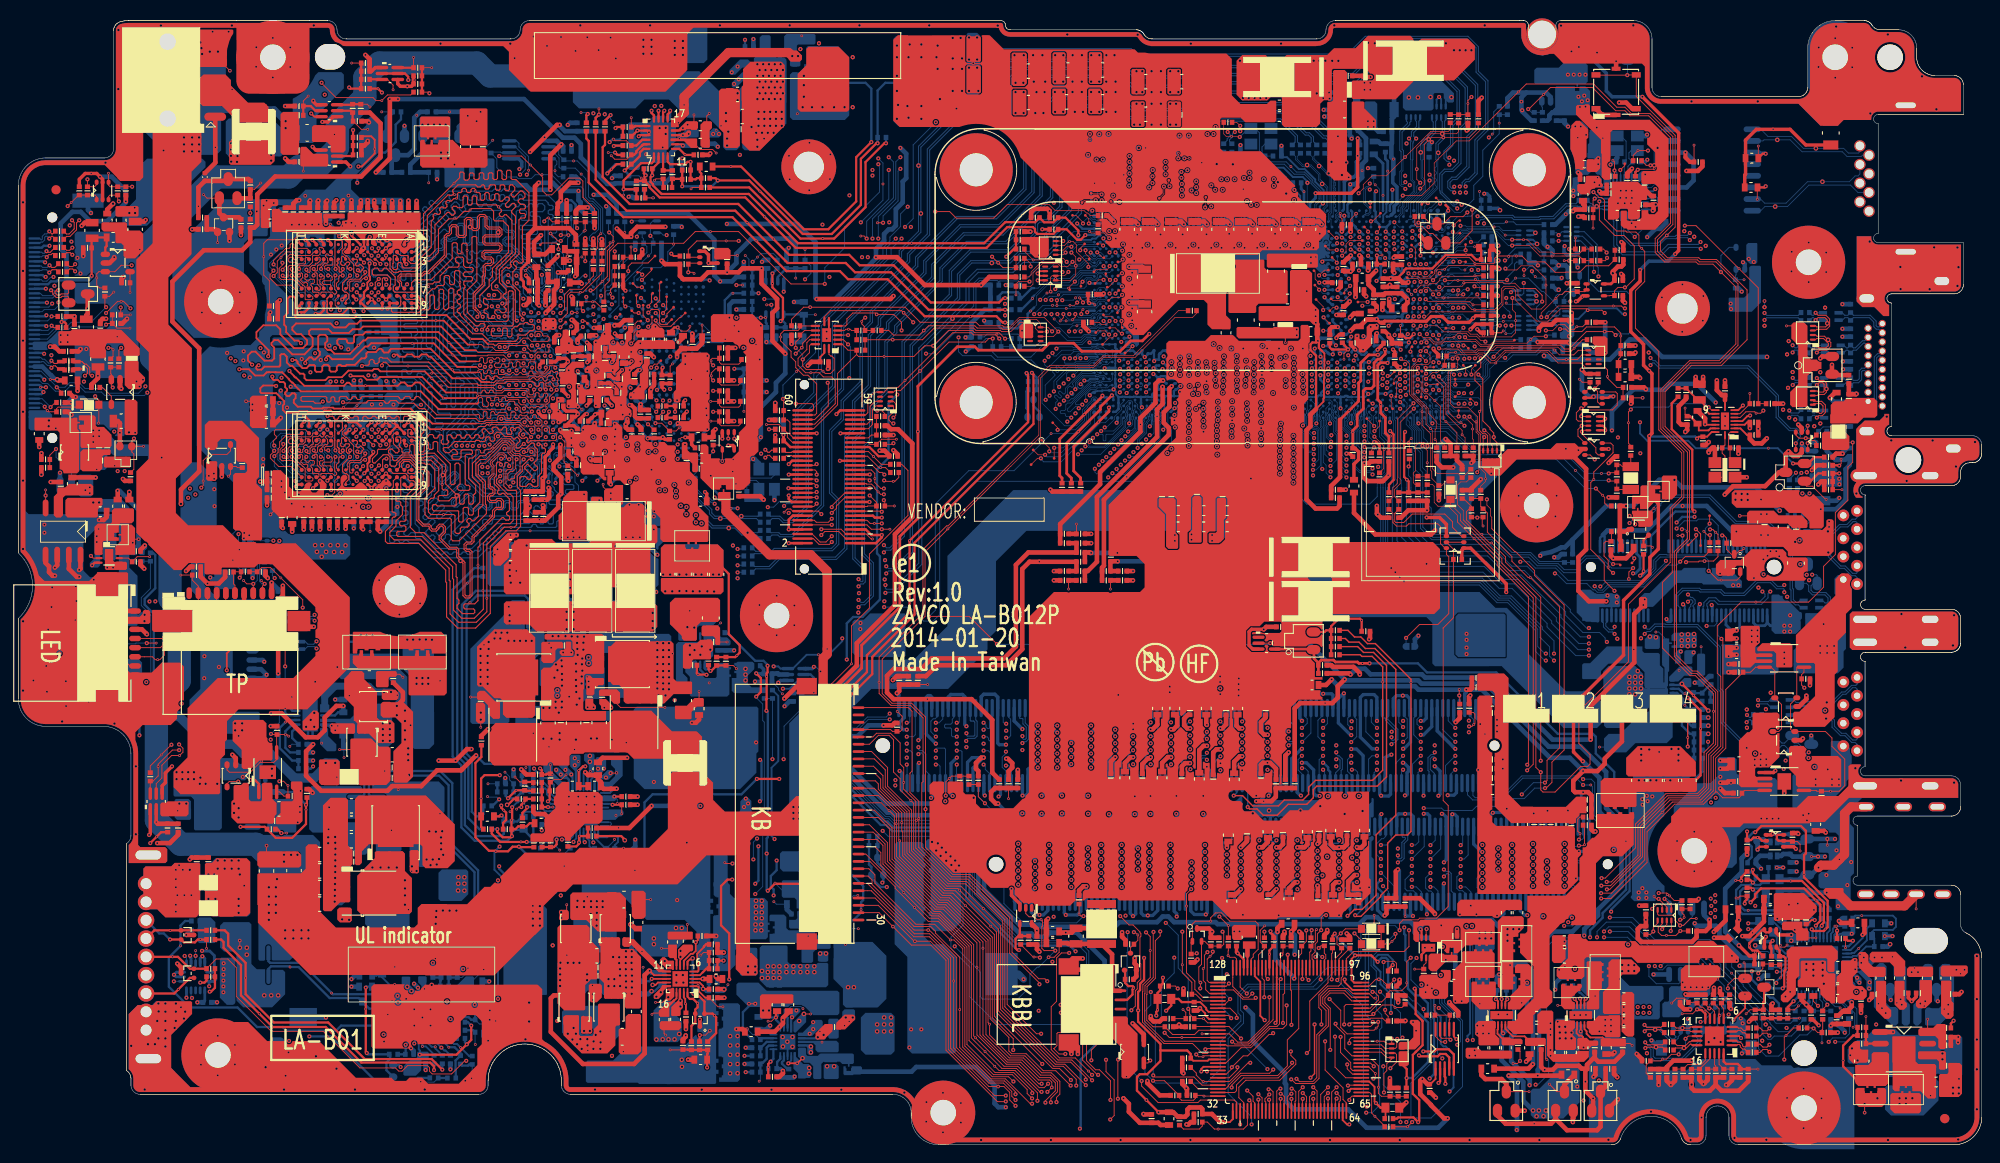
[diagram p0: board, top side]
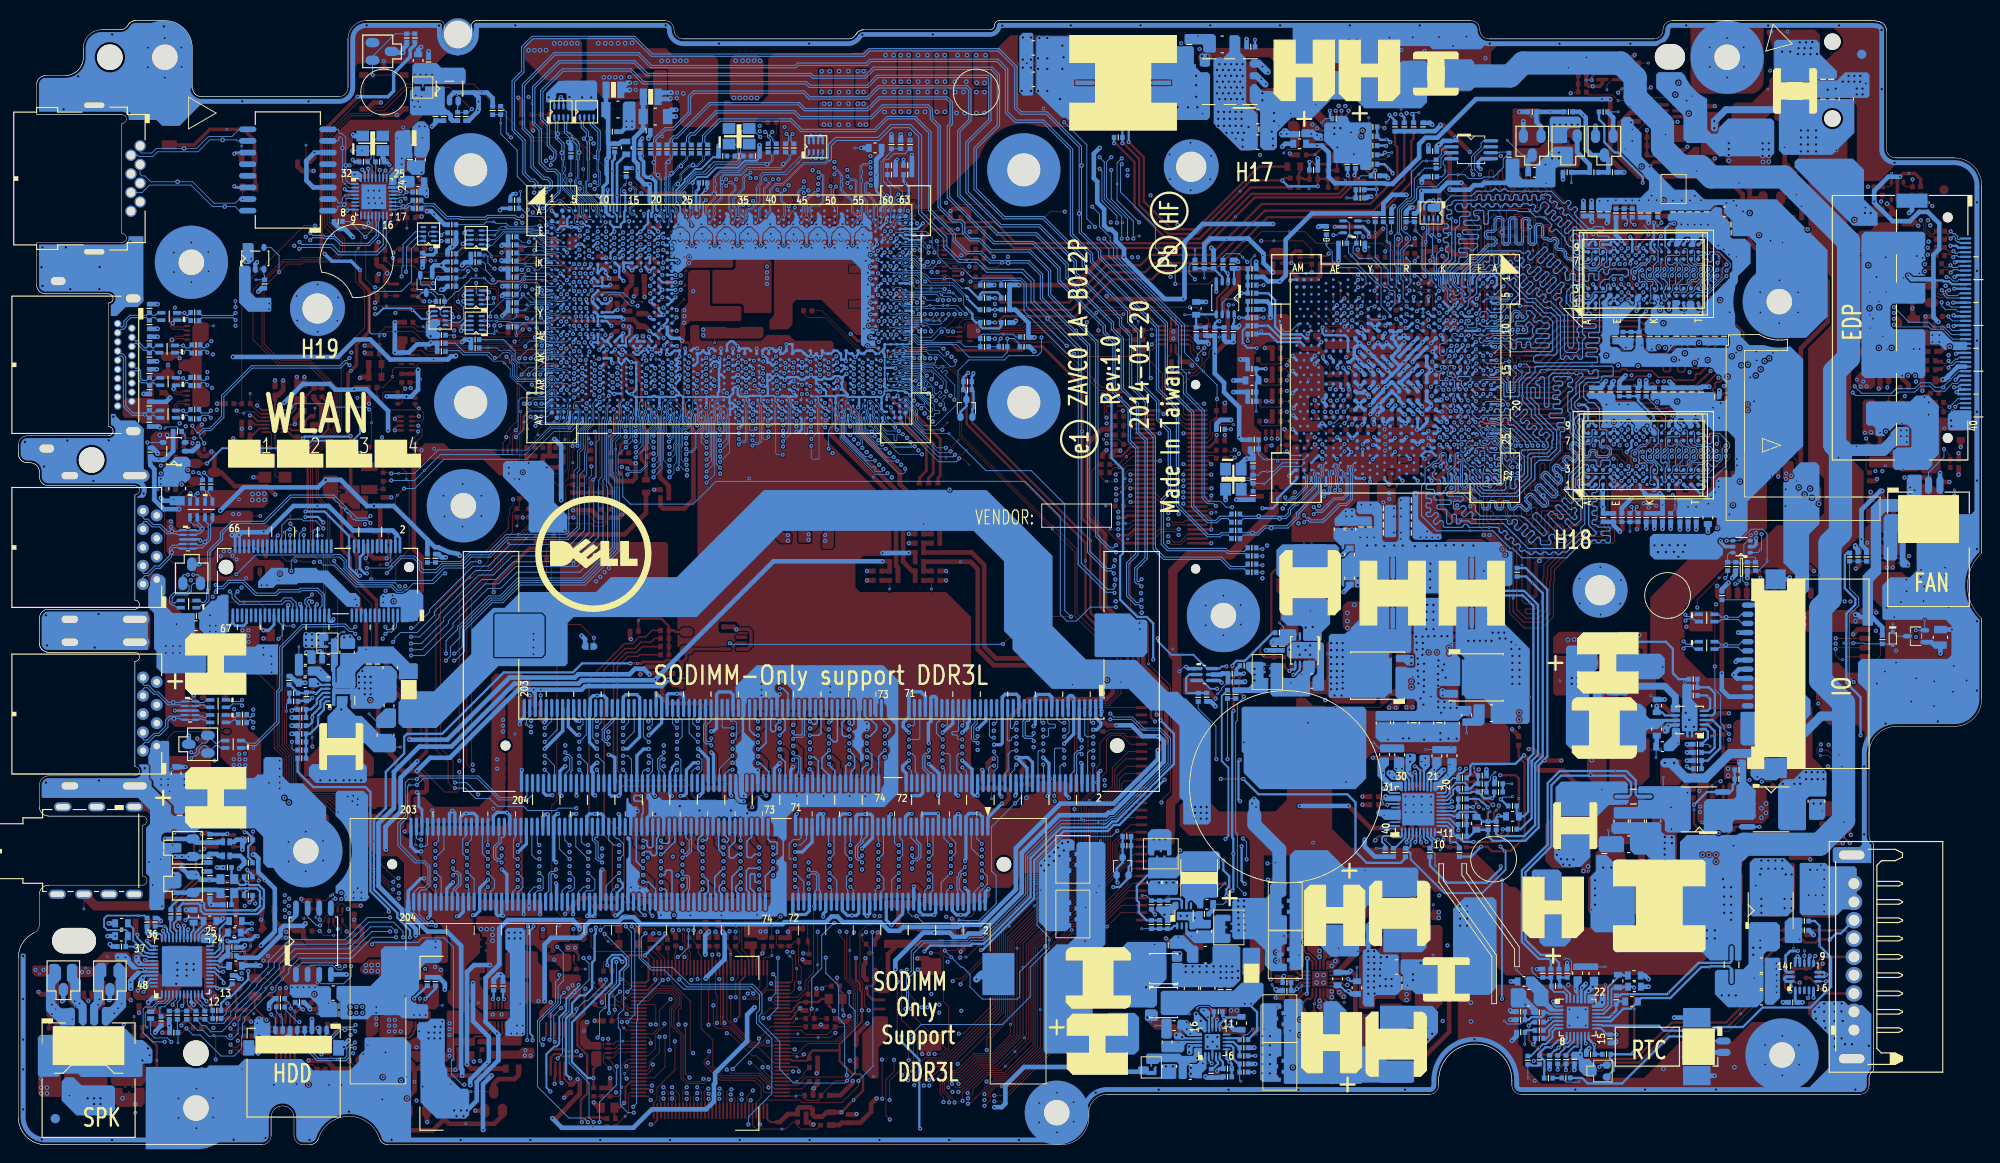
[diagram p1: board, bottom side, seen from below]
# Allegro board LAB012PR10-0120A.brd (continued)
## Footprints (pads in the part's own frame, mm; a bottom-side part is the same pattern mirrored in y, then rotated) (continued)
HB_A823020-SBHR21_30P
  oval 0.305x1.295 smd: 1(0,0) 2(0.8,0) 3(1.6,0) 4(2.4,0) 5(3.2,0) 6(4,0) 7(4.8,0) 8(5.6,0) 9(6.4,0) 10(7.2,0) 11(8,0) 12(8.8,0) 13(9.6,0) 14(10.4,0) 15(11.2,0) 16(12,0) 17(12.8,0) 18(13.6,0) 19(14.4,0) 20(15.2,0) 21(16,0) 22(16.8,0) 23(17.6,0) 24(18.4,0) 25(19.2,0) 26(20,0) 27(20.8,0) 28(21.6,0) 29(22.4,0) 30(23.2,0)
  rect 1.803x2.21 smd: 31(25.55,-5.65) 32(-2.35,-5.65)
IP4292CZ10-TBR_XSON10_2P5X1
  oval 0.254x0.889 smd: 1(0,0)
  oval 0.254x0.838 smd: 2(0.5,-0.025) 3(1,-0.025) 4(1.5,-0.025) 5(2,-0.025) 6(2,1.125) 7(1.5,1.125) 8(1,1.125) 9(0.5,1.125) 10(0,1.125)
ISL9520HRTZ-T_TQFN28_4X4
  oval 0.203x0.94 smd: 1(0,0) 2(0.4,0) 3(0.8,0) 4(1.2,0) 5(1.6,0) 6(2,0) 7(2.4,0) 15(2.4,4.05) 16(2,4.05) 17(1.6,4.05) 18(1.2,4.05) 19(0.8,4.05) 20(0.4,4.05) 21(0,4.05)
  oval 0.94x0.203 smd: 8(3.225,0.825) 9(3.225,1.225) 10(3.225,1.625) 11(3.225,2.025) 12(3.225,2.425) 13(3.225,2.825) 14(3.225,3.225) 22(-0.825,3.225) 23(-0.825,2.825) 24(-0.825,2.425) 25(-0.825,2.025) 26(-0.825,1.625) 27(-0.825,1.225) 28(-0.825,0.825)
  rect 2.388x2.388 smd: 29(1.2,2.025)
ISL62771HRTZ-T_TQFN40_5X5
  oval 0.203x1.016 smd: 1(0,0) 2(0.4,0) 3(0.8,0) 4(1.2,0) 5(1.6,0) 6(2,0) 7(2.4,0) 8(2.8,0) 9(3.2,0) 10(3.6,0) 21(3.6,4.975) 22(3.2,4.975) 23(2.8,4.975) 24(2.4,4.975) 25(2,4.975) 26(1.6,4.975) 27(1.2,4.975) 28(0.8,4.975) 29(0.4,4.975) 30(0,4.975)
  oval 1.016x0.203 smd: 11(4.288,0.688) 12(4.288,1.088) 13(4.288,1.488) 14(4.288,1.888) 15(4.288,2.288) 16(4.288,2.688) 17(4.288,3.088) 18(4.288,3.488) 19(4.288,3.888) 20(4.288,4.288) 31(-0.688,4.288) 32(-0.688,3.888) 33(-0.688,3.488) 34(-0.688,3.088) 35(-0.688,2.688) 36(-0.688,2.288) 37(-0.688,1.888) 38(-0.688,1.488) 39(-0.688,1.088) 40(-0.688,0.688)
  rect 3.505x3.505 smd: 41(1.8,2.488)
ISL95813HRZ-T_QFN20_3X4
  oval 0.254x0.889 smd: 1(0,0) 2(0.5,0) 3(1,0) 4(1.5,0) 5(2,0) 6(2.5,0) 11(2.5,3.1) 12(2,3.1) 13(1.5,3.1) 14(1,3.1) 15(0.5,3.1) 16(0,3.1)
  oval 0.889x0.254 smd: 7(3.3,0.8) 8(3.3,1.3) 9(3.3,1.8) 10(3.3,2.3) 17(-0.8,2.3) 18(-0.8,1.8) 19(-0.8,1.3) 20(-0.8,0.8)
  rect 2.642x1.651 smd: 21(1.25,1.55)
JUMP_43X39
  custom 0.191x0.191 smd: 1(0,0) 2(0.914,0)
JUMP_43X79
  custom 0.188x0.188 smd: 1(0,0) 2(1.1,0)
JUMP_43X118
  custom 0.187x0.187 smd: 1(0,0) 2(1.1,0)
K4W1G1646E-HC12_FBGA_96P-A39
  round 0.445 smd: A1(0,0) A2(0.8,0) A3(1.6,0) A7(4.801,0) A8(5.601,0) A9(6.401,0) B1(0,-0.8) B2(0.8,-0.8) B3(1.6,-0.8) B7(4.801,-0.8) B8(5.601,-0.8) B9(6.401,-0.8) C1(0,-1.6) C2(0.8,-1.6) C3(1.6,-1.6) C7(4.801,-1.6) C8(5.601,-1.6) C9(6.401,-1.6) D1(0,-2.4) D2(0.8,-2.4) D3(1.6,-2.4) D7(4.801,-2.4) D8(5.601,-2.4) D9(6.401,-2.4) E1(0,-3.2) E2(0.8,-3.2) E3(1.6,-3.2) E7(4.801,-3.2) E8(5.601,-3.2) E9(6.401,-3.2) M1(0,-8.801) M2(0.8,-8.801) M3(1.6,-8.801) M7(4.801,-8.801) M8(5.601,-8.801) M9(6.401,-8.801) N1(0,-9.601) N2(0.8,-9.601) N3(1.6,-9.601) N7(4.801,-9.601) N8(5.601,-9.601) N9(6.401,-9.601) P1(0,-10.401) P2(0.8,-10.401) P3(1.6,-10.401) P7(4.801,-10.401) P8(5.601,-10.401) P9(6.401,-10.401) R1(0,-11.201) R2(0.8,-11.201) R3(1.6,-11.201) R7(4.801,-11.201) R8(5.601,-11.201) R9(6.401,-11.201) T1(0,-12.002) T2(0.8,-12.002) T3(1.6,-12.002) T7(4.801,-12.002) T8(5.601,-12.002) T9(6.401,-12.002)
  round 0.343 smd: F1(0,-4) F2(0.8,-4) F3(1.6,-4) F7(4.801,-4) F8(5.601,-4) F9(6.401,-4) G1(0,-4.801) G2(0.8,-4.801) G3(1.6,-4.801) G7(4.801,-4.801) G8(5.601,-4.801) G9(6.401,-4.801) H1(0,-5.601) H2(0.8,-5.601) H3(1.6,-5.601) H7(4.801,-5.601) H8(5.601,-5.601) H9(6.401,-5.601) J1(0,-6.401) J2(0.8,-6.401) J3(1.6,-6.401) J7(4.801,-6.401) J8(5.601,-6.401) J9(6.401,-6.401) K1(0,-7.201) K2(0.8,-7.201) K3(1.6,-7.201) K7(4.801,-7.201) K8(5.601,-7.201) K9(6.401,-7.201) L1(0,-8.001) L2(0.8,-8.001) L3(1.6,-8.001) L7(4.801,-8.001) L8(5.601,-8.001) L9(6.401,-8.001)
KB9012QF-A2_LQFP128_14X14
  oval 0.203x1.753 smd: 1(0,0) 2(0.4,0) 3(0.8,0) 4(1.2,0) 5(1.6,0) 6(2,0) 7(2.4,0) 8(2.8,0) 9(3.2,0) 10(3.6,0) 11(4,0) 12(4.4,0) 13(4.8,0) 14(5.2,0) 15(5.6,0) 16(6,0) 17(6.4,0) 18(6.8,0) 19(7.2,0) 20(7.6,0) 21(8,0) 22(8.4,0) 23(8.8,0) 24(9.2,0) 25(9.6,0) 26(10,0) 27(10.4,0) 28(10.8,0) 29(11.2,0) 30(11.6,0) 31(12,0) 32(12.4,0) 65(12.4,15.654) 66(12,15.654) 67(11.6,15.654) 68(11.2,15.654) 69(10.8,15.654) 70(10.4,15.654) 71(10,15.654) 72(9.6,15.654) 73(9.2,15.654) 74(8.8,15.654) 75(8.4,15.654) 76(8,15.654) 77(7.6,15.654) 78(7.2,15.654) 79(6.8,15.654) 80(6.4,15.654) 81(6,15.654) 82(5.6,15.654) 83(5.2,15.654) 84(4.8,15.654) 85(4.4,15.654) 86(4,15.654) 87(3.6,15.654) 88(3.2,15.654) 89(2.8,15.654) 90(2.4,15.654) 91(2,15.654) 92(1.6,15.654) 93(1.2,15.654) 94(0.8,15.654) 95(0.4,15.654) 96(0,15.654)
  oval 1.753x0.203 smd: 33(14.027,1.627) 34(14.027,2.027) 35(14.027,2.427) 36(14.027,2.827) 37(14.027,3.227) 38(14.027,3.627) 39(14.027,4.027) 40(14.027,4.427) 41(14.027,4.827) 42(14.027,5.227) 43(14.027,5.627) 44(14.027,6.027) 45(14.027,6.427) 46(14.027,6.827) 47(14.027,7.227) 48(14.027,7.627) 49(14.027,8.027) 50(14.027,8.427) 51(14.027,8.827) 52(14.027,9.227) 53(14.027,9.627) 54(14.027,10.027) 55(14.027,10.427) 56(14.027,10.827) 57(14.027,11.227) 58(14.027,11.627) 59(14.027,12.027) 60(14.027,12.427) 61(14.027,12.827) 62(14.027,13.227) 63(14.027,13.627) 64(14.027,14.027) 97(-1.627,14.027) 98(-1.627,13.627) 99(-1.627,13.227) 100(-1.627,12.827) 101(-1.627,12.427) 102(-1.627,12.027) 103(-1.627,11.627) 104(-1.627,11.227) 105(-1.627,10.827) 106(-1.627,10.427) 107(-1.627,10.027) 108(-1.627,9.627) 109(-1.627,9.227) 110(-1.627,8.827) 111(-1.627,8.427) 112(-1.627,8.027) 113(-1.627,7.627) 114(-1.627,7.227) 115(-1.627,6.827) 116(-1.627,6.427) 117(-1.627,6.027) 118(-1.627,5.627) 119(-1.627,5.227) 120(-1.627,4.827) 121(-1.627,4.427) 122(-1.627,4.027) 123(-1.627,3.627) 124(-1.627,3.227) 125(-1.627,2.827) 126(-1.627,2.427) 127(-1.627,2.027) 128(-1.627,1.627)
KC_FBMA-L10-160808-800LMT_2P
  rect 0.889x1.092 smd: 1(0,0) 2(1.5,0)
KC_FBMA-L11-160808-800LMT_2P
  rect 0.889x1.092 smd: 1(0,0) 2(1.5,0)
KC_FBMA-L11-201209-221LMA30_2P
  rect 0.838x1.397 smd: 1(0,0) 2(1.65,0)
KC_WCM-2012HS-900T_4P
  rect 0.889x0.406 smd: 1(0,0) 2(1.7,0) 3(1.7,-0.8) 4(0,-0.8)
L03ESDL5V0CC3-2_SOT23-3
  oval 1.016x1.524 smd: 1(0,0) 2(0.965,2.083) 3(-0.965,2.083)
L03ESDL5V0CG3-2_SOT-523-3
  oval 0.406x0.787 smd: 1(0,0) 2(-0.5,-1.4) 3(0.5,-1.4)
L30ESDL5V0C3-2_SOT23-3
  oval 1.016x1.524 smd: 1(0,0) 2(0.965,2.083) 3(-0.965,2.083)
L_5X5X3_M_2P
  rect 2.159x2.794 smd: 1(0,0) 2(4.35,0)
LANKO_LF-H1201P-2_16P
  oval 0.635x1.905 smd: 1(0,0) 2(1.27,0) 3(2.54,0) 4(3.81,0) 5(5.08,0) 6(6.35,0) 7(7.62,0) 8(8.89,0) 9(8.89,8.763) 10(7.62,8.763) 11(6.35,8.763) 12(5.08,8.763) 13(3.81,8.763) 14(2.54,8.763) 15(1.27,8.763) 16(0,8.763)
LNG3DMTR_LGA16_3X3
  oval 0.305x0.864 smd: 1(0,0) 2(0.5,0) 3(1,0) 4(1.5,0) 5(2,0) 9(2,2.96) 10(1.5,2.96) 11(1,2.96) 12(0.5,2.96) 13(0,2.96)
  oval 0.864x0.305 smd: 6(2.48,0.98) 7(2.48,1.48) 8(2.48,1.98) 14(-0.48,1.98) 15(-0.48,1.48) 16(-0.48,0.98)
LOTES_APCI0019-P009A_67P
  round 1.092 hole 1.092 unplated: (-0.75,-5.275)
  round 1.6 hole 1.6 unplated: (19.25,-5.275)
  oval 0.305x1.549 smd: 1(0,0) 2(0.25,-7.55) 3(0.5,0) 4(0.75,-7.55) 5(1,0) 6(1.25,-7.55) 7(1.5,0) 8(1.75,-7.55) 9(2,0) 10(2.25,-7.55) 11(2.5,0) 12(2.75,-7.55) 13(3,0) 14(3.25,-7.55) 15(3.5,0) 16(3.75,-7.55) 17(4,0) 18(4.25,-7.55) 19(4.5,0) 20(4.75,-7.55) 21(5,0) 22(5.25,-7.55) 23(5.5,0) 24(7.75,-7.55) 25(8,0) 26(8.25,-7.55) 27(8.5,0) 28(8.75,-7.55) 29(9,0) 30(9.25,-7.55) 31(9.5,0) 32(9.75,-7.55) 33(10,0) 34(10.25,-7.55) 35(10.5,0) 36(10.75,-7.55) 37(11,0) 38(11.25,-7.55) 39(11.5,0) 40(11.75,-7.55) 41(12,0) 42(12.25,-7.55) 43(12.5,0) 44(12.75,-7.55) 45(13,0) 46(13.25,-7.55) 47(13.5,0) 48(13.75,-7.55) 49(14,0) 50(14.25,-7.55) 51(14.5,0) 52(14.75,-7.55) 53(15,0) 54(15.25,-7.55) 55(15.5,0) 56(15.75,-7.55) 57(16,0) 58(16.25,-7.55) 59(16.5,0) 60(16.75,-7.55) 61(17,0) 62(17.25,-7.55) 63(17.5,0) 64(17.75,-7.55) 65(18,0) 66(18.25,-7.55) 67(18.5,0)
  rect 1.194x2.743 smd: 68(-1.1,-0.775) 69(19.6,-0.775)
MC74VHC1G08DFT2G_SC70-5
  oval 0.381x0.711 smd: 1(0,0) 2(0.65,0) 3(1.3,0) 4(1.3,1.9) 5(0,1.9)
MDU1516URH_POWERDFN56-8-5
  oval 0.61x1.27 smd: 1(0,0) 2(1.27,0) 3(2.54,0) 4(3.81,0)
  custom 1.105x1.105 smd: 5(1.905,3.715)
MMBT3904_NL_SOT23-3
  oval 1.016x1.524 smd: 1(0,0) 2(0.965,2.083) 3(-0.965,2.083)
MMST3904-7-F_SOT323-3
  oval 0.711x0.889 smd: 1(0,0) 2(0.65,1.9) 3(-0.65,1.9)
MURAT_BLM15AG102SN1D_2P
  rect 0.457x0.508 smd: 1(0,0) 2(0.85,0)
MURAT_BLM15BB221SN1D_2P
  rect 0.508x0.762 smd: 1(0,0) 2(0.75,0)
MURAT_BLM15BD601SN1D_2P
  rect 0.508x0.762 smd: 1(0,0) 2(0.75,0)
MURAT_BLM18AG601SN1D_L0603_2P
  rect 0.66x1.041 smd: 1(0,0) 2(1.2,0)
MURAT_DLW21SN670HQ2L_4P
  rect 0.889x0.406 smd: 1(0,0) 2(1.7,0) 3(1.7,0.8) 4(0,0.8)
MURAT_LQM2MPN2R2NG0L_2P
  rect 0.787x1.803 smd: 1(0,0) 2(1.6,0)
PANAS_ETQP3W2R2WFN_2P
  rect 2.362x3.505 smd: 1(0,0) 2(-6.05,0)
PANAS_ETQP4LR15AFM_4P
  custom 0.686x0.686 smd: 1(0,0) 4(8.357,0)
  rect 2.21x0.508 smd: 2(1.448,0) 3(6.909,0)
PESD5V0U2BT_SOT23-3
  oval 1.016x1.524 smd: 1(0,0) 2(0.965,2.083) 3(-0.965,2.083)
PS8520BTQFN20GTR2_TQFN20_4X4
  oval 0.254x1.194 smd: 1(0,0) 2(0.5,0) 3(1,0) 4(1.5,0) 5(2,0) 11(2,3.8) 12(1.5,3.8) 13(1,3.8) 14(0.5,3.8) 15(0,3.8)
  oval 1.194x0.254 smd: 6(2.9,0.9) 7(2.9,1.4) 8(2.9,1.9) 9(2.9,2.4) 10(2.9,2.9) 16(-0.9,2.9) 17(-0.9,2.4) 18(-0.9,1.9) 19(-0.9,1.4) 20(-0.9,0.9)
  rect 2.108x2.108 smd: 21(1,1.9)
R0402_0OHM
  rect 0.508x0.559 smd: 1(0,0) 2(0.914,0)
R0603_0OHM
  rect 0.635x0.889 smd: 1(0,0) 2(1.397,0)
R0805_0OHM
  rect 0.813x1.397 smd: 1(0,0) 2(1.702,0)
R_0402
  rect 0.508x0.559 smd: 1(0,0) 2(0.914,0)
R_0603
  rect 0.635x0.889 smd: 1(0,0) 2(1.397,0)
R_0805
  rect 0.813x1.397 smd: 1(0,0) 2(1.702,0)
R_1206
  rect 1.016x1.651 smd: 1(0,0) 2(2.667,0)
R_1206_4P-D
  custom 0.445x0.445 smd: 1(0,0) 4(5.004,0)
  custom 0.114x0.114 smd: 2(1.194,0) 3(3.81,0)
RB751V-40_SOD323-2
  rect 0.787x0.889 smd: 1(0,0) 2(2.14,0)
RHU002N06_SOT323-3
  oval 0.813x0.914 smd: 1(0,0) 2(0.65,1.6) 3(-0.65,1.6)
RP_0804_8P4R
  oval 0.66x0.254 smd: 1(0,0) 2(0,-0.5) 3(0,-1) 4(0,-1.5) 5(1.15,-1.5) 6(1.15,-1) 7(1.15,-0.5) 8(1.15,0)
RT8207MZQW_WQFN20_3X3
  oval 0.203x0.889 smd: 1(0,0) 2(0.4,0) 3(0.8,0) 4(1.2,0) 5(1.6,0) 11(1.6,3.1) 12(1.2,3.1) 13(0.8,3.1) 14(0.4,3.1) 15(0,3.1)
  oval 0.889x0.203 smd: 6(2.35,0.75) 7(2.35,1.15) 8(2.35,1.55) 9(2.35,1.95) 10(2.35,2.35) 16(-0.75,2.35) 17(-0.75,1.95) 18(-0.75,1.55) 19(-0.75,1.15) 20(-0.75,0.75)
  rect 1.702x1.702 smd: 21(0.8,1.55)
RTL8106EUS-CG_QFN32_4X4
  oval 0.203x0.889 smd: 1(0,0) 2(0.4,0) 3(0.8,0) 4(1.2,0) 5(1.6,0) 6(2,0) 7(2.4,0) 8(2.8,0) 17(2.8,4.1) 18(2.4,4.1) 19(2,4.1) 20(1.6,4.1) 21(1.2,4.1) 22(0.8,4.1) 23(0.4,4.1) 24(0,4.1)
  oval 0.889x0.203 smd: 9(3.45,0.65) 10(3.45,1.05) 11(3.45,1.45) 12(3.45,1.85) 13(3.45,2.25) 14(3.45,2.65) 15(3.45,3.05) 16(3.45,3.45) 25(-0.65,3.45) 26(-0.65,3.05) 27(-0.65,2.65) 28(-0.65,2.25) 29(-0.65,1.85) 30(-0.65,1.45) 31(-0.65,1.05) 32(-0.65,0.65)
  rect 2.692x2.692 smd: 33(1.4,2.05)
SAMTE_BSH-030-01-L-D-A_60P
  round 1.016 hole 1.016 unplated: (-2.81,5.53) (17.316,5.53)
  oval 0.279x2.261 smd: 1(0,0) 2(0,5.728) 3(0.5,0) 4(0.5,5.728) 5(1,0) 6(1,5.728) 7(1.5,0) 8(1.5,5.728) 9(2,0) 10(2,5.728) 11(2.5,0) 12(2.5,5.728) 13(3,0) 14(3,5.728) 15(3.5,0) 16(3.5,5.728) 17(4,0) 18(4,5.728) 19(4.5,0) 20(4.5,5.728) 21(5,0) 22(5,5.728) 23(5.5,0) 24(5.5,5.728) 25(6,0) 26(6,5.728) 27(6.5,0) 28(6.5,5.728) 29(7,0) 30(7,5.728) 31(7.5,0) 32(7.5,5.728) 33(8,0) 34(8,5.728) 35(8.5,0) 36(8.5,5.728) 37(9,0) 38(9,5.728) 39(9.5,0) 40(9.5,5.728) 41(10,0) 42(10,5.728) 43(10.5,0) 44(10.5,5.728) 45(11,0) 46(11,5.728) 47(11.5,0) 48(11.5,5.728) 49(12,0) 50(12,5.728) 51(12.5,0) 52(12.5,5.728) 53(13,0) 54(13,5.728) 55(13.5,0) 56(13.5,5.728) 57(14,0) 58(14,5.728) 59(14.5,0) 60(14.5,5.728)
SDAN_601028-008041_8P-T
  round 1.245 hole 0.94: 1(0,0) 2(1.02,-1) 3(2.04,0) 4(3.06,-1) 5(4.08,0) 6(5.1,-1) 7(6.12,0) 8(7.14,-1)
  oval 1.092x2.692 hole 0.61x2.21: 9(-4.43,-5) 10(11.57,-5)
SDM10U45-7_SOD523-2
  rect 0.406x0.406 smd: 1(0,0) 2(1.4,0)
SHORTPADS
  custom 0.19x0.19 smd: 1(-0.483,0) 2(0.483,0)
SI3456BDV-T1-E3_TSOP6
  oval 0.508x1.448 smd: 1(0,0) 2(1,0) 3(2,0) 4(2,2.425) 5(1,2.425) 6(0,2.425)
SI3457CDV-T1-GE3_TSOP6
  oval 0.508x1.422 smd: 1(0,0) 2(0.95,0) 3(1.9,0) 4(1.9,2.44) 5(0.95,2.44) 6(0,2.44)
SINGA_2SJ3080-001111F_6P
  oval 0.991x1.905 hole 0.61x1.499: 1(0,0) 2(-9.55,5.5) 3(0,7.8) 4(-9.55,8.4) 5(-9.55,0) 6(-9.55,2.75) 7(0,4.1)
SIR472DP-T1-GE3_POWERPAK8-5
  oval 0.61x1.27 smd: 1(0,0) 2(1.27,0) 3(2.54,0) 4(3.81,0)
  custom 1.105x1.105 smd: 5(1.905,3.36)
SIRA06DP-T1-GE_POWERPAKSO-8-5
  oval 0.61x1.27 smd: 1(0,0) 2(1.27,0) 3(2.54,0) 4(3.81,0)
  custom 1.105x1.105 smd: 5(1.905,3.715)
SIS412DN-T1-GE3_POWERPAK8-5
  oval 0.406x0.991 smd: 1(0,0) 2(0.66,0) 3(1.32,0) 4(1.98,0)
  custom 0.559x0.559 smd: 5(0.99,2.247)
SLG3NB274VTR_TQFN16_2X3
  oval 0.203x0.914 smd: 1(0,-0.013) 2(0.4,-0.013) 3(0.8,-0.013) 4(1.2,-0.013) 5(1.6,-0.013) 6(2,-0.013) 7(2.4,-0.013) 9(2.4,2.063) 10(2,2.063) 11(1.6,2.063) 12(1.2,2.063) 13(0.8,2.063) 14(0.4,2.063) 15(0,2.063)
  oval 0.914x0.203 smd: 8(2.738,1.025) 16(-0.338,1.025)
  rect 1.905x0.889 smd: 17(1.2,1.025)
SN74LVC1G06DCKR_SC70-5
  oval 0.381x0.864 smd: 1(0,0) 2(0.65,0) 3(1.3,0) 4(1.3,1.74) 5(0,1.74)
SN74LVC2T45DCTR_SM8
  oval 0.381x0.914 smd: 1(0,0) 2(0.65,0) 3(1.3,0) 4(1.95,0) 5(1.95,3.6) 6(1.3,3.6) 7(0.65,3.6) 8(0,3.6)
SSM3K7002FU_SC70-3
  oval 0.508x0.991 smd: 1(0,0) 2(0.65,1.9) 3(-0.65,1.9)
STARC_107K40-000001-G2_40P
  round 1.092 hole 1.092 unplated: (-2.3,-1.95) (21.8,-1.95)
  oval 0.254x1.295 smd: 1(0,0) 2(0.5,0) 3(1,0) 4(1.5,0) 5(2,0) 6(2.5,0) 7(3,0) 8(3.5,0) 9(4,0) 10(4.5,0) 11(5,0) 12(5.5,0) 13(6,0) 14(6.5,0) 15(7,0) 16(7.5,0) 17(8,0) 18(8.5,0) 19(9,0) 20(9.5,0) 21(10,0) 22(10.5,0) 23(11,0) 24(11.5,0) 25(12,0) 26(12.5,0) 27(13,0) 28(13.5,0) 29(14,0) 30(14.5,0) 31(15,0) 32(15.5,0) 33(16,0) 34(16.5,0) 35(17,0) 36(17.5,0) 37(18,0) 38(18.5,0) 39(19,0) 40(19.5,0)
  rect 1.549x3.404 smd: 41(-4.125,-5.85) 42(23.625,-5.85)
  rect 2.007x6.198 smd: 43(0.5,-7.65) 44(6,-7.65) 45(13.5,-7.65) 46(19,-7.65)
SW_SMT1-05-A_4P
  rect 0.61x0.991 smd: 1(0,0) 2(0,-4.4) 3(3.7,0) 4(3.7,-4.4)
  rect 0.457x0.991 smd: 5(-0.675,-2.2) 6(4.375,-2.2)
SY6288C20AAC_SOT23-5
  oval 0.559x0.787 smd: 1(0,0) 2(0.95,0) 3(1.9,0) 4(1.9,2.4) 5(0,2.4)
SY6288D20AAC_SOT23-5
  oval 0.559x0.787 smd: 1(0,0) 2(0.95,0) 3(1.9,0) 4(1.9,2.4) 5(0,2.4)
SY8003DFC_DFN8_2X2
  oval 0.254x0.787 smd: 1(0,0) 2(0.5,0) 3(1,0) 4(1.5,0) 5(1.5,2.2) 6(1,2.2) 7(0.5,2.2) 8(0,2.2)
  rect 1.549x0.838 smd: 9(0.75,1.1)
SY8036DBC_DFN10_3X3
  oval 0.254x0.889 smd: 1(0,0) 2(0.5,0) 3(1,0) 4(1.5,0) 5(2,0) 6(2,3.1) 7(1.5,3.1) 8(1,3.1) 9(0.5,3.1) 10(0,3.1)
  rect 2.388x1.575 smd: 11(1,1.55)
SY8206DQNC_QFN10_3X3
  oval 0.254x0.61 smd: 1(0,0) 2(0.45,0) 3(0.9,0) 4(1.35,0) 5(1.8,0) 6(2.25,0)
  rect 1.168x0.254 smd: 7(2.19,-0.675)
  rect 0.914x2.007 smd: 8(2.065,-2)
  custom 0.482x0.482 smd: 9(1.077,-1.775)
  rect 0.813x1.168 smd: 10(0.137,-1.587)
TAITW_PUBAU6-09FLBS1NN4H0_9P
  round 1.295 hole 0.711: 1(0,0) 2(-2.5,0) 3(-4.5,0) 4(-7,0) 5(-7.5,-1.5) 6(-5.5,-1.5) 7(-3.5,-1.5) 8(-1.5,-1.5) 9(0.5,-1.5)
  oval 1.397x3.2 hole 0.787x2.591: 10(4.35,-2.38) 12(-11.35,-2.38)
  oval 1.397x2.388 hole 0.787x1.803: 11(4.35,-9.48) 13(-11.35,-9.48)
TAIYO_FBMJ4516HS720NT_2P
  rect 1.549x1.854 smd: 1(0,0) 2(3.95,0)
TAIYO_NRS4018T1R0NDGJ_2P
  rect 1.194x3.708 smd: 1(0,0) 2(2.8,0)
TOKO_FDUE1040J-H-R36M-P3_4P
  custom 0.876x0.876 smd: 1(0,0) 4(13.411,0)
  rect 2.032x0.508 smd: 2(2.489,0) 3(10.922,0)
TPC12
  round 0.305 smd: 1(0,0)
TPS22966DPUR_SON14_2X3
  oval 0.203x0.762 smd: 1(0,0) 2(0.4,0) 3(0.8,0) 4(1.2,0) 5(1.6,0) 6(2,0) 7(2.4,0) 8(2.4,2.05) 9(2,2.05) 10(1.6,2.05) 11(1.2,2.05) 12(0.8,2.05) 13(0.4,2.05) 14(0,2.05)
  rect 2.489x0.889 smd: 15(1.2,1.025)
TPS51212DSCR_SON10_3X3
  oval 0.279x0.838 smd: 1(0,0) 2(0.5,0) 3(1,0) 4(1.5,0) 5(2,0) 6(2,2.95) 7(1.5,2.95) 8(1,2.95) 9(0.5,2.95) 10(0,2.95)
  custom 0.412x0.412 smd: 11(1,1.475)
TPS51285BRUKR_QFN20_3X3
  oval 0.203x1.016 smd: 1(0,0) 2(0.4,0) 3(0.8,0) 4(1.2,0) 5(1.6,0) 11(1.6,2.975) 12(1.2,2.975) 13(0.8,2.975) 14(0.4,2.975) 15(0,2.975)
  oval 1.016x0.203 smd: 6(2.288,0.688) 7(2.288,1.088) 8(2.288,1.488) 9(2.288,1.888) 10(2.288,2.288) 16(-0.688,2.288) 17(-0.688,1.888) 18(-0.688,1.488) 19(-0.688,1.088) 20(-0.688,0.688)
  rect 1.702x1.702 smd: 21(0.8,1.488)
TVNST52302AB0_SOT523-3
  oval 0.508x0.559 smd: 1(0,0) 2(-0.5,-1.4) 3(0.5,-1.4)
W25Q64FVSSIG_SO8
  oval 0.635x1.676 smd: 1(0,0) 2(1.27,0) 3(2.54,0) 4(3.81,0) 5(3.81,7.25) 6(2.54,7.25) 7(1.27,7.25) 8(0,7.25)
Y_7V27000011_4P
  rect 1.397x1.194 smd: 1(0,0) 2(2.2,0) 3(2.2,1.7) 4(0,1.7)
Y_FSX3M-25PM20FDO_4P
  rect 1.397x1.194 smd: 1(0,0) 2(2.2,0) 3(2.2,1.6) 4(0,1.6)
Y_Q13FC1350000_2P
  rect 0.991x1.803 smd: 1(0,0) 2(2.5,0)
Y_X3G024000DC1H_4P
  rect 1.397x1.194 smd: 1(0,0) 2(2.2,0) 3(2.2,1.7) 4(0,1.7)

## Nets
0.675V_DDR_VTT_ON: PR202.1 QD2.2 R2347.2 R2351.2 U2303.4
1.35V_B+: PC201.1 PC206.1 PC208.1 PC212.1 PL201.2 PQ200.5 PR208.1
3/5V_B+: PC105.1 PC112.1 PC113.1 PC114.1 PC115.1 PC116.1 PC117.1 PL102.2 PQ101.5 PQ103.5 PU100.12
3V_EN: PD101.2 PR100.1 PU100.6
3VALW_PCH: J513.2 U2304.13 U2304.14
3VS: J511.2 U2301.8 U2301.9
3VS_GATE: C2322.1 R2318.2 U2301.5
5V_EN: PD101.3 PR101.1 PU100.20
5VS: J510.2 U2301.13 U2301.14
5VS_GATE: C2309.1 R2313.2 U2301.3
+0.675VS: CD24.1 CD25.1 CD26.1 CD27.1 CD28.1 CD29.1 CD54.1 CD55.1 CD56.1 CD57.1 CD58.1 CD59.1 JDIMM1.203 JDIMM1.204 JDIMM2.203 JDIMM2.204 PJP203.1 R2314.1
+0.675VSP: PC205.1 PC211.1 PJP203.2 PU200.2 PU200.20
+1.05V: J512.2 U2304.8 U2304.9
+1.05V_LDO_3V: PC312.1 PR304.1 PU300.5
+1.05V_PGOOD: PR308.2 PU300.2 UE1.122
+1.05VS: C2315.1 C2317.1 J515.1 PJP300.2 U2304.6 U2304.7
+1.5VS: PJP401.2 PR1025.1 RA8.1 RC129.1 UC1.J15
+1.05VS_APLLOPI: C69.1 C70.1 L3.2 R267.2 UC1.AA21 UC1.W21
+1.05VS_ASATA3PLL: C63.1 C65.1 L2.2 RC126.2 RC131.2 UC1.B11
+1.05VS_AUSB3PLL: C58.1 C59.1 L1.2 RC91.1 UC1.B18 UC1.B27
+1.05VS_AXCK_DCB: C83.1 C84.1 L4.2 UC1.J18 UC1.K19
+1.05VS_AXCK_LCPLL: C85.1 C86.1 L5.2 RC13.2 UC1.A20
+1.05VS_GATE: C2325.1 R2451.2 U2304.5
+1.05VS_PCH: C43.1 C44.1 C46.1 C47.1 C50.1 C53.1 C57.1 C60.1 C61.1 C62.1 C66.1 C67.1 C76.1 C87.1 C88.1 C2328.1 C2329.1 CC14.1 CC15.1 CC28.1 CD63.1 CD65.1 CG2.1 J512.1 J515.2 JXDP1.43 JXDP1.44 L1.1 L2.1 L3.1 L4.1 L5.1 PC548.2 PR500.2 PR503.2 PR504.2 R252.1 R253.2 R256.1 R267.1 R286.1 R2315.1 R2346.1 RC58.1 RC60.1 RC130.2 RC136.2 RC137.2 RC142.2 RC143.2 RP44.5 RP44.6 RP44.7 RP44.8 RP45.8 RP48.1 RP48.2 RP48.3 UC1.AC22 UC1.AE8 UC1.AE9 UC1.AE22 UC1.AE23 UC1.AF9 UC1.AF22 UC1.AG8 UC1.AG13 UC1.AG14 UC1.AG16 UC1.AG17 UC1.H11 UC1.H15 UC1.J11 UC1.J17 UC1.K9 UC1.L10 UC1.M9 UC1.N8 UC1.P9 UC1.R21 UC1.T21 UG1.3
+1.5VSP: PC403.1 PC404.1 PJP401.1 PR400.1 PU400.3 PU400.4
+1.05VSP: PC307.1 PC308.1 PC309.1 PC310.1 PC311.1 PJP300.1 PL301.2 PR305.1
+1.8VGS: CV38.1 CV39.1 CV46.1 CV170.2 J9.1 LV2.1 LV3.1 LV6.1 LV7.1 PR1022.1 RV8.1 RV11.1 RV15.1 RV27.1 RV28.1 RV81.2 RV82.2 RV84.2 RV87.2 RV152.2 U1.8 UV1.AM30
+1.8VS: J9.2 PJP601.2
+1.8VSP: PC600.1 PC602.1 PC604.1 PJP601.1 PL600.2 PR603.1
+1.8VSP_ON: PC603.1 PR601.1 PR604.1 PU600.7
+1.35V: C35.1 C36.1 C37.1 C38.1 C39.1 C40.2 C41.1 C42.1 C43.2 C45.1 C72.1 C74.1 CD4.1 CD5.1 CD6.1 CD7.1 CD8.1 CD9.1 CD10.1 CD11.1 CD12.1 CD13.1 CD14.1 CD15.1 CD16.1 CD17.1 CD18.1 CD19.1 CD20.1 CD23.1 CD35.1 CD36.1 CD37.1 CD38.1 CD39.1 CD40.1 CD41.1 CD42.1 CD43.1 CD44.1 CD45.1 CD46.1 CD47.1 CD48.1 CD49.1 CD50.1 CD51.1 CD62.2 JDIMM1.75 JDIMM1.76 JDIMM1.81 JDIMM1.82 JDIMM1.87 JDIMM1.88 JDIMM1.93 JDIMM1.94 JDIMM1.99 JDIMM1.100 JDIMM1.105 JDIMM1.106 JDIMM1.111 JDIMM1.112 JDIMM1.117 JDIMM1.118 JDIMM1.123 JDIMM1.124 JDIMM2.75 JDIMM2.76 JDIMM2.81 JDIMM2.82 JDIMM2.87 JDIMM2.88 JDIMM2.93 JDIMM2.94 JDIMM2.99 JDIMM2.100 JDIMM2.105 JDIMM2.106 JDIMM2.111 JDIMM2.112 JDIMM2.117 JDIMM2.118 JDIMM2.123 JDIMM2.124 PJP200.2 PJP201.2 QD2.1 RC14.1 RC15.1 RC16.1 RD3.1 U2303.5 UC1.AH26 UC1.AJ31 UC1.AJ33 UC1.AJ37 UC1.AN33 UC1.AP43 UC1.AR48 UC1.AY35 UC1.AY40 UC1.AY44 UC1.AY50
+1.35VGPUP: PC1108.1 PJP1100.1 PJP1101.1 PL1101.2 PR1107.2
+1.35VGPUP_B+: PC1100.1 PC1101.1 PC1102.1 PL1100.1 PQ1100.5
+1.35VP: PC213.1 PC214.2 PJP200.1 PJP201.1 PL200.1 PR207.2 PU200.5 PU200.19
+1.35VS_VGA: CV40.1 CV41.1 CV42.1 CV43.1 CV44.1 CV45.1 CV47.1 CV48.1 CV49.1 CV50.1 CV51.1 CV52.1 CV53.1 CV103.1 CV104.1 CV105.1 CV106.1 CV107.1 CV108.1 CV109.1 CV110.1 CV111.1 CV112.1 CV113.1 CV114.1 CV115.1 CV116.1 CV117.1 CV118.1 CV119.1 CV120.1 CV121.1 CV122.1 CV123.1 CV124.1 CV125.1 CV126.1 CV127.1 CV128.1 CV129.1 CV130.1 CV131.1 CV132.1 CV136.1 CV137.1 CV138.1 CV139.1 CV140.1 CV141.1 CV142.1 CV143.1 CV144.1 CV145.1 CV146.1 CV147.1 CV148.1 CV149.1 CV150.1 CV151.1 CV152.1 CV153.1 CV154.1 CV155.1 CV156.1 CV157.1 CV158.1 CV159.1 CV160.1 CV161.1 CV162.1 CV163.1 CV164.1 CV165.1 CV171.1 CV172.1 CV173.1 CV174.1 CV175.1 CV176.1 CV177.1 CV178.1 CV179.1 CV180.1 CV181.1 CV182.1 CV183.1 PJP1100.2 PJP1101.2 RV32.1 RV33.1 RV42.1 RV43.1 RV50.1 RV51.1 UV1.H13 UV1.H16 UV1.H19 UV1.J9 UV1.J10 UV1.J23 UV1.J24 UV1.K9 UV1.K10 UV1.K23 UV1.K24 UV1.L11 UV1.L12 UV1.L13 UV1.L20 UV1.L21 UV1.L22 UV5.A1 UV5.A8 UV5.B2 UV5.C1 UV5.C9 UV5.D2 UV5.D9 UV5.E9 UV5.F1 UV5.G7 UV5.H2 UV5.H9 UV5.K2 UV5.K8 UV5.N1 UV5.N9 UV5.R1 UV5.R9 UV6.A1 UV6.A8 UV6.B2 UV6.C1 UV6.C9 UV6.D2 UV6.D9 UV6.E9 UV6.F1 UV6.G7 UV6.H2 UV6.H9 UV6.K2 UV6.K8 UV6.N1 UV6.N9 UV6.R1 UV6.R9 UV7.A1 UV7.A8 UV7.B2 UV7.C1 UV7.C9 UV7.D2 UV7.D9 UV7.E9 UV7.F1 UV7.G7 UV7.H2 UV7.H9 UV7.K2 UV7.K8 UV7.N1 UV7.N9 UV7.R1 UV7.R9 UV8.A1 UV8.A8 UV8.B2 UV8.C1 UV8.C9 UV8.D2 UV8.D9 UV8.E9 UV8.F1 UV8.G7 UV8.H2 UV8.H9 UV8.K2 UV8.K8 UV8.N1 UV8.N9 UV8.R1 UV8.R9
+3V_DSW: C81.1 C5213.1 C5215.2 J518.2 RC31.1 RC32.1 RC34.1 RC39.1 RC105.2 U2408.7 U2408.8 UC1.AH10
+3VALW: C89.2 C2311.1 C2313.1 C2316.1 C2318.1 CE61.2 CG10.1 CL38.1 CL39.1 CM8.2 J516.1 J518.1 JP3.2 PJP100.2 PJP102.2 PJP301.1 PJP400.1 PJP600.1 PJP1301.2 PR3.2 PR25.2 PR28.1 PR37.1 PR115.2 RA10.1 RE327.2 RE330.1 RE332.2 RL40.1 RM10.1 RP36.7 RP36.8 U2301.6 U2301.7 U2304.1 U2304.2 U2408.1 U2408.2 UG1.2 UL2.4 UL2.5 UL3.5 UM1.5
+3VALW_EC: CE1.1 CE2.1 CE5.2 CE6.2 JLED.3 LE1.1 PR16.2 RE3.2 RE8.2 RE71.1 RE73.1 RE327.1 RE328.1 RP36.5 RP36.6 UE1.9 UE1.22 UE1.33 UE1.96 UE1.125
+3VALW_PCH: C68.1 C75.2 C78.1 C2310.1 C2312.1 C2327.1 J513.1 J516.2 QH1.2 QH1.5 R264.1 R2329.1 R2330.1 R2334.1 R2335.1 RC27.1 RC28.1 RC29.1 RC64.2 RC103.2 RC104.2 RC110.2 RC120.1 RC124.1 RC125.1 RC127.1 RP40.5 RP40.6 RP40.7 RP40.8 RP49.7 RP49.8 RP55.5 RP55.6 RP55.7 RP55.8 U2302.8 UC1.AA9 UC1.AC9 UC1.AE20 UC1.AE21 UC1.Y8
+3VALW_PCH_GATE: C2314.1 R416.2 U2304.3
+3VALWP: PC101.1 PC102.1 PJP100.1 PJP102.1 PL100.2 PR109.1
+3VGS: CV10.1 CV22.1 CV23.1 CV166.2 J514.2 LV4.1 QV1.2 QV1.5 QV2.1 RP34.1 RP34.2 RP34.3 RV5.1 RV6.1 RV24.1 RV58.2 RV71.2 RV72.2 RV79.2 RV91.2 RV146.1 RV147.1 RV148.1 RV154.1 RV162.1 U1.1 UV2.5 UV3.1
+3VLP: CG4.1 JP12.1 JP14.1 PC109.1 PD700.3 PU100.3 RE49.2 RE328.2 RE333.2 UE1.111 UG1.15
+3VS: C44.2 C71.1 C73.1 C82.1 C2323.1 C2324.1 C2498.1 CA57.1 CA58.1 CA59.1 CA60.1 CC11.1 CC13.1 CD30.1 CD31.1 CD60.1 CD61.1 CD62.1 CE15.1 CS27.1 CS42.1 CS43.1 CS44.1 CX1.1 CX7.1 J511.1 J514.1 JDIMM1.199 JDIMM2.199 JEDP.34 JEDP.35 JIO.6 PR308.1 PR1020.1 PR1030.1 PR1110.1 Q2409.2 QC1.2 QC1.5 QC3.2 QE6.2 QE6.5 QM1.2 QS1.2 QV2.3 QX3.2 QX4.2 QX4.5 QX5.1 R2331.1 R2332.1 R2448.1 R2453.1 RA1.1 RA2.1 RA7.1 RA9.1 RA13.2 RC3.1 RC9.2 RC11.2 RC36.1 RC73.1 RC74.1 RC75.1 RC76.1 RC77.1 RC79.1 RC98.2 RC100.1 RC102.1 RC106.1 RC107.2 RC108.1 RC109.1 RC111.1 RC112.1 RC114.1 RC115.1 RC118.1 RC119.1 RC121.1 RC128.1 RC362.1 RD12.2 RE9.1 RE10.1 RE50.1 RE68.2 RE331.1 RL33.1 RL37.2 RM7.1 RP37.6 RP37.7 RP37.8 RP42.1 RP42.3 RP42.4 RP51.5 RP51.8 RP52.5 RP52.6 RP52.7 RP52.8 RP53.5 RP53.6 RP53.7 RP53.8 RP54.5 RP54.6 RP54.7 RP54.8 RS19.1 RS20.1 RS25.1 RS26.1 RS27.1 RS28.1 RS29.1 RS30.1 RS33.2 RS34.2 RS38.2 RX10.1 RX12.1 RX13.1 RX27.1 RX30.1 U2407.1 UA1.1 UA1.9 UA1.36 UC1.K14 UC1.K16 UC1.T9 UC1.U8 UC1.V8 UC1.W9 UC3.5 UC4.14 UE2.5 US3.1 US3.7 US3.8 US3.14 UX1.5 UX4.5
+3VS_CAM: JEDP.29 RX27.2
+3VS_TOUCH: CE58.1 CE59.1 J519.2 JTP.8 JTP1.10 RC78.2 RE329.1 RE334.1 RE335.1 RE339.1 RE340.2 UE4.7 UE4.8
+3VS_WLAN_NGFF: CM3.2 CM4.1 CM5.1 CM6.1 CM7.1 JNGFF.2 JNGFF.4 JNGFF.64 JNGFF.66 RE72.1 RM7.2 RM8.1 RP42.2 UM1.1
+5V_HDD: CS5.1 CS6.1 CS7.1 JHDD.9 JHDD.10 JP13.1
+5V_PVDD: CA53.1 CA54.1 CA55.1 CA56.1 RA1110.2 UA1.41 UA1.46
+5V_USB_PWR1: CI1.1 CI2.1 CI40.1 JUSB1.1 UI3.6 UI3.7 UI3.8 UI5.1
+5V_USB_PWR2: CI8.1 CI9.1 CI43.1 JUSB2.1 UI2.6 UI2.7 UI2.8 UI6.1
+5V_USB_PWR3: JIO.1 JIO.2 JIO.3 JIO.4 UI4.6 UI4.7 UI4.8 UI7.1
+5VA: CA51.1 CA71.1 RA1111.2 UA1.26
+5VALW: C2305.1 C2306.1 CI6.1 CI7.1 CI12.1 CI14.1 CI18.1 CI44.1 CI45.1 JLED.1 PC400.1 PC528.1 PC1021.1 PC1105.1 PJP101.2 PJP103.2 PR8.1 PR206.1 PR210.2 PR1024.2 PU400.6 PU501.12 PU1000.26 PU1000.31 PU1100.7 R10.1 R2347.1 RV22.1 U2301.1 U2301.2 U2301.4 U2304.4 U2408.4 UI2.2 UI2.3 UI3.2 UI3.3 UI4.2 UI4.3 UI5.5 UI6.5 UI7.5
+5VALWP: PC107.1 PC108.2 PJP101.1 PJP103.1 PL101.2 PR104.2 PU100.14
+5VS: C2307.1 C2308.1 CE25.1 CE56.1 FE1.2 FX1.2 J510.1 JLED.2 JP13.2 RA1110.1 RA1111.1 RE59.1 RE60.1 RS32.1 RX16.2 RX17.2 RX29.1 UE3.1 UE3.2
+5VS_KBL: CE57.1 FE1.1 JKBBL.1 RE59.2
+V18R: CE16.1 UE1.124
+VCC_PWR_SRC: PC515.1 PC516.1 PC517.1 PC518.1 PC519.1 PC521.1 PC524.1 PC532.1 PL501.1 PL503.1 PQ501.1
+VCCHDA: C77.1 RC127.2 RC128.2 RC129.2 UC1.AH14
+VCCIO_OUT: R245.2
+VCCIO_OUT_R: R245.1 UC1.A59
+VCCIOA_OUT: RC71.1 UC1.E20
+VCCRTCEXT: C52.1 UC1.AE7
+VDD_CT: CV61.1 CV62.1 CV63.1 LV3.2 UV1.AA20 UV1.AA21 UV1.AB20 UV1.AB21
+VDD_TOUCH: CX49.1 CX50.1 JEDP.11 JEDP.26 QX6.2 QX6.5 RX28.1 RX35.1 RX39.1 RX40.1 UX3.1
+VDDCI: CV87.1 CV88.1 CV89.1 CV90.1 LV25.1 LV26.1 UV1.M13 UV1.M15 UV1.M16 UV1.M17 UV1.M18 UV1.M20 UV1.M21 UV1.N20
+VDDR3: CV64.1 CV65.1 CV66.1 LV4.2 UV1.AA17 UV1.AA18 UV1.AB17 UV1.AB18
GND: C35.2 C36.2 C37.2 C38.2 C39.2 C41.2 C42.2 C45.2 C50.2 C51.2 C52.2 C53.2 C54.2 C55.2 C56.2 C57.2 C58.2 C59.2 C60.2 C61.2 C62.2 C63.2 C64.2 C65.2 C66.2 C67.2 C68.2 C69.2 C70.2 C71.2 C72.2 C73.2 C74.2 C75.1 C76.2 C77.2 C78.2 C79.2 C80.2 C81.2 C82.2 C83.2 C84.2 C85.2 C86.2 C87.2 C88.2 C89.1 C90.2 C91.1 C92.1 C93.2 C2305.2 C2306.2 C2307.2 C2308.2 C2309.2 C2310.2 C2311.2 C2312.2 C2313.2 C2314.2 C2315.2 C2316.2 C2317.2 C2318.2 C2322.2 C2323.2 C2324.2 C2325.2 C2326.2 C2327.2 C2328.2 C2329.2 C2498.2 C5212.2 C5213.2 C5214.2 C5216.2 C5217.2 C5218.2 C5219.2 CA21.2 CA22.2 CA25.1 CA29.2 CA30.2 CA31.2 CA32.2 CA53.2 CA54.2 CA55.2 CA56.2 CA57.2 CA58.2 CA59.2 CA60.2 CA64.1 CA69.2 CA74.2 CC1.1 CC2.1 CC3.1 CC4.1 CC5.2 CC6.1 CC7.1 CC11.2 CC13.2 CC14.2 CC15.2 CC16.2 CC17.2 CC26.2 CC27.2 CC28.2 CC29.2 CC30.2 CC31.2 CC33.2 CC34.2 CC35.2 CC37.2 CC38.2 CC42.2 CD1.2 CD2.2 CD3.2 CD4.2 CD5.2 CD6.2 CD7.2 CD8.2 CD9.2 CD10.2 CD11.2 CD12.2 CD13.2 CD14.2 CD15.2 CD16.2 CD17.2 CD18.2 CD19.2 CD20.2 CD21.2 CD22.2 CD23.2 CD24.2 CD25.2 CD26.2 CD27.2 CD28.2 CD29.2 CD30.2 CD31.2 CD32.2 CD33.2 CD34.2 CD35.2 CD36.2 CD37.2 CD38.2 CD39.2 CD40.2 CD41.2 CD42.2 CD43.2 CD44.2 CD45.2 CD46.2 CD47.2 CD48.2 CD49.2 CD50.2 CD51.2 CD52.2 CD53.2 CD54.2 CD55.2 CD56.2 CD57.2 CD58.2 CD59.2 CD60.2 CD61.2 CD63.2 CD64.2 CD65.2 CE1.2 CE2.2 CE5.1 CE6.1 CE8.2 CE11.2 CE12.2 CE15.2 CE16.2 CE18.1 CE19.2 CE20.2 CE22.2 CE23.2 CE24.2 CE25.2 CE26.2 CE27.2 CE28.2 CE29.2 CE30.2 CE31.2 CE32.2 CE34.2 CE35.2 CE36.2 CE56.2 CE57.2 CE58.2 CE59.2 CE60.2 CE61.1 CG2.2 CG3.2 CG4.2 CG5.2 CG6.2 CG7.2 CG8.2 CG9.2 CG10.2 CI1.2 CI2.2 CI6.2 CI7.2 CI8.2 CI9.2 CI12.2 CI13.2 CI14.2 CI15.2 CI17.2 CI18.2 CI26.2 CI40.2 CI43.2 CI44.2 CI45.2 CI46.2 CI47.2 CL3.2 CL4.2 CL5.2 CL6.2 CL7.2 CL8.2 CL9.2 CL12.2 CL13.2 CL14.2 CL15.2 CL16.1 CL17.2 CL19.2 CL33.2 CL36.1 CL37.1 CL38.2 CL39.2 CL41.1 CM3.1 CM4.2 CM5.2 CM6.2 CM7.2 CM8.1 CMOS1.1 CS5.2 CS6.2 CS7.2 CS27.2 CS42.2 CS43.2 CS44.2 CV10.2 CV11.2 CV15.2 CV17.2 CV18.2 CV19.2 CV20.2 CV21.2 CV22.2 CV23.2 CV24.2 CV25.2 CV26.2 CV27.2 CV28.2 CV29.2 CV33.2 CV34.2 CV38.2 CV39.2 CV40.2 CV41.2 CV42.2 CV43.2 CV44.2 CV45.2 CV46.2 CV47.2 CV48.2 CV49.2 CV50.2 CV51.2 CV52.2 CV53.2 CV54.2 CV55.2 CV56.2 CV57.2 CV58.2 CV59.2 CV60.2 CV61.2 CV62.2 CV63.2 CV64.2 CV65.2 CV66.2 CV67.2 CV68.2 CV69.2 CV70.2 CV71.2 CV72.2 CV73.2 CV74.2 CV75.2 CV76.2 CV77.2 CV78.2 CV79.2 CV80.2 CV81.2 CV82.2 CV83.2 CV84.2 CV85.2 CV86.2 CV87.2 CV88.2 CV89.2 CV90.2 CV91.2 CV92.2 CV93.2 CV94.2 CV95.2 CV96.2 CV97.2 CV100.2 CV101.2 CV102.2 CV103.2 CV104.2 CV105.2 CV106.2 CV107.2 CV108.2 CV109.2 CV110.2 CV111.2 CV112.2 CV113.2 CV114.2 CV115.2 CV116.2 CV117.2 CV118.2 CV119.2 CV120.2 CV121.2 CV122.2 CV123.2 CV124.2 CV125.2 CV126.2 CV127.2 CV128.2 CV129.2 CV130.2 CV131.2 CV132.2 CV133.2 CV134.2 CV135.2 CV136.2 CV137.2 CV138.2 CV139.2 CV140.2 CV141.2 CV142.2 CV143.2 CV144.2 CV145.2 CV146.2 CV147.2 CV148.2 CV149.2 CV150.2 CV151.2 CV152.2 CV153.2 CV154.2 CV155.2 CV156.2 CV157.2 CV158.2 CV159.2 CV160.2 CV161.2 CV162.2 CV163.2 CV164.2 CV165.2 CV166.1 CV167.1 CV168.2 CV169.1 CV170.1 CV171.2 CV172.2 CV173.2 CV174.2 CV175.2 CV176.2 CV177.2 CV178.2 CV179.2 CV180.2 CV181.2 CV182.2 CV183.2 CVT90.1 CX1.2 CX2.2 CX3.2 CX5.2 CX7.2 CX8.2 CX9.2 CX11.2 CX20.2 CX21.2 CX22.2 CX23.2 CX24.2 CX25.2 CX26.2 CX27.2 CX28.2 CX29.2 CX30.2 CX49.2 CX50.2 CX51.2 CX52.2 DA10.1 DA12.1 DA13.1 DA14.1 DE1.1 DE2.1 DI1.3 DI1.8 DI2.1 DI4.3 DI4.8 DI5.1 DX2.1 H2.1(TP-1) H3.1(TP-1) H4.1(TP-1) H5.1(TP-1) H6.1(TP-1) H7.1(TP-1) H8.1(TP-1) H9.1(TP-1) H10.1(TP-1) H11.1(TP-1) H12.1(TP-1) H13.1(TP-1) H14.1(TP-1) H15.1(TP-1) H16.1(TP-1) H17.1(TP-1) H18.1(TP-1) H19.1(TP-1) HE1.2 JDIMM1.2 JDIMM1.3 JDIMM1.8 JDIMM1.9 JDIMM1.11 JDIMM1.13 JDIMM1.14 JDIMM1.19 JDIMM1.20 JDIMM1.25 JDIMM1.26 JDIMM1.28 JDIMM1.31 JDIMM1.32 JDIMM1.37 JDIMM1.38 JDIMM1.43 JDIMM1.44 JDIMM1.46 JDIMM1.48 JDIMM1.49 JDIMM1.54 JDIMM1.55 JDIMM1.60 JDIMM1.61 JDIMM1.63 JDIMM1.65 JDIMM1.66 JDIMM1.71 JDIMM1.72 JDIMM1.127 JDIMM1.128 JDIMM1.133 JDIMM1.134 JDIMM1.136 JDIMM1.138 JDIMM1.139 JDIMM1.144 JDIMM1.145 JDIMM1.150 JDIMM1.151 JDIMM1.153 JDIMM1.155 JDIMM1.156 JDIMM1.161 JDIMM1.162 JDIMM1.167 JDIMM1.168 JDIMM1.170 JDIMM1.172 JDIMM1.173 JDIMM1.178 JDIMM1.179 JDIMM1.184 JDIMM1.185 JDIMM1.187 JDIMM1.189 JDIMM1.190 JDIMM1.195 JDIMM1.196 JDIMM1.205 JDIMM1.206 JDIMM2.2 JDIMM2.3 JDIMM2.8 JDIMM2.9 JDIMM2.11 JDIMM2.13 JDIMM2.14 JDIMM2.19 JDIMM2.20 JDIMM2.25 JDIMM2.26 JDIMM2.28 JDIMM2.31 JDIMM2.32 JDIMM2.37 JDIMM2.38 JDIMM2.43 JDIMM2.44 JDIMM2.46 JDIMM2.48 JDIMM2.49 JDIMM2.54 JDIMM2.55 JDIMM2.60 JDIMM2.61 JDIMM2.63 JDIMM2.65 JDIMM2.66 JDIMM2.71 JDIMM2.72 JDIMM2.127 JDIMM2.128 JDIMM2.133 JDIMM2.134 JDIMM2.136 JDIMM2.138 JDIMM2.139 JDIMM2.144 JDIMM2.145 JDIMM2.150 JDIMM2.151 JDIMM2.153 JDIMM2.155 JDIMM2.156 JDIMM2.161 JDIMM2.162 JDIMM2.167 JDIMM2.168 JDIMM2.170 JDIMM2.172 JDIMM2.173 JDIMM2.178 JDIMM2.179 JDIMM2.184 JDIMM2.185 JDIMM2.187 JDIMM2.189 JDIMM2.190 JDIMM2.195 JDIMM2.196 JDIMM2.205 JDIMM2.206 JEDP.3 JEDP.6 JEDP.9 JEDP.12 JEDP.15 JEDP.18 JEDP.20 JEDP.31 JEDP.41 JEDP.42 JEDP.43 JEDP.44 JEDP.45 JEDP.46 JFAN.3 JFAN.4 JFAN.5 JHDD.3 JHDD.6 JHDD.11 JHDD.12 JHDMI.2 JHDMI.5 JHDMI.8 JHDMI.11 JHDMI.17 JHDMI.20 JHDMI.21 JHDMI.22 JHDMI.23 JIO.8 JIO.9 JIO.10 JIO.13 JIO.16 JIO.17 JIO.18 JKB.31 JKB.32 JKBBL.5 JKBBL.6 JLAN.9 JLAN.10 JLED.8 JLED.9 JLED.10 JNGFF.1 JNGFF.7 JNGFF.18 JNGFF.25 JNGFF.31 JNGFF.37 JNGFF.43 JNGFF.49 JNGFF.55 JNGFF.61 JNGFF.67 JNGFF.68 JNGFF.69 JRTC.2 JRTC.3 JRTC.4 JSPK.5 JSPK.6 JTP.5 JTP.9 JTP.10 JTP1.7 JTP1.11 JTP1.12 JUSB1.4 JUSB1.7 JUSB1.10 JUSB1.11 JUSB1.12 JUSB1.13 JUSB2.4 JUSB2.7 JUSB2.10 JUSB2.11 JUSB2.12 JUSB2.13 JXDP1.1 JXDP1.2 JXDP1.7 JXDP1.8 JXDP1.13 JXDP1.14 JXDP1.19 JXDP1.20 JXDP1.25 JXDP1.26 JXDP1.31 JXDP1.32 JXDP1.37 JXDP1.38 JXDP1.49 JXDP1.50 JXDP1.59 LE2.1 PBATT.1 PBATT.2 PBATT.4 PBATT.10 PBATT.11 PC1.2 PC2.2 PC3.2 PC4.2 PC5.2 PC7.2 PC8.2 PC13.1 PC15.2 PC17.1 PC100.2 PC101.2 PC103.2 PC105.2 PC106.2 PC107.2 PC109.2 PC111.2 PC112.2 PC113.2 PC114.2 PC115.2 PC116.2 PC117.2 PC201.2 PC202.2 PC203.2 PC204.1 PC205.2 PC206.2 PC208.2 PC209.2 PC210.2 PC211.2 PC212.2 PC213.2 PC300.2 PC301.2 PC303.2 PC304.2 PC305.2 PC306.2 PC308.2 PC309.2 PC310.2 PC311.2 PC312.2 PC313.2 PC400.2 PC401.2 PC402.2 PC404.2 PC500.1 PC510.2 PC515.2 PC516.2 PC517.2 PC518.2 PC519.2 PC521.2 PC524.2 PC526.1 PC527.1 PC528.2 PC531.1 PC532.2 PC541.1 PC546.1 PC548.1 PC600.2 PC601.2 PC602.2 PC603.2 PC605.2 PC703.2 PC704.2 PC705.2 PC706.2 PC707.2 PC708.2 PC709.1 PC710.2 PC711.1 PC712.2 PC713.2 PC714.2 PC716.2 PC718.2 PC719.1 PC720.1 PC724.1 PC725.1 PC726.1 PC728.1 PC729.2 PC730.2 PC731.2 PC732.2 PC734.2 PC735.2 PC736.2 PC737.2 PC738.2 PC739.2 PC836.2 PC837.2 PC838.2 PC839.2 PC840.2 PC841.2 PC842.2 PC843.2 PC844.2 PC845.2 PC846.2 PC847.2 PC848.2 PC849.2 PC850.2 PC851.2 PC852.2 PC853.2 PC854.2 PC855.2 PC856.2 PC857.2 PC858.2 PC859.2 PC860.2 PC869.2 PC871.2 PC872.2 PC901.2 PC902.2 PC903.2 PC904.2 PC905.2 PC906.2 PC907.2 PC908.2 PC909.2 PC910.2 PC911.2 PC912.2 PC913.2 PC914.2 PC915.2 PC916.2 PC917.2 PC918.2 PC919.2 PC920.2 PC921.2 PC922.2 PC923.2 PC924.2 PC1019.2 PC1020.2 PC1021.2 PC1022.1 PC1023.2 PC1024.2 PC1025.2 PC1029.2 PC1030.2 PC1034.2 PC1035.2 PC1040.2 PC1041.2 PC1042.2 PC1044.2 PC1045.2 PC1046.2 PC1047.2 PC1048.2 PC1049.2 PC1052.2 PC1100.2 PC1101.2 PC1102.2 PC1104.2 PC1105.2 PC1106.2 PC1108.2 PC1300.2 PC1301.2 PC1302.2 PC1303.2 PC1304.2 PC1305.2 PC1307.2 PC1308.2 PD1.1 PD2.1 PD101.1 PH500.2 PH1002.1 PL4.2 PL7.2 PQ1.1 PQ1.4 PQ2.1 PQ2.4 PQ3.1 PQ3.4 PQ4.1 PQ4.4 PQ5.3 PQ102.1 PQ102.2 PQ102.3 PQ104.1 PQ104.2 PQ104.3 PQ201.1 PQ201.2 PQ201.3 PQ501.8 PQ705.1 PQ705.2 PQ705.3 PQ706.1 PQ706.4 PQ1004.1 PQ1004.2 PQ1004.3 PQ1006.1 PQ1006.2 PQ1006.3 PQ1007.1 PQ1007.2 PQ1007.3 PQ1008.1 PQ1008.2 PQ1008.3 PQ1101.1 PQ1101.2 PQ1101.3 PR2.2 PR9.1 PR10.1 PR26.1 PR29.2 PR32.2 PR33.1 PR34.1 PR105.2 PR106.2 PR107.1 PR108.2 PR110.2 PR114.2 PR203.2 PR204.2 PR301.2 PR306.2 PR307.2 PR401.2 PR403.2 PR507.2 PR512.2 PR521.2 PR528.2 PR534.2 PR558.2 PR602.2 PR604.2 PR711.1 PR712.2 PR722.2 PR724.1 PR1029.1 PR1031.1 PR1032.1 PR1033.1 PR1035.1 PR1038.2 PR1051.2 PR1056.1 PR1102.1 PR1105.2 PR1108.2 PR1301.2 PR1304.2 PU100.21 PU200.1 PU200.3 PU200.14 PU200.21 PU300.9 PU400.1 PU501.21 PU600.4 PU600.8 PU600.9 PU701.22 PU701.29 PU1000.41 PU1100.11 PU1300.11 Q8.3 Q2307.3 Q2308.3 QC2.1 QC2.4 QE4.3 QE5.4 QV3.3 QV4.3 QV8.1 QV8.4 QX1.3 QX3.3 R2.2 R16.2 R159.2 R255.1 R2338.2 R2351.1 R2453.2 RA19.2 RA29.2 RA30.2 RA31.2 RA32.2 RA81.1 RA1113.1 RC2.2 RC20.2 RC21.2 RC22.2 RC23.2 RC24.2 RC25.2 RC66.2 RC68.2 RC69.2 RC70.2 RC84.1 RC87.1 RC88.2 RC89.2 RC90.2 RC99.2 RC101.2 RC113.2 RC116.2 RC122.2 RC123.2 RC132.2 RC133.1 RC134.2 RC135.2 RC138.2 RC163.2 RC368.2 RD6.1 RD7.1 RD13.2 RE1.1 RE2.1 RE5.1 RE18.2 RE47.1 RE58.2 RE326.2 RL27.1 RL31.1 RL35.1 RM9.2 RP34.4 RP41.5 RP41.6 RP41.7 RP41.8 RP45.6 RP45.7 RP51.6 RP51.7 RS18.2 RS21.2 RS22.1 RS23.2 RS24.2 RS31.2 RS35.2 RS36.2 RS37.2 RV2.1 RV4.2 RV9.2 RV12.2 RV13.2 RV16.2 RV17.1 RV21.1 RV29.1 RV34.2 RV35.2 RV38.2 RV39.1 RV40.1 RV41.1 RV44.2 RV45.2 RV46.2 RV47.2 RV52.2 RV53.2 RV56.2 RV57.2 RV59.1 RV73.1 RV74.1 RV83.2 RV88.1 RV89.1 RV150.1 RV151.1 RV160.2 RV163.2 RX9.2 RX13.2 RX14.2 RX24.1 RX26.2 RX34.2 RX36.2 RX41.2 SW1.1 SW1.2 SW1.5 SW1.6 U1.4 U2301.11 U2301.15 U2302.4 U2303.3 U2304.11 U2304.15 U2407.6 U2408.5 U2408.9 UA1.49 UC1.A11 UC1.A14 UC1.A18 UC1.A24 UC1.A28 UC1.A32 UC1.A36 UC1.A40 UC1.A44 UC1.A48 UC1.A52 UC1.A56 UC1.AA1 UC1.AA58 UC1.AB7 UC1.AB10 UC1.AB20 UC1.AB22 UC1.AC61 UC1.AD3 UC1.AD21 UC1.AD63 UC1.AE5 UC1.AE10 UC1.AE58 UC1.AF11 UC1.AF12 UC1.AF14 UC1.AF15 UC1.AF17 UC1.AF18 UC1.AG1 UC1.AG11 UC1.AG21 UC1.AG23 UC1.AG60 UC1.AG61 UC1.AG62 UC1.AG63 UC1.AH16 UC1.AH17 UC1.AH19 UC1.AH20 UC1.AH22 UC1.AH24 UC1.AH28 UC1.AH30 UC1.AH32 UC1.AH34 UC1.AH36 UC1.AH38 UC1.AH40 UC1.AH42 UC1.AH44 UC1.AH46 UC1.AH49 UC1.AH51 UC1.AH53 UC1.AH55 UC1.AH57 UC1.AJ13 UC1.AJ14 UC1.AJ23 UC1.AJ25 UC1.AJ27 UC1.AJ29 UC1.AJ35 UC1.AJ39 UC1.AJ41 UC1.AJ43 UC1.AJ45 UC1.AJ47 UC1.AJ50 UC1.AJ52 UC1.AJ54 UC1.AJ56 UC1.AJ58 UC1.AJ60 UC1.AJ63 UC1.AK3 UC1.AK23 UC1.AK52 UC1.AL10 UC1.AL13 UC1.AL17 UC1.AL20 UC1.AL22 UC1.AL23 UC1.AL26 UC1.AL29 UC1.AL31 UC1.AL33 UC1.AL36 UC1.AL39 UC1.AL40 UC1.AL45 UC1.AL46 UC1.AL51 UC1.AL52 UC1.AL54 UC1.AL57 UC1.AL60 UC1.AL61 UC1.AM1 UC1.AM17 UC1.AM23 UC1.AM31 UC1.AM52 UC1.AN7 UC1.AN17 UC1.AN23 UC1.AN31 UC1.AN32 UC1.AN35 UC1.AN36 UC1.AN39 UC1.AN40 UC1.AN42 UC1.AN43 UC1.AN45 UC1.AN46 UC1.AN48 UC1.AN49 UC1.AN51 UC1.AN52 UC1.AN60 UC1.AN63 UC1.AP3 UC1.AP10 UC1.AP17 UC1.AP20 UC1.AP22 UC1.AP23 UC1.AP26 UC1.AP29 UC1.AP31 UC1.AP38 UC1.AP39 UC1.AP48 UC1.AP52 UC1.AP54 UC1.AP57 UC1.AR5 UC1.AR11 UC1.AR15 UC1.AR17 UC1.AR23 UC1.AR31 UC1.AR33 UC1.AR39 UC1.AR43 UC1.AR49 UC1.AR52 UC1.AT13 UC1.AT35 UC1.AT37 UC1.AT40 UC1.AT42 UC1.AT43 UC1.AT46 UC1.AT49 UC1.AT61 UC1.AT62 UC1.AT63 UC1.AU1 UC1.AU16 UC1.AU18 UC1.AU20 UC1.AU22 UC1.AU24 UC1.AU26 UC1.AU28 UC1.AU30 UC1.AU33 UC1.AU51 UC1.AU53 UC1.AU55 UC1.AU57 UC1.AU59 UC1.AV8 UC1.AV14 UC1.AV16 UC1.AV20 UC1.AV24 UC1.AV28 UC1.AV33 UC1.AV34 UC1.AV36 UC1.AV39 UC1.AV41 UC1.AV43 UC1.AV46 UC1.AV49 UC1.AV51 UC1.AV55 UC1.AV59 UC1.AW4 UC1.AW16 UC1.AW24 UC1.AW33 UC1.AW35 UC1.AW37 UC1.AW40 UC1.AW42 UC1.AW44 UC1.AW47 UC1.AW50 UC1.AW51 UC1.AW59 UC1.AW60 UC1.AY4 UC1.AY6 UC1.AY11 UC1.AY16 UC1.AY18 UC1.AY22 UC1.AY24 UC1.AY26 UC1.AY30 UC1.AY33 UC1.AY51 UC1.AY53 UC1.AY57 UC1.AY59 UC1.B4 UC1.B20 UC1.B24 UC1.B26 UC1.B28 UC1.B32 UC1.B36 UC1.B40 UC1.B44 UC1.B48 UC1.B52 UC1.B56 UC1.B60 UC1.C11 UC1.C14 UC1.C18 UC1.C20 UC1.C25 UC1.C27 UC1.C38 UC1.C39 UC1.C57 UC1.D2 UC1.D5 UC1.D8 UC1.D12 UC1.D14 UC1.D18 UC1.D21 UC1.D23 UC1.D25 UC1.D26 UC1.D27 UC1.D29 UC1.D30 UC1.D31 UC1.D33 UC1.D34 UC1.D35 UC1.D37 UC1.D38 UC1.D39 UC1.D41 UC1.D42 UC1.D43 UC1.D45 UC1.D46 UC1.D47 UC1.D49 UC1.D50 UC1.D51 UC1.D53 UC1.D54 UC1.D55 UC1.D57 UC1.D59 UC1.D62 UC1.D63 UC1.E11 UC1.E17 UC1.F20 UC1.F26 UC1.F30 UC1.F34 UC1.F38 UC1.F42 UC1.F46 UC1.F50 UC1.F54 UC1.F58 UC1.F61 UC1.G3 UC1.G5 UC1.G6 UC1.G8 UC1.G18 UC1.G22 UC1.H13 UC1.H17 UC1.H57 UC1.J10 UC1.J22 UC1.J59 UC1.J63 UC1.K1 UC1.K12 UC1.L7 UC1.L13 UC1.L15 UC1.L17 UC1.L18 UC1.L20 UC1.L58 UC1.L61 UC1.M22 UC1.N3 UC1.N10 UC1.N21 UC1.P22 UC1.P59 UC1.P62 UC1.P63 UC1.R8 UC1.R10 UC1.R22 UC1.T1 UC1.T58 UC1.U9 UC1.U20 UC1.U22 UC1.U61 UC1.V3 UC1.V7 UC1.V10 UC1.V23 UC1.V58 UC1.W20 UC1.W22 UC1.Y10 UC1.Y59 UC1.Y63 UC3.3 UC4.7 UC4.15 UE1.11 UE1.24 UE1.35 UE1.94 UE1.113 UE2.3 UE3.5 UE3.6 UE3.7 UE3.8 UE4.5 UE4.9 UG1.4 UG1.7 UG1.13 UG1.17 UI2.1 UI2.9 UI3.1 UI3.9 UI4.1 UI4.9 UI5.2 UI6.2 UI7.2 UL1.33 UL2.2 UL3.2 UM1.2 US2.3 US2.21 US3.5 US3.10 US3.12 US3.13 US3.15 US3.16 UV1.A3 UV1.A30 UV1.AA11 UV1.AA13 UV1.AA16 UV1.AA27 UV1.AB6 UV1.AB10 UV1.AB15 UV1.AB24 UV1.AB32 UV1.AC9 UV1.AC17 UV1.AC24 UV1.AC26 UV1.AC27 UV1.AD6 UV1.AD8 UV1.AD25 UV1.AD32 UV1.AE7 UV1.AE14 UV1.AE27 UV1.AF32 UV1.AG12 UV1.AG27 UV1.AH10 UV1.AH28 UV1.AH32 UV1.B6 UV1.B8 UV1.B10 UV1.B12 UV1.B14 UV1.B16 UV1.B18 UV1.B20 UV1.B22 UV1.B24 UV1.B26 UV1.C1 UV1.C32 UV1.E28 UV1.F2 UV1.F6 UV1.F8 UV1.F10 UV1.F12 UV1.F14 UV1.F16 UV1.F18 UV1.F20 UV1.F22 UV1.F24 UV1.F26 UV1.G8 UV1.G10 UV1.G27 UV1.G31 UV1.H2 UV1.H6 UV1.H14 UV1.H17 UV1.H20 UV1.J7 UV1.J27 UV1.J31 UV1.K2 UV1.K6 UV1.K11 UV1.K22 UV1.K28 UV1.K32 UV1.L27 UV1.M6 UV1.M12 UV1.M32 UV1.N11 UV1.N13 UV1.N16 UV1.N18 UV1.N21 UV1.N25 UV1.N27 UV1.P6 UV1.P9 UV1.P25 UV1.P32 UV1.R11 UV1.R12 UV1.R15 UV1.R17 UV1.R20 UV1.R27 UV1.T6 UV1.T11 UV1.T13 UV1.T16 UV1.T18 UV1.T21 UV1.T25 UV1.T32 UV1.U9 UV1.U15 UV1.U17 UV1.U20 UV1.U25 UV1.U27 UV1.V11 UV1.V13 UV1.V16 UV1.V18 UV1.V32 UV1.W25 UV1.W26 UV1.W27 UV1.Y10 UV1.Y15 UV1.Y17 UV1.Y20 UV1.Y25 UV1.Y32 UV2.3 UV3.5 UV5.A9 UV5.B1 UV5.B3 UV5.B9 UV5.D1 UV5.D8 UV5.E1 UV5.E2 UV5.E8 UV5.F9 UV5.G1 UV5.G8 UV5.G9 UV5.J2 UV5.J8 UV5.M1 UV5.M9 UV5.P1 UV5.P9 UV5.T1 UV5.T9 UV6.A9 UV6.B1 UV6.B3 UV6.B9 UV6.D1 UV6.D8 UV6.E1 UV6.E2 UV6.E8 UV6.F9 UV6.G1 UV6.G8 UV6.G9 UV6.J2 UV6.J8 UV6.M1 UV6.M9 UV6.P1 UV6.P9 UV6.T1 UV6.T9 UV7.A9 UV7.B1 UV7.B3 UV7.B9 UV7.D1 UV7.D8 UV7.E1 UV7.E2 UV7.E8 UV7.F9 UV7.G1 UV7.G8 UV7.G9 UV7.J2 UV7.J8 UV7.M1 UV7.M9 UV7.P1 UV7.P9 UV7.T1 UV7.T9 UV8.A9 UV8.B1 UV8.B3 UV8.B9 UV8.D1 UV8.D8 UV8.E1 UV8.E2 UV8.E8 UV8.F9 UV8.G1 UV8.G8 UV8.G9 UV8.J2 UV8.J8 UV8.M1 UV8.M9 UV8.P1 UV8.P9 UV8.T1 UV8.T9 UX1.2 UX3.2 UX4.2 YG1.2 YG1.4 YL2.2 YL2.4 YV1.2 YV1.4
GNDA: CA1.2 CA2.2 CA23.1 CA33.2 CA38.2 CA39.2 CA40.2 CA51.2 CA61.2 CA62.1 CA63.1 CA71.2 JHP.6 JHP.7 QA5.1 QA5.4 QA6.1 QA6.4 RA12.1 RA29.1 RA30.1 RA31.1 RA32.1 RA83.2 RA84.2 UA1.25 UA1.38
VCCSENSE: PC522.1 PC541.2 PC545.1 PR537.1 R1.2 UC1.E63
VCCSENSE_VGA: PR1047.1 PR1049.2 RV159.2 RV161.1
VCCST_PG_EC: C79.1 CE35.1 DE1.2 R286.2 UC1.B59 UE1.123
VDD_1.35V: PC209.1 PR205.1 PR206.2 PU200.11
VDDIO: PC1019.1 PR1022.2 PR1025.2 PU1000.6
VDDR4: UV1.U12 UV1.V12 UV1.Y12
VIN: PC3.1 PC4.1 PC735.1 PL1.2 PL6.2 PQ700.5 PQ700.6 PQ700.7 PQ700.8 PR5.1 PR7.2 PR31.2 PR705.1 PR720.1 PR723.2
VSS_MECH: UV1.A32 UV1.AM1 UV1.AM32
VSSSENSE: PC545.2 PC546.2 PU501.8 R2.1 RC163.1 UC1.E62
VSSSENSE_VGA: PR1050.2 PR1051.1 RV158.2 RV160.1
65W#/90W: PQ4.2 PQ4.5 UE1.117
+A_VCC: RA10.2 RA11.2 UA1.20
+BIF_VDDC: CV168.1 RV31.1 UV1.R21 UV1.U21
+CHGRTC: DC1.3 JP12.2
+CODEC_AVDD2: CA61.1 RA8.2 RA9.2 UA1.40
+CPU_CORE: C40.1 C46.2 C47.2 PC901.1 PC902.1 PC903.1 PC904.1 PC905.1 PC906.1 PC907.1 PC908.1 PC909.1 PC910.1 PC911.1 PC912.1 PC913.1 PC914.1 PC915.1 PC916.1 PC917.1 PC918.1 PC919.1 PC920.1 PC921.1 PC922.1 PC923.1 PC924.1 PL502.4 R1.1 UC1.AB57 UC1.AD57 UC1.AG57 UC1.C24 UC1.C28 UC1.C32 UC1.C36 UC1.C40 UC1.C44 UC1.C48 UC1.C52 UC1.C56 UC1.E23 UC1.E25 UC1.E27 UC1.E29 UC1.E31 UC1.E33 UC1.E35 UC1.E37 UC1.E39 UC1.E41 UC1.E43 UC1.E45 UC1.E47 UC1.E49 UC1.E51 UC1.E53 UC1.E55 UC1.E57 UC1.F24 UC1.F28 UC1.F32 UC1.F36 UC1.F40 UC1.F44 UC1.F48 UC1.F52 UC1.F56 UC1.F59 UC1.G23 UC1.G25 UC1.G27 UC1.G29 UC1.G31 UC1.G33 UC1.G35 UC1.G37 UC1.G39 UC1.G41 UC1.G43 UC1.G45 UC1.G47 UC1.G49 UC1.G51 UC1.G53 UC1.G55 UC1.G57 UC1.H23 UC1.J23 UC1.K23 UC1.K57 UC1.L22 UC1.M23 UC1.M57 UC1.P57 UC1.U57 UC1.W57
+DIMM1_VREF_DQ: CD1.1 CD2.1 JDIMM1.1 RD1.2
+DIMM2_VREF_DQ: CD32.1 CD33.1 JDIMM2.1 RD8.2
+DP_VDDC: CV33.1 CV34.1 RV30.2 UV1.AD14
+DP_VDDR: CV26.1 CV27.1 RV27.2 UV1.AF14
+EC_VCCA: CE7.1 LE1.2 PR24.2 UE1.67
+FAN_POWER: CE22.1 CE23.1 JFAN.1 UE3.3
+FBA_VREF0: CV100.1 RV42.2 RV44.1 UV5.H1 UV5.M8
+FBA_VREF1: CV101.1 RV43.2 RV45.1 UV6.H1 UV6.M8
+FBA_VREF2: CV133.1 RV50.2 RV52.1 UV7.H1 UV7.M8
+FBA_VREF3: CV134.1 RV51.2 RV53.1 UV8.H1 UV8.M8
+INV_PWR_SRC: CX5.1 J520.2 JEDP.39 JEDP.40 QX2.1 QX2.2 QX2.5 QX2.6
+LAN_REGOUT: CL3.1 LL1.1 RL1.2 UL1.24
+LAN_VDD10: CL4.1 CL5.1 CL6.1 CL7.1 CL8.1 CL9.1 LL1.2 RL1.1 UL1.3 UL1.8 UL1.22 UL1.30
+LAN_VDD33: CG3.1 CL12.1 CL13.1 CL14.1 CL15.1 CL19.1 JP3.1 RL6.1 RL34.1 RL38.2 RL39.1 UG1.8 UL1.11 UL1.32 UL2.1 UL3.1
+LAN_VDDREG: CL16.2 CL17.1 RL6.2 UL1.23
+LCDVDD: LX1.1 UX1.1 UX4.1
+LCDVDD_CONN: CX2.1 CX3.1 CX8.1 CX11.1 JEDP.24 JEDP.25 LX1.2
+MIC2-VREFO: RA53.2 RA1109.2 UA1.29
+MPLL_PVDD: CV81.1 CV82.1 CV83.1 LV6.2 UV1.L8
+MVREFDA: CV94.1 RV33.2 RV34.1 UV1.K26
+MVREFSA: CV95.1 RV32.2 RV35.1 UV1.J26
+PCH_VCCDSW: C64.1 C5215.1 UC1.AG19 UC1.AG20
+RTCBATT: JRTC.1 RC10.2 RG1.1
+RTCVCC: C54.1 C55.1 C56.1 CC26.1 DC1.1 JP14.2 R2337.2 RA5.1 RA11.1 RC1.1 RC5.1 RC6.1 RC7.1 RG2.1 RG4.1 UC1.AG10
+SM_VREF_CA: CC8.1 RC17.2 UC1.AP49
+SM_VREF_CA_DIMM: RC14.2 RC17.1 RC20.1 RD4.2 RD10.2
+SM_VREF_DQ0: CC10.1 RC19.2 UC1.AR51
+SM_VREF_DQ0_DIMM1: RC16.2 RC19.1 RC22.1 RD1.1
+SM_VREF_DQ1: CC9.1 RC18.2 UC1.AP51
+SM_VREF_DQ1_DIMM2: RC15.2 RC18.1 RC21.1 RD8.1
+SPLL_PVDD: CV84.1 CV85.1 CV86.1 LV7.2 UV1.H7
+SPLL_VDDC: CV91.1 CV92.1 CV93.1 LV8.2 UV1.H8
+TSVDD: CV19.1 CV20.1 CV21.1 LV2.2 UV1.AD17
+V_TP: J519.1 RE330.2 RE331.2 UE4.1 UE4.2 UE4.4
+V_TS: CX51.1 RX28.2 RX29.2 RX30.2 UX3.5
+VCHGR: PC712.1 PC713.1 PC716.1 PQ702.1 PQ702.2 PQ702.3 PR701.1 PR716.4
+VDISPLAY_VCC: CX21.1 CX22.1 FX1.1 JHDMI.18
+VGA_CORE: CV67.1 CV68.1 CV69.1 CV70.1 CV71.1 CV72.1 CV73.1 CV74.1 CV75.1 CV76.1 CV77.1 CV78.1 CV79.1 CV80.1 LV25.2 LV26.2 PC836.1 PC837.1 PC838.1 PC839.1 PC840.1 PC841.1 PC842.1 PC843.1 PC844.1 PC845.1 PC846.1 PC847.1 PC848.1 PC849.1 PC850.1 PC851.1 PC852.1 PC853.1 PC854.1 PC855.1 PC856.1 PC857.1 PC858.1 PC859.1 PC860.1 PC869.1 PC871.1 PC872.1 PL1002.4 PL1003.4 PR1047.2 RV60.2 RV161.2 UV1.AA12 UV1.AA15 UV1.AB11 UV1.AB12 UV1.AB13 UV1.AC14 UV1.M11 UV1.N12 UV1.N15 UV1.N17 UV1.R13 UV1.R16 UV1.R18 UV1.T10 UV1.T12 UV1.T15 UV1.T17 UV1.T20 UV1.U10 UV1.U11 UV1.U13 UV1.U16 UV1.U18 UV1.V15 UV1.V17 UV1.V20 UV1.V21 UV1.W9 UV1.W10 UV1.Y9 UV1.Y13 UV1.Y16 UV1.Y18 UV1.Y21
+VGA_PCIE: CV54.1 CV55.1 CV56.1 CV57.1 CV58.1 CV59.1 CV60.1 LV8.1 PJP1300.1 RV1.2 RV3.2 RV30.1 RV31.2 UV1.L23 UV1.L24 UV1.L25 UV1.L26 UV1.M22 UV1.N22 UV1.N23 UV1.N24 UV1.R22 UV1.T22 UV1.U22 UV1.V22
+VGA_PCIEP: PC1300.1 PC1303.1 PC1305.1 PC1306.1 PC1308.1 PJP1300.2 PL1300.2 PR1302.1
AC_PRESENT: DH1.2 RC32.2 UC1.AJ8
ACDET: PC711.2 PR711.2 PR723.1 PU701.3
ACIN: CE18.2 DH1.1 PR1.1 PR707.2 PR712.1 PU701.14 RV149.1 UE1.110
ACIN_65W: QV8.2 RV149.2 UE1.108
ACOFF: PQ706.5 UE1.27
AD_BID0: CE8.1 RE3.1 RE5.2 UE1.75
ADP_I: PC720.2 PR23.2 PU701.9 UE1.65
ADPIN: PC1.1 PC2.1 PJPDC.4 PJPDC.5 PL1.1 PL6.1
AGATE: PR725.1 PU701.1
ALERT#: PR503.1 PR506.2 PU501.19
AOAC_WLAN: UE1.85 UM1.4
AUD_HP_OUT_L_CN: CA39.1 DA10.3 JHP.1 LA8.1
AUD_HP_OUT_R_CN: CA33.1 DA10.2 JHP.2 LA9.1
B+: CX4.1 J520.1 PC714.1 PC718.1 PC732.1 PC736.1 PC737.1 PC738.1 PC739.1 PL102.1 PL201.1 PL302.1 PL501.2 PL503.2 PL701.2 PL1000.2 PL1004.2 PL1100.2 PR716.1 QX2.4 RX2.1
B+_1.05V: PC303.1 PC304.1 PC305.1 PC306.1 PL302.2 PU300.8
BAT_ALERT: PBATT.3 PD1.2
BATT+: PC7.1 PL3.1 PL5.1 PQ702.5 PQ702.6 PQ702.7 PQ702.8
BATT++: PBATT.8 PBATT.9 PC8.1 PL3.2 PL5.2
BATT_CHG_LED#: JLED.6 UE1.92
BATT_I: PC725.2 PR35.2 PU701.15
BATT_LOW_LED#: JLED.5 UE1.93
BATT_PRS: PBATT.5 PC14.1 PD1.3 PR15.1 PR37.2
BATT_TEMP: CE9.2 PC723.2 PR15.2 PR16.1 UE1.63
BBS_BIT: RC119.2 RC123.1 UC1.L8
BEEP#: DA8.2 UE1.23
BGATE: PR706.2 PU701.16
BKOFF#: DX1.2 UE1.105
BOOT1: PR1034.1 PU1000.21
BOOT2: PR1055.1 PU1000.30
BOOT_1.35V: PR200.2 PU200.18
BP_0: RV82.1 UV1.U1
BP_1: RV81.1 UV1.U3
BST: PR709.1 PU701.25
BST_1.05V: PR303.1 PU300.6
BST_1.35V: PC200.1 PR200.1
BST_3V: PR103.2 PU100.9
BST_5V: PR111.1 PU100.17
BST_+1.35VGPUP: PR1101.1 PU1100.10
BST_CHGA: PC721.1 PR709.2
BT_ON#: JNGFF.46 RP54.2 UC1.AD5
CAPS_LED: JKB.1 UE1.91
CELL: PR719.2 PU701.6
CFD_PWRBTN#_XDP: JXDP1.41 RC49.2
CFG0: JXDP1.9 UC1.AC60
CFG1: JXDP1.11 UC1.AC62
CFG2: JXDP1.15 UC1.AC63
CFG3: JXDP1.17 RC56.2 UC1.AA63
CFG3_R: JXDP1.60 RC56.1
CFG4: JXDP1.27 RC138.1 UC1.AA60
CFG5: JXDP1.29 UC1.Y62
CFG6: JXDP1.33 UC1.Y61
CFG7: JXDP1.35 UC1.Y60
CFG8: JXDP1.10 UC1.V62
CFG9: JXDP1.12 UC1.V61
CFG10: JXDP1.16 UC1.V60
CFG11: JXDP1.18 UC1.U60
CFG12: JXDP1.28 UC1.T63
CFG13: JXDP1.30 UC1.T62
CFG14: JXDP1.34 UC1.T61
CFG15: JXDP1.36 UC1.T60
CFG16: JXDP1.6 UC1.AA62
CFG17: JXDP1.4 UC1.AA61
CFG18: JXDP1.24 UC1.U63
CFG19: JXDP1.22 UC1.U62
CFG_RCOMP: RC132.1 UC1.V63
CHG_B+: PC703.1 PC704.1 PC705.1 PC706.1 PC734.1 PL702.2 PQ703.5
CLK_BIASREF: RC13.1 UC1.C26
CLK_CPU_ITP: RC139.2 UC1.A35
CLK_CPU_ITP#: RC140.2 UC1.B35
CLK_PCI_LPC: R2336.1 R2354.2 UE1.12
CLK_PCIE_LAN: UC1.B42 UL1.15
CLK_PCIE_LAN#: UC1.C41 UL1.16
CLK_PCIE_WLAN: JNGFF.39 UC1.C37
CLK_PCIE_WLAN#: JNGFF.41 UC1.B38
CLK_PEG_VGA: UC1.B39 UV1.AK30
CLK_PEG_VGA#: UC1.A39 UV1.AK32
CLK_SMB: PBATT.7 PD2.3 PR18.1
CLK_X1: CG8.1 UG1.1 YG1.1
CLK_X2: CG9.1 UG1.16 YG1.3
CLK_XDP: JXDP1.40 RC139.1
CLK_XDP#: JXDP1.42 RC140.1
CLKOUT_LPC0: R2336.2 UC1.AN15
CLKRUN#: RC36.2 UC1.V5
CODEC_IRQ: RC88.1 UC1.L4
COMP: PC531.2 PR539.2 PU501.6
CPPE#: RC108.2 UC1.J1
CPU_DPB_AUX: RP51.2 UC1.B5
CPU_DPB_AUX#: RP51.1 UC1.C5
CPU_DPB_CTRLCLK: QX4.1 RP52.2 UC1.B9
CPU_DPB_CTRLCLK_R: JHDMI.15 QX4.6 RX16.1
CPU_DPB_CTRLDAT: QX4.4 RP52.1 UC1.C9
CPU_DPB_CTRLDAT_R: JHDMI.16 QX4.3 RX17.1
CPU_DPC_AUX: RP51.3 UC1.A6
CPU_DPC_AUX#: RP51.4 UC1.B6
CPU_DPC_CTRLCLK: RP52.3 UC1.D9
CPU_DPC_CTRLDAT: RP52.4 UC1.D11
CPU_EDP_HPD#: RC82.2 RC89.1 UC1.D6
CPU_PWR_DEBUG#: R253.1 R255.2 RC50.1 UC1.H59
CPU_PWR_DEBUG#_R: JXDP1.45 RC50.2
CPUSB#: RC111.2 UC1.K3
CS1: PR105.1 PU100.1
CS2: PR108.1 PU100.5
CS_1.35V: PR205.2 PU200.13
CSIN: PC708.1 PC717.2 PR704.1 PU701.27
CSIP: PC707.1 PC717.1 PR717.1 PU701.28
CSON: PC722.2 PR716.3 PU701.17
CSOP: PC722.1 PR708.1 PU701.18
DAT_SMB: PBATT.6 PD2.2 PR20.1
DBC_EN: RX23.1 UE1.25
DBC_EN_R: JEDP.23 RX23.2 RX36.1
DC_TEST_A3_B3: UC1.A3 UC1.B3
DC_TEST_A4: T168.1(TP-1) UC1.A4
DC_TEST_A60: T169.1(TP-1) UC1.A60
DC_TEST_A61_B61: UC1.A61 UC1.B61
DC_TEST_A62: T170.1(TP-1) UC1.A62
DC_TEST_AV1: T171.1(TP-1) UC1.AV1
DC_TEST_AW1: T172.1(TP-1) UC1.AW1
DC_TEST_AW63: T173.1(TP-1) UC1.AW63
DC_TEST_AY2_AW2: UC1.AW2 UC1.AY2
DC_TEST_AY3_AW3: UC1.AW3 UC1.AY3
DC_TEST_AY60: T166.1(TP-1) UC1.AY60
DC_TEST_AY61_AW61: UC1.AW61 UC1.AY61
DC_TEST_AY62_AW62: UC1.AW62 UC1.AY62
DC_TEST_B62_B63: UC1.B62 UC1.B63
DC_TEST_C1_C2: UC1.C1 UC1.C2
DCIN: PC710.1 PR705.2 PU701.2
DDI1_LANE_N0: CX18.2 UC1.C54
DDI1_LANE_N1: CX16.2 UC1.B58
DDI1_LANE_N2: CX14.2 UC1.B55
DDI1_LANE_N3: CX12.2 UC1.A57
DDI1_LANE_P0: CX19.2 UC1.C55
DDI1_LANE_P1: CX17.2 UC1.C58
DDI1_LANE_P2: CX15.2 UC1.A55
DDI1_LANE_P3: CX13.2 UC1.B57
DDR3_DRAMRST#: CD3.1 CD34.1 JDIMM1.30 JDIMM2.30 RD5.1
DDR3_DRAMRST#_CPU: CC35.1 RD3.2 RD5.2 UC1.AV15
DDR_A_BS0: JDIMM1.109 UC1.AU35
DDR_A_BS1: JDIMM1.108 UC1.AV35
DDR_A_BS2: JDIMM1.79 UC1.AY41
DDR_A_CAS#: JDIMM1.115 UC1.AU34
DDR_A_D0: JDIMM1.5 UC1.AH63
DDR_A_D1: JDIMM1.7 UC1.AH62
DDR_A_D2: JDIMM1.15 UC1.AK63
DDR_A_D3: JDIMM1.17 UC1.AK62
DDR_A_D4: JDIMM1.4 UC1.AH61
DDR_A_D5: JDIMM1.6 UC1.AH60
DDR_A_D6: JDIMM1.16 UC1.AK61
DDR_A_D7: JDIMM1.18 UC1.AK60
DDR_A_D8: JDIMM1.21 UC1.AM63
DDR_A_D9: JDIMM1.23 UC1.AM62
DDR_A_D10: JDIMM1.33 UC1.AP63
DDR_A_D11: JDIMM1.35 UC1.AP62
DDR_A_D12: JDIMM1.22 UC1.AM61
DDR_A_D13: JDIMM1.24 UC1.AM60
DDR_A_D14: JDIMM1.34 UC1.AP61
DDR_A_D15: JDIMM1.36 UC1.AP60
DDR_A_D16: JDIMM1.39 UC1.AY58
DDR_A_D17: JDIMM1.41 UC1.AW58
DDR_A_D18: JDIMM1.51 UC1.AY56
DDR_A_D19: JDIMM1.53 UC1.AW56
DDR_A_D20: JDIMM1.40 UC1.AV58
DDR_A_D21: JDIMM1.42 UC1.AU58
DDR_A_D22: JDIMM1.50 UC1.AV56
DDR_A_D23: JDIMM1.52 UC1.AU56
DDR_A_D24: JDIMM1.57 UC1.AY54
DDR_A_D25: JDIMM1.59 UC1.AW54
DDR_A_D26: JDIMM1.67 UC1.AY52
DDR_A_D27: JDIMM1.69 UC1.AW52
DDR_A_D28: JDIMM1.56 UC1.AV54
DDR_A_D29: JDIMM1.58 UC1.AU54
DDR_A_D30: JDIMM1.68 UC1.AV52
DDR_A_D31: JDIMM1.70 UC1.AU52
DDR_A_D32: JDIMM1.129 UC1.AY31
DDR_A_D33: JDIMM1.131 UC1.AW31
DDR_A_D34: JDIMM1.141 UC1.AY29
DDR_A_D35: JDIMM1.143 UC1.AW29
DDR_A_D36: JDIMM1.130 UC1.AV31
DDR_A_D37: JDIMM1.132 UC1.AU31
DDR_A_D38: JDIMM1.140 UC1.AV29
DDR_A_D39: JDIMM1.142 UC1.AU29
DDR_A_D40: JDIMM1.147 UC1.AY27
DDR_A_D41: JDIMM1.149 UC1.AW27
DDR_A_D42: JDIMM1.157 UC1.AY25
DDR_A_D43: JDIMM1.159 UC1.AW25
DDR_A_D44: JDIMM1.146 UC1.AV27
DDR_A_D45: JDIMM1.148 UC1.AU27
DDR_A_D46: JDIMM1.158 UC1.AV25
DDR_A_D47: JDIMM1.160 UC1.AU25
DDR_A_D48: JDIMM1.163 UC1.AY23
DDR_A_D49: JDIMM1.165 UC1.AW23
DDR_A_D50: JDIMM1.175 UC1.AY21
DDR_A_D51: JDIMM1.177 UC1.AW21
DDR_A_D52: JDIMM1.164 UC1.AV23
DDR_A_D53: JDIMM1.166 UC1.AU23
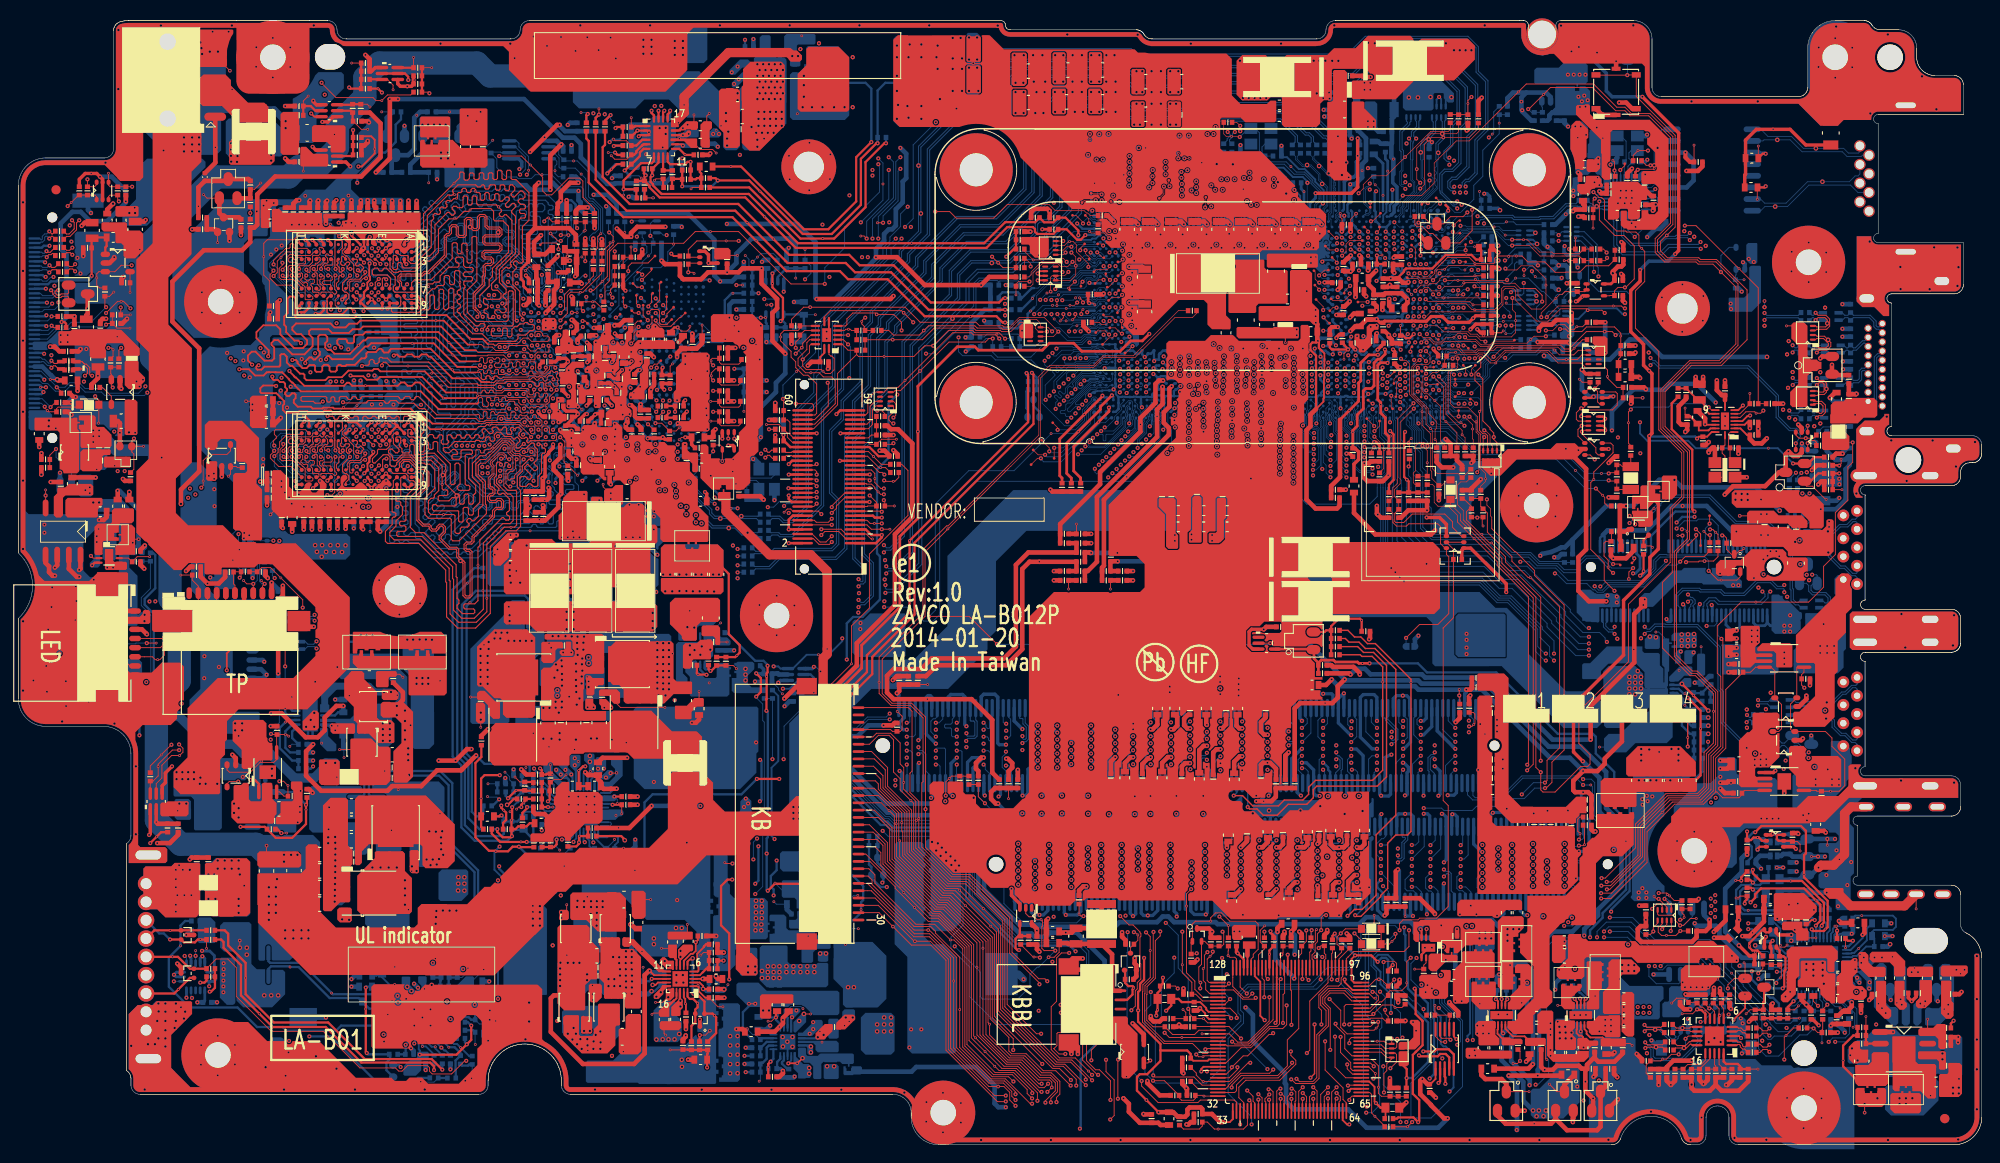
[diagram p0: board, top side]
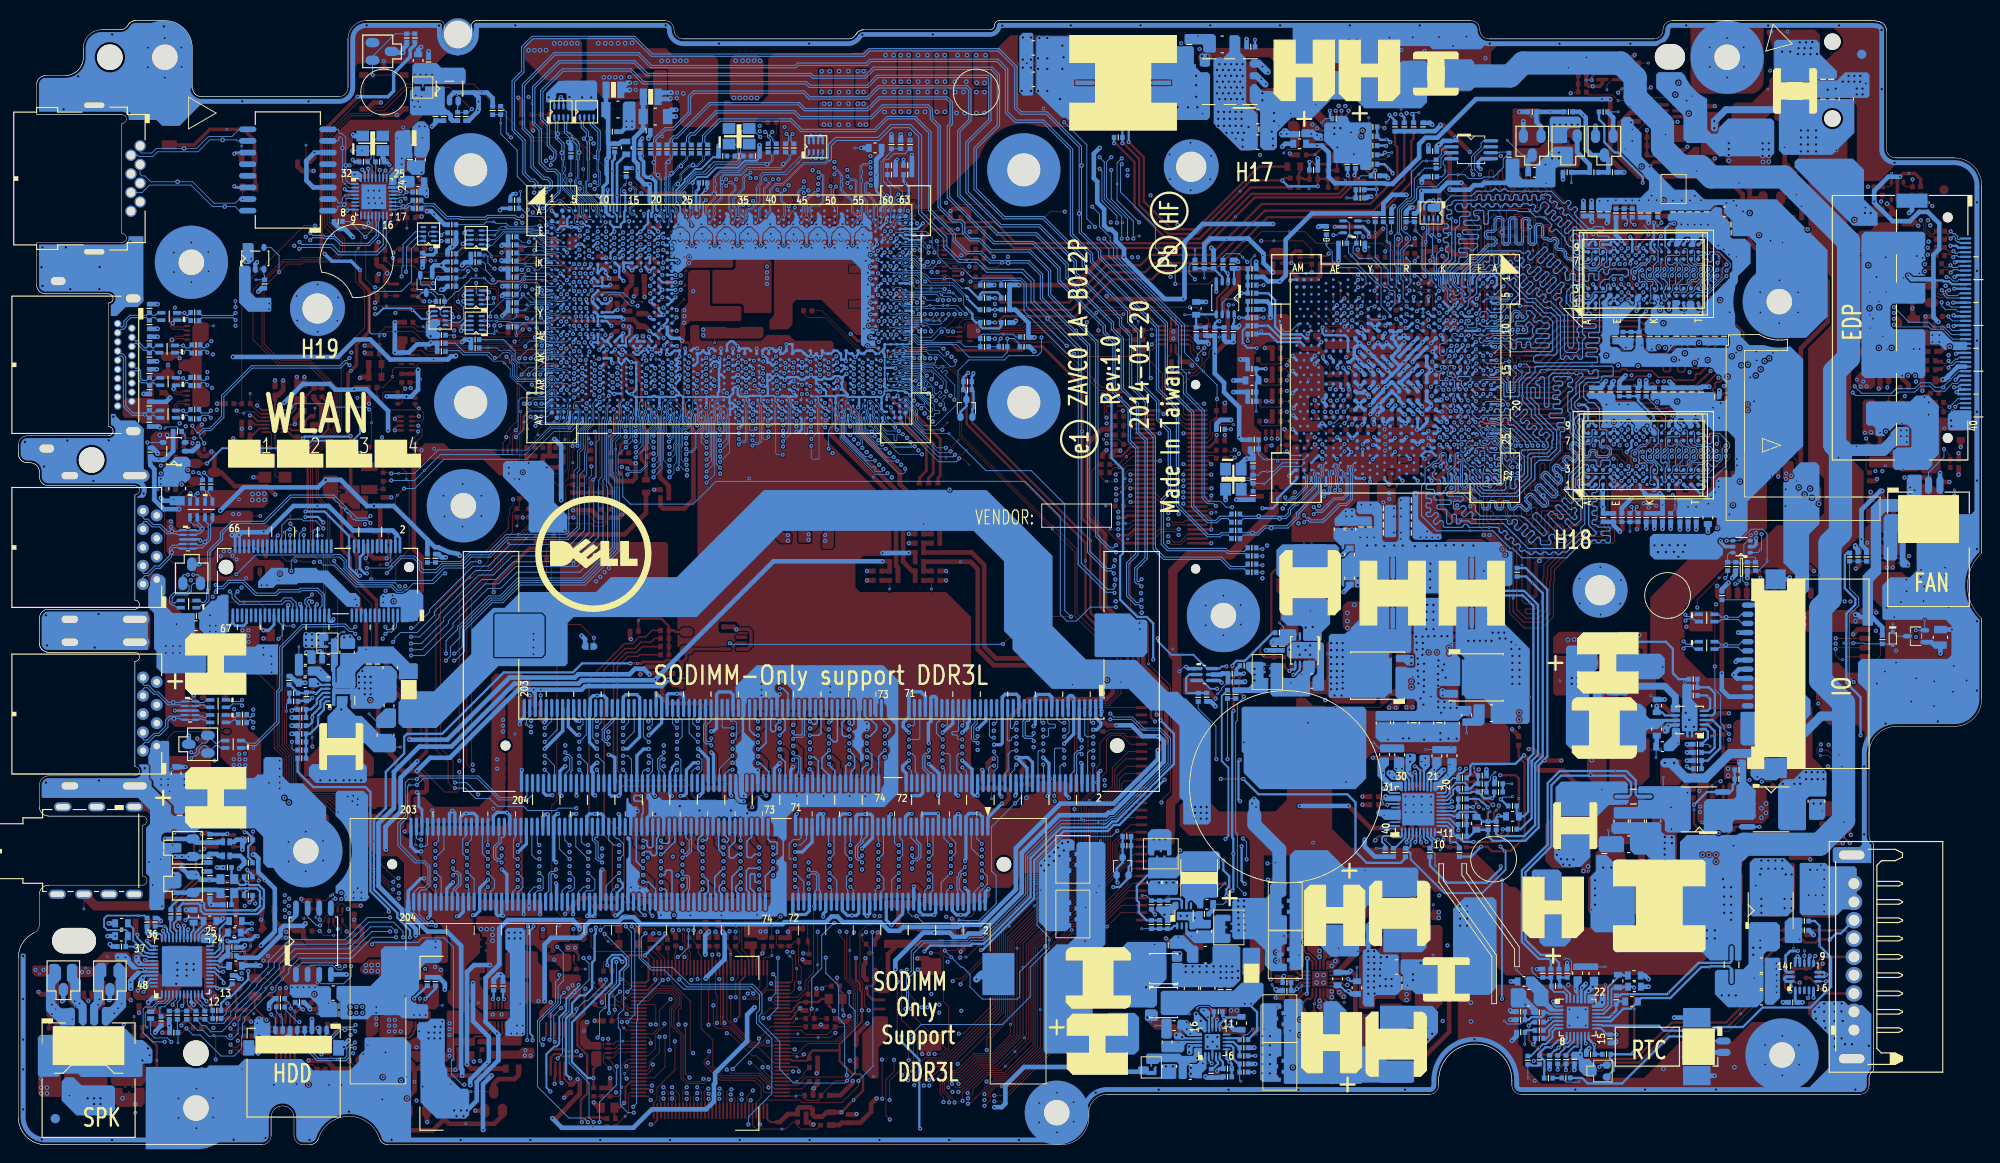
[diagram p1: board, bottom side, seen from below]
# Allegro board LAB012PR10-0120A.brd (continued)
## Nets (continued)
DDR_A_D54: JDIMM1.174 UC1.AV21
DDR_A_D55: JDIMM1.176 UC1.AU21
DDR_A_D56: JDIMM1.181 UC1.AY19
DDR_A_D57: JDIMM1.183 UC1.AW19
DDR_A_D58: JDIMM1.191 UC1.AY17
DDR_A_D59: JDIMM1.193 UC1.AW17
DDR_A_D60: JDIMM1.180 UC1.AV19
DDR_A_D61: JDIMM1.182 UC1.AU19
DDR_A_D62: JDIMM1.192 UC1.AV17
DDR_A_D63: JDIMM1.194 UC1.AU17
DDR_A_DQS0: JDIMM1.12 UC1.AJ62
DDR_A_DQS1: JDIMM1.29 UC1.AN61
DDR_A_DQS2: JDIMM1.47 UC1.AW57
DDR_A_DQS3: JDIMM1.64 UC1.AW53
DDR_A_DQS4: JDIMM1.137 UC1.AV30
DDR_A_DQS5: JDIMM1.154 UC1.AW26
DDR_A_DQS6: JDIMM1.171 UC1.AV22
DDR_A_DQS7: JDIMM1.188 UC1.AW18
DDR_A_DQS#0: JDIMM1.10 UC1.AJ61
DDR_A_DQS#1: JDIMM1.27 UC1.AN62
DDR_A_DQS#2: JDIMM1.45 UC1.AV57
DDR_A_DQS#3: JDIMM1.62 UC1.AV53
DDR_A_DQS#4: JDIMM1.135 UC1.AW30
DDR_A_DQS#5: JDIMM1.152 UC1.AV26
DDR_A_DQS#6: JDIMM1.169 UC1.AW22
DDR_A_DQS#7: JDIMM1.186 UC1.AV18
DDR_A_MA0: JDIMM1.98 UC1.AU36
DDR_A_MA1: JDIMM1.97 UC1.AY37
DDR_A_MA2: JDIMM1.96 UC1.AR38
DDR_A_MA3: JDIMM1.95 UC1.AP36
DDR_A_MA4: JDIMM1.92 UC1.AU39
DDR_A_MA5: JDIMM1.91 UC1.AR36
DDR_A_MA6: JDIMM1.90 UC1.AV40
DDR_A_MA7: JDIMM1.86 UC1.AW39
DDR_A_MA8: JDIMM1.89 UC1.AY39
DDR_A_MA9: JDIMM1.85 UC1.AU40
DDR_A_MA10: JDIMM1.107 UC1.AP35
DDR_A_MA11: JDIMM1.84 UC1.AW41
DDR_A_MA12: JDIMM1.83 UC1.AU41
DDR_A_MA13: JDIMM1.119 UC1.AR35
DDR_A_MA14: JDIMM1.80 UC1.AV42
DDR_A_MA15: JDIMM1.78 UC1.AU42
DDR_A_RAS#: JDIMM1.110 UC1.AY34
DDR_A_WE#: JDIMM1.113 UC1.AW34
DDR_B_BS0: JDIMM2.109 UC1.AL35
DDR_B_BS1: JDIMM2.108 UC1.AM36
DDR_B_BS2: JDIMM2.79 UC1.AU49
DDR_B_CAS#: JDIMM2.115 UC1.AM33
DDR_B_D0: JDIMM2.33 UC1.AP58
DDR_B_D1: JDIMM2.35 UC1.AR58
DDR_B_D2: JDIMM2.23 UC1.AM57
DDR_B_D3: JDIMM2.21 UC1.AK57
DDR_B_D4: JDIMM2.22 UC1.AL58
DDR_B_D5: JDIMM2.24 UC1.AK58
DDR_B_D6: JDIMM2.34 UC1.AR57
DDR_B_D7: JDIMM2.36 UC1.AN57
DDR_B_D8: JDIMM2.41 UC1.AP55
DDR_B_D9: JDIMM2.42 UC1.AR55
DDR_B_D10: JDIMM2.52 UC1.AM54
DDR_B_D11: JDIMM2.50 UC1.AK54
DDR_B_D12: JDIMM2.39 UC1.AL55
DDR_B_D13: JDIMM2.40 UC1.AK55
DDR_B_D14: JDIMM2.51 UC1.AR54
DDR_B_D15: JDIMM2.53 UC1.AN54
DDR_B_D16: JDIMM2.6 UC1.AK40
DDR_B_D17: JDIMM2.7 UC1.AK42
DDR_B_D18: JDIMM2.17 UC1.AM43
DDR_B_D19: JDIMM2.16 UC1.AM45
DDR_B_D20: JDIMM2.18 UC1.AK45
DDR_B_D21: JDIMM2.15 UC1.AK43
DDR_B_D22: JDIMM2.4 UC1.AM40
DDR_B_D23: JDIMM2.5 UC1.AM42
DDR_B_D24: JDIMM2.69 UC1.AM46
DDR_B_D25: JDIMM2.59 UC1.AK46
DDR_B_D26: JDIMM2.58 UC1.AM49
DDR_B_D27: JDIMM2.67 UC1.AK49
DDR_B_D28: JDIMM2.70 UC1.AM48
DDR_B_D29: JDIMM2.68 UC1.AK48
DDR_B_D30: JDIMM2.56 UC1.AM51
DDR_B_D31: JDIMM2.57 UC1.AK51
DDR_B_D32: JDIMM2.129 UC1.AM29
DDR_B_D33: JDIMM2.130 UC1.AK29
DDR_B_D34: JDIMM2.132 UC1.AL28
DDR_B_D35: JDIMM2.131 UC1.AK28
DDR_B_D36: JDIMM2.141 UC1.AR29
DDR_B_D37: JDIMM2.142 UC1.AN29
DDR_B_D38: JDIMM2.143 UC1.AR28
DDR_B_D39: JDIMM2.140 UC1.AP28
DDR_B_D40: JDIMM2.147 UC1.AN26
DDR_B_D41: JDIMM2.148 UC1.AR26
DDR_B_D42: JDIMM2.159 UC1.AR25
DDR_B_D43: JDIMM2.157 UC1.AP25
DDR_B_D44: JDIMM2.146 UC1.AK26
DDR_B_D45: JDIMM2.149 UC1.AM26
DDR_B_D46: JDIMM2.160 UC1.AK25
DDR_B_D47: JDIMM2.158 UC1.AL25
DDR_B_D48: JDIMM2.174 UC1.AR21
DDR_B_D49: JDIMM2.165 UC1.AR22
DDR_B_D50: JDIMM2.175 UC1.AL21
DDR_B_D51: JDIMM2.164 UC1.AM22
DDR_B_D52: JDIMM2.163 UC1.AN22
DDR_B_D53: JDIMM2.177 UC1.AP21
DDR_B_D54: JDIMM2.176 UC1.AK21
DDR_B_D55: JDIMM2.166 UC1.AK22
DDR_B_D56: JDIMM2.180 UC1.AN20
DDR_B_D57: JDIMM2.182 UC1.AR20
DDR_B_D58: JDIMM2.191 UC1.AK18
DDR_B_D59: JDIMM2.193 UC1.AL18
DDR_B_D60: JDIMM2.192 UC1.AK20
DDR_B_D61: JDIMM2.194 UC1.AM20
DDR_B_D62: JDIMM2.183 UC1.AR18
DDR_B_D63: JDIMM2.181 UC1.AP18
DDR_B_DQS0: JDIMM2.29 UC1.AN58
DDR_B_DQS1: JDIMM2.47 UC1.AN55
DDR_B_DQS2: JDIMM2.12 UC1.AL42
DDR_B_DQS3: JDIMM2.64 UC1.AL49
DDR_B_DQS4: JDIMM2.137 UC1.AM28
DDR_B_DQS5: JDIMM2.154 UC1.AM25
DDR_B_DQS6: JDIMM2.171 UC1.AM21
DDR_B_DQS7: JDIMM2.188 UC1.AM18
DDR_B_DQS#0: JDIMM2.27 UC1.AM58
DDR_B_DQS#1: JDIMM2.45 UC1.AM55
DDR_B_DQS#2: JDIMM2.10 UC1.AL43
DDR_B_DQS#3: JDIMM2.62 UC1.AL48
DDR_B_DQS#4: JDIMM2.135 UC1.AN28
DDR_B_DQS#5: JDIMM2.152 UC1.AN25
DDR_B_DQS#6: JDIMM2.169 UC1.AN21
DDR_B_DQS#7: JDIMM2.186 UC1.AN18
DDR_B_MA0: JDIMM2.98 UC1.AP40
DDR_B_MA1: JDIMM2.97 UC1.AR40
DDR_B_MA2: JDIMM2.96 UC1.AP42
DDR_B_MA3: JDIMM2.95 UC1.AR42
DDR_B_MA4: JDIMM2.92 UC1.AR45
DDR_B_MA5: JDIMM2.91 UC1.AP45
DDR_B_MA6: JDIMM2.90 UC1.AW46
DDR_B_MA7: JDIMM2.86 UC1.AY46
DDR_B_MA8: JDIMM2.89 UC1.AY47
DDR_B_MA9: JDIMM2.85 UC1.AU46
DDR_B_MA10: JDIMM2.107 UC1.AK36
DDR_B_MA11: JDIMM2.84 UC1.AV47
DDR_B_MA12: JDIMM2.83 UC1.AU47
DDR_B_MA13: JDIMM2.119 UC1.AK33
DDR_B_MA14: JDIMM2.80 UC1.AR46
DDR_B_MA15: JDIMM2.78 UC1.AP46
DDR_B_RAS#: JDIMM2.110 UC1.AM35
DDR_B_WE#: JDIMM2.113 UC1.AK35
DDR_CKE0_DIMMA: JDIMM1.73 UC1.AU43
DDR_CKE1_DIMMA: JDIMM1.74 UC1.AW43
DDR_CKE2_DIMMB: JDIMM2.73 UC1.AY49
DDR_CKE3_DIMMB: JDIMM2.74 UC1.AU50
DDR_CS0_DIMMA#: JDIMM1.114 UC1.AP33
DDR_CS1_DIMMA#: JDIMM1.121 UC1.AR32
DDR_CS2_DIMMB#: JDIMM2.114 UC1.AM32
DDR_CS3_DIMMB#: JDIMM2.121 UC1.AK32
DDR_PG_CTRL: U2303.2 UC1.AV61
DDR_XDP_SMBCLK_R1: JXDP1.53 RP46.7
DDR_XDP_SMBDAT_R1: JXDP1.51 RP46.8
DDR_XDP_WLAN_TP_SMBCLK: JDIMM1.202 JDIMM2.202 QC1.1 R2332.2 RP46.2 US3.4
DDR_XDP_WLAN_TP_SMBDAT: JDIMM1.200 JDIMM2.200 QC1.4 R2331.2 RP46.1 US3.6
DEVSLP0: RC11.1 RS8.1 UC1.P2
DEW1: RS34.1 RS36.1 US2.16
DEW2: RS33.1 RS35.1 US2.6
DGPU_HOLD_RST#: RC77.2 UC1.N4 UV2.1
DGPU_PRSNT#: RC99.1 RC100.2 UC1.R7
DGPU_PWR_EN#: QV3.1 RV22.2 RV23.1 RV26.2
DGPU_PWROK: PR1030.2 PU1000.9 PU1000.20 RC73.2 UC1.U6 UE1.18
DH_1.35V: PR209.2 PU200.17
DH_CHG: PQ703.4 PU701.24
DIR: CV167.2 CV169.2 RV79.1 U1.5
DISPOFF#: DX1.1 JEDP.37 RX9.1
DL_1.35V: PQ201.4 PU200.15
DL_CHG: PQ705.4 PU701.21
DP_VSSR: UV1.AF19 UV1.AF20 UV1.AF23 UV1.AG14 UV1.AG23 UV1.AH14 UV1.AM14 UV1.AM16 UV1.AM18 UV1.AM20 UV1.AM22 UV1.AM24
DPB_HPD: QX5.3 RX14.1 UC1.C8
DPC_HPD: RC84.2 UC1.A8
DRAM_RST: CV97.1 RV37.1 RV38.1 UV1.L10
DRAM_RST#: RV36.1 UV5.T2 UV6.T2 UV7.T2 UV8.T2
DSWODVREN: R2337.1 R2338.1 UC1.AW7
EC_ENVDD: RX8.2 UE1.71
EC_LID_OUT#: RE73.2 UC1.AD6 UE1.101
EC_MUTE#: UA1.47 UE1.83
EC_ON: PR102.1 UE1.112
EC_RSMRST#: DE3.2 RC41.1 RE2.2 UE1.100
EC_RST#: CE11.1 RE8.1 UE1.37
EC_RX: JNGFF.32 UE1.31
EC_SCI#: UC1.AM2 UE1.20
EC_SMB_CK1: PR18.2 PR714.1 RP36.4 UE1.77
EC_SMB_CK2: QH1.6 QV1.6 RP36.2 U2407.10 UE1.79
EC_SMB_DA1: PR20.2 PR715.1 RP36.3 UE1.78
EC_SMB_DA2: QH1.3 QV1.3 RP36.1 U2407.9 UE1.80
EC_SMI#: RC107.1 UC1.V1 UE1.15
EC_SPOK: DE3.1 DE4.1 PR115.1 PU100.7
EC_TP_INT#: RE338.1 RE340.1 UE1.119
EC_TX: JNGFF.30 RM9.1 UE1.30
ECAGND: CE7.2 CE9.1 LE2.2 PH1.2 UE1.69
EDP_AUX: C4321.2 UC1.B45
EDP_AUX#: C4322.2 UC1.A45
EDP_AUX#_C: C4322.1 JEDP.8
EDP_AUX_C: C4321.1 JEDP.7
EDP_BIA_PWM: JEDP.36 RC72.2 RC75.2 RC81.2 RX26.1
EDP_BKLCTL: RC81.1 UC1.B8
EDP_COMP: RC71.2 UC1.D20
EDP_CPU_HPD: JEDP.10 RC82.1
EDP_DISP_UTIL: RC72.1 UC1.A43
EDP_TX0: C4312.2 UC1.B46
EDP_TX0#: C4311.2 UC1.C45
EDP_TX0#_C: C4311.1 JEDP.2
EDP_TX0_C: C4312.1 JEDP.1
EDP_TX1: C4314.2 UC1.B47
EDP_TX1#: C4313.2 UC1.A47
EDP_TX1#_C: C4313.1 JEDP.5
EDP_TX1_C: C4314.1 JEDP.4
EN_0.675VSP: PC203.1 PR202.2 PU200.7
EN_1.35V: PC202.1 PR201.2 PU200.8
EN_+1.35VGPUP: PC1104.1 PR1103.2 PU1100.3
EN_DFAN1: UE1.70 UE3.4
EN_INVPWR: QX1.2 RX41.1 UE1.68
EN_PCIE: PC1307.1 PR1300.2 PR1304.1 PU1300.5
ENABLE: PR1027.2 PU1000.8
ENVDD_PCH: RC87.2 RX7.2 UC1.C6
ENVDD_R: RX7.1 RX8.1 UX1.3 UX4.4
ERP_LOT6: PC5.1 PQ1.2 PR1.2 PR2.1 UE1.73
FAN_SPEED1: CE24.1 CE29.1 JFAN.2 RE50.2 UE1.28
FB_1.8VSP: PC604.2 PR602.1 PR603.2 PU600.1
FB_1.35V: PC214.1 PR204.1 PR207.1 PU200.6
FB_3V: PC102.2 PR107.2 PR109.2 PU100.4
FB_5V: PC108.1 PR104.1 PR106.1 PU100.2
FB_+1.35VGPUP: PR1107.1 PR1108.1 PU1100.4
FB_GND: RV158.1 UV1.AD20
FB_PCIE: PC1306.2 PR1301.1 PR1302.2 PU1300.6
FB_VDDC: RV159.1 UV1.AC20
FB_VDDCI: T222.1(TP-1) UV1.W1
FFS_INT1: RC79.2 UC1.N2 US3.11
FFS_INT2: QS1.3 RC115.2 UC1.G2 US3.9
FFS_INT2_CONN: DS1.2 JHDD.8 RS32.2
GCLK_VRTC: CG5.1 RG1.2 RG4.2 UG1.10
GPIO19_CTF: RV151.2 RV152.1 UV1.M2
GPIO27: RC38.2 RC105.1 UC1.AN5
GPIO28: RV21.2 UV1.R5
GPU_B+: PC1023.1 PC1024.1 PC1025.1 PC1041.1 PC1042.1 PC1045.1 PC1046.1 PC1047.1 PC1048.1 PC1049.1 PC1052.1 PL1000.1 PL1004.1 PQ1003.5 PQ1005.5
GPU_VID1: RV76.1 UV1.P8
GPU_VID1_GPIO_20: RV72.1 RV74.2 RV76.2 U1.3
GPU_VID3: RV75.1 UV1.N1
GPU_VID3_GPIO_15: RV71.1 RV73.2 RV75.2 U1.2
H_CATERR#: RC58.2 UC1.K61
H_CPU_SVIDALRT#: R254.1 UC1.L62
H_CPU_SVIDCLK: C5212.1 R248.2 UC1.N63
H_CPU_SVIDDATA: R256.2 R257.1 UC1.L63
H_CPUPWRGD: CC27.1 RC48.1 RC66.1 UC1.C61
H_PROCHOT#: CC42.1 CE19.1 PQ2.6 PQ3.3 PQ3.6 RC60.2 RC67.1 RE44.2 UE2.4
H_PROCHOT#_R: RC67.2 UC1.K63
H_THERMTRIP#: R2346.2 UC1.D60
H_VCCST_PWRGD_XDP: JXDP1.39 RC48.2
H_VR_READY: PR519.2 PU501.2 R251.1
HDA_SPKR: DA8.3 RC121.2 UC1.V2
HDD_A0_PRE0: RS24.1 RS27.2 US2.9
HDD_A0_PRE1: RS23.1 RS30.2 US2.19
HDD_B0_EQ: RS37.1 RS38.1 US2.13
HDD_B0_PRE0: RS21.1 RS28.2 US2.8
HDD_B0_PRE1: RS18.1 RS29.2 US2.17
HDD_REXT_SATA0: RS26.2 RS31.1 US2.20
HDMI_HPLUG: CX20.1 JHDMI.19 RX15.2 RX34.1
HOST_ALERT1_R_N: RC120.2 UC1.AD7
HPOUT-L: RA55.1 UA1.32
HPOUT-R: RA56.1 UA1.33
I2C0_SCL: RP53.4 UC1.F3
I2C0_SDA: RP53.3 UC1.F2
I2C1_SCL: RC364.2 RC366.2 RP53.2 UC1.F1
I2C1_SCL_PNL: QX6.3 RC364.1 RX38.1
I2C1_SCL_PNL_R: JEDP.17 QX6.4 RX38.2 RX39.2
I2C1_SCL_TP: QE6.4 RC366.1 RE337.1
I2C1_SCL_TP_R: JTP.6 JTP1.8 QE6.3 RE334.2 RE337.2
I2C1_SDA: RC363.2 RC365.2 RP53.1 UC1.G4
I2C1_SDA_PNL: QX6.6 RC363.1 RX37.1
I2C1_SDA_PNL_R: JEDP.16 QX6.1 RX37.2 RX40.2
I2C1_SDA_TP: QE6.1 RC365.1 RE336.1
I2C1_SDA_TP_R: JTP.7 JTP1.9 QE6.6 RE335.2 RE336.2
ICOMP: PR728.2 PU701.5
ILMT_1.05V: PR304.2 PR306.1 PU300.3
IMON: PC500.2 PR521.1 PU501.3
IMON_GPU: PC1022.2 PR1029.2 PU1000.10
INT-SPK-L+: LA6.1 UA1.42
INT-SPK-L-: LA5.1 UA1.43
INT-SPK-R+: LA4.1 UA1.45
INT-SPK-R-: LA3.1 UA1.44
INTRUDER#: RC7.2 UC1.AU6
ISEN1: PC1051.2 PR1058.1 PU1000.13
ISEN2: PC1050.2 PR1059.1 PU1000.12
ISOLATEB: RL33.2 RL35.2 UL1.20
ISUMN: PC529.1 PC530.1 PH501.1 PL502.3 PR535.2 PR545.1 PR549.1
ISUMP: PC529.2 PC530.2 PR536.1 PR549.2 PR551.2 PR558.1 PU501.10
JACK_PLUG#: JHP.5 RA1.2 RA3.1 RA4.1
JACK_SENSE#: QA5.3 RA4.2 RA13.1 UA1.13
JHDD_P10: JHDD.7 RS8.2
JTAG_TCK: RP34.5 UV1.L3
JTAG_TDI: RP34.7 UV1.L5
JTAG_TDO: T86.1(TP-1) UV1.K4
JTAG_TMS: RP34.6 UV1.L1
JTAG_TRSTB: RP34.8 UV1.L6
KB_BL_PWM: JKBBL.4 QE5.1 QE5.2 QE5.5 QE5.6
KB_CAPS_PWR: JKB.4 RE60.2
KB_DET#: QE4.1 RC103.1 RE68.1 UC1.AN3
KB_LED_PWM: QE5.3 UE1.21
KB_RST#: RC109.2 UC1.V4 UE1.2
KSI0: JKB.22 UE1.55
KSI1: JKB.24 UE1.56
KSI2: JKB.26 UE1.57
KSI3: JKB.23 UE1.58
KSI4: JKB.27 UE1.59
KSI5: JKB.25 UE1.60
KSI6: JKB.28 UE1.61
KSI7: JKB.29 UE1.62
KSO0: JKB.13 UE1.39
KSO1: JKB.15 UE1.40
KSO2: JKB.14 UE1.41
KSO3: JKB.16 UE1.42
KSO4: JKB.20 UE1.43
KSO5: JKB.21 UE1.44
KSO6: JKB.18 UE1.45
KSO7: JKB.19 UE1.46
KSO8: JKB.17 UE1.47
KSO9: JKB.7 UE1.48
KSO10: JKB.5 UE1.49
KSO11: JKB.6 UE1.50
KSO12: JKB.12 UE1.51
KSO13: JKB.9 UE1.52
KSO14: JKB.8 UE1.53
KSO15: JKB.10 UE1.54
KSO16: JKB.11 UE1.81
LAN_CLKREQ#: RL37.1 RP42.8 UC1.AD1 UL1.12
LAN_X1_R: RG5.1 UG1.6
LCD_CBL_DET#: RC106.2 UC1.J3
LCD_TEST: JEDP.33 UE1.72
LG_3V: PQ102.4 PU100.11
LG_5V: PQ104.4 PU100.15
LG_+1.35VGPUP: PQ1101.4 PU1100.6
LGATE: PQ501.4 PU501.16
LGATE1: PR1061.1 PU1000.24
LGATE2: PR1063.1 PU1000.27
LID_SW#: CE30.1 JLED.4 RE71.2 UE1.115
LINE1-L: CA67.1 UA1.22
LINE1-R: CA68.1 UA1.21
LINE1-VREFO-L: RA165.1 UA1.31
LINE1-VREFO-R: RA166.1 UA1.30
LINE-IN-L: LA8.2 RA55.2 RA80.2 RA83.1 RA165.2
LINE-IN-R: LA9.2 RA56.2 RA82.2 RA84.1 RA166.2
LPC_LAD0: UC1.AU14 UE1.10
LPC_LAD1: UC1.AW12 UE1.8
LPC_LAD2: UC1.AY12 UE1.7
LPC_LAD3: UC1.AW11 UE1.5
LPC_LFRAME#: UC1.AV12 UE1.4
LX_1.05V: PC302.2 PL301.1 PR302.1 PU300.10
LX_1.8VSP: PL600.1 PR605.1 PU600.6
LX_3V: PC104.1 PL100.1 PQ101.1 PQ101.2 PQ101.3 PQ102.5 PR113.1 PU100.8
LX_5V: PC110.2 PL101.1 PQ103.1 PQ103.2 PQ103.3 PQ104.5 PR112.1 PU100.18
LX_CHG: PC715.1 PC721.2 PL701.1 PQ703.1 PQ703.2 PQ703.3 PQ705.5 PU701.23
LX_PCIE: PL1300.1 PR1303.1 PU1300.1 PU1300.2 PU1300.3
M_BA0: UV1.J16 UV5.M2 UV6.M2 UV7.M2 UV8.M2
M_BA1: UV1.L15 UV5.N8 UV6.N8 UV7.N8 UV8.N8
M_BA2: UV1.G11 UV5.M3 UV6.M3 UV7.M3 UV8.M3
M_CAS#0: UV1.G19 UV5.K3 UV6.K3
M_CAS#1: UV1.G16 UV7.K3 UV8.K3
M_CKE0: UV1.K20 UV5.K9 UV6.K9
M_CKE1: UV1.J17 UV7.K9 UV8.K9
M_CLK0: RV48.1 UV1.H26 UV5.J7 UV6.J7
M_CLK1: RV54.1 UV1.G9 UV7.J7 UV8.J7
M_CLK#0: RV49.1 UV1.H25 UV5.K7 UV6.K7
M_CLK#1: RV55.1 UV1.H9 UV7.K7 UV8.K7
M_CLK_DDR0: JDIMM1.101 UC1.AV37
M_CLK_DDR1: JDIMM1.102 UC1.AY36
M_CLK_DDR2: JDIMM2.101 UC1.AN38
M_CLK_DDR3: JDIMM2.102 UC1.AL38
M_CLK_DDR#0: JDIMM1.103 UC1.AU37
M_CLK_DDR#1: JDIMM1.104 UC1.AW36
M_CLK_DDR#2: JDIMM2.103 UC1.AM38
M_CLK_DDR#3: JDIMM2.104 UC1.AK38
M_CS#0: UV1.H22 UV5.L2 UV6.L2
M_CS#1: UV1.G13 UV7.L2 UV8.L2
M_DA0: UV1.K27 UV5.A2
M_DA1: UV1.J29 UV5.C2
M_DA2: UV1.H30 UV5.A3
M_DA3: UV1.H32 UV5.C3
M_DA4: UV1.G29 UV5.C8
M_DA5: UV1.F28 UV5.D7
M_DA6: UV1.F32 UV5.A7
M_DA7: UV1.F30 UV5.B8
M_DA8: UV1.C30 UV6.D7
M_DA9: UV1.F27 UV6.C8
M_DA10: UV1.A28 UV6.A7
M_DA11: UV1.C28 UV6.B8
M_DA12: UV1.E27 UV6.C2
M_DA13: UV1.G26 UV6.A3
M_DA14: UV1.D26 UV6.C3
M_DA15: UV1.F25 UV6.A2
M_DA16: UV1.A25 UV5.G2
M_DA17: UV1.C25 UV5.E3
M_DA18: UV1.E25 UV5.H3
M_DA19: UV1.D24 UV5.H8
M_DA20: UV1.E23 UV5.H7
M_DA21: UV1.F23 UV5.F2
M_DA22: UV1.D22 UV5.F8
M_DA23: UV1.F21 UV5.F7
M_DA24: UV1.E21 UV6.F8
M_DA25: UV1.D20 UV6.H7
M_DA26: UV1.F19 UV6.H8
M_DA27: UV1.A19 UV6.F7
M_DA28: UV1.D18 UV6.G2
M_DA29: UV1.F17 UV6.H3
M_DA30: UV1.A17 UV6.E3
M_DA31: UV1.C17 UV6.F2
M_DA32: UV1.E17 UV7.H8
M_DA33: UV1.D16 UV7.H7
M_DA34: UV1.F15 UV7.G2
M_DA35: UV1.A15 UV7.F8
M_DA36: UV1.D14 UV7.F7
M_DA37: UV1.F13 UV7.F2
M_DA38: UV1.A13 UV7.E3
M_DA39: UV1.C13 UV7.H3
M_DA40: UV1.E11 UV7.B8
M_DA41: UV1.A11 UV7.D7
M_DA42: UV1.C11 UV7.A7
M_DA43: UV1.F11 UV7.C8
M_DA44: UV1.A9 UV7.C3
M_DA45: UV1.C9 UV7.C2
M_DA46: UV1.F9 UV7.A2
M_DA47: UV1.D8 UV7.A3
M_DA48: UV1.E7 UV8.G2
M_DA49: UV1.A7 UV8.E3
M_DA50: UV1.C7 UV8.H3
M_DA51: UV1.F7 UV8.F2
M_DA52: UV1.A5 UV8.H7
M_DA53: UV1.E5 UV8.F7
M_DA54: UV1.C3 UV8.F8
M_DA55: UV1.E1 UV8.H8
M_DA56: UV1.G7 UV8.C2
M_DA57: UV1.G6 UV8.A2
M_DA58: UV1.G1 UV8.A3
M_DA59: UV1.G3 UV8.C3
M_DA60: UV1.J6 UV8.D7
M_DA61: UV1.J1 UV8.B8
M_DA62: UV1.J3 UV8.A7
M_DA63: UV1.J5 UV8.C8
M_DQM0: UV1.E32 UV5.D3
M_DQM1: UV1.E30 UV6.D3
M_DQM2: UV1.A21 UV5.E7
M_DQM3: UV1.C21 UV6.E7
M_DQM4: UV1.E13 UV7.E7
M_DQM5: UV1.D12 UV7.D3
M_DQM6: UV1.E3 UV8.E7
M_DQM7: UV1.F4 UV8.D3
M_DQS0: UV1.H28 UV5.C7
M_DQS1: UV1.C27 UV6.C7
M_DQS2: UV1.A23 UV5.F3
M_DQS3: UV1.E19 UV6.F3
M_DQS4: UV1.E15 UV7.F3
M_DQS5: UV1.D10 UV7.C7
M_DQS6: UV1.D6 UV8.F3
M_DQS7: UV1.G5 UV8.C7
M_DQS#0: UV1.H27 UV5.B7
M_DQS#1: UV1.A27 UV6.B7
M_DQS#2: UV1.C23 UV5.G3
M_DQS#3: UV1.C19 UV6.G3
M_DQS#4: UV1.C15 UV7.G3
M_DQS#5: UV1.E9 UV7.B7
M_DQS#6: UV1.C5 UV8.G3
M_DQS#7: UV1.H4 UV8.B7
M_MA0: UV1.K17 UV5.N3 UV6.N3 UV7.N3 UV8.N3
M_MA1: UV1.J20 UV5.P7 UV6.P7 UV7.P7 UV8.P7
M_MA2: UV1.H23 UV5.P3 UV6.P3 UV7.P3 UV8.P3
M_MA3: UV1.G23 UV5.N2 UV6.N2 UV7.N2 UV8.N2
M_MA4: UV1.G24 UV5.P8 UV6.P8 UV7.P8 UV8.P8
M_MA5: UV1.H24 UV5.P2 UV6.P2 UV7.P2 UV8.P2
M_MA6: UV1.J19 UV5.R8 UV6.R8 UV7.R8 UV8.R8
M_MA7: UV1.K19 UV5.R2 UV6.R2 UV7.R2 UV8.R2
M_MA8: UV1.J14 UV5.T8 UV6.T8 UV7.T8 UV8.T8
M_MA9: UV1.K14 UV5.R3 UV6.R3 UV7.R3 UV8.R3
M_MA10: UV1.J11 UV5.L7 UV6.L7 UV7.L7 UV8.L7
M_MA11: UV1.J13 UV5.R7 UV6.R7 UV7.R7 UV8.R7
M_MA12: UV1.H11 UV5.N7 UV6.N7 UV7.N7 UV8.N7
M_MA13: UV1.G20 UV5.T3 UV6.T3 UV7.T3 UV8.T3
M_MA14: UV1.G14 UV5.T7 UV6.T7 UV7.T7 UV8.T7
M_MA15: UV1.L17 UV5.M7 UV6.M7 UV7.M7 UV8.M7
M_ODT: CD64.1 QD2.3 R2348.1 R2349.1 R2350.1 R2352.1
M_ODT0: JDIMM1.116 R2348.2
M_ODT1: JDIMM1.120 R2349.2
M_ODT2: JDIMM2.116 R2350.2
M_ODT3: JDIMM2.120 R2352.2
M_RAS#0: UV1.G22 UV5.J3 UV6.J3
M_RAS#1: UV1.G17 UV7.J3 UV8.J3
M_WE#0: UV1.G25 UV5.L3 UV6.L3
M_WE#1: UV1.H10 UV7.L3 UV8.L3
MAINPWON: R2450.2
MCT0: RL19.1 TL2.14
MCT1: RL20.1 TL2.11
MDI0+: TL2.8 UL1.1
MDI0-: TL2.7 UL1.2
MDI1+: TL2.2 UL1.4
MDI1-: TL2.1 UL1.5
MDO0+: JLAN.1 TL2.9
MDO0-: JLAN.2 TL2.10
MDO1+: JLAN.3 TL2.15
MDO1-: JLAN.6 TL2.16
ME_EN: RC8.1 RE326.1 UE1.99
ME_SUS_PWR_ACK: RC27.2 RC42.1 UE1.34
ME_SUS_PWR_ACK_R: RC35.1 RC42.2 UC1.AV4
MEM_SMBCLK: QC1.6 RP40.1 UC1.AP2
MEM_SMBDATA: QC1.3 RP40.2 UC1.AH1
MIC1-L: CA74.1 UA1.19
MIC_CLK: CA22.1 JEDP.30 LA1.2
MIC_CLK_C: LA1.1 UA1.3
MIC_DATA: JEDP.32 UA1.2
MIC_IN: LA7.2 QA6.3 RA53.1 UA1.18
MIC_IN_R: CA38.1 DA12.3 JHP.4 LA7.1
NTC: PR525.2 PU501.5
OCP_L: PR1020.2 PU1000.4 RV90.2 RV91.1
ODD_DA#: RP54.1 UC1.T3
ODD_DETECT#: RP37.1 UC1.V6
ON/OFFBTN#: CE20.1 DE2.3 RE49.1 SW1.3 SW1.4 UE1.114
PACIN#: QV8.5 QV8.6 RV147.2
PANEL_BKLEN: UC1.A9 UE1.76
PBTN_OUT#: RC49.1 UC1.AL7 UE1.106
PC_BEEP: DA8.1 RA19.1 RA79.2
PCC_GPIO_6: CVT90.2 RV90.1 UV1.T8
PCH_AUDIO_EN: RC116.1 UC1.P1
PCH_AZ_BITCLK: R2359.2 UC1.AW8
PCH_AZ_CODEC_BITCLK: CC5.1 R2359.1 RA1112.1 UA1.6
PCH_AZ_CODEC_RST#: R2358.1 RA6.1 UA1.11
PCH_AZ_CODEC_SDIN0: RA130.1 UC1.AY10
PCH_AZ_CODEC_SDOUT: R2356.1 UA1.5
PCH_AZ_CODEC_SYNC: R2357.1 UA1.10
PCH_AZ_RST#: R2358.2 UC1.AU8
PCH_AZ_SDOUT: R2356.2 RC3.2 RC8.2 UC1.AU11
PCH_AZ_SYNC: R2357.2 UC1.AV11
PCH_BATLOW#: RC31.2 UC1.AN4
PCH_DPWROK: RC33.1 RE37.1 UC1.AV5
PCH_DSW_EN: U2408.3 UE1.1
PCH_GPIO9: RC125.2 UC1.AM3
PCH_GPIO12: T182.1(TP-1) UC1.AM7
PCH_GPIO14: T126.1(TP-1) UC1.AH4
PCH_GPIO25: T127.1(TP-1) UC1.AM4
PCH_GPIO35: RP37.2 UC1.U1
PCH_GPIO37: RP37.3 UC1.AC1
PCH_GPIO44: RC104.1 UC1.AK4
PCH_GPIO46: RC124.2 UC1.AG3
PCH_GPIO47: T174.1(TP-1) UC1.AB6
PCH_GPIO48: T124.1(TP-1) UC1.U4
PCH_GPIO49: T125.1(TP-1) UC1.Y3
PCH_GPIO56: RC9.1 UC1.AG6
PCH_GPIO66: RC118.2 RC122.1 UC1.D3
PCH_GPIO83: T177.1(TP-1) UC1.R6
PCH_GPIO84: T176.1(TP-1) UC1.L6
PCH_GPIO85: T175.1(TP-1) UC1.N6
PCH_GPIO89: T178.1(TP-1) UC1.N7
PCH_GPIO90: T179.1(TP-1) UC1.K2
PCH_GPIO93: T180.1(TP-1) UC1.J2
PCH_GPIO94: T181.1(TP-1) UC1.G1
PCH_HOT#: R2330.2 UC1.AU4
PCH_INTVRMEN: RC1.2 RC2.1 UC1.AV7
PCH_JTAG_JTAGX: RC59.1 RC62.2 RC130.1 UC1.AE63
PCH_JTAG_RST#: R2341.2 RC57.2 UC1.AU62
PCH_JTAG_TCK: RC65.2 RC135.1 RP46.4 UC1.AE62
PCH_JTAG_TDI: RC44.1 RP48.8 UC1.AD61
PCH_JTAG_TDO: RC43.1 RC63.2 RP48.7 UC1.AE61
PCH_JTAG_TMS: RC46.1 RP48.6 UC1.AD62
PCH_OPI_COMP: RC101.1 UC1.AW15
PCH_PCIE_RCOMP: RC91.2 UC1.A27
PCH_PLTRST#: CC33.1 UC1.AG7 UC3.1 UC3.2
PCH_PWR_EN: R416.1 RE36.1
PCH_PWROK: CC34.1 CE31.1 DE4.2 RE18.1 RP50.2 RP50.3 UE1.32
PCH_PWROK_R: RP50.7 UC1.AY7
PCH_RSMRST#_R: RC33.2 RC41.2 UC1.AW6
PCH_RTCRST#: CC4.2 CMOS1.2 QC2.6 RC6.2 UC1.AU7
PCH_RTCX1: CC1.2 RC4.1 RG3.2 UC1.AW5 YC1.1
PCH_RTCX1_R: RG3.1 UG1.9
PCH_RTCX2: CC2.2 RC4.2 UC1.AY5 YC1.2
PCH_SLP_WLAN#: RC39.2 UC1.AM5
PCH_SMB_ALERT#: R2329.2 UC1.AN2
PCH_SPI_CLK: R2333.2 UC1.AA3
PCH_SPI_CLK_R: C2326.1 R2333.1 U2302.6
PCH_SPI_CS0#: U2302.1 UC1.Y7
PCH_SPI_HOLD1#: RP39.4 U2302.7
PCH_SPI_HOLD#: R2335.2 RP39.5 UC1.AF1
PCH_SPI_MISO: RP39.7 UC1.AA4
PCH_SPI_MISO_1: RP39.2 U2302.2
PCH_SPI_MOSI: RP39.8 UC1.AA2
PCH_SPI_MOSI_1: RP39.1 U2302.5
PCH_SPI_WP1#: RP39.3 U2302.3
PCH_SPI_WP#: R2334.2 RP39.6 UC1.Y6
PCH_TP_INT#: QC3.3 RC74.2 RC367.2 UC1.U7
PCH_X1_R: RG6.1 UG1.5
PCIE_B+: PC1301.1 PJP1301.1 PU1300.8 PU1300.9 PU1300.10
PCIE_CRX_C_GTX_N0: CV2.2 UV1.AG31
PCIE_CRX_C_GTX_N1: CV4.2 UV1.AF28
PCIE_CRX_C_GTX_N2: CV6.2 UV1.AF26
PCIE_CRX_C_GTX_N3: CV8.2 UV1.AD26
PCIE_CRX_C_GTX_P0: CV1.2 UV1.AH30
PCIE_CRX_C_GTX_P1: CV3.2 UV1.AG29
PCIE_CRX_C_GTX_P2: CV5.2 UV1.AF27
PCIE_CRX_C_GTX_P3: CV7.2 UV1.AD27
PCIE_PRX_LANTX_N3: CL31.1 UC1.G11
PCIE_PRX_LANTX_N3_C: CL31.2 UL1.18
PCIE_PRX_LANTX_P3: CL30.1 UC1.F11
PCIE_PRX_LANTX_P3_C: CL30.2 UL1.17
PCIE_PRX_WLANTX_N4: JNGFF.35 UC1.F13
PCIE_PRX_WLANTX_P4: JNGFF.33 UC1.G13
PCIE_PTX_LANRX_N3: CC32.1 UL1.14
PCIE_PTX_LANRX_N3_C: CC32.2 UC1.C29
PCIE_PTX_LANRX_P3: CC40.1 UL1.13
PCIE_PTX_LANRX_P3_C: CC40.2 UC1.B30
PCIE_PTX_WLANRX_N4: CC36.1 JNGFF.29
PCIE_PTX_WLANRX_N4_C: CC36.2 UC1.B29
PCIE_PTX_WLANRX_P4: CC41.1 JNGFF.27
PCIE_PTX_WLANRX_P4_C: CC41.2 UC1.A29
PCIE_WAKE#: RC97.2 RL34.2 UE1.29 UL1.21
PCIE_WAKE#_R: RC34.2 RC97.1 UC1.AJ5
PECI_EC: RE43.2 UC1.N62
PECI_KB9012: RE43.1 UE1.118
PEG_CLKREQ#: RP42.6 RV153.1 UC1.U5
PEG_CLKREQ#_R: RV150.2 RV153.2 UV1.N7
PEG_CRX_GTX_N0: CV2.1 UC1.F10
PEG_CRX_GTX_N1: CV4.1 UC1.F8
PEG_CRX_GTX_N2: CV6.1 UC1.H10
PEG_CRX_GTX_N3: CV8.1 UC1.E6
PEG_CRX_GTX_P0: CV1.1 UC1.E10
PEG_CRX_GTX_P1: CV3.1 UC1.E8
PEG_CRX_GTX_P2: CV5.1 UC1.G10
PEG_CRX_GTX_P3: CV7.1 UC1.F6
PEG_CTX_GRX_C_N0: CC18.2 UC1.C23
PEG_CTX_GRX_C_N1: CC20.2 UC1.B23
PEG_CTX_GRX_C_N2: CC22.2 UC1.B21
PEG_CTX_GRX_C_N3: CC24.2 UC1.B22
PEG_CTX_GRX_C_P0: CC19.2 UC1.C22
PEG_CTX_GRX_C_P1: CC21.2 UC1.A23
PEG_CTX_GRX_C_P2: CC23.2 UC1.C21
PEG_CTX_GRX_C_P3: CC25.2 UC1.A21
PEG_CTX_GRX_N0: CC18.1 UV1.AE31
PEG_CTX_GRX_N1: CC20.1 UV1.AD28
PEG_CTX_GRX_N2: CC22.1 UV1.AC31
PEG_CTX_GRX_N3: CC24.1 UV1.AB28
PEG_CTX_GRX_P0: CC19.1 UV1.AF30
PEG_CTX_GRX_P1: CC21.1 UV1.AE29
PEG_CTX_GRX_P2: CC23.1 UV1.AD30
PEG_CTX_GRX_P3: CC25.1 UV1.AC29
PHASE: PC525.2 PQ501.3 PU501.15
PHASE1: PC1026.2 PL1002.1 PQ1003.1 PQ1003.2 PQ1003.3 PQ1004.5 PQ1007.5 PR1036.1 PU1000.23
PHASE2: PC1043.2 PL1003.1 PQ1005.1 PQ1005.2 PQ1005.3 PQ1006.5 PQ1008.5 PR1054.1 PU1000.28
PLL_ANALOG_IN: T221.1(TP-1) UV1.AA1
PLL_ANALOG_OUT: RV83.1 UV1.AA3
PLT_RST#: CC30.1 CE36.1 R159.1 RC51.1 RM6.2 UC3.4 UE1.13 UL1.19 UV2.2
PLT_RST#_R: JNGFF.44 RM6.1
PLT_RST_VGA#: RV4.1 UV1.AL27 UV2.4
PM_APWROK_R: RP50.6 UC1.AB5
PROC_OPI_RCOMP: RC134.1 UC1.AY15
PROJECT_ID: RC112.2 RC113.1 UC1.L5
PS_0: CV29.1 RV8.2 RV9.1 UV1.AC19
PS_1: CV28.1 RV11.2 RV12.1 UV1.AD19
PS_2: CV11.1 RV13.1 RV28.2 UV1.AE17
PS_3: CV15.1 RV15.2 RV16.1 UV1.AE20
PS_ID: PR3.1 PR4.2 UE1.16
PSID: PJPDC.1 PL2.2
PSID-1: PQ5.2 PR6.1 PR9.2
PSID-2: PQ5.1 PQ6.2 PR8.2
PSID-3: PQ6.3 PR4.1 PR11.2
PTP_DIS#: JTP.3 JTP1.5 RC78.1 UE1.38
PTP_KBBL#: JTP1.2 RE339.2 UE1.120
PWR_SRC_ON: CX4.2 QX2.3 RX2.2 RX3.1
PX_EN: T218.1(TP-1) UV1.AB16
PXS_PWREN: PR601.2 PR1027.1 PR1103.1 PR1300.1 RP54.4 RV25.1 UC1.P4
REGN: PC709.2 PD700.2 PR707.1 PR710.1 PU701.19
REMOTE1+: C2500.1 C2502.1 Q2407.1 Q2407.2 U2407.2
REMOTE1-: C2500.2 C2502.2 Q2407.3 U2407.3
REMOTE2+: C2504.1 C2505.1 Q2408.1 Q2408.2 U2407.4
REMOTE2-: C2504.2 C2505.2 Q2408.3 U2407.5
RF_+1.35VGPUP: PR1105.1 PU1100.5
RING2: LA10.2 RA1109.1 UA1.17
RING2_R: CA40.1 DA12.2 JHP.3 LA10.1
RST#: PQ706.6 PR713.2 PU701.13
RSVD_AL1: T136.1(TP-1) UC1.AL1
RSVD_AM11: T137.1(TP-1) UC1.AM11
RSVD_AP7: T139.1(TP-1) UC1.AP7
RSVD_AT2: T128.1(TP-1) UC1.AT2
RSVD_AU10: T141.1(TP-1) UC1.AU10
RSVD_AU15: T142.1(TP-1) UC1.AU15
RSVD_AU44: T132.1(TP-1) UC1.AU44
RSVD_AV44: T134.1(TP-1) UC1.AV44
RSVD_AW14: T144.1(TP-1) UC1.AW14
RSVD_AY14: T145.1(TP-1) UC1.AY14
RSVD_D15: T135.1(TP-1) UC1.D15
RSVD_F22: T138.1(TP-1) UC1.F22
RSVD_H22: T140.1(TP-1) UC1.H22
RSVD_J21: T143.1(TP-1) UC1.J21
RSVD_N23: T129.1(TP-1) UC1.N23
RSVD_R23: T130.1(TP-1) UC1.R23
RSVD_T23: T131.1(TP-1) UC1.T23
RSVD_U10: T133.1(TP-1) UC1.U10
RTC_DIS: QC2.2 QC2.5 RC368.1 UE1.126
RTC_VOUT: CG6.1 RG2.2 UG1.14
RUNPWROK: CC29.1 UC4.1 UC4.4 UC4.10 UC4.13 UE1.36
SATA_ACT#: JLED.7 UC1.U3
SATA_IREF: RC126.1 UC1.A12
SATA_PRX_DTX_N0: CS31.2 JHDD.2
SATA_PRX_DTX_N0_C: CS33.1 UC1.J5
SATA_PRX_DTX_N0_R: CS31.1 US2.12
SATA_PRX_DTX_N0_RC: CS33.2 US2.4
SATA_PRX_DTX_P0: CS34.2 JHDD.1
SATA_PRX_DTX_P0_C: CS35.1 UC1.H5
SATA_PRX_DTX_P0_R: CS34.1 US2.11
SATA_PRX_DTX_P0_RC: CS35.2 US2.5
SATA_PTX_DRX_N0: CS32.2 JHDD.4
SATA_PTX_DRX_N0_C: CS36.1 UC1.B15
SATA_PTX_DRX_N0_R: CS36.2 US2.2
SATA_PTX_DRX_N0_RC: CS32.1 US2.14
SATA_PTX_DRX_P0: CS30.2 JHDD.5
SATA_PTX_DRX_P0_C: CS37.1 UC1.A15
SATA_PTX_DRX_P0_R: CS37.2 US2.1
SATA_PTX_DRX_P0_RC: CS30.1 US2.15
SATA_RCOMP: RC131.1 UC1.C12
SCL: PR714.2 PU701.11
SCLK_CPU: PR504.1 PR508.2 PU501.20
SDA: PR715.2 PU701.10
SDA_CPU: PR500.1 PR505.2 PU501.18
SERIRQ: RC102.2 UC1.T4 UE1.3
SIO_EXT_SCI#: RC98.1 UC1.N5
SIO_SLP_S0#: UC1.AF3 UE1.89
SIO_SLP_S3#: CE27.1 UC1.AT4 UE1.6
SIO_SLP_S4#: T104.1(TP-1) UC1.AJ6 UE1.84
SIO_SLP_S5#: CE28.1 T103.1(TP-1) UC1.AP5 UE1.14
SLATE_MODE_R: RC110.1 UC1.AL4
SLP_SUS#: T106.1(TP-1) UC1.AP4 UE1.17
SM_RCOMP0: RC68.1 UC1.AU60
SM_RCOMP1: RC69.1 UC1.AV60
SM_RCOMP2: RC70.1 UC1.AU61
SML0CLK: RP49.1 UC1.AN1
SML0DATA: RP49.2 UC1.AK1
SML1_SMBCLK: QH1.1 RP40.3 UC1.AU3
SML1_SMBDATA: QH1.4 RP40.4 UC1.AH3
SNB_1.05V: PC301.1 PR302.2
SNUB_PCIE: PC1304.1 PR1303.2
SPK_L1-_CONN: CA30.1 DA13.3 JSPK.3 LA5.2
SPK_L2+_CONN: CA29.1 DA13.2 JSPK.4 LA6.2
SPK_R1-_CONN: CA32.1 DA14.3 JSPK.1 LA3.2
SPK_R2+_CONN: CA31.1 DA14.2 JSPK.2 LA4.2
SRTCRST#: CC3.2 QC2.3 RC5.2 UC1.AV6
SUS_STAT#/LPCPD#: RC29.2 UC1.AG4
SUSACK#: RC28.2 RC35.2 RC37.1 UE1.97
SUSACK#_R: RC37.2 UC1.AK2
SUSCLK: RM5.2 UC1.AE6
SUSCLK_R: JNGFF.42 RM5.1
SUSP: Q8.1 Q2307.2 Q2308.2 R10.2
SUSP#: PR300.2 PR402.1 Q8.2 R16.1 R2313.1 R2318.1 R2451.1 UE1.116
SVI2_SVC: PU1000.3 RV78.2 RV84.1 RV89.2 RV157.2
SVI2_SVD: PU1000.5 RV77.2 RV87.1 RV88.2 RV155.2
SVI2_SVT: PU1000.7 RV156.2
SW_1.35V: PC200.2 PC207.1 PL200.2 PQ200.1 PQ200.2 PQ200.3 PQ201.5 PU200.16
SW_+1.35VGPUP: PC1103.2 PL1101.1 PQ1100.1 PQ1100.2 PQ1100.3 PQ1101.5 PR1104.1 PU1100.8
SW_CPU2: PC520.1 PL502.1 PQ501.5 PQ501.6 PQ501.7
SWAP_1: RP41.2 UC1.C35
SWAP_2: RP41.1 UC1.C34
SYS_PWROK: CC31.1 CE32.1 RC52.1 RP50.1 UE1.86
SYS_PWROK_R: RP50.8 UC1.AG2
SYS_PWROK_XDP: CC16.1 JXDP1.47 RC52.2 RC64.1
SYS_RESET#: RC26.2 UC1.AC3
SYSON: CE26.1 PR201.1 PR310.2 UE1.95
TDI_IREF: RC133.2 UC1.B12
TDI_XDP: JXDP1.56 RC44.2 RC45.1
TDI_XDP_R: RC45.2 RC63.1 UC4.5
TDO_XDP: JXDP1.52 RC43.2 RC62.1 RP44.4 UC4.2
TESTEN: RV17.2 RV154.2 UV1.K7
THM_ALERT#: RV146.2 UV1.R6 UV3.6
TMDS_L_TX0N: CX25.1 JHDMI.9 LX3.2
TMDS_L_TX0P: CX26.1 JHDMI.7 LX3.3
TMDS_L_TX1N: CX27.1 JHDMI.6 LX4.2
TMDS_L_TX1P: CX28.1 JHDMI.4 LX4.3
TMDS_L_TX2N: CX29.1 JHDMI.3 LX5.2
TMDS_L_TX2P: CX30.1 JHDMI.1 LX5.3
TMDS_L_TXCN: CX23.1 JHDMI.12 LX2.2
TMDS_L_TXCP: CX24.1 JHDMI.10 LX2.3
TMDS_TX0N: CX14.1 LX3.1 RP59.2
TMDS_TX0P: CX15.1 LX3.4 RP59.1
TMDS_TX1N: CX16.1 LX4.1 RP58.2
TMDS_TX1P: CX17.1 LX4.4 RP58.1
TMDS_TX2N: CX18.1 LX5.1 RP58.4
TMDS_TX2P: CX19.1 LX5.4 RP58.3
TMDS_TXCN: CX12.1 LX2.1 RP59.4
TMDS_TXCP: CX13.1 LX2.4 RP59.3
TMS_XDP: JXDP1.58 RC46.2 UC4.9
TON_1.35V: PR208.2 PU200.9
TP_CLK: JTP.1 JTP1.3 RE9.2 UE1.87
TP_DATA: JTP.2 JTP1.4 RE10.2 UE1.88
TP_DC_TEST_B2: T167.1(TP-1) UC1.B2
TP_EN: UE1.82 UE4.3
TP_INT#: JTP.4 JTP1.6 QC3.1 RC367.1 RE329.2 RE338.2
TRIP_+1.35VGPUP: PR1102.2 PU1100.2
TRST#_XDP: JXDP1.54 UC4.12
TS_EN: RX25.1 UE1.19 UX3.3
TS_EN_R: JEDP.22 RX25.2
TS_INT#: JEDP.21 RC114.2 RX35.2 UC1.P3
TS_RST#: JEDP.19 RC76.2 RX24.2 UC1.L1
UG_3V: PQ101.4 PU100.10
UG_5V: PQ103.4 PU100.16
UG_+1.35VGPUP: PQ1100.4 PU1100.9
UGATE: PR552.1 PU501.14
UGATE1: PR1060.1 PU1000.22
UGATE2: PR1062.1 PU1000.29
USB3RN1_JUSB1: LI1.1 UC1.G20
USB3RN1_JUSB1_R: DI1.1 DI1.10 JUSB1.5 LI1.2
USB3RN2_JUSB2: LI4.1 UC1.E18
USB3RN2_JUSB2_R: DI4.1 DI4.10 JUSB2.5 LI4.2
USB3RP1_JUSB1: LI1.4 UC1.H20
USB3RP1_JUSB1_R: DI1.2 DI1.9 JUSB1.6 LI1.3
USB3RP2_JUSB2: LI4.4 UC1.F18
USB3RP2_JUSB2_R: DI4.2 DI4.9 JUSB2.6 LI4.3
USB3TN1_JUSB1: CI3.2 UC1.C33
USB3TN1_JUSB1_C: CI3.1 LI3.1
USB3TN1_JUSB1_R: DI1.4 DI1.7 JUSB1.8 LI3.2
USB3TN2_JUSB2: CI10.2 UC1.B33
USB3TN2_JUSB2_C: CI10.1 LI6.1
USB3TN2_JUSB2_R: DI4.4 DI4.7 JUSB2.8 LI6.2
USB3TP1_JUSB1: CI4.2 UC1.B34
USB3TP1_JUSB1_C: CI4.1 LI3.4
USB3TP1_JUSB1_R: DI1.5 DI1.6 JUSB1.9 LI3.3
USB3TP2_JUSB2: CI11.2 UC1.A33
USB3TP2_JUSB2_C: CI11.1 LI6.4
USB3TP2_JUSB2_R: DI4.5 DI4.6 JUSB2.9 LI6.3
USB20_CAM_N7: LX6.1 RX21.1 UC1.AR13
USB20_CAM_N7_R: JEDP.28 LX6.2 RX21.2
USB20_CAM_P7: LX6.4 RX22.1 UC1.AP13
USB20_CAM_P7_R: JEDP.27 LX6.3 RX22.2
USB20_CR_N6: LI8.1 UC1.AP11
USB20_CR_N6_R: JIO.12 LI8.2
USB20_CR_P6: LI8.4 UC1.AN11
USB20_CR_P6_R: JIO.11 LI8.3
USB20_JUSB1_N0: LI2.1 UC1.AN8
USB20_JUSB1_N0_R: DI2.2 JUSB1.2 LI2.2
USB20_JUSB1_P0: LI2.4 UC1.AM8
USB20_JUSB1_P0_R: DI2.3 JUSB1.3 LI2.3
USB20_JUSB2_N1: LI5.1 UC1.AR7
USB20_JUSB2_N1_R: DI5.2 JUSB2.2 LI5.2
USB20_JUSB2_P1: LI5.4 UC1.AT7
USB20_JUSB2_P1_R: DI5.3 JUSB2.3 LI5.3
USB20_JUSB3_N2: LI7.1 UC1.AR8
USB20_JUSB3_N2_R: JIO.15 LI7.2
USB20_JUSB3_P2: LI7.4 UC1.AP8
USB20_JUSB3_P2_R: JIO.14 LI7.3
USB20_MINI1_N4: JNGFF.5 UC1.AM15
USB20_MINI1_P4: JNGFF.3 UC1.AL15
USB20_TOUCH_N5: DX2.3 JEDP.13 UC1.AM13
USB20_TOUCH_P5: DX2.2 JEDP.14 UC1.AN13
USB_EN#: CI13.1 CI26.1 CI46.1 UE1.26 UI2.4 UI3.4 UI4.4 UI5.4 UI6.4 UI7.4
USB_OC0#: CI15.1 CI17.1 RP55.1 UC1.AL3 UI2.5 UI3.5 UI5.3 UI6.3
USB_OC1#: CI47.1 RP55.2 UC1.AT1 UI4.5 UI7.3
USB_OC2#: RP55.3 UC1.AH2
USB_OC3#: RP55.4 UC1.AV3
USBRBIAS: RC90.1 UC1.AJ10 UC1.AJ11
VCIN0_PH: PH1.1 PR24.1 PR25.1 UE1.109
VCIN0_PH2: HE1.1 RE7.1 RE332.1 RE333.1
VCIN1_PH: PC13.2 PR23.1 PR26.2 PR27.2 UE1.102
VCIN2_PH: PC17.2 PR34.2 PR35.1 PR36.2 UE1.64
VCOMP: PC727.2 PU701.7
VCOUT0_PH#: PC100.1 PR100.2 PR101.2 PR102.2 PR110.1 UE1.104
VCOUT1_PH: PR30.1 RE47.2 UE1.103 UE2.2
VFB: PC701.2 PR726.1 PU701.8
VGA_AC__BATT: QV8.3 RV148.2 UV1.T9
VGA_DMINUS: CV9.2 UV1.T2 UV3.3
VGA_DPLUS: CV9.1 UV1.T4 UV3.2
VGA_SMB_CK3: QV1.1 RV6.2 UV1.U7 UV3.8
VGA_SMB_DA3: QV1.4 RV5.2 UV1.U8 UV3.7
VL: PC106.1 PU100.13
VR12.5_VR_ON_R: R250.2 UC1.F60
VR_HOT#: PC510.1 PR510.1 RE44.1
VR_HOT#_1: PR510.2 PU501.4
VR_ON: C80.1 CE34.1 DE1.3 PR511.1 PR519.1 R250.1 RE1.2 RE12.2
VR_ON_1: PR511.2 PU501.1
VR_ON_EC: RE12.1 UE1.121
VR_READY_R: R251.2 UC1.C59
VR_SVID_ALRT#: PR506.1 R252.2 R254.2
VR_SVID_CLK: PR508.1 R248.1
VR_SVID_DAT: PR505.1 R257.2
VRAM_ODT0: UV1.L18 UV5.K1 UV6.K1
VRAM_ODT1: UV1.K16 UV7.K1 UV8.K1
VSMB: PC726.2 PD700.1 PR713.1 PR719.1 PR727.1 PU701.12
VSUM+: PC1031.1 PC1032.1 PR1039.1 PR1042.1 PR1044.1 PR1057.1 PU1000.14
VSUM-: PC1031.2 PC1032.2 PC1035.1 PC1050.1 PC1051.1 PH1003.2 PR1043.1 PR1044.2 PR1046.1 PR1048.1 PR1053.1
VTTREF_1.35V: PC210.1 PU200.4
WAKE_PCH#: RC38.1 UE1.74
WAKEB: RV162.2 RV163.1 UV1.AJ27
WL_OFF#: QM1.3 RP54.3 UC1.AT5
WL_OFF#_R: JNGFF.48 QM1.1 RM8.2
WLAN_CLKREQ#: JNGFF.45 Q2409.1 R2452.1
WLAN_CLKREQ#_R: Q2409.3 R2452.2 RP42.7 UC1.N1
WLAN_WAKE#: JNGFF.47 RE72.2 UE1.90
WOL_EN: RL27.2 RL38.1 UE1.98 UL2.3 UL3.4
XDP_DBRESET#: CC17.1 JXDP1.48 RC26.1 RC362.2
XDP_OBS0_R: JXDP1.21 RC141.1 UC1.J60
XDP_OBS1_R: JXDP1.23 RC141.2 UC1.H60
XDP_PRDY#: JXDP1.5 UC1.J62
XDP_PREQ#: JXDP1.3 RP44.3 UC1.K62
XDP_RST#_R: JXDP1.46 RC51.2
XDP_TCK: RP45.2 UC1.E60
XDP_TCLK: JXDP1.57 RC59.2 RC65.1 RP46.5
XDP_TDI: RP44.2 UC1.F63 UC4.6
XDP_TDO: RP45.1 UC1.F62 UC4.3
XDP_TMS: RP44.1 UC1.E61 UC4.8
XDP_TRST#: R2341.1 RC57.1 RP45.3 UC1.E59 UC4.11
XTAL24_IN: CC6.2 RC12.2 RG6.2 UC1.A25 YC2.3
XTAL24_OUT: CC7.2 RC12.1 UC1.B25 YC2.1
XTALIN: CV17.1 RV20.1 UV1.AM28 YV1.1
XTALOUT: CV18.1 RV20.2 UV1.AK28 YV1.3
XTLI: CL36.2 RG8.2 UL1.29 YL2.1
XTLI_R: CG7.1 RG5.2 RG8.1
XTLO: CL37.2 UL1.28 YL2.3
N71037: RA130.2 UA1.8
N71249: CA62.2 RA12.2 UA1.27
N71261: CA63.2 UA1.39
N71273: CA64.2 UA1.7
N71383: CA24.1 UA1.37
N71395: CA24.2 UA1.35
N71399: CA25.2 UA1.34
N71447: CA23.2 UA1.28
N71539: CA65.2 CA69.1 RA79.1 RA81.2
N71593: CA65.1 UA1.12
N76526: RA1113.2 UA1.4
N14128350: PR1110.2 PU1100.1
N16741477: T212.1(TP-1) UV1.AB8
N16741481: T209.1(TP-1) UV1.AC8
N16741485: T205.1(TP-1) UV1.AE8
N16741489: T208.1(TP-1) UV1.AD7
N16741493: T203.1(TP-1) UV1.AE9
N16741497: T201.1(TP-1) UV1.N9
N16741501: T215.1(TP-1) UV1.AB2
N16741505: T214.1(TP-1) UV1.AB4
N16741509: T211.1(TP-1) UV1.AB9
N16741513: T207.1(TP-1) UV1.AC10
N16741517: T206.1(TP-1) UV1.AD9
N16741521: T202.1(TP-1) UV1.L9
N16741525: T216.1(TP-1) UV1.Y8
N16741529: T213.1(TP-1) UV1.AB7
N16741533: T210.1(TP-1) UV1.AC7
N16741553: T204.1(TP-1) UV1.Y11
N16741557: T217.1(TP-1) UV1.Y7
N16741803: RV29.2 UV1.AC22
N16741825: RV59.2 UV1.AB22
N16745905: QV3.2 RV25.2
N16745935: CV24.1 QV2.2 RV23.2
N16745959: CV25.1 QV4.2 RV26.1
N16784339: RV77.1 U1.7
N16784342: RV78.1 U1.6
N16787636: JKBBL.2 QE4.2 RE58.1
N16803422: RV157.1 UV1.AJ11
N16803439: RV155.1 UV1.AK12
N16803454: RV156.1 UV1.AL11
N16814221: RV60.1 UV1.AC11 UV1.AC13
N16855208: R2448.2 R2450.1 U2407.7
N16924370: CL41.2 TL2.3 TL2.6
N16924426: RL31.2 UL1.31
N16924463: T94.1(TP-1) UL1.25
N16924465: T95.1(TP-1) UL1.27
N16924703: CL33.1 RL19.2 RL20.2
N16948644: PC1036.2 PR1046.2 PU1000.15
N16948660: PC1036.1 PR1048.2
N16948668: PC1020.1 PR1024.1 PU1000.25
N16955053: PL1002.2 PR1039.2 PR1058.2
N16955054: PL1002.3 PR1043.2
N16955057: PR1052.2 PU1000.11
N16955058: PC1027.1 PC1030.1 PR1040.1 PR1049.1 PU1000.16
N16955061: PC1040.1 PR1050.1 PU1000.17
N16955074: PQ1004.4 PQ1007.4 PR1061.2
N16955100: PC1029.1 PR1036.2
N16955117: PC1026.1 PR1034.2
N16955158: PH1002.2 PR1031.2 PR1052.1
N16955166: PC1028.1 PR1037.2 PR1040.2 PR1041.1 PR1045.1 PU1000.18
N16955169: PC1027.2 PR1037.1
N16955171: PC1034.1 PR1045.2
N16955173: PC1028.2 PC1033.2 PR1038.1 PU1000.19
N16955176: PC1033.1 PR1041.2
N16955207: PQ1003.4 PR1060.2
N16960820: C5214.1 U2408.6
N16988653: PC605.1 PJP600.2 PU600.3
N16988706: PC601.1 PR605.2
N17016554: RV56.1 UV7.L8
N17017096: RV57.1 UV8.L8
N17072999: C5216.1 U2301.12
N17073002: C5217.1 U2301.10
N17073375: C5218.1 U2304.12
N17073377: C5219.1 U2304.10
N17087794: PU1000.39 PU1000.40
N17087943: PU1000.36 PU1000.37 PU1000.38
N17088414: PR1032.2 PU1000.1
N17088417: PR1033.2 PU1000.2
N17089228: PR1035.2 PU1000.34
N17089248: PR1056.2 PU1000.32 PU1000.33
N17112777: PL1003.2 PR1057.2 PR1059.2
N17143063: CE60.1 UE4.6
N17145436: PC307.2 PR309.1
N17200666: RS19.2 US2.7
N17200672: RS20.2 RS22.2 US2.18
N17200720: RS25.2 US2.10
N17242539: RV58.1 UV3.4
N17258399: PJPDC.2 PJPDC.3 PL4.1 PL7.1
N17283470: PQ200.4 PR209.1
N17283477: PC204.2 PR210.1 PU200.12
N17290798: PC300.1 PR300.1 PR301.1 PR310.1 PU300.1
N17411014: CE12.1 R2354.1
N17434554: RE36.2 UE1.107
N17434577: RE7.2 UE1.66
N17438484: CA21.1 RA1112.2
N17446326: PC729.1 PC730.1 PC731.1 PC733.2 PQ701.5 PQ701.6 PQ701.7 PQ701.8 PR702.1
N17446342: PC702.2 PQ700.1 PQ700.2 PQ700.3 PQ701.1 PQ701.2 PQ701.3 PR718.1
N17446348: PC702.1 PC733.1 PQ700.4 PQ701.4 PR718.2 PR725.2
N17455546: C93.1 RC137.1 UC1.AD8 UC1.AD10
N17456106: C92.2 RC142.1 UC1.J13
N17456207: C91.2 RC143.1 UC1.AH13
N17468285: CD21.1 CD22.1 JDIMM1.126 RD4.1
N17471827: JDIMM1.197 RD6.2
N17471828: JDIMM1.201 RD7.2
N17476323: CD52.1 CD53.1 JDIMM2.126 RD10.1
N17476376: JDIMM2.197 RD13.1
N17476385: JDIMM2.201 RD12.1
N17493058: JNGFF.36 T4927.1(TP-1)
N17493084: JNGFF.40 T4929.1(TP-1)
N17493086: JNGFF.38 T4928.1(TP-1)
N17493091: JNGFF.6 T3861.1(TP-1)
N17493111: JNGFF.16 T3862.1(TP-1)
N17494823: CA1.1 CA2.1 QA5.2 RA3.2
N17531604: C90.1 CC37.1 CC38.1 RC136.1 UC1.AB8
N17580597: CX52.1 UX3.4
N17586185: RE37.2 UE1.127
N17613161: PC313.1 PJP301.2 PU300.7
N17613162: PR305.2 PR307.1 PR309.2 PU300.4
N17613228: PC302.1 PR303.2
N17745376: RL39.2 UL1.26
N17847259: T4930.1(TP-1) UV1.AL9
N17877344: T223.1(TP-1) UV1.R1
N17877347: T224.1(TP-1) UV1.R3
N17882994: PH1003.1 PR1042.2
N17932877: RX10.2 UX4.3
N17933206: PL1003.3 PR1053.2
N17933209: PQ1006.4 PQ1008.4 PR1063.2
N17933219: PC1044.1 PR1054.2
N17933234: PC1043.1 PR1055.2
N17933249: PQ1005.4 PR1062.2
N17933268: PC1302.1 PU1300.7
N17933717: RL40.2 UL3.3
N17936926: RM10.2 UM1.3
N17938093: PR533.2 PR537.2 PR543.2 PU501.7
N17945375: CX9.1 UX1.4
N17984356: DS1.1 QS1.1
N18923200: DC1.2 RC10.1
N19505504: T117.1(TP-1) UC1.AD4
N19607621: QX5.2 RX15.1
N19636367: QA6.2 RA6.2 RA7.2
N19792312: QA5.5 QA5.6 RA2.2
N19794620: QA6.5 QA6.6 RA5.2
N21178712: PQ1.3 PR5.2
N22753332: PQ501.2 PR552.2
N22753389: PC525.1 PR538.1
N22753454: PH500.1 PR525.1 PR528.1
N22753537: PL502.2 PR536.2
N22753594: PR507.1 PU501.17
N22753687: PC522.2 PR533.1
N22753703: PC527.2 PR543.1
N22753707: PC526.2 PR539.1
N22753760: PC523.1 PR535.1 PU501.9
N22753762: PC523.2 PR545.2
N22753790: PH501.2 PR551.1
N22763740: PR708.2 PR716.2
N22763755: PQ706.3 PR720.2
N22763812: PC724.2 PQ702.4 PR706.1
N22763830: PC719.2 PR710.2 PU701.20
N22763871: PR702.2 PR717.2
N22763875: PR702.3 PR704.2
N22763935: PC715.2 PR722.1
N22764104: PC701.1 PR701.2
N22764115: PC727.1 PR726.2
N22764126: PR727.2 PU701.4
N22764133: PC728.2 PR728.1
N22764201: PC723.1 PQ706.2 PR724.2
N22764304: PL702.1 PR702.4
N22892968: PR538.2 PU501.13
N22894348: PR512.1 PU501.11
N23700314: PL2.1 PQ6.1 PR6.2 PR11.1
N23711299: PC401.1 PJP400.2 PU400.5 PU400.9
N23711301: PC403.2 PR400.2 PR401.1 PU400.2
N23711331: PC402.1 PR402.2 PR403.1 PU400.8
N37640332: RV2.2 UV1.N10
N37640410: RV3.1 UV1.AA22
N37817724: RV1.1 UV1.Y22
N38023415: CV96.1 RV36.2 RV37.2
N38028869: CV98.2 UV1.K8
N38028873: CV99.2 UV1.L7
N38028878: CV98.1 RV40.2
N38028880: CV99.1 RV41.2
N38039273: RV46.1 UV5.L8
N38046520: CV102.1 RV48.2 RV49.2
N38049955: RV47.1 UV6.L8
N38097860: CV135.1 RV54.2 RV55.2
N38342282: RV39.2 UV1.K25
N46660696: PC520.2 PR534.1
N47007806: PC16.1 PQ2.3 PR28.2
N47007810: PC16.2 PQ2.2 PR29.1
N47007850: PQ2.5 PR31.1 PR33.2
N47007898: PC14.2 PQ3.5 PR32.1
N47008006: PQ1.5 PQ1.6 PR7.1 PR10.2
N47008110: PC15.1 PQ3.2 PR30.2
N47415217: PC104.2 PR103.1
N47415258: PC103.1 PR113.2
N47415272: PC111.1 PR112.2
N47415370: PC110.1 PR111.2
N47420895: PC207.2 PR203.1
N47445410: PR114.1 PU100.19
N47894294: CC8.2 RC23.1
N47894380: CC9.2 RC24.1
N47894401: CC10.2 RC25.1
N47938591: T118.1(TP-1) UC1.AN10
N47938593: T119.1(TP-1) UC1.AM10
N47938689: T120.1(TP-1) UC1.E15
N47938710: T121.1(TP-1) UC1.E13
N47964855: T153.1(TP-1) UC1.L60
N47964866: T154.1(TP-1) UC1.N60
N47964871: T155.1(TP-1) UC1.W23
N47964873: T156.1(TP-1) UC1.Y22
N47964879: T157.1(TP-1) UC1.AV62
N47964884: T158.1(TP-1) UC1.D58
N47965485: T146.1(TP-1) UC1.AV63
N47965487: T147.1(TP-1) UC1.AU63
N47965489: T160.1(TP-1) UC1.P20
N47965491: T162.1(TP-1) UC1.R20
N47965493: T159.1(TP-1) UC1.A5
N47965495: T148.1(TP-1) UC1.C63
N47965502: T161.1(TP-1) UC1.E1
N47965509: T149.1(TP-1) UC1.C62
N47965511: T163.1(TP-1) UC1.D1
N47965522: T150.1(TP-1) UC1.B43
N47965524: T164.1(TP-1) UC1.J20
N47965529: T151.1(TP-1) UC1.A51
N47965534: T152.1(TP-1) UC1.B51
N47965536: T165.1(TP-1) UC1.H18
N55155843: QX1.1 RX3.2
N55200533: QX3.1 RP58.5 RP58.6 RP58.7 RP58.8 RP59.5 RP59.6 RP59.7 RP59.8
N55201771: JHDMI.13 RX12.2
N60531230: RP41.3 UC1.AK8
N60531232: RP41.4 UC1.AL8
N60754677: T111.1(TP-1) UC1.H61
N60754679: T112.1(TP-1) UC1.H62
N60754681: T113.1(TP-1) UC1.K59
N60754683: T114.1(TP-1) UC1.H63
N60754685: T115.1(TP-1) UC1.K60
N60754687: T116.1(TP-1) UC1.J61
N60931942: T97.1(TP-1) UC1.AF2
N60931944: T99.1(TP-1) UC1.AF4
N60931946: T98.1(TP-1) UC1.AD2
N61580896: Q2307.1 R2314.2
N61580898: Q2308.1 R2315.2
N63469524: CA68.2 RA82.1
N63469526: CA67.2 RA80.1
N63642793: C51.1 R264.2 UC1.AH11
N63656577: T38.1(TP-1) UC1.AB23
N63657072: T39.1(TP-1) UC1.P60
N63657081: T40.1(TP-1) UC1.P61
N63657090: T41.1(TP-1) UC1.N59
N63657099: T42.1(TP-1) UC1.N61
N63657120: T43.1(TP-1) UC1.T59
N63657126: T44.1(TP-1) UC1.AD60
N63657135: T45.1(TP-1) UC1.AD59
N63657146: T46.1(TP-1) UC1.AA59
N63657155: T47.1(TP-1) UC1.AE60
N63657164: T48.1(TP-1) UC1.AC59
N63657173: T49.1(TP-1) UC1.AG58
N63657182: T50.1(TP-1) UC1.U59
N63657191: T51.1(TP-1) UC1.V59
N64564173: PC1103.1 PR1101.2
N64564191: PC1106.1 PR1104.2
N64734520: T107.1(TP-1) UC1.AJ7
N64734538: T105.1(TP-1) UC1.AL5
N177530291: QV4.1 RV24.2
N188017740: PQ4.3 PR36.1
N188020320: PQ4.6 PR27.1

Pads without a net: DE2 2; FD1 1; FD2 1; FD3 1; FD4 1; JDIMM1 77 122 125 198; JDIMM2 77 122 125 198; JEDP 38; JHDMI 14; JIO 5 7; JKB 2 3 30; JKBBL 3; JLAN 4 5 7 8; JNGFF 8 9 10 11 12 13 14 15 17 19 20 21 22 23 24 26 28 34 50 51 52 53 54 56 57 58 59 60 62 63 65; JTP1 1; JXDP1 55; PU200 10; PU400 7; PU600 2 5; PU701 26; PU1000 35; PU1300 4; RP37 4 5; RP42 5; RP45 4 5; RP46 3 6; RP48 4 5; RP49 3 4 5 6; RP50 4 5; TL2 4 5 12 13; U2303 1; U2407 8; UA1 14 15 16 23 24 48; UC1 A17 A31 A37 A41 A49 A53 AA23 AB21 AC2 AC4 AC20 AC58 AD23 AE59 AF20 AG5 AL2 AL11 AL32 AP1 AP15 AP32 AR10 AT3 AT10 AU2 AU12 AV2 AV10 AV50 AW10 AW49 AY8 AY42 AY43 B14 B17 B31 B37 B41 B49 B50 B53 B54 C3 C4 C15 C17 C30 C31 C42 C43 C46 C47 C49 C50 C51 C53 D17 D61 E2 E3 E4 E5 F4 F5 F15 F17 G15 G17 H6 H8 J4 J6 J8 J58 K4 K10 K18 K21 L2 L3 L11 L59 M20 M21 N58 R5 T2 U2 V21 Y1 Y2 Y4 Y5 Y20; UE1 128; UE2 1; UG1 11 12; UL1 6 7 9 10; US3 2 3; UV1 AA5 AA6 AA29 AA31 AB23 AB25 AB26 AB27 AB30 AC1 AC3 AC5 AC6 AC16 AC23 AC25 AD2 AD4 AD10 AD11 AD13 AD16 AD22 AD23 AD24 AE1 AE3 AE5 AE6 AE10 AE11 AE13 AE16 AE19 AE22 AE23 AE24 AE25 AE26 AF2 AF4 AF6 AF7 AF8 AF9 AF10 AF11 AF13 AF16 AF17 AF22 AF24 AF25 AG1 AG3 AG5 AG6 AG7 AG8 AG9 AG10 AG11 AG13 AG15 AG16 AG17 AG18 AG19 AG20 AG21 AG22 AG24 AG25 AG26 AH1 AH3 AH5 AH6 AH8 AH12 AH16 AH18 AH20 AH22 AH24 AH26 AJ7 AJ9 AJ13 AJ15 AJ17 AJ19 AJ21 AJ23 AJ25 AK1 AK3 AK5 AK6 AK8 AK10 AK14 AK16 AK18 AK20 AK22 AK24 AK26 AL7 AL13 AL15 AL17 AL19 AL21 AL23 AL25 AM3 AM5 AM6 AM8 AM10 AM12 AM26 J8 J22 J25 K13 K30 L16 L29 L31 M4 M27 M28 M30 N3 N5 N6 N8 N26 N29 N31 P2 P4 P7 P10 P23 P24 P26 P27 P28 P30 R29 R31 T7 T23 T24 T26 T27 T28 T30 U5 U6 U23 U24 U26 U29 U31 V2 V4 V6 V27 V28 V30 W3 W5 W6 W7 W8 W23 W24 W29 W31 Y2 Y4 Y6 Y23 Y24 Y26 Y27 Y28 Y30; UV5 J1 J9 L1 L9; UV6 J1 J9 L1 L9; UV7 J1 J9 L1 L9; UV8 J1 J9 L1 L9; YC2 2 4

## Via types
v1: diameter 0.305, hole 0.152, TOP to BOTTOM, 752 vias
v2: diameter 0.457, hole 0.203, TOP to BOTTOM, 4198 vias
v3: diameter 0.508, hole 0.254, TOP to BOTTOM, 1212 vias
v4: diameter 0.406, hole 0.203, TOP to BOTTOM, 126 vias

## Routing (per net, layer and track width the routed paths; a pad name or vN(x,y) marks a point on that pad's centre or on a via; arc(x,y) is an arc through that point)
0.675V_DDR_VTT_ON: length 187.2
  TOP w0.305: 141.97,52.63 R2351.2 R2347.2 ; 141.97,52.63 141.48,53.12 141.48,54.03 QD2.2 141.37,54.14 U2303.4 ; 141.97,52.63 142.27,52.94 143.62,52.94 143.82,52.73 146.23,52.73 146.39,52.58 v1(146.79,52.58) v2(147.55,52.58)
  IN1 w0.254: v2(171.63,22.66) 171.63,22.03 170.62,21.01 170.62,18.09 167.95,15.42 166.93,15.42 166.3,14.79 166.3,11.43 164.7,9.83 163.34,9.83 161.74,8.23 157.5,8.23 156.82,8.91 155.28,8.91 154.95,9.24 152.2,9.24 152.06,9.1 150.7,9.1 150.35,9.45 150.34,9.45 150.28,9.52 150.11,9.68 147.53,9.68 147.17,9.33 141.97,9.33 141.28,10.01 141.28,10.18 140.82,10.63 139.17,10.63 139.15,10.65 138.77,10.65 138.76,10.63 137.05,10.63 135.97,9.55 133.54,9.55 132.29,10.8 130.63,10.8 129.97,11.46 118.37,11.46 v2(117.95,11.88)
  IN2 w0.254: v2(79.43,7.93) 80.07,7.29 83.9,7.29 84.53,7.92 85.3,7.92 85.98,7.24 95.43,7.24 97.13,8.95 103.31,8.95 105.32,6.93 105.32,3.32 106.89,1.75 v2(115.92,1.75)
  BOTTOM w0.254: v2(171.63,22.66) 171.63,23.42 173.01,24.79 173.01,25.3 175.57,27.87 175.57,35.49 174.28,36.78 174.28,40.72 172.26,42.74 172.26,44.57 171.94,44.89 168.1,44.89 161.4,51.59 153.83,51.59 152.84,52.58 v2(147.55,52.58) ; v2(115.92,1.75) 115.95,1.75 116.01,1.81 116.01,9.3 117.95,11.24 v2(117.95,11.88) ; PR202.1 v2(79.43,7.93)
1.35V_B+: length 5.2
  TOP w0.102: v2(80.47,15.4) v4(79.79,15.4)
  BOTTOM w0.254: 79.94,15.3 79.13,14.48 79.13,12.48 PR208.1
3/5V_B+: length 29.9
  TOP w0.203: PU100.12 69.41,18.51 v2(68.94,18.99)
  TOP w0.508: v2(68.94,18.99) 68.87,18.99 68.4,18.52 68.4,9.97 67.24,8.82 61.65,8.82 58.15,12.32 58.15,15.98 58.48,16.31 59.09,16.31 59.19,16.21
  BOTTOM w0.508: PC105.1 69.1,18.83 v2(68.94,18.99)
  vias: v1(59.9,20.71) v3(59.2,19.88) v3(59.16,19.24) v3(59.16,18.61) v3(59.16,17.97) v3(59.16,17.34) v3(60,19.87) v3(60.64,19.87) v3(61.27,19.87) v3(62.11,18.61) v3(62.11,17.97)
3V_EN: length 12.4
  TOP w0.203: PU100.6 73.07,19.99 73.32,20.24 73.51,20.24 v3(73.64,20.36)
  TOP w0.254: PR100.1 76.21,12.2 76.21,13.92 v1(76.03,14.1) 75.81,14.32 PD101.2 74.93,15.63 74.07,16.49 v2(73.72,16.49)
  BOTTOM w0.254: v3(73.64,20.36) 73.64,16.57 v2(73.72,16.49)
3VALW_PCH:
  vias: v1(159.59,15.4)
3VS:
  vias: v1(172.19,16.23)
3VS_GATE: length 4.7
  TOP w0.102: R2318.2 176.03,11.05 v1(176.23,10.85)
  TOP w0.203: C2322.1 172.99,11.71 171.66,11.71 171.25,12.12 171.25,12.4 171.02,12.63 U2301.5
5V_EN: length 6.3
  TOP w0.203: PU100.20 73.07,16.17 73.31,15.93
  TOP w0.254: PR101.1 73.5,12.97 73.93,13.4 PD101.3 73.93,14.77 74.17,15.02 v1(74.17,15.45) 73.69,15.93 73.31,15.93
5VS: length 0.8
  TOP w0.102: 168.87,15.22 v1(168.1,15.22)
5VS_GATE: length 2.3
  TOP w0.203: C2309.1 170.87,11.74 170.69,11.92 170.43,11.92 170.16,12.18 170.16,12.56 170.22,12.62 U2301.3
  vias: v2(170.92,10.62)
+0.675VS: length 122.8
  TOP w0.508: R2314.1 168.42,7.55 v2(165.92,7.55) v2(162.74,7.55)
  IN1 w0.508: v2(163.63,1.6) 161.74,3.5 149.67,3.5 149.02,2.85 124.64,2.85 124.54,2.75 122.23,2.75 121.6,3.38 118.99,3.38 118.57,2.96 114.06,2.96 113.82,2.72 108.77,2.72 107.83,3.66 v2(107.83,4.09)
  BOTTOM w0.356: JDIMM2.203 171.52,32.58 170.97,32.03 170.44,32.03 v2(170.41,32.06) ; v2(159.64,45.95) 159.64,46.23 159.15,46.72 JDIMM1.203 ; v2(170.08,29.09) 170.44,29.09 171.81,27.72 171.81,26.55 JDIMM2.204 ; v2(159.42,40.94) 159.45,40.91 JDIMM1.204
  BOTTOM w0.508: v2(162.74,7.55) 162.74,7.52 163.66,6.61 163.66,1.63 v2(163.63,1.6) ; JDIMM2.204 171.82,25.79 171.86,25.75 171.86,25.43 169.72,23.28 167.6,23.28 166.05,21.73 166.05,8.31 165.92,8.18 v2(165.92,7.55) ; v2(107.83,4.09) 107.02,4.09 106.61,4.5 106.61,6.46 104.58,8.49 98.05,8.49 97.54,7.98 91.75,7.98
  vias: v1(160.15,44.86)
+0.675VSP: length 2.7
  TOP w0.203: v3(85.63,9.46) 85.07,8.89 v4(85.05,8.89) 84.09,8.89 v2(84.09,8.89)
  BOTTOM w0.203: v2(84.09,8.89) 84.4,9.21 PU200.2
+1.05V:
  vias: v1(164.17,15.5)
+1.05V_LDO_3V: length 4.8
  TOP w0.254: v3(181.67,50.35) v1(182.92,49.09) 182.92,49.04 v3(184.55,47.42)
  BOTTOM w0.254: PR304.1 183.91,47.55 184.42,47.55 v3(184.55,47.42)
+1.05V_PGOOD: length 100.6
  TOP w0.152: v2(141.1,7.32) 141.55,7.76 v2(141.55,13.14) ; v2(182.3,46.66) v1(182.3,44.48) v2(182.3,43.49)
  TOP w0.203: UE1.122 135.02,18.41 135.62,17.8 135.62,14.08 136.1,13.6 v2(136.1,13.6)
  IN1 w0.152: v2(141.1,7.32) 141.15,7.32 141.26,7.22 147.25,7.22 147.72,7.69 154.29,7.69 154.67,7.31 155.81,7.31 156.01,7.1 156.02,7.1 156.93,6.2 159.98,6.2 161.06,5.12 168.32,5.12 172.14,8.95 172.14,13.09 172.9,13.85 172.9,18.27 176.51,21.87 176.51,35.6 176.86,35.95 176.86,38.53 177.68,39.35 181.72,39.35 182.3,39.93 v2(182.3,43.49)
  IN2 w0.152: v2(136.1,13.6) 136.23,13.73 140.95,13.73 v2(141.55,13.14)
  BOTTOM w0.254: PR308.2 182.68,45.78 182.3,46.16 v2(182.3,46.66) 182.3,46.92 181.41,47.81 181.41,48.44 180.94,48.91 PU300.2
+1.5VS: length 326
  TOP w0.102: v3(201.62,4.44) v4(201.62,3.5)
  TOP w0.254: PR1025.1 65.84,33.71 66.1,33.46 66.1,33.38 v3(66.22,33.26)
  TOP w0.381: v2(159.31,89.08) 159.7,88.7 RC129.1
  IN1 w0.254: v2(172.6,7.01) 172.88,7.01 174.3,8.44 184.21,8.44 184.71,8.95 191.32,8.95 192.59,10.22 192.59,11.1 194.11,12.63 195.26,12.63 197.41,10.47 198.66,10.47 200.69,12.5 202.24,12.5 v2(202.88,13.14) ; v2(159.31,89.08) 158.87,89.53 158.24,89.53 158.06,89.7 156.55,89.7 155.85,89.01 153.63,89.01 153.63,89 151.78,89 151.19,89.59 151.19,90.1 148.77,92.51 148.77,95.72 v2(147.39,97.11)
  IN1 w0.508: v3(204.4,21.9) 204.4,17.84 202.75,16.18 202.75,13.26 v2(202.88,13.14) ; v2(159.31,89.08) 159.57,88.83 159.57,87.51 160.03,87.05 162.24,87.05 163.12,86.16 166.58,86.16 v3(166.6,86.19) ; v3(190.95,86.06) 191.95,85.06 191.95,80.19 192.46,79.68 192.46,70.68 193.56,69.58 193.56,65.51 193.95,65.12 193.95,62.31 195.09,61.17 195.09,55.55 194.41,54.86 194.41,51.84 192.99,50.42 v2(192.99,41.97)
  IN2 w0.254: v2(80.98,37.52) 80.98,36.83 79.64,35.49 77.27,35.49 75.88,34.09 75.87,34.09 74.63,32.85 66.63,32.85 v3(66.22,33.26) ; v2(81.01,42.04) 81.67,41.38 84.6,41.38 88.1,37.88 96.72,37.88 108.63,25.96 118.04,25.96 120.22,23.78 124.95,23.78 125.06,23.67 126.49,23.67 127.26,24.44 128.81,24.44 128.86,24.39 136.53,24.39 136.77,24.16 146.32,24.16 147.1,23.37 148.95,23.37 149.59,24.01 151.07,24.01 v2(151.34,23.74) ; v2(172.6,7.01) 172.47,6.89 169.37,6.89 169.22,7.04 164.47,7.04 163.71,6.28 157.63,6.28 156.46,7.45 154.34,7.45 v2(154.12,7.23)
  IN2 w0.508: v2(192.99,41.97) 193.2,41.97 193.68,41.49 193.68,38.03 193.87,37.84 193.87,35.74 195.31,34.31 195.31,33.48 194.87,33.05 194.87,28.73 198.46,25.15 199,25.15 199.48,24.67 201.63,24.67 v3(204.4,21.9) ; v2(202.88,13.14) 203.89,12.12 203.89,5.95 v3(203.02,5.07)
  BOTTOM w0.254: v2(80.98,37.52) 81.16,37.7 81.16,41.89 v2(81.01,42.04) ; v2(147.39,97.11) 147.68,96.82 UC1.J15 ; v2(151.34,23.74) 151.34,23.02 151.47,22.9 151.47,20.17 151.75,19.89 151.75,17.05 152.48,16.31 153.07,16.31 153.93,15.45 153.93,14.43 154.59,13.77 154.59,7.7 v2(154.12,7.23)
  BOTTOM w0.508: v3(166.6,86.19) 166.66,86.14 167.14,86.14 167.49,85.78 173.79,85.78 175.98,87.96 177.6,87.96 179.51,86.06 v3(190.95,86.06) ; v3(204.4,21.9) 204.15,21.65 RA8.1
+1.05VS:
  vias: v1(175.55,33.15)
+1.05VS_APLLOPI: length 3.4
  TOP w0.102: L3.2 v1(138.36,87.61)
  TOP w0.508: v2(143.94,90.65) 144.7,90.65 C69.1
  BOTTOM w0.254: UC1.W21 144.45,91.16 v2(143.94,90.65) 144.04,90.55 UC1.AA21
  vias: v2(139.6,89.06) v2(139.6,88.42)
+1.05VS_ASATA3PLL: length 17
  BOTTOM w0.203: 149.91,101.58 149.73,101.39 UC1.B11
  BOTTOM w0.381: 149.91,101.58 149.96,101.58 150.24,101.86 150.24,102.52 150.55,102.84 150.55,104.62 150.09,105.08 150.09,105.96 150.16,106.03
  BOTTOM w0.508: 150.16,106.03 v1(150.16,107.66) 149.94,107.88 149.94,109.35 ; RC126.2 148.52,109.59 148.76,109.35 RC131.2 149.94,109.35 ; 149.94,109.35 149.99,109.4 C63.1 149.99,112.08 150.23,112.32 C65.1 150.23,115.22 L2.2
+1.05VS_AUSB3PLL: length 26.1
  IN1 w0.381: v2(145.45,104.92) 144.15,103.62 142.48,103.62 142.17,103.31 140.34,103.31 v2(139.35,104.3)
  BOTTOM w0.076: 139.99,102.34 139.99,101.7 UC1.B27
  BOTTOM w0.203: 139.99,102.34 139.99,103.66 v2(139.35,104.3)
  BOTTOM w0.254: 145.45,103 145.14,102.69 145.14,101.89 145.27,101.76 UC1.B18
  BOTTOM w0.305: RC91.1 139.17,104.47 v2(139.35,104.3)
  BOTTOM w0.508: L1.2 146.17,114.46 C59.1 146.17,110.94 C58.1 147.16,109.95 147.16,107.54 146.74,107.12 v1(146.74,106.4) 146.74,105.67 145.99,104.92 v2(145.45,104.92) 145.45,103
+1.05VS_AXCK_DCB: length 2.5
  TOP w0.508: v2(145.5,97.14) 145.18,96.83 145.14,96.83 C83.1
  BOTTOM w0.254: UC1.K19 145.44,97.09 v2(145.5,97.14) 145.82,96.82 UC1.J18
  vias: v1(141.69,96.98) v2(141.15,96.96) v2(141.15,96.32)
+1.05VS_AXCK_LCPLL: length 7.4
  BOTTOM w0.254: UC1.A20 144.75,102.17 144.75,103.08
  BOTTOM w0.381: RC13.2 146.49,107.75 146.11,107.37 146.11,105.97 145.81,105.68 v2(145.28,105.68) 144.8,105.19 144.8,103.12 144.75,103.08
  vias: v4(144.1,110.16)
+1.05VS_GATE: length 5.9
  TOP w0.102: R2451.2 166.3,11.21 166.76,10.75 166.76,9.45 v1(166.91,9.3)
  TOP w0.203: C2325.1 164.48,11.84 163.2,11.84 162.38,12.66 U2304.5
+1.05VS_PCH: length 338.6
  TOP w0.203: RP45.8 v2(111.32,94.43) ; CG2.1 188.79,78.92 188.52,78.65 UG1.3 ; 141.71,80.37 142.53,81.18 142.53,81.54 142.57,81.59 142.57,83.64 142.62,83.69 142.62,85.62 142.63,85.62 142.63,86.44 142.32,86.75
  TOP w0.254: C53.1 151.32,95.38 151.32,95.51 151.53,95.73 154.4,95.73 155.89,97.21 158.68,97.21 159.19,96.7 C67.1 159.75,97.73 C66.1 ; CC14.1 93.94,75.21 92.93,76.21 JXDP1.43 ; 141.71,80.37 141.71,86.21 141.1,86.82 141.1,87.43 141.31,87.63 141.74,87.63 v2(141.92,87.81) 142.02,87.71 142.02,87.05 142.32,86.75
  TOP w0.279: JXDP1.44 84.3,76.21 83.62,76.89 CC15.1 83.57,77.19 83.55,77.22 v2(83.55,77.53)
  TOP w0.508: 141.71,80.37 141.1,79.76 141.1,78.49 140.67,78.06 140.67,70.49 141.66,69.5 144,69.5 144.28,69.78 RC143.2 ; C87.1 146.61,96.98 v2(146.45,97.14) ; v2(59.11,111.41) 58.83,111.41 v4(57.47,110.05) v2(55.89,108.46) ; v2(165.39,8.79) 164.9,8.31 R2315.1 ; v2(151.8,94.24) 151.72,94.16 151.19,94.16 150.73,94.62 C53.1 149.9,94.62 v2(149.88,94.64) 149.86,94.62 C50.1 ; v2(141.69,89.79) 141.85,89.63 C43.1 141.85,87.88 v2(141.92,87.81) ; v2(189.08,78.29) CG2.1 ; RC58.1 106.03,94.8 v2(105.14,93.91) 98.99,93.91 95.94,96.96 v2(93.66,96.96) ; C88.1 144.41,93.72 v2(144.08,93.39) ; C44.1 146.03,94.66 C76.1 146.03,92.62 v2(146.01,92.6) ; v2(150.26,95.26) 150.12,95.4 RC142.2 150.2,96.12 C57.1 ; v2(177.73,82.53) 177.53,82.73 RC137.2 ; v2(176.59,86.54) 176.46,86.42 RC136.2 ; CC14.1 95.1,75.32 94.6,75.82 v2(94.06,75.82) ; v2(95.56,92.71) 95.23,92.38 v2(87.18,92.38)
  IN1 w0.508: v2(109.61,88.93) 109.38,88.7 105.47,88.7 104.96,88.19 v2(103.43,88.19) ; v2(189.08,78.29) 188.65,78.29 185.86,81.08 v2(185.35,81.08) ; v2(176.59,86.54) 176.59,85.15 177.73,84 v2(177.73,82.53) ; v2(94.06,75.82) 94.04,75.85 94.04,78.8 95.05,79.81 95.05,82.1 95.43,82.48 95.43,92.59 v2(95.56,92.71) ; v2(96.32,108.89) 101.66,108.89 103.05,110.29 109.68,110.29 111.84,108.13 v2(116.82,108.13) 118.01,109.33 118.01,110.37 v2(118.04,110.39) 118.7,111.05 120.35,111.05 120.96,110.44 125.63,110.44 126.55,109.53 128.43,109.53 129.01,110.11 129.01,111.23 130.21,112.42 139.36,112.42 v3(141.79,114.85)
  IN2 w0.508: v2(77.37,100.59) 77.07,100.89 69.02,100.89 67.49,102.42 66.86,102.42 62.54,106.74 58.48,106.74 56.75,108.46 v2(55.89,108.46) ; v2(83.55,77.53) 83.55,77.96 84.13,78.54 84.13,83.24 83.14,84.23 83.14,88.35 v2(87.18,92.38)
  BOTTOM w0.203: UC1.AG14 148.05,88.16 147.65,88.56 147.65,89.3 v2(147.68,89.34)
  BOTTOM w0.254: UC1.AG17 146.82,86.85 v2(146.84,86.85) 146.84,86.85 UC1.AG16 ; 151.55,94.71 151.55,94.7 151.8,94.46 v2(151.8,94.24) ; 151.55,94.71 UC1.P9 ; 151.55,94.71 UC1.N8 ; UC1.AE9 UC1.AF9 151.16,87.65 v2(151.84,87.65) 151.84,87.46 151.55,87.17 UC1.AG8 ; UC1.AE8 151.55,88.38 v2(151.73,88.55) ; UC1.J11 UC1.H11 149.63,97.47 v2(149.33,97.77) ; UC1.K9 UC1.M9 150.66,95.67 UC1.L10 150.44,95.7 150.26,95.52 v2(150.26,95.26) 150.26,95.15 149.88,94.77 v2(149.88,94.64) ; UC1.J17 146.78,96.82 v2(146.45,97.14) ; v2(147.39,97.8) 147.73,97.47 UC1.H15 ; v2(143.88,87.33) 143.88,87.36 UC1.AF22 ; UC1.T21 144.45,93.02 v2(144.08,93.39) 144.45,93.76 UC1.R21 ; UC1.AG13 148.78,87.32 148.13,87.32 UC1.AG14
  BOTTOM w0.381: UC1.AC22 UC1.AE22 143.13,88.11 UC1.AE23 142.21,88.11 v2(141.92,87.81)
  BOTTOM w0.508: v2(59.11,111.41) 59.11,111.31 59.7,110.72 PC548.2 PR504.2 PR503.2 PR500.2 ; R2346.1 CC28.1 v2(116.82,108.13) ; v2(147.63,115.24) 147.67,115.21 148.57,115.21 L2.1 148.61,115.28 147.88,116.01 v2(147.63,116.01) ; R286.1 v2(118.04,110.39) ; v2(162.9,19.62) 164.64,19.62 165.41,18.85 165.41,8.82 v2(165.39,8.79) ; v2(143.19,114.28) 143.24,114.23 144.29,114.23 L1.1 144.09,114.94 143.08,114.94 143.08,114.94 v2(143.13,114.94) ; v2(185.35,81.08) 183.32,83.11 180.4,83.11 179.76,82.48 177.78,82.48 v2(177.73,82.53) 176.38,82.53 174.02,80.16 v2(174.02,78.03) ; v2(105.14,93.91) R253.2 R256.1 R252.1 105.52,91.22 104.1,89.79 RC130.2 104.04,88.19 v2(103.43,88.19) ; v2(96.32,108.89) 96.96,108.26 96.96,105.59 96.58,105.21 96.58,102.94 95.83,102.19 95.83,100.41 95.42,100 95.05,100 94.54,99.5 94.54,98.73 93.66,97.85 v2(93.66,96.96) 93.66,96.83 89.21,92.38 v2(87.18,92.38) 87.05,92.51 87.05,98.61 85.07,100.59 v2(77.37,100.59)
  vias: v2(111.44,97.16) v2(140.7,93.25) v2(141.66,91.19) v2(141.66,90.5) v2(142.47,114.91) v2(142.5,114.33) v2(146.19,88.33) v2(147,116.01) v2(147,115.24) v2(148.33,89.47) v3(141.46,118.42) v3(142.09,118.42) v3(142.73,118.42) v3(143.48,118.41) v3(144.15,118.41) v3(147.38,120.37) v3(148.14,120.32) v3(148.57,116.6) v3(148.9,120.32) v3(149.21,116.6) v3(149.66,120.32) v3(149.84,116.6) v3(150.3,120.32) v3(150.48,116.6) v3(151.06,120.32) v3(162.62,23.55) v3(162.62,22.92) v3(162.62,22.28) v3(163.25,23.55) v3(163.89,23.55)
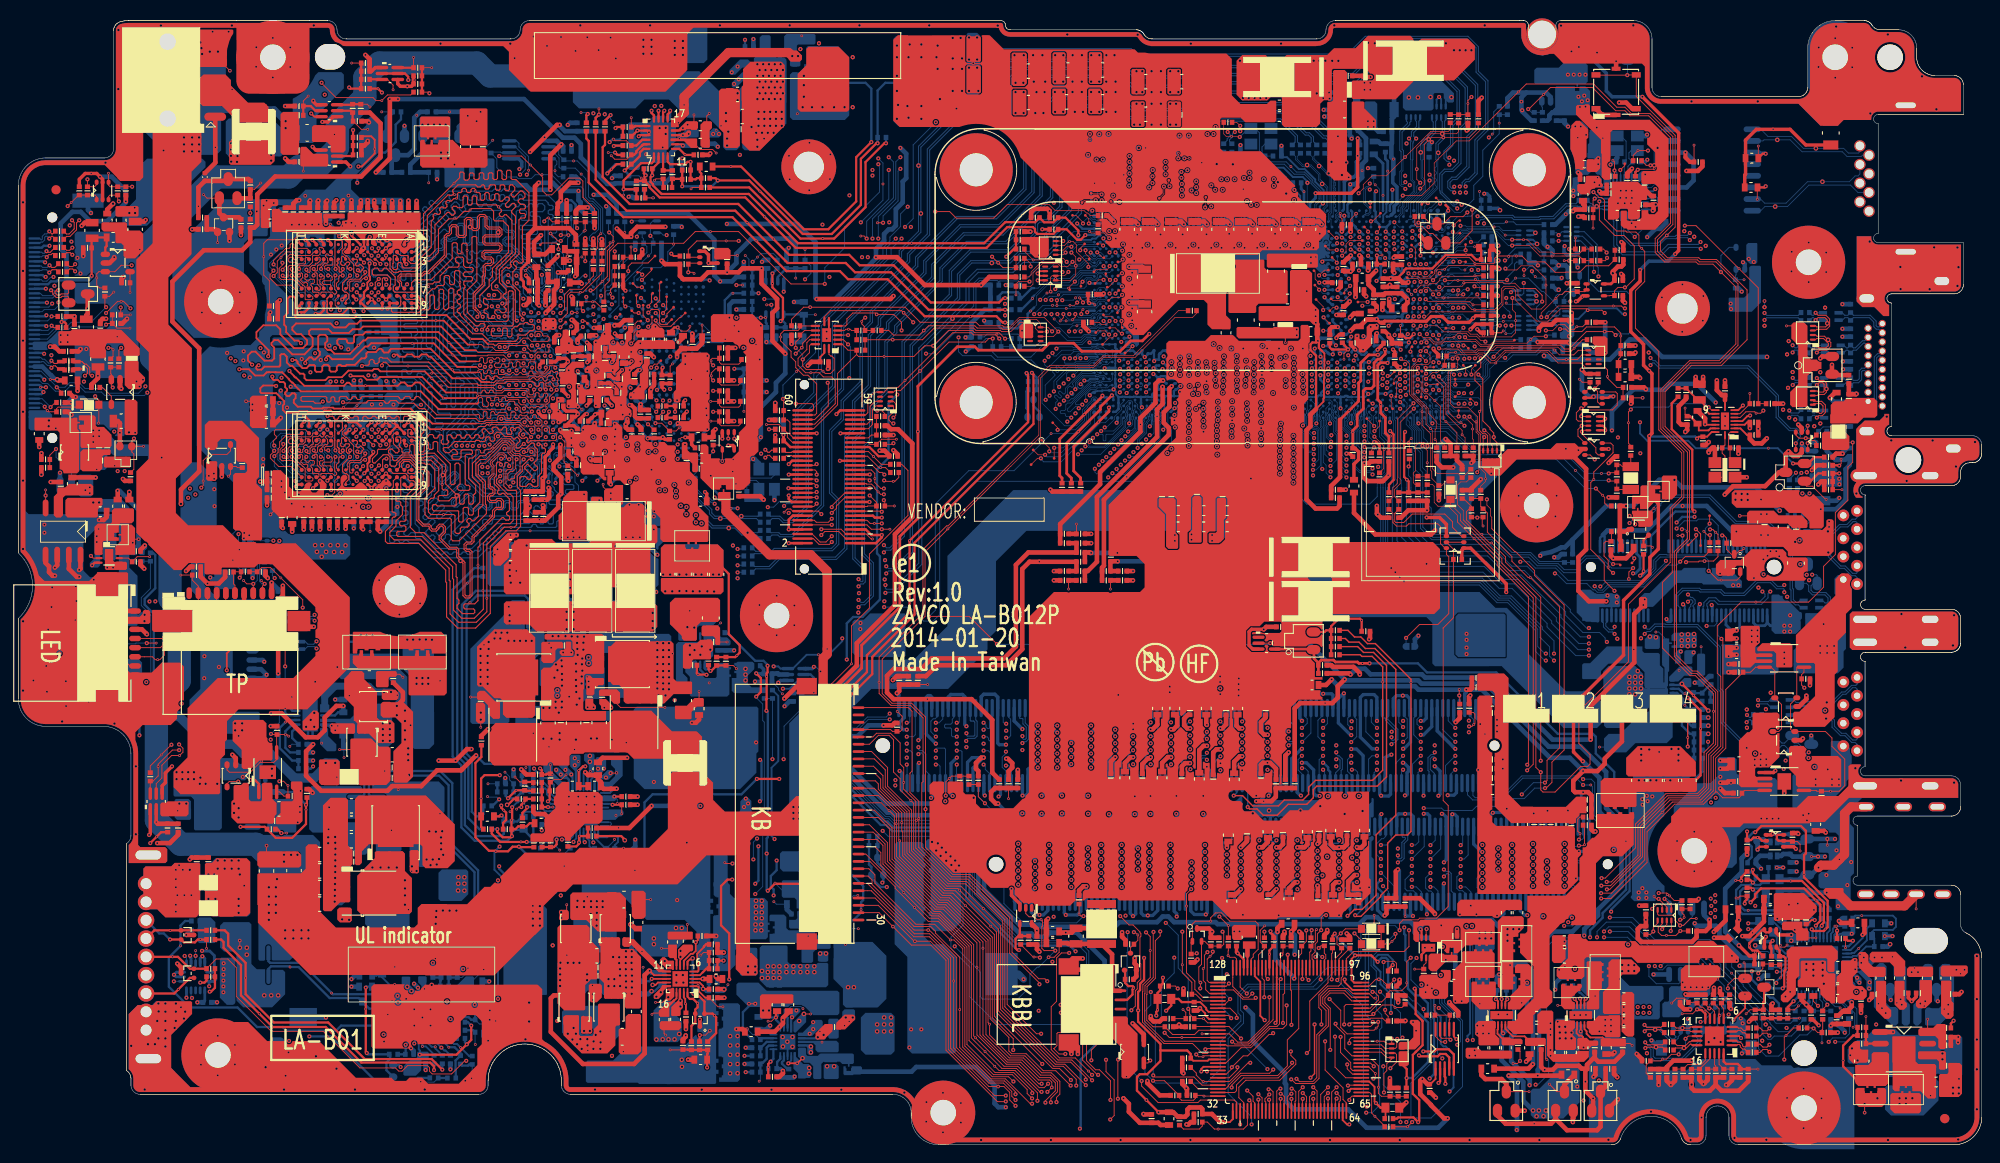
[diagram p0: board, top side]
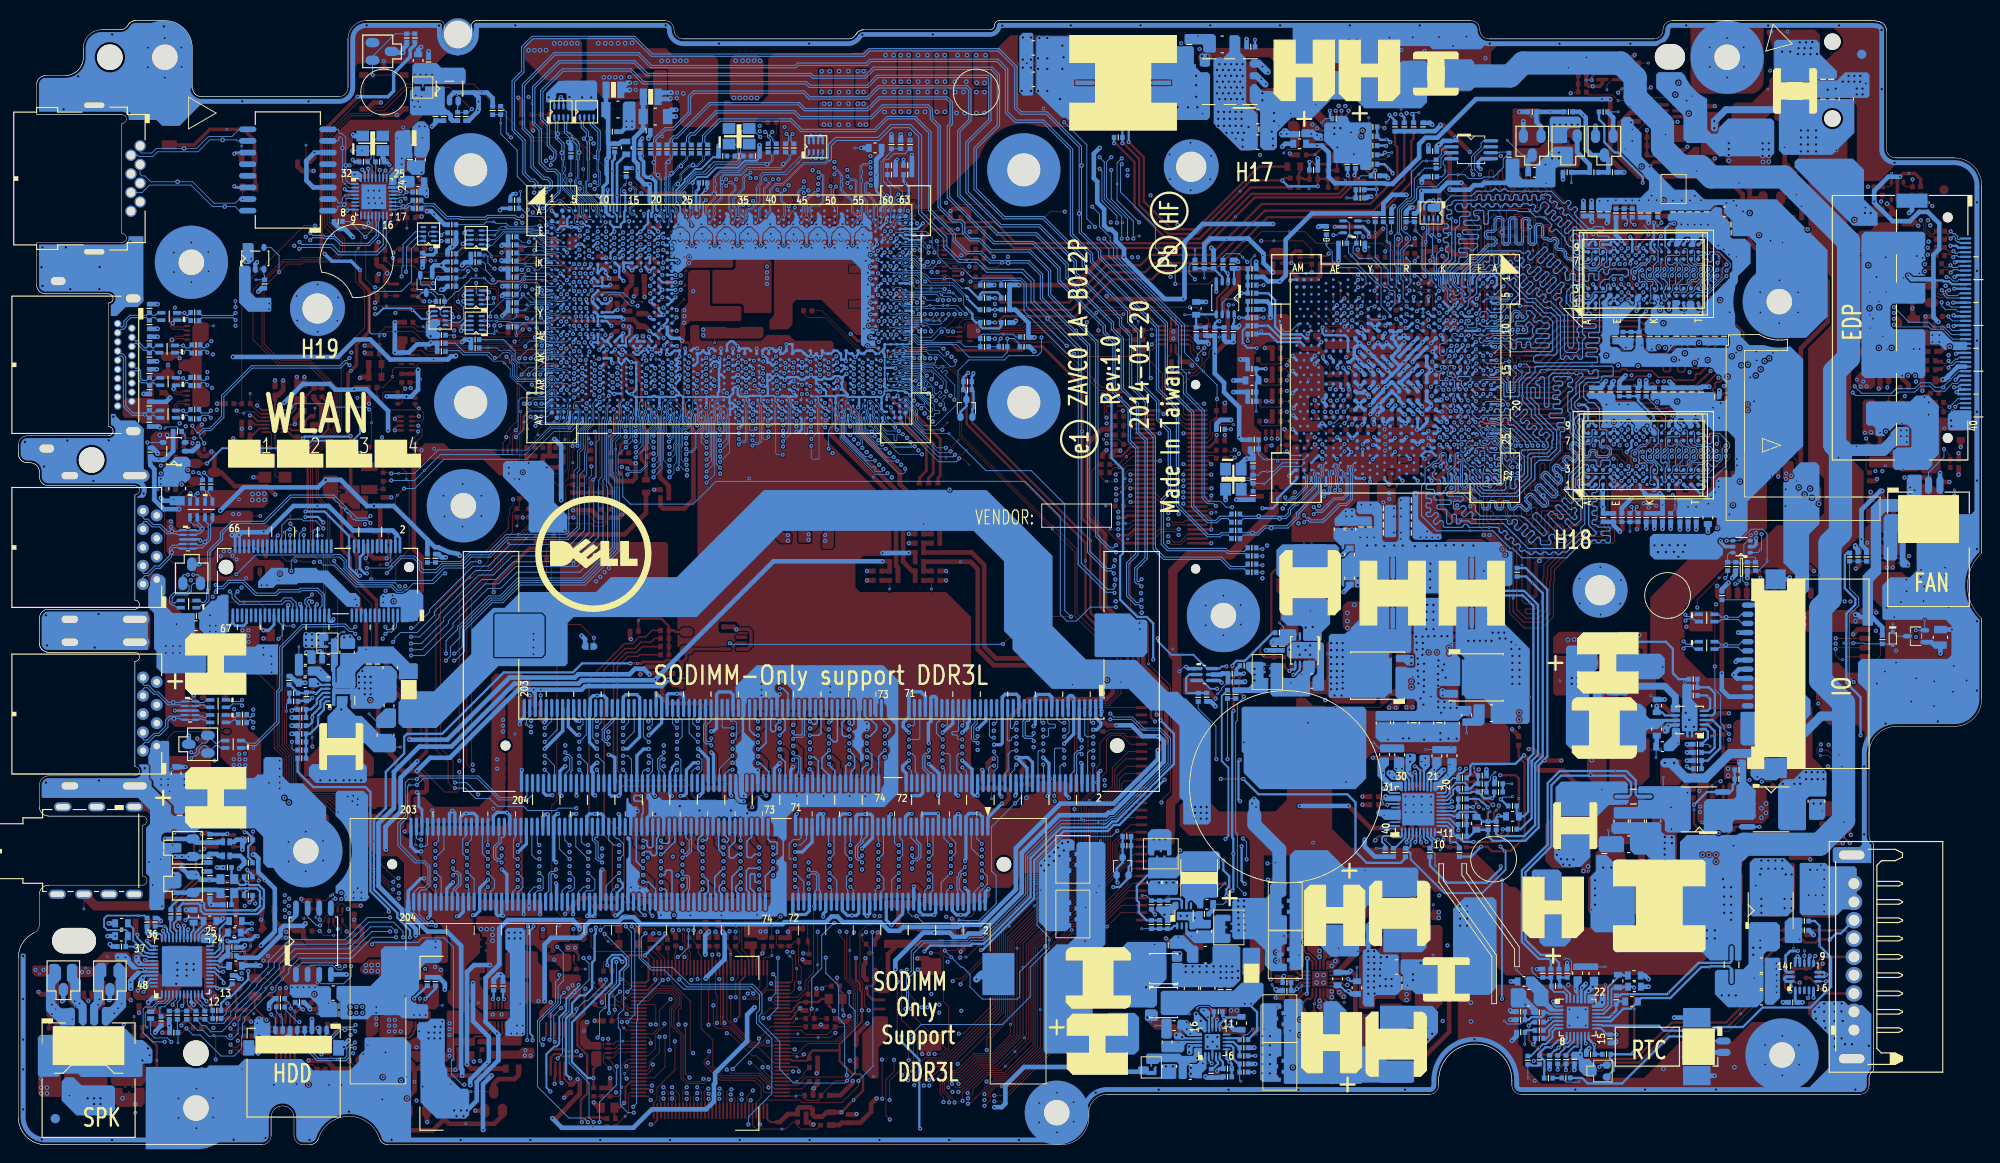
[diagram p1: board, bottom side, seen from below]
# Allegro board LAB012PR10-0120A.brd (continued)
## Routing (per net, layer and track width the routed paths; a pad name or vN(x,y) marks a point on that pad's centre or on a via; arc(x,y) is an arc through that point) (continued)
+1.5VSP: length 8.2
  TOP w0.254: PR400.1 PC403.1 200.37,11.93 199.27,10.82 v1(199.27,9.2) 199.27,8.56 200.79,7.04
  TOP w0.508: 200.79,7.04 201.61,7.04
+1.05VSP: length 11.6
  TOP w0.254: 183.13,39.77 183.7,40.34 v1(183.7,45.44) 183.7,47.43 v2(182.3,48.82)
  BOTTOM w0.254: PC307.1 183.83,48.49 PR305.1 182.63,48.49 v2(182.3,48.82)
  vias: v3(176.97,39.81) v3(177.6,39.81) v3(178.24,39.81) v3(178.87,39.81) v3(179.76,39.81) v3(180.4,39.81) v3(181.41,39.81)
+1.8VGS: length 115.6
  TOP w0.305: 55.68,96.45 54.91,95.67 54.91,94.56 55.17,94.29 55.17,93.78 55.68,93.27 LV7.1
  TOP w0.508: v2(69.14,37.01) 66.73,34.6 PR1022.1 ; v2(56.83,105.08) 56.42,104.68 56.42,100.13 ; 56.42,100.13 55.68,99.39 55.68,96.45 ; 56.42,100.13 60.14,100.13 60.89,99.38 LV6.1
  IN1 w0.381: v2(74.48,37.01) 74.61,37.01 75.55,37.95 75.55,50.17 74.61,51.11 74.61,52.25 76.26,53.9 76.26,54.79 77.15,55.68 77.15,65.33 75.35,67.13 75.35,70.78 75.62,71.05 v2(75.62,73.08)
  IN1 w0.508: v2(77.65,90.35) 77.65,93.3 v2(76.64,94.31)
  IN2 w0.508: v2(62.82,103.78) 62.81,103.76 61.6,103.76 v2(61.17,104.2)
  BOTTOM w0.254: U1.8 81.63,89.8 81.72,89.72 CV170.2
  BOTTOM w0.305: UV1.AM30 75,73.7 v2(75.62,73.08)
  BOTTOM w0.508: CV170.2 81.26,89.29 v2(81.08,89.46) ; v2(80.96,85.78) 80.14,85.78 LV2.1 ; v2(62.82,103.78) 64.36,103.78 65.33,102.8 RV82.2 RV81.2 73.13,101.73 76,98.86 76,94.95 v2(76.64,94.31) 77.93,94.31 78.42,94.8 RV84.2 ; v2(77.65,90.35) 77.65,91.75 78.03,92.13 RV87.2 ; v2(69.14,37.01) v2(74.48,37.01) ; v2(56.83,105.08) 58.35,105.08 59.24,104.2 v2(61.17,104.2) 61.17,103.18 61.4,102.95 61.4,102.14 61.8,101.73 RV152.2
  vias: v4(78.67,88.85)
+1.8VS: length 44
  TOP w1.016: 88.6,34.24 88.58,34.27 88.58,37.32 87.89,38 87.89,53.15 88.32,53.59 v1(88.32,54.16) 88.32,62.66 86.54,64.44 82.03,64.44 77.27,69.2 77.27,70.54
  vias: v3(89.15,33.36) v3(89.79,33.36) v3(90.43,33.35)
+1.8VSP: length 7.5
  BOTTOM w0.254: 90.89,29.41 91.1,29.41 92.26,28.25 92.26,26.73 92.03,26.5 v1(92.03,25.68) 92.03,25.36 91.18,24.51 PC604.1 PR603.1
+1.8VSP_ON: length 5.3
  BOTTOM w0.102: PR601.1 91.22,27.23 v1(91.67,27.23)
  BOTTOM w0.254: PR601.1 PR604.1 PC603.1 88.7,26.85 87.56,26.85 87.35,26.64 PU600.7
+1.35V: length 88.8
  TOP w0.508: RD3.1 102.8,38.35 103.25,37.9 v3(104.32,37.9) ; RC16.1 RC15.1 117,64.7 117.05,64.65 v2(117.15,64.65)
  BOTTOM w0.076: UC1.AY50 126.11,79.14 v2(126.25,79.14)
  BOTTOM w0.254: UC1.AY35 135.26,79.38 135.26,78.7 135.52,78.45 135.55,78.45 v2(135.72,78.28) ; UC1.AH26 140.69,86.98 v2(140.27,86.98) ; UC1.AR48 127.01,82.25 v2(126.85,82.25) ; v2(133.77,86.98) UC1.AJ37 ; v2(136.37,86.98) UC1.AJ33 ; UC1.AY44 128.86,79.28 128.86,78.11 129.09,77.89 v2(129.42,77.89) ; v2(132.54,79.12) 132.43,79.24 132.4,79.24 132.38,79.26 132.29,79.26 UC1.AY40 ; v2(129.75,83.41) 129.97,83.41 130.21,83.17 UC1.AP43 ; v2(135.8,84.09) 135.93,84.09 136.2,83.82 UC1.AN33 ; v2(137.67,86.98) UC1.AJ31
  BOTTOM w0.356: JDIMM1.99 127.95,49.52 127.43,50.04 125.74,50.04 v2(125.74,50.04) ; v2(131.25,49.22) 131.55,48.92 JDIMM1.111 ; JDIMM1.87 124.35,48.86 124.92,49.43 v2(125.74,49.43) 125.76,49.43 126.15,49.04 JDIMM1.93 ; JDIMM2.123 147.52,35.95 147.02,36.45 v3(146.79,36.45) ; JDIMM2.88 137.02,25.44 137.4,25.06 v2(137.63,25.06) 138.49,25.06 138.82,25.39 JDIMM2.94 ; JDIMM2.93 138.52,36.16 138.87,36.5 v3(140.01,36.5) 140.32,36.19 JDIMM2.99 ; v3(136.58,36.5) 136.72,36.36 JDIMM2.87 ; v2(133.26,49.07) 133.35,48.98 JDIMM1.117 ; v2(144.22,25.07) JDIMM2.112 ; JDIMM2.105 142.12,36.93 v3(142.17,36.98) ; v2(121.74,46) 122.07,46 122.55,46.47 JDIMM1.81 122.55,48.85 122.56,48.86 ; v2(131.26,41.67) 131.85,41.08 JDIMM1.112 ; JDIMM1.105 129.75,50.69 130.32,51.26 131.13,51.26 v2(131.23,51.16) ; v2(123.63,38.09) 123.09,38.09 122.85,38.33 JDIMM1.82 ; 135.22,25.31 JDIMM2.82 ; JDIMM1.94 126.45,38.11 v2(126.46,38.1) 124.9,38.1 124.65,38.35 JDIMM1.88 ; JDIMM1.100 128.25,38.37 128.52,38.1 v2(129.39,38.1) ; v2(129.79,41.29) 129.79,41.23 130.05,40.93 JDIMM1.106 ; JDIMM1.118 133.65,40.57 v2(133.64,40.91) ; v2(146.52,28.03) 146.52,27.97 146.02,27.48 JDIMM2.118 ; JDIMM2.106 142.42,25.49 141.99,25.06 v2(141.01,25.06) 140.96,25.06 140.62,25.39 JDIMM2.100 ; JDIMM2.117 145.72,35.73 145.32,36.13 v3(144.84,36.13) 144.37,36.13 143.92,35.68 JDIMM2.111 ; JDIMM2.76 133.42,25.41 v2(133.72,25.11) ; JDIMM2.75 133.12,35.68 133.64,36.2 v3(134.8,36.2) 134.92,36.08 JDIMM2.81 ; JDIMM1.76 121.05,38.27 121.26,38.06 121.89,38.06 121.9,38.05 v2(121.93,38.05)
  BOTTOM w0.381: 147.78,27.84 v2(147.5,28.12) ; 147.82,27.84 JDIMM2.124
  BOTTOM w0.508: v2(120.02,64.65) v2(117.15,64.65)
  vias: v2(120.11,49.14) v2(121.73,45.38) v2(131.23,50.55) v2(133.28,50.93) v2(133.26,50.32) v2(133.26,49.69) v2(135.18,38.13) v3(99.78,33.08) v3(100.23,32.14) v3(100.41,32.92) v3(100.72,31.55) v3(100.84,32.45) v3(101.3,31.94) v3(101.33,31.02) v3(101.8,31.5) v3(101.89,30.56) v3(102.3,31.04) v3(102.37,29.95) v3(102.72,30.5) v4(134.6,72.78)
+1.35VGPUP: length 14.3
  BOTTOM w0.254: PR1107.2 33.08,50.86 33.72,51.5 33.72,54.17 34.5,54.94 41.69,54.94 42.6,54.03
  vias: v1(46.06,50.68) v3(43.49,50.98) v3(43.49,50.35) v3(44.13,50.98) v3(44.13,50.35) v3(44.76,50.98) v3(44.76,50.35)
+1.35VGPUP_B+: length 2.4
  TOP w0.102: PQ1100.5 v1(35.08,43.16)
+1.35VP: length 32.5
  TOP w0.508: PC214.2 83.11,7.42 83.5,7.8 v2(83.5,8.06)
  IN2 w0.254: v2(97.31,10.62) 96.02,9.33 86.23,9.33 85.71,8.8 85.13,8.8 84.57,9.37 83.87,9.37 83.5,9 v2(83.5,8.06)
  IN2 w1.016: v3(86.54,10.72) 86.92,10.34 95.1,10.34 97.36,12.6 v2(97.49,12.6) v2(98.61,12.6)
  BOTTOM w0.254: PR207.2 82.86,8.36 82.86,9.04 83.2,9.38 PU200.5
  BOTTOM w0.381: PR207.2 83.24,8.31 v2(83.5,8.06)
  vias: v1(96.37,28.25) v3(86.54,10.09)
+1.35VS_VGA: length 97.4
  TOP w0.102: v4(27.54,68.85) 28.03,69.35
  TOP w0.203: UV7.G7 38.11,93.58 38.11,94.17 38.41,94.47 38.41,94.83 38.32,94.92 38.32,96.23 v2(38.36,96.27) ; UV6.G7 38.13,73.74 38.13,74.4
  TOP w0.254: UV7.R1 31.75,98.46 v2(31.36,98.85) ; v2(32.97,98.85) 33.35,98.47 UV7.N1 ; UV7.A8 43.57,92.73 v2(44.02,92.28) ; UV7.C9 UV7.D9 40.55,91.57 v2(40.32,91.34) ; UV6.C9 41.35,71.45 v2(41.35,71.45) ; UV7.R9 31.75,91.44 31.25,90.94 30.84,90.94 v2(30.71,90.81) ; UV6.R9 31.72,72.12 v2(30.64,71.04) ; v2(32.94,78.13) 33.33,78.52 UV6.N1 ; v2(43.74,72.24) 43.74,72.6 43.42,72.92 UV6.A8 ; v2(39.36,78.94) 38.95,78.53 UV6.F1 ; UV6.C1 41.38,78.52 42.15,77.75 UV6.B2 ; UV6.C1 41.35,78.54 v2(40.95,78.94) ; UV6.C1 UV6.D2 ; v2(38.76,75.68) 38.76,75.5 38.33,75.07 38.33,75 38.33,74.6 38.13,74.4 ; v2(32.94,72.51) 33.33,72.12 UV6.N9 ; UV6.H2 37.35,77.79 v2(37.69,78.12) ; UV6.G7 v2(37.78,73.35) ; UV7.E9 39.75,91.38 v2(39.71,91.34) 38.07,91.34 37.48,91.93 UV7.H9 37.35,92.12 37.75,92.52 37.75,93.14 38.14,93.53 UV7.G7 ; v2(43.49,77.92) 42.95,78.46 UV6.A1 ; UV7.K8 35.75,92.72 v2(35.37,92.34) ; UV6.K2 35.79,77.72 v2(36.17,78.1) ; UV6.R1 31.75,79.14 v2(31.24,79.64) ; UV7.N9 33.35,91.16 32.95,90.76 v2(32.47,90.76)
  TOP w0.381: CV42.1 56.93,85.2 v2(56.93,84.91) ; CV160.1 27.41,90.83 v2(27.52,90.94)
  TOP w0.508: v2(34.73,103.18) 34.48,102.93 34.48,102.37 RV51.1 ; CV45.1 CV44.1 CV43.1 28.05,78.8 v2(28.66,79.41)
  IN1 w0.508: v2(35.77,100.72) 35.77,101.46 34.73,102.5 v2(34.73,103.18) ; v2(36.63,67.33) 36.63,69.35 v2(36.38,69.6)
  IN2 w0.254: v2(43.74,72.24) 43.08,72.24 42.98,72.34 42.25,72.34 v2(41.35,71.45) ; v2(40.32,91.34) 40.78,91.8 42.7,91.8 42.98,91.52 v2(42.98,91.38)
  BOTTOM w0.254: UV7.R1 31.75,98.46 v2(31.36,98.85) ; v2(38.36,96.27) 38.36,96.52 UV8.G7 ; v2(38.76,75.68) 38.76,75.68 38.25,76.2 38.25,76.82 38.15,76.92 UV5.G7 ; v2(32.94,72.51) 33.33,72.12 UV6.N9 ; UV6.R9 31.72,72.12 v2(30.64,71.04) ; v2(41.35,71.45) 41.35,71.45 UV6.C9 ; UV8.A8 42.95,97.53 43.28,97.53 43.74,97.99 43.74,98.71 v2(43.59,98.86) ; v2(57.6,90.05) 57.65,90.05 58,89.7 UV1.J9 ; UV1.J10 58,88.9 57.65,89.25 v2(57.6,89.25) ; UV1.K24 v2(58.4,77.3) ; v2(44.02,92.28) 43.77,92.28 43.41,91.93 42.96,91.93 UV8.A1 ; v2(39.37,71.64) 39.37,71.7 UV5.F1 ; UV7.K2 36.15,97.93 36.15,98.5 35.81,98.84 35.81,100.58 35.77,100.61 v2(35.77,100.72) ; UV1.J23 v2(57.6,78.1) UV1.J24 ; UV8.E9 39.79,98.33 v2(40.28,98.82) 40.55,98.55 UV8.D9 UV7.C1 ; UV5.H2 v2(37.78,73.35) ; v2(58.39,78.1) 58.79,78.5 UV1.K23 ; UV7.K8 35.75,92.7 35.73,92.7 v2(35.37,92.34) ; UV7.N1 33.35,98.47 v2(32.97,98.85) ; UV6.K8 35.35,72.52 35.35,71.84 35.68,71.51 v2(35.8,71.51) ; UV1.K10 58.8,88.9 58.45,89.25 v2(58.4,89.25) ; v2(56.67,87.35) 56.67,87.23 UV1.H13 ; UV5.B2 UV5.A1 43.62,72.12 v2(43.74,72.24) ; v2(42.98,91.38) 42.95,91.41 UV8.A1 ; UV8.B2 42.15,92.58 42.79,91.93 UV8.A1 ; UV5.A8 43.28,77.72 v2(43.49,77.92) 43.49,78.35 43.49,78.35 43.49,78.67 42.98,79.18 42.98,80.45 43.36,80.83 v2(43.97,80.83) ; v2(40.16,72.51) 40.55,72.91 UV5.D2 ; UV8.H9 37.35,98.26 v2(37.67,97.94) ; UV1.K9 58.8,89.7 58.45,90.05 v2(58.4,90.05)
  BOTTOM w0.305: UV1.L21 59.6,80.3 59.39,80.09 v2(58.97,80.09) ; v2(56.8,81.3) 57.2,81.7 UV1.H19 ; UV1.L22 59.6,79.3 59.25,78.95 v2(59,78.95) ; UV1.H16 56.93,84.57 v2(56.93,84.91) ; UV1.L11 59.6,88.09 v2(60.13,87.56) ; UV1.L13 59.6,86.24 v2(59.98,86.62) 59.6,86.99 UV1.L12
  BOTTOM w0.381: v2(58.98,81.39) 59.07,81.3 UV1.L20
  BOTTOM w0.508: CV139.1 CV140.1 v2(36.38,100.72) ; CV180.1 CV158.1 42.6,100.89 v2(42.54,100.83) ; v2(41.35,71.45) 41.39,71.42 v2(41.39,69.68) 41.33,69.62 CV107.1 CV122.1 ; RV42.1 v2(36.63,67.33) ; v2(37.37,83.47) 37.37,82.83 RV43.1 ; CV161.1 CV162.1 40.82,100.81 v2(40.95,100.69)
  vias: v2(22.79,86.5) v2(24.61,86.67) v2(24.57,85.68) v2(25.28,83.83) v2(26.74,74.9) v2(26.72,74.22) v2(26.82,86.55) v2(27.59,97.24) v2(28.17,97.79) v2(28.49,81.02) v2(28.74,72.5) v2(28.73,71.86) v2(28.76,98.23) v2(29.11,71.25) v2(29.34,80.52) v2(29.57,70.72) v2(29.87,100.5) v2(29.85,70.03) v2(30.66,100.52) v2(30.95,85.84) v2(31.19,69.69) v2(31.35,100.51) v2(32.09,100.51) v2(32.06,69.67) v2(32.8,100.53) v2(33.02,85.72) v2(35.55,69.8) v2(36.9,70.05) v2(38.61,80.86) v2(39.59,80.88) v2(40.97,80.85) v2(42.41,99.48) v2(55.83,69.76) v3(32.41,65.49) v3(32.6,64.77) v3(33.13,64.23) v3(33.18,65.49) v3(33.61,64.77) v3(34.08,65.49) v3(34.48,64.74) v3(34.89,65.49) v3(35.35,64.74) v3(35.73,65.47) v3(37.39,55.68) v3(38.03,55.68) v3(38.66,55.68) v3(42.47,55.17) v3(43.11,55.17) v3(43.82,55.19) v3(44.51,55.19) v3(45.17,55.16)
+3V_DSW: length 221
  TOP w0.305: v2(89.68,46.37) 89.68,46.42 89.59,46.51 89.59,49.56 92.09,52.06 92.09,54.56 96.26,58.72 96.26,66.46 98.23,68.43 v4(98.23,77.91) 98.23,82.86 102.55,87.18 104.45,87.18 104.83,86.8 111.82,86.8 112.58,87.56 115.25,87.56 116.13,86.67 120.3,86.67 121.44,87.81 122.74,87.81 v2(123.5,88.57)
  TOP w0.381: C5215.2 144.27,88.52 143.93,88.19 v2(143.93,88.12) ; v2(150.12,86.87) 150.09,86.85 150.3,86.64 C81.1 ; v2(154.54,86.97) 154.54,86.85 155.05,86.34 RC105.2
  TOP w0.508: RC39.1 156.41,75.24 ; 156.41,75.24 156.41,76.55 v2(155.86,77.09) ; 156.41,75.24 RC31.1 157.1,74.76 157.66,74.19 RC34.1 ; RC32.1 v2(155.12,70.41)
  IN1 w0.305: v2(123.5,88.57) 123.96,88.12 137.16,88.12 137.6,87.69 140.93,87.69 141.58,88.34 143.04,88.34 143.26,88.12 v2(143.93,88.12) 144.53,88.12 145.09,87.56 147.22,87.56 147.73,87.05 147.73,86.26 148.24,85.75 149,85.75 v2(150.12,86.87) 150.64,87.4 151.32,87.4 151.54,87.17 154.34,87.17 v2(154.54,86.97) ; v2(155.89,20.2) 155.66,20.43 153.6,20.43 152.79,21.24 151.62,21.24 150.93,20.55 148.09,20.55 147.39,19.86 143.74,19.86 142.6,21 141.42,21 140.19,19.76 135.64,19.76 135.39,19.51 121.18,19.51 120.66,20.03 117.72,20.03 116.63,21.12 v2(115.45,21.12)
  IN1 w0.508: v2(155.86,77.09) 155.75,77.21 149.46,77.21 149.03,77.64 149.03,78.71 148.65,79.09 148.65,81.34 148.24,81.74 148.24,85.75
  BOTTOM w0.254: v2(89.68,46.37) 88.21,44.9 88.21,41.58 94.48,35.31 94.93,35.31 95.59,34.65 100.51,34.65 103.86,31.3 103.86,27.06 108.97,21.95 110.24,21.95 110.45,21.75 114.83,21.75 v2(115.45,21.12) ; UC1.AH10 150.43,86.56 v2(150.12,86.87)
  BOTTOM w0.508: v2(155.86,77.09) 155.12,76.35 v2(155.12,70.41)
+3VALW: length 314.9
  TOP w0.203: UG1.2 188.05,78.25 188.78,77.53 CG10.1
  TOP w0.508: CG10.1 189.08,77.09 189.57,76.61 190.38,76.61 v2(190.94,77.17) ; RE330.1 v2(10.85,71.43) ; v2(120.68,5.06) 120.68,5.06 121.27,4.47 121.27,3.59 122.47,2.39 CE61.2 124.49,2.39 124.74,2.15 RE327.2 ; PR115.2 v2(76.2,22.8) ; v3(17.76,70.01) 17.76,71.57 19.75,73.56 19.75,86.99 16.83,89.92 16.83,94.28 20.26,97.72 24.44,97.72 25.33,98.61 PR3.2 25.76,100.18 26.09,100.51 26.09,103.81 28.05,105.77 37.45,105.77 39.55,107.88 39.55,111.57 38.37,112.75 PR28.1
  IN1 w0.254: 79.3,36.25 79.3,34.98 77.02,32.69 63.56,32.69 63.3,32.44 55.48,32.44 54.97,31.93 51.11,31.93 50.09,32.95 50.09,38.28 46.79,41.58 46.79,48.19 45.52,49.46 41.84,49.46 40.19,51.11 32.57,51.11 30.28,53.4 30.28,58.6 29.01,59.87 24.14,59.87 17.96,66.04 17.96,68.79 17.76,68.99 v3(17.76,70.01)
  IN1 w0.762: v2(170.92,4.83) 171.76,3.99 174.94,3.99 176.08,5.14 181.55,5.14 182.2,5.78 187.39,5.78 188.14,6.53 192.97,6.53 193.6,7.17 203.43,7.17 205.7,4.91
  IN1 w1.524: 79.43,49.59 79.43,38.41
  IN2 w0.762: v3(17.76,70.01) 11.94,70.01 10.85,71.1 v2(10.85,71.43)
  IN2 w1.524: 184.23,55 184.23,51.72 185.69,50.26 185.69,43.77 187.13,42.33 187.13,38.03 184.71,35.62 181.41,35.62 179.56,33.76 179.56,30.69 182.28,27.97 182.28,27.91 182.35,27.83 182.35,25.62 183.06,24.91 v2(183.06,24.19) 183.06,21.06 180.09,18.09 180.09,16.57 179.14,15.61
  BOTTOM w0.508: v2(196.83,69.43) 198.52,69.43 199.54,70.45 199.54,73.8 199.98,74.24 CM8.2 199.86,75.2 199.48,74.82 UM1.5 198.45,74.82 197.49,75.78 RM10.1 ; v2(10.85,71.43) 11.06,71.43 13.13,69.36 13.13,65.52 12.58,64.98 RE332.2 ; RL40.1 187.81,93.58 v2(188.19,93.2) ; RA10.1 190.35,20.43 188.22,20.43 185.76,22.89 185.76,23.55 185.4,23.91 183.29,23.91 183.06,24.13 v2(183.06,24.19)
  BOTTOM w1.524: 79.43,36.07 79.43,34.98 76.7,32.25 76.7,28.47 76.66,28.43
  vias: v2(79.24,36.89) v2(79.44,37.81) v2(79.69,37.28) v2(152.3,13.39) v2(159.31,13.01) v2(159.31,12.15) v2(159.95,13.01) v2(159.95,12.15) v2(160.58,12.15) v2(169.22,116.9) v2(169.86,116.9) v2(170.49,116.9) v2(171.13,116.9) v2(172.65,12.37) v2(173.28,13.64) v2(173.28,13.01) v2(173.28,12.37) v2(173.92,13.64) v2(173.92,13.01) v2(173.92,12.37) v2(176.84,15.04) v2(176.84,14.41) v2(177.48,15.04) v2(177.48,14.41) v2(178.11,15.04) v2(178.11,14.41) v2(181.64,54.49) v2(188.97,96.77) v2(189.52,96.44) v3(79.41,51.99) v3(79.41,51.35) v3(79.41,50.72) v3(80.55,26.65) v3(80.55,26.01) v3(80.55,25.38) v3(80.55,24.74) v3(80.5,24.05) v3(80.5,23.42) v3(81.13,24.05) v3(81.13,23.42) v3(81.18,26.65) v3(81.18,26.01) v3(81.18,25.38) v3(81.18,24.74) v3(159.57,23.17) v3(159.57,22.53) v3(160.2,23.17) v3(160.2,22.53) v3(160.84,23.17) v3(160.84,22.53) v3(181.64,55.73) v3(181.64,55.1) v3(182.33,55.76) v3(182.33,55.12) v3(182.3,54.46) v3(182.99,55.78) v3(182.99,55.15) v3(182.99,54.51) v3(187.53,71.12) v3(187.51,70.46) v3(188.19,71.1) v3(188.17,70.44) v3(188.83,71.07) v3(188.86,70.44) v3(205.43,5.07) v3(205.43,4.44) v3(206.13,5.07) v3(206.13,4.44) v3(206.83,5.07) v4(152.63,12.45) v4(155.38,23.96) v4(190.3,70.49)
+3VALW_EC: length 300.5
  TOP w0.203: 131.55,2.47 132.29,2.47 132.62,2.8 UE1.33 ; UE1.96 145.86,17.71 145.59,17.98 145.59,20.29 v2(145.97,20.68) ; CE6.2 129.06,15.57 129.72,14.91 129.72,14.76 129.98,14.51 UE1.9 ; CE2.1 128.3,9.17 129.88,9.17 130.01,9.31 UE1.22
  TOP w0.254: v2(122.93,20.41) 122.93,18.02 122.5,17.59 122.5,16.9 122.28,16.68 v2(122.28,14.67) 122.28,13.44 124.72,11 124.72,10.32 ; v2(145.97,20.68) 147.74,20.68 v2(148.44,19.98) ; 124.72,10.32 124.75,10.29 127.64,10.29 128.02,9.91 CE2.1 ; 124.72,10.32 124.72,9.15 123.27,7.7 122.46,7.7 122.15,7.4 122.15,5.91 v4(123.19,4.87) v2(124.52,3.55) ; RE3.2 151.58,6.21 151.58,7.26 v2(151.61,7.28) 151.61,8.27 151.06,8.82 150.88,8.82 ; v2(19.87,17.71) 20.33,17.71 20.55,17.94 PR16.2 ; UE1.125 133.82,20.24 v2(133.15,20.91) ; v2(125.34,14.63) 125.9,15.19 LE1.1 126.69,15.93 127.05,15.57 CE6.2 ; RE73.1 143.51,22.81 v2(143.76,23.06)
  TOP w0.381: v2(133.15,20.91) 133.03,21.04 CE5.2
  TOP w0.508: JLED.3 13.09,56.3 13.5,56.3 13.96,55.84 13.96,55.84 v2(14.04,55.76) ; 131.55,2.47 131.22,2.47 130.33,3.36 CE1.1 129.29,3.89 129.11,4.07 127.9,4.07 127.67,3.84 127.67,3.31 127.41,3.05 RE8.2 126.61,3.05 126.12,3.55 RE327.1 v2(124.52,3.55) ; RE328.1 139.36,23.64 v2(138.99,23.27) RE71.1
  IN2 w0.254: v2(125.34,14.63) 125.34,14.63 125.3,14.67 125.14,14.83 122.44,14.83 v2(122.28,14.67) ; v2(145.97,20.68) 142.87,20.68 142.58,20.97 141.45,20.97 140.93,20.45 139.68,20.45 v2(139.38,20.76) 138.77,21.37 137.41,21.37 136.95,20.91 v2(133.15,20.91) 131.3,20.91 130,19.61 126.2,19.61 125.77,20.03 125.3,20.03 125.02,20.31 123.02,20.31 v2(122.93,20.41)
  IN2 w0.508: 15.94,45.83 12.33,49.44 12.33,54.06 v2(14.04,55.76) ; 15.94,45.83 17.02,45.83 20.88,41.97 24.39,41.97 27.27,39.08 29.67,39.08 30.24,39.65 46.69,39.65 47.3,39.04 47.3,32.31 52.51,27.11 55.45,27.11 58.55,30.21 76.59,30.21 77.74,31.35 78.67,31.35 79.71,30.31 90.43,30.31 96.69,24.05 100.81,24.05 106.48,18.38 106.48,15.47 106.48,15.47 106.48,15.04 107.12,14.41 107.12,3.89 107.52,3.48 121.52,3.48 122.25,2.75 123.72,2.75 v2(124.52,3.55) ; 15.94,45.83 15.94,37.51 20.12,33.33 20.12,23.3 20.72,22.7 20.72,18.56 v2(19.87,17.71)
  BOTTOM w0.254: v2(143.76,23.06) 143.76,22.9 v2(145.97,20.68) ; v2(151.61,7.28) 152.2,7.28 153.94,9.02 153.94,13.35 149.58,17.71 149.58,20.18 149.35,20.41 148.88,20.41 v2(148.44,19.98)
  BOTTOM w0.508: v2(138.99,23.27) 139.4,22.86 139.4,20.96 139.38,20.93 v2(139.38,20.76)
+3VALW_PCH: length 328
  TOP w0.254: RP40.7 173.03,79.05 v2(173.28,79.3) 173.04,79.54 RP40.8 ; RP40.6 173.03,78.55 173.28,78.29 v2(173.28,78.05) RP40.5
  TOP w0.356: RC127.1 159.14,90.56 v2(158.87,90.29) 158.43,89.84 156.14,89.84 155.5,90.48 154.28,90.48 153.77,89.96 152.58,89.96 152.56,89.99 152.15,89.99 152.13,89.96 151.5,89.96 151.49,89.97 149.21,89.97 C68.1 148.71,89.79 v2(148.32,90.19)
  TOP w0.381: QH1.5 v2(173.67,76)
  TOP w0.508: RC120.1 v2(173.28,89.84) ; v2(145.47,88.89) 145.98,89.4 C78.1 147.24,90.15 C75.2 148.28,90.15 v2(148.32,90.19) ; v2(184.66,24.57) 184.69,24.54 184.69,23.78 184.26,23.35 R2334.1 183.27,22.66 182.76,22.15 177.22,22.15 176.84,22.53 176.84,23.55 177.17,23.88 R2335.1 v2(177.73,24.57) C2327.1 ; v2(169.35,87.61) 169.27,87.69 v2(165.92,87.69) ; v2(156.69,73.99) 155.45,73.99 154.88,74.56 RC29.1 ; v2(89.96,43.08) 89.05,44 89.05,49.83 91.56,52.34 91.56,54.78 95.73,58.95 95.73,66.68 97.63,68.58 97.63,76.6 96.07,78.16 95.31,78.16 94.93,78.54 RC64.2 ; RC125.1 R2330.1 158.88,74.67 v2(158.68,74.48) ; v2(159.7,72.7) 158.68,71.68 RC28.1 RC27.1 ; v2(173.41,59.36) 171.51,59.36 170.36,60.51 170.36,64.19 171.2,65.03 171.2,73.83 169.6,75.43 ; v2(154.71,67.11) 154.27,66.67 148.2,66.67 145.85,69.02 R264.1
  IN1 w0.508: v2(173.67,76) 173.28,76.38 v2(173.28,78.05) v2(173.28,79.3) v2(173.28,86.54) ; v2(148.32,90.19) 147.09,90.19 145.79,88.89 v2(145.47,88.89) ; v2(157.61,15.68) 158.1,15.68 158.1,16.34 164.62,22.86 164.62,24.2 164.17,24.65 164.17,26.12 166.05,28 166.05,31.42 169.22,34.6 169.46,34.6 173.02,38.16 173.02,49.89 172.59,50.32 172.59,58.54 v2(173.41,59.36) ; v2(158.87,90.29) 159.43,90.29 161.38,88.33 164.38,88.33 165.03,87.69 v2(165.92,87.69)
  IN2 w0.381: v2(170.36,75.87) 170.49,76 v2(173.67,76)
  IN2 w0.508: 159.16,15.7 160.05,15.7 160.46,15.3 165.89,15.3 166.3,15.7 168.28,15.7 169.21,16.64 176.51,16.64 177.7,17.84 177.7,18.5 177.18,19.02 177.18,24.01 v2(177.73,24.57)
  BOTTOM w0.254: 150.37,90.47 151.1,90.47 UC1.AA9 UC1.AC9 ; v2(145.47,88.89) 145.43,88.89 145.06,88.51 UC1.AE20 144.86,88.51 UC1.AE21
  BOTTOM w0.305: UC1.Y8 151.39,90.94 151.11,90.65 UC1.AA9
  BOTTOM w0.381: 150.37,90.47 150.32,90.43 148.56,90.43 v2(148.32,90.19)
  BOTTOM w0.508: v2(173.28,89.84) v2(173.28,86.54) 171.76,86.54 170.87,87.43 169.53,87.43 v2(169.35,87.61) 169.3,87.56 RC103.2 RC110.2 ; v2(156.93,15.68) 156.93,21.87 156.19,22.6 153.07,22.6 152.49,23.18 152.49,23.88 151.99,24.38 148.86,24.38 148.38,24.86 147.18,24.86 146.42,24.1 130.96,24.1 130.74,24.31 126.21,24.31 125.59,24.93 124.97,24.93 124.35,24.31 120.25,24.31 119.31,23.37 118.19,23.37 117.76,23.8 111.74,23.8 111.51,24.03 109.3,24.03 105.46,27.87 105.46,32.39 100.59,37.27 94.79,37.27 89.96,42.1 v2(89.96,43.08) ; U2302.8 184.08,25.07 184.59,24.57 v2(184.66,24.57) ; R2329.1 RC104.2 165.66,87.94 v2(165.92,87.69)
  vias: v2(160.84,73.97) v2(160.84,73.33) v4(168.99,76.03)
+3VALW_PCH_GATE: length 2.3
  TOP w0.203: U2304.3 161.58,12.62 161.52,12.56 161.52,12.12 162.35,11.29 C2314.1
+3VALWP: length 10.3
  TOP w0.254: PR109.1 PC102.1 v2(77.02,20.11)
  IN1 w0.254: v2(71.94,26.73) 75.46,23.2 75.46,21.66 v2(77.02,20.11)
  vias: v1(67.33,29.96)
+3VGS: length 120.1
  TOP w0.381: v2(77.53,76.38) 78.04,76.38 78.18,76.25 UV2.5
  TOP w0.508: v2(59.29,109.28) 58.1,108.08 v2(58.1,104.32) ; v2(77.4,95.31) 75.32,95.31 74.56,94.54 72.62,94.54 72.24,94.92 RV148.1 70.62,96.19 v2(70.24,96.58) ; v2(77.4,95.31) 78.64,95.31 79.08,95.74 v2(81.16,95.74) 81.16,94.09 82.86,92.38 82.86,91.37 82.35,90.86 82.35,87.81 v2(83.75,86.42) ; v2(77.4,95.31) RV147.1 ; v2(61.14,105.08) 60.25,105.08 59.24,104.07 v2(59.24,103.15) 58.91,102.82 58.91,102.42 58.86,102.37 RV154.1 ; v2(65.36,100.08) 66.25,99.19 v2(66.91,99.19) 66.91,99.6 67.59,100.27 v2(70.65,100.27) ; LV4.1 69.02,86.42 v2(69.4,86.03) ; RV91.2 v2(62.92,100.13)
  IN1 w0.508: v2(69.4,86.03) 69.4,87.81 71.18,89.59 71.18,95.64 v2(70.24,96.58)
  IN2 w0.508: v2(70.24,96.58) 70.24,96.63 69.78,97.08 67.75,97.08 67.37,97.46 v2(67.37,97.74) 67.27,97.85 66.73,97.85 65.39,99.19 65.39,100.03 65.33,100.08 ; v2(81.08,77.3) 80.17,76.38 v2(77.53,76.38) ; 65.33,100.08 65.33,100.13 65.19,100.27 63.06,100.27 v2(62.92,100.13) 61.93,100.13 59.24,102.82 v2(59.24,103.15) 59.23,103.17 59.23,103.19 v2(58.1,104.32) ; 65.33,100.08 v2(65.36,100.08)
  BOTTOM w0.254: CV166.2 81.63,95.52 U1.1
  BOTTOM w0.305: v2(66.91,99.19) 66.91,99.66 67.52,100.27 QV1.2 ; QV1.5 v2(70.65,100.27)
  BOTTOM w0.508: RV162.1 80.8,77.02 v2(81.08,77.3) 81.08,80.57 82.73,82.22 82.73,83.24 83.75,84.26 v2(83.75,86.42) RV71.2 RV79.2 ; v2(67.37,97.74) RV6.1 ; RV5.1 v2(70.24,96.58) ; v2(77.4,95.31) 78.42,96.32 78.42,97.34 80.07,98.99 84.26,98.99 84.89,98.35 RV72.2 ; v2(81.16,95.74) CV166.2 ; UV3.1 58.8,109.67 59.19,109.28 v2(59.29,109.28) 59.49,109.07 CV10.1 ; v2(58.1,104.32) 55.94,104.32 55.43,104.82 54.53,104.82 54.27,105.08 51.75,105.08 ; v2(61.14,105.08) 61.14,105.47 60.86,105.74 RV58.2
  vias: v3(46.16,108.39) v3(46.16,107.75) v3(46.92,108.39) v3(46.92,107.75) v4(47.63,107.07)
+3VLP: length 440.2
  TOP w0.203: v2(74.73,18.11) PU100.3 ; UG1.15 184.91,77.85 184.41,77.35 CG4.1 183.52,77.35 v2(183.32,77.14) ; UE1.111 139.42,18.31 139.32,18.21 v2(139.32,18.14)
  TOP w0.254: v2(77.95,28.96) 77.44,28.96 76.74,28.26 76.74,23.96 77.63,23.07 v2(77.63,18.06)
  TOP w0.381: v2(170.85,41.89) 169.83,42.9 169.83,48.04 175.29,53.5 175.29,59.47 178.16,62.34 178.16,64.15 179.09,65.08 179.09,70.02 178.71,70.41 ; v2(177.35,114.48) 181.31,110.52 181.31,97.68 v2(180.93,97.3) ; 178.1,71.67 178.1,71.67 v2(178.1,77.42) 178.39,77.72 178.39,84.24 v4(178.08,84.55) 177.48,85.15 177.48,87.43 176.08,88.83 176.08,93.32 177.09,94.33 v2(177.09,95.56)
  TOP w0.508: RE328.2 137.5,23.66 v2(137.5,23.25) ; v2(74.73,18.11) 74.86,18.11 74.87,18.1 PC109.1
  IN1 w0.254: v2(13.23,44.72) 13.77,44.72 16.67,41.83 20.15,41.83 22.23,39.74 22.23,38.97 21.96,38.7 21.96,34.51 25.29,31.19 25.29,25.27 24.1,24.08 23.79,24.08 21.58,21.87 21.58,16.37 23.87,14.09 31.31,14.09 36.05,9.35 40.89,9.35 v2(41.75,8.49)
  IN1 w0.508: v2(169.98,19.21) 170.01,19.23 170.01,23.09 174.63,27.71 174.63,31.86 174.28,32.21 v2(174.22,32.21)
  IN2 w0.254: v2(41.75,8.49) 41.75,11.15 42.5,11.9 46.42,11.9 49.18,14.66 49.97,14.66 54.01,18.7 54.01,24.95 58.63,29.57 77.34,29.57 v2(77.95,28.96) 79.58,28.96 80.14,29.52 90.13,29.52 96.5,23.16 99.52,23.16 105.47,17.21 105.47,14.58 106.28,13.77 106.28,3.59 107.12,2.74 118.23,2.74 118.96,2.01 124.25,2.01 125.37,3.13 133.18,3.13 133.38,3.33 142.98,3.33 145.04,5.39 148.62,5.39 150.43,3.58 155.29,3.58 ; v2(77.63,18.06) 77.4,17.84 75.75,17.84 75.47,18.11 v2(74.73,18.11)
  IN2 w0.508: v2(165.03,6.51) 165,6.51 164.27,5.77 157.48,5.77 155.29,3.58 ; v2(169.98,19.21) 169.17,18.4 167.01,18.4 166.98,18.37 166.66,18.37 165.97,17.68 v2(164.75,17.68) 155.23,17.68 154.54,18.37 152.74,18.37 152.25,18.85 140.11,18.85 139.48,18.22 139.4,18.22 v2(139.32,18.14)
  BOTTOM w0.254: PD700.3 41.55,8.69 v2(41.75,8.49) ; v2(178.1,77.42) 178.16,77.36 183.1,77.36 v2(183.32,77.14) ; RE333.2 14.71,64.66 14.95,64.42 14.95,60.79 13.8,59.63 13.8,58.99 14.79,58 14.79,50.46 13.23,48.9 v2(13.23,44.72)
  BOTTOM w0.381: v2(177.09,95.56) 178.06,96.52 180.15,96.52 v2(180.93,97.3) ; v2(177.35,114.48) 174.05,114.48 173.41,115.12 173.41,117.05 171.61,118.85 171.61,119.64 171.1,120.15 171.1,120.45
  BOTTOM w0.508: v2(165.03,6.51) 165.06,6.53 165.06,7.09 163.02,9.12 163.02,11.78 164.75,13.5 v2(164.75,17.68) ; v2(174.22,32.21) 174.3,32.29 174.3,34.73 172.65,36.38 172.65,40.09 v2(170.85,41.89) ; v2(137.5,23.25) 137.27,23.02 137.27,20.27 139.32,18.22 v2(139.32,18.14)
+3VS: length 551.8
  TOP w0.203: UC4.14 88.02,86.49 87.56,86.03 CC13.1 ; C2498.1 154.18,6.61 154.76,7.18 U2407.1
  TOP w0.254: QC1.5 173.64,81.59 173.8,81.75 v2(174.17,81.75) ; v2(80.65,39.96) v2(83.09,39.96) ; v3(172.02,81.71) 171.87,81.71 171.75,81.59 QC1.2
  TOP w0.305: UC3.5 173.92,94.04 CC11.1
  TOP w0.381: v3(187.89,21.77) 189.03,20.63 RA2.1 RA1.1 ; R2331.1 R2332.1 171.18,84.21 170.74,84.64 v3(170.74,84.67) ; RC128.1 v2(161.55,90.56)
  TOP w0.457: RC102.1 161.54,92.77 v2(161.58,92.73) ; RC102.1 RC74.1 ; RC102.1 RC36.1 ; RC73.1 RC77.1 161.6,95.81 v2(161.73,95.69)
  TOP w0.508: R2448.1 157.23,14.51 156.27,15.47 v2(156.27,15.57) ; v2(32.19,43.74) 31.43,42.98 31.43,40.31 33.08,38.66 40.32,38.66 40.82,39.17 44,39.17 45.73,40.9 48.35,40.9 48.48,41.02 v2(49.98,42.53) ; QX4.5 194.75,75.62 194.37,75.24 193.82,75.24 193.33,75.73 v2(193.3,75.73) 192.99,75.42 192.99,73.46 QX5.1 192.26,73.45 190.75,71.94 187.25,71.94 v2(186.34,71.02) ; QX4.2 194.75,78.29 v2(194.37,78.67) ; QC3.2 153.85,98.51 153.07,99.29 v2(153.07,99.28) ; RS26.1 188.91,6.91 187.89,5.9 185.98,5.9 185.35,6.53 ; C2498.1 153.88,6.61 v2(153.32,7.17) 153.27,7.17 153.09,6.99 153.09,5.52 154.26,4.35 154.26,4.3 155.69,2.88 v2(156.08,2.88) ; 185.35,6.53 RS20.1 RS30.1 ; 185.35,6.53 184.71,5.9 183.01,5.9 182.72,6.19 v3(182.72,6.57) 182.71,6.58 RS29.1 182.7,7.34 RS34.2 ; RC75.1 158.3,110.93 v2(158.17,110.8) ; RX30.1 9.71,102.16 v3(10.34,102.8) ; RE50.1 v3(2.52,73.21) ; v2(195.86,73.7) 196.38,74.22 RX12.1 ; v3(166.05,88.93) 166.05,89.21 166.43,89.59 167.44,89.59 167.95,90.1 169.22,90.1 v3(169.6,89.72) 169.63,89.74 v3(169.63,90.86) ; v2(182.56,14.79) 181.92,14.79 181.46,15.24 RS27.1 ; v2(86.21,85.12) 86.62,85.53 CC13.1 ; RD12.2 CD61.1 CD60.1 171.79,38.16 171.43,38.51 v2(170.87,38.51) 170.01,38.51 169.81,38.71 169.81,39.76 v2(170.87,40.82) 172.45,40.82 173.23,41.61 173.23,42.17 175.11,44.05 175.11,47.73 v2(175.95,48.57) ; v3(170.36,101.4) 170.92,101.4 RL33.1 ; CX1.1 4.49,86.67 3.98,87.18 v3(3.49,87.18) ; CD31.1 CD30.1 158.73,49.88 158.57,49.71 v2(158.12,49.71) ; RE331.1 v3(12.12,71.3) ; v2(143.41,50.83) 142.8,50.22 CD62.1 ; RA7.1 v2(188.78,31.68) ; v2(198.05,85.2) 198.05,84.21 QX3.2 198.18,84.08 RX13.1 ; RC3.1 v2(198.68,12.25) ; CE15.1 v2(111.23,23.4) 111.23,23.56 UE2.5 ; v2(120.53,23.21) 120.53,22.71 120.91,22.33 RE68.2 ; v2(187.02,14.84) 186.87,14.99 RS33.2 ; RC362.1 v3(82.66,81.03) ; CA60.1 195.76,14.79 v3(195.26,15.3) 194.75,15.8 CA59.1 ; v2(148.27,95.48) 147.45,94.67 C44.2 147.44,93.97 148.01,93.4 C73.1 C71.1 149.1,92.84 149.28,93.02 151.03,93.02 v2(151.69,92.36) 151.69,91.96 151.38,91.64 C82.1 ; v2(28.89,61.06) 28.89,60 28.38,59.49 v2(28.38,51.49) ; RS38.2 CS42.1 CS27.1 180.02,8.47 180.73,9.19 182.7,9.19 v2(182.71,9.2) ; RE9.1 151.39,16.31 RE10.1 150.5,16.03 150.68,15.85 v2(150.68,15.55) ; v2(185.16,17.14) 185.16,16.45 RS19.1 ; v3(200.21,15.55) 200.21,15.1 CA57.1 199.26,14.6 198.76,14.1 CA58.1 ; RC119.1 175.27,96.14 175.06,95.94 174.68,95.94 174.12,95.38 v3(174.12,95.2) 174.3,95.03 CC11.1 ; RX27.1 v2(6.47,82.35)
  IN1 w0.508: v2(195.86,73.7) 195.86,74.13 194.8,75.19 193.55,75.19 193.33,75.42 193.33,75.71 v2(193.3,75.73) 193.33,75.76 193.33,77.28 193.35,77.31 193.35,77.65 v2(194.37,78.67) 195.26,79.56 195.26,83.88 196.58,85.2 v2(198.05,85.2) ; v3(169.37,88.32) 169.98,88.32 171.25,87.05 171.25,85.17 v3(170.74,84.67) ; v2(32.19,43.74) 30.31,43.74 28.38,45.67 v2(28.38,51.49) ; v2(185.16,17.14) 185.16,16.14 ; 185.16,16.14 183.66,16.14 182.56,15.04 v2(182.56,14.79) 182.05,14.79 181.41,14.15 181.41,11.08 182.71,9.79 v2(182.71,9.2) ; 185.16,16.14 185.72,16.14 v2(187.02,14.84) 188.01,14.84 188.44,14.41 191.45,14.41 v2(193.1,12.76) ; v2(28.89,61.06) 28.89,65.59 v2(28.5,65.97) 28.5,66.35 27.74,67.11 25.46,67.11
  IN1 w1.524: 19.51,70.13 19.51,69.31 20.59,68.23 23.55,68.23
  IN2 w0.508: 4.97,72.01 4.91,71.95 4.91,54.07 v2(4.5,53.66) 5.3,52.86 6.64,52.86 14.43,45.07 14.43,37.16 17.33,34.26 17.33,31.07 15.97,29.7 15.97,19.59 v2(17,18.56) ; v3(187.89,21.77) 188.65,21.01 188.65,18.73 189.27,18.12 v2(190.02,18.12) 190.02,17.87 193.1,14.8 v2(193.1,12.76) 193.73,12.76 194.49,13.52 194.49,14.53 v3(195.26,15.3) 196.02,16.06 198.94,16.06 199.45,15.55 v3(200.21,15.55) ; v2(198.68,12.25) 198.68,12.88 200.21,14.41 v3(200.21,15.55) ; v3(200.21,15.55) 200.21,16.31 199.45,17.07 199.45,22.64 199.85,23.04 v2(200.21,23.04) ; v2(156.08,2.88) 158.08,4.88 168.59,4.88 169.6,3.87 175.32,3.87 177.22,5.77 181.92,5.77 v3(182.72,6.57) 182.71,6.58 v2(182.71,9.2)
  IN2 w1.524: 12.76,72.32 12.78,72.29 15.22,72.29 15.82,71.7 18.74,71.7 v2(18.74,71.68)
  BOTTOM w0.203: 155.96,114.43 v3(156.5,114.43) ; 155.96,114.43 155.94,114.43 ; 155.96,114.43 155.87,114.34 RP51.8 ; 165.99,89.52 RP37.7 ; 165.99,89.52 166,89.52 166,88.98 ; 165.99,89.52 165.49,90.02 RP37.6 ; v3(169.63,90.86) 169.47,90.86 169.28,91.05 RP42.1 ; 166,88.98 165.96,89.02 RP37.8 ; 166,88.98 v3(166.05,88.93) ; v3(154.21,114.46) 154.37,114.29 RP51.5 ; RP54.8 165.47,91.81 v3(165.79,92.13) 165.72,92.13 165.54,92.31 RP54.7 ; RP54.6 165.69,92.81 v2(165.77,92.74) 165.77,92.97 165.42,93.31 RP54.5 ; UA1.9 195.53,15.68 ; RP53.5 165.42,99.86 v3(165.66,99.62) 165.41,99.37 RP53.6 ; RP52.7 152.58,114.15 v3(152.84,114.41) 153.08,114.16 RP52.8 ; UA1.1 198.73,16.14 198.84,16.03 199.32,16.03 ; 199.32,23.04 198.94,23.04 198.73,22.83 UA1.36 ; RP53.7 165.41,98.87 165.74,98.53 165.74,98.51 v3(165.84,98.4) 165.46,98.4 165.42,98.37 RP53.8 ; RP52.6 152.08,114.17 v3(151.85,114.41) 151.58,114.14 RP52.5
  BOTTOM w0.254: JEDP.34 2.47,82.5 v2(2.75,82.22) 2.53,82 JEDP.35 ; v2(151.69,92.36) 151.72,92.38 151.72,92.67 UC1.U8 151.41,92.99 151.11,93.29 UC1.T9 ; PR1020.1 62.92,31.3 63.43,30.79 67.16,30.79 68.38,32.01 68.38,37.39 69.27,38.28 78.97,38.28 v2(80.65,39.96) ; PR1030.1 55.84,40.47 55.84,41.37 55.6,41.61 50.9,41.61 v2(49.98,42.53)
  BOTTOM w0.305: UC1.W9 151.11,91.44 UC1.V8 151.69,92.03 v2(151.69,92.36) ; US3.14 21.23,18.84 21.41,19.02 21.41,20.65 20.91,21.15 20.08,21.15 v2(20.06,21.18) ; UC1.K16 UC1.K14 148.3,95.52 v2(148.27,95.48) ; US3.1 20.36,15.74 CS43.1 ; US3.7 17.21,18.34 v2(17,18.56) 17.28,18.84 US3.8 ; v2(170.87,38.51) 170.9,38.51 170.67,38.28 170.67,36.94 170.32,36.59 JDIMM2.199
  BOTTOM w0.381: v3(195.26,15.3) 195.53,15.57 195.53,15.68 ; v3(161.8,102.09) 161.6,102.29 RC118.1 ; v2(28.5,65.97) 28.5,65.84 28,65.33 QE6.5 ; QE6.2 24.89,65.33 24.63,65.59 v2(24.63,66.25) ; v2(158.12,49.71) 158.12,49.43 157.95,49.26 JDIMM1.199
  BOTTOM w0.457: RC107.2 RC121.1 160.99,91.11 v2(161.55,90.56) ; RC100.1 167.82,96.45 v3(168.2,96.07) 167.7,95.56 RC98.2 ; RC112.1 167.57,93.78 167.95,93.4 v3(168.2,93.4)
  BOTTOM w0.508: RC79.1 RC76.1 161.69,95.65 v2(161.73,95.69) ; v3(168.2,96.07) 168.95,96.07 169.21,95.81 Q2409.2 ; RA9.1 200.34,23.17 v2(200.21,23.04) 199.32,23.04 ; RL37.2 179.93,100.7 179.28,100.05 178.77,100.05 v2(177.87,99.15) ; RC115.1 RC106.1 161.52,98.3 v2(161.61,98.21) ; v2(28.38,51.49) 28.38,49.71 27.61,48.95 JIO.6 ; RC108.1 RC111.1 161.56,96.54 v2(161.63,96.6) ; RS25.1 183.19,15.55 182.56,14.91 v2(182.56,14.79) ; RS28.1 186.46,15.96 187.02,15.4 v2(187.02,14.84) ; 199.32,16.03 199.73,16.03 v3(200.21,15.55) ; v2(165.94,96.07) 165.61,96.4 165,96.4 RC114.1 RC109.1 ; v2(188.78,31.68) 188.58,31.68 188.22,31.32 188.2,31.23 188.19,31.2 188.19,29.77 186.39,27.97 186.39,23.27 v3(187.89,21.77) ; v2(174.17,81.75) 172.06,81.75 v3(172.02,81.71) 171.52,81.71 170.74,82.49 v3(170.74,84.67) ; QS1.2 5.52,54.9 5.19,54.58 CS44.1 v2(4.5,53.66) ; v2(161.58,92.73) 161.39,92.92 RC11.2 ; PR1110.1 v2(32.19,43.74) ; PR308.1 v3(184.54,45.78) ; R2453.1 170.24,95.89 v2(170.29,95.84) ; v2(156.08,2.88) 155.05,1.85 147.23,1.85 145.22,3.87 139.29,3.87 138.44,4.72 138.44,5.32 138.44,6.58 138.31,6.71 138.31,7.81 134.81,11.31 134.81,14.19 134.02,14.99 v2(134.01,14.99) ; v2(190.02,18.12) 190.26,18.12 190.63,18.48 RA13.2 ; v2(170.87,40.82) 169.42,42.27 167.27,42.27 159.82,49.71 v2(158.12,49.71) 152.89,49.71 152.51,50.09 144.15,50.09 v2(143.41,50.83) ; v2(19.55,15.55) CS43.1
  vias: v2(10.47,77.91) v2(10.85,73.59) v2(11.61,73.59) v2(12.76,77.78) v2(18.55,70.67) v2(19.34,71.04) v2(24.67,66.83) v2(25.22,66.58) v2(176.94,27.56) v2(176.94,26.93) v2(177.34,37.75) v2(177.35,28.02) v2(177.37,37.14) v2(177.83,38.12) v2(177.78,27.56) v2(177.78,26.95) v2(177.92,37.53) v2(178.43,38.04) v2(185.83,62.39) v2(190.56,63.94) v2(191.01,64.33) v2(191.33,64.84) v2(191.97,64.84) v2(192.29,64.28) v3(12.08,77.82) v3(44.13,111.43) v3(44.76,111.43) v3(45.4,111.43) v3(46.03,111.43) v3(46.67,111.43) v3(175.14,19.64) v3(175.14,18.95) v3(175.82,19.61) v3(175.82,18.98) v3(176.46,19.61) v3(176.46,18.98) v4(189.53,61.9)
+3VS_CAM: length 4.7
  TOP w0.102: v3(4.25,83.6) v1(3.49,83.6)
  TOP w0.508: RX27.2 4.35,83.49 v3(4.25,83.6)
  BOTTOM w0.508: JEDP.29 2.61,85 3.56,84.05 3.57,84.05 4.03,83.6 v3(4.25,83.6)
+3VS_TOUCH: length 33
  TOP w0.102: 12.43,66.15 v4(13.14,66.15)
  TOP w0.508: JTP1.10 v2(27.66,61.4) ; RE340.2 26.99,62.15 v2(27.23,61.9) ; CE58.1 19.91,62.23 RE339.1 19.91,62.05 v2(20.66,61.31) 21.89,61.31 22.59,62.01 RE329.1
  IN2 w0.508: v2(25.58,61.9) v2(27.23,61.9) 27.23,61.8 27.64,61.4 v2(27.66,61.4) 27.66,60.99 27.3,60.63 21.49,60.63 20.82,61.31 v2(20.66,61.31) 20.27,60.92 14.09,60.92 12.5,62.51 v2(12.5,65.76)
  BOTTOM w0.508: RE334.1 v2(25.58,61.9) ; v2(27.66,61.4) 28.37,60.69 RC78.2 ; RE335.1 26.85,62.29 v2(27.23,61.9)
+3VS_WLAN_NGFF: length 144.2
  TOP w0.254: RE72.1 149.59,19.12 v2(150.09,19.62)
  IN1 w0.203: v2(149.89,14.39) 150.23,14.06 152.51,14.06 153.24,13.32 158.43,13.32 160.22,15.11 163,15.11 165.38,17.48 165.38,18.83 167.36,20.82 167.36,24.29 171.62,28.55 171.62,32.94 172.99,34.3 172.99,35.28 174.9,37.19 174.9,51.88 176.3,53.28 176.3,60.33 178.11,62.15 178.11,66.15 v2(181.74,69.78) 181.74,69.94 179.62,72.06 179.62,86.55 v2(175.44,90.73)
  BOTTOM w0.203: v2(175.44,90.73) 175.19,90.73 174.55,91.37 171.51,91.37 170.36,90.23 169.58,90.23 169.25,90.55 RP42.2 ; v2(150.09,19.62) 150.09,20.2 149.54,20.75 148.49,20.75 148.01,20.26 148.01,19.64 148.75,18.89 148.75,17.54 149.89,16.4 v2(149.89,14.39)
  BOTTOM w0.254: JNGFF.66 190.73,66.26 v2(191.06,66.6) ; JNGFF.2 172.73,66.3 173.03,66.6 173.23,66.41 JNGFF.4 ; v2(190.3,66.6) 190.3,66.48 190.23,66.4 JNGFF.64
  BOTTOM w0.508: v2(191.06,66.6) 191.06,66.6 v2(190.3,66.6) 190,66.91 187.23,66.91 184.36,69.78 v2(181.74,69.78) 180.52,69.78 177.86,67.11 173.54,67.11 173.03,66.6
  vias: v2(197.74,68.08) v2(197.73,67.49) v2(198.84,72.74) v2(198.86,72.15) v4(187.61,66.98)
+5V_HDD:
  vias: v2(182,17.2) v2(182.63,17.2) v2(183.27,17.2) v2(183.9,17.2) v2(184.54,17.2) v2(188.1,13.81) v2(188.3,13.25) v4(181.74,17.73)
+5V_PVDD: length 3.4
  BOTTOM w0.203: UA1.41 200.48,20.09 v2(200.56,20.17) ; v2(201.35,16.82) 200.97,17.2 200.72,17.2 200.49,17.43 200.49,17.57 200.25,17.81 200.25,17.82 199.99,18.09 UA1.46
  vias: v4(200.59,19.16)
+5V_USB_PWR1:
  vias: v2(196.76,54.48) v2(196.76,53.72) v2(197.52,54.48) v2(197.52,53.72) v2(198.28,54.48) v2(198.28,53.72) v4(197.14,56.87)
+5V_USB_PWR2:
  vias: v2(196.27,39.93) v2(196.27,39.3) v2(198.05,39.93) v2(198.05,39.3) v2(198.81,39.93) v2(198.81,39.3) v4(197.59,41)
+5V_USB_PWR3:
  vias: v3(23.68,46.03) v3(23.68,45.27) v3(24.44,46.03) v3(24.44,45.27) v4(24.06,44.66)
+5VA: length 2.8
  TOP w0.102: 194.86,22.6 v1(196.29,22.6)
  BOTTOM w0.203: UA1.26 194.73,22.95 194.46,23.21 194.45,23.21 194.19,23.47 v2(193.99,23.47)
+5VALW: length 215.5
  TOP w0.203: v2(162.13,12.17) 161.98,12.32 U2304.4 ; U2301.4 v2(170.62,12.37) ; v2(72.57,109.15) 72.43,109.29 PU501.12
  TOP w0.254: v2(153.13,23.54) 153.23,23.43 153.23,22.62 U2408.4
  TOP w0.508: v2(41.46,114.23) v2(40.57,114.23) 40.57,107.75 v2(39.05,106.23) ; v2(35.49,47.93) 34.73,47.93 33.46,46.66 33.46,45.27 32.7,44.51 31.38,44.51 28.75,47.13 v2(27.6,47.13) ; v2(49.48,43.21) 49,43.21 v4(47.75,41.97) v2(45.9,41.97) ; v2(65.33,38.89) 64.7,38.89 64.67,38.87 63.93,38.87 PR1024.2 63.62,39.62 63.3,39.93 PC1021.1 62.22,40.38 v2(61.91,40.7) ; PR8.1 v2(24.31,99.37) ; R10.1 174.25,7.73 v2(174.61,7.37) ; v2(145.47,51.36) 145.34,51.49 R2347.1 ; v2(171.7,44.25) 171.7,47.92 176.46,52.68 176.46,57.97 v2(177.45,58.96) ; v2(11.51,58.13) 11.69,58.3 12.75,58.3 JLED.1 ; PR210.2 79.06,12.63 v2(78.42,12.63)
  IN1 w0.381: v2(174.61,7.37) 174.58,7.34 173.87,7.34 172.88,6.35 v2(170.24,6.35)
  IN1 w0.508: v2(61.91,40.7) 61.91,40.11 61.47,39.68 58.6,39.68 57.63,40.66 57.63,41.6 57.23,41.99 56,41.99 55.51,42.49 52.1,42.49 51.37,43.21 v2(49.48,43.21) ; v2(35.49,47.93) 35.49,43.36 38.03,40.82 44.63,40.82 45.78,41.97 v2(45.9,41.97)
  IN2 w0.508: v2(27.6,47.13) 26.55,48.19 v2(17.84,48.19)
  BOTTOM w0.203: PU1000.31 64.62,38.43 65.08,38.89 v2(65.33,38.89) ; PU1000.26 61.73,40.51 v2(61.91,40.7)
  BOTTOM w0.254: PC1105.1 34.92,47.24 34.58,46.89 PU1100.7
  BOTTOM w0.508: PR206.1 81.65,12.56 v2(82.1,13.01) ; v3(165.41,3.74) 164.34,4.8 164.34,6.86 161.98,9.22 161.98,12.02 v2(162.13,12.17) 163.37,13.41 163.37,18.2 161.88,19.69 161.88,23.61 160.94,24.55 153.88,24.55 153.12,23.8 v2(153.12,23.54) ; v2(171.7,44.25) 167.54,44.25 160.76,51.03 153.63,51.03 153.27,51.39 147.66,51.39 147.05,52 146.11,52 v2(145.47,51.36) ; PC528.1 73.58,109.15 v2(72.57,109.15) 72.07,109.15 71.3,108.39 71.3,105.72 70.62,105.03 65.17,105.03 65.09,104.96 64.32,104.96 61.42,107.85 61.42,109.33 60.74,110.01 59.44,110.01 55.23,114.23 v2(41.46,114.23) v2(40.57,114.23) ; v2(39.05,106.23) RV22.1 ; v2(35.49,47.93) PC1105.1
  vias: v2(177.6,59.57) v2(184.84,37.39) v2(184.82,26.88) v2(184.82,25.3) v2(184.87,26.09) v2(185.35,37.9) v2(185.3,27.26) v2(185.3,26.55) v2(185.3,25.63) v2(185.27,24.87) v2(187.25,61.12) v2(187.84,61.12) v2(189.29,56.19) v2(189.29,55.55) v2(189.29,54.92) v2(189.62,42.09) v2(189.62,41.46) v2(189.92,56.19) v2(189.92,55.55) v2(189.92,54.92) v2(190.28,42.68) v2(190.25,42.09) v2(190.25,41.46) v2(190.87,42.12) v2(190.87,41.48) v3(23.55,37.27) v3(23.55,36.25) v3(24.06,36.76) v3(24.06,35.74) v3(77.73,11.85) v3(77.73,10.84) v3(77.73,9.82) v3(77.73,8.81) v3(77.73,7.79) v3(78.54,11.87) v3(78.54,10.85) v3(78.54,9.83) v3(78.54,8.82) v3(78.54,7.8) v3(165.79,3.1) v3(166.05,3.74) v3(166.55,3.1) v3(166.81,3.74) v3(168.28,12.88) v3(168.33,12.25) v3(168.33,11.61) v3(168.92,12.88) v3(168.97,12.25) v3(168.97,11.61) v3(169.6,12.25) v3(169.6,11.61) v3(210.11,9.96) v3(210.11,9.33) v4(168.1,13.44) v4(188.74,43.35)
+5VALWP: length 26.5
  TOP w0.203: PU100.14 69.85,17.71 69.59,17.45 v3(69.27,17.45)
  TOP w0.508: v3(77.08,16.96) 77.04,17 PR104.2
  IN2 w0.254: v3(77.08,16.96) 75.29,15.17 75.29,10.57 73.23,8.51 v3(72.47,8.51)
  IN2 w0.508: v3(69.27,17.45) 69.35,17.38 71.23,17.38 72.15,16.46 72.56,16.46 73.62,15.41 73.62,11.39 72.45,10.22 v3(72.45,9.28)
  BOTTOM w0.102: v1(77.49,17.48) 77.49,17.37 v3(77.08,16.96)
  BOTTOM w0.508: v3(77.08,16.96) 76.94,16.82 PC108.2
+5VS: length 283.9
  TOP w0.508: v2(94.48,45.81) 95.43,45.81 95.69,46.07 RE60.1 ; FE1.2 118.29,23.98 117.95,23.64 RE59.1 115.03,23.17 v2(114.38,23.17) 113.79,23.17 CE56.1
  IN1 w1.016: 186.37,19.36 186.24,19.49 186.24,29.04 187.23,30.03 187.23,34.95 188.96,36.68 192.67,36.68 194.59,38.61 194.59,42.94 193.95,43.58 193.95,50.09 195.58,51.72 195.58,54.54 196.8,55.76 196.8,67.43 195.94,68.29 195.94,70.09 197.56,71.72 197.56,73.51 197.03,74.05 197.03,77.02 197.29,77.27
  IN2 w0.508: 168.26,19.11 164.9,19.11 164.62,18.83 162.54,18.83 162.12,19.24 155.87,19.24 155.33,19.79 151.69,19.79 150.88,20.6 148.15,20.6 147.23,19.69 136.05,19.69 135.61,19.25 131.25,19.25 130.66,18.67 125.76,18.67 125.4,19.04 124.93,19.04 124.77,19.2 118.67,19.2 v2(118.62,19.16) ; 168.26,19.11 v2(168.26,19.11) 168.26,19.11 ; 168.26,19.11 168.59,19.11 v2(168.89,19.41) ; 13.26,59.11 13.26,59.73 13.82,60.29 20.84,60.29 21.13,60 27.64,60 28.02,60.38 33.97,60.38 37.65,56.7 45.14,56.7 46.77,58.32 46.77,61.24 53.45,67.92 69.58,67.92 71.89,65.61 75.44,65.61 77.53,63.53 77.53,57.69 81.21,54 81.21,49.15 84.08,46.28 88.31,46.28 v2(89.97,44.62)
  BOTTOM w0.508: v2(94.48,45.81) 92.83,45.81 91.64,44.62 v2(89.97,44.62) 89.85,44.62 89.31,44.09 89.31,41.84 94.88,36.28 95.33,36.28 95.61,36 100.72,36 104.83,31.88 104.83,27.57 109.33,23.07 110.64,23.07 110.99,22.71 112.25,22.71 112.71,23.17 v2(114.38,23.17) 115.56,23.17 118.62,20.11 v2(118.62,19.16) ; RS32.1 10.85,56.52 11.99,57.66 12,57.65 13.26,57.65 13.51,57.89 v3(13.79,57.89)
  vias: v2(187.13,20.63) v2(187.64,20.12) v2(192.97,16.18) v2(193.48,16.69) v3(8.18,70.16) v3(8.82,70.16) v3(12.12,101.78) v3(12.76,101.78) v3(13.78,57.19) v3(198.18,77.53) v3(198.94,77.53) v4(12.71,102.37)
+5VS_KBL: length 13.5
  TOP w0.102: CE57.1 113.66,21.02 113.12,20.48 v4(112.5,20.48)
  TOP w0.508: CE57.1 114.57,22.03 114.66,21.94 RE59.2 FE1.1 119.44,20.79 119.44,16.92 119.54,16.82 JKBBL.1
+V18R: length 2.6
  TOP w0.203: 134.22,20.66 UE1.124
  TOP w0.508: 134.22,20.66 134.22,21.61 CE16.1
+VCC_PWR_SRC:
  vias: v1(76.74,111.31) v3(77.27,112.7) v3(77.27,111.82) v3(77.4,109.91) v3(77.4,109.15) v3(77.53,110.67) v3(78.54,114.86) v3(78.54,114.1)
+VCCHDA: length 17.6
  TOP w0.127: RC129.2 161.96,88.7 v1(162.16,88.9)
  TOP w0.381: RC129.2 160.84,88.78 RC128.2 RC127.2 159.15,89.64 v2(158.58,89.07) ; v2(148.43,86.85) 148.83,87.25 149.08,87.5 C77.1
  IN1 w0.254: v2(148.43,86.85) 149.54,87.96 150.83,87.96 150.98,88.11 154.12,88.11 154.41,87.81 156.14,87.81
  IN1 w0.381: 156.14,87.81 157.06,88.73 158.24,88.73 v2(158.58,89.07)
  BOTTOM w0.254: UC1.AH14 148.34,86.85 v2(148.43,86.85)
+VCCIO_OUT: length 1.6
  BOTTOM w0.102: v3(122.36,108.89) v1(123.09,108.89)
  BOTTOM w0.508: R245.2 v3(122.36,108.89)
+VCCIO_OUT_R: length 7.7
  BOTTOM w0.254: UC1.A59 120.24,102.3 119.69,102.85 119.69,103.18 120.71,104.2 120.71,104.7
  BOTTOM w0.508: 120.71,104.7 v1(120.71,105.95) 120.71,107.62 120.14,108.2 R245.1
+VCCIOA_OUT: length 2.9
  TOP w0.076: RC71.1 145.47,101.1 v4(146.08,101.71)
  TOP w0.508: v2(145.5,99.74) 145.47,99.76 RC71.1
  BOTTOM w0.254: v2(145.5,99.74) 145.28,99.74 144.97,99.42 UC1.E20
+VCCRTCEXT: length 3.4
  TOP w0.127: v1(150.93,89.49) C52.1
  TOP w0.254: v2(152.38,88.55) 151.94,88.11 151.5,88.11 151.21,88.4 C52.1
  BOTTOM w0.254: v2(152.38,88.55) 152.2,88.38 UC1.AE7
+VDD_CT: length 13.7
  TOP w0.102: v2(72.83,77.27) 72.42,77.27 v1(72.17,77.02)
  TOP w0.381: LV3.2 73.53,76.5 CV61.1 v2(72.83,77.27)
  TOP w0.508: CV63.1 CV62.1 67.93,80.84 v2(67.96,80.88)
  IN1 w0.381: v2(72.83,77.27) 71.94,77.27 70.54,78.67 70.54,79.05 70.08,79.51 69.32,79.51 68.26,80.57 68.26,80.59 v2(67.96,80.88)
  BOTTOM w0.381: UV1.AB20 68.38,81.3 v2(67.96,80.88) ; UV1.AA21 67.46,80.3 67.96,80.8 ; 67.96,80.8 68.4,80.36 UV1.AB21 ; 67.96,80.8 v2(67.96,80.88) ; v2(67.96,80.88) 67.54,81.3 UV1.AA20
+VDD_TOUCH: length 52.3
  TOP w0.254: v2(8.01,94.92) CX50.1 8.01,98.98 CX49.1 8.15,99.12 RX28.1 9.65,98.16 9.5,98.02 UX3.1 ; RX35.1 5.21,89.69 5.03,89.87 v2(4.73,89.87)
  TOP w0.381: RX40.1 6.66,105.47 7.3,106.1 v1(7.96,106.1) 8.57,106.1 v2(8.92,105.74) 9.2,105.47 9.2,103.25
  TOP w0.508: RX39.1 v2(11.74,103.05)
  IN2 w0.508: v2(2.82,86.4) 2.82,87.73 4.73,89.64 v2(4.73,89.87)
  BOTTOM w0.254: JEDP.11 3.25,94 3.56,94.31 4.17,94.31 4.27,94.42 5.24,94.42 5.26,94.44 ; JEDP.26 2.72,86.5 v2(2.82,86.4)
  BOTTOM w0.508: v2(4.73,89.87) 5.26,90.41 5.26,94.44 ; 5.26,94.44 5.37,94.54 7.63,94.54 v2(8.01,94.92) ; 5.26,94.44 5.26,97.21 4.63,97.85 4.63,100.64 5.89,101.9 6.82,101.9 7.83,100.89 9.71,100.89 11.74,102.93 v2(11.74,103.05) 11.74,104.2 10.19,105.74 v2(8.92,105.74)
+VDDCI: length 7.2
  TOP w0.102: v2(61.09,80.62) 61.22,80.62 v1(61.55,80.29)
  BOTTOM w0.381: UV1.M13 UV1.M15 60.6,85.09 v2(60.1,84.59) 60.15,84.54 60.16,84.54 UV1.M16 UV1.M17 ; UV1.N20 61.6,81.13 v2(61.09,80.62) ; UV1.M18 UV1.M20 60.52,81.3 60.1,80.88 v2(60.1,80.7) 60.5,80.3 UV1.M21
+VDDR3: length 3.4
  BOTTOM w0.381: UV1.AB18 68.24,82.14 67.56,82.14 UV1.AA18 66.9,81.8 v2(66.9,81.67) ; UV1.AA17 67.41,83.29 v2(67.9,82.8) UV1.AB17
  vias: v1(67.21,82.15)
GND: length 2245.4
  TOP w0.102: CM6.2 v4(187.98,68.7) ; C93.2 v4(177.37,81.59) ; 25.44,81.22 25.44,81.22 v4(24.87,81.22) ; PC714.2 v4(27.11,32.67)
  TOP w0.203: v2(170.54,15.96) 170.54,15.93 170.62,15.85 U2301.11 ; UE1.113 v2(138.62,20.76) ; UG1.4 188.27,79.05 188.8,79.58 189.03,79.58 v2(189.11,79.66) ; UC4.15 88.52,88.7 UC4.7 ; UE1.24 129.41,8.51 129.18,8.28 v2(129.18,8) ; U2304.11 v2(161.98,15.91) ; UE1.11 130.04,13.71 129.61,14.14 129.61,14.34 v2(129.04,14.91) ; UG1.13 184.26,78.65 v2(184.19,78.72) ; v2(188.12,11.65) 187.9,11.87 US2.3 ; U2407.6 156.76,11.82 v2(157.04,11.54) ; UE1.35 v2(133.42,2.21) ; v2(144.84,18.04) 144.84,17.76 145.69,16.91 UE1.94 ; RP45.6 111.56,95.43 v2(111.31,95.18) 111.56,94.93 RP45.7 ; UG1.7 187.82,80.25 v2(188.32,80.75)
  TOP w0.254: U2408.9 153.23,20.77 U2408.5 ; UV6.G1 v2(38.57,78.94) ; UV6.T9 30.53,72.12 v2(30.32,71.91) ; v2(42.54,71.7) 42.54,71.7 ; 42.54,71.7 42.54,71.73 UV6.B9 ; 42.54,71.7 42.95,72.11 UV6.A9 ; v2(38.59,92.36) 38.95,92 UV7.F9 ; v2(38.59,92.36) 38.21,92.73 UV7.G8 ; v2(38.59,92.36) 38.16,91.93 UV7.G9 ; v2(32.47,91.34) 32.47,91.59 32.55,91.67 UV7.P9 ; UV7.E2 v2(40.14,97.93) UV7.D1 ; UV6.J8 36.55,72.92 v2(36.96,72.52) ; v2(31.23,79.01) 30.95,78.72 UV6.T1 ; UV6.D1 40.55,78.57 v2(40.17,78.94) 39.75,78.52 UV6.E1 ; UV7.T1 30.86,98.33 v2(30.51,98.68) ; UV7.D8 40.55,92.72 v2(40.16,92.33) 39.76,92.73 UV7.E8 ; UV6.B1 42.17,78.52 v2(42.59,78.94) ; UV6.E2 39.75,77.72 v2(40.15,78.12) ; v2(36.96,97.95) 36.55,97.53 UV7.J2 ; v2(30.71,91.42) 30.71,91.7 UV7.T9 ; UV6.G9 38.2,72.12 v2(38.57,71.75) UV6.F9 ; UV7.J8 36.55,92.7 v2(36.91,92.33) ; v2(32.94,78.96) 32.55,78.57 UV6.P1 ; UV7.E1 39.75,98.39 v2(39.35,98.78) ; v2(25.36,39.84) 25.84,39.84 26.26,39.42 UI4.1 ; UV7.M1 34.15,98.5 v2(33.81,98.84) ; v2(42.42,98.84) 42.15,98.56 UV7.B1 ; UV7.M9 v2(34.15,91.24) ; UV6.P9 32.55,72.09 v2(32.17,71.72) ; UV6.D8 40.55,72.93 v2(40.15,73.33) 39.75,72.93 UV6.E8 ; JXDP1.37 v2(89.72,74.71) ; UV7.P1 32.55,98.4 v2(32.11,98.84) ; UV6.G8 38.15,72.84 38.5,72.49 v2(38.51,72.49) ; JXDP1.49 v2(89.78,77.71) ; UV7.A9 43.3,91.93 43.64,91.59 43.64,91.43 v2(43.63,91.43) ; UV7.B3 42.15,96.42 v2(42.37,96.19) ; v2(42.35,76.4) 42.15,76.6 UV6.B3 ; v2(42.22,91.33) 42.22,91.86 UV7.B9 ; v2(34.17,71.52) 34.17,72.1 UV6.M9 ; UV7.G1 38.15,98.93 v2(38.39,99.17) ; UV6.J2 36.58,77.72 36.87,78.02 v2(36.87,78.13)
  TOP w0.279: v2(92.95,70.21) JXDP1.19 ; JXDP1.8 v2(84.13,67.21) 84.13,68.28 84.57,68.71 JXDP1.14 ; JXDP1.7 92.54,67.21 93.15,66.6 v2(94.29,66.6) 94.29,66.35 93.66,65.71 JXDP1.1 ; v2(89.34,79.81) 89.74,80.21 JXDP1.59 ; JXDP1.38 84.49,74.71 v2(84.13,74.35) ; JXDP1.50 v2(87.18,77.71) ; JXDP1.31 v2(92.97,73.21) ; JXDP1.20 84.46,70.21 84.13,70.54 v2(84.13,70.92) ; JXDP1.25 v2(92.97,71.71) ; v2(84.1,71.71) JXDP1.26 ; JXDP1.13 93.32,68.71 93.53,68.51 v2(94.29,68.51) ; JXDP1.2 v2(84.13,65.71) ; JXDP1.32 84.27,73.21 84.26,73.21 v2(84.13,73.21)
  TOP w0.381: CV41.2 59.52,80.45 59.82,80.14 60.86,80.14 61.1,79.91 v2(61.1,79.8) 60.81,79.51 CV47.2 60.46,79.23 CV60.2 60.69,78.54 CV57.2 ; CV90.2 59.59,85.09 v2(60.01,85.52) 60.01,85.67 59.77,85.91 CV40.2 58.63,85.53 CV42.2 ; PQ2.4 32.55,113.61 32.21,113.95 v2(32.21,114.05) ; v2(170.08,92.13) 170.24,92.13 170.84,92.74 UC3.3 ; UE2.3 109.36,26.32 108.45,27.23 v2(108.45,27.96) ; CV88.2 62.1,83.39 v2(62.1,82.89) ; CV89.2 59.44,82.38 v2(60.05,81.77) ; CV168.2 62.56,79.38 62.6,79.38 v2(62.98,79.76) 63.08,79.86 CV70.2 63.63,79.82 CV80.2 ; v2(55.43,94.96) 55.43,94.92 55.78,94.57 CV85.2 ; v2(161.64,97.47) 161.62,97.49 161.5,97.49 161.02,97.97 C66.2 160.66,97.73 C67.2 ; PC851.2 67.29,84.26 67.66,84.63 v2(67.86,84.63) ; CV53.2 57.23,79.53 56.8,79.96 v2(56.8,80.1) ; CV33.2 CV34.2 70.29,82.73 v2(70.54,82.48) ; RV38.2 CV97.2 66.05,93.55 v2(66.3,93.3) ; CV51.2 60.69,86.14 CV87.2 CV74.2 ; UV2.3 v2(76.88,77.13) ; v2(196.6,13.03) 195.94,13.69 CA60.2 ; PC871.2 65.47,88.29 v2(65.14,88.63) ; PC852.2 CV75.2 64.65,83.19 v2(65.07,82.78) 65.33,82.51 65.33,82.51 CV76.2 ; PQ1.4 32.48,108.66 32.14,109 v2(32.14,109.02) ; v2(36.25,106.86) 35.76,107.36 PQ1.1 ; PQ4.4 41.43,115.91 41.71,115.63 v2(42.47,115.63) 42.93,115.63 43.16,115.85 PR26.1 PC13.1 ; v2(65.93,84.63) 65.51,84.21 CV78.2 65,83.7 64.67,84.03 CV72.2 ; CV71.2 64.09,86.97 CV77.2 PC840.2 64.98,85.66 v2(64.82,85.5) ; v2(162.48,60.36) 162.48,61.28 158.59,65.17 QC2.1 157.63,64.95 RC368.2 ; v2(146,86.87) 145.52,87.35 C62.2 ; v2(66.96,85.58) 66.77,85.39 CV67.2 ; v2(68.73,77.16) 68.76,77.19 RV59.1 70.28,77.19 v2(70.38,77.3) 70.62,77.06 RV29.1 ; v2(62.05,80.74) 62.41,81.1 CV73.2 ; QV8.4 75.38,96.31 v2(75.37,96.32) 75.37,97.21 74.97,97.61 QV8.1 ; UV6.M1 34.15,78.84 v2(33.94,79.05) ; v2(33.2,111.74) 33.8,111.74 34.36,112.31 PQ2.1 ; C51.2 145.39,75.5 v2(145.03,75.5) ; RV160.2 72.65,79.73 v2(73.01,80.09) ; QC2.4 155.95,67.77 155.2,68.52 v2(153.78,68.52) ; UI2.1 191.66,40.65 191.86,40.86 v2(191.87,40.86) ; CA30.2 206.38,16.06 v2(206.76,15.68) 207.24,16.16 CA31.2 ; CV79.2 64.24,81.31 v2(64.8,80.75) ; v2(136,56.29) 135.97,56.32 134.68,56.32 134.4,56.04 134.4,54.54 134.79,54.14 U2303.3 ; PQ4.1 38.98,117.67 38.59,117.28 PC17.1 ; v2(14.28,33.84) 14.41,33.96 PQ706.1 ; v2(16.78,41.33) 16.06,40.61 16.06,39.55 15.71,39.2 PQ706.4
  TOP w0.406: PD101.1 v2(74.43,13.67)
  TOP w0.457: v2(62.13,85.48) 62.31,85.66 CV74.2 ; v2(62.1,87.63) 62.39,87.34 CV52.2 ; v2(69.09,82.5) 69.09,82.6 69.42,82.94 CV64.2 CV66.2 ; v2(144.08,89.33) 143.43,89.33 143.21,89.11 C64.2 ; CV63.2 CV62.2 67.54,79.35 67.32,79.58 67.32,80.42 66.94,80.8 v2(66.77,80.8) ; v2(142.64,94.2) 143.45,94.2 C88.2 ; C68.2 149.23,88.88 v2(149.66,88.45) ; C61.2 148.27,88.56 v2(148.35,88.65) ; v2(82.66,77.53) CC15.2 ; v2(149.77,93.93) 149.99,93.7 C53.2
  TOP w0.508: v2(186.49,6.53) 186.62,6.53 187.13,7.04 RS23.2 RS31.2 ; RE1.1 CE34.2 130.23,23.14 v2(130.36,23.27) 130.01,23.62 DE1.1 ; v2(185.86,39.55) 186.57,39.55 186.7,39.68 CI7.2 ; v2(57.55,91.71) 57.59,91.75 CV92.2 57.59,93.07 CV93.2 ; CI14.2 v2(186.75,52.51) ; CV134.2 33.58,103 v2(33.71,103.13) ; v2(151.57,4.62) 150.99,4.04 LE2.1 ; v2(195.26,49.05) 195.26,48.67 194.46,47.87 UI5.2 ; v2(77.04,21) PR107.1 PR108.2 ; C76.2 146.95,92.92 v2(147.19,92.68) ; CC13.2 88.47,84.83 v2(88.41,84.76) ; v2(135.53,32.49) 135.87,32.49 136.45,33.08 CD43.2 ; RC163.2 112.63,101.99 v2(112.6,102.01) 112.37,102.24 110.96,102.24 110.6,101.88 R2.2 ; PC902.2 142.02,100.86 v2(142.32,100.55) ; v2(5.8,79.73) 5.47,80.07 RX9.2 ; CV160.2 RV57.2 28.33,92.03 v2(28.56,92.26) ; v2(150.65,30.07) 150.42,29.85 CD52.2 CD53.2 ; v2(169.78,101.99) 169.96,102.16 RL35.1 171.05,102.6 170.87,102.78 CL17.2 ; CG8.2 v2(187.84,75.49) ; v2(73.59,88.6) 73.62,88.57 CV26.2 ; v2(196.55,72.13) 196.87,72.45 RX34.2 CX20.2 ; CA22.2 6,81.69 v2(6.26,81.69) ; UX3.2 9.96,96.32 10.47,96.83 v2(10.47,96.96) ; v2(73.56,46.09) 73.98,46.09 74.34,46.45 PC1044.2 ; CV124.2 CV132.2 37.52,67.37 v2(37.65,67.24) ; R159.2 175.22,92.21 v2(175.44,91.98) ; v2(187.64,54.28) 187.17,54.28 CI12.2 186.78,53.87 187.13,53.52 v2(187.64,53.52) ; RC90.2 149.66,73.14 149.02,72.5 RC101.2 147.33,72.5 146.99,72.84 v2(146.99,74.45) 147.5,74.45 147.71,74.65 CC35.2 RC134.2 ; CD14.2 129.72,45.93 v2(129.79,45.86) ; CD41.2 142.04,33.04 v2(141.87,32.87) ; v2(197.92,13.01) 198.1,13.19 CA58.2 198.57,13.2 CA57.2 ; v2(123.65,42.33) 123.54,42.22 123.37,42.22 122.74,41.58 CD5.2 ; PC923.2 122.82,92.01 v2(121.31,92.01) ; CX3.2 7.42,90.61 7.58,90.76 v2(7.58,91.37) DX2.1 ; v2(81.39,70.46) 81.01,70.84 CV46.2 ; CV125.2 CV121.2 v2(35.74,67.29) ; RC132.2 118.42,92.89 v2(118.51,92.98) ; CX7.2 10.86,79.05 11.09,78.82 v2(11.09,77.78) QX1.3 ; v2(62.44,74.94) 62.58,74.79 CV55.2 ; v2(174.81,113.85) 175.57,113.85 176.25,113.17 SW1.2 ; v2(6.91,100.39) 7.26,100.73 CX49.2 ; v2(95.56,75.87) 96.02,75.42 CC14.2 ; PC7.2 PC8.2 18.93,31.37 v2(18.73,31.17) ; v2(133.64,42.43) 133.36,42.43 132.77,41.84 CD19.2 ; v2(78.16,81.21) RV12.2 CV28.2 ; CV159.2 CV165.2 31.81,103.03 31.86,103.08 v2(31.86,103.15) ; v2(156.95,46.16) 157.41,46.61 RD6.1 ; CD46.2 132.88,27.3 v2(133.5,27.91) ; PC841.2 62.44,88.42 v2(63.1,88.42) ; v2(184.59,76.76) 184.26,76.43 CG4.2 ; RE5.1 CE8.2 149.78,6.21 v2(149.78,7.27) ; v2(116.24,20.35) 115.14,20.35 114.6,19.81 114.6,19.57 JKBBL.5 115.04,19.13 v2(116.19,19.13) ; v2(39.5,66.98) 39.25,67.24 39.25,68 CV128.2 CV122.2 ; UE3.5 2.98,63.56 3.36,63.17 3.36,62.54 3.74,62.16 v2(3.99,62.16) ; v2(127.95,41.69) 127.41,41.69 127.06,41.33 CD6.2 ; RS22.1 184.47,7.07 184.13,6.72 184.11,6.72 v2(184.02,6.63) 183.58,7.07 RS18.2 ; CX2.2 v2(6.13,90.48) RX24.1 ; v2(145.39,92.12) 144.84,91.57 C69.2 ; CV130.2 28.76,67.49 v2(28.89,67.37) ; CD48.2 143.31,32.82 143.69,32.44 144.19,32.44 v2(144.23,32.49) 144.76,32.49 145.09,32.82 CD42.2 ; C93.2 176.16,81.01 v2(176.1,80.95) ; CD45.2 140.77,32.82 140.44,32.49 v2(139.67,32.49) ; v2(38.87,103.15) 38.87,102.54 CV154.2 ; v2(184.59,75.62) 184.59,75.75 184.97,76.13 CG9.2 185.27,76.01 YG1.2 ; RC123.2 175.27,98.4 v2(175.06,98.61) ; CD36.2 141.92,28.25 v2(141.87,28.29) ; v2(127.28,100.55) 126.97,100.86 PC920.2 ; CL16.1 170.54,106 v2(170.34,106.2) ; v2(194.87,44.37) 194.87,44.37 194.69,44.19 UI6.2 ; v2(123.3,6.96) 123.3,6.74 124.64,5.39 RE18.2 ; C2325.2 165.03,9.45 v2(164.65,9.07) ; v2(23.37,42.6) 23.74,42.23 UI7.2 ; v2(78.29,87.05) RV13.2 CV11.2 ; v2(13.75,62.93) 13.34,63.34 CE60.2 ; CE27.2 v2(127.23,17.07) ; v2(142.93,23.45) 142.93,23.23 142.61,22.91 RE47.1 ; CX52.2 11.28,94.59 v2(11.49,94.8) ; C2322.2 174.11,9.9 v2(174.3,10.09) ; C73.2 148.32,91.62 v2(148.32,91.2) 148.18,91.06 C75.1 ; CV152.2 32.7,103.03 32.75,103.08 v2(32.75,103.15) ; CI26.2 186.37,38.41 v2(185.86,38.92) ; v2(65.11,89.49) 65.16,89.54 65.64,89.54 66.17,90.07 PC872.2 ; RX41.2 11.63,72.52 v2(11.42,72.73) ; v2(147.38,95.51) 147.43,95.56 C92.1 ; v2(136.42,44.78) 136.05,44.78 135.69,45.14 135.69,46.16 136.2,46.66 CD9.2 ; RV2.1 v2(61.91,99.01) ; CG7.2 v2(192.72,80.95) ; CV155.2 37.39,102.49 v2(37.39,103.15) ; CD8.2 135.69,41.49 135.92,41.72 v2(136.41,41.72) 136.7,41.72 137.34,41.08 CD21.2 ; v2(119.61,100.84) 118.95,101.5 C80.2 ; v2(6.65,62.79) 6.79,62.94 UE3.8 ; v2(29.14,107.75) 29.52,107.37 PR10.1 ; CE6.1 128.78,14.66 v2(129.04,14.91) ; CX51.2 13.73,100.86 v2(13.9,101.02) ; UE3.7 5.52,62.91 6.39,62.03 v2(6.65,62.03) ; CE19.2 111.21,21.87 CE15.2 111.23,21.35 v2(111.5,21.09) ; Q8.3 173.74,4.02 174.66,4.93 v2(174.66,4.96) ; v2(17.37,19.78) 17.77,19.37 PD1.1 ; CE18.1 140.14,23.02 v2(139.88,23.27) ; v2(182.07,16.44) 182.12,16.39 RS24.2 RS21.2 ; CV119.2 CV123.2 ; CV123.2 v2(26.41,72.45) ; CV123.2 CV179.2 ; CD39.2 134.17,33.16 v2(133.5,32.49) ; R2351.1 143.39,52.38 143.57,52.2 145.8,52.2 146.49,51.52 v2(146.49,51.36) ; JTP.9 31.28,56.58 v2(32.26,56.58) ; v2(72.9,12.63) PR114.2 ; CE25.2 9.65,68.57 9.33,68.25 v2(8.82,68.25) ; CD13.2 126.55,46.73 126.55,45.78 126.15,45.38 v2(125.87,45.38) ; v2(137.3,100.55) 137,100.86 PC916.2 ; v2(149.66,88.45) 149.66,88.27 149.99,87.94 C77.2 150.86,87.56 C52.2 ; v2(57.28,69.85) 57.33,69.8 RV34.2 CV94.2 ; C71.2 148.95,91.85 148.95,91.22 v2(148.98,91.19) ; UI2.9 v2(192.84,38.41) ; v2(129.78,100.55) 129.48,100.86 PC919.2 ; PR110.2 72.57,11.5 72.88,11.8 v2(72.88,11.94) ; v2(183.98,83.88) 183.98,83.34 183.71,83.08 CG5.2 183.17,83.48 v2(183.17,83.88) ; CV59.2 60.94,74.83 v2(60.84,74.94) 60.43,74.94 60.1,75.26 CV58.2 ; v2(125.87,42.33) 125.86,42.35 125.53,42.35 124.9,41.71 CD17.2 ; CL5.2 178.34,103.64 CL12.2 ; CV173.2 v2(33.97,67.29) ; v2(146.17,29.46) 145.92,29.46 145.22,28.76 CD37.2 CD38.2 ; v2(60.43,90.1) 60.52,90.1 60.99,89.63 60.99,89.06 CV50.2 ; CV127.2 v2(32.95,67.21) ; v2(6.79,86.92) 6.79,86.9 6.56,86.67 CX1.2 ; PC922.2 122.73,95.91 v2(121.31,95.91) ; PC917.2 134.5,100.86 v2(134.8,100.55) ; v2(150.88,84.93) 150.69,84.93 C81.2 ; PC842.2 63.45,89.23 v2(62.86,89.23) ; PC5.2 PR2.2 37.78,109.15 38.16,109.53 v2(38.16,109.66) ; PC921.2 124.1,100.86 v2(124.39,100.57) ; CE28.2 126.52,12.88 v2(126.75,13.11) 126.98,12.88 CE36.2 ; PC1035.2 57.78,35.81 57.46,36.12 56.47,36.12 56.24,36.35 PC1030.2 ; v2(145.06,23.07) 145.41,22.72 RE326.2 RE2.1 ; v2(68.13,97.79) 68.13,97.26 CV96.2 ; v2(185.17,22.61) 186.7,22.61 RA32.2 ; v2(172.22,34.22) 172.01,34.22 171.79,34.45 RD13.2 ; SW1.1 172.95,112.5 173.05,112.5 v2(173.06,112.5) 173.06,112.48 173.08,112.5 SW1.5 ; v2(3.99,63.05) 4.25,63.3 UE3.6 ; CA29.2 202.42,16.11 v2(202.11,15.8) ; v2(76.13,78.16) 75.88,77.91 RV4.2 75.8,77.27 CV61.2 ; CC42.2 v2(110.52,99.75) ; RV9.2 CV29.2 v2(78.16,83.49) ; Q2307.3 169.81,2.93 169.75,2.87 v2(169.75,2.47) ; v2(145.42,90.38) 145.85,90.8 C78.2 ; v2(112.71,71.56) 112.91,71.35 RC70.2 RC68.2 RC69.2 ; v2(132.29,100.55) 131.99,100.86 PC918.2 ; CV15.2 RV16.2 v2(78.16,79.05) ; v2(175.04,95.13) 175.22,94.95 CC11.2 ; CV65.2 69.02,81.74 69.02,82.43 v2(69.09,82.5) ; CX8.2 v2(8.69,84) 8.69,83.75 7.98,83.04 CX9.2 ; v2(83.65,48.73) 85.01,50.1 JKB.32 ; CS42.2 v2(179.13,6.53) ; v2(58.93,95.3) 59.84,95.3 CV82.2 ; C90.2 v2(176.59,87.3) ; v2(147.67,116.64) 146.88,116.64 146.75,116.77 C85.2 ; CE23.2 v2(3.54,72.39) ; RX14.2 198.51,75.49 v2(199.21,75.49) ; CE30.2 138.11,22.89 138.26,23.04 v2(138.26,23.27) ; CV162.2 v2(40.82,103.13) ; v2(121.73,42.33) 121.45,42.33 120.83,41.71 CD16.2 ; CV86.2 55.78,92.1 55.41,91.73 v2(55.17,91.73) ; UX4.2 v2(22.22,72.99) ; PR9.1 v2(18.98,100) ; C91.1 v2(144.96,71.56) ; R16.2 172.22,7.62 v2(172.01,7.42) ; v2(149.7,92.39) 149.7,91.65 C82.2 ; CG6.2 184.19,79.34 v2(184.19,78.72) ; v2(183.5,26.85) 183.32,26.67 C2326.2 ; CV153.2 v2(38.16,103.18) ; v2(127.96,45.48) 127.65,45.48 127.31,45.82 127.31,46.54 127.74,46.97 CD10.2 ; CV120.2 v2(31.17,67.21) ; v2(185.86,41.97) 186.75,41.97 187.04,41.67 CI6.2 187.04,41.5 186.62,41.08 v2(185.86,41.08) ; RM9.2 127.11,6.63 127.54,6.2 v2(127.54,6.18) 127.62,6.1 CE31.2 ; CD49.2 138.74,28 139.42,28.68 v2(139.67,28.68) ; v2(72.11,87.68) 72.57,88.15 CV27.2 ; CC17.2 v2(81.97,79.18) ; QX3.3 196.98,86.11 v2(196.78,85.91) ; v2(121.68,13.25) 122.9,12.03 QE5.4 ; CG2.2 v2(190,78.21) CG10.2 ; CX22.2 198.38,82.16 v2(197.82,81.6) ; C87.2 145.7,95.62 v2(145.5,95.42) 145.49,95.41 144.79,95.41 C83.2 ; PU400.1 v2(204.72,12.31) ; CD33.2 108.13,40.8 108.54,41.2 108.54,41.69 108.06,42.17 v2(107.88,42.17) ; PC100.2 v2(73.13,9.29) ; CC29.2 v2(84.44,87.48) ; v2(30.66,103.18) 30.41,103.18 30.03,102.8 CV163.2 CV164.2 ; RV150.1 60.56,92.52 v2(60.42,92.67) ; CE22.2 v2(8.44,72.89) ; v2(60.06,72.53) 60,72.59 RV39.1 ; PR724.1 17.46,33.86 16.54,32.95 v2(15.17,32.95) ; CC33.2 v2(169.09,94.11) ; v2(148.35,69.79) 148.35,68.94 v4(148.46,68.84) 148.8,68.5 CC4.1 ; PC109.2 76.42,18.1 76.19,18.33 v3(76.19,18.42) ; CV157.2 v2(39.93,103.18) ; RV40.1 63.73,98.91 v2(63.71,98.94) ; RA19.2 189.36,13.82 v2(188.98,13.44) ; v2(158.55,49.08) 158.43,48.95 RD7.1 ; v2(191.57,15.42) 191.45,15.3 CA69.2 RA81.1 ; v2(112.45,24.69) 112.26,24.5 CE56.2 CE57.2 ; v2(144.23,28.68) 143.87,28.68 143.57,28.38 CD50.2 ; CD12.2 124.39,45.9 123.86,45.38 v2(123.65,45.38) ; CE24.2 v2(2.52,75.54) ; JKB.31 88.75,22.2 v2(89.08,22.53) ; PC1021.2 63.8,42.27 v2(66.48,42.27) ; PR33.1 v2(29.14,113.47) ; v2(105.41,42.29) 105.15,42.29 104.58,41.71 104.58,41.08 104.83,40.82 CD3.2 ; RA30.2 186.43,24.5 185.43,23.5 185.4,23.5 v2(185.15,23.25) ; CE35.2 128.44,19.92 v2(128.76,20.23) ; v2(115.7,9.91) 115.7,10.67 115.21,11.17 JKBBL.6 114.7,10.51 114.99,10.22 v2(114.99,9.91) ; PH1002.1 50.56,44.67 v2(51.29,45.39) ; v2(133.64,45.48) 133.32,45.48 133.03,45.78 133.03,46.85 CD20.2 ; v2(151.47,13.54) 151.44,13.52 CE32.2 ; v2(131.26,45.48) 131.46,45.48 131.88,45.9 CD11.2 ; v2(109.15,40.95) CD32.2 ; v2(57.9,71.77) 57.97,71.7 57.97,70.69 57.74,70.46 CV95.2 RV35.2 ; v2(11.87,90.23) 11.36,89.72 RX36.2 ; v2(24.31,58.86) 24.66,59.2 JTP1.7 ; CVT90.1 60.89,102.04 61.25,102.39 v2(62.16,102.39) ; CV49.2 58.53,88.19 58.78,88.45 v2(59.06,88.45) ; v2(200.73,82.02) 200.69,82.02 200.65,81.98 CX21.2 RX13.2 ; v3(66.86,24.06) 66.93,24.06 67.39,23.6 PC103.2 ; v2(121.9,20.38) 121.9,19.79 122.09,19.6 QE4.3 122.09,18.38 RE58.2 ; v2(60.23,96.58) 59.59,96.58 CV83.2 ; CD4.2 119.31,41.86 v2(119.78,42.33) ; RC2.2 173.92,64.32 v2(174.17,64.06) 175.57,64.06 176.4,64.89 CC26.2 ; v2(61.52,94.06) 61.39,94.19 CV91.2 ; CX11.2 8.95,89.97 9.2,90.23 v2(9.58,90.23) ; CD44.2 131.97,32.98 v2(131.97,32.47) ; PR1051.2 55.48,40.44 v2(54.92,41) ; v2(122.26,100.55) 121.96,100.86 PC907.2 ; v2(123.66,14.05) 123.66,13.77 123.96,13.47 124.63,13.47 124.94,13.77 CE12.2 ; CL41.1 183.9,106.87 183.41,106.38 v2(182.16,106.38) ; v3(41.33,47.93) 41.99,48.59 41.99,49.43 PC1106.2 ; CD40.2 138.11,32.84 137.75,32.49 v2(137.39,32.49) ; CE26.2 150.83,17.66 v2(150.83,18.01) ; v2(187.64,56.19) 187.29,56.19 CI18.2 187.17,55.3 v2(187.64,55.3) ; v2(75.56,108.29) 75.4,108.13 PR512.2 ; RS36.2 180.9,6.98 v2(180.46,6.53) 180.02,6.98 CS27.2 ; PC17.1 PR34.1 38.36,118.6 v2(37.9,119.05) ; RC23.2 v2(121.72,61.65) ; CC1.1 174.38,75.19 v2(173.67,74.48) ; RS35.2 185.82,16.55 v2(185.82,17.07) ; v2(150.2,96.91) 150.32,97.03 C57.2 ; CV118.2 v2(29.9,66.97) ; CD34.2 115.83,27.77 116.28,28.22 v2(116.62,28.22) ; C50.2 149.54,93.7 v2(149.77,93.93) ; SW1.6 v2(174.48,118.37) ; YG1.4 v2(188.74,72.92) ; CE58.2 18.78,63.13 v2(18.31,62.67) ; CX5.2 v2(2.28,76.22) ; CD64.2 147.61,55.33 v2(147.5,55.22) ; RX26.2 v2(5.77,81.08) ; v2(95.5,50.75) 95.93,51.19 CD2.2 CD1.2 ; PR1035.1 v2(67.62,37.14) ; v2(57.07,99.35) 57.06,99.35 56.32,98.61 56.32,97.53 CV84.2 57.52,97.27 58.1,97.85 CV81.2 ; RV17.1 v2(59.87,103.18) ; RC20.2 v2(121.72,62.67) ; CI17.2 196.91,36.31 RA29.2 195.99,35.68 v2(195.51,36.16) ; 211.82,11.74 PC402.2 PR403.2 ; 211.82,11.74 v2(211.82,11.18) ; 211.82,11.74 v2(211.84,11.76) ; CD7.2 130.49,42.85 130.82,43.19 v2(131.26,43.19) ; RS37.2 177.31,9.34 v2(176.73,9.92) ; Q2308.3 v2(164.5,3.71) ; CA54.2 v2(201.22,14.41) ; CD35.2 136.78,27.31 v2(137.39,27.91) ; CI13.2 v2(186.75,51.62) ; CG3.2 v2(186.37,83.49) ; C2498.2 154.12,5.71 154.22,5.71 v2(154.79,5.14) ; RC138.2 116.31,89.44 v2(116.89,88.87) ; RC21.2 v2(117.15,65.71) ; CC2.1 v2(173.67,70.72) ; CV161.2 v2(41.71,103.1) ; CD22.2 138.36,42.51 v2(138.72,42.87) ; v2(212.2,16.69) 211.94,16.44 CA32.2 ; v2(139.81,100.55) 139.51,100.86 PC915.2 ; C2327.2 v2(176.99,26.12) ; C56.2 C54.2 C55.2 153.83,70.31 v2(153.83,69.31) 151.8,69.31 150.98,68.5 CC3.1 ; v2(77.1,16.06) PR105.2 ; v2(136,56.29) 136.28,56.57 CD23.2 ; PQ5.3 v2(23.06,98.75) ; CE2.2 CE29.2 127.11,7.93 v2(127.23,7.8) ; v2(177.09,83.75) 176.97,83.88 CC37.2 CC38.2 ; RA31.2 199.02,24.24 v2(198.81,24.44) ; RC24.2 v2(117.15,66.73) ; CE59.2 13.34,64.99 v2(13.81,65.46) ; CD47.2 147,32.82 146.61,32.44 146.24,32.44 v2(146.17,32.51) ; CC16.2 v2(95.56,77.53) ; v2(38.28,111.69) 38.16,111.82 PR29.2 ; CX50.2 v2(7.09,97.08) ; PD2.1 v2(18.34,22.92) ; CV158.2 v2(42.6,103.13) ; CI15.2 v2(195.65,50.19) ; CE1.2 CE11.2 128.04,2.47 127.78,2.21 v2(127.56,2.21) ; CV54.2 64.57,72.27 v2(64.7,72.15) ; PR1056.1 v2(67.62,38.03) ; v2(129.79,43.57) 129.43,43.57 128.96,43.11 CD18.2 ; CV126.2 v2(27.16,69.85) ; CV180.2 v2(43.49,103.1) ; CI47.2 v2(27.57,45.72) ; RV41.1 v2(62.79,98.99) ; v2(159.8,114.38) 159.44,114.02 RC84.1 ; v2(35.49,103.18) 35.36,103.05 RV53.2 ; RC25.2 v2(113.09,61.65) ; CV129.2 v2(32.06,67.21) ; RC22.2 v2(113.09,62.67) ; CE61.1 122.92,3.31 v2(122.87,3.36) ; C89.1 v2(157.11,23.55) ; CV156.2 v2(36.38,103.18) ; CV131.2 v2(34.85,67.29)
  TOP w0.559: UX1.2 11.11,82.73 v2(11.23,82.61)
  VCC w0.203: PBATT.2 15.03,14.52 ; PBATT.2 14.76,13.71 ; PBATT.2 14.76,15.33 ; PBATT.10 16.08,31.65 ; PBATT.10 16.08,30.67 ; PBATT.10 16.08,32.62 ; PBATT.10 14.2,30.67 ; PBATT.4 14.76,19.33 ; PBATT.4 15.03,18.52 ; PBATT.4 14.76,17.71 ; 20.46,8.46 H7.1 ; H7.1 23.14,11.14 ; H7.1 23.14,8.46 ; H7.1 21.8,11.63 ; H7.1 20.46,11.14 ; H7.1 21.8,7.97 ; H7.1 19.97,9.8 ; H7.1 23.63,9.8 ; PBATT.1 14.76,11.71 ; PBATT.1 15.03,12.52 ; PBATT.1 13.95,11.44 ; PBATT.1 14.76,13.33 ; 40.15,62.09 H18.1 ; H18.1 43.75,60.57 ; H18.1 43.19,62.09 ; H18.1 43.19,59.05 ; H18.1 39.59,60.57 ; H18.1 40.15,59.05 ; H18.1 41.67,58.49 ; H18.1 41.67,62.65 ; 14.2,8.42 PBATT.11 ; PBATT.11 16.08,9.4 ; PBATT.11 16.08,8.42 ; PBATT.11 16.08,10.37 ; PBATT.11 14.2,10.37
  GND w0.102: 38.16,97.46 38.16,96.7 ; 36.63,94.54 36.63,94.8 36.63,94.8 36.63,95.82 36.63,95.83 ; 30.28,94.67 30.28,94.78 30.25,94.81 30.25,95.91 30.28,95.94 ; 33.44,95.92 33.44,94.82 33.46,94.8 33.45,94.8 33.46,94.79 33.46,94.54 ; 31.81,94.42 31.81,94.78 31.84,94.81 31.84,95.9 31.81,95.94 ; 37.39,96.83 37.35,96.87 37.35,97.3 37.39,97.34 ; 35.11,94.54 35.03,94.62 35.03,95.83 ; 32.7,94.42 32.7,94.76 32.65,94.8 32.65,96.15 32.7,96.19 ; 35.84,95.8 35.84,94.8 35.84,94.8 35.84,94.57 ; 31.04,95.94 31.04,94.54 ; 38.47,97.55 38.96,97.55 ; 32.65,75.99 32.65,74.69 ; 30.27,76 30.27,74.99 ; 36.61,75.99 36.61,74.79 ; 31.84,75.94 31.84,75 ; 35.02,75.97 35.02,74.77 ; 31.04,76.13 31.04,74.73 ; 34.23,76.01 34.23,74.99 ; 35.82,75.99 35.82,74.79 ; 34.23,95.83 34.23,94.55
  GND w0.203: JUSB1.12 203.45,73.1 ; JUSB1.12 199.89,73.1 ; JUSB1.12 199.89,73.97 ; JUSB1.12 201.67,73.97 ; JUSB1.12 199.89,72.22 ; JUSB1.12 203.45,73.97 ; 202.97,84.7 JHDMI.11 ; JHDMI.11 204.01,84.24 ; JHDMI.11 204.01,85.16 ; JHDMI.11 204.13,84.7 ; JHDMI.11 203.09,84.24 ; JHDMI.11 203.09,85.16 ; 164.46,71.14 H12.1 ; H12.1 164.46,68.46 ; H12.1 167.14,68.46 ; H12.1 165.8,71.63 ; H12.1 167.14,71.14 ; H12.1 163.97,69.8 ; H12.1 165.8,67.97 ; H12.1 167.63,69.8 ; 202.97,87.7 JHDMI.5 ; JHDMI.5 203.09,87.24 ; JHDMI.5 204.01,87.24 ; JHDMI.5 204.13,87.7 ; JHDMI.5 204.01,88.16 ; JHDMI.5 203.09,88.16 ; H7.1 23.14,8.46 ; H7.1 23.14,11.14 ; H7.1 23.63,9.8 ; H7.1 21.8,7.97 ; H7.1 21.8,11.63 ; H7.1 19.97,9.8 ; H7.1 20.46,11.14 ; H7.1 20.46,8.46 ; 201.85,91.52 JHDMI.20 ; JHDMI.20 200.57,91.52 ; JHDMI.20 203.13,91.52 ; JHDMI.20 200.57,93.38 ; JHDMI.20 203.13,93.38 ; JHDMI.20 201.85,93.38 ; JHDMI.20 200.57,92.45 ; JHDMI.20 203.13,92.45 ; H5.1 196.83,4 ; H5.1 193.66,5.34 ; H5.1 193.17,4 ; H5.1 195,5.83 ; H5.1 196.34,5.34 ; H5.1 195,2.17 ; H5.1 193.66,2.66 ; H5.1 196.34,2.66 ; H16.1 106.23,82.73 ; H16.1 102.97,82.73 ; H16.1 106.84,81.1 ; H16.1 104.6,78.86 ; H16.1 104.6,83.34 ; H16.1 106.23,79.47 ; H16.1 102.97,79.47 ; H16.1 102.36,81.1 ; 199.96,65.25 JUSB1.7 ; JUSB1.7 200.16,64.61 ; JUSB1.7 200.16,65.88 ; JUSB1.7 200.79,66.07 ; JUSB1.7 200.79,64.42 ; JUSB2.13 210.14,55.77 ; JUSB2.13 207.4,54.9 ; JUSB2.13 208.77,55.77 ; JUSB2.13 207.4,55.77 ; JUSB2.13 210.14,54.9 ; 27.8,116.97 H9.1 ; H9.1 27.8,120.63 ; H9.1 26.46,117.46 ; H9.1 26.46,120.14 ; H9.1 25.97,118.8 ; H9.1 29.63,118.8 ; H9.1 29.14,117.46 ; H9.1 29.14,120.14 ; JLAN.9 207.62,113.55 ; JLAN.9 206.1,114.27 ; JLAN.9 207.62,114.27 ; JLAN.9 204.58,113.55 ; JLAN.9 204.58,114.27 ; JUSB2.12 203.45,55.77 ; JUSB2.12 199.89,54.9 ; JUSB2.12 201.67,55.77 ; JUSB2.12 199.89,55.77 ; JUSB2.12 199.89,54.02 ; JUSB2.12 203.45,54.9 ; H17.1 86.32,108.91 ; H17.1 87.84,108.35 ; H17.1 88.4,106.83 ; H17.1 87.84,105.31 ; H17.1 84.79,108.35 ; H17.1 84.23,106.83 ; H17.1 86.32,104.75 ; H17.1 84.79,105.31 ; 199.89,57.4 JUSB1.10 ; JUSB1.10 203.45,57.4 ; JUSB1.10 201.67,56.52 ; JUSB1.10 199.89,58.27 ; JUSB1.10 199.89,56.52 ; JUSB1.10 203.45,56.52 ; H13.1 166.63,104.87 ; H13.1 163.37,108.13 ; H13.1 167.24,106.5 ; H13.1 165,104.26 ; H13.1 163.37,104.87 ; H13.1 166.63,108.13 ; H13.1 165,108.74 ; H13.1 162.76,106.5 ; JHDMI.22 203.13,77.95 ; JHDMI.22 201.85,77.02 ; JHDMI.22 203.13,77.02 ; JHDMI.22 200.57,78.88 ; JHDMI.22 203.13,78.88 ; JHDMI.22 201.85,78.88 ; JHDMI.22 200.57,77.95 ; JHDMI.17 204.01,82.16 ; JHDMI.17 202.97,81.7 ; JHDMI.17 204.13,81.7 ; JHDMI.17 203.09,82.16 ; JHDMI.17 203.09,81.24 ; JHDMI.17 204.01,81.24 ; H19.1 183.81,91.35 ; H19.1 181.73,89.27 ; H19.1 183.25,92.87 ; H19.1 180.21,89.83 ; H19.1 180.21,92.87 ; H19.1 179.65,91.35 ; H19.1 181.73,93.43 ; H19.1 183.25,89.83 ; JUSB1.4 199.29,69.57 ; JUSB1.4 198.65,68.11 ; JUSB1.4 198.46,68.75 ; JUSB1.4 199.29,67.92 ; JUSB1.4 199.92,68.11 ; JUSB1.4 198.65,69.38 ; PBATT.1 15.03,12.52 ; PBATT.1 12.87,12.52 ; PBATT.1 14.76,11.71 ; PBATT.1 14.76,13.33 ; PBATT.1 13.95,11.44 ; PBATT.1 13.14,13.33 ; PBATT.1 13.14,11.71 ; 199.89,40.07 JUSB2.10 ; JUSB2.10 199.89,39.2 ; JUSB2.10 203.45,39.2 ; H8.1 84.14,56.46 ; H8.1 82.8,55.97 ; H8.1 84.14,59.14 ; H8.1 84.63,57.8 ; H8.1 81.46,56.46 ; H8.1 82.8,59.63 ; H8.1 80.97,57.8 ; H8.1 81.46,59.14 ; JUSB1.13 210.14,73.97 ; JUSB1.13 208.77,73.97 ; JUSB1.13 210.14,73.1 ; JUSB1.13 207.4,73.1 ; 198.65,49.91 JUSB2.4 ; JUSB2.4 199.92,49.91 ; JUSB2.4 198.65,51.18 ; JUSB2.4 198.46,50.55 ; JUSB2.4 199.29,49.72 ; JUSB2.4 199.29,51.37 ; 104.6,104.3 H15.1 ; H15.1 102.4,106.5 ; H15.1 106.8,106.5 ; H15.1 103,108.1 ; H15.1 103,104.9 ; H15.1 106.2,108.1 ; H15.1 104.6,108.7 ; H15.1 106.2,104.9 ; H11.1 23.93,92.1 ; H11.1 22.1,90.27 ; H11.1 20.76,90.76 ; H11.1 22.1,93.93 ; H11.1 23.44,93.44 ; H11.1 20.76,93.44 ; H11.1 23.44,90.76 ; H11.1 20.27,92.1 ; 200.16,47.68 JUSB2.7 ; JUSB2.7 200.16,46.41 ; JUSB2.7 199.96,47.05 ; JUSB2.7 200.79,46.22 ; JUSB2.7 200.79,47.87 ; H4.1 184.83,32.1 ; H4.1 184.34,30.76 ; H4.1 183,33.93 ; H4.1 181.66,30.76 ; H4.1 183,30.27 ; H4.1 184.34,33.44 ; H4.1 181.66,33.44 ; H4.1 181.17,32.1 ; JHDMI.8 202.46,86.66 ; JHDMI.8 201.54,86.66 ; JHDMI.8 202.46,85.74 ; JHDMI.8 201.42,86.2 ; JHDMI.8 202.58,86.2 ; JHDMI.8 201.54,85.74 ; 193.67,96.4 H3.1 ; H3.1 195.5,98.23 ; H3.1 194.16,97.74 ; H3.1 196.84,95.06 ; H3.1 194.16,95.06 ; H3.1 195.5,94.57 ; H3.1 196.84,97.74 ; H3.1 197.33,96.4 ; 99.17,3.5 H6.1 ; H6.1 102.34,2.16 ; H6.1 99.66,4.84 ; H6.1 99.66,2.16 ; H6.1 102.83,3.5 ; H6.1 101,5.33 ; H6.1 101,1.67 ; H6.1 102.34,4.84 ; 12.32,31.65 PBATT.10 ; PBATT.10 12.32,30.67 ; PBATT.10 12.32,32.62 ; PBATT.10 14.2,30.67 ; PBATT.10 16.08,30.67 ; PBATT.10 16.08,31.65 ; PBATT.10 16.08,32.62 ; 12.32,8.42 PBATT.11 ; PBATT.11 16.08,8.42 ; PBATT.11 16.08,10.37 ; PBATT.11 14.2,10.37 ; PBATT.11 16.08,9.4 ; PBATT.11 12.32,9.4 ; PBATT.11 14.2,8.42 ; PBATT.11 12.32,10.37 ; 165,78.86 H14.1 ; H14.1 166.63,82.73 ; H14.1 167.24,81.1 ; H14.1 165,83.34 ; H14.1 163.37,82.73 ; H14.1 166.63,79.47 ; H14.1 163.37,79.47 ; H14.1 162.76,81.1 ; 204.58,97.55 JLAN.10 ; JLAN.10 207.62,96.83 ; JLAN.10 207.62,97.55 ; JLAN.10 206.1,96.83 ; JLAN.10 204.58,96.83 ; 208.77,95.28 JHDMI.21 ; JHDMI.21 208.77,94.35 ; JHDMI.21 208.77,93.42 ; JHDMI.21 210.05,93.42 ; JHDMI.21 210.05,95.28 ; JHDMI.21 211.33,93.42 ; JHDMI.21 211.33,94.35 ; JHDMI.21 211.33,95.28 ; 13.14,15.33 PBATT.2 ; PBATT.2 13.14,13.71 ; PBATT.2 12.87,14.52 ; PBATT.2 14.76,15.33 ; PBATT.2 14.76,13.71 ; PBATT.2 15.03,14.52 ; 207.4,56.52 JUSB1.11 ; JUSB1.11 210.14,57.4 ; JUSB1.11 208.77,56.52 ; JUSB1.11 207.4,57.4 ; JUSB1.11 210.14,56.52 ; H18.1 41.67,62.65 ; H18.1 43.75,60.57 ; H18.1 39.59,60.57 ; H18.1 40.15,62.09 ; H18.1 41.67,58.49 ; H18.1 40.15,59.05 ; H18.1 43.19,62.09 ; H18.1 43.19,59.05 ; PBATT.4 15.03,18.52 ; PBATT.4 13.14,19.33 ; PBATT.4 13.14,17.71 ; PBATT.4 14.76,19.33 ; PBATT.4 14.76,17.71 ; PBATT.4 12.87,18.52 ; JHDMI.23 212.58,75.12 ; JHDMI.23 210.02,76.98 ; JHDMI.23 210.02,76.05 ; JHDMI.23 212.58,76.05 ; JHDMI.23 210.02,75.12 ; JHDMI.23 211.3,76.98 ; JHDMI.23 212.58,76.98 ; JHDMI.23 211.3,75.12 ; H2.1 199.74,117.46 ; H2.1 200.23,118.8 ; H2.1 198.4,120.63 ; H2.1 199.74,120.14 ; H2.1 197.06,120.14 ; H2.1 197.06,117.46 ; H2.1 196.57,118.8 ; H2.1 198.4,116.97 ; 201.42,89.2 JHDMI.2 ; JHDMI.2 202.58,89.2 ; JHDMI.2 202.46,89.66 ; JHDMI.2 201.54,88.74 ; JHDMI.2 202.46,88.74 ; JHDMI.2 202,89.78 ; JHDMI.2 201.54,89.66
  BOTTOM w0.076: 140.75,101.42 140.75,105.06 v2(140.77,105.08)
  BOTTOM w0.102: v2(78.16,81.21) v4(77.5,81.21) ; PU200.21 83.98,11.28 v3(83.98,11.26) ; v2(86.87,52.2) 87.1,52.2 v4(87.6,51.71) ; v2(190.68,91.5) v4(190.68,92.17)
  BOTTOM w0.127: 127.19,81.75 127.03,81.59 127.03,81.08 UC1.AV49 ; 130.43,81.75 130.18,81.5 130.18,81.23 129.82,80.86 UC1.AV43 ; UC1.AV41 131.39,80.86 131.76,81.23 131.76,81.71 131.78,81.73 ; 134.99,81.71 134.91,81.63 134.91,81.23 134.54,80.86 UC1.AV36 ; UC1.AV39 132.97,80.86 133.33,81.23 133.33,81.78
  BOTTOM w0.152: UC1.AY16 146.96,78.57 v2(147,78.53)
  BOTTOM w0.178: UC1.AT61 118.38,82.4 UC1.AT62 118.32,82.34 117.82,82.34 117.79,82.3 117.63,82.3 UC1.AT63 117.32,82.19 v2(117,81.87) ; v2(145.54,78.81) 145.6,78.88 UC1.AY18 ; UC1.AN60 119.79,84.06 119.81,84.08 119.81,84.36 119.79,84.38 UC1.AL60 119.79,85.35 119.81,85.37 119.81,85.66 119.79,85.67 UC1.AJ60 ; UC1.AT46 127.76,81.75 126.71,81.75 126.67,81.79 UC1.AT49 ; UC1.A28 139.61,102.91 v2(139.32,103.2) ; UC1.AU18 146.12,81.68 146.14,81.7 146.42,81.7 146.44,81.68 UC1.AU16 ; v2(140.28,78.57) 140.28,78.59 140.47,78.79 UC1.AY26 ; 130.9,81.82 UC1.AT42 131.07,81.73 131.78,81.73 131.87,81.82 UC1.AT40 132.86,81.82 132.93,81.75 133.3,81.75 ; UC1.AW33 136.69,80.98 UC1.AV33 ; UC1.AU28 139.74,81.68 139.76,81.7 140.04,81.7 140.06,81.68 UC1.AU26 140.99,81.68 141,81.7 141.29,81.7 141.31,81.68 UC1.AU24 UC1.AV24 UC1.AW24 UC1.AY24 141.82,78.88 v2(141.75,78.8) ; v2(121.31,78.8) 121.38,78.87 UC1.AY57 ; UC1.AY53 123.81,79.11 123.77,79.06 123.77,78.68 123.56,78.47 v2(123.56,78.47) ; v2(116.41,83.48) 116.44,83.44 116.81,83.44 117.02,83.65 UC1.AN63 ; v2(137.88,78.77) 138.04,78.93 UC1.AY30 ; UC1.AJ63 116.73,86.08 v2(116.58,85.94) ; UC1.AY22 143.18,79.73 143.18,79.13 143.23,79.07 v2(143.23,78.79) ; v2(125.02,78.11) 125.16,78.24 UC1.AY51 UC1.AW51 UC1.AV51 ; UC1.AG60 UC1.AG61 UC1.AG62 UC1.AG63 117.84,87.43 117.17,87.43 v2(116.97,87.63)
  BOTTOM w0.203: UC1.AH49 126.29,86.42 125.97,86.42 ; UC1.D21 144.05,99.61 144.53,99.13 v2(144.53,99.1) ; UC1.AC61 118.81,89.69 v2(118.51,89.99) ; v2(147.41,82.01) 147.08,81.68 UC1.AU16 ; 119.96,86.87 120.41,86.42 UC1.AJ58 ; v2(181.79,59.03) 181.98,58.85 JNGFF.31 ; UC1.A24 142.12,102.48 v2(142.46,102.82) 142.54,102.9 142.54,104.28 141.62,105.2 141.62,105.44 140.48,106.58 139.83,106.58 138.54,107.88 138.06,107.88 CC7.1 ; UC1.AU1 156.3,81.38 156.73,80.95 v2(157.28,80.95) ; RP51.7 155.37,114.23 v2(155.15,114.46) 154.87,114.18 RP51.6 ; UC1.B52 124.49,101.13 ; v2(140.77,105.08) 140.77,105.21 140.26,105.72 139.18,105.72 138.16,106.74 135.82,106.74 135.06,107.5 133.79,107.5 133.46,107.83 CC6.1 ; UC1.AN42 131.5,84.12 v2(131.63,84.12) 131.7,84.12 UC1.AN40 ; UC1.B56 UC1.A56 ; JNGFF.7 173.98,58.91 174.3,59.24 v2(174.55,59.24) ; UC1.D8 152.13,100.4 152.43,100.4 152.76,100.73 v2(152.9,100.73) ; UC1.AU59 119.84,81.98 119.84,82.28 v2(119.61,82.52) 119.49,82.4 UC1.AT61 ; 142.26,81.86 142,81.86 UC1.AU24 ; 124.48,101.13 124.48,101.64 ; UC1.A32 137.1,101.71 137,101.61 137,101.16 UC1.B32 ; 155.13,100.36 154.45,100.36 ; UC1.AU33 136.83,81.65 137.17,81.65 137.22,81.7 137.5,81.7 137.51,81.71 138.02,81.71 ; v2(149.31,82.02) 149.49,82.02 149.76,82.3 149.88,82.3 UC1.AR11 ; v2(155.13,85.43) 155.13,85.44 155.13,85.57 UC1.AK3 ; 124.49,101.64 UC1.A52 ; PU200.3 PU200.21 ; UC1.B48 UC1.A48 ; UC1.R8 UC1.R10
  BOTTOM w0.229: UC1.AU59 120.51,81.68 120.54,81.71 120.85,81.71 120.88,81.68 121.21,81.68 121.22,81.68 UC1.AU57 121.76,81.68 121.8,81.72 122.1,81.72 122.14,81.68 UC1.AU55 123.05,81.68 123.09,81.72 123.39,81.72 123.43,81.68 UC1.AU53 ; UC1.AU20 144.33,81.68 144.3,81.65 143.95,81.65 143.89,81.71 143.58,81.71 143.55,81.68 UC1.AU22
  BOTTOM w0.254: RP41.6 127.06,109.98 v2(126.8,110.24) 126.56,110 RP41.5 ; UC1.AP26 140.66,83.17 140.33,82.83 140.31,82.83 v2(140.31,82.82) ; v2(52.74,79.3) 52.74,79.3 UV1.B22 ; v2(30.32,71.91) 30.53,72.12 UV6.T9 ; UC1.AL36 134.47,85.12 v2(134.16,84.81) ; v2(152.82,84.26) 152.52,83.96 UC1.AN7 ; UV1.B12 53.45,87.15 v2(53.12,87.15) ; UC1.AH19 145.61,86.66 145.82,86.87 v2(146,86.87) 146.04,86.87 146.35,86.56 UC1.AH17 146.69,86.3 146.97,86.3 UC1.AH16 ; PC105.2 70.14,17.43 69.48,16.77 v3(69.14,16.77) ; UC1.AU16 UC1.AV16 UC1.AW16 146.96,80.35 UC1.AY16 ; v2(149.31,82.02) 149.27,82.06 148.62,82.06 UC1.AT13 ; UC1.T58 120.76,93.53 v2(120.52,93.77) 120.22,94.07 UC1.P59 ; v2(63.63,92.74) 63.6,92.71 UV1.T6 ; UC1.N10 150.63,94.71 150.63,93.83 UC1.R10 149.9,93.79 v2(149.77,93.93) ; UV1.L27 59.66,75.3 60.08,75.72 60.78,75.72 UV1.N27 v2(60.84,74.94) ; UV7.J8 36.55,92.7 v2(36.91,92.33) ; UV6.J2 36.55,77.74 36.87,78.07 v2(36.87,78.13) ; UC1.AR39 132.99,82.84 v2(133.07,82.93) 133.26,82.93 UC1.AP38 ; UC1.AR39 UC1.AP39 ; UC1.AR39 132.55,82.8 UC1.AT40 ; UV1.A30 52.68,73.7 v2(52.61,73.63) ; v2(149.79,78.92) 149.77,78.94 UC1.AY11 ; UV6.G9 38.2,72.12 v2(38.57,71.75) ; v2(121.31,95.91) UC1.L58 ; v2(155.2,95.19) 154.84,94.83 UC1.N3 ; v2(56.99,82.51) 57.2,82.72 UV1.H17 ; v2(55.27,78.92) 55.6,79.25 UV1.F22 ; UC1.AP39 132.33,83.49 UC1.AN40 132.33,84.14 UC1.AN39 UC1.AP39 ; UC1.AH30 138.55,86.98 v2(138.97,86.98) UC1.AJ29 139.29,86.42 UC1.AH28 139.94,86.42 UC1.AJ27 140.22,86.38 140.22,85.47 140.58,85.12 UC1.AL26 ; UV1.B18 53.2,82.5 52.91,82.79 v2(52.57,82.79) ; UC1.AM52 124.21,84.82 v2(123.96,84.82) 124.26,85.12 UC1.AL52 ; v2(2.99,94.8) 2.86,94.8 2.66,95 JEDP.9 ; v2(115.63,100.64) 116.21,100.06 UC1.D63 118.1,100.06 UC1.D62 ; v2(70.41,74.89) 70.8,75.28 UV1.AE27 ; v2(144.53,99.1) 144.64,99.1 UC1.F20 ; UC1.AV36 134.52,80.71 v2(134.16,80.34) 133.87,80.06 UC1.AW37 ; v2(155.14,82.43) 155.14,82.54 154.84,82.84 UC1.AP3 ; UC1.AG11 149.67,87.35 UC1.AF11 ; UC1.A18 145.65,101.92 145.65,100.86 UC1.C18 145.63,100.66 UC1.D18 146.04,100.15 v2(146.45,99.74) 146.55,99.74 UC1.E17 ; v2(55.19,74.87) 54.81,74.5 UV1.E28 ; v2(123.31,98.33) 123.31,98.33 UC1.F54 UC1.D54 ; UV5.B3 42.15,73.76 42.53,74.14 v2(42.53,74.14) ; v2(145.42,90.38) 145.19,90.14 UC1.AB20 ; v2(156.77,84.13) 156.58,84.33 UC1.AM1 ; UC1.AA1 156.57,90.32 156.61,90.36 v2(156.62,90.36) ; RP41.7 127.56,109.98 v2(127.82,110.24) 127.83,110.24 128.06,110.01 RP41.8 ; v2(133.34,98.33) 133.34,98.33 UC1.F38 UC1.D38 ; UC1.K1 156.14,96.32 156.18,96.36 156.6,96.36 v2(156.71,96.48) ; v2(144.85,84.82) 145.15,85.12 UC1.AL20 ; v2(150.89,81.13) 151.3,80.71 UC1.AV8 ; v2(151.88,96.2) 151.88,96.01 152.19,95.7 UC1.L7 ; v2(150.04,104.32) 150.04,102.91 149.77,102.64 UC1.A11 ; v2(39.35,98.78) 38.95,98.38 UV8.F9 ; v2(148.35,97.79) 148.43,97.79 148.75,97.47 UC1.H13 ; UV1.J7 57.96,91.3 v2(57.55,91.71) 57.2,92.06 UV1.H6 ; UV1.J7 UV1.K6 ; UV1.J7 58.06,91.24 v2(58.41,90.89) ; UV1.K2 58.8,95.17 v2(58.93,95.3) ; v2(149.64,89.46) 150.16,89.98 UC1.AB10 ; UC1.AR43 130.13,82.52 129.8,82.19 v2(129.75,82.19) 129.75,82.16 UC1.AT43 129.48,81.74 130,81.74 130.03,81.71 130.39,81.71 130.43,81.75 130.84,81.75 130.9,81.82 ; UC1.AP54 123.21,82.84 v2(123.14,82.84) ; UV7.E8 39.76,92.73 v2(40.16,92.33) ; UV1.B10 52.63,88.9 v2(52.48,89.05) ; UV1.AD6 69.95,92.1 v2(69.6,92.45) ; v2(119.61,82.52) 119.61,82.6 119.83,82.82 119.83,82.83 119.84,82.84 119.84,83.11 119.83,83.12 119.83,83.13 119.79,83.17 UC1.AN60 ; v2(156.67,93.32) UC1.T1 ; UV8.D8 40.54,97.53 v2(40.14,97.93) UV7.E2 ; v2(60.06,72.53) 60.06,72.56 UV1.M32 ; UC1.AW44 129.05,80.06 129.4,80.41 v2(129.41,80.41) 129.58,80.41 129.82,80.64 UC1.AV43 ; v2(148.32,94.37) 148.78,94.82 UC1.L13 149.22,96.34 UC1.K12 ; UC1.AN35 135.25,83.82 v2(134.92,83.49) 134.59,83.82 UC1.AN36 ; UV7.M9 v2(34.15,91.24) ; UC1.AN48 127.03,83.56 126.64,83.56 UC1.AN49 126.2,83.64 125.63,83.64 125.45,83.82 UC1.AN51 125.24,83.96 124.75,83.96 124.61,83.82 UC1.AN52 ; UC1.AN48 127.57,83.82 v2(127.85,84.09) 128.12,83.82 UC1.AN46 128.57,83.59 129,83.59 129.23,83.82 UC1.AN45 129.3,83.86 130.21,83.86 UC1.AN43 130.43,83.82 v2(130.7,83.54) 130.98,83.82 UC1.AN42 ; UC1.AN48 UC1.AP48 127.19,83.17 v2(126.9,82.88) 126.85,82.88 126.49,82.52 UC1.AR49 126.18,82.32 126.18,81.83 UC1.AT49 125.26,81.79 UC1.AU51 ; UC1.AG21 144.18,86.56 v2(144.33,86.42) 144.47,86.56 UC1.AH20 ; v2(40.16,92.33) 40.55,91.95 UV8.D1 ; v2(40.16,92.33) 39.76,91.93 UV8.E1 ; UC1.W20 145.03,91.77 v2(145.39,92.12) 144.96,92.54 UC1.U20 ; v2(62.02,92.61) 62.04,92.59 62.04,92.14 UV1.P6 ; v2(153.75,82.4) 153.52,82.4 153.26,82.66 UC1.AR5 ; UC1.F58 120.66,98.81 120.66,98.38 v2(120.63,98.36) 121.05,97.94 UC1.H57 ; UC1.G8 151.24,98.51 v2(151.14,98.51) ; UC1.AJ60 119.79,86.32 119.96,86.49 119.96,86.87 119.95,86.87 119.8,87.02 119.8,87.43 UC1.AG60 ; v2(118.63,84.83) 118.66,84.87 UC1.AL61 UC1.AL60 ; UV6.P1 32.55,78.57 v2(32.94,78.96) ; UC1.N21 144.45,94.61 144.05,94.2 143.53,94.2 UC1.P22 v2(142.64,94.2) ; v2(52.87,84.52) 52.87,84.53 53.3,84.1 UV1.B16 ; UV1.J27 58.04,75.26 58.04,74.76 v2(58.04,74.76) ; v2(144.39,80.44) UC1.AV20 UC1.AU20 144.4,81.7 144.79,81.7 144.89,81.8 145.08,81.8 145.16,81.72 145.19,81.72 145.22,81.68 UC1.AU18 ; v2(33.81,98.84) 34.15,98.5 UV7.M1 ; UC1.AL29 138.78,85.26 138.48,85.56 138.1,85.56 137.98,85.44 UC1.AL31 ; UV6.T1 30.95,78.72 v2(31.23,79.01) ; UV1.F24 55.25,77.7 v2(55.12,77.57) ; v2(125.81,98.33) 125.82,98.33 UC1.F50 UC1.D50 ; UC1.AV34 136.44,80.38 UC1.AW33 UC1.AY33 ; UC1.AV34 136.44,81.03 UC1.AV33 136.74,81.68 UC1.AU33 136.7,81.71 136.33,82.08 136.33,82.43 UC1.AR33 136.16,82.78 135.83,82.78 v2(135.8,82.8) 135.8,82.78 135.85,82.73 135.85,81.96 UC1.AT35 135.63,81.74 135.02,81.74 134.99,81.71 134.75,81.71 134.74,81.72 134.67,81.72 134.58,81.82 UC1.AT37 133.37,81.82 133.3,81.75 ; UC1.AV34 136.01,80.71 v2(135.71,80.41) 135.36,80.06 UC1.AW35 ; v2(36.96,72.52) 36.55,72.92 UV6.J8 ; UV1.K32 58.66,72.76 v2(58.66,72.29) ; v2(153.78,87.64) 153.78,87.8 UC1.AE5 ; v2(147.89,80.36) 147.95,80.36 147.98,80.38 147.99,80.38 148.31,80.7 UC1.AV14 ; UC1.B20 144.38,101.49 v2(144.8,101.49) 144.8,101.01 UC1.C20 ; v2(52.85,80.82) 52.85,80.82 52.82,80.82 52.91,80.9 UV1.B20 ; 130.53,86.76 130.53,86.76 130.87,86.42 UC1.AJ41 131.17,86.41 v2(131.17,87.03) 131.26,87.03 131.68,86.61 UC1.AH40 132.05,86.98 v2(132.47,86.98) ; 130.53,86.76 UC1.AH42 ; 130.53,86.76 v2(130.53,87.45) 129.89,87.45 129.87,87.43 UC1.AJ43 129.54,86.75 UC1.AH44 128.89,86.75 UC1.AJ45 128.51,86.42 128.24,86.15 128.21,86.15 128.19,86.14 v2(127.85,86.14) ; UV1.Y32 66.79,72.89 v2(66.79,72.42) ; v2(61.59,72.53) 61.96,72.9 UV1.P32 ; UC1.AL57 121.56,85.12 v2(121.23,84.79) ; v2(56.02,75.69) 56.02,75.69 ; 56.02,75.69 56.4,75.32 UV1.G27 ; 56.02,75.69 55.62,76.1 UV1.F26 ; UV1.AG12 72.4,87.38 72.14,87.63 72.14,87.65 v2(72.11,87.68) ; v2(36.96,97.95) 36.96,97.95 UV7.J2 ; UC1.AY6 152.76,78.94 v2(152.9,78.8) ; UC1.B40 UC1.A40 ; v2(150.88,82.98) 150.55,83.31 UC1.AP10 ; v2(54.06,72.35) 54.05,72.35 53.87,72.54 53.87,72.77 UV1.C32 ; UV8.B3 42.15,93.7 v2(42.45,94) ; RP34.4 60.88,102.68 60.38,103.18 v2(59.87,103.18) ; UV1.AH32 73.2,72.45 73.21,72.44 v2(73.21,72.34) ; UC1.AE58 120.78,88.12 121.18,88.12 v2(121.33,88.27) ; UC1.L17 147,95.89 v2(147.38,95.51) 147.44,95.51 147.82,95.89 UC1.L15 ; UC1.AP22 143.42,83.17 143.09,82.84 v2(143.04,82.84) 142.96,82.84 142.64,82.52 UC1.AR23 142.61,82.49 142.26,82.14 142.26,81.86 142.54,81.86 142.72,81.68 UC1.AU22 ; v2(143.04,84.79) 143.04,84.8 143.36,85.12 UC1.AL22 ; UC1.V7 152.38,92.07 v2(152.38,92.36) ; v2(119.81,91.48) 119.81,91.38 120.11,91.08 UC1.Y59 ; UV1.A3 52.95,93.95 52.95,94.7 53.25,95 v2(53.5,95) UV1.C1 ; v2(144.01,98.48) 143.8,98.27 143.53,98.27 UC1.G22 ; UV1.V32 65.2,72.65 v2(64.7,72.15) ; v2(155.14,91.41) 155.14,91.54 154.84,91.84 UC1.V3 ; v2(148.98,91.19) 149.21,91.19 149.47,90.94 UC1.Y10 ; UC1.AV41 131.39,80.68 131.14,80.43 v2(130.98,80.43) 130.61,80.06 UC1.AW42 ; UC1.AV49 126.67,80.7 126.42,80.45 v2(126.26,80.45) 125.86,80.06 UC1.AW50 ; v2(42.54,71.7) 42.15,72.09 UV6.B9 ; UV1.F6 55.58,92.1 55.21,91.73 v2(55.17,91.73) ; UV1.B14 v2(52.99,85.7) ; v2(122.7,80.56) 122.59,80.67 UC1.AV55 UC1.AU55 ; v2(152.37,90.5) 152.37,90.51 152.37,90.51 152.2,90.35 UC1.AB7 ; v2(124.99,85.46) 125.34,85.12 UC1.AL51 ; JEDP.12 1.77,93.51 v2(3.01,93.51) ; UV8.A9 42.45,98.84 v2(42.42,98.84) 42.15,98.56 UV7.B1 ; v2(55.17,82.02) 55.6,82.45 UV1.F18 ; v2(3.07,90.61) 2.96,90.5 JEDP.18 ; UC1.AD21 144.45,88.95 v2(144.08,89.33) 143.95,89.45 143.95,89.5 143.53,89.92 UC1.AB22 ; UC1.L18 145.92,95.84 v2(145.5,95.42) 145.09,95.83 UC1.L20 ; UC1.AF11 150.34,87.75 150.6,88.02 UC1.AE10 ; UC1.AF11 150.08,87.9 149.66,88.32 v2(149.66,88.45) ; v2(57.89,72.4) 57.89,73.19 UV1.J31 ; UC1.L61 118.81,95.58 118.51,95.88 v2(118.51,95.98) ; UC1.AH36 134.65,86.98 135.07,86.98 ; v2(3.12,91.99) 1.77,91.99 JEDP.15 ; DI1.3 DI1.8 194.63,66.13 v2(194.51,66.01) ; v2(52.85,91.9) 52.85,91.89 52.9,91.89 52.92,91.91 53.41,91.91 UV1.B6 ; UV5.A9 42.95,78.58 v2(42.59,78.94) 42.17,78.52 UV6.B1 ; UC1.AD3 155.14,88.56 v2(155.14,88.45) ; UV1.AC27 69.2,75.3 v2(68.83,75.68) 69.2,76.05 UV1.AC26 ; UC1.AR15 148,82.29 147.72,82.01 v2(147.41,82.01) 146.92,82.5 UC1.AR17 UC1.AP17 UC1.AN17 UC1.AM17 UC1.AL17 147.43,85.45 v2(147.48,85.5) 147.61,85.5 148.01,85.91 UC1.AJ14 148.26,85.7 148.26,85.57 UC1.AL13 148.86,85.56 UC1.AJ13 ; UV1.F16 55.6,84.2 v2(55.22,84.59) ; JEDP.20 2.98,89.5 v2(3.06,89.43) ; v2(66.49,74.87) 66.06,75.3 UV1.W27 ; v2(56.81,90.85) 56.46,90.5 UV1.G8 56.37,90.47 55.63,90.47 UV1.F8 ; UC1.AL31 137.79,85.36 137.79,84.88 UC1.AM31 UC1.AN31 ; UC1.AL31 137.78,85.55 137.78,85.89 v2(137.81,85.92) ; v2(118.51,92.98) 118.51,92.87 UC1.U61 ; UC1.AH46 127.85,86.68 v2(127.85,86.14) ; v2(121.31,90.71) UC1.AA58 ; v2(69.91,72.4) 69.91,72.84 69.97,72.9 UV1.AD32 ; UV1.AH10 73.29,88.9 v2(73.59,88.6) ; UV1.K28 59.09,74.21 v2(59.09,74.1) ; v2(121.31,92.01) UC1.V58 ; v2(149.7,92.39) 149.7,92.22 150.04,91.89 UC1.V10 151.11,92.33 UC1.U9 ; UV6.E2 39.75,77.72 v2(40.15,78.12) 40.54,77.72 UV5.D8 ; UC1.AH22 143.61,86.81 143.61,86.41 v2(143.54,86.34) 143.16,86.34 143.03,86.48 UC1.AJ23 142.76,86.75 UC1.AH24 142.2,86.73 v2(142.2,86.1) 142.52,85.77 UC1.AK23 142.48,85.63 142.39,85.63 v2(142.2,85.44) 142.35,85.44 142.61,85.18 UC1.AL23 142.52,85.12 v2(142.2,84.79) 142.25,84.79 142.58,84.47 UC1.AM23 ; UV1.G10 UV1.F10 55.16,88.9 55.06,89.01 v2(54.87,89.01) ; UV1.M6 60.4,92.65 v2(60.42,92.67) ; UC1.AN52 124.39,83.82 124.02,84.2 v2(123.95,84.2) ; UC1.AN52 124.39,83.66 124.39,83.33 UC1.AP52 124.46,83.07 124.46,82.62 UC1.AR52 124.38,82.52 123.81,81.95 UC1.AU53 123.98,81.85 124.99,81.85 UC1.AU51 ; 155.13,100.36 155.16,100.33 155.16,100.33 155.49,100 UC1.D2 ; JDIMM2.128 149.02,27.49 148.39,28.12 148.39,28.53 v2(148.79,28.93) ; v2(69.6,90.85) 69.95,90.5 UV1.AD8 ; UC1.AU59 UC1.AV59 UC1.AW59 120.14,80.36 119.83,80.06 UC1.AW60 ; v2(42.22,91.33) 42.15,91.4 UV7.B9 ; UC1.B60 119.64,101.21 119.64,100.87 v2(119.61,100.84) 119.61,100.79 120.24,100.16 UC1.D59 ; v2(139.29,80.53) 139.26,80.56 UC1.AV28 UC1.AU28 138.8,81.68 138.76,81.73 138.46,81.73 138.41,81.68 UC1.AU30 138.02,81.71 138.02,82.14 137.88,82.28 UC1.AR31 UC1.AP31 UC1.AN31 ; UC1.AU51 UC1.AV51 ; UC1.AH32 137.02,87.41 136.67,87.76 136.34,87.76 v2(135.86,87.27) 135.72,87.13 UC1.AH34 135.48,86.98 135.07,86.98 ; UC1.V23 143.03,92.19 v2(142.64,92.58) ; UC1.V23 143.43,92.58 UC1.U22 ; UC1.V23 143.43,91.77 UC1.W22 ; UC1.AF18 UC1.AF17 146.83,88.29 v2(146.88,88.34) 147.06,88.34 UC1.AF15 ; v2(30.51,98.68) 30.86,98.33 UV7.T1 ; UV1.B8 v2(53.1,90.5) ; v2(142.4,96.47) 142.57,96.64 UC1.J22 ; v2(56.27,72.52) 56.27,73.17 UV1.G31 ; v2(38.59,92.36) 38.16,91.93 UV7.G9 ; v2(153.09,99.89) 153.39,100.19 UC1.D5 153.51,100.19 153.57,100.25 v2(153.98,100.25) 154.34,100.25 154.45,100.36 154.45,101.16 UC1.B4 ; v2(127.85,86.14) 127.55,86.14 UC1.AJ47 127.26,86.35 126.9,85.99 v2(126.87,85.99) 126.63,86.23 126.63,86.73 UC1.AH49 ; UC1.J10 150.29,96.82 v2(150.2,96.91) ; UC1.G5 153.28,98.38 v2(153.09,98.38) 152.85,98.38 UC1.G6 ; UC1.AG1 v2(156.62,87.32) ; v2(121.23,82.84) 121.56,83.17 UC1.AP57 ; v2(2.84,83.57) 2.84,83.58 2.42,84 JEDP.31 ; UV1.F20 55.6,80.83 55.21,80.44 v2(55.21,80.41) ; UC1.C11 149.79,100.63 UC1.D12 ; UC1.D34 UC1.F34 135.85,98.33 v2(135.84,98.33) ; v2(138.39,82.87) 138.51,82.87 138.78,83.14 UC1.AP29 ; UC1.AW4 154.16,79.46 UC1.AY4 154.21,79.01 v2(154.41,78.81) ; UV7.P1 32.55,98.4 v2(32.11,98.84) ; v2(123,86.04) 123.02,86.04 ; 123.02,86.04 122.71,86.35 UC1.AH55 122.39,86.42 UC1.AJ56 121.74,86.75 UC1.AH57 121.09,86.75 UC1.AJ58 ; 123.02,86.04 123.02,86.04 123.36,86.38 UC1.AJ54 123.69,86.42 UC1.AH53 124.01,85.63 v2(124.03,85.61) 124.2,85.77 UC1.AK52 124.56,86.32 UC1.AJ52 124.99,86.75 UC1.AH51 125.64,86.42 UC1.AJ50 125.97,86.42 ; UV8.G8 38.18,97.57 38.18,97.73 38.17,97.74 38.17,97.76 38.17,97.77 38.17,98.13 38.18,98.14 38.18,98.3 UV7.G1 38.15,98.93 v2(38.39,99.17) ; UV1.AB32 68.28,72.78 v2(67.43,72.78) ; UC1.A28 UC1.B28 ; v2(64.06,75.7) 64.4,75.37 UV1.U27 ; UV1.AF32 71.6,72.11 71.64,72.07 v2(71.65,72.07) ; v2(132.47,86.98) 132.88,86.98 UC1.AH38 133.12,86.24 v2(133.05,86.17) 132.92,86.17 132.6,85.85 UC1.AL39 132.33,85.44 UC1.AL40 131.94,85.12 v2(131.62,85.44) ; v2(132.47,86.98) UC1.AJ39 ; v2(55.43,94.96) 55.6,94.79 UV1.F2 ; UC1.AN31 137.64,84.14 UC1.AN32 ; v2(140.86,98.33) 140.86,98.33 UC1.F26 UC1.D26 ; v2(72,74.92) 72.01,74.92 72.39,75.3 UV1.AG27 UV1.AH28 ; UC1.D12 UC1.D14 148.62,100.53 148.31,100.84 UC1.C14 148.23,100.86 148.23,101.92 UC1.A14 148.11,104.01 v2(148.27,104.17) ; UC1.D12 149.39,100.24 149.39,99.82 v2(149.31,99.74) 149.39,99.74 149.72,99.42 UC1.E11 ; v2(53.09,76.03) 53.17,76.1 UV1.B26 ; UV5.D1 40.55,72.08 v2(40.17,71.71) 39.76,72.12 UV5.E1 ; UC1.AL33 136.15,85.12 v2(135.81,85.46) ; UV5.F9 38.95,78.57 v2(38.57,78.94) UV6.G1 38.15,78.52 38.15,77.73 UV5.G8 ; UV1.AA27 67.6,75.96 v2(67.6,75.94) ; UV1.F14 55.6,85.76 55.24,86.13 55.23,86.13 v2(55.23,86.12) ; UC1.AP23 142.58,83.17 142.18,83.57 v2(142.18,84.06) 142.44,84.06 142.61,83.89 UC1.AN23 ; UV1.F12 55.6,87.34 v2(55.24,87.7) ; UC1.H17 146.55,97.79 v2(146.45,97.79) 146.24,97.79 UC1.G18 ; UC1.D42 UC1.F42 130.83,98.33 v2(130.83,98.33) ; UC1.AL10 150.69,85.05 150.72,85.05 150.74,85.07 v2(150.88,84.93) ; v2(142.48,41.72) 142.53,41.72 143.04,41.21 143.04,40.94 143.25,40.73 JDIMM1.150 ; v2(118.5,99.01) 118.5,98.88 UC1.F61 ; UV7.P9 32.55,91.67 32.47,91.59 v2(32.47,91.34) ; UV6.P9 32.55,72.09 v2(32.17,71.72) ; UV7.T9 30.95,91.65 v2(30.71,91.42) ; UC1.J59 120.11,97.18 v2(119.81,97.48) ; JEDP.6 2.67,96.5 2.78,96.4 v2(2.93,96.4) ; v2(116.89,88.87) 117.02,88.87 117.03,88.86 UC1.AD63 ; UC1.AL54 123.46,85.12 v2(123.14,84.79) ; UC1.AL45 129.07,85.12 v2(128.8,84.85) 128.53,85.12 UC1.AL46 ; UV1.AB6 v2(68,92.5) ; v2(116.72,90.94) 116.89,91.11 UC1.Y63 ; UC1.P62 UC1.P63 117.49,94.08 117.05,94.08 v2(116.97,94.16) ; UC1.AP20 145.34,83.28 145.13,83.49 v2(144.91,83.49) ; v2(117.1,97.46) 117.15,97.46 UC1.J63 ; UV1.B24 52.69,77.7 52.36,77.38 52.37,77.38 v2(52.38,77.39) ; UC1.D46 UC1.F46 128.33,98.33 v2(128.32,98.33) ; UC1.A36 134.59,101.6 134.54,101.55 134.54,101.26 134.59,101.21 UC1.B36 ; v2(40.15,73.33) 39.75,72.93 UV6.E8 ; UV1.AC9 69.54,89.36 v2(69.58,89.36) ; v2(70.41,91.72) 70.41,91.72 70.8,91.33 UV1.AE7 ; UC1.AW40 132.16,80.06 132.51,80.41 v2(132.56,80.41) 132.59,80.41 132.89,80.71 UC1.AV39 ; v2(34.17,71.52) 34.17,72.1 UV6.M9 ; UC1.AV46 127.94,80.41 v2(127.83,80.41) 127.77,80.41 UC1.AW47 ; UV1.H2 57.17,94.13 v2(57.17,95.03) ; 135.07,86.98 UC1.AJ35 ; UC1.B24 UC1.A24 ; v2(154.48,97.45) 154.84,97.81 UC1.G3 ; UC1.M22 v2(142.64,95.02) ; v2(119.94,78.87) 120.02,78.96 120.02,79.38 UC1.AY59 ; UC1.AG23 142.99,87.26 v2(142.49,87.26) ; v2(141.57,86.98) UC1.AJ25 ; UV1.R27 v2(62.44,74.94) ; v2(138.35,98.33) 138.36,98.33 UC1.F30 UC1.D30 ; 148.46,88.54 UC1.AF14 ; JEDP.3 2.57,98 2.77,98.2 v2(3.41,98.2) ; v2(197.31,47.43) DI4.3 DI4.8 ; UV1.T32 v2(63.24,72.54) ; UC1.R22 v2(142.64,93.39)
  BOTTOM w0.305: v2(179.98,57.42) 179.98,57.26 180.11,57.14 180.38,57.14 180.48,57.23 JNGFF.25 ; UV1.AB24 68.2,77.68 v2(68.73,77.16) 69.2,77.63 UV1.AC24 ; UC1.AF12 149.25,87.75 v2(148.35,88.65) ; US3.5 v2(18.36,16.06) ; v2(176.33,62.41) 176.59,62.41 177.09,62.92 177.09,64.19 176.73,64.56 JNGFF.18 ; US3.13 20.36,20.33 v2(20.1,20.59) 19.86,20.35 US3.12 ; JNGFF.37 183.48,58.78 183.62,58.93 v2(183.62,59.06) ; v2(184.92,58.96) 184.92,58.83 184.98,58.77 JNGFF.43 ; v2(56.8,80.1) 56.8,80.3 UV1.H20 ; UV1.Y10 67.29,88.9 v2(67.72,89.34) ; UV1.K11 58.8,88.19 v2(59.06,88.45) ; UV1.W25 65.95,76.9 v2(66.35,77.3) ; UV1.U9 64.89,89.7 v2(65.11,89.49) ; v2(66.46,76.44) 66.14,76.44 UV1.W26 ; v2(62.86,89.23) 62.67,89.23 UV1.P9 ; UV1.H14 57.2,85.51 56.8,85.91 56.8,86.1 v2(56.8,86.1) ; 190.98,57.04 191.32,56.7 v2(192.84,56.7) ; 190.98,57.04 JNGFF.67 ; 190.98,57.04 190.98,56.97 190.71,56.7 189.79,56.7 189.48,57.02 JNGFF.61 ; v2(169.22,36.5) 169.12,36.41 JDIMM2.195 ; UV1.AE14 70.8,85.7 v2(71.2,86.1) ; v2(70.38,77.3) 70,76.92 UV1.AD25 ; v2(20.84,17.31) US3.16 21.34,17.84 21.52,18.03 21.52,18.18 21.35,18.34 US3.15 ; JNGFF.55 187.98,56.53 v2(187.64,56.19) 187.08,56.19 186.48,56.79 JNGFF.49 ; UV1.AC17 69.09,82.99 v2(69.09,82.5) ; UV1.U25 64.39,76.9 v2(64.06,77.23) ; US3.10 18.86,20.38 18.76,20.48 v2(18.76,20.64) ; v2(67.6,76.5) 67.2,76.9 UV1.Y25
  BOTTOM w0.356: JDIMM2.139 152.32,35.85 152.03,36.15 151.45,36.15 v2(151.44,36.14) 150.72,36.14 150.52,35.94 JDIMM2.133 ; v2(148.36,43.25) 147.83,43.25 146.55,44.53 JDIMM1.161 146.55,48.86 146.86,49.17 148.05,49.17 148.35,48.88 JDIMM1.167 ; JDIMM1.49 110.55,46.23 110.74,46.04 110.74,45.53 v2(111.32,45.02) ; JDIMM2.161 158.92,32.85 159.79,31.98 v2(159.87,31.98) ; JDIMM1.156 145.05,38.32 v2(144.86,38.13) ; 109.65,38.15 109.65,38.15 JDIMM1.46 ; 109.65,38.15 110.01,38.15 110.25,38.39 JDIMM1.48 110.25,41.02 v2(111.32,41.97) ; 109.65,38.15 v2(109.66,38.14) ; v2(126.5,24.92) 126.5,25.23 126.22,25.5 JDIMM2.60 ; v2(116.82,36.16) 117.19,36.16 117.52,35.83 JDIMM2.31 ; v2(155.68,30.85) 155.92,31.1 JDIMM2.151 155.92,35.81 155.58,36.15 v2(155.45,36.15) ; JDIMM2.14 112.42,25.58 111.94,25.1 v2(111.51,25.1) 110.93,25.1 110.62,25.41 JDIMM2.8 110.62,27.63 v2(111.02,28.03) ; v2(136.53,38.13) 136.65,38.25 JDIMM1.128 ; JDIMM2.167 160.72,35.96 v2(161.02,36.26) 161.06,36.3 162.13,36.3 162.52,35.9 JDIMM2.173 ; JDIMM2.61 126.52,36.07 v2(126.45,36.14) 126.91,36.14 127.12,35.93 JDIMM2.63 ; JDIMM2.179 164.32,35.87 164.65,36.19 v2(165.48,36.19) 165.7,36.19 166.12,35.77 JDIMM2.185 ; v2(123.63,36.13) 124.44,36.13 124.72,35.85 JDIMM2.55 ; JDIMM2.189 167.32,36.14 v2(166.99,36.48) 166.72,36.22 JDIMM2.187 ; v2(156.09,38.18) 156.77,38.18 157.05,38.46 JDIMM1.196 ; JDIMM1.2 96.45,40.62 v2(96.23,40.83) ; JDIMM1.145 141.75,49.01 142,49.26 v2(142.49,49.26) 143.41,49.26 143.55,49.12 JDIMM1.151 ; JDIMM1.28 104.25,41.15 105.38,42.29 ; v2(117.14,45.02) 117.78,45.65 117.78,46.12 117.15,46.75 JDIMM1.71 ; JDIMM2.38 119.62,24.55 v2(119.06,23.98) 117.84,25.2 117.84,25.55 117.82,25.57 JDIMM2.32 ; JDIMM1.150 143.25,38.24 143.08,38.08 v2(143.01,38.08) ; JDIMM1.55 112.35,46.01 v2(113.45,45.02) ; v2(166.93,28.66) 167.62,27.97 JDIMM2.190 ; JDIMM2.155 157.12,35.83 156.85,36.1 v2(156.6,36.1) 156.52,36.02 JDIMM2.153 ; v2(107.04,38.04) 107.25,38.24 JDIMM1.38 ; JDIMM1.172 149.85,38.29 149.65,38.09 148.85,38.09 v2(148.81,38.13) 148.65,38.29 JDIMM1.168 ; JDIMM2.134 150.82,29.9 v2(150.65,30.07) ; JDIMM2.46 122.02,25.22 121.77,24.97 v2(121.72,24.97) 121.42,25.27 JDIMM2.44 ; JDIMM2.196 169.42,25.03 v2(169.65,24.79) ; v2(116.62,28.22) JDIMM2.28 ; JDIMM1.138 139.65,38.49 140.01,38.13 v2(140.06,38.13) ; v2(98.35,41.71) 98.25,41.61 JDIMM1.8 ; JDIMM2.48 122.62,25.29 122.88,25.04 v2(123.34,25.04) 123.87,25.04 124.42,25.59 JDIMM2.54 ; v2(111.74,38.13) 111.84,38.13 112.05,38.34 JDIMM1.54 ; v2(105.54,38.14) 105.54,38.19 105.42,38.3 105.42,39.47 JDIMM1.32 ; v2(149.95,42.61) 149.84,42.61 149.25,42.3 JDIMM1.170 ; v2(164.78,25.07) 164.5,25.07 164.02,25.55 JDIMM2.178 164.02,28.03 v2(163.12,28.93) ; JDIMM2.136 151.42,25.16 151.6,24.98 v2(152.3,24.98) 152.02,25.25 JDIMM2.138 ; JDIMM1.185 153.75,46.59 153.45,46.3 v2(153.15,46.3) ; 105.38,42.29 v2(105.41,42.29) ; 105.38,42.29 105.38,42.29 104.16,42.29 103.65,41.78 JDIMM1.26 ; JDIMM2.66 128.02,25.55 128.42,25.15 v2(129.67,25.15) 129.67,25.18 129.82,25.33 JDIMM2.72 ; v2(111.02,30.98) 111.02,31.1 110.92,31.2 JDIMM2.9 110.92,35.85 110.58,36.2 v2(109.63,36.2) 109.5,36.2 109.12,35.81 JDIMM2.3 ; JDIMM1.3 96.75,46.66 96.2,46.11 96.2,45.76 96.63,45.33 v2(97.02,45.33) ; v2(109.15,40.95) 109.05,40.85 JDIMM1.44 ; v2(142.09,38.1) 142.07,38.13 141.71,38.13 141.45,38.39 JDIMM1.144 141.45,40.94 140.67,41.72 v2(140.17,41.72) ; JDIMM2.172 162.22,25.23 162.02,25.02 v2(161.47,25.02) 161.62,25.17 JDIMM2.170 ; v2(155.07,38.12) 155.25,38.29 JDIMM1.190 155.25,40.81 154.72,41.34 v2(154.67,41.34) ; v2(153.47,36.15) 153.88,36.15 154.12,35.91 JDIMM2.145 ; v2(103.53,45.71) 103.35,45.91 JDIMM1.25 ; JDIMM2.26 116.02,25.49 115.63,25.1 v2(114.38,25.1) 114.38,25.16 114.22,25.32 JDIMM2.20 ; v2(116.82,38.13) 115.91,38.13 115.65,38.39 JDIMM1.66 ; JDIMM2.71 129.52,36 v2(129.39,36.13) ; v2(140.17,43.25) 140.12,43.25 139.05,42.17 JDIMM1.136 ; JDIMM1.195 156.75,46.36 v2(156.95,46.16) ; JDIMM1.11 99.15,44.85 v2(100.19,43.81) ; v2(114.97,41.59) 113.85,40.55 JDIMM1.60 113.85,38.26 v2(113.96,38.14) ; JDIMM2.65 127.72,33.04 128.79,31.98 v2(129.59,31.98) ; v2(157.42,25.17) JDIMM2.156 ; JDIMM1.173 150.15,48.73 150.48,49.06 v2(151.19,49.06) 151.62,49.06 151.95,48.73 JDIMM1.179 152.03,47.62 152.03,43.97 151.3,43.25 v2(151.22,43.25) ; v2(153.82,25.18) JDIMM2.144 ; JDIMM1.14 100.05,38.28 v2(99.67,37.9) ; JDIMM2.184 165.82,25.42 166.3,24.95 v2(166.53,24.95) ; v2(119.1,36.11) 119.32,35.89 JDIMM2.37 ; v2(159.22,25.18) JDIMM2.162 ; JDIMM1.127 136.35,49.18 136.63,49.46 137.89,49.46 138.15,49.19 JDIMM1.133 138.15,45.52 138.52,45.15 v2(138.72,45.15) ; 145.6,44.75 v2(145.55,44.75) 145.48,44.75 144.15,46.08 JDIMM1.153 144.15,48.75 144.71,49.31 v2(144.75,49.31) JDIMM1.155 ; JDIMM2.49 122.92,35.9 122.74,36.08 122.32,36.08 122.3,36.11 v2(121.93,36.11) 121.34,36.11 121.12,35.89 JDIMM2.43 121.12,33.5 v2(122.26,32.36) ; v2(138.72,42.87) 138.5,42.65 138.5,39.55 JDIMM1.134 ; JDIMM2.25 115.72,36 115.54,36.18 v2(113.96,36.18) 113.92,36.14 JDIMM2.19 ; v2(153.45,38.13) JDIMM1.184 ; v2(107.85,43.7) 107.12,43.7 106.95,43.87 JDIMM1.37 ; v2(98.29,44.19) 98.55,44.48 JDIMM1.9 ; v2(145.55,43.22) 146.13,43.22 146.85,42.5 JDIMM1.162 ; JDIMM2.168 161.05,26.56 161.05,29.55 161.57,30.07 v2(161.62,30.07) ; v2(151.42,38.16) 151.54,38.16 151.67,38.28 151.67,38.57 151.65,38.59 JDIMM1.178 151.65,40.64 151.8,40.79 151.8,41.23 151.3,41.72 v2(151.22,41.72) 151.17,41.72 ; JDIMM1.187 154.35,45.67 153.45,44.77 v2(153.15,44.77) ; JDIMM2.11 111.52,35.94 v2(111.74,36.16) 111.78,36.16 112.12,35.82 JDIMM2.13 ; v2(140.17,46.3) 140.24,46.3 139.95,46.59 JDIMM1.139 ; v2(102.03,38.1) 102.03,38.07 101.85,38.25 JDIMM1.20 101.85,41.66 v2(102.48,42.29) ; JDIMM2.127 148.72,35.99 v2(148.85,36.12) ; JDIMM1.72 117.45,40.57 117.83,40.94 117.83,41.37 v2(117.14,41.97)
  BOTTOM w0.381: JDIMM1.37 106.95,48.89 106.63,49.21 105.42,49.21 105.15,48.94 JDIMM1.31 ; v2(58.4,78.9) 58.4,79.1 UV1.K22 ; JDIMM1.13 99.75,48.88 99.57,49.05 99.35,49.05 99.15,48.86 JDIMM1.11 ; v2(198.81,24.44) 199.14,24.77 CA25.1 ; CC27.2 118.6,107.45 v2(118.42,107.62) ; UV1.AA13 67.42,86.1 v2(67.93,86.61) ; UV1.N16 61.49,84.1 v2(61.09,84.5) ; UV1.T16 v2(63.13,84.57) UV1.R15 ; UV1.Y17 66.4,83.14 v2(66.86,82.68) ; UV1.P25 62,76.9 v2(61.6,76.5) 61.2,76.9 UV1.N25 ; UV1.N11 61.63,88.1 v2(62.1,87.63) 62.6,87.13 UV1.R12 UV1.T13 ; v2(65.93,84.63) 65.4,84.1 UV1.V16 ; v2(108.45,27.96) 108.78,27.62 108.78,26.58 JDIMM2.2 ; JDIMM1.189 154.95,45.21 156.69,43.46 156.7,43.46 v2(156.92,43.25) ; v2(33.94,79.05) 34.15,78.84 UV6.M1 ; v2(62.05,80.74) 62.6,81.29 UV1.R20 ; JDIMM2.150 155.62,28.48 v2(155.68,28.54) ; UV1.Y15 66.48,85.1 v2(66.96,85.58) ; PQ3.4 83.23,50.71 v2(82.99,50.47) ; v2(54.72,106.58) 54.97,106.84 54.97,107.37 54.63,107.72 UV3.5 ; UV1.T18 63.6,82.5 UV1.U17 64.45,83.3 64.97,82.78 v2(65.07,82.78) 65.4,82.44 UV1.V18 65.93,81.77 UV1.Y20 66.4,81.17 v2(66.77,80.8) ; JDIMM1.71 117.15,49.12 116.8,49.48 115.86,49.48 115.35,48.97 JDIMM1.65 ; v2(114.98,43.88) 115.02,43.92 115.02,46 114.75,46.27 JDIMM1.63 114.75,48.84 114.64,48.95 114.31,48.95 114.15,48.79 JDIMM1.61 ; JDIMM1.167 148.35,46.31 v2(148.36,46.3) ; v2(62.8,77.3) 63.2,76.9 UV1.T25 ; UV1.T11 63.42,88.1 v2(63.1,88.42) 62.78,88.11 62.61,88.11 UV1.R11 ; U1.4 v2(83.58,93.19) ; JDIMM1.43 108.75,46.3 v2(109.64,45.4) ; CL37.1 174.17,107.37 173.87,107.07 v2(173.87,107.07) ; UV1.N21 v2(61.1,79.8) ; v2(86.87,52.2) 86.68,52.01 85.97,52.01 85.97,52.01 PQ3.1 ; UV1.N18 61.6,82.39 v2(62.1,82.89) 62.32,83.11 62.32,83.11 62.52,83.3 UV1.R17 ; v2(160.08,103.89) 160.38,103.89 160.66,103.61 RC122.2 ; UV1.M12 UV1.N13 62.13,85.57 v2(62.13,85.48) ; JDIMM1.25 103.35,48.93 103.1,49.18 101.83,49.18 101.55,48.89 JDIMM1.19 ; CL36.1 177.65,107.37 v2(177.88,107.6) ; UV1.V11 65.4,88.37 v2(65.14,88.63) ; v2(147.38,106.68) RC133.1 ; UV1.U20 64.4,81.16 64.81,80.75 v2(64.8,80.75) ; UV1.AA16 67.4,84.16 v2(67.86,84.63) 68.34,85.1 UV1.AB15 ; v2(168.87,98.18) 168.79,98.1 168.79,97.51 169.09,97.21 170.03,97.21 R2453.2 ; UV1.V13 65.4,86.08 v2(64.82,85.5) 64.42,85.1 UV1.U15 ; v2(62.98,79.76) 63.06,79.76 UV1.T21 ; UV1.AB10 68.2,88.9 67.95,88.65 v2(67.73,88.65) 67.4,88.33 UV1.AA11 ; v2(117.74,107.62) CC28.2 ; v3(76.19,18.42) 76.33,18.28 PR106.2
  BOTTOM w0.457: RV151.1 62.85,101.93 62.79,101.99 62.79,102.01 62.41,102.39 v2(62.16,102.39) ; UL3.2 188.52,96.22 v2(188.33,96.41)
  BOTTOM w0.508: RC89.2 162.6,114.33 163.21,114.94 164.67,114.94 ; CC6.1 v2(133.46,109.2) ; PR558.2 v2(72.5,107.75) ; CV24.2 v2(45.73,105.47) ; PC1307.2 PR1304.2 v2(78.16,54) ; CV114.2 CV111.2 CV110.2 CV109.2 30.54,82.81 v2(29.75,82.81) ; CV114.2 CV116.2 ; CV114.2 33.71,82.99 v2(34.09,83.37) ; CV101.2 RV45.2 39.55,83.37 v2(38.89,84.03) ; UM1.2 195.35,75.77 194.77,76.35 v2(194.77,76.61) ; v2(67.37,33.33) 67.37,32.57 66.27,31.47 PR1032.1 PR1033.1 ; PC1034.2 53.23,39.44 53.17,39.5 v2(53.17,40.06) ; PC709.1 v2(36.38,17.26) ; v2(188.22,9.97) 188.82,10.57 JHDD.12 ; CX25.2 199.05,78.46 v2(198.94,78.35) ; v2(167.82,16.95) 167.82,17.63 168.48,18.29 C5216.2 C5217.2 ; YV1.2 v2(82.57,70.41) ; R2338.2 168.51,64.52 168.15,64.16 v2(167.72,64.16) ; v2(103.46,86.66) 103.98,87.18 RC135.2 ; CS43.2 21.68,15.55 v2(21.7,15.56) ; v2(84.77,7.44) 84.74,7.44 84.65,7.34 PC210.2 82.89,7.34 PR204.2 ; CL37.1 174.48,107.7 174.6,107.82 YL2.2 ; v2(154.36,109.53) 154.06,109.22 RC87.1 ; CV180.2 v2(43.49,103.1) ; PR32.2 80.5,50.55 v2(80.45,50.6) ; JHDD.3 v2(182.33,13.73) ; PR1038.2 v2(54.08,41) ; JHDD.11 179.16,10.57 v2(178.34,11.4) ; v2(84.44,87.48) 84.64,87.69 85.53,87.69 85.78,87.94 CV167.1 ; 164.67,114.94 164.14,114.41 v4(164.14,113.95) 164.14,113.09 v2(164.22,113.01) 164.22,112.88 165.23,111.87 RL27.1 ; 164.67,114.94 166.83,114.94 167.32,114.46 UL2.2 ; CA21.2 197.87,12.96 v2(197.92,13.01) CC5.2 ; CV129.2 v2(32.06,67.21) ; PR712.2 43.17,10.24 v2(42.88,10.53) ; CV173.2 v2(33.97,67.29) ; PC711.1 51.36,14.53 v2(51.49,14.66) ; C5212.2 105.67,89.82 v2(105.47,90.02) ; 143.49,112.32 143.49,112.65 143.08,113.06 v2(142.55,113.06) ; 143.49,112.32 v2(142.6,112.32) ; 143.49,112.32 C59.2 ; CM8.1 199.72,76.11 199.21,75.59 v2(199.21,75.49) ; JHDD.6 184.73,12.11 v3(185.21,11.64) ; CV169.1 v2(84.7,92.07) ; C63.2 148.52,110.67 v2(148.01,111.18) ; PR1102.1 v2(32.19,42.85) ; JRTC.3 v2(29.19,7.53) ; RV74.1 83.88,97.72 v2(84.13,97.97) ; CV166.1 81.41,96.65 v2(81.21,96.45) ; v2(36.66,83.49) 36.63,83.47 RV46.2 CV117.2 ; v3(69.14,16.77) 69.12,16.77 68.81,16.46 PC106.2 ; v2(66.66,103.56) 67.04,103.56 67.16,103.43 PC527.1 ; CV20.2 CV21.2 v2(81.72,82.22) ; CL39.2 v2(169.6,119.44) ; YV1.4 80.87,74.44 80.4,74.91 v2(80.24,74.91) 80.22,74.93 CV17.2 79.56,75.37 79.89,75.7 RV163.2 ; JIO.10 26.67,52.95 v2(26.85,52.76) ; RV83.2 72.37,100.33 v2(72.45,100.26) ; v2(64.19,102.52) 64.45,102.26 RV21.1 ; CV131.2 v2(34.85,67.29) ; JIO.8 26.72,50.95 v2(27.11,51.34) 26.5,51.95 JIO.9 ; YL2.4 176.81,110.19 177.7,110.19 v2(177.86,110.34) ; RC99.2 167.52,97.72 167.21,98.02 167.06,98.02 v2(166.99,98.09) 166.94,98.09 166.6,98.43 CC31.2 CC34.2 ; QV4.3 v2(50.04,111.82) ; JIO.13 v2(26.59,55.95) ; v2(168.54,94.7) 168.48,94.64 168.1,94.64 168.08,94.67 RC113.2 ; v2(13.81,65.46) 13.81,65.27 13.51,64.96 HE1.2 ; v2(36.38,18.09) 36.77,18.48 PC719.1 ; PC724.1 18.85,23.42 v2(18.34,22.92) ; CX29.2 v2(199.19,89.13) ; 166.43,119.23 166.4,119.26 H10.1 ; PC728.1 50.79,11.87 v2(51.3,11.36) ; v2(187.97,19.54) 188.01,19.58 189.52,19.58 189.57,19.54 CA74.2 ; v2(169.23,111.23) 168.84,111.62 CL15.2 CL19.2 ; v2(81.97,79.18) 83.11,79.18 83.57,78.72 CC30.2 ; CV18.2 v2(81.39,70.46) ; DA14.1 209.48,15.8 v2(209.61,15.68) ; PC726.1 v2(44.48,8.16) ; CV161.2 v2(41.71,103.1) ; CI40.2 v2(193.48,56.7) ; v2(145.6,109.91) 145.6,110.06 145.4,110.27 C58.2 ; PC531.1 65.08,105.85 v2(64.83,105.59) ; v3(66.86,24.06) 66.97,23.95 66.97,20.5 ; v2(181.54,53.88) 181.44,53.88 181.22,53.66 PC313.2 ; v2(204.48,15.8) 204.4,15.88 DA13.1 ; v2(183.06,50.47) PC312.2 183.95,50.47 184.66,51.19 PR307.2 ; CX27.2 v2(199.24,85.58) ; RC116.2 161.52,93.81 v2(161.55,93.77) ; CV135.2 39.93,99.37 v2(39.35,98.78) ; CV170.1 81.72,87.71 v2(81.69,87.69) 82.48,87.69 82.73,87.94 RV73.1 ; v2(29.51,10.08) JRTC.2 ; JEDP.41 7.61,102.1 v2(7.93,101.78) ; CM3.1 198.54,70.35 v2(198.84,70.65) ; v2(76.38,109.02) 76.05,109.35 PC528.2 ; CX30.2 v2(199.19,91.83) ; JIO.16 24.4,58.95 v2(24.31,58.86) ; PC15.2 84.21,48.43 v2(83.67,47.9) ; RC88.2 167.85,100.51 v4(168.99,101.66) 169.32,101.99 v2(169.78,101.99) ; v2(178.58,18.6) 178.58,18.6 U2302.4 ; DE2.1 173.08,119.44 172.95,119.31 v2(172.4,119.31) 172.4,119.71 171.99,120.12 171.99,120.45 ; CX26.2 198.27,81.16 v2(197.82,81.6) ; CV115.2 40.34,82.91 40.34,83.27 v2(40.19,83.42) ; v2(38.22,70.62) 39.3,69.54 CV102.2 ; CV118.2 v2(29.9,66.97) ; PR306.2 v3(184.54,46.66) ; v2(39.93,11.27) 40.09,11.12 PC725.1 ; v2(50.48,112.83) CV25.2 ; CX24.2 v2(199.27,84.71) ; RV89.1 v2(79.23,96.45) ; v2(170.41,119.92) 170.74,119.59 CL38.2 ; PH500.2 v2(80.27,120.78) ; CV108.2 28.68,81.92 28.63,81.97 28.63,82.35 v2(28.66,82.38) ; CI43.2 v2(196.14,41.27) ; PC858.2 69.02,61.02 v2(69.65,60.38) ; RA1113.1 198.81,13.01 199.45,12.37 v2(199.45,12.25) ; CV127.2 v2(32.95,67.21) ; PC707.2 v2(48.57,19.18) ; PC855.2 69.08,65.14 v2(69.78,64.44) ; CMOS1.1 152.51,55.22 v2(152.89,55.6) ; v2(39.5,66.98) 40.19,67.67 CV122.2 CV107.2 ; v2(60,111.41) 60.23,111.64 PC548.1 ; CV121.2 v2(35.74,67.29) ; PC203.2 v2(79.3,8.82) ; C5219.2 162.49,18.09 161.98,18.6 v2(161.7,18.6) 161.47,18.37 C5218.2 ; RV88.1 v2(78.42,91.24) ; v2(20.96,61.97) 21.16,61.76 22.49,61.76 JIO.18 ; R255.1 v2(107.83,93.91) ; JRTC.4 v2(33.59,13.88) ; PR301.2 PC300.2 v3(184.54,44.89) ; v2(41.03,83.42) 41.41,83.04 41.41,82.86 CV112.2 CV113.2 ; CI2.2 v2(193.48,57.84) ; CV158.2 v2(42.6,103.13) ; v2(195.79,44.7) DI5.1 ; v2(137.93,109.12) CC7.1 ; PC202.2 v2(79.43,10.6) ; CV120.2 v2(31.17,67.21) ; PC1104.2 v2(32.19,41.97) ; RC66.2 CC27.2 ; CX28.2 v2(199.19,88.27) ; CV19.2 v2(81.72,83.49) ; CS44.2 v2(3.26,56.28) ; CV162.2 v2(40.82,103.13) ; DI2.1 v2(194.6,63.41) ; C79.2 v2(119.06,110.42) ; PC708.2 v2(45.27,19.87) ; PC710.2 v2(51.42,17.84) ; JFAN.3 v2(4.55,73.41) ; PR711.1 v2(51.47,13.64) ; v2(42.17,111.31) QV3.3 ; v2(200.73,82.02) CX23.2 ; PC1105.2 v2(34.6,48.63) ; PC720.1 v2(47.19,8.23) ; CV10.2 v2(60.41,109.2)
  BOTTOM w0.762: v2(109.77,18.08) 109.38,18.47 109.37,18.47 109.2,18.64 JDIMM2.205
  vias: v2(1.65,50.71) v2(2.85,67.75) v2(2.85,66.86) v2(3.05,52.3) v2(3.13,49.48) v2(3.61,86.25) v2(3.62,58.74) v2(3.69,60.88) v2(3.94,93.83) v2(5.19,50.63) v2(5.22,47.92) v2(5.62,100.44) v2(5.8,98.66) v2(6.28,61) v2(6.35,59.39) v2(6.46,96.88) v2(6.79,95.18) v2(7.17,83.37) v2(7.15,50.95) v2(7.42,86.92) v2(7.69,48.41) v2(8.24,61.72) v2(8.2,60.46) v2(8.82,59.27) v2(9.35,53.97) v2(9.35,52.68) v2(9.55,57.62) v2(9.71,63.05) v2(10.34,63.05) v2(10.4,58.65) v2(10.57,51.69) v2(11.45,50.38) v2(19.36,57.59) v2(19.36,56.82) v2(19.95,8.74) v2(20.05,93.12) v2(20.05,90.91) v2(19.97,10.88) v2(20.32,53.37) v2(20.3,50.96) v2(21.4,71.61) v2(21.42,69.76) v2(21.7,56.22) v2(21.77,11.89) v2(21.77,7.57) v2(21.91,52.19) v2(22.08,94.42) v2(22.1,89.74) v2(22.42,19.82) v2(22.42,19.18) v2(22.4,18.56) v2(22.4,17.92) v2(22.4,17.29) v2(22.4,16.65) v2(22.55,57.54) v2(22.54,54.88) v2(23.65,10.9) v2(23.65,8.77) v2(24.19,93.12) v2(24.16,90.91) v2(24.52,40.17) v2(25.56,80.88) v2(25.56,80.24) v2(25.99,119.89) v2(25.96,117.76) v2(26.78,102.59) v2(27.79,120.91) v2(27.79,116.59) v2(27.9,102.87) v2(29.7,119.87) v2(29.7,117.73) v2(30.83,38.65) v2(30.75,36.94) v2(30.75,36.34) v2(33.97,87.3) v2(36.02,86.9) v2(38.84,87.08) v2(39.4,61.68) v2(39.48,59.11) v2(41.64,63.1) v2(41.61,57.92) v2(42.35,15.93) v2(43.24,14.79) v2(43.24,13.01) v2(43.92,61.83) v2(43.87,59.14) v2(44.13,13.9) v2(45.01,14.79) v2(45.01,13.01) v2(48.81,6.99) v2(52.03,64.46) v2(52.33,65.04) v2(53.75,66.6) v2(54.19,118.7) v2(54.36,66.62) v2(56.27,121.06) v2(57.73,120.04) v2(58.35,21.77) v2(58.86,13.52) v2(59.24,27.23) v2(59.26,121.01) v2(59.37,66.35) v2(60,66.35) v2(60.13,38.03) v2(60.13,37.14) v2(60.13,36.33) v2(60.64,66.35) v2(60.85,119.49) v2(61.14,38.03) v2(61.14,37.14) v2(61.14,36.33) v2(61.27,66.35) v2(61.78,71.05) v2(62.03,38.03) v2(62.03,37.14) v2(62.03,36.33) v2(62.13,120.98) v2(62.79,112.68) v2(62.92,38.03) v2(62.92,37.14) v2(62.92,36.33) v2(63.37,119.58) v2(64.04,112.58) v2(64.19,69.52) v2(64.19,68.64) v2(64.19,66.86) v2(64.68,120.94) v2(64.83,9.71) v2(65.25,118.67) v2(68.56,108.21) v2(68.76,69.27) v2(68.76,68.64) v2(69.4,68.64) v2(69.41,39.63) v2(69.5,113.47) v2(70.21,113.49) v2(71.68,48.57) v2(72.35,69.8) v2(72.8,76.5) v2(74.61,67.87) v2(76.33,69.5) v2(78.03,65.46) v2(78.54,61.88) v2(80.56,43.95) v2(80.93,58.96) v2(80.91,56.82) v2(81.11,75.49) v2(82.81,59.97) v2(82.81,55.66) v2(84.16,108.03) v2(84.23,105.47) v2(84.49,13.92) v2(84.74,58.91) v2(84.74,56.75) v2(84.97,14.66) v2(85.4,119.69) v2(86.39,109.45) v2(86.37,104.27) v2(87.43,120.32) v2(88.27,88.83) v2(88.27,88.07) v2(88.63,105.49) v2(88.68,108.18) v2(91.12,118.8) v2(91.12,113.34) v2(91.73,58.13) v2(91.8,60.25) v2(91.94,56.33) v2(91.97,56.99) v2(94.65,63.86) v2(94.61,61.75) v2(94.57,59.36) v2(97.02,43.81) v2(97.02,42.29) v2(99.14,2.52) v2(99.17,4.65) v2(100.19,45.33) v2(100.19,42.29) v2(100.97,5.67) v2(100.97,1.35) v2(102.48,45.33) v2(102.48,43.81) v2(102.93,4.55) v2(102.93,2.42) v2(103.53,43.43) v2(105.41,45.33) v2(105.41,43.81) v2(107.75,91.85) v2(107.75,90.61) v2(107.87,45.22) v2(109.19,32.23) v2(109.19,30.71) v2(109.19,29.18) v2(109.64,43.12) v2(111.04,28.8) v2(111.32,43.5) v2(112.17,90.73) v2(112.49,86.08) v2(112.61,81.83) v2(112.56,31.98) v2(112.56,30.45) v2(112.81,92.28) v2(113.45,43.5) v2(113.45,41.97) v2(113.7,80.86) v2(114.15,83.16) v2(114.55,78.99) v2(114.77,90.74) v2(114.83,85.91) v2(114.99,82.12) v2(114.98,31.98) v2(114.98,30.45) v2(114.98,28.93) v2(115.44,79.89) v2(116.11,75.86) v2(116.8,32.36) v2(116.8,30.15) v2(117.14,43.5) v2(117.35,77.22) v2(118,74.28) v2(118.25,31.98) v2(118.25,30.45) v2(118.25,28.93) v2(119.01,72.9) v2(119.25,75.57) v2(119.78,45.34) v2(119.78,43.85) v2(120.39,74.28) v2(120.47,76.95) v2(120.48,31.98) v2(120.48,30.45) v2(120.48,28.93) v2(121.34,108.01) v2(121.34,106.1) v2(121.73,43.85) v2(121.77,75.66) v2(122.26,30.07) v2(123.15,77.04) v2(123.5,104.58) v2(123.51,31.98) v2(123.51,30.45) v2(123.51,28.92) v2(123.65,43.85) v2(123.88,106.48) v2(125.28,107.37) v2(125.48,75.55) v2(125.82,31.98) v2(125.82,30.45) v2(125.82,28.93) v2(125.87,43.85) v2(126.29,66.6) v2(126.29,65.97) v2(127.06,104.96) v2(127.67,106.46) v2(127.83,77.85) v2(127.96,43.95) v2(127.96,43.19) v2(128.12,104.25) v2(128.11,66.68) v2(128.11,66.09) v2(128.11,30.83) v2(128.11,28.55) v2(128.63,105.24) v2(129.44,78.46) v2(129.59,30.45) v2(129.59,28.93) v2(130.28,104.81) v2(130.36,66.6) v2(130.36,65.97) v2(130.74,111.18) v2(130.89,77.99) v2(130.89,76.28) v2(131.26,43.93) v2(131.37,105.47) v2(131.97,30.94) v2(131.97,29.42) v2(132.48,77.92) v2(132.64,95.31) v2(132.64,94.67) v2(132.64,94.04) v2(132.77,23.3) v2(133.43,110.72) v2(133.36,23.3) v2(133.5,30.96) v2(133.5,29.44) v2(133.64,43.95) v2(133.84,105.62) v2(134.17,103.09) v2(134.2,77.55) v2(135.53,30.96) v2(135.53,29.44) v2(135.53,27.91) v2(135.72,77.71) v2(136.01,105.47) v2(136.41,43.25) v2(137.39,30.96) v2(137.39,29.44) v2(137.82,76.97) v2(137.76,75.17) v2(137.76,73.31) v2(139.26,75.5) v2(139.26,72.96) v2(139.67,30.96) v2(139.67,30.2) v2(140.17,44.77) v2(141.38,73.12) v2(141.47,76.59) v2(141.47,74.83) v2(141.87,30.58) v2(142.4,29.41) v2(142.48,46.3) v2(142.48,44.77) v2(142.48,43.25) v2(142.93,31.46) v2(143.31,76.21) v2(143.31,73.55) v2(143.92,43.63) v2(143.92,41.34) v2(144.23,30.96) v2(144.23,30.2) v2(145.6,46.26) v2(145.55,41.72) v2(145.66,31.36) v2(146.17,30.98) v2(147,76.84) v2(147.38,111.82) v2(147.38,111.18) v2(148.01,111.82) v2(148.36,44.77) v2(148.36,41.72) v2(148.49,74.05) v2(148.79,31.98) v2(148.79,30.45) v2(149.92,63) v2(149.97,45.11) v2(150.37,62.54) v2(150.65,32.36) v2(150.86,62.03) v2(151.22,46.3) v2(151.22,44.77) v2(151.31,61.53) v2(151.44,105.85) v2(151.59,109.38) v2(151.95,104.83) v2(152.17,31.98) v2(152.17,30.45) v2(152.17,28.93) v2(153.15,43.25) v2(153.15,41.72) v2(153.6,21.52) v2(153.88,17.43) v2(154.2,31.97) v2(154.2,30.44) v2(154.2,28.92) v2(154.36,21.52) v2(154.36,17.07) v2(154.67,43.63) v2(156.77,107.5) v2(156.92,44.77) v2(156.92,41.72) v2(157.44,104.02) v2(157.51,31.97) v2(157.51,30.44) v2(157.51,28.92) v2(157.61,102.68) v2(157.82,91.44) v2(158.07,104.02) v2(158.15,55.81) v2(158.15,55.15) v2(158.15,54.31) v2(158.15,53.6) v2(158.4,46.32) v2(158.4,45.07) v2(158.46,9.72) v2(159.02,10.32) v2(159.1,9.73) v2(159.87,30.45) v2(159.87,28.93) v2(160.05,100.64) v2(161.47,46.41) v2(161.47,45.78) v2(161.47,45.14) v2(161.62,32.36) v2(161.63,14.23) v2(162.11,42.09) v2(162.11,41.08) v2(162.59,14.23) v2(163.12,31.98) v2(163.12,30.45) v2(163.84,70.9) v2(163.84,68.69) v2(165.41,32.09) v2(165.41,30.57) v2(165.41,29.04) v2(165.87,72.19) v2(165.89,67.52) v2(166.93,30.95) v2(167.32,13.26) v2(167.32,12.63) v2(167.32,11.99) v2(167.32,10.34) v2(167.32,9.71) v2(167.85,68.64) v2(167.98,70.9) v2(168.84,22.19) v2(168.84,21.56) v2(168.86,32.09) v2(168.86,30.57) v2(168.86,29.04) v2(169.92,14.15) v2(170.55,14.16) v2(171.19,14.18) v2(173.54,60) v2(174.55,59.87) v2(174.61,55.27) v2(174.68,102.85) v2(174.94,103.43) v2(174.99,104.22) v2(175.32,15.04) v2(175.32,14.41) v2(175.32,13.77) v2(175.32,13.14) v2(175.42,102.85) v2(175.57,104.22) v2(175.57,103.43) v2(176.1,102.85) v2(176.18,104.22) v2(176.21,103.43) v2(176.55,67.78) v2(177.2,55.33) v2(177.84,9.99) v2(178.03,86.54) v2(178.11,11.99) v2(179.48,92.56) v2(179.56,90) v2(180.4,47.68) v2(181.13,33.18) v2(181.11,31.04) v2(181.72,93.98) v2(181.69,88.8) v2(181.92,99.8) v2(183.01,99.19) v2(183.01,34.19) v2(183.01,29.87) v2(183.81,2.97) v2(184,92.71) v2(183.95,90.02) v2(184.26,98.2) v2(184.89,33.08) v2(184.89,30.94) v2(185.86,40.19) v2(186.38,79.58) v2(186.37,78.53) v2(188.75,47.54) v2(188.76,45.55) v2(189.67,42.73) v2(190.02,60.86) v2(190.3,68.89) v2(190.33,35.63) v2(190.43,11.36) v2(190.68,89.46) v2(190.84,47.58) v2(190.81,13.14) v2(190.94,68.89) v2(190.95,35.62) v2(191.36,49.38) v2(191.57,35.62) v2(192.22,35.63) v2(192.72,80.29) v2(192.84,56.06) v2(192.84,53.78) v2(192.84,53.14) v2(192.84,52.51) v2(193.15,86.34) v2(193.15,5.11) v2(193.12,2.98) v2(193.25,82.68) v2(193.16,59.85) v2(193.33,87.79) v2(193.48,56.06) v2(193.63,95.41) v2(193.66,97.54) v2(193.76,84.41) v2(194.04,79.23) v2(194.9,36) v2(194.95,6.13) v2(194.95,1.81) v2(195.3,73.46) v2(195.32,35.43) v2(195.51,98.56) v2(195.51,94.24) v2(195.56,61.67) v2(196.12,78.49) v2(196.6,119.87) v2(196.58,117.73) v2(196.78,84.38) v2(196.78,78.8) v2(196.91,5.06) v2(196.91,2.93) v2(197.3,91.44) v2(197.41,97.46) v2(197.41,95.33) v2(197.44,29.46) v2(198.41,120.88) v2(198.41,116.56) v2(198.55,32.16) v2(198.71,26.05) v2(199.73,28.36) v2(200.15,30.88) v2(200.26,119.84) v2(200.26,117.71) v3(0.51,102.95) v3(0.51,95.46) v3(0.51,87.84) v3(0.51,80.07) v3(0.51,72.55) v3(0.51,65.08) v3(0.51,57.18) v3(0.51,49.61) v3(4.78,46.23) v3(9.52,107.28) v3(10.5,46) v3(10.93,121.77) v3(10.92,115.32) v3(12.33,10.8) v3(12.83,41.33) v3(12.83,33.91) v3(13.01,115.37) v3(13.01,114.74) v3(13.26,116.77) v3(13.26,116.13) v3(13.65,115.37) v3(13.65,114.74) v3(13.8,6.02) v3(13.9,116.77) v3(13.9,116.13) v3(14.15,10.98) v3(14.53,116.77) v3(14.53,116.13) v3(14.92,10.98) v3(15.17,116.13) v3(15.17,13.52) v3(15.3,15.42) v3(15.32,14.56) v3(15.3,11.61) v3(15.57,122.27) v3(15.93,115.37) v3(16.06,15.42) v3(16.06,14.53) v3(16.06,13.52) v3(16.06,12.5) v3(16.06,11.61) v3(16.06,10.72) v3(16.82,115.24) v3(17.07,12.76) v3(17.2,15.42) v3(17.2,14.53) v3(17.2,13.52) v3(18.09,116.01) v3(18.09,115.37) v3(18.09,114.74) v3(18.09,13.77) v3(18.22,14.53) v3(23.25,109.4) v3(23.25,108.72) v3(23.22,108.03) v3(23.25,107.4) v3(23.32,122.27) v3(23.93,109.4) v3(23.91,108.74) v3(23.93,108.01) v3(23.88,107.37) v3(27,8.47) v3(27.62,109.4) v3(27.62,108.77) v3(27.62,108.13) v3(27.62,107.5) v3(27.69,41.08) v3(27.69,40.3) v3(29.01,31.68) v3(29.01,30.92) v3(29.01,6.02) v3(29.79,31.67) v3(30.48,31.67) v3(31.43,45.65) v3(31.93,46.41) v3(32.26,122.28) v3(32.31,47.17) v3(32.31,45.65) v3(32.5,9.66) v3(33.84,33.58) v3(33.83,32.94) v3(34.6,33.62) v3(34.61,32.98) v3(34.63,32.33) v3(34.62,31.7) v3(34.61,31.06) v3(34.61,30.42) v3(34.61,29.79) v3(34.6,29.14) v3(34.58,28.48) v3(34.57,27.84) v3(34.56,27.19) v3(34.55,26.55) v3(34.74,8.31) v3(36.76,6.02) v3(38.36,120.29) v3(41.33,46.92) v3(42.22,47.43) v3(42.22,46.28) v3(42.22,45.27) v3(42.22,44.25) v3(42.58,43.3) v3(42.56,42.64) v3(42.58,42) v3(44.38,6.02) v3(45.14,17.45) v3(46.1,120.29) v3(48.04,28.52) v3(48.02,27.77) v3(48.05,29.23) v3(48.71,29.21) v3(48.71,28.52) v3(48.71,27.75) v3(53.72,120.28) v3(53.65,57.84) v3(53.65,57.21) v3(55.38,11.51) v3(55.78,15.52) v3(55.78,13.46) v3(57.33,47.72) v3(57.97,58.98) v3(57.98,48.37) v3(58.01,47.72) v3(58.35,55.55) v3(58.54,51.02) v3(58.71,52.47) v3(58.67,48.39) v3(58.68,47.74) v3(58.87,51.83) v3(58.98,58.98) v3(58.98,55.55) v3(59.02,47.2) v3(59.32,52.9) v3(59.34,47.77) v3(59.35,52.26) v3(59.37,51.43) v3(59.37,50.79) v3(59.37,50.14) v3(59.35,48.4) v3(59.75,55.55) v3(59.87,58.96) v3(59.87,58.22) v3(59.87,57.33) v3(59.87,56.32) v3(60.43,55.53) v3(60.56,58.98) v3(60.64,58.22) v3(60.64,57.33) v3(60.64,56.32) v3(60.89,52.54) v3(60.92,51.69) v3(60.89,50.78) v3(60.92,50.11) v3(60.93,49.46) v3(61.02,54.82) v3(61.04,54.16) v3(60.98,48.07) v3(61.07,55.5) v3(61.08,53.51) v3(61.28,48.75) v3(61.37,122.28) v3(61.52,51.15) v3(61.51,50.39) v3(61.59,53.12) v3(61.55,52.48) v3(61.59,51.78) v3(61.7,54.84) v3(61.7,54.08) v3(61.78,58.98) v3(61.78,55.5) v3(62.97,6.02) v3(64.45,18.09) v3(64.45,17.33) v3(64.95,20.5) v3(65.08,18.09) v3(65.08,17.33) v3(65.61,20.48) v3(65.61,19.84) v3(65.7,19.17) v3(65.7,18.47) v3(65.72,17.33) v3(66.33,19.84) v3(66.34,19.17) v3(66.34,18.47) v3(66.3,16.51) v3(66.35,21.14) v3(66.35,20.5) v3(66.36,17.84) v3(66.36,17.17) v3(66.99,21.14) v3(66.99,20.5) v3(66.96,19.87) v3(66.99,19.16) v3(67.01,18.47) v3(67.01,17.84) v3(67,17.17) v3(66.99,16.49) v3(67.62,58.98) v3(68.26,120.71) v3(68.26,119.94) v3(68.26,119.18) v3(68.51,58.98) v3(68.99,122.28) v3(69.14,120.71) v3(69.14,119.94) v3(69.14,119.18) v3(69.27,58.09) v3(69.27,57.21) v3(69.27,56.44) v3(69.4,22.53) v3(69.4,21.9) v3(69.68,11.49) v3(70.03,111.05) v3(70.36,11.51) v3(70.64,60.46) v3(70.69,111.08) v3(70.69,110.42) v3(71,11.51) v3(71.41,60.46) v3(71.68,120.58) v3(71.68,119.82) v3(71.68,119.05) v3(71.66,11.51) v3(71.81,23.68) v3(71.86,18.53) v3(71.86,17.71) v3(72.19,60.48) v3(72.17,12.09) v3(72.45,23.68) v3(72.57,120.58) v3(72.57,119.82) v3(72.57,119.05) v3(72.57,18.53) v3(72.62,17.71) v3(72.95,60.48) v3(73.34,54.54) v3(73.34,53.52) v3(73.67,60.46) v3(73.84,54.03) v3(74.4,60.46) v3(74.48,53.52) v3(74.63,54.44) v3(74.63,6.01) v3(75.24,60.46) v3(75.57,54.08) v3(75.98,60.43) v3(76.61,122.28) v3(80.07,111.18) v3(80.57,110.55) v3(80.7,118.04) v3(80.7,116.77) v3(80.7,115.5) v3(80.7,114.23) v3(80.7,109.78) v3(80.7,109.02) v3(80.83,112.83) v3(80.83,112.07) v3(80.83,111.31) v3(80.96,117.4) v3(80.96,116.13) v3(80.96,114.86) v3(81.21,110.55) v3(81.21,18.98) v3(81.21,18.22) v3(81.34,118.04) v3(81.34,116.77) v3(81.34,115.5) v3(81.34,114.23) v3(81.34,14.66) v3(81.46,112.83) v3(81.46,112.07) v3(81.46,111.31) v3(81.59,117.4) v3(81.59,116.13) v3(81.59,114.86) v3(81.84,110.55) v3(81.84,19.49) v3(81.84,18.85) v3(81.84,18.22) v3(81.97,118.04) v3(81.97,116.77) v3(81.97,115.5) v3(81.97,114.23) v3(81.97,14.66) v3(82.1,112.83) v3(82.1,112.07) v3(82.1,111.31) v3(82.23,117.4) v3(82.23,116.13) v3(82.23,114.86) v3(82.25,6.01) v3(82.48,110.55) v3(82.48,19.49) v3(82.48,18.85) v3(82.48,18.22) v3(82.61,118.04) v3(82.61,116.77) v3(82.61,115.5) v3(82.61,114.23) v3(82.73,112.83) v3(82.73,112.07) v3(82.73,111.31) v3(82.86,117.4) v3(82.86,116.13) v3(82.86,114.86) v3(83.11,19.49) v3(83.11,18.85) v3(83.11,18.22) v3(83.24,118.04) v3(83.24,116.77) v3(83.24,115.5) v3(83.24,114.23) v3(83.37,112.83) v3(83.37,112.07) v3(83.37,111.31) v3(83.5,117.4) v3(83.5,116.13) v3(83.5,114.86) v3(83.47,11.76) v3(83.5,10.72) v3(83.88,19.49) v3(83.88,18.85) v3(84.23,122.28) v3(84.54,11.76) v3(84.54,10.7) v3(84.64,19.49) v3(84.64,18.85) v3(85.4,19.49) v3(85.4,18.85) v3(85.95,24.78) v3(86.16,19.49) v3(86.16,18.85) v3(86.37,8.39) v3(86.37,7.75) v3(86.78,25.01) v3(86.92,19.49) v3(86.92,18.85) v3(87.48,25.01) v3(88.27,28.63) v3(88.32,8.56) v3(88.5,25.13) v3(89.03,28.63) v3(89.08,8.56) v3(89.26,25.13) v3(89.85,28.63) v3(89.87,6.01) v3(91.85,122.28) v3(93.78,13.14) v3(93.78,12.37) v3(94.54,13.9) v3(94.54,13.14) v3(94.54,12.37) v3(95.31,13.9) v3(95.31,13.14) v3(95.31,12.37) v3(96.75,5.69) v3(99.47,122.28) v3(103.82,120.96) v3(103.82,118.55) v3(103.82,117.66) v3(103.82,115.12) v3(104.7,120.96) v3(104.7,118.55) v3(104.7,117.66) v3(104.83,115.12) v3(105.14,0.51) v3(106.95,122.25) v3(108.78,119.02) v3(108.9,116.01) v3(108.9,114.99) v3(108.9,112.7) v3(109.75,116.01) v3(109.8,119.02) v3(109.78,114.99) v3(109.78,112.7) v3(112.76,0.51) v3(113.23,119.02) v3(113.21,116.13) v3(113.19,115) v3(113.21,112.83) v3(114.12,119.02) v3(114.1,116.13) v3(114.12,115) v3(114.1,112.83) v3(114.55,121.29) v3(117.16,119.02) v3(117.15,116.13) v3(117.15,115) v3(117.15,112.83) v3(118.04,116.13) v3(118.04,115) v3(118.04,112.83) v3(118.05,119.02) v3(120.38,0.51) v3(121.85,111.43) v3(122.1,117.28) v3(122.1,114.99) v3(122.1,113.72) v3(122.23,121.26) v3(122.48,111.43) v3(122.74,117.28) v3(122.74,114.99) v3(122.74,113.72) v3(125.79,117.28) v3(125.79,114.99) v3(125.79,113.72) v3(125.79,111.43) v3(126.42,113.72) v3(126.42,111.43) v3(126.68,117.28) v3(126.68,114.99) v3(128.03,120.29) v3(128,0.51) v3(133.41,118.42) v3(133.73,114.36) v3(134.04,118.42) v3(134.36,114.36) v3(134.68,118.42) v3(135,114.36) v3(135.31,118.42) v3(135.63,114.36) v3(135.62,0.51) v3(136.07,118.42) v3(136.27,114.36) v3(137.89,120.29) v3(143.24,0.51) v3(143.71,122.28) v3(150.86,0.51) v3(153.35,120.32) v3(153.98,120.32) v3(154.62,120.32) v3(155.25,120.32) v3(155.89,120.32) v3(156.77,119.56) v3(157.41,119.56) v3(158.04,119.56) v3(158.48,0.51) v3(158.68,119.56) v3(160.13,122.28) v3(166.1,0.51) v3(168.46,122.25) v3(173.64,0.54) v3(175.93,51.11) v3(175.93,50.47) v3(175.93,49.84) v3(175.93,49.2) v3(176.36,122.28) v3(176.56,51.11) v3(176.56,50.47) v3(176.56,49.84) v3(176.56,49.2) v3(176.84,51.74) v3(177.2,51.11) v3(177.2,50.47) v3(177.2,49.84) v3(177.22,43.24) v3(177.22,42.6) v3(177.22,41.97) v3(178.1,43.17) v3(178.16,55.5) v3(178.29,3.61) v3(178.82,55.43) v3(180.52,43.24) v3(181.29,43.24) v3(181.29,42.6) v3(181.29,41.97) v3(182.61,0.51) v3(182.71,113.97) v3(184.59,11.21) v3(185.9,11.22) v3(187.41,0.74) v3(189.95,113.97) v3(190.89,0.54) v3(195.26,19.74) v3(195.26,19.11) v3(196.02,19.74) v3(196.02,19.11) v3(196.02,18.47) v3(197.03,19.87) v3(197.03,19.11) v3(197.03,18.47) v3(197.16,17.58) v3(198.51,122.15) v3(200.23,10.52) v3(200.6,41.13) v3(200.72,71.14) v3(200.84,9.2) v3(202.24,112.65) v3(202.17,98.66) v3(204.03,79.53) v3(204.15,121.29) v3(204.17,0.51) v3(204.53,76.94) v3(205.52,95.89) v3(205.55,93.47) v3(205.64,57.97) v3(205.59,39.78) v3(206.06,54.31) v3(206.21,72.51) v3(207.88,116.72) v3(208.72,93.46) v3(209.04,76.93) v3(209.21,98.03) v3(209.45,113.11) v3(211.26,54.54) v3(211.27,6.23) v3(211.27,5.6) v3(211.38,57.84) v3(211.38,39.55) v3(211.59,74.09) v3(211.75,98.01) v3(211.75,93.82) v3(211.83,0.57) v3(211.87,95.86) v3(211.9,6.23) v3(211.9,5.6) v3(213.67,76.76) v3(213.87,20.6) v3(213.87,15.9) v3(213.87,11.49) v3(213.87,8.23) v3(213.87,3.87) v4(12.66,115.93) v4(17.76,15.02) v4(26.04,101.96) v4(27.11,103.13) v4(30.51,35.21) v4(31.32,103.66) v4(33.94,36.86) v4(33.88,34.45) v4(34.83,52.18) v4(36.05,103.69) v4(42.68,40.44) v4(42.83,45.83) v4(49.08,112.4) v4(53.56,58.77) v4(60.15,48.95) v4(60.56,67.01) v4(68.87,110.6) v4(69.45,69.19) v4(70.36,108.94) v4(81.44,109.91) v4(104.27,118.14) v4(153.68,16.67) v4(153.78,63.45) v4(158.6,26.12) v4(162.54,36.71) v4(179.18,42.9) v4(186.77,53.37) v4(187.03,39.53) v4(200.06,9.77) v4(211.92,7.19)
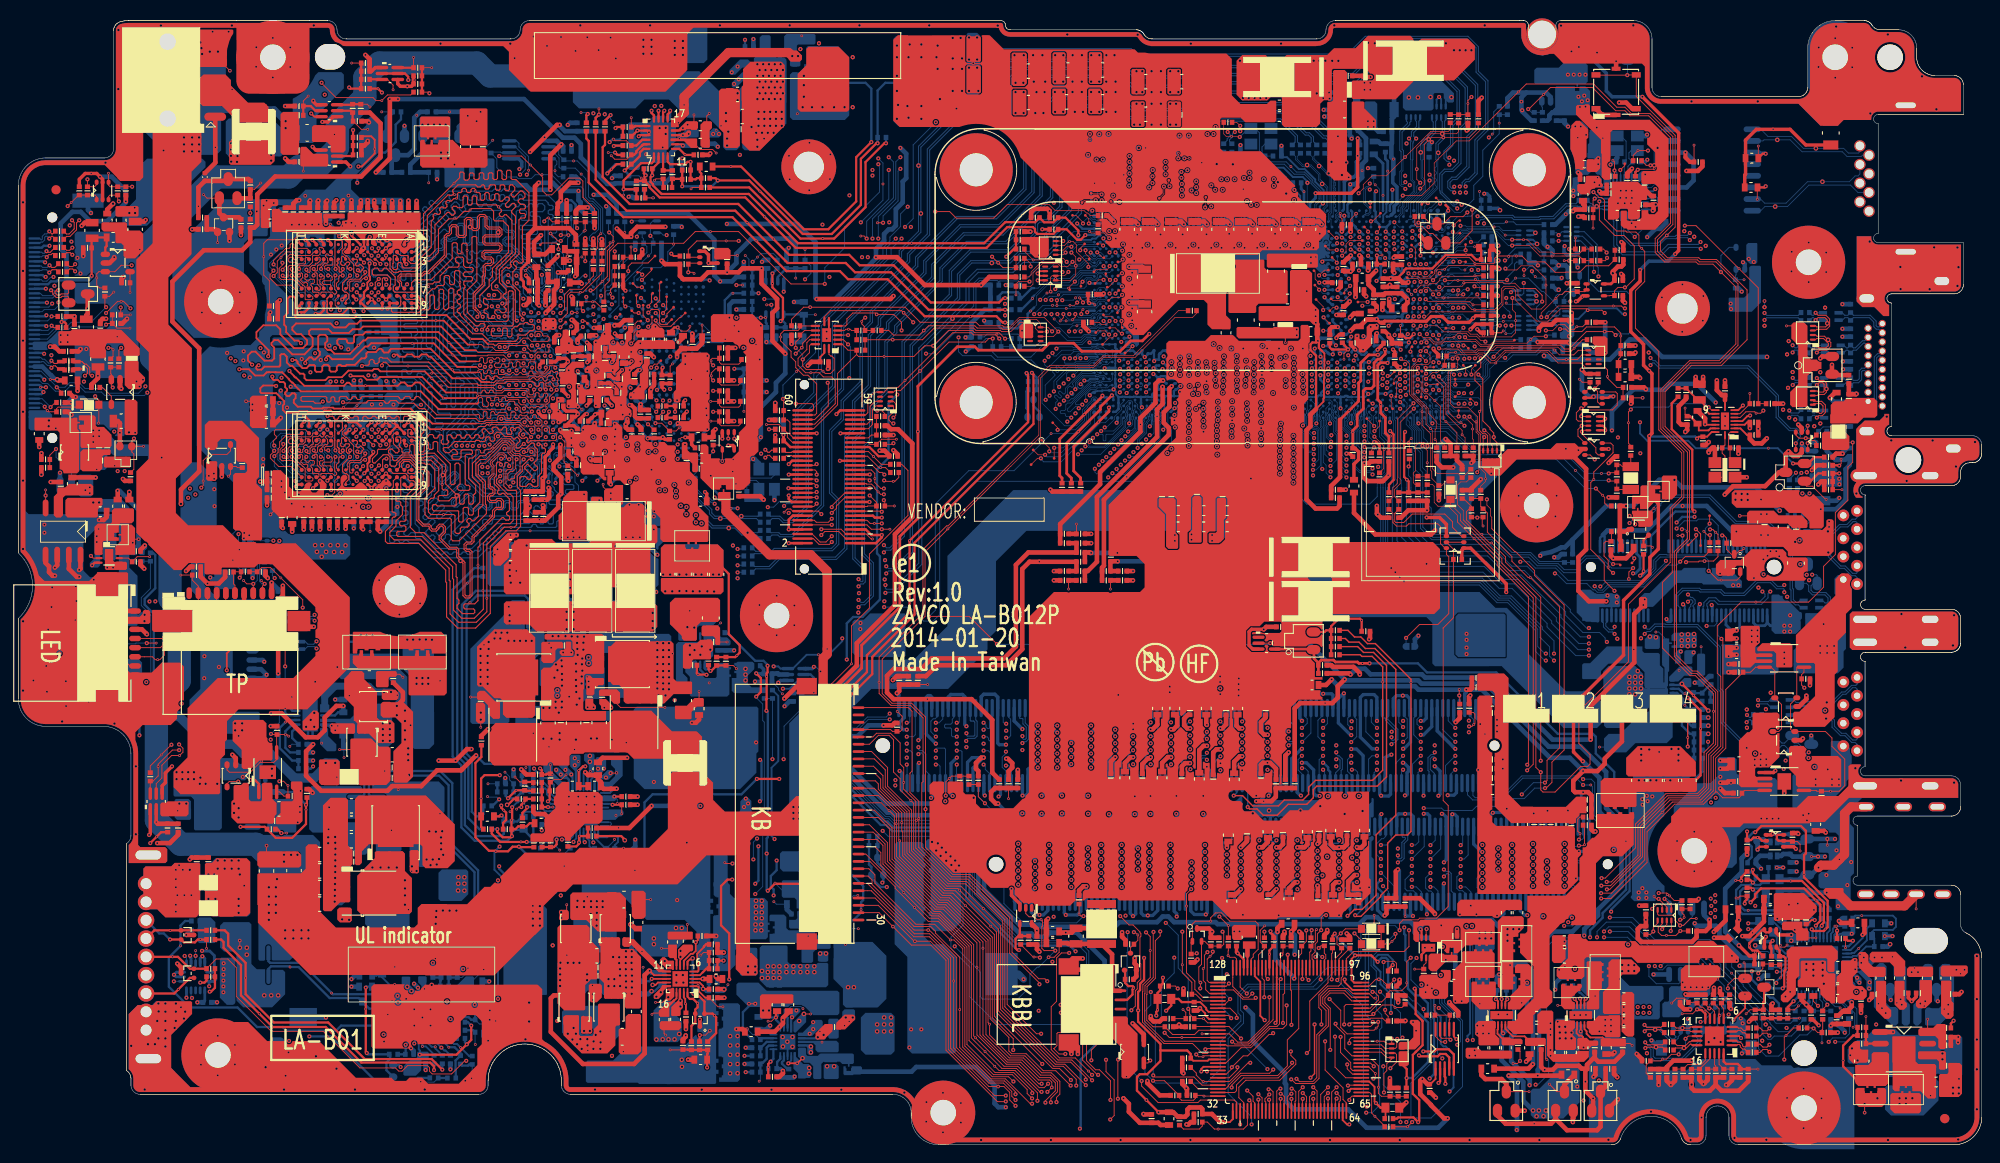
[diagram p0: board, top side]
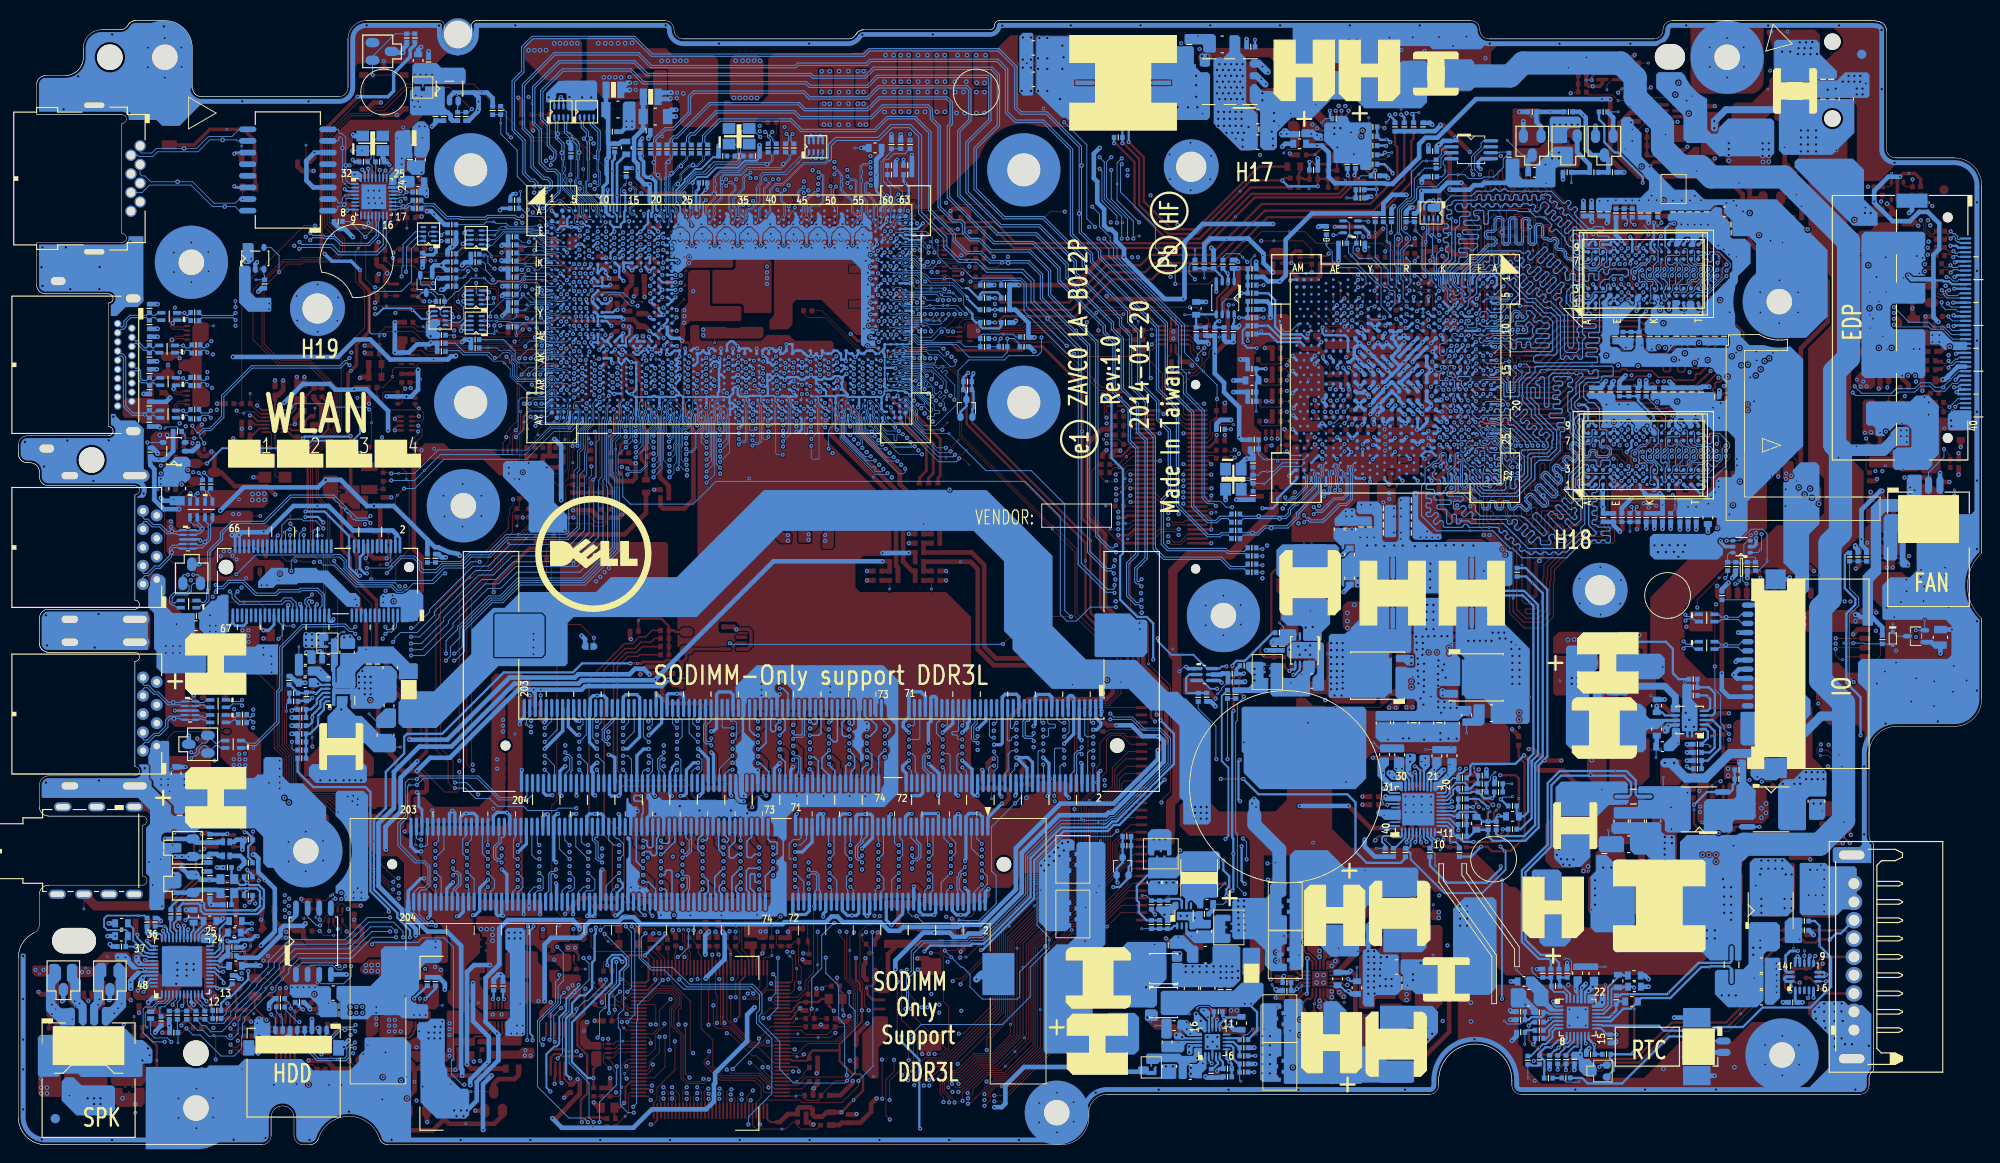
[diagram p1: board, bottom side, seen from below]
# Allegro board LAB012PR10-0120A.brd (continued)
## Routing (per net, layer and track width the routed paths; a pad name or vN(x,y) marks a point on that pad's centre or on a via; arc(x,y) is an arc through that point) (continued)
GNDA: length 23.7
  TOP w0.102: v2(204.65,22.79) v4(203.82,22.79) ; v2(192.72,30.28) v4(192.03,30.28)
  TOP w0.381: v3(193.6,22.92) 192.2,22.92 191.97,23.14 QA5.4 ; v2(190.83,22.71) 190.83,22.69 190.79,22.64 190.79,22.63 190.67,22.51 QA5.1 ; QA6.4 193.87,32.55 v2(194.11,32.31) ; v2(191.57,33.96) 191.45,33.84 190.89,33.84 QA6.1
  TOP w0.508: RA29.1 197.19,34.28 v2(197.36,34.1) ; RA30.1 187.83,24.63 v2(187.89,24.57) 187.75,24.43 RA32.1 ; v2(201.4,22.93) 201.59,23.12 RA31.1
  BOTTOM w0.203: UA1.38 200.01,21.29 200.01,21.28 200.02,21.29 200.1,21.29 201.4,22.58 v2(201.4,22.93)
  BOTTOM w0.381: CA38.2 191.62,33.91 v2(191.57,33.96)
  BOTTOM w0.508: RA84.2 v2(193.35,26.22) 193.48,26.34 CA33.2 ; CA23.1 v2(196.08,25.65) ; v4(192.03,30.28) v2(192.72,30.28) ; v2(192.08,24.69) 192.33,24.44 CA62.1 ; CA40.2 v2(194.19,30.84) ; CA39.2 v2(194.19,29.85) ; CA63.1 v2(204.53,24.19) ; CA61.2 v2(204.65,22.79)
  vias: v2(189.67,26.09) v3(193.6,22.28) v4(194.32,26.34)
VCCSENSE: length 57.7
  TOP w0.254: PR537.1 PC522.1 ; PC522.1 68.38,105.77 v2(68.51,105.9) 68.31,106.1 PC545.1 ; PC522.1 68.92,104.75 68.92,104.6 70.03,103.48 79.38,103.48 v1(81.5,101.36) 84.89,97.97 105.72,97.97 107.99,100.25 110.8,100.25 111.02,100.03 111.02,99.74 111.26,99.5 113.04,99.5 R1.2 114.48,100 115.63,98.86 116.01,98.86 v2(116.52,99.37)
  BOTTOM w0.254: PC541.2 68.38,106.18 68.51,106.05 v2(68.51,105.9) ; UC1.E63 116.54,99.39 v2(116.52,99.37)
VCCSENSE_VGA: length 75.9
  TOP w0.102: v1(54.41,36.66) 54.64,36.89 v2(54.92,36.89)
  TOP w0.254: v2(71.71,80.07) 71.74,80.09 RV161.1 RV159.2 ; v2(54.92,36.89) 54.92,37.14 55.38,37.6 PR1047.1 PR1049.2
  IN1 w0.203: v2(71.71,80.07) 72.14,79.63 73.64,79.63 74.53,78.74 74.53,75.92 77.02,73.44 77.02,70.16 79.43,67.75 79.43,61.52 78.03,60.13 78.03,55.17 77.21,54.35 77.21,53.59 76.43,52.81 76.43,35.96 76.01,35.54 58.72,35.54 58.52,35.74 58.48,35.74 58.1,36.12 55.56,36.12 54.92,36.76 v2(54.92,36.89)
VCCST_PG_EC: length 167.2
  TOP w0.102: UE1.123 134.62,20.27 134.85,20.5 134.85,20.81 135.39,21.34 135.39,24.11 135.08,24.41 132.3,24.41 131.39,25.33 130.74,25.33 130.21,24.79 v1(130.21,24.41) 128.53,24.41 128.21,24.09 DE1.2 128.07,22.08 CE35.1 128.61,20.83 v2(128.68,20.91)
  IN1 w0.107: v2(128.68,20.91) 127.59,20.91 126.71,20.03 124.87,20.03 123.81,21.09 120.63,21.09 119.89,21.82 114.67,21.82 114.67,21.85 112.02,24.51 112.02,25.96 110.6,27.39 110.6,33.52 108.24,35.88 99.26,35.88 96.3,38.84 95.94,38.84 95.93,38.84 95.59,38.84 95.59,38.84 95.55,38.84 95.05,39.34 95.05,41.15 93.29,42.9 93.29,44.06 94.04,44.8 94.04,65.71 94.8,66.48 94.8,69.4 93.91,70.29 93.91,73.72 93.27,74.35 93.27,79.05 94.29,80.07 94.29,91.11 91.88,93.53 91.88,96.19 91.12,96.96 91.12,98.1 92.84,99.83 107.32,99.83 111.74,104.25 119.01,104.25 v2(119.56,103.69)
  BOTTOM w0.076: 119.94,107.62 120.2,107.37 120.2,104.32 v2(119.56,103.69) 119.44,103.56 119.44,102.74 119.91,102.27 119.91,101.9 120.24,101.57 UC1.B59
  BOTTOM w0.102: R286.2 C79.1 119.06,108.51 119.94,107.62
VDD_1.35V: length 5.7
  TOP w0.102: v2(82.73,13.9) 82.66,13.9 82.25,13.49 v1(81.87,13.49)
  TOP w0.254: v2(82.73,13.9) 82.73,14.47 PC209.1
  BOTTOM w0.254: PU200.11 83.2,13.17 82.73,13.64 v2(82.73,13.9) ; v2(82.73,13.9) 80.89,13.9 PR206.2 ; v2(82.73,13.9) 82.91,14.08 PR205.1
VDDIO: length 5.1
  TOP w0.254: PR1022.2 PR1025.2 v1(61.28,33.71) 61.23,33.66 v2(61.23,33.04) 61.23,32.88 60.93,32.58 PC1019.1
  BOTTOM w0.203: PU1000.6 61.32,33.14 v2(61.23,33.04)
VDDR4: length 3
  BOTTOM w0.381: UV1.U12 64.43,87.1 v2(64.97,87.64) 64.97,87.52 65.39,87.1 UV1.V12 65.4,87.1 v2(65.94,87.64) 66.4,87.18 UV1.Y12
VIN: length 63.7
  IN2 w0.254: v3(21.72,39.43) 22.59,38.56 30.05,38.56 30.64,39.15 46.44,39.15 46.79,38.79 46.79,32.06 53.45,25.4 53.45,18.9 v2(49.84,15.3)
  BOTTOM w0.762: v3(29.19,111.05) v3(29.19,111.82) 27.94,113.07 PL6.2
  vias: v3(17.28,40.7) v3(17.28,39.93) v3(17.91,40.7) v3(17.91,39.93) v3(18.09,110.8) v3(18.09,110.04) v3(18.09,109.28) v3(18.09,108.51) v3(18.55,40.7) v3(18.55,39.93) v3(18.98,110.8) v3(18.98,110.04) v3(18.98,109.28) v3(18.98,108.51) v3(19.18,40.7) v3(19.18,39.93) v3(19.74,110.8) v3(19.74,110.04) v3(19.74,109.28) v3(19.74,108.51) v3(19.82,39.43) v3(19.88,40.1) v3(20.45,39.43) v4(15.65,75.06) v4(15.86,108.61) v4(32.42,50.58)
VSS_MECH: length 137.9
  IN1 w0.254: v2(52.63,72.45) 52.63,72.32 53.27,71.68 53.27,66.73 48.13,61.59 48.13,41.86 51.24,38.75 51.24,35.87 52.15,34.95 53.93,34.95 54.41,34.47 56.19,34.47 57.84,32.82 59.62,32.82 60.06,33.26 60.06,33.29 61.96,35.18 76.16,35.18 76.82,35.84 76.82,52.56 77.65,53.4 77.65,54.28 78.42,55.05 78.42,59.87 79.81,61.27 79.81,68.25 v2(78.54,69.52) 77.65,70.41 77.65,75.75 78.67,76.76 78.67,85.65 77.02,87.3 77.02,92.89 v2(75.49,94.42)
  BOTTOM w0.254: UV1.AM1 75.41,94.5 v2(75.49,94.42) ; v2(52.63,72.45) 52.76,72.45 53.2,72.89 UV1.A32 ; UV1.AM32 74.8,72.71 76.93,70.58 76.93,69.99 77.4,69.52 v1(77.83,69.52) v2(78.54,69.52)
VSSSENSE: length 59.2
  TOP w0.254: PU501.8 69.91,107.3 PC545.2 v2(69.22,105.9) 69.04,105.72 69.04,105.19 69.3,104.93 69.3,104.8 70.24,103.86 79.76,103.86 85.15,98.48 v1(97.54,98.48) 105.47,98.48 107.77,100.78 111.02,100.78 R2.1 112.02,100.77 113.04,100.77 RC163.1 114.36,101.27 115.75,99.88 v2(115.75,99.37)
  BOTTOM w0.203: v2(115.75,99.37) 115.75,99.02 115.93,98.84 117.13,98.84 117.28,98.99 117.67,98.99 118.03,99.35 UC1.E62
  BOTTOM w0.254: v2(69.22,105.9) PC545.2 PC546.2
VSSSENSE_VGA: length 77.3
  TOP w0.102: v1(58.1,41.51) PR1050.2
  TOP w0.254: PR1050.2 57.71,40.52 57.64,40.44 PR1051.1 57.16,40.92 v2(56.98,41.1) ; v2(71.05,80.07) 71.05,79.94 70.75,79.63 RV158.2 RV160.1
  IN1 w0.203: v2(71.05,80.07) 71.84,79.28 73.49,79.28 73.92,78.85 73.92,75.57 76.51,72.98 76.51,70.03 79.05,67.49 79.05,61.65 77.65,60.25 77.65,55.3 76.76,54.41 76.76,53.78 76.05,53.06 76.05,36.05 75.88,35.87 58.86,35.87 58.6,36.12 58.6,37.9 56.98,39.53 v2(56.98,41.1)
65W#/90W: length 190.1
  TOP w0.102: UE1.117 137.02,13.66 134.37,11 132.85,11 132.59,11.26 v2(132.54,11.26)
  TOP w0.254: v2(42.58,116.31) 42.58,116.67 42.22,117.02 PQ4.5 PQ4.2
  IN1 w0.107: v2(42.58,116.31) 51.45,116.31 60.75,107.01 62.46,107.01 64.69,104.78 66.66,104.78 67.9,103.54 80.59,103.54 84.51,99.62 84.77,99.62 89.34,95.05 89.34,91.37 91.75,88.96 91.75,84 90.47,82.72 90.47,66.82 90.2,66.55 90.2,56.01 91.23,54.98 91.23,50.97 88.96,48.7 88.96,41.08 89.95,40.09 89.95,39.13 94.07,35.01 94.57,35.01 95.04,34.55 95.04,34.25 101.73,27.56 102.99,27.56 103.75,26.79 103.88,26.79 103.88,26.79 104.07,26.79 104.07,26.79 104.26,26.79 107.21,23.85 107.21,15.82 110.49,12.53 111.86,12.53 112.59,11.8 113.07,11.8 113.4,11.47 115.36,11.47 116.26,12.37 118.04,12.37 118.65,11.77 130.12,11.77 130.63,11.26 v2(132.54,11.26)
  BOTTOM w0.102: v2(42.58,116.31) v1(43.24,116.31)
+A_VCC: length 5.2
  BOTTOM w0.102: v1(189.68,21.02) 189.76,21.1 191.05,21.1 RA10.2
  BOTTOM w0.203: UA1.20 192.37,20.09
  BOTTOM w0.508: 192.37,20.09 191.78,20.68 RA10.2 RA11.2
+BIF_VDDC: length 3.5
  TOP w0.102: 64.32,71.42 63.86,71.87 v1(63.86,72.14)
  TOP w0.381: CV168.1 61.32,79.23 61.91,79.81 v2(62.08,79.81)
  BOTTOM w0.381: UV1.R21 62.47,80.3 62.08,79.91 v2(62.08,79.81) ; v2(64.01,80.75) 64.04,80.73 64.05,80.73 64.4,80.38 UV1.U21
  vias: v2(64.7,71.18) v2(64.7,70.54) v2(65.33,70.16)
+CHGRTC: length 1.9
  TOP w0.102: v1(178.62,69.52) 178.02,68.92 DC1.3
+CODEC_AVDD2: length 13.9
  BOTTOM w0.203: RA9.2 200.59,25.02 v1(201.3,25.02) 204.7,25.02 205.03,24.69 205.03,23.8 204.69,23.46 202.66,23.46 202.43,23.23 CA61.1 202.67,22.55 RA8.2 201.78,21.65 200.76,20.62 200.37,20.62 200.23,20.49 UA1.40
+CPU_CORE: length 41.1
  TOP w0.305: R1.1 v2(111.82,100)
  IN1 w0.305: v2(122.18,99.42) 122.18,99.52 121.42,100.28 117.43,100.28 117.15,100 v2(111.82,100)
  BOTTOM w0.076: 143.01,97.39 143.03,97.37 UC1.J23 ; UC1.K23 143.13,96.24 UC1.L22 143.13,95.42 UC1.M23 ; UC1.AB57 v2(121.63,90.06)
  BOTTOM w0.081: UC1.H23 143.16,98 143.16,98.19 142.81,98.54 UC1.G23
  BOTTOM w0.254: v2(121.63,95.26) UC1.M57 ; 142.53,99.32 UC1.F24 141.7,99.32 ; UC1.U57 121.49,92.66 ; 137.52,99.32 UC1.F32 136.69,99.32 ; UC1.F59 120.11,98.72 v2(119.85,98.99) ; UC1.M23 143.01,95.42 142.61,95.82 UC1.K23 ; 122.33,98.17 UC1.G55 ; UC1.G53 124.29,98.17 ; 129.99,99.32 UC1.F44 129.16,99.32 ; 137.47,98.28 137.78,98.59 UC1.G31 ; 122.47,99.32 UC1.F56 121.64,99.32 ; 134.87,98.17 UC1.G35 ; UC1.G33 136.83,98.17 ; 139.19,99.32 UC1.F28 140.02,99.32 ; 131.67,99.32 UC1.F40 132.5,99.32 ; UC1.G25 141.84,98.17 ; 135.01,99.32 UC1.F36 134.18,99.32 ; UC1.P57 121.49,93.96 ; 126.66,99.32 UC1.F48 127.49,99.32 ; v2(121.85,96.56) UC1.K57 ; 129.86,98.17 UC1.G43 ; 142.39,98.17 UC1.G23 ; UC1.J23 142.61,97.46 ; UC1.G37 134.32,98.17 ; UC1.G49 126.8,98.17 ; 127.35,98.17 UC1.G47 ; 124.15,99.32 UC1.F52 124.98,99.32 ; UC1.G41 131.81,98.17 ; 139.89,98.17 UC1.G27 ; UC1.G45 129.3,98.17 ; UC1.W57 121.49,91.36 ; UC1.G29 139.33,98.17 ; UC1.AD57 121.49,88.76 ; UC1.G57 121.78,98.17 ; 124.84,98.17 UC1.G51 ; 132.36,98.17 UC1.G39
  vias: v2(121.63,93.96) v2(121.63,92.66) v2(121.63,91.36) v2(121.67,97.98) v2(122.07,89.15) v2(122.75,97.98) v2(123.87,97.98) v2(124.73,99.44) v2(125.25,97.98) v2(126.38,97.98) v2(127.14,99.44) v2(127.76,97.98) v2(128.89,97.98) v2(129.75,99.46) v2(130.27,97.98) v2(131.4,97.98) v2(132.22,99.51) v2(132.64,95.94) v2(132.78,97.98) v2(133.9,97.98) v2(134.73,99.51) v2(135.28,97.98) v2(136.41,97.98) v2(137.24,99.51) v2(137.79,97.98) v2(138.92,97.98) v2(139.74,99.51) v2(140.42,97.98) v2(141.43,97.98) v2(142.12,99.52) v3(95.94,120.07) v3(95.94,118.8) v3(95.94,116.77) v3(95.94,115.12) v3(95.94,112.07) v3(96.07,113.59) v3(97.08,113.47) v3(97.21,118.8) v3(97.21,112.2) v3(97.34,120.2) v3(98.61,120.2) v3(98.61,118.8) v3(98.61,113.47) v3(98.61,112.07) v3(100.26,118.8) v3(100.39,120.07) v3(100.39,117.53) v3(100.64,114.23) v3(102.04,120.91) v3(102.04,118.67) v3(102.04,117.53) v3(102.04,115.12) v3(102.9,120.91) v3(103.05,118.67) v3(103.05,117.53) v3(103.05,115.12) v3(110.81,119.02) v3(110.89,116.13) v3(111.05,112.7) v3(111.18,114.99) v3(111.83,119.02) v3(111.94,112.7) v3(112.13,116.13) v3(112.07,114.99) v3(115.13,119.02) v3(115.12,116.13) v3(115.12,115) v3(115.37,112.83) v3(116.15,119.02) v3(116.13,116.13) v3(116.13,115) v3(116.26,112.83) v3(118.81,119.02) v3(118.8,116.13) v3(118.8,115) v3(118.8,112.83) v3(119.7,119.02) v3(119.82,116.13) v3(119.82,115) v3(119.82,112.83) v3(123.75,117.28) v3(123.75,114.99) v3(123.75,113.72) v3(123.75,111.43) v3(124.77,117.28) v3(124.77,114.99) v3(124.77,113.72) v3(124.77,111.43) v4(102.44,113.19)
+DIMM1_VREF_DQ: length 5.9
  TOP w0.102: v1(99.29,50.27) RD1.2
  TOP w0.508: RD1.2 CD1.1 CD2.1 96.2,49.56 95.97,49.33 v2(95.94,49.33)
  BOTTOM w0.381: v2(95.94,49.33) 96.15,49.12 JDIMM1.1
+DIMM2_VREF_DQ: length 9.2
  TOP w0.102: v1(108.13,37.8) CD33.1
  TOP w0.508: CD32.1 CD33.1 RD8.2 106.66,38.97 106.23,38.54 106.23,37.77 106.74,37.27 v2(106.99,37.27)
  BOTTOM w0.356: v2(106.99,37.27) 108.52,35.73 JDIMM2.1
+DP_VDDC: length 25
  TOP w0.102: v1(71.43,85.3) 71.18,85.04 CV33.1
  TOP w0.305: CV33.1 CV34.1 70.29,84.82 v2(70.36,84.89)
  TOP w0.381: RV30.2 75.18,71.11 v2(74.99,71.3)
  IN1 w0.381: v2(70.36,84.89) 70.36,84.71 68.57,82.92 68.57,82.59 67.33,81.35 67.33,80.48 68.22,79.6 68.22,78.49 68.61,78.1 70.35,78.1 71.43,77.02 71.43,73.08 72.7,71.81 74.48,71.81 v2(74.99,71.3)
  BOTTOM w0.254: v2(70.36,84.89) 70.36,85.14 70,85.5 UV1.AD14
+DP_VDDR: length 6.3
  TOP w0.102: v1(74.67,89.54) RV27.2
  TOP w0.508: RV27.2 74.67,87.56 74.09,86.97 CV26.1 CV27.1 72.45,86.97 71.94,86.46 v2(71.94,86.05)
  BOTTOM w0.254: v2(71.94,86.05) 71.94,85.84 UV1.AF14
+EC_VCCA: length 101.8
  TOP w0.203: UE1.67 145.51,6.11 145.28,5.87 v2(145.27,5.87)
  TOP w0.254: v2(125,18.24) 125,18.21 124.97,18.19 124.97,17.6 CE7.1 124.69,16.87 124.4,16.58 LE1.2 v1(124.4,14.74) 124.4,14.65 124.27,14.52 124.27,14.11 v2(124.27,14.11)
  IN2 w0.203: v2(82.58,33.39) 83.63,33.39 83.96,33.06 86.15,33.06 87.14,34.05 92.82,34.05 99.73,27.14 101.86,27.14 110.66,18.34 117.15,18.34 117.27,18.22 118.15,18.22 118.19,18.26 119.89,18.26 119.97,18.34 122.77,18.34 122.89,18.46 124.41,18.46 124.63,18.24 v2(125,18.24)
  IN2 w0.254: v2(145.27,5.87) 145.29,5.9 145.6,5.9 145.98,6.28 145.98,11.14 145.56,11.56 145.04,11.56 144.65,11.17 143.48,11.17 142.86,11.79 140.98,11.79 140.8,11.97 137.46,11.97 137.22,11.73 136.59,11.73 135.38,12.94 134.66,12.94 134.47,13.13 127.67,13.13 126.95,13.86 124.52,13.86 124.27,14.1 124.27,14.11 v2(124.27,14.11)
  BOTTOM w0.203: v2(82.58,33.39) 82.25,33.72 82.25,41.18 82.99,41.91 82.99,49.03 PR24.2
+FAN_POWER:
  vias: v2(7.8,71.81) v2(7.8,71.18) v4(7.32,71.51)
+FBA_VREF0: length 27.4
  IN1 w0.508: v2(35.14,71.13) 35.14,71.17 34.92,71.4 34.92,72.66 33.77,73.8 29.01,73.8 28.66,74.15 27.95,74.15 27.36,74.74 27.36,76.71 28.25,77.61 30.07,77.61 30.61,77.07 33.05,77.07 33.74,77.76 v2(33.74,78.13)
  BOTTOM w0.254: 36.8,71.19 37.27,71.66 37.27,72.04 UV5.H1 ; v2(33.74,78.13) 34.15,77.72 UV5.M8
  BOTTOM w0.508: 36.8,71.19 36.8,71.12 36.54,70.87 35.41,70.87 v2(35.14,71.13) 34.85,70.84 v1(34.85,69.89) 34.85,68.97 CV100.1 RV44.1 RV42.2
+FBA_VREF1: length 32.7
  TOP w0.254: UV6.M8 34.13,72.92 v2(33.75,72.54) ; UV6.H1 37.32,78.52 36.9,78.94 36.06,78.94 v2(35.82,79.18)
  IN1 w0.254: v2(35.82,79.18) 35.42,79.58 34.71,79.58 34.19,80.09 33.41,80.09 33.34,80.03 33.27,80.03
  IN1 w0.381: 31.89,78.58 31.89,78.65 33.27,80.03
  IN1 w0.508: 31.89,78.58 31.52,78.22 27.93,78.22 26.72,77.01 26.72,76.38 26.09,75.75 26.09,73.72 26.62,73.19 30.79,73.19 31.3,72.68 31.3,71.17 31.6,70.86 32.54,70.86 33.75,72.07 v2(33.75,72.54)
  BOTTOM w0.254: RV45.1 CV101.1 RV43.2 37.52,81.28 v1(36.98,80.74) 35.82,79.58 v2(35.82,79.18)
+FBA_VREF2: length 37.6
  TOP w0.152: 33.79,92.51 33.71,92.43 33.71,92.14 33.75,92.1 33.75,91.77 33.71,91.73 33.71,90.94 33.92,90.73
  TOP w0.165: UV7.M8 34.01,92.73 33.79,92.51
  TOP w0.203: v2(36.66,91.04) 36.27,91.42 36.08,91.42 35.39,90.73 33.92,90.73
  TOP w0.254: UV7.H1 36.4,99.28 v2(36.4,99.45)
  IN1 w0.508: v2(36.4,99.45) 34.96,98 30.21,98 29.37,98.84 28.33,98.84 26.88,97.39 26.88,94.67 27.64,93.91 32.75,93.91 34.91,91.75 35.74,91.75 36.46,91.04 v2(36.66,91.04)
  BOTTOM w0.102: v1(36.81,100.36) 36.4,99.95 v2(36.4,99.45)
  BOTTOM w0.254: CV133.1 RV52.1 RV50.2 37.39,90.3 v2(36.66,91.04)
+FBA_VREF3: length 34.6
  TOP w0.508: v2(33.58,100.61) CV134.1 RV51.2 RV53.1
  IN1 w0.508: v2(37.7,91.06) 37.6,91.06 36.96,90.43 36.2,90.43 36.12,90.5 33.86,90.5 33.38,90.99 33.38,91.83 32.19,93.02 27.18,93.02 25.33,94.87 25.33,97.07 28.12,99.85 33.05,99.85 33.58,100.39 v2(33.58,100.61)
  BOTTOM w0.152: 34.58,98.86 34.58,98.18 34.15,97.75 UV8.M8
  BOTTOM w0.254: v2(33.58,100.61) 34.03,100.61 v1(34.09,100.55) 34.58,100.07 34.58,98.86 ; UV8.H1 37.35,91.34 37.62,91.06 v2(37.7,91.06)
+INV_PWR_SRC:
  vias: v3(3.34,79.12) v3(3.32,78.49) v4(4.1,78.26)
+LAN_REGOUT:
  vias: v1(173.03,109.96) v2(172.52,107.75) v2(172.52,107.12)
+LAN_VDD10: length 8.5
  TOP w0.508: v2(176.21,106.63) 175.7,106.13 CL7.1 ; CL8.1 CL9.1 172.87,103.94 v2(172.65,104.16) ; CL6.1 178.52,102.67 CL5.1 178.57,102.11 v2(178.49,102.04)
  BOTTOM w0.203: UL1.8 178.37,102.16 v2(178.49,102.04) ; UL1.3 178.52,104.16 v2(178.76,104.4) ; v2(172.65,104.16) UL1.22 ; UL1.30 176.17,106.6 v2(176.21,106.63)
  vias: v1(170.29,110.01) v2(170.02,111.24) v2(170.62,111.23) v2(171.2,110.32)
+LAN_VDD33: length 29.2
  TOP w0.203: UG1.8 186.37,81.34
  TOP w0.508: 186.37,81.34 CG3.1 186.01,81.89 185.48,82.43 v2(185.48,83.49) ; CL12.1 177.6,105.95 v2(177.65,106)
  IN1 w0.508: v2(187.03,91.29) 187.1,91.22 187.1,85.12 v2(185.48,83.49)
  IN1 w1.016: 187.14,92.47 187.14,92.8 179.46,100.49 177.13,100.49
  BOTTOM w0.203: UL1.11 v2(176.17,100.68)
  BOTTOM w0.508: CL19.1 167.52,112.78 167.19,112.45 167.19,112.07 166.99,111.87 RL38.2
  vias: v2(169.81,104.22) v2(169.81,103.64) v2(170.36,114.48) v2(170.53,113.36) v2(170.74,113.97) v2(171,114.61) v2(171.14,113.4) v2(171.38,114.1) v2(176.6,100.26) v2(186.99,91.89) v4(172.37,111.12)
+LAN_VDDREG:
  vias: v1(172.45,105.64) v2(172.12,105.13) v2(172.65,104.83)
+LCDVDD: length 11
  IN2 w1.524: 12.91,81.47 20.71,73.68 20.71,73.66
  vias: v2(12.57,82.85) v2(12.91,83.38) v2(13.23,82.82) v2(20.81,73.07) v2(21.35,73.32) v2(21.38,72.74) v4(13.62,83.57)
+LCDVDD_CONN:
  vias: v1(10.8,88.27) v2(4.63,88.45) v2(4.63,87.69) v2(5.39,88.45) v2(5.39,87.69)
+MIC2-VREFO: length 24.9
  TOP w0.254: v2(195.84,23.53) 196.02,23.35 197.17,23.35 197.58,23.76 197.58,26.64 195,29.21 v1(195,29.52) 195,31.63 195.2,31.83 195.2,34.29 194.67,34.82 190.34,34.82 v2(189.67,34.14)
  BOTTOM w0.254: v2(195.84,23.53) 195.92,23.44 195.92,22.54 UA1.29 ; v2(189.67,34.14) 189.46,34.14 188.83,33.51 RA53.2 188.83,33.02 189.29,32.57 189.29,31.42 188.83,30.97 RA1109.2
+MPLL_PVDD: length 10.1
  TOP w0.102: v2(60.45,90.9) v1(61.03,90.9)
  TOP w0.508: CV81.1 59.93,97.6 LV6.2 60.97,97.53 CV83.1 CV82.1 60.97,95.03 v2(60.81,94.87)
  IN2 w0.508: v2(60.45,90.9) 60.45,91.62 61,92.17 61,93.05 60.51,93.55 60.51,94.64 60.74,94.87 v2(60.81,94.87)
  BOTTOM w0.254: UV1.L8 60.05,90.5 v2(60.45,90.9)
+MVREFDA: length 12.3
  TOP w0.508: v2(59.2,76.46) 59.19,76.45 59.19,75.08 58.45,74.34 58.45,73.74 59.29,72.9 59.29,71.15 v1(59.24,71.1) 58.96,70.82 58.96,69.63 57.51,68.18 RV34.1 CV94.1 RV33.2
  BOTTOM w0.254: UV1.K26 59.16,76.46 v2(59.2,76.46)
+MVREFSA: length 8
  TOP w0.381: v2(58.4,76.5) 58.4,76.14 57.92,75.65 57.92,75.52 57.52,75.13 57.52,73.02
  TOP w0.508: 57.52,73.02 57.29,72.79 v1(57.27,72.79) 57.27,71.44 CV95.1 RV35.1 RV32.2
  BOTTOM w0.254: UV1.J26 v2(58.4,76.5)
+PCH_VCCDSW: length 5.9
  TOP w0.102: v2(145.2,86.87) 144.76,86.43 v1(144.76,85.81)
  TOP w0.254: C5215.1 144.78,87.42 144.78,87.37 145.2,86.94 v2(145.2,86.87) 143.44,86.87 143.21,87.1 C64.1
  BOTTOM w0.254: UC1.AG20 144.83,87.25 v2(145.2,86.87) 145.58,87.25 UC1.AG19
+RTCBATT: length 251.6
  TOP w0.254: RC10.2 v4(177.48,62.66) 177.48,62.54 v2(177.09,62.16) ; RG1.1 181.25,81.69 180.55,80.99 180.55,78.17 182.8,75.92 182.8,69.41 v2(183.04,69.17)
  IN1 w0.254: v2(177.09,62.16) 175.7,60.76 175.7,53.59 174.23,52.13 174.23,37.45 170.98,34.2 170.98,29.02 169.12,27.16 167.65,27.16 166.03,25.54 166.03,20.57 164.37,18.92 164.37,18.8 162.14,16.57 160.84,16.57 158.22,13.94 153.6,13.94 152.7,14.83 150.46,14.83 149.88,15.4 144.61,15.4 143.35,14.13 134.74,14.13 133.97,13.36 132.15,13.36 130.7,14.82 130.65,14.82 130.03,15.43 122.82,15.43 122.69,15.56 116.31,15.56 v2(115.75,15.01) ; v2(82.48,27.23) 81.46,27.23 80.7,28 77.78,28 75.24,30.54 57.46,30.54 54.29,27.36 54.29,14.66 52.25,12.63 51.48,12.63 48.16,9.31 48.16,8.3 47.33,7.46 33.43,7.46 v2(29.56,11.33)
  IN2 w0.254: v2(115.75,15.01) 115.75,14.66 114.74,13.64 109.02,13.64 106.99,15.68 106.99,18.59 100.9,24.68 96.78,24.68 90.64,30.81 83.04,30.81 v2(82.81,31.04)
  BOTTOM w0.254: v2(183.04,69.17) 180.96,69.17 178.29,66.5 178.29,63.12 177.32,62.16 v2(177.09,62.16) ; JRTC.1 v2(29.56,11.33) ; v2(82.48,27.23) 82.48,27.89 82.18,28.2 82.18,29.35 82.81,29.99 v2(82.81,31.04)
+RTCVCC: length 166.6
  TOP w0.254: 151.63,72.66 151.82,72.47 C56.1 ; 151.63,72.66 v4(151.63,72.65) ; 151.63,72.66 151.34,72.95 151.34,77.78 v2(151.43,77.87) ; v2(149.8,77.97) 150.18,77.6 150.18,72.61 149.68,72.11 RC6.1 ; C56.1 C54.1 C55.1 ; C56.1 RC5.1
  TOP w0.508: RC1.1 174.89,66.11 175,65.99 CC26.1 ; RC1.1 175.6,66.98 175.86,67.24 DC1.1 ; RC1.1 RC7.1 v3(175.57,69.78) ; v3(182.04,77.88) 182.04,77.87 182.24,78.06 RG2.1 181.59,78.67 181.31,78.95 181.31,80.67 182.12,81.49 RG4.1 ; v2(194.37,33.96) 194.29,34.04 RA5.1
  IN1 w0.254: 154.89,85.92 154.75,86.06 153.32,86.06 153.19,86.19 151.61,86.19 v2(150.96,86.85) 150.3,86.19 150.3,82.55 150.44,82.42 150.44,81.47 150.2,81.23 150.2,79.72 151.43,78.49 v2(151.43,77.87) 149.9,77.87 v2(149.8,77.97)
  IN1 w0.305: 155.49,85.92 154.89,85.92
  IN1 w0.508: v3(189.67,21.77) 189.67,22.44 190.43,23.2 190.43,24.71 191.57,25.85 191.57,31.17 v2(194.37,33.96) ; v3(192.33,69.27) 192.61,69 192.61,64.84 193.05,64.4 193.05,61.92 194.09,60.88 194.09,55.81 193.48,55.2 193.48,52.24 192,50.76 192,41.67 192.62,41.05 v2(192.78,41.05) ; v3(180.85,72.63) 180.85,72.63 180.85,76.69 v3(182.04,77.88) ; 155.49,85.92 156.14,85.27 159.44,85.27 160.74,83.97 160.74,80.55 163.42,77.86 163.42,71.74 163.08,71.39 163.08,68.33 166.2,65.22 v2(166.2,64.34)
  IN2 w0.508: v2(194.37,33.96) 192.84,35.49 192.84,37.39 192.14,38.08 192.14,39.91 192.78,40.54 v2(192.78,41.05)
  BOTTOM w0.254: v2(150.96,86.85) 150.55,87.25 UC1.AG10
  BOTTOM w0.508: v2(166.2,64.34) 166.2,64.35 166.39,64.54 167.4,64.75 168.36,65.16 168.5,65.26 168.89,65.26 169.73,66.1 ; RA11.1 189.87,21.57 v3(189.67,21.77) ; v3(192.33,69.27) 189.79,71.81 181.67,71.81 v3(180.85,72.63) 179.18,72.63 176.33,69.78 v3(175.57,69.78) 173.41,69.78 169.73,66.1 ; 169.73,66.1 R2337.2
+SM_VREF_CA: length 25.4
  TOP w0.508: v2(125.94,82.86) 125.7,82.62 125.7,80.62 125.09,80.01 125.09,78.86 125.64,78.31 125.64,77.56 v1(121.04,72.96) 118.55,70.47 118.55,63.25 118.34,63.05 RC17.2 CC8.1
  BOTTOM w0.254: v2(125.94,82.86) 125.94,82.86 126.25,83.17 UC1.AP49
+SM_VREF_CA_DIMM: length 123.9
  TOP w0.508: v2(154.69,25.2) 154.69,25.25 153.02,26.93 RD10.2 ; v2(144.84,50.83) 144.07,50.07 144.07,48.82 143.49,48.24 v1(142.7,48.24) 139.96,48.24 139.38,47.65 RD4.2 ; v2(120.05,63.73) RC14.2 119.26,63.68 RC17.1 RC20.1
  IN2 w0.508: v2(171,22.85) 170.39,23.46 170.39,24.97 169.35,26.01 155.5,26.01 v2(154.69,25.2)
  BOTTOM w0.508: v2(171,22.85) 171,23.55 172.5,25.05 172.5,25.68 175.06,28.25 175.06,35.11 173.39,36.78 173.39,40.72 170.62,43.49 167.11,43.49 160.23,50.37 153.22,50.37 152.86,50.73 144.94,50.73 v2(144.84,50.83) 131.93,63.73 v2(120.05,63.73)
+SM_VREF_DQ0: length 25.4
  TOP w0.508: CC10.1 RC19.2 116.77,62.67 117.79,63.68 117.79,70.76 124.36,77.33 v1(124.36,79.56) 124.36,80.33 124.95,80.92 124.95,82.78 v2(124.95,82.79)
  BOTTOM w0.254: v2(124.95,82.79) 124.95,82.78 124.96,82.78 124.96,82.77 124.98,82.77 124.98,82.76 124.99,82.76 124.99,82.75 125,82.75 125.01,82.74 125.01,82.72 125.2,82.52 125.38,82.52 UC1.AR51
+SM_VREF_DQ0_DIMM1: length 29.5
  TOP w0.508: RD1.1 99.12,51.19 100.31,52.38 107.88,52.38 109.63,54.13 109.63,62.89 110.42,63.68 v1(111.5,63.68) RC16.2 RC19.1 RC22.1
+SM_VREF_DQ1: length 23.2
  TOP w0.508: RC18.2 CC9.1 113.77,67.8 118.13,72.16 118.13,73.49 122.53,77.89 v1(122.53,78.69) 122.53,79.39 124.18,81.04 124.18,83.11 124.56,83.49 v2(125,83.49)
  BOTTOM w0.254: UC1.AP51 125.32,83.17 v2(125,83.49)
+SM_VREF_DQ1_DIMM2: length 54.8
  TOP w0.508: RD8.1 106.36,40.64 106.36,46.41 104.1,48.67 v1(99.27,48.67) 95.59,48.67 94.86,49.39 94.86,51.22 95.6,51.96 98.59,51.96 99.75,53.12 107.63,53.12 108.93,54.42 108.93,63.34 110.29,64.7 RC15.2 RC21.1 RC18.1
+SPLL_PVDD: length 6.2
  TOP w0.102: v1(55.38,95.48) 55.77,95.88 CV84.1
  TOP w0.508: v2(56.86,91.69) 56.7,91.85 CV86.1 56.7,93.25 LV7.2 56.72,94.14 CV85.1 56.7,94.54 56.57,94.67 CV84.1
  BOTTOM w0.254: v2(56.86,91.69) 57.2,91.35 UV1.H7
+SPLL_VDDC: length 6.3
  TOP w0.508: LV8.2 57.87,95.08 57.87,94.26 ; 57.87,94.26 CV93.1 ; 57.87,94.26 58.74,94.26 CV91.1 58.82,93.68 58.5,93.36 CV92.1 58.5,91.81 v1(58.12,91.43) 57.6,90.9 v2(57.6,90.85)
  BOTTOM w0.254: UV1.H8 57.25,90.5 v2(57.6,90.85)
+TSVDD: length 16.8
  IN1 w0.254: v2(78.19,84.76) 77.3,85.65 75.32,85.65 73.87,84.21 71.5,84.21 v2(69.74,82.45)
  BOTTOM w0.102: CV20.1 v1(79.23,80.12)
  BOTTOM w0.305: v2(69.74,82.45) 70,82.71 UV1.AD17 ; v2(78.19,84.76) LV2.2 79.23,84.13 78.99,83.89 CV19.1 79.23,83.25 CV21.1 CV20.1
+V_TP: length 0.9
  TOP w0.254: UE4.4 8.34,63.58 v2(8.06,63.3)
  vias: v1(8.77,67.26) v2(8.57,66.48) v2(8.57,65.84)
+V_TS:
  vias: v1(13.26,97.79)
+VCHGR: length 30.2
  TOP w0.102: v3(24.19,21.52) v4(24.19,22.31)
  IN2 w0.254: v2(31.78,11.83) 31.78,12.91 29.67,15.02 29.67,19.07 27.22,21.52 v3(24.95,21.52)
  BOTTOM w0.254: v2(31.78,11.83) 34.13,11.83 39.27,6.68 43.02,6.68 43.63,7.29 PR701.1
  vias: v3(24.95,20.76) v3(26.85,16.31) v3(27.62,16.31) v3(28.38,16.31)
+VDISPLAY_VCC:
  vias: v4(200.58,79.73)
+VGA_CORE: length 77.2
  TOP w0.254: v3(53.37,37.13) 53.46,37.13 54.11,37.77 PR1047.2
  TOP w0.381: v2(72.83,81.34) 72.65,81.16 RV161.2
  TOP w0.508: PC841.1 61.07,87.97 v2(61.07,87.63)
  IN1 w0.203: v3(55.51,65.46) 55.44,65.4 53.97,65.4 48.48,59.91 48.48,42.45 52.98,37.95 52.98,37.52 v3(53.37,37.13)
  BOTTOM w0.381: UV1.AB13 67.93,85.63 v2(67.93,85.55) 67.47,85.1 UV1.AA15 67.23,85.1 v2(66.76,84.63) 66.4,84.27 UV1.Y16 ; UV1.AB13 69,85.5 UV1.AC14 ; UV1.AB13 68.51,86.21 68.51,86.99 UV1.AB12 68.36,87.1 v2(67.93,87.54) ; v2(66.25,89.26) 66.22,89.29 66.21,89.29 UV1.W9 ; v2(66.25,89.26) 66.69,89.7 UV1.Y9 ; v2(66.25,89.26) 65.89,88.9 UV1.W10 ; 63.57,83.3 63.45,83.3 62.65,84.1 UV1.R16 v2(62.13,84.57) UV1.N15 ; 63.57,83.3 UV1.T17 ; 63.57,83.3 63.02,82.75 v2(63.02,82.73) 63.01,82.73 62.6,82.33 UV1.R18 ; UV1.U16 64.4,84.12 v2(64.91,84.63) 65.38,85.1 UV1.V15 UV1.Y13 66.42,86.1 v2(66.93,86.61) 66.93,86.63 UV1.AA12 67.49,87.1 v2(67.93,87.54) ; UV1.U16 65.2,83.3 UV1.V17 ; UV1.U16 63.6,84.9 UV1.T15 ; v2(65.82,80.8) 65.9,80.8 UV1.Y21 66.4,80.17 66.74,79.83 v2(66.74,79.82) ; v2(65.82,80.8) 65.82,80.85 65.4,81.27 UV1.V20 UV1.U18 63.6,81.5 UV1.T20 63.07,80.77 v2(63.07,80.75) ; v2(65.82,80.8) 65.4,80.38 UV1.V21 65.46,80.3 v2(66,79.76) ; UV1.T15 64.4,85.9 UV1.U13 63.6,86.9 UV1.T12 ; UV1.T15 63.48,85.1 v2(63.1,85.49) 62.6,85.98 UV1.R13 UV1.N12 v2(61.07,87.63) UV1.M11 ; UV1.T10 63.69,88.9 v2(64.01,88.57) ; v2(67.93,87.54) 68.4,88.01 UV1.AB11 ; UV1.T12 63.6,87.11 v2(63.06,87.65) ; UV1.T12 64.01,87.51 64.01,87.71 UV1.U11 64.4,88.19 v2(64.01,88.57) ; UV1.U10 64.34,88.9 v2(64.01,88.57) ; v2(61.23,82.84) 61.6,83.21 UV1.N17 ; UV1.Y18 v2(65.9,82.8)
  vias: v2(63.43,70.41) v2(63.43,69.52) v2(63.43,68.64) v2(63.43,66.86) v2(63.43,66.17) v2(66.35,66.35) v2(66.73,69.91) v2(67.11,66.35) v2(67.75,69.91) v2(67.87,66.35) v2(68.76,67.21) v2(69.4,67.21) v3(53.68,63.53) v3(53.65,62.79) v3(53.68,62.13) v3(53.78,61.4) v3(54.79,61.4) v3(56.57,61.4) v3(56.57,60.63) v3(56.67,65.49) v3(57.64,65.51) v3(57.71,61.4) v3(57.71,60.63) v3(58.55,65.49) v3(58.86,61.4) v3(58.86,60.63) v3(59.54,65.43) v3(60.2,63.48) v3(60.23,62.64) v3(60.23,61.75) v3(60.23,60.84) v3(60.59,65.41) v3(61.27,62.03) v3(61.27,61.27) v3(61.91,65.38) v3(62.29,62.03) v3(62.29,61.27) v3(63.05,61.27) v3(63.23,65.46) v3(63.81,61.27) v3(64.14,65.46) v3(65.23,65.38) v3(65.46,61.14) v3(66.17,65.49) v3(66.35,61.9) v3(66.35,61.14) v3(67.11,65.46) v3(67.24,61.9) v3(67.24,61.14) v3(68.13,61.9) v3(68.13,61.14) v4(54.37,62.68)
+VGA_PCIE: length 49.6
  TOP w0.508: v2(58.86,97.08) 58.86,97.03 LV8.1
  IN2 w0.203: 59.72,86.11 60.18,86.11 60.64,85.65 60.64,82.73 61.14,82.22 ; 59.21,86.97 59.34,87.1 60.64,87.1 61.19,86.54 61.19,85.12 61.58,84.74 61.58,83.54 61.75,83.37
  IN2 w0.254: 64.7,78.92 64.7,79.94 65.27,80.51 65.27,81.02 64.45,81.84 61.98,81.84 61.6,82.22 61.14,82.22 ; 59.26,86.44 59.39,86.44 59.72,86.11 ; 61.75,83.37 63.68,83.37 65.33,81.72 65.72,81.72 66.31,81.12 66.31,80.59 66.05,80.32 65.84,80.32 65.33,79.81 65.33,78.94 v2(65.14,78.75)
  IN2 w0.508: 59.26,86.44 59.21,86.49 59.21,87.69 59.8,88.27 59.8,92.79 59.87,92.86 59.87,93.51 58.35,95.03 58.35,96.57 v2(58.86,97.08)
  BOTTOM w0.254: UV1.L26 60.08,76.1 v2(60.4,76.42)
  BOTTOM w0.305: UV1.L24 59.6,77.7 v2(59.2,78.1) 59.6,78.5 UV1.L23 ; UV1.L25 60.09,76.9 v2(60.39,77.2) ; UV1.N23 61.4,78.1 v2(61.68,78.1) 61.6,78.18 UV1.N22 ; UV1.N24 60.7,77.7 v2(60.41,77.99)
  BOTTOM w0.381: UV1.M22 60.6,78.9 UV1.N23 ; UV1.T22 63.37,79.07 63.22,79.07 v2(62.93,78.77) 62.89,78.77 62.6,79.07 UV1.R22 ; UV1.U22 64.59,79.3 v2(65.14,78.75) 65.4,79 UV1.V22
  vias: v2(65.14,77.35) v2(65.14,76.53) v2(65.14,75.83) v2(65.21,78.16) v4(69.14,73.74)
+VGA_PCIEP: length 13.5
  TOP w0.254: PC1303.1 76.8,63.14 77.58,62.36 77.58,55.78 78.77,54.59 78.77,53.75 v1(78.47,53.45) 78.29,53.27 PC1306.1 PR1302.1
  vias: v3(70.41,62.29) v3(71.18,62.29) v3(72.19,62.29) v3(72.95,62.29) v3(73.97,62.29) v3(74.61,62.29) v3(75.88,62.29) v3(76.51,62.29)
AC_PRESENT: length 18.2
  TOP w0.076: v2(150.99,85.86) 151.19,85.65 151.57,85.65 151.92,85.3 151.92,81.97 153.3,80.6 v1(153.3,80.07) 153.3,78.59 154.23,77.65 154.23,73.67 154.35,73.56 154.35,72.79 RC32.2 155.45,72.01 156.06,72.63 DH1.2
  BOTTOM w0.076: v2(150.99,85.86) 151.06,85.79 151.36,85.79 151.55,85.98 UC1.AJ8
ACDET: length 7.8
  BOTTOM w0.102: v1(52.13,13.52) 51.8,13.19 50.35,13.19 PR711.2
  BOTTOM w0.203: PU701.3 47.27,14.3 47.43,14.46 PR723.1
  BOTTOM w0.254: PC711.2 PR711.2 49.46,13.64 49.18,13.92 48.06,13.92 47.86,14.13 PR723.1
ACIN: length 429.7
  TOP w0.076: 157.48,68.25 157.48,68.9 156.39,69.98 DH1.1
  TOP w0.102: v2(164.76,40.9) 165.43,41.56 165.43,59.73 161.75,63.4 161.75,63.9 157.48,68.17 157.48,68.25 ; v2(140.65,23.41) 140.65,22.21 CE18.2 140.14,20.91 139.82,20.59 UE1.110 139.82,12.69 138.58,11.45 138.58,8.6 137.52,7.55 133.53,7.55 132.52,6.53 132.52,6.28 v2(132.49,6.25)
  TOP w0.203: v2(37.14,106.86) 37.5,106.86 38.92,108.28 v1(38.92,108.77) 38.92,109.78 38.54,110.16 37.6,110.16 PR1.1 ; v2(71.3,97.34) 71.56,97.08 RV149.1 ; v2(22.76,51.82) 22.76,53.67 23.3,54.21 v2(23.3,58.68)
  IN1 w0.102: 63.05,97.72 63.91,96.85 65.82,96.85 66.3,97.34 v2(71.3,97.34) 75.24,97.34 75.88,96.7 75.88,95.71 77.91,93.68
  IN1 w0.107: v2(140.65,23.41) 141.02,23.03 143.15,23.03 143.62,23.5 146.57,23.5 147.03,23.04 148.7,23.04 151.75,26.09 152.76,26.09 154.74,28.07 154.74,32.87 159.39,37.52 160.84,37.52 162.24,38.92 162.69,38.92 164.67,40.9 v2(164.76,40.9) ; 77.91,93.68 78.14,93.45 81.11,93.45 82.73,91.83 82.73,91.24 82.23,90.73 82.23,86.29 80.7,84.76 80.7,78.29 83.37,75.62 83.37,70.54 82.86,70.03 82.86,62.05 85.53,59.39 85.53,54.79 84.13,53.4 84.13,38.61 83.22,37.7 83.22,34.5 86.49,31.22 91.23,31.22 93.36,29.09 95.23,29.09 100.27,24.05 101.53,24.05 102.29,23.29 102.81,23.29 103.68,22.42 103.68,13.32 108.4,8.6 109.86,8.6 110.89,7.58 112.85,7.58 114.79,5.63 117.34,5.63 118.43,6.72 121.21,6.72 122.14,5.79 130.42,5.79 130.88,6.25 v2(132.49,6.25) ; 63.05,97.72 62.36,98.4 62.36,99.42 61.22,100.56 59.86,100.56 55.21,105.21 54.54,105.21 53.9,105.85 53.9,107.24 52.71,108.44 50.07,108.44 47.99,106.35 40.7,106.35 40.06,106.99 37.27,106.99 v2(37.14,106.86) 36.38,106.1 35.74,106.1 33.23,103.59 33.23,102.45 32.14,101.36 28.68,101.36 24.96,97.64 19.67,97.64 17.07,95.05 17.07,69.11 17.58,68.6 17.58,65.98 23.3,60.26 v2(23.3,58.68)
  IN2 w0.203: v2(52.38,15.93) 52,15.93 50.35,14.28 49.31,14.28 46.58,11.55 42.93,11.55 v2(42.3,10.91) ; v2(22.76,51.82) 24.6,49.99 27.09,49.99 28.39,48.68 28.39,42.36 30.15,40.6 47.16,40.6 48.25,39.51 48.25,32.89 52.25,28.88 v2(52.38,28.88)
  BOTTOM w0.203: v2(52.38,28.88) v2(52.38,15.93)
  BOTTOM w0.254: PR707.2 PR712.1 42.3,9.91 v2(42.3,10.91) 42.93,11.54 PU701.14
ACIN_65W: length 164.2
  TOP w0.102: v2(78.67,98.73) v1(77.3,98.73) 74.1,98.73 73.16,97.79 RV149.2 73.29,96.96 QV8.2 ; v2(117.91,7.62) 117.84,7.62 116.22,9.24 116.22,11.93 117.96,13.67 v2(117.96,18.95) ; v2(140.9,17.99) 140.62,18.27 UE1.108
  IN1 w0.107: v2(117.96,18.95) 118.33,18.58 121.84,18.58 122.11,18.86 130.1,18.86 130.96,18 135.6,18 136.32,18.71 140.18,18.71 v2(140.9,17.99) ; v2(78.67,98.73) 78.67,96.32 80.07,94.92 81.62,94.92 82.94,93.6 83.75,93.6 84.26,93.09 84.26,88.32 84,88.07 84,86.92 84.26,86.67 84.26,82.99 85.91,81.34 85.91,79.18 85.65,78.92 85.65,69.02 84.89,68.25 84.89,65.21 84.51,64.83 84.51,62.29 86.82,59.97 86.82,54.06 85.4,52.63 85.4,39.17 87.18,37.39 87.18,36.07 88.73,34.53 90.34,34.53 94.84,30.02 95.62,30.02 100.66,24.99 101.92,24.99 102.68,24.22 103.2,24.22 104.61,22.8 104.61,13.79 108.86,9.54 110.25,9.54 110.56,9.23 112,9.23 112.72,8.51 113.24,8.51 113.5,8.25 117.21,8.25 117.84,7.62 v2(117.91,7.62)
ACOFF: length 289.3
  TOP w0.102: PQ706.5 15.06,39.44 15.68,40.06 15.68,41.46 16.73,42.51 v1(17.61,42.51) 17.98,42.88 17.98,43.31 v2(17.56,43.73) ; UE1.27 132.23,7.31 133.13,8.21 v2(133.13,8.46)
  IN1 w0.107: v2(17.56,43.73) 17.56,44.04 16.44,45.15 14.9,45.15 8.23,51.83 8.23,57.15 7.29,58.09 7.29,64.67 7.7,65.08 9.07,65.08 10.47,66.48 10.47,70.29 9.58,71.18 9.58,73.59 6.53,76.64 6.53,79.05 7.42,79.94 7.42,82.22 8.06,82.86 8.79,82.86 9.71,83.78 9.71,85.4 8.57,86.54 8.57,91.62 9.45,92.51 9.45,97.08 11.3,98.92 13.2,98.92 18.26,103.98 29.24,103.98 33.84,108.59 33.84,110.42 35.87,112.45 39.43,112.45 41.33,110.55 48.19,110.55 49,111.36 54.89,111.36 60.29,105.96 61.99,105.96 65.45,102.5 74.28,102.5 74.29,102.48 78.51,102.48 85.28,95.72 86.03,95.72 86.92,94.82 86.92,93.4 87.69,92.64 87.69,91.75 87.18,91.24 87.18,87.3 88.83,85.65 88.83,82.99 88.37,82.53 88.37,68.56 86.92,67.11 86.92,64.95 87.94,63.94 87.94,62.55 88.83,61.66 88.83,50.86 87.43,49.46 87.43,40.16 95.7,31.89 96.39,31.89 101.43,26.85 102.69,26.85 103.46,26.09 103.97,26.09 106.48,23.58 106.48,15.5 110.57,11.41 111.03,11.41 111.34,11.1 112.78,11.1 113.31,10.56 116.68,10.56 116.81,10.43 128.77,10.43 129.38,9.83 131.76,9.83 v2(133.13,8.46)
AD_BID0: length 8.3
  TOP w0.102: UE1.75 147.83,9.31 148.52,8.61 v1(148.52,6.28) 148.52,5.62 148.85,5.29 CE8.1 RE5.2 RE3.1
ADP_I: length 317.6
  TOP w0.102: PR23.2 42.86,114.69 40.32,114.69 v1(39.69,114.06) 39.06,114.06 38.73,114.39 34.69,114.39 33.11,115.97 v2(33.11,116.02) ; UE1.65 145.64,5.31 145.34,5.01 v2(145.34,4.88)
  IN1 w0.107: v2(33.11,116.02) 30.8,116.02 29.92,115.14 29.92,107.57 28.51,106.15 11.03,106.15 9.84,104.96 4.63,104.96 1.61,101.94 1.61,70.51 5.62,66.5 5.62,59.1 7.76,56.95 7.76,51.39 16.96,42.19 20.24,42.19 22.6,39.83 22.6,38.68 22.28,38.36 22.28,34.73 25.6,31.42 25.6,24.96 24.36,23.72 24.05,23.72 21.99,21.66 21.99,16.45 24.03,14.41 31.73,14.41 35.61,10.53 41.63,10.53 42.92,9.24 45.08,9.24 46.2,10.35 v2(46.2,10.61)
  IN2 w0.107: v2(46.2,10.61) 47.64,12.06 49.14,12.06 51.24,14.15 51.87,14.15 54.41,16.69 54.41,24.92 58.74,29.24 76.97,29.24 77.69,28.52 79.57,28.52 80.19,29.14 90.02,29.14 96.38,22.78 99.4,22.78 105.13,17.05 105.13,14.43 105.9,13.66 105.9,3.52 106.98,2.44 118.1,2.44 118.84,1.7 124.37,1.7 125.39,2.71 133.27,2.71 133.51,2.95 143.41,2.95 v2(145.34,4.88)
  BOTTOM w0.203: PU701.9 44.93,11.38 45.23,11.08 45.73,11.08 v2(46.2,10.61) 46.51,10.29 46.65,10.29 PC720.2
ADPIN: length 0.7
  TOP w0.102: v4(23.11,117.33) 22.68,117.76 22.66,117.76 22.66,117.87
  vias: v3(17.99,119.16) v3(18.5,120.45) v3(18.65,119.79) v3(18.7,119.13) v3(19.18,120.43) v3(19.34,119.79) v3(19.41,119.13) v3(19.87,120.43) v3(20,119.79) v3(20.07,119.16) v3(20.91,119.41) v3(21.8,119.41) v4(21.22,121.59) v4(22.97,121.59)
AGATE: length 49.8
  TOP w0.102: v2(28.72,34.04) v1(29.3,34.04)
  TOP w0.254: PR725.1 28.29,34.47 v2(28.72,34.04)
  IN1 w0.254: v2(28.72,34.04) 26.67,31.99 26.67,24.25 25.09,22.67 24.43,22.67 23.65,21.89 23.65,17.45 25.55,15.55 33.18,15.55 35.77,12.96 42.17,12.96 43.02,12.11 45.75,12.11 46.69,13.05 46.69,15.53 v2(46.82,15.65)
  BOTTOM w0.203: v2(46.82,15.65) 46.82,15.4 46.52,15.1 PU701.1
ALERT#: length 11
  TOP w0.102: v2(63.4,112.53) v1(63.4,113.16)
  TOP w0.254: PR506.2 63.05,112.17 v2(63.4,112.53) ; PU501.19 69.91,112.83 69.91,112.83 v2(69.91,112.96)
  IN1 w0.254: v2(63.4,112.53) 63.48,112.6 63.48,112.88 63.68,113.09 68,113.09 68.64,112.45 69.4,112.45 v2(69.91,112.96)
  BOTTOM w0.254: PR506.2 63.05,112.23 63.35,112.53 v2(63.4,112.53)
AOAC_WLAN: length 110.4
  TOP w0.102: UE1.85 145.52,13.31 v2(145.34,13.14) ; v2(200.31,76.72) 200.31,74.55 199.79,74.03 199.79,70.41 198.42,69.04 198.42,64.47 197.14,63.19 197.14,60.91 195.5,59.28 v1(189.74,59.28) 188.12,59.28 185.53,56.68 185.53,51.52 185.91,51.13 185.91,43.54 184.84,42.47 184.84,38.79 183.71,37.66 180.37,37.66 177.35,34.64 177.35,31.45 173.79,27.89 v2(173.47,27.89)
  IN1 w0.107: v2(145.34,13.14) 145.95,12.53 150.7,12.53 151.05,12.18 157.35,12.18 157.82,11.72 157.82,11.09 158.02,10.88 162.73,10.88 164.83,12.98 164.83,15.34 167.44,17.95 167.44,19.36 168.43,20.35 168.43,22.89 170.36,24.82 170.36,25.59 172.67,27.89 v2(173.47,27.89)
  BOTTOM w0.102: UM1.4 v2(200.31,76.72)
AUD_HP_OUT_L_CN: length 15.4
  TOP w1.016: JHP.1 200.14,36.91 199.42,36.19 199.42,31.73 v1(198.86,31.17) 198.23,30.54 196.84,30.54 v2(196.58,30.27)
  BOTTOM w0.508: v2(196.58,30.27) 195.78,29.47 DA10.3 194.98,29.47 194.44,28.93 CA39.1 192.4,28.93 LA8.1
AUD_HP_OUT_R_CN: length 16.3
  TOP w0.102: v1(207.24,25.76) JHP.2
  TOP w1.016: JHP.2 205.97,26.09 200.08,26.09 198.94,27.23
  BOTTOM w0.508: v2(197.48,27.54) DA10.2 195.08,27.82 CA33.1 192.65,27.82 LA9.1
B+: length 176.4
  TOP w1.524: 78.82,33.28 79.18,32.92 79.14,32.89 79.14,20.28 79.43,19.99
  BOTTOM w1.016: 15.08,46.83 17.52,46.83 20.61,43.74 23.55,43.74 24.57,42.73 27.48,42.73 30.14,40.06 32.31,40.06 33.58,41.33 v3(33.58,41.71) v3(34.6,41.71)
  BOTTOM w1.27: 9.58,76.89 9.71,76.89 10.72,75.87 15.42,75.87
  BOTTOM w2.54: 57.36,116.76 51.5,116.76 50.09,118.17 39.43,118.17 37.84,116.58 37.84,114.46 34.85,111.47 34.85,108.89 32.82,106.86 30.66,106.86 29.52,105.72 21.6,105.72 14.53,98.66 14.53,85.98 16.06,84.46 16.06,76.51 15.42,75.87 15.42,66.86 16.57,65.71 16.57,59.62 17.58,58.6 17.58,50.73 15.08,48.23 15.08,35.45 17.71,32.82 25.96,32.82 26.73,32.06
  vias: v2(8.18,78.03) v2(8.18,77.4) v2(8.18,76.76) v2(8.82,78.03) v2(8.82,77.4) v2(56.19,26.09) v2(56.19,25.43) v3(27.36,28.12) v3(27.36,27.11) v3(27.36,26.22) v3(27.36,25.33) v3(27.36,24.57) v3(28.12,28.12) v3(28.12,27.11) v3(28.12,26.22) v3(28.12,25.33) v3(28.25,29.01) v3(29.14,23.42) v3(29.14,22.53) v3(30.03,23.42) v3(30.03,22.53) v3(30.92,23.42) v3(30.92,22.53) v3(31.68,23.42) v3(31.68,22.53) v3(45.65,25.53) v3(45.61,24.86) v3(45.57,24.13) v3(46.36,25.58) v3(47.1,25.57) v3(47.83,25.57) v3(56.19,24.69) v3(56.19,23.93) v3(56.95,26.06) v3(56.95,25.4) v3(56.95,24.69) v3(56.95,23.93) v3(79.69,19.49) v3(79.69,18.83) v3(80.47,19.46) v3(80.47,18.83) v3(84.64,36.89) v3(84.64,36.25) v3(84.64,35.62) v3(85.27,36.89) v3(85.27,36.25) v3(85.27,35.62) v3(85.91,36.89) v3(85.91,36.25) v3(85.91,35.62) v4(73.01,33)
B+_1.05V:
  vias: v1(176.41,54.11)
BAT_ALERT: length 5.9
  TOP w0.254: PD1.2 18.73,18.22 v1(17.48,16.97) 17.03,16.52 PBATT.3
BATT+:
  vias: v3(20.76,29.52) v3(20.76,26.85) v3(20.76,25.84) v3(21.39,29.52) v3(21.52,26.85) v3(21.52,25.84) v3(21.77,31.04) v3(21.77,30.15) v3(22.54,31.04) v3(22.54,30.15) v3(23.3,31.04) v3(23.3,30.15) v3(24.06,31.04) v3(24.06,30.15) v3(24.06,26.85) v3(24.06,26.09) v3(24.06,25.33) v3(24.19,29.52) v4(24.67,28.3)
BATT++:
  vias: v2(17.2,30.03) v2(17.2,29.01) v2(17.2,28.12) v2(17.2,26.22) v2(17.2,25.46) v2(17.37,27.26) v2(17.96,30.03) v2(18.13,27.26) v2(18.89,27.26) v3(18.73,30.03) v4(17.56,30.54)
BATT_CHG_LED#: length 281.8
  TOP w0.102: v2(138.99,7.14) 139.02,7.14 139.48,6.68 141.48,6.68 142.04,7.24 142.04,11.94 143.06,12.96 143.06,14.79 142.45,15.4 142.45,16.11 143.16,16.82 144.89,16.82 145.6,16.11 UE1.92 ; v2(15.96,54.16) 15.96,53.48 15.46,52.99 v1(15.21,52.99) 14.95,52.99 14.64,53.3 13.77,53.3 JLED.6
  IN1 w0.102: 66.35,97.72 65.74,97.11 64.29,97.11 63.68,97.72 ; 75.15,97.72 75.5,97.37 75.88,97.37 77.91,95.34
  IN1 w0.107: v2(15.96,54.16) 16.59,54.79 16.59,95.97 18.65,98.02 25.01,98.02 28.58,101.59 31.24,101.59 32.31,102.67 32.31,103.69 36.2,107.57 40.14,107.57 41.1,106.61 47.91,106.61 49.99,108.69 52.84,108.69 54.16,107.37 54.16,105.97 54.67,105.47 55.29,105.47 59.86,100.89 61.22,100.89 62.69,99.42 62.97,99.42 63.2,99.19 63.2,98.2 63.68,97.72 ; 75.15,97.72 74.64,98.23 66.85,98.23 66.35,97.72 ; 77.91,95.34 79.54,93.7 81.29,93.7 82.99,92 82.99,91.11 82.48,90.61 82.48,86.16 80.96,84.64 80.96,78.41 83.62,75.75 83.62,70.41 83.11,69.91 83.11,62.16 85.78,59.49 85.78,54.67 84.38,53.27 84.38,38.45 83.55,37.61 83.55,34.68 86.75,31.47 91.31,31.47 93.46,29.32 95.32,29.32 100.36,24.28 101.63,24.28 102.39,23.52 102.91,23.52 103.91,22.51 103.91,13.45 108.52,8.84 109.96,8.84 110.99,7.81 112.94,7.81 114.89,5.86 117.24,5.86 118.36,6.98 121.34,6.98 122.13,6.18 127,6.18 127.57,6.75 131.08,6.75 131.26,6.92 138.49,6.92 138.71,7.14 v2(138.99,7.14)
BATT_I: length 161.4
  TOP w0.254: v2(39.71,114.94) v1(39.3,115.35) 39.27,115.37 PR35.2
  IN1 w0.107: v2(39.71,114.94) 39.63,114.86 37.9,114.86 33.58,110.55 33.58,108.71 29.09,104.22 18.11,104.22 13.2,99.31 11.3,99.31 9.2,97.21 9.2,92.64 8.31,91.75 8.31,86.42 9.45,85.27 9.45,83.85 8.71,83.11 7.93,83.11 7.17,82.35 7.17,80.07 6.28,79.18 6.28,76.51 9.33,73.46 9.33,71.05 10.22,70.16 10.22,66.6 8.95,65.33 7.63,65.33 7.05,64.76 7.05,57.99 8,57.05 8,51.55 14.79,44.76 16.44,44.76 17.14,44.06 17.14,42.93 17.38,42.69 20.5,42.69 23.15,40.05 23.15,38.38 22.79,38.03 22.79,34.99 26.1,31.67 26.1,24.58 24.76,23.24 24.22,23.24 23.11,22.12 23.11,16.05 24.24,14.91 31.95,14.91 34.83,12.03 v2(39.88,12.03)
  BOTTOM w0.203: PC725.2 40.91,12.03 41.58,12.7 PU701.15
  BOTTOM w0.254: v2(39.88,12.03) PC725.2
BATT_LOW_LED#: length 280.8
  TOP w0.102: v2(139.58,7.19) 139.6,7.19 139.91,6.89 141.36,6.89 141.79,7.32 141.79,12.01 142.8,13.02 142.8,14.66 142.22,15.24 142.22,16.23 143.06,17.07 145.16,17.07 145.73,16.51 UE1.93 147.51,16.51 148.01,16.01 v1(148.19,16.01) ; JLED.5 15.51,54.3 v2(15.96,54.74)
  IN1 w0.102: 75.85,97.72 77.58,95.99 77.58,95.99 77.91,95.67
  IN1 w0.107: 75.85,97.72 74.84,98.73 70.42,98.73 70.42,99.12 69.46,100.08 68.23,100.08 67.77,99.62 65.23,99.62 64.59,100.27 63.72,100.27 62.79,101.2 61.91,101.2 61.03,102.08 59.67,102.08 57.49,104.26 57.49,105.33 56.19,106.63 55.86,106.63 53.42,109.07 50.04,109.07 47.91,106.94 41.36,106.94 40.44,107.85 35.98,107.85 31.43,103.3 31.43,102.54 30.71,101.83 28.48,101.83 24.98,98.33 18.57,98.33 16.36,96.11 16.36,55.14 v2(15.96,54.74) ; v2(139.58,7.19) 139.58,7.22 139.25,7.55 138.82,7.55 138.4,7.13 130.89,7.13 130.72,6.96 127.48,6.96 126.94,6.42 122.27,6.42 121.46,7.23 118.28,7.23 117.15,6.1 116.4,6.1 115.93,6.56 115.93,6.72 114.93,7.73 113.36,7.73 113.04,8.04 111.09,8.04 110.06,9.07 108.63,9.07 104.15,13.55 104.15,22.61 103,23.75 102.49,23.75 101.72,24.52 100.46,24.52 95.42,29.56 93.63,29.56 91.46,31.73 86.87,31.73 83.81,34.79 83.81,37.48 84.64,38.31 84.64,53.01 86.04,54.41 86.04,59.62 83.37,62.29 83.37,68.89 84.64,70.16 84.64,75.62 84,76.26 84,82.1 82.73,83.37 82.73,90.48 83.23,90.97 83.23,92.12 81.39,93.96 79.62,93.96 77.91,95.67
BATT_PRS: length 120.4
  TOP w0.102: v2(48.91,9.16) 48.75,9.16 47.32,7.73 45.2,7.73 44.9,8.03 44.9,8.42 44.68,8.64 42.51,8.64 41.91,8.04 41.54,8.04 41.19,8.38 37.3,8.38 33.29,12.39 27.62,12.39 23.81,16.2 23.81,19.36 22.88,20.29 21.61,20.29 PR15.1
  TOP w0.254: PR15.1 20.55,19.22 PD1.3 18.73,19.22 17.44,20.52 v1(16.85,20.52) PBATT.5 ; v2(80.57,51.49) 81.08,50.98 81.08,49.46 v2(80.57,48.95)
  IN1 w0.107: v2(80.47,27.39) 77.63,27.39 74.99,30.03 57.71,30.03 54.79,27.11 54.79,14.46 52.46,12.12 51.47,12.12 48.91,9.57 v2(48.91,9.16)
  BOTTOM w0.102: v2(80.47,27.39) 81.29,28.2 81.29,33.99 81.46,34.17 81.46,46.16 81.29,46.33 81.29,48.14 80.57,48.85 v2(80.57,48.95)
  BOTTOM w0.381: PR37.2 81.39,51.95 PC14.1 80.63,51.44 v2(80.57,51.49)
BATT_TEMP: length 225.8
  TOP w0.203: UE1.63 144.62,2.68 145.09,2.21 v2(145.34,2.21)
  TOP w0.254: v2(152.86,2.47) 152.85,2.47 ; 152.85,2.47 152.35,2.98 150.68,2.98 150.55,2.85 CE9.2 ; 152.85,2.47 152.98,2.6 152.98,4.87 152.28,5.57 152.28,9.81 152.61,10.14 152.61,10.14 153.35,10.87 153.35,13.5 153.31,13.53 153.31,13.56 152.58,14.28 152.58,16.95 v2(152.48,17.05) ; PR15.2 PR16.1 21.47,17.14 21.05,16.72 v2(20.9,16.72) ; v2(14.41,32.95) v1(15.09,33.63) 15.6,34.14 PC723.2
  IN1 w0.203: v2(152.86,2.47) 152.3,3.03 150.73,3.03 149.92,2.21 v2(145.34,2.21)
  IN1 w0.254: v2(14.41,32.95) 15.42,33.96 21.9,33.96 24.82,31.04 24.82,25.35 24.04,24.57 23.66,24.57 20.72,21.62 20.72,18.34 20.35,17.97 20.35,17.12 20.75,16.72 v2(20.9,16.72)
  IN2 w0.254: v2(152.48,17.05) 152.36,17.05 152.33,17.02 149.65,17.02 148.89,17.78 146.38,17.78 145.62,17.02 141.16,17.02 141.08,16.94 137.63,16.94 137.45,17.12 133.83,17.12 133.32,16.6 126.42,16.6 126.2,16.83 126.01,17.01 124.35,17.01 123.97,17.4 123.36,17.4 123.13,17.16 120.51,17.16 119.83,16.48 117.4,16.48 116.65,17.23 113.25,17.23 112.94,16.91 110.21,16.91 108.98,18.14 108.98,19.07 101.6,26.46 101.45,26.46 101.38,26.52 98.51,26.52 92.48,32.55 88.39,32.55 88.03,32.9 86.93,32.9 86.39,32.36 83.76,32.36 83.46,32.66 80.88,32.66 v2(80.82,32.6) ; v2(80.47,28.5) 80.18,28.21 77.56,28.21 76.84,28.94 59,28.94 57.56,27.5 57.56,18.83 51.75,13.01 50.6,13.01 49.21,11.61 47.96,11.61 45.29,8.95 44.32,8.95 43.16,7.79 36.77,7.79 33.84,10.72 31.91,10.72 27.34,15.3 22.65,15.3 21.23,16.72 v2(20.9,16.72)
  BOTTOM w0.254: v2(80.47,28.5) 80.82,28.85 v2(80.82,32.6)
BBS_BIT: length 27.8
  TOP w0.076: 155.1,95.97 154.64,95.51 154.64,95.15 154.16,94.67 153.04,94.67 152.89,94.82 152.17,94.82 v2(151.81,95.19)
  TOP w0.102: 155.1,95.97 156.08,96.94 158.43,96.94 159.12,96.24 161.09,96.24 161.22,96.37 161.22,96.83 161.47,97.08 v1(163.58,97.08) 164.19,97.08 164.83,96.45 166.68,96.45 167.82,95.31 168.97,95.31 168.99,95.33 170.52,95.33 171.2,96.02 173.67,96.02 RC119.2 RC123.1
  BOTTOM w0.076: UC1.L8 151.55,95.44 v2(151.81,95.19)
BEEP#: length 70.7
  TOP w0.102: v2(186.68,17.07) 186.68,17.47 187.38,18.17 DA8.2 188.56,19.75 v1(188.45,19.87) ; v2(138.5,15.22) 138.5,13.11 138.07,12.68 136.67,12.68 134.58,10.6 133.53,10.6 131.85,8.91 UE1.23
  IN2 w0.107: v2(186.68,17.07) 185.98,17.77 181.91,17.77 181.42,17.28 181.42,15.3 179.63,13.52 177.35,13.52 175.19,11.36 172.27,11.36 170.69,12.93 169.63,12.93 168.79,13.77 167.06,13.77 166.17,12.88 160.66,12.88 159.66,13.88 153.27,13.88 152.97,14.17 150.71,14.17 149.56,15.33 147.2,15.33 146.76,14.89 141.64,14.89 141.49,15.03 138.69,15.03 v2(138.5,15.22)
BGATE: length 36.5
  BOTTOM w0.203: 41.4,13.01 41.49,13.1 PU701.16
  BOTTOM w0.254: PR706.2 18.22,24.44 17.71,23.93 v1(17.71,21.72) 16.44,20.45 16.44,17.25 18.7,14.99 23.93,14.99 26.07,12.86 28.89,12.86 29.28,12.46 34.7,12.46 35.25,13.01 41.4,13.01
BKOFF#: length 252.5
  TOP w0.102: v2(117.39,19.12) 117.39,16.72 116.54,15.87 116.54,14.55 116.55,14.55 116.55,14.21 116.54,14.21 116.54,13.95 114.84,12.25 113.52,12.25 113.42,12.14 113.42,10.82 113.1,10.51 113.05,10.51 113.65,9.91 v2(114.33,9.91) ; UE1.105 141.82,20.35 v2(141.66,20.51) ; v1(8.75,78.82) 8.75,78.82 8.79,78.86 DX1.2 8.79,81.36 v2(8.39,81.77)
  IN1 w0.107: v2(117.39,19.12) 117.94,19.67 120.27,19.67 120.85,19.09 127.34,19.09 127.45,19.2 135.66,19.2 135.84,19.38 140.52,19.38 v2(141.66,20.51) ; v2(8.39,81.77) 8.69,81.77 10.47,83.55 10.47,85.83 9.33,86.97 9.33,87.56 10.04,88.27 10.04,95.64 12.76,98.35 13.39,98.35 18.56,103.52 29.43,103.52 34.58,108.66 34.58,110.37 36.01,111.8 37.15,111.8 37.9,111.05 40.06,111.05 41.08,110.04 48.44,110.04 49.23,110.82 54.76,110.82 60.1,105.49 61.8,105.49 65.27,102.02 78.32,102.02 85.28,95.05 85.98,95.05 86.42,94.61 86.42,91.37 86.67,91.11 86.67,87.05 87.69,86.03 87.69,78.8 87.86,78.62 87.86,69.7 87.18,69.02 87.18,68.25 86.42,67.49 86.42,64.7 87.43,63.68 87.43,62.21 88.32,61.32 88.32,51.11 86.92,49.71 86.92,39.93 88.7,38.16 88.7,37.01 89.22,36.49 90.38,36.49 95.44,31.43 96.2,31.43 101.24,26.39 102.5,26.39 103.26,25.62 103.78,25.62 106.02,23.39 106.02,15.3 110.38,10.94 110.83,10.94 111.15,10.63 112.59,10.63 113.3,9.91 114.33,9.91 v2(114.33,9.91)
BOOT1:
  vias: v1(58.3,40.42)
BOOT2:
  vias: v1(65.32,40.64)
BOOT_1.35V:
  vias: v1(87.76,11.21)
BP_0: length 6.7
  BOTTOM w0.102: RV82.1 64.95,100.44 v1(64.95,98.68) 64.57,98.3 64.57,94.67 UV1.U1
BP_1: length 7.9
  BOTTOM w0.102: UV1.U3 64.49,93.7 64.83,94.04 64.83,95.56 66.22,96.96 v1(66.22,99.66) RV81.1
BST:
  vias: v1(44.35,17.02)
BST_1.05V:
  vias: v1(181.36,51.82)
BST_1.35V: length 1.3
  BOTTOM w0.102: PC200.1 v1(90.23,13.01)
BST_3V: length 3.2
  TOP w0.102: PR103.2 v1(70.22,21.45)
  TOP w0.203: 71.88,20.18 71.88,19.6 PU100.9
  TOP w0.254: 71.88,20.18 71.73,20.33 71.73,21.15 PR103.2
BST_5V: length 2.5
  TOP w0.102: PR111.1 69.34,14.38 v1(69.2,14.24)
  TOP w0.203: PU100.17 71.87,15.99 71.56,15.68
BST_+1.35VGPUP:
  vias: v1(33.13,43.87)
BST_CHGA: length 1.2
  BOTTOM w0.102: PC721.1 v1(41.1,19.42)
BT_ON#: length 61.8
  TOP w0.076: v2(153.71,89.47) 154.97,89.47 155.64,88.8 158.32,88.8 158.58,88.55 159.29,88.55 159.59,88.24 163.05,88.24 163.51,88.7 v1(163.51,90.02) 163.51,90.86 163.15,91.22 v2(163.15,92.5)
  IN2 w0.107: v2(163.15,92.5) 163.92,93.27 164.78,93.27 165.18,93.68 166.53,93.68 167.34,92.87 167.34,92.79 168.81,91.32 169.86,91.32 170.11,91.06 170.11,88.75 169.83,88.47 169.83,86.57 171.25,85.15 171.25,84.76 173.24,82.78 173.24,81.51 174.19,80.55 174.3,80.55 175.32,79.53 177.61,79.53 179.48,77.66 179.48,68.92 v2(181.08,67.31)
  BOTTOM w0.076: v2(153.71,89.47) 153.73,89.45 153.73,89.45 153.72,89.44 153.72,89.44 153.5,89.22 UC1.AD5
  BOTTOM w0.102: v2(181.08,67.31) 181.92,68.16 183.27,68.16 183.45,68.34 184.94,68.34 185.63,67.64 185.63,66.35 185.73,66.25 JNGFF.46 ; v2(163.15,92.5) 163.35,92.31 163.82,92.31 RP54.2
CAPS_LED: length 93
  TOP w0.102: UE1.91 145.6,15.71 144.74,16.57 143.24,16.57 142.68,16.01 142.68,15.5 143.26,14.91 v2(143.26,10.35) ; JKB.1 97.19,47.75 97.59,47.35 97.59,40.81 97.36,40.58 97.36,38.49 98.33,37.52 v1(98.33,35.64) 98.33,32.47 101.78,29.01 103.69,29.01 107.98,24.72 107.98,15.32 111.18,12.12 v2(111.69,12.12)
  IN2 w0.107: v2(111.69,12.12) 111.82,12.12 112.76,13.06 118.82,13.06 119.31,12.57 122.73,12.57 123.2,13.04 123.86,13.04 124.11,13.29 125.54,13.29 126.19,12.64 134.26,12.64 134.46,12.45 134.96,12.45 136.18,11.23 138.28,11.23 138.46,11.41 140.67,11.41 141.72,10.35 v2(143.26,10.35)
CELL: length 2.7
  BOTTOM w0.203: PU701.6 46.61,13.1 47.22,12.49 47.22,11.92 47.53,11.61 PR719.2
CFD_PWRBTN#_XDP: length 4.4
  TOP w0.102: JXDP1.41 92.85,75.71 v1(93.39,75.18) 94.24,74.32 RC49.2
CFG0: length 43.4
  TOP w0.102: JXDP1.9 92.67,67.71 93.15,67.24 v2(94.29,67.24) v1(95.18,67.24)
  IN2 w0.076: 111.94,87.18 112.25,87.48 114.79,87.48 116.01,88.7 v2(116.01,88.85)
  IN2 w0.107: v2(94.29,67.24) 94.42,67.24 101.4,74.22 101.4,82.35 103.31,84.26 109.02,84.26 111.94,87.18
  BOTTOM w0.076: UC1.AC60 119.17,89.28 118.69,89.28 118.65,89.32 117.87,89.32 117.7,89.15 117.1,89.15 117,89.25 116.37,89.25 116.01,88.89 v2(116.01,88.85)
CFG1: length 40.9
  TOP w0.102: JXDP1.11 92.68,68.21 93.02,67.87 v1(93.48,67.87) v2(94.29,67.87)
  IN2 w0.076: 111.94,87.56 112.07,87.69 114.36,87.69 115.37,88.7 v2(115.37,88.85)
  IN2 w0.107: 111.94,87.56 108.9,84.51 103.18,84.51 101.15,82.48 101.15,74.35 94.67,67.87 v2(94.29,67.87)
  BOTTOM w0.076: v2(115.37,88.85) 115.5,88.85 116.07,89.42 117.07,89.42 117.17,89.32 117.63,89.32 117.92,89.61 UC1.AC62
CFG2: length 39.8
  TOP w0.102: JXDP1.15 94.22,69.21 v2(94.29,69.14)
  IN2 w0.076: 111.94,87.94 114.23,87.94 114.74,88.45 v2(114.74,88.85)
  IN2 w0.107: v2(94.29,69.14) 95.56,69.14 100.89,74.48 100.89,82.61 103.05,84.76 108.77,84.76 111.94,87.94
  BOTTOM w0.076: UC1.AC63 117.49,89.59 115.72,89.59 v1(115.6,89.46) 115.12,89.46 114.74,89.08 v2(114.74,88.85)
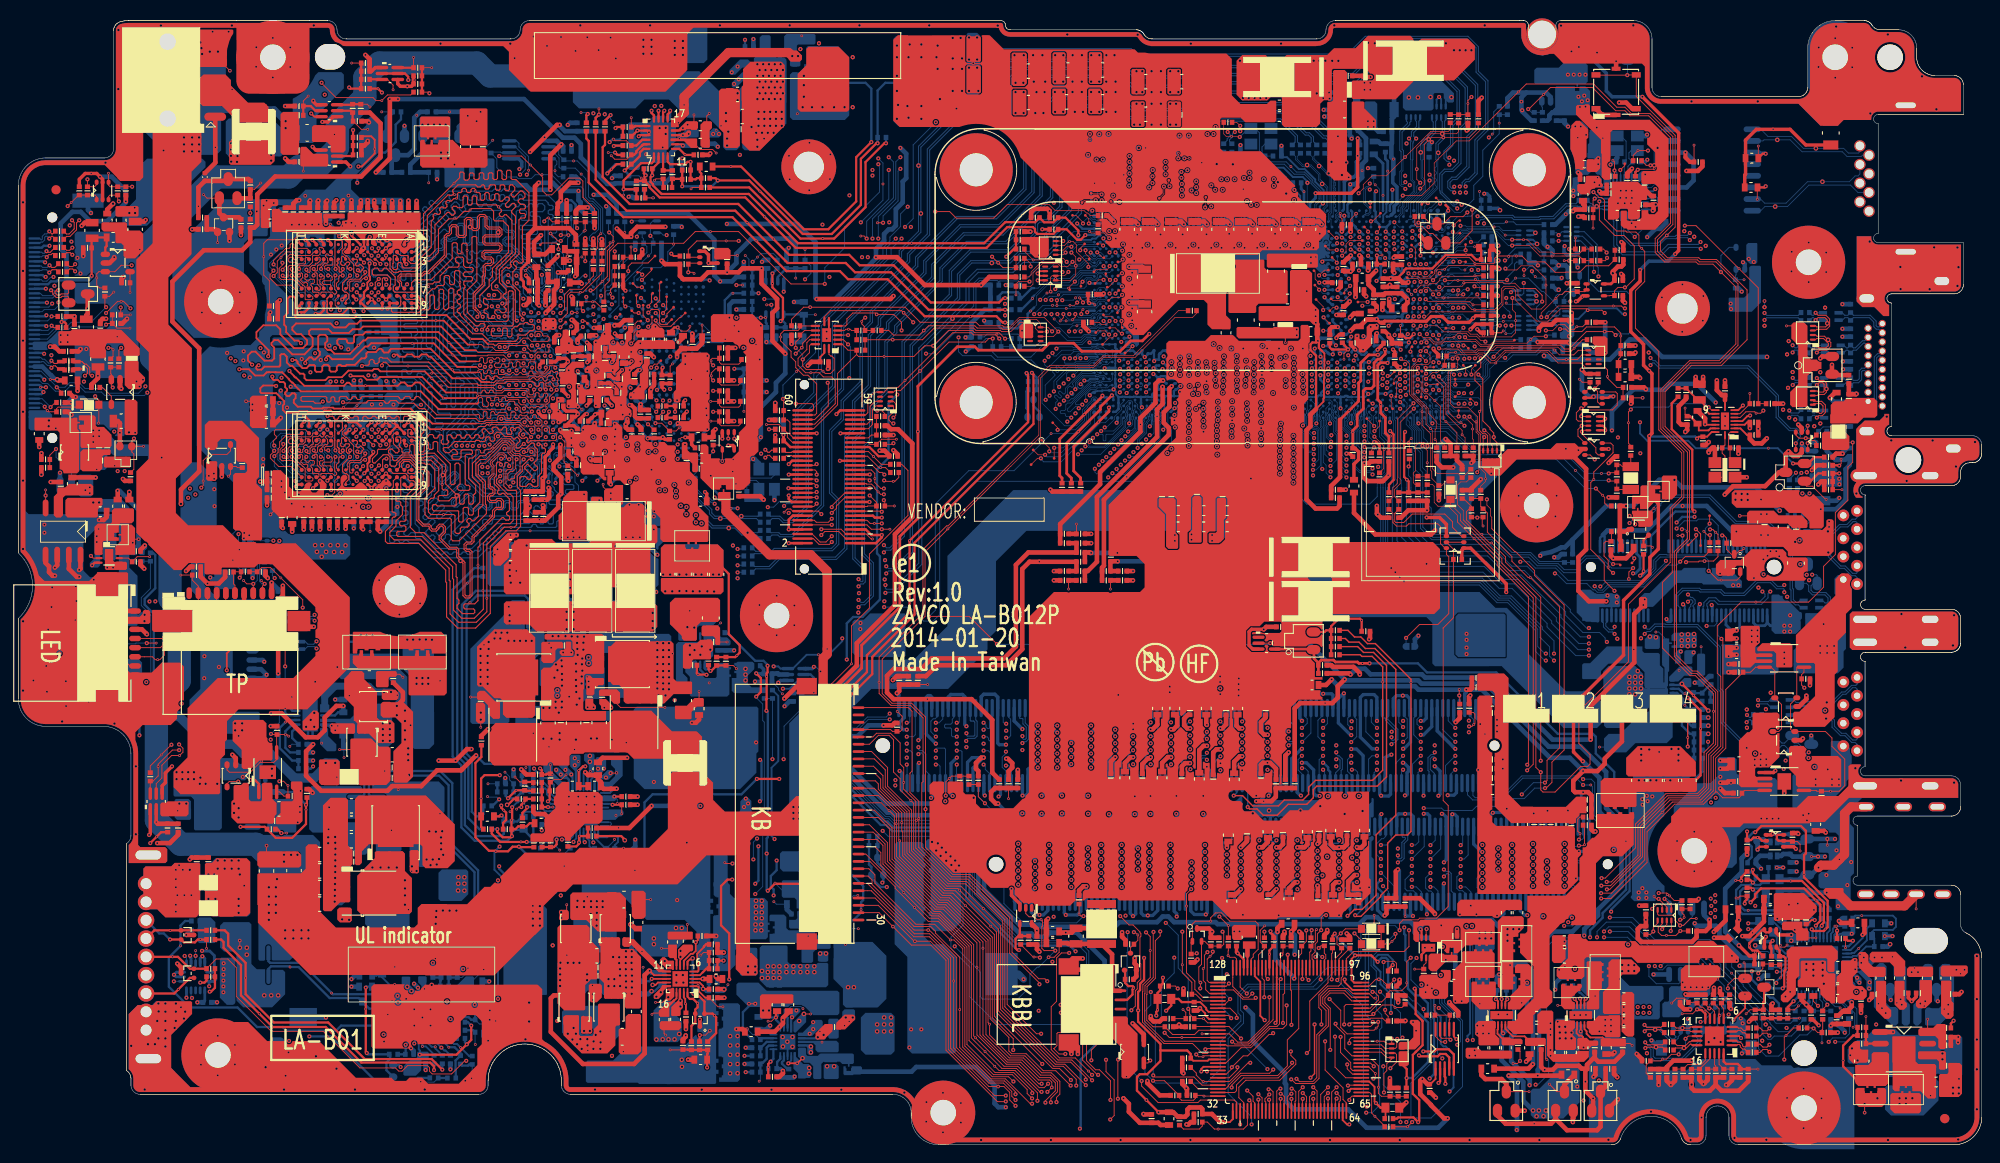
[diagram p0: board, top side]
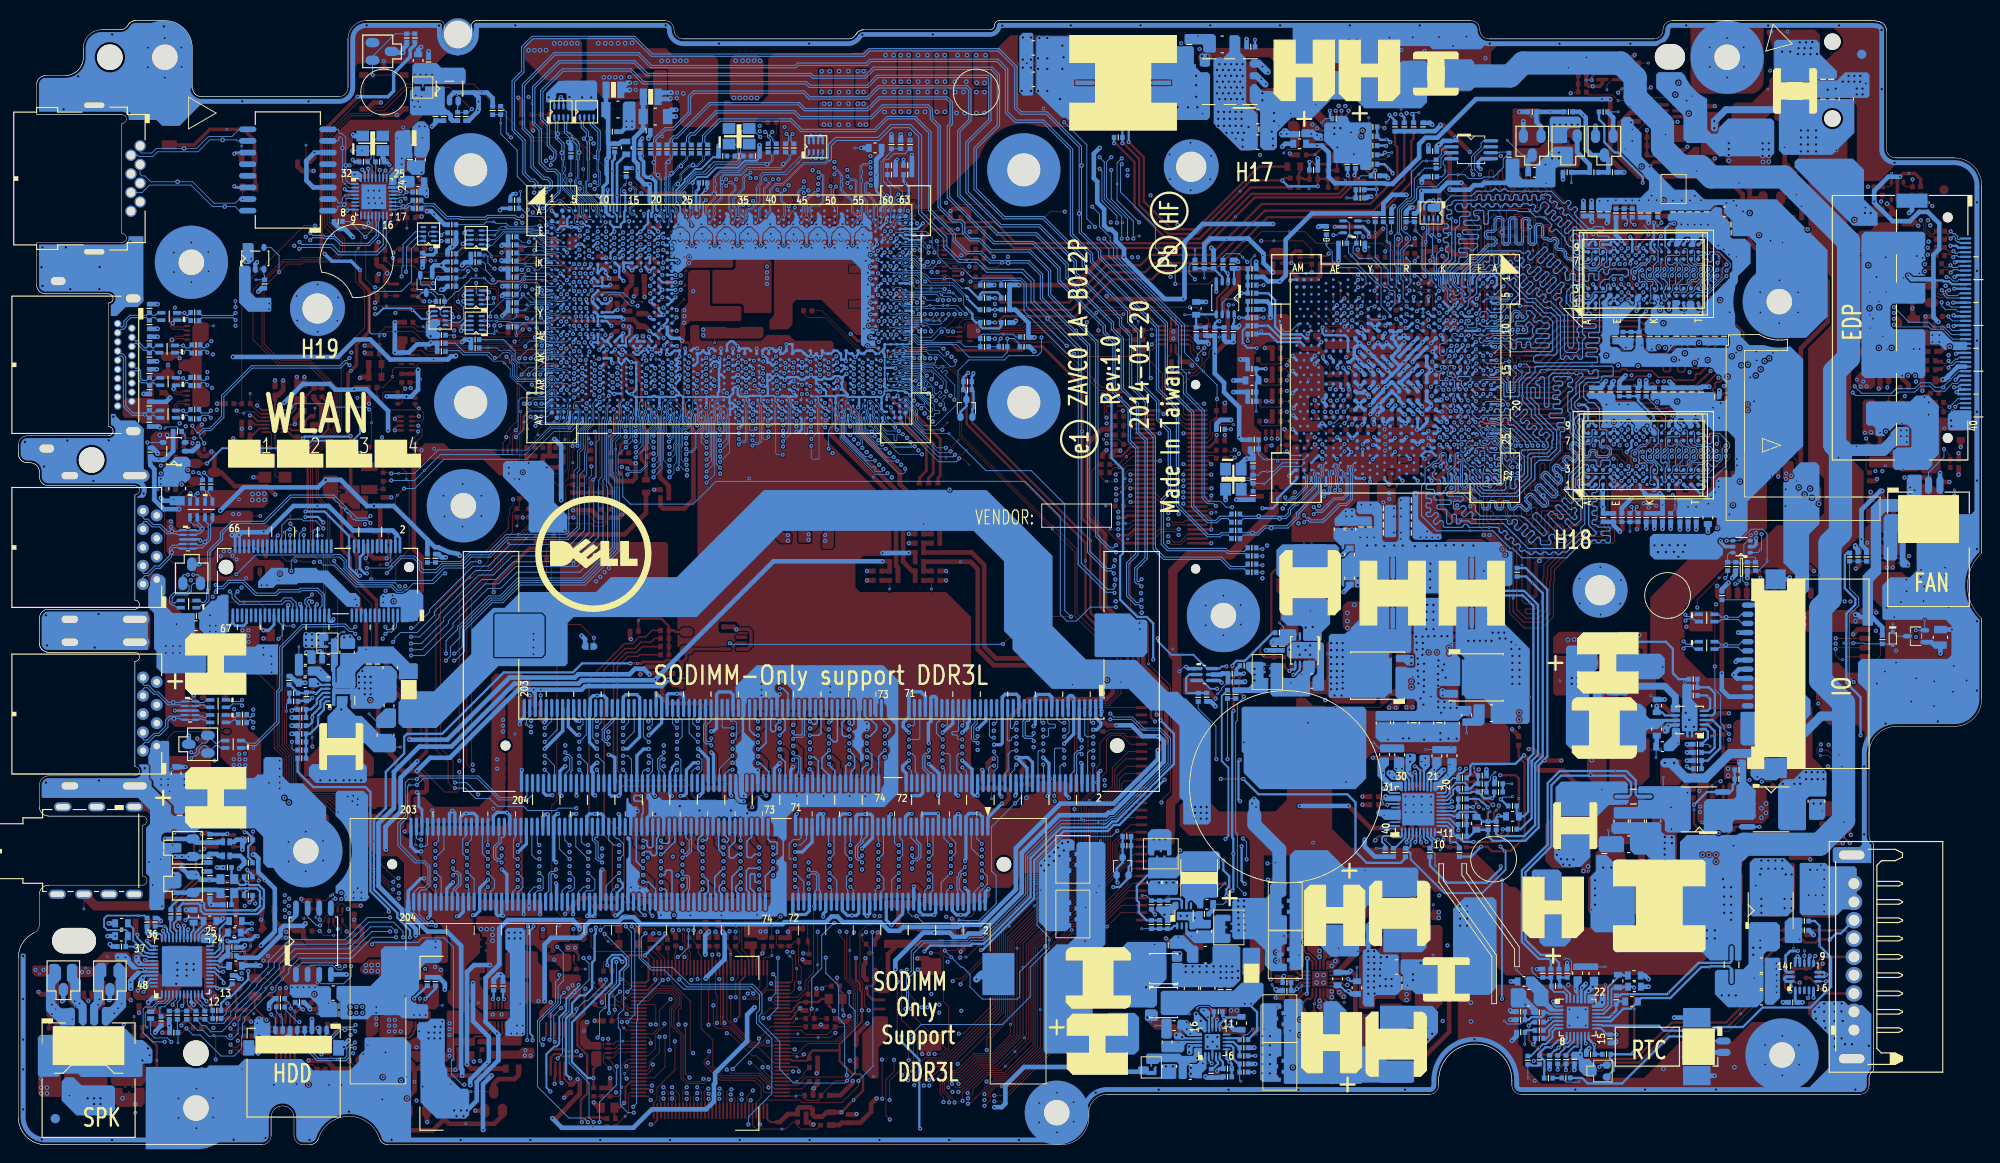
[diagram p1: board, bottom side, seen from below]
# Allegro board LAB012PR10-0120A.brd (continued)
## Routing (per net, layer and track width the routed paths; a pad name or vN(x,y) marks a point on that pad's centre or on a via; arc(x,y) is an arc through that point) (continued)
CFG3: length 43.9
  TOP w0.102: v2(92.97,70.92) 93.71,70.18 RC56.2 92.77,69.78 92.7,69.71 JXDP1.17 ; v1(113.77,90) 114.12,90.34 v2(114.12,90.74)
  IN2 w0.076: v2(114.12,90.74) 113.14,89.77 111.84,89.77 111.56,89.49
  IN2 w0.107: 111.56,89.49 109.15,87.08 103.08,87.08 98.99,82.99 98.99,76.26 96.58,73.84 93,73.84 92.39,73.23 92.39,71.51 v2(92.97,70.92)
  BOTTOM w0.076: UC1.AA63 117.38,90.23 117.2,90.23 117.16,90.19 114.68,90.19 v2(114.12,90.74)
CFG3_R: length 32.4
  TOP w0.102: v2(94.52,70.41) 94.54,70.41 94.62,70.34 RC56.1 v1(95.66,69.78) ; JXDP1.60 86.73,80.21 86.84,80.32 86.84,80.79 86.67,80.95 v2(84.9,80.95)
  IN1 w0.107: v2(84.9,80.95) 84.9,69.79 v2(84.13,69.02)
  IN2 w0.107: v2(84.13,69.02) 84.13,68.85 84.36,68.62 85.04,68.62 88.32,65.33 89.46,65.33 92.51,68.38 92.51,69.37 92.92,69.78 93.53,69.78 94.16,70.41 v2(94.52,70.41)
CFG4: length 43.5
  TOP w0.076: v2(119.16,89.99) 118.77,89.59 118.29,89.59 118.04,89.84 RC138.1
  TOP w0.102: v2(94.52,71.05) 94.16,71.05 v1(93.9,71.31) 93.53,71.68 93.53,71.81 93.17,72.17 92.64,72.17 92.59,72.21 JXDP1.27
  IN2 w0.076: v2(119.16,89.99) 118.79,89.61 114.89,89.61 114.36,89.08 114.36,88.57 113.98,88.19 111.94,88.19
  IN2 w0.107: 111.94,88.19 111.79,88.19 108.62,85.02 102.93,85.02 100.64,82.73 100.64,75.49 96.2,71.05 v2(94.52,71.05)
  BOTTOM w0.076: UC1.AA60 119.46,90.28 v2(119.16,89.99)
CFG5: length 39.7
  TOP w0.076: v1(116.26,91.24) 116.07,91.05 v2(116.07,90.74)
  TOP w0.102: JXDP1.29 92.83,72.71 v2(92.97,72.57)
  IN2 w0.076: v2(116.07,90.74) 115.48,90.16 114.2,90.16 113.38,89.34 112.15,89.34 111.56,88.75
  IN2 w0.107: v2(92.97,72.57) 93.45,72.09 96.1,72.09 100.13,76.13 100.13,82.99 102.8,85.65 108.46,85.65 111.56,88.75
  BOTTOM w0.076: UC1.Y62 117.92,91.11 117.63,90.82 117.32,90.82 117.09,90.58 116.23,90.58 v2(116.07,90.74)
CFG6: length 42.1
  TOP w0.102: JXDP1.33 93.15,73.71 93.53,73.33 v1(93.53,72.78) 93.53,72.34 94.19,71.68 v2(94.52,71.68)
  IN2 w0.076: 111.94,88.45 113.85,88.45 114.07,88.67 114.07,89.75 114.29,89.96 116.99,89.96 v2(118.51,91.48)
  IN2 w0.107: v2(94.52,71.68) 96.32,71.68 100.39,75.75 100.39,82.86 102.8,85.27 108.46,85.27 111.64,88.45 111.94,88.45
  BOTTOM w0.076: UC1.Y61 118.81,91.09 118.51,91.39 v2(118.51,91.48)
CFG7: length 41.1
  TOP w0.102: v1(115.12,90.12) 115.42,90.42 v2(115.42,90.74) ; JXDP1.35 93.26,74.21 94.02,73.45 94.33,73.45 v2(94.57,73.21)
  IN2 w0.076: 111.56,89.11 112.05,89.59 113.36,89.59 114.12,90.35 115.03,90.35 v2(115.42,90.74)
  IN2 w0.107: 111.56,89.11 108.49,86.03 102.67,86.03 99.75,83.11 99.75,76.13 97.08,73.46 94.83,73.46 v2(94.57,73.21)
  BOTTOM w0.076: v2(115.42,90.74) 115.81,90.35 117.09,90.35 117.13,90.39 117.13,90.39 117.39,90.65 117.7,90.65 117.87,90.82 118.46,90.82 118.55,90.73 119.12,90.73 UC1.Y60
CFG8: length 49.2
  TOP w0.102: v2(88.83,67.71) JXDP1.10
  IN2 w0.107: v2(111.52,90.74) 110.93,90.15 109.84,90.15 108.26,88.57 104.43,88.57 104.32,88.68 102.57,88.68 102.16,88.27 102.16,87.56 97.97,83.37 97.97,76.38 96.2,74.6 92.64,74.6 91.62,73.59 91.62,70.03 89.31,67.71 v2(88.83,67.71)
  BOTTOM w0.076: UC1.V62 117.97,91.67 117.7,91.4 115.4,91.4 115.37,91.37 v1(114.43,91.37) 112.15,91.37 v2(111.52,90.74)
CFG9: length 50.2
  TOP w0.102: JXDP1.12 86.92,68.21 87.14,68 88.45,68 v2(88.83,68.38)
  IN2 w0.107: v2(88.83,68.38) 89.34,68.38 91.37,70.41 91.37,73.72 92.51,74.86 96.07,74.86 97.72,76.51 97.72,83.62 101.81,87.71 101.81,88.32 102.47,88.98 104.5,88.98 104.65,88.83 108.13,88.83 110.04,90.73 v2(110.93,90.73)
  BOTTOM w0.076: v2(110.93,90.73) 111.89,91.7 v1(112.93,91.7) 115.01,91.7 115.14,91.57 117.63,91.57 117.8,91.74 117.8,91.91 118.04,92.15 118.56,92.15 UC1.V61
CFG10: length 56
  TOP w0.102: v2(87.69,68.89) 87.36,69.21 JXDP1.16 84.57,69.21 84.33,69.45 83.98,69.45 v1(83.62,69.09)
  IN2 w0.076: v2(119.16,91.48) 118.33,92.31 116.75,92.31 115.9,93.16 114.28,93.16 113.47,93.98 113.06,93.98 112.48,93.4 111.56,93.4
  IN2 w0.107: 111.56,93.4 110.17,93.4 108.92,94.64 105.26,94.64 102.11,91.5 101.91,91.5 92.13,81.72 92.13,77.4 90.48,75.75 89.21,75.75 87.4,73.94 86.8,73.94 86.42,73.56 86.42,70.16 v2(87.69,68.89)
  BOTTOM w0.076: v2(119.16,91.48) 119.46,91.78 UC1.V60
CFG11: length 49.2
  TOP w0.102: v2(116.26,92) 116.26,92.13 v1(115.88,92.51) ; v2(87.18,70.03) 86.86,69.71 JXDP1.18
  IN2 w0.076: 115.45,91.19 v2(116.26,92)
  IN2 w0.107: v2(87.18,70.03) 88.07,70.03 90.99,72.95 90.99,73.84 92.26,75.11 95.81,75.11 97.34,76.64 97.34,83.62 101.28,87.56 101.28,88.17 102.37,89.26 104.65,89.26 104.83,89.08 108.01,89.08 110.12,91.19 115.45,91.19
  BOTTOM w0.076: UC1.U60 119.17,92.28 118.69,92.28 118.65,92.32 117.87,92.32 117.7,92.15 117.32,92.15 117.14,92.33 116.59,92.33 v2(116.26,92)
CFG12: length 44.2
  TOP w0.102: JXDP1.28 86.9,72.21 v2(87.18,71.94)
  IN2 w0.107: v2(87.18,71.94) 87.81,71.94 94.8,78.92 94.8,83.24 102.16,90.61 104.55,90.61 107.17,93.22 108.87,93.22 109.85,92.25 111.53,92.25 v2(111.59,92.3)
  BOTTOM w0.076: UC1.T63 117.4,93.25 113.54,93.25 113.34,93.04 v1(112.33,93.04) v2(111.59,92.3)
CFG13: length 47.3
  TOP w0.102: JXDP1.30 87.04,72.71 v2(87.18,72.57) ; v2(113.41,92.26) v1(113.41,91.68)
  IN2 w0.076: 111.56,93.07 112.65,93.07 113.41,92.3 v2(113.41,92.26)
  IN2 w0.107: v2(87.18,72.57) 86.67,73.08 86.67,73.46 86.85,73.64 87.48,73.64 89.34,75.49 90.61,75.49 92.39,77.27 92.39,81.59 102.04,91.24 103.08,91.24 106.2,94.37 108.64,94.37 109.94,93.07 111.56,93.07
  BOTTOM w0.076: UC1.T62 117.69,92.89 117.4,92.89 114.12,92.89 113.49,92.26 v2(113.41,92.26)
CFG14: length 45.8
  TOP w0.102: v2(87.18,73.21) 87.18,73.53 87,73.71 JXDP1.34
  IN2 w0.076: 111.8,92.76 112.19,92.38 v2(112.19,92.29)
  IN2 w0.107: v2(87.18,73.21) 87.31,73.33 87.56,73.33 89.46,75.24 90.73,75.24 92.64,77.14 92.64,81.46 102.04,90.86 104.45,90.86 107.07,93.48 109,93.48 109.71,92.76 111.8,92.76
  BOTTOM w0.076: UC1.T61 118.56,93.65 118.04,93.65 117.8,93.41 117.8,93.25 117.62,93.06 113.81,93.06 v1(113.58,92.84) 113.43,92.68 112.98,92.68 112.98,92.69 112.95,92.69 112.61,92.69 112.59,92.69 v2(112.19,92.29)
CFG15: length 46.8
  TOP w0.102: JXDP1.36 86.92,74.21 87.05,74.35 v2(87.18,74.35)
  IN2 w0.076: v2(119.16,92.98) 118.79,92.61 117.03,92.61 116.93,92.71 116.92,92.71 116.12,93.51 114.63,93.51 113.85,94.3 113.06,94.3 112.42,93.65 111.56,93.65
  IN2 w0.107: 111.56,93.65 110.39,93.65 109.1,94.95 104.98,94.95 91.75,81.72 91.75,77.4 90.35,76 89.08,76 87.43,74.35 v2(87.18,74.35)
  BOTTOM w0.076: v2(119.16,92.98) 119.46,93.28 UC1.T60
CFG16: length 50.4
  TOP w0.102: JXDP1.6 86.69,66.71 87.56,65.84 88.19,65.84 v2(88.83,66.48)
  IN2 w0.076: v2(112.82,90.73) 112.24,90.15 111.56,90.15
  IN2 w0.107: 111.56,90.15 111.44,90.15 108.85,87.57 102.68,87.57 98.29,83.18 98.29,76.32 96.32,74.35 92.77,74.35 91.88,73.46 91.88,69.65 88.83,66.6 v2(88.83,66.48)
  BOTTOM w0.076: UC1.AA62 118.1,90.3 118.1,90.3 118.08,90.28 118.08,90.22 117.75,89.89 117.34,89.89 117.23,89.78 115.2,89.78 115.05,89.63 113.69,89.63 v1(113.12,90.2) 112.82,90.5 v2(112.82,90.73)
CFG17: length 51.2
  TOP w0.102: v2(88.83,65.84) 88.58,65.59 87.43,65.59 86.81,66.21 JXDP1.4
  IN2 w0.076: 111.56,89.89 111.63,89.96 112.69,89.96 v2(113.47,90.74)
  IN2 w0.107: 111.56,89.89 108.98,87.31 102.93,87.31 98.74,83.11 98.74,76.38 96.45,74.1 92.89,74.1 92.13,73.33 92.13,69.14 v2(88.83,65.84)
  BOTTOM w0.076: v2(113.47,90.74) 113.47,90.61 114.08,90 v1(114.42,90) 117.21,90 117.27,90.06 117.68,90.06 117.87,90.24 117.87,90.48 118.04,90.65 118.36,90.65 118.61,90.4 UC1.AA61
CFG18: length 44.8
  TOP w0.102: JXDP1.24 87.09,71.21 v2(87.18,71.3)
  IN2 w0.107: v2(114,92.26) 113.48,91.74 109.92,91.74 108.74,92.92 107.45,92.92 104.55,90.02 101.96,90.02 95.05,83.11 95.05,78.67 90.23,73.84 90.23,73.21 88.32,71.3 v2(87.18,71.3)
  BOTTOM w0.076: UC1.U63 117.44,92.61 117.33,92.71 115.65,92.71 v1(115.45,92.51) 115.2,92.26 v2(114,92.26)
CFG19: length 47.7
  TOP w0.076: v2(115.63,92) 115.32,91.7 v1(114.84,91.7)
  TOP w0.102: v2(87.18,70.71) JXDP1.22
  IN2 w0.076: 111.56,91.48 115.1,91.48 v2(115.63,92)
  IN2 w0.107: 111.56,91.48 110.02,91.48 107.88,89.34 105.04,89.34 104.86,89.51 102.19,89.51 100.95,88.27 100.95,87.61 96.96,83.62 96.96,76.64 95.69,75.37 92.13,75.37 90.61,73.84 90.61,73.21 88.11,70.71 v2(87.18,70.71)
  BOTTOM w0.076: UC1.U62 117.92,92.61 117.8,92.48 117.8,92.48 117.63,92.32 117.39,92.32 117.18,92.53 116.15,92.53 v2(115.63,92)
CFG_RCOMP: length 2.3
  TOP w0.102: v1(117.56,91.75) 117.37,91.94 v2(116.93,91.94)
  TOP w0.305: v2(116.93,91.94) 116.82,92.06 RC132.1
  BOTTOM w0.305: v2(116.93,91.94) 117.02,91.86 UC1.V63
CHG_B+:
  vias: v1(46.04,36.16) v3(44.58,31.16) v3(44.88,34.23) v3(45.01,30.54) v3(45.26,31.16) v3(45.6,34.19) v3(45.69,30.61) v3(45.94,31.21) v3(46.16,33.57) v3(46.17,32.92) v3(46.17,32.28) v3(46.28,34.24) v3(46.4,31.67)
CLK_BIASREF: length 15
  TOP w0.381: v2(141.66,103.94) 145.6,103.94 146.26,104.6 v4(146.26,108.03) v2(146.26,109.94)
  BOTTOM w0.089: 141.04,102.38 141.03,102.36 141.03,101.71 141.13,101.61 141.13,101.22 141.19,101.15 141.19,100.98 141.16,100.95 141.16,100.94 140.99,100.76 140.98,100.76 140.86,100.65 UC1.C26
  BOTTOM w0.305: v2(141.66,103.94) 141.66,103.43 141.04,102.81 141.04,102.38
  BOTTOM w0.381: v2(146.26,109.94) 146.49,109.71 RC13.1
CLK_CPU_ITP: length 76.5
  TOP w0.112: RC139.2 82.35,74.99 82.02,75.32 81.82,75.32 v2(81.57,75.06)
  IN2 w0.076: 111.56,98.87 111.71,98.87 111.79,98.95 112.9,98.95 113.07,99.12 114.99,99.12 115.53,98.57 117.34,98.57 118.24,97.67 118.75,97.67 119.47,98.39 120.11,98.39 120.58,98.86 124.01,98.86 124.35,98.52 124.35,97.9 125.08,97.17 131.57,97.17 132.3,97.9 132.3,98.54 133.83,100.06 133.83,101.26 v2(135.24,102.67)
  IN2 w0.114: 111.56,98.87 104.97,98.87 90.1,84 90.1,79.47 86.93,76.31 86.34,76.31 85.32,75.29 81.8,75.29 v2(81.57,75.06)
  BOTTOM w0.076: UC1.A35 135.22,101.97 135.22,101.78 135.34,101.66 135.46,101.66 135.59,101.79 135.59,102.54 135.69,102.65 135.69,103.07 135.58,103.19 135.07,103.19 135.01,103.13 135.01,102.89 v2(135.24,102.67)
CLK_CPU_ITP#: length 76.5
  TOP w0.112: RC140.2 82.25,75.87 82.02,75.65 81.85,75.65 v2(81.57,75.92)
  IN2 w0.076: 111.56,99.2 111.71,99.2 111.79,99.12 112.83,99.12 113,99.28 115.06,99.28 115.6,98.73 117.41,98.73 118.31,97.83 118.68,97.83 119.41,98.56 120.04,98.56 120.51,99.03 124.08,99.03 124.52,98.59 124.52,97.97 125.15,97.34 131.5,97.34 132.14,97.97 132.14,98.61 133.66,100.13 133.66,101.71 v2(134.63,102.67)
  IN2 w0.114: 111.56,99.2 104.83,99.2 89.77,84.14 89.77,79.61 86.8,76.64 86.2,76.64 85.19,75.62 81.87,75.62 v2(81.57,75.92)
  BOTTOM w0.076: v2(134.63,102.67) 134.85,102.89 134.85,103.2 135,103.35 135.65,103.35 135.86,103.14 135.86,102.58 135.75,102.48 135.75,101.7 135.54,101.49 135.38,101.49 UC1.B35
CLK_PCI_LPC: length 134
  TOP w0.076: v2(151.82,74.1) 151.9,74.17 R2336.1
  TOP w0.102: UE1.12 129.88,13.31 v1(129.42,13.77) R2354.2 127.91,14.27 127.91,14.69 v2(127.76,14.84)
  IN2 w0.107: v2(173.47,54.92) 173.95,54.44 173.95,45.96 174.23,45.68 174.23,34.27 173.82,33.86 173.82,31.6 174.43,30.99 174.43,23.23 173.35,22.15 170.29,22.15 169.34,23.11 165.96,23.11 165.02,24.04 159.78,24.04 159.09,23.35 157.98,23.35 157.29,24.04 153.31,24.04 152.78,24.57 152.13,24.57 151.14,25.56 126.55,25.56 125.3,24.31 v2(125.3,24.23)
  BOTTOM w0.076: v2(151.82,74.1) 151.82,73.08 152.08,72.83 152.08,71.81
  BOTTOM w0.102: v2(127.76,14.84) 127.76,18.21 126.67,19.3 126.67,22.88 125.3,24.24 v2(125.3,24.23) ; v2(173.47,54.92) 173.28,55.11 173.28,55.35 172.68,55.96 170.85,55.96 168.97,57.84 168.97,58.22 164.47,62.72 162.82,62.72 160.71,64.83 154.11,64.83 152.08,66.86 152.08,71.81
CLK_PCIE_LAN: length 91.4
  IN2 w0.076: 130.57,107.37 130.65,107.29 130.65,105.17 131.03,104.8 131.03,104.65 v2(130.7,104.32)
  IN2 w0.114: v2(183.7,98.62) 183.49,98.4 180.98,98.4 177.93,101.45 177.93,105.03 177.02,105.95 173.89,105.95 173.18,106.66 172.32,106.66 172.09,106.89 172.09,110.85 170.87,112.07 170,112.07 168.09,113.97 163.76,113.97 161.14,116.59 151.2,116.59 149.42,114.81 144.53,114.81 143.57,113.85 133.13,113.85 131.25,111.97 131.25,109.62 130.57,108.94 130.57,107.37
  BOTTOM w0.076: UC1.B42 130.83,101.17 130.74,101.26 130.74,101.32 130.64,101.41 130.64,102.81 130.99,103.16 130.99,104.03 v2(130.7,104.32)
  BOTTOM w0.112: v2(183.7,98.62) 183.44,98.35 180.15,98.35 179.33,97.54 175.33,97.54 174.55,98.31 174.55,100.88 174.57,100.89 UL1.15
CLK_PCIE_LAN#: length 91.9
  IN2 w0.076: 130.9,107.37 130.9,107.35 130.82,107.26 130.82,105.24 131.19,104.86 131.19,104.65 v2(131.52,104.32)
  IN2 w0.114: v2(183.72,97.87) 183.52,98.07 180.84,98.07 177.6,101.32 177.6,104.9 176.88,105.62 173.76,105.62 173.05,106.33 172.18,106.33 171.76,106.75 171.76,110.71 170.73,111.74 169.86,111.74 167.95,113.64 163.62,113.64 161.01,116.26 151.34,116.26 149.56,114.48 144.67,114.48 143.7,113.52 133.26,113.52 131.58,111.83 131.58,109.48 130.9,108.81 130.9,107.37
  BOTTOM w0.076: UC1.C41 131.15,100.98 131.15,101.2 130.81,101.54 130.81,102.74 131.16,103.09 131.16,103.96 v2(131.52,104.32)
  BOTTOM w0.112: v2(183.72,97.87) 183.59,97.87 183.44,98.02 180.28,98.02 179.47,97.21 175.19,97.21 174.22,98.18 174.22,100.84 174.17,100.9 UL1.16
CLK_PCIE_WLAN: length 128.8
  IN2 w0.076: v2(132.82,105.47) 132.77,105.47 132.49,105.74 132.49,107.27 132.58,107.35 132.58,107.37
  IN2 w0.114: 132.58,107.37 132.58,107.67 132.71,107.8 141.79,107.8 146.31,112.32 150.35,112.32 151.65,113.62 159.97,113.62 163.04,110.55 167.05,110.55 168.9,108.7 168.9,105.75 170.31,104.34 170.31,103.42 172.21,101.53 173.27,101.53 175.75,99.05 175.75,98.85 179.35,95.25 184.22,95.25 187.44,92.04 187.44,84.72 188.51,83.65 188.51,82.2 189.02,81.69 189.02,80.51 190,79.53 192.39,77.14 192.39,75.47 193.01,74.84 195.72,74.84 197.35,73.21 197.35,69.21 195.05,66.91 194.16,66.91 193.53,66.29 191.35,66.29 189.79,64.73 189.79,61.88 190.79,60.89 190.79,60.53 190.68,60.43 v2(190.46,60.43)
  BOTTOM w0.076: v2(132.82,105.47) 132.49,105.14 132.49,105.03 133.03,104.49 133.03,102.8 133.57,102.26 133.57,101.27 133.71,101.14 133.71,100.93 UC1.C37
  BOTTOM w0.112: v2(190.46,60.43) 190.73,60.15 190.73,59.88 190.22,59.36 185.74,59.36 185.36,59.75 184.59,59.75 184.06,59.22 184.06,58.86 183.98,58.78 JNGFF.39
CLK_PCIE_WLAN#: length 129.2
  IN2 w0.076: v2(132,105.47) 132.33,105.79 132.33,107.27 132.24,107.35 132.24,107.37
  IN2 w0.114: v2(191.31,60.43) 191.12,60.63 191.12,61.03 190.13,62.02 190.13,64.6 191.48,65.96 193.67,65.96 194.29,66.58 195.19,66.58 197.68,69.07 197.68,73.35 195.86,75.17 193.15,75.17 192.72,75.6 192.72,77.28 190.23,79.76 189.35,80.65 189.35,81.83 188.84,82.34 188.84,83.79 187.77,84.86 187.77,92.17 184.36,95.58 179.48,95.58 176.08,98.99 176.08,99.19 173.41,101.86 172.35,101.86 170.64,103.56 170.64,104.47 169.23,105.89 169.23,108.83 167.19,110.88 163.18,110.88 160.1,113.95 151.51,113.95 150.21,112.65 146.17,112.65 141.65,108.13 132.57,108.13 132.24,107.81 132.24,107.37
  BOTTOM w0.076: v2(132,105.47) 132.33,105.14 132.33,104.96 132.86,104.42 132.86,102.73 133.4,102.19 133.4,101.13 UC1.B38
  BOTTOM w0.112: v2(191.31,60.43) 191.06,60.18 191.06,59.75 190.35,59.03 185.6,59.03 185.22,59.41 184.72,59.41 184.39,59.08 184.39,58.86 184.48,58.78 JNGFF.41
CLK_PEG_VGA: length 116.7
  IN2 w0.102: v2(76.04,70.02) 76.22,70.19 76.88,70.19 77.04,70.03 77.04,70.02 77.12,69.94 77.12,69.88 77.23,69.78
  IN2 w0.114: v2(94.68,60.28) 94.59,60.38 94.04,60.38 91.83,62.59 91.04,62.59 89.77,61.32 85.64,61.32 84.63,62.34 82.85,62.34 81.39,63.8 81.39,66.47 79.52,68.33 78.65,68.33 77.23,69.75 77.23,69.78
  BOTTOM w0.076: UC1.B39 132.78,101.55 132.7,101.63 132.54,101.63 132.37,101.8 132.37,101.83 132.23,101.97 132.23,104.23 131.63,104.83 130.89,104.83 128.58,107.14 126.24,107.14 125.91,107.47 125.88,107.47 125.87,107.48 125.86,107.48
  BOTTOM w0.102: v2(76.04,70.02) 75.88,70.18 75.65,70.18 75.24,70.59 74.85,70.59 73.64,71.8 73.64,73.05 74,73.41 UV1.AK30
  BOTTOM w0.112: v2(94.68,60.28) 94.75,60.35 95.62,60.35 98.66,63.39 98.66,86.89 v3(102.02,90.25) 103.82,92.04 103.82,94.29 104.83,95.31 108.65,95.31 109.73,96.39 111.72,96.39 113.34,98.01 113.34,98.99 116.08,101.73 116.08,110.11 117.07,111.1 119.01,111.1 120.4,109.71 125.04,109.71 125.61,109.14 125.61,107.65 125.78,107.48 125.86,107.48
CLK_PEG_VGA#: length 116.6
  IN2 w0.102: v2(76.04,70.71) 76.04,70.48 76.13,70.4 76.96,70.4 77.25,70.11
  IN2 w0.114: v2(94.68,61.14) 94.68,60.81 94.58,60.71 94.17,60.71 91.96,62.92 90.9,62.92 89.63,61.65 85.78,61.65 84.77,62.67 82.99,62.67 81.72,63.94 81.72,66.6 79.66,68.66 78.79,68.66 77.56,69.89 77.56,69.92 77.37,70.11 77.25,70.11
  BOTTOM w0.076: 126.1,107.62 126.1,107.52 126.31,107.31 128.64,107.31 130.96,105 131.7,105 132.39,104.3 132.39,102.04 132.53,101.9 132.53,101.87 132.61,101.79 132.7,101.79 132.78,101.87 UC1.A39
  BOTTOM w0.102: UV1.AK32 73.84,72.74 73.84,71.89 74.94,70.79 75.33,70.79 75.73,70.39 75.95,70.39 76.04,70.48 v2(76.04,70.71)
  BOTTOM w0.112: v2(94.68,61.14) 94.68,60.79 94.79,60.68 95.48,60.68 98.33,63.53 98.33,87.02 103.49,92.18 103.49,94.43 104.69,95.64 108.51,95.64 109.6,96.72 111.58,96.72 113.01,98.15 113.01,99.13 115.75,101.87 115.75,110.25 116.94,111.43 119.14,111.43 120.54,110.04 125.18,110.04 125.94,109.28 125.94,107.78 126.1,107.62
CLK_SMB: length 8.7
  TOP w0.102: v1(20.55,21.44) PR18.1
  TOP w0.254: PR18.1 19.59,22.41 19.28,22.1 18.08,22.1 PD2.3 v2(16.57,22.41)
  BOTTOM w0.254: v2(16.57,22.41) 16.55,22.41 15.89,23.08 15.39,23.08 PBATT.7
CLK_X1: length 4.2
  TOP w0.102: UG1.1 186.94,77.85 186.75,77.65 186.75,76.31 CG8.1 186.92,75.06 YG1.1
CLK_X2: length 5.9
  TOP w0.102: YG1.3 186.2,72.92 186.37,73.08 186.37,75.24 186.06,75.54 CG9.1 186.37,76.43 UG1.16
CLK_XDP: length 2.2
  TOP w0.112: RC139.1 83.89,75.3 84.43,75.3 84.51,75.21 JXDP1.40
CLK_XDP#: length 2.2
  TOP w0.112: RC140.1 83.82,75.63 84.43,75.63 84.51,75.71 JXDP1.42
CLKOUT_LPC0: length 11
  TOP w0.076: R2336.2 151.9,76.56 v2(151.82,76.64) 151.82,76.86 v1(152.1,77.14)
  IN2 w0.076: v2(151.82,76.64) 151.44,76.64 150.3,77.78 150.3,78.92 149.66,79.56 149.54,79.56 148.9,80.19 148.9,81.21 147.41,82.7 v2(147.41,83.36)
  BOTTOM w0.076: UC1.AN15 147.69,83.63 v2(147.41,83.36)
CLKRUN#: length 7.1
  TOP w0.076: RC36.2 v1(158.86,91.75) 158.48,92.13 153.92,92.13 v2(153.68,92.36)
  BOTTOM w0.076: UC1.V5 153.5,92.19 v2(153.68,92.36)
CODEC_IRQ: length 16.3
  IN1 w0.076: v2(153.73,96.21) 154.1,96.21 155.65,97.76
  IN1 w0.127: 155.65,97.76 156.88,98.99 156.9,98.99 157.49,99.57 v2(157.49,100.39)
  BOTTOM w0.076: v2(157.49,100.39) 158.04,100.39 158.15,100.28 160.76,100.28 160.86,100.39 ; v2(153.73,96.21) 154.19,95.75 UC1.L4
  BOTTOM w0.102: RC88.1 163.58,100.51 163.28,100.82 v1(162.5,100.82) 162.4,100.82 162.24,100.66 161.14,100.66 160.86,100.39
COMP: length 5.8
  TOP w0.254: PU501.6 68.28,108.79 67.87,108.39 67.87,108.01 66.99,107.12 PR539.2 66.92,107.12 66.24,106.43 v2(66.21,106.43)
  BOTTOM w0.102: PC531.2 67.77,105.85 v1(68.03,105.59)
  BOTTOM w0.254: PC531.2 66.68,105.96 v2(66.21,106.43)
CPPE#: length 4
  BOTTOM w0.076: RC108.2 159.79,97.22 v1(158.1,97.22) 157.04,97.22 157.02,97.2 156.28,97.2 UC1.J1
CPU_DPB_AUX: length 12.4
  BOTTOM w0.076: UC1.B5 153.03,101.39 153.09,101.45 153.09,102.78 154.84,104.53 154.84,104.7 154.69,104.86 154.69,105.15 154.84,105.3 154.84,105.47 154.69,105.62 154.69,105.92 154.84,106.07 154.84,106.25 154.69,106.4 154.69,106.71 154.84,106.86 154.84,107.56 154.8,107.61 154.8,107.62
  BOTTOM w0.112: RP51.2 155.37,111.9 155.5,111.77 v3(155.5,110.44) 155.5,110.08 154.8,109.38 154.8,107.62
CPU_DPB_AUX#: length 12.5
  BOTTOM w0.076: 155.06,107.62 155.06,107.61 155.01,107.57 155.01,104.46 153.26,102.72 153.26,101.54 153.29,101.51 153.29,100.91 UC1.C5
  BOTTOM w0.112: RP51.1 155.87,111.94 155.75,111.82 155.75,109.97 155.06,109.28 v3(155.06,108.36) 155.06,107.62
CPU_DPB_CTRLCLK: length 77.6
  TOP w0.112: QX4.1 v2(195.4,78.54)
  IN2 w0.114: v2(178.24,85.94) 178.04,85.75 177.73,85.75 177.47,86.01 177.47,87.69 176.2,88.96 176.2,92.26 171.35,97.11 171.35,97.31 168.18,100.48 167.5,100.48 166.28,101.71 163.2,101.71 160.28,104.63 160.28,106.63 159.41,107.5 159.41,108.77 157.44,110.74 152.63,110.74 152.21,110.32 152.21,110.12 152.01,109.92 v2(151.86,109.92)
  BOTTOM w0.076: 152.02,107.62 152.02,107.61 152.03,107.61 152.07,107.61 152.07,107.6 152.07,105.37 152.33,105.1 152.33,104.14 151.15,102.96 151.15,102.55 150.97,102.37 150.97,101.77 150.6,101.39 UC1.B9
  BOTTOM w0.112: v2(178.24,85.94) 178.53,85.66 178.74,85.66 179.3,85.09 188.96,85.09 192.21,81.84 192.21,79.56 193.5,78.26 194.19,78.26 194.66,77.8 194.73,77.75 194.88,77.78 v2(195.4,78.54) ; 152.02,107.62 152.02,109.52 152.07,109.57 152.07,109.71 v2(151.86,109.92) 152.12,110.18 152.12,110.68 152.69,111.24 152.69,111.77 152.58,111.88 RP52.2
CPU_DPB_CTRLCLK_R: length 14.1
  TOP w0.112: RX16.1 196.35,76.74 196.16,76.93 195.55,76.93 195.4,76.78 v2(195.4,76.64) QX4.6
  IN2 w0.114: JHDMI.15 202.88,82.03 202.88,80.26 202.44,79.82 199.45,79.82 196.45,76.82 195.46,76.82 195.4,76.75 v2(195.4,76.64)
CPU_DPB_CTRLDAT: length 77.5
  TOP w0.112: QX4.4 v2(194.1,76.62)
  IN2 w0.114: v2(178.24,85.16) 178.24,85.42 178.16,85.5 177.63,85.5 177.22,85.91 177.22,87.59 175.95,88.86 175.95,92.16 171.11,97.01 171.11,97.21 168.08,100.23 167.4,100.23 166.17,101.46 163.1,101.46 160.03,104.52 160.03,106.53 159.16,107.4 159.16,108.67 157.33,110.49 152.73,110.49 152.46,110.22 152.46,110.1 v2(152.64,109.92)
  BOTTOM w0.076: 152.28,107.62 152.28,107.58 152.23,107.53 152.23,105.43 152.49,105.17 152.49,104.08 151.31,102.89 151.31,102.48 151.14,102.3 151.14,101.7 150.79,101.35 UC1.C9
  BOTTOM w0.112: RP52.1 153.08,111.96 152.94,111.82 152.94,111.13 152.38,110.57 152.38,110.18 v2(152.64,109.92) 152.33,109.6 152.33,109.46 152.28,109.42 152.28,107.62 ; v2(178.24,85.16) 178.48,85.4 178.64,85.4 179.2,84.84 188.85,84.84 191.95,81.74 191.95,79.45 193.39,78.01 194.08,78.01 194.49,77.6 194.52,77.58 194.58,77.54 194.61,77.38 v2(194.1,76.62)
CPU_DPB_CTRLDAT_R: length 13.8
  TOP w0.112: RX17.1 196.01,77.18 v2(195.19,77.18) 194.45,77.18 194.1,77.54 QX4.3
  IN2 w0.114: JHDMI.16 202.63,81.57 202.63,80.36 202.33,80.07 199.35,80.07 196.35,77.07 195.31,77.07 v2(195.19,77.18)
CPU_DPC_AUX: length 11.5
  BOTTOM w0.076: UC1.A6 152.39,102.93 153.66,104.2 153.66,105.36 153.35,105.67 153.35,107.56 153.4,107.61 153.4,107.62
  BOTTOM w0.112: RP51.3 154.87,111.91 154.77,111.81 154.77,110.59 v3(154.01,109.83) 153.4,109.22 153.4,107.62
CPU_DPC_AUX#: length 12.4
  BOTTOM w0.076: UC1.B6 152.02,102.79 153.5,104.27 153.5,105.29 153.19,105.6 153.19,107.56 153.14,107.61 153.14,107.62
  BOTTOM w0.112: 153.14,107.62 v3(153.14,108.41) 153.14,109.33 153.24,109.43 153.24,109.58 153.52,109.86 153.68,109.86 153.93,110.11 153.93,110.27 154.18,110.51 154.33,110.51 154.51,110.69 154.51,111.72 154.37,111.86 RP51.4
CPU_DPC_CTRLCLK: length 15.2
  IN2 w0.076: 150.15,101.78 150.15,101.76 150.19,101.72 150.19,101.47 150.5,101.16 150.5,100.92 150.35,100.78 v2(150.26,100.78)
  IN2 w0.114: 150.15,101.78 150.15,102.91 150.48,103.24 150.48,104.55 150.81,104.87 151.35,104.87 151.46,104.99 v2(151.46,105.16)
  BOTTOM w0.076: v2(151.46,105.16) 151.46,105.08 151.25,104.87 151.1,104.87 151.02,104.95 151.02,106.23 151.21,106.41 151.21,107.57 151.25,107.61 151.25,107.62 ; v2(150.26,100.78) 150.78,100.25 UC1.D9
  BOTTOM w0.112: RP52.3 152.08,111.81 151.95,111.68 151.95,111.46 151.11,110.62 151.11,108.74 151.25,108.6 151.25,107.62
CPU_DPC_CTRLDAT: length 15.3
  IN2 w0.076: v2(150.2,99.76) 150.2,100.19 150.67,100.65 150.67,101.23 150.36,101.53 150.36,101.72 150.4,101.76 150.4,101.78
  IN2 w0.114: v2(151.46,104.42) 151.26,104.62 150.91,104.62 150.73,104.45 150.73,103.13 150.4,102.8 150.4,101.78
  BOTTOM w0.076: v2(150.2,99.76) 150.23,99.76 150.23,99.77 150.23,100.2 150.28,100.25 UC1.D11 ; 151,107.62 151,107.61 151.04,107.57 151.04,106.48 150.86,106.3 150.86,104.88 151.03,104.71 151.17,104.71 v2(151.46,104.42)
  BOTTOM w0.112: RP52.4 151.58,111.81 151.69,111.7 151.69,111.57 150.85,110.73 150.85,108.64 151,108.49 151,107.62
CPU_EDP_HPD#: length 20.5
  BOTTOM w0.076: 157.68,102.02 157.5,101.85 156.86,101.85 155.49,103.21 155.11,103.21 154.27,102.38 154.12,102.38 153.92,102.17 153.92,101.85 153.66,101.59 153.66,100.72 153.49,100.55 153.31,100.55 153.01,100.25 UC1.D6
  BOTTOM w0.102: RC89.1 RC82.2 161.72,112.51 v1(161.72,111.6) 161.72,110.43 159.92,108.64 159.92,105.8 158.93,104.8 158.93,103.28 157.68,102.02
CPU_PWR_DEBUG#: length 56.9
  TOP w0.102: RC50.1 95.43,76.51 v2(95.56,76.64)
  IN1 w0.076: v2(120.54,97.67) 120.54,97.3 119.94,96.7 116.64,96.7 113.98,94.04 112.45,94.04 110.04,91.62 110.04,88.64 109.01,87.61 108.13,87.61
  IN1 w0.107: 108.13,87.61 100.89,87.61 99.7,86.42 v2(99.12,86.42)
  IN2 w0.107: v2(99.12,86.42) 96.58,83.88 96.58,77.65 v2(95.56,76.64)
  BOTTOM w0.076: v2(120.54,97.67) 120.32,97.89 UC1.H59
  BOTTOM w0.102: 107.07,94.24 107.19,94.37 109.2,94.37 109.35,94.21 R255.2 ; 107.07,94.24 R253.1 ; 107.07,94.24 106.89,94.42 105.01,94.42 104.58,93.98 104.58,91.06 v1(103.97,90.45) 99.93,86.42 v2(99.12,86.42)
CPU_PWR_DEBUG#_R: length 4.8
  TOP w0.102: v1(95.89,77.07) 94.27,77.07 RC50.2 93.02,76.51 92.82,76.71 JXDP1.45
CPUSB#: length 5.5
  BOTTOM w0.076: RC111.2 159.71,96.24 v1(159.06,96.24) 157.97,96.24 157.75,96.03 155.16,96.03 UC1.K3
CS1: length 4.4
  TOP w0.102: v1(76.94,15.07) 76.41,15.07 PR105.1
  TOP w0.203: PU100.1 74.2,17.31 74.3,17.21 74.3,16.77 75.01,16.06 PR105.1
CS2: length 4.2
  TOP w0.203: 74.87,21.65 74.87,21.59 74.13,20.86 74.13,20.03 74.27,19.89 74.27,18.99 74.2,18.91 PU100.5
  TOP w0.254: 74.87,21.65 74.87,21.65 75.11,21.9 75.29,21.9 75.3,21.89 PR108.1
CS_1.35V: length 4
  BOTTOM w0.102: v1(85.68,14.86) 85.45,15.09 84.38,15.09 PR205.2
  BOTTOM w0.254: PU200.13 84,13.85 83.83,14.03 PR205.2
CSIN: length 6.7
  BOTTOM w0.102: v1(45.54,20.32) 45.11,20.32 44.79,20 44.79,18.75 PC708.1
  BOTTOM w0.203: PU701.27 44.93,16.48 45.73,17.28 46.03,17.28 PC717.2
  BOTTOM w0.254: PC708.1 PR704.1 46.16,17.96 46.08,17.89 PC717.2
CSIP: length 6.3
  BOTTOM w0.102: v1(49.1,19.28) 49.1,18.93 48.44,18.27 PC707.1
  BOTTOM w0.203: PU701.28 45.33,16.37 45.65,16.69 46.67,16.69 47,17.02 PC717.1
  BOTTOM w0.254: PC707.1 PR717.1 47,18.22 PC717.1
CSON: length 18.2
  BOTTOM w0.203: 41.36,13.5 PU701.17
  BOTTOM w0.254: 41.36,13.5 40.49,13.5 39.12,14.86 38.32,14.86 PC722.2 37.17,16.02 34,16.02 30.61,19.41 v1(29.67,19.41) 29.67,19.42 29.61,19.49 27.6,19.49 27.31,19.19 PR716.3
CSOP: length 4.3
  BOTTOM w0.203: PU701.18 41.15,13.9
  BOTTOM w0.254: 41.15,13.9 40.67,13.9 v1(40.35,14.22) 39.91,14.66 PR708.1 39.63,15.65 PC722.1
DAT_SMB: length 7
  TOP w0.254: PBATT.6 14.85,23.42 v1(16.59,23.42) PD2.2 17.78,23.42 PR20.1
DBC_EN: length 216.4
  TOP w0.102: v2(129.8,8) 129.9,8.11 UE1.25 ; v1(12.22,90.66) RX23.1 v2(11.18,91.47)
  IN1 w0.107: v2(11.18,91.47) 10.98,91.67 10.98,95.43 12.63,97.08 14.41,97.08 16.57,99.24 20.88,99.24 21.77,100.13 25.76,100.13 28.28,102.65 29.23,102.65 35.38,108.8 35.38,110.28 36.4,111.31 36.85,111.31 37.61,110.55 39.81,110.55 40.82,109.53 48.7,109.53 49.46,110.29 54.64,110.29 60.3,104.63 60.3,104.37 61.41,103.27 62.19,103.27 63.91,101.55 78.12,101.55 84.82,94.85 84.82,94.16 85.91,93.07 85.91,91.11 86.16,90.86 86.16,86.8 87.18,85.78 87.18,78.8 86.67,78.29 86.67,68.51 85.91,67.75 85.91,64.44 86.92,63.43 86.92,61.98 87.81,61.09 87.81,51.36 86.42,49.97 86.42,39.68 88.19,37.9 88.19,36.73 89.07,35.86 90.33,35.86 95.23,30.96 96,30.96 101.04,25.92 102.31,25.92 103.07,25.16 103.59,25.16 105.55,23.19 105.55,15.11 110.18,10.47 110.64,10.47 110.95,10.16 112.39,10.16 113.11,9.45 113.62,9.45 113.82,9.24 116.05,9.24 116.52,9.71 127.65,9.71 128.3,9.06 128.74,9.06 v2(129.8,8)
DBC_EN_R: length 12.3
  TOP w0.102: RX36.1 9.71,89.72 v2(9.58,89.59) ; RX36.1 10.78,89.21 v1(12.2,89.21) ; RX36.1 RX23.2
  BOTTOM w0.102: JEDP.23 3.17,88 4.25,89.08 5.52,89.08 5.77,89.34 9.33,89.34 v2(9.58,89.59)
DC_TEST_A3_B3: length 0.7
  BOTTOM w0.081: UC1.B3 155,101.51 UC1.A3
DC_TEST_A4: length 2.1
  TOP w0.076: v2(155.25,102.8) 155.25,103.01 T168.1
  BOTTOM w0.076: UC1.A4 154.36,102.04 155.12,102.8 v2(155.25,102.8)
DC_TEST_A60: length 3.4
  TOP w0.076: T169.1 118.17,103.94 v2(118.29,103.81)
  BOTTOM w0.076: UC1.A60 119.41,102.18 118.67,102.92 118.67,103.43 v2(118.29,103.81)
DC_TEST_A61_B61: length 0.7
  BOTTOM w0.076: UC1.B61 118.75,101.45 UC1.A61
DC_TEST_A62: length 2.9
  TOP w0.076: T170.1 116.41,103.18 v2(117.66,103.18)
  BOTTOM w0.076: v2(117.66,103.18) 118.1,102.73 UC1.A62
DC_TEST_AV1: length 4.4
  TOP w0.076: T171.1 158.68,81.46 v2(159.19,80.95)
  BOTTOM w0.076: UC1.AV1 156.39,80.72 156.88,80.23 158.47,80.23 v2(159.19,80.95)
DC_TEST_AW1: length 2
  TOP w0.076: v2(157.28,79.56) T172.1
  BOTTOM w0.076: UC1.AW1 156.58,79.56 v2(157.28,79.56)
DC_TEST_AW63: length 9.7
  TOP w0.076: v2(112.12,75.37) 111.36,75.37 T173.1
  BOTTOM w0.076: 113.17,75.15 113.94,75.15 117.51,78.73 UC1.AW63
  BOTTOM w0.102: v2(112.12,75.37) 112.34,75.15 113.17,75.15
DC_TEST_AY2_AW2: length 0.7
  BOTTOM w0.076: UC1.AY2 155.48,79.52 UC1.AW2
DC_TEST_AY3_AW3: length 0.7
  BOTTOM w0.076: UC1.AY3 154.87,80.01 UC1.AW3
DC_TEST_AY60: length 11.3
  TOP w0.076: T166.1 111.28,74.99 v2(111.66,74.99)
  BOTTOM w0.076: UC1.AY60 119.23,79.41 118.7,78.87 118.16,78.87 113.9,74.6 113.72,74.6
  BOTTOM w0.102: v2(111.66,74.99) 111.66,74.91 111.97,74.6 113.72,74.6
DC_TEST_AY61_AW61: length 0.7
  BOTTOM w0.076: UC1.AW61 118.73,79.98 UC1.AY61
DC_TEST_AY62_AW62: length 0.7
  BOTTOM w0.076: UC1.AW62 118.08,79.97 UC1.AY62
DC_TEST_B62_B63: length 0.7
  BOTTOM w0.076: UC1.B62 117.64,101.31 UC1.B63
DC_TEST_C1_C2: length 0.7
  BOTTOM w0.081: UC1.C1 156.02,100.78 UC1.C2
DCIN: length 2.1
  BOTTOM w0.102: PC710.1 49.52,17.84 v1(50.82,19.13)
DDI1_LANE_N0: length 103.6
  IN2 w0.076: 126.08,107.37 126.08,107.35 126.04,107.31 126.04,105.65 125.73,105.34 124.13,105.34 v2(123.85,105.05)
  IN2 w0.114: 126.08,107.37 126.08,108 126.77,108.68 128.5,108.68 129.42,109.61 129.42,112.38 133.17,116.13 145.49,116.13 147.37,118.01 161.78,118.01 164.55,115.25 171.02,115.25 175.37,110.91 179.71,110.91 181.16,109.45 181.16,101.96 189.57,93.55 189.57,90.58 189.84,90.31 190.48,90.31 v2(190.68,90.1)
  BOTTOM w0.076: v2(123.85,105.05) 123.57,105.34 123.12,105.34 122.99,105.21 122.99,103.31 122.36,102.67 122.36,102.16 122.46,101.95 122.51,101.85 122.51,101.62 122.49,101.54 122.48,101.53 122.48,101.52 122.45,101.47 122.45,101.34 122.48,101.24 122.69,101.03 122.87,101.03 123.04,100.86 UC1.C54
  BOTTOM w0.112: v2(190.68,90.1) 190.92,90.34 194.36,90.34 CX18.2
DDI1_LANE_N1: length 112.5
  IN2 w0.076: v2(121.31,104.78) 121.31,104.95 121.41,105.05 122.95,105.05 123.33,105.42 123.33,106.82 123.84,107.33 123.84,107.56 123.88,107.61 123.88,107.62
  IN2 w0.114: v2(193.75,86.55) 193.5,86.8 193.09,86.8 192.62,87.27 192.62,87.51 192.49,87.65 192.49,87.99 192.62,88.12 192.62,88.52 192.49,88.65 192.49,89.01 192.62,89.14 192.62,89.56 192.49,89.69 192.49,90.05 192.62,90.18 192.62,90.35 192.49,90.48 192.49,90.83 192.62,90.97 192.62,91.26 192.49,91.39 192.49,91.75 192.62,91.88 192.62,92.38 191.06,93.94 191.06,96.77 189.86,97.98 187.35,97.98 183.83,101.5 183.83,109.65 181.06,112.42 176.9,112.42 171.91,117.41 168.82,117.41 168.31,116.9 165.16,116.9 161.99,120.07 156.62,120.07 156.11,119.56 146.81,119.56 144.91,117.66 132.44,117.66 127.82,113.04 127.82,111.56 126.93,110.67 125.15,110.67 124.95,110.47 124.95,110.32 124.69,110.06 124.54,110.06 124.36,109.88 124.36,109.74 124.12,109.5 123.98,109.5 123.88,109.4 123.88,107.62
  BOTTOM w0.076: v2(121.31,104.78) 121.31,104.93 121.37,104.99 121.74,104.99 121.81,104.91 121.81,104.14 121.65,103.98 121.43,103.98 121.19,103.73 121.19,103.51 120.89,103.21 120.89,102.98 120.82,102.92 120.82,102.92 120.76,102.86 120.76,102.52 120.82,102.45 120.82,102.45 120.89,102.39 120.89,101.14 UC1.B58
  BOTTOM w0.112: v2(193.75,86.55) 193.75,86.6 193.95,86.8 194.34,86.8 194.54,86.59 CX16.2
DDI1_LANE_N2: length 116.9
  IN2 w0.076: v2(125.28,106) 125.28,106.15 125.15,106.28 124.79,106.28 124.53,106.54 124.53,107.27 124.45,107.36 124.45,107.37
  IN2 w0.114: v2(193.39,79.42) 193.65,79.68 194.09,79.68 194.36,79.96 194.36,80.63 192.3,82.69 192.3,86.19 191.78,86.72 191.78,89.81 191.64,89.94 191.64,90.09 191.78,90.22 191.78,90.75 191.64,90.89 191.64,91.04 191.78,91.17 191.78,92.13 190.56,93.34 190.56,96.57 189.67,97.46 187.1,97.46 183.06,101.5 183.06,109.53 180.67,111.93 175.84,111.93 171.38,116.39 164.88,116.39 162.24,119.02 146.97,119.02 145.09,117.14 132.67,117.14 128.33,112.81 128.33,110.14 128,109.8 125.58,109.8 124.45,108.67 124.45,107.37
  BOTTOM w0.076: UC1.B55 122.75,101.39 122.9,101.54 123.11,101.54 123.41,101.84 123.41,103.05 124.64,104.28 124.64,106 124.97,106.33 125.18,106.33 125.28,106.23 v2(125.28,106)
  BOTTOM w0.112: CX14.2 194.29,79.68 193.65,79.68 v2(193.39,79.42)
DDI1_LANE_N3: length 119.4
  IN2 w0.076: v2(121.34,106.73) 121.34,106.91 121.43,107 122.62,107 123.08,107.46 123.08,107.56 123.12,107.61 123.12,107.62
  IN2 w0.114: v2(193.77,82.99) 193.77,83.15 193.68,83.25 193.09,83.25 192.82,83.51 192.82,84.54 194.87,86.59 194.87,91.4 191.8,94.47 191.8,97.08 190.15,98.74 187.66,98.74 184.72,101.68 184.72,109.93 181.49,113.17 177.42,113.17 172.04,118.55 168.84,118.55 168.08,117.78 165.41,117.78 162.36,120.84 147.01,120.84 145.05,118.88 132.59,118.88 125.79,112.07 123.53,112.07 123.25,111.79 123.25,110.67 123.12,110.55 123.12,107.62
  BOTTOM w0.076: UC1.A57 121.37,101.91 121.42,101.86 121.57,101.86 121.68,101.98 121.68,103.12 122.32,103.76 122.32,105 122.21,105.12 122.21,105.46 122.32,105.57 122.32,105.92 122.21,106.03 122.21,106.37 122.32,106.49 122.32,106.82 122.12,107.03 121.44,107.03 121.34,106.93 v2(121.34,106.73)
  BOTTOM w0.112: CX12.2 194.36,83.25 194.03,83.25 v2(193.77,82.99)
DDI1_LANE_P0: length 103.6
  IN2 w0.076: 125.83,107.37 125.83,107.35 125.88,107.31 125.88,105.72 125.66,105.5 124.13,105.5 v2(123.85,105.79)
  IN2 w0.114: v2(190.68,90.86) 190.68,90.71 190.53,90.56 189.95,90.56 189.82,90.68 189.82,93.65 181.41,102.06 181.41,109.55 179.81,111.15 175.47,111.15 171.13,115.5 164.65,115.5 161.89,118.26 147.26,118.26 145.38,116.38 133.07,116.38 129.17,112.48 129.17,109.71 128.39,108.93 126.66,108.93 125.83,108.1 125.83,107.37
  BOTTOM w0.076: UC1.C55 122.36,101.13 122.33,101.16 122.29,101.32 122.29,101.5 122.3,101.53 122.32,101.58 122.32,101.59 122.35,101.65 122.35,101.81 122.35,101.81 122.28,101.95 122.24,102.02 122.19,102.13 122.19,102.74 122.83,103.37 122.83,105.28 123.05,105.5 123.57,105.5 v2(123.85,105.79)
  BOTTOM w0.112: CX19.2 194.36,90.59 190.95,90.59 v2(190.68,90.86)
DDI1_LANE_P1: length 112.8
  IN2 w0.076: v2(121.31,105.43) 121.53,105.21 122.89,105.21 123.16,105.49 123.16,106.88 123.67,107.4 123.67,107.56 123.63,107.61 123.63,107.62
  IN2 w0.114: v2(193.75,87.33) 193.47,87.05 193.19,87.05 192.87,87.38 192.87,89.66 192.74,89.79 192.74,89.94 192.87,90.08 192.87,90.45 192.74,90.58 192.74,90.73 192.87,90.86 192.87,91.36 192.74,91.5 192.74,91.65 192.87,91.78 192.87,92.49 191.31,94.05 191.31,96.88 189.96,98.23 187.46,98.23 184.08,101.6 184.08,109.75 181.16,112.67 177,112.67 172.01,117.66 168.71,117.66 168.2,117.15 165.26,117.15 162.09,120.32 156.52,120.32 156.01,119.81 146.71,119.81 144.81,117.91 132.34,117.91 127.57,113.14 127.57,111.66 126.83,110.92 125.05,110.92 123.63,109.51 123.63,107.62
  BOTTOM w0.076: v2(121.31,105.43) 121.59,105.15 121.81,105.15 121.98,104.98 121.98,104.07 121.05,103.14 121.05,101.25 121.1,101.2 121.1,100.94 120.8,100.64 UC1.C58
  BOTTOM w0.112: v2(193.75,87.33) 194.03,87.06 194.22,87.06 CX17.2
DDI1_LANE_P2: length 116.7
  IN2 w0.076: 124.69,107.37 124.69,106.61 124.86,106.44 125.19,106.44 125.28,106.53 v2(125.28,106.74)
  IN2 w0.114: 124.69,107.37 124.69,108.56 124.87,108.74 125.04,108.74 125.31,109 125.31,109.18 125.69,109.55 125.99,109.55 126.12,109.43 126.47,109.43 126.6,109.55 126.88,109.55 127.01,109.43 127.34,109.43 127.46,109.55 128.1,109.55 128.58,110.04 128.58,112.71 132.77,116.9 145.2,116.9 147.08,118.77 162.14,118.77 164.77,116.14 171.28,116.14 175.74,111.68 180.56,111.68 182.81,109.43 182.81,101.4 187,97.22 189.57,97.22 190.32,96.47 190.32,93.24 191.53,92.02 191.53,91.27 191.4,91.14 191.4,90.78 191.53,90.65 191.53,90.33 191.4,90.19 191.4,89.84 191.53,89.71 191.53,89.37 191.4,89.23 191.4,88.87 191.53,88.74 191.53,88.45 191.4,88.32 191.4,87.96 191.53,87.83 191.53,87.46 191.4,87.33 191.4,86.97 191.53,86.84 191.53,86.62 192.06,86.09 192.06,82.58 192.82,81.82 192.82,81.67 193.07,81.41 193.23,81.41 193.53,81.11 193.53,80.98 193.78,80.73 193.91,80.73 194.11,80.53 194.11,80.06 193.98,79.93 193.51,79.93 193.39,80.05 v2(193.39,80.2)
  BOTTOM w0.076: v2(125.28,106.74) 125.28,106.63 125.14,106.49 124.91,106.49 124.48,106.07 124.48,105.9 124.36,105.79 124.36,105.44 124.48,105.33 124.48,105.15 124.36,105.03 124.36,104.68 124.48,104.56 124.48,104.35 123.25,103.12 123.25,101.91 123.04,101.71 122.79,101.71 122.74,101.76 122.74,102.03 UC1.A55
  BOTTOM w0.112: CX15.2 194.67,80.2 194.41,79.94 193.59,79.94 193.39,80.14 v2(193.39,80.2)
DDI1_LANE_P3: length 119.4
  IN2 w0.076: v2(121.34,107.37) 121.55,107.17 122.56,107.17 122.87,107.48 122.87,107.62
  IN2 w0.114: 122.87,107.62 122.87,110.65 123,110.78 123,111.89 123.43,112.32 125.69,112.32 132.49,119.13 144.95,119.13 146.91,121.09 162.46,121.09 165.52,118.03 167.97,118.03 168.74,118.8 172.14,118.8 177.53,113.42 181.59,113.42 184.97,110.04 184.97,101.78 187.76,98.99 190.25,98.99 192.05,97.19 192.05,94.57 195.12,91.5 195.12,86.49 193.07,84.44 193.07,83.62 193.19,83.49 193.49,83.49 v2(193.77,83.77)
  BOTTOM w0.076: UC1.B57 121.37,101.43 121.85,101.91 121.85,103.05 122.48,103.69 122.48,106.89 122.19,107.19 121.52,107.19 v2(121.34,107.37)
  BOTTOM w0.112: CX13.2 194.36,83.51 194.03,83.51 v2(193.77,83.77)
DDR3_DRAMRST#: length 31.9
  TOP w0.102: RD5.1 CD3.1 104.83,38.02 v2(105.56,37.3) ; CD34.1 v1(115.83,25.18) 116.03,24.97 v2(116.31,24.97)
  BOTTOM w0.102: JDIMM2.30 117.22,25.37 116.82,24.97 v2(116.31,24.97) 115.58,24.24 111.92,24.24 111.68,24.48 109.49,24.48 107.63,26.34 107.63,29.39 108.12,29.89 108.12,34.73 v2(105.56,37.3) 104.85,38 JDIMM1.30
DDR3_DRAMRST#_CPU: length 111.3
  TOP w0.076: v2(148.06,76.18) 147.76,75.87 CC35.1
  TOP w0.102: v2(101.28,38.13) 101.28,39.63 v1(101.66,40.01) 101.91,40.26 RD3.2 RD5.2
  IN2 w0.107: v2(101.28,38.13) 98.71,40.7 97.15,40.7 95.56,42.28 95.56,44.06 91.5,48.12 91.5,53.78 94.54,56.82 v2(94.54,58.73)
  BOTTOM w0.076: UC1.AV15 147.23,80.45 147.23,79.94 147.3,79.86 147.3,79.59 147.24,79.52 147.24,79.29 147.35,79.17 147.35,76.89 v2(148.06,76.18) 148.9,75.34 148.9,73.52 148.39,73.02 148.39,71.81
  BOTTOM w0.102: v2(94.54,58.73) 97.34,58.73 98.86,57.21 99.9,57.21 100.62,57.92 100.62,68.61 104.48,72.47 138.21,72.47 140.7,69.98 147.57,69.98 148.39,70.81 148.39,71.81
DDR_A_BS0: length 48.8
  IN1 w0.076: 134.6,70.74 134.6,74.1 135.54,75.03 135.54,76.31 v2(135.72,76.5)
  IN1 w0.163: v2(131.26,44.72) 131.47,44.51 131.74,44.51 131.86,44.63 131.86,46.86 132.25,47.25 132.25,51.31 132.29,51.34 132.29,51.43 131.57,52.15 131.57,53.13 131.74,53.29 132.22,53.29 132.39,53.13 132.39,52.48 132.55,52.31 133.04,52.31 133.2,52.48 133.2,60.3 133.38,60.48 133.69,60.48 133.89,60.28 133.89,59.57 134,59.45 134.49,59.45 134.6,59.57 134.6,70.74
  BOTTOM w0.076: v2(135.72,76.5) 135.51,76.71 135.05,76.71 134.83,76.93 134.83,80.66 135.1,80.93 135.1,81.22 UC1.AU35
  BOTTOM w0.157: v2(131.26,44.72) 130.67,45.31 130.67,46.36 130.95,46.64 JDIMM1.109
DDR_A_BS1: length 49.2
  IN1 w0.076: 135.11,70.24 135.11,74.27 135.72,74.88 135.72,75.92 136.08,76.28 136.08,76.96 135.95,77.09 v2(135.72,77.09)
  IN1 w0.163: 135.11,70.24 135.11,59.36 134.72,58.98 134.17,58.98 133.62,58.42 133.62,52.08 132.67,51.13 132.67,47.08 132.29,46.7 132.29,43.14 132.55,42.88 132.55,40.91 132.39,40.75 131.9,40.75 131.74,40.91 131.74,42.23 131.54,42.43 v2(131.26,42.43)
  BOTTOM w0.076: UC1.AV35 135,80.42 135,77 135.13,76.87 135.59,76.87 135.72,77 v2(135.72,77.09)
  BOTTOM w0.157: JDIMM1.108 130.65,41.82 v2(131.26,42.43)
DDR_A_BS2: length 46.8
  IN1 w0.076: v2(130.97,79.16) 131.25,78.88 131.25,76.02 131.14,75.91 129.49,75.91 129.07,75.49 126.68,75.49 124.24,73.05 124.24,71.81
  IN1 w0.163: 124.24,71.81 124.24,71.66 123.22,70.64 123.22,66.48 121.09,64.34 121.09,63.45 120.58,62.95 120.58,60.79 121.09,60.28 121.09,46.55 121.27,46.37 121.27,45.22 121.73,44.76 v2(121.73,44.61)
  BOTTOM w0.076: UC1.AY41 131.23,79.41 v2(130.97,79.16)
  BOTTOM w0.157: v2(121.73,44.61) 121.39,44.61 120.68,45.32 120.68,45.81 121.33,46.46 121.6,46.46 121.95,46.81 JDIMM1.79
DDR_A_CAS#: length 48.3
  IN1 w0.076: v2(135.72,81.06) 135.72,81.01 136.47,80.27 136.47,76.07 136.14,75.74 136.14,74.67 135.92,74.45 135.92,70.26 136.14,70.03 136.14,69.2
  IN1 w0.163: v2(133.64,43.19) 133.15,43.68 133.15,46.38 133.56,46.79 133.56,48.06 134.5,49 134.5,57.84 134.66,58 135.15,58 135.31,57.84 135.31,57.03 135.47,56.86 135.96,56.86 136.14,57.05 136.14,69.2
  BOTTOM w0.076: UC1.AU34 135.87,81.06 v2(135.72,81.06)
  BOTTOM w0.157: JDIMM1.115 132.75,43.89 133.45,43.19 v2(133.64,43.19)
DDR_A_D0: length 68.6
  IN1 w0.107: v2(112.08,85.64) 101.68,85.64 97.21,81.17 97.21,80.87 97.32,80.76 98.25,80.76 98.35,80.65 98.35,80.44 98.25,80.33 97.32,80.33 97.21,80.23 97.21,80.01 97.32,79.91 98.25,79.91 98.35,79.8 98.35,79.59 98.25,79.48 97.32,79.48 97.21,79.37 97.21,79.16 97.32,79.05 98.25,79.05 98.35,78.95 98.35,78.73 98.25,78.63 97.32,78.63 97.21,78.52 97.21,78.31 97.32,78.2 98.25,78.2 98.35,78.09 98.35,77.88 98.25,77.77 97.32,77.77 97.21,77.67 97.21,75.01 97.02,74.82 v2(97.02,46.1)
  BOTTOM w0.076: UC1.AH63 117.42,86.67 115.29,86.67 115.24,86.63 115.24,86.63 114.9,86.3 113.89,86.3 112.61,85.02 112.26,85.02 112.08,85.2 v2(112.08,85.64)
  BOTTOM w0.102: v2(97.02,46.1) 97.28,46.1 97.35,46.17 JDIMM1.5
DDR_A_D1: length 68.7
  IN1 w0.107: v2(112.93,86.49) 112.98,86.45 112.98,85.88 112.25,85.16 102.08,85.16 101.61,84.69 101.61,84.54 101.83,84.31 101.83,84.16 101.68,84.01 101.53,84.01 101.3,84.23 101.15,84.23 101,84.08 101,83.93 101.23,83.71 101.23,83.56 101.07,83.41 100.92,83.41 100.52,83.81 100.37,83.81 100.22,83.66 100.22,83.51 100.62,83.11 100.62,82.95 100.47,82.8 100.32,82.8 99.91,83.21 99.76,83.21 99.61,83.06 99.61,82.91 100.02,82.5 100.02,82.35 99.87,82.2 99.72,82.2 99.49,82.42 99.34,82.42 98.74,81.82 98.74,77.65 97.76,76.67 97.76,67.33 97.61,67.18 97.61,45.17 v2(97.02,44.57)
  BOTTOM w0.076: UC1.AH62 117.96,86.96 117.76,86.96 117.58,87.05 117.31,87.05 117.16,86.9 115.28,86.9 115.18,86.79 113.96,86.79 113.32,86.16 113.09,86.16 112.93,86.32 v2(112.93,86.49)
  BOTTOM w0.102: v2(97.02,44.57) 97.74,44.57 97.95,44.78 JDIMM1.7
DDR_A_D2: length 67.6
  IN1 w0.107: v2(113.08,82.3) 112.42,82.3 110.83,80.7 110.83,80.22 105.97,75.37 105.82,75.37 105.19,76 105.04,76 104.89,75.85 104.89,75.7 105.55,75.04 105.55,74.89 105.4,74.74 105.24,74.74 104.45,75.53 104.3,75.53 104.15,75.38 104.15,75.23 104.94,74.44 104.94,74.29 104.78,74.12 104.63,74.12 103.77,74.98 103.62,74.98 103.47,74.83 103.47,74.68 104.32,73.82 104.32,73.67 104.16,73.5 104.01,73.5 103.31,74.2 103.16,74.2 103,74.05 103,73.9 103.71,73.2 103.71,73.05 103.55,72.9 103.4,72.9 102.7,73.6 102.55,73.6 102.4,73.45 102.4,73.3 103.1,72.6 103.1,72.45 102.94,72.28 102.79,72.28 102.28,72.79 102.13,72.79 101.98,72.64 101.98,72.49 102.46,72 102.46,71.85 102.19,71.58 102.04,71.58 101.72,71.9 101.54,71.9 101.42,71.77 101.42,71.59 101.73,71.28 101.73,71.13 100.62,70.01 100.62,44.99 v2(100.19,44.57)
  BOTTOM w0.076: v2(113.08,82.3) 113.08,83.42 114.63,84.97 115.4,84.97 115.61,85.17 116.9,85.17 117.13,85.41 UC1.AK63
  BOTTOM w0.102: v2(100.19,44.57) 99.65,45.11 99.65,46.28 99.91,46.53 100.12,46.53 100.35,46.76 JDIMM1.15
DDR_A_D3: length 67.7
  IN1 w0.107: v2(100.19,46.1) 100.13,46.16 100.13,57.28 100.22,57.37 100.22,58.01 100.13,58.09 100.13,70.34 100.8,71.01 100.8,71.6 100.64,71.75 100.24,71.75 100.13,71.86 100.13,72.07 100.24,72.18 100.64,72.18 100.8,72.33 100.8,72.63 100.3,73.13 100.3,73.29 100.45,73.44 100.6,73.44 101.2,72.83 101.35,72.83 101.51,72.98 101.51,73.13 100.92,73.71 100.92,73.89 101.05,74.02 101.22,74.02 101.78,73.46 101.93,73.46 102.08,73.61 102.08,73.76 101.46,74.38 101.46,74.54 101.61,74.69 101.76,74.69 102.38,74.07 102.53,74.07 102.68,74.22 102.68,74.37 102.06,74.99 102.06,75.14 102.21,75.29 102.37,75.29 102.83,74.82 102.98,74.82 103.13,74.97 103.13,75.12 102.67,75.59 102.67,75.74 102.82,75.89 102.97,75.89 103.51,75.35 103.66,75.35 103.81,75.5 103.81,75.65 103.31,76.15 103.31,76.3 103.46,76.45 103.61,76.45 104.17,75.9 104.43,75.9 104.97,76.45 106.45,76.45 109.86,79.86 109.86,81 110.15,81.28 110.33,81.28 110.66,80.96 110.81,80.96 110.96,81.11 110.96,81.26 110.71,81.5 110.71,81.65 110.86,81.8 111.02,81.8 111.26,81.56 111.41,81.56 111.56,81.71 111.56,81.86 111.32,82.11 111.32,82.26 111.47,82.41 111.62,82.41 111.86,82.16 112.01,82.16 112.16,82.32 112.16,82.47 111.92,82.71 111.92,82.86 112.34,83.28 113.51,83.28 113.66,83.13 v2(113.66,82.78)
  BOTTOM w0.076: v2(113.66,82.78) 113.4,83.03 113.4,83.38 114.66,84.64 115.31,84.64 115.67,84.99 116.97,84.99 117.11,85.13 117.88,85.13 UC1.AK62
  BOTTOM w0.102: v2(100.19,46.1) 100.54,46.1 100.95,46.5 JDIMM1.17
DDR_A_D4: length 69.5
  IN1 w0.107: v2(97.02,41.52) 96.5,42.04 96.5,74.91 96.83,75.24 96.83,81.44 101.48,86.08 111.59,86.08 111.69,86.19 111.69,86.43 111.59,86.53 110.65,86.53 110.55,86.64 110.55,86.86 110.65,86.97 v2(113.37,86.97)
  BOTTOM w0.076: v2(113.37,86.97) 113.45,86.97 113.64,87.16 115.12,87.16 115.21,87.08 117.1,87.08 117.24,87.22 117.62,87.22 117.66,87.19 117.77,87.14 118.43,87.14 UC1.AH61
  BOTTOM w0.102: JDIMM1.4 97.05,41.49 v2(97.02,41.52)
DDR_A_D5: length 69.8
  IN1 w0.107: v2(97.02,43.05) 97.5,43.05 97.62,43.16 97.62,44.53 98.12,45.02 98.12,76.27 98.38,76.53 98.53,76.53 98.95,76.11 99.1,76.11 99.25,76.26 99.25,76.41 98.83,76.83 98.83,76.98 99.12,77.27 99.12,80.94 102.91,84.73 112.3,84.73 113.51,85.94 113.51,86.56 113.62,86.67 114.12,86.67 114.23,86.56 v2(114.23,85.91)
  BOTTOM w0.076: v2(114.23,85.91) 114.23,85.43 114.28,85.38 115.33,85.38 115.47,85.53 116.72,85.53 117.06,85.86 117.61,85.86 117.77,85.79 117.9,85.79 118.06,85.86 118.26,85.86 118.32,85.84 118.4,85.8 118.42,85.79 118.61,85.79 118.62,85.81 119,85.81 119.02,85.79 119.26,85.79 119.46,85.99 UC1.AH60
  BOTTOM w0.102: JDIMM1.6 97.65,42.81 97.41,43.05 v2(97.02,43.05)
DDR_A_D6: length 68.1
  IN1 w0.107: v2(100.19,41.52) 100.19,39.69 100.38,39.5 101.91,39.5 102.03,39.63 102.03,39.81 101.91,39.93 100.82,39.93 100.69,40.06 100.69,40.25 100.82,40.38 102.44,40.38 102.55,40.49 102.55,40.7 102.44,40.81 101.16,40.81 101.05,40.91 101.05,69.88 111.44,80.27 111.44,80.62 v2(112.18,81.37)
  BOTTOM w0.076: UC1.AK61 118.47,85.51 118.33,85.65 118.23,85.7 118.1,85.7 118.08,85.69 117.99,85.65 117.94,85.63 117.73,85.63 117.58,85.7 117.17,85.7 116.83,85.35 115.54,85.35 115.39,85.2 114.36,85.2 114.09,84.93 114.09,84.93 113.95,84.79 113.85,84.79 113.54,85.1 113.42,85.1 113.33,85.01 113.33,84.88 113.63,84.58 113.63,84.47 113.52,84.36 113.42,84.36 113.18,84.6 113.05,84.6 112.96,84.51 112.96,84.39 113.2,84.15 113.2,84.04 112.13,82.97 112.13,81.42 v2(112.18,81.37)
  BOTTOM w0.102: v2(100.19,41.52) 100.48,41.52 100.65,41.35 JDIMM1.16
DDR_A_D7: length 69.4
  IN1 w0.107: v2(100.19,43.05) 99.92,43.05 99.8,43.17 99.8,43.62 99.78,43.64 99.78,43.98 99.8,44 99.8,44.38 99.78,44.4 99.78,44.74 99.8,44.76 99.8,45.15 99.78,45.16 99.78,45.5 99.8,45.52 99.8,45.91 99.78,45.93 99.78,45.99 99.7,46.08 99.7,57.36 99.86,57.52 99.86,57.86 99.7,58.01 99.7,70.42 99.8,70.52 99.8,71.68 99.77,71.71 99.77,72.22 99.8,72.25 99.8,73.3 100.5,74 100.5,74.15 100.31,74.34 100.31,74.5 100.46,74.65 100.61,74.65 100.8,74.45 100.95,74.45 101.1,74.61 101.1,74.76 100.91,74.95 100.91,75.1 101.06,75.25 101.21,75.25 101.41,75.06 101.56,75.06 101.71,75.21 101.71,75.36 101.52,75.55 101.52,75.7 101.67,75.85 101.82,75.85 102.01,75.66 102.16,75.66 102.31,75.81 102.31,75.96 102.16,76.12 102.16,76.3 102.28,76.42 102.46,76.42 102.61,76.27 102.76,76.27 103.37,76.87 106.36,76.87 109.01,79.52 109.01,79.52 109.53,80.04 109.53,80.34 109.42,80.45 109.12,80.45 109.01,80.56 109.01,80.77 109.12,80.88 109.42,80.88 109.53,80.98 109.53,81.23 110.04,81.74 110.04,81.78 109.9,81.92 109.9,82.07 110.05,82.23 110.2,82.23 110.51,81.92 110.66,81.92 110.8,82.06 110.8,82.21 110.49,82.51 110.49,82.67 110.64,82.82 110.79,82.82 111.12,82.49 111.27,82.49 111.42,82.64 111.42,82.79 111.09,83.12 111.09,83.27 111.24,83.42 111.39,83.42 111.54,83.27 111.69,83.27 112.02,83.6 113.46,83.6 113.62,83.75 113.62,84.19 113.77,84.34 114.52,84.34 114.67,84.19 v2(114.67,83.63)
  BOTTOM w0.076: UC1.AK60 119.23,85.51 118.93,85.22 118.69,85.22 118.67,85.24 118.41,85.24 118.13,84.96 117.18,84.96 117.04,84.83 117.04,84.83 117,84.79 115.74,84.79 115.39,84.44 114.69,84.44 114.47,84.22 114.47,83.74 114.58,83.63 v2(114.67,83.63)
  BOTTOM w0.102: JDIMM1.18 101.25,43.2 101.12,43.33 100.32,43.33 100.19,43.2 v2(100.19,43.05)
DDR_A_D8: length 58.3
  IN1 w0.107: v2(102.48,44.57) 102.18,44.57 102.03,44.72 102.03,57.17 102.13,57.27 102.23,57.27 102.33,57.38 102.33,57.59 102.23,57.7 102.13,57.7 102.03,57.81 102.03,58.05 102.13,58.15 102.23,58.15 102.33,58.26 102.33,58.47 102.23,58.58 102.13,58.58 102.03,58.69 102.03,58.99 102.13,59.09 102.23,59.09 102.33,59.2 102.33,59.41 102.23,59.52 102.13,59.52 102.03,59.63 102.03,59.84 102.13,59.95 102.23,59.95 102.33,60.05 102.33,60.27 102.23,60.37 102.13,60.37 102.03,60.48 102.03,60.69 102.13,60.8 102.23,60.8 102.33,60.91 102.33,61.12 102.23,61.23 102.13,61.23 102.03,61.33 102.03,61.55 102.13,61.65 102.23,61.65 102.33,61.76 102.33,61.97 102.23,62.08 102.13,62.08 102.03,62.19 102.03,62.53 102.13,62.64 102.23,62.64 102.33,62.74 102.33,62.96 102.23,63.06 102.13,63.06 102.03,63.17 102.03,63.38 102.13,63.49 102.23,63.49 102.33,63.6 102.33,63.81 102.23,63.92 102.13,63.92 102.03,64.02 102.03,64.34 102.13,64.44 102.18,64.44 102.31,64.57 102.31,64.75 102.18,64.87 102.13,64.87 102.03,64.98 102.03,65.19 102.13,65.3 102.23,65.3 102.33,65.4 102.33,65.62 102.23,65.72 102.13,65.72 102.03,65.83 102.03,66.07 102.13,66.17 102.23,66.17 102.33,66.28 102.33,66.49 102.23,66.6 102.13,66.6 102.03,66.71 102.03,66.92 102.13,67.03 102.23,67.03 102.33,67.13 102.33,67.35 102.23,67.45 102.13,67.45 102.03,67.56 102.03,67.77 102.13,67.88 102.21,67.88 102.33,68 102.33,68.18 102.21,68.31 102.18,68.31 102.03,68.46 102.03,68.76 102.2,68.93 102.2,69.11 102.03,69.28 102.03,69.46 102.15,69.58 102.33,69.58 102.5,69.41 102.65,69.41 106.42,73.17 106.42,73.83 112.38,79.79 112.38,80.19 113.93,81.74 v2(114.57,81.74)
  BOTTOM w0.076: UC1.AM63 117.33,84.33 117.27,84.26 116.19,84.26 115.11,83.18 115.11,83.07 115.21,82.97 115.21,82.85 115.12,82.76 115,82.76 114.9,82.86 114.79,82.86 114.57,82.64 v2(114.57,81.74)
  BOTTOM w0.102: v2(102.48,44.57) 102.02,44.57 101.91,44.68 101.91,45.41 101.8,45.52 101.26,45.52 101.15,45.63 101.15,45.83 101.26,45.94 101.83,45.94 101.99,46.09 101.99,46.49 102.15,46.65 JDIMM1.21
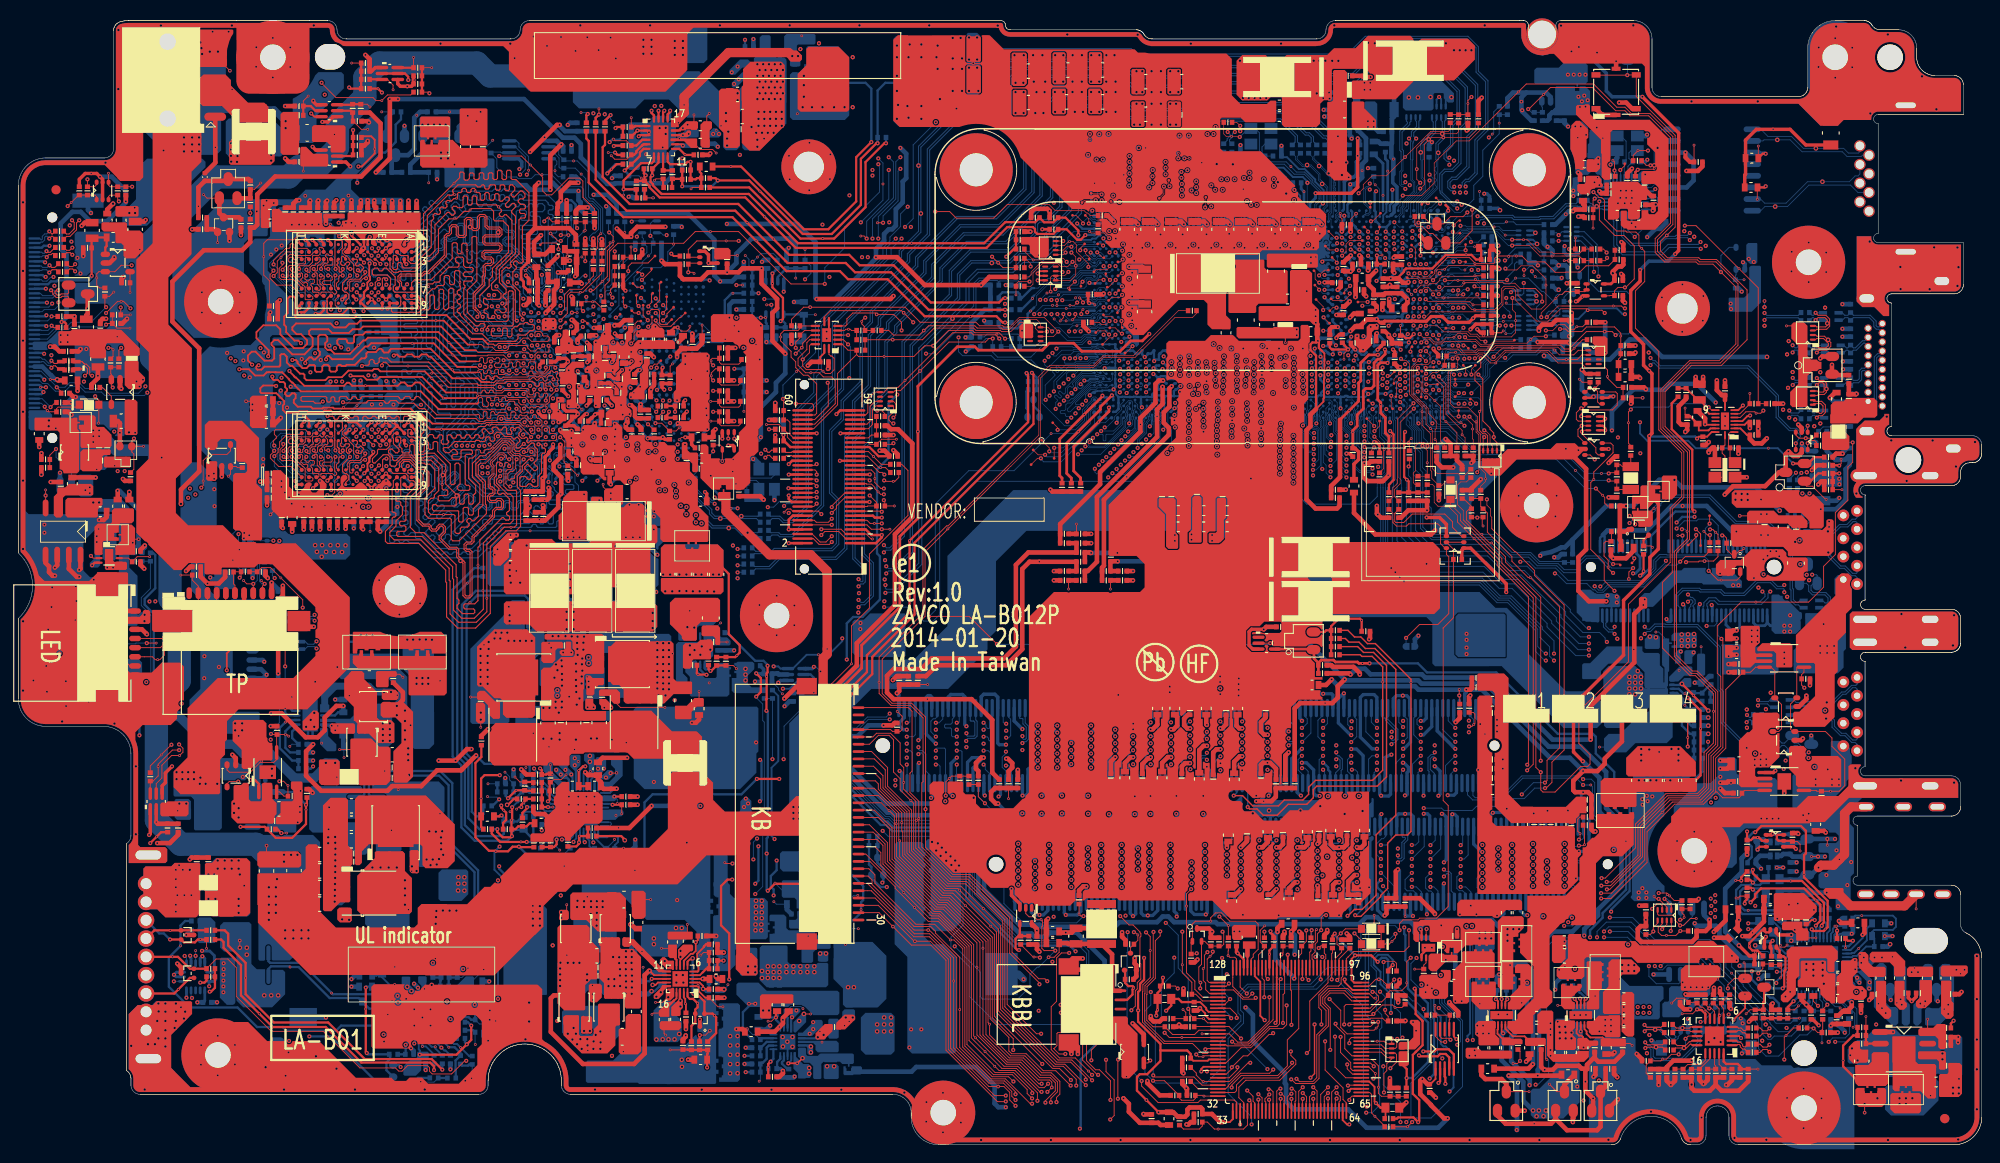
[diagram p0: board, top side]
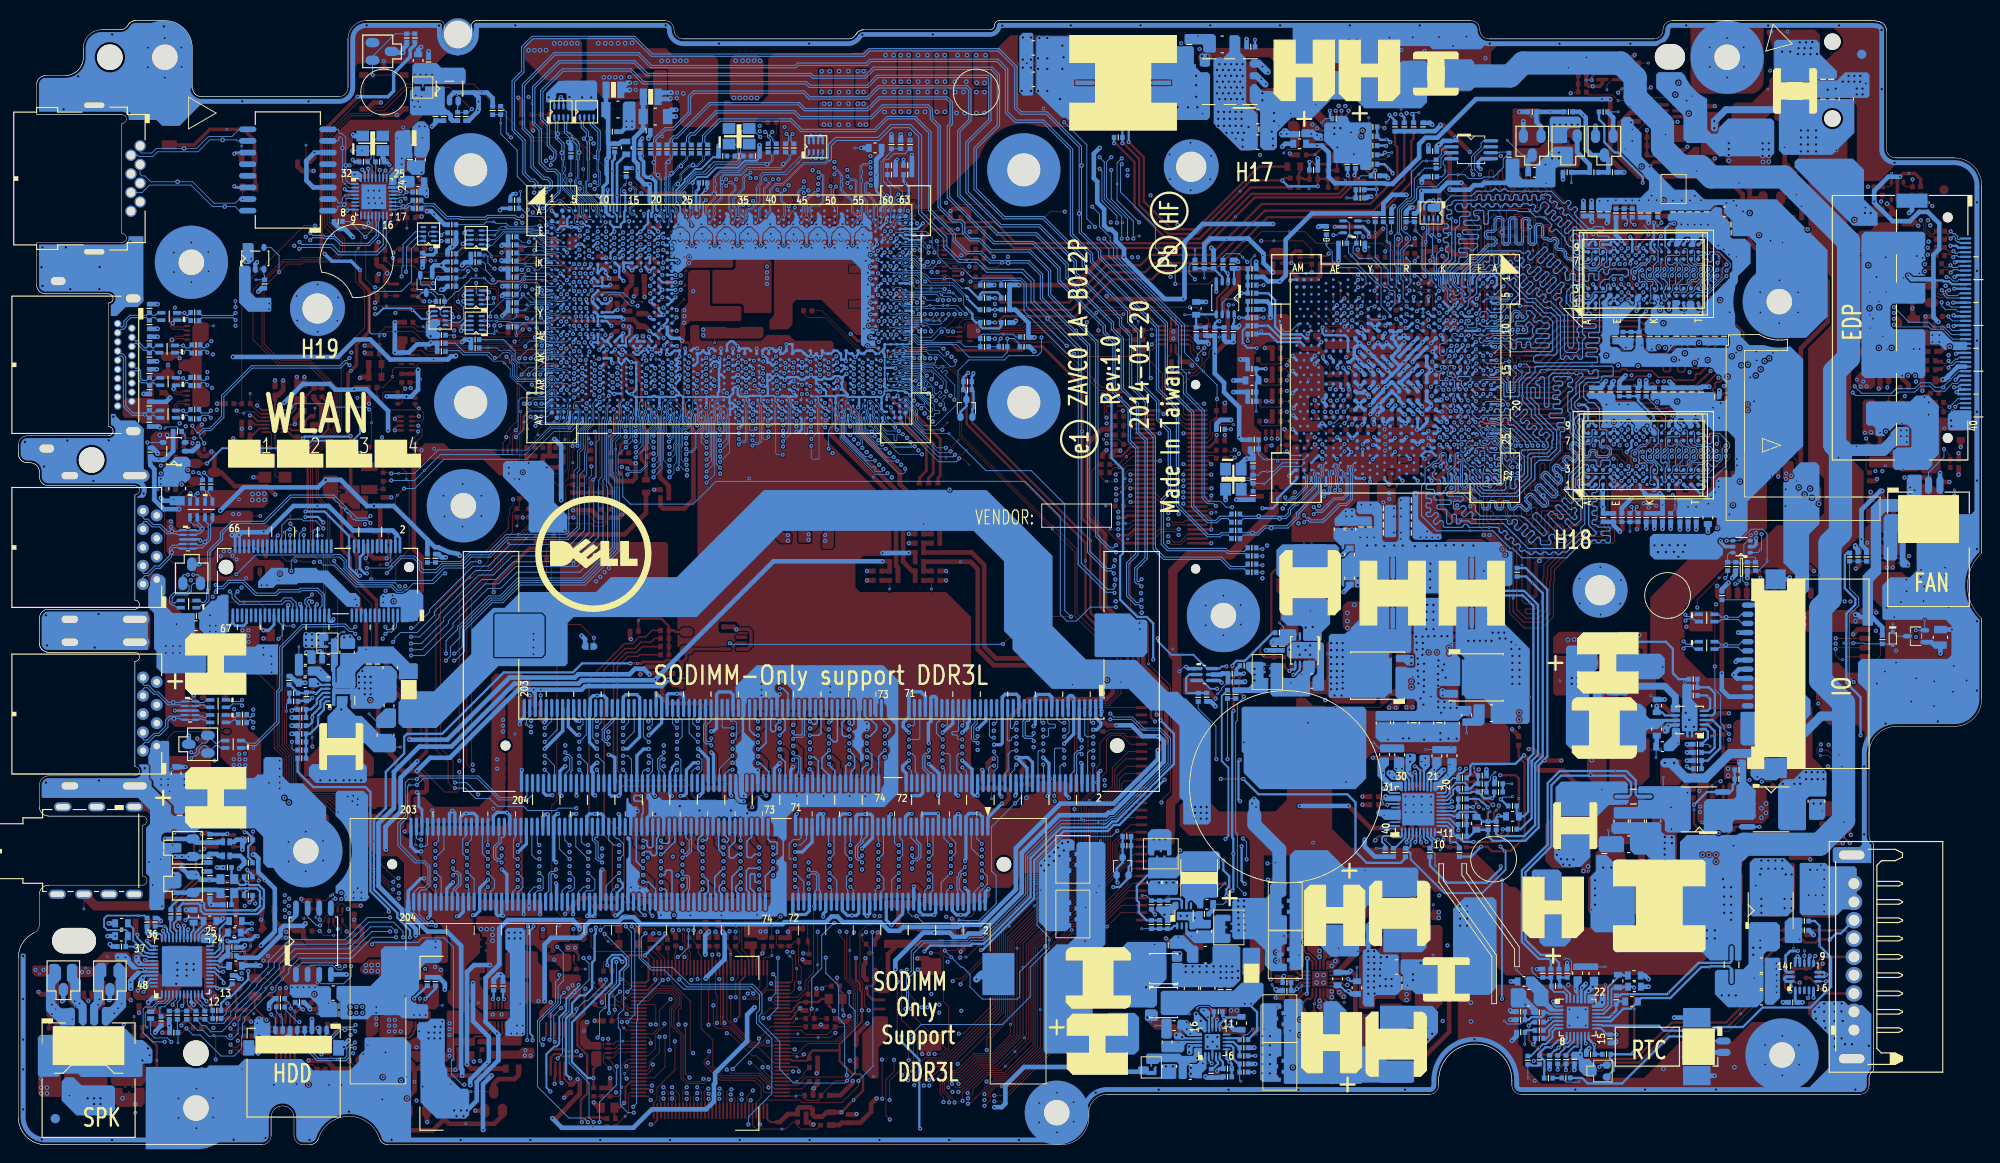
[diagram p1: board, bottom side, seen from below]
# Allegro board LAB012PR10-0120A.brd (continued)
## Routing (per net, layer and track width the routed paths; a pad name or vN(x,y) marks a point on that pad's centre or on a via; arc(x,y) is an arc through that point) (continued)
DDR_A_D9: length 59.5
  IN1 w0.107: v2(113.28,80.38) 113.29,80.4 113.68,80.4 113.79,80.29 113.79,80.08 113.68,79.97 112.86,79.97 112.76,79.86 112.76,78.85 112.62,78.72 112.52,78.72 112.27,78.97 112.08,78.97 111.95,78.84 111.95,78.65 112.14,78.46 112.14,78.28 112.01,78.15 111.83,78.15 111.63,78.35 111.45,78.35 111.33,78.23 111.33,78.05 111.58,77.8 111.58,77.65 111.43,77.5 111.28,77.5 111,77.78 110.82,77.78 110.7,77.65 110.7,77.47 110.98,77.2 110.98,77.05 110.83,76.9 110.67,76.9 110.38,77.19 110.21,77.19 110.08,77.06 110.08,76.88 110.37,76.59 110.37,76.44 110.22,76.29 110.07,76.29 109.72,76.64 109.54,76.64 109.42,76.52 109.42,76.34 109.77,75.99 109.77,75.84 109.62,75.69 109.47,75.69 109.22,75.93 109.05,75.93 108.92,75.81 108.92,75.63 109.17,75.39 109.17,75.24 109.03,75.1 108.88,75.1 108.61,75.36 108.46,75.36 108.31,75.21 108.31,75.06 108.57,74.8 108.57,74.65 108.42,74.49 108.27,74.49 108.01,74.76 107.87,74.76 107.62,74.51 107.62,74.36 107.88,74.1 107.88,73.95 107.73,73.8 107.58,73.8 107.32,74.06 107.17,74.06 106.89,73.78 106.89,72.97 102.69,68.76 102.69,46.16 102.63,46.1 v2(102.48,46.1)
  BOTTOM w0.076: UC1.AM62 117.92,84.33 117.63,84.62 117.39,84.62 117.21,84.44 116.14,84.44 114.33,82.64 114.33,82.13 114.22,82.01 114.11,82.01 113.8,82.32 113.69,82.32 113.58,82.21 113.58,82.1 113.89,81.79 113.89,81.69 113.79,81.58 113.68,81.58 113.37,81.89 113.26,81.89 113.15,81.78 113.15,81.67 113.46,81.36 113.46,81.25 113.29,81.08 113.29,80.39 v2(113.28,80.38)
  BOTTOM w0.102: JDIMM1.23 102.75,46.18 102.66,46.1 v2(102.48,46.1)
DDR_A_D10: length 57.4
  IN1 w0.107: v2(105.41,46.1) 105.41,47.01 105.16,47.26 105.16,47.26 105.05,47.37 105.01,47.37 104.91,47.48 104.91,47.69 105.01,47.8 105.05,47.8 105.16,47.9 105.16,48.12 105.05,48.22 105.01,48.22 104.91,48.33 104.91,48.54 105.01,48.65 105.05,48.65 105.16,48.76 105.16,48.97 105.05,49.08 105.01,49.08 104.91,49.18 104.91,49.4 105.01,49.5 105.05,49.5 105.16,49.61 105.16,49.82 105.05,49.93 105.01,49.93 104.91,50.04 104.91,50.25 105.01,50.36 105.05,50.36 105.16,50.46 105.16,50.68 105.05,50.79 105.01,50.79 104.91,50.89 104.91,51.11 105.01,51.21 105.05,51.21 105.16,51.32 105.16,51.53 105.05,51.64 105.01,51.64 104.91,51.75 104.91,51.96 105.01,52.07 105.05,52.07 105.16,52.17 105.16,52.39 105.05,52.49 105.01,52.49 104.91,52.6 104.91,52.81 105.01,52.92 105.05,52.92 105.16,53.03 105.16,53.24 105.05,53.35 105.01,53.35 104.91,53.45 104.91,53.67 105.01,53.77 105.05,53.77 105.16,53.88 105.16,54.09 105.05,54.2 105.01,54.2 104.91,54.31 104.91,54.52 105.01,54.63 105.05,54.63 105.16,54.73 105.16,54.95 105.05,55.05 105.01,55.05 104.91,55.16 104.91,55.37 105.01,55.48 105.05,55.48 105.16,55.59 105.16,55.8 105.05,55.91 105.01,55.91 104.91,56.01 104.91,56.23 105.01,56.33 105.05,56.33 105.16,56.44 105.16,56.65 105.05,56.76 105.01,56.76 104.91,56.87 104.91,57.08 105.01,57.19 105.05,57.19 105.16,57.29 105.16,57.51 105.05,57.61 105.01,57.61 104.91,57.72 104.91,57.93 105.01,58.04 105.05,58.04 105.16,58.15 105.16,58.36 105.05,58.47 105.01,58.47 104.91,58.57 104.91,58.79 105.01,58.89 105.05,58.89 105.16,59 105.16,59.21 105.05,59.32 105.01,59.32 104.91,59.43 104.91,59.64 105.01,59.75 105.05,59.75 105.16,59.85 105.16,60.07 105.05,60.17 105.01,60.17 104.91,60.28 104.91,60.49 105.01,60.6 105.05,60.6 105.16,60.71 105.16,60.92 105.05,61.03 105.01,61.03 104.91,61.13 104.91,61.35 105.01,61.45 105.05,61.45 105.16,61.56 105.16,61.77 105.05,61.88 105.01,61.88 104.91,61.99 104.91,62.2 105.01,62.31 105.05,62.31 105.16,62.41 105.16,62.63 105.05,62.73 105.01,62.73 104.91,62.84 104.91,63.05 105.01,63.16 105.05,63.16 105.16,63.27 105.16,63.48 105.05,63.59 105.01,63.59 104.91,63.69 104.91,63.91 105.01,64.01 105.05,64.01 105.16,64.12 105.16,64.33 105.05,64.44 105.01,64.44 104.91,64.55 104.91,64.76 105.01,64.87 105.05,64.87 105.16,64.97 105.16,65.19 105.05,65.29 105.01,65.29 104.91,65.4 104.91,65.61 105.01,65.72 105.05,65.72 105.16,65.83 105.16,66.04 105.05,66.15 105.01,66.15 104.91,66.25 104.91,66.47 105.01,66.57 105.05,66.57 105.16,66.68 105.16,66.91 105.16,66.92 105.16,67.13 105.05,67.24 105.01,67.24 104.91,67.34 104.91,67.56 105.01,67.66 105.05,67.66 105.16,67.77 105.16,68.07 109.77,72.68 110.07,72.68 110.42,73.03 110.42,73.18 110.1,73.5 110.1,73.65 110.25,73.8 110.4,73.8 110.77,73.44 110.95,73.44 111.07,73.56 111.07,73.74 110.7,74.1 110.7,74.26 110.86,74.41 111.01,74.41 111.37,74.05 111.55,74.05 115.9,78.39 115.9,78.97 115.85,79.02 115.5,79.02 115.4,79.13 115.4,79.43 115.49,79.52 115.8,79.52 115.9,79.63 115.9,79.97 115.8,80.08 v2(115.8,80.45)
  BOTTOM w0.076: UC1.AP63 117.12,82.98 115.14,81 115.14,80.95 114.59,80.4 114.59,80.17 114.69,80.07 114.86,80.07 115.47,80.67 115.57,80.67 v2(115.8,80.45)
  BOTTOM w0.102: v2(105.41,46.1) 105.67,45.83 105.67,45.65 105.81,45.5 105.81,45.47 106,45.47 106.05,45.52 106.05,46.44 105.75,46.74 JDIMM1.33
DDR_A_D11: length 58.6
  IN1 w0.107: v2(116.19,80.85) 116.19,78.4 110.1,72.32 109.95,72.32 105.52,67.89 105.52,58.92 105.63,58.82 105.84,58.82 105.94,58.71 105.94,58.5 105.84,58.39 105.63,58.39 105.52,58.28 105.52,58.04 105.63,57.93 105.83,57.93 105.94,57.82 105.94,57.61 105.84,57.51 105.63,57.51 105.52,57.4 105.52,57.19 105.63,57.08 105.84,57.08 105.94,56.97 105.94,56.76 105.84,56.65 105.63,56.65 105.52,56.55 105.52,56.33 105.63,56.23 105.84,56.23 105.94,56.12 105.94,55.91 105.84,55.8 105.63,55.8 105.52,55.69 105.52,55.48 105.63,55.37 105.84,55.37 105.94,55.27 105.94,55.05 105.84,54.95 105.63,54.95 105.52,54.84 105.52,54.63 105.63,54.52 105.8,54.52 105.92,54.39 105.92,54.22 105.8,54.09 105.63,54.09 105.52,53.99 105.52,53.77 105.63,53.67 105.84,53.67 105.94,53.56 105.94,53.35 105.84,53.24 105.63,53.24 105.52,53.13 105.52,52.92 105.63,52.81 105.84,52.81 105.94,52.7 105.94,52.49 105.84,52.38 105.63,52.38 105.52,52.28 105.52,52.06 105.63,51.96 105.8,51.96 105.92,51.83 105.92,51.66 105.8,51.53 105.63,51.53 105.52,51.42 105.52,51.21 105.63,51.1 105.84,51.1 105.94,51 105.94,50.78 105.84,50.68 105.63,50.68 105.52,50.57 105.52,50.36 105.63,50.25 105.8,50.25 105.92,50.13 105.92,49.95 105.8,49.82 105.63,49.82 105.52,49.72 105.52,49.5 105.63,49.4 105.84,49.4 105.94,49.29 105.94,49.08 105.84,48.97 105.63,48.97 105.52,48.86 105.52,48.57 105.63,48.46 105.84,48.46 105.94,48.35 105.94,48.14 105.84,48.03 105.67,48.03 105.52,47.89 105.52,47.68 105.67,47.53 105.82,47.53 105.92,47.43 105.92,44.45 105.85,44.38 105.6,44.38 v2(105.41,44.57)
  BOTTOM w0.076: v2(116.19,80.85) 115.53,80.85 115.45,80.92 115.45,81.07 117.06,82.68 117.63,82.68 117.92,82.98 UC1.AP62
  BOTTOM w0.102: v2(105.41,44.57) 105.42,44.56 105.8,44.56 105.95,44.4 105.95,44.23 106.06,44.12 106.3,44.12 106.41,44.23 106.41,47.64 JDIMM1.35
DDR_A_D12: length 59.3
  IN1 w0.107: v2(102.48,41.52) 102.38,41.42 101.82,41.42 101.67,41.57 101.67,68.63 101.67,68.63 101.67,68.93 101.67,68.93 101.67,69.61 102.25,70.19 102.4,70.19 102.57,70.02 102.75,70.02 102.87,70.14 102.87,70.32 102.7,70.49 102.7,70.67 102.83,70.79 103,70.79 103.18,70.62 103.35,70.62 103.48,70.74 103.48,70.92 103.31,71.09 103.31,71.27 103.43,71.39 103.61,71.39 103.79,71.21 103.94,71.21 104.09,71.36 104.09,71.51 103.91,71.7 103.91,71.87 104.03,72 104.21,72 104.38,71.83 104.56,71.83 104.69,71.95 104.69,72.13 104.51,72.3 104.51,72.48 104.64,72.6 104.82,72.6 104.99,72.43 105.16,72.43 105.29,72.55 105.29,72.73 105.12,72.9 105.12,73.08 105.24,73.2 105.42,73.2 105.59,73.03 105.77,73.03 105.89,73.16 105.89,73.33 105.72,73.51 105.72,73.66 111.94,79.89 111.94,80.34 115.21,83.61 v2(115.21,84.01)
  BOTTOM w0.076: UC1.AM61 118.68,84.22 118.28,84.62 117.87,84.62 117.7,84.78 117.32,84.78 117.16,84.62 115.82,84.62 v2(115.21,84.01)
  BOTTOM w0.102: v2(102.48,41.52) 102.45,41.49 JDIMM1.22
DDR_A_D13: length 60.4
  IN1 w0.107: v2(102.48,43.05) 102.94,42.59 103.16,42.59 103.36,42.79 103.36,43 102.91,43.45 102.91,45.53 103.05,45.67 103.05,68.61 107.26,72.82 109.89,75.45 110.04,75.45 110.2,75.3 110.35,75.3 110.5,75.45 110.5,75.6 110.35,75.76 110.35,75.91 110.56,76.12 110.74,76.12 110.88,75.98 111.04,75.98 111.19,76.13 111.19,76.28 110.95,76.52 110.95,76.67 111.1,76.82 111.25,76.82 111.49,76.58 111.64,76.58 111.79,76.74 111.79,76.89 111.55,77.13 111.55,77.28 111.69,77.41 111.86,77.41 112.02,77.25 112.18,77.25 112.33,77.4 112.33,77.55 112.16,77.72 112.16,77.87 112.31,78.02 112.46,78.02 112.69,77.79 112.84,77.79 113,77.94 113,78.09 112.76,78.32 112.76,78.47 112.91,78.62 113.06,78.62 113.19,78.49 113.32,78.49 113.47,78.65 113.47,78.94 113.32,79.09 113.12,79.09 113.01,79.2 113.01,79.47 113.16,79.63 113.61,79.63 114.18,80.19 v2(114.18,81.28)
  BOTTOM w0.076: UC1.AM60 119.46,83.56 119.26,83.36 118.42,83.36 118.4,83.37 118.32,83.41 118.27,83.43 118.06,83.43 117.9,83.36 117.77,83.36 117.61,83.43 117.11,83.43 115.16,81.48 114.97,81.48 114.74,81.25 114.21,81.25 v2(114.18,81.28)
  BOTTOM w0.102: JDIMM1.24 103.05,42.93 102.93,43.05 v2(102.48,43.05)
DDR_A_D14: length 58.4
  IN1 w0.107: v2(114.98,79.43) 114.98,77.95 113.8,76.76 112.85,76.76 109.4,73.32 109.4,72.85 104.55,68 104.55,47 104.98,46.56 104.98,43.64 104.83,43.49 104.04,43.49 103.94,43.38 103.94,43.14 104.04,43.03 104.83,43.03 104.98,42.88 104.98,42.61 104.88,42.5 103.92,42.5 103.82,42.39 103.82,42.18 103.92,42.07 104.7,42.07 104.81,41.97 104.81,41.36 104.91,41.25 105.3,41.25 105.41,41.36 v2(105.41,41.52)
  BOTTOM w0.076: UC1.AP61 118.58,82.98 118.33,83.22 118.23,83.27 118.1,83.27 118.08,83.26 117.99,83.22 117.99,83.22 117.94,83.19 117.73,83.19 117.58,83.27 117.18,83.27 114.93,81.02 114.58,81.02 114.38,80.83 114.38,80.32 114.25,80.19 113.86,80.19 113.77,80.1 113.77,79.98 113.86,79.89 114.26,79.89 114.33,79.81 114.33,79.66 114.46,79.53 114.88,79.53 v2(114.98,79.43)
  BOTTOM w0.102: JDIMM1.34 106.05,40.55 105.59,41.01 105.59,41.34 v2(105.41,41.52)
DDR_A_D15: length 59.4
  IN1 w0.107: v2(116.58,81.28) 116.58,78.39 106.35,68.15 106.33,68.15 105.97,67.8 105.97,67.44 106.08,67.33 106.57,67.33 106.68,67.22 106.68,67.01 106.57,66.9 106.08,66.9 105.97,66.8 105.97,66.58 106.08,66.48 106.57,66.48 106.68,66.37 106.68,66.16 106.57,66.05 106.08,66.05 105.97,65.94 105.97,65.73 106.08,65.62 106.57,65.62 106.68,65.52 106.68,65.3 106.57,65.2 106.08,65.2 105.97,65.09 105.97,64.88 106.08,64.77 106.57,64.77 106.68,64.66 106.68,64.45 106.57,64.34 106.08,64.34 105.97,64.24 105.97,63.86 106.08,63.75 106.33,63.75 106.45,63.63 106.45,63.45 106.33,63.33 106.08,63.33 105.97,63.22 105.97,63.01 106.08,62.9 106.24,62.9 106.35,62.79 106.35,62.58 106.24,62.47 106.08,62.47 105.97,62.37 105.97,62.15 106.08,62.05 106.24,62.05 106.35,61.94 106.35,61.73 106.24,61.62 106.08,61.62 105.97,61.51 105.97,61.3 106.08,61.19 106.24,61.19 106.35,61.09 106.35,60.87 106.24,60.77 106.08,60.77 105.97,60.66 105.97,60.45 106.08,60.34 106.24,60.34 106.35,60.23 106.35,60.02 106.24,59.91 106.08,59.91 105.97,59.81 105.97,59.6 106.08,59.49 106.25,59.49 106.31,59.44 106.31,43.25 106.1,43.05 v2(105.41,43.05)
  BOTTOM w0.076: v2(116.58,81.28) 116.53,81.33 116.53,81.92 117.13,82.52 117.7,82.52 117.87,82.68 118.28,82.68 118.29,82.69 118.68,82.69 118.69,82.68 118.93,82.68 119.23,82.98 UC1.AP60
  BOTTOM w0.102: v2(105.41,43.05) 105.91,43.05 106.32,42.64 106.32,40.92 106.65,40.59 JDIMM1.36
DDR_A_D16: length 48.9
  IN1 w0.107: v2(117.81,77.61) 117.19,77.61 116.97,77.4 116.97,77.3 114.98,75.3 114.98,75.15 115.08,75.05 115.08,74.87 114.95,74.74 114.78,74.74 114.67,74.85 114.52,74.85 114.37,74.7 114.37,74.55 114.49,74.43 114.49,74.25 114.36,74.13 114.19,74.13 114.07,74.24 113.92,74.24 113.77,74.09 113.77,73.94 113.86,73.85 113.86,73.67 113.73,73.55 113.56,73.55 113.47,73.64 113.32,73.64 113.17,73.49 113.17,73.34 113.23,73.27 113.23,73.1 113.11,72.97 112.93,72.97 112.86,73.04 112.71,73.04 112.56,72.89 112.56,72.73 112.64,72.65 112.64,72.48 112.52,72.35 112.34,72.35 112.26,72.43 112.11,72.43 111.89,72.22 111.89,71.63 108.3,68.04 108.3,58.66 107.88,58.25 107.88,57.74 107.99,57.63 108.31,57.63 108.44,57.51 108.44,57.33 108.31,57.2 107.99,57.2 107.88,57.1 107.88,56.88 107.99,56.78 108.31,56.78 108.44,56.65 108.44,56.48 108.31,56.35 107.99,56.35 107.88,56.24 107.88,56.03 107.99,55.92 108.34,55.92 108.45,55.81 108.45,55.61 108.34,55.5 107.99,55.5 107.88,55.39 107.88,55.27 108.08,55.07 108.36,55.07 108.45,54.98 108.45,54.73 108.36,54.64 108.15,54.64 107.99,54.48 107.99,54.22 107.88,54.11 107.88,45.99 v2(107.87,45.99)
  BOTTOM w0.076: v2(117.81,77.61) 118.38,77.61 118.46,77.54 118.46,76.98 118.55,76.89 118.67,76.89 118.76,76.98 118.76,77.54 118.84,77.61 119.52,77.61 120.58,78.67 120.58,79.29 UC1.AY58
  BOTTOM w0.102: v2(107.87,45.99) 107.72,45.99 107.55,46.16 JDIMM1.39
DDR_A_D17: length 49.4
  IN1 w0.107: v2(107.87,44.46) 107.6,44.46 107.37,44.69 107.37,54.11 107.63,54.37 107.63,55.01 107.37,55.27 107.37,59.07 107.72,59.42 107.72,60.17 107.94,60.38 107.94,60.6 107.83,60.7 107.48,60.7 107.37,60.81 107.37,61.02 107.48,61.13 107.83,61.13 107.94,61.24 107.94,61.45 107.83,61.56 107.48,61.56 107.37,61.66 107.37,61.88 107.48,61.98 107.83,61.98 107.94,62.09 107.94,62.3 107.83,62.41 107.48,62.41 107.37,62.52 107.37,62.92 107.82,63.36 107.82,68.14 111.54,71.86 111.54,72.24 117.4,78.1 117.4,78.1 117.53,78.23 117.98,78.23 v2(118.24,77.97)
  BOTTOM w0.076: v2(118.24,77.97) 119.6,77.97 120.41,78.78 120.41,79.77 UC1.AW58
  BOTTOM w0.102: v2(107.87,44.46) 108.15,44.46 108.36,44.69 108.36,46.49 108.15,46.7 JDIMM1.41
DDR_A_D18: length 49.7
  IN1 w0.107: v2(120.88,77.39) 119.61,77.39 114.59,72.37 114.59,71.08 111.05,67.55 111.05,66.86 110.95,66.75 110.79,66.75 110.68,66.65 110.68,66.43 110.79,66.33 110.95,66.33 111.05,66.22 111.05,66.01 110.95,65.9 110.79,65.9 110.68,65.79 110.68,65.58 110.79,65.47 110.95,65.47 111.05,65.37 111.05,65.15 110.95,65.05 110.79,65.05 110.68,64.94 110.68,64.73 110.79,64.62 110.95,64.62 111.05,64.51 111.05,64.3 110.95,64.19 110.79,64.19 110.68,64.09 110.68,63.87 110.79,63.77 110.95,63.77 111.05,63.66 111.05,63.45 110.95,63.34 110.79,63.34 110.68,63.23 110.68,63.02 110.79,62.91 110.95,62.91 111.05,62.81 111.05,62.59 110.95,62.49 110.79,62.49 110.68,62.38 110.68,62.17 110.79,62.06 110.95,62.06 111.05,61.95 111.05,61.74 110.95,61.63 110.79,61.63 110.68,61.53 110.68,61.31 110.79,61.21 110.95,61.21 111.05,61.1 111.05,60.89 110.95,60.78 110.79,60.78 110.68,60.67 110.68,60.46 110.79,60.35 110.95,60.35 111.05,60.25 111.05,60.03 110.95,59.93 110.79,59.93 110.68,59.82 110.68,59.61 110.79,59.5 110.95,59.5 111.05,59.39 111.05,59.18 110.95,59.07 110.79,59.07 110.68,58.97 110.68,58.75 110.79,58.65 110.95,58.65 111.05,58.54 111.05,58.33 110.95,58.22 110.79,58.22 110.68,58.11 110.68,57.9 110.79,57.79 110.95,57.79 111.05,57.69 111.05,57.47 110.95,57.37 110.79,57.37 110.68,57.26 110.68,57.05 110.79,56.94 110.95,56.94 111.05,56.83 111.05,56.62 110.95,56.51 110.79,56.51 110.68,56.41 110.68,56.19 110.79,56.09 110.95,56.09 111.05,55.98 111.05,55.77 110.95,55.66 110.79,55.66 110.68,55.55 110.68,55.34 110.79,55.23 110.95,55.23 111.05,55.13 111.05,54.8 110.95,54.69 110.79,54.69 110.68,54.58 110.68,54.37 110.79,54.26 110.95,54.26 111.05,54.16 111.05,53.94 110.95,53.84 110.79,53.84 110.68,53.73 110.68,53.52 110.79,53.41 110.95,53.41 111.05,53.3 111.05,53.09 110.95,52.98 110.79,52.98 110.68,52.88 110.68,52.66 110.79,52.56 110.95,52.56 111.05,52.45 111.05,46.05 v2(111.32,45.78)
  BOTTOM w0.076: UC1.AY56 122.05,79.23 122.03,79.21 122.03,78.22 121.2,77.39 v2(120.88,77.39)
  BOTTOM w0.102: v2(111.32,45.78) 111.15,45.95 JDIMM1.51
DDR_A_D19: length 50.5
  IN1 w0.107: v2(120.1,76.49) 119.01,76.49 114.99,72.47 114.99,70.98 111.42,67.4 111.42,66.93 111.52,66.83 111.76,66.83 111.87,66.72 111.87,66.51 111.76,66.4 111.52,66.4 111.42,66.29 111.42,66.08 111.52,65.97 111.76,65.97 111.87,65.87 111.87,65.65 111.76,65.55 111.52,65.55 111.42,65.44 111.42,65.23 111.52,65.12 111.76,65.12 111.87,65.01 111.87,64.8 111.76,64.69 111.52,64.69 111.42,64.59 111.42,64.37 111.52,64.27 111.76,64.27 111.87,64.16 111.87,63.95 111.76,63.84 111.52,63.84 111.42,63.73 111.42,63.37 111.54,63.24 111.54,62.94 111.42,62.82 111.42,62.52 111.54,62.39 111.54,62.09 111.42,61.96 111.42,61.66 111.54,61.54 111.54,61.24 111.42,61.11 111.42,60.81 111.54,60.68 111.54,60.38 111.42,60.26 111.42,59.96 111.54,59.83 111.54,59.53 111.42,59.4 111.42,46.73 111.82,46.33 111.82,44.12 111.69,44 111.44,44 111.32,44.11 v2(111.32,44.26)
  BOTTOM w0.076: v2(120.1,76.49) 120.54,76.49 122.2,78.15 122.2,79.14 122.35,79.29 122.35,79.77 UC1.AW56
  BOTTOM w0.102: JDIMM1.53 111.75,45.25 111.86,45.14 112.34,45.14 112.45,45.03 112.45,44.87 112.34,44.76 111.94,44.76 111.82,44.63 111.82,44.38 111.69,44.25 111.33,44.25 v2(111.32,44.26)
DDR_A_D20: length 50.7
  IN1 w0.107: v2(115.72,75.42) 115.72,75.21 112.27,71.76 112.27,71.45 109.02,68.2 109.02,68.19 108.81,67.98 108.81,54.12 108.28,53.59 108.28,43.37 v2(107.85,42.94)
  BOTTOM w0.076: UC1.AV58 120.7,80.75 121.26,81.31 121.49,81.31 121.66,81.15 121.66,80.29 121.62,80.21 121.6,80.16 121.6,79.96 121.67,79.8 121.67,79.67 121.62,79.56 121.6,79.51 121.6,79.22 121.66,79.15 121.66,78.65 121.46,78.45 121.22,78.45 118.2,75.42 v2(115.72,75.42)
  BOTTOM w0.102: v2(107.85,42.94) 107.85,42.75 107.44,42.34 107.44,41.23 107.85,40.82 JDIMM1.40
DDR_A_D21: length 51.2
  IN1 w0.107: v2(107.85,41.41) 107.21,41.41 106.97,41.66 106.97,42 106.81,42.15 106.64,42.15 106.53,42.26 106.53,42.47 106.64,42.58 106.81,42.58 107.27,43.04 107.27,44.17 107.01,44.43 107.01,54.28 107.03,54.28 107.27,54.52 107.27,54.86 107.03,55.1 107.01,55.1 107.01,63.07 107.3,63.35 107.3,68.23 111.13,72.06 111.13,72.24 117.69,78.8 118.41,78.8 118.64,78.57 v2(118.64,78.36)
  BOTTOM w0.076: v2(118.64,78.36) 118.83,78.36 119.72,79.26 119.72,79.54 120.48,80.3 120.48,80.52 120.39,80.61 120.39,80.88 120.7,81.19 UC1.AU58
  BOTTOM w0.102: JDIMM1.42 108.45,41.11 108.16,41.41 v2(107.85,41.41)
DDR_A_D22: length 50.9
  IN1 w0.107: v2(121.19,77.91) 120.95,77.91 120.45,78.41 120.17,78.41 119.73,77.97 119.61,77.97 119.33,78.26 119.15,78.26 119.03,78.13 119.03,77.95 119.37,77.61 119.37,77.43 119.25,77.31 119.07,77.31 118.7,77.68 118.52,77.68 118.4,77.55 118.4,77.38 118.71,77.07 118.71,76.92 114.18,72.39 114.18,71.19 110.32,67.32 110.32,41.46 110.56,41.21 v2(111.32,41.21)
  BOTTOM w0.076: UC1.AV56 121.95,80.36 121.81,80.23 121.79,80.18 121.76,80.12 121.76,79.99 121.77,79.97 121.81,79.89 121.83,79.84 121.83,79.6 121.81,79.58 121.76,79.47 121.76,79.29 121.87,79.18 121.87,78.29 121.58,78.01 121.29,78.01 v2(121.19,77.91)
  BOTTOM w0.102: v2(111.32,41.21) 110.85,40.74 JDIMM1.50
DDR_A_D23: length 52.3
  IN1 w0.107: v2(119.67,76.02) 118.85,76.02 115.48,72.65 115.48,70.95 112.23,67.7 112.23,64.02 112.23,64.02 112.23,63.8 111.9,63.47 111.9,60.09 112.01,59.98 112.14,59.98 112.26,59.86 112.26,59.68 112.14,59.55 112.01,59.55 111.9,59.45 111.9,59.23 112.01,59.13 112.14,59.13 112.26,59 112.26,58.83 112.14,58.7 111.94,58.7 111.82,58.58 111.82,58.4 111.94,58.27 112.14,58.27 112.26,58.15 112.26,57.97 112.14,57.85 111.97,57.85 111.84,57.72 111.84,57.55 111.97,57.42 112.14,57.42 112.26,57.3 112.26,57.12 112.14,56.99 112.01,56.99 111.9,56.89 111.9,46.87 112.23,46.54 112.23,43.58 112.88,42.92 112.88,42.77 112.88,42.58 112.77,42.47 112.57,42.47 112.31,42.73 v2(111.32,42.73)
  BOTTOM w0.076: UC1.AU56 121.95,81.12 122.24,80.83 122.24,80.59 122.23,80.58 122.23,80.48 122.51,80.2 122.51,79.22 122.36,79.07 122.36,78.08 120.3,76.02 v2(119.67,76.02)
  BOTTOM w0.102: JDIMM1.52 111.45,40.48 111.9,40.93 111.9,42.51 111.67,42.73 v2(111.32,42.73)
DDR_A_D24: length 46.1
  IN1 w0.107: v2(117.56,73.84) 116.52,72.8 116.52,70.61 113.2,67.3 113.2,63.24 113.52,62.93 113.52,60.99 113.35,60.82 113.35,53.59 113.04,53.29 113.04,52.61 113.15,52.5 113.41,52.5 113.51,52.39 113.51,52.18 113.41,52.07 113.15,52.07 113.04,51.97 113.04,51.65 113.15,51.54 113.41,51.54 113.51,51.44 113.51,51.22 113.41,51.11 113.15,51.11 113.04,51.01 113.04,50.79 113.15,50.69 113.41,50.69 113.51,50.58 113.51,50.37 113.41,50.26 113.15,50.26 113.04,50.15 113.04,49.94 113.15,49.83 113.41,49.83 113.51,49.73 113.51,49.51 113.41,49.41 113.15,49.41 113.04,49.3 113.04,49.09 113.15,48.98 113.41,48.98 113.51,48.87 113.51,48.66 113.41,48.55 113.15,48.55 113.04,48.45 113.04,48.23 113.15,48.13 113.41,48.13 113.51,48.02 113.51,47.81 113.41,47.7 113.15,47.7 113.04,47.59 113.04,47.36 113.45,46.95 v2(113.45,45.78)
  BOTTOM w0.076: v2(117.56,73.84) 117.56,73.48 117.76,73.28 118.26,73.28 122.86,77.88 122.86,78.86 123.01,79.01 123.01,79.28 UC1.AY54
  BOTTOM w0.102: JDIMM1.57 112.95,45.97 113.14,45.78 v2(113.45,45.78)
DDR_A_D25: length 47
  IN1 w0.107: v2(118.4,74.69) 117.87,74.69 116.13,72.95 116.13,70.74 112.84,67.45 112.84,63.18 112.68,63.02 112.68,60.48 112.88,60.28 112.88,56.6 112.77,56.49 112.62,56.49 112.52,56.38 112.52,56.17 112.62,56.06 112.77,56.06 112.88,55.96 112.88,55.74 112.77,55.64 112.62,55.64 112.52,55.53 112.52,55.32 112.62,55.21 112.77,55.21 112.88,55.1 112.88,54.89 112.77,54.78 112.62,54.78 112.52,54.68 112.52,54.46 112.62,54.36 112.77,54.36 112.88,54.25 112.88,53.78 112.55,53.45 112.55,47.11 112.88,46.79 112.88,44.83 v2(113.45,44.26)
  BOTTOM w0.076: UC1.AW54 123.13,79.82 122.84,79.53 122.84,79.08 122.69,78.93 122.69,77.95 119.43,74.69 v2(118.4,74.69)
  BOTTOM w0.102: JDIMM1.59 113.55,46.63 114.14,46.03 114.14,44.95 v2(113.45,44.26)
DDR_A_D26: length 46.4
  IN1 w0.107: v2(117.14,44.26) 117.44,44.26 117.59,44.41 117.59,46.14 116.88,46.85 116.88,48.37 117.32,48.82 117.32,59.25 117.22,59.36 116.65,59.36 116.54,59.47 116.54,59.68 116.65,59.79 117.22,59.79 117.32,59.89 117.32,63.86 117.17,64.01 116.72,64.01 116.57,64.16 116.57,65.89 116.91,66.24 117.24,66.24 119.87,68.87 119.87,71.96 120.38,72.47 120.38,73.3 120.85,73.78 v2(120.85,74.74)
  BOTTOM w0.076: v2(120.85,74.74) 121.76,74.74 124.34,77.32 124.34,78.78 124.36,78.8 124.36,79.28 UC1.AY52
  BOTTOM w0.102: v2(117.14,44.26) 116.1,44.26 115.95,44.41 JDIMM1.67
DDR_A_D27: length 47.6
  IN1 w0.107: v2(119.93,73.82) 119.93,72.64 119.46,72.17 119.46,69.62 116.18,66.33 116.18,63.35 116.28,63.24 116.86,63.24 116.96,63.14 116.96,62.92 116.86,62.82 116.28,62.82 116.18,62.71 116.18,62.5 116.28,62.39 116.86,62.39 116.96,62.28 116.96,62.07 116.86,61.96 116.28,61.96 116.18,61.86 116.18,61.64 116.28,61.54 116.86,61.54 116.96,61.43 116.96,61.22 116.86,61.11 116.28,61.11 116.18,61 116.18,60.79 116.28,60.68 116.67,60.68 116.8,60.56 116.8,60.38 116.67,60.25 116.28,60.25 116.18,60.15 116.18,46.4 116.79,45.78 v2(117.14,45.78)
  BOTTOM w0.076: UC1.AW52 124.63,80.06 124.7,79.99 124.7,79.63 124.73,79.58 124.73,79.57 124.78,79.47 124.78,79.28 124.52,79.03 124.52,78.73 124.5,78.71 124.5,77.25 121.22,73.97 121.12,73.97 120.97,74.12 120.86,74.12 120.76,74.01 120.76,73.9 120.9,73.76 120.9,73.65 120.77,73.52 120.06,73.52 119.93,73.65 v2(119.93,73.82)
  BOTTOM w0.102: JDIMM1.69 116.55,45.88 116.65,45.78 v2(117.14,45.78)
DDR_A_D28: length 47.7
  IN1 w0.107: v2(113.45,42.73) 113.76,42.73 113.96,42.94 113.96,65.46 113.86,65.57 113.67,65.57 113.56,65.67 113.56,65.89 113.67,65.99 113.86,65.99 113.96,66.1 113.96,66.31 113.86,66.42 113.67,66.42 113.56,66.53 113.56,66.74 113.67,66.85 113.86,66.85 113.96,66.95 113.96,67.55 116.92,70.51 116.92,72.67 118.81,74.56 v2(118.81,75.11)
  BOTTOM w0.076: v2(118.81,75.11) 119.62,75.11 122.53,78.01 122.53,79 122.68,79.15 122.68,80.01 123.24,80.58 UC1.AV54
  BOTTOM w0.102: JDIMM1.56 112.65,42.56 112.83,42.73 v2(113.45,42.73)
DDR_A_D29: length 48.2
  IN1 w0.107: v2(123.55,77.52) 122.17,77.52 117.33,72.67 117.33,70.4 114.32,67.4 114.32,41.89 113.64,41.21 v2(113.45,41.21)
  BOTTOM w0.076: UC1.AU54 123.9,81.36 124.1,81.15 124.1,80.32 124.09,80.3 124.05,80.21 124.03,80.16 124.03,79.96 124.1,79.8 124.1,79.67 124.05,79.56 124.03,79.51 124.03,79 124.01,78.98 124.01,77.75 123.78,77.52 v2(123.55,77.52)
  BOTTOM w0.102: v2(113.45,41.21) 113.25,41.01 JDIMM1.58
DDR_A_D30: length 47.5
  IN1 w0.107: v2(117.14,42.73) 117.62,42.73 117.95,43.07 117.95,46.43 117.32,47.06 117.32,47.19 117.48,47.34 118.01,47.34 118.14,47.47 118.14,47.66 118.01,47.79 117.46,47.79 117.3,47.94 117.3,48.16 117.4,48.26 117.61,48.26 117.68,48.34 117.68,65.66 120.28,68.26 120.28,71.66 120.88,72.27 120.88,73.26 121.31,73.69 v2(121.31,75.2)
  BOTTOM w0.076: v2(121.31,75.2) 121.98,75.2 124.17,77.39 124.17,78.85 124.19,78.87 124.19,79.47 124.27,79.63 124.27,79.84 124.24,79.89 124.24,79.89 124.2,79.98 124.19,79.99 124.19,80.12 124.22,80.18 124.24,80.23 124.38,80.36 UC1.AV52
  BOTTOM w0.102: v2(117.14,42.73) 116.79,42.73 116.45,42.4 116.45,40.77 116.25,40.57 JDIMM1.68
DDR_A_D31: length 48.8
  IN1 w0.107: v2(117.14,41.21) 116.79,41.21 116.36,41.63 115.86,41.63 115.75,41.74 115.75,42.01 115.86,42.12 116.31,42.12 116.41,42.22 116.41,45.65 115.82,46.25 115.82,66.48 119.06,69.72 119.06,72.31 119.47,72.73 v2(119.47,73.36)
  BOTTOM w0.076: v2(119.47,73.36) 119.63,73.21 120.77,73.21 124.67,77.11 124.67,78.64 124.69,78.66 124.69,78.96 124.94,79.21 124.94,79.51 124.92,79.56 124.87,79.67 124.87,80.97 UC1.AU52
  BOTTOM w0.102: JDIMM1.70 116.85,40.78 117.14,41.08 v2(117.14,41.21)
DDR_A_D32: length 44.9
  IN1 w0.076: 138.46,69.02 138.46,69.93 136.94,71.45 136.94,75.45 137.15,75.66 137.15,76.07 137.46,76.39 v2(137.76,76.39)
  IN1 w0.107: 138.46,69.02 138.46,55.02 136.84,53.39 136.84,48.19 135.78,47.13 135.78,44.2 135.24,43.67 135.24,43.52 135.5,43.25 135.65,43.25 v2(136.41,44.01)
  BOTTOM w0.076: UC1.AY31 137.05,79.1 137.05,77.09 v2(137.76,76.39)
  BOTTOM w0.102: v2(136.41,44.01) 135.99,44.43 135.99,46.11 136.17,46.28 136.57,46.28 136.95,46.66 JDIMM1.129
DDR_A_D33: length 45.6
  IN1 w0.076: 138.87,69.02 138.87,70.03 137.14,71.76 137.14,75.17 v2(137.76,75.79)
  IN1 w0.107: 138.87,69.02 138.87,54.91 137.75,53.79 137.75,52.97 137.64,52.86 137.3,52.86 137.2,52.76 137.2,52.54 137.3,52.44 137.64,52.44 137.75,52.33 137.75,52.12 137.64,52.01 137.3,52.01 137.2,51.9 137.2,51.69 137.3,51.58 137.64,51.58 137.75,51.48 137.75,51.26 137.64,51.16 137.3,51.16 137.2,51.05 137.2,50.84 137.3,50.73 137.64,50.73 137.75,50.62 137.75,50.41 137.64,50.3 137.3,50.3 137.2,50.2 137.2,49.98 137.3,49.88 137.64,49.88 137.75,49.77 137.75,49.53 137.67,49.45 137.3,49.45 137.2,49.34 137.2,49.11 137.3,49 137.64,49 137.75,48.9 137.75,48.68 137.64,48.58 137.32,48.58 137.24,48.49 137.24,48.09 136.14,46.98 136.14,46.79 136.29,46.64 136.48,46.64 136.62,46.5 136.62,46.3 136.48,46.16 136.29,46.16 136.14,46 136.14,45.8 v2(136.41,45.53)
  BOTTOM w0.076: v2(137.76,75.79) 136.89,76.66 136.89,79.24 137.07,79.42 137.07,79.48 137.16,79.66 137.36,79.86 UC1.AW31
  BOTTOM w0.102: v2(136.41,45.53) 137.4,45.53 137.55,45.68 JDIMM1.131
DDR_A_D34: length 44.9
  IN1 w0.076: v2(139.24,73.55) 139.63,73.16 139.63,72.19 142.07,69.75 142.07,69.02
  IN1 w0.107: v2(140.17,45.53) 140.49,45.53 140.68,45.72 140.68,52.57 142.91,54.8 142.91,58.35 142.8,58.46 142.18,58.46 142.07,58.56 142.07,58.78 142.18,58.88 142.91,58.88 143.02,58.99 143.02,59.2 142.91,59.31 142.18,59.31 142.07,59.42 142.07,59.63 142.18,59.74 142.91,59.74 143.02,59.84 143.02,60.06 142.91,60.16 142.18,60.16 142.07,60.27 142.07,60.48 142.18,60.59 142.91,60.59 143.02,60.7 143.02,60.91 142.91,61.02 142.18,61.02 142.07,61.12 142.07,69.02
  BOTTOM w0.076: UC1.AY29 138.72,77.95 138.52,77.75 138.52,74.27 v2(139.24,73.55)
  BOTTOM w0.102: v2(140.17,45.53) 140.24,45.53 140.75,46.04 140.75,46.53 140.55,46.73 JDIMM1.141
DDR_A_D35: length 45.9
  IN1 w0.076: v2(139.24,74.2) 139.79,73.65 139.79,72.31 142.43,69.67 142.43,69.02
  IN1 w0.107: v2(140.19,44.01) 140.5,44.01 140.61,43.9 140.61,43.16 140.71,43.06 140.94,43.06 141.04,43.16 141.04,52.42 143.38,54.76 143.38,61.09 142.43,62.03 142.43,69.02
  BOTTOM w0.076: v2(139.24,74.2) 138.68,74.76 138.68,77.68 138.88,77.88 138.88,79.16 139.01,79.29 139.01,79.77 UC1.AW29
  BOTTOM w0.102: JDIMM1.143 141.15,44.97 v2(140.19,44.01)
DDR_A_D36: length 46.1
  IN1 w0.076: v2(137.76,74.61) 138.04,74.61 138.16,74.49 138.16,71.56 139.68,70.03 139.68,69.02
  IN1 w0.107: v2(136.41,40.96) 137.83,40.96 138.04,41.17 138.04,43.15 137.41,43.79 137.41,47 138.47,48.06 138.47,53.49 139.68,54.71 139.68,69.02
  BOTTOM w0.076: 136.98,79.66 136.98,80.32 UC1.AV31 ; 136.98,79.66 136.91,79.52 136.72,79.33 136.72,75.64 v2(137.76,74.61) ; 136.98,79.66 136.98,79.66 136.98,79.66
  BOTTOM w0.102: JDIMM1.130 137.25,40.49 136.78,40.96 v2(136.41,40.96)
DDR_A_D37: length 46.8
  IN1 w0.076: v2(137.76,73.96) 137.34,73.54 137.34,71.96 139.27,70.04 139.27,69.02
  IN1 w0.107: 139.27,69.02 139.27,69.01 139.27,54.81 138.11,53.64 138.11,48.21 136.98,47.08 136.98,43.16 137.09,43.06 137.3,43.06 137.4,42.95 137.4,42.59 137.3,42.49 v2(136.41,42.49)
  BOTTOM w0.076: v2(137.76,73.96) 138.19,74.39 138.19,77.89 138.36,78.06 138.36,78.97 138.26,79.07 138.26,79.51 138.28,79.56 138.28,79.56 138.33,79.67 138.33,79.8 138.26,79.96 138.26,80.16 138.28,80.21 138.32,80.3 138.33,80.32 138.33,80.5 138.32,80.52 138.32,80.9 138.33,80.91 138.33,81.17 138.15,81.36 UC1.AU31
  BOTTOM w0.102: v2(136.41,42.49) 137.85,41.04 JDIMM1.132
DDR_A_D38: length 46.5
  IN1 w0.076: 141.71,69.02 141.71,69.86 v2(139.24,72.33)
  IN1 w0.107: 141.71,69.02 141.71,58.09 141.82,57.98 142.44,57.98 142.55,57.87 142.55,57.66 142.44,57.55 141.89,57.55 141.78,57.45 141.78,57.23 141.89,57.13 142.42,57.13 142.53,57.02 142.53,54.93 140.32,52.72 140.32,47.1 139.73,46.51 139.73,42.92 v2(140.17,42.49)
  BOTTOM w0.076: v2(139.24,72.33) 138.35,73.22 138.35,77.82 138.53,77.99 138.53,79.04 138.42,79.14 138.42,79.47 138.47,79.58 138.5,79.63 138.5,79.84 138.47,79.89 138.47,79.89 138.43,79.98 138.42,79.99 138.42,80.12 138.45,80.18 138.47,80.23 138.53,80.28 138.53,80.62 UC1.AV29
  BOTTOM w0.102: JDIMM1.140 140.25,40.43 139.75,40.92 139.75,42.07 v2(140.17,42.49)
DDR_A_D39: length 47
  IN1 w0.076: v2(139.24,74.85) 139.01,74.85 138.87,74.71 138.87,71.96 141.31,69.52 141.31,69.02
  IN1 w0.107: v2(140.18,41.14) 139.75,41.14 139.35,41.54 139.35,46.74 139.96,47.35 139.96,52.87 141.31,54.22 141.31,55.95 141.41,56.06 142.06,56.06 142.16,56.17 142.16,56.38 142.06,56.49 141.41,56.49 141.31,56.59 141.31,69.02
  BOTTOM w0.076: UC1.AU29 138.9,81.07 138.9,80.39 139.17,80.12 139.17,79.22 139.05,79.09 139.05,77.81 138.85,77.61 138.85,75.24 v2(139.24,74.85)
  BOTTOM w0.102: v2(140.18,41.14) 140.5,41.14 140.85,40.79 JDIMM1.142
DDR_A_D40: length 49.1
  IN1 w0.076: 143.05,68.72 143.05,69.36 139.96,72.45 139.96,75.43 v2(139.24,76.15)
  IN1 w0.107: v2(142.48,44.01) 142.07,43.6 142.07,41.24 141.96,41.14 141.76,41.14 141.66,41.24 141.66,52.17 143.99,54.51 143.99,61.6 143.05,62.55 143.05,68.72
  BOTTOM w0.076: UC1.AY27 139.8,79.14 139.55,78.9 139.55,78.25 139.84,77.96 139.84,76.75 v2(139.24,76.15)
  BOTTOM w0.102: JDIMM1.147 142.35,46.8 141.92,46.36 141.92,44.57 v2(142.48,44.01)
DDR_A_D41: length 49.8
  IN1 w0.076: v2(139.24,76.8) 139.83,76.8 140.14,76.49 140.14,72.64 143.41,69.37
  IN1 w0.107: 143.41,69.37 143.41,62.85 144.35,61.9 144.35,61.39 144.46,61.29 145.27,61.29 145.38,61.18 145.38,60.97 145.27,60.86 144.46,60.86 144.35,60.75 144.35,60.54 144.46,60.43 145.41,60.43 145.51,60.33 145.51,60.11 145.41,60.01 144.46,60.01 144.35,59.9 144.35,59.67 144.46,59.56 145.41,59.56 145.51,59.45 145.51,59.24 145.41,59.13 144.46,59.13 144.35,59.03 144.35,58.81 144.46,58.71 145.22,58.71 145.34,58.58 145.34,58.4 145.22,58.28 144.46,58.28 144.35,58.17 144.35,55.55 144.46,55.44 144.98,55.44 145.09,55.33 145.09,55.12 144.98,55.01 144.46,55.01 144.35,54.91 144.35,54.36 142.07,52.07 142.07,45.94 v2(142.48,45.53)
  BOTTOM w0.076: UC1.AW27 139.8,79.82 139.5,79.53 139.5,79.08 139.39,78.97 139.39,78.17 139.65,77.91 139.65,77.21 v2(139.24,76.8)
  BOTTOM w0.102: v2(142.48,45.53) 142.95,46 JDIMM1.149
DDR_A_D42: length 48.3
  IN1 w0.076: 146.69,68.74 146.01,69.42 145,69.42 141.99,72.43 141.99,73.48 141.76,73.71 141.76,73.94 v2(141.43,74.27)
  IN1 w0.107: v2(145.55,45.51) 145.11,45.95 145.11,48.41 145.66,48.96 145.66,49.95 147.1,51.39 147.1,51.54 146.54,52.11 146.54,52.26 146.69,52.41 146.84,52.41 147.4,51.85 147.56,51.85 148.37,52.66 148.37,56.38 148.68,56.7 148.68,56.85 148.51,57.02 148.51,57.17 148.66,57.32 148.81,57.32 148.99,57.15 149.14,57.15 149.61,57.62 149.61,57.83 149.5,57.94 148.93,57.94 148.82,58.05 148.82,58.26 148.93,58.37 149.5,58.37 149.61,58.47 149.61,58.69 149.5,58.79 148.93,58.79 148.82,58.9 148.82,59.11 148.93,59.22 149.5,59.22 149.61,59.33 149.61,61.22 146.69,64.14 146.69,68.74
  BOTTOM w0.076: UC1.AY25 141.02,79.28 141.02,78.5 141.41,78.11 141.72,78.11 141.85,77.98 141.85,76.37 142.02,76.2 142.02,74.86 v2(141.43,74.27)
  BOTTOM w0.102: JDIMM1.157 145.35,46.79 145.17,46.61 145.17,45.89 v2(145.55,45.51)
DDR_A_D43: length 49.2
  IN1 w0.076: v2(141.38,73.72) 141.8,73.29 141.8,72.39 145.81,68.38
  IN1 w0.107: v2(145.55,43.98) 144.75,44.79 144.75,48.56 145.3,49.11 145.3,50.43 146.03,51.16 146.03,52.35 148,54.32 148,57.36 148.37,57.73 148.37,59.58 148.48,59.69 149.14,59.69 149.25,59.79 149.25,60.01 149.14,60.11 148.48,60.11 148.37,60.22 148.37,60.43 148.48,60.54 149.14,60.54 149.25,60.65 149.25,60.86 149.14,60.97 148.48,60.97 148.37,61.07 148.37,61.61 145.81,64.17 145.81,68.38
  BOTTOM w0.076: v2(141.38,73.72) 141.72,73.72 142.18,74.18 142.18,76.27 142.02,76.43 142.02,78.05 141.79,78.28 141.48,78.28 141.18,78.57 141.18,79.03 141.44,79.28 141.44,79.47 141.39,79.57 141.39,79.58 141.36,79.63 141.36,79.84 UC1.AW25
  BOTTOM w0.102: v2(145.55,43.98) 146.15,44.58 146.15,46.46 145.95,46.67 JDIMM1.159
DDR_A_D44: length 49.6
  IN1 w0.076: 143.77,69.29 140.32,72.75 140.32,76.84 139.71,77.45 v2(139.24,77.45)
  IN1 w0.107: v2(142.48,42.49) 142.9,42.9 142.9,49.67 142.58,49.99 142.58,52.07 145.7,55.19 145.7,56.16 145.33,56.53 144.82,56.53 144.71,56.64 144.71,56.85 144.82,56.96 145.62,56.96 145.73,57.07 145.73,57.28 145.62,57.39 144.89,57.39 144.76,57.51 144.76,57.69 144.89,57.81 145.57,57.81 145.73,57.97 145.73,58.68 145.87,58.83 145.87,61.2 143.77,63.3 143.77,69.29
  BOTTOM w0.076: UC1.AV27 139.9,80.58 139.34,80.01 139.34,79.15 139.21,79.02 139.21,77.97 139.24,77.94 v2(139.24,77.45)
  BOTTOM w0.102: v2(142.48,42.49) 142.05,42.06 JDIMM1.146
DDR_A_D45: length 50.7
  IN1 w0.076: v2(141.49,77.2) 140.49,76.2 140.49,72.82 144.13,69.19
  IN1 w0.107: v2(142.48,40.96) 143.26,41.74 143.26,49.95 142.96,50.25 142.96,51.94 146.22,55.2 146.22,58.6 146.37,58.75 146.77,58.75 146.88,58.86 146.88,59.07 146.77,59.18 146.35,59.18 146.24,59.28 146.24,59.5 146.35,59.6 146.77,59.6 146.88,59.71 146.88,59.92 146.77,60.03 146.35,60.03 146.24,60.14 146.24,60.35 146.35,60.46 146.77,60.46 146.88,60.56 146.88,60.78 146.77,60.88 146.35,60.88 146.24,60.99 146.24,61.54 144.13,63.65 144.13,69.19
  BOTTOM w0.076: UC1.AU27 140.56,81.36 140.75,81.17 140.75,80.29 140.69,80.16 140.69,79.96 140.76,79.8 140.76,79.67 140.69,79.51 140.69,78 v2(141.49,77.2)
  BOTTOM w0.102: JDIMM1.148 142.65,40.79 v2(142.48,40.96)
DDR_A_D46: length 50
  IN1 w0.076: v2(141.49,77.76) 141.86,77.76 141.99,77.62 141.99,73.71 142.22,73.48 142.22,72.44 144.96,69.7 146.14,69.7 146.95,68.89
  IN1 w0.107: 146.95,68.89 147.05,68.79 147.05,64.39 149.97,61.47 149.97,57.31 148.74,56.07 148.74,52.47 146.15,49.88 146.15,48.41 146.05,48.31 145.73,48.31 145.62,48.2 145.62,47.99 145.73,47.88 146.05,47.88 146.15,47.77 146.15,47.56 146.05,47.45 145.73,47.45 145.62,47.35 145.62,47.13 145.73,47.03 146.05,47.03 146.15,46.92 146.15,43.09 v2(145.55,42.49)
  BOTTOM w0.076: v2(141.49,77.76) 141.22,77.76 140.85,78.12 140.85,79.47 140.9,79.58 140.93,79.63 140.93,79.84 140.9,79.89 140.86,79.98 140.85,79.99 140.85,80.12 140.9,80.23 141.15,80.47 UC1.AV25
  BOTTOM w0.102: JDIMM1.158 145.65,40.3 145.14,40.81 145.14,42.07 v2(145.55,42.49)
DDR_A_D47: length 51
  IN1 w0.076: v2(142.39,73.82) 142.45,73.76 142.45,72.45 145.03,69.87 146.32,69.87 147.35,68.84
  IN1 w0.107: v2(145.63,40.96) 145.63,40.49 145.83,40.28 146.33,40.28 146.57,40.53 146.57,49.77 149.13,52.33 149.13,55.71 149.38,55.96 149.38,55.98 150.46,57.07 150.46,61.59 147.45,64.6 147.45,68.74 147.35,68.84
  BOTTOM w0.076: UC1.AU25 141.53,80.97 141.53,79.67 141.58,79.56 141.6,79.51 141.6,79.21 141.46,79.07 141.46,79.07 141.35,78.96 141.35,78.64 141.54,78.44 141.86,78.44 142.18,78.12 142.18,76.5 142.35,76.34 142.35,73.86 v2(142.39,73.82)
  BOTTOM w0.102: v2(145.63,40.96) 146,40.96 146.25,40.71 JDIMM1.160
DDR_A_D48: length 51
  IN1 w0.076: v2(143.29,75.45) 143.7,75.04 143.7,72.16 144.66,71.2 146.13,71.2 148.55,68.79
  IN1 w0.107: 148.55,68.79 148.79,68.54 148.79,66.08 152.79,62.08 152.79,59.03 152.58,58.83 152.28,58.83 152.12,58.67 152.12,55.04 152.01,54.93 151.6,54.93 151.49,54.83 151.49,54.61 151.6,54.51 152.84,54.51 152.96,54.38 152.96,54.21 152.84,54.08 151.6,54.08 151.49,53.97 151.49,53.76 151.6,53.65 152.01,53.65 152.12,53.55 152.12,53.26 147.91,49.05 147.91,44.23 148.13,44.01 v2(148.36,44.01)
  BOTTOM w0.076: UC1.AY23 142.5,79.15 142.51,79.14 142.51,78.52 142.68,78.36 142.68,76.71 142.84,76.54 142.84,75.9 v2(143.29,75.45)
  BOTTOM w0.102: v2(148.36,44.01) 148.25,44.01 147.15,45.11 JDIMM1.163
DDR_A_D49: length 52.1
  IN1 w0.076: v2(143.29,74.8) 142.86,75.23 142.86,75.58 143.1,75.82 143.52,75.82 143.95,75.39 143.95,72.57 144.47,72.05 145.54,72.05 149.15,68.44 149.15,68.38
  IN1 w0.107: v2(148.36,45.53) 148.77,45.94 148.77,47.25 148.67,47.35 148.38,47.35 148.27,47.46 148.27,47.67 148.38,47.78 148.71,47.78 148.82,47.89 148.82,48.1 148.71,48.21 148.38,48.21 148.27,48.31 148.27,48.53 148.38,48.63 148.67,48.63 148.77,48.74 148.77,49.34 149.15,49.72 153.35,53.92 153.35,56.12 153.24,56.23 152.74,56.23 152.63,56.34 152.63,56.55 152.74,56.66 153.24,56.66 153.35,56.76 153.35,56.98 153.24,57.08 152.74,57.08 152.63,57.19 152.63,57.4 152.74,57.51 153.24,57.51 153.35,57.62 153.35,57.83 153.24,57.94 152.74,57.94 152.63,58.04 152.63,58.26 152.74,58.36 153.24,58.36 153.35,58.47 153.35,62.03 149.15,66.23 149.15,68.38
  BOTTOM w0.076: UC1.AW23 142.5,79.86 142.3,79.66 142.21,79.48 142.21,79.21 142.34,79.07 142.34,78.45 142.51,78.29 142.51,76.64 142.68,76.47 142.68,75.41 v2(143.29,74.8)
  BOTTOM w0.102: v2(148.36,45.53) 147.75,46.15 JDIMM1.165
DDR_A_D50: length 50.8
  IN1 w0.076: 151.37,70.38 150.5,71.25 147.81,71.25 145.51,73.55 v2(145.03,73.55)
  IN1 w0.107: v2(151.22,45.62) 151.72,46.13 151.72,47.36 151.56,47.52 151.31,47.52 151.19,47.64 151.19,47.82 151.31,47.94 151.56,47.94 151.67,48.05 151.67,48.45 151.96,48.74 151.96,49.37 156.3,53.71 156.3,54.07 156.2,54.17 155.94,54.17 155.84,54.28 155.84,54.49 155.94,54.6 156.2,54.6 156.3,54.71 156.3,54.92 156.2,55.03 155.94,55.03 155.84,55.13 155.84,55.35 155.94,55.45 156.2,55.45 156.3,55.56 156.3,55.77 156.2,55.88 155.94,55.88 155.84,55.99 155.84,56.2 155.94,56.31 156.2,56.31 156.3,56.41 156.3,56.63 156.2,56.73 155.94,56.73 155.84,56.84 155.84,57.05 155.94,57.16 156.2,57.16 156.3,57.27 156.3,57.48 156.2,57.59 155.94,57.59 155.84,57.69 155.84,57.91 155.94,58.01 156.2,58.01 156.3,58.12 156.3,58.33 156.2,58.44 155.94,58.44 155.84,58.55 155.84,58.76 155.94,58.87 156.2,58.87 156.3,58.97 156.3,62.22 151.37,67.15 151.37,68.94 151.26,69.05 150.96,69.05 150.86,69.15 150.86,69.37 150.96,69.47 151.26,69.47 151.37,69.58 151.37,70.38
  BOTTOM w0.076: UC1.AY21 143.97,79.29 143.97,78.04 144.27,77.74 144.27,74.32 v2(145.03,73.55)
  BOTTOM w0.102: v2(151.22,45.62) 151.22,45.68 150.75,46.14 JDIMM1.175
DDR_A_D51: length 52.6
  IN1 w0.076: 152.19,70.02 150.76,71.45 147.91,71.45 145.17,74.2 v2(145.03,74.2)
  IN1 w0.107: v2(151.22,44.01) 151.52,44.01 151.63,43.9 151.63,42.83 151.73,42.73 152.02,42.73 152.13,42.83 152.13,48.4 152.32,48.59 152.32,49.22 156.66,53.56 156.66,62.37 151.85,67.19 151.85,68.61 152.19,68.96 152.19,70.02
  BOTTOM w0.076: v2(145.03,74.2) 144.43,74.8 144.43,77.82 144.14,78.11 144.14,79.53 143.85,79.82 UC1.AW21
  BOTTOM w0.102: v2(151.22,44.01) 151.67,44.46 151.67,46.5 151.35,46.82 JDIMM1.177
DDR_A_D52: length 52.9
  IN1 w0.076: 148.43,68.6 146.01,71.02 144.53,71.02 143.29,72.27 v2(143.29,72.91)
  IN1 w0.107: 148.43,68.6 148.43,65.93 152.33,62.02 152.33,60.26 152.23,60.15 151.72,60.15 151.61,60.04 151.61,59.83 151.72,59.72 152.23,59.72 152.33,59.62 152.33,59.4 152.23,59.3 151.72,59.3 151.61,59.19 151.61,56.52 151.09,56 151.09,54.89 150.98,54.78 150.59,54.78 150.48,54.67 150.48,54.46 150.59,54.35 150.98,54.35 151.09,54.25 151.09,54.03 150.98,53.93 150.59,53.93 150.48,53.82 150.48,53.61 150.59,53.5 150.98,53.5 151.09,53.39 151.09,52.79 147.55,49.25 147.55,43.3 v2(148.36,42.49)
  BOTTOM w0.076: UC1.AV23 142.11,80.32 142.11,79.66 142.06,79.56 142.04,79.52 142.04,79.14 142.18,79 142.18,78.38 142.35,78.21 142.35,76.57 142.51,76.41 142.51,74.54 142.81,74.24 142.81,73.4 v2(143.29,72.91)
  BOTTOM w0.102: JDIMM1.164 147.45,42.11 147.82,42.49 v2(148.36,42.49)
DDR_A_D53: length 53.5
  IN1 w0.076: 147.87,68.85 146.69,70.03 145.1,70.03 142.75,72.37 142.75,73.62 v2(143.29,74.15)
  IN1 w0.107: 147.87,68.85 148.07,68.66 148.07,64.9 148.58,64.38 148.74,64.38 149.02,64.67 149.18,64.67 149.33,64.52 149.33,64.37 149.04,64.08 149.04,63.93 149.19,63.78 149.34,63.78 149.63,64.07 149.78,64.07 151.75,62.1 151.75,61.12 151.08,60.45 151.08,56.81 149.99,55.72 149.99,55.7 149.89,55.61 149.89,52.61 149.74,52.46 149.74,52.07 147.19,49.52 147.19,40.91 147.53,40.57 148.11,40.57 148.36,40.82 v2(148.36,40.96)
  BOTTOM w0.076: v2(143.29,74.15) 143.93,74.79 143.93,77.54 143.63,77.85 143.63,78.98 143.39,79.22 143.39,79.51 143.47,79.67 143.47,79.8 143.39,79.96 143.39,80.16 143.42,80.21 143.46,80.3 143.47,80.32 143.47,80.5 143.45,80.52 143.45,80.9 143.47,80.91 143.47,81.15 143.26,81.36 UC1.AU23
  BOTTOM w0.102: v2(148.36,40.96) 148.05,40.65 JDIMM1.166
DDR_A_D54: length 52.2
  IN1 w0.076: v2(145.03,72.9) 145.86,72.9 147.67,71.09 149.78,71.09 150.42,70.44 150.42,69.12 151.01,68.53
  IN1 w0.107: 151.01,68.53 151.01,67 155.48,62.54 155.48,62.21 155.58,62.1 155.76,62.1 155.89,61.98 155.89,61.8 155.76,61.67 155.58,61.67 155.48,61.57 155.48,61.35 155.58,61.25 155.78,61.25 155.9,61.12 155.9,60.95 155.78,60.82 155.58,60.82 155.48,60.71 155.48,60.5 155.58,60.39 155.77,60.39 155.9,60.27 155.9,60.09 155.77,59.97 155.58,59.97 155.48,59.86 155.48,53.4 151.6,49.52 151.6,48.89 150.81,48.1 150.81,42.68 151,42.49 v2(151.22,42.49)
  BOTTOM w0.076: UC1.AV21 143.74,80.36 143.61,80.23 143.56,80.12 143.56,79.99 143.57,79.97 143.61,79.89 143.63,79.84 143.63,79.63 143.56,79.47 143.56,79.29 143.8,79.04 143.8,77.97 144.1,77.68 144.1,73.84 v2(145.03,72.9)
  BOTTOM w0.102: v2(151.22,42.49) 150.45,41.72 JDIMM1.174
DDR_A_D55: length 53.3
  IN1 w0.076: 150.65,68.38 150.21,68.82 150.21,70.09 149.38,70.92 147.53,70.92 145.91,72.54 144.79,72.54 144.64,72.7 144.64,74.45 v2(145.03,74.85)
  IN1 w0.107: 150.65,68.38 150.65,66.85 155.12,62.39 155.12,53.56 150.45,48.89 150.45,40.04 150.55,39.93 150.7,39.93 150.81,40.04 150.81,40.85 150.91,40.96 v2(151.22,40.96)
  BOTTOM w0.076: v2(145.03,74.85) 144.6,75.28 144.6,77.89 144.31,78.18 144.31,79.6 144.14,79.76 144.14,80.18 144.02,80.3 144.02,80.57 144.02,80.57 144.02,81.08 UC1.AU21
  BOTTOM w0.102: v2(151.22,40.96) 151.05,40.79 JDIMM1.176
DDR_A_D56: length 54.7
  IN1 w0.076: 151.08,71.73 147.94,71.73 145.51,74.16 145.51,74.4 145.59,74.47 145.99,74.47 146.08,74.56 146.08,74.69 145.99,74.78 145.59,74.78 145.51,74.85 145.51,75.01 145.59,75.08 145.99,75.08 146.08,75.17 146.08,75.3 145.99,75.39 145.59,75.39 145.51,75.46 145.51,75.67 v2(145.03,76.15)
  IN1 w0.107: 151.08,71.73 152.46,70.35 152.46,69.01 152.7,68.77 152.7,67.2 152.86,67.05 152.88,67.05 157.28,62.65 157.28,59.1 157.38,59 157.79,59 157.91,58.87 157.91,58.7 157.79,58.57 157.38,58.57 157.28,58.46 157.28,58.25 157.38,58.14 157.69,58.14 157.82,58.02 157.82,57.84 157.69,57.72 157.38,57.72 157.28,57.61 157.28,53.18 153.44,49.34 153.44,48.86 152.93,48.35 152.93,48.34 152.74,48.14 152.74,47.42 152.85,47.31 153.34,47.31 153.46,47.19 153.46,47.01 153.34,46.89 152.85,46.89 152.74,46.78 152.74,43.81 152.89,43.67 153.04,43.67 153.15,43.78 v2(153.15,44.01)
  BOTTOM w0.076: v2(145.03,76.15) 145.55,76.67 145.55,77.68 144.8,78.44 144.8,79.28 UC1.AY19
  BOTTOM w0.102: JDIMM1.181 152.55,46.79 152.38,46.62 152.38,44.78 v2(153.15,44.01)
DDR_A_D57: length 56
  IN1 w0.076: v2(145.03,76.8) 146.28,75.55 146.28,73.69 148.01,71.96 151.28,71.96
  IN1 w0.107: 151.28,71.96 153.22,70.02 153.22,67.25 154.75,65.71 154.9,65.71 155.21,66.02 155.36,66.02 155.51,65.87 155.51,65.72 155.2,65.41 155.2,65.26 155.36,65.11 155.51,65.11 155.81,65.41 155.96,65.41 156.11,65.26 156.11,65.11 155.81,64.81 155.81,64.66 155.96,64.51 156.11,64.51 156.41,64.81 156.56,64.81 156.71,64.66 156.71,64.51 156.41,64.21 156.41,64.06 156.56,63.9 156.71,63.9 157.02,64.21 157.17,64.21 157.32,64.06 157.32,63.9 157.02,63.6 157.02,63.45 157.64,62.83 158.12,62.83 158.27,62.68 158.27,62.49 158.17,62.39 157.82,62.39 157.71,62.28 157.71,62.07 157.82,61.96 158.17,61.96 158.27,61.85 158.27,61.64 158.17,61.53 157.82,61.53 157.71,61.43 157.71,61.21 157.82,61.11 158.17,61.11 158.27,61 158.27,60.79 158.17,60.68 157.82,60.68 157.71,60.57 157.71,60.36 157.82,60.25 158.17,60.25 158.27,60.15 158.27,59.93 158.17,59.83 157.82,59.83 157.71,59.72 157.71,59.51 157.82,59.4 158.12,59.4 158.27,59.25 158.27,57.79 157.64,57.15 157.64,53.03 153.8,49.19 153.8,48.36 153.7,48.25 153.35,48.25 153.24,48.15 153.24,47.93 153.35,47.83 153.7,47.83 153.82,47.7 153.82,46 153.36,45.53 v2(153.15,45.53)
  BOTTOM w0.076: UC1.AW19 144.93,79.82 144.64,79.53 144.64,78.37 145.39,77.61 145.39,77.15 v2(145.03,76.8)
  BOTTOM w0.102: v2(153.15,45.53) 152.74,45.95 152.74,46.46 153.15,46.87 JDIMM1.183
DDR_A_D58: length 54.2
  IN1 w0.076: v2(146.99,76.22) 148.33,74.88 153.9,74.88
  IN1 w0.107: v2(156.92,44.01) 156.51,44.42 156.51,46.37 157.51,47.38 157.94,47.38 160.98,50.42 160.98,53.93 161.09,54.03 161.16,54.03 161.27,54.14 161.27,54.35 161.16,54.46 161.09,54.46 160.98,54.57 160.98,54.78 161.09,54.89 161.16,54.89 161.27,54.99 161.27,55.21 161.16,55.31 161.09,55.31 160.98,55.42 160.98,55.63 161.09,55.74 161.16,55.74 161.27,55.85 161.27,56.06 161.16,56.17 161.09,56.17 160.98,56.27 160.98,56.49 161.09,56.59 161.16,56.59 161.27,56.7 161.27,56.91 161.16,57.02 161.09,57.02 160.98,57.13 160.98,57.34 161.09,57.45 161.16,57.45 161.27,57.55 161.27,57.77 161.16,57.87 161.09,57.87 160.98,57.98 160.98,58.19 161.09,58.3 161.16,58.3 161.27,58.41 161.27,58.62 161.16,58.73 161.09,58.73 160.98,58.83 160.98,59.05 161.09,59.15 161.16,59.15 161.27,59.26 161.27,59.47 161.16,59.58 161.09,59.58 160.98,59.69 160.98,59.9 161.09,60.01 161.16,60.01 161.27,60.11 161.27,60.33 161.16,60.43 161.09,60.43 160.98,60.54 160.98,60.75 161.09,60.86 161.16,60.86 161.27,60.97 161.27,61.18 161.16,61.29 161.09,61.29 160.98,61.39 160.98,64.98 156.52,69.44 156.52,72.27 153.9,74.88
  BOTTOM w0.076: v2(146.99,76.22) 146.45,76.76 146.45,78.01 146.26,78.2 146.26,79.07 146.28,79.09 UC1.AY17
  BOTTOM w0.102: JDIMM1.191 155.55,45.34 156.88,44.01 v2(156.92,44.01)
DDR_A_D59: length 55.4
  IN1 w0.107: v2(156.92,45.53) 157.22,45.53 157.35,45.4 157.35,42.57 157.51,42.42 157.77,42.42 157.93,42.57 157.93,46.52 158.22,46.82 161.63,50.22 161.63,64.85 156.83,69.65 156.83,72.6 154.11,75.32 148.32,75.32 147.38,76.26 147.38,77.03 v2(146.99,77.41)
  BOTTOM w0.076: UC1.AW17 146.5,79.84 146.5,79.63 146.57,79.47 146.57,79.29 146.44,79.16 146.44,78.25 146.61,78.08 146.61,77.79 v2(146.99,77.41)
  BOTTOM w0.102: v2(156.92,45.53) 156.15,46.3 JDIMM1.193
DDR_A_D60: length 56.2
  IN1 w0.076: 153.94,71.01 152.76,72.19 148.02,72.19 146.49,73.72 146.49,76 v2(145.03,77.45)
  IN1 w0.107: v2(153.15,42.49) 153.57,42.91 153.57,44.28 154.18,44.89 154.18,48.99 158.76,53.57 158.76,63.12 157.08,64.8 157.08,64.95 157.33,65.19 157.33,65.34 157.18,65.49 157.06,65.49 156.82,65.25 156.63,65.25 156.48,65.4 156.48,65.55 156.72,65.8 156.72,65.95 156.57,66.1 156.42,66.1 156.18,65.86 156.03,65.86 155.88,66.01 155.88,66.16 156.12,66.4 156.12,66.55 155.97,66.7 155.82,66.7 155.58,66.46 154.56,66.46 153.94,67.08 153.94,68.14 154.26,68.46 154.26,70.69 153.94,71.01
  BOTTOM w0.076: UC1.AV19 145.04,80.58 144.64,80.18 144.64,79.77 144.47,79.61 144.47,78.3 145.03,77.74 v2(145.03,77.45)
  BOTTOM w0.102: JDIMM1.180 152.25,41.59 v2(153.15,42.49)
DDR_A_D61: length 57.1
  IN1 w0.076: v2(146.98,75.08) 147.4,74.66 147.4,73.04 148.05,72.39 153.2,72.39 154.54,71.05
  IN1 w0.107: 154.54,71.05 154.54,68.18 154.35,67.99 154.35,67.81 154.47,67.69 154.65,67.69 155,68.03 155.15,68.03 155.3,67.88 155.3,67.73 155.08,67.52 155.08,67.34 155.21,67.21 155.38,67.21 155.6,67.43 155.75,67.43 159.12,64.06 159.12,53.42 154.57,48.86 154.57,44.58 153.96,43.97 153.96,40.5 153.85,40.39 153.26,40.39 153.15,40.5 v2(153.15,40.96)
  BOTTOM w0.076: v2(146.98,75.08) 146.09,75.97 146.09,77.9 145.93,78.06 145.93,79.06 145.82,79.17 145.82,79.51 145.9,79.67 145.9,79.8 145.82,79.96 145.82,80.16 145.85,80.21 145.89,80.3 145.9,80.32 145.9,81.15 145.69,81.36 UC1.AU19
  BOTTOM w0.102: JDIMM1.182 152.85,40.66 v2(153.15,40.96)
DDR_A_D62: length 55.4
  IN1 w0.076: 153.56,74.48 148.15,74.48 v2(146.98,75.65)
  IN1 w0.107: v2(156.92,42.49) 156.16,41.73 156.01,41.73 155.83,41.92 155.83,42.07 156.15,42.39 156.15,46.72 157.17,47.74 157.79,47.74 160.62,50.57 160.62,64.83 156.19,69.26 156.19,71.85 153.56,74.48
  BOTTOM w0.076: UC1.AV17 146.28,80.47 146.04,80.23 145.99,80.12 145.99,79.99 146,79.97 146.04,79.89 146.04,79.89 146.06,79.84 146.06,79.63 145.99,79.47 145.99,79.24 146.1,79.13 146.1,78.13 146.28,77.95 146.28,76.34 v2(146.98,75.65)
  BOTTOM w0.102: v2(156.92,42.49) 155.85,41.42 JDIMM1.192
DDR_A_D63: length 56.6
  IN1 w0.107: v2(156.92,40.96) 158.31,40.96 159.19,41.84 159.19,47.1 162.03,49.94 162.03,64.95 157.18,69.8 157.18,72.85 154.39,75.65 149.35,75.65 148.58,76.41 148.58,78.59 148.29,78.88 147.92,78.88 147,77.97 v2(146.99,77.97)
  BOTTOM w0.076: UC1.AU17 146.57,81.07 146.57,80.32 146.66,80.22 146.66,79.67 146.71,79.56 146.74,79.51 146.74,79.22 146.61,79.09 146.61,78.35 v2(146.99,77.97)
  BOTTOM w0.102: v2(156.92,40.96) 156.88,40.96 156.45,40.53 JDIMM1.194
DDR_A_DQS0: length 68.5
  IN1 w0.107: 109.48,82.43 111.14,84.08
  IN1 w0.119: v2(98.29,43.43) 98.24,43.38 98.24,43.16 98.32,43.08 98.63,43.08 98.74,43.19 98.74,74.16 102.33,77.75 106,77.75 108.14,79.88 108.14,81.95 108.62,82.43 109.48,82.43 ; 111.14,84.08 112.82,84.08 113.55,84.81 117.24,84.81 117.35,84.92 117.35,85.94 116.6,86.69 115.86,86.69 115.64,86.48 115.64,86.21 115.94,85.92 v2(115.99,85.92)
  BOTTOM w0.076: UC1.AJ62 118.69,86.08 118.75,86.15 118.76,86.22 118.76,86.24 118.7,86.31 118.66,86.32 118.66,86.33 118.6,86.35 118.55,86.37 118.42,86.37 118.26,86.3 118.06,86.3 118.01,86.32 117.92,86.37 117.9,86.37 117.77,86.37 117.72,86.35 117.61,86.3 115.83,86.3 115.71,86.18 115.71,86.13 115.92,85.92 v2(115.99,85.92)
  BOTTOM w0.114: v2(98.29,43.43) 98.29,43.22 98.46,43.06 98.71,43.06 99.1,42.67 99.1,40.82 99.45,40.47 JDIMM1.12
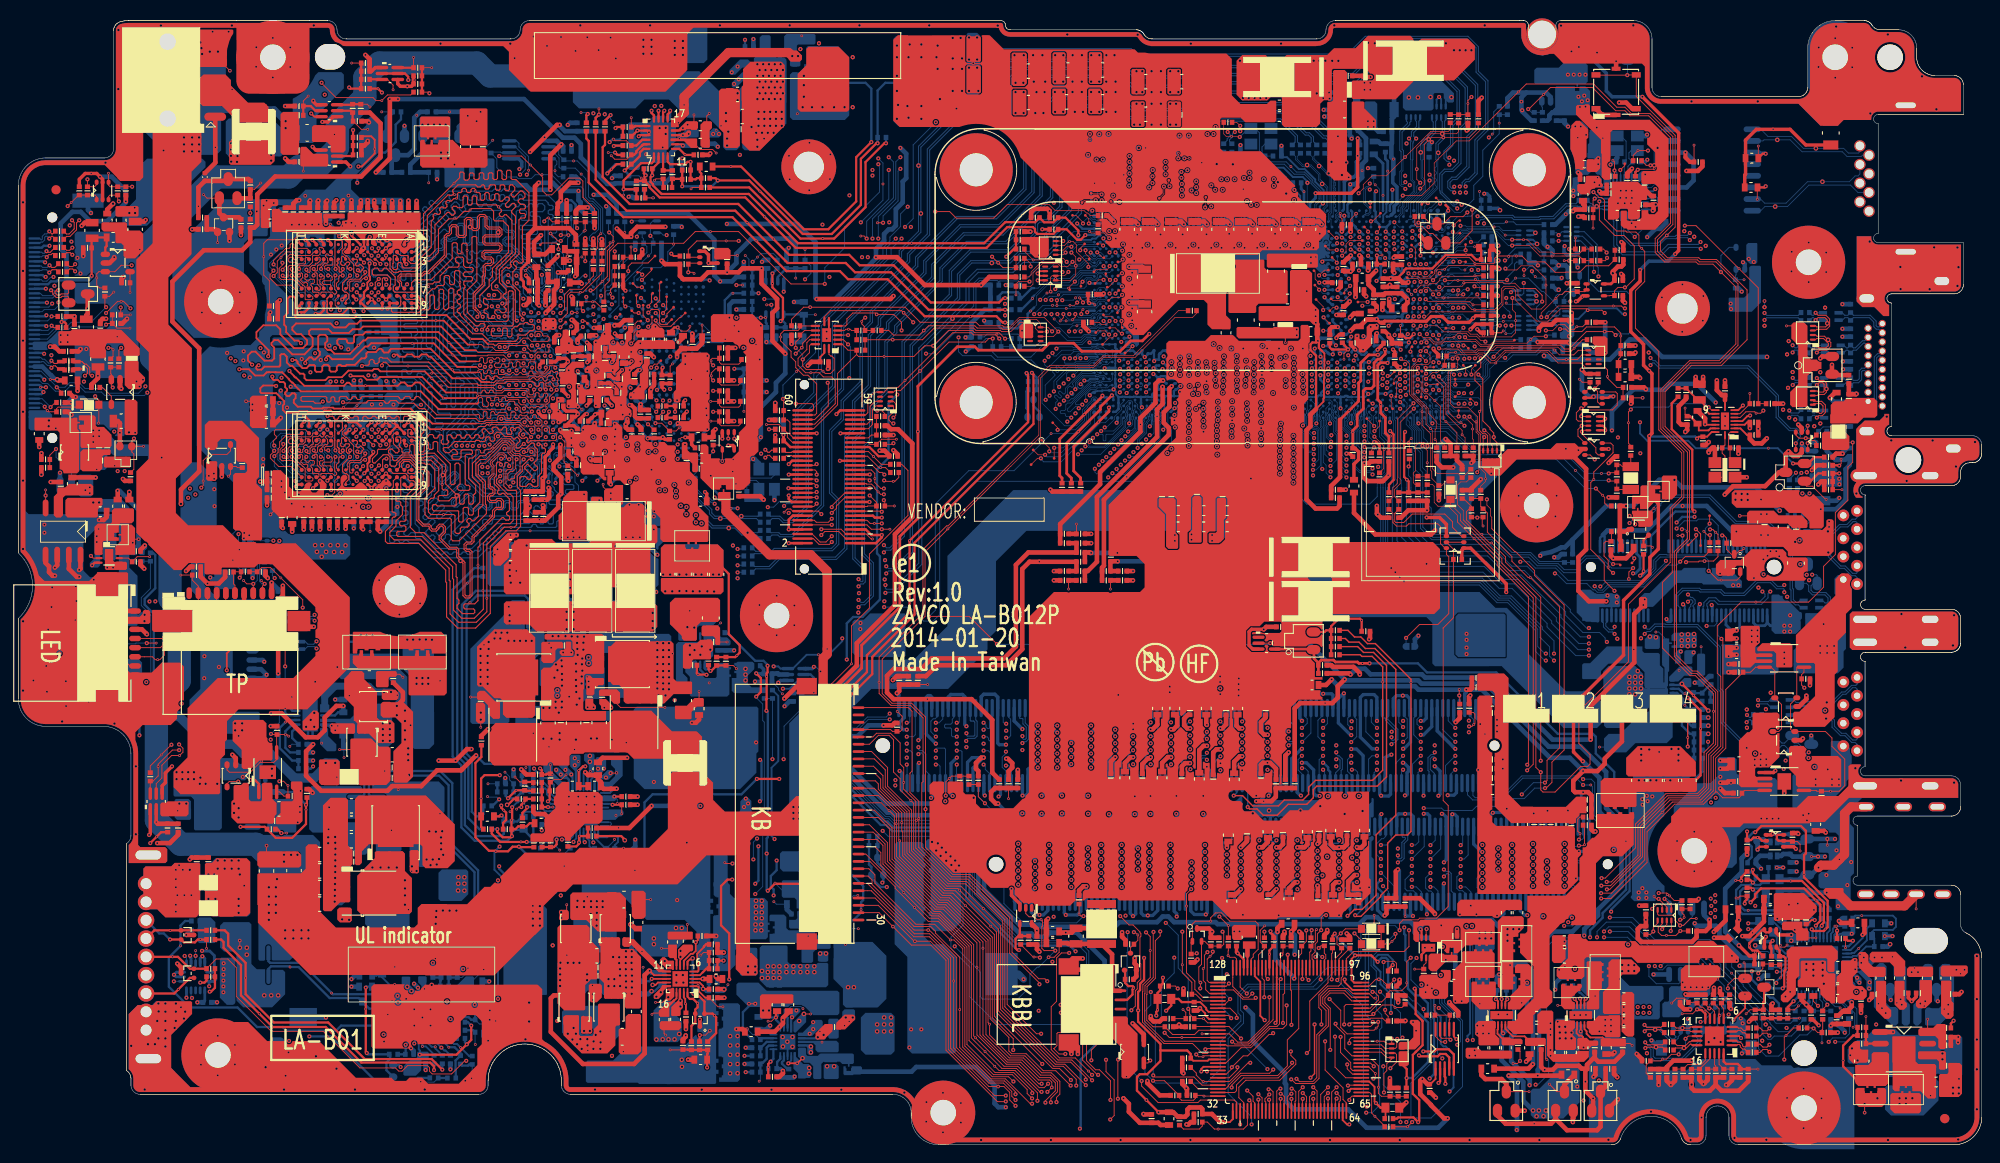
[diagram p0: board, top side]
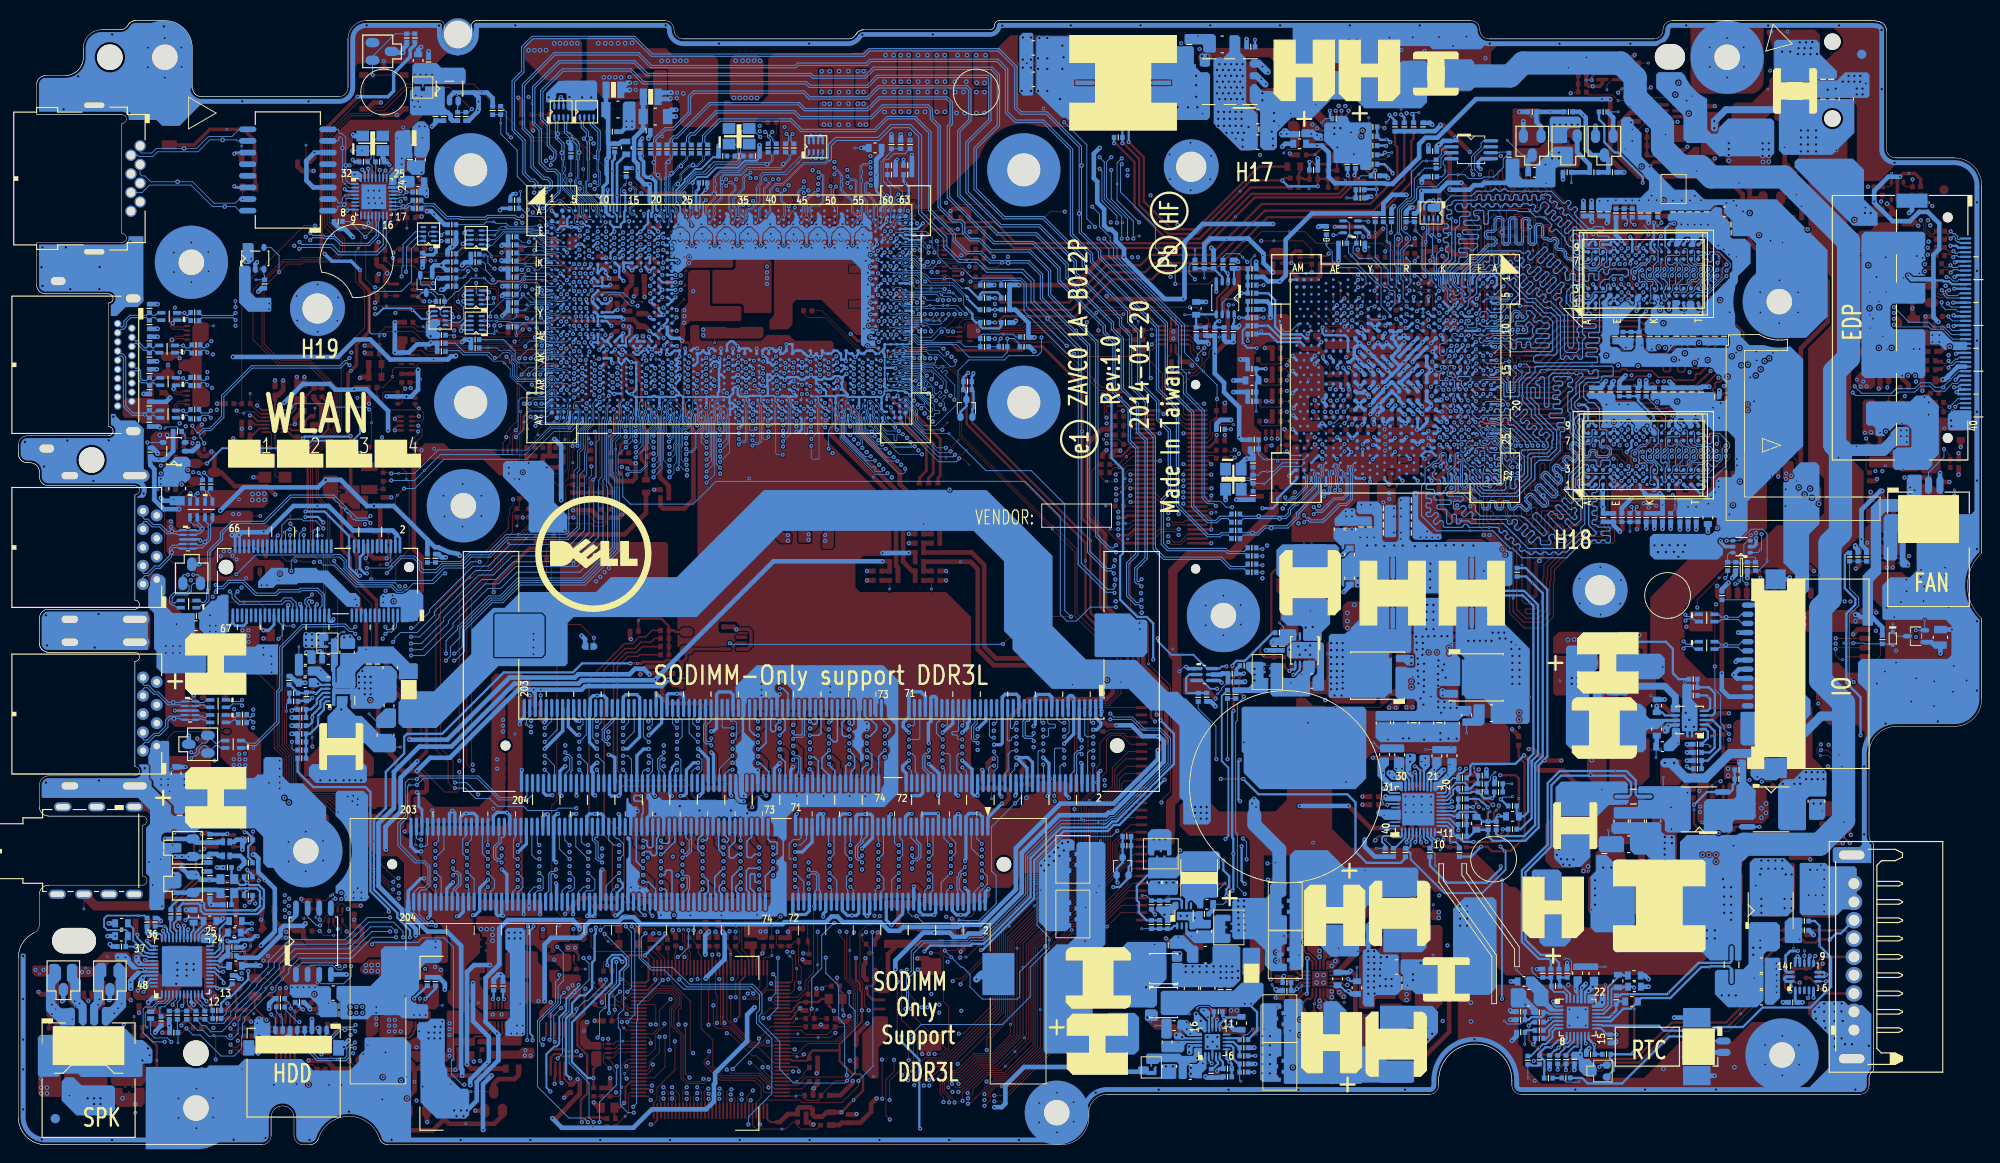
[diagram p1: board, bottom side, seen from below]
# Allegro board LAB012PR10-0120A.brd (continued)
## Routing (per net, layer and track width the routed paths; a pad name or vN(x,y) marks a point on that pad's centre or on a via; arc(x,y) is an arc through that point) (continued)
DDR_A_DQS1: length 59.2
  IN1 w0.107: v2(115.43,82.53) 115.43,82.79
  IN1 w0.119: 115.43,82.79 115.32,82.9 115.32,83.4 116.06,84.13 116.73,84.13 117.13,83.74 117.13,82.69 116.31,81.87 116.31,81.6 114.05,79.34 114.05,78.84 114.26,78.64 114.26,78 113.62,77.35 112.99,77.35 109.18,73.54 109.18,73.5 103.93,68.25 103.93,46.66 104.33,46.25 104.33,44.56 104.11,44.34 103.66,44.34 103.55,44.23 103.55,44.14 v2(103.51,44.1)
  BOTTOM w0.076: UC1.AN61 118.95,83.65 118.56,84.04 118.08,84.04 117.99,84.08 117.94,84.11 117.73,84.11 117.65,84.07 117.59,84.04 117.59,84.04 116.22,84.04 115.46,83.28 115.46,82.75 115.43,82.72 v2(115.43,82.53)
  BOTTOM w0.114: v2(103.51,44.1) 103.51,44.11 103.56,44.16 103.56,44.28 103.67,44.38 104.45,44.38 104.7,44.64 104.7,46.26 104.55,46.41 JDIMM1.29
DDR_A_DQS2: length 50.2
  IN1 w0.119: v2(116.52,76.3) 116.58,76.3 116.79,76.08 116.79,75.81 113.26,72.27 113.26,71.85 113.21,71.81 113.21,71.45 109.48,67.72 109.43,67.72 109.43,53.78 109,53.34 108.92,53.27 108.92,53.06 108.92,52.44 109.19,52.17 109.33,52.17 109.45,52.06 109.45,51.82 109.33,51.7 109.19,51.7 108.92,51.43 108.92,50.98 109.19,50.72 109.33,50.72 109.45,50.6 109.45,50.36 109.33,50.24 109.19,50.24 108.92,49.97 108.92,44.25 109.18,44 109.52,44 v2(109.64,43.88)
  BOTTOM w0.076: v2(116.52,76.3) 116.74,76.3 116.89,76.14 118.69,76.14 120.91,78.37 120.91,78.97 121.16,79.22 121.16,79.51 121.13,79.56 121.09,79.67 121.09,79.8 121.09,79.82 121.14,79.9 121.16,79.95 121.16,80.16 121.09,80.32 121.09,80.45 121.13,80.55 121.22,80.63 121.31,80.63 121.38,80.56 UC1.AW57
  BOTTOM w0.114: JDIMM1.47 109.95,46.08 110.32,45.71 110.32,44.3 110.05,44.03 109.79,44.03 v2(109.64,43.88)
DDR_A_DQS3: length 47.3
  IN1 w0.076: 118.06,71.81 118.06,72.91 121.7,76.56 122.15,76.56 122.15,76.55 122.67,76.55 v2(122.69,76.58)
  IN1 w0.119: 118.06,71.81 118.06,70.25 114.94,67.14 114.94,45.65 115.45,45.14 115.45,43 115.35,42.9 115.18,42.9 v2(114.97,43.12)
  BOTTOM w0.076: v2(122.69,76.58) 122.45,76.58 122.4,76.63 122.4,76.95 123.19,77.74 123.19,78.67 123.34,78.82 123.34,78.94 123.59,79.19 123.59,79.51 123.57,79.56 123.52,79.67 123.52,79.8 123.53,79.82 123.57,79.9 123.59,79.95 123.59,80.34 123.63,80.38 UC1.AW53
  BOTTOM w0.114: v2(114.97,43.12) 114.97,42.87 115.07,42.76 115.35,42.76 115.65,42.46 115.65,41.1 115.05,40.5 JDIMM1.64
DDR_A_DQS4: length 45.9
  IN1 w0.076: 140.36,69.8 140.36,69.83 138.4,71.79 138.4,77.43 138.11,77.72 137.97,77.72 v2(137.79,77.54)
  IN1 w0.119: 140.36,69.8 140.36,68.42 140.32,68.38 140.32,54.46 139.09,53.23 139.09,47.8 138.03,46.74 138.03,44.05 138.28,43.8 138.55,43.8 v2(138.72,43.63)
  BOTTOM w0.076: v2(137.79,77.54) 137.6,77.74 137.46,77.74 137.24,77.96 137.24,78.87 137.66,79.29 137.66,79.47 137.61,79.57 137.61,79.58 137.58,79.63 137.58,79.84 137.66,79.99 137.66,80.12 137.61,80.22 137.58,80.28 137.58,80.49 137.65,80.63 137.65,80.64 137.72,80.71 137.81,80.8 137.96,80.8 138.04,80.88 UC1.AV30
  BOTTOM w0.114: JDIMM1.137 139.35,46.1 139.57,45.89 139.57,44.06 139.3,43.79 138.89,43.79 v2(138.72,43.63)
DDR_A_DQS5: length 49.5
  IN1 w0.076: v2(141.47,76) 141.47,75.88 141.36,75.77 141.12,75.77 140.66,75.31 140.66,72.99 144.85,68.8 144.85,68.48 144.76,68.39 144.76,68.38
  IN1 w0.119: v2(143.92,42.87) 143.92,42.63 144.05,42.5 144.36,42.5 144.76,42.9 144.76,43.54 143.88,44.42 143.88,50.76 144.1,50.98 144.1,51.82 146.84,54.55 146.84,57.6 147.5,58.27 147.5,61.16 144.76,63.9 144.76,68.38
  BOTTOM w0.076: UC1.AW26 140.31,80.38 140.25,80.32 140.25,79.96 140.22,79.88 140.19,79.82 140.18,79.8 140.18,79.67 140.2,79.61 140.25,79.51 140.25,79.1 139.96,78.82 139.88,78.74 139.88,78.39 140.47,77.8 140.47,76.22 140.92,75.77 141.23,75.77 v2(141.47,76)
  BOTTOM w0.114: JDIMM1.154 144.45,40.88 144.58,41.01 144.58,42.13 144.23,42.48 144.11,42.48 143.92,42.67 v2(143.92,42.87)
DDR_A_DQS6: length 52.3
  IN1 w0.076: 149.82,68.85 149.82,68.88 149.78,68.92 149.78,69.83 149.04,70.57 147.35,70.57 145.7,72.21 144.61,72.21 144.27,72.55 144.27,76.52 143.8,76.99 143.54,76.99 143.36,76.81 v2(143.36,76.8)
  IN1 w0.119: v2(149.95,43.76) 149.81,43.9 149.22,43.9 148.98,44.14 148.98,45.27 149.44,45.73 149.44,49.13 149.59,49.28 154.24,53.94 154.24,56.16 154.01,56.4 154.01,62.25 149.78,66.48 149.78,67.2 149.78,68.38 149.82,68.42 149.82,68.85
  BOTTOM w0.076: v2(143.36,76.8) 143.19,76.97 143.13,76.97 142.84,77.25 142.84,78.42 142.69,78.57 142.69,79.16 142.79,79.26 142.79,79.47 142.72,79.64 142.72,79.84 142.77,79.95 142.78,79.96 142.79,80 142.79,80.44 143.17,80.82 UC1.AV22
  BOTTOM w0.114: v2(149.95,43.76) 150.12,43.93 150.3,43.93 150.65,44.27 150.65,45.37 149.55,46.47 JDIMM1.171
DDR_A_DQS7: length 55.4
  IN1 w0.076: v2(147.88,73.87) 147.88,73.69 147.95,73.63 149.03,73.63 149.24,73.41 153.78,73.41 155.73,71.45 155.73,68.99 155.78,68.95 155.78,68.94
  IN1 w0.119: 155.78,68.94 155.78,68.8 160,64.57 160,53.06 157.57,50.63 157.57,49.94 155.5,47.88 155.5,42.73 155.24,42.46 154.75,42.46 154.67,42.38 v2(154.67,42.1)
  BOTTOM w0.076: UC1.AW18 145.57,80.42 145.45,80.42 145.39,80.35 145.39,79.96 145.35,79.88 145.31,79.8 145.31,79.67 145.39,79.51 145.39,79.21 145.14,78.97 145.14,78.6 145.9,77.84 145.9,74.22 146.51,73.61 147.63,73.61 v2(147.88,73.87)
  BOTTOM w0.114: JDIMM1.188 154.65,40.53 154.18,41 154.18,42.17 154.39,42.38 154.59,42.38 154.67,42.29 v2(154.67,42.1)
DDR_A_DQS#0: length 68.7
  IN1 w0.107: 111.21,83.88 111.2,83.88 109.68,82.35 109.68,82.34 109.51,82.18 109.1,82.18
  IN1 w0.119: 111.21,83.88 112.91,83.88 113.64,84.6 117.33,84.6 117.56,84.83 117.56,86.03 116.68,86.9 115.75,86.9 115.43,86.58 115.43,85.94 v2(115.4,85.92) ; v2(98.29,42.67) 98.45,42.83 98.74,42.83 98.99,43.08 98.99,74.06 102.43,77.5 106.11,77.5 108.39,79.78 108.39,81.84 108.72,82.18 109.1,82.18
  BOTTOM w0.076: UC1.AJ61 119.14,86.18 118.86,86.46 118.75,86.46 118.73,86.48 118.72,86.48 118.59,86.54 118.38,86.54 118.33,86.51 118.23,86.47 118.1,86.47 117.94,86.54 117.73,86.54 117.59,86.47 117.57,86.46 115.76,86.46 115.53,86.23 115.53,86.04 v2(115.4,85.92)
  BOTTOM w0.114: JDIMM1.10 98.85,42.57 98.61,42.81 98.43,42.81 v2(98.29,42.67)
DDR_A_DQS#1: length 59.1
  IN1 w0.119: v2(103.53,44.95) 103.53,44.69 103.63,44.59 104.01,44.59 104.08,44.66 104.08,46.14 103.67,46.55 103.67,68.36 109.01,73.69 109.03,73.69 112.77,77.42 112.79,77.45 112.91,77.56 113.53,77.56 114.05,78.08 114.05,78.55 113.84,78.76 113.84,79.43 116.1,81.69 116.1,81.95 116.92,82.77 116.92,83.65 116.65,83.93 116.14,83.93 115.53,83.31 115.53,82.99 115.88,82.64 116.06,82.64 116.18,82.75 116.18,82.92 v2(116.01,83.09)
  BOTTOM w0.076: v2(116.01,83.09) 116.03,83.06 116.16,83.06 116.26,82.96 116.26,82.82 116.05,82.61 115.85,82.61 115.72,82.74 115.72,82.75 115.63,82.84 115.63,83.21 116.29,83.88 117.62,83.88 117.65,83.89 117.67,83.89 117.77,83.93 117.9,83.93 117.92,83.93 118,83.89 118.06,83.86 118.49,83.86 118.55,83.8 118.55,83.71 UC1.AN62
  BOTTOM w0.114: JDIMM1.27 103.95,46.35 104.02,46.28 104.32,46.28 104.45,46.16 104.45,44.74 104.34,44.63 103.64,44.63 103.53,44.74 v2(103.53,44.95)
DDR_A_DQS#2: length 50.4
  IN1 w0.119: v2(116.98,76.76) 116.9,76.67 116.9,76.27 117,76.17 117,75.72 113.47,72.19 113.47,71.35 109.68,67.57 109.68,53.67 109.18,53.17 109.18,52.55 109.29,52.43 109.43,52.43 109.7,52.16 109.7,51.71 109.43,51.45 109.29,51.45 109.18,51.33 109.18,51.09 109.29,50.97 109.43,50.97 109.7,50.7 109.7,50.25 109.43,49.99 109.29,49.99 109.18,49.87 109.18,44.35 109.28,44.25 109.45,44.25 109.64,44.44 v2(109.64,44.64)
  BOTTOM w0.076: v2(116.98,76.76) 116.88,76.66 116.88,76.39 116.96,76.31 118.62,76.31 120.75,78.44 120.75,79.04 120.99,79.29 120.99,79.47 120.98,79.49 120.95,79.58 120.94,79.58 120.92,79.63 120.92,79.84 120.99,79.99 120.99,80.12 120.95,80.22 120.92,80.28 120.92,80.49 121,80.65 121.06,80.71 121.15,80.8 121.3,80.8 121.38,80.88 UC1.AV57
  BOTTOM w0.114: v2(109.64,44.64) 109.64,44.4 109.77,44.28 109.94,44.28 110.07,44.4 110.07,45.61 109.7,45.98 109.7,46.49 109.64,46.56 109.41,46.56 109.35,46.62 JDIMM1.45
DDR_A_DQS#3: length 47.6
  IN1 w0.076: v2(122.23,76.12) 122.23,76.18 122.04,76.37 121.75,76.37 118.31,72.93 118.31,71.81
  IN1 w0.119: v2(114.97,42.35) 114.97,42.53 115.09,42.65 115.46,42.65 115.7,42.9 115.7,45.24 115.2,45.75 115.2,67.04 118.31,70.15 118.31,71.81
  BOTTOM w0.076: UC1.AV53 123.53,80.76 123.53,80.59 123.42,80.48 123.42,79.99 123.35,79.84 123.35,79.63 123.38,79.58 123.39,79.55 123.42,79.47 123.42,79.26 123.17,79.01 123.17,78.88 123.02,78.74 123.02,77.81 122.23,77.02 v2(122.23,76.12)
  BOTTOM w0.114: JDIMM1.62 114.45,40.39 114.67,40.61 114.8,40.61 115.4,41.2 115.4,42.36 115.24,42.51 115.12,42.51 v2(114.97,42.35)
DDR_A_DQS#4: length 45.9
  IN1 w0.076: v2(137.82,78.21) 137.82,77.96 137.9,77.88 138.18,77.88 138.56,77.5 138.56,71.86 140.57,69.85
  IN1 w0.119: 140.57,69.85 140.57,54.36 139.34,53.13 139.34,47.69 138.28,46.64 138.28,44.15 138.39,44.05 138.64,44.05 138.72,44.13 v2(138.72,44.39)
  BOTTOM w0.076: v2(137.82,78.21) 137.82,77.98 137.75,77.91 137.53,77.91 137.41,78.02 137.41,78.8 137.82,79.22 137.82,79.51 137.8,79.56 137.8,79.56 137.75,79.67 137.75,79.8 137.76,79.82 137.8,79.9 137.82,79.95 137.82,80.16 137.75,80.32 137.75,80.45 137.8,80.55 137.88,80.63 138.02,80.63 138.08,80.57 138.08,80.43 UC1.AW30
  BOTTOM w0.114: JDIMM1.135 138.75,46.35 139.32,45.78 139.32,44.16 139.2,44.04 138.8,44.04 138.72,44.12 v2(138.72,44.39)
DDR_A_DQS#5: length 49.7
  IN1 w0.076: 145.01,68.38 145.01,68.86 140.82,73.05 140.82,75.24 141.19,75.6 141.4,75.6 141.47,75.54 v2(141.47,75.43)
  IN1 w0.119: v2(143.92,42.1) 144.06,42.25 144.46,42.25 145.01,42.8 145.01,43.64 144.13,44.53 144.13,50.66 144.35,50.88 144.35,51.72 147.09,54.45 147.09,57.5 147.75,58.16 147.75,61.26 145.01,64 145.01,68.38
  BOTTOM w0.076: UC1.AV26 140.25,80.81 140.25,80.55 140.09,80.39 140.09,79.99 140.01,79.84 140.01,79.63 140.09,79.47 140.09,79.17 139.85,78.93 139.72,78.8 139.72,78.32 140.31,77.74 140.31,76.15 140.85,75.61 141.29,75.61 v2(141.47,75.43)
  BOTTOM w0.114: v2(143.92,42.1) 144.04,42.23 144.13,42.23 144.33,42.02 144.33,41.12 143.85,40.63 JDIMM1.152
DDR_A_DQS#6: length 52.2
  IN1 w0.076: v2(143.38,77.51) 143.22,77.51 143.14,77.42 143.14,77.19 143.18,77.15 143.87,77.15 144.43,76.59 144.43,72.62 144.68,72.38 145.77,72.38 147.41,70.73 149.11,70.73 149.94,69.9 149.94,68.99 150.03,68.9 150.03,68.89
  IN1 w0.119: 150.03,68.89 150.03,67.1 150.03,67.1 150.03,66.58 154.26,62.35 154.26,56.5 154.5,56.27 154.5,53.83 149.76,49.1 149.69,49.03 149.69,45.62 149.23,45.17 149.23,44.24 149.33,44.15 149.58,44.15 v2(149.95,44.52)
  BOTTOM w0.076: UC1.AW22 143.12,80.38 143.06,80.32 143.06,80.03 142.95,79.93 142.94,79.93 142.92,79.88 142.88,79.8 142.88,79.67 142.96,79.51 142.96,79.19 142.86,79.09 142.86,78.64 143.01,78.49 143.01,77.32 143.18,77.15 143.28,77.15 143.38,77.26 v2(143.38,77.51)
  BOTTOM w0.114: JDIMM1.169 148.95,46.69 149.03,46.61 149.23,46.61 149.3,46.54 149.3,46.37 150.4,45.27 150.4,44.37 150.2,44.17 150.04,44.17 149.95,44.27 v2(149.95,44.52)
DDR_A_DQS#7: length 55.5
  IN1 w0.076: v2(147.88,73.22) 147.88,73.36 147.99,73.46 148.96,73.46 149.17,73.25 153.71,73.25 155.57,71.39 155.57,68.89
  IN1 w0.119: 155.57,68.89 155.57,68.65 159.75,64.47 159.75,53.17 157.32,50.74 157.32,50.05 155.25,47.98 155.25,42.83 155.13,42.71 154.83,42.71 v2(154.67,42.87)
  BOTTOM w0.076: UC1.AV18 145.6,80.81 145.22,80.42 145.22,79.99 145.14,79.83 145.14,79.64 145.22,79.47 145.22,79.28 144.98,79.04 144.98,78.54 145.74,77.77 145.74,74.15 146.44,73.45 147.65,73.45 v2(147.88,73.22)
  BOTTOM w0.114: v2(154.67,42.87) 154.67,42.76 154.54,42.63 154.29,42.63 153.94,42.27 153.94,40.9 154.05,40.78 JDIMM1.186
DDR_A_MA0: length 46.1
  IN1 w0.076: v2(134.17,80.99) 133.8,80.63 133.8,78.86 134.3,78.36 134.3,78.16 134.1,77.96 134.09,77.96 133.77,77.63 133.77,76.94 133.11,76.29 133.11,74.84 130.54,72.27 130.54,71.81
  IN1 w0.163: 130.54,71.81 130.54,71.66 130.52,71.65 130.82,71.35 130.82,65.23 127.69,62.11 127.69,56.7 128.12,56.28 128.12,48.19 128.41,47.89 128.41,41.42 128.02,41.03 v2(128,41.03)
  BOTTOM w0.076: UC1.AU36 134.59,81.18 134.4,80.99 v2(134.17,80.99)
  BOTTOM w0.157: JDIMM1.98 127.65,40.68 v2(128,41.03)
DDR_A_MA1: length 47.5
  IN1 w0.076: v2(133.88,78.24) 133.68,78.24 133.59,78.15 133.59,77.14 133.59,77.14 133.59,77 133.5,76.92 133.5,76.91 132.95,76.36 132.95,76.25 132.95,76.25 132.95,74.98 130,72.04
  IN1 w0.163: 130,72.04 129.73,71.77 129.73,71.46 129.89,71.31 130.25,71.31 130.4,71.16 130.4,70.81 130.25,70.66 129.89,70.66 129.73,70.51 129.73,70.16 129.89,70.01 130.25,70.01 130.4,69.86 130.4,69.51 130.25,69.36 129.89,69.36 129.73,69.21 129.73,68.86 129.89,68.71 130.08,68.71 130.23,68.56 130.23,68.21 130.08,68.06 129.99,68.06 129.83,67.9 129.83,67.19 129.52,66.88 129.52,66.02 129.88,65.66 129.88,65.26 129.52,64.9 129.52,64.65 126.89,62.02 126.89,55.93 127.05,55.77 127.54,55.77 127.7,55.61 127.7,55.28 127.54,55.12 127.05,55.12 126.89,54.96 126.89,54.63 127.05,54.47 127.54,54.47 127.7,54.31 127.7,53.98 127.54,53.82 127.05,53.82 126.89,53.66 126.89,53.33 127.05,53.17 127.54,53.17 127.7,53.01 127.7,52.68 127.54,52.52 127.05,52.52 126.89,52.36 126.89,52.09 127.52,51.46 127.52,48.2 127.93,47.79 127.93,46.27 v2(127.96,46.24)
  BOTTOM w0.076: v2(133.88,78.24) 133.88,78.13 133.98,78.03 134.45,78.03 134.55,78.13 134.55,78.56 134.45,78.66 133.82,78.66 133.79,78.69 133.79,79.33 UC1.AY37
  BOTTOM w0.157: v2(127.96,46.24) 127.9,46.24 127.6,45.94 127.35,45.94 127.17,46.12 127.17,46.47 127.35,46.65 JDIMM1.97
DDR_A_MA2: length 49.5
  IN1 w0.076: 128.81,72.09 129.9,73.18 130.64,73.18 132.62,75.16 132.62,76.11 132.62,76.5 133.17,77.05 133.17,77.05 133.22,77.1 133.22,78.72 133.41,78.9 133.41,82.15 133.99,82.73 v2(133.99,82.91)
  IN1 w0.163: 128.81,72.09 128.81,67.53 128.57,67.29 128.57,64.99 125.86,62.29 125.86,51.16 126.38,50.64 126.38,47.57 126.89,47.06 126.89,43.23 127.78,42.34 v2(127.96,42.34)
  BOTTOM w0.076: v2(133.99,82.91) 133.6,82.52 UC1.AR38
  BOTTOM w0.157: JDIMM1.96 127.05,41.91 127.48,42.34 v2(127.96,42.34)
DDR_A_MA3: length 48.6
  IN1 w0.076: v2(134.01,83.53) 134.34,83.53 134.5,83.37 134.5,82.75 133.61,81.86 133.61,78.87 133.42,78.69 133.42,77.07 133.33,76.98 133.33,76.98 132.78,76.43 132.78,76.18 132.78,75.09 130.62,72.93 130.26,72.93 129.32,71.99
  IN1 w0.163: 129.32,71.99 129.32,67.39 129.01,67.09 129.01,64.79 126.47,62.25 126.47,51.44 127.1,50.81 127.1,49.43 126.8,49.13 126.8,48.06 127.32,47.54 127.32,44.98 127.58,44.72 v2(127.96,44.72)
  BOTTOM w0.076: UC1.AP36 134.36,83.17 v2(134.01,83.53)
  BOTTOM w0.157: v2(127.96,44.72) 127,44.72 126.75,44.97 JDIMM1.95
DDR_A_MA4: length 48
  IN1 w0.076: v2(132.55,81.23) 132.9,81.23 133.16,80.97 133.16,78.89 133.05,78.78 133.05,77.17 133,77.12 133,77.12 132.45,76.57 132.45,76.04 132.45,75.23 130.71,73.48 129.59,73.48 128.3,72.19
  IN1 w0.163: v2(125.87,43.09) 125.87,43.12 126.46,43.7 126.46,46.78 125.25,47.98 125.25,62.32 127.64,64.71 127.64,67.03 128.3,67.7 128.3,72.19
  BOTTOM w0.076: v2(132.55,81.23) 132.68,81.36 UC1.AU39
  BOTTOM w0.157: JDIMM1.92 125.85,40.35 126.64,41.14 126.64,42.25 125.87,43.02 v2(125.87,43.09)
DDR_A_MA5: length 48.2
  IN1 w0.076: v2(133.08,82.29) 132.21,82.29 132.06,82.14 132.06,81.89 131.91,81.74 131.55,81.74 131.41,81.59 131.41,81.39 131.55,81.25 131.98,81.25 132.13,81.1 132.13,80.94 132.24,80.83 132.72,80.83 132.72,80.84 132.84,80.84 132.99,80.69 132.99,78.95 132.89,78.85 132.89,77.24 132.84,77.19 132.84,77.19 132.29,76.63 132.29,75.29 130.64,73.65 129.15,73.65 127.79,72.29
  IN1 w0.163: 127.79,72.29 127.79,69.49 127.64,69.34 127.34,69.34 127.18,69.19 127.18,68.84 127.34,68.69 127.64,68.69 127.79,68.54 127.79,67.95 127.64,67.8 127.34,67.8 127.18,67.64 127.18,64.9 124.75,62.46 124.75,47.88 125.87,46.75 v2(125.87,46.14)
  BOTTOM w0.076: UC1.AR36 133.93,82.52 133.53,82.12 133.25,82.12 v2(133.08,82.29)
  BOTTOM w0.157: JDIMM1.91 125.55,46.26 125.67,46.14 v2(125.87,46.14)
DDR_A_MA6: length 48.5
  IN1 w0.076: v2(132.53,78.54) 132.34,78.54 131.91,78.11 131.91,75.38 130.8,74.27 128.56,74.27 126.78,72.5 126.78,71.81
  IN1 w0.163: 126.78,71.81 126.78,70.54 125.76,69.52 125.76,65.05 123.73,63.02 123.73,47.68 124.64,46.77 124.64,42.09 125.17,41.57 v2(125.87,41.57)
  BOTTOM w0.076: v2(132.53,78.54) 132.16,78.54 131.85,78.85 131.85,80.42 UC1.AV40
  BOTTOM w0.157: JDIMM1.90 125.25,40.87 125.85,41.46 125.85,41.54 v2(125.87,41.57)
DDR_A_MA7: length 47.9
  IN1 w0.076: v2(132.56,79.76) 132.56,79.8 132.41,79.95 131.89,79.95 131.74,79.8 131.74,75.45 130.73,74.44 128.09,74.44 126.27,72.62 126.27,71.81
  IN1 w0.163: 126.27,71.81 126.27,70.74 125.25,69.73 125.25,65.26 123.22,63.22 123.22,47.46 124.14,46.55 124.14,41.79 123.92,41.57 v2(123.65,41.57)
  BOTTOM w0.076: UC1.AW39 132.86,80.06 v2(132.56,79.76)
  BOTTOM w0.157: v2(123.65,41.57) 123.82,41.57 124.05,41.34 JDIMM1.86
DDR_A_MA8: length 47.3
  IN1 w0.076: v2(132.5,77.35) 132.07,76.92 132.07,75.91 132.07,75.31 130.7,73.94 128.83,73.94 127.29,72.39
  IN1 w0.163: v2(125.87,44.61) 125.85,44.61 125.15,45.31 125.15,46.87 124.24,47.78 124.24,62.62 126.77,65.15 126.77,66.89 126.37,67.29 126.37,67.61 126.53,67.78 126.73,67.78 126.88,67.93 126.88,68.27 126.73,68.43 126.42,68.43 126.27,68.58 126.27,68.92 126.42,69.08 126.54,69.08 126.7,69.23 126.7,69.72 126.85,69.87 127.13,69.87 127.29,70.02 127.29,72.39
  BOTTOM w0.076: v2(132.5,77.35) 132.5,77.17 132.65,77.02 132.92,77.02 133.08,77.17 133.08,79.07 132.97,79.18 UC1.AY39
  BOTTOM w0.157: v2(125.87,44.61) 125.87,44.5 125.4,44.02 125.1,44.02 124.95,44.17 JDIMM1.89
DDR_A_MA9: length 48.2
  IN1 w0.076: v2(130.93,75.38) 130.93,75.11 130.64,74.82 127.22,74.82 125.25,72.85 125.25,71.81
  IN1 w0.163: 125.25,71.81 125.25,71.15 124.24,70.13 124.24,65.87 122.21,63.83 122.21,47.07 122.82,46.46 122.82,44.92 123.12,44.61 v2(123.65,44.61)
  BOTTOM w0.076: v2(130.93,75.38) 131.55,75.38 131.68,75.52 131.68,80.68 132.09,81.09 UC1.AU40
  BOTTOM w0.157: v2(123.65,44.61) 124.26,44.61 124.44,44.8 124.44,46.12 123.75,46.81 JDIMM1.85
DDR_A_MA10: length 48.4
  IN1 w0.076: v2(134.91,82.83) 133.84,81.76 133.84,81.54 133.91,81.46 134.75,81.46 135.21,81.92 135.44,81.92 135.59,81.77 135.59,81.55 135.08,81.04 134.68,81.04 134.6,80.96 134.6,80.74 134.68,80.66 135.24,80.66 135.31,80.58 135.31,80.35 135.24,80.28 134.68,80.28 134.6,80.2 134.6,79.97 134.68,79.9 135.08,79.9 135.16,79.82 135.16,75.26 133.48,73.59 133.48,71.81
  IN1 w0.163: 133.48,71.81 133.48,62.11 132.22,60.85 132.22,57.51 132.06,57.35 131.57,57.35 131.41,57.51 131.41,59.3 131.29,59.43 130.8,59.43 130.64,59.26 130.64,50.16 130.95,49.85 v2(131.25,49.85)
  BOTTOM w0.076: v2(134.91,82.83) 135.25,83.17 UC1.AP35
  BOTTOM w0.157: JDIMM1.107 130.35,49.31 130.89,49.85 v2(131.25,49.85)
DDR_A_MA11: length 48.7
  IN1 w0.076: v2(130.99,79.77) 131.41,79.36 131.41,76.63 131.41,76.63 131.41,75.95 131.21,75.75 129.56,75.75 129.05,75.24 127.03,75.24 124.75,72.95 124.75,71.81
  IN1 w0.163: v2(123.65,43.09) 122.31,44.44 122.31,46.16 121.6,46.87 121.6,60.61 121.21,60.99 121.21,62.89 121.6,63.28 121.6,63.83 123.73,65.97 123.73,70.24 124.75,71.25 124.75,71.81
  BOTTOM w0.076: UC1.AW41 131.28,80.06 v2(130.99,79.77)
  BOTTOM w0.157: v2(123.65,43.09) 123.07,42.43 123.07,41.17 123.45,40.78 JDIMM1.84
DDR_A_MA12: length 47.7
  IN1 w0.076: 125.76,71.81 125.76,72.72 127.69,74.65 130.71,74.65 131.58,75.52 131.58,80.45 131.23,80.79 130.41,80.79 129.95,81.25 129.95,81.89 130.11,82.05 130.11,82.06 130.11,82.06 130.83,82.06 130.99,81.9 v2(130.99,81.17)
  IN1 w0.163: 125.76,71.81 125.76,70.95 124.75,69.93 124.75,65.64 122.71,63.61 122.71,47.35 123.65,46.42 v2(123.65,46.14)
  BOTTOM w0.076: UC1.AU41 131.26,81.17 v2(130.99,81.17)
  BOTTOM w0.157: v2(123.65,46.14) 123.65,45.96 123.51,45.81 123.31,45.81 123.15,45.97 JDIMM1.83
DDR_A_MA13: length 48.4
  IN1 w0.076: 136.58,69.02 136.96,69.4 136.96,69.73 136.12,70.57 136.12,74.3 136.33,74.5 136.33,75.68 136.63,75.99 136.63,82.45 136.66,82.48 137.22,82.48 137.34,82.6 137.34,82.77 137.22,82.88 136.43,82.88 136.28,82.73 136.28,81.54 136.2,81.46 135.97,81.46 135.9,81.54 135.9,82.26 135.74,82.41 135.15,82.41 134.92,82.18 v2(134.9,82.18)
  IN1 w0.163: v2(133.64,46.24) 133.99,46.59 133.99,47.88 134.91,48.8 134.91,48.82 134.95,48.86 134.95,54.6 135.49,55.15 135.49,55.34 134.93,55.89 134.93,56.13 135.14,56.33 135.29,56.33 135.86,55.76 136.11,55.76 136.58,56.23 136.58,69.02
  BOTTOM w0.076: v2(134.9,82.18) 134.92,82.18 135.07,82.03 135.47,82.03 135.55,82.11 135.55,82.38 UC1.AR35
  BOTTOM w0.157: v2(133.64,46.24) 133.65,46.24 133.95,46.54 JDIMM1.119
DDR_A_MA14: length 50.3
  IN1 w0.076: 122.97,71.81 123.12,71.96 123.12,73.99 125.51,76.39 126.93,76.39 127.36,75.95 128.73,75.95 130.2,77.42 v2(130.87,77.42)
  IN1 w0.163: v2(121.73,41.57) 120.76,42.54 120.76,44.56 120.39,44.93 120.39,45.9 120.33,45.97 120.25,46.04 120.25,48.29 119.51,49.03 119.51,64.95 122.21,67.64 122.21,70.91 122.83,71.53 122.83,71.67 122.97,71.81
  BOTTOM w0.076: UC1.AV42 130.27,80.42 130.27,78.02 v2(130.87,77.42)
  BOTTOM w0.157: v2(121.73,41.57) 122.25,41.05 JDIMM1.80
DDR_A_MA15: length 50
  IN1 w0.076: v2(130.89,76.85) 130.07,76.85 128.96,75.73 126.31,75.73 123.73,73.16 123.73,71.81
  IN1 w0.163: v2(121.73,43.09) 121.19,43.64 121.19,44.71 120.82,45.09 120.82,46.19 120.67,46.34 120.67,59.96 120.02,60.61 120.02,63.02 120.67,63.67 120.67,64.52 122.71,66.56 122.71,70.76 123.73,71.78 123.73,71.81
  BOTTOM w0.076: UC1.AU42 130.37,81.22 130.37,81.15 130.11,80.88 130.11,77.63 v2(130.89,76.85)
  BOTTOM w0.157: v2(121.73,43.09) 121.68,43.09 121.19,42.6 121.19,41.21 121.65,40.75 JDIMM1.78
DDR_A_RAS#: length 49.6
  IN1 w0.076: v2(135.72,78.93) 136.3,78.35 136.3,76.21 135.92,75.82 135.92,74.78 135.62,74.48 135.62,69.73
  IN1 w0.163: 135.62,69.73 135.62,59.16 134.95,58.49 134.34,58.49 134.03,58.19 134.03,49.14 133.13,48.24 133.13,46.95 132.72,46.54 132.72,43.37 133.04,43.06 133.04,40.45 132.87,40.28 132.06,40.28 131.9,40.12 131.9,39.8 132.06,39.63 132.87,39.63 133.04,39.47 133.04,39.15 132.87,38.98 131.41,38.98 131.25,39.15 131.25,40.89 v2(131.26,40.91)
  BOTTOM w0.076: UC1.AY34 136.12,79.33 v2(135.72,78.93)
  BOTTOM w0.157: JDIMM1.110 131.26,39.52 v2(131.26,40.91)
DDR_A_WE#: length 48.6
  IN1 w0.076: v2(135.72,79.7) 135.72,79.92 135.82,80.01 136.12,80.01 136.2,79.94 136.2,79.48 136.05,79.33 135.44,79.33 135.32,79.21 135.32,75.13 134.09,73.89 134.09,71.25
  IN1 w0.163: 134.09,71.25 134.09,61.99 132.71,60.6 132.71,53.94 132.55,53.78 132.06,53.78 131.9,53.94 131.9,56.46 131.74,56.62 131.25,56.62 131.09,56.46 131.09,51.99 131.71,51.37 131.71,47.29 131.44,47.03 131.44,46.42 v2(131.26,46.24)
  BOTTOM w0.076: v2(135.72,79.7) 136.03,79.7 136.12,79.79 UC1.AW34
  BOTTOM w0.157: v2(131.26,46.24) 131.71,45.8 131.71,45.28 131.86,45.13 132.08,45.13 132.24,45.28 132.24,46.49 132.15,46.58 JDIMM1.113
DDR_B_BS0: length 77
  IN2 w0.076: v2(134.92,84.8) 134.92,84.97 134.6,85.29 133.79,85.29 133.64,85.14 133.64,82 133.69,81.94 133.69,81.55 133.82,81.42 134.31,81.42 134.64,81.1 134.64,75.45 134.76,75.32 135.13,75.32 135.21,75.25 135.21,74.98 135.13,74.9 134.48,74.9 134.4,74.82 134.4,74.66 134.48,74.58 135.08,74.58 135.16,74.51 135.16,74.35 135.08,74.28 134.48,74.28 134.4,74.2 134.4,74.05 134.48,73.97 135.08,73.97 135.16,73.9 135.16,73.74 135.08,73.67 134.48,73.67 134.4,73.59 134.4,73.44 134.48,73.36 135.08,73.36 135.16,73.29 135.16,73.13 135.08,73.06 134.48,73.06 134.4,72.98 134.4,72.83 134.48,72.75 135.08,72.75 135.16,72.68 135.16,72.52 135.08,72.45 134.48,72.45 134.4,72.37 134.4,70.39 134.96,69.83
  IN2 w0.163: 134.96,69.83 134.96,61.49 141.25,55.21 141.25,54.98 140.82,54.55 140.82,54.32 141.04,54.09 141.28,54.09 141.82,54.63 142.05,54.63 142.28,54.4 142.28,54.17 141.74,53.63 141.74,53.4 141.96,53.17 142.2,53.17 143.64,54.62 143.87,54.62 144.12,54.38 144.12,54.15 142.43,52.47 142.43,50.31 143.29,49.46 143.29,49.1 142.54,48.36 142.54,47.29 142.02,46.77 142.02,40.8 143.5,39.33 143.5,37.45 143.18,37.13 143.18,36.8 143.5,36.48 143.5,36.15 143.18,35.83 143.18,35.5 143.5,35.18 143.5,34.31 143.63,34.18 143.63,33.44 143.82,33.25 v2(144.23,33.25)
  BOTTOM w0.076: v2(134.92,84.8) 135.33,84.8 135.41,84.89 UC1.AL35
  BOTTOM w0.157: JDIMM2.109 143.32,33.08 143.47,32.92 144.1,32.92 144.23,33.05 v2(144.23,33.25)
DDR_B_BS1: length 77.4
  IN2 w0.076: v2(134.17,84.19) 134.37,83.98 134.37,82.68 134.02,82.33 134.02,81.98 134.8,81.2 134.8,76.1 135.24,75.67 135.24,75.48 135.39,75.33 135.39,72.36 135.24,72.21 134.65,72.21 134.58,72.13 134.58,71.98 134.69,71.86 135.24,71.86 135.33,71.77 135.33,71.65 135.24,71.56 134.88,71.56 134.8,71.48 134.8,70.49 135.42,69.87
  IN2 w0.163: 135.42,69.87 135.42,61.73 135.79,61.36 136.02,61.36 136.73,62.06 136.95,62.06 137.18,61.83 137.18,61.6 136.48,60.9 136.48,60.67 136.71,60.44 136.94,60.44 137.68,61.18 137.84,61.34 138.07,61.34 138.3,61.11 138.3,60.88 138.14,60.72 137.4,59.98 137.4,59.75 142.11,55.05 144.07,55.05 144.53,54.59 144.53,52.99 144.38,52.84 143.59,52.84 142.88,52.13 142.88,50.47 143.74,49.61 143.74,48.87 142.96,48.09 142.96,40.85 143.91,39.89 143.91,35.4 144.15,35.16 144.57,35.16 144.77,34.96 144.77,34.67 144.6,34.51 144.21,34.51 144.04,34.34 144.04,34.02 144.21,33.86 144.6,33.86 144.77,33.69 144.77,29.63 144.58,29.44 v2(144.23,29.44)
  BOTTOM w0.076: UC1.AM36 134.31,84.47 134.17,84.33 v2(134.17,84.19)
  BOTTOM w0.157: JDIMM2.108 143.02,29.84 143.18,30 143.58,30 143.74,29.84 143.74,29.6 143.9,29.44 v2(144.23,29.44)
DDR_B_BS2: length 72.6
  IN2 w0.076: v2(126.32,81.03) 126.97,81.03 127.09,80.91 127.09,80.76 126.97,80.63 126.71,80.63 126.65,80.57 126.65,80.35 126.71,80.29 126.97,80.29 127.03,80.22 127.03,75.54 125.13,73.63 125.13,73.18 125.02,73.08 124.57,73.08 124.38,72.88 124.38,72.72 124.45,72.64 125.11,72.64 125.2,72.55 125.2,72.43 125.11,72.34 124.16,72.34 124.07,72.25 124.07,72.12 124.16,72.03 124.95,72.03 125.03,71.96 125.03,71.23 124.84,71.05
  IN2 w0.163: v2(133.5,31.72) 133.94,31.28 133.94,30.79 134.14,30.59 134.43,30.59 134.63,30.79 134.63,32.36 132.01,34.98 132.01,37.59 131.83,37.77 131.83,46.45 129.89,48.39 129.89,49.35 126.67,52.57 126.07,52.57 122.24,56.41 122.24,56.69 122.4,56.86 122.77,56.86 122.93,57.02 122.93,57.34 122.77,57.51 122.4,57.51 122.24,57.67 122.24,57.99 122.4,58.16 122.77,58.16 122.93,58.32 122.93,58.64 122.77,58.81 122.4,58.81 122.24,58.97 122.24,59.29 122.4,59.46 122.77,59.46 122.93,59.62 122.93,60.02 122.99,60.08 122.99,63.95 123.22,64.17 123.45,64.17 123.54,64.09 123.77,64.09 124,64.32 124,64.55 123.91,64.63 123.91,64.86 124.38,65.33 124.38,70.89 124.54,71.05 124.84,71.05
  BOTTOM w0.076: v2(126.32,81.03) 126.64,81.36 UC1.AU49
  BOTTOM w0.157: v2(133.5,31.72) 133.99,31.72 134.34,31.37 134.68,31.37 134.84,31.53 134.84,33.14 134.32,33.66 JDIMM2.79
DDR_B_CAS#: length 76.6
  IN2 w0.076: v2(135.81,84.75) 135.45,84.38 135.45,83.61 135.45,83.61 135.45,81.76 135.77,81.44 135.87,81.44 136.17,81.14 136.17,75.81 136.25,75.72 136.46,75.72 136.54,75.64 136.54,75.48 136.46,75.4 136.05,75.4 135.97,75.32 135.97,75.16 136.05,75.07 136.46,75.07 136.54,74.99 136.54,74.83 136.46,74.75 136.05,74.75 135.97,74.67 135.97,74.51 136.05,74.42 136.46,74.42 136.54,74.34 136.54,74.18 136.46,74.1 136.01,74.1 135.92,74 135.92,73.87 136.01,73.77 136.45,73.77 136.54,73.68 136.54,73.54 136.45,73.45 136.03,73.45 135.92,73.34 135.92,73.18 136.03,73.07 136.45,73.07 136.54,72.98 136.54,72.85 136.45,72.76 136.02,72.76 135.92,72.65 135.92,72.5 136.02,72.39 136.34,72.39 136.44,72.29 136.44,72.16 136.38,72.09 136.05,72.09 136,72.04 136,70.82 136.67,70.15
  IN2 w0.163: v2(146.16,33.24) 146.16,35.98 145.78,36.35 145.78,36.71 145.95,36.88 146.39,36.88 146.58,37.07 146.58,37.34 146.39,37.53 145.94,37.53 145.78,37.68 145.78,39.93 144.94,40.77 144.94,48.03 145.81,48.9 145.81,50.62 146.05,50.86 146.05,51.6 145.86,51.79 145.86,55.17 144.06,56.97 144.05,56.97 143.86,57.16 143.59,57.16 142.79,56.36 142.56,56.36 142.29,56.63 142.29,56.86 143.16,57.73 143.16,58.01 142.96,58.21 142.68,58.21 141.83,57.36 141.56,57.36 141.37,57.55 141.37,57.82 142.23,58.67 142.23,58.94 142.04,59.13 141.77,59.13 140.91,58.28 140.64,58.28 140.45,58.47 140.45,58.74 141.33,59.61 141.33,59.84 136.67,64.5 136.67,70.15
  BOTTOM w0.076: v2(135.81,84.75) 136.09,84.47 UC1.AM33
  BOTTOM w0.157: v2(146.16,33.24) 146.15,33.25 145.84,33.25 145.75,33.16 145.75,32.63 145.58,32.45 145.27,32.45 145.12,32.6 JDIMM2.115
DDR_B_D0: length 69.5
  IN2 w0.076: 114.73,76.67 118.67,80.61 118.67,80.79 119.23,81.35 119.49,81.35 119.93,81.79 119.93,82.34 120.28,82.7 v2(120.28,82.84)
  IN2 w0.107: v2(118.25,31.22) 117.53,31.93 117.53,36.25 115.73,38.05 115.73,38.56 113.86,40.43 113.58,40.43 112.99,41.02 112.99,46.64 112.32,47.31 112.32,47.46 112.65,47.79 112.65,47.94 112.5,48.09 112.35,48.09 112.02,47.76 111.87,47.76 111.72,47.91 111.72,48.06 112.05,48.39 112.05,48.54 111.9,48.69 111.75,48.69 111.41,48.36 111.26,48.36 107.07,52.56 107.07,53.45 107.35,53.73 107.35,59.67 107.07,59.95 107.07,69.2 111.54,73.68 112.57,73.68 114.23,75.34 114.23,75.74 114.73,76.24 114.73,76.67
  BOTTOM w0.076: UC1.AP58 120.59,83.03 120.47,83.03 v2(120.28,82.84)
  BOTTOM w0.102: JDIMM2.33 118.12,33.52 117.83,33.23 117.83,31.63 v2(118.25,31.22)
DDR_B_D1: length 68.3
  IN2 w0.076: v2(120.28,82.19) 120.19,82.1 120.19,81.08 115.13,76.03
  IN2 w0.107: 115.13,76.03 115.11,76.03 114.71,75.63 114.71,75.16 112.87,73.32 111.69,73.32 107.45,69.08 107.45,60.25 107.82,59.88 107.82,53.13 107.58,52.89 107.58,52.74 107.73,52.58 107.88,52.58 108.12,52.83 108.28,52.83 108.43,52.68 108.43,52.53 108.18,52.28 108.18,52.13 108.33,51.98 108.48,51.98 108.73,52.22 108.88,52.22 109.03,52.07 109.03,51.92 108.79,51.68 108.79,51.53 108.94,51.38 109.09,51.38 109.33,51.62 109.48,51.62 109.63,51.47 109.63,51.32 109.39,51.08 109.39,50.93 109.54,50.77 109.69,50.77 109.93,51.02 110.09,51.02 110.24,50.87 110.24,50.72 109.95,50.43 109.95,50.26 110.08,50.13 110.25,50.13 110.54,50.41 110.69,50.41 110.84,50.26 110.84,50.11 110.54,49.82 110.54,49.64 110.67,49.51 110.85,49.51 111.14,49.81 111.29,49.81 114.48,46.62 114.48,40.47 116.19,38.76 116.19,38.18 117.97,36.4 117.97,33.02 v2(118.25,32.74)
  BOTTOM w0.076: UC1.AR58 120.61,82.52 v2(120.28,82.19)
  BOTTOM w0.102: JDIMM2.35 118.72,33 118.47,32.74 v2(118.25,32.74)
DDR_B_D2: length 71.1
  IN2 w0.076: v2(121.22,84.16) 120.74,84.64 120.74,84.9 120.52,85.12 120.04,85.12 118.25,83.33 118.25,82.64
  IN2 w0.107: 118.25,82.64 117.74,82.12 117.74,80.9 114.48,77.65 112.81,77.65 104.87,69.7 104.87,68.51 104.97,68.4 105.03,68.4 105.13,68.3 105.13,68.09 105.02,67.97 104.97,67.97 104.87,67.87 104.87,67.65 104.97,67.55 105.03,67.55 105.13,67.45 105.13,67.23 105.02,67.12 104.97,67.12 104.87,67.01 104.87,66.8 104.97,66.69 105.03,66.69 105.13,66.59 105.13,66.38 105.02,66.27 104.97,66.27 104.87,66.16 104.87,65.95 104.97,65.84 105.03,65.84 105.13,65.74 105.13,65.53 105.02,65.41 104.97,65.41 104.87,65.31 104.87,65.09 104.97,64.99 105,64.99 105.11,64.88 105.11,64.67 105,64.56 104.97,64.56 104.87,64.45 104.87,64.24 104.97,64.13 105,64.13 105.11,64.03 105.11,63.81 105,63.71 104.97,63.71 104.87,63.6 104.87,63.39 104.97,63.28 105.06,63.28 105.19,63.16 105.19,62.98 105.06,62.85 104.97,62.85 104.87,62.75 104.87,62.53 104.97,62.43 105.04,62.43 105.16,62.3 105.16,62.13 105.04,62 104.97,62 104.87,61.89 104.87,61.68 104.97,61.57 105.04,61.57 105.16,61.45 105.16,61.27 105.04,61.15 104.97,61.15 104.87,61.04 104.87,60.83 104.97,60.72 105.06,60.72 105.19,60.6 105.19,60.42 105.06,60.29 104.97,60.29 104.87,60.19 104.87,59.34 105.21,58.99 105.21,51.45 108.75,47.91 108.75,42.52 112.06,39.21 112.06,38.9 113.33,37.63 113.33,35.89 114.98,34.24 v2(114.98,32.74)
  BOTTOM w0.076: v2(121.22,84.16) 121.53,84.47 UC1.AM57
  BOTTOM w0.102: JDIMM2.23 115.12,32.88 v2(114.98,32.74)
DDR_B_D3: length 72.8
  IN2 w0.076: v2(121.18,85.44) 120.79,85.44 120.63,85.28 119.96,85.28 117.97,83.3 117.97,82.72
  IN2 w0.107: 117.97,82.72 117.47,82.22 117.47,81.15 114.89,78.57 113.22,78.57 104.51,69.85 104.51,58.6 104.61,58.5 104.73,58.5 104.85,58.37 104.85,58.19 104.73,58.07 104.61,58.07 104.51,57.96 104.51,57.75 104.61,57.64 104.71,57.64 104.83,57.52 104.83,57.34 104.71,57.22 104.61,57.22 104.51,57.11 104.51,56.86 104.61,56.75 104.75,56.75 104.85,56.64 104.85,56.43 104.75,56.32 104.61,56.32 104.51,56.22 104.51,51.64 108.39,47.76 108.39,42.32 111.28,39.43 111.28,39.17 112.93,37.51 112.93,35.77 114.53,34.17 114.53,31.37 114.69,31.22 v2(114.98,31.22)
  BOTTOM w0.076: UC1.AK57 121.51,85.77 v2(121.18,85.44)
  BOTTOM w0.102: v2(114.98,31.22) 114.52,31.67 JDIMM2.21
DDR_B_D4: length 71
  IN2 w0.076: 118.49,82.47 118.49,83.3 119.95,84.76 v2(120.29,84.76)
  IN2 w0.107: 118.49,82.47 117.94,81.92 117.94,80.6 114.66,77.32 112.99,77.32 105.57,69.9 105.57,51.6 110.05,47.12 110.05,41.75 112.73,39.07 112.73,38.74 114.02,37.45 114.02,36.88 115.27,35.63 115.45,35.45 115.45,29.85 115.29,29.69 v2(114.98,29.69)
  BOTTOM w0.076: v2(120.29,84.76) 120.3,84.76 120.66,85.12 UC1.AL58
  BOTTOM w0.102: v2(114.98,29.69) 114.72,29.69 114.55,29.52 114.55,27.74 114.82,27.47 JDIMM2.22
DDR_B_D5: length 72.1
  IN2 w0.076: v2(120.22,85.65) 120.07,85.5 119.94,85.5 117.76,83.32 117.76,83.19
  IN2 w0.107: 117.76,83.19 113.52,78.95 113.09,78.95 110.69,76.54 104.15,70 104.15,51.49 107.3,48.34 107.3,41.3 107.6,41 108.41,41 108.72,40.7 108.72,40.06 112.46,36.31 112.46,35.6 114.1,33.96 114.1,28.66 114.59,28.17 v2(114.98,28.17)
  BOTTOM w0.076: UC1.AK58 120.59,85.62 120.25,85.62 v2(120.22,85.65)
  BOTTOM w0.102: JDIMM2.24 115.42,27.72 v2(114.98,28.17)
DDR_B_D6: length 70.1
  IN2 w0.076: 115.34,75.73 116.15,76.53 116.15,76.55 116.61,77.01 119.4,79.8 119.4,79.8 120.57,80.97 120.57,81.51 121.03,81.97 v2(121.03,82.12)
  IN2 w0.107: v2(118.25,28.17) 119.04,28.95 119.04,33.48 118.69,33.82 118.69,37.54 116.09,40.14 116.08,40.15 116.08,46.04 108.59,53.53 108.59,63.48 108.57,63.48 108.57,63.78 108.49,63.86 108.34,63.86 108.19,64.01 108.19,64.29 108.3,64.39 108.49,64.39 108.59,64.5 108.59,64.71 108.49,64.82 108.3,64.82 108.19,64.93 108.19,65.14 108.3,65.25 108.49,65.25 108.59,65.35 108.59,65.57 108.49,65.67 108.3,65.67 108.19,65.78 108.19,65.99 108.3,66.1 108.49,66.1 108.59,66.21 108.59,66.42 108.49,66.53 108.3,66.53 108.19,66.63 108.19,66.85 108.3,66.95 108.49,66.95 108.59,67.06 108.59,67.27 108.49,67.38 108.3,67.38 108.19,67.49 108.19,67.7 108.3,67.81 108.49,67.81 108.59,67.91 108.59,68.13 108.49,68.23 108.3,68.23 108.19,68.34 108.19,68.8 111.99,72.6 113.17,72.6 115.34,74.77 115.34,75.73
  BOTTOM w0.076: v2(121.03,82.12) 121.06,82.12 121.46,82.52 UC1.AR57
  BOTTOM w0.102: JDIMM2.34 118.42,27.99 v2(118.25,28.17)
DDR_B_D7: length 70.7
  IN2 w0.076: v2(121.23,83.49) 120.64,82.9 120.64,81.89 120.41,81.65 120.41,81.04 119.33,79.97 119.33,79.97 118.86,79.49 115.09,75.73
  IN2 w0.107: v2(118.25,29.69) 118.57,29.69 118.67,29.8 118.67,33.33 118.33,33.67 118.33,37.28 115.65,39.96 115.65,45.96 108.23,53.38 108.23,60.52 108.13,60.62 107.94,60.62 107.83,60.73 107.83,60.94 107.94,61.05 108.13,61.05 108.23,61.16 108.23,61.37 108.13,61.48 107.94,61.48 107.83,61.58 107.83,61.8 107.94,61.9 108.13,61.9 108.23,62.01 108.23,62.22 108.13,62.33 107.94,62.33 107.83,62.44 107.83,62.65 107.94,62.76 108.13,62.76 108.23,62.86 108.23,63.08 108.13,63.19 107.94,63.19 107.83,63.29 107.83,68.95 111.84,72.96 113.02,72.96 115.09,75.03 115.09,75.73
  BOTTOM w0.076: UC1.AN57 121.56,83.82 v2(121.23,83.49)
  BOTTOM w0.102: v2(118.25,29.69) 119.02,28.92 JDIMM2.36
DDR_B_D8: length 66.9
  IN2 w0.076: v2(122.19,82.84) 122.19,82.72 121.76,82.29 121.76,81.7 121.52,81.47 121.52,80.97 121.25,80.7 121.25,80.59 121.39,80.46 121.39,80.35 121.28,80.24 121.18,80.24 121.04,80.38 120.93,80.38 120.82,80.27 120.82,80.16 120.96,80.02 120.96,79.92 120.85,79.81 120.74,79.81 120.61,79.95 120.5,79.95 120.39,79.84 120.39,79.73 120.53,79.59 120.53,79.49 120.42,79.38 120.31,79.38 120.17,79.52 120.07,79.52 119.4,78.85 119.4,78.65 119.48,78.58 119.58,78.58 119.65,78.5 119.65,78.35 119.58,78.27 119.48,78.27 119.4,78.2 119.4,77.84 119.13,77.57 119.13,77.46 119.21,77.38 119.21,77.27 119.11,77.16 119,77.16 118.91,77.25 118.8,77.25 118.7,77.14 118.7,77.03 118.78,76.94 118.78,76.84 118.67,76.73 118.57,76.73 118.48,76.82 118.37,76.82 118.27,76.71 118.27,76.6 118.35,76.51 118.35,76.41 118.24,76.3 118.14,76.3 118.05,76.38 117.94,76.38 117.83,76.28 117.83,76.17 117.92,76.08 117.92,75.97 117.81,75.87 117.7,75.87 117.62,75.95 117.51,75.95 117.4,75.84 117.4,75.74 117.49,75.65 117.49,75.54 117.38,75.44 117.27,75.44 117.19,75.52 117.08,75.52 116.52,74.96
  IN2 w0.107: v2(120.48,32.74) 120.48,34.54 120.23,34.79 120.23,37.89 118.07,40.06 118.07,45.95 109.93,54.09 109.93,68.27 112.35,70.69 113.24,70.69 116.52,73.96 116.52,74.96
  BOTTOM w0.076: v2(122.19,82.84) 122.22,82.82 122.67,82.82 122.79,82.94 122.79,83.07 122.7,83.17 UC1.AP55
  BOTTOM w0.102: v2(120.48,32.74) 120.44,32.78 120.44,33.34 120.52,33.42 JDIMM2.41
DDR_B_D9: length 66.3
  IN2 w0.076: 116.72,73.65 116.72,74.54 120.31,78.13 120.31,79.04 121.75,80.47 121.75,81.38 122.13,81.76 v2(122.13,82.16)
  IN2 w0.107: 116.72,73.65 113.05,69.98 112.2,69.98 110.29,68.07 110.29,54.24 118.45,46.08 118.45,40.3 120.59,38.15 120.59,35.04 120.91,34.73 120.91,28.59 v2(120.48,28.17)
  BOTTOM w0.076: UC1.AR55 122.48,82.52 v2(122.13,82.16)
  BOTTOM w0.102: v2(120.48,28.17) 120.82,27.83 JDIMM2.42
DDR_B_D10: length 69.7
  IN2 w0.076: v2(123.14,84.14) 123.67,83.61 123.67,79.66 122.8,78.79 122.8,77.84 118.04,73.08
  IN2 w0.107: 118.04,73.08 118.04,72.78 116.82,71.56 116.82,70.33 113.3,66.81 113.3,63.53 112.68,62.91 112.68,60.11 112.93,59.86 113.19,59.86 113.3,59.75 113.3,59.54 113.19,59.43 112.93,59.43 112.83,59.33 112.83,59.11 112.93,59.01 113.19,59.01 113.3,58.9 113.3,58.69 113.19,58.58 112.93,58.58 112.83,58.47 112.83,54.83 121.29,46.37 121.29,40.59 123.22,38.66 123.22,35.9 123.63,35.49 123.63,34.17 124.34,33.46 124.34,30.5 v2(123.53,29.69)
  BOTTOM w0.076: UC1.AM54 123.46,84.47 v2(123.14,84.14)
  BOTTOM w0.102: v2(123.53,29.69) 123.98,29.25 123.98,28 123.82,27.84 JDIMM2.52
DDR_B_D11: length 70.7
  IN2 w0.076: 118.33,73.06 122.97,77.7 122.97,78.72 123.84,79.59 123.84,83.68 123.5,84.02 123.5,85.11 v2(123.13,85.48)
  IN2 w0.107: 118.33,73.06 118.33,72.55 117.32,71.55 117.32,70.33 113.66,66.66 113.66,58.29 113.26,57.89 113.26,57.1 113.37,56.99 113.55,56.99 113.66,56.88 113.66,56.67 113.55,56.56 113.37,56.56 113.26,56.46 113.26,56.24 113.37,56.14 113.55,56.14 113.66,56.03 113.66,55.82 113.55,55.71 113.37,55.71 113.26,55.6 113.26,55.06 122.15,46.17 122.15,40.24 124.21,38.18 124.21,34.37 124.75,33.84 124.75,29.18 123.73,28.17 v2(123.53,28.17)
  BOTTOM w0.076: v2(123.13,85.48) 123.12,85.48 123.41,85.77 UC1.AK54
  BOTTOM w0.102: JDIMM2.50 123.22,27.86 v2(123.53,28.17)
DDR_B_D12: length 69.6
  IN2 w0.076: v2(122.19,84.79) 122.19,84.82 122.06,84.95 121.92,84.95 121.79,84.82 121.79,82.63 121.59,82.43 121.59,81.78 121.21,81.39 121.21,80.89 119.2,78.88 119.2,77.89 116.21,74.91
  IN2 w0.107: 116.21,74.91 116.21,74.17 116.07,74.03 115.92,74.03 115.8,74.15 115.65,74.15 115.5,73.99 115.5,73.84 115.62,73.73 115.62,73.57 115.47,73.42 115.32,73.42 115.2,73.54 115.05,73.54 114.9,73.39 114.9,73.24 115.02,73.12 115.02,72.97 113.09,71.05 112.2,71.05 109.57,68.42 109.57,53.94 117.56,45.95 117.56,40.06 117.7,39.91 117.7,39.91 119.87,37.74 119.87,34.6 120.05,34.42 120.05,31.65 v2(120.48,31.22)
  BOTTOM w0.076: UC1.AL55 122.51,85.12 v2(122.19,84.79)
  BOTTOM w0.102: JDIMM2.39 119.92,31.78 v2(120.48,31.22)
DDR_B_D13: length 70.4
  IN2 w0.076: v2(122.18,85.44) 121.63,84.89 121.63,82.7 121.42,82.5 121.42,81.87 120.96,81.41 120.96,80.88 119.03,78.95 119.03,78.1 115.8,74.87
  IN2 w0.107: v2(120.48,29.69) 119.65,30.53 119.65,34.13 119.51,34.27 119.51,37.59 119.31,37.8 116.72,40.39 116.72,46.27 109.21,53.79 109.21,68.64 112.56,71.98 113.52,71.98 114.47,72.94 114.47,73.35 115.8,74.68 115.8,74.87
  BOTTOM w0.076: v2(122.18,85.44) 122.51,85.77 UC1.AK55
  BOTTOM w0.102: v2(120.48,29.69) 119.88,29.09 119.88,27.93 120.22,27.59 JDIMM2.40
DDR_B_D14: length 67.3
  IN2 w0.076: v2(123.15,82.21) 123.15,80.31 122.8,79.97 122.8,79.86 123.05,79.61 123.05,79.5 122.94,79.4 122.84,79.4 122.3,79.93 122.17,79.93 122.08,79.84 122.08,79.72 122.62,79.18 122.62,79.07 122.51,78.96 122.4,78.96 122.16,79.21 121.86,79.21 121.66,79.02 121.66,78.65 121.74,78.57 122.38,78.57 122.46,78.49 122.46,78.34 122.38,78.26 121.74,78.26 121.66,78.19 121.66,77.97 121.74,77.9 122.01,77.9 122.1,77.81 122.1,77.68 122.01,77.59 121.82,77.59 117.43,73.21
  IN2 w0.107: 117.43,73.21 116.01,71.78 116.01,70.73 113.19,67.91 111.87,66.59 111.87,65.89 111.97,65.78 112,65.78 112.1,65.68 112.1,65.46 112,65.36 111.97,65.36 111.87,65.25 111.87,65.04 111.97,64.93 112,64.93 112.1,64.82 112.1,64.61 112,64.5 111.97,64.5 111.87,64.4 111.87,64.18 111.97,64.08 112,64.08 112.1,63.97 112.1,63.76 112,63.65 111.97,63.65 111.87,63.54 111.87,54.77 120.38,46.26 120.38,40.48 122.36,38.5 122.36,35.62 122.82,35.16 122.82,32.75 122.97,32.6 123.39,32.6 v2(123.53,32.74)
  BOTTOM w0.076: UC1.AR54 123.46,82.52 v2(123.15,82.21)
  BOTTOM w0.102: v2(123.53,32.74) 123.52,32.75 JDIMM2.51
DDR_B_D15: length 68.8
  IN2 w0.076: v2(123.14,83.49) 123.37,83.49 123.51,83.36 123.51,79.73 122.64,78.86 122.64,77.98 117.74,73.08
  IN2 w0.107: v2(123.53,31.22) 123.65,31.09 123.81,31.09 123.96,31.25 123.96,33.15 123.2,33.91 123.2,35.31 122.76,35.74 122.76,38.6 120.91,40.46 120.91,46.24 112.32,54.83 112.32,63.33 112.57,63.58 112.81,63.58 112.93,63.71 112.93,63.88 112.81,64.01 112.57,64.01 112.46,64.12 112.46,64.33 112.57,64.44 112.81,64.44 112.93,64.56 112.93,64.74 112.81,64.86 112.57,64.86 112.46,64.97 112.46,65.18 112.57,65.29 112.81,65.29 112.93,65.41 112.93,65.59 112.81,65.72 112.57,65.72 112.46,65.82 112.46,66.49 116.41,70.44 116.41,71.76 117.74,73.08
  BOTTOM w0.076: v2(123.14,83.49) 123.46,83.82 UC1.AN54
  BOTTOM w0.102: JDIMM2.53 124.12,31.8 v2(123.53,31.22)
DDR_B_D16: length 92.8
  IN2 w0.076: 114.94,86.57 117.18,86.57 118.68,88.07 120.73,88.07 120.89,87.92 121.48,87.92 121.67,88.1 129.1,88.1 131.09,86.12 v2(131.66,86.12)
  IN2 w0.107: 114.94,86.57 113.55,86.57 107.78,80.8 107.78,79.73 97.77,69.72 97.77,50.17 100.82,47.12 100.82,40.82 102.56,39.08 102.56,36.46 108.4,30.62 108.4,29.71 108.3,29.6 108.11,29.6 108.01,29.5 108.01,29.28 108.11,29.18 108.3,29.18 108.4,29.07 108.4,28.56 108.55,28.42 v2(109.19,28.42)
  BOTTOM w0.076: UC1.AK40 132.01,85.77 v2(131.66,86.12)
  BOTTOM w0.102: v2(109.19,28.42) 110.02,27.59 JDIMM2.6
DDR_B_D17: length 92.2
  IN2 w0.076: 114.99,85.17 115.02,85.2 115.28,85.2 115.36,85.12 115.36,84.78 115.44,84.71 115.59,84.71 115.67,84.78 115.67,85.12 115.74,85.2 115.89,85.2 115.97,85.12 115.97,84.78 116.05,84.71 116.2,84.71 116.28,84.78 116.28,85.12 116.35,85.2 116.74,85.2 118.56,87.01 121.29,87.01 121.43,86.87 121.81,86.87 122.55,87.61 128.57,87.61 130.47,85.7 130.47,85.58 v2(130.63,85.42)
  IN2 w0.107: 114.99,85.17 113.93,85.17 113.54,84.78 113.54,84.63 113.74,84.42 113.74,84.27 113.59,84.12 113.44,84.12 113.23,84.33 113.08,84.33 112.93,84.18 112.93,84.03 113.14,83.82 113.14,83.67 112.99,83.52 112.84,83.52 112.63,83.72 112.52,83.72 109.1,80.31 109.1,79.52 99.02,69.43 99.02,52.07 101.91,49.18 101.91,41.46 103.82,39.55 103.82,36.95 107.28,33.48 109.32,33.48 109.67,33.14 109.67,31.95 v2(109.19,31.47)
  BOTTOM w0.076: UC1.AK42 131.02,85.77 130.69,85.45 130.66,85.45 v2(130.63,85.42)
  BOTTOM w0.102: v2(109.19,31.47) 109.42,31.47 110.32,32.38 JDIMM2.7
DDR_B_D18: length 90.1
  IN2 w0.076: v2(129.77,84.34) 129.4,84.7 129.4,84.7 129.33,84.77 129.33,85.68 128.07,86.94 122.82,86.94 122.06,86.19 120.84,86.19 120.67,86.35 119.12,86.35 116.67,83.9 116.19,83.9
  IN2 w0.107: v2(112.56,32.74) 112.56,33.47 110.25,35.78 109.05,35.78 107.93,36.9 107.93,38.33 105.83,40.43 105.83,47.92 102.15,51.6 102.15,57.69 102,57.84 101.61,57.84 101.45,57.99 101.45,58.34 101.61,58.49 101.96,58.49 102.09,58.61 102.09,58.79 101.96,58.91 101.33,58.91 101.23,59.02 101.23,59.23 101.33,59.34 101.99,59.34 102.11,59.47 102.11,59.64 101.99,59.77 101.33,59.77 101.23,59.87 101.23,60.09 101.33,60.19 102.01,60.19 102.14,60.32 102.14,60.5 102.01,60.62 101.33,60.62 101.23,60.73 101.23,60.94 101.33,61.05 102.08,61.05 102.19,61.16 102.19,61.37 102.08,61.48 101.33,61.48 101.23,61.58 101.23,61.8 101.33,61.9 102.08,61.9 102.19,62.01 102.19,62.22 102.08,62.33 101.33,62.33 101.23,62.44 101.23,68.97 110.98,78.73 110.98,78.93 114.31,82.25 114.53,82.25 116.19,83.9
  BOTTOM w0.076: v2(129.77,84.34) 129.9,84.47 UC1.AM43
  BOTTOM w0.102: v2(112.56,32.74) 113.32,33.5 JDIMM2.17
DDR_B_D19: length 89.6
  IN2 w0.076: 117.23,83.14 117.23,83.96 119.29,86.02 120.37,86.02 120.58,85.81 122.25,85.81 123.01,86.57 127.92,86.57 128.41,86.08 128.41,84.59 v2(128.8,84.2)
  IN2 w0.107: 117.23,83.14 113.54,79.46 112.73,79.46 103.53,70.26 103.53,68.28 103.42,68.18 102.42,68.18 102.32,68.07 102.32,67.86 102.42,67.75 103.42,67.75 103.53,67.64 103.53,67.43 103.42,67.32 102.47,67.32 102.34,67.2 102.34,67.02 102.47,66.9 103.42,66.9 103.53,66.79 103.53,66.58 103.42,66.47 102.62,66.47 102.5,66.35 102.5,66.17 102.62,66.04 103.42,66.04 103.53,65.94 103.53,51.24 106.68,48.09 106.68,40.82 109.03,38.47 109.03,38.15 113.47,33.71 113.47,29.07 v2(112.56,28.17)
  BOTTOM w0.076: v2(128.8,84.2) 129.07,84.47 UC1.AM45
  BOTTOM w0.102: v2(112.56,28.17) 113.02,27.71 JDIMM2.16
DDR_B_D20: length 89.7
  IN2 w0.076: v2(128.81,85.5) 128.81,85.96 128.02,86.75 122.89,86.75 122.15,86.01 120.73,86.01 120.55,86.19 119.21,86.19 116.92,83.9 116.92,83.37
  IN2 w0.107: 116.92,83.37 113.44,79.89 112.65,79.89 101.59,68.82 101.59,65.44 101.69,65.33 102.88,65.33 103,65.21 103,65.03 102.88,64.91 101.69,64.91 101.59,64.8 101.59,64.59 101.69,64.48 103,64.48 103.1,64.37 103.1,64.16 103,64.05 101.89,64.05 101.73,63.9 101.73,63.53 101.89,63.38 102.67,63.38 102.82,63.22 102.82,51.44 106.19,48.07 106.19,40.58 108.62,38.15 108.62,37.95 113.09,33.48 113.09,30.21 v2(112.56,29.69)
  BOTTOM w0.076: UC1.AK45 129.08,85.77 v2(128.81,85.5)
  BOTTOM w0.102: v2(112.56,29.69) 113.62,28.63 JDIMM2.18
DDR_B_D21: length 91.1
  IN2 w0.076: 115.95,84.2 116.66,84.2 118.98,86.52 121.09,86.52 121.24,86.36 122.01,86.36 122.75,87.11 128.17,87.11 129.71,85.56 v2(129.71,85.47)
  IN2 w0.107: v2(112.56,31.22) 112.56,31.34 111.94,31.96 111.94,33.2 109.75,35.4 108.79,35.4 107.5,36.69 107.5,38.25 104.89,40.86 104.89,48.35 101.66,51.58 101.66,52.56 101.5,52.71 101.1,52.71 100.95,52.86 100.95,53.14 101.1,53.3 101.6,53.3 101.71,53.4 101.71,53.62 101.6,53.72 100.97,53.72 100.86,53.83 100.86,54.04 100.97,54.15 101.6,54.15 101.71,54.26 101.71,54.47 101.6,54.58 100.97,54.58 100.86,54.68 100.86,54.9 100.97,55 101.6,55 101.71,55.11 101.71,55.32 101.6,55.43 100.97,55.43 100.86,55.54 100.86,55.75 100.97,55.86 101.6,55.86 101.71,55.96 101.71,56.18 101.6,56.28 100.97,56.28 100.86,56.39 100.86,69.12 110.6,78.86 110.6,79.1 114.21,82.71 114.46,82.71 115.95,84.2
  BOTTOM w0.076: UC1.AK43 130.03,85.56 129.8,85.56 v2(129.71,85.47)
  BOTTOM w0.102: JDIMM2.15 112.72,33.67 112.04,32.98 112.04,31.86 112.56,31.34 v2(112.56,31.22)
DDR_B_D22: length 91.8
  IN2 w0.076: v2(131.62,84.78) 131.26,85.14 131.26,85.53 128.85,87.94 121.74,87.94 121.55,87.75 121.15,87.75 120.74,87.34 118.28,87.34 117.23,86.3 115.33,86.3
  IN2 w0.107: v2(109.19,29.95) 108.78,30.35 108.78,30.75 102.99,36.54 102.99,39.21 101.19,41.01 101.19,47.26 98.13,50.32 98.13,69.57 108.23,79.67 108.23,80.46 114.05,86.29 115.32,86.29 115.33,86.3
  BOTTOM w0.076: UC1.AM40 131.93,84.47 v2(131.62,84.78)
  BOTTOM w0.102: v2(109.19,29.95) 108.57,29.33 108.57,28.45 109.42,27.6 JDIMM2.4
DDR_B_D23: length 91
  IN2 w0.076: v2(130.75,84.28) 130.98,84.51 130.98,85.57 128.79,87.77 121.8,87.77 121.62,87.59 121.22,87.59 120.81,87.18 118.42,87.18 116.67,85.42 114.99,85.42
  IN2 w0.107: 114.99,85.42 114.97,85.45 113.73,85.45 108.74,80.46 108.74,79.67 98.49,69.42 98.49,51.84 99.7,50.63 99.7,50.48 99.16,49.95 99.16,49.79 99.31,49.64 99.46,49.64 100,50.18 100.15,50.18 100.3,50.03 100.3,49.88 99.77,49.34 99.77,49.19 99.92,49.04 100.07,49.04 100.6,49.57 100.75,49.57 101.55,48.78 101.55,41.21 103.4,39.36 103.4,36.64 107.16,32.88 v2(109.19,32.88)
  BOTTOM w0.076: v2(130.75,84.28) 130.94,84.47 UC1.AM42
  BOTTOM w0.102: JDIMM2.5 109.72,33.41 v2(109.19,32.88)
DDR_B_D24: length 72.5
  IN2 w0.076: v2(127.85,84.73) 127.85,84.96 127.78,85.03 127.62,85.03 127.47,84.88 127.47,83.79 127.32,83.64 127.32,82.16 127.02,81.86 126.7,81.86 126.65,81.9 125.98,81.9 125.41,81.33 125.41,78.82 125.71,78.51 125.71,77.57 125.37,77.23 125.37,76.24 121.45,72.32
  IN2 w0.107: 121.45,72.32 121.45,67.65 119.19,65.39 119.19,62.15 119.25,62.09 119.25,61.75 119.14,61.64 119,61.64 118.89,61.54 118.89,61.32 119,61.22 119.14,61.22 119.25,61.11 119.25,60.9 119.14,60.79 119,60.79 118.89,60.68 118.89,60.47 119,60.36 119.14,60.36 119.25,60.26 119.25,60.04 119.14,59.94 119.02,59.94 118.89,59.81 118.89,59.63 119.02,59.51 119.14,59.51 119.25,59.4 119.25,59.19 119.14,59.08 119.02,59.08 118.89,58.96 118.89,58.78 119.02,58.66 119.14,58.66 119.25,58.55 119.25,58.27 119.14,58.17 119,58.17 118.89,58.06 118.89,57.85 119,57.74 119.14,57.74 119.25,57.63 119.25,57.42 119.14,57.31 119,57.31 118.89,57.21 118.89,56.99 119,56.89 119.14,56.89 119.25,56.78 119.25,55.66 119.25,54.83 120.91,53.17 121.35,53.17 124.82,49.7 124.82,49.26 127.01,47.07 127.01,46.84 127.15,46.69 127.15,46.41 127.01,46.26 127.01,45.98 127.15,45.84 127.15,45.56 127.01,45.41 127.01,45.13 127.15,44.98 127.15,44.7 127.01,44.56 127.01,44.28 127.15,44.13 127.15,43.85 127.01,43.7 127.01,43.42 127.15,43.28 127.15,43 127.01,42.85 127.01,42.57 127.15,42.42 127.15,42.14 127.01,42 127.01,40.93 128.58,39.35 128.58,35.86 128.94,35.5 128.94,31.87 v2(129.59,31.22)
  BOTTOM w0.076: UC1.AM46 128.25,84.38 128.08,84.38 127.85,84.61 v2(127.85,84.73)
  BOTTOM w0.102: v2(129.59,31.22) 130.16,31.22 130.23,31.28 130.23,32.89 129.79,33.32 129.14,33.32 128.92,33.54 JDIMM2.69
DDR_B_D25: length 71.9
  IN2 w0.076: 118.34,71.68 123.92,77.26 123.92,78.76 124.18,79.02 124.18,83.67 124.53,84.02 124.53,84.03 124.54,84.04 124.54,84.84 124.8,85.1 125.14,85.1 125.48,85.44 125.48,86.11 125.72,86.35 127.12,86.35 127.91,85.56 v2(127.91,85.55)
  IN2 w0.107: 118.34,71.68 118.34,69.97 114.64,66.26 114.64,65.69 114.74,65.58 114.88,65.58 114.98,65.48 114.98,65.26 114.88,65.16 114.74,65.16 114.64,65.05 114.64,64.84 114.74,64.73 114.88,64.73 114.98,64.62 114.98,64.41 114.88,64.3 114.74,64.3 114.64,64.2 114.64,63.98 114.74,63.88 114.88,63.88 114.98,63.77 114.98,63.56 114.88,63.45 114.74,63.45 114.64,63.34 114.64,63.13 114.74,63.02 114.88,63.02 114.98,62.92 114.98,62.7 114.88,62.6 114.74,62.6 114.64,62.49 114.64,62.28 114.74,62.17 114.88,62.17 114.98,62.06 114.98,61.85 114.88,61.74 114.74,61.74 114.64,61.64 114.64,61.42 114.74,61.32 114.88,61.32 114.98,61.21 114.98,61 114.88,60.89 114.74,60.89 114.64,60.78 114.64,60.57 114.74,60.46 114.88,60.46 114.98,60.36 114.98,60.14 114.88,60.04 114.74,60.04 114.64,59.93 114.64,59.72 114.74,59.61 114.88,59.61 114.98,59.5 114.98,59.29 114.88,59.18 114.74,59.18 114.64,59.08 114.64,56.39 115.34,55.69 115.34,55.36 116.31,54.39 116.31,53.61 119.72,50.2 120.13,50.2 121.88,48.46 121.88,48.04 123.22,46.7 123.22,40.55 125.27,38.5 125.27,35.01 125.82,34.47 v2(125.82,32.74)
  BOTTOM w0.076: UC1.AK46 128.14,85.77 v2(127.91,85.55)
  BOTTOM w0.102: JDIMM2.59 125.92,32.84 v2(125.82,32.74)
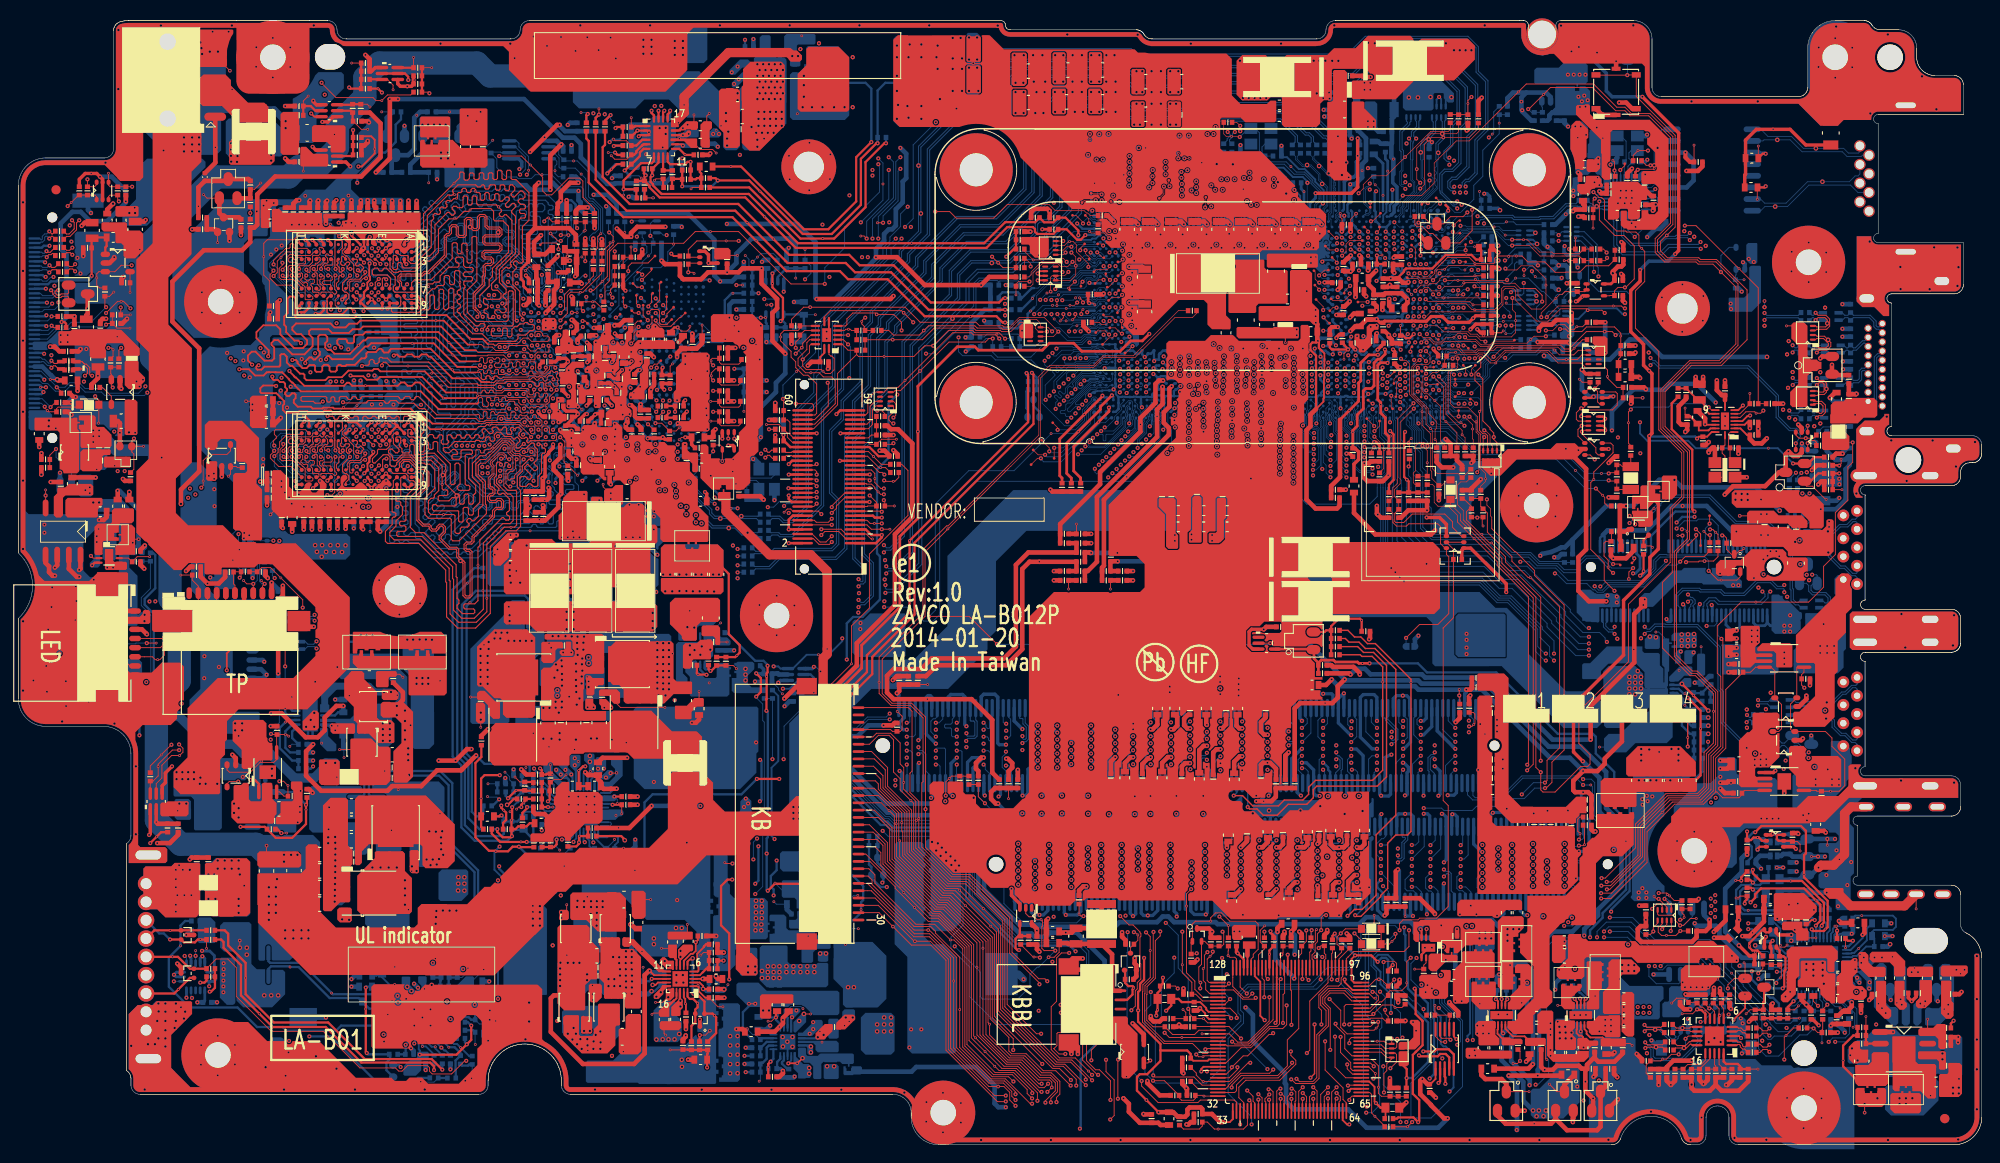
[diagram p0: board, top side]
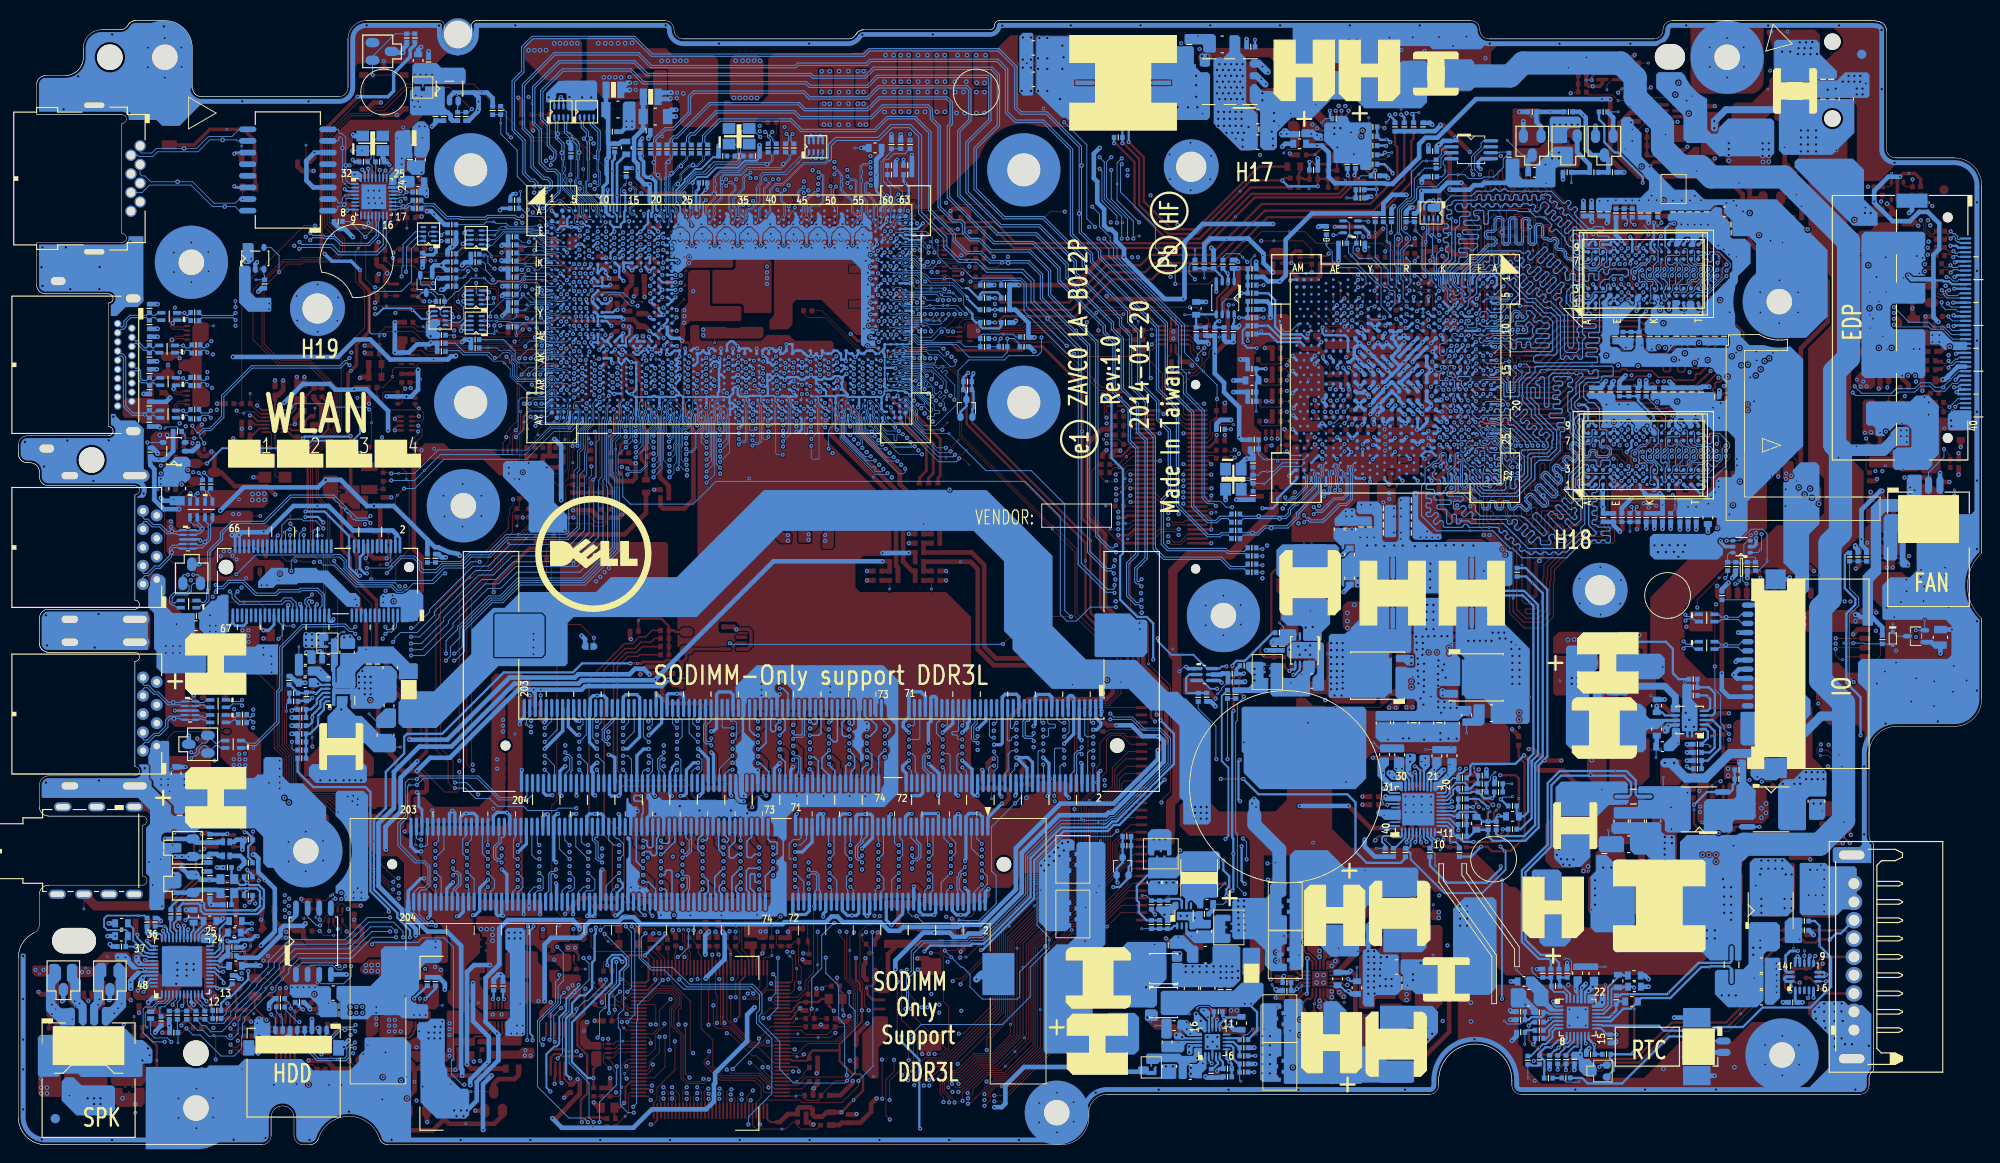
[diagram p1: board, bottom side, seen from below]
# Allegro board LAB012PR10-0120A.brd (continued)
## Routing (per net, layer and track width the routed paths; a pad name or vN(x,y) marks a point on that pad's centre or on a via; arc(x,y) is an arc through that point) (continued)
DDR_B_D26: length 70
  IN2 w0.076: v2(125.89,84.21) 125.22,84.21 124.53,83.53 124.53,78.9 124.26,78.62 124.26,76.86 119.16,71.76
  IN2 w0.107: 119.16,71.76 119.16,69.76 115.7,66.31 115.7,64.34 115.81,64.23 115.96,64.23 116.06,64.12 116.06,63.91 115.96,63.8 115.81,63.8 115.7,63.7 115.7,63.48 115.81,63.38 115.96,63.38 116.06,63.27 116.06,63.06 115.96,62.95 115.81,62.95 115.7,62.84 115.7,62.63 115.81,62.52 115.96,62.52 116.06,62.42 116.06,62.2 115.96,62.1 115.81,62.1 115.7,61.99 115.7,61.78 115.81,61.67 115.96,61.67 116.06,61.56 116.06,61.35 115.96,61.24 115.81,61.24 115.7,61.14 115.7,56.44 116.06,56.08 116.06,55.66 117.04,54.69 117.04,53.91 120.02,50.92 120.43,50.92 122.6,48.75 122.6,48.34 124.54,46.4 124.54,40.25 125.99,38.8 125.99,35.31 126.65,34.65 126.65,28.99 125.83,28.17 v2(125.82,28.17)
  BOTTOM w0.076: v2(125.89,84.21) 126.15,84.47 UC1.AM49
  BOTTOM w0.102: v2(125.82,28.17) 125.62,27.97 JDIMM2.58
DDR_B_D27: length 68.9
  IN2 w0.076: v2(125.92,85.48) 125.73,85.67 125.73,85.83 125.99,86.09 126.12,86.09 126.58,85.63 127.28,85.63 127.72,85.19 128.15,85.19 128.22,85.13 128.22,83.96 128.06,83.8 128.06,83.69 128.24,83.51 128.24,83.38 128.15,83.29 128.03,83.29 127.84,83.48 127.73,83.48 127.49,83.23 127.49,82.09 127.09,81.69 126.63,81.69 126.6,81.72 126.03,81.72 125.57,81.26 125.57,78.91 125.88,78.6 125.88,77.45 125.54,77.11 125.54,76.11 121.81,72.38
  IN2 w0.107: v2(129.59,32.74) 129.33,32.99 129.33,35.61 128.96,35.99 128.96,39.48 127.51,40.93 127.51,47.07 125.18,49.41 125.18,49.84 121.46,53.56 121.03,53.56 119.61,54.97 119.61,55.51 119.61,62.24 119.55,62.3 119.55,64.94 119.96,65.35 121.81,67.2 121.81,72.38
  BOTTOM w0.076: UC1.AK49 126.2,85.77 v2(125.92,85.48)
  BOTTOM w0.102: JDIMM2.67 128.32,33.39 128.97,32.74 v2(129.59,32.74)
DDR_B_D28: length 71.3
  IN2 w0.076: 120.73,72.22 125.04,76.53 125.04,77.36 125.38,77.7 125.38,78.31 125.07,78.63 125.07,81.47 126.31,82.7 126.31,83.29 126.86,83.84 v2(126.86,84.09)
  IN2 w0.107: v2(129.59,28.17) 128.92,28.17 128.76,28.33 128.76,30.87 128.17,31.45 128.17,35.24 127.82,35.6 127.82,39.09 126.28,40.63 126.28,46.77 124.1,48.96 124.1,49.39 121.04,52.45 120.61,52.45 118.53,54.53 118.53,55.52 117.56,56.49 117.56,59.27 117.66,59.37 118.07,59.37 118.17,59.48 118.17,59.69 118.07,59.8 117.66,59.8 117.56,59.91 117.56,60.12 117.66,60.23 118.07,60.23 118.17,60.33 118.17,60.55 118.07,60.65 117.66,60.65 117.56,60.76 117.56,60.97 117.66,61.08 118.07,61.08 118.17,61.19 118.17,61.4 118.07,61.51 117.66,61.51 117.56,61.61 117.56,61.83 117.66,61.93 118.07,61.93 118.47,62.34 118.47,65.69 120.73,67.95 120.73,72.22
  BOTTOM w0.076: UC1.AM48 127.23,84.47 126.88,84.12 126.88,84.11 v2(126.86,84.09)
  BOTTOM w0.102: v2(129.59,28.17) 129.39,28.17 129.22,28 JDIMM2.70
DDR_B_D29: length 70.7
  IN2 w0.076: 121.19,72.31 125.21,76.33 125.21,77.3 125.55,77.63 125.55,78.4 125.24,78.7 125.24,81.39 126.48,82.63 126.48,83.12 127.31,83.95 127.31,84.79 v2(126.84,85.26)
  IN2 w0.107: 121.19,72.31 121.09,72.21 121.09,67.8 118.83,65.54 118.83,62.19 118.81,62.17 118.81,62.15 118.53,61.86 118.53,59.01 118.43,58.91 118.07,58.91 117.96,58.8 117.96,58.59 118.07,58.48 118.43,58.48 118.53,58.37 118.53,58.16 118.43,58.05 118.07,58.05 117.96,57.95 117.96,57.73 118.07,57.63 118.43,57.63 118.53,57.52 118.53,56.18 118.64,56.07 118.64,56.07 118.89,55.82 118.89,54.68 120.76,52.81 121.19,52.81 124.46,49.54 124.46,49.11 126.64,46.92 126.64,40.78 128.18,39.24 128.18,35.75 128.56,35.37 128.56,31.63 129.14,31.04 129.14,29.85 129.3,29.69 v2(129.59,29.69)
  BOTTOM w0.076: UC1.AK48 127.31,85.73 v2(126.84,85.26)
  BOTTOM w0.102: JDIMM2.68 128.62,28.73 v2(129.59,29.69)
DDR_B_D30: length 68.6
  IN2 w0.076: v2(124.95,84.74) 124.71,84.5 124.71,83.95 124.37,83.62 124.37,78.97 124.09,78.69 124.09,77.1 118.75,71.76
  IN2 w0.107: 118.75,71.76 118.75,69.86 115.34,66.46 115.34,58.41 115.24,58.31 115.17,58.31 115.07,58.2 115.07,57.99 115.17,57.88 115.24,57.88 115.34,57.77 115.34,57.56 115.24,57.45 115.17,57.45 115.07,57.35 115.07,57.13 115.17,57.03 115.24,57.03 115.34,56.92 115.34,56.29 115.7,55.93 115.7,55.51 116.68,54.54 116.68,53.76 119.87,50.56 120.28,50.56 122.24,48.61 122.24,48.19 124.14,46.3 124.14,40.14 125.63,38.65 125.63,35.16 126.24,34.55 126.24,30.12 v2(125.82,29.69)
  BOTTOM w0.076: v2(124.95,84.74) 125.22,84.47 UC1.AM51
  BOTTOM w0.102: JDIMM2.56 125.02,28.9 v2(125.82,29.69)
DDR_B_D31: length 68.6
  IN2 w0.076: v2(125.07,86.12) 124.37,85.41 124.37,84.11 124.01,83.75 124.01,79.43 123.2,78.62 123.2,77.65 118.6,73.04
  IN2 w0.107: 118.6,73.04 118.6,72.42 117.94,71.76 117.94,70.07 114.28,66.41 114.28,55.84 115.95,54.16 115.95,53.46 119.57,49.84 119.99,49.84 121.52,48.31 121.52,47.89 122.82,46.6 122.82,40.44 124.9,38.36 124.9,34.68 125.38,34.19 125.38,31.65 v2(125.82,31.22)
  BOTTOM w0.076: v2(125.07,86.12) 125.4,85.79 UC1.AK51
  BOTTOM w0.102: JDIMM2.57 125.32,31.71 v2(125.82,31.22)
DDR_B_D32: length 66.8
  IN2 w0.076: v2(138.27,85.08) 138.27,85.2 138.15,85.33 137.91,85.33 137.78,85.2 137.78,84.54 137.37,84.13 137.37,82.36 137.4,82.33 137.4,72.95 137.48,72.87 137.98,72.87 138.06,72.8 138.06,72.65 137.98,72.57 137.48,72.57 137.4,72.49 137.4,71.5 139.78,69.12
  IN2 w0.107: 139.78,69.12 139.78,65.01 149.02,55.78 149.02,46.02 148.77,45.78 148.77,39.04 149.3,38.52 149.3,35.06 148.34,34.11 148.34,31.67 v2(148.79,31.22)
  BOTTOM w0.076: v2(138.27,85.08) 138.78,84.57 UC1.AM29
  BOTTOM w0.102: JDIMM2.129 149.32,33.69 149.06,33.43 148.87,33.43 148.33,32.88 148.33,31.68 v2(148.79,31.22)
DDR_B_D33: length 68.7
  IN2 w0.076: 139.42,69.12 137.21,71.34 137.21,81.26 136.66,81.8 136.66,82.45 136.74,82.52 137.1,82.52 137.19,82.61 137.19,82.74 137.1,82.83 136.74,82.83 136.66,82.9 136.66,83.07 136.76,83.16 137.05,83.16 137.21,83.32 137.21,84.22 137.29,84.31 137.29,85.2 137.62,85.53 138.08,85.53 138.17,85.61 138.17,85.86 v2(138.4,86.09)
  IN2 w0.107: v2(149.03,28.25) 148.77,28.25 148.38,28.64 148.38,29.9 147.97,30.32 147.97,34.35 148.39,34.78 148.39,40.35 147.83,40.91 147.83,46.51 148.65,47.33 148.65,55.63 139.42,64.86 139.42,69.12
  BOTTOM w0.076: UC1.AK29 138.72,85.77 v2(138.4,86.09)
  BOTTOM w0.102: JDIMM2.130 149.62,27.65 v2(149.03,28.25)
DDR_B_D34: length 67.5
  IN2 w0.076: 140.55,69.14 138.4,71.29 138.4,79.22 137.91,79.71 137.91,82.29 137.7,82.49 137.7,83.88 138.21,84.38 138.47,84.38 138.84,84.75 138.84,84.98 139.23,85.37 v2(139.3,85.37)
  IN2 w0.107: 140.55,69.14 140.55,65.27 149.74,56.08 149.74,45.67 149.54,45.47 149.54,42.01 149.64,41.9 149.73,41.9 149.83,41.8 149.83,41.58 149.73,41.48 149.64,41.48 149.54,41.37 149.54,41.16 149.64,41.05 149.73,41.05 149.83,40.94 149.83,40.73 149.73,40.62 149.64,40.62 149.54,40.52 149.54,39.35 150.02,38.87 150.02,34.66 149.85,34.49 149.33,33.97 149.33,29.93 149.1,29.69 v2(148.79,29.69)
  BOTTOM w0.076: v2(139.3,85.37) 139.42,85.37 139.67,85.12 UC1.AL28
  BOTTOM w0.102: JDIMM2.132 150.22,28.26 v2(148.79,29.69)
DDR_B_D35: length 67.6
  IN2 w0.076: 140.19,69.14 138.24,71.1 138.24,71.34 138.16,71.41 137.74,71.41 137.65,71.5 137.65,71.63 137.74,71.72 138.16,71.72 138.24,71.8 138.24,71.95 138.16,72.02 137.66,72.02 137.57,72.11 137.57,72.24 137.66,72.33 138.16,72.33 138.24,72.4 138.24,79.15 137.74,79.64 137.74,82.22 137.54,82.43 137.54,84.02 138.08,84.56 138.32,84.56 138.68,84.92 138.68,85.46 138.75,85.54 138.75,86.45 138.87,86.57 139.74,86.57 139.86,86.45 139.86,86.08 139.74,85.97 v2(139.28,85.97)
  IN2 w0.107: v2(148.79,32.74) 148.79,33.94 149.66,34.8 149.66,38.72 149.15,39.22 149.15,45.6 149.38,45.82 149.38,55.93 140.19,65.12 140.19,69.14
  BOTTOM w0.076: v2(139.28,85.97) 139.48,85.77 UC1.AK28
  BOTTOM w0.102: v2(148.79,32.74) 149.4,32.74 149.92,33.26 JDIMM2.131
DDR_B_D36: length 65.4
  IN2 w0.076: v2(139.27,82.87) 139.27,82.7 138.87,82.3 138.87,81.72 139.85,80.75 139.85,80.1 139.35,79.61 139.35,78.46 140.04,77.78 140.04,71.12 140.85,70.31 141.81,70.31 143.03,69.09 143.03,68.51
  IN2 w0.107: 143.03,68.51 143.03,66.04 153.35,55.73 153.35,55.27 153.22,55.15 152.91,55.15 152.8,55.03 152.8,54.76 152.91,54.65 153.84,54.65 153.95,54.54 153.95,54.33 153.84,54.22 152.91,54.22 152.8,54.12 152.8,53.9 152.91,53.8 153.84,53.8 153.95,53.69 153.95,53.48 153.84,53.37 152.91,53.37 152.8,53.26 152.8,48.43 152.35,47.98 152.35,40.5 152.61,40.24 152.61,34.11 152.17,33.67 v2(152.17,32.74)
  BOTTOM w0.076: UC1.AR29 138.92,82.52 v2(139.27,82.87)
  BOTTOM w0.102: v2(152.17,32.74) 152.58,32.74 152.92,33.08 JDIMM2.141
DDR_B_D37: length 66.6
  IN2 w0.076: 142.23,69.11 141.41,69.93 140.62,69.93 139.66,70.9 139.66,77.65 139.02,78.28 139.02,80.19 138.47,80.74 138.47,82.42 138.74,82.69 138.74,83.42 138.64,83.52 v2(138.39,83.52)
  IN2 w0.107: v2(152.17,28.17) 151.85,27.84 151.52,27.84 151.27,28.09 151.27,33.8 151.89,34.41 151.89,39.74 151.63,40 151.63,48.52 152.08,48.97 152.08,55.85 142.23,65.7 142.23,69.11
  BOTTOM w0.076: v2(138.39,83.52) 138.39,83.73 138.49,83.82 UC1.AN29
  BOTTOM w0.102: v2(152.17,28.17) 152.67,28.17 153.22,27.61 JDIMM2.142
DDR_B_D38: length 65.3
  IN2 w0.076: 143.69,68.86 141.99,70.57 140.95,70.57 140.21,71.3 140.21,77.85 139.52,78.55 139.52,79.54 140.01,80.03 140.01,80.82 139.27,81.56 v2(139.27,82.19)
  IN2 w0.107: 143.69,68.86 143.69,65.89 154.31,55.27 154.31,53.33 153.99,53.01 153.29,53.01 153.16,52.88 153.16,52.6 153.27,52.49 153.62,52.49 153.73,52.38 153.73,52.17 153.62,52.06 153.27,52.06 153.16,51.96 153.16,48.26 152.71,47.81 152.71,40.75 152.97,40.49 152.97,33.96 152.71,33.7 152.71,31.75 v2(152.17,31.22)
  BOTTOM w0.076: v2(139.27,82.19) 139.6,82.52 UC1.AR28
  BOTTOM w0.102: v2(152.17,31.22) 153.52,32.57 JDIMM2.143
DDR_B_D39: length 66.3
  IN2 w0.076: 142.65,69.02 141.56,70.11 140.7,70.11 139.83,70.97 139.83,77.73 139.19,78.37 139.19,79.72 139.65,80.18 139.65,80.38 139.65,80.67 139.65,80.67 139.65,80.72 138.71,81.66 138.71,82.42 138.91,82.62 138.91,83.17 v2(139.25,83.51)
  IN2 w0.107: v2(152.17,29.69) 151.76,30.1 151.76,33.78 152.25,34.26 152.25,39.99 151.99,40.25 151.99,48.18 152.44,48.63 152.44,56 142.65,65.79 142.65,69.02
  BOTTOM w0.076: UC1.AP28 139.65,83.17 139.32,83.51 v2(139.25,83.51)
  BOTTOM w0.102: JDIMM2.140 152.62,27.46 152.35,27.74 151.65,27.74 151.43,27.96 151.43,28.95 v2(152.17,29.69)
DDR_B_D40: length 67.9
  IN2 w0.076: 145.05,68.68 142.5,71.23 142.17,71.23 141.85,71.55 141.74,71.55 141.49,71.3 141.38,71.3 141.27,71.41 141.27,71.52 141.52,71.77 141.52,71.87 141.41,71.98 141.31,71.98 141.06,71.73 140.95,71.73 140.84,71.84 140.84,71.95 141.09,72.2 141.09,72.3 140.73,72.66 140.73,78 140.86,78.12 140.86,79.32 140.79,79.4 140.58,79.4 140.51,79.48 140.51,79.63 140.58,79.7 140.79,79.7 140.86,79.78 140.86,79.93 140.79,80.01 140.58,80.01 140.51,80.08 140.51,80.24 140.58,80.31 140.79,80.31 140.86,80.39 140.86,80.69 139.96,81.6 139.96,83.16 v2(140.29,83.49)
  IN2 w0.107: 145.05,68.68 145.05,66.43 153.26,58.22 153.41,58.22 153.61,58.42 153.76,58.42 153.91,58.27 153.91,58.12 153.71,57.92 153.71,57.77 153.91,57.56 154.54,57.56 155.65,56.45 155.65,50.84 155.5,50.69 154.74,50.69 154.63,50.59 154.63,50.37 154.74,50.27 155.02,50.27 155.12,50.16 155.12,49.95 155.02,49.84 154.74,49.84 154.63,49.73 154.63,49.52 154.74,49.41 155.02,49.41 155.12,49.31 155.12,49.09 155.02,48.99 154.74,48.99 154.63,48.88 154.63,48.67 154.74,48.56 155.02,48.56 155.12,48.45 155.12,48.24 155.02,48.13 154.74,48.13 154.63,48.03 154.63,46.07 155.12,45.58 155.12,39.43 154.66,38.96 154.66,33.19 v2(154.2,32.73)
  BOTTOM w0.076: UC1.AN26 140.62,83.82 v2(140.29,83.49)
  BOTTOM w0.102: JDIMM2.147 154.72,33.25 v2(154.2,32.73)
DDR_B_D41: length 66.7
  IN2 w0.076: v2(140.31,82.16) 140.31,81.54 141.03,80.83 141.03,78.06 140.9,77.93 140.9,72.75 142.22,71.43 142.65,71.43 145.45,68.64
  IN2 w0.107: v2(154.2,28.16) 154.83,28.16 155.02,28.35 155.02,37.36 155.64,37.98 155.64,39.13 155.53,39.25 155.53,46.21 155.42,46.32 155.11,46.32 155.01,46.42 155.01,46.64 155.11,46.74 155.42,46.74 155.53,46.85 155.53,47.06 155.42,47.17 155.11,47.17 155.01,47.28 155.01,47.49 155.11,47.6 155.42,47.6 155.53,47.7 155.53,50.07 156.01,50.55 156.01,56.69 154.75,57.94 154.74,57.94 153.8,58.88 153.24,58.88 145.45,66.68 145.45,68.64
  BOTTOM w0.076: UC1.AR26 140.68,82.52 140.32,82.16 v2(140.31,82.16)
  BOTTOM w0.102: v2(154.2,28.16) 154.57,28.17 155.02,27.72 JDIMM2.148
DDR_B_D42: length 66.2
  IN2 w0.076: v2(141.27,82.19) 141.27,81.34 141.6,81 141.6,79.94 142.2,79.34 142.2,74.86 142.74,74.31 142.74,72.1 145.7,69.14 146.44,69.14 147.01,68.57 147.01,68.51
  IN2 w0.107: v2(157.51,31.21) 157.01,31.71 157.01,37.18 157.56,37.74 157.56,48.01 157.71,48.16 157.71,48.66 157.82,48.77 158.03,48.77 158.13,48.88 158.13,49.09 158.03,49.2 157.82,49.2 157.7,49.32 157.7,50.78 157.82,50.9 158.11,50.9 158.22,51.01 158.22,51.22 158.11,51.33 157.82,51.33 157.71,51.43 157.71,51.65 157.82,51.75 158.11,51.75 158.22,51.86 158.22,52.07 158.11,52.18 157.82,52.18 157.71,52.29 157.71,52.5 157.82,52.61 158.11,52.61 158.22,52.71 158.22,52.93 158.11,53.03 157.82,53.03 157.71,53.14 157.71,57.1 147.01,67.81 147.01,68.51
  BOTTOM w0.076: UC1.AR25 141.59,82.52 v2(141.27,82.19)
  BOTTOM w0.102: JDIMM2.159 158.32,31.65 157.88,31.21 v2(157.51,31.21)
DDR_B_D43: length 67
  IN2 w0.076: 146.56,69.32 145.8,69.32 142.92,72.2 142.92,75.25 142.84,75.32 142.44,75.32 142.36,75.4 142.36,75.55 142.44,75.63 142.84,75.63 142.92,75.7 142.92,75.86 142.84,75.93 142.44,75.93 142.36,76.01 142.36,76.16 142.44,76.24 142.84,76.24 142.92,76.31 142.92,76.47 142.84,76.54 142.44,76.54 142.36,76.62 142.36,76.77 142.44,76.85 142.84,76.85 142.92,76.92 142.92,77.08 142.84,77.15 142.44,77.15 142.36,77.23 142.36,77.38 142.44,77.46 142.84,77.46 142.92,77.53 142.92,77.69 142.84,77.76 142.44,77.76 142.36,77.84 142.36,77.99 142.44,78.07 142.84,78.07 142.92,78.14 142.92,78.55 142.83,78.65 142.83,79 141.79,80.04 141.79,81.1 141.62,81.27 141.62,82.49 v2(141.27,82.84)
  IN2 w0.107: v2(157.51,32.73) 157.51,37.03 157.97,37.49 157.97,46.73 158.08,46.84 158.6,46.84 158.7,46.95 158.7,47.16 158.6,47.27 158.08,47.27 157.97,47.37 157.97,47.8 158.96,48.8 158.96,49.63 158.58,50.01 158.58,56.94 147.4,68.12 147.4,68.48 146.56,69.32
  BOTTOM w0.076: v2(141.27,82.84) 141.31,82.84 UC1.AP25
  BOTTOM w0.102: v2(157.51,32.73) 157.72,32.95 JDIMM2.157
DDR_B_D44: length 70
  IN2 w0.076: v2(141.1,86.17) 139.79,84.86 139.79,84.09 139.63,83.92 139.63,81.45 140.18,80.9 140.18,79.97 139.78,79.57 139.78,78.52 140.39,77.91 140.39,71.66 141.31,70.74 142.17,70.74 144.31,68.6
  IN2 w0.107: v2(154.2,29.68) 153.43,30.45 153.43,33.39 153.94,33.9 153.94,38.55 153.78,38.71 153.78,51.05 154.93,52.2 154.93,55.96 154.18,56.7 153.75,56.7 144.31,66.14 144.31,68.6
  BOTTOM w0.076: v2(141.1,86.17) 140.7,85.77 UC1.AK26
  BOTTOM w0.102: JDIMM2.146 154.42,27.54 154.24,27.71 154,27.71 153.68,28.03 153.68,29.15 v2(154.2,29.68)
DDR_B_D45: length 69.2
  IN2 w0.076: v2(140.22,84.19) 139.79,83.76 139.79,81.53 140.34,80.98 140.34,80.03 140.34,79.54 140.27,79.47 140.06,79.47 139.99,79.39 139.99,79.24 140.06,79.16 140.27,79.16 140.34,79.08 140.34,79.02 140.7,78.67 140.7,78.26 140.57,78.13 140.57,71.81 141.36,71.02 142.3,71.02 144.68,68.64
  IN2 w0.107: v2(154.2,31.21) 153.79,31.61 153.79,33.04 154.3,33.55 154.3,40.25 154.4,40.36 154.66,40.36 154.76,40.46 154.76,40.68 154.66,40.78 154.32,40.78 154.21,40.89 154.21,44.15 154.32,44.26 154.66,44.26 154.76,44.36 154.76,44.58 154.66,44.68 154.32,44.68 154.21,44.79 154.21,45 154.32,45.11 154.66,45.11 154.76,45.22 154.76,45.43 154.66,45.54 154.35,45.54 154.27,45.62 154.27,50.86 154.65,51.24 155.15,51.24 155.29,51.37 155.29,56.28 154.45,57.12 153.85,57.12 144.68,66.28 144.68,68.64
  BOTTOM w0.076: UC1.AM26 140.5,84.47 v2(140.22,84.19)
  BOTTOM w0.102: JDIMM2.149 155.32,32.32 v2(154.2,31.21)
DDR_B_D46: length 69.9
  IN2 w0.076: 146.82,70.34 145.95,71.2 144.68,71.2 143.94,71.95 143.94,78.92 142.47,80.38 142.47,81.12 142,81.59 142,83.55 141.81,83.74 141.81,84.83 v2(141.19,85.44)
  IN2 w0.107: 146.82,70.34 148.19,68.97 148.19,68.35 159.31,57.24 159.31,50.31 159.68,49.93 159.68,46.85 160.05,46.49 160.05,45.19 158.98,44.12 158.98,36.4 158.35,35.77 158.35,29 v2(157.51,28.16)
  BOTTOM w0.076: v2(141.19,85.44) 141.52,85.77 UC1.AK25
  BOTTOM w0.102: JDIMM2.160 158.62,27.6 158.07,28.16 v2(157.51,28.16)
DDR_B_D47: length 69.2
  IN2 w0.076: v2(141.25,84.82) 141.65,84.43 141.65,83.63 141.81,83.46 141.81,81.49 142.27,81.03 142.27,80.34 143.74,78.87 143.74,71.78 144.51,71.02 145.47,71.02 147.81,68.69
  IN2 w0.107: v2(157.51,29.68) 157.84,29.68 157.99,29.83 157.99,36.02 158.57,36.59 158.57,44.31 159.06,44.81 159.06,46.68 159.32,46.95 159.32,47.48 159.22,47.59 159,47.59 158.89,47.69 158.89,47.91 159,48.01 159.22,48.01 159.32,48.12 159.32,49.78 158.94,50.16 158.94,57.09 147.81,68.23 147.81,68.69
  BOTTOM w0.076: v2(141.25,84.82) 141.55,85.12 UC1.AL25
  BOTTOM w0.102: JDIMM2.158 158.02,27.44 157.72,27.74 157.35,27.74 157.09,28 157.09,29.26 v2(157.51,29.68)
DDR_B_D48: length 67.7
  IN2 w0.076: v2(144.12,82.09) 144.12,81.61 144.75,80.98 144.75,79.8 145.14,79.4 145.14,78.62 145.75,78.01 145.75,73.43 147.1,72.09 149.66,72.09 152.23,69.52
  IN2 w0.107: v2(163.12,29.69) 162.47,29.69 162.24,29.92 162.24,34.52 163.02,35.29 163.02,38.99 163.45,39.42 163.45,39.43 163.46,39.44 163.46,41.97 163.91,42.42 163.91,48.52 163.07,49.36 163.07,51.06 162.57,51.57 162.57,58.63 152.38,68.81 152.38,69.37 152.23,69.52
  BOTTOM w0.076: v2(144.12,82.09) 144.39,82.36 UC1.AR21
  BOTTOM w0.102: JDIMM2.174 162.82,27.63 162.39,28.06 162.39,28.96 v2(163.12,29.69)
DDR_B_D49: length 68.6
  IN2 w0.076: 149.13,71.43 147,71.43 145.93,72.5 145.76,72.5 145.61,72.65 145.46,72.65 145.31,72.5 144.93,72.5 144.6,72.83 144.6,79.23 143.31,80.51 143.31,81.37 142.99,81.69 v2(142.99,82.17)
  IN2 w0.107: v2(159.87,31.22) 159.96,31.13 160.14,31.13 160.28,31.26 160.28,34.7 160.51,34.93 160.51,35.08 160.39,35.19 160.39,35.34 160.54,35.5 160.69,35.5 160.81,35.38 160.96,35.38 161.52,35.95 161.52,37.08 161.42,37.19 160.84,37.19 160.74,37.3 160.74,37.51 160.84,37.62 161.42,37.62 161.52,37.72 161.52,42.14 162.42,43.03 162.42,47.12 161.52,48.01 161.52,50.5 161.06,50.96 161.06,57.88 150.17,68.77 150.17,70.38 149.13,71.43
  BOTTOM w0.076: v2(142.99,82.17) 143.34,82.52 UC1.AR22
  BOTTOM w0.102: JDIMM2.165 160.12,33.54 160.32,33.34 160.32,31.44 160.1,31.22 v2(159.87,31.22)
DDR_B_D50: length 70.8
  IN2 w0.076: v2(144,84.79) 144.39,84.4 144.39,82.63 144.7,82.32 144.7,81.61 145.12,81.2 145.12,80.08 146.08,79.11 146.08,73.71 147.33,72.47 150.73,72.47 153.45,69.75 154.03,69.75 154.26,69.52
  IN2 w0.107: 154.26,69.52 154.26,69.52 154.26,68.68 157.44,65.5 157.44,65.35 157.24,65.15 157.24,65 157.39,64.85 157.54,64.85 157.74,65.05 157.89,65.05 158.04,64.9 158.04,64.75 157.84,64.55 157.84,64.4 157.99,64.25 158.14,64.25 158.34,64.45 158.49,64.45 158.65,64.3 158.65,64.15 158.44,63.94 158.44,63.79 158.6,63.64 158.75,63.64 158.95,63.84 159.1,63.84 159.25,63.69 159.25,63.54 159.05,63.34 159.05,63.19 159.2,63.04 159.35,63.04 159.55,63.24 159.7,63.24 159.85,63.09 159.85,62.94 159.65,62.74 159.65,62.59 159.8,62.44 159.95,62.44 160.15,62.64 160.31,62.64 160.46,62.49 160.46,62.34 160.25,62.13 160.25,61.98 160.41,61.83 160.56,61.83 160.76,62.03 160.91,62.03 161.06,61.88 161.06,61.73 160.86,61.53 160.86,61.38 163.53,58.71 163.53,51.74 164.65,50.63 164.65,42.08 164.19,41.62 164.19,38.97 163.74,38.52 163.74,34.07 163.12,33.45 v2(163.12,32.74)
  BOTTOM w0.076: v2(144,84.79) 144.32,85.12 UC1.AL21
  BOTTOM w0.102: JDIMM2.175 163.12,33.11 163.12,32.95 v2(163.12,32.74)
DDR_B_D51: length 71
  IN2 w0.076: v2(143.04,84.14) 142.45,83.55 142.45,81.74 142.92,81.27 142.92,80.42 144.27,79.07 144.27,72.61 144.74,72.14 145.82,72.14 147,70.95
  IN2 w0.107: 147,70.95 147.04,70.92 147.66,70.92 147.78,70.79 147.78,70.64 147.54,70.4 147.54,70.25 147.68,70.11 147.87,70.11 148.6,70.84 148.75,70.84 148.9,70.69 148.9,70.54 148.77,70.41 148.77,70.24 148.88,70.13 149.05,70.13 149.16,70.24 149.35,70.24 149.5,70.09 149.5,69.94 149.29,69.73 149.29,69.58 149.35,69.51 149.35,68.57 160.28,57.64 160.28,50.71 160.71,50.28 160.71,47.27 161.04,46.94 161.04,44.66 160.23,43.85 160.23,40.19 159.98,39.93 159.98,35.97 159.42,35.41 159.42,30.14 v2(159.87,29.69)
  BOTTOM w0.076: UC1.AM22 143.37,84.47 v2(143.04,84.14)
  BOTTOM w0.102: v2(159.87,29.69) 159.3,29.12 159.3,28.11 159.82,27.58 JDIMM2.164
DDR_B_D52: length 70.1
  IN2 w0.076: 148.77,71.18 147.02,71.18 145.87,72.32 144.81,72.32 144.43,72.7 144.43,79.15 143.09,80.49 143.09,81.35 142.62,81.81 142.62,83.09 v2(143.01,83.48)
  IN2 w0.107: v2(159.87,32.74) 159.87,35.33 160.36,35.82 160.36,37.98 160.46,38.08 161.06,38.08 161.16,38.19 161.16,38.4 161.06,38.51 160.46,38.51 160.36,38.62 160.36,38.83 160.46,38.94 161.06,38.94 161.16,39.04 161.16,39.26 161.06,39.36 160.46,39.36 160.36,39.47 160.36,39.76 160.46,39.86 161.05,39.86 161.16,39.97 161.16,40.18 161.06,40.29 160.7,40.29 160.6,40.4 160.6,40.61 160.7,40.72 161.02,40.72 161.14,40.84 161.14,41.02 161.02,41.14 160.7,41.14 160.6,41.25 160.6,41.46 160.7,41.57 161.02,41.57 161.14,41.7 161.14,41.87 161.02,42 160.7,42 160.6,42.1 160.6,42.53 160.8,42.74 161.61,42.74 162.06,43.18 162.06,46.97 161.07,47.95 161.07,50.43 160.64,50.86 160.64,57.79 160.63,57.81 149.76,68.67 149.76,70.18 148.77,71.18
  BOTTOM w0.076: UC1.AN22 143.34,83.82 v2(143.01,83.48)
  BOTTOM w0.102: JDIMM2.163 159.52,33.09 v2(159.87,32.74)
DDR_B_D53: length 68.8
  IN2 w0.076: v2(144.01,82.86) 144.01,82.77 144.49,82.29 144.49,81.51 144.93,81.08 144.93,80 145.92,79.01 145.92,73.62 147.25,72.29 150.39,72.29 153.16,69.52
  IN2 w0.107: v2(163.12,31.22) 162.85,31.22 162.62,31.45 162.62,34.37 163.38,35.13 163.38,38.79 163.82,39.24 163.82,41.82 164.27,42.27 164.27,50.37 163.1,51.55 163.1,58.63 156.56,65.16 156.56,65.29 156.68,65.41 156.68,65.59 156.56,65.72 156.38,65.72 156.26,65.59 156.11,65.59 155.96,65.75 155.96,65.9 156.08,66.02 156.08,66.2 155.96,66.32 155.78,66.32 155.66,66.2 155.51,66.2 155.36,66.35 155.36,66.5 155.44,66.59 155.44,66.74 155.15,67.03 155.15,67.28 154.91,67.52 154.2,67.52 153.32,68.4 153.32,69.36 153.16,69.52
  BOTTOM w0.076: v2(144.01,82.86) 144.32,83.17 UC1.AP21
  BOTTOM w0.102: JDIMM2.177 163.72,31.82 v2(163.12,31.22)
DDR_B_D54: length 71.5
  IN2 w0.076: v2(144.02,85.44) 144.42,85.04 144.42,84.73 144.56,84.6 144.56,82.69 144.93,82.32 144.93,81.64 145.3,81.27 145.3,80.16 146.25,79.21 146.25,73.85 147.45,72.65 150.93,72.65 153.63,69.96 154.19,69.96 154.62,69.52
  IN2 w0.107: 154.62,69.52 154.62,68.83 164.01,59.44 164.01,51.77 165.18,50.6 165.18,38.67 164.1,37.58 164.1,33.87 163.63,33.41 163.63,28.68 163.12,28.17 v2(163.12,28.17)
  BOTTOM w0.076: UC1.AK21 144.35,85.77 v2(144.02,85.44)
  BOTTOM w0.102: JDIMM2.176 163.42,27.87 v2(163.12,28.17)
DDR_B_D55: length 71.8
  IN2 w0.076: 148.65,69.27 148.22,69.27 145.52,71.96 144.66,71.96 144.1,72.52 144.1,79 142.68,80.42 142.68,81.21 142.29,81.6 142.29,83.62 142.6,83.94 142.6,85.01 v2(143.04,85.44)
  IN2 w0.107: 148.65,69.27 148.8,69.11 148.8,68.61 159.8,57.62 159.92,57.49 159.92,50.57 160.3,50.19 160.3,47.11 160.66,46.75 160.66,44.89 159.83,44.05 159.83,40.32 159.59,40.09 159.59,36.12 159.01,35.54 159.01,27.33 159.21,27.13 159.66,27.13 159.87,27.33 v2(159.87,28.17)
  BOTTOM w0.076: UC1.AK22 143.37,85.77 v2(143.04,85.44)
  BOTTOM w0.102: JDIMM2.166 160.42,27.61 v2(159.87,28.17)
DDR_B_D56: length 72.5
  IN2 w0.076: v2(144.95,84.15) 144.97,84.15 145.32,83.79 145.32,81.74 145.65,81.41 145.65,80.39 146.61,79.43 146.61,74.17 146.79,73.99 147.3,73.99 147.76,74.45 149.3,74.45 150.65,73.11 151.24,73.11 153.47,70.87 155.3,70.87 155.61,70.56 155.61,69.52
  IN2 w0.107: v2(165.41,29.8) 164.92,29.8 164.61,30.12 164.61,32.91 165.08,33.37 165.08,37.08 166.24,38.24 166.24,39.92 166.71,40.39 166.71,42.32 166.18,42.85 166.18,51.21 165.39,52 165.39,59.45 155.61,69.22 155.61,69.52
  BOTTOM w0.076: v2(144.95,84.15) 145.28,83.82 UC1.AN20
  BOTTOM w0.102: v2(165.41,29.8) 164.62,29.02 JDIMM2.180
DDR_B_D57: length 71.7
  IN2 w0.076: 155.25,69.52 155.25,69.55 154.62,70.18 153.8,70.18 151.16,72.83 147.55,72.83 146.44,73.94 146.44,79.3 145.49,80.25 145.49,81.33 145.12,81.7 145.12,82.4 144.92,82.6 v2(144.92,82.87)
  IN2 w0.107: 155.25,69.52 155.25,69.07 164.92,59.4 164.92,51.83 165.82,50.93 165.82,38.41 164.71,37.31 164.71,33.6 164.25,33.13 164.25,27.58 164.55,27.28 165.21,27.28 165.41,27.49 165.41,28.28 v2(165.41,28.28)
  BOTTOM w0.076: UC1.AR20 145.26,82.52 v2(144.92,82.87)
  BOTTOM w0.102: JDIMM2.182 165.22,28.09 v2(165.41,28.28)
DDR_B_D58: length 73
  IN2 w0.076: v2(146.03,86.22) 146.36,85.89 146.36,85.4 147.05,84.71 147.05,81.81 147.27,81.59 148.06,81.59 148.48,81.17 148.48,80.08
  IN2 w0.107: v2(168.86,31.33) 169.32,31.79 169.32,35.06 169.99,35.72 169.99,37.02 170.19,37.22 170.19,47.71 170.36,47.88 170.36,59.13 166.53,62.97 166.53,63.43 164.62,65.33 164.2,65.33 160.9,68.63 160.9,69.36 159.98,70.29 159.25,70.29 158.5,71.04 158.18,71.04 153.6,75.62 150.68,75.62 149.4,76.9 149.4,79.16 148.48,80.08
  BOTTOM w0.076: UC1.AK18 146.29,85.96 v2(146.03,86.22)
  BOTTOM w0.102: JDIMM2.191 167.92,32.27 v2(168.86,31.33)
DDR_B_D59: length 72.8
  IN2 w0.076: 148.27,80.01 148.27,81.13 147.99,81.41 147.2,81.41 146.88,81.73 146.88,84.55 145.83,85.6 v2(145.83,85.67)
  IN2 w0.107: 148.27,80.01 149.21,79.07 149.21,76.74 150.55,75.39 153.3,75.39 157.99,70.69 158.33,70.69 159.13,69.89 159.54,69.89 160.54,68.88 160.54,68.48 160.82,68.2 164.07,64.95 164.47,64.95 166.12,63.3 166.12,62.86 169.06,59.93 169.94,59.05 169.94,51.08 169.83,50.97 169.41,50.97 169.25,50.81 169.25,50.59 169.36,50.48 169.83,50.48 169.94,50.38 169.94,50.16 169.83,50.06 169.36,50.06 169.25,49.95 169.25,49.74 169.36,49.63 169.83,49.63 169.94,49.52 169.94,49.31 169.83,49.2 169.36,49.2 169.25,49.1 169.25,48.88 169.36,48.78 169.83,48.78 169.94,48.67 169.94,48.46 169.83,48.35 169.36,48.35 169.25,48.24 169.25,44.12 169.79,43.59 169.79,37.38 169.63,37.22 169.63,35.9 168.86,35.13 v2(168.86,32.85)
  BOTTOM w0.076: v2(145.83,85.67) 146.29,85.21 UC1.AL18
  BOTTOM w0.102: v2(168.86,32.85) 168.52,33.19 JDIMM2.193
DDR_B_D60: length 74.1
  IN2 w0.076: v2(145.23,86.24) 145.46,86 145.46,85.48 145.73,85.22 145.9,85.22 146.72,84.41 146.72,81 147.92,79.8 148.15,79.8
  IN2 w0.107: v2(168.86,29.8) 168.41,30.26 168.41,35.31 168.74,35.65 168.74,36.86 169.43,37.55 169.43,43.44 168.84,44.02 168.84,51.07 169.58,51.8 169.58,58.9 165.74,62.74 165.74,63.17 164.34,64.57 163.94,64.57 160.46,68.05 160.18,68.33 160.18,68.73 159.39,69.53 158.98,69.53 158.05,70.46 157.74,70.46 153.07,75.14 150.53,75.14 149,76.66 149,78.97 148.18,79.8 148.15,79.8
  BOTTOM w0.076: UC1.AK20 145.34,86.13 v2(145.23,86.24)
  BOTTOM w0.102: v2(168.86,29.8) 168.22,29.16 JDIMM2.192
DDR_B_D61: length 72.8
  IN2 w0.076: 147.99,79.58 147.86,79.58 146.55,80.89 146.55,83.66 146.26,83.95 146.26,84.34 v2(145.77,84.83)
  IN2 w0.107: 147.99,79.58 148.11,79.58 148.8,78.89 148.8,76.46 150.37,74.88 152.86,74.88 157.6,70.15 157.86,70.15 158.83,69.17 159.24,69.17 159.82,68.58 159.82,68.18 163.81,64.19 164.21,64.19 165.31,63.09 165.31,62.66 169.22,58.75 169.22,51.95 168.41,51.14 168.41,43.95 169.07,43.29 169.07,37.7 168.38,37.01 168.38,35.82 168,35.44 168,28.4 168.26,28.15 168.73,28.15 v2(168.86,28.28)
  BOTTOM w0.076: v2(145.77,84.83) 145.4,84.47 UC1.AM20
  BOTTOM w0.102: v2(168.86,28.28) 168.82,28.24 JDIMM2.194
DDR_B_D62: length 70
  IN2 w0.076: v2(145.84,82.13) 145.84,81.74 146.01,81.57 146.01,80.69 147.32,79.38 147.53,79.17 147.53,75.34 147.96,74.91 149.33,74.91 150.68,73.56 151.39,73.56
  IN2 w0.107: v2(165.41,31.33) 165.76,31.33 165.87,31.22 165.87,30.26 165.97,30.15 166.19,30.15 166.3,30.26 166.3,31.31 166.58,31.58 166.58,37.39 167.56,38.37 167.56,42.66 166.9,43.32 166.9,51.83 166.38,52.35 166.38,59.48 156.47,69.38 156.47,70.31 155.42,71.37 153.99,71.37 151.8,73.56 151.39,73.56
  BOTTOM w0.076: v2(145.84,82.13) 146.23,82.52 UC1.AR18
  BOTTOM w0.102: v2(165.41,31.33) 165.87,31.79 165.87,33.38 165.52,33.73 JDIMM2.183
DDR_B_D63: length 70.4
  IN2 w0.076: 151.44,73.36 150.63,73.36 149.31,74.68 147.88,74.68 147.35,75.21 147.35,79.07 145.84,80.58 145.84,81.48 145.49,81.84 145.49,82.49 v2(145.85,82.86)
  IN2 w0.107: 151.44,73.36 153.68,71.13 155.3,71.13 156.06,70.36 156.06,69.28 165.96,59.39 165.96,52.16 166.54,51.58 166.54,43.05 167.19,42.4 167.19,38.64 166.2,37.65 166.2,37.24 166.09,37.13 165.85,37.13 165.74,37.03 165.74,36.81 165.85,36.71 166.09,36.71 166.2,36.6 166.2,35.88 166.09,35.77 165.56,35.77 165.44,35.64 165.44,35.47 165.56,35.34 166.09,35.34 166.2,35.24 166.2,35.02 166.09,34.92 165.56,34.92 165.44,34.79 165.44,34.61 165.56,34.49 166.09,34.49 166.2,34.38 166.2,34.17 166.09,34.06 165.56,34.06 165.44,33.94 165.44,33.76 165.56,33.64 166.09,33.64 166.2,33.53 166.2,32.49 166.07,32.36 165.74,32.36 165.41,32.7 v2(165.41,32.85)
  BOTTOM w0.076: v2(145.85,82.86) 145.88,82.86 146.19,83.17 UC1.AP18
  BOTTOM w0.102: JDIMM2.181 164.92,33.34 v2(165.41,32.85)
DDR_B_DQS0: length 70.4
  IN2 w0.076: 113.21,75.37 113.23,75.37 113.31,75.46 113.46,75.46 113.98,75.98 113.98,76.39 114.47,76.88 114.71,76.88 118.34,80.51 118.34,80.89 118.99,81.54 118.99,83.08 119.7,83.79 120.21,83.79 120.28,83.72 v2(120.28,83.49)
  IN2 w0.119: v2(116.8,31.6) 116.8,31.37 116.65,31.22 116.44,31.22 116.34,31.32 116.34,32.95 116.72,33.33 116.72,35.41 115.88,36.25 114.89,37.24 114.89,38.16 114.63,38.42 114.63,38.42 114.24,38.81 114.24,38.81 112.12,40.93 112.12,46.63 106.45,52.3 106.45,69.46 111.29,74.3 112.1,74.3 113.17,75.37 113.21,75.37
  BOTTOM w0.076: v2(120.28,83.49) 120.3,83.51 120.79,83.51 120.88,83.6 120.88,83.74 120.8,83.82 UC1.AN58
  BOTTOM w0.114: v2(116.8,31.6) 116.8,31.35 116.71,31.27 116.32,31.27 116.08,31.51 116.08,32.71 116.92,33.55 JDIMM2.29
DDR_B_DQS1: length 68.1
  IN2 w0.076: 115.09,71.05 115.11,71.07 115.11,71.4 116.96,73.25 116.96,74.55 120.72,78.3 120.72,79 122.13,80.41 122.13,80.89 122.58,81.35 122.58,83.55 122.47,83.66 122.26,83.66 122.19,83.59 v2(122.19,83.49)
  IN2 w0.119: 115.09,71.05 110.91,66.87 110.91,54.49 119.08,46.32 119.08,40.54 121.21,38.41 121.21,35.31 121.55,34.98 121.55,31.27 121.77,31.05 122.05,31.05 v2(122.26,30.83)
  BOTTOM w0.076: v2(122.19,83.49) 122.51,83.82 UC1.AN55
  BOTTOM w0.114: JDIMM2.47 122.32,33.46 122.42,33.37 122.42,33.14 122.98,32.58 122.98,31.34 122.72,31.07 122.5,31.07 v2(122.26,30.83)
DDR_B_DQS2: length 91.2
  IN2 w0.076: v2(130.63,84.85) 130.55,84.85 130.27,85.13 130.27,85.67 128.51,87.44 122.61,87.44 121.87,86.69 121.37,86.69 121.22,86.85 118.76,86.85 117.19,85.27 116.46,84.54 114.46,84.54 113.09,83.18 112.91,83.18 112.02,82.29 111.96,82.29 111.94,82.28
  IN2 w0.119: 111.94,82.28 109.73,80.06 109.73,79.22 99.99,69.48 99.99,52.01 103.95,48.06 103.95,40.56 106.2,38.31 106.2,35.54 107.43,34.31 109.59,34.31 110.3,33.61 110.3,31.9 110.62,31.58 111.08,31.58 111.67,30.99 111.67,30.46 111.38,30.18 111.18,30.18 v2(111.04,30.33)
  BOTTOM w0.076: UC1.AL42 130.82,85.12 130.63,84.92 v2(130.63,84.85)
  BOTTOM w0.114: JDIMM2.12 111.82,27.78 111.9,27.86 111.9,29.18 111.73,29.35 111.73,29.63 v2(111.04,30.33)
DDR_B_DQS3: length 70.1
  IN2 w0.076: 119.85,71.05 119.85,71.97 124.48,76.6 124.48,78.43 124.72,78.67 124.72,81.88 125.33,82.49 125.34,82.49 125.34,83.04 125.34,83.04 125.34,83.09 126.29,84.04 126.29,84.69 126.16,84.82 v2(125.94,84.82)
  IN2 w0.119: 119.85,71.05 119.85,68.47 117.59,66.21 117.59,63.96 116.68,63.06 116.68,59.69 116.32,59.33 116.32,58.86 116.68,58.5 116.68,57.9 116.32,57.54 116.32,57.07 116.68,56.71 116.68,55.92 117.66,54.95 117.66,54.16 120.28,51.54 120.69,51.54 123.22,49.01 123.22,48.6 125.21,46.62 125.21,40.46 126.93,38.74 126.93,35.25 127.29,34.9 127.29,29.9 127.67,29.52 127.92,29.52 128.07,29.37 128.07,29.35 v2(128.11,29.31)
  BOTTOM w0.076: UC1.AL49 126.24,85.12 v2(125.94,84.82)
  BOTTOM w0.114: JDIMM2.64 127.42,27.65 127.22,27.86 127.22,29.4 127.4,29.58 127.84,29.58 v2(128.11,29.31)
DDR_B_DQS4: length 66.8
  IN2 w0.076: 141.36,68.51 141.36,68.53 141.4,68.57 141.4,69.35 141.29,69.46 140.53,69.46 138.65,71.34 138.65,79.79 138.07,80.37 138.07,82.36 137.87,82.56 137.87,83.75 138.23,84.12 138.54,84.12 139.01,84.59 139.1,84.59 v2(139.29,84.78)
  IN2 w0.119: 141.36,68.51 141.36,65.34 150.36,56.34 150.85,55.84 150.85,50.34 150.45,49.94 150.45,39.31 150.75,39.02 150.75,34.51 150.55,34.31 149.95,33.71 149.95,31.28 150.22,31.02 150.55,31.02 150.65,30.92 v2(150.65,30.83)
  BOTTOM w0.076: v2(139.29,84.78) 139.32,84.78 139.63,84.47 UC1.AM28
  BOTTOM w0.114: v2(150.65,30.83) 150.81,31 151.06,31 151.33,31.27 151.33,32.9 151.72,33.3 JDIMM2.137
DDR_B_DQS5: length 68.2
  IN2 w0.076: 146.08,68.51 146.07,68.52 146.07,68.58 145.88,68.77 145.59,68.77 145.45,68.92 142.66,71.71 142.2,71.71 141.85,72.05 141.85,77.92 141.22,78.55 141.22,80.88 140.71,81.38 140.71,83.76 140.9,83.95 141.05,83.95 v2(141.25,84.14)
  IN2 w0.119: 146.08,68.51 146.13,68.45 146.13,67.44 156.83,56.75 156.83,49.54 156.24,48.95 156.24,39.71 156.69,39.26 156.69,38.12 155.89,37.33 155.89,31.52 156.46,30.95 156.46,30.04 156.23,29.81 155.93,29.81 v2(155.68,30.06)
  BOTTOM w0.076: UC1.AM25 141.57,84.47 v2(141.25,84.14)
  BOTTOM w0.114: v2(155.68,30.06) 155.89,29.86 156.24,29.86 156.47,29.62 156.47,27.72 156.82,27.37 JDIMM2.154
DDR_B_DQS6: length 69.7
  IN2 w0.076: v2(143.99,84.17) 143.84,84.02 143.63,84.02 143.43,83.82 143.43,81.65 143.51,81.57 143.51,80.57 144.8,79.28 144.8,78.47 145.41,77.86 145.41,77.85 145.42,77.84 145.42,73.25 147.02,71.66 149.18,71.66 150.87,69.96 150.87,69.58 150.83,69.53 150.83,69.52
  IN2 w0.119: v2(161.62,30.83) 161.44,31.02 161.19,31.02 160.92,31.3 160.92,34.42 162.15,35.65 162.15,39.36 162.59,39.81 162.59,42.33 163.04,42.78 163.04,47.82 162.15,48.71 162.15,50.76 161.68,51.22 161.68,58.14 150.83,68.99 150.83,69.2 150.83,69.52
  BOTTOM w0.076: UC1.AM21 144.28,84.47 v2(143.99,84.17)
  BOTTOM w0.114: JDIMM2.171 161.92,33.12 162.51,32.53 162.51,31.33 162.16,30.98 161.77,30.98 v2(161.62,30.83)
DDR_B_DQS7: length 71.8
  IN2 w0.076: v2(145.87,84.07) 145.87,83.9 145.97,83.81 146.14,83.81 146.39,83.57 146.39,80.81 147.89,79.3 148.01,79.3 148.62,78.69 148.62,76.16 150.14,74.64 152.7,74.64 157.16,70.19 157.16,69.87 157.32,69.71 157.38,69.71 157.39,69.7
  IN2 w0.119: v2(166.93,29.42) 167.11,29.6 167.37,29.6 167.63,29.86 167.63,36.01 167.75,36.12 167.75,37.27 168.43,37.95 168.43,43.03 167.77,43.69 167.77,51.39 168.59,52.21 168.59,58.49 157.39,69.7
  BOTTOM w0.076: v2(145.87,84.07) 146.28,84.47 UC1.AM18
  BOTTOM w0.114: JDIMM2.188 167.02,27.59 166.89,27.72 166.89,27.94 166.31,28.52 166.31,29.41 166.53,29.63 166.85,29.63 166.93,29.54 v2(166.93,29.42)
DDR_B_DQS#0: length 70.5
  IN2 w0.076: 113.21,75.62 113.39,75.62 113.81,76.04 113.81,76.45 114.4,77.04 114.64,77.04 118.17,80.58 118.17,80.96 118.83,81.61 118.83,83.15 119.63,83.95 120.11,83.95 v2(120.32,84.16)
  IN2 w0.119: 113.21,75.62 113.07,75.62 112,74.55 111.18,74.55 106.19,69.57 106.19,52.2 111.87,46.52 111.87,40.82 114.13,38.56 114.14,38.56 114.38,38.31 114.38,38.31 114.64,38.05 114.64,37.14 115.71,36.07 116.09,35.69 116.47,35.31 116.47,33.43 116.09,33.05 116.09,31.22 116.34,30.97 116.67,30.97 v2(116.8,30.83)
  BOTTOM w0.076: v2(120.32,84.16) 120.32,84.18 120.61,84.47 UC1.AM58
  BOTTOM w0.114: v2(116.8,30.83) 116.62,31.02 116.22,31.02 115.84,31.4 115.84,32.82 116.32,33.3 JDIMM2.27
DDR_B_DQS#1: length 68.2
  IN2 w0.076: v2(122.19,84.14) 122.19,83.9 122.24,83.85 122.51,83.85 122.75,83.61 122.75,81.28 122.29,80.82 122.29,80.34 120.88,78.93 120.88,78.24 117.13,74.48 117.13,73.18 115.27,71.33 115.27,70.98 115.28,70.98 115.28,70.97
  IN2 w0.119: 115.28,70.97 115.28,70.88 111.16,66.77 111.16,54.6 119.34,46.42 119.34,40.65 121.47,38.51 121.47,35.41 121.8,35.08 121.8,31.37 121.88,31.3 122.24,31.3 122.32,31.38 122.32,31.54 v2(122.26,31.6)
  BOTTOM w0.076: UC1.AM55 122.51,84.47 v2(122.19,84.14)
  BOTTOM w0.114: v2(122.26,31.6) 122.26,31.43 122.37,31.32 122.61,31.32 122.74,31.44 122.74,32.47 122.17,33.04 122.17,33.26 121.72,33.71 JDIMM2.45
DDR_B_DQS#2: length 91.1
  IN2 w0.076: v2(129.78,84.9) 129.93,84.74 130.19,84.74 130.24,84.79 130.24,84.93 130.1,85.06 130.1,85.6 128.44,87.27 122.68,87.27 121.94,86.53 121.31,86.53 121.15,86.68 118.83,86.68 117.3,85.16 116.52,84.38 114.53,84.38 113.16,83.01 112.97,83.01 112.14,82.17 112.14,82.11 112.12,82.1
  IN2 w0.119: 112.12,82.1 109.98,79.95 109.98,79.11 100.24,69.38 100.24,52.12 104.2,48.16 104.2,40.67 106.45,38.41 106.45,35.64 107.54,34.56 109.7,34.56 110.55,33.71 110.55,32.01 110.72,31.83 111.18,31.83 111.92,31.09 111.92,30.36 111.49,29.93 111.14,29.93 110.96,29.74 110.96,29.64 v2(111.04,29.56)
  BOTTOM w0.076: UC1.AL43 130.05,85.12 129.83,84.9 v2(129.78,84.9)
  BOTTOM w0.114: v2(111.04,29.56) 111.17,29.56 111.22,29.62 111.39,29.62 111.48,29.53 111.48,29.25 111.66,29.07 111.66,27.97 111.22,27.53 JDIMM2.10
DDR_B_DQS#3: length 70.3
  IN2 w0.076: 120.1,71.05 120.1,71.06 120.01,71.15 120.01,71.9 124.64,76.53 124.64,78.36 124.88,78.6 124.88,81.81 125.5,82.42 125.5,82.97 125.51,82.97 125.51,83.02 126.45,83.97 126.45,84.62 126.6,84.76 126.76,84.76 v2(126.86,84.67)
  IN2 w0.119: 120.1,71.05 120.1,68.37 117.84,66.11 117.84,63.86 116.94,62.96 116.94,59.59 116.58,59.23 116.58,58.97 116.94,58.61 116.94,57.8 116.58,57.44 116.58,57.17 116.94,56.81 116.94,56.02 117.91,55.05 117.91,54.27 120.38,51.79 120.8,51.79 123.47,49.12 123.47,48.7 125.46,46.72 125.46,40.57 127.18,38.84 127.18,35.35 127.54,35 127.54,30 127.77,29.77 127.96,29.77 128.11,29.93 v2(128.11,30.07)
  BOTTOM w0.076: UC1.AL48 127.28,85.1 v2(126.86,84.67)
  BOTTOM w0.114: v2(128.11,30.07) 127.87,29.83 127.29,29.83 126.97,29.5 126.97,27.87 126.82,27.72 JDIMM2.62
DDR_B_DQS#4: length 66.7
  IN2 w0.076: v2(139.29,84.13) 139.29,84.37 139.24,84.42 139.08,84.42 138.61,83.95 138.3,83.95 138.03,83.69 138.03,82.63 138.24,82.42 138.24,80.44 138.82,79.86 138.82,71.41 140.6,69.63 141.36,69.63 141.57,69.42 141.57,68.57 141.61,68.53 141.61,68.51
  IN2 w0.119: v2(150.65,31.6) 150.65,31.37 150.55,31.27 150.32,31.27 150.21,31.39 150.21,33.61 150.8,34.21 151,34.4 151,39.12 150.7,39.42 150.7,49.84 151.1,50.24 151.1,55.95 150.61,56.44 141.61,65.44 141.61,68.51
  BOTTOM w0.076: UC1.AN28 139.73,84.08 139.65,84.16 139.32,84.16 v2(139.29,84.13)
  BOTTOM w0.114: v2(150.65,31.6) 150.65,31.32 150.72,31.25 150.96,31.25 151.08,31.37 151.08,33.01 151.47,33.4 151.47,33.5 151.39,33.58 151.19,33.58 151.12,33.65 JDIMM2.135
DDR_B_DQS#5: length 68.2
  IN2 w0.076: 146.26,68.69 146.25,68.7 146.19,68.7 145.94,68.94 145.66,68.94 142.73,71.87 142.65,71.87 142.26,71.87 142.02,72.12 142.02,77.98 141.38,78.62 141.38,80.95 140.87,81.45 140.87,83.69 140.97,83.79 141.17,83.79 141.26,83.7 v2(141.26,83.49)
  IN2 w0.119: 146.26,68.69 146.39,68.56 146.39,67.54 157.08,56.85 157.08,49.43 156.49,48.85 156.49,39.81 156.94,39.36 156.94,38.02 156.15,37.22 156.15,31.62 156.71,31.05 156.71,29.94 156.33,29.56 155.93,29.56 v2(155.68,29.3)
  BOTTOM w0.076: UC1.AN25 141.64,83.59 141.54,83.49 v2(141.26,83.49)
  BOTTOM w0.114: v2(155.68,29.3) 155.97,29.6 155.97,29.61 156.13,29.61 156.22,29.52 JDIMM2.152
DDR_B_DQS#6: length 69.5
  IN2 w0.076: v2(143.98,83.53) 143.98,83.71 143.83,83.86 143.7,83.86 143.59,83.75 143.59,81.72 143.67,81.64 143.67,80.64 144.96,79.35 144.96,78.54 145.59,77.92 145.59,73.32 147.08,71.82 149.24,71.82 151.04,70.03 151.04,69.67 151.08,69.63 151.08,69.52
  IN2 w0.119: 151.08,69.52 151.08,69.1 161.93,58.25 161.93,51.33 162.4,50.86 162.4,48.81 163.29,47.92 163.29,42.67 162.84,42.22 162.84,39.7 162.4,39.26 162.4,35.55 161.17,34.32 161.17,31.4 161.3,31.27 161.52,31.27 161.62,31.37 v2(161.62,31.6)
  BOTTOM w0.076: v2(143.98,83.53) 143.98,83.62 144.17,83.82 UC1.AN21
  BOTTOM w0.114: v2(161.62,31.6) 161.62,31.35 161.75,31.23 162.06,31.23 162.26,31.43 162.26,32.43 161.67,33.02 161.67,33.53 161.62,33.58 161.4,33.58 161.32,33.66 JDIMM2.169
DDR_B_DQS#7: length 71.7
  IN2 w0.076: 157.21,69.52 157.21,69.59 156.99,69.8 156.99,70.12 152.63,74.48 150.07,74.48 148.46,76.09 148.46,78.62 147.94,79.14 147.82,79.14 146.22,80.74 146.22,83.5 146.08,83.65 145.93,83.65 145.85,83.57 v2(145.85,83.43)
  IN2 w0.119: 157.21,69.52 168.34,58.39 168.34,52.31 167.52,51.49 167.52,43.59 168.18,42.93 168.18,38.05 167.5,37.37 167.5,36.22 167.38,36.11 167.38,29.97 167.26,29.85 167.06,29.85 166.93,29.98 v2(166.93,30.18)
  BOTTOM w0.076: UC1.AN18 146.25,83.82 v2(145.85,83.43)
  BOTTOM w0.114: JDIMM2.186 166.42,27.49 166.64,27.7 166.64,27.84 166.06,28.42 166.06,29.51 166.42,29.87 166.78,29.87 166.93,30.02 v2(166.93,30.18)
DDR_B_MA0: length 61.5
  IN2 w0.076: v2(131.59,83.46) 131.91,83.15 131.91,81.95 131.78,81.82 131.78,71.12
  IN2 w0.163: v2(139.67,27.91) 140.14,28.38 140.14,35.67 139.38,36.43 139.38,39.44 138.18,40.64 138.18,50.77 134.16,54.79 134.16,56.13 131.77,58.52 131.77,71.11 131.78,71.12
  BOTTOM w0.076: UC1.AP40 131.89,83.17 v2(131.59,83.46)
  BOTTOM w0.157: JDIMM2.98 140.02,27.57 v2(139.67,27.91)
DDR_B_MA1: length 62.2
  IN2 w0.076: v2(131.56,82.84) 131.34,82.84 131.11,82.61 131.11,81.79 130.49,81.17 130.49,71.56 130.87,71.17 130.87,71.05
  IN2 w0.163: v2(139.67,31.72) 139.35,31.72 139.15,31.93 139.15,35.23 138.51,35.87 138.51,39.13 137.29,40.35 137.29,50.48 130.87,56.9 130.87,67.23 130.71,67.39 130.55,67.39 130.38,67.55 130.38,67.88 130.55,68.04 130.71,68.04 130.87,68.2 130.87,68.53 130.71,68.69 130.38,68.69 130.22,68.85 130.22,69.18 130.38,69.34 130.71,69.34 130.87,69.5 130.87,69.83 130.71,69.99 130.38,69.99 130.22,70.15 130.22,70.48 130.38,70.64 130.71,70.64 130.87,70.8 130.87,71.05
  BOTTOM w0.076: UC1.AR40 131.88,82.52 v2(131.56,82.84)
  BOTTOM w0.157: JDIMM2.97 139.72,33.81 139.85,33.69 139.86,33.69 140.11,33.43 140.11,33.42 140.19,33.34 140.19,32.24 v2(139.67,31.72)
DDR_B_MA2: length 63.8
  IN2 w0.076: 129.8,71.05 129.8,75.44 130.26,75.9 130.26,81.52 130.35,81.61 130.35,82.47 v2(130.78,82.9)
  IN2 w0.163: 129.8,71.05 129.8,65.59 129.96,65.42 130.29,65.42 130.46,65.26 130.46,64.94 130.29,64.77 129.96,64.77 129.8,64.61 129.8,64.29 129.96,64.12 130.29,64.12 130.46,63.96 130.46,63.64 130.29,63.47 129.96,63.47 129.8,63.31 129.8,62.99 129.96,62.82 130.29,62.82 130.46,62.66 130.46,56.73 136.86,50.33 136.86,40.19 138.08,38.97 138.08,35.56 138.72,34.93 138.72,30.4 v2(139.67,29.44)
  BOTTOM w0.076: UC1.AP42 131.05,83.17 v2(130.78,82.9)
  BOTTOM w0.157: JDIMM2.96 139.42,27.33 139.06,27.69 139.06,28.83 v2(139.67,29.44)
DDR_B_MA3: length 62.7
  IN2 w0.076: 131.35,71.76 131.35,72.63 131.27,72.7 130.73,72.7 130.65,72.78 130.65,72.93 130.73,73.01 131.27,73.01 131.35,73.08 131.35,73.24 131.27,73.31 130.73,73.31 130.65,73.39 130.65,73.54 130.73,73.62 131.27,73.62 131.35,73.69 131.35,73.85 131.27,73.92 130.73,73.92 130.65,74 130.65,74.15 130.73,74.23 131.27,74.23 131.35,74.3 131.35,74.46 131.27,74.53 130.73,74.53 130.65,74.61 130.65,74.76 130.73,74.84 131.27,74.84 131.35,74.91 131.35,81.99 v2(131.52,82.16)
  IN2 w0.163: v2(139.67,33.25) 139.67,35.44 138.94,36.17 138.94,39.29 137.72,40.5 137.72,50.64 133.1,55.26 133.1,55.49 133.52,55.91 133.52,56.18 133.33,56.37 133.06,56.37 132.66,55.97 132.39,55.97 132.2,56.16 132.2,56.43 132.6,56.83 132.6,57.1 132.41,57.29 132.14,57.29 131.72,56.87 131.49,56.87 131.29,57.08 131.29,71.7 131.35,71.76
  BOTTOM w0.076: UC1.AR42 131.2,82.48 v2(131.52,82.16)
  BOTTOM w0.157: v2(139.67,33.25) 139.32,33.25 139.12,33.45 JDIMM2.95
DDR_B_MA4: length 68.8
  IN2 w0.076: 129.22,71.05 129.22,75.24 130.03,76.05 130.03,81.75 130.18,81.9 130.18,82.3 v2(129.68,82.8)
  IN2 w0.163: 129.22,71.05 129.22,62.25 129.38,62.09 129.88,62.09 130.04,61.93 130.04,61.49 129.88,61.33 129.35,61.33 129.19,61.17 129.19,60.84 129.35,60.68 129.88,60.68 130.04,60.52 130.04,60.19 129.88,60.03 129.35,60.03 129.19,59.87 129.19,59.54 129.35,59.38 129.88,59.38 130.04,59.22 130.04,58.89 129.88,58.73 129.35,58.73 129.19,58.57 129.19,58.24 129.35,58.08 129.88,58.08 130.04,57.92 130.04,56.56 135.95,50.65 135.95,50.36 135.78,50.2 135.53,50.2 135.36,50.04 135.36,49.71 135.53,49.55 136.25,49.55 136.44,49.36 136.44,49.09 136.25,48.9 135.53,48.9 135.36,48.74 135.36,48.41 135.53,48.25 135.78,48.25 135.95,48.09 135.95,40.51 137.62,38.84 137.62,35.34 138.3,34.66 138.3,31.11 v2(137.39,30.2)
  BOTTOM w0.076: UC1.AR45 129.39,82.52 v2(129.68,82.8)
  BOTTOM w0.157: v2(137.39,30.2) 138.35,29.24 138.35,27.55 138.22,27.42 JDIMM2.92
DDR_B_MA5: length 67.8
  IN2 w0.076: v2(128.81,83.02) 129.37,82.45 129.37,81.88 129.79,81.45 129.79,76.1 128.68,74.99 128.68,71.05
  IN2 w0.163: v2(137.39,31.72) 137.87,32.2 137.87,34.08 137.21,34.74 137.21,35.13 137.04,35.29 136.61,35.29 136.46,35.44 136.46,35.79 136.61,35.94 137.04,35.94 137.21,36.1 137.21,36.88 137.04,37.04 136.64,37.04 136.49,37.19 136.49,37.54 136.64,37.69 137.04,37.69 137.21,37.85 137.21,38.66 135.52,40.36 135.52,47.6 134.95,48.17 134.95,48.5 134.78,48.66 134.64,48.66 134.47,48.82 134.47,49.15 134.64,49.31 134.78,49.31 134.95,49.47 134.95,49.8 134.78,49.96 134.29,49.96 134.13,50.11 134.13,50.46 134.29,50.61 134.78,50.61 134.95,50.77 134.95,51.06 128.77,57.23 128.77,62.45 128.61,62.61 127.77,62.61 127.61,62.78 127.61,63.1 127.77,63.26 128.61,63.26 128.77,63.43 128.77,63.75 128.61,63.91 127.77,63.91 127.61,64.08 127.61,64.4 127.77,64.56 128.61,64.56 128.77,64.73 128.77,70.96 128.68,71.05
  BOTTOM w0.076: UC1.AP45 128.96,83.17 v2(128.81,83.02)
  BOTTOM w0.157: JDIMM2.91 137.92,32.26 v2(137.39,31.72)
DDR_B_MA6: length 71.5
  IN2 w0.076: v2(127.83,79.8) 127.48,79.45 127.48,78.98 127.67,78.79 128.38,78.79 128.74,78.43 128.74,75.88 127.64,74.78 127.64,71.05
  IN2 w0.163: 127.64,71.05 127.64,70.06 127.48,69.9 127.23,69.9 127.06,69.73 127.06,69.41 127.23,69.25 127.48,69.25 127.64,69.08 127.64,68.76 127.48,68.6 127.23,68.6 127.06,68.43 127.06,68.11 127.23,67.95 127.48,67.95 127.64,67.78 127.64,67.41 127.15,66.92 127.15,65.48 126.71,65.04 126.71,61.62 126.87,61.46 127.76,61.46 127.92,61.3 127.92,60.97 127.76,60.81 126.87,60.81 126.71,60.65 126.71,60.32 126.87,60.16 127.76,60.16 127.92,60 127.92,59.67 127.76,59.51 126.87,59.51 126.71,59.35 126.71,59.02 126.87,58.86 127.76,58.86 127.92,58.7 127.92,58.37 127.76,58.21 126.93,58.21 126.74,58.02 126.74,57.75 126.93,57.56 127.73,57.56 127.92,57.37 127.92,57.1 127.73,56.91 126.84,56.91 126.71,56.78 126.71,55.74 129.87,52.58 132.06,52.58 132.8,51.84 132.8,48.87 134.6,47.08 134.6,40.1 135.64,39.05 135.64,37.19 135.36,36.91 135.36,35.34 136.91,33.79 136.91,29.15 v2(137.39,28.68)
  BOTTOM w0.076: UC1.AW46 128.1,80.06 127.84,79.8 v2(127.83,79.8)
  BOTTOM w0.157: JDIMM2.90 137.62,27.45 137.85,27.68 137.85,28.21 v2(137.39,28.68)
DDR_B_MA7: length 71.3
  IN2 w0.076: v2(127.84,78.43) 128.38,78.43 128.58,78.23 128.58,76.02 127.22,74.67 127.22,73.97 127.15,73.89 126.61,73.89 126.53,73.82 126.53,73.66 126.61,73.59 127.15,73.59 127.22,73.51 127.22,73.36 127.15,73.28 126.61,73.28 126.53,73.21 126.53,73.05 126.61,72.98 127.15,72.98 127.22,72.9 127.22,72.75 127.15,72.67 126.61,72.67 126.53,72.6 126.53,72.44 126.61,72.37 127.15,72.37 127.22,72.29 127.22,72.14 127.15,72.06 126.61,72.06 126.53,71.99 126.53,71.84 126.65,71.72 126.65,71.05
  IN2 w0.163: 126.65,71.05 126.65,67.6 126.73,67.51 126.73,65.67 126.29,65.23 126.29,63.5 126.13,63.34 125.81,63.34 125.65,63.18 125.65,62.85 125.81,62.69 126.13,62.69 126.29,62.53 126.29,62.2 126.13,62.04 125.81,62.04 125.65,61.87 125.65,61.55 125.81,61.39 126.13,61.39 126.29,61.22 126.29,60.9 126.13,60.74 125.81,60.74 125.65,60.57 125.65,60.25 125.81,60.09 126.13,60.09 126.29,59.92 126.29,55.57 129.7,52.16 131.89,52.16 132.28,51.76 132.28,48.8 134.18,46.9 134.18,39.92 134.73,39.38 134.73,37.65 134.45,37.37 133.99,37.37 133.81,37.19 133.81,36.25 136.45,33.61 136.45,30.48 136.17,30.2 v2(135.53,30.2)
  BOTTOM w0.076: UC1.AY46 128.4,79.41 128.51,79.3 128.51,77.68 128.42,77.6 128.29,77.6 128.2,77.68 128.2,78.31 128.08,78.43 v2(127.84,78.43)
  BOTTOM w0.157: JDIMM2.86 136.42,27.49 136.47,27.54 136.47,29.26 v2(135.53,30.2)
DDR_B_MA8: length 69.5
  IN2 w0.076: 128.06,71.05 128.07,71.06 128.07,71.55 128.15,71.63 128.43,71.63 128.52,71.71 128.52,71.84 128.43,71.93 128.15,71.93 128.07,72.01 128.07,72.25 128.15,72.33 128.43,72.33 128.5,72.4 128.5,72.55 128.43,72.63 128.15,72.63 128.07,72.71 128.07,72.86 128.15,72.94 128.43,72.94 128.5,73.01 128.5,73.16 128.43,73.24 128.15,73.24 128.07,73.32 128.07,73.47 128.15,73.55 128.43,73.55 128.5,73.62 128.5,73.77 128.43,73.85 128.15,73.85 128.07,73.93 128.07,74.08 128.15,74.16 128.43,74.16 128.5,74.23 128.5,74.38 128.43,74.46 128.15,74.46 128.07,74.54 128.07,74.63 129.35,75.9 129.35,77.41 129.04,77.72 129.04,78.41 128.64,78.81 128.64,78.92 129.05,79.33 129.05,79.44 128.95,79.55 128.84,79.55 128.42,79.14 127.86,79.14 v2(127.85,79.15)
  IN2 w0.163: 128.06,71.05 128.06,70.8 128.27,70.59 128.27,70.19 128.06,69.98 128.06,69.5 128.23,69.33 128.23,68.85 128.06,68.68 128.06,68.39 128.27,68.19 128.27,67.74 128.06,67.54 128.06,67.24 127.56,66.75 127.56,65.28 127.19,64.91 127.19,62.47 127.51,62.15 128.12,62.15 128.34,61.94 128.34,56.86 127.5,56.03 127.5,55.8 127.73,55.57 127.96,55.57 128.5,56.1 128.73,56.1 128.96,55.87 128.96,55.64 128.37,55.06 128.37,54.83 128.6,54.6 128.83,54.6 129.55,55.32 129.78,55.32 130.01,55.09 130.01,54.86 129.21,54.06 129.21,53.83 129.44,53.6 129.67,53.6 130.63,54.56 130.86,54.56 131.09,54.33 131.09,54.1 130.44,53.46 130.44,53.23 130.67,53 130.9,53 131.25,53.35 131.88,53.35 133.72,51.51 133.72,48.66 135.08,47.3 135.08,40.2 136.07,39.21 136.07,36.96 135.85,36.73 135.85,35.46 137.39,33.92 v2(137.39,33.25)
  BOTTOM w0.076: v2(127.85,79.15) 127.86,79.15 127.86,79.16 127.84,79.16 127.84,79.14 127.57,79.41 UC1.AY47
  BOTTOM w0.157: v2(137.39,33.25) 137.39,33.21 137.26,33.08 136.98,33.08 136.86,33.21 136.86,33.42 137.32,33.89 JDIMM2.89
DDR_B_MA9: length 72.8
  IN2 w0.076: 126.2,71.05 126.2,73.97 128.34,76.11 128.34,77.32 128.22,77.45 127.38,77.45 127.26,77.57 127.26,79.89 127.45,80.08 127.45,80.36 127.26,80.55 127.26,80.86 127.49,81.09 v2(127.8,81.09)
  IN2 w0.163: 126.2,71.05 126.2,67.49 125.77,67.06 125.77,63.87 125.61,63.71 125.3,63.71 125.13,63.53 125.13,59.64 125.29,59.48 125.72,59.48 125.88,59.32 125.88,58.99 125.72,58.83 125.29,58.83 125.13,58.67 125.13,58.34 125.29,58.18 125.72,58.18 125.88,58.02 125.88,57.69 125.72,57.53 124.35,57.53 124.19,57.37 124.19,57.04 124.35,56.88 125.72,56.88 125.88,56.72 125.88,56.39 125.53,56.05 125.53,55.63 130.21,50.96 130.61,50.96 130.8,51.14 130.8,51.49 131.02,51.72 131.5,51.72 131.71,51.52 131.71,48.79 133.15,47.34 133.15,40.44 133.32,40.27 133.57,40.27 133.74,40.11 133.74,39.79 133.57,39.62 133.32,39.62 133.15,39.46 133.15,39.09 133.37,38.88 134.15,38.88 134.31,38.72 134.31,38.39 134.15,38.23 133.69,38.23 133.57,38.12 133.57,37.67 133.26,37.36 133.26,36.21 133.55,35.93 133.55,35.7 133.5,35.64 133.5,35.41 133.73,35.18 133.96,35.18 134.01,35.24 134.24,35.24 134.47,35.01 134.47,34.78 134.42,34.72 134.42,34.49 134.65,34.26 134.88,34.26 134.93,34.32 135.16,34.32 136.02,33.45 136.02,31.86 135.89,31.72 v2(135.53,31.72)
  BOTTOM w0.076: v2(127.8,81.09) 128.03,81.09 UC1.AU46
  BOTTOM w0.157: JDIMM2.85 136.12,33.14 136.78,32.48 136.78,31.48 136.62,31.32 136.29,31.32 135.89,31.72 v2(135.53,31.72)
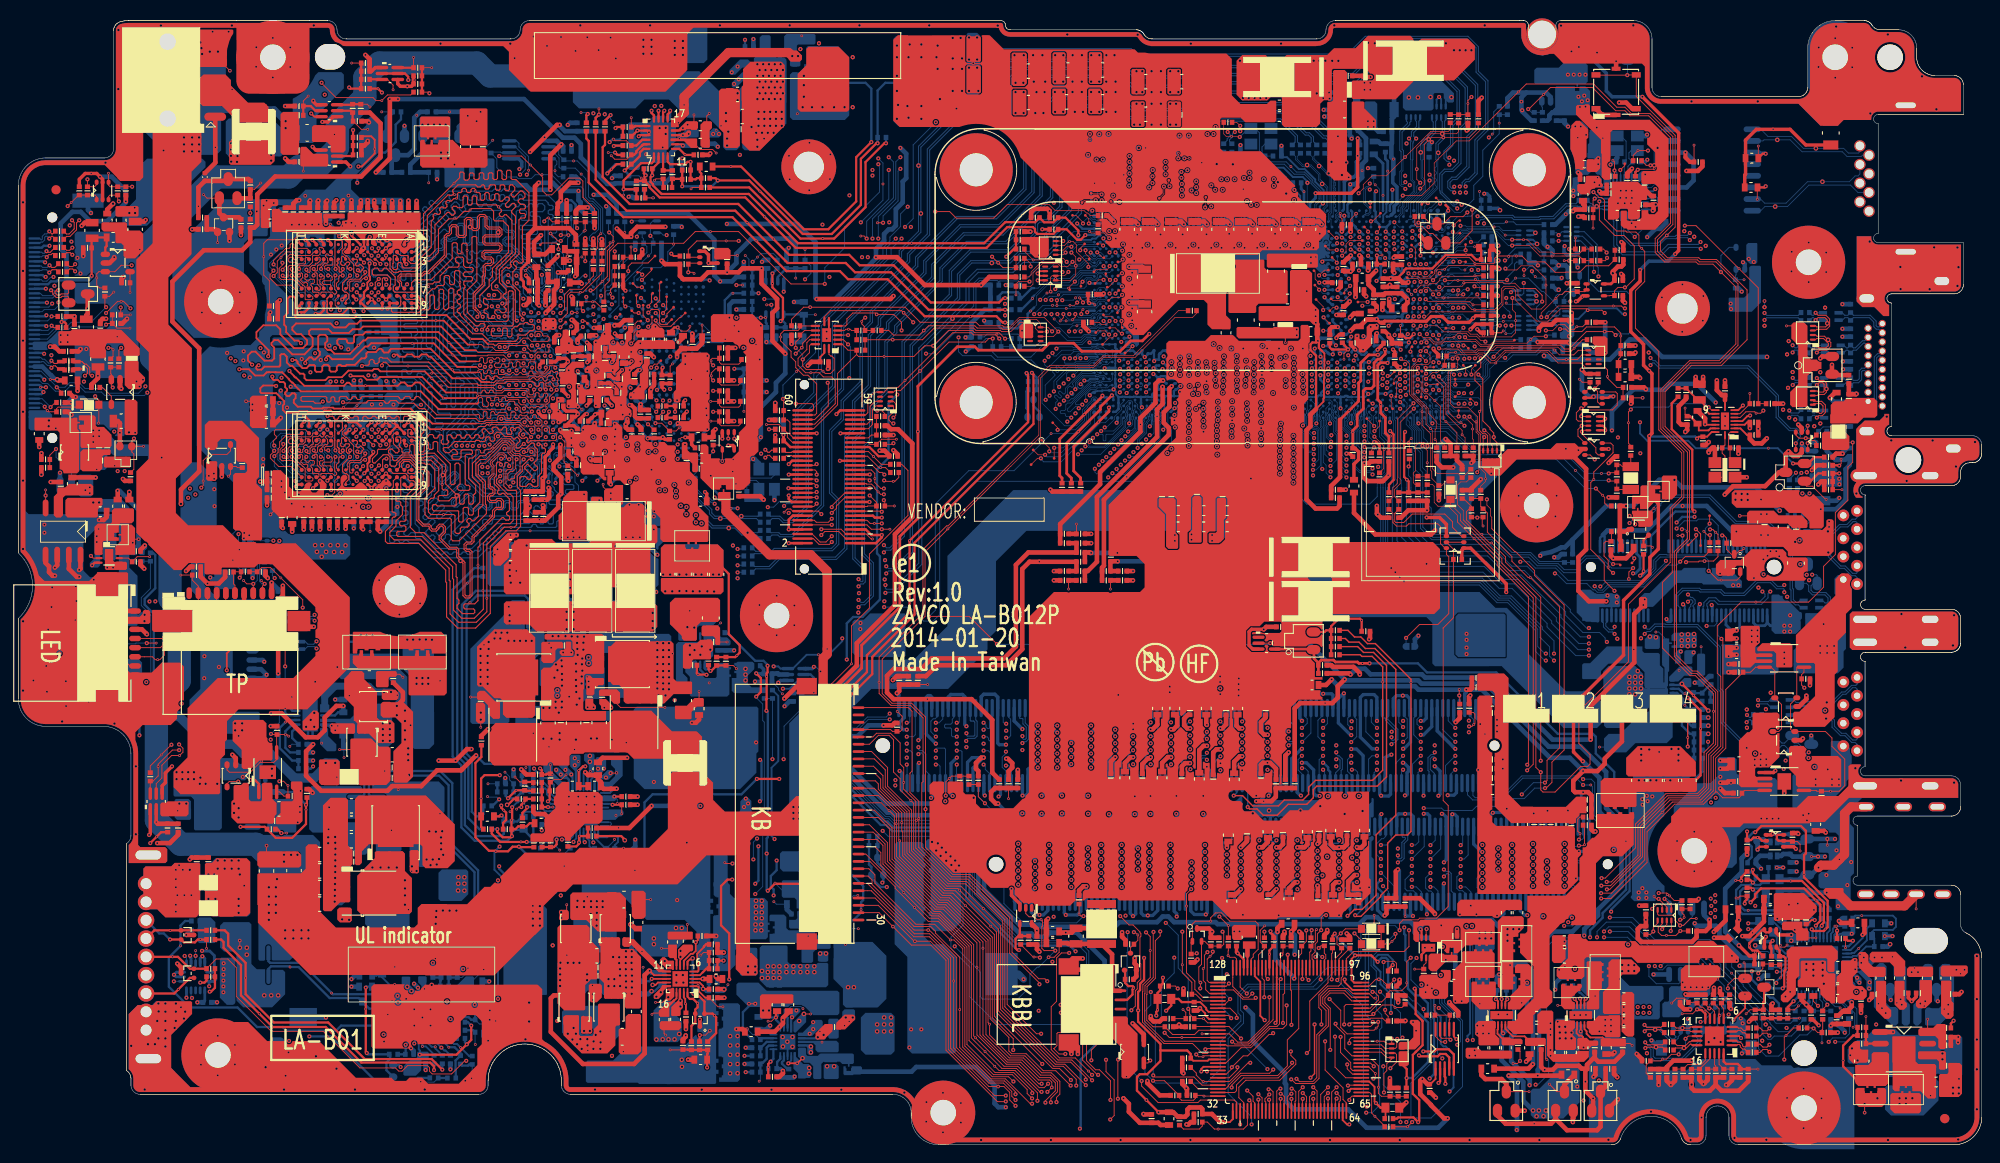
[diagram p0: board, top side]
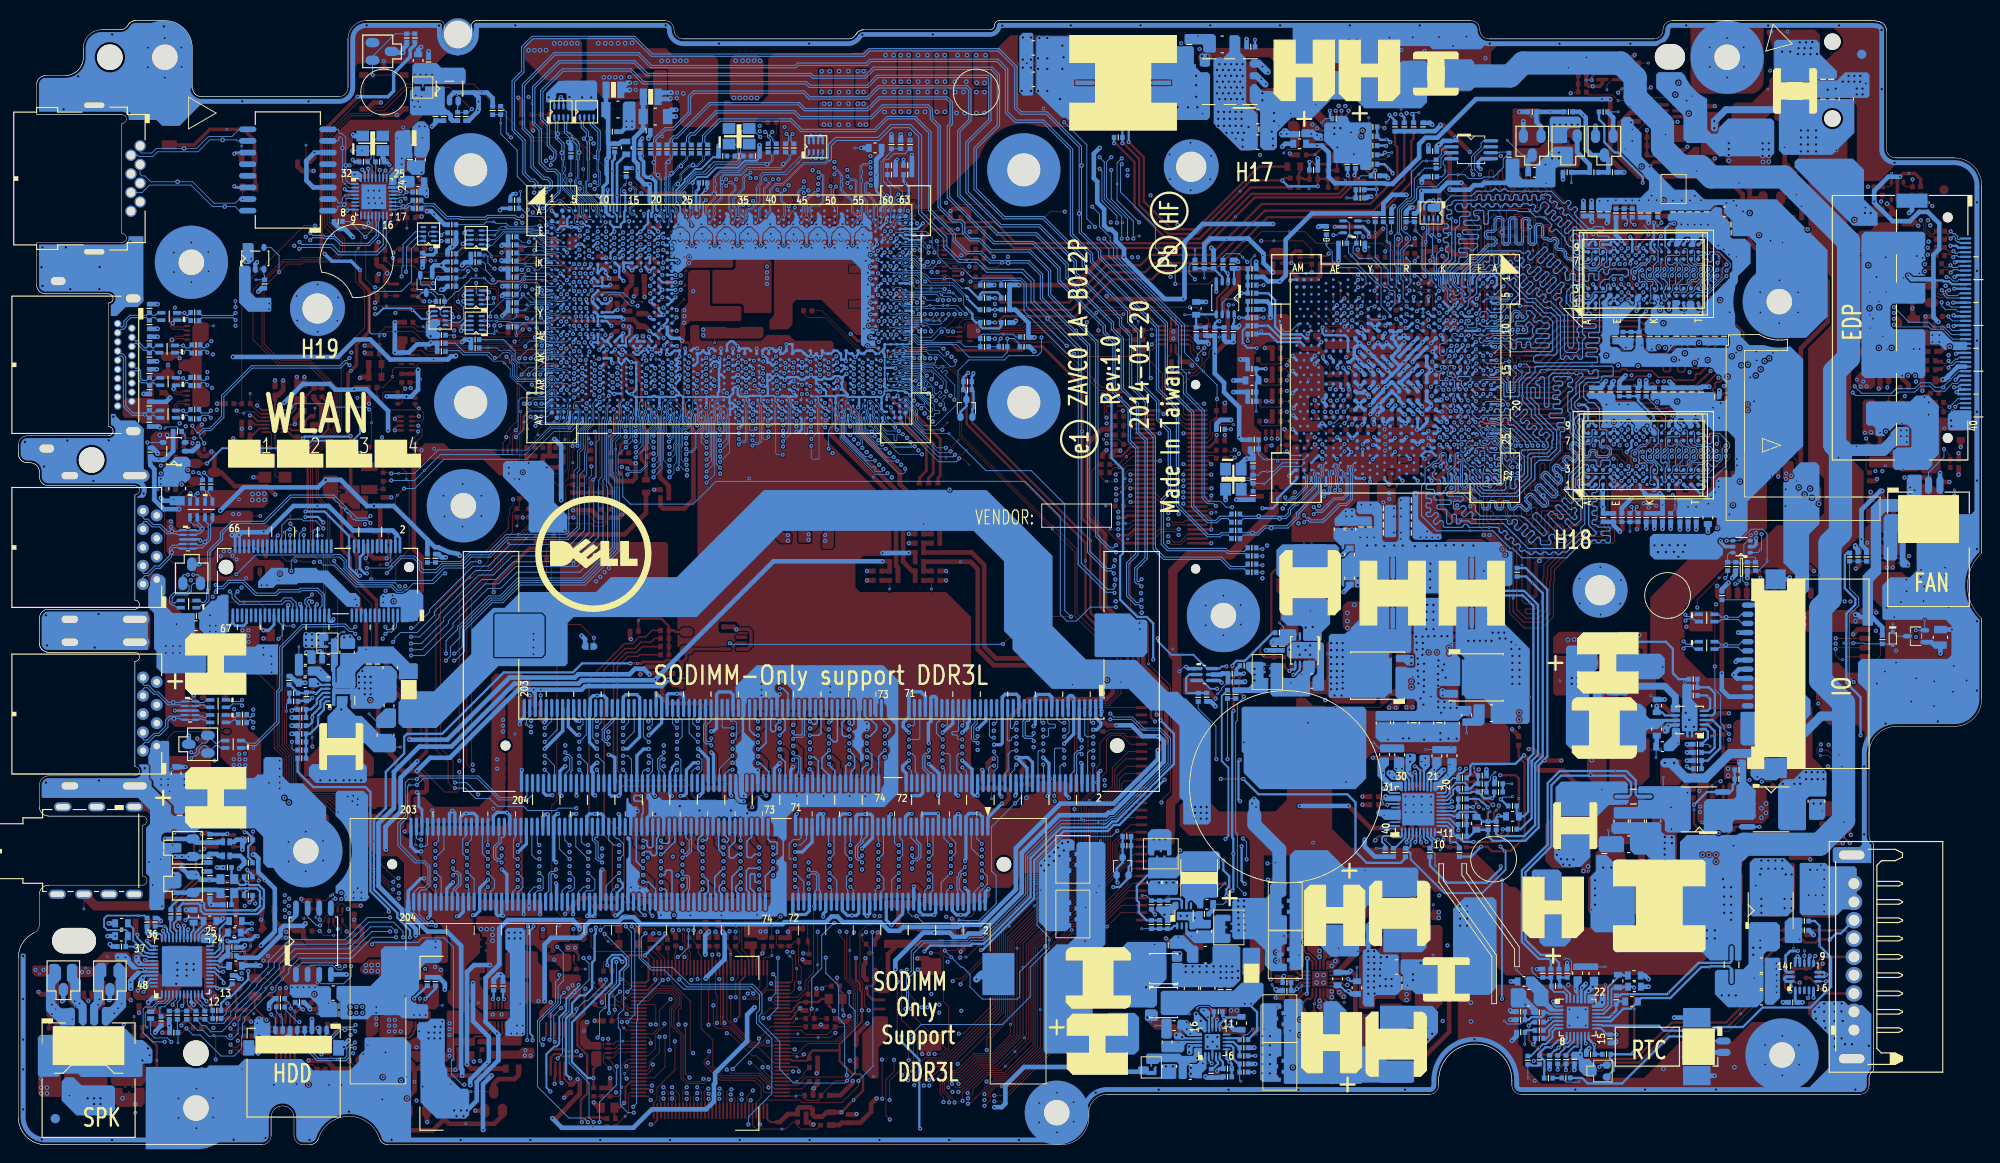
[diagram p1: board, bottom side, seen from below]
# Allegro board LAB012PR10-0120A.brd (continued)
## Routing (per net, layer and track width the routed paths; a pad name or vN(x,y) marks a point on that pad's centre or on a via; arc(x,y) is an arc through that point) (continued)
DDR_B_MA10: length 75.8
  IN2 w0.076: 134.5,69.65 134.09,70.06 134.09,75.22 134.42,75.55 134.42,75.67 134.33,75.76 134.2,75.76 133.75,75.31 133.64,75.31 133.52,75.43 133.52,81.8 133.46,81.87 133.46,86.11 133.61,86.26 133.94,86.26 134.07,86.14 v2(134.07,85.65)
  IN2 w0.163: 134.5,69.65 134.5,59.97 134.78,59.69 135.01,59.69 135.48,60.15 135.71,60.15 135.94,59.92 135.94,59.69 135.47,59.23 135.47,59 135.7,58.77 135.93,58.77 136.4,59.23 136.63,59.23 136.86,59 136.86,58.77 136.39,58.31 136.39,58.08 136.62,57.85 136.85,57.85 137.32,58.31 137.55,58.31 137.78,58.08 137.78,57.85 137.31,57.39 137.31,57.16 137.54,56.93 137.77,56.93 138.24,57.39 138.47,57.39 138.7,57.16 138.7,56.93 138.23,56.47 138.23,56.24 138.46,56.01 138.69,56.01 139.16,56.47 139.39,56.47 139.62,56.24 139.62,56.01 139.15,55.55 139.15,55.32 139.38,55.09 139.61,55.09 140.08,55.55 140.31,55.55 140.54,55.32 140.54,55.09 140.07,54.63 140.07,54.4 142.02,52.46 142.02,47.36 141.59,46.93 141.59,40.65 142.55,39.68 142.55,37.6 142.77,37.38 142.77,34.36 143.21,33.91 143.21,32.29 143.78,31.72 v2(144.23,31.72)
  BOTTOM w0.076: v2(134.07,85.65) 134.18,85.77 UC1.AK36
  BOTTOM w0.157: v2(144.23,31.72) 144.08,31.72 142.72,33.08 JDIMM2.107
DDR_B_MA11: length 71.5
  IN2 w0.076: 125.36,71.05 125.36,73.59 127.22,75.45 127.22,77.16 127.35,77.28 127.68,77.28 127.8,77.16 v2(127.8,77.09)
  IN2 w0.163: v2(135.53,28.68) 136.56,28.68 136.71,28.52 136.71,27.26 136.56,27.11 134.96,27.11 134.8,27.26 134.8,29.34 134.65,29.49 134.07,29.49 133.91,29.65 133.91,29.99 134.07,30.14 134.64,30.14 135.09,30.6 135.09,32.53 132.43,35.19 132.43,37.78 132.26,37.95 132.26,46.61 130.31,48.57 130.31,49.52 126.85,52.99 126.25,52.99 123.35,55.89 123.35,59.85 123.41,59.91 123.41,63.14 124.94,64.67 124.94,67.4 125.36,67.82 125.36,68.45 125.2,68.62 124.96,68.62 124.79,68.78 124.79,69.1 124.96,69.27 125.2,69.27 125.36,69.43 125.36,69.75 125.2,69.92 124.96,69.92 124.79,70.08 124.79,70.4 124.96,70.57 125.2,70.57 125.36,70.73 125.36,71.05
  BOTTOM w0.076: UC1.AV47 127.12,80.42 127.12,77.79 127.8,77.12 v2(127.8,77.09)
  BOTTOM w0.157: JDIMM2.84 135.82,27.48 136.05,27.71 136.05,28.15 v2(135.53,28.68)
DDR_B_MA12: length 68.7
  IN2 w0.076: 125.78,71.05 125.78,73.78 127.8,75.8 127.8,76.32 v2(127.82,76.34)
  IN2 w0.163: v2(135.53,33.25) 135.04,33.25 132.85,35.44 132.85,37.62 133.16,37.93 133.16,38.43 132.72,38.87 132.72,46.74 132.52,46.95 132.52,47.39 132.27,47.63 131.84,47.63 130.81,48.65 130.81,48.83 130.73,48.91 130.73,50.54 130.72,50.54 130.03,50.54 126.8,53.77 126.57,53.77 126.44,53.64 126.21,53.64 125.98,53.87 125.98,54.1 126.11,54.23 126.11,54.46 125.88,54.69 125.65,54.69 125.52,54.56 125.29,54.56 124.67,55.18 124.67,55.41 124.87,55.61 124.87,55.84 124.64,56.07 124.41,56.07 124.21,55.87 123.98,55.87 123.77,56.07 123.77,57.49 123.77,57.5 123.77,57.95 123.96,58.14 124.55,58.14 124.71,58.3 124.71,58.62 124.55,58.79 123.96,58.79 123.77,58.98 123.77,59.25 123.96,59.44 124.55,59.44 124.71,59.6 124.71,59.92 124.55,60.09 123.99,60.09 123.83,60.25 123.83,60.57 123.99,60.74 124.55,60.74 124.71,60.9 124.71,61.22 124.55,61.39 123.99,61.39 123.83,61.55 123.83,61.88 123.99,62.04 124.55,62.04 124.71,62.2 124.71,62.53 124.55,62.69 124.2,62.69 124.03,62.85 124.03,63.18 124.2,63.34 124.55,63.34 124.71,63.5 124.71,63.7 125.36,64.35 125.36,67.23 125.78,67.65 125.78,71.05
  BOTTOM w0.076: v2(127.82,76.34) 127.82,75.02 127.69,74.89 127.09,74.89 126.96,75.02 126.96,80.66 127.37,81.07 UC1.AU47
  BOTTOM w0.157: v2(135.53,33.25) 135.52,33.25 JDIMM2.83
DDR_B_MA13: length 77.1
  IN2 w0.076: v2(135.75,86.18) 135.06,86.87 135.06,87.86 135.21,88.02 137.06,88.02 137.17,87.9 137.17,87.75 137.06,87.63 135.52,87.63 135.37,87.48 135.37,87.23 136.17,86.44 136.17,85.61 136.17,85.31 136.17,85.31 136.17,84.89 136.17,82.39 136.09,82.32 135.73,82.32 135.65,82.24 135.65,82.09 135.73,82.01 136.09,82.01 136.17,81.94 136.17,81.53 136.41,81.29 136.41,80.81 136.48,80.74 136.63,80.74 136.71,80.66 136.71,80.51 136.63,80.43 136.48,80.43 136.41,80.36 136.41,80.2 136.48,80.13 136.63,80.13 136.71,80.05 136.71,79.9 136.63,79.82 136.48,79.82 136.41,79.75 136.41,79.59 136.48,79.52 136.63,79.52 136.71,79.44 136.71,79.29 136.63,79.21 136.48,79.21 136.41,79.14 136.41,78.98 136.48,78.91 136.63,78.91 136.71,78.83 136.71,78.68 136.63,78.6 136.48,78.6 136.41,78.53 136.41,78.38 136.48,78.3 136.63,78.3 136.71,78.22 136.71,78.07 136.63,77.99 136.48,77.99 136.41,77.92 136.41,77.77 136.48,77.69 136.63,77.69 136.71,77.61 136.71,77.46 136.63,77.38 136.48,77.38 136.41,77.31 136.41,77.16 136.48,77.08 136.63,77.08 136.71,77 136.71,76.85 136.63,76.78 136.48,76.78 136.41,76.7 136.41,76.23 136.71,75.93 136.71,71.92 136.63,71.85 136.33,71.85 136.25,71.77 136.25,71.62 136.33,71.54 136.63,71.54 136.71,71.47 136.71,71.31 136.63,71.24 136.33,71.24 136.25,71.16 136.25,71.01 136.33,70.93 136.63,70.93 136.71,70.86 136.71,70.57 137.09,70.19
  IN2 w0.163: 137.09,70.19 137.09,68.67 137.26,68.5 137.54,68.5 137.69,68.35 137.69,68 137.54,67.85 137.26,67.85 137.09,67.68 137.09,67.3 137.25,67.13 137.54,67.13 137.69,66.98 137.69,66.64 137.54,66.48 137.25,66.48 137.09,66.32 137.09,66 137.25,65.83 137.54,65.83 137.69,65.68 137.69,65.34 137.54,65.18 137.25,65.18 137.09,65.02 137.09,64.7 137.25,64.53 137.53,64.53 137.69,64.37 137.69,64.07 146.27,55.49 146.27,52.19 146.92,51.54 146.92,49.4 146.78,49.26 146.45,49.26 146.29,49.09 146.29,48.77 146.45,48.61 146.73,48.61 146.89,48.45 146.89,48.05 146.73,47.9 145.54,47.9 145.38,47.73 145.38,47.41 145.54,47.25 145.93,47.25 146.08,47.09 146.08,40.22 146.39,39.91 v2(146.39,38.1)
  BOTTOM w0.076: v2(135.75,86.18) 135.75,86 135.98,85.77 UC1.AK33
  BOTTOM w0.157: JDIMM2.119 146.32,36.06 146.18,36.2 146.18,37.37 146.34,37.53 147.01,37.53 147.17,37.69 147.17,38 147.01,38.16 146.44,38.16 v2(146.39,38.1)
DDR_B_MA14: length 73.6
  IN2 w0.076: v2(128.27,82) 128.27,82.37 128.47,82.56 129.03,82.56 129.21,82.39 129.21,81.73 128.89,81.41 128.89,81.02 128.76,80.9 128.32,80.9 128.19,81.02 128.19,81.42 128.06,81.55 127.73,81.55 127.42,81.24 126.61,81.24 126.47,81.39 126.17,81.39 125.9,81.12 125.9,80.17 125.98,80.09 126.73,80.09 126.85,79.97 126.85,75.59 123.91,72.65 123.91,71.81 123.98,71.74 124.5,71.74 124.57,71.66 124.57,71.51 124.5,71.43 123.98,71.43 123.91,71.36 123.91,71.1 123.96,71.05
  IN2 w0.163: 123.96,71.05 123.96,65.5 123.74,65.29 123.51,65.29 123.41,65.39 123.18,65.39 122.95,65.16 122.95,64.93 123.05,64.83 123.05,64.6 122.58,64.12 122.58,61.03 121.82,60.27 121.82,56.23 125.9,52.16 126.5,52.16 129.48,49.18 129.48,48.22 130.82,46.88 130.82,40.74 131.42,40.14 131.42,37.6 131.43,37.59 131.43,37.57 131.6,37.4 131.6,33.64 131.87,33.36 132.28,33.36 133.03,32.62 133.03,30.36 133.19,30.2 v2(133.5,30.2)
  BOTTOM w0.076: UC1.AR46 128.27,82.46 v2(128.27,82)
  BOTTOM w0.157: JDIMM2.80 134.62,27.58 134.9,27.85 134.9,29.94 134.64,30.2 v2(133.5,30.2)
DDR_B_MA15: length 74.5
  IN2 w0.076: v2(127.9,82.88) 127.9,82.88 127.68,82.67 127.68,81.82 127.27,81.41 126.68,81.41 126.53,81.55 126.1,81.55 125.74,81.19 125.74,79 125.96,78.77 126.53,78.77 126.67,78.63 126.67,75.64 123.54,72.52 123.54,71.05
  IN2 w0.163: v2(133.5,28.68) 131.93,27.11 131.59,27.11 131.23,27.47 131.23,27.81 132.55,29.14 132.55,32.5 132.11,32.95 131.7,32.95 131.18,33.47 131.18,37.15 130.99,37.34 130.99,39.97 130.4,40.56 130.4,46.71 129.06,48.05 129.06,49.01 126.33,51.74 125.73,51.74 121.34,56.13 121.34,60.6 122.16,61.42 122.16,64.96 123.54,66.34 123.54,71.05
  BOTTOM w0.076: v2(127.9,82.88) 128.19,83.17 UC1.AP46
  BOTTOM w0.157: v2(133.5,28.68) 133.86,28.68 133.97,28.78 133.97,29.51 134.06,29.6 134.35,29.6 134.48,29.47 134.48,28.03 134.02,27.57 JDIMM2.78
DDR_B_RAS#: length 76.4
  IN2 w0.076: v2(134.92,84.16) 134.66,84.16 134.55,84.04 134.55,82.53 134.3,82.27 134.3,82.1 135.08,81.31 135.08,76.23 135.41,75.9 135.41,75.55 135.57,75.4 135.57,71.35 135.41,71.2 135.26,71.2 135.26,70.54 135.84,69.96
  IN2 w0.163: 135.84,69.96 135.84,64.16 138.79,61.2 138.79,60.56 138.12,59.89 138.12,59.62 142.25,55.49 144.26,55.49 144.98,54.78 144.98,52.57 144.76,52.35 144.35,52.35 143.94,51.94 143.94,50 144.16,49.78 144.16,48.6 143.39,47.83 143.39,41.03 144.34,40.08 144.34,35.98 145.19,35.12 145.19,27.26 145.04,27.11 143.07,27.11 142.92,27.26 142.92,29.85 143.07,30 143.42,30 143.57,29.85 143.57,28.11 143.76,27.91 v2(144.23,27.91)
  BOTTOM w0.076: v2(134.92,84.16) 135.23,84.47 UC1.AM35
  BOTTOM w0.157: v2(144.23,27.91) 143.8,27.91 143.62,27.74 JDIMM2.110
DDR_B_WE#: length 76.1
  IN2 w0.076: 136.25,70.08 135.74,70.59 135.74,75.87 135.28,76.34 135.28,83.64 135.28,83.64 135.28,85.09 135.38,85.2 135.38,85.73 134.95,86.16 134.95,86.34 134.8,86.49 134.58,86.49 134.42,86.33 134.42,85.81 134.74,85.49 v2(134.97,85.49)
  IN2 w0.163: v2(146.17,31.75) 145.86,31.75 145.62,31.99 145.62,35.93 145.32,36.23 145.32,36.72 145.16,36.88 144.92,36.88 144.76,37.04 144.76,37.37 144.92,37.53 145.16,37.53 145.32,37.69 145.32,39.79 144.52,40.59 144.52,44.13 144.36,44.29 143.97,44.29 143.81,44.45 143.81,44.78 143.97,44.94 144.36,44.94 144.52,45.1 144.52,45.43 144.36,45.59 143.97,45.59 143.81,45.76 143.81,46.08 143.97,46.24 144.36,46.24 144.52,46.41 144.52,46.73 144.36,46.89 143.97,46.89 143.81,47.06 143.81,47.38 143.97,47.54 144.36,47.54 144.52,47.71 144.52,48.25 145.4,49.13 145.4,49.56 144.38,50.58 144.38,51.64 144.66,51.92 145.29,51.92 145.44,52.07 145.44,55 144.53,55.91 142.42,55.91 139.75,58.58 139.75,58.85 140.1,59.2 140.1,59.43 139.87,59.66 139.64,59.66 139.29,59.31 139.02,59.31 138.83,59.5 138.83,59.77 139.7,60.65 139.7,60.88 136.25,64.33 136.25,70.08
  BOTTOM w0.076: UC1.AK35 135.28,85.77 134.99,85.49 v2(134.97,85.49)
  BOTTOM w0.157: JDIMM2.113 144.52,33.62 144.7,33.44 144.7,31.74 144.86,31.59 145.17,31.59 145.3,31.72 145.3,31.86 145.47,32.02 146.05,32.02 146.17,31.89 v2(146.17,31.75)
DDR_CKE0_DIMMA: length 49.2
  IN1 w0.076: v2(129.42,81.06) 129.82,81.06 130.1,80.78 130.1,77.74 129.07,76.71 127.54,76.71 127.01,77.25 125.36,77.25 122.51,74.4 122.51,72.17 122.15,71.81
  IN1 w0.163: v2(119.78,44.61) 119.34,45.05 119.34,48.25 118.84,48.75 118.84,65.27 121.49,67.92 121.49,71.15 122.15,71.81
  BOTTOM w0.076: v2(129.42,81.06) 129.57,81.06 UC1.AU43
  BOTTOM w0.157: JDIMM1.73 120.15,46.53 119.22,45.6 119.22,45.17 v2(119.78,44.61)
DDR_CKE1_DIMMA: length 48.5
  IN1 w0.076: v2(129.41,79.76) 128.96,79.31 128.96,78.08 128.33,77.45 127.46,77.45 127.16,77.75 125.15,77.75 121.9,74.5 121.9,72.27 121.44,71.81
  IN1 w0.163: 121.44,71.81 120.99,71.35 120.99,68.06 118.37,65.44 118.37,48.63 118.93,48.08 118.93,43.94 v2(119.78,43.09)
  BOTTOM w0.076: UC1.AW43 129.72,80.06 129.42,79.76 v2(129.41,79.76)
  BOTTOM w0.157: JDIMM1.74 120.45,42.42 v2(119.78,43.09)
DDR_CKE2_DIMMB: length 60.3
  IN2 w0.076: 122.87,71.05 122.87,72.08 126.4,75.61 126.4,78.26 v2(126.3,78.36)
  IN2 w0.163: 122.87,71.05 122.87,66.63 121.29,65.04 121.29,61.53 120.67,60.91 120.67,55.85 125.45,51.07 126.05,51.07 128.39,48.73 128.39,47.77 129.14,47.02 129.14,40.88 130.28,39.73 130.28,36.71 130.51,36.48 130.51,32.73 130.66,32.57 131.11,32.57 131.26,32.42 131.26,31.71 131.41,31.56 131.83,31.56 v2(131.97,31.7)
  BOTTOM w0.076: UC1.AY49 126.67,78.59 126.44,78.36 v2(126.3,78.36)
  BOTTOM w0.157: JDIMM2.73 132.52,33.36 132.26,33.1 131.69,33.1 131.54,32.95 131.54,31.86 131.69,31.7 v2(131.97,31.7)
DDR_CKE3_DIMMB: length 63
  IN2 w0.076: 122.46,71.05 122.46,71.91 125.92,75.37 v2(125.92,76.03)
  IN2 w0.163: v2(131.97,30.18) 130.03,32.12 130.03,36.3 129.85,36.48 129.85,39.55 128.68,40.72 128.68,46.81 127.79,47.7 127.79,48.74 125.88,50.65 125.28,50.65 120.25,55.68 120.25,62.04 120.86,62.64 120.86,65.28 122.46,66.88 122.46,71.05
  BOTTOM w0.076: UC1.AU50 125.53,81.15 125.53,78.46 125.92,78.08 v2(125.92,76.03)
  BOTTOM w0.157: v2(131.97,30.18) 132.82,29.33 JDIMM2.74
DDR_CS0_DIMMA#: length 50.4
  IN1 w0.076: 137.79,69.02 137.79,69.99 136.73,71.05 136.73,75.5 136.98,75.74 136.98,76.25 137.34,76.61 137.34,79.13 138.49,80.27 138.49,82.15 137.52,83.11 136.41,83.11 136.06,83.46 v2(135.8,83.46)
  IN1 w0.163: 137.79,69.02 137.79,68.77 137.8,68.76 137.8,55.27 136.12,53.59 136.12,48.39 135.13,47.4 135.13,45.22 134.98,45.06 134.58,45.06 134.32,44.81 134.32,42.35 v2(133.64,41.67)
  BOTTOM w0.076: v2(135.8,83.46) 136.08,83.18 136.09,83.18 136.1,83.17 UC1.AP33
  BOTTOM w0.157: JDIMM1.114 132.45,40.74 133.38,41.67 v2(133.64,41.67)
DDR_CS1_DIMMA#: length 51.4
  IN1 w0.076: v2(137.02,82.11) 137.02,81.69 136.8,81.47 136.8,81.01 136.88,80.93 137.51,80.93 137.6,80.85 137.6,80.72 137.51,80.63 136.88,80.63 136.8,80.55 136.8,80.4 136.88,80.33 137.56,80.33 137.65,80.24 137.65,80.11 137.56,80.02 136.88,80.02 136.8,79.94 136.8,79.79 136.88,79.72 137.36,79.72 137.45,79.63 137.45,79.5 137.36,79.41 136.88,79.41 136.8,79.33 136.8,79.18 136.88,79.11 137.1,79.11 137.18,79.03 137.18,78.88 137.1,78.8 136.88,78.8 136.8,78.73 136.8,78.57 136.88,78.5 137.1,78.5 137.18,78.42 137.18,78.27 137.1,78.19 136.88,78.19 136.8,78.12 136.8,77.96 136.88,77.89 137.1,77.89 137.18,77.81 137.18,77.66 137.1,77.58 136.88,77.58 136.8,77.51 136.8,77.34 136.88,77.26 137.1,77.26 137.18,77.19 137.18,77.04 137.1,76.96 136.88,76.96 136.8,76.88 136.8,75.89 136.53,75.62 136.53,74.32 136.38,74.18 136.38,74.02 136.53,73.87 136.53,73.72 136.38,73.57 136.38,73.41 136.53,73.26 136.53,73.11 136.38,72.96 136.38,72.8 136.53,72.65 136.53,72.5 136.38,72.35 136.38,72.19 136.53,72.04 136.53,71.89 136.38,71.73 136.38,71.59 136.53,71.43 136.53,70.9 136.65,70.78 136.65,70.67 136.54,70.56 136.54,70.46 136.65,70.35 136.76,70.35 136.86,70.45 136.97,70.45 137.34,70.08 137.34,69.02
  IN1 w0.163: v2(133.64,44.72) 134.68,45.75 134.68,47.55 135.69,48.57 135.69,54.39 137.34,56.05 137.34,69.02
  BOTTOM w0.076: v2(137.02,82.11) 137.47,82.11 137.6,82.24 137.6,82.39 137.47,82.52 UC1.AR32
  BOTTOM w0.157: v2(133.64,44.72) 133.96,44.72 134.55,45.31 JDIMM1.121
DDR_CS2_DIMMB#: length 67.4
  IN2 w0.076: 138.73,69.38 137.04,71.08 137.04,81.15 136.5,81.69 136.5,84.37 v2(136.86,84.74)
  IN2 w0.163: v2(146.17,28.7) 146.47,28.7 146.79,28.38 147,28.38 147.29,28.67 147.29,28.89 147,29.19 147,29.5 147.32,29.82 147.32,34.62 147.75,35.04 147.75,40.09 147.19,40.65 147.19,46.78 148.01,47.6 148.01,53.59 147.85,53.75 147.76,53.75 147.61,53.91 147.61,54.25 147.76,54.4 147.85,54.4 148.01,54.57 148.01,55.36 138.78,64.6 138.78,69.33 138.73,69.38
  BOTTOM w0.076: UC1.AM32 137.28,84.47 137.28,84.47 137.01,84.74 v2(136.86,84.74)
  BOTTOM w0.157: v2(146.17,28.7) 145.57,28.7 144.82,27.95 JDIMM2.114
DDR_CS3_DIMMB#: length 68.2
  IN2 w0.076: v2(136.81,86.06) 136.33,85.58 136.33,85.24 136.33,85.24 136.33,84.96 136.33,84.96 136.33,84.53 136.33,84.53 136.33,81.62 136.87,81.08 136.87,70.86 138.36,69.37
  IN2 w0.163: v2(146.17,30.22) 146.17,30.1 146.33,29.94 146.75,29.94 146.9,30.1 146.9,35.33 146.83,35.4 146.83,35.77 146.98,35.92 147.18,35.92 147.33,36.07 147.33,39.91 146.77,40.48 146.77,46.94 147.6,47.77 147.6,51.82 147.02,52.4 147.02,55.76 138.36,64.42 138.36,69.37
  BOTTOM w0.076: UC1.AK32 137.1,85.77 v2(136.81,86.06)
  BOTTOM w0.157: JDIMM2.121 146.92,30.97 v2(146.17,30.22)
DDR_PG_CTRL: length 76.5
  TOP w0.102: v2(99.45,57.69) 99.47,57.71 103.84,57.71 v2(106.86,54.69) ; U2303.2 v2(136.71,54.79)
  BOTTOM w0.076: 111.71,76.61 v1(112.78,77.68) 115.29,77.68 116.67,79.07 116.67,80.22 117.19,80.74 117.19,80.84 117.4,81.04 118.3,81.04 118.36,80.99 UC1.AV61
  BOTTOM w0.102: v2(106.86,54.69) 106.89,54.67 136.58,54.67 v2(136.71,54.79) ; 111.71,76.61 108.73,73.63 103.78,73.63 100.13,69.98 100.13,58.37 v2(99.45,57.69)
DDR_XDP_SMBCLK_R1: length 4.7
  TOP w0.102: JXDP1.53 92.69,78.71 93.02,79.05 93.02,80.7 93.53,81.21 94.09,81.21 RP46.7
DDR_XDP_SMBDAT_R1: length 4.7
  TOP w0.102: RP46.8 93.67,80.71 93.27,80.32 93.27,78.67 92.82,78.21 JXDP1.51
DDR_XDP_WLAN_TP_SMBCLK: length 424.4
  TOP w0.102: QC1.1 171.13,82.24 v2(171.56,82.67) 171.63,82.74 R2332.2 170.8,83.29 v1(170.47,83.62) ; v2(95.56,79.43) 95.81,79.68 95.81,80.95 95.55,81.21 RP46.2
  IN1 w0.107: v2(170.87,39.93) 171.38,40.44 171.38,42.47 170.23,43.62 170.23,63.85 171.2,64.82 171.2,74.93 172.14,75.87 172.14,80.78 171.56,81.36 v2(171.56,82.67) ; v2(14.32,59.35) 14.48,59.19 14.48,54.04 17.36,51.16 20,48.52 20,46.64 24.5,42.13 27.93,42.13 29.84,40.22 36.29,40.22 37.17,39.34 46.6,39.34 47.6,38.34 47.6,32.76 52.8,27.55 52.8,17.27 48.68,13.14 48.68,12.5 45.15,8.97 43.43,8.97 42.53,8.07 37.62,8.07 36.72,8.97 35.87,8.97 31.09,13.75 22.54,13.75 21.15,15.14 19.38,15.14 18.97,15.55 v2(18.97,16.03) ; v2(95.76,39.25) 95.34,39.67 95.34,41.01 95.59,41.25 95.59,45.36 94.29,46.65 94.29,55.45 95.21,56.37 95.21,73.18 94.54,73.84 94.54,78.41 v2(95.56,79.43)
  IN2 w0.107: v2(14.32,59.35) 14.37,59.35 14.54,59.17 14.54,58.91 14.75,58.71 16.32,58.71 16.87,59.27 28.01,59.27 28.31,59.56 32.19,59.56 34.2,57.56 34.2,55.32 35.16,54.37 44.79,54.37 47.61,51.55 47.61,50.75 48.06,50.3 48.06,45.66 51.85,41.86 51.85,36.7 52.16,36.38 52.97,36.38 53.57,35.79 59.12,35.79 59.37,35.54 72.43,35.54 74.31,37.42 75.19,37.42 80.53,42.76 84.31,42.76 88.35,38.72 94.15,38.72 94.68,39.26 95.75,39.26 v2(95.76,39.25) 97.39,39.25 105.34,31.29 105.34,30.01 108.46,26.9 127.29,26.9 128.25,25.94 152.1,25.94 153.51,24.53 165.99,24.53 166.46,24.06 168.65,24.06 v2(168.8,23.91)
  BOTTOM w0.102: JDIMM1.202 158.85,38.15 159.09,37.91 161.8,37.91 164.18,40.29 170.52,40.29 v2(170.87,39.93) 171.76,39.93 172.14,39.55 172.14,35.92 172.95,35.11 172.95,32.67 171.08,30.79 170.14,30.79 169.68,30.33 169.68,28.5 170.08,28.1 170.67,28.1 171.22,27.54 JDIMM2.202 171.22,25.42 169.7,23.91 v2(168.8,23.91) ; US3.4 18.86,16.14 v2(18.97,16.03)
DDR_XDP_WLAN_TP_SMBDAT: length 427.3
  TOP w0.102: v2(95.56,78.8) 95.43,78.8 95.05,79.18 95.05,79.53 95.58,80.06 95.58,80.65 95.51,80.71 RP46.1 ; QC1.4 172.66,80.94 172.46,81.14 172.46,82.29 v2(172.14,82.61) 172.52,82.99 R2331.2
  IN1 w0.107: v2(14.96,59.36) 14.71,59.11 14.71,54.14 17.59,51.26 20.23,48.62 20.23,46.73 24.6,42.37 28.03,42.37 29.94,40.45 36.39,40.45 37.27,39.57 46.7,39.57 47.83,38.44 47.83,32.86 53.04,27.65 53.04,17.17 48.91,13.05 48.91,12.41 45.24,8.73 43.63,8.73 42.7,7.8 37.38,7.8 36.46,8.73 35.78,8.73 30.99,13.52 22.44,13.52 21.06,14.91 18.93,14.91 16.99,16.85 v2(16.99,17.84) ; v2(170.87,39.3) 171.63,40.06 171.63,42.73 170.47,43.9 170.47,63.76 171.43,64.72 171.43,74.78 172.4,75.75 172.4,79.68 172.45,79.74 172.45,82.29 v2(172.14,82.61) ; v2(95.78,39.83) 95.78,41.01 95.84,41.07 95.84,47.69 94.52,49.01 94.52,55.25 95.45,56.18 95.45,73.32 94.93,73.84 94.93,78.16 v2(95.56,78.8)
  IN2 w0.107: v2(169.25,24.31) 167.98,25.58 161,25.58 160.19,24.76 153.66,24.76 152.23,26.19 128.45,26.19 127.51,27.13 108.56,27.13 105.58,30.11 105.58,31.39 97.14,39.83 v2(95.78,39.83) 94.75,39.83 93.87,38.96 88.45,38.96 84.41,42.99 80.43,42.99 75.1,37.65 74.21,37.65 72.33,35.77 59.47,35.77 59.22,36.02 53.66,36.02 53.07,36.62 52.28,36.62 52.08,36.81 52.08,41.97 48.29,45.76 48.29,50.4 47.84,50.85 47.84,51.64 44.88,54.6 35.25,54.6 34.43,55.42 34.43,57.65 32.29,59.8 28.22,59.8 27.98,59.56 16.84,59.56 16.22,58.94 14.84,58.94 14.78,59.01 14.78,59.17 v2(14.96,59.36)
  BOTTOM w0.102: US3.6 v2(16.99,17.84) ; v2(169.25,24.31) 169.75,24.31 170.62,25.18 JDIMM2.200 170.62,27.61 170.39,27.84 169.93,27.84 169.45,28.33 169.45,30.43 170.03,31.02 170.9,31.02 172.68,32.8 172.68,34.98 171.89,35.77 171.89,39.12 v1(171.71,39.3) v2(170.87,39.3) 170.12,40.05 164.29,40.05 161.91,37.66 158.82,37.66 158.25,38.23 JDIMM1.200
DEVSLP0: length 131.4
  IN1 w0.107: v2(158.74,23.89) 160.84,25.99 160.84,32.82 161.55,33.53 162.09,33.53 163.67,35.11 166.66,35.11 167.95,36.4 167.95,37.27 169.28,38.59 169.28,64.34 170.26,65.33 170.26,72.56 169.86,72.97 169.86,76.38 170.24,76.76 170.24,85.78 167.8,88.22 167.8,89.49 167.57,89.72 164.65,89.72 163.89,90.48 v2(162.87,90.48)
  IN2 w0.107: v2(183.7,13.42) 183.24,13.42 178.9,9.07 169.86,9.07 167.7,11.23 159.04,11.23 v2(158.83,11.43)
  BOTTOM w0.076: UC1.P2 155.8,93.76 157.39,93.76 157.79,94.16 v1(157.84,94.16) 159.18,94.16 159.59,93.75 159.59,93.33 RC11.1 160.47,92.45 161.31,92.45 162.67,91.09 162.74,91.09
  BOTTOM w0.102: v2(158.74,23.89) 158.83,23.8 v2(158.83,11.43) ; v2(183.7,13.42) 183.92,13.42 185.32,14.81 RS8.1 ; 162.74,91.09 162.87,90.96 v2(162.87,90.48)
DEW1: length 4.5
  TOP w0.102: US2.16 184.22,9.22 183.76,8.75 182.29,8.75 RS34.1 RS36.1
DEW2: length 3.1
  TOP w0.102: US2.6 186.22,14.88 185.98,15.12 RS35.1 185.98,15.5 RS33.1
DGPU_HOLD_RST#: length 112.2
  TOP w0.076: v2(154.49,94.44) 154.82,94.77 154.82,95.43 155.02,95.64 v1(155.76,95.64) 156.19,96.07 159.75,96.07 RC77.2
  TOP w0.102: UV2.1 v2(78.18,77.13)
  IN1 w0.076: v2(154.49,94.44) 153.91,93.86 151.64,93.86 151.19,94.31 151.19,96.32 150.68,96.83 150.68,101.02 149.82,101.88 121.95,101.88 ; 108.13,101.43 108.59,101.88
  IN1 w0.107: 108.13,101.43 106.97,100.26 v2(97.47,100.26) ; 121.95,101.88 119.25,104.58 111.28,104.58 108.59,101.88
  IN2 w0.107: v2(97.47,100.26) 97.95,99.78 97.95,97.95 91.88,91.88 91.88,87.56 87.69,83.37 87.69,79.68 84.26,76.26 82.48,76.26 81.59,77.14 81.59,77.53 81.21,77.91 78.95,77.91 v2(78.18,77.13)
  BOTTOM w0.076: UC1.N4 154.19,94.74 v2(154.49,94.44)
DGPU_PRSNT#: length 18.4
  IN1 w0.076: 158.73,94.82 158.5,95.05 156.77,95.05 156.01,95.81 154.87,95.81 153.88,94.82 153.03,94.82 v2(152.46,94.25)
  IN1 w0.107: 158.73,94.82 159.85,94.82 161.22,96.19 161.93,96.19 v2(162.34,96.6)
  BOTTOM w0.076: v2(152.46,94.25) 152.2,94 UC1.R7 ; v2(162.34,96.6) 162.52,96.6 162.74,96.83 v1(162.74,97.03) 162.74,97.21
  BOTTOM w0.102: RC100.2 RC99.1 165.97,97.97 163.51,97.97 162.74,97.21
DGPU_PWR_EN#: length 10.6
  BOTTOM w0.508: RV23.1 RV22.2 40.77,107.67 QV3.1 42.58,108.11 43.24,108.77 43.24,112.2 v1(43.5,112.46) 43.87,112.83 RV26.2
DGPU_PWROK: length 247.1
  TOP w0.076: v2(152.54,93.28) 153.17,93.91 153.97,93.91 154.12,94.06 154.84,94.06 155.23,94.44 155.23,94.59 155.5,94.87 157.87,94.87
  TOP w0.102: UE1.18 131.88,10.91 131.98,10.8 134.5,10.8 136.62,12.92 137.45,12.92 137.72,13.2 137.72,17.96 v2(137.85,18.09) ; 157.87,94.87 159.01,94.87 v1(159.06,94.92) RC73.2
  IN1 w0.107: v2(112.92,19.98) 112.92,19.46 114.14,18.24 123.42,18.24 123.8,18.63 129.95,18.63 131.35,17.22 136.99,17.22 v2(137.85,18.09) 138.61,17.33 145.09,17.33 146.26,18.5 151.21,18.5 151.67,18.95 156.42,18.95 158.3,20.83 158.3,22.53 161.35,25.57 161.35,29.01 162.03,29.69 162.03,32.8 163.83,34.6 166.81,34.6 168.46,36.25 168.46,37.01 169.74,38.3 169.74,64.09 170.73,65.08 170.73,75.23 171.63,76.13 171.63,80.57 170.87,81.34 170.87,82.99 172.14,84.26 172.14,87.3 170.24,89.21 169.35,89.21 169.09,89.46 169.09,90.1 168.08,91.11 164.52,91.11 164.14,91.5 161.35,91.5 160.84,92 158.3,92 158.04,92.26 154.36,92.26 153.85,92.77 152.96,92.77 152.54,93.19 v2(152.54,93.28)
  IN1 w0.254: v2(59.37,33.33) 59.37,34.35 57.97,35.74 55.17,35.74 54.43,36.49 54.43,39.2 v2(56.32,41.09)
  IN2 w0.107: v2(112.92,19.98) 111.19,19.98 103.28,27.89 100.04,27.89 92.96,34.98 77.53,34.98 75.09,32.54 60.16,32.54 v2(59.37,33.33)
  BOTTOM w0.076: v2(152.54,93.28) 152.85,92.97 UC1.U6
  BOTTOM w0.203: v2(59.37,33.33) 59.77,33.33 60.13,33.68 PU1000.9 ; PU1000.20 58.6,38.43 58.48,38.56 58.48,39.3 57.71,40.06 PR1030.2
  BOTTOM w0.254: v2(56.32,41.09) 56.32,41.03 56.72,40.62 56.98,40.62 57.16,40.44 PR1030.2
DH_1.35V:
  vias: v1(87.53,12.37) v3(87.31,11.74) v3(87.94,11.99)
DH_CHG: length 11.6
  IN1 w1.016: 43.62,18.47 43.36,18.72 43.36,29.77 v3(43.49,29.9)
  vias: v1(42.96,29.87) v2(43.21,17.58) v2(43.64,17.15) v3(42.98,30.41)
DIR: length 5.9
  BOTTOM w0.102: v1(87.04,90.67) CV169.2
  BOTTOM w0.254: U1.5 85.74,90.71 CV169.2 CV167.2 RV79.1
DISPOFF#: length 5.9
  TOP w0.102: v2(2.88,80.62) 2.88,80.49 v1(3.18,80.19) 3.31,80.07 RX9.1 4.17,80.4 4.35,80.57 6.39,80.57 DX1.1
  BOTTOM w0.102: JEDP.37 2.5,81 v2(2.88,80.62)
DL_1.35V: length 7.4
  TOP w0.102: v3(85.78,14.28) v1(86.52,14.28)
  IN2 w1.016: v3(85.78,14.28) 88.19,16.69 88.19,19.94
  vias: v3(85.27,13.52) v3(87.56,20.88) v3(88.19,20.88)
DL_CHG: length 10.9
  IN2 w1.016: 35.36,23.63 35.36,22.38 41.2,16.54
  BOTTOM w0.102: v1(41.1,17.5) 41.1,17 41.41,16.69 v2(41.41,16.26)
  vias: v3(35.36,24.62) v3(36.12,24.57) v3(41.46,15.55)
DP_VSSR: length 7.4
  BOTTOM w0.254: UV1.AM20 75.11,80.59 v2(75.11,80.45) ; v2(75.24,82.1) 74.84,82.5 UV1.AM18
  BOTTOM w0.305: UV1.AM14 74.8,85.72 v2(75.24,86.16) ; v2(75.16,79.68) 74.86,79.38 74.86,79.36 UV1.AM22 ; UV1.AM16 74.83,84.1 v2(75.24,84.51) ; UV1.AH14 73.2,85.79 v2(72.83,86.16) ; UV1.AG23 72.09,78.81 v2(72.02,78.81) 71.91,78.81 UV1.AF23 ; UV1.AG14 v2(72.83,85.27) ; v2(75.24,78.16) 74.8,77.72 UV1.AM24
  BOTTOM w0.381: UV1.AF19 71.6,81.67 v2(71.94,81.34) 71.94,81.21 71.6,80.87 UV1.AF20
  vias: v1(73.51,83.6)
DPB_HPD: length 73.5
  TOP w0.254: v2(193.8,74.42) 193.81,74.41 195.06,74.41 QX5.3 195.46,74.42 196.16,75.11 RX14.1
  IN1 w0.203: v2(154.11,105.34) 154.62,105.34 155.25,105.97 159.44,105.97 163.76,101.66 168.08,101.66 170.55,99.18 172.41,99.18 173.95,97.64 173.95,96.07 173.64,95.76 173.64,94.72 174.22,94.14 174.22,90.85 177.27,87.81 177.27,85.33 178.29,84.31 178.29,80.12 v2(177.09,78.92)
  BOTTOM w0.076: UC1.C8 151.6,100.84 151.84,101.09 152.17,101.09 152.53,101.45 152.53,101.63 152.71,101.81 152.71,102.96 153.09,103.34 154.11,104.35 v2(154.11,105.34)
  BOTTOM w0.203: v2(177.09,78.92) 177.09,77.7 177.88,76.9 182.35,76.9 183.17,76.09 v1(191.1,76.09) 192.13,76.09 v2(193.8,74.42)
DPC_HPD: length 15.2
  TOP w0.076: v2(153.09,104.45) 153.11,104.45 153.54,104.88 153.54,109.24 154.34,110.04 v4(155.61,110.04) 158.43,110.04 159.44,111.05 RC84.2
  BOTTOM w0.076: v2(153.09,104.45) 153.09,104.17 151.82,102.9 151.82,102.26 UC1.A8
DRAM_RST: length 12.6
  TOP w0.102: v2(64.89,92.54) 64.67,92.76 v1(64.67,92.99) 64.67,93.45 CV97.1 RV38.1 RV37.1
  IN2 w0.102: v2(60.38,89.39) 60.93,88.85 63.2,88.85 63.46,89.11 63.46,90.39 64.02,90.96 64.65,90.96 65.33,91.64 65.33,92.1 v2(64.89,92.54)
  BOTTOM w0.102: v2(60.38,89.39) 59.89,88.9 UV1.L10
DRAM_RST#: length 95
  TOP w0.102: RV36.1 v2(65.13,97.59) ; v2(27.88,94.9) 28.28,95.29 28.28,96.52 v1(28.68,96.93) 29.29,97.53 UV7.T2 ; v2(27.96,75.22) 28.38,75.64 28.38,76.03 28.54,76.19 28.54,76.78 29.35,77.6 30.82,77.6 UV6.T2
  IN2 w0.102: v2(65.13,97.59) 60.76,97.59 60.64,97.72 ; v2(27.88,94.9) 27.8,94.97 27.64,94.97 27.26,95.36 27.26,96.22 27.74,96.7 27.87,96.7 30.54,99.37 34.35,99.37 35.01,100.03 38.18,100.03
  IN2 w0.107: 27.26,94.77 26.19,94.77 25.08,93.65 25.08,93.13 25.07,93.13 25.07,90.32 21.77,87.02 21.77,79.56 24.35,76.98 24.35,75.63 ; 38.18,100.03 38.41,100.26 38.41,100.89 39.17,101.66 57.59,101.66 59.75,99.5 59.75,98.61 60.64,97.72
  IN2 w0.127: 24.35,75.63 26.24,73.74 29.02,73.74 v2(30.25,72.5)
  IN2 w0.13: v2(27.88,94.9) 27.75,94.77 27.26,94.77
  BOTTOM w0.102: v2(30.25,72.5) 30.72,72.5 30.95,72.73 UV5.T2 29.15,72.92 27.96,74.12 v2(27.96,75.22) ; v2(27.88,94.9) 30.04,92.73 UV8.T2
DSWODVREN: length 30.9
  BOTTOM w0.076: UC1.AW7 152.31,79.76 152.31,78.64 152.96,77.99 152.96,76.12 153.35,75.73 153.35,73.97 153.73,73.59 153.73,71.81
  BOTTOM w0.102: 153.73,71.81 153.73,70.1 154.29,69.54 154.29,66.93 154.54,66.68 v1(159.82,66.68) 161.12,66.68 163.1,64.7 165.15,64.7 166.14,63.71 168.74,63.71 R2338.1 R2337.1
EC_ENVDD: length 239.3
  TOP w0.102: RX8.2 10.34,86.11 v1(10.34,86.85) 10.14,87.05 v2(9.84,87.05) ; UE1.71 145.69,7.71 145.12,8.28 v2(145.12,8.77)
  IN1 w0.107: v2(145.12,8.77) 144.81,8.46 142.37,8.46 141.29,9.54 137.13,9.54 135.62,8.03 132.41,8.03 131.17,9.27 128.39,9.27 127.71,9.94 116.37,9.94 115.91,9.48 113.92,9.48 113.72,9.68 113.21,9.68 112.49,10.4 111.05,10.4 110.74,10.71 110.28,10.71 105.78,15.21 105.78,23.29 103.68,25.39 103.17,25.39 102.4,26.15 101.14,26.15 96.1,31.19 95.33,31.19 90.36,36.16 89.16,36.16 88.45,36.87 88.45,38.03 86.67,39.81 86.67,49.84 88.07,51.24 88.07,61.19 87.18,62.08 87.18,63.56 86.16,64.57 86.16,67.62 86.92,68.38 86.92,69.14 87.61,69.83 87.61,78.49 87.43,78.67 87.43,85.91 86.42,86.92 86.42,90.99 86.16,91.24 86.16,93.15 85.08,94.23 85.08,94.92 78.22,101.78 64.01,101.78 61.81,103.98 61.81,104.13 61.29,104.65 60.61,104.65 54.71,110.55 49.33,110.55 48.57,109.78 40.95,109.78 39.93,110.8 37.78,110.8 37.01,111.56 36.25,111.56 34.94,110.25 34.94,108.7 29.53,103.28 18.7,103.28 13.52,98.1 12.88,98.1 10.34,95.56 10.34,87.56 v2(9.84,87.05)
EC_LID_OUT#: length 111.1
  TOP w0.076: v2(153.14,89.45) 153.08,89.45 v1(152.74,89.11)
  TOP w0.102: RE73.2 143.51,20.96 143.42,20.88 UE1.101 v2(143.42,18.06)
  IN1 w0.076: v2(153.14,89.45) 153.52,89.83 153.89,89.83 154.4,89.32 155.78,89.32 156.42,89.96 158.25,89.96 158.36,89.84 158.73,89.84
  IN1 w0.107: 158.73,89.84 159.25,89.84 161.28,87.81 164.23,87.81 164.92,87.13 167.49,87.13 169.22,85.4 169.22,77.27 168.84,76.89 168.84,72.55 169.67,71.72 169.67,65.53 168.71,64.57 168.71,38.97 166.49,36.75 165.44,36.75 164.81,36.12 163.56,36.12 161.78,34.35 160.46,34.35 158.93,32.82 158.93,27.36 156.52,24.95 156.52,22.84 156.98,22.38 156.98,20.17 156.3,19.5 151.02,19.5 150.48,18.95 144.31,18.95 v2(143.42,18.06)
  BOTTOM w0.076: UC1.AD6 152.85,89.14 153.14,89.42 v2(153.14,89.45)
EC_MUTE#: length 70.5
  TOP w0.102: UE1.83 148.04,12.51 v1(148.28,12.74) 148.49,12.96 v2(148.49,13.42)
  IN2 w0.107: v2(148.49,13.42) 148.49,11.97 149.6,10.86 152.02,10.86 152.26,11.1 154.68,11.1 155.26,10.52 156.28,10.52 158.49,8.31 161.85,8.31 163.32,9.77 165.6,9.77 166.68,8.69 168.33,8.69 169.09,7.93 180.36,7.93 182.26,9.83 184.51,9.83 186.9,7.45 196.86,7.45 199.22,9.81 199.22,10.14 201.73,12.65 201.73,14.81 200.72,15.83 v2(200.72,16.69)
  BOTTOM w0.102: v2(200.72,16.69) 200.21,17.2 200.21,17.45 199.98,17.69 UA1.47
EC_ON: length 111.4
  TOP w0.102: v2(139.02,13.09) 139.02,16.82 138.94,16.9 138.94,18.46 139.02,18.55 UE1.112 ; v2(74.42,11.97) 75.04,11.97 v4(75.52,12.45)
  TOP w0.254: v2(74.42,11.97) 74.39,11.93 PR102.1
  IN1 w0.107: v2(150.93,2.47) 150.3,1.83 116.66,1.83 116.25,2.24 114.61,2.24 114.08,1.71 107.24,1.71 106.36,2.6 106.36,4.88 101.99,9.25 86.49,9.25 85.85,9.89 83,9.89 81.54,11.36 75.37,11.36 74.76,11.97 v2(74.42,11.97)
  IN2 w0.107: v2(149.05,8.56) 149.05,9.97 145.39,13.63 143.56,13.63 142.69,12.75 141.39,12.75 141.33,12.82 139.3,12.82 v2(139.02,13.09)
  BOTTOM w0.102: v2(149.05,8.56) 149.05,6.54 150.93,4.67 v2(150.93,2.47)
EC_RSMRST#: length 75.6
  TOP w0.076: 157.16,68.25 157.16,68.74 156.16,69.75 155.03,69.75 154.62,70.16 154.62,71.94 154.44,72.11 RC41.1
  TOP w0.102: UE1.100 143.82,20.36 144.5,21.04 RE2.2 144,21.89 144,22.7 144.38,23.08 v2(144.42,23.08) 144.91,23.58 DE3.2 ; 157.16,68.25 157.16,68.02 v1(158.97,66.21) 161.5,63.68 161.5,63.28 164.9,59.87 164.9,41.63 v2(164.78,41.51)
  IN1 w0.107: v2(144.42,23.08) 144.86,22.64 148.65,22.64 151.85,25.84 152.89,25.84 155,27.94 155,32.74 159.52,37.27 160.97,37.27 162.36,38.66 163,38.66 164.73,40.39 165.09,40.39 165.26,40.56 165.26,41.03 v2(164.78,41.51)
EC_RST#: length 10.2
  TOP w0.102: RE8.1 127.23,1.71 128.96,1.71 129.29,2.04 CE11.1 129.85,2.47 130.61,1.71 v1(131.02,1.71) 133.79,1.71 134.22,2.14 UE1.37
EC_RX: length 110.3
  TOP w0.102: v2(139.1,8.95) 139.1,8.82 137.57,7.29 133.79,7.29 133.03,6.53 133.03,5.9 132.84,5.71 UE1.31
  IN1 w0.107: v2(181.67,67.24) 180.56,66.13 180.56,62.66 179.97,62.07 179.97,59.53 179.33,58.89 179.33,55.32 177.63,53.62 177.63,49.63 176.28,48.27 176.28,44.23 175.48,43.43 175.48,37.23 175.06,36.81 175.06,22.02 172.27,19.23 172.27,13.91 171.38,13.02 171.38,9.71 167.28,5.61 161.48,5.61 160.38,6.71 157.11,6.71 156.23,7.59 156.22,7.59 156.01,7.8 155.61,7.8 155.61,7.8 154.87,7.8 154.49,8.18 150.87,8.18 149.87,9.19 147.86,9.19 147.85,9.18 147.77,9.18 146.57,7.98 142.2,7.98 141.22,8.95 v2(139.1,8.95)
  BOTTOM w0.102: JNGFF.32 v1(182.23,67.01) 182,67.24 v2(181.67,67.24)
EC_SCI#: length 123.8
  TOP w0.102: UE1.20 130,10.11 129.85,9.96 129.32,9.96 128.23,11.05 125.1,11.05 122.76,13.39 122.76,13.58 122.76,13.58 122.76,16.73 122.8,16.77 122.8,17.46 123.6,18.26 v1(123.6,21.21) 123.6,22.74 v2(123.15,23.19)
  IN1 w0.076: 158.73,83.44 158.55,83.62 157.92,83.62 v2(157.41,84.13)
  IN1 w0.107: 158.73,83.44 159.95,82.22 159.95,80.32 162.65,77.61 162.65,71.99 162.37,71.71 162.37,67.86 165.28,64.95 165.28,59.75 164.9,59.36 164.9,49.08 163.25,47.43 163.25,43.11 162.87,42.73 162.87,41.18 162.12,40.43 161.46,40.43 160.08,39.04 156.14,39.04 155.53,38.43 155.53,37.99 155.23,37.69 154.7,37.69 154.21,37.19 153.14,37.19 152.46,36.5 152.46,33.84 151.69,33.08 151.69,28.5 150.04,26.85 145.22,26.85 144.84,26.47 129.72,26.47 129.09,25.84 129.09,23.73 127.67,22.31 124.03,22.31 v2(123.15,23.19)
  BOTTOM w0.076: UC1.AM2 155.73,84.33 156.02,84.62 156.92,84.62 v2(157.41,84.13)
EC_SMB_CK1: length 181.5
  TOP w0.102: UE1.77 148.83,10.11 149.42,9.52 RP36.4 149.98,9.38 149.43,8.83 149.43,8.08 149.13,7.78 v2(149.13,5.71)
  TOP w0.254: v2(45.4,8.15) 45.4,8.54 44.97,8.97 37.45,8.97 33.57,12.86 27.77,12.86 v1(26.32,14.3) 24.31,16.31 24.31,19.61 22.41,21.52 22.41,22.15 22.15,22.41 PR18.2
  IN1 w0.107: v2(149.13,5.71) 148.12,5.71 145.75,3.33 125.49,3.33 124.82,4 118.98,4 118.38,3.41 113.82,3.41 113.65,3.23 109.15,3.23 108.39,3.99 108.39,5.74 107.67,6.47 106.93,6.47 101.78,11.61 101.78,20.76 100.57,21.97 99.04,21.97 91.25,29.76 77.29,29.76 75.75,31.3 57.08,31.3 53.27,27.49 53.27,15.55 51.87,14.15 50.98,14.15 50.09,13.26 50.09,12.63 49.46,11.99 48.83,11.99 45.53,8.69 45.53,8.21 45.4,8.08 v2(45.4,8.15)
  BOTTOM w0.254: PR714.1 v2(45.4,8.15)
EC_SMB_CK2: length 250.9
  TOP w0.102: UE1.79 148.84,10.91 149.24,10.52 RP36.2 150.37,10.52 150.53,10.67 150.53,11.51 v2(150.58,11.56) ; U2407.10 154.76,11.82 155.37,11.22 v2(155.81,11.22) ; QH1.6 173.89,76.65 174.15,76.39 174.15,75.59 172.04,73.49 v1(172.04,72.67) 171.71,72.34 171.71,65.03 173.18,63.56 173.18,61.62 v2(174.3,60.51)
  IN1 w0.102: 77.91,96.32 76.51,97.72
  IN1 w0.107: v2(70.8,99.37) 74.86,99.37 76.51,97.72 ; v2(174.3,60.51) 174.02,60.23 174.02,59.36 173.02,58.36 173.02,50.5 173.46,50.07 173.46,37.95 169.41,33.9 169.16,33.9 168.08,32.82 168.08,28.83 165.18,25.93 165.18,21.04 163.53,19.38 163.53,19.14 161.85,17.45 160.58,17.45 158.06,14.93 v2(155.11,14.93) 154.22,15.82 151.48,15.82 151.15,16.14 149.04,16.14 148.99,16.1 144.25,16.1 142.98,14.83 138.19,14.83 137.99,15.03 134.67,15.03 134.2,15.5 133.64,15.5 133.62,15.52 130.94,15.52 130.23,16.23 123.23,16.23 123.01,16.46 v2(114.7,16.46) ; 77.91,96.32 79.99,94.24 81.51,94.24 83.75,92 83.75,88.96 82.99,88.19 82.99,83.49 85.36,81.12 85.36,79.47 85.15,79.25 85.15,69.4 83.62,67.87 83.62,62.41 86.33,59.7 86.33,54.36 84.89,52.93 84.89,38.92 86.67,37.14 86.67,33.02 v2(87.53,32.16)
  IN2 w0.107: v2(87.53,32.16) 87.7,31.99 92.26,31.99 98.27,25.98 101.13,25.98 101.2,25.91 101.37,25.91 108.44,18.84 108.44,17.91 109.98,16.37 114.3,16.37 114.41,16.48 114.68,16.48 v2(114.7,16.46) ; v2(155.81,11.22) 155.39,11.64 152.07,11.64 151.73,11.3 150.83,11.3 v2(150.58,11.56)
  BOTTOM w0.102: QV1.6 70.16,99.62 70.41,99.37 v2(70.8,99.37) ; v2(155.11,14.93) 155.92,14.12 155.92,11.33 v2(155.81,11.22)
EC_SMB_DA1: length 190.5
  TOP w0.102: v2(119.23,2.75) 119.67,3.18 119.67,7.09 118.78,7.98 v2(118.78,9.28) ; UE1.78 148.81,10.51 149.3,10.02 RP36.3 150.34,10.02 150.5,9.86 150.5,9.02 v2(149.83,8.35)
  TOP w0.254: v2(46.3,8.2) 45.14,9.35 37.83,9.35 33.83,13.35 27.91,13.35 24.82,16.44 v1(24.82,18.22) 24.82,19.87 22.92,21.77 22.92,23.04 22.54,23.42 PR20.2
  IN1 w0.107: v2(46.3,8.2) 46.51,8.41 46.51,9.27 48.98,11.74 49.59,11.74 50.98,13.14 52,13.14 53.78,14.91 53.78,27.49 57.33,31.04 75.62,31.04 77.16,29.51 91.18,29.51 98.95,21.74 100.42,21.74 101.53,20.63 101.53,11.31 106.61,6.23 106.61,2.98 107.5,2.09 113.95,2.09 114.34,2.48 118.97,2.48 v2(119.23,2.75) ; v2(149.83,8.35) 149.49,8.01 147.71,8.01 147.2,7.5 141.97,7.5 141.15,8.31 138.64,8.31 138.13,7.8 130.36,7.8 130.18,7.62 128.65,7.62 127.02,9.25 124.55,9.25 124.1,8.79 119.88,8.79 119.39,9.28 v2(118.78,9.28)
  BOTTOM w0.254: PR715.1 v2(46.3,8.2)
EC_SMB_DA2: length 265.7
  TOP w0.102: v2(118.37,17.8) 118.43,17.73 118.43,11.59 117.18,10.33 v2(117.18,9.22) ; v2(156.39,11.46) 156.23,11.62 155.44,11.62 155.26,11.81 U2407.9 ; UE1.80 v1(148.39,11.31) 149.13,11.31 149.42,11.02 RP36.1 149.98,11.02 149.98,11.55 v2(149.99,11.56) ; QH1.3 171.65,75.35 v2(172.14,74.86)
  IN1 w0.107: v2(149.99,11.56) 149.99,11.46 150.28,11.16 151.77,11.16 152.23,11.63 156.23,11.63 v2(156.39,11.46) ; v2(118.37,17.8) 122.3,17.8 122.36,17.86 125.95,17.86 126.19,18.1 130.09,18.1 131.23,16.97 133.1,16.97 133.94,16.13 133.98,16.13 133.98,16.13 134.5,16.13 134.74,15.89 134.74,15.88 134.96,15.66 135.41,15.66 135.66,15.9 135.66,16.3 135.85,16.5 137.33,16.5 137.67,16.84 145.29,16.84 145.85,17.4 151.45,17.4 152.23,16.62 v2(154.79,16.62) 155.53,16.62 157.68,18.76 158.21,18.76 161.6,22.15 161.6,24.19 162.36,24.95 162.36,26.73 163.89,28.25 163.89,33.33 164.65,34.09 166.97,34.09 168.87,36 169.35,36 171.89,38.54 171.89,42.85 170.7,44.04 170.7,63.66 171.67,64.63 171.67,74.38 v2(172.14,74.86) ; v2(117.18,9.22) 116.36,9.22 116.15,9.01 113.73,9.01 113.53,9.21 113.01,9.21 112.3,9.93 110.85,9.93 110.54,10.24 110.09,10.24 105.31,15.01 105.31,23.1 103.49,24.92 102.97,24.92 102.21,25.69 100.95,25.69 95.91,30.73 95.13,30.73 90.29,35.56 89.01,35.56 87.94,36.63 87.94,37.77 86.16,39.55 86.16,50.09 87.52,51.45 87.52,60.89 86.67,61.74 86.67,63.3 85.65,64.32 85.65,67.87 86.42,68.64 86.42,78.41 86.92,78.92 86.92,85.65 85.91,86.67 85.91,90.73 85.65,90.99 85.65,92.89 84.49,94.06 84.49,94.85 78.02,101.31 67.46,101.31 v2(66.99,100.84)
  BOTTOM w0.102: QV1.3 67.04,100.92 66.99,100.87 v2(66.99,100.84) ; v2(154.79,16.62) 155.2,16.21 155.2,15.42 156.25,14.37 156.25,11.6 v2(156.39,11.46)
EC_SMI#: length 134.2
  TOP w0.102: v1(129.27,12.11) UE1.15 132.25,12.11 133.15,11.21 134.28,11.21 136.59,13.52 136.59,16.09 v2(136.62,16.11)
  IN1 w0.107: v2(136.62,16.11) 137.27,16.11 137.75,16.59 145.57,16.59 146.13,17.14 151.34,17.14 152.13,16.36 154.41,16.36 154.62,16.16 155.43,16.16 157.5,18.23 158.26,18.23 161.85,21.82 161.85,24.06 162.62,24.82 162.62,26.6 164.14,28.12 164.14,33.2 164.78,33.84 167.04,33.84 168.97,35.76 169.5,35.76 172.12,38.39 172.12,42.95 170.93,44.14 170.93,60.44 172.58,62.09 172.58,69.89 172.69,70 172.69,83.33 172.65,83.37 172.65,87.56 171.25,88.96 171.25,91.11 171,91.37 169.65,91.37 169.33,91.7 164.65,91.7 164.36,91.98 164.36,91.98 164.34,92 161.55,92 160.66,92.89 v2(159.31,92.89)
  BOTTOM w0.076: v2(159.31,92.89) 158.43,92 157.59,92 157.56,91.98 156.3,91.98 UC1.V1
  BOTTOM w0.102: RC107.1 159.44,92.55 159.44,92.77 v2(159.31,92.89)
EC_SPOK: length 122.6
  TOP w0.102: v2(150.38,23.03) 150.38,22.6 v1(150.01,22.22) 149.7,21.91 DE4.1 DE3.1
  TOP w0.203: PU100.7 72.67,20.09 73.44,20.85 73.66,20.85 73.98,21.17 v2(73.98,22.13) 74.2,22.35 PR115.1
  IN2 w0.107: v2(147.19,3.5) 146.51,2.83 144.63,2.83 144.41,2.61 134.43,2.61 133.62,1.8 124.92,1.8 124.58,1.46 118.73,1.46 118.02,2.17 106.91,2.17 105.64,3.44 105.64,7.2 103.55,9.3 96.98,9.3 96.7,9.02 86.38,9.02 85.63,8.26 84.41,8.26 83.76,7.62 80.67,7.62 79.89,8.4 79.89,12.01 78.59,13.31 78.59,20.3 76.76,22.13 v2(73.98,22.13)
  BOTTOM w0.102: v2(147.19,3.5) 147.84,3.5 148.66,4.32 148.66,12.56 148.89,12.79 148.89,14.19 148.29,14.79 148.29,18.98 147.72,19.55 147.72,20.41 150.34,23.03 v2(150.38,23.03)
EC_TP_INT#: length 145.5
  TOP w0.102: UE1.119 136.22,18.33 v2(136.45,18.1) ; RE338.1 26.07,62.59 RE340.1 26.1,62.58 26.56,63.04 27.54,63.04 v1(28.67,61.92) 31.06,59.53 31.06,58.71 v2(31.06,58.67)
  IN2 w0.107: v2(31.06,58.67) 31.06,58.61 31.04,58.58 31.03,58.58 31.03,52.02 32.34,50.72 42.15,50.72 45.53,47.35 45.53,43.96 49.38,40.11 49.38,33.64 51.86,31.17 55.83,31.17 55.83,31.17 56.78,31.17 57.57,31.96 75.85,31.96 76.99,33.1 79.54,33.1 79.63,33.01 81.05,33.01 81.09,32.98 83.64,32.98 83.84,32.78 86.34,32.78 86.8,33.25 88.14,33.25 88.52,32.87 92.6,32.87 98.64,26.83 101.77,26.83 110.56,18.04 111.58,18.04 112.17,17.45 112.69,17.45 113.04,17.81 116.93,17.81 117.72,17.02 119.6,17.02 120.28,17.71 122.9,17.71 123.14,17.94 124.19,17.94 124.51,17.62 126.81,17.62 126.95,17.76 130.08,17.76 130.3,17.55 130.31,17.55 130.66,17.19 132.81,17.19 133.63,18.01 136.36,18.01 v2(136.45,18.1)
EC_TX: length 112
  TOP w0.102: v2(181.73,66.54) v1(181.22,66.54) ; RM9.1 128.83,6.11 UE1.30 131.84,6.11 132.14,6.41 132.14,6.48 133.46,7.8 136.63,7.8 v2(137.04,8.21)
  IN1 w0.107: v2(137.04,8.21) 137.39,8.56 141.26,8.56 142.09,7.73 146.61,7.73 147.86,8.97 149.75,8.97 150.78,7.94 154.39,7.94 154.77,7.56 155.7,7.56 155.92,7.56 156.12,7.36 156.13,7.36 157.03,6.46 160.2,6.46 161.28,5.38 167.56,5.38 171.76,9.58 171.76,13.07 172.52,13.83 172.52,19.11 175.29,21.88 175.29,36.7 175.71,37.12 175.71,43.33 176.51,44.13 176.51,48.18 177.86,49.53 177.86,53.52 179.56,55.22 179.56,58.8 180.2,59.44 180.2,61.98 180.79,62.56 180.79,65.61 v2(181.73,66.54)
  BOTTOM w0.102: JNGFF.30 v2(181.73,66.54)
ECAGND: length 176.3
  TOP w0.076: PH1.2 126.68,91.11 121.75,86.19 118.45,86.19 117.4,85.15 112.64,85.15 111.44,83.94 111.44,77.51 108.13,74.21
  TOP w0.102: v2(111.51,17.53) 111.51,17.66 108.26,20.91 108.26,24.82 103.82,29.27 101.91,29.27 98.66,32.52 98.66,39.53 98.8,39.67 98.8,46.63 97.43,48 95.29,48 94,49.29 v1(94,50.52) 94,53.27 98.79,58.06 98.79,65.03 101.37,67.61 101.53,67.61 108.13,74.21 ; CE7.2 126.34,17.33 v2(126.61,17.06)
  TOP w0.203: v2(148.25,4.54) 148.1,4.7 148.1,6.32 147.51,6.91 UE1.69 ; 149.29,3.99 149.29,2.94 CE9.1
  TOP w0.254: 149.29,3.99 LE2.2 148.75,4.04 v2(148.25,4.54)
  IN1 w0.203: v2(156.29,5.81) 156.17,5.68 154.08,5.68 153.96,5.55 150.56,5.55 149.55,4.54 v2(148.25,4.54)
  IN2 w0.107: v2(111.51,17.53) 111.81,17.22 112.79,17.22 113.12,17.56 116.85,17.56 117.62,16.79 119.7,16.79 120.38,17.47 123,17.47 123.23,17.71 124.1,17.71 124.47,17.33 126.34,17.33 v2(126.61,17.06)
  IN2 w0.203: v2(153.22,17.48) 151.97,17.48 151.84,17.35 149.79,17.35 148.95,18.19 146.15,18.19 145.31,17.35 141.03,17.35 140.94,17.27 138.86,17.27 138.69,17.44 137.6,17.44 137.59,17.45 133.53,17.45 133.01,16.93 130.55,16.93 129.98,17.5 127.06,17.5 v2(126.61,17.06)
  BOTTOM w0.203: v2(156.29,5.81) 156.72,6.24 156.72,9.88 155.87,10.74 155.62,10.74 155.33,11.03 155.33,13.92 154.57,14.69 154.57,15.96 153.22,17.3 v2(153.22,17.48)
EDP_AUX: length 147.8
  TOP w0.112: v2(6.2,96.19) 5.94,95.93 5.61,95.93 C4321.2
  IN2 w0.114: v2(6.2,96.19) 6.46,95.94 7.57,95.94 9.98,98.35 13.51,98.35 17.32,102.16 22.18,102.16 25.23,105.21 28.53,105.21 31.7,108.38 33.33,108.38 34.09,109.15 50.76,109.15 51.9,110.29 52.38,110.29 53.14,111.05 58.45,111.05 58.96,110.55 64.49,110.55 65.13,109.91 65.59,109.91 68.89,106.6 69.63,106.6 72.3,103.94 81.72,103.94 84.14,101.52 89.36,101.52 91.67,103.83 97,103.83 103.2,110.03 112.96,110.03 119.18,103.81 119.18,103.5 120.14,102.54 125.53,102.54 126.12,101.96 128.09,101.96 129.34,103.22 129.34,103.84 128.94,104.25 128.75,104.25 128.63,104.13 v2(128.63,103.95)
  BOTTOM w0.076: UC1.B45 128.89,101.62 128.58,101.93 128.58,102.57 129.18,103.17 129.18,104 128.92,104.26 128.72,104.26 128.63,104.17 v2(128.63,103.95)
EDP_AUX#: length 147.8
  TOP w0.112: C4322.2 5.61,95.67 5.94,95.67 v2(6.2,95.41)
  IN2 w0.114: v2(6.2,95.41) 6.48,95.69 7.68,95.69 10.08,98.1 13.62,98.1 17.43,101.91 22.28,101.91 25.33,104.96 28.63,104.96 31.81,108.13 33.43,108.13 34.2,108.9 50.86,108.9 52,110.04 52.48,110.04 53.25,110.8 58.34,110.8 58.85,110.3 64.39,110.3 65.02,109.66 65.48,109.66 68.79,106.35 69.53,106.35 72.19,103.69 81.62,103.69 84.03,101.27 89.46,101.27 91.77,103.58 97.1,103.58 103.31,109.78 112.85,109.78 118.93,103.7 118.93,103.4 120.04,102.3 125.43,102.3 126.01,101.71 128.19,101.71 129.59,103.11 129.59,103.95 129.04,104.49 128.74,104.49 v2(128.63,104.6)
  BOTTOM w0.076: v2(128.63,104.6) 128.81,104.42 128.99,104.42 129.34,104.07 129.34,103.1 128.75,102.51 128.75,102.18 UC1.A45
EDP_AUX#_C: length 3
  TOP w0.112: C4322.1 4.15,95.58 3.69,95.58 v2(3.38,95.28)
  BOTTOM w0.112: v2(3.38,95.28) 3.08,95.58 2.62,95.58 2.54,95.5 JEDP.8
EDP_AUX_C: length 3
  TOP w0.112: v2(3.41,96.07) 3.64,95.84 3.99,95.84 4.37,96.23 C4321.1
  BOTTOM w0.112: JEDP.7 2.49,96 2.65,95.84 3.18,95.84 3.41,96.07 v2(3.41,96.07)
EDP_BIA_PWM: length 402.5
  TOP w0.102: RX26.1 4.03,81.08 v2(3.52,80.57) ; v2(158.68,114.46) 158.3,114.08 v1(158.3,113.75) RC75.2 RC81.2 156.78,112.53 156.76,112.55 RC72.2
  IN1 w0.107: v2(158.68,114.46) 158.68,113.85 161.22,111.31 161.22,104.83 164.01,102.04 168.2,102.04 170.24,100 172.78,100 174.58,98.2 174.58,94.75 174.61,94.72 174.61,90.9 178.76,86.75 178.76,79.8 177.46,78.5 177.46,76.08 177.74,75.79 177.74,65.81 177.5,65.57 177.5,61.99 176.01,60.49 176.01,53.46 174.54,52 174.54,37.28 171.32,34.06 171.32,28.65 167.08,24.41 167.08,20.99 164.17,18.09 164.17,16.76 162.85,15.44 160.15,15.44 158.32,13.61 153.39,13.61 152.6,14.4 150.43,14.4 149.71,15.12 144.76,15.12 143.5,13.85 136.93,13.85 136.16,13.08 132.04,13.08 130.67,14.45 127.42,14.45 126.83,15.04 122.69,15.04 122.47,15.25 116.63,15.25 115.94,14.57 115.57,14.57 115.13,15 v2(115.12,15) ; v2(113.84,14.43) 113.35,14.43 110.85,16.92 110.85,18.77 110.06,19.56 110.06,23.83 109.61,24.28 109.61,25.33 100.75,34.18 98.64,34.18 98.63,34.2 98.62,34.19 95.64,37.17 94.87,37.17 93.34,38.7 93.34,40.49 91.66,42.17 91.66,44.74 92.26,45.34 92.26,55.31 91.21,56.36 91.21,66.02 91.5,66.3 91.5,82.22 92.77,83.49 92.77,89.46 90.35,91.88 90.35,95.56 81.43,104.48 73.3,104.48 72.67,105.11 68.11,105.11 66.24,106.98 64.02,106.98 60.61,110.39 58.71,110.39 51.68,117.42 36.66,117.42 34.59,115.35 31.03,115.35 30.41,114.74 30.41,107.34 28.66,105.59 11.23,105.59 10.09,104.45 4.88,104.45 2.08,101.65 2.08,82 3.51,80.57 v2(3.52,80.57)
  IN2 w0.107: v2(115.12,15) 114.54,14.43 v2(113.84,14.43)
  BOTTOM w0.102: JEDP.36 2.6,81.5 v2(3.52,80.57)
EDP_BKLCTL: length 14.7
  TOP w0.076: v2(153.09,105.08) 152.71,105.47 v4(152.71,106.58) 152.71,108.87 154.29,110.44 157.05,110.44 157.28,110.67 RC81.1
  BOTTOM w0.076: v2(153.09,105.08) 152.71,104.7 152.71,104.04 151.62,102.95 151.62,102.49 151.32,102.19 151.32,101.46 UC1.B8
EDP_COMP: length 2.9
  TOP w0.102: v1(144.35,101.73) 144.35,101.35 144.56,101.15 RC71.2
  TOP w0.508: v2(144.53,99.76) 144.53,100.49 RC71.2
  BOTTOM w0.254: UC1.D20 145.02,100.25 v2(144.53,99.76)
EDP_CPU_HPD: length 193.5
  IN1 w0.107: v2(33.46,114.71) 31.15,114.71 30.92,114.48 30.92,107.14 28.84,105.06 11.59,105.06 10.22,103.69 5.9,103.69 4.65,102.44 4.65,95.58 3.87,94.8 v2(3.84,94.8) ; v2(160.58,110.04) 157.92,112.7 146.36,112.7 143.69,115.37 132.14,115.37 127.69,110.93 121.47,110.93 120.83,111.56 118.17,111.56 117.53,110.93 117.53,109.66 116.52,108.64 112.2,108.64 110.04,110.8 102.8,110.8 101.4,109.4 96.07,109.4 95.31,108.64 92.64,108.64 91.24,110.04 84.51,110.04 82.35,107.88 79.05,107.88 v2(78.8,108.13)
  IN2 w0.107: v2(33.46,114.71) 37.24,114.71 37.9,115.37 40.32,115.37 40.7,114.99 43.11,114.99 43.87,115.75 54.29,115.75 55.63,114.41 66.4,114.41 69.58,111.23 69.58,110.9 70.69,109.78 72.75,109.78 74.66,107.88 78.54,107.88 v2(78.8,108.13)
  BOTTOM w0.102: RC82.1 161.11,112.83 161.11,110.57 v1(160.95,110.41) v2(160.58,110.04) ; v2(3.84,94.8) 3.79,94.75 3.51,94.75 3.1,94.34 2.67,94.34 2.51,94.5 JEDP.10
EDP_DISP_UTIL: length 31.3
  TOP w0.076: v2(146.36,103.94) 146.87,104.45 146.87,104.88 147.83,105.85 149.38,105.85 v4(151.43,107.89) 154.23,110.7 156.17,110.7 156.37,110.9 RC72.1
  IN1 w0.107: v2(130.27,102.51) 131.25,102.51 131.59,102.16 144.58,102.16 v2(146.36,103.94)
  BOTTOM w0.076: v2(130.27,102.51) UC1.A43
EDP_TX0: length 147.3
  TOP w0.112: v2(5.86,100.99) 6.1,100.76 6.1,100.05 5.54,99.48 5.28,99.48 C4312.2
  IN2 w0.114: v2(5.86,100.99) 6.13,100.73 6.13,100.13 6.66,99.6 7.78,99.6 8.41,100.24 12.48,100.24 15.93,103.69 21.52,103.69 24.31,106.48 27.77,106.48 28.4,107.11 28.4,107.83 29.12,108.54 29.93,108.54 32.28,110.89 33.68,110.89 34.09,111.31 37.27,111.31 37.64,110.93 40.95,110.93 41.3,110.58 49.87,110.58 51.24,111.94 51.99,111.94 53.16,113.11 65.87,113.11 68.21,110.77 68.21,110.55 70.35,108.41 70.77,108.41 72.57,106.61 81.74,106.61 84.92,103.44 88.58,103.44 90.35,105.21 95.91,105.21 102.06,111.36 114.64,111.36 116.77,109.22 117.4,109.22 120.46,106.17 120.46,104.6 121.14,103.92 126.83,103.92 v2(127.06,103.69)
  BOTTOM w0.076: UC1.B46 128.16,100.89 128.03,100.89 127.92,101 127.92,101.13 128.24,101.45 128.24,103.14 127.41,103.97 127.23,103.97 127.06,103.79 v2(127.06,103.69)
EDP_TX0#: length 147.3
  TOP w0.112: v2(6.65,100.99) 6.36,100.7 6.36,99.94 5.64,99.23 5.28,99.23 C4311.2
  IN2 w0.114: v2(127.06,104.32) 126.9,104.16 121.25,104.16 120.71,104.7 120.71,106.27 117.51,109.47 116.88,109.47 114.74,111.61 101.96,111.61 95.81,105.46 90.25,105.46 88.48,103.69 85.02,103.69 81.84,106.86 72.67,106.86 70.87,108.66 70.46,108.66 68.46,110.66 68.46,110.87 65.97,113.36 53.06,113.36 51.89,112.19 51.13,112.19 49.77,110.82 41.4,110.82 41.05,111.18 37.75,111.18 37.37,111.56 33.99,111.56 33.57,111.14 32.18,111.14 29.83,108.79 29.02,108.79 28.15,107.93 28.15,107.21 27.67,106.73 24.21,106.73 21.42,103.94 15.83,103.94 12.38,100.49 8.31,100.49 7.68,99.85 6.76,99.85 6.38,100.23 6.38,100.73 v2(6.65,100.99)
  BOTTOM w0.076: v2(127.06,104.32) 127.25,104.13 127.48,104.13 128.4,103.2 128.4,101.46 128.62,101.24 128.62,101 UC1.C45
EDP_TX0#_C: length 3.1
  TOP w0.112: v2(3.38,98.99) 3.63,99.24 3.72,99.24 C4311.1
  BOTTOM w0.112: JEDP.2 2.37,98.5 2.47,98.6 2.65,98.6 2.88,98.84 2.88,99.13 2.99,99.24 3.14,99.24 v2(3.38,98.99)
EDP_TX0_C: length 3.1
  TOP w0.112: C4312.1 3.74,99.5 3.66,99.5 v2(3.38,99.78)
  BOTTOM w0.112: JEDP.1 2.33,99 2.47,98.86 2.54,98.86 2.62,98.94 2.62,99.24 2.88,99.5 3.11,99.5 v2(3.38,99.78)
EDP_TX1: length 149.4
  TOP w0.112: v2(5.9,98) 5.61,97.71 5.28,97.71 C4314.2
  IN2 w0.114: v2(127.01,105.63) 127.01,105.78 127.13,105.9 127.33,105.9 127.44,105.79 127.44,103.02 127.19,102.76 126.63,102.76 126.1,103.3 120.83,103.3 113.36,110.78 102.65,110.78 96.45,104.57 90.5,104.57 88.88,102.94 84.62,102.94 81.47,106.1 72.2,106.1 70.39,107.9 70.16,107.9 68.44,109.62 67.71,109.62 67.05,110.28 67.05,110.67 65.65,112.07 52.92,112.07 52.15,111.3 51.77,111.3 50.55,110.08 41.01,110.08 40.77,110.32 32.5,110.32 28.15,105.97 24.72,105.97 21.8,103.05 16.59,103.05 12.91,99.36 9.6,99.36 8.31,98.07 6.91,98.07 6.49,97.64 6.05,97.64 5.9,97.79 v2(5.9,98)
  BOTTOM w0.076: UC1.B47 127.76,101.62 128.07,101.93 128.07,102.37 127.73,102.71 126.96,102.71 126.6,103.07 126.6,105.76 126.69,105.86 126.78,105.86 v2(127.01,105.63)
EDP_TX1#: length 149.4
  TOP w0.112: v2(5.9,97.21) 5.66,97.45 5.28,97.45 C4313.2
  IN2 w0.114: v2(127.01,106.27) 127.13,106.15 127.44,106.15 127.69,105.9 127.69,102.92 127.29,102.52 126.53,102.52 125.99,103.05 120.73,103.05 113.25,110.53 102.76,110.53 96.55,104.32 90.61,104.32 88.98,102.69 84.52,102.69 81.37,105.85 72.09,105.85 70.29,107.65 70.06,107.65 68.34,109.37 67.61,109.37 66.8,110.18 66.8,110.56 65.54,111.82 53.02,111.82 52.25,111.05 51.87,111.05 50.65,109.83 40.9,109.83 40.67,110.07 32.6,110.07 28.25,105.72 24.82,105.72 21.9,102.8 16.69,102.8 13.01,99.12 9.71,99.12 8.41,97.82 7.02,97.82 6.59,97.39 6.08,97.39 v2(5.9,97.21)
  BOTTOM w0.076: UC1.A47 127.91,102.18 127.91,102.3 127.66,102.54 126.89,102.54 126.43,103 126.43,105.83 126.63,106.02 126.77,106.02 v2(127.01,106.27)
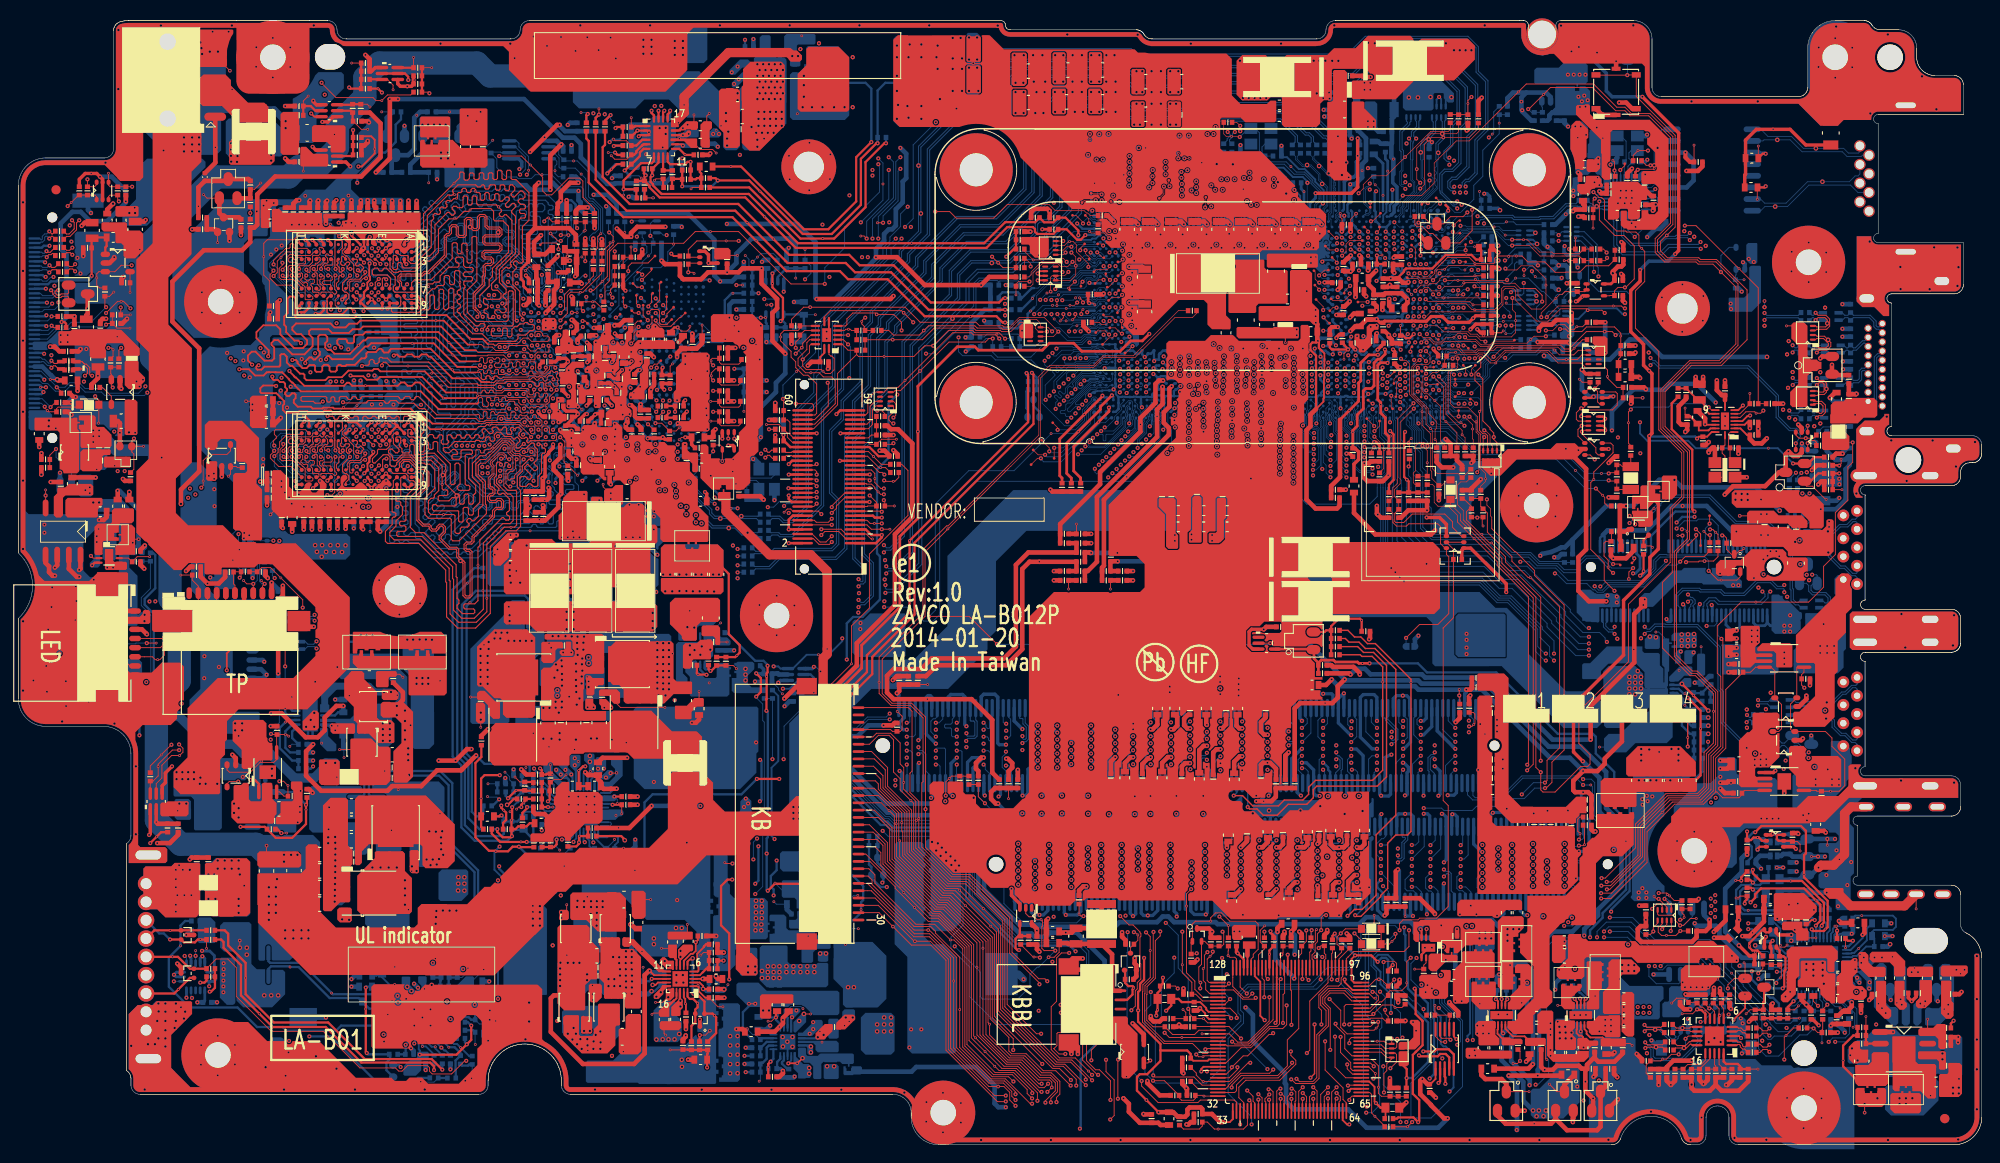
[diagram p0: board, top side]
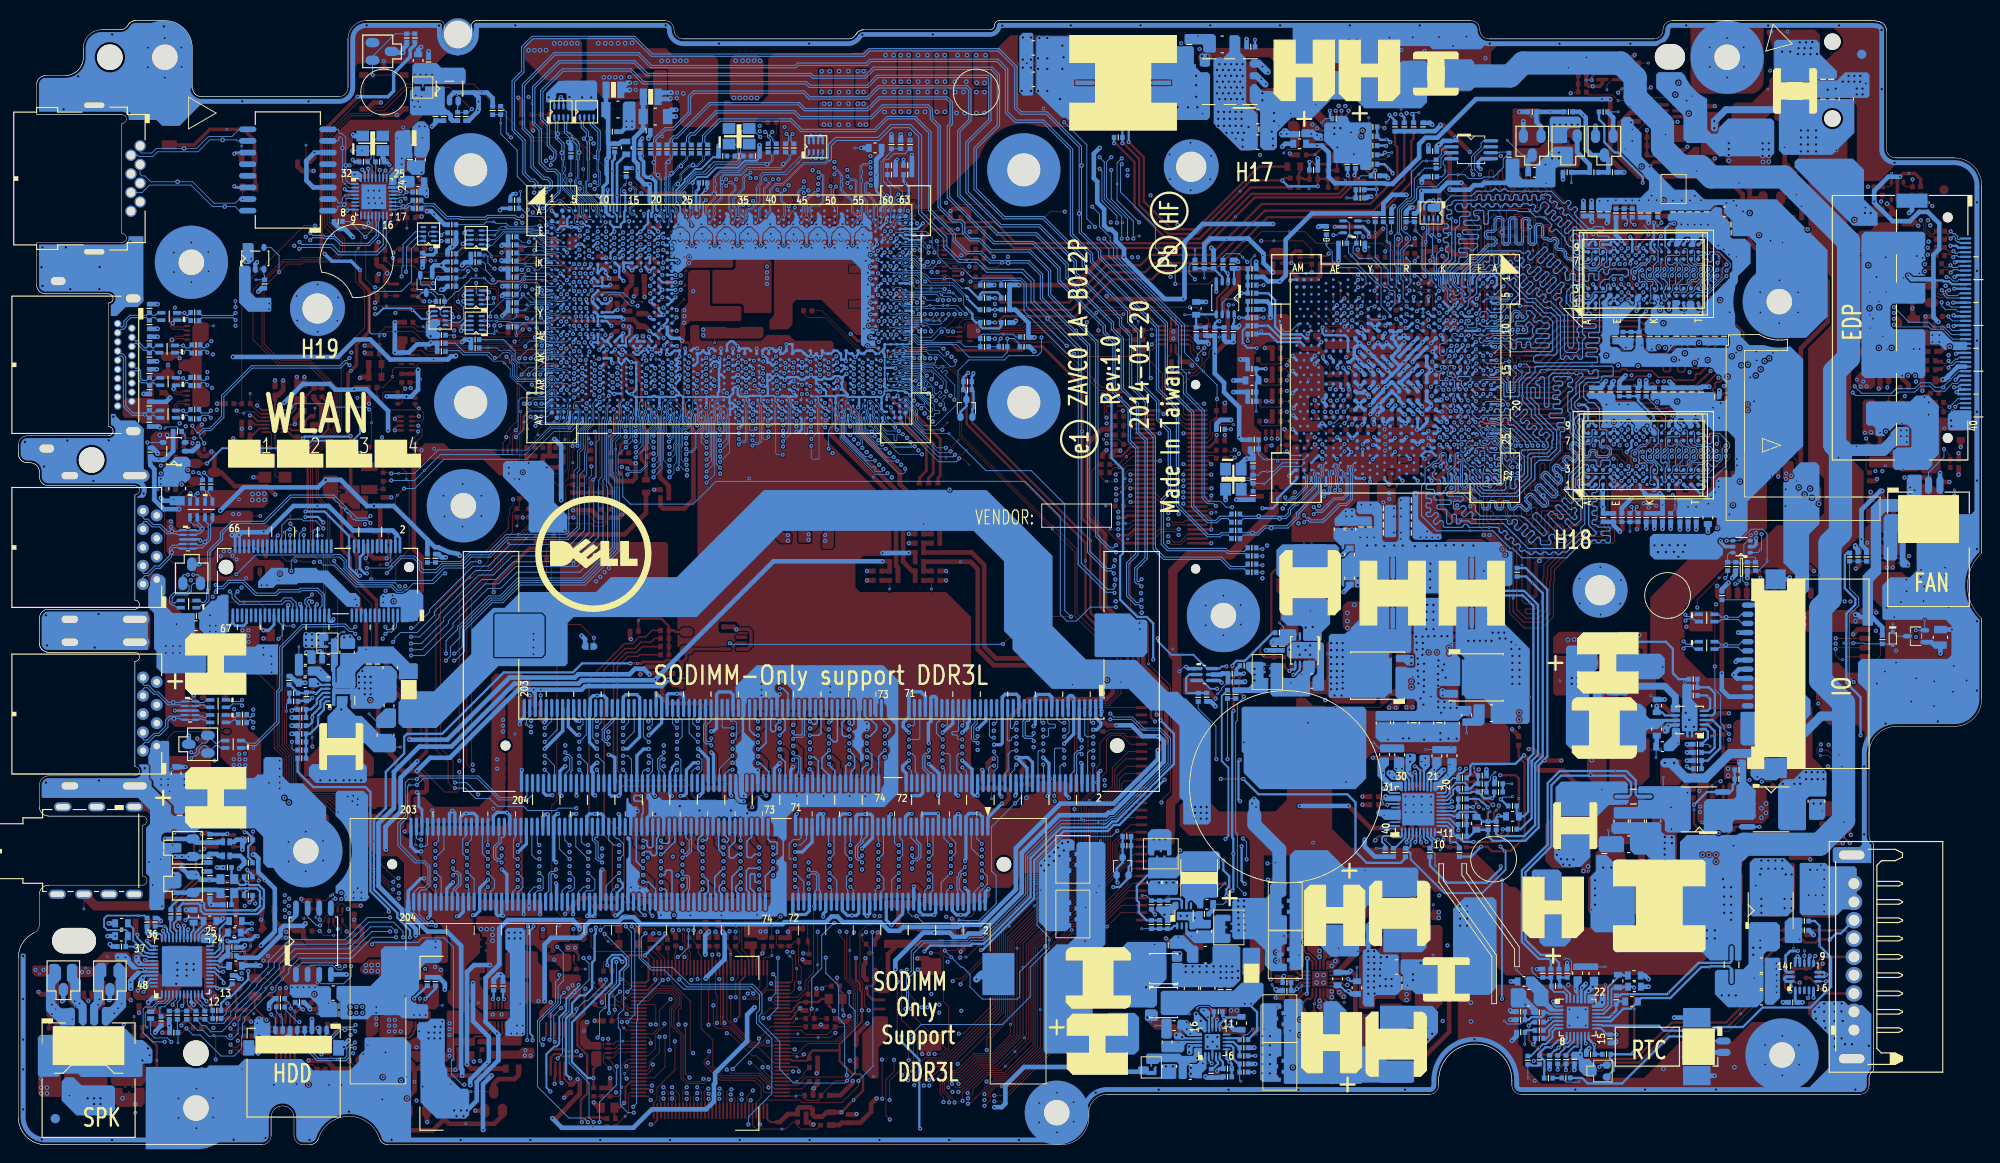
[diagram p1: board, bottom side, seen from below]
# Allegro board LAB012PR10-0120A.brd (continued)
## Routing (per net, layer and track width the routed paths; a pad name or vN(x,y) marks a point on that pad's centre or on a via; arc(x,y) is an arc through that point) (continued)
EDP_TX1#_C: length 2.7
  TOP w0.112: v2(3.1,96.96) 3.1,97.01 3.33,97.23 3.58,97.23 3.71,97.36 3.82,97.36 C4313.1
  BOTTOM w0.112: v2(3.1,96.96) 2.94,97.12 2.68,97.12 2.56,97 JEDP.5
EDP_TX1_C: length 2.7
  TOP w0.112: v2(3.08,97.62) 3.21,97.49 3.48,97.49 4.01,98.02 C4314.1
  BOTTOM w0.112: v2(3.08,97.62) 2.84,97.38 2.68,97.38 2.56,97.5 JEDP.4
EN_0.675VSP: length 4.9
  BOTTOM w0.102: PR202.2 81.03,7.07 v1(80.91,6.94)
  BOTTOM w0.254: PR202.2 PC203.1 81.16,8.95 81.29,8.95 81.72,9.38 81.72,10.6 81.95,10.83 PU200.7
EN_1.35V: length 2.6
  BOTTOM w0.254: PR201.2 PC202.1 81.08,10.6 81.72,11.23 PU200.8
EN_+1.35VGPUP: length 7.9
  BOTTOM w0.254: PR1103.2 PC1104.1 29.9,41.97 28.56,43.31 28.56,45.55 v1(29.18,46.17) 29.4,46.39 PU1100.3
EN_DFAN1: length 275.2
  TOP w0.102: v1(2.98,71.53) v2(2.98,70.92) UE3.4 ; UE1.70 144.95,7.31 143.78,8.48 v2(143.78,11.8)
  IN1 w0.107: v2(143.78,11.8) 143.78,12.17 143.45,12.5 138.42,12.5 138.05,12.87 131.95,12.87 130.58,14.24 124.82,14.24 124.35,14.71 122.9,14.71 122.45,14.26 122.11,14.26 122.11,14.27 121.34,14.27 120.66,14.95 118.27,14.95 117.75,14.43 117.7,14.43 117.7,14.43 117.36,14.43 117.36,14.43 117.12,14.43 117.12,14.43 116.78,14.43 116.78,14.43 116.47,14.43 116.29,14.25 114.99,14.25 114.41,14.84 113.27,14.84 111.09,17.01 111.09,18.89 110.32,19.66 110.32,23.94 109.84,24.42 109.84,25.45 100.87,34.42 98.74,34.42 95.72,37.44 94.96,37.44 93.59,38.8 93.59,39 93.59,39 93.59,40.57 91.89,42.27 91.89,44.64 92.51,45.26 92.51,68.25 91.75,69.02 91.75,82.1 93.02,83.37 93.02,90.48 90.61,92.89 90.61,95.69 81.58,104.71 73.4,104.71 72.76,105.35 68.2,105.35 66.34,107.21 64.11,107.21 60.63,110.7 58.74,110.7 51.79,117.65 36.56,117.65 34.51,115.61 30.9,115.61 30.16,114.86 30.16,107.47 28.53,105.85 11.11,105.85 9.96,104.7 4.76,104.7 1.85,101.8 1.85,72.05 v2(2.98,70.92)
EN_INVPWR: length 247.8
  TOP w0.102: v2(12.63,77.14) 12.39,76.91 QX1.2 ; QX1.2 v1(13.67,76.29) ; QX1.2 12.39,75.68 12.62,75.46 12.62,73.79 RX41.1 ; UE1.68 145.24,6.51 v2(145.19,6.46)
  IN1 w0.107: v2(12.63,77.14) 12.88,77.14 15.42,79.68 15.42,97.46 16.95,98.99 21.14,98.99 22.03,99.88 25.87,99.88 28.41,102.42 29.32,102.42 35.29,108.39 40.57,108.39 41.1,108.92 48.9,108.92 49.69,109.71 53.45,109.71 56.04,107.12 56.9,107.12 61.11,102.9 61.11,102.66 62.1,101.67 62.99,101.67 63.85,100.8 65.65,100.8 66.26,100.2 67.51,100.2 68.13,100.82 76.54,100.82 77.4,99.95 78.49,99.95 82.78,95.66 82.78,95.61 83.88,94.52 83.88,93.83 85.15,92.56 85.15,90.73 85.4,90.48 85.4,86.29 84.51,85.4 84.51,83.11 86.16,81.46 86.16,78.92 85.91,78.67 85.91,68.89 85.15,68.13 85.15,65.08 84.77,64.7 84.77,62.41 87.06,60.12 87.06,53.93 85.65,52.53 85.65,39.3 87.43,37.52 87.43,36.24 88.68,34.99 90.2,34.99 94.94,30.26 95.71,30.26 100.75,25.22 102.01,25.22 102.78,24.45 103.29,24.45 104.85,22.9 104.85,14.8 109.87,9.77 110.35,9.77 110.66,9.46 112.1,9.46 112.82,8.74 113.33,8.74 113.58,8.5 118.67,8.5 118.9,8.27 124.24,8.27 124.75,8.78 126.9,8.78 128.48,7.2 130.52,7.2 130.7,7.39 138.35,7.39 138.77,7.8 140.11,7.8 140.34,7.57 140.34,7.01 140.67,6.68 144.96,6.68 v2(145.19,6.46)
EN_PCIE: length 1.3
  BOTTOM w0.102: v1(76.69,57) 76.23,56.54 PR1300.2
ENABLE: length 4.3
  BOTTOM w0.102: v1(59.62,30.43) 59.7,30.51 59.7,31.83 PR1027.2
  BOTTOM w0.203: PU1000.8 60.52,33.65 60.11,33.24 60,33.13 60,32.62 60.03,32.62 PR1027.2
ENVDD_PCH: length 181
  TOP w0.102: v2(11.23,87.05) 10.98,86.8 RX7.2
  IN1 w0.107: v2(154.11,105.97) 151.57,108.51 133.28,108.51 132.77,109.02 126.42,109.02 125.53,109.91 119.31,109.91 117.02,107.62 111.69,107.62 109.53,109.78 103.31,109.78 101.91,108.39 94.54,108.39 v2(93.91,107.75)
  IN2 w0.107: v2(11.23,87.05) 11.11,87.18 11.11,90.61 11.74,91.24 11.74,91.5 13.01,92.77 14.03,92.77 19.49,98.23 24.06,98.23 28.76,102.93 29.65,102.93 32,105.27 35.3,105.27 36.19,106.16 37.97,106.16 38.41,105.72 40.06,105.72 40.82,104.96 51.34,104.96 54.31,107.93 56.42,107.93 58.25,106.1 62.54,106.1 66.73,101.91 67.37,101.91 70.54,98.73 72.7,98.73 74.1,100.13 81.21,100.13 82.91,98.43 89.67,98.43 v2(92,100.77)
  BOTTOM w0.076: UC1.C6 152.72,101.2 152.72,101.51 152.91,101.7 152.91,102.87 154.49,104.45 154.49,105.59 v2(154.11,105.97) 154.06,106.02 154.06,107.62
  BOTTOM w0.102: v2(92,100.77) 94.42,103.18 v1(94.42,104.96) 94.42,107.24 v2(93.91,107.75) ; RC87.2 154.06,107.62
ENVDD_R: length 25.3
  TOP w0.102: UX4.4 23.17,75.8 22.78,75.41 20.85,75.41 20.19,74.74 v1(20.19,72.5) 20.19,71.99 v2(19.98,71.78) ; RX7.1 RX8.1 10.09,84.23 10.16,84.16 UX1.3 10.16,82.87 v2(10.31,82.72)
  IN2 w0.107: v2(19.98,71.78) 19.98,72.04 10.31,81.71 v2(10.31,82.72)
ERP_LOT6: length 204.7
  TOP w0.102: UE1.73 147.46,8.51 v1(148.19,7.78) 148.19,7.43 v2(147.97,7.22)
  TOP w0.254: PQ1.2 36.43,108.01 PC5.1 PR2.1 PR1.2 v2(36.56,110.85)
  IN1 w0.107: v2(36.56,110.85) 36.56,109.61 37.52,108.64 40.44,108.64 41.08,109.28 48.82,109.28 49.59,110.04 53.47,110.04 56.14,107.37 56.97,107.37 61.31,103.03 62.1,103.03 64.09,101.04 65.75,101.04 66.36,100.43 67.36,100.43 68,101.07 77.86,101.07 84.18,94.75 84.18,93.98 85.4,92.77 85.4,90.86 85.65,90.61 85.65,86.54 86.67,85.53 86.67,79.05 86.16,78.54 86.16,68.76 85.4,68 85.4,64.95 85.02,64.57 85.02,62.54 87.29,60.27 87.29,51.6 85.91,50.22 85.91,39.43 87.69,37.65 87.69,36.44 88.9,35.23 90.3,35.23 95.03,30.49 95.81,30.49 100.85,25.45 102.11,25.45 102.88,24.69 103.39,24.69 105.08,23 105.08,14.91 109.09,10.89 109.1,10.89 109.99,10.01 110.45,10.01 110.76,9.69 112.2,9.69 112.92,8.98 113.43,8.98 113.66,8.75 118.96,8.75 119.18,8.53 124.16,8.53 124.65,9.01 126.96,9.01 128.57,7.41 130.35,7.41 130.53,7.59 138.25,7.59 138.72,8.06 140.29,8.06 140.57,7.78 140.57,7.17 140.82,6.91 147.67,6.91 v2(147.97,7.22)
FAN_SPEED1: length 263.4
  TOP w0.102: RE50.2 CE24.1 3.44,75.32 v2(4.12,76) ; v2(134.52,8.95) 134.3,8.95 132.26,6.91 UE1.28 130.99,6.91 v1(129.39,6.91) 129.32,6.91 128.63,7.6 128.63,7.83 CE29.1
  IN1 w0.107: v2(134.52,8.95) 133.78,8.95 133.46,9.26 133.43,9.26 132.24,10.45 130.5,10.45 129.8,11.15 118.07,11.15 117.1,12.12 116.36,12.12 115.36,11.12 113.42,11.12 112.98,11.56 111.53,11.56 111.22,11.88 110.77,11.88 106.97,15.68 106.97,23.76 104.17,26.56 103.97,26.56 103.65,26.56 102.89,27.32 101.63,27.32 94.8,34.15 94.8,34.45 94.56,34.69 94.01,34.69 89.7,39 89.7,40 88.7,41 88.7,48.82 90.99,51.11 90.99,54.88 89.96,55.91 89.96,66.78 90.23,67.05 90.23,85.78 91.5,87.05 91.5,88.83 89.08,91.24 89.08,94.92 85.27,98.73 83.5,98.73 78.92,103.31 67.8,103.31 67.14,103.97 66.27,103.97 66.24,103.94 65.2,103.94 62.36,106.78 60.65,106.78 51.55,115.88 43.62,115.88 42.86,115.12 41.08,115.12 40.32,115.88 37.32,115.88 34.52,113.09 31.81,113.09 31.43,112.7 31.43,106.89 28.99,104.45 17.97,104.45 13.15,99.64 11.25,99.64 8.95,97.34 8.95,92.77 8.06,91.88 8.06,86.29 9.2,85.15 9.2,83.93 8.64,83.37 7.8,83.37 6.91,82.48 6.91,80.19 6.03,79.3 6.03,76.76 5.26,76 v2(4.12,76)
  BOTTOM w0.102: v2(4.12,76) 4.12,75.11 5.8,73.43 JFAN.2
FB_1.8VSP: length 4
  BOTTOM w0.102: v1(91.73,23.6) PC604.2
  BOTTOM w0.254: PU600.1 88.17,23.91 88.48,23.6 PR602.1 PR603.2 PC604.2
FB_1.35V: length 5
  TOP w0.254: v2(82.15,9.07) 81.9,8.82 v1(81.9,8.46) PC214.1
  BOTTOM w0.254: PC214.1 PR207.1 81.9,8.82 v2(82.15,9.07) 82.45,9.38 PU200.6
FB_3V: length 4.8
  TOP w0.102: v1(74.53,20.71) 74.82,21 PR107.2
  TOP w0.203: PU100.4 74.42,18.51 74.73,18.82
  TOP w0.254: PR107.2 PC102.2 PR109.2 75.13,19.22 74.73,18.82
FB_5V: length 4.7
  TOP w0.203: PU100.2 74.4,17.71 74.78,17.33 v3(74.78,17.02)
  TOP w0.254: v3(74.78,17.02) 74.81,17 PR104.1
  BOTTOM w0.102: v3(74.78,17.02) 74.62,17.02 v1(74.22,17.42)
  BOTTOM w0.254: PR106.1 PC108.1 75.42,16.69 75.11,16.69 v3(74.78,17.02)
FB_+1.35VGPUP: length 6.6
  BOTTOM w0.254: PU1100.4 29.42,46.89 29.14,47.17 v1(29.14,47.65) 29.14,49.33 29.77,49.97 PR1108.1 PR1107.1
FB_GND: length 1.7
  TOP w0.102: RV158.1 69.83,79.48 v2(70.41,80.07)
  BOTTOM w0.102: UV1.AD20 70,80.48 v2(70.41,80.07)
FB_PCIE: length 5.1
  TOP w0.102: v1(78.42,52) 78.06,52.35 PC1306.2
  TOP w0.254: PR1301.1 75.37,51.97 v2(75.58,51.75) 75.66,51.75 PR1302.2 PC1306.2
  BOTTOM w0.254: PU1300.6 74.95,52.03 75.06,51.92 75.42,51.92 v2(75.58,51.75)
FB_VDDC: length 1.5
  TOP w0.102: RV159.1 69.83,80.24 v2(69.65,80.07)
  BOTTOM w0.102: v2(69.65,80.07) 69.2,80.52 UV1.AC20
FB_VDDCI: length 5.1
  TOP w0.102: T222.1 68.76,96.32 66.99,96.32 66.6,95.94 v2(66.6,95.43)
  BOTTOM w0.102: v2(66.6,95.43) 66.6,95.1 66,94.5 UV1.W1
FFS_INT1: length 286.1
  IN1 w0.076: 158.73,96.55 158.71,96.52 v2(158.71,95.57)
  IN1 w0.107: v2(7.18,55.47) 6.9,55.47 5.15,57.22 5.15,66.31 1.15,70.31 1.15,102.14 5.4,106.39 10.22,106.39 10.69,106.85 27.73,106.85 28.14,107.27 28.14,114.91 30.13,116.89 34.81,116.89 36.27,118.36 52.16,118.36 58,112.52 59.8,112.52 64.41,107.91 66.63,107.91 67.77,106.77 72.33,106.77 72.89,106.21 76.97,106.21 77.77,105.41 81.92,105.41 84.01,103.32 88.43,103.32 90.46,105.36 98.64,105.36 103.27,100.73 106.77,100.73 107.94,101.89 107.96,101.89 108.12,102.05 108.12,102.07 111.09,105.04 119.45,105.04 121.93,102.56 128.8,102.56 129.42,103.17 132.76,103.17 133.47,103.87 137.85,103.87 140.5,106.52 146.29,106.52 147.06,105.76 147.72,105.76 149.05,104.44 149.05,103.79 151.48,101.36 154.76,101.36 155.07,101.05 157.7,101.05 158.37,100.38 158.37,99.48 159.15,98.7 159.15,96.97 158.73,96.55
  IN2 w0.107: v2(19.36,20.63) 19.65,20.92 19.65,33.19 15.4,37.44 15.4,45.54 7.18,53.76 v2(7.18,55.47)
  BOTTOM w0.076: RC79.2 159.59,95.17 159.11,95.17 v2(158.71,95.57) 158.35,95.22 156.11,95.22 155.71,94.82 UC1.N2
  BOTTOM w0.102: US3.11 v2(19.36,20.63) v1(19.36,21.2)
FFS_INT2: length 284.7
  IN1 w0.107: v2(7.2,56.2) 5.38,58.03 5.38,66.41 1.38,70.41 1.38,102.04 5.49,106.15 10.32,106.15 10.79,106.62 27.83,106.62 28.38,107.17 28.38,114.81 30.22,116.66 34.9,116.66 36.37,118.12 52.06,118.12 57.89,112.29 59.7,112.29 64.31,107.68 66.53,107.68 67.67,106.54 72.23,106.54 72.79,105.98 76.87,105.98 77.67,105.18 81.83,105.18 83.92,103.09 88.53,103.09 90.56,105.12 98.54,105.12 103.17,100.49 106.87,100.49 108.04,101.66 108.06,101.66 108.35,101.95 108.35,101.98 111.19,104.81 119.35,104.81 121.84,102.32 128.9,102.32 129.52,102.94 132.86,102.94 133.56,103.64 137.96,103.64 140.57,106.25 146.16,106.25 147,105.41 147.75,105.41 148.81,104.34 148.81,103.69 151.35,101.16 154.68,101.16 154.98,100.86 157.6,100.86 158.07,100.38 158.07,99.18 v2(158.63,98.62)
  IN2 w0.107: v2(18.17,20.62) 18.17,21.32 19.39,22.55 19.39,33.12 15.16,37.34 15.16,45.45 6.7,53.91 6.7,55.7 v2(7.2,56.2)
  BOTTOM w0.076: UC1.G2 155.6,97.81 155.89,98.1 156.63,98.1 157.8,99.27 158.38,99.27 158.63,99.01 v2(158.63,98.62) 158.65,98.59 159.42,98.59 RC115.2
  BOTTOM w0.102: US3.9 18.36,20.42 v2(18.17,20.62) ; v1(6.22,57.32) QS1.3 v2(7.2,56.2)
FFS_INT2_CONN: length 213.2
  TOP w0.102: v1(15.05,54.8) v2(14.03,54.8)
  IN2 w0.107: v2(14.03,54.8) 14.99,55.75 19.56,55.75 25.01,50.31 27.73,50.31 28.78,49.25 28.78,42.37 30.26,40.89 47.27,40.89 48.53,39.63 48.53,33.17 51.71,30 56.95,30 58.06,31.11 76.21,31.11 77.35,32.25 79.05,32.25 79.72,31.57 80.46,31.57 80.77,31.26 82.12,31.26 82.54,31.69 82.88,31.69 82.88,31.69 83.07,31.69 83.4,31.37 90.56,31.37 90.57,31.36 90.87,31.36 96.93,25.3 101.11,25.3 107.83,18.58 107.83,17.65 109.75,15.73 114.25,15.73 114.47,15.51 114.71,15.51 114.85,15.65 116.1,15.65 116.24,15.51 117.29,15.51 117.3,15.52 120.73,15.52 121.05,15.83 122.01,15.83 122.01,15.84 125.63,15.84 126.03,15.44 129.14,15.44 129.62,14.96 133.49,14.96 133.88,14.57 134.83,14.57 135.08,14.82 141.41,14.82 141.55,14.68 146.85,14.68 147.29,15.12 148.29,15.12 149.47,13.94 152.87,13.94 153.17,13.64 157.21,13.64 159.37,11.49 167.82,11.49 169.98,9.33 178.67,9.33 183.56,14.22 v2(186.77,14.22)
  BOTTOM w0.102: v2(186.77,14.22) 186.33,13.78 JHDD.8 ; DS1.2 10.27,54.6 10.38,54.72 RS32.2 12.77,54.72 12.85,54.8 v2(14.03,54.8)
GCLK_VRTC: length 5.5
  TOP w0.203: RG1.2 RG4.2 183.38,81.37 CG5.1 184.13,80.81 184.13,80.36 184.64,79.85 UG1.10
GPIO19_CTF: length 8.4
  BOTTOM w0.102: UV1.M2 60.25,94.25 60.25,94.94 61.12,95.81 61.12,99.14 v1(61.78,99.8) 61.78,100.69 61.91,100.82 RV152.1 RV151.2
GPIO27: length 5.5
  TOP w0.076: v1(156.95,86.57) 156.37,86.57 RC105.1 155.96,85.93 155.76,85.73 RC38.2 154.97,84.36 154.43,84.36 154.34,84.27 v2(153.73,83.66)
  BOTTOM w0.076: v2(153.73,83.66) 153.49,83.89 153.43,83.96 UC1.AN5
GPIO28: length 9.5
  TOP w0.102: v2(62.49,93.32) 62.79,93.32 v1(63.76,94.29) 64.32,94.85 64.32,97.66 64.95,98.3 64.95,99.23 v2(64.52,99.66)
  BOTTOM w0.102: RV21.2 64.45,99.74 v2(64.52,99.66) ; v2(62.49,93.32) 62.49,93.21 62.8,92.9 UV1.R5
GPU_B+:
  vias: v1(57.94,43.46) v2(64.83,44.25) v3(57.33,44.35) v3(58.22,44.35) v3(59.11,44.96) v3(59.11,44.25) v3(60.89,44.25) v3(62.54,44.38) v3(63.18,44.38)
GPU_VID1: length 32.6
  IN2 w0.102: v2(62.8,90.72) 63.42,90.72 64.14,91.44 64.14,92.71 65.21,93.78 66.6,93.78 67.11,93.27 70.16,93.27 72.57,95.69 77.91,95.69
  IN2 w0.107: v2(85.91,94.54) 84.77,95.69 82.61,95.69 81.34,96.96 81.08,96.96 80.7,96.58 80.7,96.07 80.32,95.69 77.91,95.69
  BOTTOM w0.102: UV1.P8 62.58,90.5 v2(62.8,90.72) ; v2(85.91,94.54) 86.54,95.18 86.54,96.02 RV76.1 v1(85.91,97.79)
GPU_VID1_GPIO_20: length 4.9
  BOTTOM w0.102: v1(84.89,94.67) RV72.1
  BOTTOM w0.254: U1.3 82.93,94.79 RV74.2 RV72.1 RV76.2
GPU_VID3: length 24
  IN2 w0.102: v2(61.93,94.94) 62.81,94.06 70.44,94.06 72.32,95.94 77.91,95.94
  IN2 w0.107: v2(80.19,96.45) 79.69,95.94 77.91,95.94
  BOTTOM w0.102: RV75.1 82.86,96.96 82.48,97.34 81.08,97.34 v1(80.71,96.97) v2(80.19,96.45) ; UV1.N1 61.63,94.94 v2(61.93,94.94)
GPU_VID3_GPIO_15: length 9.5
  TOP w0.254: v2(82.35,95.18) v1(82.35,94.09) 82.35,93.65 83.5,92.51 83.5,90.23 v2(83.24,89.97)
  BOTTOM w0.254: U1.2 82.28,95.11 v2(82.35,95.18) 82.86,95.69 RV75.2 ; v2(83.24,89.97) 83.5,89.97 83.75,89.72 RV71.1 RV73.2
H_CATERR#: length 10.9
  TOP w0.076: RC58.2 110.37,94.8 110.6,95.03 110.6,95.33 111.72,96.45 v2(113.84,96.45)
  BOTTOM w0.076: UC1.K61 118.56,96.64 118.03,96.64 117.8,96.41 117.8,96.23 117.63,96.06 117.28,96.06 117.02,96.32 116.69,96.32 116.13,95.76 114.53,95.76 v2(113.84,96.45)
H_CPU_SVIDALRT#: length 10.7
  BOTTOM w0.076: 110.93,92.77 112.32,94.16 114.74,94.16 115.37,94.8 115.51,94.8 116.03,95.31 117.63,95.31 117.92,95.6 UC1.L62
  BOTTOM w0.254: R254.1 109.53,91.22 v1(110.75,92.43) 110.75,92.59 110.93,92.77
H_CPU_SVIDCLK: length 14.7
  BOTTOM w0.076: 110.93,91.47 111.21,91.75 111.21,92.76 112.36,93.91 115.63,93.91 115.81,94.09 115.81,94.47 116.28,94.94 117.44,94.94 117.51,94.86 UC1.N63
  BOTTOM w0.254: C5212.1 107.07,89.41 107.3,89.18 109.1,89.18 109.35,89.44 R248.2 109.81,89.82 110.22,90.23 110.22,90.76 v1(110.53,91.08) 110.93,91.47
H_CPU_SVIDDATA: length 12.6
  BOTTOM w0.076: UC1.L63 117.42,95.51 115.96,95.51 115.55,95.1 115.29,95.1 114.81,94.62 v1(113.26,94.62) 112.4,94.62 111.36,93.58 110.93,93.58
  BOTTOM w0.254: R256.2 107.07,92.71 107.47,93.12 109.15,93.12 109.35,92.92 R257.1 109.58,92.49 110.67,93.58 110.93,93.58
H_CPUPWRGD: length 66.8
  TOP w0.102: v2(94.54,72.57) 94.65,72.47 v1(95.55,72.47) 95.73,72.47 96.15,72.89 RC48.1
  IN1 w0.107: v2(113.09,102.9) 112.93,102.75 110.88,102.75 107.63,99.5 95.05,99.5 94.04,98.48 92,98.48 91.37,97.85 91.37,97.08 92.17,96.28 92.17,93.59 94.54,91.22 94.54,79.94 93.53,78.92 93.53,74.48 94.16,73.84 94.16,72.95 v2(94.54,72.57)
  IN2 w0.076: v2(118.31,103.18) 117.79,102.66 113.33,102.66 v2(113.09,102.9)
  BOTTOM w0.076: UC1.C61 119.14,101.22 119.15,101.24 119.15,101.83 119.08,101.9 119.08,102.26 118.31,103.04 v2(118.31,103.18) 117.85,103.63 117.85,104.13 118.24,104.53 118.62,104.53 119.51,105.41 RC66.1 CC27.1
H_PROCHOT#: length 200
  TOP w0.203: PQ2.6 32.33,112.31 v2(31.98,112.65)
  TOP w0.254: RE44.2 109.2,22.79 108.9,22.48 108.9,21.47 109.1,21.26 v2(109.28,21.26) ; RE44.2 109.36,22.88 UE2.4 ; RE44.2 CE19.1 ; CC42.1 RC60.2 RC67.1 108.72,97.85 v2(107.88,97.01)
  IN1 w0.203: 89.97,55.3 v2(89.97,55.31) ; 89.97,55.3 89.66,55.62 89.66,67.07 89.81,67.23 89.81,70.32 89.21,70.92 89.21,78.8 89.85,79.43 89.85,85.91 91.12,87.18 91.12,88.7 88.58,91.24 v2(88.58,94.8) 84.94,98.43 83.29,98.43 78.69,103.03 65.71,103.03 62.24,106.5 60.53,106.5 51.56,115.47 43.72,115.47 42.98,114.74 40.82,114.74 40.09,115.47 37.45,115.47 34.63,112.65 v2(31.98,112.65) ; 89.97,55.3 89.97,54.46 89.67,54.16 89.67,50.3 88.32,48.95 88.32,40.78 v2(89.22,39.88)
  IN1 w0.254: v2(107.88,97.01) 107.85,97.01 107.02,97.85 92.89,97.85 92.13,97.08 v2(92.13,96.96)
  IN2 w0.203: v2(83.5,49.81) 83.5,51.24 v2(82.48,52.25)
  IN2 w0.254: v2(92.13,96.96) 89.97,94.8 v2(88.58,94.8)
  BOTTOM w0.203: v2(83.5,49.81) 84.23,49.81 85.13,50.71 PQ3.3 ; v2(89.97,55.31) 89.97,55.01 88.49,53.52 v1(87.38,53.52) 86.09,53.52 84.58,52.01 PQ3.6 83.23,52.01 82.99,52.25 v2(82.48,52.25)
  BOTTOM w0.254: v2(109.28,21.26) 109.11,21.26 103.47,26.9 103.47,31.03 100.25,34.26 95.45,34.26 94.77,34.93 94.18,34.93 v2(89.22,39.88)
H_PROCHOT#_R: length 9
  TOP w0.076: RC67.2 109.86,97.62 v1(110.83,96.65) 111.68,96.65 111.74,96.7 112.83,96.7 112.96,96.83 114.1,96.83 v2(114.48,96.45)
  BOTTOM w0.076: v2(114.48,96.45) 114.94,95.99 116.06,95.99 116.64,96.58 117.06,96.58 117.28,96.35 UC1.K63
H_THERMTRIP#: length 7.3
  BOTTOM w0.076: 117.28,102.8 117.67,102.4 117.67,101.85 117.88,101.64 118.3,101.64 118.49,101.45 118.49,101.24 118.83,100.9 118.83,100.69 119.29,100.24 UC1.D60
  BOTTOM w0.254: 117.28,102.8 117.15,102.93 117.15,104.65 v1(117.53,105.03) 117.74,105.24 R2346.2
H_VCCST_PWRGD_XDP: length 4.6
  TOP w0.102: RC48.2 94.7,73.97 v1(94.16,73.97) 93.99,73.97 92.74,75.21 JXDP1.39
H_VR_READY: length 57.2
  TOP w0.076: v2(117.02,110.42) v1(117.02,109.78)
  TOP w0.254: PR519.2 66.99,110.16 v2(67.61,110.79) PU501.2
  IN1 w0.107: v2(117.02,110.42) 110.8,110.42 110.17,111.05 102.67,111.05 101.28,109.66 95.94,109.66 95.18,108.89 93.15,108.89 91.62,110.42 84.26,110.42 82.1,108.26 79.56,108.26 79.18,108.64 78.29,108.64 77.27,107.62 74.48,107.62 73.72,108.39 70.29,108.39 67.89,110.79 v2(67.61,110.79)
  BOTTOM w0.102: R251.1 v2(117.02,110.42)
HDA_SPKR: length 135.7
  TOP w0.203: v2(187.29,13.64) 188.56,14.91 DA8.3
  IN1 w0.203: v2(162.24,90.48) 162.24,90.35 162.62,89.97 163.76,89.97 164.32,89.41 167.24,89.41 167.51,89.14 167.51,87.99 169.86,85.65 169.86,77.02 169.47,76.64 169.47,72.83 169.95,72.35 169.95,65.41 168.99,64.45 168.99,38.82 167.63,37.46 167.63,36.48 166.64,35.49 163.65,35.49 161.98,33.81 161.32,33.81 160.46,32.95 160.46,27.08 158.14,24.76 v2(158.14,23.88)
  IN2 w0.203: v2(158.25,11.41) 158.25,11.32 158.72,10.85 167.57,10.85 169.65,8.77 179.01,8.77 181.3,11.06 182.31,11.06 184.89,13.64 v2(187.29,13.64)
  BOTTOM w0.076: UC1.V2 155.6,91.82 155.94,91.48 156.21,91.48 156.54,91.81 158.44,91.81 v1(159.05,91.2) 159.14,91.11 RC121.2 160,90.52 160.32,90.2 161.96,90.2 v2(162.24,90.48)
  BOTTOM w0.203: v2(158.14,23.88) 158.14,23.75 158.53,23.36 158.53,12.16 158.25,11.88 v2(158.25,11.41)
HDD_A0_PRE0: length 5.6
  TOP w0.102: v1(180.55,15.47) 181.08,16.01 181.92,16.01 RS27.2 183.24,15.55 RS24.1 183.76,15.03 183.93,15.03 184.72,14.23 US2.9
HDD_A0_PRE1: length 2.8
  TOP w0.102: RS23.1 RS30.2 185.72,8.78 US2.19
HDD_B0_EQ: length 9
  TOP w0.102: US2.13 182.36,11.87 v2(182.06,11.57) ; v2(181.31,9.87) 180.51,9.87 179.98,9.35 v1(179.56,9.35) 179.37,9.15 RS37.1 177.76,8.69 177.76,7.81 RS38.1
  BOTTOM w0.102: v2(181.31,9.87) 181.31,10.09 182.06,10.84 v2(182.06,11.57)
HDD_B0_PRE0: length 4.2
  TOP w0.102: 185.22,13.77 185.22,14.56 184.89,14.89 v2(184.66,14.89) 184.21,15.34 RS21.1
  BOTTOM w0.102: v1(184.19,14.54) 184.54,14.89 v2(184.66,14.89) 184.66,15.3 RS28.2
HDD_B0_PRE1: length 3.1
  TOP w0.102: US2.17 184.72,9.4 RS18.1 183.57,8.25 RS29.2
HDD_REXT_SATA0: length 5.1
  TOP w0.102: v1(189.97,8.26) RS26.2
  TOP w0.254: RS26.2 RS31.1 188.02,8.56 187.76,8.82 186.49,8.82 186.22,9.09 US2.20
HDMI_HPLUG: length 13.4
  TOP w0.102: v1(199.14,71.56) CX20.1
  TOP w0.254: v2(198.84,73.33) RX15.2 RX34.1 CX20.1
  IN1 w0.254: v2(198.84,73.33) 199.83,74.32 199.83,77.91 201.35,79.43 202.28,79.43 JHDMI.19
HOST_ALERT1_R_N: length 22.2
  TOP w0.076: v2(166.81,88.96) 167.57,88.96 168.2,89.59 168.59,89.59
  TOP w0.102: 168.59,89.59 168.87,89.59 169.37,89.08 169.91,89.08 v1(170.19,89.36) 170.82,89.36 RC120.2
  IN1 w0.076: v2(152.36,89.49) 152.96,90.1 153.68,90.1 154.37,90.8 155.39,90.8 155.48,90.89 158.32,90.89 158.55,91.11 158.73,91.11
  IN1 w0.107: 158.73,91.11 159.31,91.11 161.6,88.83 165.28,88.83 165.66,88.45 166.3,88.45 v2(166.81,88.96)
  BOTTOM w0.076: v2(152.36,89.49) 152.2,89.34 UC1.AD7
HPOUT-L: length 2.5
  BOTTOM w0.203: UA1.32 197.13,23.38 v1(197.31,23.56) 197.4,23.65 197.4,24.2 RA55.1
HPOUT-R: length 2.4
  BOTTOM w0.203: RA56.1 197.75,24.48 197.81,24.41 197.81,23.4 197.53,23.11 UA1.33
I2C0_SCL: length 9.9
  BOTTOM w0.076: UC1.F3 154.95,98.52 155.28,98.85 155.49,98.85 155.77,99.13 156.57,99.13 157.47,100.03 158.19,100.03 158.28,100.12 160.36,100.12 160.36,100.12 161.01,100.12 v1(161.15,100.26) 161.18,100.28 161.7,100.28 162.12,99.86
  BOTTOM w0.102: RP53.4 162.12,99.86
I2C0_SDA: length 9.1
  BOTTOM w0.076: UC1.F2 155.85,98.93 156.68,98.93 157.61,99.86 158.26,99.86 158.35,99.95 159.98,99.95 159.98,99.95 161.78,99.95 v1(162.37,99.37) 162.62,99.37
  BOTTOM w0.102: RP53.3 162.62,99.37
I2C1_SCL: length 18.1
  TOP w0.076: 168.59,97.34 167.65,97.34 167.47,97.51 166.12,97.51 164.77,98.87 v1(164.37,98.87) v2(163.12,98.87)
  TOP w0.102: RC366.2 RC364.2 170.44,97.34 168.59,97.34
  BOTTOM w0.076: 162.74,98.87 162.37,98.87 161.45,99.79 158.41,99.79 158.33,99.7 157.74,99.7 156.64,98.6 156.14,98.6 UC1.F1
  BOTTOM w0.102: RP53.2 v2(163.12,98.87) 162.74,98.87
I2C1_SCL_PNL: length 340.5
  TOP w0.102: v1(170.03,99.06) RC364.1 v2(169.35,97.85) ; v2(10.98,103.05) 10.85,103.18 RX38.1 10.01,103.74 9.85,103.58 QX6.3
  IN1 w0.107: v2(169.35,97.85) 169.86,97.34 169.86,94.8 172.78,91.88 172.78,89.72 173.41,89.08 174.43,89.08 175.44,88.07 175.44,83.75 175.52,83.67 175.52,79.21 176.2,78.54 176.2,75.56 177.28,74.48 177.28,66.01 175.92,64.66 175.92,62.05 175.32,61.45 175.32,53.65 173.92,52.26 173.92,37.62 169.59,33.28 169.59,28.07 169.05,27.53 167.52,27.53 165.66,25.67 165.66,20.75 164.04,19.13 164.04,18.93 162.06,16.95 160.79,16.95 158.11,14.27 154.81,14.27 153.76,15.32 151.81,15.32 151.61,15.11 150.57,15.11 150,15.68 144.46,15.68 143.2,14.42 134.48,14.42 134.23,14.17 133.57,14.17 132.64,15.1 130.77,15.1 130.1,15.77 123.04,15.77 122.84,15.97 115.11,15.97 114.97,15.82 114.36,15.82 v2(113.82,15.28) ; v2(10.98,103.05) 10.98,103.18 11.87,104.07 12.63,104.07 13.25,104.69 28.84,104.69 31.17,107.01 31.17,112.83 31.68,113.34 33.39,113.34 37,116.95 51.47,116.95 58.5,109.92 60.41,109.92 63.82,106.51 64.49,106.51 65.75,105.25 66.85,105.25 68.09,104.01 81.14,104.01 89.85,95.31 89.85,91.62 92.26,89.21 92.26,83.75 90.99,82.48 90.99,66.6 90.67,66.29 90.67,56.23 91.78,55.11 91.78,45.53 91.19,44.93 91.19,41.94 92.78,40.35 92.78,38.6 94.68,36.7 95.45,36.7 98.54,33.62 100.48,33.62 108.86,25.24 108.86,18.08 111.43,15.51 v2(111.43,14.63)
  IN2 w0.107: v2(113.82,15.28) 112.08,15.28 v2(111.43,14.63)
I2C1_SCL_PNL_R: length 25.5
  TOP w0.102: v2(12.43,104.65) RX39.2 RX38.2 10.03,104.65 9.85,104.83 QX6.4 v1(9.85,106.13)
  IN1 w0.107: v2(4.38,92.02) 4.63,92.02 5.21,92.6 5.21,101.22 7.37,103.38 10.29,103.38 11.56,104.65 v2(12.43,104.65)
  BOTTOM w0.102: JEDP.17 2.6,91 2.84,91.24 3.97,91.24 4.38,91.65 v2(4.38,92.02)
I2C1_SCL_TP: length 226
  TOP w0.102: RC366.1 173.11,97.85 173.36,97.59 173.36,97.54 v2(173.44,97.46)
  IN1 w0.107: v2(96.32,107.88) 98.72,107.88 103.42,103.18 106.48,103.18 110.42,107.12 118.55,107.12 121.09,109.66 125.41,109.66 126.29,108.77 132.64,108.77 133.15,108.26 151.19,108.26 153.6,105.85 153.6,105.21 153.98,104.83 154.74,104.83 155.5,105.59 159.06,105.59 163.63,101.02 168.2,101.02 171.91,97.31 173.28,97.31 v2(173.44,97.46)
  IN2 w0.107: v2(27.85,65.98) 27.76,66.08 27.76,70.2 21.9,76.05 21.9,77.53 20.5,78.92 20.5,83.88 17.46,86.92 17.46,92 20.88,95.43 25.2,95.43 29.39,99.62 34.09,99.62 34.47,100 34.47,101.53 34.85,101.91 57.71,101.91 60,99.62 60,98.73 60.76,97.97 65.33,97.97 65.82,97.48 65.82,97.48 67.75,95.56 71.3,95.56 72.7,96.96 80.32,96.96 80.57,97.21 81.46,97.21 82.73,95.94 90.1,95.94 92.39,98.23 93.15,98.23 v2(93.91,98.99)
  BOTTOM w0.102: v2(27.85,65.98) QE6.4 26.42,65.98 25.16,67.24 23.92,67.24 23.42,66.74 v1(23.42,63.86) 23.42,63.66 24.36,62.72 RE337.1 ; v2(96.32,107.88) 95.81,107.37 95.81,103.31 93.91,101.4 v2(93.91,98.99)
I2C1_SCL_TP_R: length 9.9
  TOP w0.102: JTP1.8 v2(25.66,61.27) 24.95,61.27 v1(24.59,61.63)
  BOTTOM w0.102: QE6.3 25.57,65.98 25.96,65.59 25.96,64.44 25.71,64.19 24.82,64.19 24.69,64.06 RE337.2 RE334.2 25.89,63.63 26.09,63.43 26.09,61.65 25.71,61.27 v2(25.66,61.27)
I2C1_SDA: length 20.4
  TOP w0.076: v2(163.12,98.23) 165.03,98.23 166.17,97.08 v1(167.49,97.08) 168.59,97.08
  TOP w0.102: 168.59,97.08 170.44,97.08 RC363.2 RC365.2
  BOTTOM w0.076: 162.74,98.23 162.71,98.23 161.32,99.61 158.47,99.61 158.4,99.53 157.83,99.53 156.56,98.27 155.69,98.27 155.57,98.15 154.68,98.15 154.38,97.85 UC1.G4
  BOTTOM w0.102: 162.74,98.23 v2(163.12,98.23) 163.26,98.37 RP53.1
I2C1_SDA_PNL: length 338.9
  TOP w0.102: QX6.6 8.55,104.88 8.32,104.65 RX37.1 v2(7.55,105.47) ; v1(168.81,96.58) v2(169.35,96.58) RC363.1
  IN1 w0.107: v2(7.55,105.47) 7.8,105.21 9.71,105.21 10.88,106.38 27.92,106.38 28.73,107.19 28.73,114.84 30.32,116.43 35,116.43 36.46,117.89 51.91,117.89 55.87,113.92 58.12,111.68 58.87,110.93 60.72,110.93 64.21,107.44 66.44,107.44 67.58,106.31 72.13,106.31 72.69,105.75 76.78,105.75 77.58,104.95 81.73,104.95 90.86,95.81 90.86,93.02 93.27,90.61 93.27,83.24 92,81.97 92,69.14 92.79,68.36 92.79,45.21 92.12,44.54 92.12,42.37 93.82,40.66 93.82,38.9 95.05,37.67 95.81,37.67 98.83,34.65 101,34.65 110.08,25.57 110.08,24.54 110.57,24.05 110.57,20.31 113.81,17.07 113.81,16.7 114.45,16.05 114.87,16.05 115.04,16.23 122.91,16.23 123.14,16 130.16,16 130.85,15.31 132.72,15.31 133.65,14.38 134.15,14.38 134.39,14.62 143.1,14.62 144.37,15.89 149.08,15.89 149.12,15.93 150.9,15.93 151.26,15.57 153.88,15.57 154.93,14.52 158.03,14.52 160.71,17.2 161.94,17.2 163.79,19.04 163.79,19.26 165.42,20.89 165.42,25.83 167.4,27.81 168.98,27.81 169.35,28.19 169.35,33.45 173.69,37.79 173.69,52.4 175.04,53.75 175.04,61.55 175.69,62.2 175.69,64.75 177.04,66.1 177.04,74.38 175.96,75.46 175.96,78.44 175.29,79.12 175.29,83.52 175.19,83.62 175.19,86.92 172.52,89.59 172.52,91.75 169.35,94.92 v2(169.35,96.58)
I2C1_SDA_PNL_R: length 17.6
  TOP w0.102: v2(5.39,102.54) v1(5.77,102.93) 6.58,103.74 RX40.2 RX37.2 8.37,103.74 8.55,103.56 QX6.1
  IN1 w0.107: v2(5.39,102.54) 4.88,102.04 4.88,92.89 4.45,92.46 4.24,92.46 3.7,91.91 v2(3.7,91.89)
  BOTTOM w0.102: JEDP.16 3.31,91.5 v2(3.7,91.89)
I2C1_SDA_TP: length 227.7
  TOP w0.102: v2(173.49,96.88) 173.49,96.78 173.28,96.58 RC365.1
  IN1 w0.107: v2(95.05,107.88) 95.56,107.37 98.9,107.37 103.35,102.93 106.61,102.93 110.29,106.61 118.42,106.61 121.21,109.4 125.28,109.4 126.17,108.51 132.52,108.51 133.03,108.01 151.06,108.01 152.68,106.38 152.68,104.22 153.09,103.81 154.36,103.81 155.89,105.34 158.04,105.34 159.31,104.07 159.31,103.81 163,100.13 168.46,100.13 171.89,96.7 173.31,96.7 v2(173.49,96.88)
  IN2 w0.102: 66.08,97.55 67.82,95.81 71.05,95.81 72.45,97.21 77.91,97.21 ; 29.31,99.92 33.75,99.92 33.86,100.03
  IN2 w0.107: 33.86,100.03 34.09,100.26 34.09,101.53 34.73,102.16 57.84,102.16 60.25,99.75 60.25,98.86 60.91,98.21 65.42,98.21 66.08,97.55 ; v2(28,61.9) 24.05,65.85 v2(24.05,66.7) 24,66.76 24,73.63 21.52,76.1 21.52,77.32 20.12,78.72 20.12,83.24 16.69,86.67 16.69,91.62 20.88,95.81 25.2,95.81 29.31,99.92 ; 77.91,97.21 80.19,97.21 80.45,97.46 81.59,97.46 82.86,96.19 89.97,96.19 92.26,98.48 92.77,98.48 v2(93.27,98.99)
  BOTTOM w0.102: v2(24.05,66.7) 24.05,65.09 v1(24.14,65) 24.46,64.68 QE6.1 ; v2(93.27,98.99) 93.27,101.15 95.56,103.43 95.56,107.37 v2(95.05,107.88) ; v2(28,61.9) 27.74,62.16 RE336.1
I2C1_SDA_TP_R: length 7.2
  TOP w0.102: JTP1.9 26.66,61.03 26.9,61.27 ; 26.9,61.27 v2(26.9,61.27) ; 26.9,61.27 v1(26.53,61.64)
  BOTTOM w0.102: v2(26.9,61.27) 26.6,61.27 26.35,61.52 26.35,63.43 26.55,63.63 RE335.2 RE336.2 27.74,64.44 27.49,64.7 27.18,64.7 QE6.6
ICOMP: length 2.1
  BOTTOM w0.203: PR728.2 47.77,12.5 46.77,13.5 PU701.5
ILMT_1.05V: length 4.3
  BOTTOM w0.254: PR306.1 PR304.2 182.43,47.55 v1(181.98,48) 181.79,48.19 181.79,48.7 181.13,49.36 PU300.3
IMON: length 7.1
  TOP w0.254: PU501.3 67.87,110.29 67.75,110.16 v2(67.75,110.16)
  IN1 w0.254: v2(64.57,109.53) 64.83,109.78 67.37,109.78 v2(67.75,110.16)
  BOTTOM w0.254: PC500.2 PR521.1 65.64,109.78 v1(65.03,109.78) 64.83,109.78 v2(64.57,109.53)
IMON_GPU: length 5
  TOP w0.254: PR1029.2 PC1022.2 58.49,32.52 58.78,32.81 v2(58.78,33.33)
  BOTTOM w0.102: v2(58.78,33.33) 58.78,32.53 v1(59.12,32.19)
  BOTTOM w0.203: PU1000.10 59.25,34.14 58.78,33.67 v2(58.78,33.33)
INT-SPK-L+:
  vias: v1(201.12,20.78) v2(201.25,19.87) v2(201.53,20.45)
INT-SPK-L-:
  vias: v1(204.65,20.53) v2(202.7,20.45) v2(203.51,20.45)
INT-SPK-R+:
  vias: v1(207.07,19.31) v2(200.79,18.24) v2(201.05,17.71) v2(206.75,18.85) v2(207.45,18.85)
INT-SPK-R-:
  vias: v1(212.1,18.67) v2(202.11,17.07) v2(202.16,17.73) v2(211.64,19.11) v2(212.53,19.11)
INTRUDER#: length 28.6
  TOP w0.102: v2(172.27,71.68) v1(173.01,70.95) 173.23,70.72 173.23,70.08 173.54,69.78 RC7.2
  BOTTOM w0.076: UC1.AU6 152.99,81.17 153.52,81.17 153.79,80.9 153.79,80.48 153.69,80.38 153.42,80.38 153.22,80.18 153.22,79.27 153.47,79.02 153.47,78.41 153.98,77.91 155.91,77.91 158.95,74.86 161.19,74.86 161.22,74.88 161.25,74.88
  BOTTOM w0.102: v2(172.27,71.68) 171.13,71.68 167.93,74.88 161.25,74.88
ISEN1: length 13.3
  IN1 w0.254: v2(52.51,37.73) 52.36,37.73 52,37.37 52,35.83 52.49,35.34 54.31,35.34 54.67,34.98 56.52,34.98 v2(57.16,34.35)
  BOTTOM w0.102: v2(52.51,37.73) 52.27,37.97 51.3,37.97 v1(51.24,38.03)
  BOTTOM w0.203: PC1051.2 57.46,34.98 58.11,35.63 PU1000.13
  BOTTOM w0.254: v2(52.51,37.73) 51.78,37.01 51.7,37.01 PR1058.1 ; v2(57.16,34.35) PC1051.2
ISEN2: length 9.5
  TOP w0.254: v2(55.52,33.08) v1(54.88,33.08) 52.61,33.08 51.7,33.99 PR1059.1
  BOTTOM w0.203: 57.18,33.71 57.46,33.71 57.71,33.96 57.71,34.68 58.27,35.23 PU1000.12
  BOTTOM w0.254: 57.18,33.71 PC1050.2 57.16,33.66 56.57,33.08 v2(55.52,33.08)
ISOLATEB: length 4.8
  TOP w0.102: v1(171.96,100.13) RL33.2 RL35.2 171.96,103.18 v2(172.14,103.36)
  BOTTOM w0.102: UL1.20 172.92,103.36 172.82,103.46 172.24,103.46 v2(172.14,103.36)
ISUMN: length 46.1
  TOP w0.254: PC529.1 76.13,105.59 v2(76.38,105.34) 79.81,105.34 v1(80.98,104.17) 85.65,99.5 88.83,99.5 92,102.67 92,107.7 93.71,109.4 v2(93.83,109.4) ; PR545.1 71.38,105.47 PR535.2 72.45,105.52 PR549.1 ; PC530.1 PR549.1 ; PR549.1 v2(72.5,104.7)
  BOTTOM w0.254: v2(72.5,104.7) 75.75,104.7 v2(76.38,105.34) ; v2(93.83,109.4) PH501.1 93.83,115.17 94.67,116.01 PL502.3
ISUMP: length 10.9
  TOP w0.102: PR551.2 73.62,104.58 v1(73.46,104.42)
  TOP w0.254: PC529.2 74.58,106.1 74.42,106.27 PR536.1 ; PC529.2 74.1,105.59 73.97,105.47 PR549.2 PC530.2 v2(73.41,107.37) 73.08,107.37 72.83,107.12 71.18,107.12 70.91,107.38 PU501.10 ; PC529.2 PR551.2
  BOTTOM w0.254: PC530.2 v2(73.41,107.37)
JACK_PLUG#: length 22
  TOP w0.102: v2(190,18.73) 190.51,19.24 RA1.2 191.37,19.74 RA3.1 RA4.1 192.52,19.48 192.52,18.33 v1(192.41,18.22)
  IN1 w0.107: JHP.5 200.75,27.36 200.54,27.14 200.54,26.09 199.43,24.98 193.89,24.98 192.46,23.55 192.46,21.19 v2(190,18.73)
JACK_SENSE#: length 9.3
  TOP w0.102: QA5.3 192.91,21.58 v1(193.15,21.82)
  TOP w0.254: v2(192.67,17.08) 192.84,17.25 192.84,18.98 192.97,19.11 192.97,20.38 192.77,20.58 RA4.2 192.33,21.22 QA5.3
  BOTTOM w0.203: UA1.13 192.88,17.29 v2(192.67,17.08)
  BOTTOM w0.254: RA13.1 191.52,17.08 v2(192.67,17.08)
JHDD_P10: length 2.8
  BOTTOM w0.102: RS8.2 186.24,14.53 v1(185.81,14.11) 185.53,13.83 185.53,13.29 185.53,13.29 JHDD.7
JTAG_TCK: length 8.2
  BOTTOM w0.102: RP34.5 60.88,100.75 60.61,100.49 60.61,98.73 v4(60.71,98.63) 60.75,98.59 60.75,95.73 60.04,95.02 60.04,94.38 59.6,93.94 UV1.L3
JTAG_TDI: length 11.3
  TOP w0.102: v2(59.24,98.73) 58.93,98.73 v4(58.12,99.55)
  IN2 w0.107: v2(59.24,98.73) 57.9,97.4 57.9,94.63 59.26,93.27 v2(59.28,93.27)
  BOTTOM w0.102: v2(59.28,93.27) 59.6,92.95 UV1.L5 ; v2(59.24,98.73) 59.88,99.37 RP34.7
JTAG_TDO: length 7.7
  TOP w0.102: v2(58.98,97.82) 58.98,98.28 58.76,98.51 57.19,98.51 T86.1
  BOTTOM w0.102: v2(58.98,97.82) 59.53,97.28 59.53,94.9 59.3,94.67 59.3,94.37 59.31,94.36 59.31,93.85 58.8,93.34 UV1.K4
JTAG_TMS: length 7
  BOTTOM w0.102: UV1.L1 59.73,94.63 59.73,95.01 59.8,95.07 59.8,96.88 v4(59.98,97.06) 59.98,99.01 60.38,99.42 RP34.6
JTAG_TRSTB: length 11.5
  TOP w0.102: v2(59.24,99.37) v4(60.06,99.37)
  IN2 w0.107: v2(59.21,92.49) 57.59,94.11 57.59,97.72 v2(59.24,99.37)
  BOTTOM w0.102: UV1.L6 59.6,92.1 v2(59.21,92.49) ; RP34.8 59.38,99.51 v2(59.24,99.37)
KB_BL_PWM:
  vias: v1(121.01,7.43)
KB_CAPS_PWR: length 7.1
  TOP w0.102: v1(95.98,47.34) 96.51,46.8 96.51,45.36 96.31,45.15 RE60.2 95.45,45.15 95.26,45.35 JKB.4
KB_DET#: length 127.4
  TOP w0.102: v2(121.82,23.22) 121.95,23.22 v1(122.26,22.92) 122.26,22.33 RE68.1 121.44,21.52 QE4.1
  IN1 w0.107: v2(162.36,85.96) 162.92,85.4 167.06,85.4 168.71,83.75 168.71,77.65 168.33,77.27 168.33,72.32 169.2,71.45 169.2,65.95 168.2,64.95 168.2,63.76 166.99,62.54 166.99,56.6 165.92,55.53 165.92,43.36 163.89,41.33 163.89,40.7 162.62,39.43 161.98,39.43 160.58,38.03 157.92,38.03 156.14,36.25 156.14,34.98 154.74,33.58 153.98,33.58 153.47,33.08 153.47,27.77 152.3,26.6 151.83,26.6 148.67,23.45 147.23,23.45 146.71,23.97 143.32,23.97 143.2,24.09 134.62,24.09 134.6,24.11 130.08,24.11 128,22.03 122.99,22.03 121.82,23.19 v2(121.82,23.22)
  BOTTOM w0.076: UC1.AN3 155.09,83.28 155.68,83.28 155.84,83.44 155.84,83.69 156.01,83.86 156.27,83.86 156.56,83.57 159.77,83.57 160.2,84 160.2,85.22 160.56,85.58 160.56,86.29 160.81,86.54 161.47,86.54 162.06,85.96 v2(162.36,85.96) 162.39,85.96 162.73,86.3 162.74,86.3
  BOTTOM w0.102: 162.74,86.3 162.76,86.3 163.02,86.57 165.69,86.57 166.68,87.56 RC103.1
KB_LED_PWM: length 8.7
  TOP w0.102: v2(128.63,9.86) 128.89,9.61 v1(129.37,9.61) 129.47,9.71 UE1.21 ; v2(123.6,9.2) 123.6,9.17 123.36,8.93 QE5.3
  IN2 w0.107: v2(128.63,9.86) 128.61,9.88 124.26,9.88 123.6,9.22 v2(123.6,9.2)
KB_RST#: length 151.7
  TOP w0.076: v2(162.39,95.71) 162.54,95.56 163.63,95.56 164.09,96.02 165.39,96.02 166.82,94.58 v1(166.82,93.91) 166.82,91.81 166.3,91.29 165.23,91.29 163.76,92.77 163.76,93.4 163.38,93.78 162.24,93.78 161.96,93.5 161.96,91.98 161.22,91.24 158.73,91.24 158.1,91.88 154.95,91.88 v2(154.49,91.41)
  TOP w0.102: v2(132.2,17.61) 131.9,17.31 UE1.2
  IN1 w0.076: 158.73,91.75 158.17,91.75 157.92,92 155.08,92 v2(154.49,91.41)
  IN1 w0.107: 158.73,91.75 160.71,91.75 161.22,91.24 164.01,91.24 164.39,90.86 167.95,90.86 168.84,89.97 168.84,89.34 169.22,88.96 170.11,88.96 171.89,87.18 171.89,84.38 170.55,83.05 170.55,81.27 171.38,80.45 171.38,76.26 170.5,75.37 170.5,65.18 169.51,64.19 169.51,38.44 168.2,37.14 168.2,36.32 166.74,34.85 163.75,34.85 162.17,33.27 161.8,33.27 161.09,32.57 161.09,25.66 158.04,22.61 158.04,20.91 156.37,19.23 151.11,19.23 150.6,18.72 146.11,18.72 144.94,17.56 139.02,17.56 138.1,18.47 137.61,18.47 136.75,17.61 v2(132.2,17.61)
  BOTTOM w0.076: 162.74,95.94 162.52,95.71 v2(162.39,95.71) ; v2(154.49,91.41) 154.19,91.71 UC1.V4
  BOTTOM w0.102: 162.74,95.94 163.12,96.32 163.12,97.01 163.4,97.29 RC109.2
KSI0: length 75.1
  TOP w0.102: v2(110.7,5.06) 110.17,5.59 110.17,6.02 108.54,7.65 106.49,7.65 103.36,10.78 103.36,21.5 100.46,24.4 99.36,24.4 v1(97.85,25.92) 95.75,28.01 95.75,28.19 92.99,30.95 JKB.22 ; UE1.55 141.42,5 v2(141.41,5.01)
  IN2 w0.107: v2(110.7,5.06) 110.29,5.47 110.29,5.9 112.15,7.75 115.51,7.75 116.55,8.8 119.69,8.8 119.83,8.66 122.48,8.66 124.09,10.27 128.81,10.27 129.36,9.72 130.05,9.72 130.13,9.79 134.84,9.79 135.32,9.31 137.89,9.31 138.96,8.24 140.26,8.24 140.7,7.8 140.7,6.79 141,6.48 141,5.42 v2(141.41,5.01)
KSI1: length 76.8
  TOP w0.102: UE1.56 141.82,5.87 v2(141.41,6.28) ; v2(110.7,4.47) 110.51,4.47 107.79,7.19 106.23,7.19 102.8,10.62 v1(102.8,14.76) 102.8,20.46 100.15,23.12 100.15,23.32 99.64,23.83 97.82,23.83 93.23,28.42 93.23,28.9 92.79,29.35 JKB.24
  IN2 w0.107: v2(110.7,4.47) 110.57,4.47 109.91,5.14 109.91,5.9 112.02,8.01 115.38,8.01 117.06,9.68 119.14,9.68 119.93,8.89 122.39,8.89 124.01,10.52 128.91,10.52 129.48,9.95 129.99,9.95 130.04,10 134.92,10 135.4,9.52 137.99,9.52 139.04,8.47 140.56,8.47 141.56,7.47 141.56,6.43 v2(141.41,6.28)
KSI2: length 76.3
  TOP w0.102: v2(108.9,4.88) 108.49,5.29 108.49,5.82 107.58,6.74 105.96,6.74 102.14,10.56 v1(102.14,17.87) 102.14,20.41 99.51,23.04 97.85,23.04 93.16,27.73 93.16,27.74 92.76,27.74 JKB.26 ; v2(143.01,6.28) 142.22,5.48 UE1.57
  IN2 w0.107: v2(143.01,6.28) 143.01,6.96 140.87,9.11 140.09,9.11 139.45,9.75 138.68,9.75 138.28,10.15 135.79,10.15 135.23,10.71 130.58,10.71 129.75,11.54 123.71,11.54 122.94,10.77 112.76,10.77 109.4,7.42 109.4,5.39 v2(108.9,4.88)
KSI3: length 76.1
  TOP w0.102: v2(108.67,6.91) 108.65,6.91 108.13,7.42 106.36,7.42 103.13,10.65 103.13,21.41 102.17,22.37 v1(101.79,22.37) 100.07,24.08 98.01,24.08 93.54,28.55 93.54,29.48 92.88,30.15 JKB.23 ; v2(143.01,5.64) 142.61,5.24 142.61,4.75 142.62,4.74 UE1.58
  IN2 w0.107: v2(108.67,6.91) 108.9,7.13 108.9,7.29 112.63,11.03 122.84,11.03 123.58,11.77 132.57,11.77 133.42,10.92 135.31,10.92 135.88,10.35 138.57,10.35 138.58,10.35 138.8,10.57 139.13,10.57 140.36,9.35 140.36,9.35 140.39,9.32 140.97,9.32 143.44,6.85 143.44,5.9 143.19,5.64 v2(143.01,5.64)
KSI4: length 76.1
  TOP w0.102: v2(143.01,5.05) 143.02,5.04 UE1.59 ; JKB.27 93.56,26.95 97.8,22.71 99.5,22.71 101.81,20.4 101.81,10.53 105.99,6.35 v4(106.99,6.35) 107.63,6.35 108.26,5.72 108.26,4.88 v2(108.9,4.25)
  IN2 w0.107: v2(108.9,4.25) 109.66,5.01 109.66,7.29 112.86,10.49 123,10.49 123.78,11.28 129.67,11.28 130.46,10.49 135.15,10.49 135.7,9.94 138.2,9.94 138.59,9.54 139.34,9.54 139.99,8.9 140.78,8.9 142.55,7.13 142.55,5.51 v2(143.01,5.05)
KSI5: length 78.8
  TOP w0.102: JKB.25 92.72,28.55 97.82,23.45 v4(99.36,23.45) 99.49,23.45 102.47,20.46 102.47,10.59 106.09,6.96 107.7,6.96 108.9,5.77 v2(108.9,5.52) ; UE1.60 143.42,5.74 v2(143.95,6.28)
  IN2 w0.107: v2(143.95,6.28) 143.69,6.54 143.69,7.07 141.2,9.55 140.44,9.55 139.22,10.78 138.72,10.78 138.54,10.6 135.92,10.6 134.7,11.82 134.2,11.82 134,12.02 125.92,12.02 125.34,12.61 124.8,12.61 124.49,12.3 123.45,12.3 123.02,11.87 118.84,11.87 118.41,12.3 113.39,12.3 108.16,7.07 108.16,6.25 v2(108.9,5.52)
KSI6: length 78.8
  TOP w0.102: v2(143.95,5.04) 143.82,4.91 UE1.61 ; JKB.28 93.91,26.15 97.83,22.23 v4(97.91,22.23) 99.6,22.23 101.56,20.27 101.56,10.42 106.62,5.36 v2(107.83,5.36)
  IN2 w0.107: v2(107.83,5.36) 107.58,5.62 107.58,7.24 113.14,12.81 118.74,12.81 119.22,12.33 122.82,12.33 123.3,12.81 124.26,12.81 124.52,13.06 125.48,13.06 126.11,12.44 134.18,12.44 134.37,12.24 134.88,12.24 136.1,11.02 138.36,11.02 138.55,11.2 140.59,11.2 141.97,9.82 141.97,9.45 144.71,6.71 144.71,5.8 v2(143.95,5.04)
KSI7: length 78.8
  TOP w0.102: v2(107.83,4.73) 107.8,4.7 106.92,4.7 101.3,10.32 101.3,20.15 99.65,21.8 97.54,21.8 v4(95.51,23.83) 93.99,25.35 JKB.29 ; UE1.62 144.22,4.67 144.36,4.81 144.36,5.24 v2(143.95,5.64)
  IN2 w0.107: v2(143.95,5.64) 144.36,6.05 144.36,6.51 143.95,6.92 143.95,7.12 141.56,9.5 141.56,9.88 140.46,10.99 138.63,10.99 138.45,10.81 136.01,10.81 134.79,12.03 134.29,12.03 134.09,12.23 126.01,12.23 125.41,12.83 124.64,12.83 124.38,12.57 123.39,12.57 122.92,12.1 119.12,12.1 118.65,12.57 113.29,12.57 107.81,7.1 107.81,5.97 108.26,5.52 108.26,5.16 v2(107.83,4.73)
KSO0: length 70.2
  TOP w0.102: JKB.13 93.92,38.15 95.89,36.17 95.89,31.47 100.64,26.73 101.53,26.73 105.9,22.36 105.9,13.33 v1(106.06,13.16) 106.06,11.99 108.34,9.71 109.91,9.71 111.77,7.85 112.8,7.85 113.73,6.92 113.73,5.53 113.37,5.16 v2(113.37,4.65) ; v2(134.19,5.92) 134.83,5.29 134.83,4.75 135.02,4.56 UE1.39
  IN2 w0.107: v2(134.19,5.92) 133.96,5.92 132.54,4.5 122.23,4.5 122.21,4.48 113.54,4.48 v2(113.37,4.65)
KSO1: length 69.8
  TOP w0.102: UE1.40 135.42,4.92 v2(135.41,4.93) ; JKB.15 93.48,36.55 95.41,34.62 95.41,31.2 100.39,26.22 101.28,26.22 105.34,22.15 v1(105.34,21.47) 105.34,11.98 108.07,9.25 109.61,9.25 111.54,7.32 112.69,7.32 113.24,6.77 113.24,5.88 112.16,4.8 v2(112.16,4.6)
  IN2 w0.107: v2(135.41,4.93) 135.01,4.93 134.68,5.26 134.1,5.26 132.83,3.99 122.61,3.99 122.59,4.01 112.75,4.01 v2(112.16,4.6)
KSO2: length 70.9
  TOP w0.102: JKB.14 93.34,37.35 94.25,37.35 v1(95.09,36.5) 95.66,35.93 95.66,31.32 100.51,26.47 101.4,26.47 105.67,22.2 105.67,12.02 108.21,9.48 109.76,9.48 111.64,7.6 112.73,7.6 113.47,6.86 113.47,5.77 112.76,5.06 v2(112.76,4.63) ; v2(135.41,5.52) 135.82,5.11 UE1.41
  IN2 w0.107: v2(135.41,5.52) 135.39,5.49 133.89,5.49 132.64,4.25 122.46,4.25 122.46,4.24 113.14,4.24 v2(112.76,4.63)
KSO3: length 71.4
  TOP w0.102: JKB.16 93.9,35.75 95.15,34.5 95.15,31.07 100.26,25.96 101.15,25.96 105.01,22.1 105.01,11.99 107.97,9.02 109.45,9.02 111.41,7.07 112.62,7.07 112.86,6.83 v4(112.86,6.25) v2(112.38,5.77) ; UE1.42 136.22,4.66 136.12,4.75 136.12,5.01 v2(136.61,5.49)
  IN2 w0.107: v2(136.61,5.49) 136.99,5.87 136.99,6.15 136.71,6.43 135.72,6.43 135.34,6.81 133.66,6.81 132.11,5.26 121.85,5.26 121.12,5.99 119.08,5.99 118.43,5.35 114.27,5.35 113.85,5.77 v2(112.38,5.77)
KSO4: length 67
  TOP w0.102: v1(106.62,8.56) 106.62,8.58 ; 106.62,8.58 107.09,8.11 108.85,8.11 111.28,5.67 v2(111.28,4.79) ; 106.62,8.58 103.82,11.38 103.82,21.69 100.51,25 99.7,25 94.19,30.51 94.19,31.91 93.55,32.55 JKB.20 ; UE1.43 136.62,4.87 v2(136.58,4.91)
  IN2 w0.107: v2(136.58,4.91) 135.13,6.35 134.02,6.35 132.42,4.75 121.65,4.75 120.93,5.47 119.26,5.47 118.67,4.88 113.98,4.88 113.77,5.08 111.58,5.08 v2(111.28,4.79)
KSO5: length 66.4
  TOP w0.102: v2(110.72,5.64) 110.72,5.85 108.69,7.88 106.66,7.88 103.59,10.95 103.59,21.6 100.44,24.74 99.49,24.74 v1(96.69,27.55) 96.69,27.61 92.54,31.75 92.43,31.75 JKB.21 ; UE1.44 137.02,5.78 136.75,6.05 v2(136.53,6.05)
  IN2 w0.107: v2(110.72,5.64) 111.23,5.64 111.54,5.34 113.9,5.34 114.13,5.11 118.55,5.11 119.2,5.76 120.97,5.76 121.72,5.01 132.26,5.01 133.84,6.58 135.24,6.58 135.77,6.05 v2(136.53,6.05)
KSO6: length 69.8
  TOP w0.102: UE1.45 137.42,5.85 137.7,6.13 v2(137.83,6.13) ; JKB.18 93.34,34.15 94.65,32.85 94.65,30.81 99.98,25.48 100.69,25.48 104.32,21.85 104.32,11.88 v1(104.53,11.68) 107.64,8.56 109.15,8.56 111.49,6.23 112.02,6.23 v2(112.45,6.66)
  IN2 w0.107: v2(137.83,6.13) 137.1,6.85 135.93,6.85 135.49,7.29 132.37,7.29 131.42,6.35 128.26,6.35 127.68,5.77 122.1,5.77 121.41,6.46 118.78,6.46 118.13,5.81 114.57,5.81 113.39,6.99 112.78,6.99 v2(112.45,6.66)
KSO7: length 68.8
  TOP w0.102: UE1.46 137.82,4.98 v2(137.85,5.01) ; JKB.19 93.76,33.35 94.42,32.69 94.42,30.66 99.85,25.23 100.6,25.23 104.07,21.76 104.07,11.67 v1(105.57,10.17) 107.4,8.34 109,8.34 111.56,5.77 v2(111.74,5.77)
  IN2 w0.107: v2(111.74,5.77) 112.2,6.23 113.77,6.23 114.42,5.58 118.28,5.58 118.93,6.23 121.29,6.23 122,5.52 130.88,5.52 132.41,7.04 135.41,7.04 135.81,6.64 136.83,6.64 137.34,6.13 137.34,5.52 v2(137.85,5.01)
KSO8: length 70.7
  TOP w0.102: UE1.47 138.22,4.8 138.26,4.84 138.26,5.24 137.93,5.57 v2(137.85,5.57) ; JKB.17 92.49,34.95 92.95,34.95 94.9,33 94.9,30.94 100.11,25.73 101,25.73 104.68,22.05 v1(104.68,19.38) 104.68,11.99 107.88,8.79 109.3,8.79 111.44,6.66 v2(111.74,6.66)
  IN2 w0.107: v2(111.74,6.66) 112.35,7.27 113.49,7.27 114.72,6.05 117.99,6.05 118.63,6.69 121.53,6.69 122.21,6.02 126.66,6.02 127.19,6.56 131.28,6.56 132.24,7.52 135.57,7.52 136.01,7.08 137.43,7.08 138.26,6.25 138.26,5.98 v2(137.85,5.57)
KSO9: length 76
  TOP w0.102: JKB.7 93.18,42.95 94.93,41.2 94.93,39.17 97.54,36.55 97.54,32.11 101.4,28.25 102.93,28.25 v1(105.38,25.8) 107.27,23.91 107.27,14.76 113.24,8.79 114.28,8.79 v2(116.57,6.51) ; v2(139.02,5.57) 138.92,5.57 138.56,5.21 138.56,4.8 138.62,4.75 UE1.48
  IN2 w0.107: v2(116.57,6.51) 116.72,6.35 117.94,6.35 118.51,6.93 121.71,6.93 122.36,6.28 126.62,6.28 127.15,6.81 131.23,6.81 132.16,7.75 135.64,7.75 136.11,7.29 137.58,7.29 138.49,6.38 138.49,6.05 138.97,5.57 v2(139.02,5.57)
KSO10: length 79.7
  TOP w0.102: JKB.5 93.32,44.55 93.72,44.95 95.24,44.95 96.3,43.9 96.3,41.6 96.68,41.21 v1(96.68,39.58) 96.68,38.84 98,37.53 98,32.41 101.66,28.76 103.56,28.76 107.73,24.59 107.73,15.07 113.54,9.25 115.04,9.25 v2(117.25,7.04) ; UE1.49 v2(139.02,5.01)
  IN2 w0.107: v2(117.25,7.04) 117.91,7.04 118.27,7.4 123.09,7.4 123.7,8.01 124.06,8.01 124.87,8.82 126.04,8.82 126.17,8.69 130.51,8.69 130.69,8.87 133.29,8.87 133.93,8.23 135.82,8.23 136.36,7.7 137.77,7.7 138.92,6.56 139.17,6.56 139.5,6.23 139.5,5.39 139.12,5.01 v2(139.02,5.01)
KSO11: length 79.5
  TOP w0.102: v2(116.57,7.12) 116.57,7.37 114.92,9.02 113.39,9.02 107.5,14.91 107.5,24.44 103.43,28.5 101.53,28.5 97.77,32.26 97.77,37.29 v1(97.47,37.59) 96.3,38.76 96.3,39.98 95.57,40.71 95.57,44.24 95.09,44.72 93.92,44.72 92.95,43.75 JKB.6 ; UE1.50 139.42,4.73 139.5,4.81 139.5,5.77 139.15,6.13 v2(139.05,6.13)
  IN2 w0.107: v2(139.05,6.13) 137.68,7.49 136.25,7.49 135.74,8.01 132.11,8.01 131.16,7.05 127.07,7.05 126.55,6.53 122.51,6.53 121.88,7.16 118.39,7.16 117.84,6.61 117.07,6.61 v2(116.57,7.12)
KSO12: length 77
  TOP w0.102: v2(114.92,6.46) 113.29,8.08 111.92,8.08 110.06,9.94 108.47,9.94 108.16,10.25 108.16,11.72 106.13,13.76 106.13,22.51 101.66,26.98 100.72,26.98 96.25,31.46 v1(96.25,33.2) 96.15,33.3 96.15,36.25 93.45,38.95 JKB.12 ; UE1.51 139.82,5.83 v2(140.26,6.28)
  IN2 w0.107: v2(114.92,6.46) 116.77,8.31 118.29,8.31 118.41,8.19 123.18,8.19 123.5,8.51 123.86,8.51 124.72,9.38 126.24,9.38 126.42,9.2 130.26,9.2 130.44,9.38 134.66,9.38 135.14,8.9 137.65,8.9 138.76,7.78 140,7.78 140.24,7.55 140.24,6.3 v2(140.26,6.28)
KSO13: length 77.9
  TOP w0.102: UE1.52 140.22,4.96 v2(140.26,5.01) ; v2(114.94,7.07) 114.94,7.09 113.7,8.34 112.93,8.34 106.81,14.46 106.81,23.25 v1(106.19,23.87) 102.32,27.74 101.15,27.74 97.03,31.86 97.03,36.38 94.42,38.99 94.42,40.31 93.38,41.35 JKB.9
  IN2 w0.107: v2(114.94,7.07) 115.17,7.07 116.67,8.56 119.59,8.56 119.73,8.42 123.06,8.42 123.4,8.77 123.75,8.77 124.62,9.63 126.37,9.63 126.53,9.48 130.13,9.48 130.24,9.59 134.75,9.59 135.23,9.11 137.79,9.11 138.89,8.01 140.16,8.01 140.47,7.7 140.47,6.71 140.77,6.41 140.77,5.52 v2(140.26,5.01)
KSO14: length 78.8
  TOP w0.102: v2(140.26,5.64) 140.67,5.24 140.67,4.73 140.62,4.68 UE1.53 ; v2(115.53,6.46) 115.53,7.14 114.1,8.56 113.09,8.56 107.04,14.61 107.04,23.55 v1(102.79,27.8) 102.6,28 101.28,28 97.29,31.98 97.29,36.47 94.67,39.08 94.67,40.95 93.47,42.15 JKB.8
  IN2 w0.107: v2(140.26,5.64) 139.81,6.1 139.81,6.38 139.99,6.56 139.99,7.37 139.78,7.58 138.61,7.58 137.54,8.64 135.82,8.64 135.69,8.51 134.02,8.51 133.41,9.12 130.54,9.12 130.36,8.95 126.29,8.95 126.17,9.07 124.77,9.07 123.96,8.26 123.6,8.26 123.3,7.96 118.27,7.96 118.17,8.06 116.87,8.06 115.53,6.71 v2(115.53,6.46)
KSO15: length 78.5
  TOP w0.102: v2(111.82,8.82) 106.58,14.05 106.58,22.95 v1(103.43,26.1) 102.05,27.49 101.02,27.49 96.81,31.7 96.81,36.28 94.16,38.92 94.16,39.93 93.55,40.55 JKB.10 ; UE1.54 141.02,4.75 141,4.77 141,5.24 v2(141.41,5.64)
  IN2 w0.107: v2(141.41,5.64) 141.53,5.64 141.82,5.93 141.82,7.57 140.7,8.69 139.9,8.69 139.26,9.34 138.47,9.34 138.07,9.73 135.52,9.73 135.03,10.22 130.39,10.22 129.57,11.03 123.86,11.03 123.07,10.24 117.26,10.24 115.71,8.69 111.94,8.69 v2(111.82,8.82)
KSO16: length 79.6
  TOP w0.102: JKB.11 93.59,39.75 93.91,39.43 93.91,38.84 96.48,36.28 v1(96.48,35.2) 96.48,34.27 96.58,34.17 96.58,31.55 100.89,27.23 101.78,27.23 106.36,22.66 106.36,13.87 108.64,11.59 v2(108.64,10.34) ; v2(145.34,11.09) 145.34,11.49 145.57,11.71 UE1.81
  IN2 w0.107: v2(108.64,10.34) 109.15,10.34 111.36,12.55 111.87,12.55 112.63,13.31 118.9,13.31 119.41,12.8 122.63,12.8 123.1,13.27 123.36,13.27 123.61,13.53 126.88,13.53 127.55,12.85 134.35,12.85 134.54,12.66 135.05,12.66 136.27,11.43 138.19,11.43 138.37,11.61 140.76,11.61 141.55,10.82 145.08,10.82 v2(145.34,11.09)
LAN_CLKREQ#: length 39.1
  TOP w0.076: 168.59,91.62 168.14,91.62 166.92,90.4 v2(166.91,90.4)
  TOP w0.102: v2(175.44,91.37) 175.32,91.37 175.06,91.62 v1(174.17,91.62) 168.59,91.62
  IN1 w0.107: v2(176.51,99.17) 176.26,98.91 176.26,95.39 174.89,94.02 174.89,91.93 v2(175.44,91.37)
  IN2 w0.076: 158.68,88.67 158.38,88.67 v2(157.81,89.25)
  IN2 w0.107: v2(166.91,90.4) 166.91,90.47 166.54,90.83 165.89,90.83 165.03,89.97 165.03,88.32 164.47,87.76 161.12,87.76 160.21,88.67 158.68,88.67
  BOTTOM w0.076: UC1.AD1 156.17,88.86 157.41,88.86 v2(157.81,89.25)
  BOTTOM w0.102: v2(166.91,90.4) 166.91,90.82 167.14,91.05 RP42.8 ; UL1.12 175.77,99.91 v2(176.51,99.17) 178.2,100.86 RL37.1
LAN_X1_R: length 3.3
  TOP w0.102: UG1.6 188,79.85 188.96,80.81 188.96,80.83 RG5.1 v1(189.08,82.07)
LCD_CBL_DET#: length 5.7
  BOTTOM w0.076: RC106.2 159.8,98.1 v1(159.04,98.1) 157.22,98.1 156.65,97.53 155.66,97.53 155.58,97.45 155.27,97.45 UC1.J3
LCD_TEST: length 260.9
  TOP w0.102: v2(144.39,11.78) 144.39,10.08 145.5,8.97 145.5,8.31 145.7,8.11 UE1.72 ; v1(2.43,82.74) v2(3.02,82.74)
  IN1 w0.107: v2(3.02,82.74) 3,82.74 2.32,83.43 2.32,101.5 5.01,104.2 8.57,104.2 8.57,104.19 10.21,104.19 11.36,105.34 28.74,105.34 30.66,107.27 30.66,114.61 31.17,115.12 34.81,115.12 36.88,117.19 51.57,117.19 54.73,114.03 54.73,114.02 58.6,110.15 60.51,110.15 63.92,106.74 64.59,106.74 65.85,105.48 66.95,105.48 68.19,104.25 81.29,104.25 90.1,95.43 90.1,91.75 92.51,89.34 92.51,83.62 91.24,82.35 91.24,66.4 90.94,66.1 90.94,56.3 92.02,55.22 92.02,45.43 91.42,44.84 91.42,42.04 93.07,40.39 93.07,38.64 94.77,36.94 95.55,36.94 98.53,33.95 100.59,33.95 109.37,25.18 109.37,24.13 109.82,23.68 109.82,19.44 110.58,18.67 110.58,16.8 113.37,14.01 116.37,14.01 116.56,14.2 116.68,14.2 116.68,14.2 117.21,14.2 117.22,14.2 117.26,14.2 117.27,14.2 120.91,14.2 121.08,14.03 122.61,14.03 123.06,13.58 124.2,13.58 124.32,13.7 125.82,13.7 125.92,13.8 130.72,13.8 131.89,12.64 137.98,12.64 138.33,12.29 142.73,12.29 143.59,11.44 143.6,11.44 143.62,11.42 144.03,11.42 v2(144.39,11.78)
  BOTTOM w0.102: JEDP.33 2.46,83 2.71,82.74 v2(3.02,82.74)
LG_3V: length 3.6
  TOP w0.635: 69.29,19.93 v1(68.11,21.12) 67.07,22.15 66.6,22.15
LG_5V: length 6.5
  IN1 w0.762: 69.53,15.93 69.02,15.42 63.43,15.42 63.3,15.55
  vias: v1(62.69,17.4) v3(62.79,16.44) v3(62.79,15.8) v3(69.67,16.17) v3(70.16,16.65)
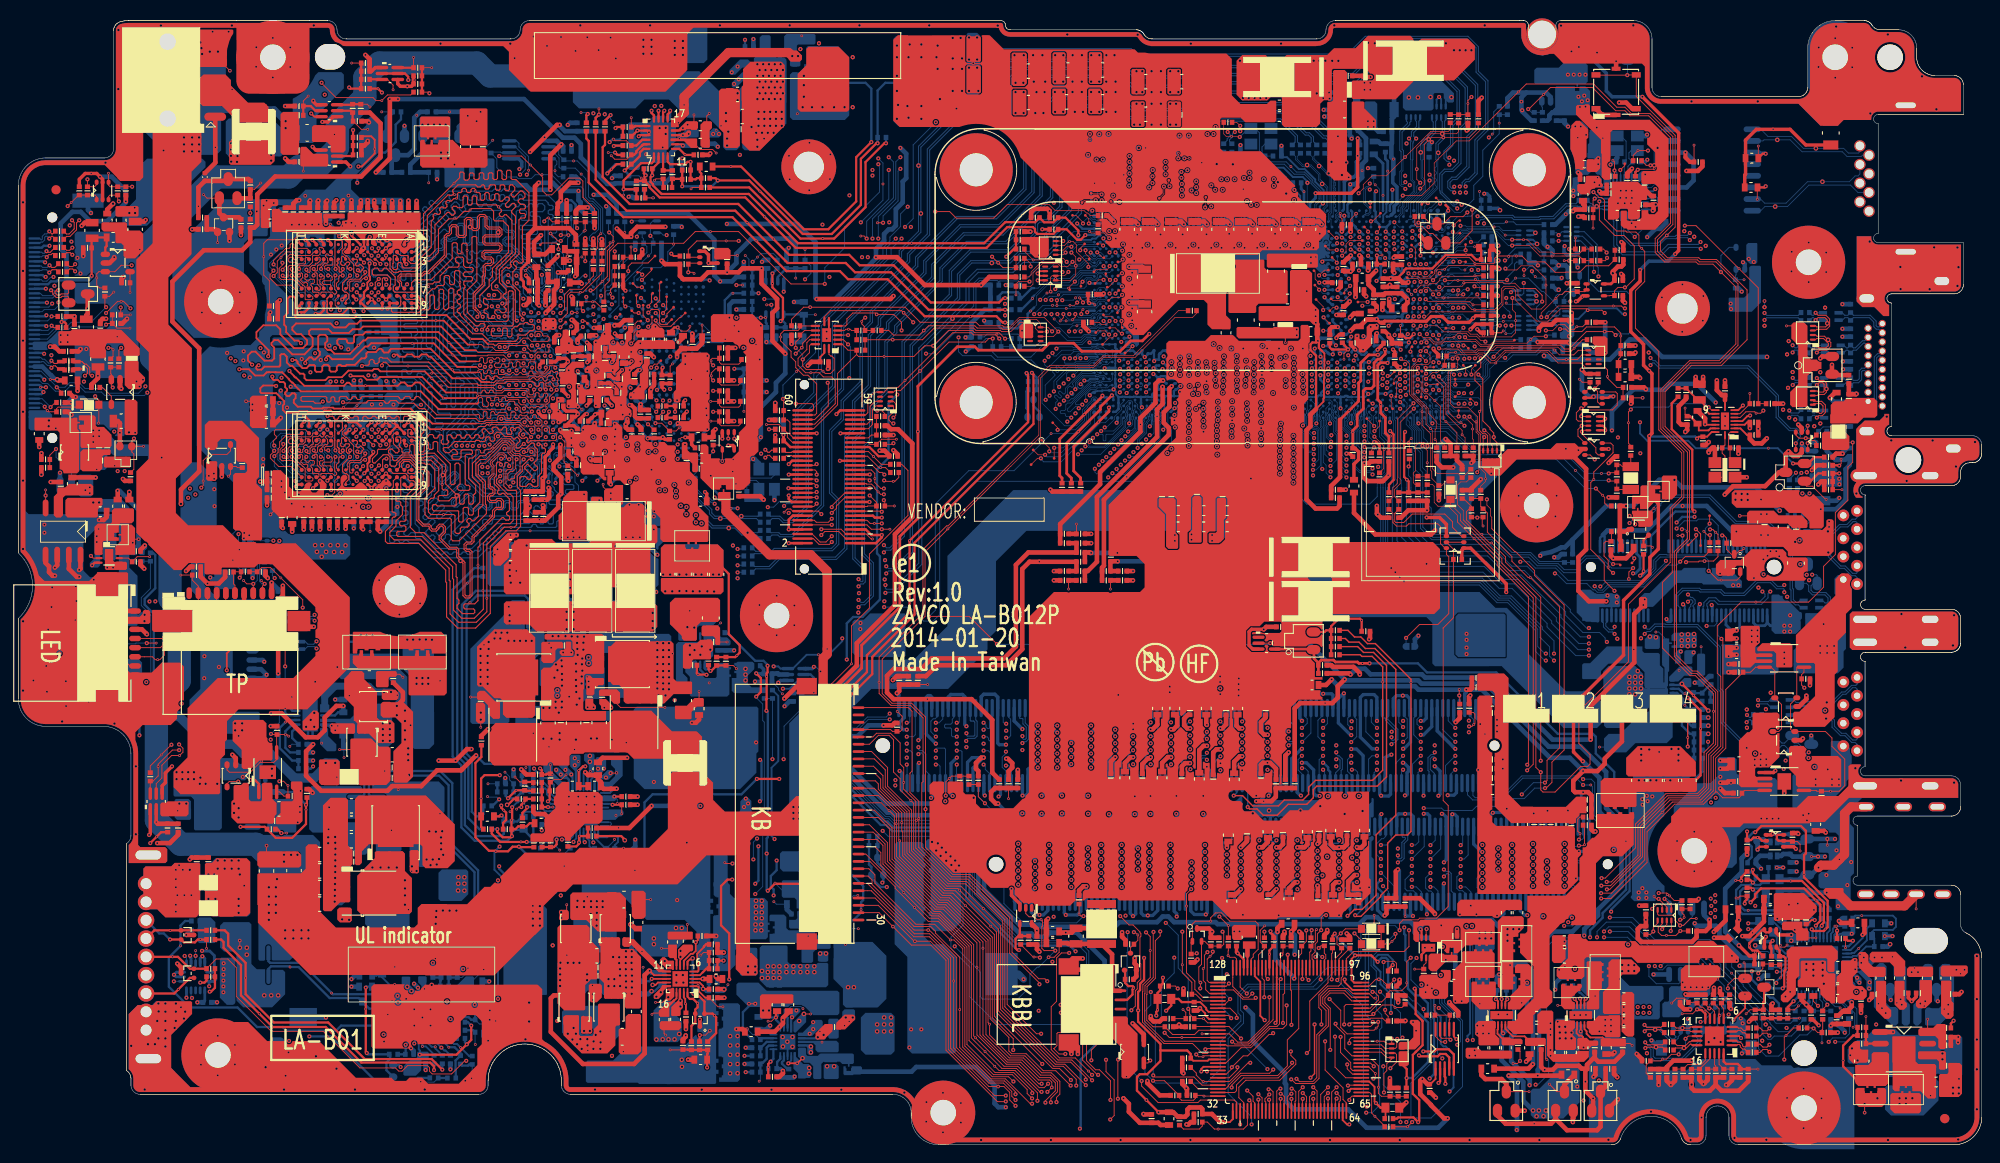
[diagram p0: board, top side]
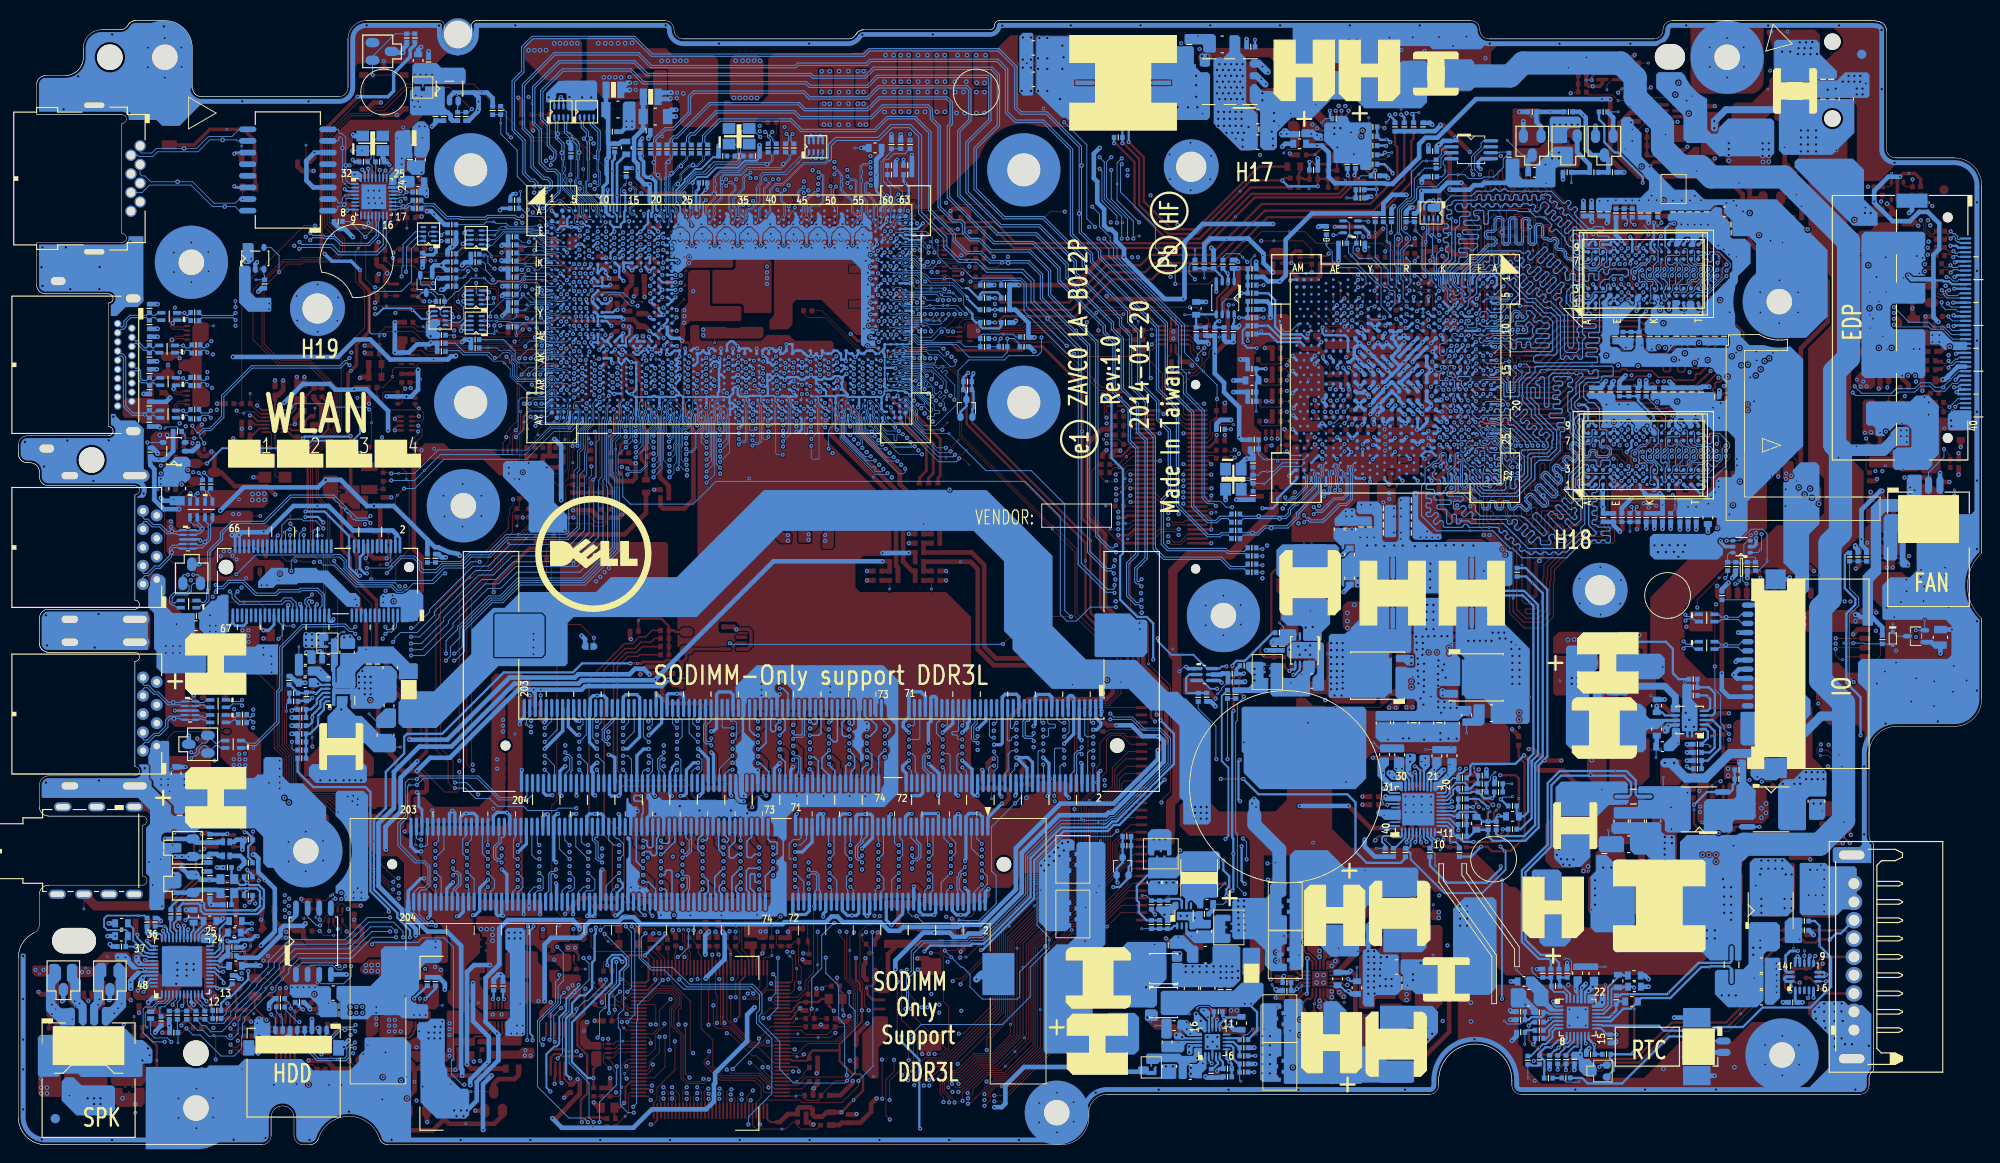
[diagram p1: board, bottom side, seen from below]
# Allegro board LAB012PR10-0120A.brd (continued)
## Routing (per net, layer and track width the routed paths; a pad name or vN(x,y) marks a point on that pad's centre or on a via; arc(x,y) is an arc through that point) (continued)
LG_+1.35VGPUP: length 9
  BOTTOM w0.762: v3(40.7,49.46) v3(39.93,49.46) 38.92,49.46 38.28,50.09 34.6,50.09 33.46,48.95 33.46,47.93
  vias: v1(41.38,49.1)
LGATE: length 15.6
  TOP w1.016: 72.69,112.81 72.7,112.82 v1(72.7,113.59) 72.7,114.47 77.54,119.31 84.13,119.31 v3(84.51,118.93)
  vias: v3(85.15,118.93)
LGATE1: length 11.3
  IN2 w0.762: 60.13,53.14 60.13,46.16 60,46.03 60,42.98 v2(60.76,42.22)
  vias: v1(61.14,41.86) v2(59.49,53.78) v2(60.38,53.78) v2(60.76,41.46)
LGATE2: length 5.5
  IN2 w0.762: v3(62.41,42.47) 61.78,43.11 61.78,47.17 62.16,47.55
  vias: v1(62.46,40.77) v2(62.16,47.78) v2(62.82,47.78) v3(62.41,41.84)
LID_SW#: length 281.1
  TOP w0.102: UE1.115 137.82,20.28 137.83,20.28 137.83,20.68 v2(137.93,20.78) 138.11,20.96 CE30.1 RE71.2 ; v2(15.95,55.33) 15.92,55.3 JLED.4 ; v2(117.25,7.62) 117.25,7.65 v1(116.86,8.04) 115.42,9.48 113.7,9.48 112.79,10.38 112.79,15.08 113.38,15.66 113.38,20.41 113.91,20.95 v2(114.75,20.95)
  IN1 w0.102: 77.91,97.72 77.91,96.7
  IN1 w0.107: 77.91,97.72 77.91,98.89 76.99,99.8 70.36,99.8 69.75,100.41 68.13,100.41 67.68,99.97 66.08,99.97 65.54,100.51 63.82,100.51 62.89,101.43 62,101.43 60.88,102.56 60.88,102.75 56.77,106.86 55.96,106.86 53.4,109.43 50.07,109.43 47.86,107.22 41.64,107.22 40.75,108.11 35.9,108.11 31.17,103.38 31.17,102.67 30.56,102.06 28.38,102.06 25.06,98.73 23.81,98.73 23.3,99.24 21.9,99.24 21.39,98.73 18.6,98.73 16.12,96.26 16.12,55.5 v2(15.95,55.33) ; 77.91,96.7 79.97,94.64 81.46,94.64 83.99,92.12 83.99,88.82 83.24,88.07 83.24,83.62 85.65,81.21 85.65,79.35 85.4,79.1 85.4,69.14 84.64,68.38 84.64,65.33 84.26,64.95 84.26,62.16 86.57,59.85 86.57,54.14 85.15,52.72 85.15,39.04 86.92,37.27 86.92,35.91 88.54,34.29 90.24,34.29 94.74,29.79 95.52,29.79 100.56,24.75 101.82,24.75 102.59,23.99 103.1,23.99 104.38,22.71 104.38,13.65 108.73,9.31 110.15,9.31 111.18,8.28 113.14,8.28 113.42,7.99 116.88,7.99 v2(117.25,7.62)
  IN2 w0.107: v2(137.93,20.78) 137.72,20.78 137.67,20.73 137.32,20.73 136.99,20.4 135.79,20.4 135.34,19.94 130.82,19.94 130.18,19.31 126.05,19.31 125.64,19.73 125.2,19.73 125,19.92 115.77,19.92 v2(114.75,20.95)
LINE1-L: length 4.8
  BOTTOM w0.203: UA1.22 192.95,20.89 192.41,21.43 v1(192.41,21.78) 192.41,23.6 191.57,24.44 CA67.1
LINE1-R: length 3.9
  BOTTOM w0.203: CA68.1 192.03,22.65 192.03,21.19 192.73,20.49 UA1.21
LINE1-VREFO-L: length 14.5
  TOP w0.254: v2(196.93,23.91) 196.93,24.04 197.16,24.27 197.16,26.43 194.79,28.81 v1(193.54,28.81) 190.25,28.81 189.41,29.65 v2(189.41,30.03)
  BOTTOM w0.254: v2(189.41,30.03) 188.83,29.44 RA165.1 ; v2(196.93,23.91) 196.93,23.91 196.72,23.7 196.72,23.02 196.73,23.02 UA1.31
LINE1-VREFO-R: length 14
  TOP w0.254: v2(189.16,26.47) 189.67,26.98 189.67,27.36 190.3,28 195,28 v1(196.28,26.71) 196.78,26.22 196.78,24.45 196.29,23.97 v2(196.29,23.93)
  BOTTOM w0.254: UA1.30 196.33,23.18 196.33,23.9 v2(196.29,23.93) ; v2(189.16,26.47) 188.83,26.8 RA166.1
LINE-IN-L: length 19.6
  TOP w0.254: RA80.2 189.11,28.93 v2(189.41,28.63)
  BOTTOM w0.254: RA165.2 189.74,28.96 v2(189.41,28.63) ; RA83.1 191.12,29.3 LA8.2 190.19,28.38 189.67,28.38 v2(189.41,28.63) ; v2(189.41,28.63) 189.16,28.38 188.14,28.38 187.59,27.82 v1(187.59,26.95) 187.59,25.89 188.27,25.2 194.11,25.2 194.49,25.58 194.49,26.09 194.75,26.34 196.42,26.34 196.86,25.91 RA55.2
LINE-IN-R: length 19
  TOP w0.254: v2(189.41,27.87) 189.21,28.07 RA82.2
  BOTTOM w0.254: v2(189.41,27.87) 189.74,27.54 RA166.2 ; v2(189.41,27.87) 189.54,28 190.31,28 LA9.2 191.12,27.19 RA84.1 ; v2(189.41,27.87) 189.29,28 188.35,28 188.02,27.66 188.02,26.09 188.5,25.61 v1(188.91,25.61) 193.88,25.61 194.11,25.84 194.11,26.34 194.49,26.73 196.98,26.73 197.75,25.96 RA56.2
LPC_LAD0: length 113.7
  TOP w0.102: v2(132.44,13.82) 132.16,14.11 UE1.10
  IN1 w0.107: v2(131.45,20.4) 132.36,21.31 136.63,21.31 136.96,21.65 141.23,21.65 141.45,21.86 142.61,21.86 144.28,20.19 147.25,20.19 147.95,20.88 149.89,20.88 150.98,21.98 153.4,21.98 154.46,23.04 154.97,23.04 155.68,23.75 155.68,25.25 158.17,27.74 158.17,33.2 160.08,35.11 161.55,35.11 163.33,36.89 164.46,36.89 165.17,37.6 166.29,37.6 167.82,39.13 167.82,41.79 166.93,42.68 166.93,52.76 v2(166.81,52.89)
  BOTTOM w0.076: UC1.AU14 148.6,81.07 148.6,80.59 148.56,80.55 148.56,79.09 148.65,79 148.65,77.33 149.15,76.83 v1(149.15,75.96) 149.15,73.45 148.77,73.07 148.77,71.81
  BOTTOM w0.102: v2(166.81,52.89) 166.68,52.89 165.66,53.9 165.66,56.19 162.64,59.21 161.47,59.21 159.54,61.14 152.51,61.14 148.77,64.88 148.77,71.81 ; v2(131.45,20.4) 131.45,14.96 132.44,13.97 v2(132.44,13.82)
LPC_LAD1: length 120.9
  TOP w0.102: v2(133.05,13.85) 133.05,14.18 132.32,14.91 UE1.8
  IN1 w0.107: v2(155.56,21.62) 155.96,22.03 155.96,25.15 158.43,27.61 158.43,33.08 160.2,34.85 161.63,34.85 163.41,36.63 164.57,36.63 165.28,37.34 166.39,37.34 168.08,39.03 168.08,41.97 167.22,42.83 167.22,53.17 v2(167.7,53.65)
  IN2 w0.107: v2(157.13,10.91) 157.02,10.8 155.38,10.8 154.78,11.4 152.2,11.4 151.88,11.08 149.8,11.08 148.88,12 148.88,13.59 148.63,13.84 141.18,13.84 141.03,13.99 135.53,13.99 135.21,13.67 133.23,13.67 v2(133.05,13.85)
  BOTTOM w0.076: UC1.AW12 149.4,79.68 149.4,77.86 149.84,77.42 v1(149.84,77.42) 149.92,77.34 149.92,72.19 149.54,71.81
  BOTTOM w0.102: v2(167.7,53.65) 167.7,55.05 166.43,56.32 166.43,56.57 163.05,59.95 161.82,59.95 159.86,61.9 152.89,61.9 149.54,65.26 149.54,71.81 ; v2(155.56,21.62) 154.9,20.96 154.9,17.89 155.45,17.33 155.45,15.49 157.47,13.47 157.47,11.26 v2(157.13,10.91)
LPC_LAD2: length 109.7
  TOP w0.102: v2(132.33,15.91) 131.73,15.31 UE1.7
  IN1 w0.107: v2(167.7,52.89) 167.7,52.76 168.33,52.13 168.33,38.93 166.5,37.1 165.39,37.1 164.66,36.38 163.48,36.38 161.7,34.6 160.33,34.6 158.68,32.95 158.68,27.49 156.27,25.07 156.27,22.71 156.67,22.31 156.67,20.27 156.14,19.74 150.93,19.74 150.37,19.18 144.28,19.18 144.25,19.15 136.01,19.15 135.48,18.62 v2(131.97,18.62)
  BOTTOM w0.076: UC1.AY12 149.02,77.71 149.7,77.03 149.7,73.24 v1(149.59,73.13) 149.59,73.13 149.28,72.83 149.28,71.81
  BOTTOM w0.102: 149.28,71.81 149.28,65.13 152.76,61.65 159.75,61.65 161.68,59.72 162.9,59.72 166.17,56.44 166.17,55.43 167.21,54.39 167.21,53.37 v2(167.7,52.89) ; v2(132.33,15.91) 131.68,16.56 131.68,18.33 v2(131.97,18.62)
LPC_LAD3: length 124.1
  TOP w0.102: UE1.5 129.34,16.11 128.48,16.97 128.48,17.86 127.56,18.77 v1(127.56,26.06) 127.56,27.41 v2(128.07,27.92)
  IN2 w0.076: v2(149.39,80.36) 149.39,80.09 150.55,78.92 150.55,77.78 151.31,77.02 152.08,77.02 153.09,76 153.73,76 158.13,71.59 158.38,71.59 158.76,71.21 159.35,71.21
  IN2 w0.107: v2(128.07,27.92) 128.07,27.13 128.74,26.46 168.53,26.46 169.53,27.46 169.53,30.92 169.98,31.37 169.98,34.73 171.3,36.05 171.3,42.57 170.8,43.08 170.8,46.89 170.98,47.06 170.98,59.39 168.36,62.01 168.36,64.85 166.85,66.36 164.69,66.36 162.54,68.51 162.54,69.5 160.83,71.21 159.35,71.21
  BOTTOM w0.076: UC1.AW11 149.69,80.06 v2(149.39,80.36)
LPC_LFRAME#: length 111.1
  TOP w0.102: v2(129.85,21.04) 129.52,20.71 129.52,19.36 v1(129.39,19.23) 129.39,17.94 129.66,17.67 129.66,16.93 130.09,16.51 UE1.4
  IN1 w0.107: v2(166.81,53.65) 166.3,53.14 166.3,42.98 167.59,41.69 167.59,39.24 166.21,37.86 165.08,37.86 164.36,37.14 163.25,37.14 161.47,35.36 159.95,35.36 157.92,33.33 157.92,27.87 155.43,25.38 155.43,24.54 153.17,22.28 150.88,22.28 149.69,21.09 143.71,21.09 142.7,22.1 141.3,22.1 141.1,21.9 136.79,21.9 136.4,21.52 131.45,21.52 130.61,20.68 130.21,20.68 v2(129.85,21.04)
  BOTTOM w0.076: 149.03,71.81 149.03,73.02 149.5,73.48 149.5,76.88 148.85,77.52 148.85,79.07 148.73,79.2 148.73,80.45 UC1.AV12
  BOTTOM w0.102: v2(166.81,53.65) 166.68,53.65 165.92,54.41 165.92,56.32 162.74,59.49 161.55,59.49 159.65,61.4 152.63,61.4 149.03,65 149.03,71.81
LX_1.05V: length 8.4
  IN1 w0.508: v2(182.94,53.78) 180.3,51.13 180.3,49.1 179.13,47.93 v3(179.13,47.55)
  BOTTOM w0.102: v1(172.66,43.44) 173.27,43.44
LX_1.8VSP: length 3.2
  BOTTOM w0.102: v1(82.63,28.58) 83.47,27.74 PL600.1
LX_3V: length 9.5
  IN1 w0.762: v3(63.15,23.93) 63.79,23.3 70.26,23.3 71.76,21.79 71.76,21.76
  vias: v1(62.13,27.08) v3(61.02,25.96) v3(61.07,26.65) v3(61.78,26.6) v3(61.78,25.96) v3(62.54,26.6) v3(62.54,25.96) v3(62.52,25.2) v3(62.52,24.57) v3(63.18,26.6) v3(63.18,25.96) v3(63.18,25.33) v3(63.15,24.57) v3(63.81,26.6) v3(63.81,25.96) v3(72.31,21.17) v3(72.3,20.53)
LX_5V: length 7.6
  IN1 w0.762: 72.19,14.41 71.62,14.41 69.59,12.37 65.46,12.37
  vias: v1(62.19,10.29) v3(60,12.12) v3(60.51,11.49) v3(60.64,12.76) v3(60.89,12.12) v3(61.02,10.98) v3(61.37,11.54) v3(61.52,10.47) v3(62.13,11.54) v3(62.16,10.85) v3(62.82,11.28) v3(62.79,10.47) v3(63.05,11.99) v3(63.56,12.37) v3(63.58,11.18) v3(63.56,10.47) v3(72.3,15.73) v3(72.3,15.09)
LX_CHG: length 7.5
  IN1 w1.016: 41.71,17.96 41.59,18.09 41.59,25.46
  vias: v1(42.6,25.68) v3(38.66,30.28) v3(39.55,30.28) v3(40.44,30.28) v3(41.33,30.28) v3(42.22,28.88) v3(42.22,28) v3(42.22,27.23) v3(42.22,26.22) v3(42.47,17.25) v3(42.93,16.79)
LX_PCIE:
  vias: v1(73.31,58.32) v3(73.06,56.54) v3(73.82,56.49)
M_BA0: length 79.7
  TOP w0.102: v2(57.6,84.9) 57.6,84.62 57.38,84.4 56.67,84.4 56.49,84.58 56.49,85.4 56.37,85.53 55.86,85.53 55.72,85.38 55.72,85.13 55.57,84.97 54.88,84.97 54.78,85.08 54.78,85.42 54.66,85.54 54.49,85.54 54.37,85.42 54.37,85.06 54.25,84.94 54.09,84.94 53.97,85.06 53.97,85.38 53.85,85.5 53.68,85.5 53.56,85.38 53.56,85.08 53.46,84.97 53.26,84.97 53.15,85.08 53.15,85.18 53.04,85.3 52.87,85.3 52.75,85.18 52.75,85.04 52.63,84.92 52.14,84.92 51.99,85.08 51.99,85.25 52.14,85.4 52.43,85.4 52.58,85.55 52.58,85.83 52.45,85.97 52.24,85.97 52.08,85.81 51.94,85.81 51.77,85.97 51.32,85.97 51.2,85.85 51.2,85.49 51.08,85.37 50.91,85.37 50.8,85.47 50.8,85.87 50.68,85.98 50.52,85.98 50.4,85.87 50.4,85.65 50.32,85.58 49.97,85.58 ; v2(33.06,95.67) 33.06,95.88 33.47,96.3 33.72,96.3 33.82,96.4 33.82,96.53 33.77,96.58 33.77,96.84 33.54,97.07 33.54,97.19 33.65,97.31 33.8,97.31 33.98,97.13 34.17,97.13 34.29,97.26 34.29,97.39 UV7.M2 ; v2(33.06,75.86) 33.06,76.07 33.47,76.48 33.7,76.48 33.81,76.58 33.81,76.73 33.77,76.77 33.77,77.03 33.56,77.24 33.56,77.37 33.68,77.49 33.78,77.49 33.96,77.31 34.24,77.31 34.34,77.42 34.34,77.53 UV6.M2
  TOP w0.198: 49.97,85.58 48.19,85.58 45.6,88.17 38.18,88.17 37.88,87.86 37.67,87.86 v1(37.15,87.34) 36.23,86.42 34.52,86.42 34.12,86.82 33.76,86.82 33.51,87.08 33.51,87.56 33.74,87.79 33.74,88.24 33.51,88.47 32.92,88.47 32.75,88.29 32.75,86.8 32.92,86.62 32.92,86.29 32.42,85.78 32.24,85.78 32.01,86.01 31.78,86.01 31.33,85.56 v2(31.33,85.39)
  IN2 w0.107: v2(33.06,75.86) 32.9,76.02 32.9,76.26 31.63,77.53 31.63,80.02 31.39,80.26 31.39,84.26 31.33,84.31 31.33,84.44 31.5,84.61 31.5,84.74 31.38,84.87 30.99,84.87 30.87,84.99 30.87,85.24 30.98,85.35 31.29,85.35 v2(31.33,85.39) 31.4,85.46 31.4,90.43 31.45,90.48 31.45,91.72 33.43,93.7 33.43,95.3 v2(33.06,95.67)
  BOTTOM w0.102: UV8.M2 34.15,92.96 33.73,93.37 33.73,93.81 33.43,94.12 33.43,95.2 33.06,95.57 v2(33.06,95.67) ; v2(33.06,75.86) 33.06,75.75 33.43,75.39 33.43,74.3 33.73,74 33.73,73.56 34.15,73.14 UV5.M2 ; v2(57.6,84.9) 57.6,84.97 57.75,85.12 58.1,85.12 58.25,84.97 58.25,84.56 58.38,84.43 58.38,84.08 58.22,83.93 57.92,83.93 57.77,83.77 57.56,83.77 57.49,83.85 57.49,84.02 57.64,84.18 57.64,84.23 57.74,84.34 57.96,84.34 UV1.J16
M_BA1: length 90.6
  TOP w0.102: v2(34.63,94.96) 34.55,94.88 34.55,93.42 34.76,93.21 34.76,93.06 34.63,92.93 34.49,92.93 34.28,93.14 33.14,93.14 33.04,93.04 33.04,92.84 33.14,92.73 UV7.N8 ; v2(34.63,75.14) 34.55,75.06 34.55,73.59 34.76,73.38 34.76,73.24 34.63,73.11 34.51,73.11 34.29,73.33 33.14,73.33 33.04,73.23 33.04,73.01 33.13,72.92 UV6.N8 ; v2(58.64,84.87) 58.64,85.01 58.55,85.09 58.07,85.09 57.99,85.02 57.99,84.73 57.47,84.2 56.28,84.2 56.17,84.3 56.17,84.41 56.07,84.51 55.87,84.51 55.77,84.41 55.77,84.3 55.67,84.2 55.46,84.2 55.4,84.14 55.1,84.14 54.88,84.36 54.77,84.36 54.55,84.14 54.28,84.14 54.06,84.36 53.93,84.36 53.71,84.14 53.52,84.14 53.37,84.28 53.19,84.28 53.05,84.14 52.5,84.14 52.43,84.21 52.43,84.6 52.31,84.71 52.15,84.71 52.03,84.6 52.03,84.33 51.93,84.23 51.73,84.23 51.62,84.33 51.62,84.52 51.51,84.64 51.34,84.64 51.22,84.52 51.22,84.33 51.12,84.23 50.91,84.23 50.81,84.33 50.81,84.58 50.7,84.69 50.32,84.69 50.04,84.97 49.97,84.97
  TOP w0.198: 49.97,84.97 47.94,84.97 45.35,87.55 v1(43.01,87.55) 38.53,87.55 38.18,87.2 37.88,87.2 36.48,85.81 34.27,85.81 33.92,86.16 33.76,86.16 33.61,86.01 v2(33.61,85.81)
  IN2 w0.107: v2(34.63,94.96) 34.61,94.94 34.61,94.55 34.37,94.31 34.37,93.43 32.87,91.93 32.87,90.58 32.62,90.33 32.62,89.95 32.82,89.74 32.82,89.51 32.62,89.31 32.62,89.01 32.73,88.91 32.77,88.91 32.87,88.8 32.87,88.59 32.77,88.48 32.73,88.48 32.62,88.37 32.62,88.09 32.77,87.94 33.38,87.94 33.51,87.81 33.51,87.57 33.4,87.46 32.74,87.46 32.62,87.34 32.62,87.16 32.74,87.04 33.64,87.04 33.76,86.91 33.76,86.73 33.64,86.61 32.96,86.61 32.82,86.47 32.82,86.27 32.96,86.14 33.25,86.14 33.36,86.24 33.81,86.24 34.09,86.51 34.27,86.51 34.41,86.38 34.41,86.2 34.13,85.92 34.13,85.65 34.28,85.5 34.58,85.5 34.73,85.35 34.73,85.25 34.58,85.09 34.42,85.09 34.27,84.94 34.27,84.56 34.12,84.41 33.84,84.41 33.69,84.56 33.69,85.09 33.81,85.22 33.81,85.6 v2(33.61,85.81) 33.61,85.7 33.25,85.35 33.25,84.54 32.7,83.98 32.7,80.88 32.65,80.83 32.65,80.14 32.29,79.79 32.29,77.78 33.81,76.26 34.01,76.26 34.24,76.02 34.24,74.78 33.58,74.12 33.58,72.95 33.33,72.7 33.33,72.09 33.48,71.94 33.76,71.94 34.14,72.32 34.14,73.94 34.65,74.45 34.65,75.13 v2(34.63,75.14)
  BOTTOM w0.102: v2(34.63,75.14) 34.63,75.26 34.24,75.65 34.24,76.01 34.53,76.3 34.53,77.09 34.29,77.33 33.06,77.33 32.96,77.43 32.96,77.62 33.06,77.72 UV5.N8 ; v2(34.63,94.96) 34.49,95.1 34.49,95.27 34.24,95.52 34.24,95.82 34.53,96.11 34.53,96.9 34.29,97.14 33.07,97.14 32.97,97.24 32.97,97.43 33.07,97.53 UV8.N8 ; v2(58.64,84.87) 58.64,85.05 58.71,85.12 59.01,85.12 59.1,85.03 59.1,84.85 59.01,84.76 59.01,84.61 59.13,84.49 59.5,84.49 59.75,84.74 59.75,84.95 UV1.L15
M_BA2: length 66.9
  TOP w0.102: v2(33.85,75.86) 33.52,75.86 33.46,75.92 33.46,76.18 33.55,76.27 34.2,76.27 34.35,76.42 34.35,76.88 34.31,76.92 UV6.M3 ; v2(33.85,95.67) 33.52,95.67 33.46,95.73 33.46,95.96 33.58,96.08 34.28,96.08 34.35,96.15 34.35,96.69 34.31,96.73 UV7.M3
  IN1 w0.102: v2(56.03,88.42) 55.82,88.62 55.53,88.62 54.46,87.56 53.78,87.56 53.4,87.94 51.62,87.94 51.34,87.66
  IN1 w0.203: v2(32.41,86.46) 31.86,87.02 31.86,87.25 30.64,88.47 29.67,88.47 29.37,88.78 29.37,90 29.72,90.35 31.02,90.35 31.27,90.61 31.96,90.61 32.26,90.3 32.98,90.3 33.61,89.67 34.02,89.67 35.19,88.5 38.92,88.5 39.58,87.84 41.94,87.84 42.12,87.66 51.34,87.66
  IN2 w0.107: v2(33.85,95.67) 34.22,95.3 34.22,94.47 34.14,94.39 34.14,93.6 32.06,91.52 32.06,90.58 32.21,90.43 32.21,86.66 v2(32.41,86.46) 32.41,85.35 32.82,84.94 32.82,84.71 32.26,84.15 32.26,80.19 32.06,79.99 32.06,77.71 33.85,75.92 v2(33.85,75.86)
  BOTTOM w0.102: v2(33.85,75.86) 33.85,75.74 34.23,75.36 34.23,74.97 34.13,74.86 34.13,73.74 UV5.M3 ; v2(56.03,88.42) 56.29,88.42 56.5,88.22 56.5,88 UV1.G11 ; v2(33.85,95.67) 33.85,95.55 34.23,95.17 34.23,94.78 34.09,94.64 34.09,93.59 UV8.M3
M_CAS#0: length 52.5
  TOP w0.124: UV6.K3 35.75,76.96 35.63,77.08 35.63,77.08 35.48,77.23 35.38,77.23 35.28,77.14 35.28,77.05 35.28,76.68 35.2,76.6 35.2,76.36 35.31,76.26 35.52,76.26 35.65,76.39 35.65,76.47 35.75,76.57 36.1,76.57 36.17,76.5 36.17,76.36 35.83,76.02 35.83,75.69 35.97,75.54 36.14,75.54 36.25,75.66 36.25,75.83 v2(36.22,75.86)
  IN1 w0.13: v2(35.36,83.37) 35.36,83.14 35.26,83.04 35.06,83.04 34.9,82.87 34.9,82.69 34.98,82.61 36.05,82.61 36.28,82.38 45.08,82.38 45.21,82.25 45.21,82.1 45.34,81.97 45.6,81.97 45.73,82.1 45.73,82.25 45.86,82.38 46.12,82.38 46.25,82.25 46.25,82.1 46.38,81.97 46.64,81.97 46.77,82.1 46.77,82.25 46.9,82.38 47.16,82.38 47.29,82.25 47.29,82.1 47.41,81.97 47.67,81.97 47.8,82.1 47.8,82.25 47.93,82.38 48.19,82.38 48.32,82.25 48.32,82.1 48.45,81.97 48.71,81.97 48.84,82.1 48.84,82.25 48.97,82.38 49.23,82.38 49.36,82.25 49.36,82.1 49.49,81.97 49.74,81.97 49.87,82.1 49.87,82.27 49.99,82.4 50.4,82.4 50.53,82.27 50.53,81.94 50.65,81.82 50.92,81.82 51.05,81.95 51.05,82.25 51.18,82.38 51.44,82.38 51.57,82.25 51.57,81.95 51.7,81.82 52.38,81.82 52.5,81.94 52.5,82.04 52.63,82.17 52.89,82.17 53.02,82.04 53.02,81.69 53.15,81.56 53.55,81.56 53.68,81.43 53.68,81.26 53.81,81.13 54.07,81.13 54.2,81.26 54.2,81.43 54.33,81.56 54.64,81.56 54.69,81.62 55.53,81.62 55.81,81.89 56.14,81.89 56.42,81.61 56.42,81.41 56.31,81.3 v2(56.08,81.3)
  IN2 w0.13: v2(35.36,83.37) 35.29,83.37 35.08,83.57 35.08,83.75 35.57,84.23 35.72,84.23 35.82,84.13 35.82,83.95 35.69,83.82 35.69,83.67 35.82,83.54 35.82,83.19 35.69,83.06 35.69,82.86 35.82,82.73 35.82,82.66 35.53,82.37 35.17,82.37 34.91,82.63 34.73,82.63 34.55,82.45 34.55,82.27 34.81,82 34.81,81.82 34.55,81.56 34.55,80.75 34.89,80.41 34.89,79.97 35.02,79.84 35.06,79.84 35.19,79.71 35.19,79.45 35.06,79.32 35.02,79.32 34.89,79.19 34.89,78.93 35.02,78.8 35.06,78.8 35.19,78.67 35.19,78.41 35.06,78.28 35.02,78.28 34.89,78.15 34.89,77.65 34.77,77.52 34.77,77.35 34.89,77.23 35.05,77.23 35.27,77.44 35.41,77.44 35.55,77.31 35.55,77.15 35.34,76.94 35.34,76.78 35.46,76.66 35.63,76.66 35.77,76.79 36.05,76.79 36.22,76.62 36.22,76.45 36.1,76.33 36.1,75.98 v2(36.22,75.86)
  BOTTOM w0.124: v2(56.08,81.3) 56.4,81.62 UV1.G19 ; v2(36.22,75.86) 36.49,75.86 36.62,75.73 36.62,74.96 36.38,74.72 35.96,74.72 35.57,74.32 35.57,74.18 35.39,74 35.39,73.4 35.51,73.28 35.75,73.28 35.88,73.4 35.88,73.59 UV5.K3
M_CAS#1: length 50.9
  TOP w0.124: UV7.K3 35.75,96.8 35.66,96.89 35.63,96.89 35.48,97.04 35.38,97.04 35.28,96.95 35.28,96.49 35.2,96.41 35.2,96.23 35.36,96.07 35.59,96.07 35.7,96.18 35.7,96.23 35.9,96.42 36.07,96.42 36.18,96.32 36.18,96.19 35.92,95.94 35.92,95.74 36,95.67 v2(36.25,95.67)
  IN1 w0.102: v2(56.11,84.9) 56.04,84.97 54.68,84.97 54.46,85.18 52.93,85.18 52.77,85.02 52.62,85.02 52.36,85.29 52.22,85.29 52.07,85.14 52.07,85 52.34,84.74 52.34,84.59 51.9,84.15 50.53,84.15 50.3,84.38 50.3,84.71 50.02,84.99 49.97,84.99
  IN1 w0.13: v2(38.23,84.05) 38.87,84.69 39.96,84.69 40.44,85.17 40.84,85.17 40.97,85.04 40.97,84.77 41.1,84.64 41.36,84.64 41.49,84.77 41.49,85.04 41.62,85.17 41.92,85.17 42.06,85.02 42.06,84.36 42.19,84.23 42.45,84.23 42.58,84.36 42.58,84.89 42.84,85.15 47.66,85.15 47.89,84.92 47.89,84.41 48.02,84.28 48.28,84.28 48.41,84.41 48.41,85.06 48.52,85.17 48.99,85.17 49.07,85.1 49.07,84.36 49.2,84.23 49.46,84.23 49.59,84.36 49.59,84.99 49.69,85.09 49.87,85.09 49.97,84.99
  IN2 w0.13: v2(38.23,84.05) 38.11,84.18 38.11,85.15 37.9,85.35 37.9,88.6 35.79,90.71 35.79,93.93 35.83,93.97 35.83,94 36.28,94.45 36.28,94.46 36.62,94.79 36.62,95.12 36.66,95.16 36.66,95.7 36.68,95.72 36.68,96.75 36.21,97.22 36.03,97.22 35.68,96.87 35.68,96.69 36.23,96.14 36.23,95.69 v2(36.25,95.67)
  BOTTOM w0.124: UV8.K3 35.75,93.33 35.67,93.25 35.56,93.25 35.39,93.42 35.39,93.81 35.57,93.99 35.57,94.22 35.88,94.53 36.38,94.53 36.62,94.77 36.62,95.54 36.49,95.67 v2(36.25,95.67) ; v2(56.11,84.9) 56.11,84.61 56.4,84.32 UV1.G16
M_CKE0: length 54.1
  TOP w0.124: UV6.K9 35.75,72.34 36.08,72.68 36.08,73.07 35.84,73.32 35.67,73.32 35.41,73.57 35.41,74.32 36.22,75.13 v2(36.22,75.14)
  IN1 w0.13: v2(57.98,80.1) 58.17,80.29 58.17,80.54 57.89,80.83 55.84,80.83 55.81,80.8 55.05,80.8 55.02,80.83 53.42,80.83 52.71,81.54 44.81,81.54 44.41,81.94 36.13,81.94 35.9,82.17 34.17,82.17 34.04,82.3 33.56,82.3 33.13,82.73 33.13,82.86 33.36,83.09 33.66,83.09 33.86,82.88 34.32,82.88 34.7,83.27 v2(34.7,83.39)
  IN2 w0.13: v2(36.22,75.14) 36.28,75.09 36.28,73.87 36.12,73.71 36.12,72.12 35.97,71.97 35.64,71.97 35.41,72.19 35.41,73.66 35.69,73.94 35.69,74.76 35.82,74.88 35.82,75.67 35.83,75.68 35.83,76.01 35.82,76.01 35.82,76.15 35.62,76.36 35.39,76.36 34.47,77.27 34.47,77.57 34.58,77.67 34.58,80.04 34.12,80.5 34.12,82.63 34.7,83.21 v2(34.7,83.39)
  BOTTOM w0.124: v2(36.22,75.14) 36.22,75.26 35.83,75.66 35.83,76.14 35.31,76.66 35.31,78.08 UV5.K9 ; v2(57.98,80.1) 58.58,80.7 UV1.K20
M_CKE1: length 55.9
  TOP w0.124: v2(36.22,94.96) 36.22,94.94 35.41,94.13 35.41,93.38 35.67,93.13 35.84,93.13 36.08,92.88 36.08,92.49 35.75,92.15 UV7.K9 ; v2(57.6,82.5) 57.48,82.5 57.38,82.6 57.38,83.16 57.26,83.29 57.03,83.29 56.9,83.16 56.9,82.99 56.78,82.86 56.55,82.86 56.42,82.99 56.42,83.16 56.29,83.29 56.22,83.29 56.11,83.4 53.35,83.4 53.14,83.19 52.23,83.19 52,82.96 50.3,82.96 50.3,82.97 50.28,82.97 50.12,83.12 47.19,83.12 44.81,85.5 40.72,85.5 40.29,85.93 39.78,85.93 39.71,86.01 39.53,86.01 39.4,85.88 39.4,85.53 39.2,85.32 38.97,85.32 38.84,85.45 38.84,85.63 38.69,85.78 38.51,85.78 38.32,85.59 38.32,85.28 38.18,85.15 37.6,85.15 v2(37.52,85.07)
  IN2 w0.13: v2(37.52,85.07) 37.65,84.94 37.65,84.48 37.47,84.31 37.04,84.31 36.91,84.43 36.91,84.61 36.79,84.74 35.79,84.74 35.67,84.87 35.67,85.32 35.79,85.45 37.34,85.45 37.47,85.58 37.47,85.83 37.34,85.96 37.01,85.96 36.89,86.08 36.89,86.39 36.99,86.49 37.32,86.49 37.45,86.62 37.45,86.88 37.32,87.01 37.02,87.01 36.91,87.11 36.91,87.38 37.04,87.51 37.22,87.51 37.34,87.63 37.34,87.81 37.46,87.93 37.46,88.1 37.34,88.22 37.17,88.22 37.04,88.09 36.86,88.09 36.72,88.23 36.72,88.54 36.96,88.78 36.96,88.93 36.78,89.12 36.59,89.12 36.38,88.9 36.2,88.9 36.02,89.09 36.02,89.27 36.23,89.48 36.23,89.67 36.04,89.85 35.86,89.85 35.55,89.53 35.37,89.53 35.18,89.72 35.18,89.9 35.49,90.21 35.49,90.4 35.31,90.58 35.13,90.58 34.96,90.41 34.77,90.41 34.55,90.63 34.55,91.47 34.68,91.6 35.13,91.6 35.26,91.72 35.26,91.86 35.14,91.98 35.01,91.98 34.88,92.11 34.88,92.41 35.54,93.07 35.54,94.04 36.05,94.55 36.05,94.65 36.22,94.82 v2(36.22,94.96)
  BOTTOM w0.102: UV1.J17 58.07,83.17 58.07,83.47 57.97,83.57 57.69,83.57 57.56,83.44 57.56,82.54 v2(57.6,82.5)
  BOTTOM w0.124: UV8.K9 35.75,98.06 35.34,97.65 35.34,96.55 35.83,96.06 35.83,95.47 36.22,95.08 v2(36.22,94.96)
M_CLK0: length 62.5
  TOP w0.102: v2(37.87,74.81) 37.66,74.81 37.38,74.53 36.34,74.53 36.19,74.38 36.19,73.51 36.31,73.38 36.45,73.38 36.55,73.48 UV6.J7
  IN1 w0.102: 36.52,74.17 36.52,74.2 36.8,74.48 37.17,74.48 37.51,74.81 v2(37.87,74.81) 37.87,74.96 38.28,75.37 38.28,75.86 37.98,76.16 37.56,76.16 37.54,76.18 ; 54.73,76.93 54.75,76.95 55.47,76.95 55.75,76.67 55.88,76.67 56.18,76.37 56.18,76.1 56.25,76.03 56.25,76.01 56.52,75.74 56.52,74.68 56.24,74.4 55.99,74.4 55.77,74.18 55.77,73.92 55.67,73.82 55.46,73.82 55.36,73.92 55.36,74.18 55.14,74.4 54.73,74.4 54.44,74.1 54.44,73.1 54.99,72.55 55.73,72.55 57.39,74.21 57.39,76.24 57.41,76.26 57.41,76.4 57.48,76.47 v2(57.59,76.47)
  IN1 w0.14: 54.73,76.93 54.59,76.79 54.59,76.16 54.32,75.89 53.76,75.89 53.49,76.16 53.49,78.39 53.35,78.53 52.16,78.53 51.42,79.28 46.12,79.28 45.76,78.92 45.09,78.92 44.73,79.27 44.1,79.27 43.78,79.6 37.04,79.6 36.91,79.47 36.91,78.87 36.54,78.5 35.24,78.5 35.11,78.38 35.11,77.55 34.52,76.97 34.52,76.61 34.63,76.51 35.43,76.51 35.55,76.63 35.55,77.14 35.82,77.41 36.3,77.41 36.57,77.14 36.57,76.63 36.69,76.51 37.22,76.51 37.54,76.18 ; v2(38.24,69.69) 38.24,69.7 38.09,69.86 38.09,70.12 36.87,71.34 36.87,71.5 36.52,71.84 36.52,74.17
  BOTTOM w0.102: v2(57.59,76.47) 57.47,76.59 57.26,76.59 57.2,76.53 UV1.H26 ; UV5.J7 36.55,76.72 36.81,76.47 37.25,76.47 37.82,75.89 38.12,75.89 38.29,75.72 38.29,75.24 v2(37.87,74.81)
  BOTTOM w0.137: v2(38.24,69.69) 38.13,69.58 38.13,69.24 RV48.1
M_CLK1: length 62.6
  TOP w0.102: v2(37.97,94.65) 37.68,94.65 37.38,94.35 36.34,94.35 36.19,94.19 36.19,93.34 36.28,93.25 36.46,93.25 36.55,93.34 UV7.J7
  IN1 w0.102: 49.97,89.84 49.99,89.84 50.06,89.78 53.92,89.78 54.08,89.62 56.18,89.62 56.42,89.85 56.42,90.05 56.34,90.12 56.12,90.12 v2(56.01,90.01) ; 38.46,90.73 38.46,90.76 38.4,90.82 38.4,91.44 37.91,91.93 36.6,91.93 35.92,92.61 35.92,93.74 35.68,93.98 35.28,93.98 35.03,93.74 35.03,93.07 34.91,92.94 34.6,92.94 34.47,93.07 34.47,94.24 34.6,94.37 37.24,94.37 37.25,94.37 37.25,94.37 37.6,94.71 37.6,94.72 37.75,94.87 37.95,94.87 38,94.82 38,94.68 v2(37.97,94.65) 38.1,94.65 38.54,95.09 38.54,95.53 38.16,95.91 37.63,95.91 37.08,96.47 36.92,96.47 36.9,96.49 36.89,96.49
  IN1 w0.14: v2(38.88,100.5) 38.8,100.5 38.53,100.22 38.53,99.97 37.81,99.25 37.29,99.25 36.19,98.16 36.19,97.06 36.77,96.49 36.89,96.49 ; 38.46,90.73 38.46,90.4 38.6,90.26 38.79,90.26 38.89,90.36 38.89,90.62 39.21,90.94 40.08,90.94 40.4,90.62 40.4,89.56 40.53,89.44 40.95,89.44 41.08,89.56 41.08,90.5 41.48,90.91 42.66,90.91 43.01,90.57 43.01,90.02 42.81,89.82 42.81,89.43 42.96,89.29 43.49,89.29 43.63,89.43 43.63,90.5 43.96,90.83 44.52,90.83 44.85,90.5 44.85,89.43 44.99,89.29 45.27,89.29 45.41,89.43 45.41,90.5 45.74,90.83 46.3,90.83 46.63,90.5 46.63,89.43 46.77,89.29 47.05,89.29 47.19,89.43 47.19,91.07 47.51,91.39 48.4,91.39 48.72,91.07 48.72,89.71 48.85,89.58 49.11,89.58 49.37,89.84 49.97,89.84
  BOTTOM w0.102: v2(56.01,90.01) 56.01,90.04 56.12,90.15 56.32,90.15 56.4,90.07 UV1.G9
  BOTTOM w0.124: UV8.J7 36.55,96.53 36.76,96.32 37.22,96.32 37.67,95.86 37.96,95.86 38.29,95.53 38.29,95.18 38.05,94.93 38.01,94.93 37.9,94.82 37.9,94.72 v2(37.97,94.65)
  BOTTOM w0.137: RV54.1 39,101.32 38.69,101.02 38.69,100.98 38.69,100.69 38.69,100.69 v2(38.88,100.5)
M_CLK#0: length 63.1
  TOP w0.102: UV6.K7 35.89,73.72 35.97,73.8 35.97,74.46 36.24,74.74 37.27,74.74 37.47,74.93 37.47,74.98 37.7,75.22 37.86,75.22 37.95,75.32 37.95,75.44 v2(37.89,75.51)
  IN1 w0.102: 54.56,77.1 54.57,77.11 54.6,77.11 54.64,77.15 54.82,77.15 55.55,77.15 55.83,76.87 55.96,76.87 56.38,76.46 56.38,76.19 56.45,76.11 56.45,76.09 56.72,75.82 56.72,74.6 56.33,74.2 56.07,74.2 55.97,74.1 55.97,73.83 55.75,73.61 55.38,73.61 55.16,73.83 55.16,74.1 55.06,74.2 54.82,74.2 54.64,74.02 54.64,73.18 55.07,72.75 55.65,72.75 57.19,74.29 57.19,76.89 v2(57.6,77.3) ; 36.19,74.17 36.22,74.2 36.23,74.2 36.71,74.68 37.09,74.68 37.48,75.08 37.48,75.11 v2(37.89,75.51) 37.97,75.51 38.08,75.62 38.08,75.77 37.89,75.96 37.64,75.96 37.45,75.96 37.41,76 37.38,76 37.37,76.01
  IN1 w0.14: 54.56,77.1 54.35,76.89 54.35,76.26 54.22,76.13 53.86,76.13 53.73,76.26 53.73,78.49 53.45,78.77 52.27,78.77 51.52,79.52 50.11,79.52 50.02,79.61 45.98,79.61 45.62,79.25 45.22,79.25 44.87,79.6 44.43,79.6 44.34,79.51 44.2,79.51 43.88,79.84 36.94,79.84 36.67,79.57 36.67,78.97 36.44,78.74 35.14,78.74 34.87,78.48 34.87,77.65 34.28,77.07 34.28,76.51 34.53,76.27 35.53,76.27 35.79,76.53 35.79,77.04 35.92,77.17 36.2,77.17 36.33,77.04 36.33,76.53 36.59,76.27 37.12,76.27 37.37,76.01 ; v2(37.66,69.69) 37.66,70.08 36.54,71.2 36.54,71.36 36.19,71.71 36.19,74.17
  BOTTOM w0.102: v2(37.89,75.51) 37.89,75.54 37.16,76.26 36.72,76.26 36.21,76.77 36.21,77.21 36.13,77.29 35.84,77.29 35.75,77.2 UV5.K7 ; UV1.H25 v2(57.6,77.3)
  BOTTOM w0.137: RV49.1 37.8,69.24 37.8,69.55 v2(37.66,69.69)
M_CLK#1: length 62.5
  TOP w0.102: v2(37.89,95.32) 37.89,95.09 37.82,95.03 37.7,95.03 37.47,94.79 37.47,94.75 37.27,94.55 36.24,94.55 35.97,94.28 35.97,93.61 35.89,93.53 UV7.K7
  IN1 w0.102: 38.13,90.73 38.13,90.76 38.19,90.82 38.19,91.36 37.83,91.72 36.52,91.72 35.72,92.53 35.72,93.65 35.59,93.78 35.36,93.78 35.24,93.65 35.24,92.99 34.99,92.74 34.52,92.74 34.27,92.99 34.27,94.32 34.52,94.57 37.16,94.57 37.17,94.58 37.17,94.58 37.39,94.8 37.39,94.8 37.89,95.3 v2(37.89,95.32) 38.03,95.18 38.24,95.18 38.34,95.28 38.34,95.45 38.07,95.71 37.55,95.71 37.03,96.23 36.92,96.23 36.91,96.24 36.89,96.24 ; 49.97,89.51 49.99,89.51 50.06,89.58 53.83,89.58 54,89.41 56.27,89.41 56.81,89.96 v2(56.81,89.99)
  IN1 w0.14: 38.13,90.73 38.13,90.26 38.46,89.93 38.93,89.93 39.22,90.23 39.22,90.48 39.35,90.61 39.94,90.61 40.07,90.48 40.07,89.43 40.39,89.11 41.09,89.11 41.41,89.43 41.41,90.37 41.62,90.58 42.53,90.58 42.68,90.43 42.68,90.16 42.48,89.96 42.48,89.3 42.82,88.96 43.63,88.96 43.96,89.29 43.96,90.36 44.1,90.5 44.38,90.5 44.52,90.36 44.52,89.29 44.85,88.96 45.41,88.96 45.74,89.29 45.74,90.36 45.88,90.5 46.16,90.5 46.3,90.36 46.3,89.29 46.63,88.96 47.18,88.96 47.52,89.29 47.52,90.94 47.64,91.06 48.27,91.06 48.39,90.94 48.39,89.57 48.71,89.25 49.25,89.25 49.51,89.51 49.97,89.51 ; 36.89,96.24 36.67,96.24 35.95,96.96 35.95,98.26 37.19,99.5 37.71,99.5 38.19,99.98 38.19,100.36 38.06,100.5 v2(37.9,100.5)
  BOTTOM w0.102: UV1.H9 57.15,89.7 56.86,89.99 v2(56.81,89.99)
  BOTTOM w0.124: v2(37.89,95.32) 37.88,95.32 37.11,96.1 36.67,96.1 36.32,96.44 36.32,96.47 36.21,96.58 36.21,97 36.08,97.12 35.87,97.12 35.75,97 UV8.K7
  BOTTOM w0.137: RV55.1 38.36,101.12 38.36,100.83 38.03,100.5 v2(37.9,100.5)
M_CLK_DDR0: length 50.5
  IN1 w0.076: v2(134.24,76.96) 134.04,76.76 133.91,76.76 133.47,76.32 133.47,74.72 131.62,72.87 131.62,72.25 131.79,72.08 132.05,72.08 132.21,71.92 132.21,71.71 132.09,71.58 131.83,71.58 131.65,71.41 131.65,70.87 131.61,70.83 131.61,70.81
  IN1 w0.114: v2(129.79,44.34) 129.79,44.41 129.64,44.56 129.35,44.56 129.07,44.85 129.07,47.17 129.7,47.81 129.7,48.35 129.42,48.64 129.02,48.64 128.76,48.89 128.76,56.89 128.4,57.25 128.4,57.81 128.76,58.17 128.76,58.53 128.4,58.89 128.4,59.73 128.83,60.15 128.83,60.52 128.4,60.94 128.4,61.85 129.81,63.25 130.17,63.25 131.02,62.4 131.21,62.4 131.35,62.54 131.35,62.73 130.5,63.58 130.5,63.97 130.99,64.46 131.27,64.46 131.61,64.81 131.61,70.81
  BOTTOM w0.076: UC1.AV37 133.53,80.71 133.42,80.6 133.42,76.85 133.6,76.67 133.95,76.67 v2(134.24,76.96)
  BOTTOM w0.112: v2(129.79,44.34) 129.79,44.44 129.72,44.5 128.81,44.5 128.55,44.76 JDIMM1.101
M_CLK_DDR1: length 49.5
  IN1 w0.076: 132.59,71.81 132.59,71.82 132.72,71.95 132.72,73.43 133.81,74.53 133.81,74.85 134.06,75.1 134.53,75.1 134.59,75.16 134.59,75.26 134.53,75.33 134.07,75.33 133.91,75.48 133.91,75.82 134.07,75.98 134.57,75.98 134.8,76.21 134.8,79.18 134.65,79.33 134.43,79.33 v2(134.18,79.08)
  IN1 w0.114: 132.59,71.81 132.59,62.48 131.15,61.04 130.99,61.04 130.1,61.93 129.73,61.93 129.43,61.62 129.43,61.25 130.31,60.37 130.31,60.2 129.73,59.62 129.73,49.78 130.44,49.07 130.44,48.85 130.8,48.49 130.8,47.66 130.44,47.3 130.44,42.65 130.34,42.55 129.95,42.55 129.79,42.72 v2(129.79,42.81)
  BOTTOM w0.076: UC1.AY36 134.22,79.08 v2(134.18,79.08)
  BOTTOM w0.112: JDIMM1.102 128.85,40.47 128.96,40.58 128.96,42.24 129.22,42.5 129.62,42.5 129.79,42.67 v2(129.79,42.81)
M_CLK_DDR2: length 70
  IN2 w0.076: 133.54,71.05 133.54,71.08 133.66,71.2 133.66,74.58 133.24,75 133.24,81.45 132.64,82.05 132.64,83.62 132.75,83.72 132.85,83.72 v2(133.08,83.49)
  IN2 w0.114: 133.54,71.05 133.54,70.62 133.86,70.3 133.86,69.81 133.54,69.49 133.54,69.21 133.86,68.89 133.86,68.4 133.54,68.08 133.54,67.5 133.86,67.18 133.86,66.69 133.54,66.37 133.54,66.05 133.86,65.73 133.86,65.25 133.54,64.92 133.54,64.41 133.86,64.08 133.86,63.6 133.54,63.27 133.54,62.72 133.86,62.39 133.86,61.91 133.54,61.59 133.54,60.9 133.86,60.58 133.86,60.1 133.54,59.77 133.54,59.44 133.99,58.98 134.16,58.98 134.18,59.01 134.55,59.01 134.86,58.7 134.86,58.33 134.83,58.3 134.83,58.14 134.99,57.98 135.15,57.98 135.18,58.01 135.55,58.01 135.86,57.7 135.86,57.33 135.83,57.31 135.83,57.14 135.99,56.98 136.15,56.98 136.18,57.01 136.55,57.01 136.86,56.7 136.86,56.33 136.83,56.31 136.83,56.14 137.36,55.61 137.52,55.61 137.55,55.64 137.92,55.64 138.23,55.33 138.23,54.96 138.2,54.93 138.2,54.77 138.36,54.61 138.52,54.61 138.55,54.64 138.92,54.64 139.23,54.33 139.23,53.96 139.2,53.94 139.2,53.77 139.36,53.61 139.52,53.61 139.55,53.64 139.92,53.64 140.23,53.33 140.23,52.96 140.2,52.94 140.2,52.77 140.87,52.1 140.87,51.59 140.41,51.13 140.41,50.88 140.52,50.76 141.11,50.76 141.37,50.5 141.37,50.07 141.11,49.81 140.47,49.81 140.36,49.7 140.36,49.46 140.47,49.35 140.79,49.35 141.06,49.07 141.06,48.68 140.79,48.4 140.16,48.4 140.01,48.24 140.01,47.99 140.16,47.84 140.62,47.84 140.87,47.58 140.87,40.45 141.66,39.66 141.66,36.76 142.12,36.3 142.12,34.04 142.55,33.61 142.55,31.83 142.25,31.53 142.06,31.53 v2(141.87,31.34)
  BOTTOM w0.076: v2(133.08,83.49) 133.08,83.75 133.21,83.88 133.44,83.88 UC1.AN38
  BOTTOM w0.112: v2(141.87,31.34) 141.68,31.54 141.43,31.54 140.88,32.09 140.88,33.29 140.92,33.33 JDIMM2.101
M_CLK_DDR3: length 69.8
  IN2 w0.076: v2(133.06,84.82) 133.06,84.98 133.01,85.04 132.54,85.04 132.3,84.8 132.3,81.7 132.11,81.51 132.11,75.24 132.58,74.77 132.58,71.14 132.66,71.06 132.66,71.05
  IN2 w0.114: v2(141.87,29.82) 141.87,29.61 141.69,29.43 141.34,29.43 141.18,29.59 141.18,30.93 141.05,31.06 141.05,31.76 141.23,31.95 141.23,32.58 141.03,32.78 141.03,33.45 141.2,33.62 141.2,34.31 141.03,34.48 141.03,35.16 141.23,35.35 141.23,35.92 140.77,36.38 140.77,39.32 139.1,40.99 139.1,42.09 139.54,42.53 139.54,46.69 139.12,47.11 139.12,52.44 138.59,52.96 138.23,52.96 138.02,52.75 137.86,52.75 137.69,52.92 137.69,53.07 137.96,53.34 137.96,53.72 137.4,54.28 137.01,54.28 136.63,53.9 136.35,53.9 136.16,54.1 136.16,54.2 136.25,54.29 136.25,55.03 135.97,55.3 135.68,55.3 135.44,55.06 135.3,55.06 135.1,55.25 135.1,55.48 135.41,55.79 135.41,56.14 134.97,56.58 134.97,56.77 134.59,57.16 134.4,57.16 133.74,57.81 133.74,58 133.36,58.39 133.17,58.39 132.66,58.89 132.66,71.05
  BOTTOM w0.076: v2(133.06,84.82) 133.36,85.12 UC1.AL38
  BOTTOM w0.112: v2(141.87,29.82) 141.87,29.52 141.77,29.42 141.31,29.42 141.1,29.21 141.1,27.94 141.22,27.82 JDIMM2.102
M_CLK_DDR#0: length 50.6
  IN1 w0.076: 131.86,70.81 131.86,70.83 131.82,70.87 131.82,71.34 131.9,71.42 132.15,71.42 132.38,71.64 132.38,72.02 132.15,72.24 131.86,72.24 131.79,72.32 131.79,72.8 133.63,74.65 133.63,76.25 133.98,76.6 134.12,76.6 134.23,76.49 v2(134.23,76.38)
  IN1 w0.114: 131.86,70.81 131.86,64.7 131.32,64.16 131.04,64.16 130.75,63.87 130.75,63.68 131.6,62.83 131.6,62.43 131.32,62.15 130.92,62.15 130.07,63 129.91,63 128.65,61.75 128.65,61.05 129.08,60.62 129.08,60.05 128.65,59.63 128.65,58.99 129.01,58.63 129.01,58.07 128.65,57.71 128.65,57.35 129.01,56.99 129.01,49 129.12,48.89 129.52,48.89 129.95,48.46 129.95,47.71 129.32,47.07 129.32,44.95 129.46,44.81 129.65,44.81 129.79,44.95 v2(129.79,45.1)
  BOTTOM w0.076: v2(134.23,76.38) 134.23,76.4 134.12,76.51 133.53,76.51 133.26,76.78 133.26,80.71 133.67,81.12 UC1.AU37
  BOTTOM w0.112: v2(129.79,45.1) 129.79,44.87 129.68,44.76 128.91,44.76 128.81,44.87 128.81,46.38 129.15,46.73 JDIMM1.103
M_CLK_DDR#1: length 49.6
  IN1 w0.076: 132.79,71.77 132.79,71.79 132.88,71.88 132.88,73.36 133.98,74.46 133.98,74.78 134.13,74.93 134.6,74.93 134.76,75.09 134.76,75.33 134.6,75.49 134.14,75.49 134.08,75.55 134.08,75.75 134.14,75.81 134.64,75.81 134.97,76.14 134.97,79.24 134.72,79.49 134.43,79.49 v2(134.18,79.73)
  IN1 w0.114: v2(129.79,42.05) 130.05,42.31 130.45,42.31 130.69,42.55 130.69,47.2 131.04,47.55 131.04,48.59 130.69,48.95 130.69,49.18 129.98,49.89 129.98,59.52 130.56,60.1 130.56,60.47 129.67,61.36 129.67,61.52 129.84,61.68 130,61.68 130.89,60.79 131.25,60.79 132.84,62.38 132.84,69.84 132.79,69.88 132.79,71.77
  BOTTOM w0.076: v2(134.18,79.73) 134.22,79.73 UC1.AW36
  BOTTOM w0.112: JDIMM1.104 129.45,40.45 129.22,40.68 129.22,42.14 129.32,42.24 129.6,42.24 v2(129.79,42.05)
M_CLK_DDR#2: length 70.2
  IN2 w0.076: v2(133.08,84.25) 133.08,83.98 132.99,83.89 132.68,83.89 132.48,83.69 132.48,81.98 133.08,81.38 133.08,74.93 133.49,74.52 133.49,71.26 133.29,71.06 133.29,71.05
  IN2 w0.114: 133.29,71.05 133.29,70.52 133.61,70.2 133.61,69.92 133.29,69.59 133.29,69.11 133.61,68.78 133.61,68.5 133.29,68.18 133.29,67.4 133.61,67.07 133.61,66.79 133.29,66.47 133.29,65.95 133.61,65.63 133.61,65.35 133.29,65.03 133.29,64.3 133.61,63.98 133.61,63.7 133.29,63.38 133.29,62.61 133.61,62.29 133.61,62.01 133.29,61.69 133.29,60.8 133.61,60.48 133.61,60.2 133.29,59.88 133.29,59.34 133.89,58.73 134.26,58.73 134.29,58.76 134.45,58.76 134.61,58.6 134.61,58.43 134.58,58.41 134.58,58.04 134.89,57.73 135.26,57.73 135.29,57.76 135.45,57.76 135.61,57.6 135.61,57.44 135.58,57.41 135.58,57.04 135.89,56.73 136.26,56.73 136.28,56.76 136.45,56.76 136.61,56.6 136.61,56.44 136.58,56.41 136.58,56.04 137.26,55.36 137.63,55.36 137.66,55.39 137.82,55.39 137.98,55.23 137.98,55.07 137.95,55.04 137.95,54.67 138.26,54.36 138.63,54.36 138.65,54.39 138.82,54.39 138.98,54.23 138.98,54.07 138.95,54.04 138.95,53.67 139.26,53.36 139.63,53.36 139.65,53.39 139.82,53.39 139.98,53.23 139.98,53.07 139.95,53.04 139.95,52.67 140.62,52 140.62,51.69 140.16,51.23 140.16,50.78 140.42,50.52 141.01,50.52 141.12,50.4 141.12,50.17 141.01,50.06 140.37,50.06 140.11,49.8 140.11,49.36 140.37,49.1 140.68,49.1 140.82,48.97 140.82,48.78 140.68,48.65 140.06,48.65 139.76,48.35 139.76,47.88 140.06,47.59 140.51,47.59 140.62,47.48 140.62,40.35 141.41,39.55 141.41,36.65 141.87,36.2 141.87,33.94 142.3,33.51 142.3,31.94 142.14,31.78 141.92,31.78 141.87,31.82 v2(141.87,32.1)
  BOTTOM w0.076: UC1.AM38 133.51,84.22 133.41,84.12 133.2,84.12 v2(133.08,84.25)
  BOTTOM w0.112: v2(141.87,32.1) 141.87,31.95 141.71,31.79 141.54,31.79 141.14,32.19 141.14,33.18 141.52,33.56 JDIMM2.103
M_CLK_DDR#3: length 70
  IN2 w0.076: v2(133.05,85.57) 133.13,85.5 133.13,85.31 133.02,85.2 132.47,85.2 132.14,84.87 132.14,81.77 131.95,81.58 131.95,75.17 132.42,74.7 132.42,71.05
  IN2 w0.114: v2(141.88,29) 141.69,29.18 141.24,29.18 140.93,29.49 140.93,30.82 140.8,30.96 140.8,31.87 140.98,32.05 140.98,32.48 140.78,32.67 140.78,33.56 140.96,33.73 140.96,34.21 140.78,34.38 140.78,35.26 140.98,35.46 140.98,35.82 140.52,36.28 140.52,39.22 138.85,40.89 138.85,42.2 139.29,42.64 139.29,46.59 138.87,47.01 138.87,52.34 138.49,52.71 138.34,52.71 138.12,52.5 137.76,52.5 137.44,52.81 137.44,53.17 137.71,53.44 137.71,53.61 137.3,54.03 137.11,54.03 136.74,53.65 136.25,53.65 135.91,53.99 135.91,54.3 136,54.39 136,54.92 135.87,55.05 135.79,55.05 135.54,54.81 135.2,54.81 134.85,55.15 134.85,55.58 135.16,55.89 135.16,56.04 134.73,56.48 134.73,56.66 134.48,56.91 134.3,56.91 133.5,57.71 133.5,57.89 133.25,58.14 133.07,58.14 132.42,58.79 132.42,71.05
  BOTTOM w0.076: v2(133.05,85.57) 133.33,85.57 UC1.AK38
  BOTTOM w0.112: v2(141.88,29) 141.72,29.16 141.41,29.16 141.36,29.1 141.36,28.05 141.82,27.58 JDIMM2.104
M_CS#0: length 60.7
  TOP w0.102: 49.97,79.73 50.09,79.73 50.15,79.79 50.24,79.79 50.37,79.66 50.37,79.4 50.47,79.3 50.68,79.3 50.78,79.4 50.78,80.02 50.9,80.14 51.06,80.14 51.18,80.02 51.18,79.4 51.29,79.3 51.49,79.3 51.59,79.4 51.59,79.96 51.72,80.09 51.9,80.09 52.03,79.96 52.03,79.85 52.11,79.76 52.25,79.76 52.46,79.97 53.25,79.97 53.38,79.84 53.38,79.43 53.48,79.33 53.69,79.33 53.79,79.43 53.79,79.94 53.91,80.07 54.2,80.07 54.33,79.94 54.33,79.73 54.16,79.56 54.16,79.46 54.29,79.33 54.54,79.33 54.67,79.46 54.67,79.61 54.79,79.73 54.9,79.73 55,79.63 55.53,79.63 55.66,79.51 55.66,79.43 55.78,79.3 56.01,79.3 56.14,79.43 56.14,79.63 56.27,79.76 56.44,79.76 56.57,79.63 56.57,79.46 56.67,79.35 56.9,79.35 57.18,79.07 57.18,78.67 57.03,78.52 56.57,78.52 56.39,78.69 56.39,78.98 56.51,79.1 56.68,79.1 56.8,78.98 v2(56.8,78.9)
  TOP w0.124: v2(33.25,81.19) 33.19,81.19 33,81 32.42,81 32.21,81.21 30.99,81.21 30.87,81.34 30.87,81.61 30.99,81.74 33.56,81.74 33.69,81.61 33.69,81.26 33.81,81.13 34.01,81.13 34.14,81.26 34.14,81.57 34.26,81.69 34.43,81.69 34.55,81.57 34.55,81.28 34.68,81.16 34.93,81.16 35.05,81.28 35.05,81.61 35.18,81.74 35.8,81.74 35.93,81.61 35.93,81.54 36.05,81.41 36.3,81.41 36.43,81.54 36.43,81.61 36.55,81.74 36.8,81.74 36.92,81.61 36.92,81.54 37.05,81.41 37.3,81.41 37.42,81.54 37.42,81.61 37.55,81.74 41.47,81.74 41.62,81.59 41.62,81.54 41.75,81.41 41.99,81.41 42.12,81.54 42.12,81.59 42.27,81.74 42.69,81.74 42.81,81.61 42.81,81.51 42.94,81.39 43.18,81.39 43.31,81.51 43.31,81.61 43.43,81.74 43.7,81.74 45.7,79.73 49.97,79.73 ; UV6.L2 34.95,77.74 35.39,78.19 35.39,78.89 35.3,78.98 34.65,78.98 34.55,78.88 34.55,77.89 34.56,77.87 34.56,76.97 34.56,76.97 34.56,75.92 34.62,75.86 34.62,75.85 v2(34.63,75.85)
  IN2 w0.13: v2(34.63,75.85) 34.62,75.86 34.62,76.11 34.17,76.56 33.89,76.56 33.08,77.37 33.08,77.6 32.95,77.73 32.7,77.73 32.52,77.91 32.52,78.28 32.67,78.44 32.67,78.67 32.52,78.82 32.52,79.3 32.62,79.4 32.92,79.4 33.05,79.53 33.05,79.68 32.9,79.84 32.9,80.01 33.05,80.17 33.05,80.34 33.31,80.6 33.31,81.14 v2(33.25,81.19)
  BOTTOM w0.102: v2(56.8,78.9) 56.98,79.08 56.98,79.2 56.78,79.4 56.78,79.59 56.9,79.71 57.08,79.71 57.2,79.59 UV1.H22
  BOTTOM w0.124: v2(34.63,75.85) 34.62,75.85 34.62,75.74 35.03,75.33 35.03,74.6 34.9,74.47 34.71,74.47 34.61,74.57 34.46,74.57 34.35,74.46 34.35,74.09 34.55,73.88 34.55,72.77 34.4,72.62 34.4,72.48 34.49,72.38 34.72,72.38 34.87,72.53 34.87,72.84 UV5.L2
M_CS#1: length 56.4
  TOP w0.124: v2(34.65,95.67) 34.58,95.74 34.58,98.72 34.65,98.79 35.3,98.79 35.39,98.7 35.39,97.98 UV7.L2
  IN1 w0.13: v2(56.08,87.3) 56.08,87.67 55.96,87.8 55.74,87.8 55.66,87.71 55.66,87.47 55.49,87.3 54.87,87.3 54.72,87.15 53.75,87.15 53.3,87.61 51.8,87.61 51.26,87.06 41.8,87.06 41.61,87.25 39.33,87.25 38.69,87.89 34.93,87.89 34.02,88.8 33.66,88.8 32.77,89.69 31.98,89.69 31.73,89.95 31.45,89.95 31.25,89.74 30.05,89.74 29.95,89.64 29.95,89.18 30.08,89.06 30.87,89.06 32.11,87.81 34.09,87.81 34.42,87.48 34.42,87.18 v2(34.58,87.02)
  IN2 w0.13: v2(34.58,87.02) 34.42,87.18 34.42,87.48 33.28,88.62 33.28,90.4 33.1,90.58 33.1,91.83 34.6,93.32 34.6,94.21 35.03,94.64 35.03,95.29 v2(34.65,95.67)
  BOTTOM w0.124: UV1.G13 56.4,86.98 v2(56.08,87.3) ; UV8.L2 34.95,92.43 34.72,92.2 34.49,92.2 34.36,92.32 34.36,92.4 34.55,92.59 34.55,92.89 34.75,93.1 34.75,93.25 34.55,93.45 34.55,93.7 34.32,93.93 34.32,94.17 34.72,94.57 34.88,94.57 35.03,94.72 35.03,95.12 34.65,95.5 v2(34.65,95.67)
M_DA0: length 48.4
  BOTTOM w0.102: UV1.K27 58.94,75.3 59.01,75.23 59.01,74.75 59.33,74.43 59.75,74.43 59.92,74.25 59.92,73.97 59.72,73.77 59.72,73.61 59.98,73.36 59.98,73.03 59.67,72.72 59.57,72.62 59.21,72.62 59.09,72.5 59.09,72.33 59.21,72.22 59.57,72.22 59.67,72.11
  BOTTOM w0.124: UV5.A2 43.05,72.92 43.36,73.23 43.49,73.23 43.66,73.07 43.66,72.81 43.82,72.65 44.08,72.65 44.15,72.57 44.15,72.04 42.93,70.82 42.93,67.72 42.09,66.88 42.09,66.73 42.3,66.53 42.55,66.53 42.88,66.86 43.21,66.86 43.36,66.7 43.36,66.32 43.47,66.22 43.85,66.22 45.32,64.75 45.83,64.75 45.95,64.62 45.95,64.62 46.08,64.49 46.32,64.49 46.45,64.62 46.45,64.62 46.57,64.75 46.82,64.75 46.95,64.62 46.95,64.62 47.07,64.49 47.32,64.49 47.44,64.62 47.44,64.62 47.57,64.75 47.82,64.75 47.94,64.62 47.94,64.62 48.07,64.49 48.32,64.49 48.44,64.62 48.44,64.62 48.56,64.75 48.81,64.75 48.94,64.62 48.94,64.62 49.06,64.49 49.31,64.49 49.44,64.62 49.44,64.62 49.56,64.75 49.69,64.75 49.87,64.93 50.05,64.93 50.15,64.83 50.33,64.83 50.5,65 50.5,65.18 50.4,65.28 50.4,65.46 50.57,65.63 50.75,65.63 50.85,65.53 51.03,65.53 51.21,65.71 51.21,65.88 51.1,65.99 51.1,66.16 51.28,66.34 51.45,66.34 51.68,66.11 51.86,66.11 52.03,66.28 52.03,66.46 51.81,66.69 51.81,66.87 52.03,67.09 52.13,67.09 52.36,66.86 52.56,66.86 52.69,66.98 52.69,67.31 52.81,67.44 v1(53.8,67.44) 55.98,67.44 56.1,67.57 56.1,67.65 56.23,67.77 56.47,67.77 56.6,67.65 56.6,67.57 56.72,67.44 58.68,67.44 58.81,67.57 58.81,68.05 58.93,68.18 59.14,68.18 59.54,67.77 59.67,67.77 59.87,67.97 59.87,68.15 59.33,68.7 59.33,68.87 59.5,69.05 59.68,69.05 60.11,68.62 60.47,68.62 60.69,68.84 60.69,68.96 60.56,69.08 60.3,69.08 60.18,69.21 60.18,69.46 60.3,69.58 60.56,69.58 60.69,69.71 60.69,69.97 60.56,70.09 60.2,70.09 60.08,70.22 60.08,70.47 60.2,70.59 60.56,70.59 60.69,70.72 60.69,70.97 60.56,71.09 59.87,71.09 59.75,71.22 59.75,71.46 59.87,71.59 60.56,71.59 60.66,71.69 60.66,71.99 60.53,72.11 59.67,72.11
M_DA1: length 48.1
  BOTTOM w0.102: 61.17,69.78 61.17,72.01 60.79,72.39 60.79,73.82 60.51,74.1 60.43,74.1 60.33,74.2 60.27,74.2 59.84,74.63 59.62,74.63 59.22,75.02 59.22,75.31 58.93,75.6 58.67,75.6 58.49,75.42 58.49,74.56 58.35,74.43 58.35,74.26 58.49,74.12 58.49,73.93 58.35,73.79 58.25,73.79 58,74.04 UV1.J29
  BOTTOM w0.124: UV5.C2 41.74,72.53 41.74,71.91 42.02,71.63 42.02,71.37 42.14,71.24 42.43,71.24 42.55,71.12 42.55,70.87 42.43,70.74 42.14,70.74 42.02,70.62 42.02,70.37 42.14,70.25 42.43,70.25 42.55,70.12 42.55,69.87 42.43,69.75 42.14,69.75 42.02,69.62 42.02,69.37 42.14,69.25 42.43,69.25 42.55,69.13 42.55,68.88 42.43,68.75 42.14,68.75 42.02,68.63 42.02,68.38 42.14,68.25 42.43,68.25 42.55,68.13 42.55,67.88 42.43,67.76 42.14,67.76 41.85,67.47 40.7,67.47 40.57,67.34 40.57,67.16 40.7,67.03 41.43,67.03 41.56,66.91 41.56,66.68 41.43,66.55 40.67,66.55 40.54,66.43 40.54,65.89 40.67,65.76 40.97,65.76 41.09,65.89 41.09,65.92 41.21,66.04 41.46,66.04 41.59,65.92 41.59,65.89 41.71,65.76 41.96,65.76 42.09,65.89 42.09,65.92 42.21,66.04 42.46,66.04 42.58,65.92 42.58,65.89 42.71,65.76 43.69,65.76 45.35,64.11 50.2,64.11 51.24,65.16 51.52,65.16 53.42,67.06 v1(55.89,67.06) 59.52,67.06 61.17,68.71 61.17,69.78
M_DA2: length 47.5
  BOTTOM w0.124: UV5.A3 42.92,73.75 42.92,74.15 43.05,74.28 43.43,74.28 44.74,72.98 44.74,71.63 43.77,70.67 43.77,70.45 43.89,70.32 44.08,70.32 44.2,70.2 44.2,69.95 44.08,69.83 43.89,69.83 43.77,69.7 43.77,68.25 44.33,67.7 44.5,67.7 45.14,68.33 45.32,68.33 45.49,68.16 45.49,67.98 44.51,66.99 44.51,66.8 44.84,66.47 45.01,66.47 45.14,66.6 45.32,66.6 45.5,66.43 45.5,66.25 45.36,66.12 45.36,65.94 45.52,65.79 46.18,65.79 46.31,65.91 46.31,66.04 46.44,66.17 46.51,66.17 46.63,66.3 46.63,66.55 46.76,66.68 47.02,66.68 47.25,66.45 47.25,66.13 47.05,65.93 47.05,65.66 47.17,65.54 48.06,65.54 48.19,65.66 48.19,66.24 48.32,66.36 48.51,66.36 49.13,65.74 49.31,65.74 49.48,65.92 49.48,66.09 48.86,66.72 48.86,66.89 49.04,67.07 49.21,67.07 49.84,66.44 50.01,66.44 50.19,66.62 50.19,66.8 49.56,67.42 49.56,67.6 49.79,67.82 49.92,67.82 50.63,67.11 50.81,67.11 51.03,67.34 51.03,67.52 50.7,67.85 50.7,68.18 50.83,68.3 51.14,68.3 51.27,68.18 51.27,67.92 51.39,67.8 51.64,67.8 51.76,67.92 51.76,68.18 51.89,68.3 55.5,68.3 55.63,68.43 55.63,68.68 55.54,68.77 55.54,68.95 55.71,69.12 55.89,69.12 56.4,68.61 56.58,68.61 56.77,68.81 56.77,68.99 56.31,69.44 56.31,69.62 56.49,69.8 56.66,69.8 56.71,69.75 56.77,69.75 57.08,69.45 57.56,69.45 57.69,69.57 57.69,70.24 57.56,70.37 v1(57.5,70.37) 57.14,70.37 57,70.24 56.87,70.24 56.62,70.48 56.62,70.72 56.75,70.84 58.27,70.84 58.4,70.97 58.4,71.23 58.27,71.35 57.62,71.35 57.49,71.48 57.49,72.63 57.59,72.72 57.59,73.03 57.37,73.25 57.37,73.35 57.62,73.6 57.62,73.7 57.46,73.87 57.27,73.87 57.2,73.8 UV1.H30
M_DA3: length 47.1
  BOTTOM w0.124: UV1.H32 57.16,72.86 57.16,71.33 57.04,71.21 56.71,71.21 55.28,69.78 55.28,69.24 54.72,68.69 v1(51.57,68.69) 50.25,68.69 50.09,68.53 49.92,68.53 47.91,66.53 47.73,66.53 47.46,66.79 47.46,66.97 49.04,68.55 49.04,68.73 48.72,69.04 48.54,69.04 46.08,66.58 45.9,66.58 45.64,66.84 45.64,67.02 47.34,68.72 47.34,68.9 47.06,69.18 46.88,69.18 46.06,68.36 45.88,68.36 45.69,68.55 45.69,68.73 46.51,69.55 46.51,69.75 46.35,69.92 46.17,69.92 44.55,68.29 44.37,68.29 44.2,68.46 44.2,68.64 44.41,68.86 44.41,69.04 44.22,69.23 44.22,69.41 44.39,69.59 44.57,69.59 44.76,69.39 44.94,69.39 45.82,70.27 45.82,70.45 45.64,70.62 45.47,70.62 44.93,70.09 44.76,70.09 44.58,70.26 44.58,70.44 45.12,70.97 45.12,71.25 45.24,71.37 45.42,71.37 45.55,71.5 45.55,71.75 45.42,71.87 45.24,71.87 45.12,71.99 45.12,73.16 43.95,74.32 43.95,74.5 43.66,74.79 42.19,74.79 42.09,74.68 42.09,74.24 41.96,74.12 41.7,74.12 41.58,74.24 41.58,74.62 41.43,74.77 40.67,74.77 40.56,74.66 40.56,74.27 40.69,74.14 40.93,74.14 UV5.C3
M_DA4: length 47.5
  BOTTOM w0.124: UV5.C8 41.75,77.32 42.3,77.32 42.55,77.07 42.55,76.77 42.79,76.54 43.65,76.54 44.94,77.83 44.94,79.89 45.19,80.14 45.19,82.15 45.07,82.27 44.81,82.27 44.68,82.39 44.68,82.64 44.81,82.77 45.07,82.77 45.19,82.89 45.19,83.14 45.07,83.27 44.81,83.27 44.68,83.39 44.68,83.64 44.95,83.9 46.67,83.9 46.79,83.77 46.79,83.6 46.6,83.4 45.88,83.4 45.75,83.28 45.75,83.03 45.88,82.91 v1(46.18,82.91) 46.67,82.91 46.79,82.78 46.79,82.54 46.68,82.43 46.18,82.43 46.03,82.27 46.03,82.03 46.16,81.91 46.72,81.91 46.84,81.78 46.84,81.54 46.72,81.41 46.16,81.41 46.03,81.29 46.03,81.04 46.16,80.91 46.67,80.91 46.79,80.78 46.79,80.54 46.67,80.41 45.93,80.41 45.8,80.29 45.8,80.04 45.93,79.92 47.1,79.92 47.22,79.79 47.22,79.54 47.1,79.42 45.65,79.42 45.53,79.29 45.53,79.01 45.65,78.89 46.26,78.89 46.39,78.76 46.39,78.52 46.26,78.39 45.65,78.39 45.53,78.27 45.53,78.02 45.65,77.89 45.93,77.89 46.03,77.8 46.03,75.8 47.06,74.77 48.35,74.77 48.8,74.32 48.8,72.72 50.7,70.82 54.67,70.82 55.41,71.57 55.41,72.21 55.89,72.68 55.89,72.74 55.92,72.77 55.92,73.03 55.89,73.06 55.89,73.54 55.92,73.57 55.92,73.62 UV1.G29
M_DA5: length 47.7
  BOTTOM w0.102: 52.93,72.05 53.56,72.68 53.56,73.07 53.79,73.3 53.83,73.3 53.83,73.3 54.27,73.3 54.41,73.44 54.41,73.82 54.26,73.97 54.26,74.1 54.41,74.25 54.57,74.25 54.74,74.08 54.97,74.08 55.39,74.5 UV1.F28
  BOTTOM w0.124: UV5.D7 40.95,77.32 40.95,77.98 41.08,78.11 41.59,78.11 41.74,78.26 41.74,80.45 42.37,81.08 42.91,81.08 43.47,81.64 43.47,82.86 43.02,83.3 41.8,83.3 41.48,83.62 41.48,83.85 41.36,83.98 40.37,83.98 40.24,84.1 40.24,84.92 40.37,85.04 48.65,85.04 48.77,84.92 48.77,84.41 49.36,83.82 49.54,83.82 50.15,83.21 v1(50.15,81.82) 50.15,81.26 49.18,80.29 49.18,79.56 47.98,78.36 47.98,78.19 48.34,77.83 48.34,77.65 48.17,77.48 47.99,77.48 47.63,77.83 47.46,77.83 47.17,77.55 47.17,77.42 47.55,77.04 47.55,76.89 47.35,76.69 47.35,76.25 47.66,75.94 49.45,75.94 49.49,75.9 50.12,75.9 50.27,75.75 50.27,75.47 49.94,75.13 49.94,73.3 50.28,72.96 51.5,72.96 51.85,73.31 52,73.31 52.2,73.11 52.2,72.32 52.47,72.05 52.93,72.05
M_DA6: length 47.3
  BOTTOM w0.124: UV5.A7 43.11,76.76 43.54,76.76 44.48,77.7 44.48,78.13 44.3,78.31 44.3,78.52 44.48,78.69 44.48,79.25 44.05,79.68 44.05,79.89 44.28,80.12 44.53,80.12 44.81,80.4 44.81,81.46 44.3,81.97 44.3,83.21 43.55,83.97 43.55,84.17 43.67,84.28 43.95,84.28 44.13,84.1 44.33,84.1 44.51,84.28 v1(45.14,84.28) 46.89,84.28 47.26,83.92 47.26,80.7 47.38,80.57 47.63,80.57 47.75,80.7 47.75,83.75 47.88,83.88 48.12,83.88 48.25,83.75 48.25,83.6 48.38,83.47 48.55,83.47 48.67,83.35 48.67,83.1 48.55,82.98 48.38,82.98 48.25,82.85 48.25,81.69 48.38,81.56 48.62,81.56 48.75,81.69 48.75,82.61 48.88,82.73 49.1,82.73 49.23,82.61 49.23,81.59 48.34,80.7 48.34,79.89 46.41,77.96 46.41,76.03 47.28,75.16 48.98,75.16 49.18,74.96 49.18,72.9 50.92,71.16 54.53,71.16 55.06,71.69 55.06,72.25 55.6,72.79 UV1.F32
M_DA7: length 46.8
  BOTTOM w0.124: UV5.B8 42.15,78.01 42.26,78.12 42.42,78.12 42.55,78 42.55,77.45 42.68,77.32 43.72,77.32 44.1,77.7 44.1,78.05 43.98,78.17 43.97,78.17 43.85,78.3 43.85,78.54 43.97,78.67 43.98,78.67 44.1,78.79 44.1,79.16 43.98,79.29 43.44,79.29 43.31,79.41 43.31,80.04 43.44,80.17 43.97,80.17 44.43,80.62 44.43,81.11 43.92,81.61 43.92,83.04 43.24,83.72 41.97,83.72 41.89,83.8 41.89,84.54 42.02,84.66 42.32,84.66 42.44,84.54 42.44,84.33 42.56,84.21 42.81,84.21 42.94,84.33 42.94,84.54 43.06,84.66 v1(47.4,84.66) 48.11,84.66 48.24,84.54 48.24,84.36 49.66,82.94 49.66,81.46 48.77,80.57 48.77,79.73 46.79,77.75 46.79,76.99 46.92,76.86 46.92,76.1 47.47,75.55 49.3,75.55 49.56,75.29 49.56,73.11 50.17,72.5 50.43,72.5 50.65,72.72 50.91,72.72 50.98,72.65 50.98,72.19 50.83,72.04 50.83,71.84 51.01,71.66 51.35,71.66 51.48,71.78 51.48,72.62 51.58,72.72 51.8,72.72 51.97,72.55 51.97,71.68 52.16,71.5 54.37,71.5 54.77,71.9 54.77,72.34 55.2,72.76 55.2,73.02 55.6,73.42 UV1.F30
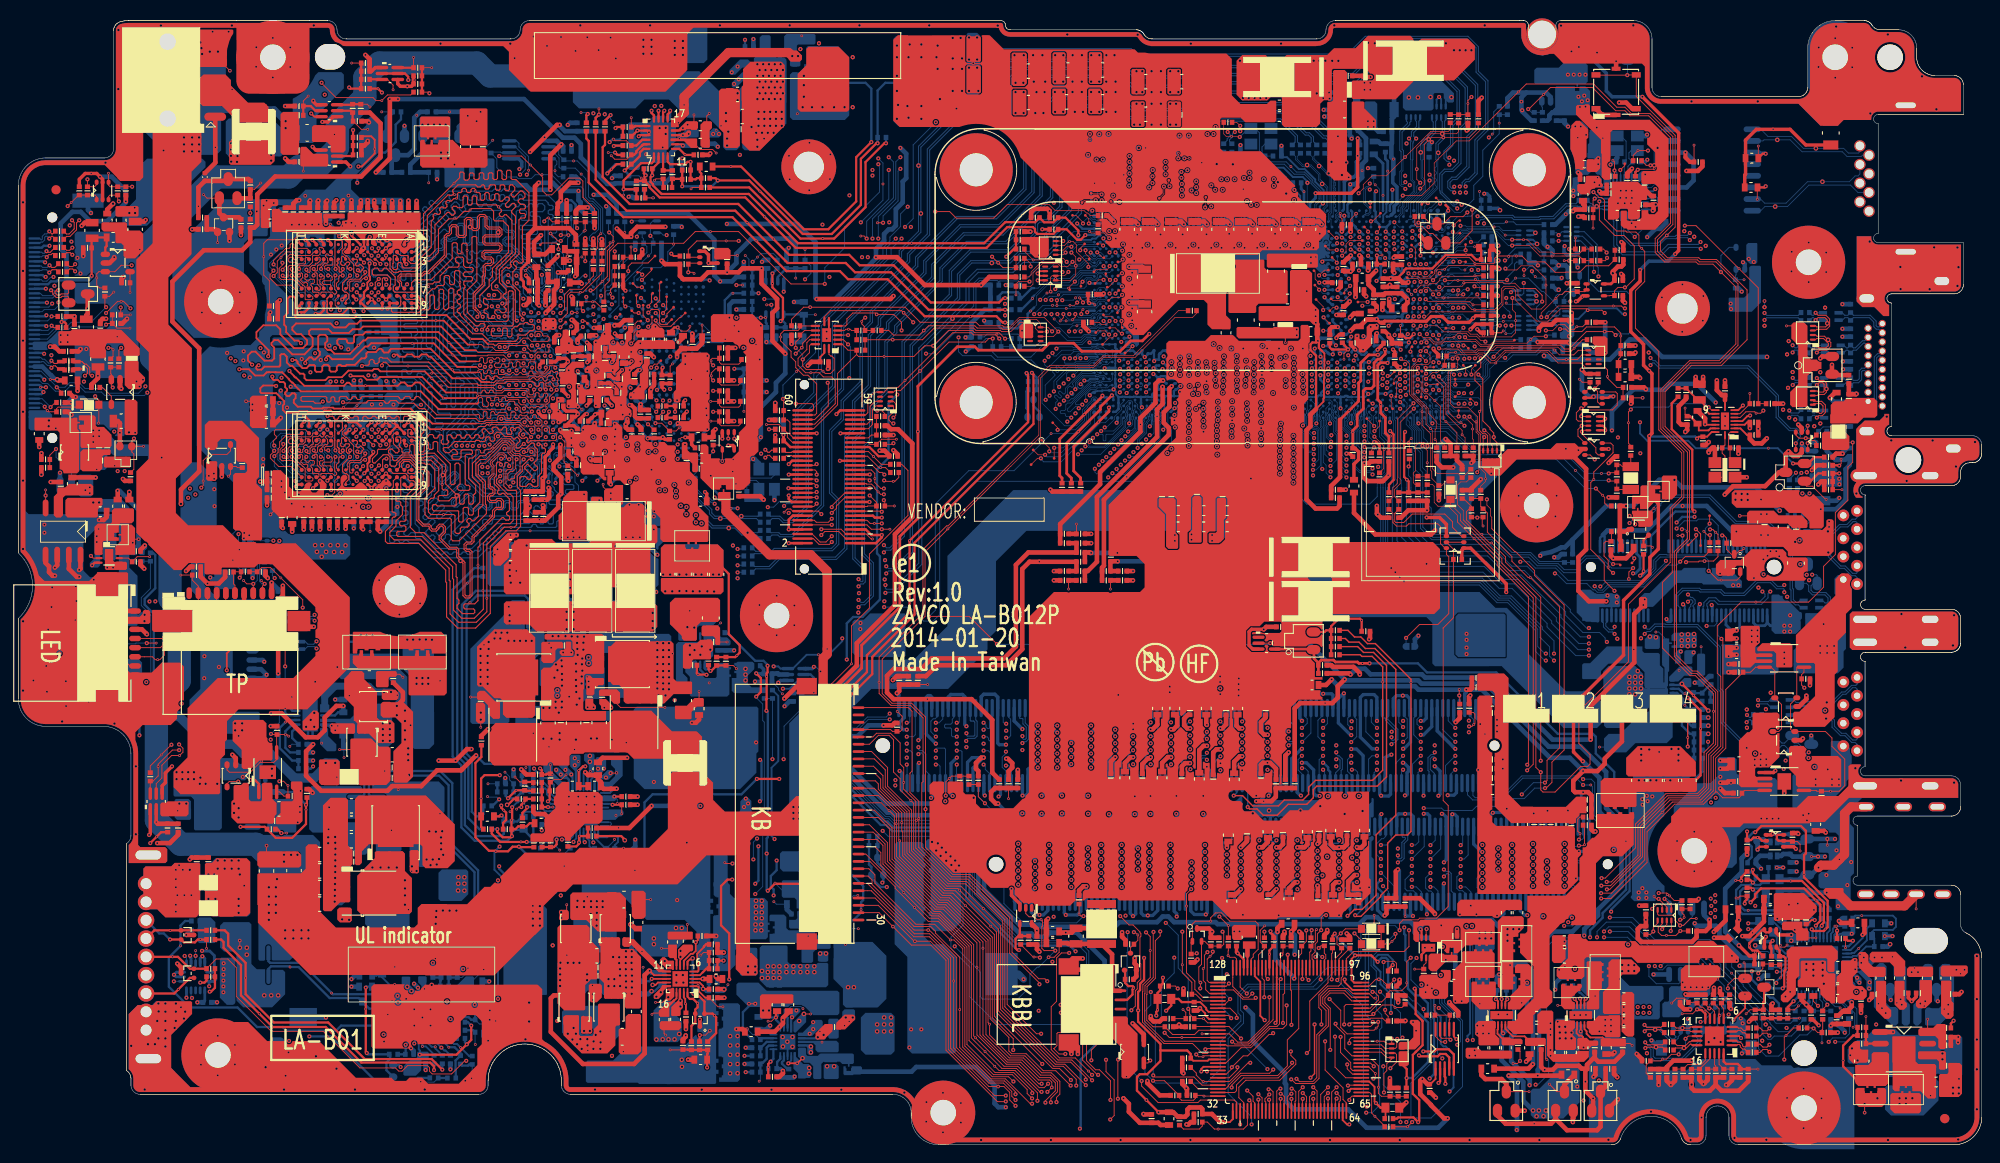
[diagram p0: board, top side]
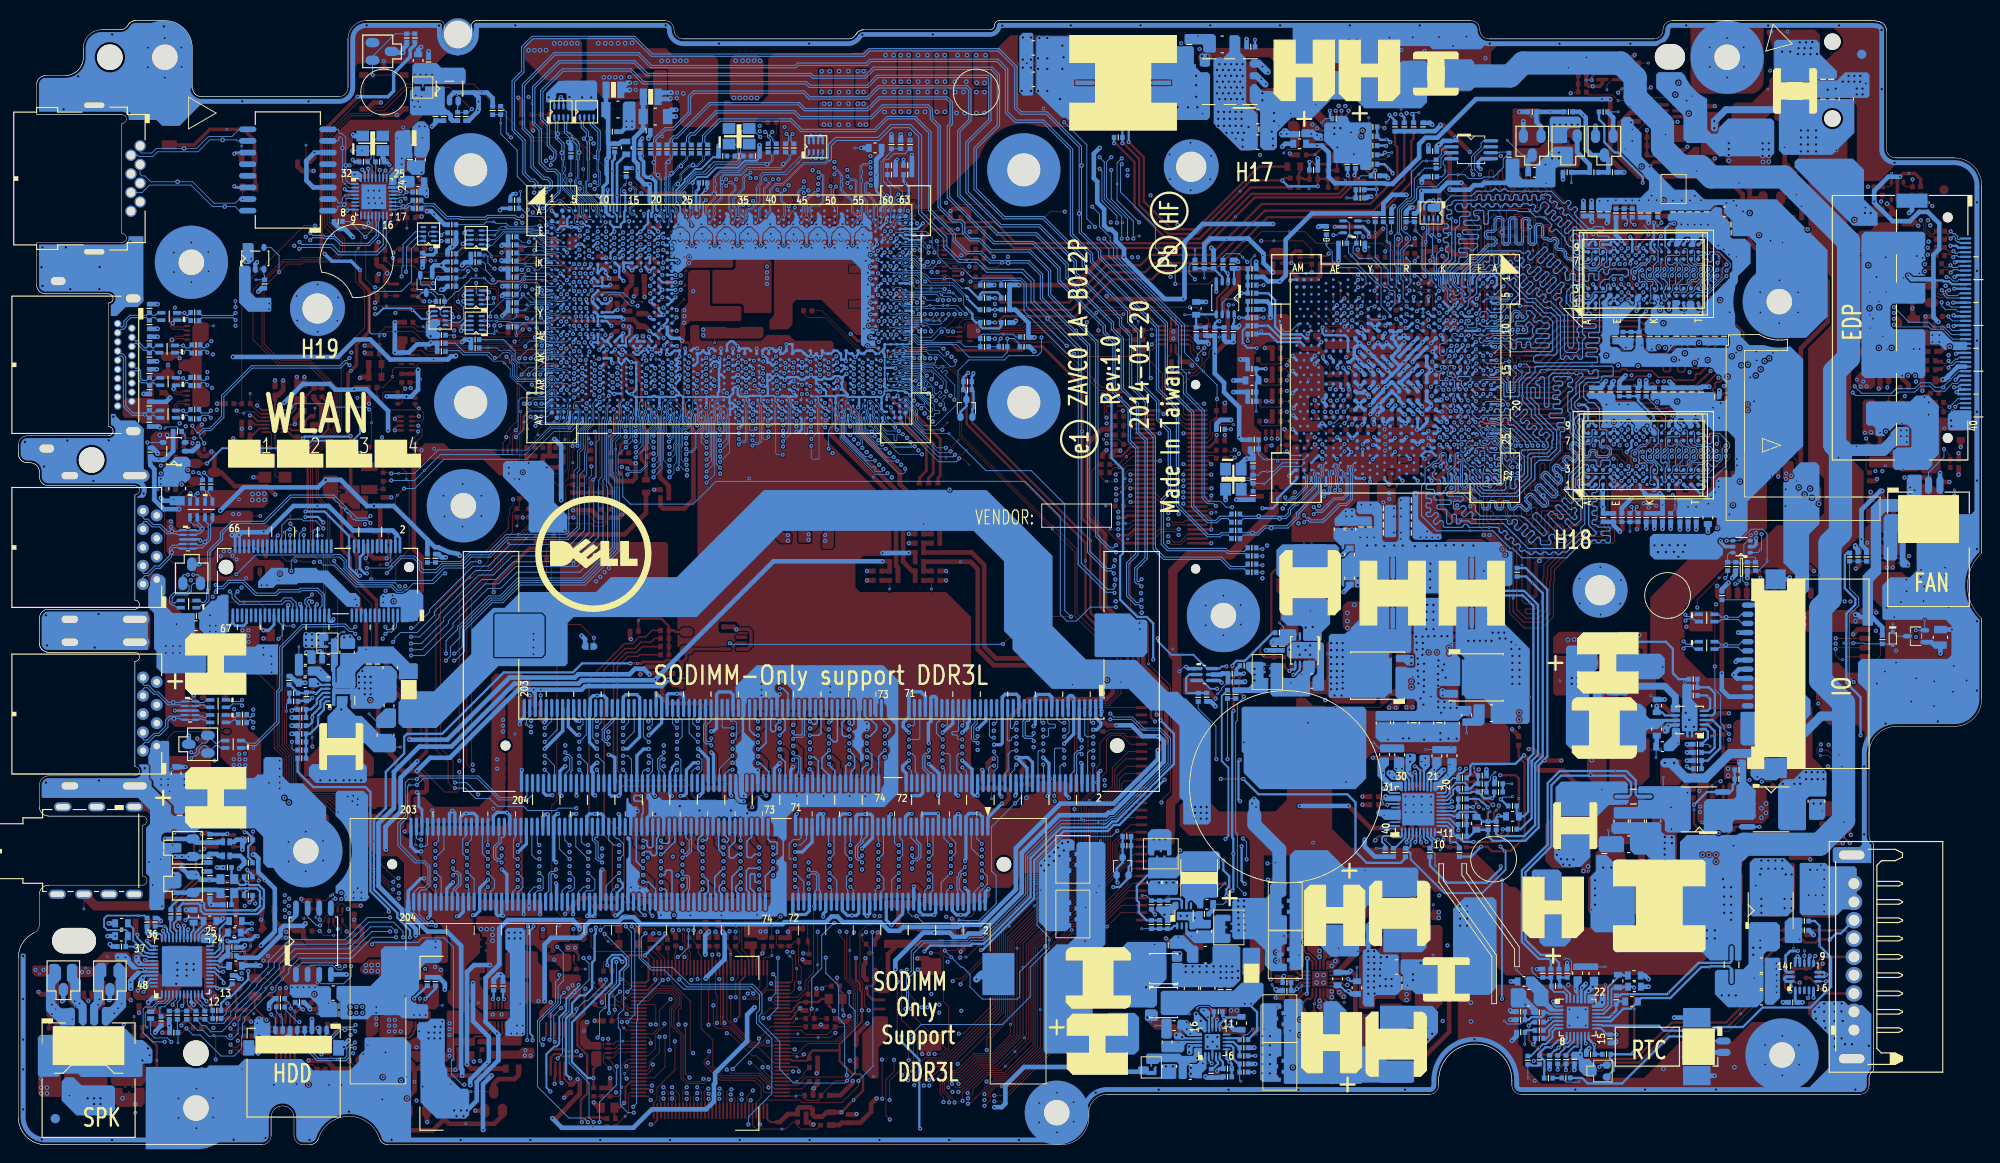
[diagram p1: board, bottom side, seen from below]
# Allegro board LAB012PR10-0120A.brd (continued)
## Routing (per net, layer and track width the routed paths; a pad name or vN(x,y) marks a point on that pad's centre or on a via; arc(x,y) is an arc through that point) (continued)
M_DA8: length 47.1
  TOP w0.102: 53.27,71.23 52.63,71.86
  TOP w0.124: UV6.D7 40.94,73.33 42.29,73.33 42.56,73.06 42.56,72.7 42.71,72.55 42.78,72.55 42.79,72.54 43.11,72.54 43.12,72.55 43.15,72.55 43.34,72.36 43.34,71.86 42.32,70.84 42.32,68.23 42.2,68.11 41.76,68.11 41.64,67.98 41.64,67.73 41.76,67.61 42.2,67.61 42.32,67.49 42.32,67.14 42.2,67.01 41.46,67.01 41.33,66.88 41.33,66.58 41.46,66.45 44.1,66.45 46.64,63.91 47.43,63.13 47.43,61.85 47.53,61.75 47.53,58.4 48.42,57.51 49.79,57.51 50.78,58.5 50.78,65.74 52.89,67.85 53.7,67.85 54.03,68.18 54.03,70.77 53.73,71.07 53.42,71.07 53.27,71.23 ; v2(52.62,73.03) 52.23,72.64 52.23,72.27 52.63,71.86
  BOTTOM w0.124: UV1.C30 53.82,73.7 53.42,73.3 52.89,73.3 v2(52.62,73.03)
M_DA9: length 47.5
  TOP w0.124: UV6.C8 40.95,72.52 40.95,71.84 40.82,71.71 40.82,69.19 40.95,69.07 41.11,69.07 41.23,68.94 41.23,68.69 41.11,68.57 40.95,68.57 40.82,68.44 40.82,67.75 40.09,67.01 40.09,65.92 40.32,65.69 43.74,65.69 46.67,62.77 46.67,61.5 46.77,61.4 46.77,57.66 47.98,56.44 49.94,56.44 51.54,58.04 51.54,65.36 53.24,67.06 54.36,67.06 54.84,67.54 54.84,71.48 54.49,71.84 54.49,73.03 55.04,73.58 55.04,74.16 55.75,74.87 v2(56.06,74.87)
  BOTTOM w0.124: v2(56.06,74.87) 55.64,75.3 UV1.F27
M_DA10: length 47.1
  TOP w0.124: v2(52.7,74.29) 52.7,74.45 52.57,74.57 52.34,74.57 52.21,74.45 52.21,73.12 51.97,72.88 51.97,72.19 52.47,71.69 52.47,71.52 52.33,71.38 52.33,71.2 52.51,71.02 52.68,71.02 52.83,71.16 53,71.16 53.63,70.54 53.63,69.3 53.5,69.17 53.45,69.17 53.32,69.04 53.32,68.86 53.45,68.74 53.52,68.74 53.65,68.61 53.65,68.36 53.52,68.23 53.24,68.23 52.97,68.51 52.84,68.51 50.4,66.07 50.4,65.46 50.2,65.26 v1(50.2,63.3) 50.2,59.44 49.84,59.08 48.77,59.08 48.65,58.96 48.65,58.65 48.77,58.53 49.71,58.53 49.84,58.4 49.84,58.14 49.71,58.02 48.49,58.02 47.91,58.6 47.91,58.93 48.11,59.14 48.11,59.49 47.91,59.69 47.91,61.95 47.81,62.06 47.81,63.35 44.3,66.86 43.39,66.86 42.81,67.44 42.81,70.74 44.2,72.14 44.2,73.16 43.9,73.46 43.39,73.46 43.24,73.31 42.68,73.31 42.54,73.46 42.54,73.61 42.65,73.72 UV6.A7
  BOTTOM w0.102: v2(52.7,74.29) 52.7,74.17 52.82,74.05 53.07,74.05 53.2,74.17 UV1.A28
M_DA11: length 46.7
  TOP w0.102: 53.19,71.76 53.02,71.94 53.02,74.05 53.11,74.14 53.11,74.39 53.24,74.53 53.42,74.53 53.6,74.35 v2(53.6,74.14)
  TOP w0.124: UV6.B8 41.86,72.92 41.76,72.82 41.76,70.92 41.64,70.79 41.33,70.79 41.2,70.67 41.2,70.42 41.33,70.29 41.64,70.29 41.76,70.17 41.76,69.88 41.94,69.7 41.94,68.84 41.24,68.14 41.24,67.58 40.57,66.91 40.57,66.55 41.05,66.07 43.95,66.07 47.05,62.97 47.05,61.68 47.15,61.57 47.15,57.99 48.06,57.08 50.02,57.08 51.16,58.22 v1(51.16,59.69) 51.16,65.56 53.07,67.47 54.18,67.47 54.41,67.7 54.41,71.38 54.31,71.48 53.47,71.48 53.19,71.76
  BOTTOM w0.124: v2(53.6,74.14) 53.96,74.5 UV1.C28
M_DA12: length 47
  TOP w0.102: v2(54.41,74.87) 54.31,74.77 54.31,73.87 53.97,73.52 53.71,73.52 53.45,73.26 53.45,72.72 53.57,72.6 53.68,72.6 53.83,72.75 54.11,72.75 54.2,72.84 54.2,73.12 54.79,73.72 54.79,75.11 54.62,75.29 54.06,75.29 53.7,75.65 53.7,76.38 53.4,76.69 52.86,76.69 51.03,74.86 50.45,74.86 50.12,74.53
  TOP w0.124: UV6.C2 41.1,77.72 40.82,77.45 40.82,77.3 40.96,77.16 40.96,76.58 41.57,75.96 41.57,75.76 41.4,75.58 41.22,75.58 40.8,76 40.62,76 40.43,75.81 40.43,75.63 40.87,75.19 40.87,74.88 41.03,74.73 41.23,74.73 41.84,75.34 42.96,75.34 43.52,74.78 45.07,74.78 45.9,73.94 45.9,71.45 45.43,70.98 45.43,70.76 45.29,70.62 45.07,70.62 44.79,70.34 44.79,69.12 45.07,68.84 v1(46.44,68.84) 47.55,68.84 47.68,68.71 47.68,66.93 47.83,66.78 48.14,66.78 48.27,66.91 48.27,67.31 48.42,67.47 49.05,67.47 49.22,67.64 49.22,67.81 48.98,68.05 48.98,68.23 49.16,68.41 49.33,68.41 49.57,68.16 49.75,68.16 50.25,68.66 50.25,69.37 50.73,69.85 50.73,72.34 49.97,73.11 49.97,74.38 50.12,74.53
  BOTTOM w0.102: v2(54.41,74.87) 54.31,74.97 54.31,75.47 54.26,75.52 54.26,75.72 54.31,75.77 54.67,75.77 54.8,75.65 UV1.E27
M_DA13: length 47.9
  TOP w0.102: 53.68,77.12 52.66,77.12 51.52,75.98 51.36,75.98 51.31,75.92 50.96,75.92 50.86,75.82 50.86,75.67 50.76,75.57 50.55,75.57 50.45,75.67 50.45,75.82 50.35,75.92 50.04,75.92 49.97,75.85 49.97,75.37
  TOP w0.124: v2(56.8,76.51) 57.05,76.51 57.18,76.39 57.18,76.23 57.31,76.1 57.44,76.1 57.56,75.98 57.56,75.67 57.44,75.54 57.26,75.54 57.13,75.42 57.13,73.38 56.75,73 56.75,72.04 56.62,71.91 56.21,71.91 56.09,72.04 56.09,72.07 55.96,72.19 55.71,72.19 55.59,72.07 55.59,72.04 55.46,71.91 54.9,71.91 54.77,72.04 54.77,72.83 54.93,72.99 55.37,72.99 55.67,72.69 55.85,72.69 56.08,72.91 56.08,73.09 55.3,73.87 55.3,74.05 55.57,74.31 55.65,74.31 56.32,73.64 56.5,73.64 56.7,73.84 56.7,74.02 56.33,74.39 56.33,74.51 56.67,74.86 56.67,75.98 56.38,76.27 56.38,76.54 56.28,76.64 56.01,76.64 55.62,76.25 55.44,76.07 55.02,76.07 54.69,75.75 54.36,75.75 54.13,75.98 54.13,76.66 53.68,77.12 ; UV6.A3 43.36,76.92 43.49,76.79 43.49,75.62 43.72,75.39 44.25,75.39 44.41,75.54 45.42,75.54 46.67,74.3 v1(46.67,73.61) 46.67,72.19 47.78,71.07 48.06,71.07 48.19,70.95 48.19,70.11 48.31,69.98 48.56,69.98 48.69,70.11 48.69,70.95 48.81,71.07 49.06,71.07 49.19,70.95 49.19,70.11 49.31,69.98 49.56,69.98 49.68,70.11 49.68,70.95 49.81,71.07 49.82,71.07 49.94,71.2 49.94,72.01 49.18,72.78 49.18,74.88 49.31,75.01 49.61,75.01 49.97,75.37
  BOTTOM w0.102: UV1.G26 56.4,75.79 56.55,75.65 56.75,75.65 56.88,75.77 56.88,76.44 v2(56.8,76.51)
M_DA14: length 47.3
  TOP w0.102: 51.36,75.65 51.52,75.65 52.76,76.89 53.6,76.89 53.9,76.59 53.9,75.77 54.18,75.49 54.51,75.49 54.54,75.52 54.72,75.52 54.97,75.26 55.35,75.26 55.45,75.16 55.78,75.16 55.89,75.26 56.34,75.26 56.42,75.34 56.42,75.87 56.19,76.1 55.81,76.1 55.63,75.92 55.63,75.72 55.53,75.62 55.24,75.62 v2(55.2,75.67)
  TOP w0.124: 51.36,75.65 50.98,75.26 50.43,75.26 49.59,74.43 49.59,72.93 50.4,72.11 50.4,70.18 49.69,69.47 49.69,68.91 49.56,68.79 49.28,68.79 49.16,68.91 49.16,69.5 49.03,69.63 48.7,69.63 48.58,69.5 48.58,68.15 48.45,68.03 48.2,68.03 48.08,68.15 48.08,69.18 48.01,69.24 45.37,69.24 45.22,69.4 45.22,69.83 45.32,69.93 45.6,69.93 45.75,69.78 47.68,69.78 47.81,69.91 47.81,70.59 47.71,70.69 47.38,70.69 47.02,70.34 45.98,70.34 45.85,70.46 45.85,70.79 45.98,70.92 46.77,70.92 46.89,71.05 46.89,71.4 46.77,71.53 46.41,71.53 46.28,71.66 v1(46.28,72.11) 46.28,74.12 45.24,75.16 44.38,75.16 44.25,75.04 43.6,75.04 43.25,75.39 43.25,76.38 43.12,76.51 42.88,76.51 42.75,76.38 42.75,75.7 42.62,75.57 42.02,75.57 41.89,75.7 41.89,76.03 41.61,76.31 41.61,76.53 41.76,76.68 41.76,77.19 41.63,77.32 41.34,77.32 41.22,77.19 41.22,77.05 41.34,76.92 UV6.C3
  BOTTOM w0.124: v2(55.2,75.67) 55.3,75.77 55.3,75.92 55.05,76.18 54.48,76.18 UV1.D26
M_DA15: length 48.2
  TOP w0.124: v2(55.2,76.55) 55.12,76.55 54.67,76.1 54.46,76.1 54.36,76.2 54.36,76.46 54.74,76.84 54.74,77.04 54.51,77.27 54.39,77.27 54.21,77.09 54.08,77.09 53.8,77.37 53.12,77.37 52.66,77.83 52.25,77.83 51.97,77.55 51.97,77.22 52.04,77.16 52.04,76.98 51.91,76.85 51.64,76.85 51.52,76.98 51.52,77.19 51.39,77.32 51.16,77.32 51.03,77.19 51.03,76.94 50.91,76.81 50.43,76.81 50.3,76.94 49.99,76.94 49.87,76.81 47.66,76.81 47,76.15 46.49,76.15 46.41,76.08 46.41,75.85 46.67,75.59 47.07,75.59 47.43,75.95 47.68,75.95 47.93,75.7 47.93,75.44 47.88,75.39 47.48,75.39 47.35,75.26 47.35,75.01 47.48,74.88 48.14,74.88 48.34,75.09 48.34,75.77 48.47,75.9 49.46,75.9 49.59,75.77 49.59,75.54 49.46,75.42 48.93,75.42 48.8,75.29 48.8,72.17 48.93,72.04 49.18,72.04 49.31,71.91 49.31,71.6 49.18,71.48 48.14,71.48 47.94,71.68 47.94,71.89 48.24,72.19 48.24,74.26 48.05,74.45 47.81,74.45 47.68,74.32 47.68,72.24 47.56,72.11 47.3,72.11 47.17,72.24 47.17,74.38 45.8,75.75 45.8,76.69 45.68,76.81 45.42,76.81 45.29,76.69 45.29,76.08 45.17,75.95 44.91,75.95 44.79,76.08 44.79,76.71 44.66,76.84 44.46,76.84 44.33,76.71 44.33,75.82 44.2,75.7 43.94,75.7 43.82,75.82 43.82,76.84 43.93,76.96 43.93,77.13 43.76,77.31 43.58,77.31 43.46,77.19 43.29,77.19 43.17,77.32 42.68,77.32 42.54,77.46 42.54,78.06 42.61,78.14 42.85,78.14 42.95,78.04 UV6.A2
  BOTTOM w0.102: UV1.F25 55.95,76.9 56.27,76.59 56.27,76.41 56.06,76.2 55.96,76.2 55.76,76.41 55.35,76.41 55.25,76.5
  BOTTOM w0.124: 55.25,76.5 v2(55.2,76.55)
M_DA16: length 41.8
  IN1 w0.13: v2(50.66,74.05) 50.12,74.05 49.99,73.92 49.99,72.35 50.12,72.23 50.6,72.23 50.84,72.46 51.1,72.46 51.23,72.34 51.23,67.38 51.1,67.25 48.76,67.25 48.7,67.31 48.19,67.31 48.06,67.19 48.06,67.01 48.31,66.76 48.31,66.5 48.13,66.31 48,66.31 47.66,66.65 47.37,66.65 47.21,66.49 47.21,66.31 47.64,65.88 47.64,65.7 47.46,65.52 47.28,65.52 46.89,65.9 46.71,65.9 46.53,65.72 46.53,65.53 46.91,65.15 46.91,64.97 46.73,64.78 46.54,64.78 46.24,65.09 43,65.09 40.76,67.33 40.12,67.33 39.99,67.46 39.99,67.8 40.12,67.92 40.7,67.92 40.82,68.05 40.82,68.33 40.7,68.46 39.98,68.46 39.86,68.58 39.86,68.89 39.99,69.02 40.36,69.02 40.49,69.15 40.49,69.41 40.36,69.54 39.99,69.54 39.86,69.67 39.86,69.93 39.99,70.06 40.36,70.06 40.49,70.19 40.49,70.45 40.36,70.58 39.99,70.58 39.86,70.71 39.86,71.09 39.76,71.19 39.76,71.5 39.77,71.51 39.77,71.83 39.76,71.85 39.76,72.77 39.6,72.93 38.76,72.93 38.72,72.9 37.92,72.9 37.82,72.8 v2(37.82,72.52)
  BOTTOM w0.102: UV1.A25 52.96,76.66 52.8,76.66 52.4,76.25 52.4,76.13 51.92,75.65 51.77,75.65 51.64,75.78 51.5,75.78 51.36,75.64 51.36,75.49 51.48,75.37 51.48,75.16 50.67,74.34 50.67,74.26 50.66,74.26 v2(50.66,74.05)
  BOTTOM w0.124: UV5.G2 38.15,72.84 v2(37.82,72.52)
M_DA17: length 42.7
  IN1 w0.13: v2(40.19,74.14) 39.75,73.71 39.75,73.11 39.95,72.91 40.61,72.91 40.68,72.84 40.68,72.7 40.81,72.57 41.18,72.57 41.31,72.45 41.31,72.22 41.18,72.09 40.7,72.09 40.57,71.96 40.57,71.53 40.33,71.29 40.33,71.14 40.46,71.01 41.58,71.01 41.71,70.88 41.71,70.62 41.58,70.49 41.18,70.49 40.93,70.24 40.93,69.4 41.26,69.07 41.26,67.6 41.98,66.87 41.99,66.88 42.17,66.88 42.35,66.7 42.35,66.52 42.35,66.51 42.35,66.32 43.01,65.66 45.73,65.66 47.79,67.72 50.63,67.72 50.76,67.85 50.76,71.63 50.63,71.76 49.74,71.76 49.61,71.89 49.61,74.68 49.74,74.81 50.3,74.81 50.43,74.68 50.43,74.6 50.55,74.48 50.78,74.48 50.91,74.6 50.91,74.96 50.76,75.11 50.76,75.57 51.03,75.85 51.31,75.85 51.44,75.72 51.44,74.14 51.31,74.01 v2(51.25,74.01)
  BOTTOM w0.102: UV1.C25 54.07,76.97 54.38,76.97 54.49,76.86 54.49,76.71 54.38,76.61 54.16,76.61 54.01,76.46 53.88,76.46 53.75,76.59 53.75,76.66 53.63,76.79 53.52,76.79 53.4,76.66 53.4,76.59 53.27,76.46 52.89,76.46 52.62,76.19 52.62,75.91 51.95,75.24 51.95,75.14 52.11,74.97 52.11,74.88 51.88,74.65 51.79,74.65 51.61,74.83 51.47,74.83 51.32,74.69 51.32,74.54 51.59,74.27 51.59,74.1 51.47,73.97 51.29,73.97 v2(51.25,74.01)
  BOTTOM w0.124: UV5.E3 40.17,74.14 v2(40.19,74.14)
M_DA18: length 43.4
  IN1 w0.13: v2(51.26,73.35) 52.08,73.35 52.21,73.23 52.21,70.66 52.7,70.17 52.7,66.84 52.08,66.22 49.46,66.22 46.72,63.48 43.44,63.48 41.47,65.45 41.29,65.45 40.81,64.97 40.63,64.97 40.44,65.15 40.44,65.34 40.92,65.82 40.92,66 40.77,66.15 40.03,66.15 39.9,66.02 39.9,64.95 39.77,64.83 39.52,64.83 39.39,64.95 39.39,66.02 39.26,66.15 38.9,66.15 38.6,66.45 38.6,69.04 38.92,69.35 38.92,70.65 38.18,71.39 38.18,71.86 37.92,72.12 37.61,72.12 37.38,72.35 37.38,72.37 37.36,72.39 37.36,73.49 37.27,73.58 37.27,73.75 v2(36.95,74.07)
  BOTTOM w0.102: UV1.E25 54.8,76.59 54.62,76.41 54.26,76.41 53.99,76.14 53.99,75.92 53.69,75.62 52.62,75.62 52.32,75.32 52.32,74.41 v2(51.26,73.35)
  BOTTOM w0.124: UV5.H3 37.3,73.72 v2(36.95,74.07)
M_DA19: length 42.9
  IN1 w0.13: v2(51.47,76.48) 51.69,76.26 51.69,74.23 51.82,74.1 52.16,74.1 52.28,74.23 52.28,75.22 52.41,75.35 52.7,75.35 52.8,75.45 52.8,75.71 52.64,75.87 52.43,75.87 52.3,76 52.3,76.71 52.43,76.84 53.09,76.84 53.22,76.97 53.22,77.91 53.09,78.04 52.36,78.04 52.08,77.75 51.54,77.75 51.1,78.2 51.1,78.87 50.97,79 50.71,79 50.58,78.87 50.58,78.37 50.45,78.24 50.19,78.24 50.06,78.37 50.06,78.49 49.93,78.62 49.67,78.62 49.54,78.49 49.54,78.37 49.41,78.24 49.15,78.24 49.03,78.37 49.03,78.49 48.9,78.62 48.64,78.62 48.51,78.49 48.51,78.37 48.38,78.24 48.12,78.24 47.99,78.37 47.99,78.49 47.86,78.62 47.6,78.62 47.47,78.49 47.47,78.37 47.34,78.24 47.08,78.24 46.95,78.37 46.95,78.49 46.82,78.62 46.56,78.62 46.43,78.49 46.43,78.37 46.33,78.26 45.16,78.26 45.09,78.19 45.09,77.83 44.96,77.7 44.05,77.7 43.92,77.83 43.92,78.16 44.05,78.29 44.38,78.29 44.51,78.41 44.51,78.74 44.38,78.87 43.81,78.87 43.68,79 43.68,79.22 43.57,79.33 43.11,79.33 43,79.22 43,78.93 43.21,78.72 43.21,78.39 42.87,78.05 42.28,78.05 42.17,78.15 42.17,79.14 41.98,79.34 37.51,79.34 37.29,79.12 37.29,78.95 37.29,78.95 37.52,78.72 37.52,78.52 37.29,78.29 37.29,77.95 37.29,77.95 37.29,77.71 v2(36.92,77.34)
  BOTTOM w0.102: UV1.D24 54.51,77.81 54.51,77.86 54.69,78.03 54.69,78.13 54.46,78.36 54.31,78.36 54.11,78.16 53.98,78.16 53.9,78.08 53.9,77.78 54.06,77.63 54.06,77.46 54.01,77.41 53.79,77.41 53.73,77.35 53.47,77.35 53.41,77.41 52.94,77.41 52.52,76.99 52.3,76.99 52.25,76.94 52.25,76.71 52.13,76.59 51.95,76.59 51.72,76.81 51.72,76.97 51.85,77.09 51.85,77.25 51.77,77.32 51.54,77.32 51.09,76.86 51.09,76.71 51.31,76.48 v2(51.47,76.48)
  BOTTOM w0.124: UV5.H8 37.3,77.72 v2(36.92,77.34)
M_DA20: length 43.3
  IN1 w0.13: v2(37.74,77.34) 37.61,77.34 37.51,77.24 37.51,76.99 37.55,76.94 37.58,76.94 37.58,76.94 37.91,76.94 37.92,76.94 38.08,76.94 38.17,77.03 38.17,78.22 38.23,78.28 38.23,78.3 38.46,78.53 38.47,78.53 38.48,78.54 40.45,78.54 40.58,78.41 40.58,78.12 40.7,77.99 41.14,77.99 41.27,78.12 41.27,78.65 41.39,78.78 41.78,78.78 41.91,78.65 41.91,78.04 42.21,77.75 42.21,77 42.33,76.87 42.74,76.87 42.87,77 42.87,77.38 42.99,77.51 43.4,77.51 43.53,77.38 43.53,76.18 43.65,76.05 44.06,76.05 44.19,76.18 44.19,77.14 44.31,77.27 44.72,77.27 44.85,77.14 44.85,75.26 44.97,75.13 45.64,75.13 45.76,75 45.76,74.6 45.64,74.47 45.15,74.47 45.02,74.34 45.02,73.94 45.15,73.81 46.3,73.81 46.42,73.94 46.42,75.66 46.3,75.79 45.63,75.79 45.51,75.92 45.51,76.32 45.63,76.45 46.3,76.45 46.42,76.58 46.42,76.98 46.3,77.11 45.63,77.11 45.51,77.24 45.51,77.64 45.69,77.83 51.1,77.83 51.28,77.64 51.28,77.14 51.15,77.02 49.73,77.02 49.62,76.91 v2(49.62,76.33)
  BOTTOM w0.102: UV1.E23 54.9,78.6 54.9,78.88 54.77,79 54.49,79 54.3,78.81 53.87,78.81 53.84,78.77 53.36,78.77 53.33,78.81 53.07,78.81 52.89,78.62 52.25,78.62 51.85,78.21
  BOTTOM w0.124: 51.85,78.21 51.25,78.21 49.87,76.83 49.87,76.57 v2(49.62,76.33) ; v2(37.74,77.34) 37.35,76.95 UV5.H7
M_DA21: length 44.3
  IN1 w0.13: v2(50.68,73.35) 50.68,72.96 50.79,72.85 51.61,72.85 51.74,72.72 51.74,70.4 51.9,70.24 52.02,70.24 52.19,70.07 52.19,69.74 52.02,69.58 51.9,69.58 51.74,69.41 51.74,69.01 51.9,68.85 52.06,68.85 52.23,68.68 52.23,68.35 52.06,68.19 51.9,68.19 51.74,68.02 51.74,67.69 51.9,67.53 52.06,67.53 52.23,67.36 52.23,67.03 52.06,66.87 51.49,66.87 51.32,66.69 49.32,66.69 46.98,64.36 46.67,64.36 46.54,64.23 46.54,64.04 46.41,63.91 46.07,63.91 45.94,64.04 45.94,64.52 45.81,64.65 45.55,64.65 45.42,64.52 45.42,64.04 45.3,63.91 45.04,63.91 44.91,64.04 44.91,64.52 44.78,64.65 44.52,64.65 44.39,64.52 44.39,64.04 44.26,63.91 43.95,63.91 43.82,64.04 43.82,64.47 43.69,64.6 42.91,64.6 40.94,66.56 39.2,66.56 39.07,66.69 39.07,67.24 39.2,67.37 39.3,67.37 39.43,67.49 39.43,67.9 39.3,68.03 39.24,68.03 39.07,68.2 39.07,68.84 39.39,69.16 39.39,70.89 39,71.28 39,71.49 38.98,71.51 38.98,71.83 39,71.85 39,72.29 39.23,72.53 v2(39.35,72.53)
  BOTTOM w0.102: UV1.F23 55.48,78.5 54.72,77.74 54.72,77.58 54.34,77.2 53.87,77.2 53.77,77.1 53.43,77.1 53.33,77.2 53.05,77.2 52.19,76.35 52.19,76.25 52.04,76.1 v1(51.8,76.1) 51.26,76.1 50.88,75.72 50.88,75.58 51.14,75.31 51.14,75.17 51,75.03 50.86,75.03 50.59,75.29 50.45,75.29 50.27,75.11 50.27,74.94 50.5,74.71 50.5,74.48 50.27,74.25 50.27,73.76 v2(50.68,73.35)
  BOTTOM w0.124: v2(39.35,72.53) 38.95,72.92 UV5.F2
M_DA22: length 43.4
  IN1 w0.13: v2(49.04,76.36) 49.08,76.36 49.21,76.49 49.21,77.25 49.08,77.37 47.02,77.37 46.89,77.25 46.89,73.69 46.54,73.34 45.34,73.34 45.21,73.21 45.21,72.81 45.34,72.68 46.98,72.68 47.11,72.55 47.11,72.15 46.98,72.02 46.7,72.02 46.57,71.89 46.57,71.49 46.7,71.36 46.98,71.36 47.11,71.23 47.11,70.67 46.98,70.55 46,70.55 45.87,70.67 45.87,71.89 45.74,72.02 45.34,72.02 45.21,71.89 45.21,70.69 45.08,70.56 44.68,70.56 44.58,70.65 44.58,75.62 44.46,75.75 43.59,75.75 43.2,76.14 42.68,76.14 42.43,75.9 42.43,75.7 42.31,75.58 41.9,75.58 41.77,75.7 41.77,76.29 41.94,76.46 41.94,77.63 41.81,77.76 41.34,77.76 41.22,77.63 41.22,76.99 41.09,76.86 40.83,76.86 40.58,77.11 40.58,77.63 40.5,77.7 40.32,77.7 40.31,77.71 39.98,77.71 39.98,77.7 39.52,77.7 39.51,77.71 39.18,77.71 39.18,77.7 38.75,77.7 38.74,77.71 38.58,77.71 38.47,77.82 38.47,78.01 38.6,78.13 v2(38.62,78.13)
  BOTTOM w0.102: 52.4,78.87 52.44,78.82 52.8,78.82 52.99,79.01 53.41,79.01 53.45,78.97 53.75,78.97 53.96,79.18 53.96,79.35 54.08,79.48 54.27,79.48 54.4,79.35 UV1.D22
  BOTTOM w0.124: v2(49.04,76.36) 49.31,76.63 49.31,76.81 51.12,78.63 v1(51.46,78.63) 51.59,78.63 51.72,78.75 51.72,79.28 51.85,79.4 52.15,79.4 52.28,79.28 52.28,78.99 52.4,78.87 ; UV5.F8 38.95,77.72 38.62,78.05 v2(38.62,78.13)
M_DA23: length 44.6
  IN1 w0.13: v2(48.44,76.36) 48.46,76.36 48.59,76.49 48.59,76.81 48.46,76.94 47.49,76.94 47.36,76.81 47.36,72.92 47.58,72.7 47.58,70.51 47.14,70.08 45.5,70.08 45.37,69.95 45.37,68.48 45.24,68.35 44.96,68.35 44.84,68.48 44.84,69.85 44.71,69.98 44.43,69.98 44.3,69.85 44.3,68.91 44.18,68.78 43.9,68.78 43.77,68.91 43.77,70.13 44.23,70.59 44.23,74.1 44.1,74.22 43.82,74.22 43.69,74.35 43.69,74.68 43.82,74.81 44.2,74.81 44.33,74.93 44.33,75.24 44.2,75.37 43.64,75.37 43.47,75.54 43.26,75.54 43.16,75.44 43.16,74.6 43.03,74.47 42.75,74.47 42.63,74.6 42.63,75.19 42.5,75.32 42.2,75.32 42.07,75.19 42.07,74.34 41.94,74.21 41.62,74.21 41.49,74.34 41.49,76.42 41.36,76.54 40.74,76.54 40.37,76.92 39.17,76.92 39,77.09 39,77.22 39.09,77.32 v2(39.35,77.32)
  BOTTOM w0.102: 55.48,79.68 55.6,79.8 UV1.F21
  BOTTOM w0.124: v2(48.44,76.36) 48.44,76.52 51.62,79.7 54.45,79.7 54.82,79.33 55.12,79.33 55.48,79.68 ; v2(39.35,77.32) 38.95,76.92 UV5.F7
M_DA24: length 40.7
  TOP w0.124: UV6.F8 38.95,72.94 v2(39.35,73.34)
  IN2 w0.13: v2(54.4,80.4) 54.25,80.25 54.25,78.83 54.12,78.7 54.01,78.7 53.88,78.57 53.88,78.31 54.01,78.18 54.12,78.18 54.25,78.05 54.25,77.76 54.12,77.63 53.6,77.63 53.47,77.5 53.47,77.24 53.6,77.11 54.12,77.11 54.25,76.98 54.25,76.6 54.16,76.51 53.78,76.51 53.58,76.7 53.41,76.7 53.29,76.58 53.29,76.39 53.55,76.13 53.55,75.9 53.27,75.62 52.38,75.62 52.2,75.43 52.2,71.28 52.14,71.23 52.14,70.44 52.01,70.31 51.75,70.31 51.62,70.44 51.62,71.38 51.49,71.51 51.23,71.51 51.1,71.38 51.1,70.44 50.97,70.31 50.71,70.31 50.58,70.44 50.58,71.38 50.45,71.51 50.2,71.51 50.07,71.38 50.07,70.44 49.94,70.31 49.68,70.31 49.55,70.44 49.55,71.38 49.42,71.51 46.76,71.51 46.63,71.63 46.63,72.37 46.5,72.5 46.24,72.5 46.11,72.37 46.11,71.63 45.98,71.51 45.72,71.51 45.59,71.63 45.59,72.37 45.46,72.5 45.2,72.5 45.07,72.37 45.07,71.63 44.95,71.51 44.43,71.51 44.3,71.63 44.3,72.52 44.18,72.65 41.79,72.65 40.3,71.16 39.28,71.16 38.98,71.46 38.98,72.34 38.95,72.36 38.95,72.95 v2(39.35,73.34)
  BOTTOM w0.124: UV1.E21 54.7,80.1 v2(54.4,80.4)
M_DA25: length 41.3
  TOP w0.124: v2(37.65,74.13) 37.35,73.82 UV6.H7
  IN2 w0.13: v2(52.29,80.84) 52.29,80.49 52.63,80.15 52.81,80.15 52.96,80.29 53.14,80.29 53.33,80.11 53.33,79.93 53.18,79.78 53.18,79.6 53.27,79.51 53.83,79.51 53.96,79.39 53.96,79.12 53.83,79 53.27,79 53.14,78.87 53.14,78.61 53.27,78.48 53.4,78.48 53.52,78.35 53.52,78.09 53.4,77.96 53.27,77.96 53.14,77.83 53.14,76.94 52.63,76.44 51.84,75.64 51.84,72.12 51.66,71.94 51.4,71.94 51.27,72.07 51.27,72.8 51.14,72.93 50.88,72.93 50.75,72.8 50.75,72.07 50.62,71.94 50.36,71.94 50.23,72.07 50.23,73.77 50.1,73.89 49.84,73.89 49.71,73.77 49.71,72.07 49.58,71.94 49.32,71.94 49.2,72.07 49.2,72.8 49.07,72.93 48.81,72.93 48.68,72.8 48.68,72.07 48.55,71.94 48.29,71.94 48.16,72.07 48.16,72.8 48.03,72.93 47.77,72.93 47.64,72.8 47.64,72.07 47.51,71.94 47.25,71.94 47.12,72.07 47.12,72.8 46.99,72.93 46.45,72.93 46.32,73.06 46.32,73.53 46.19,73.66 45.93,73.66 45.8,73.53 45.8,73.06 45.67,72.93 44.52,72.93 44.31,73.13 44,73.13 43.8,72.93 43.48,72.93 43.28,73.13 42.96,73.13 42.76,72.93 42.44,72.93 42.24,73.13 41.93,73.13 41.72,72.93 41.41,72.93 41.2,73.13 40.89,73.13 40.69,72.93 39.86,72.93 39.74,73.04 39.74,73.5 39.51,73.74 38.14,73.74 37.75,74.13 v2(37.65,74.13)
  BOTTOM w0.102: UV1.D20 54.1,81.2 52.66,81.2 v2(52.29,80.84)
M_DA26: length 41.6
  TOP w0.124: v2(36.95,73.33) 37.35,72.93 UV6.H8
  IN2 w0.13: v2(55.22,81.22) 55.22,81.01 54.81,80.61 54.81,80.18 54.56,79.92 54.56,76.3 53.61,75.35 53.31,75.35 53.19,75.22 53.19,72.02 53.06,71.89 52.94,71.89 52.81,71.76 52.81,71.5 52.94,71.37 53.06,71.37 53.19,71.24 53.19,70.91 52.03,69.75 49.13,69.75 49,69.88 49,70.89 48.87,71.02 48.62,71.02 48.49,70.89 48.49,69.88 48.36,69.75 48.1,69.75 47.97,69.88 47.97,70.89 47.84,71.02 47.58,71.02 47.45,70.89 47.45,69.88 47.32,69.75 46.92,69.75 46.79,69.88 46.79,70.89 46.66,71.02 46.4,71.02 46.27,70.89 46.27,69.88 46.14,69.75 45.88,69.75 45.75,69.88 45.75,70.89 45.62,71.02 45.36,71.02 45.23,70.89 45.23,69.88 45.1,69.75 43.01,69.75 42.25,70.51 39.14,70.51 38.53,71.12 37.25,71.12 36.53,71.84 36.53,72.91 v2(36.95,73.33)
  BOTTOM w0.124: v2(55.22,81.22) 55.22,81.27 55.6,81.66 UV1.F19
M_DA27: length 40.5
  TOP w0.124: UV6.F7 38.95,73.78 v2(39.38,74.22)
  IN2 w0.13: v2(39.38,74.22) 39.36,74.22 38.84,74.73 38.84,75.03 38.97,75.16 39.55,75.16 39.73,74.99 39.73,74.81 39.99,74.55 40.37,74.55 40.61,74.31 40.61,73.61 40.73,73.49 43.17,73.49 43.3,73.62 43.3,74.04 43.43,74.17 43.69,74.17 43.82,74.04 43.82,73.62 43.95,73.49 44.21,73.49 44.34,73.62 44.34,74.04 44.46,74.17 44.72,74.17 44.85,74.04 44.85,73.62 44.98,73.49 45.24,73.49 45.37,73.62 45.37,74.04 45.5,74.17 46.8,74.17 46.93,74.04 46.93,73.62 47.06,73.49 47.31,73.49 47.44,73.62 47.44,74.78 47.31,74.91 47.05,74.91 46.92,75.04 46.92,75.29 47.05,75.42 47.31,75.42 47.44,75.55 47.44,75.7 47.57,75.82 47.84,75.82 47.96,75.7 48.29,75.7 48.42,75.57 48.42,75.21 48.29,75.09 48.09,75.09 47.96,74.96 47.96,73.62 48.09,73.49 48.82,73.49 48.95,73.61 48.95,73.95 48.82,74.08 48.75,74.08 48.62,74.21 48.62,74.47 48.75,74.6 48.82,74.6 48.95,74.73 48.95,75.8 49.08,75.92 49.51,75.92 49.63,75.8 49.63,74.45 49.76,74.32 50.02,74.32 50.15,74.45 50.15,75.75 50.28,75.87 50.54,75.87 50.67,75.75 50.67,74.66 50.8,74.53 51.06,74.53 51.19,74.66 51.19,75.75 51.36,75.92 51.76,75.92 52.37,76.53 52.37,76.66 52.79,77.08 52.79,78.52 52.3,79 52.3,80.12 51.71,80.71 v2(51.71,80.86)
  BOTTOM w0.102: UV1.A19 52.91,81.41 52.26,81.41 v2(51.71,80.86)
M_DA28: length 41.3
  TOP w0.124: v2(38.57,77.32) 38.17,77.72 UV6.G2
  IN2 w0.13: v2(38.57,77.32) 38.23,77.32 38.18,77.37 38.18,78.45 38.27,78.54 41.26,78.54 41.76,79.05 41.76,79.72 41.63,79.85 41.23,79.85 41.1,79.72 41.1,79.48 40.97,79.35 39.78,79.35 39.68,79.46 39.68,79.81 39.99,80.12 40.27,80.12 40.52,80.36 41.2,80.36 41.93,81.09 42.36,81.09 42.55,81.28 42.55,81.61 42.43,81.73 42.04,81.73 41.92,81.86 41.92,82.12 42.04,82.25 42.43,82.25 42.55,82.38 42.55,83.65 42.87,83.96 52.16,83.96 52.48,83.64 55.2,83.64 55.71,84.15 56.39,84.15 56.52,84.28 56.52,85.26 56.65,85.39 59.02,85.39 59.19,85.22 59.19,84.64 58.96,84.41 57.61,84.41 57.44,84.23 57.44,83.54 57.31,83.42 55.84,83.42 55.36,82.94 55.24,82.94 55.18,83 v2(55.18,82.99)
  BOTTOM w0.124: v2(55.18,82.99) 54.69,82.5 UV1.D18
M_DA29: length 41.5
  TOP w0.124: v2(37.75,76.55) 37.38,76.92 UV6.H3
  IN2 w0.13: v2(37.75,76.55) 37.32,76.98 37.32,77.73 37.27,77.78 37.27,78.38 37.18,78.46 37.14,78.46 37.01,78.59 37.01,78.81 37.14,78.94 37.9,78.94 38.18,79.22 38.18,81.21 38.31,81.34 39,81.34 39.12,81.21 39.12,80.52 38.99,80.39 38.85,80.39 38.72,80.26 38.72,80 38.85,79.87 39.28,79.87 39.55,80.14 39.55,80.32 39.68,80.45 39.93,80.45 40.06,80.57 40.06,81.21 40.19,81.34 41.36,81.34 41.48,81.46 41.48,82.55 41.6,82.66 41.96,82.66 42.09,82.79 42.09,83.78 42.79,84.48 51.97,84.48 52.57,83.88 55.08,83.88 55.71,84.51 55.71,85.58 55.84,85.7 59.42,85.7 59.54,85.58 59.54,84.27 59.42,84.14 58.17,84.14 58.05,84.01 57.98,84.01 57.85,83.89 57.85,83.3 57.66,83.11 56.1,83.11 v2(55.89,82.9)
  BOTTOM w0.124: UV1.F17 55.6,83.19 v2(55.89,82.9)
M_DA30: length 40.6
  TOP w0.124: v2(40.15,77.32) 40.15,77.05 39.96,76.86 39.81,76.86 UV6.E3
  IN2 w0.102: v2(53.58,82.98) 53.44,82.83 53.14,82.83 53.09,82.88 53.09,82.99 52.9,83.17 51.85,83.17
  IN2 w0.13: 51.85,83.17 51.47,83.17 51.34,83.04 51.34,82.66 51.21,82.53 50.95,82.53 50.82,82.66 50.82,83.04 50.69,83.17 50.37,83.17 50.25,83.05 50.25,82.45 49.82,82.02 49.05,82.02 48.93,81.89 48.93,81.69 49.05,81.56 49.21,81.56 49.33,81.44 49.33,81.18 49.21,81.06 48.72,81.06 48.6,80.93 48.6,80.8 48.47,80.67 48.12,80.67 47.99,80.8 47.99,81.11 48.39,81.51 48.39,81.69 48.09,81.99 47.91,81.99 47.44,81.53 47.44,80.27 47.32,80.14 47.05,80.14 46.93,80.27 46.93,81.16 46.8,81.28 46.53,81.28 46.4,81.15 46.4,80.29 46.27,80.17 46.01,80.17 45.88,80.29 45.88,81.15 45.75,81.28 45.49,81.28 45.36,81.15 45.36,80.62 45.23,80.5 44.56,80.5 44.43,80.62 44.43,81.06 44.56,81.18 44.71,81.18 45.12,81.59 45.12,82.94 44.99,83.06 44.66,83.06 44.53,82.94 44.53,81.77 44.4,81.64 44.15,81.64 44.02,81.77 44.02,82.96 43.9,83.09 43.59,83.09 43.47,82.96 43.47,80.24 43.95,79.76 43.95,77.3 43.82,77.17 42.91,77.17 42.78,77.3 42.78,77.35 42.65,77.48 42.32,77.48 42.2,77.35 42.2,76.99 42.07,76.86 41.79,76.86 41.66,76.99 41.66,77.29 41.54,77.42 41.23,77.42 41.1,77.29 41.1,76.4 40.98,76.27 40.72,76.27 40.6,76.4 40.6,77.19 40.47,77.32 v2(40.15,77.32)
  BOTTOM w0.124: UV1.A17 53.27,83.3 v2(53.58,82.98)
M_DA31: length 40.7
  TOP w0.124: v2(39.34,78.12) 39.34,77.8 39.24,77.7 38.97,77.7 UV6.F2
  IN2 w0.13: v2(39.34,78.12) 39.34,77.85 39.47,77.71 40.31,77.71 40.32,77.7 40.49,77.7 40.59,77.8 40.59,78.16 40.71,78.29 41.05,78.29 41.18,78.16 41.18,77.82 41.31,77.7 41.56,77.7 41.68,77.82 41.68,78.44 41.81,78.57 42.09,78.57 42.22,78.44 42.22,77.9 42.35,77.77 42.93,77.77 43.06,77.9 43.06,78.06 42.86,78.26 42.86,78.46 42.98,78.59 43.34,78.59 43.47,78.72 43.47,79.07 43.34,79.2 42.98,79.2 42.86,79.33 42.86,79.53 43.06,79.73 43.06,79.96 42.93,80.09 42.67,80.09 42.34,79.75 42.16,79.75 41.76,80.14 41.76,80.32 42.05,80.6 42.93,80.6 43.06,80.73 43.06,83.36 43.21,83.52 45.42,83.52 45.55,83.39 45.55,81.84 45.68,81.72 45.98,81.72 46.11,81.84 46.11,83.39 46.23,83.52 46.51,83.52 46.64,83.39 46.64,81.84 46.77,81.72 47.05,81.72 47.17,81.84 47.17,82.4 47.3,82.53 47.66,82.53 47.78,82.66 47.78,82.86 47.66,82.99 47.3,82.99 47.17,83.11 47.17,83.42 47.3,83.54 48.16,83.54 48.29,83.42 48.29,82.4 48.42,82.27 48.73,82.27 48.85,82.4 48.85,83.42 48.98,83.54 49.26,83.54 49.39,83.42 49.39,82.71 49.5,82.6 49.79,82.6 49.92,82.73 49.92,83.37 50.04,83.49 52.07,83.49 52.16,83.4 54.69,83.4 54.76,83.32 54.76,83.01 54.65,82.9 54.46,82.9 v2(54.37,82.99)
  BOTTOM w0.124: UV1.C17 54.07,83.3 v2(54.37,82.99)
M_DA32: length 40.8
  TOP w0.124: UV7.H8 v2(36.96,93.12)
  IN2 w0.102: 49.97,84.96 50.15,85.15 v2(50.42,85.15)
  IN2 w0.13: v2(36.96,93.12) 37.44,93.12 37.62,92.94 37.62,92.21 38.33,91.49 38.33,91.39 39.57,90.15 39.99,90.15 42.7,87.43 42.7,87.25 41.32,85.87 41.32,85.69 41.51,85.5 41.69,85.5 43.07,86.88 43.25,86.88 43.44,86.7 43.44,86.51 41.72,84.8 41.55,84.8 41.17,85.18 40.99,85.18 40.77,84.97 40.77,84.51 40.98,84.31 41.31,84.31 41.54,84.07 41.72,84.07 42.57,84.92 42.98,84.92 43.19,85.12 43.19,85.53 43.34,85.68 43.52,85.68 43.92,85.28 43.92,85.1 44.1,84.92 49.92,84.92 49.97,84.96
  BOTTOM w0.102: v2(50.42,85.15) 50.3,85.27 49.97,85.27 ; 52.66,83.62 52.82,83.62 52.84,83.6 53.33,83.6 53.34,83.59 53.81,83.59 53.82,83.6 54.5,83.6 UV1.E17
  BOTTOM w0.124: 49.97,85.27 49.71,85.27 49.36,84.92 49.36,84.41 49.49,84.28 49.64,84.28 50.5,83.42 50.5,81.84 50.63,81.72 52.05,81.72 52.18,81.84 52.18,83.14 52.66,83.62
M_DA33: length 39.9
  TOP w0.124: v2(37.67,93.95) 37.35,93.63 UV7.H7
  IN2 w0.13: v2(50.96,84.97) 50.96,85.17 50.59,85.54 50.19,85.54 50.14,85.49 45.25,85.49 44.8,85.94 44.62,85.94 44.33,85.66 44.15,85.66 43.97,85.84 43.97,86.02 44.25,86.31 44.25,86.49 43.75,86.99 43.75,87.17 43.98,87.4 43.98,87.58 43.79,87.76 43.61,87.76 43.39,87.54 43.2,87.54 42.29,88.46 42.29,88.64 43.59,89.94 43.59,90.12 43.41,90.31 43.23,90.31 41.92,89.01 41.74,89.01 41.56,89.19 41.56,89.37 42.86,90.68 42.86,90.86 42.67,91.04 42.49,91.04 41.19,89.74 41.01,89.74 40.82,89.92 40.82,90.1 41.76,91.04 41.76,91.22 41.57,91.41 41.39,91.41 40.46,90.47 40.27,90.47 40.14,90.61 39.75,90.61 39.08,91.28 39.08,91.46 39.22,91.6 39.22,91.78 39.03,91.96 38.85,91.96 38.71,91.83 38.53,91.83 38.03,92.33 38.03,93.6 v2(37.67,93.95)
  BOTTOM w0.102: v2(50.96,84.97) 50.44,84.45 v1(50.22,84.45) 50.22,84.03 50.96,83.29 50.96,82.3 51.09,82.17 51.77,82.17 51.87,82.27 51.87,83.19 52.53,83.85 52.97,83.85 53.01,83.81 53.41,83.81 53.42,83.8 53.73,83.8 54.03,84.1 UV1.D16
M_DA34: length 39.6
  TOP w0.124: UV7.G2 38.17,97.53 v2(38.57,97.13)
  IN2 w0.13: v2(55.17,85.36) 55.17,85.64 55.09,85.73 55.07,85.73 54.84,85.96 54.84,86.29 54.84,86.3 54.84,86.31 54.82,86.34 54.82,86.36 54.59,86.59 54.27,86.59 53.14,87.71 53.14,88.04 53.79,88.68 53.79,90.85 53.6,91.04 51.6,91.04 50.26,92.37 50.26,98.75 50.02,98.99 47.98,98.99 47.85,99.12 47.85,99.77 47.72,99.9 47.46,99.9 47.33,99.77 47.33,99.12 47.2,98.99 46.88,98.99 46.75,99.12 46.75,100.49 46.63,100.61 46.36,100.61 46.23,100.49 46.23,99.12 46.1,98.99 45.85,98.99 45.72,99.12 45.72,100.49 45.59,100.61 45.33,100.61 45.2,100.48 45.2,99.5 45.07,99.37 44.41,99.37 43.8,99.98 41.56,99.98 40.8,99.21 40.01,99.21 39.86,99.06 39.86,98.4 39.73,98.28 39.73,97.59 39.66,97.51 39.11,97.51 38.73,97.13 v2(38.57,97.13)
  BOTTOM w0.124: v2(55.17,85.36) 55.17,85.35 55.6,84.92 UV1.F15
M_DA35: length 39.5
  TOP w0.124: UV7.F8 38.95,92.74 v2(39.33,93.12)
  IN2 w0.13: v2(51.58,85.01) 51.51,85.01 51.19,85.33 51.19,85.73 51.02,85.9 45.5,85.9 44.58,86.82 44.58,88.14 44.45,88.27 43.09,88.27 42.96,88.4 42.96,88.66 43.09,88.79 44.29,88.79 44.46,88.96 44.46,89.19 44.33,89.32 44.1,89.32 43.97,89.45 43.97,89.71 44.1,89.84 44.33,89.84 44.46,89.97 44.46,90.32 44.33,90.45 43.65,90.45 43.52,90.57 43.52,90.83 43.65,90.96 44.33,90.96 44.46,91.09 44.46,91.39 43.97,91.88 43.64,91.88 43.16,92.36 43.16,93.57 43.09,93.64 42.64,93.64 42.51,93.52 42.51,92.56 42.36,92.41 42.12,92.41 41.89,92.64 41.89,94.14 41.76,94.27 41.2,94.27 41.08,94.14 41.08,93.58 41.2,93.45 41.28,93.45 41.41,93.33 41.41,92.31 41.28,92.19 40.95,92.19 40.82,92.31 40.82,93.12 40.7,93.25 40.4,93.25 40.27,93.12 40.27,92.87 40.14,92.74 39.96,92.74 39.83,92.87 39.83,93.14 39.71,93.27 39.47,93.27 v2(39.33,93.12)
  BOTTOM w0.102: UV1.A15 52.67,84.9 52.39,84.62 52.39,84.45 52.2,84.25 52.05,84.25 51.79,84.51 51.65,84.51 51.5,84.37 51.5,84.22 51.76,83.96 v1(51.76,83.7) 51.76,83.49 51.64,83.37 51.64,82.53 51.54,82.43 51.26,82.43 51.16,82.53 51.16,83.67 50.83,84 50.83,84.27 v2(51.58,85.01)
M_DA36: length 39.8
  TOP w0.124: v2(39.36,94.58) 38.98,94.19 38.98,93.57 UV7.F7
  IN2 w0.13: v2(39.36,94.58) 39.36,94.74 38.85,95.25 38.59,95.25 38.34,95.01 38.34,94.84 38.97,94.21 38.97,93.72 39.13,93.55 40.53,93.55 40.64,93.67 40.64,94.5 40.77,94.63 41.99,94.63 42.1,94.74 42.29,94.74 42.91,94.12 43.13,94.12 43.49,94.48 43.49,94.87 43.62,95 43.9,95 44.02,94.87 44.02,93.77 43.92,93.66 43.6,93.66 43.47,93.53 43.47,93.28 43.6,93.15 43.92,93.15 44.05,93.02 44.05,92.92 44.18,92.79 44.43,92.79 44.56,92.92 44.56,94.52 44.68,94.64 44.91,94.64 45.04,94.52 45.04,86.95 45.57,86.42 46.73,86.42 46.85,86.54 46.85,87.1 46.98,87.23 47.24,87.23 47.37,87.1 47.37,86.54 47.5,86.42 47.76,86.42 47.89,86.54 47.89,87.1 48.02,87.23 48.28,87.23 48.41,87.1 48.41,86.54 48.54,86.42 48.8,86.42 48.93,86.54 48.93,87.1 49.06,87.23 49.32,87.23 49.45,87.1 49.45,86.54 49.57,86.42 49.8,86.42 49.92,86.54 49.92,86.84 50.05,86.97 50.31,86.97 50.44,86.84 50.44,86.42 50.57,86.29 51.42,86.29 51.61,86.11 v2(51.61,85.57)
  BOTTOM w0.102: UV1.D14 54.02,85.32 52.31,85.32 52.06,85.57 v2(51.61,85.57)
M_DA37: length 39.4
  TOP w0.124: UV7.F2 38.97,97.51 39.24,97.51 39.34,97.61 v2(39.34,97.93)
  IN2 w0.13: v2(39.34,97.93) 38.87,98.4 38.87,99.55 39.43,100.11 39.75,100.11 39.88,99.98 39.88,99.68 40.01,99.55 40.27,99.55 40.4,99.68 40.4,99.98 40.53,100.11 41.03,100.11 41.32,100.4 44.01,100.4 44.79,101.17 47.15,101.17 48.43,99.89 48.43,99.57 48.56,99.45 48.82,99.45 48.95,99.57 48.95,99.82 49.08,99.95 49.4,99.95 49.53,99.82 49.53,99.6 49.66,99.47 49.92,99.47 50.04,99.6 50.04,99.82 50.17,99.95 50.58,99.95 50.84,99.69 50.84,98.8 50.91,98.73 51.36,98.73 51.59,98.51 51.59,98.1 51.46,97.97 50.83,97.97 50.7,97.84 50.7,97.58 50.83,97.45 51.46,97.45 51.59,97.32 51.59,97.06 51.46,96.93 50.83,96.93 50.7,96.8 50.7,96.54 50.83,96.41 51.46,96.41 51.59,96.28 51.59,96.02 51.46,95.89 50.83,95.89 50.7,95.76 50.7,95.51 50.83,95.38 51.46,95.38 51.59,95.25 51.59,94.99 51.46,94.86 50.83,94.86 50.7,94.73 50.7,94.47 50.83,94.34 51.46,94.34 51.59,94.21 51.59,93.81 54.02,91.38 54.02,88.11 v2(55.24,86.9)
  BOTTOM w0.124: v2(55.24,86.9) 55.6,86.54 UV1.F13
M_DA38: length 38.7
  TOP w0.124: UV7.E3 39.81,96.68 40.02,96.68 40.15,96.8 v2(40.15,97.13)
  IN2 w0.13: v2(52.57,87.14) 52.57,87.94 53.5,88.88 53.5,89.54 53.12,89.92 51.54,89.92 51.29,90.17 51.29,90.56 50.98,90.86 49.49,90.86 49,91.34 49,91.93 49.13,92.05 49.76,92.05 49.89,92.18 49.89,92.44 49.76,92.57 49.13,92.57 49,92.7 49,92.96 49.13,93.09 49.76,93.09 49.89,93.22 49.89,93.48 49.76,93.61 49.13,93.61 49,93.74 49,94 49.13,94.13 49.76,94.13 49.89,94.26 49.89,94.52 49.76,94.65 49.13,94.65 49,94.78 49,95.03 49.13,95.16 49.76,95.16 49.89,95.29 49.89,95.55 49.76,95.68 49.13,95.68 49,95.81 49,96.07 49.13,96.2 49.76,96.2 49.89,96.33 49.89,96.59 49.76,96.72 49.13,96.72 49,96.85 49,97.22 49.11,97.32 49.64,97.32 49.76,97.45 49.76,97.71 49.64,97.84 49.49,97.84 49.31,98.02 49.31,98.38 49.13,98.56 48.75,98.56 48.62,98.43 48.62,97.62 48.49,97.49 48.23,97.49 48.1,97.62 48.1,98.43 47.97,98.56 44.43,98.56 44.08,98.91 44.08,99.12 43.9,99.29 43.41,99.29 43.19,99.06 43.19,98.56 43.01,98.38 42.05,98.38 41.92,98.51 41.92,98.58 41.8,98.71 41.53,98.71 41.41,98.58 41.41,98.51 41.28,98.38 40.8,98.38 40.63,98.21 40.63,97.55 40.21,97.13 v2(40.15,97.13)
  BOTTOM w0.124: UV1.A13 53.2,86.51 v2(52.57,87.14)
M_DA39: length 38.6
  TOP w0.124: UV7.H3 37.38,96.73 v2(37.75,96.36)
  IN2 w0.102: 52.88,89.31 52.68,89.51 50.04,89.51
  IN2 w0.13: 52.88,89.31 52.88,88.78 52.66,88.55 51.37,88.55 51.13,88.31 51.13,88.13 51.44,87.81 51.88,87.81 52.06,87.63 52.06,87.01 52.43,86.64 53.48,86.64 53.6,86.52 v2(53.6,86.23) ; v2(37.75,96.36) 37.75,96.5 37.93,96.68 40.28,96.68 41.47,97.86 41.66,97.86 41.79,97.73 41.79,97.54 41.92,97.41 42.17,97.41 42.3,97.54 42.3,97.87 42.43,98 42.69,98 42.82,97.87 42.82,97.54 42.95,97.41 43.21,97.41 43.34,97.54 43.34,97.92 43.47,98.05 43.73,98.05 43.86,97.92 43.86,97.54 43.99,97.41 44.25,97.41 44.38,97.54 44.38,97.73 44.51,97.86 46.11,97.86 46.24,97.73 46.24,97.42 46.37,97.29 46.63,97.29 46.76,97.42 46.76,97.73 46.89,97.86 47.33,97.86 47.61,97.58 47.61,97.4 47.26,97.05 47.26,96.87 47.45,96.68 47.63,96.68 47.98,97.03 48.16,97.03 48.55,96.65 48.55,96.3 48.42,96.17 47.61,96.17 47.48,96.04 47.48,95.78 47.61,95.65 48.42,95.65 48.55,95.52 48.55,95.13 48.42,95.01 47.63,95.01 47.5,94.88 47.5,94.61 47.63,94.49 48.42,94.49 48.55,94.36 48.55,91.01 48.75,90.81 48.75,90.25 49.01,90 49.56,90 50.04,89.51
  BOTTOM w0.124: v2(53.6,86.23) 53.87,86.5 UV1.C13
M_DA40: length 46
  TOP w0.102: 49.97,89.02 v2(50.03,89.02)
  TOP w0.124: UV7.B8 42.15,92.48 42.28,92.35 43.4,92.35 43.87,91.88 44.25,91.88 44.48,92.1 44.48,92.77 45.22,93.5 45.47,93.5 45.83,93.86 46.39,93.86 46.51,93.98 46.51,94.82 46.64,94.95 46.97,94.95 47.1,94.82 47.1,94.09 47.22,93.96 47.5,93.96 47.63,94.09 47.63,95.36 47.76,95.48 48.09,95.48 48.22,95.36 v1(48.22,94.21) 48.22,93.83 48.27,93.78 48.27,93.48 48.14,93.36 48.06,93.36 47.94,93.24 47.94,92.99 48.06,92.86 48.14,92.86 48.27,92.74 48.27,92.49 48.14,92.36 48.06,92.36 47.94,92.24 47.94,91.99 48.06,91.87 48.14,91.87 48.27,91.74 48.27,91.49 48.14,91.37 48.06,91.37 47.94,91.24 47.94,90.99 48.06,90.87 48.14,90.87 48.27,90.75 48.27,90.58 49.83,89.02 49.97,89.02
  BOTTOM w0.102: UV1.E11 54.84,88.06 54.84,87.74 54.72,87.61 54.59,87.61 54.31,87.89 54.24,87.89 54.11,87.76 53.85,87.76 53.79,87.83 53.41,87.83 53.37,87.79 51.72,87.79
  BOTTOM w0.124: v2(50.03,89.02) 50.07,89.06 50.07,89.36 50.15,89.44 50.76,89.44 50.88,89.57 50.88,89.84 50.76,89.97 49.99,89.97 49.54,90.43 49.54,90.58 49.73,90.77 49.73,91.02 49.62,91.13 49.32,91.13 48.77,90.58 48.77,90.4 48.96,90.21 48.96,90.03 48.79,89.86 48.61,89.86 48.42,90.05 48.17,90.05 47.89,89.77 47.35,89.77 47.22,89.64 47.22,89.26 47.35,89.13 48.52,89.13 48.65,89.01 48.65,88.73 48.52,88.61 47.35,88.61 47.22,88.48 47.22,88.21 47.35,88.08 48.62,88.08 48.75,87.96 48.75,87.71 48.62,87.58 47.35,87.58 47.22,87.46 47.22,87.18 47.35,87.05 49.13,87.05 49.26,87.17 49.26,87.59 49.38,87.71 49.63,87.71 49.75,87.59 49.75,87.17 49.88,87.05 50.13,87.05 50.25,87.17 50.25,87.59 50.38,87.71 50.71,87.71 50.84,87.59 50.84,87.05 50.96,86.92 51.21,86.92 51.33,87.05 51.33,87.59 51.46,87.71 51.64,87.71 51.72,87.79
M_DA41: length 44.5
  TOP w0.124: UV7.D7 40.55,93.78 40.65,93.88 40.65,94.64 40.29,95 38.79,95 38.66,95.13 38.66,95.51 38.92,95.76 39.21,95.76 39.34,95.64 39.34,95.58 39.46,95.46 39.71,95.46 39.84,95.58 39.84,95.64 39.96,95.76 40.19,95.76 41.15,94.8 41.15,93.93 40.95,93.73 40.95,93.3 41.12,93.13 43.38,93.13 43.5,93.25 43.5,94.04 43.63,94.16 43.87,94.16 44,94.04 44,93.25 44.12,93.13 44.26,93.13 44.53,93.4 44.53,93.93 44.63,94.04 45.24,94.04 45.45,94.24 45.93,94.24 46.06,94.37 46.06,94.91 47.01,95.86 47.99,95.86 48.11,95.99 48.11,96.22 47.99,96.35 47.89,96.35 47.76,96.47 47.76,96.83 47.89,96.96 48.49,96.96 48.62,96.83 48.62,96.04 48.82,95.84 49.54,95.84 49.66,95.71 49.66,95.47 49.54,95.35 48.77,95.35 48.6,95.17 48.6,94.96 48.72,94.84 49.46,94.84 49.59,94.71 49.59,94.47 49.46,94.34 48.72,94.34 48.65,94.27 48.65,93.96 48.77,93.83 48.77,93.65 48.65,93.53 48.65,90.76 49.94,89.46 50.25,89.46 50.48,89.69 50.83,89.69 50.96,89.56 50.96,89.37 v2(50.63,89.03)
  BOTTOM w0.124: UV1.A11 53.13,88.17 53.02,88.17 52.89,88.04 52.69,88.04 52.56,88.17 52.28,88.17 52.15,88.04 51.85,88.04 51.72,88.17 51.47,88.17 51.19,87.89 50.88,87.89 50.68,88.09 49.15,88.09 48.93,88.32 48.93,88.47 49.05,88.6 49.05,89.16 48.9,89.31 48.9,89.41 49.34,89.86 49.52,89.86 49.78,89.6 49.78,89.42 49.59,89.23 49.59,88.83 49.79,88.62 50.73,88.62 50.83,88.72 50.83,88.91 50.7,89.03 v2(50.63,89.03)
M_DA42: length 44.9
  TOP w0.102: 49.97,90 50.04,89.92 53.3,89.92 53.37,89.99
  TOP w0.124: v2(51.23,89.03) 51.23,89.32 51.35,89.45 53.92,89.45 54.04,89.57 54.04,93.15 53.92,93.27 53.62,93.27 53.5,93.15 53.5,90.11 53.37,89.99 ; UV7.A7 42.95,94.16 43.28,94.49 45.07,94.49 47.38,96.8 47.38,98.4 47.5,98.53 47.8,98.53 47.93,98.4 47.93,97.46 48.05,97.34 48.3,97.34 48.43,97.46 48.43,98.35 48.56,98.48 48.88,98.48 49,98.35 v1(49,97.69) 49,96.45 49.13,96.32 49.41,96.32 49.54,96.45 49.54,99.09 49.66,99.22 49.94,99.22 50.07,99.09 50.07,94.39 49.03,93.35 49.03,90.94 49.97,90
  BOTTOM w0.102: UV1.C11 53.63,88.1 53.33,88.4 51.28,88.4 51.16,88.53 51.16,88.95 v2(51.23,89.03)
M_DA43: length 45.8
  TOP w0.124: UV7.C8 41.59,92.73 41.76,92.56 41.76,92.1 41.76,92.09 41.76,91.75 41.48,91.47 40.87,91.47 40.75,91.34 40.75,91.06 40.87,90.94 43.77,90.94 44.05,91.22 44.8,91.22 44.95,91.37 44.95,92.69 45.08,92.82 45.32,92.82 45.45,92.69 45.45,91.37 45.57,91.24 45.82,91.24 45.95,91.37 45.95,93.32 46.07,93.45 46.32,93.45 46.44,93.32 46.44,91.37 46.59,91.22 46.79,91.22 47,91.42 47,93.37 47.17,93.55 47.43,93.55 47.55,93.43 47.55,90.66 49.62,88.59 50.64,88.59 51.47,87.76 54.28,87.76 54.56,88.05 v1(54.56,88.44) 55.39,88.44 55.88,88.93 56.17,88.93 56.34,89.11 56.34,89.46 56.19,89.62 55.78,89.62 55.58,89.82 55.35,89.82 55.2,89.67 54.77,89.67 54.46,89.36 54.19,89.36 53.9,89.08 53.9,88.38 53.77,88.25 53.52,88.25 53.39,88.38 53.39,89.09 53.27,89.22 53.01,89.22 52.89,89.09 52.89,88.47 52.76,88.35 51.77,88.35 51.64,88.47 51.64,88.83 v2(51.85,89.03)
  BOTTOM w0.102: UV1.F11 55.6,88.43 55.46,88.57 55.35,88.57 55.17,88.4 54.95,88.4 54.77,88.57 54.59,88.57 54.39,88.37 54.16,88.37 53.96,88.57 53.44,88.57 53.41,88.61 51.97,88.61 51.85,88.74 v2(51.85,89.03)
M_DA44: length 44.3
  TOP w0.124: UV7.C3 41.35,97.03 41.22,97.15 41.02,97.15 40.94,97.07 40.94,96.29 40.9,96.25 40.9,95.74 41.03,95.61 41.28,95.61 41.41,95.74 41.41,96.25 41.53,96.37 41.78,96.37 41.91,96.25 41.91,95.91 42.03,95.79 43.36,95.79 44.66,97.08 44.91,97.08 45.5,97.67 45.5,100.49 46.86,101.84 47.03,101.84 47.33,101.55 47.5,101.55 47.68,101.73 47.68,101.9 47.38,102.2 47.38,102.37 47.53,102.52 47.83,102.52 47.99,102.36 48.44,102.36 48.56,102.49 48.56,103.51 48.69,103.64 48.94,103.64 49.06,103.51 49.06,102.8 49.19,102.67 49.43,102.67 49.56,102.8 49.56,103.51 49.68,103.64 49.93,103.64 50.06,103.51 50.06,102.8 50.18,102.67 52.2,102.67 v1(52.43,102.44) 52.75,102.13 52.75,101.95 52.53,101.73 52.53,101.56 52.71,101.38 52.88,101.38 53.1,101.6 53.28,101.6 53.9,100.97 53.9,97.44 52.18,95.71 52.18,94.57 51.68,94.07 51.68,93.49 51.82,93.35 52.33,93.35 52.71,92.97 52.71,92.51 52.56,92.36 51.16,92.36 51.05,92.47 50.87,92.47 50.81,92.41 50.81,91.98 50.98,91.81 51.16,91.81 51.29,91.68 51.29,91.43 51.16,91.31 50.98,91.31 50.86,91.18 50.86,90.94 50.98,90.81 51.14,90.81 51.26,90.68 51.26,90.4 51.39,90.28 51.7,90.28 v2(51.86,90.43)
  BOTTOM w0.102: UV1.A9 53.03,89.7 52.77,89.96 52.33,89.96 51.86,90.44 v2(51.86,90.43)
M_DA45: length 44.5
  TOP w0.124: v2(52.47,90.43) 52.03,90.87 52.03,91.06 52.17,91.2 52.17,91.2 52.5,91.2 52.81,90.89 53.08,90.89 53.27,91.08 53.27,91.3 53.04,91.54 53.04,91.54 53.27,91.77 53.27,92.34 53.15,92.46 53.08,92.46 52.94,92.61 52.94,92.81 53.08,92.96 53.15,92.96 53.27,93.08 53.27,93.45 52.53,94.19 52.53,95.64 54.29,97.39 54.29,101.43 53.87,101.85 53.87,102.02 54.33,102.48 54.33,102.66 54.15,102.83 53.97,102.83 53.55,102.41 53.34,102.41 53.2,102.55 53.2,102.76 53.62,103.18 53.62,103.39 53.47,103.53 53.28,103.53 52.83,103.08 52.63,103.08 52.5,103.2 52.5,103.75 52.35,103.89 52.15,103.89 52,103.75 52,103.35 51.84,103.18 51.6,103.18 51.43,103.35 51.43,103.87 51.29,104.02 51.08,104.02 50.94,103.87 50.94,103.31 50.79,103.17 50.58,103.17 50.44,103.31 50.44,103.89 50.31,104.02 50.06,104.02 49.93,104.14 49.93,104.33 49.79,104.48 49.58,104.48 49.44,104.33 49.44,104.14 49.31,104.02 49.06,104.02 48.94,104.14 48.94,104.33 48.79,104.48 48.59,104.48 48.44,104.33 48.44,104.14 48.32,104.02 48.07,104.02 47.95,103.89 47.95,103.48 v1(47.87,103.4) 47.82,103.36 47.55,103.36 47.29,103.09 47.11,103.09 47.05,103.15 46.84,103.15 46.7,103 46.7,102.8 46.81,102.69 46.81,102.48 46.66,102.34 46.45,102.34 46.35,102.44 46.18,102.44 46,102.26 46,102.08 46.1,101.99 46.1,101.78 45.95,101.64 45.74,101.64 45.65,101.73 45.47,101.73 45.3,101.56 45.3,101.38 45.35,101.33 45.35,101.15 45.09,100.89 45.09,98.02 43.34,96.27 42.86,96.27 42.56,96.57 42.56,96.89 42.57,96.91 42.57,97.06 42.5,97.13 41.75,97.13 UV7.C2
  BOTTOM w0.102: UV1.C9 53.96,89.74 53.89,89.74 53.63,90 53.03,90 52.87,90.16 52.56,90.16 52.47,90.25 v2(52.47,90.43)
M_DA46: length 45.7
  TOP w0.124: UV7.A2 43.23,97.53 44.25,98.56 44.25,101.71 v1(47.58,105.03) 48.19,105.64 48.19,106.13 48.31,106.25 48.55,106.25 48.67,106.13 48.67,105.49 48.8,105.36 49.05,105.36 49.26,105.56 49.26,106.03 49.38,106.15 49.63,106.15 49.75,106.03 49.75,105.56 49.88,105.44 50.21,105.44 50.33,105.56 50.33,106.05 50.45,106.18 50.7,106.18 50.83,106.05 50.83,105.56 50.95,105.44 51.2,105.44 51.33,105.56 51.33,106.05 51.45,106.18 51.7,106.18 51.82,106.05 51.82,105.56 51.95,105.44 52.2,105.44 52.32,105.56 52.32,106.33 52.45,106.46 52.69,106.46 52.82,106.33 52.82,105.56 52.94,105.44 53.19,105.44 53.32,105.56 53.32,106.33 53.44,106.46 53.69,106.46 53.81,106.33 53.81,105.56 53.94,105.44 54.34,105.44 55.76,104.02 55.76,100.99 55.05,100.28 55.05,96.73 55.12,96.65 55.12,96.47 54.96,96.31 54.66,96.31 54.43,96.54 54.25,96.54 54.08,96.37 54.08,96.19 54.38,95.88 54.38,95.73 54,95.35 54,93.98 54.75,93.22 54.75,90.68 55.07,90.36 v2(55.07,90.14)
  BOTTOM w0.102: UV1.F9 55.71,89.59 56.02,89.59 56.16,89.45 56.16,89.31 56.09,89.23 55.23,89.23 55.12,89.34 55.12,90.09 v2(55.07,90.14)
M_DA47: length 44.4
  TOP w0.124: v2(54.44,90.02) 54.27,90.18 54.27,93.34 53.88,93.73 53.44,93.73 52.81,94.36 52.81,95.46 53.2,95.85 53.38,95.85 53.46,95.76 53.64,95.76 53.82,95.93 53.82,96.11 53.73,96.2 53.73,96.37 54.67,97.31 54.67,101.03 54.87,101.23 55.25,101.23 55.38,101.36 55.38,101.6 55.25,101.73 54.87,101.73 54.74,101.85 54.74,102.1 54.87,102.23 55.25,102.23 55.38,102.35 55.38,102.6 55.25,102.72 54.87,102.72 54.59,103 54.59,103.13 54.79,103.33 55.12,103.33 55.33,103.53 55.33,103.86 55,104.19 54.82,104.19 54.17,103.55 54,103.55 53.82,103.72 53.82,103.9 54.21,104.29 54.21,104.6 53.96,104.86 53.75,104.86 53.62,104.73 53.62,104.35 53.49,104.22 53.25,104.22 53.12,104.35 53.12,104.73 53,104.86 52.71,104.86 52.61,104.76 52.61,104.4 52.49,104.27 52.24,104.27 52.11,104.4 52.11,104.76 52.01,104.86 51.55,104.86 51.42,104.73 51.42,104.52 51.3,104.4 51.05,104.4 50.93,104.52 50.93,104.73 50.8,104.86 50.65,104.86 50.43,104.63 50.17,104.63 49.94,104.86 48.01,104.86 47.44,104.28 47.44,104.1 47.5,104.04 47.5,103.86 47.32,103.69 47.15,103.69 47.08,103.75 46.91,103.75 44.66,101.5 44.66,98.18 43.61,97.13 43.34,97.13 UV7.A3
  BOTTOM w0.102: UV1.D8 54.5,90.4 54.69,90.4 54.79,90.5 54.79,90.8 54.58,91.01 54.13,91.01 53.9,90.78 53.9,90.17 54.06,90.02 v2(54.44,90.02)
M_DA48: length 38.4
  IN1 w0.102: 49.97,90.91 53.24,90.91 53.78,90.38 53.96,90.38 54.17,90.58 54.17,90.81 54.27,90.91 54.47,90.91 54.57,90.81 54.57,90.58 54.67,90.48 54.89,90.48 v2(55.2,90.79)
  IN1 w0.13: v2(38.59,93.1) 37.47,93.1 37.34,92.97 37.34,92.56 37.47,92.43 37.79,92.43 38.28,91.94 38.73,91.94 38.8,91.88 42.9,91.88 43.09,92.06 43.09,93.32 43.22,93.45 43.42,93.45 43.59,93.27 43.59,92.03 44.02,91.61 44.47,91.61 44.57,91.71 44.57,92.87 44.7,92.99 45.11,92.99 45.23,92.87 45.23,91.62 45.36,91.5 45.77,91.5 45.9,91.62 45.9,92.97 46.02,93.1 46.43,93.1 46.56,92.97 46.56,91.97 46.69,91.83 47,91.83 47.2,92.03 47.2,94.05 47.32,94.18 47.73,94.18 47.85,94.05 47.85,92.18 47.98,92.05 48.39,92.05 48.51,92.18 48.51,93.69 48.64,93.81 49.05,93.81 49.18,93.69 49.18,91.55 49.59,91.14 49.69,91.14 49.92,90.91 49.97,90.91
  BOTTOM w0.124: v2(38.59,93.1) 38.27,92.77 38.19,92.77 UV8.G2 ; UV1.E7 54.8,91.19 v2(55.2,90.79)
M_DA49: length 37
  IN1 w0.102: 49.97,96.68 49.98,96.68 50.46,96.19
  IN1 w0.13: v2(40.19,93.95) 41.04,93.95 41.16,94.08 41.16,94.47 41.04,94.6 40.85,94.6 40.72,94.73 40.72,95.15 40.85,95.27 41.23,95.27 41.35,95.4 41.35,95.84 42.68,97.17 43.53,97.17 44.14,97.78 44.14,97.9 44.26,98.02 44.43,98.02 44.56,98.15 44.56,99.75 44.68,99.88 45.03,99.88 45.15,99.75 45.15,98.12 45.28,98 45.69,98 45.81,98.12 45.81,100.23 45.94,100.35 46.23,100.35 46.36,100.23 46.36,96.73 46.49,96.6 46.78,96.6 46.91,96.73 46.91,98.38 47.03,98.51 47.34,98.51 47.46,98.38 47.46,96.98 47.77,96.68 49.97,96.68 ; 50.46,96.19 50.46,94.46 50.7,94.21 50.7,92.62 51.18,92.14 52,92.14 52.33,92.47 53.36,92.47 53.48,92.34 53.48,91.44 53.44,91.39 52.41,91.39 52.37,91.44 v2(52.37,91.59)
  BOTTOM w0.124: v2(40.19,93.95) 40.17,93.95 UV8.E3 ; UV1.A7 52.66,91.3 v2(52.37,91.59)
M_DA50: length 38
  IN1 w0.102: 49.99,95.76 49.97,95.78
  IN1 w0.13: 49.97,95.78 49.58,96.17 48.09,96.17 47.73,95.81 47.73,95.48 47.61,95.36 47.26,95.36 47.13,95.48 47.13,96.04 47.01,96.17 46.62,96.17 46.49,96.04 46.49,95.41 46.36,95.28 46.03,95.28 45.9,95.41 45.9,97.36 45.78,97.49 45.48,97.49 45.36,97.36 45.36,95.5 45.19,95.33 44.86,95.33 44.7,95.5 44.7,97.38 44.57,97.51 44.29,97.51 44.14,97.35 44.14,95.41 44.01,95.28 43.6,95.28 43.48,95.41 43.48,96.64 43.31,96.81 42.98,96.81 42.82,96.64 42.82,95.92 42.69,95.8 41.75,95.8 41.62,95.67 41.62,95.24 41.75,95.11 42.42,95.11 42.55,94.98 42.55,94.55 42.42,94.42 41.7,94.42 41.56,94.28 41.56,94.01 41.1,93.55 36.98,93.55 36.95,93.59 v2(36.95,93.89) ; 49.99,95.76 49.99,92.19 50.11,92.07 50.58,92.07 51.07,91.59 v2(51.71,91.59)
  BOTTOM w0.124: UV1.C7 53.6,90.9 52.38,90.9 51.71,91.58 v2(51.71,91.59) ; v2(36.95,93.89) 37.3,93.53 UV8.H3
M_DA51: length 37.8
  IN1 w0.102: 54.77,91.32 54.59,91.14 50.32,91.14 49.97,91.5
  IN1 w0.13: 54.77,91.32 55.63,91.32 55.76,91.44 55.98,91.44 56.2,91.22 56.2,91.07 56.07,90.95 v2(56,90.95) ; v2(39.35,92.31) 39.35,92.43 40.06,93.14 40.69,93.14 40.84,92.99 40.84,92.37 40.97,92.24 41.37,92.24 41.5,92.37 41.5,93.57 41.63,93.7 42.03,93.7 42.16,93.57 42.16,92.38 42.29,92.25 42.69,92.25 42.82,92.38 42.82,93.53 42.85,93.56 42.85,94.7 42.98,94.82 43.4,94.82 43.53,94.7 43.53,93.78 43.65,93.65 44.06,93.65 44.19,93.78 44.19,94.8 44.31,94.92 44.72,94.92 44.85,94.8 44.85,93.6 44.97,93.48 45.38,93.48 45.51,93.6 45.51,94.7 45.63,94.82 46.04,94.82 46.17,94.7 46.17,93.76 46.29,93.63 46.64,93.63 46.77,93.76 46.77,94.77 46.89,94.9 47.38,94.9 47.63,94.65 48.03,94.65 48.15,94.77 48.15,95.6 48.28,95.73 49.37,95.73 49.52,95.58 49.52,95.07 49.42,94.97 48.94,94.97 48.81,94.84 48.81,94.39 48.91,94.28 49.38,94.28 49.61,94.05 49.61,91.85 49.97,91.5
  BOTTOM w0.124: v2(39.35,92.31) 39.34,92.31 38.95,92.71 UV8.F2 ; UV1.F7 55.65,91.3 v2(56,90.95)
M_DA52: length 36.7
  IN1 w0.13: v2(36.97,97.13) 37.1,97.13 37.45,96.78 37.98,96.78 38.06,96.7 40.31,96.7 41.39,97.78 41.39,101.02 42.58,102.21 44.1,102.21 44.58,102.7 49.36,102.7 50.35,101.71 50.35,101.2 50.48,101.07 51.87,101.07 52,100.94 52,100.73 51.87,100.61 50.4,100.61 50.27,100.48 50.27,100.21 50.4,100.09 52.58,100.09 52.71,99.96 52.71,99.7 52.58,99.57 52.33,99.57 52.2,99.44 52.2,99.18 52.33,99.05 52.58,99.05 52.71,98.92 52.71,98.66 52.58,98.53 52.33,98.53 52.2,98.4 52.2,98.14 52.33,98.02 52.58,98.02 52.71,97.89 52.71,95.47 52.58,95.34 52.33,95.34 52.2,95.21 52.2,94.95 52.33,94.82 52.58,94.82 52.71,94.69 52.71,94.39 52.58,94.26 51.97,94.26 51.85,94.14 51.85,93.9 51.97,93.77 v2(52.22,93.77)
  BOTTOM w0.124: UV1.A5 53.09,92.9 52.46,93.53 52.45,93.53 v2(52.22,93.77) ; v2(36.97,97.13) 37.35,96.75 UV8.H7
M_DA53: length 37.1
  IN1 w0.13: v2(39.32,97.11) 39.32,97.15 39.7,97.54 40.63,97.54 40.92,97.82 40.92,100.12 40.6,100.43 40.49,100.54 40.49,100.99 40.6,101.09 40.8,101.09 40.92,101.21 40.92,101.67 41.89,102.65 43.82,102.65 44.41,103.23 49.49,103.23 51.06,101.66 53.04,101.66 53.17,101.53 53.17,101.27 53.04,101.14 52.56,101.14 52.43,101.01 52.43,100.75 52.56,100.62 53.04,100.62 53.17,100.49 53.17,95.73 52.99,95.55 52.99,94.18 52.74,93.93 52.74,93.35 52.94,93.15 53.83,93.15 53.95,93.27 53.95,94.36 54.14,94.54 55.43,94.54 55.62,94.36 55.62,92.54 55.49,92.41 v2(55.15,92.41)
  BOTTOM w0.124: UV8.F7 v2(39.32,97.11) ; v2(55.15,92.41) 54.8,92.76 UV1.E5
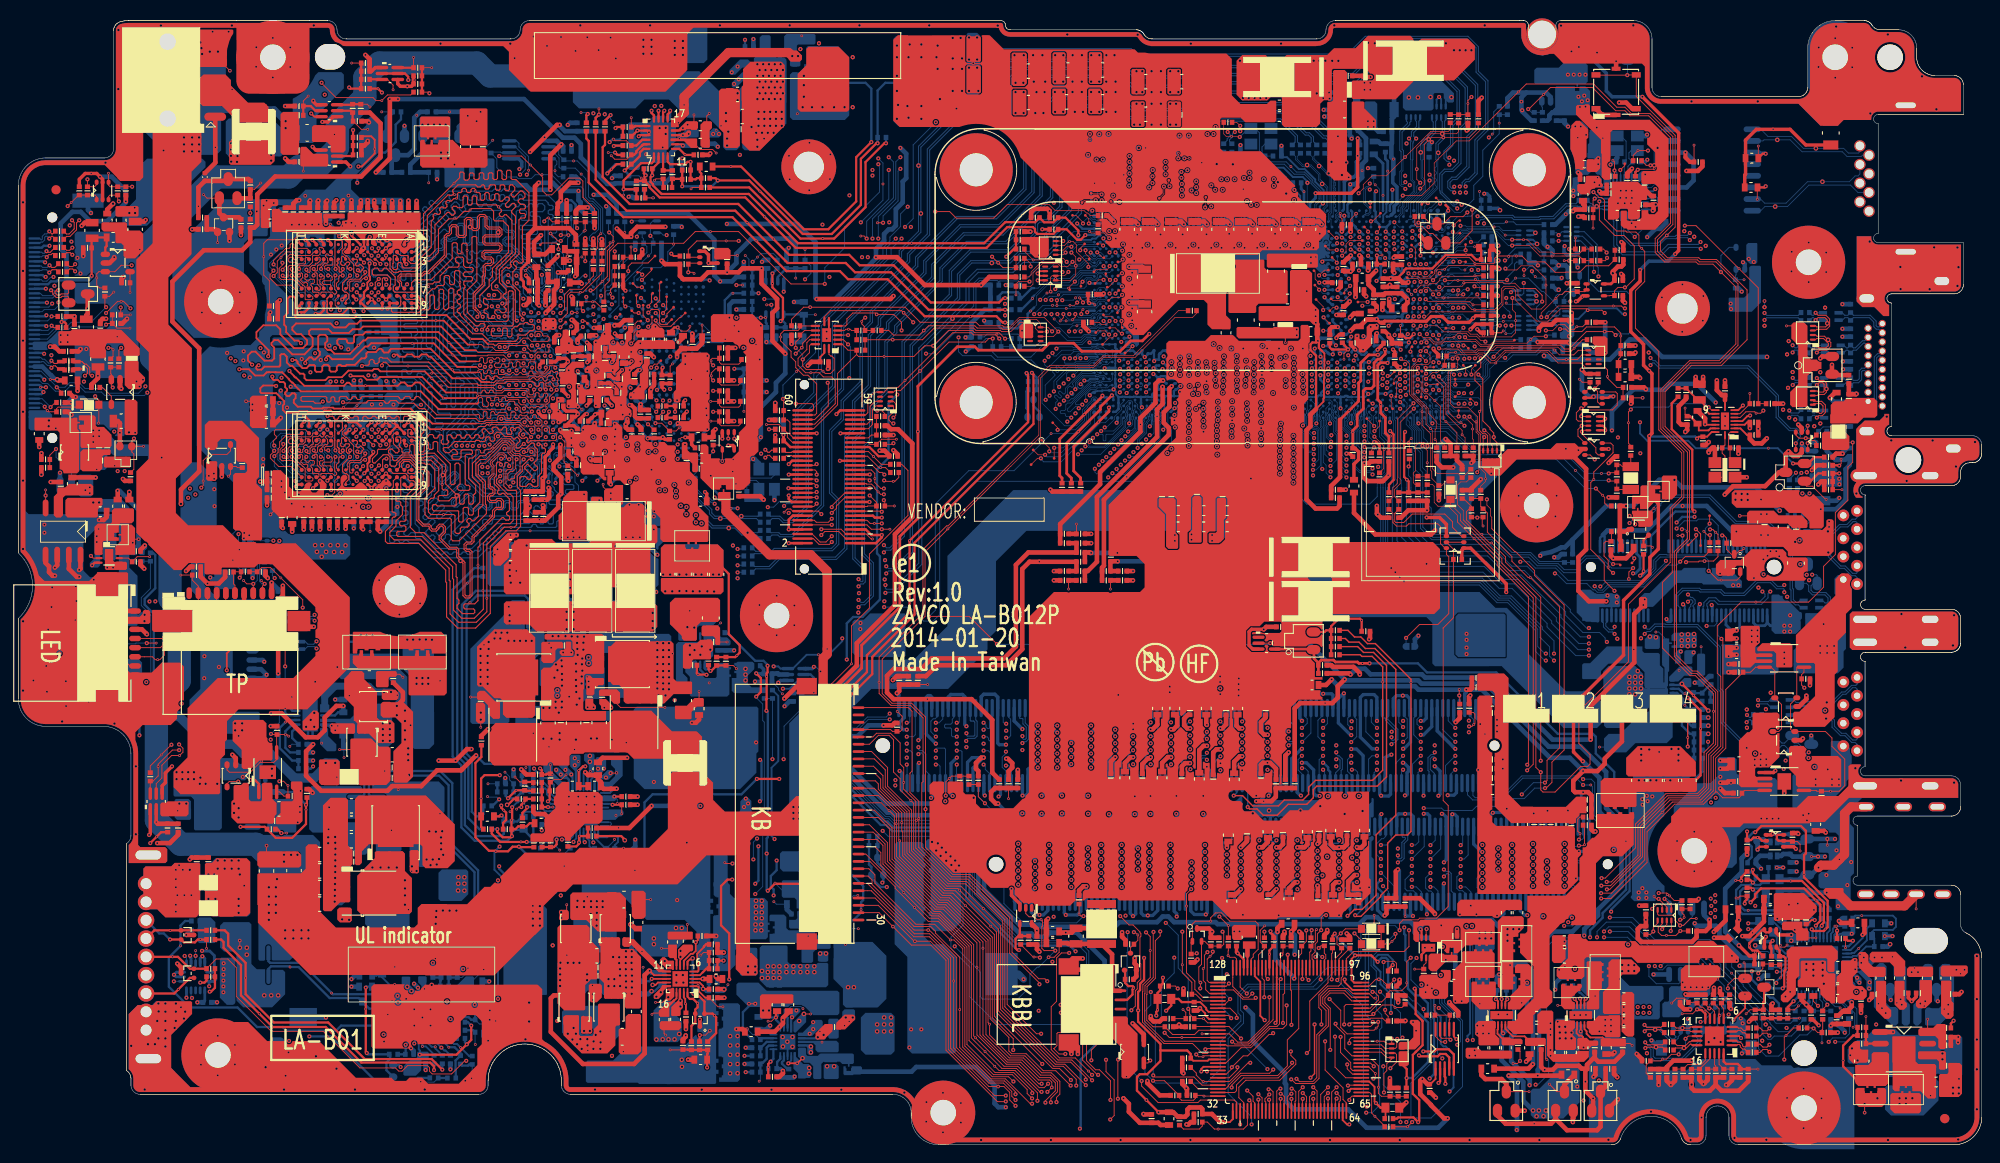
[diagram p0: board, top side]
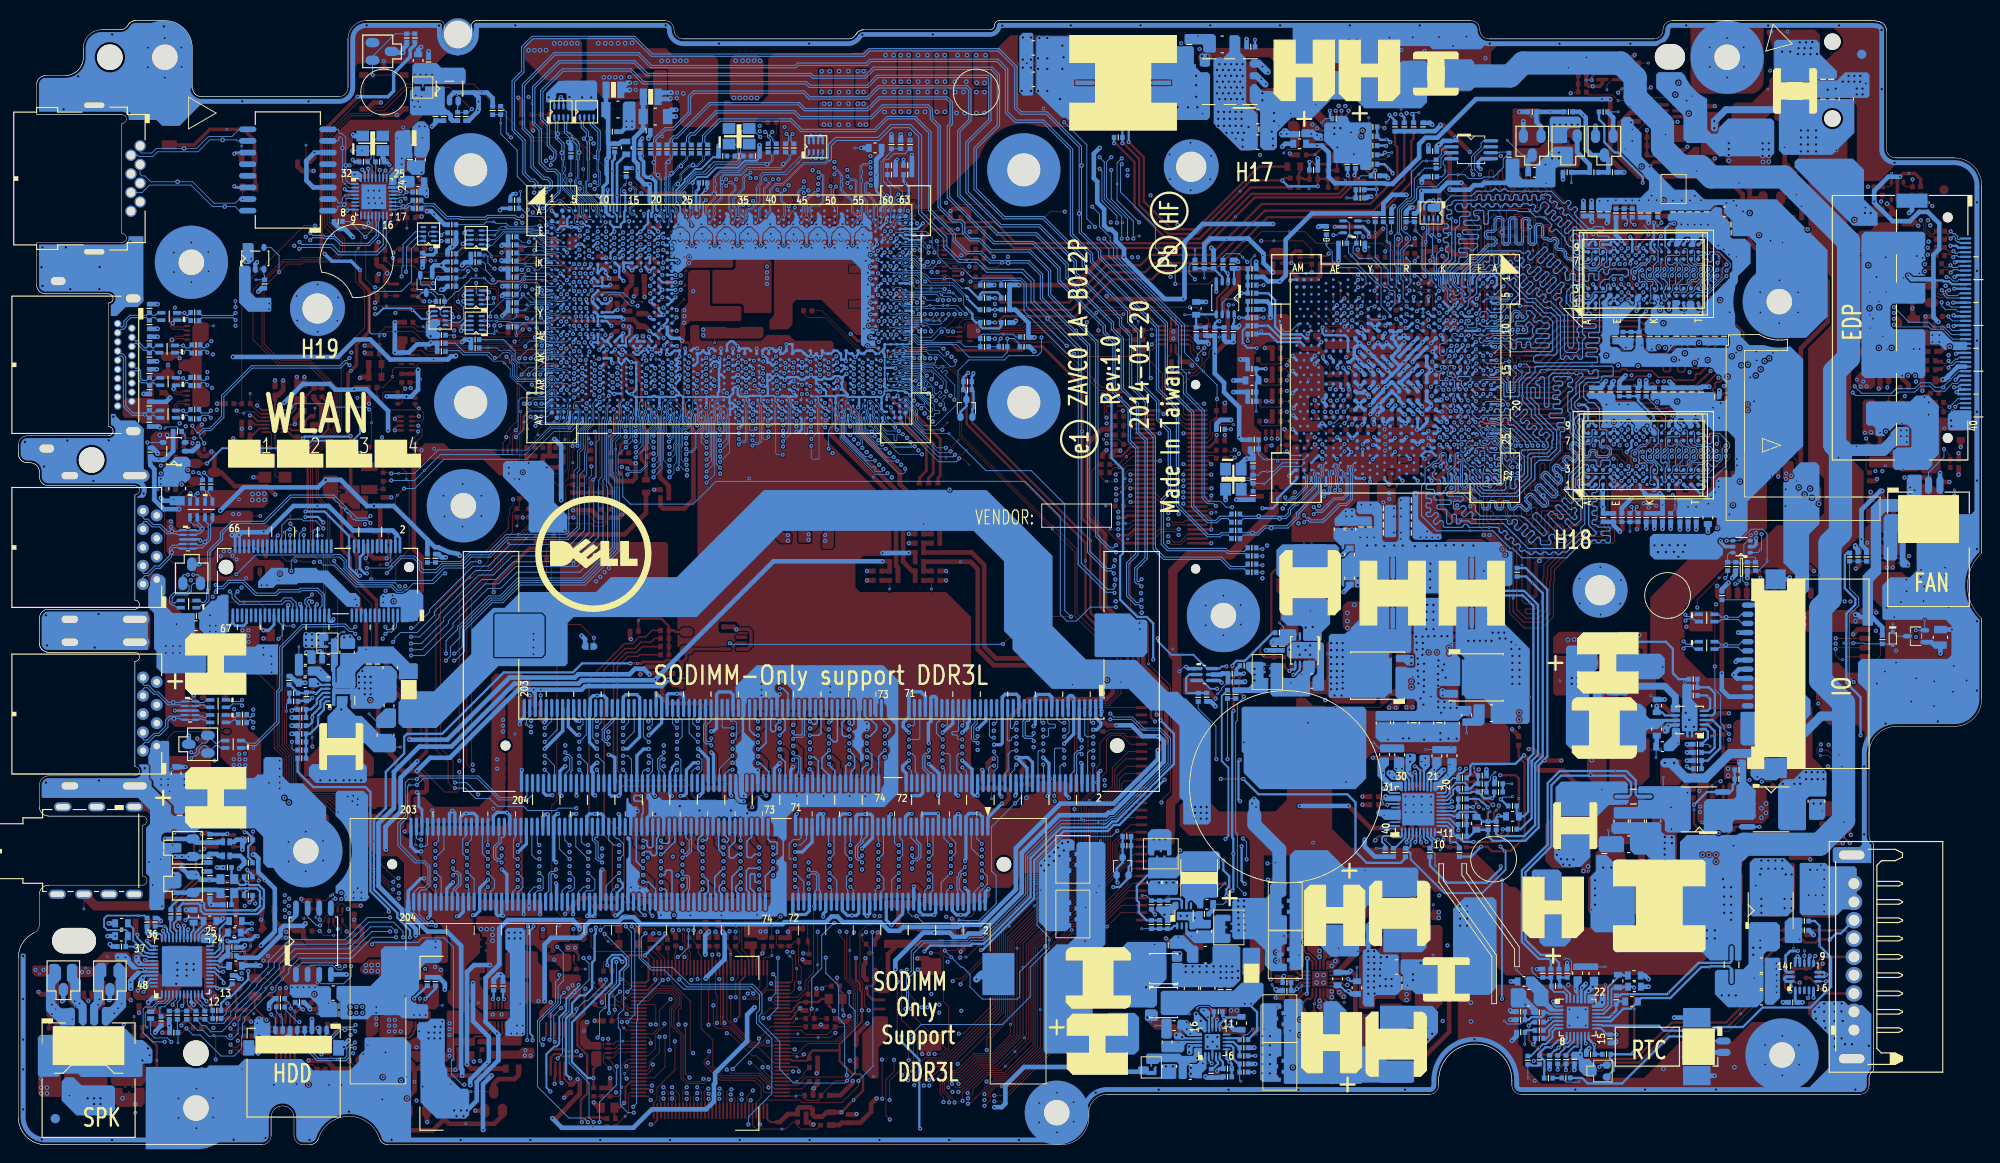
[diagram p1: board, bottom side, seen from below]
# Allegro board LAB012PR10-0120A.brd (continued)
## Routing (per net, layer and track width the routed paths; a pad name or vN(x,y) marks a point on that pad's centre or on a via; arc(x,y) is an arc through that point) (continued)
M_DA54: length 36.9
  IN1 w0.102: 53.6,97.72 53.6,97.6 53.45,97.45 53.45,95.61 53.93,95.13 53.93,94.8 53.47,94.33 v2(53.47,94.26)
  IN1 w0.13: v2(38.63,97.93) 38.63,97.93 38.63,97.94 38.46,97.94 38.42,97.99 38.42,98.3 38.46,98.35 39.65,98.35 39.78,98.47 39.78,98.94 39.91,99.07 39.91,99.07 40.02,99.18 40.02,99.28 40.15,99.41 40.52,99.41 40.65,99.54 40.65,99.8 40.52,99.93 40.15,99.93 40.02,100.06 40.02,101.56 41.28,102.82 41.28,103.28 41.74,103.74 50.42,103.74 50.55,103.61 50.55,102.8 50.65,102.7 50.89,102.7 51.02,102.83 51.02,103.69 51.14,103.81 51.41,103.81 51.53,103.69 51.53,102.24 51.66,102.11 51.92,102.11 52.05,102.24 52.05,103.71 52.18,103.84 52.46,103.84 52.58,103.71 52.58,102.26 52.71,102.14 53.24,102.14 53.6,101.78 53.6,97.72
  BOTTOM w0.124: UV1.C3 54,93.72 53.47,94.26 v2(53.47,94.26) ; UV8.F8 38.63,97.85 38.63,97.93 v2(38.63,97.93)
M_DA55: length 37.1
  IN1 w0.102: v2(54.39,94.94) 54.39,95.17 54.06,95.51 54.06,97.72
  IN1 w0.13: 54.06,97.72 54.06,102.77 53.93,102.9 53.15,102.9 53.02,103.03 53.02,103.29 53.15,103.42 53.32,103.42 53.59,103.69 53.59,104.28 53.17,104.7 52.88,104.7 52.78,104.6 52.78,104.4 52.65,104.27 52.39,104.27 52.26,104.4 52.26,104.6 52.13,104.73 50.85,104.73 50.7,104.57 50.7,104.3 50.57,104.17 50.31,104.17 50.18,104.3 50.18,104.57 50.05,104.7 49.79,104.7 49.66,104.57 49.66,104.3 49.53,104.17 49.27,104.17 49.14,104.3 49.14,104.57 49.01,104.7 48.75,104.7 48.62,104.57 48.62,104.3 48.5,104.17 48.24,104.17 48.11,104.3 48.11,104.57 47.98,104.7 47.72,104.7 47.59,104.57 47.59,104.3 47.46,104.17 47.2,104.17 47.07,104.3 47.07,104.57 46.94,104.7 46.51,104.7 46.01,104.2 40.98,104.2 40.39,103.61 40.39,102.65 39.55,101.81 39.55,100.05 38.82,99.32 38.82,98.76 38.72,98.66 38.44,98.66 38.11,98.32 38.11,97.51 v2(37.77,97.18)
  BOTTOM w0.124: v2(54.39,94.94) 54.8,94.53 UV1.E1 ; v2(37.77,97.18) 37.7,97.18 UV8.H8
M_DA56: length 45.6
  BOTTOM w0.124: UV8.C2 41.39,92.73 41.74,92.38 41.74,88.81 41.86,88.69 42.81,88.69 42.93,88.57 42.93,88.32 42.81,88.19 41.86,88.19 41.74,88.07 41.74,87.79 41.95,87.58 43.09,87.58 43.21,87.45 43.21,87.2 43.09,87.08 42.09,87.08 41.97,86.95 41.97,86.7 42.09,86.58 43.09,86.58 43.21,86.46 43.21,86.21 43.09,86.08 42.09,86.08 41.97,85.96 41.97,85.53 42.07,85.42 48.77,85.42 48.93,85.58 48.93,85.99 48.65,86.26 v1(47.45,86.26) 46.6,86.26 46.39,86.48 46.39,90.24 47.01,90.86 47.76,90.86 48.93,92.03 49.69,92.03 50.1,92.44 50.28,92.44 50.99,91.73 51.17,91.73 51.34,91.91 51.34,92.08 50.63,92.8 50.63,92.97 53.19,95.53 53.55,95.53 53.73,95.36 54.54,95.36 54.81,95.09 54.81,94.96 55.15,94.62 55.15,93.02 55.58,92.59 55.73,92.59 56.06,92.26 56.06,91.64 UV1.G7
M_DA57: length 44.9
  BOTTOM w0.102: UV1.G6 56.6,92.3 56.6,92.43 56.53,92.5 56.23,92.5 55.84,92.89 55.84,93.02 56.09,93.27 56.09,93.62 56.1,93.63 56.1,93.83 56.11,93.85 56.11,93.96 56.17,94.01 56.17,94.3 56.09,94.38 56.09,95.18 55.43,95.84
  BOTTOM w0.124: UV8.A2 42.98,92.76 42.98,92.94 43.1,93.07 43.4,93.07 43.52,93.19 43.52,93.58 43.65,93.7 43.9,93.7 44.02,93.58 44.02,93.19 44.15,93.07 44.79,93.07 44.91,92.94 44.91,92.16 44.41,91.65 44.41,91.19 44,90.78 44,90.31 44.18,90.13 44.18,89.81 44,89.63 44,89.31 44.18,89.13 44.18,88.81 44,88.64 44,88.32 44.18,88.14 44.18,87.82 44,87.64 44,86.82 44.28,86.54 45.32,86.54 45.57,86.8 45.57,90.61 47.1,92.13 47.38,92.13 47.5,92 47.71,92 47.85,92.15 47.85,92.32 47.61,92.56 47.61,92.74 v1(47.68,92.82) 47.78,92.91 47.96,92.91 48.23,92.65 48.41,92.65 48.58,92.83 48.58,93.01 48.32,93.27 48.32,93.45 48.47,93.6 48.65,93.6 49.32,92.93 49.5,92.93 49.68,93.11 49.68,93.28 49.03,93.93 49.03,94.11 49.2,94.28 49.38,94.28 50.03,93.64 50.2,93.64 50.38,93.81 50.38,93.99 49.71,94.66 49.71,94.84 49.99,95.13 50.17,95.13 50.51,94.79 50.69,94.79 50.89,94.98 50.89,95.16 50.51,95.54 50.51,95.72 50.68,95.89 50.86,95.89 51.24,95.51 51.42,95.51 51.59,95.68 51.59,95.86 51.21,96.25 51.21,96.42 51.39,96.6 51.56,96.6 51.84,96.32 52.02,96.32 52.25,96.55 52.25,97.01 52.38,97.13 52.62,97.13 52.75,97.01 52.75,96.3 52.88,96.17 53.12,96.17 53.25,96.3 53.25,97.01 53.37,97.13 53.62,97.13 53.74,97.01 53.74,96.55 53.88,96.41 54.03,96.41 54.11,96.5 54.29,96.5 54.46,96.32 54.46,96.14 54.36,96.04 54.36,95.93 54.45,95.84 55.43,95.84
M_DA58: length 45.2
  BOTTOM w0.124: UV1.G1 56.4,95.3 55.61,96.09 55.17,96.09 53.88,97.39 51.7,97.39 51.54,97.23 51.36,97.23 51.25,97.35 51.07,97.35 50.9,97.18 50.9,97 51.01,96.88 51.01,96.71 50.84,96.53 50.66,96.53 50.33,96.86 50.15,96.86 49.98,96.68 49.98,96.51 50.31,96.18 50.31,96 50.13,95.83 49.96,95.83 49.62,96.16 49.45,96.16 49.27,95.98 49.27,95.8 49.6,95.47 49.6,95.3 49.43,95.12 49.25,95.12 48.48,95.9 48.3,95.9 48.13,95.72 48.13,95.54 48.9,94.77 48.9,94.59 48.72,94.42 48.55,94.42 47.61,95.36 47.43,95.36 47.26,95.18 47.26,95 48.2,94.06 48.2,93.89 48.02,93.71 47.84,93.71 46.8,94.75 46.62,94.75 46.45,94.58 46.45,94.4 47.49,93.36 47.49,93.18 47.32,93.01 47.14,93.01 45.95,94.2 45.77,94.2 45.59,94.03 45.59,93.85 45.92,93.53 45.92,93.35 45.89,93.33 45.89,93.16 46.07,92.98 46.25,92.98 46.27,93 46.44,93 46.79,92.66 46.79,92.48 46.61,92.3 46.44,92.3 46.18,92.56 46,92.56 45.83,92.39 45.83,92.21 46.08,91.95 46.08,91.78 45.19,90.89 45.19,87.25 44.99,87.05 44.76,87.05 44.56,87.25 44.56,90.94 44.76,91.14 44.76,91.39 45.32,91.95 45.32,93.21 v1(44.78,93.75) 44.57,93.96 43.37,93.96 UV8.A3
M_DA59: length 44.3
  BOTTOM w0.124: UV8.C3 41.52,93.53 41.66,93.68 41.66,94.09 41.22,94.53 40.79,94.53 40.29,95.03 39.22,95.03 39,94.8 38.79,94.8 38.56,95.03 38.56,95.54 38.69,95.67 40.63,95.67 40.75,95.54 40.75,95.23 40.87,95.1 41.12,95.1 41.25,95.23 41.25,95.54 41.37,95.67 41.53,95.67 41.81,95.38 41.81,94.56 41.94,94.44 42.19,94.44 42.32,94.56 42.32,95.06 42.43,95.18 42.77,95.18 42.9,95.05 42.9,94.44 43.02,94.31 43.27,94.31 43.4,94.44 43.4,95.05 43.52,95.18 43.77,95.18 43.89,95.05 43.89,94.44 44.02,94.31 44.27,94.31 44.39,94.44 44.39,95.05 44.52,95.18 44.83,95.18 44.96,95.05 44.96,94.54 45.08,94.42 45.33,94.42 45.46,94.54 45.46,95.05 45.52,95.12 45.52,95.25 45.27,95.51 45.27,95.69 45.46,95.88 45.64,95.88 46.34,95.18 46.62,95.18 46.78,95.34 46.78,95.52 45.99,96.31 45.99,96.49 46.17,96.66 46.35,96.66 47.13,95.87 47.31,95.87 47.49,96.05 47.49,96.22 46.74,96.97 46.74,97.15 46.91,97.33 47.09,97.33 48.12,96.3 48.3,96.3 48.48,96.49 48.48,96.67 47.43,97.72 47.43,97.9 47.6,98.07 47.78,98.07 v1(48.46,97.4) 49.19,96.67 49.37,96.67 49.57,96.87 49.57,97.05 49.31,97.31 49.31,97.49 49.45,97.63 49.63,97.63 49.87,97.39 50.17,97.39 50.43,97.64 53.96,97.64 55.25,96.35 55.7,96.35 56.75,95.29 56.75,93.79 56.66,93.7 UV1.G3
M_DA60: length 45.3
  BOTTOM w0.102: 58,92.12 58.3,92.42 58.3,93.24 58.67,93.6 58.74,93.6 59.1,93.97 59.1,94.28 59.09,94.29 59.09,94.83 59.32,95.05 59.32,95.66 58.86,96.12
  BOTTOM w0.124: 58.86,96.12 58.86,96.26 58.46,96.66 58.25,96.87 58.25,97.44 58.37,97.57 58.43,97.57 58.55,97.69 58.55,97.94 58.43,98.06 58.37,98.06 58.25,98.19 58.25,98.47 58.37,98.6 58.66,98.6 58.78,98.72 58.78,98.97 58.66,99.1 58.37,99.1 58.25,99.22 58.25,99.47 58.37,99.59 58.66,99.59 58.78,99.72 58.78,99.97 58.66,100.09 58.37,100.09 58.25,100.22 58.25,100.46 58.37,100.59 58.66,100.59 58.78,100.71 58.78,102.8 57.92,103.66 55.71,103.66 55.2,104.17 53.49,104.17 53.37,104.29 53.37,104.3 53.24,104.42 52.99,104.42 52.87,104.3 52.87,104.29 52.74,104.17 52.49,104.17 52.27,104.4 51.98,104.4 51.75,104.17 v1(49.89,104.17) 47.02,104.17 45.7,102.84 45.52,102.84 45.21,103.15 45.04,103.15 44.86,102.98 44.86,102.8 45.17,102.49 45.17,102.32 44.99,102.14 44.82,102.14 44.51,102.45 44.33,102.45 44.16,102.27 44.16,102.1 44.47,101.79 44.47,101.61 42.95,100.09 42.52,100.09 42.33,100.28 41.41,100.28 41.28,100.16 41.28,99.9 41.4,99.78 41.85,99.78 41.97,99.66 41.97,99.39 41.84,99.27 40.81,99.27 40.69,99.14 40.69,98.86 40.81,98.73 41.61,98.73 41.74,98.61 41.74,98.18 41.5,97.94 41.21,97.94 40.96,97.69 40.96,96.51 41.23,96.24 41.23,95.94 41.13,95.84 40.82,95.84 40.62,96.04 40.62,96.4 40.55,96.47 UV8.D7 ; UV1.J6 58,92.12
M_DA61: length 44.5
  BOTTOM w0.124: UV8.B8 42.48,97.53 42.56,97.45 42.56,96.58 42.89,96.24 43.52,96.24 43.59,96.17 43.82,96.17 44,96.35 44,96.6 43.74,96.85 43.74,97.06 43.94,97.25 44.11,97.25 44.13,97.24 44.3,97.24 44.48,97.41 44.48,97.59 44.46,97.6 44.46,97.78 44.81,98.12 45.01,98.12 45.32,98.43 45.32,98.63 45.52,98.84 45.52,99.09 46.43,100 46.61,100 46.86,99.74 47.06,99.74 47.21,99.89 47.21,100.09 46.96,100.35 46.96,100.52 v1(47.66,101.23) 47.78,101.35 48.7,101.35 49.28,101.93 50.63,101.93 50.76,102.07 53.75,102.07 53.88,101.94 53.88,100.71 54.02,100.56 54.23,100.56 54.38,100.71 54.38,101.94 54.5,102.07 55.35,102.07 55.48,101.94 55.48,101.61 55.35,101.48 55.02,101.48 54.87,101.33 54.87,101.13 55.02,100.98 56.39,100.98 56.55,100.83 56.55,100.59 56.39,100.44 54.84,100.44 54.69,100.29 54.69,100.12 54.87,99.94 56.55,99.94 56.7,99.8 56.7,99.59 56.55,99.44 55.07,99.44 54.93,99.31 54.93,99.08 55.07,98.95 56.88,98.95 56.9,98.93 57.02,98.93 57.11,98.85 57.11,98.55 57.01,98.45 55.15,98.45 55.06,98.36 55.06,98.14 55.52,97.67 55.74,97.67 56.02,97.95 56.96,97.95 57.11,97.8 57.11,97.6 56.96,97.45 56.24,97.45 56.11,97.33 56.11,97.08 56.24,96.96 56.96,96.96 57.08,96.83 57.08,96.45 58.06,95.47 58.06,94.56 UV1.J1
M_DA62: length 44.8
  BOTTOM w0.102: 58.29,95.76 58.29,94.64 58.3,94.63 58.3,94.37 58.29,94.36 58.29,94.05 58,93.76 UV1.J3
  BOTTOM w0.124: UV8.A7 43.18,96.5 43.36,96.5 43.51,96.64 43.51,97.29 43.86,97.64 44,97.64 44.38,98.02 44.38,98.2 44.1,98.48 44.1,98.75 44.18,98.83 44.45,98.83 44.59,98.69 44.79,98.69 44.91,98.81 44.91,99.15 44.52,99.54 44.3,99.54 44,99.24 43.69,99.24 43.57,99.37 43.57,99.52 44.32,100.27 44.5,100.27 45.21,99.56 45.38,99.56 45.56,99.73 45.56,99.91 44.85,100.62 44.85,100.8 45.02,100.97 45.2,100.97 45.9,100.28 46.08,100.28 46.25,100.45 46.25,100.63 45.85,101.02 45.85,101.2 46.03,101.38 46.21,101.38 46.63,100.96 46.81,100.96 46.98,101.13 46.98,101.31 46.56,101.73 46.56,101.9 46.74,102.08 46.91,102.08 47.33,101.66 47.51,101.66 47.68,101.83 47.68,102.01 47.26,102.43 47.26,102.61 47.63,102.98 47.85,102.98 48.16,102.66 48.16,102.24 48.49,101.91 48.67,101.91 48.85,102.09 48.85,102.26 48.73,102.38 48.73,102.56 48.91,102.73 49.09,102.73 49.2,102.61 49.38,102.61 49.56,102.8 50.11,102.8 50.24,102.67 50.24,102.59 50.36,102.47 50.61,102.47 50.73,102.59 50.73,102.67 50.86,102.8 51.11,102.8 51.23,102.67 51.23,102.59 51.36,102.47 51.6,102.47 51.73,102.59 51.73,102.67 51.85,102.8 52.1,102.8 52.23,102.67 52.23,102.59 52.35,102.47 v1(52.46,102.47) 52.6,102.47 52.72,102.59 52.72,102.67 52.85,102.8 53.1,102.8 53.22,102.67 53.22,102.59 53.35,102.47 53.6,102.47 53.72,102.59 53.72,102.67 53.84,102.8 54.09,102.8 54.22,102.67 54.22,102.59 54.34,102.47 54.59,102.47 54.72,102.59 54.72,102.67 54.84,102.8 55.09,102.8 55.21,102.67 55.21,102.59 55.34,102.47 55.59,102.47 55.71,102.59 55.71,102.67 55.84,102.8 56.08,102.8 56.21,102.67 56.21,102.47 56.34,102.34 56.58,102.34 56.71,102.47 56.71,102.67 56.83,102.8 57.23,102.8 57.49,102.54 57.49,102.18 57.24,101.93 56.01,101.93 55.89,101.8 55.89,101.55 56.01,101.43 56.85,101.43 57,101.28 57,100.54 57.49,100.05 57.49,96.56 58.29,95.76
M_DA63: length 45.4
  BOTTOM w0.102: UV1.J5 58.1,92.8 58.1,92.64 57.77,92.31 57.44,92.31 57.33,92.41 56.93,92.41 56.72,92.61 56.72,92.94 56.85,93.07 56.98,93.07 57.28,92.77 57.49,92.77 57.64,92.92 57.64,93.2 57.71,93.27 58,93.27 58.5,93.76 58.5,94.23 58.51,94.24 58.51,96.09 58.48,96.12
  BOTTOM w0.124: UV8.C8 41.35,97.35 41.43,97.26 41.69,97.26 41.75,97.32 41.75,97.83 41.84,97.92 43.08,97.92 43.33,98.17 43.33,98.51 43.11,98.73 43.11,99.65 45.11,101.64 45.28,101.64 45.4,101.53 45.57,101.53 45.75,101.7 45.75,101.88 45.63,102 45.63,102.17 45.81,102.35 45.99,102.35 46.1,102.23 46.28,102.23 46.45,102.41 46.45,102.58 46.34,102.7 46.34,102.88 46.52,103.06 46.7,103.06 46.84,102.92 47.01,102.92 47.19,103.09 47.19,103.27 47.05,103.41 47.05,103.59 47.25,103.79 v1(47.63,103.79) 48.01,103.79 48.14,103.66 48.14,103.3 48.26,103.18 48.51,103.18 48.63,103.3 48.63,103.66 48.76,103.79 49.01,103.79 49.13,103.66 49.13,103.3 49.26,103.18 49.51,103.18 49.63,103.3 49.63,103.66 49.76,103.79 50,103.79 50.13,103.66 50.13,103.3 50.25,103.18 50.5,103.18 50.63,103.3 50.63,103.66 50.75,103.79 51,103.79 51.12,103.66 51.12,103.3 51.25,103.18 51.5,103.18 51.62,103.3 51.62,103.66 51.75,103.79 52,103.79 52.12,103.66 52.12,103.3 52.24,103.18 52.49,103.18 52.62,103.3 52.62,103.66 52.74,103.79 52.99,103.79 53.12,103.66 53.12,103.3 53.24,103.18 53.49,103.18 53.61,103.3 53.61,103.66 53.74,103.79 53.99,103.79 54.11,103.66 54.11,103.3 54.24,103.18 54.48,103.18 54.61,103.3 54.61,103.66 54.73,103.79 54.9,103.79 55.1,103.59 55.1,103.28 55.2,103.18 57.57,103.18 57.87,102.87 57.87,102.74 57.99,102.62 58.28,102.62 58.4,102.5 58.4,102.25 58.28,102.12 57.99,102.12 57.87,102 57.87,101.75 57.99,101.62 58.28,101.62 58.4,101.5 58.4,101.25 58.28,101.13 57.99,101.13 57.87,101 57.87,96.73 58.48,96.12
M_DQM0: length 47
  BOTTOM w0.102: UV1.E32 54.8,73.04 55.21,73.46 55.21,73.74 55.57,74.1 55.83,74.1 56.44,74.72 56.44,74.83 56.85,75.24 56.85,75.38 57.07,75.6 57.33,75.6 57.5,75.43 57.5,74.16 57.87,73.8 57.94,73.8 58.3,73.43 58.3,73.17 58.27,73.14 58.27,72.03
  BOTTOM w0.124: UV5.D3 40.5,73.67 40.5,73.56 40.72,73.33 43.14,73.33 43.29,73.49 43.67,73.49 44.38,72.78 44.38,71.81 43.34,70.77 43.34,67.82 43.77,67.39 43.77,66.98 45.62,65.13 49.51,65.13 52.23,67.85 55.76,67.85 56.06,68.15 56.78,68.15 v1(56.9,68.28) 56.9,67.97 57.05,67.82 57.28,67.82 57.35,67.89 57.35,68.74 57.48,68.86 57.73,68.86 57.85,68.74 57.85,67.95 57.98,67.82 58.3,67.82 58.43,67.95 58.43,69.3 58.55,69.42 59.34,69.42 59.47,69.55 59.47,69.81 59.34,69.94 58.07,69.94 57.94,70.06 57.94,70.31 58.07,70.43 59.67,70.43 59.8,70.57 59.8,70.84 59.62,71.02 59.06,71.02 58.54,71.55 58.54,71.77 58.27,72.03
M_DQM1: length 46.7
  TOP w0.102: v2(53.73,71.9) 53.56,71.9 53.24,72.22 53.24,73.56 53.42,73.74 53.8,73.74 54.01,73.94 54.01,75.04 53.47,75.57 53.47,76.28 53.27,76.48 52.99,76.48 52.66,76.15 52.66,76.1 51.01,74.45 50.45,74.45 50.3,74.3
  TOP w0.124: 50.3,74.3 50.22,74.22 50.22,73.23 51.01,72.45 51.01,69.98 51.11,69.88 51.11,68.94 48.14,65.97 47.45,65.97 47.28,66.15 47.28,68.3 47.15,68.43 44.81,68.43 44.41,68.84 44.41,70.64 45.47,71.71 45.47,73.79 44.93,74.34 44.44,74.34 44.33,74.45 43.52,74.45 42.86,75.11 41.94,75.11 41.32,74.49 41.32,74.29 41.15,74.12 40.77,74.12 40.6,74.3 40.6,75.14 40.37,75.37 39.86,75.37 38.95,74.47 38.8,74.47 38.67,74.6 38.67,74.95 39.22,75.5 39.22,75.87 39.32,75.97 40.21,75.97 40.57,76.33 40.57,76.9 UV6.D3
  BOTTOM w0.124: v2(53.73,71.9) 54.3,71.9 54.46,72.06 54.46,73.19 54.8,73.52 UV1.E30
M_DQM2: length 44.4
  IN1 w0.13: v2(40.17,76.52) 40.08,76.52 39.95,76.39 39.95,76.15 40.08,76.02 40.87,76.02 41.22,75.67 41.22,74.07 41.35,73.95 41.93,73.95 42.14,73.73 42.72,73.73 43.24,74.25 43.42,74.25 43.63,74.03 43.63,73.85 43.49,73.71 43.49,73.53 43.93,73.09 43.93,72.91 43.75,72.73 43.56,72.73 43.26,73.03 43.08,73.03 42.83,72.78 42.83,72.6 43.73,71.7 43.82,71.7 43.95,71.57 43.95,71.31 43.82,71.18 43.42,71.18 43.29,71.05 43.29,68.74 44.14,67.88 45.69,67.88 45.81,68.01 45.81,69.45 45.94,69.58 46.28,69.58 46.41,69.45 46.41,69.18 46.54,69.05 46.85,69.05 48.05,70.24 48.05,73.07 47.83,73.28 47.83,74.19 48.09,74.44 48.09,74.7 47.83,74.96 47.83,75.22 48.09,75.48 48.09,75.74 47.83,76 v2(47.83,76.36)
  BOTTOM w0.124: v2(40.17,76.52) 39.77,76.92 UV5.E7 ; UV1.A21 53.2,80.27 53.07,80.4 52.79,80.4 52.66,80.27 52.66,80.14 52.53,80.01 52.23,80.01 52.11,80.14 52.11,80.35 52.01,80.45 51.75,80.45 51.55,80.25 51.43,80.25 50.58,81.11 50.4,81.11 50.23,80.93 50.23,80.75 51.08,79.9 51.08,79.72 50.9,79.55 50.73,79.55 49.97,80.31 49.95,80.32 49.77,80.32 49.6,80.15 49.6,79.97 49.97,79.6 50.38,79.19 50.38,79.02 50.2,78.84 50.02,78.84 49.74,79.13 49.56,79.13 49.39,78.95 49.39,78.77 49.67,78.49 49.67,78.31 49.52,78.16 49.35,78.16 48.95,78.56 48.77,78.56 48.59,78.39 48.59,78.21 48.99,77.81 48.99,77.63 48.62,77.26 48.5,77.26 47.83,76.59 v2(47.83,76.36)
M_DQM3: length 41.4
  TOP w0.124: UV6.E7 39.78,73.76 39.78,74.82 39.89,74.93 40.18,74.93 v2(40.2,74.95)
  IN2 w0.13: v2(40.2,74.95) 42,74.95 42.13,74.82 42.13,74.53 42,74.4 41.08,74.4 40.95,74.27 40.95,73.87 41.08,73.74 42.85,73.74 42.98,73.87 42.98,74.75 43.21,74.99 43.51,74.99 43.64,74.86 43.64,74.6 43.74,74.5 44.25,74.5 44.35,74.6 45.32,74.6 45.45,74.73 45.45,76.94 45.57,77.07 45.84,77.07 45.97,76.94 45.97,74.74 46.11,74.6 46.39,74.6 46.49,74.71 46.49,75.86 46.62,75.99 47.15,75.99 47.28,76.12 47.28,76.38 47.15,76.51 46.62,76.51 46.49,76.63 46.49,76.89 46.62,77.02 47.78,77.02 47.99,76.81 48.35,76.81 48.45,76.92 48.45,76.99 48.58,77.12 48.84,77.12 48.97,76.99 48.97,76.92 49.1,76.79 49.36,76.79 49.49,76.92 49.49,76.99 49.62,77.12 49.88,77.12 50.01,76.99 50.01,76.92 50.11,76.81 50.5,76.81 50.6,76.92 50.6,77.22 50.78,77.4 51.03,77.4 51.16,77.27 51.16,77.05 51.29,76.92 51.55,76.92 51.68,77.05 51.68,77.27 51.81,77.4 51.87,77.4 52,77.53 52,77.96 51.87,78.09 51.32,78.09 51.19,78.21 51.19,78.47 51.32,78.6 51.87,78.6 52,78.73 52,78.99 51.87,79.12 51.32,79.12 51.19,79.25 51.19,79.51 51.32,79.64 51.87,79.64 52,79.77 52,79.89 51.77,80.12 51.34,80.12 51.24,80.22 51.24,81.06 51.51,81.33 52.61,81.33 52.89,81.61 54.51,81.61 54.64,81.49 54.64,81.23 54.46,81.06 53.47,81.06 53.36,80.94 53.36,80.66 v2(53.6,80.42)
  BOTTOM w0.124: UV1.C21 53.92,80.1 v2(53.6,80.42)
M_DQM4: length 38.9
  TOP w0.124: v2(40.17,94.54) 40.01,94.7 39.86,94.7 39.75,94.6 39.75,94.36 39.75,94.36 39.75,94.12 39.77,94.1 39.77,93.55 UV7.E7
  IN2 w0.13: v2(40.17,94.54) 40.17,94.77 40.3,94.89 41.11,94.89 41.24,95.02 41.24,95.53 41.37,95.66 41.63,95.66 41.76,95.53 41.76,95.18 41.88,95.05 42.15,95.05 42.27,95.18 42.27,95.53 42.4,95.66 42.66,95.66 42.79,95.53 42.79,95.02 42.92,94.89 43.1,94.89 43.23,95.02 43.23,96.17 43.35,96.3 43.58,96.3 43.71,96.17 43.71,95.41 43.84,95.28 44.1,95.28 44.22,95.41 44.22,96.17 44.35,96.3 44.57,96.3 44.7,96.17 44.7,95.23 44.82,95.1 45.08,95.1 45.21,95.23 45.21,95.71 45.34,95.84 45.55,95.84 45.9,95.48 45.9,95.1 45.5,94.7 45.5,87.81 45.62,87.69 45.66,87.69 45.79,87.56 45.79,86.98 45.92,86.85 46.18,86.85 46.31,86.98 46.31,87.56 46.44,87.69 49.56,87.69 49.87,87.38 50.37,87.38 50.91,86.85 50.91,86.83 51.22,86.83 52.03,86.02 52.03,85.26 52.43,84.86 52.43,84.36 52.68,84.11 54.62,84.11 54.81,84.31 54.81,85.04 54.77,85.09 54.77,85.57 54.67,85.67 54.07,85.67 54.01,85.74 54.01,86.13 54.07,86.19 v2(54.43,86.19)
  BOTTOM w0.124: v2(54.43,86.19) 54.43,86.19 54.73,86.5 UV1.E13
M_DQM5: length 45.4
  TOP w0.124: v2(50.4,91.63) 50.4,92.77 51.42,93.78 51.42,94.49 51.77,94.85 51.77,95.74 53.52,97.49 53.52,100.33 52.94,100.92 52.05,100.92 51.9,101.07 51.9,101.96 51.59,102.26 49.49,102.26 v1(49.33,102.11) 49.18,101.96 48.67,101.96 47.86,101.15 47.02,101.15 45.88,100 45.88,97.46 44.94,96.52 44.46,96.52 43.34,95.41 41.56,95.41 41.46,95.31 40.98,95.31 40.58,95.7 40.58,96.7 UV7.D3
  BOTTOM w0.102: UV1.D12 54.03,87.3 53.73,87.6 53.47,87.6 53.43,87.56 52.43,87.56 51.52,86.64 49.97,86.64
  BOTTOM w0.124: 49.97,86.64 46.97,86.64 46.84,86.77 46.84,89.95 47.34,90.44 47.94,90.44 49.13,91.63 v2(50.4,91.63)
M_DQM6: length 37.8
  IN1 w0.13: v2(54.43,94.1) 55.3,94.1 55.36,94.04 55.36,93.23 55.24,93.1 54.98,93.1 54.87,93.2 54.87,93.57 54.77,93.67 54.57,93.67 54.47,93.57 54.47,91.53 54.36,91.42 54.01,91.42 53.88,91.55 53.88,92.71 53.78,92.82 52.56,92.82 51.52,93.86 51.52,94.72 51.7,94.9 51.8,94.9 51.92,95.03 51.92,95.39 51.8,95.51 51.62,95.51 51.49,95.64 51.49,95.9 51.62,96.03 52.15,96.03 52.28,96.16 52.28,96.42 52.15,96.55 51.62,96.55 51.49,96.68 51.49,96.94 51.62,97.07 52.15,97.07 52.28,97.2 52.28,97.46 52.15,97.59 51.9,97.59 51.77,97.71 51.77,99.06 51.31,99.52 49.99,99.52 49.84,99.67 49.84,101.6 49.23,102.21 45.6,102.21 45.17,101.78 43.26,101.78 42.75,101.27 42.28,101.27 41.88,100.86 41.88,100.66 42.15,100.39 42.15,100.03 41.88,99.76 41.88,97.75 40.3,96.18 v2(40.19,96.18)
  BOTTOM w0.124: v2(40.19,96.18) 39.75,96.61 UV8.E7 ; UV1.E3 54.8,93.73 v2(54.43,94.1)
M_DQM7: length 44.1
  BOTTOM w0.102: UV1.F4 55.73,93.3 55.86,93.43 55.86,93.93 55.9,93.97 55.9,94.23 55.88,94.25 55.88,95.06 55.54,95.39
  BOTTOM w0.124: 55.54,95.39 55.34,95.6 54.22,95.6 53.72,96.1 53.45,96.1 53.12,95.76 52.92,95.76 52.58,96.1 52.41,96.1 52.24,95.92 52.24,95.75 52.54,95.44 52.54,95.26 52.37,95.09 52.19,95.09 51.88,95.39 51.71,95.39 51.53,95.22 51.53,95.04 51.84,94.74 51.84,94.56 51.66,94.38 51.49,94.38 51.18,94.69 51,94.69 50.83,94.51 50.83,94.34 50.99,94.17 50.99,93.89 49.54,92.43 48.75,92.43 47.76,91.44 v1(47.35,91.44) 47,91.44 46.01,90.45 46.01,85.93 45.88,85.81 45.68,85.81 45.55,85.93 45.55,86.04 45.43,86.16 45.18,86.16 45.06,86.04 45.06,85.93 44.93,85.81 44.68,85.81 44.56,85.93 44.56,86.04 44.43,86.16 44.19,86.16 44.06,86.04 44.06,85.93 43.94,85.81 43.72,85.81 43.59,85.93 43.59,87.85 43.47,87.97 43.44,87.97 43.31,88.1 43.31,88.35 43.44,88.47 43.47,88.47 43.59,88.6 43.59,89.07 43.47,89.19 42.24,89.19 42.12,89.32 42.12,89.56 42.24,89.69 43.47,89.69 43.59,89.81 43.59,90.06 43.47,90.19 42.24,90.19 42.12,90.31 42.12,90.56 42.24,90.68 42.52,90.68 42.65,90.81 42.65,90.84 42.77,90.96 43.02,90.96 43.15,90.84 43.15,90.81 43.27,90.68 43.47,90.68 44.05,91.27 44.05,91.75 44.51,92.21 44.51,92.46 44.2,92.77 43.62,92.77 43.19,92.33 42.8,92.33 42.55,92.59 42.55,92.88 42.28,93.15 41.19,93.15 40.95,93.39 40.95,93.91 40.85,94.01 40.7,94.01 40.6,93.91 40.6,93.58 UV8.D3
M_DQS0: length 48.3
  BOTTOM w0.102: 55.96,70.94 55.96,71.37 55.84,71.49 55.84,71.66 55.96,71.78 56.13,71.78 56.29,71.61 56.61,71.61 56.9,71.91 56.9,72.77 56.89,72.77 56.89,73.03 56.9,73.03 56.9,73.08 56.91,73.09 56.91,73.51 56.9,73.52 56.9,73.57 56.89,73.57 56.89,73.83 56.9,73.83 56.9,73.88 56.91,73.89 56.91,74.31 56.85,74.37 56.85,74.6 56.94,74.68 57.05,74.68 57.2,74.54 UV1.H28
  BOTTOM w0.124: 55.96,70.94 55.16,70.14 54.74,70.14 54.61,70.01 54.61,69.6 54.35,69.35 53.92,69.35 53.66,69.6 53.66,70.01 53.54,70.14 53.29,70.14 53.16,70.01 53.16,69.6 52.91,69.35 52.47,69.35 52.21,69.6 52.21,70.01 52.09,70.14 51.84,70.14 51.72,70.01 51.72,69.6 51.46,69.35 51.02,69.35 50.75,69.62 50.74,69.62 50.63,69.73 50.42,69.73 50.32,69.62 50.31,69.62 49.91,69.23 49.55,69.23 49.2,69.58 49.2,69.94 49.66,70.41 49.66,70.64 49.36,70.94 49.23,70.94 49.21,70.92 47.95,69.66 47.59,69.66 47.29,69.96 47.29,70.32 v3(47.87,70.9) 48.55,71.58 48.55,71.75 48.37,71.93 48.19,71.93 46.94,70.67 46.58,70.67 46.28,70.98 46.28,71.34 47.89,72.95 47.89,73.13 47.72,73.3 47.54,73.3 46.83,72.59 46.42,72.18 46.06,72.18 45.76,72.48 45.76,72.84 45.99,73.08 45.99,73.12 46.39,73.52 46.43,73.52 46.67,73.76 46.67,73.94 46.5,74.11 46.32,74.11 45.88,73.67 45.52,73.67 45.2,73.98 45.2,74.39 45.52,74.71 45.52,74.89 45.36,75.05 45.18,75.05 44.79,74.66 44.71,74.58 44.35,74.58 43.98,74.95 43.98,75.31 44.48,75.81 44.63,75.97 44.76,76.1 44.76,76.38 44.63,76.51 44.61,76.53 44.33,76.53 43.85,76.05 43.76,76.05 43.64,75.92 43.64,75.31 43.38,75.06 42.95,75.06 42.7,75.31 42.7,75.61 42.58,75.73 42.33,75.73 42.2,75.61 42.2,75.31 41.95,75.06 40.84,75.06 40.43,75.48 40.43,75.99 40.77,76.33 41.43,76.33 41.55,76.44 41.55,76.73 UV5.C7
M_DQS1: length 47.4
  TOP w0.102: 51.32,72.14 51.32,72.84 51.73,73.25 51.73,74.11 51.54,74.3 51.54,74.64 52.47,75.57 52.99,75.57 53.32,75.24 53.32,75.01 53.46,74.87 v2(53.61,74.87)
  TOP w0.124: 51.32,72.14 51.32,71.86 51.54,71.63 51.7,71.63 51.82,71.51 51.82,71.25 51.7,71.12 51.5,71.12 51.24,70.86 51.24,70.42 51.5,70.16 52.17,70.16 52.37,70.36 52.63,70.36 52.75,70.24 52.75,69.7 52.68,69.63 52.13,69.63 51.78,69.28 51.78,68.68 49.55,66.44 49.55,65.96 49.42,65.84 48.92,65.84 48.67,65.59 48.67,65.05 48.9,64.83 49.21,64.83 49.33,64.7 49.33,60.08 49.21,59.95 48.9,59.95 48.77,60.08 48.77,63.61 48.66,63.72 48.66,63.76 48.26,64.16 48.22,64.16 48.09,64.29 48.09,65.05 47.87,65.27 47.11,65.27 46.17,66.21 46.17,66.41 46.63,66.87 46.63,67.51 46.35,67.79 45.98,67.79 45.7,67.51 45.7,67.38 45.57,67.25 45.22,67.25 45.09,67.38 45.09,67.57 44.86,67.8 44.23,67.8 43.73,68.29 43.73,70.88 44.84,71.98 44.84,73.48 44.31,74 43.62,74 42.77,74.86 42.06,74.86 42.02,74.81 42,74.81 41.63,74.45 41.63,74.01 UV6.C7
  BOTTOM w0.124: UV1.C27 54,75.26 v2(53.61,74.87)
M_DQS2: length 42.8
  IN1 w0.102: v2(50.32,76.34) 50.41,76.34 50.53,76.23 50.53,75.98 50.46,75.91 50.09,75.91 49.99,75.81 49.97,75.81
  IN1 w0.13: 49.97,75.81 49.83,75.67 49.31,75.67 48.75,75.11 48.75,71.15 49.03,70.87 49.61,70.87 49.74,70.74 49.74,70.4 49.61,70.28 48.91,70.28 48.66,70.02 48.66,69.5 48.91,69.24 49.73,69.24 49.85,69.12 49.85,68.75 49.7,68.6 48.68,68.6 48.39,68.89 47.63,68.89 47.13,68.4 46.83,68.4 46.47,68.04 46.47,67.65 46.05,67.23 45.64,67.23 45.38,66.97 45.38,66.73 45.25,66.6 44.84,66.6 44.71,66.73 44.71,66.93 44.45,67.19 44.01,67.19 43.75,66.93 43.75,66.68 43.63,66.55 43.34,66.55 43.21,66.68 43.21,67.7 42.95,67.96 42.27,67.96 42.14,68.09 42.14,68.45 42.27,68.58 42.37,68.58 42.63,68.84 42.63,69.28 42.37,69.54 42.27,69.54 42.14,69.67 42.14,69.93 42.27,70.06 42.37,70.06 42.63,70.31 42.63,70.75 42.37,71.01 42.27,71.01 42.14,71.14 42.14,71.72 41.88,71.98 41.88,72.22 42.01,72.35 42.14,72.35 42.54,72.75 42.54,73.09 42.21,73.42 41.72,73.42 41.41,73.11 41.09,73.11 40.99,73.21 40.99,75.25 40.57,75.67 39.33,75.67 38.74,75.09 38.74,74.22 38.66,74.14 v2(38.56,74.14)
  BOTTOM w0.102: UV1.A23 53.27,78.57 53.52,78.57 53.6,78.49 53.6,78.39 53.4,78.19 52.14,78.19 51.86,77.91 51.54,77.91 50.53,76.89 50.53,76.43 50.44,76.34 v2(50.32,76.34)
  BOTTOM w0.124: v2(38.56,74.14) 38.46,74.04 38.46,73.84 38.61,73.69 38.92,73.69 UV5.F3
M_DQS3: length 41.4
  TOP w0.124: UV6.F3 39.02,76.92 v2(39.54,76.4)
  IN2 w0.102: 50.81,81.87 50.83,81.87 51.09,82.13 52.72,82.13 53.18,82.6 53.88,82.6 54.08,82.4 54.08,82.05 54.13,82 54.41,82 v2(54.42,82.01)
  IN2 w0.13: v2(39.54,76.4) 39.35,76.4 39.3,76.36 39.3,76.03 39.56,75.77 40.31,75.77 40.68,75.41 40.89,75.41 41.02,75.54 41.02,75.92 41.28,76.18 41.72,76.18 41.97,75.92 41.97,75.54 42.1,75.42 42.69,75.42 42.82,75.54 42.82,76.51 43.07,76.76 43.49,76.76 43.87,76.38 43.87,75.7 44.05,75.52 44.41,75.52 44.58,75.7 44.58,76.84 44.47,76.95 44.47,79.55 44.72,79.8 45.3,79.8 45.55,79.55 45.55,78.06 45.68,77.93 45.94,77.93 46.07,78.06 46.07,79.27 46.32,79.52 46.77,79.52 47.02,79.27 47.02,78.03 47.15,77.91 47.41,77.91 47.54,78.03 47.54,79.44 47.8,79.7 48.24,79.7 48.5,79.44 48.5,78.13 48.62,78.01 48.89,78.01 49.01,78.13 49.01,80.13 49.27,80.39 49.75,80.39 50.01,80.13 50.01,78.26 50.13,78.13 50.53,78.13 50.65,78.26 50.65,80.4 49.99,81.06 49.99,81.54 50.33,81.87 50.81,81.87
  BOTTOM w0.124: v2(54.42,82.01) 54.45,82.01 54.76,81.7 UV1.E19
M_DQS4: length 38.8
  TOP w0.124: UV7.F3 39.02,96.73 v2(39.54,96.21)
  IN2 w0.102: v2(54.41,84.59) 54.23,84.59 54.08,84.74 54.08,85.02 53.8,85.3 52.77,85.3 52.56,85.51 52.56,86.17 51.01,87.72 51.01,87.74 50.99,87.76
  IN2 w0.13: 50.99,87.76 50.17,88.57 49.66,88.57 49.53,88.7 49.53,89.08 49.27,89.34 48.83,89.34 48.58,89.08 48.58,88.7 48.45,88.57 48.19,88.57 48.06,88.7 48.06,89.08 47.8,89.34 47.36,89.34 47.1,89.08 47.1,88.7 46.97,88.57 46.63,88.57 46.39,88.82 46.39,89.8 46.52,89.93 47.7,89.93 47.95,90.19 47.95,90.63 47.7,90.89 46.52,90.89 46.39,91.02 46.39,91.27 46.52,91.4 47.65,91.4 47.9,91.66 47.9,92.1 47.65,92.36 46.52,92.36 46.39,92.49 46.39,92.75 46.52,92.88 47.59,92.88 47.85,93.13 47.85,93.58 47.59,93.83 46.52,93.83 46.39,93.96 46.39,94.28 46.83,94.73 46.83,95.88 45.54,97.17 41.47,97.17 41.21,96.91 41.21,96.28 40.34,95.41 39.42,95.41 39.25,95.57 39.25,95.93 v2(39.54,96.21)
  BOTTOM w0.124: v2(54.41,84.59) 54.72,84.9 UV1.E15
M_DQS5: length 45.6
  TOP w0.102: v2(50.72,90.44) 50.49,90.67 50.49,90.88 50.18,91.19 50.18,91.2 50.13,91.24 50.13,91.25 49.98,91.4 49.98,91.41 49.97,91.41
  TOP w0.124: UV7.C7 41.63,93.82 41.63,94.12 41.46,94.29 41.46,94.86 41.71,95.12 44.06,95.12 44.06,95.14 44.32,95.4 44.75,95.4 46.51,97.16 46.51,99.27 46.77,99.52 46.96,99.52 47.08,99.65 47.08,100.25 47.34,100.5 47.78,100.5 48.04,100.25 48.04,99.49 48.19,99.33 48.61,99.33 48.7,99.43 48.7,101.03 48.96,101.29 49.38,101.29 49.64,101.03 49.64,100.21 49.76,100.08 50.01,100.08 50.14,100.21 50.14,101.36 50.39,101.62 50.92,101.62 51.18,101.36 51.18,100.4 51.33,100.25 52.56,100.25 52.81,99.99 52.81,99.43 52.56,99.18 51.06,99.18 50.93,99.05 50.93,98.62 51.06,98.5 52.56,98.5 52.81,98.24 52.81,97.78 52.51,97.48 50.98,97.48 50.86,97.35 50.86,97.11 50.98,96.98 51.65,96.98 51.9,96.73 51.9,96.3 51.65,96.05 51.12,96.05 50.99,95.92 50.99,95.44 51,95.43 51,94.89 50.88,94.77 50.88,93.91 49.89,92.92 49.89,91.47 49.91,91.45 49.93,91.45 49.97,91.41
  BOTTOM w0.102: UV1.D10 54.12,89.18 53.75,89.18 53.73,89.2 53.47,89.2 53.45,89.18 52.96,89.18 52.7,89.44 51.71,89.44 51.16,89.99 51.16,90.75 51,90.91 50.66,90.91 50.5,90.75 50.5,90.66 v2(50.72,90.44)
M_DQS6: length 37.8
  IN1 w0.102: v2(51.38,92.82) 51.44,92.88 51.44,93.24 51.06,93.62 51.06,95.26 51.05,95.27
  IN1 w0.13: v2(39.37,93.99) 39.32,93.99 38.92,94.39 38.92,94.8 39,94.87 39,95.33 39.23,95.57 39.72,95.57 39.83,95.46 40.49,95.46 43.11,98.07 43.11,100.36 43.62,100.87 45.5,100.87 45.98,101.35 47.14,101.35 47.27,101.22 47.27,99.4 47.53,99.14 47.97,99.14 48.23,99.4 48.23,101.22 48.36,101.35 48.83,101.35 48.96,101.22 48.96,98.75 48.8,98.58 48.4,98.58 48.15,98.33 48.15,97.62 48.4,97.36 49.61,97.36 50.07,97.82 50.07,98.53 50.2,98.66 50.78,98.66 50.91,98.53 50.91,97.73 50.89,97.72 50.89,95.42 51.05,95.27
  BOTTOM w0.102: UV1.D6 54.09,92.41 53.43,92.41 53.41,92.39 52.99,92.39 52.97,92.41 52.82,92.41 52.7,92.29 52.69,92.29 52.56,92.16 51.81,92.16 51.54,92.43 51.54,92.65 v2(51.38,92.82)
  BOTTOM w0.124: UV8.F3 38.95,93.58 39.35,93.99 v2(39.37,93.99)
M_DQS7: length 45.1
  BOTTOM w0.102: UV1.G5 56.4,93.02 57.01,93.63 57.17,93.63 57.56,94.02 57.56,94.18 57.49,94.26 57.49,94.67 57.49,94.68 57.49,94.71 57.61,94.83 57.61,95.2 57.15,95.66 56.89,95.66 55.85,96.7 55.3,96.7 54.5,97.51 54.49,97.51 54.45,97.55 54.43,97.55 54.28,97.7 54.28,97.71 54.27,97.72
  BOTTOM w0.124: 54.27,97.72 54.24,97.75 54.24,97.76 54.12,97.88 53.83,98.18 53.2,98.18 52.92,98.46 52.92,98.88 53.2,99.16 53.93,99.16 54.08,99.31 54.08,99.52 53.93,99.67 53.28,99.67 53.03,99.93 53.03,101.05 52.9,101.17 52.53,101.17 52.4,101.05 v3(52.4,99.67) 52.4,98.54 52.14,98.29 51.72,98.29 51.46,98.54 51.46,101.02 51.34,101.15 51.09,101.15 50.97,101.02 50.97,98.55 50.71,98.3 50.28,98.3 50.03,98.55 50.03,100.94 49.9,101.07 49.66,101.07 49.53,100.94 49.53,100.57 49.56,100.54 49.56,99.98 49.53,99.95 49.53,98.52 49.28,98.26 48.85,98.26 48.6,98.52 48.6,100.31 48.47,100.44 48.19,100.44 48.06,100.31 48.06,99.14 47.78,98.86 47.46,98.86 47.3,98.7 46.94,98.7 46.75,98.89 46.57,98.89 46.4,98.71 46.4,98.54 46.59,98.35 46.59,97.99 46.28,97.69 45.92,97.69 45.82,97.69 45.57,97.44 45.57,96.98 45.27,96.67 44.86,96.67 44.56,96.37 44.56,96.32 44.56,95.96 44.13,95.53 43.55,95.53 43.3,95.79 43.09,95.79 42.83,95.53 42.11,95.53 41.51,96.14 41.51,96.57 UV8.C7
M_DQS#0: length 48.6
  BOTTOM w0.102: UV1.H27 57.26,75.24 57.26,74.99 57.16,74.88 56.85,74.88 56.65,74.68 56.65,74.28 56.7,74.23 56.7,73.97 56.7,73.97 56.7,73.92 56.69,73.91 56.69,73.49 56.7,73.48 56.7,73.43 56.7,73.43 56.7,73.17 56.7,73.17 56.7,73.12 56.69,73.11 56.69,72.69 56.7,72.68 56.7,72 56.52,71.82 56.38,71.82 56.21,71.98 55.87,71.98 55.64,71.75 55.64,71.41 55.76,71.29 55.76,71.06 55.75,71.04
  BOTTOM w0.124: 55.75,71.04 55.07,70.36 54.64,70.36 54.39,70.11 54.39,69.69 54.26,69.56 54.01,69.56 53.89,69.69 53.89,70.11 53.63,70.36 53.19,70.36 52.94,70.11 52.94,69.69 52.82,69.56 52.56,69.56 52.44,69.69 52.44,70.11 52.18,70.36 51.75,70.36 51.49,70.11 51.49,69.69 51.37,69.56 51.11,69.56 50.99,69.69 50.72,69.96 50.33,69.96 50.15,69.78 49.82,69.45 49.64,69.45 49.42,69.67 49.42,69.85 49.88,70.31 49.88,70.73 49.45,71.16 49.14,71.16 49.05,71.07 47.86,69.88 47.68,69.88 47.51,70.05 47.51,70.23 47.81,70.53 47.85,70.53 48.25,70.93 48.25,70.97 48.76,71.49 48.76,71.84 48.46,72.15 48.1,72.15 46.85,70.89 46.67,70.89 46.5,71.07 46.5,71.25 48.11,72.86 48.11,73.22 47.81,73.52 47.45,73.52 46.68,72.75 46.33,72.4 46.15,72.4 45.98,72.57 45.98,72.75 v3(46.37,73.15) 46.89,73.67 46.89,74.03 46.59,74.33 46.23,74.33 45.79,73.89 45.61,73.89 45.42,74.07 45.42,74.3 45.74,74.61 45.74,74.98 45.45,75.27 45.09,75.27 44.62,74.8 44.44,74.8 44.2,75.04 44.2,75.22 44.63,75.66 44.79,75.81 44.98,76.01 44.98,76.47 44.79,76.66 44.7,76.75 44.24,76.75 43.76,76.27 43.67,76.27 43.42,76.02 43.42,75.4 43.29,75.28 43.04,75.28 42.92,75.4 42.92,75.7 42.67,75.95 42.24,75.95 41.98,75.7 41.98,75.4 41.86,75.28 40.94,75.28 40.65,75.57 40.65,75.9 40.86,76.11 41.52,76.11 41.76,76.35 41.76,76.87 41.81,76.92 UV5.B7
M_DQS#1: length 47
  TOP w0.102: v2(52.72,74.94) 52.92,74.94 53.09,75.11 53.09,75.18 52.91,75.37 52.56,75.37 51.75,74.55 51.75,74.38 51.94,74.19 51.94,73.17 51.52,72.75 51.52,72.24 51.53,72.23 51.53,72.17 51.54,72.15 51.54,72.14
  TOP w0.124: 51.54,72.14 51.54,71.95 51.64,71.86 51.79,71.86 52.05,71.6 52.05,71.16 51.79,70.9 51.59,70.9 51.47,70.77 51.47,70.51 51.59,70.39 52.07,70.39 52.28,70.59 52.72,70.59 52.98,70.33 52.98,69.62 52.77,69.41 52.22,69.41 52,69.19 52,68.58 49.76,66.35 49.76,65.87 49.51,65.62 49.02,65.62 48.89,65.49 48.89,65.14 48.99,65.04 49.3,65.04 49.55,64.79 49.55,59.98 49.3,59.73 48.81,59.73 48.56,59.98 48.56,63.52 v3(48.29,63.78) 47.87,64.2 47.87,64.96 47.78,65.05 47.02,65.05 45.95,66.12 45.95,66.5 46.41,66.96 46.41,67.42 46.26,67.57 46.07,67.57 45.91,67.42 45.91,67.29 45.66,67.03 45.13,67.03 44.87,67.29 44.87,67.48 44.77,67.58 44.14,67.58 43.52,68.2 43.52,70.97 44.62,72.07 44.62,73.39 44.22,73.79 43.53,73.79 42.68,74.64 42.15,74.64 42.12,74.6 42.09,74.6 41.85,74.36 41.85,74.02 UV6.B7
  BOTTOM w0.124: UV1.A27 53.2,74.92 53.12,74.83 52.83,74.83 v2(52.72,74.94)
M_DQS#2: length 42.8
  IN1 w0.102: v2(50.9,76.34) 50.9,76.26 50.73,76.09 50.73,75.89 50.54,75.71 50.17,75.71 50.06,75.59
  IN1 w0.13: 50.06,75.59 49.92,75.45 49.4,75.45 48.97,75.02 48.97,71.24 49.12,71.09 49.7,71.09 49.96,70.83 49.96,70.31 49.7,70.06 49,70.06 48.88,69.93 48.88,69.59 49,69.46 49.82,69.46 50.07,69.21 50.07,68.66 49.79,68.38 48.59,68.38 48.3,68.67 47.72,68.67 47.22,68.18 46.92,68.18 46.69,67.94 46.69,67.56 46.14,67.01 45.73,67.01 45.6,66.88 45.6,66.64 45.34,66.38 44.74,66.38 44.49,66.64 44.49,66.84 44.36,66.97 44.1,66.97 43.97,66.84 43.97,66.59 43.72,66.33 43.25,66.33 42.99,66.59 42.99,67.61 42.86,67.74 42.18,67.74 41.93,68 41.93,68.54 42.18,68.8 42.28,68.8 42.41,68.93 42.41,69.19 42.28,69.32 42.18,69.32 41.93,69.58 41.93,70.02 42.18,70.27 42.28,70.27 42.41,70.4 42.41,70.66 42.28,70.79 42.18,70.79 41.93,71.05 41.93,71.63 41.67,71.89 41.67,72.31 41.92,72.57 42.05,72.57 42.32,72.84 42.32,73 42.12,73.2 41.81,73.2 41.5,72.89 40.99,72.89 40.77,73.12 40.77,75.16 40.48,75.46 39.42,75.46 38.96,75 38.96,74.13 38.97,74.12 38.97,73.7 v2(38.56,73.29)
  BOTTOM w0.102: v2(50.9,76.34) 50.73,76.51 50.73,76.81 51.63,77.7 51.95,77.7 52.23,77.98 53.48,77.98 53.8,78.3 UV1.C23
  BOTTOM w0.124: UV5.G3 38.15,73.7 v2(38.56,73.29)
M_DQS#3: length 41.2
  TOP w0.124: v2(38.76,76.41) 38.26,76.92 UV6.G3
  IN2 w0.102: v2(53.62,82.01) 53.64,82.01 53.88,82.25 53.88,82.31 53.8,82.39 53.27,82.39 52.8,81.93 51.17,81.93 50.88,81.64
  IN2 w0.13: 50.88,81.64 50.43,81.64 50.22,81.44 50.22,81.15 50.88,80.49 50.88,78.17 50.62,77.9 50.04,77.9 49.77,78.17 49.77,80.05 49.66,80.17 49.36,80.17 49.23,80.04 49.23,78.04 48.98,77.79 48.53,77.79 48.28,78.04 48.28,79.35 48.15,79.48 47.89,79.48 47.76,79.35 47.76,77.94 47.5,77.69 47.06,77.69 46.8,77.94 46.8,79.18 46.68,79.3 46.41,79.3 46.29,79.18 46.29,77.97 46.03,77.71 45.59,77.71 45.33,77.97 45.33,79.46 45.2,79.58 44.81,79.58 44.68,79.46 44.68,77.04 44.8,76.93 44.8,75.61 44.5,75.3 43.96,75.3 43.65,75.61 43.65,76.29 43.4,76.54 43.16,76.54 43.03,76.42 43.03,75.45 42.78,75.2 42.01,75.2 41.76,75.45 41.76,75.83 41.63,75.96 41.37,75.96 41.24,75.83 41.24,75.45 40.98,75.19 40.59,75.19 40.22,75.56 39.47,75.56 39.07,75.95 39.07,76.11 v2(38.76,76.41)
  BOTTOM w0.124: v2(53.62,82.01) 53.93,81.7 UV1.C19
M_DQS#4: length 38.9
  TOP w0.124: v2(38.94,96.2) 38.94,96.25 38.45,96.73 UV7.G3
  IN2 w0.102: v2(53.6,84.59) 53.63,84.59 53.88,84.84 53.88,84.93 53.72,85.1 52.68,85.1 52.36,85.42 52.36,86.08 50.85,87.59 50.85,87.59 50.83,87.59 50.83,87.6
  IN2 w0.13: 50.83,87.6 50.08,88.34 49.97,88.34 49.96,88.36 49.57,88.36 49.31,88.61 49.31,88.99 49.18,89.12 48.92,89.12 48.79,88.99 48.79,88.61 48.54,88.36 48.1,88.36 47.84,88.61 47.84,88.99 47.71,89.12 47.45,89.12 47.32,88.99 47.32,88.61 47.06,88.36 46.54,88.36 46.17,88.73 46.17,89.89 46.43,90.15 47.61,90.15 47.73,90.28 47.73,90.54 47.61,90.67 46.43,90.67 46.17,90.93 46.17,91.37 46.43,91.62 47.55,91.62 47.68,91.75 47.68,92.01 47.55,92.14 46.43,92.14 46.17,92.4 46.17,92.84 46.43,93.1 47.5,93.1 47.63,93.22 47.63,93.49 47.5,93.61 46.43,93.61 46.17,93.87 46.17,94.38 46.62,94.82 46.62,95.79 45.45,96.95 41.57,96.95 41.43,96.82 41.43,96.19 40.43,95.19 39.33,95.19 39.03,95.48 39.03,96.11 v2(38.94,96.2)
  BOTTOM w0.124: UV1.C15 53.91,84.9 v2(53.6,84.59)
M_DQS#5: length 45.5
  TOP w0.102: v2(50.13,90.44) 50.27,90.59 50.27,90.81 49.97,91.11
  TOP w0.124: UV7.B7 41.85,93.83 41.85,94.21 41.69,94.37 41.68,94.38 41.68,94.77 41.8,94.9 44.16,94.9 44.28,95.03 44.28,95.05 44.41,95.18 44.84,95.18 46.73,97.07 46.73,99.18 46.86,99.31 47.05,99.31 47.3,99.56 47.3,100.16 47.43,100.28 47.69,100.28 47.82,100.16 47.82,99.4 48.1,99.12 48.7,99.12 48.92,99.34 48.92,100.94 49.05,101.07 49.29,101.07 49.42,100.94 49.42,100.12 49.67,99.86 50.1,99.86 50.35,100.12 50.35,101.27 50.48,101.4 50.83,101.4 50.96,101.27 50.96,100.31 51.24,100.03 52.47,100.03 52.59,99.9 52.59,99.52 52.47,99.39 50.97,99.39 50.71,99.14 50.71,98.53 50.97,98.28 52.47,98.28 52.59,98.15 52.59,97.88 52.42,97.71 50.89,97.71 50.63,97.45 50.63,97.02 50.89,96.76 51.55,96.76 51.67,96.64 51.67,96.39 51.55,96.27 51.02,96.27 50.77,96.02 50.77,95.35 50.77,95.34 50.77,94.98 50.66,94.87 50.66,94 49.81,93.16 49.81,93.15 49.67,93.01 49.67,91.38 49.82,91.23 49.84,91.23 49.88,91.19 49.89,91.19 49.97,91.11
  BOTTOM w0.102: v2(50.13,90.44) 50.3,90.61 50.3,90.83 50.58,91.11 51.09,91.11 51.36,90.83 51.36,90.07 51.8,89.64 52.79,89.64 53.04,89.39 53.37,89.39 53.39,89.41 53.81,89.41 53.83,89.39 54.2,89.39 54.25,89.44 54.54,89.44 UV1.E9
M_DQS#6: length 37.7
  IN1 w0.102: 51.26,95.38 51.26,93.7 51.64,93.32 51.64,93.14 v2(51.96,92.82)
  IN1 w0.13: 51.26,95.38 51.13,95.52 51.13,98.62 50.87,98.88 50.11,98.88 49.85,98.62 49.85,97.91 49.52,97.58 48.49,97.58 48.37,97.71 48.37,98.24 48.49,98.36 48.89,98.36 49.18,98.66 49.18,101.31 48.92,101.57 48.27,101.57 48.01,101.31 48.01,99.49 47.88,99.36 47.62,99.36 47.49,99.49 47.49,101.31 47.23,101.57 45.89,101.57 45.41,101.09 43.53,101.09 42.89,100.45 42.89,98.16 40.4,95.68 39.92,95.68 39.81,95.79 39.14,95.79 38.78,95.42 38.78,94.96 38.65,94.84 38.65,94.09 v2(38.55,93.99)
  BOTTOM w0.102: UV1.C5 53.71,92.61 53.34,92.61 53.33,92.6 53.07,92.6 53.06,92.61 52.74,92.61 52.61,92.49 52.61,92.49 52.48,92.36 51.9,92.36 51.75,92.51 51.75,92.6 51.96,92.82 v2(51.96,92.82)
  BOTTOM w0.124: UV8.G3 38.15,93.59 v2(38.55,93.99)
M_DQS#7: length 45.1
  BOTTOM w0.102: UV1.H4 57.2,93.37 57.77,93.93 57.77,94.26 57.69,94.34 57.69,94.57 57.7,94.57 57.7,94.63 57.82,94.75 57.82,95.28 57.23,95.86 56.98,95.86 55.94,96.91 55.39,96.91 54.58,97.72
  BOTTOM w0.124: UV8.B7 42.15,96.93 42.09,96.98 41.84,96.98 41.74,96.88 41.74,96.22 42.21,95.75 42.74,95.75 43,96.01 43.39,96.01 43.64,95.75 44.04,95.75 44.34,96.05 44.34,96.32 44.34,96.46 44.77,96.89 45.18,96.89 45.35,97.07 45.35,97.53 45.47,97.64 45.73,97.9 45.93,97.9 46.19,97.9 46.37,98.08 46.37,98.26 46.18,98.45 46.18,98.8 46.48,99.11 46.84,99.11 47.03,98.92 47.21,98.92 47.37,99.08 47.69,99.08 47.84,99.23 47.84,100.4 48.1,100.65 48.56,100.65 48.82,100.4 48.82,98.61 48.94,98.48 49.19,98.48 49.32,98.61 v3(49.32,100.26) 49.32,101.03 49.57,101.29 50,101.29 50.25,101.03 50.25,98.65 50.37,98.52 50.62,98.52 50.75,98.65 50.75,101.11 51,101.37 51.43,101.37 51.68,101.11 51.68,98.63 51.81,98.51 52.05,98.51 52.18,98.63 52.18,99.34 52.15,99.37 52.15,99.98 52.18,100.01 52.18,101.14 52.43,101.39 52.99,101.39 53.24,101.14 53.24,100.02 53.37,99.89 54.02,99.89 54.3,99.61 54.3,99.22 54.02,98.94 53.3,98.94 53.14,98.78 53.14,98.55 53.3,98.39 53.92,98.39 54.46,97.85 54.46,97.84 54.5,97.8 54.5,97.8 54.58,97.72
M_MA0: length 79.7
  TOP w0.102: v2(32.26,75.86) 32.26,75.77 32.39,75.64 32.58,75.64 32.68,75.74 32.68,76.2 32.84,76.36 33.06,76.36 33.17,76.47 33.17,76.75 UV6.N3 ; UV7.N3 33.35,96.46 32.99,96.1 32.76,96.1 32.66,96 32.66,95.55 32.56,95.45 32.36,95.45 32.26,95.55 v2(32.26,95.67) ; 49.97,84.36 50.4,84.36 50.55,84.21 ; v2(58.2,82.49) 58.2,82.74 58.07,82.87 57.71,82.87 57.6,82.97 57.6,83.12 57.71,83.22 57.87,83.22 58.02,83.37 58.13,83.37 58.4,83.09 58.4,82.97 58.51,82.86 58.86,82.86 58.94,82.95 58.94,83.16 58.86,83.25 58.86,83.47 58.94,83.56 58.94,83.69 58.78,83.85 58.78,84.1 58.91,84.23 58.91,84.41 58.84,84.48 58.7,84.48 58.58,84.36 58.48,84.36 58.3,84.54 58.15,84.54 58.07,84.46 58.07,84.33 57.99,84.26 57.87,84.26 57.51,83.89 57.41,83.89 57.31,84 56.9,84 56.76,83.86 56.58,83.86 56.44,84 55.75,84 55.62,83.86 52.95,83.86 52.79,83.7 52.53,83.7 52.37,83.86
  TOP w0.124: 50.55,84.21 50.55,83.72 50.68,83.6 50.93,83.6 51.06,83.72 51.06,83.88 51.19,84 51.39,84 51.52,83.88 51.52,83.72 51.64,83.6 51.82,83.6 51.92,83.7 51.92,83.87 52.03,83.97 52.26,83.97 52.37,83.86
  TOP w0.198: v2(29.93,85.72) 30.31,85.72 30.49,85.55 30.49,85.37 31.02,84.84 31.48,84.84 31.81,85.17 32.29,85.17 32.4,85.06 32.4,84.59 32.55,84.43 33.04,84.43 33.19,84.59 33.19,85 33.39,85.2 33.79,85.2 33.98,85 33.98,84.61 34.14,84.46 34.62,84.46 34.78,84.61 34.78,85 34.97,85.2 35.19,85.2 35.31,85.07 35.72,85.07 35.85,85.2 36.76,85.2 37.47,85.91 37.83,85.91 38,86.08 38,86.44 38.16,86.59 39.05,86.59 39.4,86.95 39.63,86.95 39.78,86.8 39.78,86.69 39.93,86.54 40.39,86.54 40.54,86.69 40.54,86.8 40.7,86.95 45.03,86.95 47.62,84.36 49.97,84.36
  IN2 w0.107: v2(32.26,95.67) 32.06,95.87 32.06,96.58 32.19,96.7 32.52,96.7 32.65,96.58 32.65,94.72 30.31,92.38 30.31,90.67 30.56,90.42 30.56,87.89 30.44,87.76 30.44,86.47 30.05,86.08 30.05,85.85 v2(29.93,85.72) 29.8,85.85 29.8,86.17 29.74,86.24 29.62,86.24 29.5,86.11 29.5,85.4 29.62,85.27 29.72,85.27 29.75,85.3 29.95,85.3 30.05,85.2 30.05,84.99 29.95,84.89 29.95,84.76 30.49,84.23 30.49,84.1 30.59,84 30.59,83.77 30.49,83.67 30.49,83.37 30.59,83.27 30.59,80.14 30.41,79.96 30.41,79.81 30.59,79.63 30.59,79.46 30.41,79.28 30.41,79.05 30.59,78.87 30.59,78.62 30.71,78.49 30.86,78.49 30.97,78.38 30.97,78.22 30.86,78.11 30.8,78.11 30.68,77.98 30.68,77.83 30.78,77.73 31.1,77.73 31.17,77.65 31.17,77.22 31.5,76.89 31.63,76.89 31.77,76.75 31.77,76.62 31.88,76.51 32.01,76.51 32.39,76.13 32.39,75.99 v2(32.26,75.86)
  BOTTOM w0.102: UV8.N3 33.35,93.91 32.64,94.62 32.64,95.2 32.26,95.58 v2(32.26,95.67) ; UV5.N3 33.35,74.1 32.64,74.8 32.64,75.39 32.26,75.77 v2(32.26,75.86) ; UV1.K17 58.69,83.21 58.45,83.21 58.38,83.14 58.38,83.01 58.5,82.88 58.5,82.8 v2(58.2,82.49)
M_MA1: length 79.2
  TOP w0.102: 50.25,81.08 50.25,81.49 50.37,81.61 50.58,81.61 50.7,81.49 50.7,80.75 50.83,80.62 51.21,80.62 51.31,80.73 51.31,81.08 51.14,81.26 51.14,81.56 51.19,81.61 51.49,81.61 51.59,81.51 51.59,81.34 51.65,81.27 51.94,81.27 52.03,81.36 52.03,81.56 52.08,81.61 52.41,81.61 52.46,81.56 52.46,81.29 52.56,81.18 52.71,81.18 52.81,81.29 52.81,81.54 52.89,81.61 53.08,81.61 53.19,81.5 53.19,81.34 53.24,81.28 53.42,81.28 53.56,81.43 54.58,81.43 54.66,81.34 54.66,81.08 54.91,80.83 55.35,80.83 55.68,80.5 55.89,80.5 55.99,80.6 56.17,80.6 56.27,80.5 56.45,80.5 56.6,80.65 56.82,80.65 56.95,80.52 57.16,80.52 57.33,80.7 57.61,80.7 57.74,80.57 57.74,80.42 57.47,80.15 v2(57.4,80.15) ; UV7.P7 32.75,93.33 32.87,93.33 32.97,93.43 32.97,93.7 32.64,94.03 32.64,95.12 32.52,95.25 32.39,95.25 32.25,95.11 v2(32.25,94.96) ; v2(32.25,75.14) 32.25,75.29 32.39,75.44 32.52,75.44 32.64,75.31 32.64,74.22 32.97,73.89 32.97,73.62 32.87,73.52 32.75,73.52 UV6.P7
  TOP w0.198: v2(29.61,84.53) 29.61,84.48 30.14,83.95 30.14,83.92 30.24,83.81 30.32,83.81 31.22,82.91 35.57,82.91 35.9,83.24 36.12,83.24 36.46,82.91 v1(37.9,82.91) 41.43,82.91 41.79,83.27 42.17,83.27 42.53,82.91 42.98,82.91 43.34,83.27 43.85,83.27 46.16,80.95 50.12,80.95 50.25,81.08
  IN2 w0.107: v2(32.25,75.14) 32.37,75.03 32.37,73.23 32.24,73.11 31.98,73.11 31.86,73.23 31.86,76.23 30.41,77.68 30.41,78.49 30.18,78.72 30.18,82.97 30.08,83.08 30.08,84.06 v2(29.61,84.53) 29.17,84.53 29.09,84.61 29.09,84.79 29.24,84.94 29.24,85.07 29.09,85.22 29.09,86.52 29.22,86.64 29.9,86.64 30.03,86.77 30.03,86.93 29.9,87.05 29.39,87.05 29.24,87.21 29.24,87.41 29.37,87.53 29.86,87.53 29.99,87.66 29.99,88.16 30.16,88.32 30.16,90.33 29.93,90.56 29.93,90.76 30.05,90.89 30.05,91.19 29.93,91.32 29.93,91.61 30.08,91.76 30.08,92.04 29.93,92.19 29.93,92.43 30.19,92.7 30.3,92.7 30.66,93.07 30.66,93.17 30.98,93.49 31.11,93.49 31.35,93.73 31.35,93.86 31.55,94.06 31.68,94.06 31.9,94.28 31.9,94.4 32.05,94.56 32.18,94.56 32.37,94.75 32.37,94.84 v2(32.25,94.96)
  BOTTOM w0.102: v2(32.25,94.96) 32.25,95.12 31.85,95.52 31.85,95.83 32.14,96.12 32.53,96.12 32.95,96.54 32.95,96.69 32.83,96.81 32.62,96.81 UV8.P7 ; v2(57.4,80.15) 57.5,80.15 57.64,80.29 57.64,80.42 57.56,80.5 57.56,80.8 57.69,80.93 57.94,80.93 58,80.87 UV1.J20 ; v2(32.25,75.14) 32.25,75.31 31.85,75.7 31.85,76.02 32.09,76.26 32.48,76.26 32.95,76.73 32.95,76.85 32.82,76.97 32.6,76.97 UV5.P7
M_MA2: length 73.1
  TOP w0.102: UV7.P3 32.55,96.89 32.6,96.95 32.88,96.95 32.97,96.86 32.97,96.59 32.68,96.3 32.47,96.3 32.43,96.25 32.43,96.1 32.37,96.05 32.06,96.05 31.86,95.85 31.86,95.37 31.8,95.32 31.58,95.32 31.46,95.43 v2(31.46,95.59) ; v2(31.46,75.78) 31.46,75.62 31.58,75.5 31.8,75.5 31.86,75.55 31.86,76.03 32.06,76.24 32.37,76.24 32.43,76.29 32.43,76.44 32.47,76.49 32.68,76.49 32.97,76.78 32.97,77.05 32.88,77.14 32.6,77.14 32.55,77.08 UV6.P3
  IN1 w0.198: v2(57.6,78.9) 57.6,79.51 57.45,79.66 54.23,79.66 54,79.89 53.47,79.89 53,80.37 51.47,80.37
  IN1 w0.203: v2(28.75,83.79) 28.89,83.65 28.89,82.96 29.52,82.33 31.53,82.33 32.16,81.69 33.43,81.69 33.53,81.59 35.68,81.59 35.89,81.37 44.14,81.37 44.56,80.95 50.88,80.95 51.47,80.37
  IN2 w0.107: v2(31.46,95.59) 31.86,95.19 31.86,94.7 29.7,92.54 29.7,88.42 28.69,87.41 28.69,83.84 v2(28.75,83.79) 28.94,83.79 29.06,83.91 29.06,84 29.19,84.13 29.44,84.13 29.67,83.9 29.67,83.47 29.55,83.34 28.71,83.34 28.58,83.21 28.58,82.99 28.71,82.86 29.17,82.86 29.29,82.73 29.29,82.07 29.42,81.94 29.65,81.94 29.77,81.82 29.77,81.59 29.65,81.47 29.42,81.47 29.32,81.36 29.32,81.15 29.42,81.04 29.64,81.04 29.77,80.91 29.77,80.19 29.93,80.04 29.93,79.82 29.82,79.71 29.7,79.71 29.6,79.61 29.6,79.39 29.7,79.29 29.82,79.29 29.93,79.18 29.93,78.64 30.18,78.39 30.18,77.6 31.63,76.15 31.63,75.95 v2(31.46,75.78)
  BOTTOM w0.102: UV5.P3 32.73,73.54 32.87,73.54 32.97,73.65 32.97,74.1 32.92,74.16 32.21,74.16 32.15,74.22 32.15,74.61 31.84,74.92 31.84,75.4 v2(31.46,75.78) ; UV8.P3 32.73,93.36 32.87,93.36 32.97,93.46 32.97,93.91 32.92,93.97 32.21,93.97 32.15,94.03 32.15,94.42 31.84,94.74 31.84,95.21 v2(31.46,95.59) ; v2(57.6,78.9) UV1.H23
M_MA3: length 82.9
  TOP w0.102: UV7.N2 33.35,97.85 33.22,97.98 33.11,97.98 33.05,98.04 32.93,98.04 32.84,97.95 32.84,97.83 32.95,97.73 32.95,97.31 32.79,97.15 32.22,97.15 32.12,97.05 32.12,96.4 31.75,96.02 30.76,96.02 30.66,95.92 v2(30.66,95.67) ; 49.97,78.77 50.96,78.77 51.09,78.9 54.76,78.9 55.14,78.52 v1(55.59,78.52) 55.62,78.49 56.27,78.49 56.39,78.36 56.39,77.79 56.28,77.68 56.06,77.68 55.94,77.8 55.94,78.04 v2(56,78.1) ; v2(30.66,75.86) 30.61,75.81 30.61,75.7 30.69,75.62 30.97,75.62 31.06,75.7 31.06,75.94 31.2,76.08 31.2,76.15 31.15,76.2 31.15,76.28 31.32,76.46 31.43,76.46 31.65,76.23 31.76,76.23 31.99,76.46 32.12,76.46 32.21,76.55 32.21,76.74 32.12,76.83 32.12,77.24 32.23,77.35 32.71,77.35 32.87,77.51 32.95,77.51 33.13,77.32 33.23,77.32 33.38,77.47 33.38,77.69 UV6.N2
  TOP w0.198: 49.97,78.77 45.21,78.77 44.88,79.1 44.79,79.1 44.08,79.81 43.44,79.81 42.83,80.42 34.47,80.42 34.37,80.52 33.31,80.52 33.2,80.42 32.14,80.42 31.93,80.62 30.51,80.62 30.08,81.06 30.08,81.36 30.28,81.56 30.28,81.94 30.14,82.08 29.89,82.08 29.58,81.78 29.36,81.78 29.14,82 29.14,82.17 29.34,82.38 29.34,82.55 29.14,82.76 29.14,83.14 28.96,83.32 28.57,83.32 28.34,83.54 27.87,83.54 27.74,83.67 v2(27.74,83.91)
  IN2 w0.107: v2(30.66,75.86) 30.54,75.98 30.54,76.1 30.74,76.31 30.74,76.43 30.58,76.6 30.43,76.6 30.27,76.44 30.12,76.44 30,76.56 30,76.69 30.16,76.84 30.16,77.02 29.97,77.2 29.81,77.2 29.71,77.3 29.71,77.52 29.6,77.62 29.37,77.62 29.22,77.78 29.22,77.96 29.31,78.05 29.6,78.05 29.71,78.16 29.71,78.25 29.55,78.41 29.39,78.41 29.29,78.52 29.29,78.74 29.01,79.02 29.01,79.15 29.14,79.28 29.14,79.53 28.84,79.84 28.56,79.84 28.5,79.89 28.5,80.17 28.33,80.34 28.25,80.34 28.06,80.15 27.82,80.15 27.69,80.28 27.69,80.47 27.82,80.6 27.99,80.6 28.1,80.7 28.1,80.85 27.99,80.95 27.82,80.95 27.69,81.08 27.69,81.28 27.82,81.41 28.11,81.41 28.23,81.52 28.23,81.68 28.11,81.79 27.87,81.79 27.69,81.97 27.69,83.47 27.9,83.67 27.9,83.85 27.84,83.91 v2(27.74,83.91) 27.74,87.61 28.89,88.75 28.89,90.53 29.22,90.86 29.22,92.74 31.04,94.57 31.04,95.28 v2(30.66,95.67)
  BOTTOM w0.102: UV1.G23 56.4,78.13 56.27,78.01 56.09,78.01 v2(56,78.1) ; v2(30.66,75.86) 30.66,75.7 31.04,75.32 31.04,74.98 31.31,74.71 31.69,74.71 31.95,74.45 31.95,74.09 32.12,73.92 32.12,73.59 32.38,73.33 33.5,73.33 33.63,73.2 33.63,73.05 33.51,72.92 UV5.N2 ; v2(30.66,95.67) 30.66,95.52 31.04,95.13 31.04,94.79 31.31,94.52 31.69,94.52 31.95,94.26 31.95,93.9 32.12,93.73 32.12,93.41 32.38,93.15 33.5,93.15 33.63,93.01 33.63,92.86 33.51,92.73 UV8.N2
M_MA4: length 80.8
  TOP w0.102: v2(31.45,94.96) 31.31,94.82 31.31,94.58 31.52,94.37 31.67,94.37 31.86,94.55 32.25,94.55 32.33,94.47 32.33,94.19 32.21,94.08 32.03,94.08 31.96,94.01 31.96,93.86 32.13,93.69 32.13,93.19 32.2,93.13 32.73,93.13 32.83,93.03 32.83,92.86 32.71,92.73 UV7.P8 ; v2(31.45,75.14) 31.31,75.01 31.31,74.77 31.52,74.56 31.67,74.56 31.86,74.74 32.25,74.74 32.33,74.66 32.33,74.38 32.21,74.27 32.03,74.27 31.96,74.2 31.96,74.05 32.13,73.87 32.13,73.38 32.2,73.32 32.73,73.32 32.83,73.21 32.83,73.05 32.71,72.92 UV6.P8 ; v2(56,77.3) 56,77.36 54.69,78.67 51.16,78.67 50.96,78.46 50.27,78.46 49.97,78.16
  TOP w0.198: 49.97,78.16 v1(46.21,78.16) 44.97,78.16 44.11,79.02 43.74,79.02 42.78,79.99 34.35,79.99 34.12,80.22 33.43,80.22 33.2,79.99 31.68,79.99 31.55,80.12 30.66,80.12 30.51,79.96 29.19,79.96 28.89,80.27 28.89,80.75 29.04,80.9 29.04,81.23 28.17,82.1 26.55,82.1 26.42,82.22 26.42,82.63 26.73,82.94 28.1,82.94 v2(28.15,82.88)
  IN2 w0.107: v2(31.45,94.96) 31.45,94.62 29.44,92.61 29.44,90.73 29.29,90.58 29.29,88.57 28.3,87.58 28.3,83.52 28.15,83.37 v2(28.15,82.88) 28.15,82.32 28.86,81.6 28.86,81.41 28.91,81.36 28.91,80.83 28.78,80.7 28.78,80.45 29.37,79.86 29.37,79.18 29.65,78.9 29.65,78.61 29.95,78.31 29.95,77.53 31.04,76.43 31.04,75.7 31.04,75.69 31.04,74.81 30.91,74.68 30.16,74.68 30.03,74.55 30.03,74.14 30.16,74.01 31.32,74.01 31.45,74.14 v2(31.45,75.14)
  BOTTOM w0.102: v2(31.45,75.14) 31.45,75.23 31.07,75.61 31.07,75.92 31.31,76.17 31.7,76.17 32.15,76.62 32.15,77.97 32.26,78.09 32.43,78.09 32.55,77.97 UV5.P8 ; v2(31.45,94.96) 31.45,95.05 31.07,95.43 31.07,95.74 31.31,95.99 31.7,95.99 32.15,96.43 32.15,97.79 32.26,97.9 32.45,97.9 32.55,97.81 UV8.P8 ; UV1.G24 v2(56,77.3)
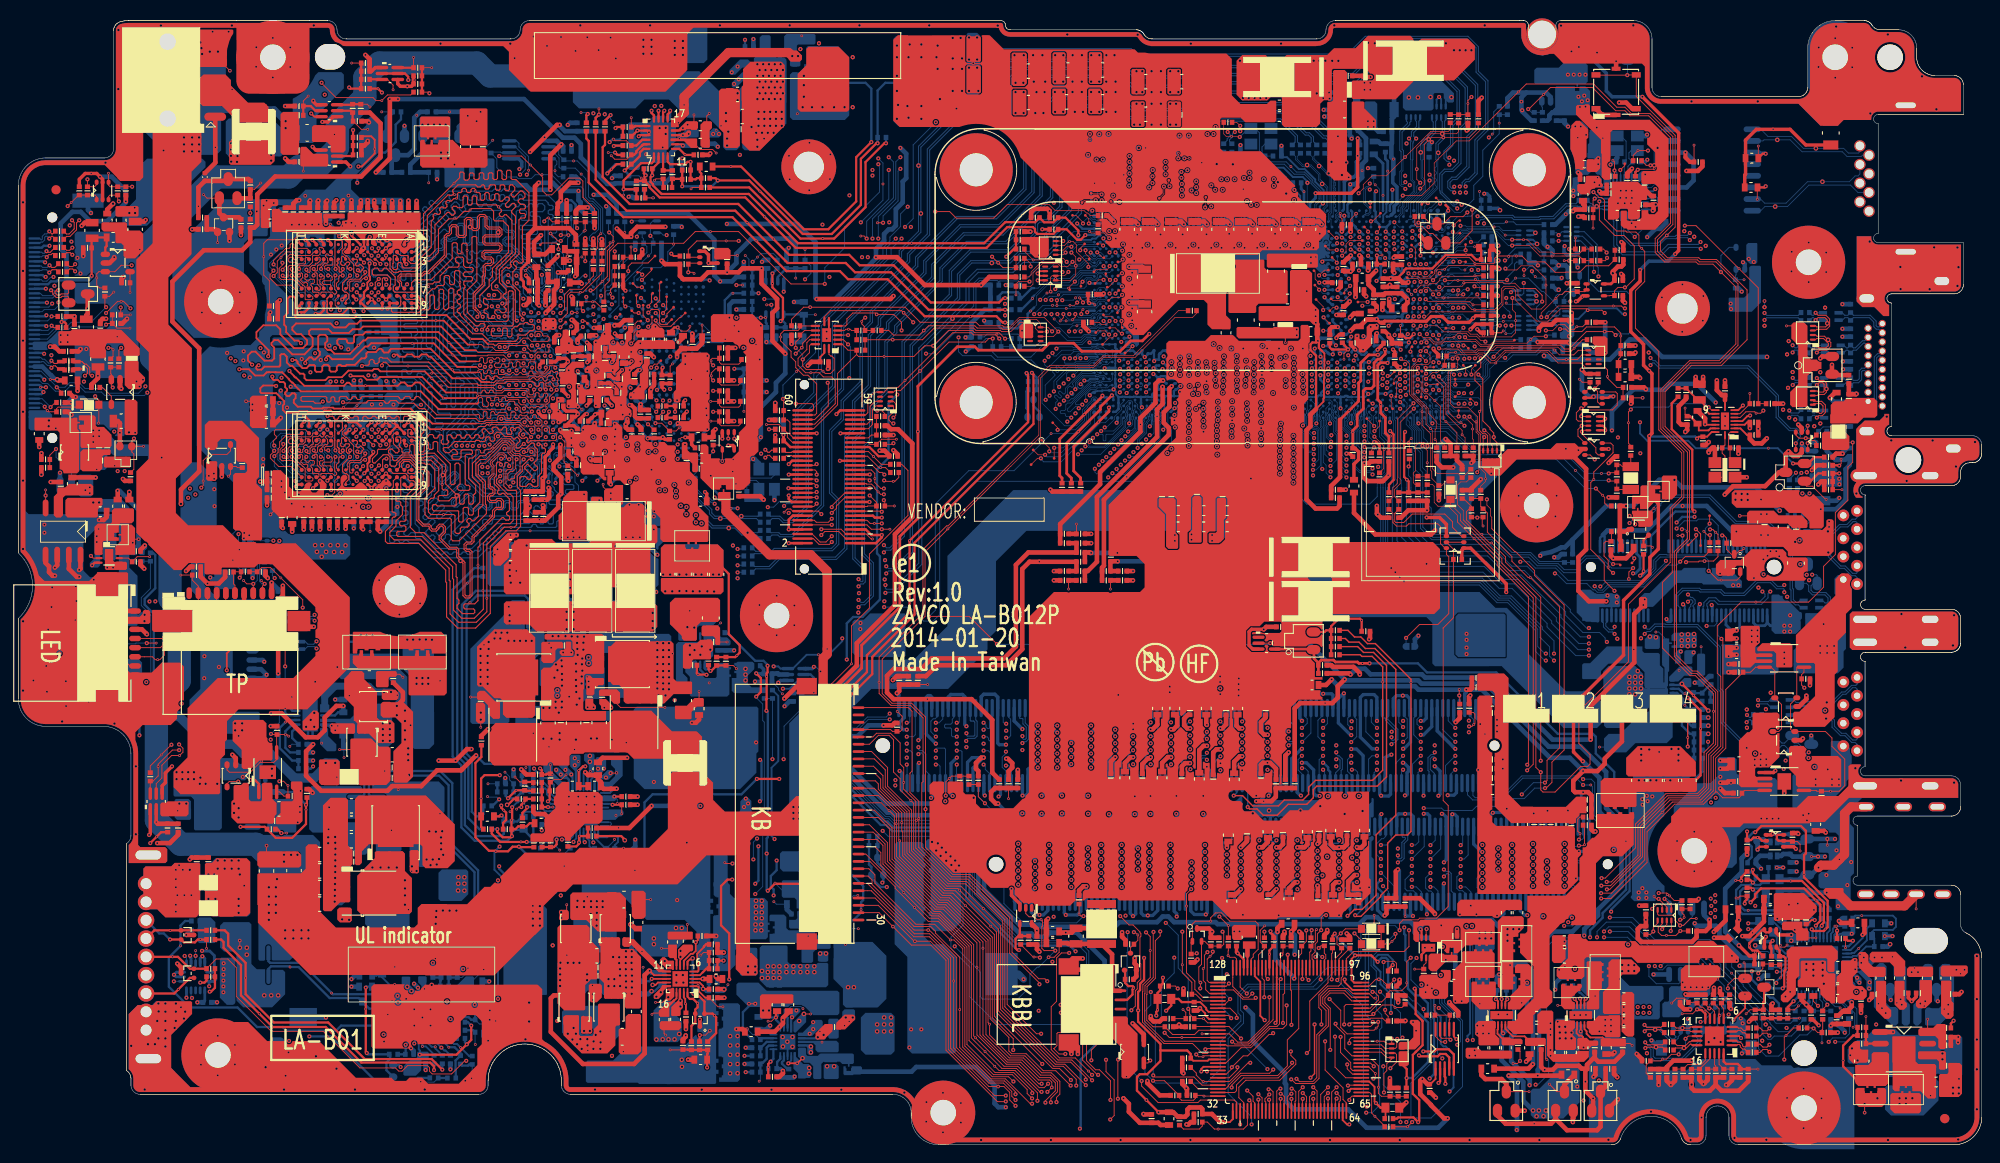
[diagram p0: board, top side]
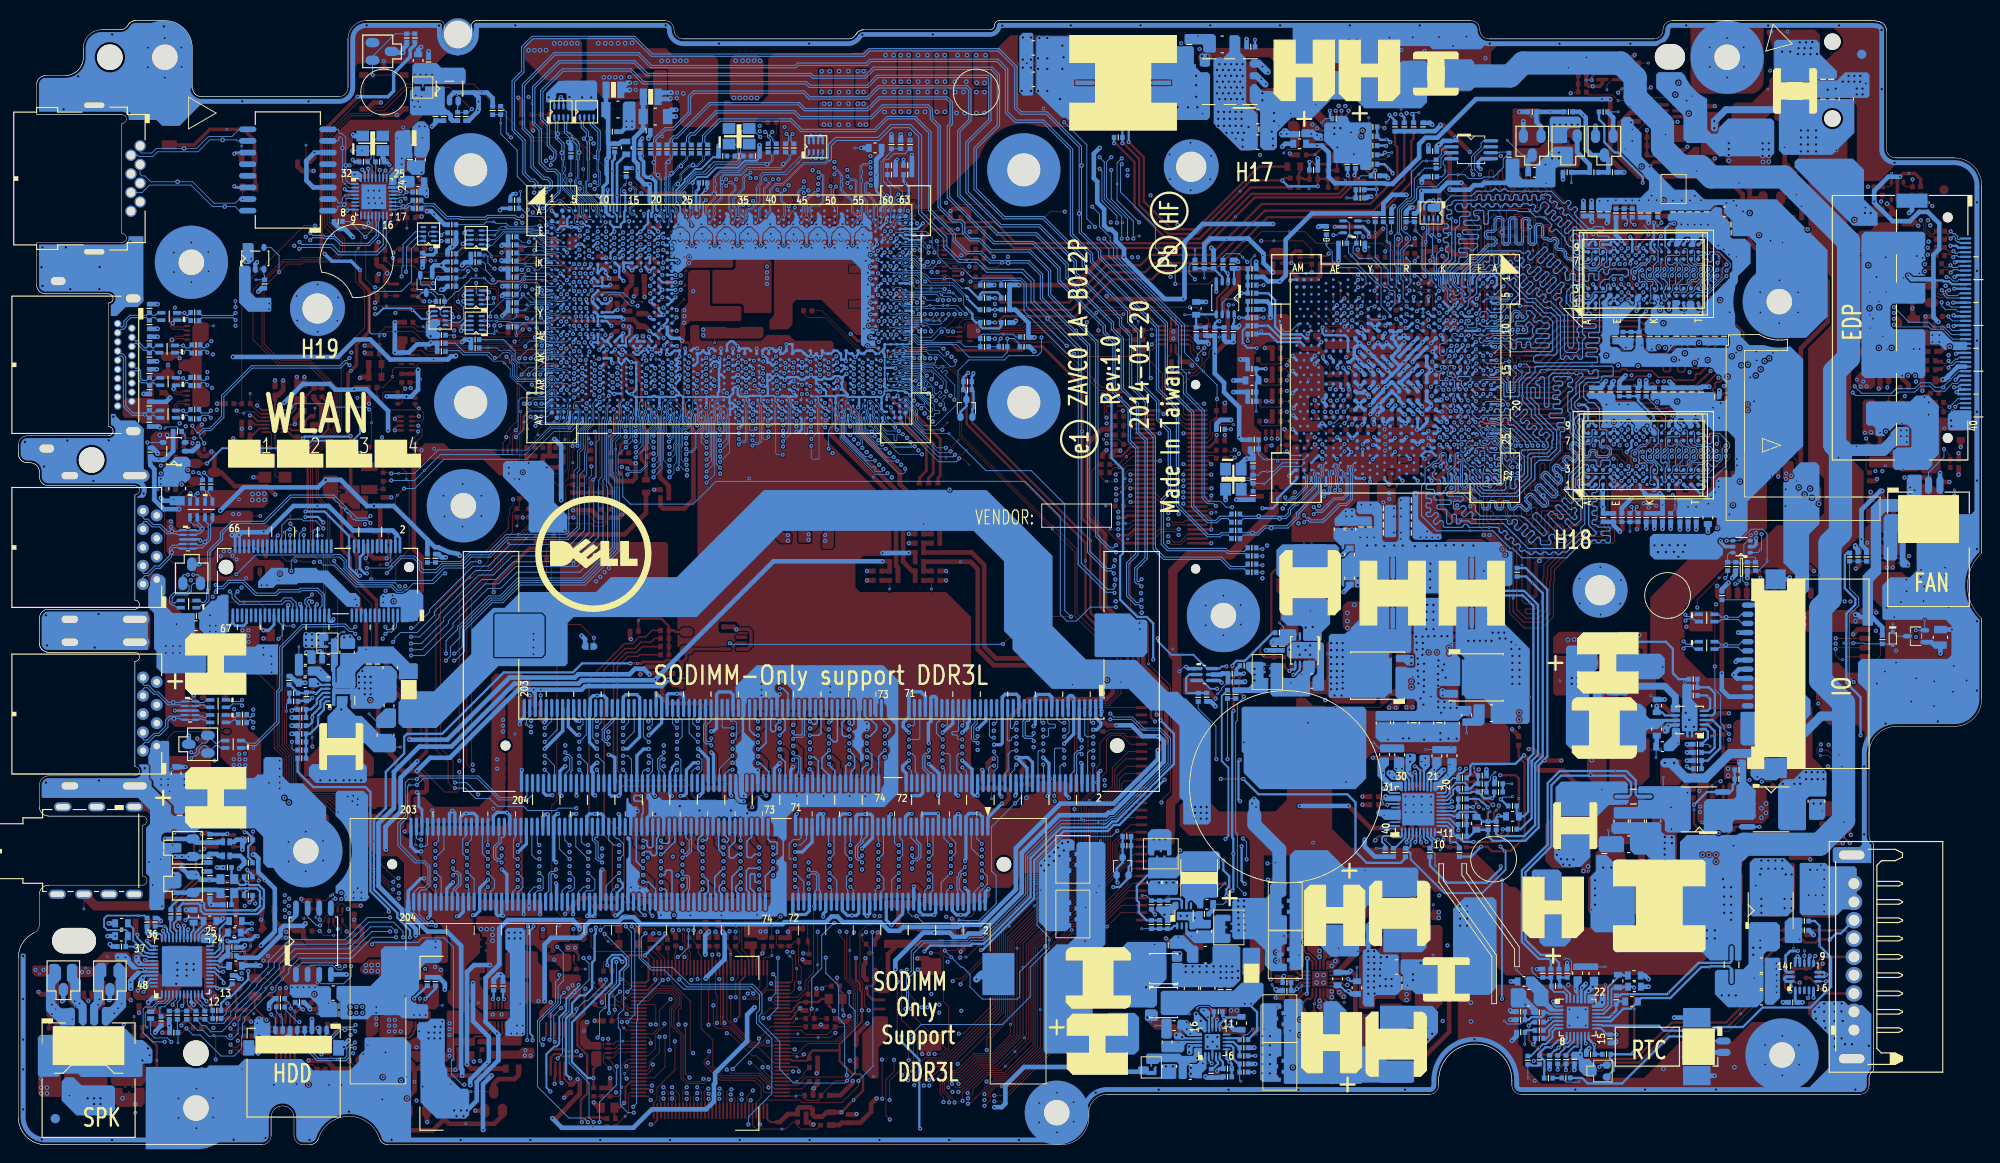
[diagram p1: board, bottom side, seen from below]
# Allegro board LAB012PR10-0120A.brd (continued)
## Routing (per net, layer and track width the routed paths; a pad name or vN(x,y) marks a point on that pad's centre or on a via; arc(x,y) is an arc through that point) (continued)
M_MA5: length 82.7
  TOP w0.102: v2(28.96,75.78) 28.96,75.95 29.32,76.3 29.32,77.21 29.43,77.33 31.92,77.33 32.14,77.55 32.14,77.68 32.21,77.75 32.52,77.75 UV6.P2 ; v2(28.87,95.58) 28.87,95.67 29.32,96.12 29.32,96.91 29.64,97.24 30.05,97.24 30.15,97.14 31.92,97.14 32.31,97.53 UV7.P2
  IN1 w0.102: 53.42,79.45 53.88,79.15 54.57,78.8 55.23,78.52 56.09,78.49 56.62,78.19 56.72,78.13 v2(56.8,78.11)
  IN1 w0.198: 53.42,79.45 52.8,80.07 51.29,80.07 51.01,80.34 49.97,80.34
  IN1 w0.203: 49.97,80.34 35.29,80.34 34.91,80.73 31.83,80.73 30.84,81.72 26.98,81.72 26.45,82.07 26.19,82.27 25.91,82.48 24.67,83.67 v2(24.67,84.03)
  IN2 w0.107: v2(28.96,75.78) 28.91,75.73 28.68,75.73 28.55,75.87 28.55,75.98 28.69,76.13 28.69,76.24 28.55,76.38 28.55,76.74 28.17,77.12 28.05,77.12 24.69,80.47 24.69,81.98 24.8,82.08 25.38,82.08 25.51,82.21 25.51,82.38 25.38,82.51 24.74,82.51 24.62,82.63 24.62,82.81 24.74,82.94 25.41,82.94 25.53,83.06 25.53,83.24 25.41,83.36 24.69,83.36 24.57,83.49 24.57,83.93 v2(24.67,84.03) 24.67,84.89 25.08,85.3 25.08,87.94 26.68,89.54 26.68,92.31 27.64,93.27 27.84,93.27 29.26,94.68 29.26,95.19 v2(28.87,95.58)
  BOTTOM w0.102: v2(56.8,78.11) 57.2,77.71 UV1.H24 ; v2(28.96,75.78) 28.96,75.7 29.37,75.3 29.37,75.06 29.71,74.72 30.05,74.72 30.46,74.31 30.91,74.31 31.33,73.88 31.33,73.6 31.61,73.33 32.09,73.33 32.5,72.92 UV5.P2 ; UV8.P2 32.32,92.73 31.91,93.14 31.61,93.14 31.33,93.42 31.33,93.69 30.66,94.37 30.22,94.37 30.01,94.58 29.67,94.58 29.44,94.8 29.44,95 v2(28.87,95.58)
M_MA6: length 84.3
  TOP w0.102: UV6.R8 32.03,72.92 32.16,72.79 32.16,72.62 32.05,72.5 31.39,72.5 31.32,72.57 31.32,73.88 31.1,74.1 31.07,74.1 30.78,74.38 30.75,74.38 29.99,75.14 v2(29.85,75.14) ; UV7.R8 32.03,92.73 32.16,92.61 32.16,92.43 32.05,92.31 31.39,92.31 31.32,92.38 31.32,93.69 31.1,93.91 31.06,93.91 31.04,93.93 31.03,93.93 30.65,94.32 30.65,94.32 30.01,94.96 v2(29.85,94.96) ; 49.97,82.17 50.02,82.12 50.54,82.12 50.64,82.22 50.64,82.33 50.74,82.43 50.94,82.43 51.04,82.33 51.04,82.22 51.14,82.12 51.35,82.12 51.45,82.22 51.45,82.33 51.55,82.43 51.75,82.43 51.86,82.33 51.86,82.22 51.96,82.12 52.81,82.12 53.09,82.4 55.43,82.4 55.56,82.27 55.56,81.81 55.68,81.68 56.35,81.68 56.46,81.78 56.46,82.05 56.56,82.15 56.76,82.15 56.86,82.05 56.86,81.78 56.96,81.68 57.21,81.68 57.33,81.81 57.33,81.97 57.46,82.1 57.69,82.1 57.82,81.97 57.82,81.82 57.6,81.6 v2(57.6,81.3)
  TOP w0.198: v2(26.24,85.15) 26.12,85.15 25.99,85.02 25.99,84.79 26.12,84.66 26.55,84.66 26.88,85 28.48,85 28.61,85.12 28.61,86.24 28.73,86.36 29.04,86.36 29.32,86.08 29.32,85.45 29.67,85.09 29.9,85.09 30.21,84.78 30.76,84.23 31.12,84.23 31.25,84.1 31.25,83.74 31.47,83.52 33.53,83.52 33.86,83.85 35.34,83.85 36.05,84.56 38.66,84.56 38.84,84.74 39.27,84.74 39.53,84.48 44.38,84.48 v1(45.16,83.7) 46.69,82.17 49.97,82.17
  IN2 w0.107: v2(29.85,75.14) 29.34,75.65 29.34,75.94 29.32,75.96 29.32,76.72 28.97,77.07 28.2,77.84 28.2,78.11 26.4,79.91 26.4,84.99 v2(26.24,85.15) 26.24,85.3 25.96,85.58 25.96,87.61 27.54,89.18 27.54,90.28 27.95,90.68 27.95,92.71 29.85,94.62 v2(29.85,94.96)
  BOTTOM w0.102: v2(57.6,81.3) 57.71,81.42 57.71,81.61 57.56,81.77 57.56,81.94 57.71,82.09 57.85,82.09 58,81.94 UV1.J19 ; v2(29.85,94.96) 29.85,95.11 29.39,95.56 29.39,95.83 29.62,96.06 30.13,96.06 30.35,96.28 31.03,96.28 31.37,96.62 31.37,97.61 31.48,97.72 31.64,97.72 31.75,97.61 UV8.R8 ; UV5.R8 31.75,77.82 31.64,77.93 31.48,77.93 31.37,77.82 31.37,76.81 31.03,76.47 30.35,76.47 30.13,76.25 29.62,76.25 29.39,76.02 29.39,75.75 29.85,75.3 v2(29.85,75.14)
M_MA7: length 85.9
  TOP w0.102: v2(27.87,96.16) 27.87,96.58 29.21,97.92 29.58,97.92 29.68,98.02 29.68,98.33 29.78,98.43 29.99,98.43 30.09,98.33 30.09,98.02 30.19,97.92 31.53,97.92 31.75,97.7 UV7.R2 ; UV6.R2 31.35,78.12 28.09,78.12 27.96,77.99 27.96,77.6 28.17,77.38 28.17,77.2 27.84,76.87 27.84,76.49 v2(27.95,76.38)
  IN1 w0.102: 49.97,82.96 51.47,82.61 52.41,82.4 55.43,82.43 56.27,82.1 57.87,81.69 v2(58.38,81.52)
  IN1 w0.203: v2(23.7,85.6) 23.83,85.53 24.44,85.15 24.56,85.12 25.4,84.77 26.05,84.69 26.42,84.64 26.52,84.64 28.84,84.41 28.94,84.38 29.1,84.29 29.5,84.05 29.62,84.01 30.11,84.03 30.77,83.9 31.65,83.8 32.06,83.77 35.61,83.93 35.94,83.6 35.94,83.54 36.52,82.96 37.28,82.96 37.29,82.95 39.44,82.95 39.45,82.96 49.97,82.96
  IN2 w0.107: v2(27.87,96.16) 28.2,95.71 28.25,95.65 28.48,95.17 28.48,94.57 27.95,94.04 27.34,93.93 27.1,93.9 25.86,92.66 25.86,89.89 23.7,87.74 v2(23.7,85.6) 23.66,85.56 23.66,79.88 23.84,79.7 24.28,79.7 24.39,79.59 24.39,79.25 24.34,79.2 24.34,79.05 24.49,78.9 24.64,78.9 24.79,79.05 24.95,79.05 25.1,78.9 25.1,78.75 24.94,78.6 24.94,78.45 25.09,78.29 25.24,78.29 25.31,78.36 25.64,78.36 26.02,77.98 26.02,77.3 27.08,76.24 27.81,76.24 v2(27.95,76.38)
  BOTTOM w0.102: v2(27.95,76.38) 27.95,76.38 28.34,75.99 28.34,74.82 29.86,73.3 31.16,73.3 31.58,73.03 UV5.R2 ; v2(27.87,96.16) 28.35,95.69 28.35,94.73 29.97,93.11 31.2,93.11 31.57,92.73 UV8.R2 ; v2(27.87,96.16) 27.87,96.16 v2(27.87,96.16) ; v2(58.38,81.52) 58.76,81.9 UV1.K19
M_MA8: length 83
  TOP w0.102: UV7.T8 29.78,93.9 28.24,93.9 27.5,94.64 27.5,95.08 27.86,95.44 v2(27.86,95.49) ; v2(27.94,75.8) 27.94,75.76 27.52,75.34 27.52,75 28.44,74.09 29.78,74.09 UV6.T8
  IN1 w0.102: v2(57.5,86.2) 57.02,85.72 55.41,85.72 55.39,85.74 53.51,85.74 53.17,86.08 51.44,86.08 51.11,85.75 49.97,85.75
  IN1 w0.203: v2(23.2,85.91) 23.5,86.21 25.91,86.21 26.6,85.53 29.11,85.53 29.62,85.02 31.06,85.02 31.14,84.94 31.52,84.94 31.83,85.25 33.84,85.25 34.35,85.75 49.97,85.75
  IN2 w0.107: v2(27.94,75.8) 26.95,75.8 23.2,79.56 v2(23.2,85.91) 23.25,85.96 23.25,87.91 25.46,90.12 25.46,92.97 26.83,94.34 27.9,94.34 28.1,94.54 28.27,94.71 28.27,95.09 28.08,95.28 28.08,95.3 27.88,95.49 v2(27.86,95.49)
  BOTTOM w0.102: UV8.T8 30.23,97.53 30.13,97.43 30.13,97.35 30.01,97.24 29.84,97.24 29.72,97.35 29.72,97.43 29.62,97.53 28.7,97.53 27.45,96.28 27.45,95.9 27.85,95.49 v2(27.86,95.49) ; v2(57.5,86.2) 58,85.7 UV1.J14 ; v2(27.94,75.8) 27.93,75.8 27.55,76.19 27.55,76.62 28.65,77.72 29.62,77.72 29.72,77.62 29.72,77.41 29.81,77.32 30.04,77.32 30.13,77.41 30.13,77.47 30.38,77.72 UV5.T8
M_MA9: length 73.3
  TOP w0.102: UV6.R3 31.75,77.03 31.65,77.13 31.39,77.13 31.32,77.06 31.32,76.77 31.1,76.55 30.68,76.55 30.6,76.46 30.6,76.33 30.28,76.01 30.28,75.57 30.22,75.51 29.94,75.51 29.86,75.6 v2(29.86,75.86) ; UV7.R3 31.75,96.78 31.61,96.91 31.42,96.91 31.32,96.81 31.32,96.53 31.36,96.49 31.36,96.29 31.3,96.23 30.68,96.23 30.28,95.83 30.28,95.39 30.22,95.32 29.94,95.32 29.86,95.41 v2(29.86,95.67)
  IN1 w0.102: v2(58.12,86.16) 57.68,86.59 55.61,86.59 55.53,86.52 54.82,86.52 54.67,86.67 51.77,86.67 51.56,86.46
  IN1 w0.203: v2(26.45,87.02) 26.65,87.23 28.73,87.23 29.42,86.54 31.45,86.54 32.01,85.98 32.62,85.98 33.03,86.39 38.94,86.39 39.22,86.67 41.33,86.67 41.61,86.39 51.49,86.39 51.56,86.46
  IN2 w0.107: v2(29.86,95.67) 29.83,95.7 29.83,96.55 29.95,96.68 30.13,96.68 30.26,96.55 30.26,94.72 28.15,92.62 28.15,90.6 28.15,90.59 28.15,90.56 28.05,90.45 28.05,90.28 28.03,90.26 28.03,90.22 28,90.19 28,89.08 26.45,87.53 v2(26.45,87.02) 26.37,86.95 26.37,85.86 26.85,85.37 26.85,80.01 28.56,78.31 28.56,77.78 29.55,76.79 29.55,76.17 v2(29.86,75.86)
  BOTTOM w0.102: v2(29.86,75.86) 29.86,75.75 30.24,75.37 30.24,74.82 30.55,74.51 31.61,74.51 31.75,74.37 UV5.R3 ; UV8.R3 31.75,94.18 31.61,94.32 31.1,94.32 30.85,94.57 30.3,94.57 30.24,94.63 30.24,95.18 29.86,95.57 v2(29.86,95.67) ; UV1.K14 58.77,85.5 v2(58.12,86.16)
M_MA10: length 82.9
  TOP w0.102: UV6.L7 34.75,73.92 34.75,74.29 34.99,74.54 34.99,75.02 35.12,75.14 v2(35.42,75.14) ; UV7.L7 34.75,93.73 34.75,94.11 34.99,94.35 34.99,94.83 35.12,94.96 v2(35.42,94.96) ; 49.97,86.19 51.21,86.19 51.29,86.26 52.99,86.26 53.51,85.74 56.36,85.74 56.42,85.81 56.42,85.94 56.42,85.94 56.42,86.26 56.42,86.26 56.42,86.31 56.7,86.59 57.87,86.59 57.94,86.67 57.94,87.24 v2(57.9,87.28)
  TOP w0.198: 49.97,86.19 48.46,86.19 v1(47.03,87.62) 45.87,88.78 37.93,88.78 37.62,88.47 36.81,88.47 36.66,88.32 36.66,87.71 36.51,87.56 36.05,87.56 35.9,87.71 35.9,87.86 35.74,88.02 34.98,88.02 34.83,87.86 34.83,87.53 v2(35.26,87.1)
  IN2 w0.107: v2(35.42,75.14) 35.42,74.1 35.06,73.74 35.06,72.19 34.96,72.09 34.55,72.09 34.5,72.14 34.5,73.92 35.03,74.45 35.03,76.03 34.22,76.84 34.02,76.84 33.33,77.53 33.33,79.89 33.48,80.04 33.48,80.17 33.71,80.4 33.71,81.49 33.66,81.54 33.66,83.65 33.9,83.89 34.61,83.89 35.26,84.54 35.26,85.37 34.8,85.83 34.8,86.64 v2(35.26,87.1) 35.44,86.92 35.44,86.85 35.11,86.52 35.11,86.12 35.19,86.03 35.38,86.03 35.52,86.17 35.52,86.38 35.66,86.52 35.86,86.52 36,86.38 36,86.03 36.15,85.88 36.33,85.88 36.46,86.01 36.46,87.08 36.33,87.2 36.33,87.33 36.46,87.46 36.46,87.89 36.01,88.33 35.81,88.33 35.71,88.23 35.71,87.98 36.01,87.67 36.01,87.52 35.9,87.41 35.64,87.41 35.39,87.66 35.13,87.66 35.05,87.58 34.88,87.58 34.76,87.7 34.76,87.87 35.64,88.75 35.64,88.93 35.52,89.05 35.34,89.05 34.49,88.2 34.31,88.2 34.19,88.33 34.19,88.5 34.63,88.95 34.63,89.1 34.48,89.25 34.33,89.25 33.94,88.86 33.79,88.86 33.69,88.96 33.69,89.18 33.79,89.29 33.79,89.41 33.69,89.51 33.69,90.5 33.48,90.71 33.48,91.8 35.01,93.32 35.01,94.24 35.42,94.65 v2(35.42,94.96)
  BOTTOM w0.102: v2(57.9,87.28) 58.11,87.08 58.2,87.08 58.4,86.87 58.4,86.49 58.68,86.22 59.04,86.22 59.19,86.36 59.19,87.35 59.01,87.53 58.65,87.53 58.29,87.9 UV1.J11 ; UV5.L7 35.03,76.84 35.03,75.65 35.29,75.39 35.29,75.28 v2(35.42,75.14) ; UV8.L7 34.95,96.58 35.04,96.48 35.04,95.47 35.42,95.09 v2(35.42,94.96)
M_MA11: length 82.1
  TOP w0.102: 49.97,87.41 50.58,87.41 50.84,87.14 51.75,87.14 52.12,86.76 53.32,86.76 53.51,86.95 53.51,87.18 53.63,87.31 54.73,87.31 54.74,87.32 55.52,87.32 55.63,87.21 55.63,87.04 55.96,86.71 56.44,86.71 56.71,86.97 56.99,86.97 v2(57.32,87.3) ; UV6.R7 31.6,73.72 31.54,73.79 31.54,73.99 31.6,74.05 31.6,74.24 31.5,74.34 31.33,74.34 31.28,74.29 31.16,74.29 30.86,74.59 30.86,74.7 31.05,74.89 31.05,75.28 30.94,75.4 30.74,75.4 30.65,75.31 v2(30.65,75.14) ; v2(30.65,94.96) 30.65,95.11 30.75,95.21 30.94,95.21 31.04,95.11 31.04,94.72 30.85,94.52 30.85,94.4 31.12,94.13 31.22,94.13 31.31,94.22 31.38,94.22 31.44,94.17 31.49,94.17 31.59,94.07 31.59,93.88 31.52,93.81 31.52,93.61 31.6,93.53 UV7.R7
  TOP w0.198: 49.97,87.41 49.08,87.41 46.46,90.02 v1(45.6,90.02) 37.34,90.02 37.01,89.69 36.15,89.69 35.74,89.29 34.52,89.29 34.09,89.72 30.33,89.72 29.93,89.31 29.93,89.01 30.38,88.55 30.87,88.55 31.53,87.89 31.53,87.48 31.07,87.02 30.11,87.02 28.61,88.52 28.61,89.08 28.17,89.51 26.75,89.51 26,88.76 26,88.13 27.34,86.8 27.34,86.36 27.29,86.31 v2(27.29,86.14)
  IN2 w0.107: v2(30.65,75.14) 30.24,75.55 30.24,76.02 29.77,76.48 29.77,76.92 28.96,77.73 28.96,78.46 27.29,80.14 v2(27.29,86.14) 27.34,86.19 27.34,86.92 27.21,87.05 27.06,87.05 26.9,87.2 26.9,87.41 27.03,87.53 27.13,87.53 27.31,87.71 27.31,87.81 28.48,88.98 28.48,90.53 28.5,90.56 28.5,90.8 28.61,90.91 28.78,90.91 28.89,91.02 28.89,91.23 28.78,91.34 28.61,91.34 28.5,91.44 28.5,91.8 28.58,91.88 28.86,91.88 28.96,91.98 28.96,92.42 28.78,92.61 28.78,92.76 28.76,92.78 28.76,92.93 28.91,93.08 29.06,93.08 29.08,93.06 29.23,93.06 29.38,93.21 29.38,93.36 29.36,93.38 29.36,93.53 29.51,93.68 29.66,93.68 29.68,93.66 29.83,93.66 29.98,93.81 29.98,93.96 29.96,93.98 29.96,94.13 30.12,94.28 30.27,94.28 30.29,94.26 30.44,94.26 30.82,94.64 30.82,94.79 v2(30.65,94.96)
  BOTTOM w0.102: v2(57.32,87.3) 57.32,87.24 57.56,87 57.56,86.64 57.63,86.58 57.88,86.58 UV1.J13 ; UV8.R7 31.75,96.45 31.49,96.19 31.23,96.19 31.12,96.07 30.43,96.07 30.27,95.91 30.27,95.5 30.65,95.12 v2(30.65,94.96) ; UV5.R7 31.75,76.64 31.49,76.38 31.23,76.38 31.12,76.26 30.43,76.26 30.27,76.09 30.27,75.69 30.65,75.31 v2(30.65,75.14)
M_MA12: length 80.6
  TOP w0.102: v2(33.03,75.14) 33.24,75.14 33.36,75.03 33.36,74.85 33.21,74.71 33,74.71 32.88,74.6 32.88,74.33 33.02,74.2 33.03,74.2 33.35,73.88 UV6.N7 ; v2(56.8,88.45) 56.65,88.29 56.44,88.29 56.41,88.33 56.41,88.71 56.55,88.85 56.98,88.85 57.23,88.6 57.23,88.45 57.33,88.35 57.82,88.35 57.97,88.19 57.97,87.91 57.82,87.76 56.04,87.76 55.68,88.12 55.11,88.12 54.53,87.53 52.41,87.53 52.22,87.34 ; v2(33.03,94.96) 33.27,94.96 33.4,94.83 33.4,94.69 33.27,94.56 33.01,94.56 32.92,94.47 32.92,94.12 33.03,94.01 33.03,94.01 33.35,93.69 UV7.N7
  TOP w0.124: 52.22,87.34 51.99,87.34 51.87,87.46 51.26,87.46
  TOP w0.198: 51.26,87.46 50.7,88.02 v1(49.36,88.02) 46.74,90.63 37.01,90.63 36.71,90.33 30.36,90.33 30.26,90.43 30.26,92.47 30.06,92.66 29.65,92.66 29.41,92.43 29.41,90.86 29.04,90.48 29.04,89.56 29.24,89.36 29.24,88.76 30.16,87.85 30.58,87.85 v2(30.86,87.57)
  IN2 w0.107: v2(33.03,94.96) 33.08,94.96 33.2,94.83 33.2,94.39 33.13,94.31 32.98,94.31 32.9,94.39 32.67,94.39 32.54,94.26 32.54,94.11 32.67,93.99 32.9,93.99 33,93.88 33,93.63 32.8,93.43 32.62,93.43 32.24,93.81 32.09,93.81 31.94,93.66 31.94,93.51 32.35,93.1 32.35,92.93 32.22,92.8 32.05,92.8 31.64,93.21 31.49,93.21 31.32,93.04 31.32,92.84 31.65,92.51 31.65,92.26 31.55,92.16 31.35,92.16 30.99,92.51 30.85,92.51 30.54,92.2 30.54,91.99 30.64,91.88 31.04,91.88 31.15,91.77 31.15,90.68 30.97,90.5 30.97,87.68 v2(30.86,87.57) 30.86,86.33 30.46,85.93 30.46,84.81 30.94,84.33 30.94,84.15 30.99,84.1 30.99,80.04 30.82,79.86 30.82,78.87 31.4,78.29 31.4,77.42 32.65,76.18 32.65,75.62 33.03,75.24 v2(33.03,75.14)
  BOTTOM w0.102: v2(33.03,94.96) 33.03,95.12 32.67,95.49 32.67,95.97 33.35,96.65 UV8.N7 ; v2(56.8,88.45) 56.8,88.38 56.91,88.27 57.07,88.27 57.43,88.62 57.69,88.62 57.84,88.47 57.84,88.29 57.45,87.9 UV1.H11 ; UV5.N7 33.35,76.84 32.67,76.16 32.67,75.68 33.03,75.31 v2(33.03,75.14)
M_MA13: length 86.5
  TOP w0.102: v2(56.08,80.1) 55.92,79.94 55.73,79.94 55.66,80.01 55.35,80.01 55.28,79.94 54.98,79.94 54.8,80.12 54.8,80.53 54.53,80.8 54.29,80.8 54.21,80.88 54.21,81.13 54.11,81.22 53.68,81.22 53.4,80.94 53.4,80.78 53.22,80.6 53.22,80.4 53.12,80.29 51.72,80.29 51.67,80.34 49.97,80.34 ; UV6.T3 30.95,77.06 30.88,77.13 30.52,77.13 30.46,77.06 30.46,77 30.33,76.87 30.13,76.87 30.03,76.97 30.03,77.07 29.98,77.13 29.66,77.13 29.52,76.99 29.52,76.72 29.65,76.59 30.33,76.59 30.39,76.53 30.39,76.41 30.21,76.24 29.61,76.24 29.47,76.09 29.47,75.67 29.37,75.57 29.37,75.41 29.47,75.32 29.47,75.03 29.39,74.96 29.08,74.96 28.97,75.07 v2(28.97,75.14) ; UV7.T3 30.95,96.87 30.88,96.94 30.52,96.94 30.46,96.87 30.46,96.81 30.33,96.68 30.13,96.68 30.03,96.79 30.03,96.89 29.98,96.94 29.66,96.94 29.52,96.8 29.52,96.53 29.65,96.4 30.33,96.4 30.39,96.34 30.39,96.23 30.21,96.05 29.61,96.05 29.47,95.91 29.47,94.88 29.33,94.74 29,94.74 28.87,94.87 v2(28.87,94.94)
  TOP w0.198: v2(24.14,84.71) 25.18,84.71 25.86,84.03 26.78,84.03 27.13,84.38 27.36,84.38 27.37,84.39 28.11,84.39 28.12,84.38 28.81,84.38 29.53,83.66 29.53,83.61 29.88,83.26 29.94,83.26 30.2,83 30.2,82.94 30.84,82.31 43.94,82.31 45.9,80.34 49.97,80.34
  IN2 w0.107: v2(28.97,75.14) 28.97,75.04 28.85,74.91 28.61,74.91 28.48,75.04 28.48,75.21 28.34,75.36 28.34,76.07 28.34,76.07 28.34,76.65 28.12,76.87 28.12,76.87 28.11,76.88 27.68,76.88 24.14,80.42 v2(24.14,84.71) 24.14,87.61 26.27,89.74 26.27,92.51 27.31,93.55 27.77,93.55 28.87,94.65 v2(28.87,94.94)
  BOTTOM w0.102: UV1.G20 56.3,80.8 56.04,80.8 55.84,80.6 55.84,80.32 56.05,80.1 v2(56.08,80.1) ; UV8.T3 30.95,93.4 30.87,93.32 30.54,93.32 30.49,93.37 30.49,93.6 30.74,93.86 30.74,93.98 30.56,94.16 30.33,94.16 30.18,94.01 30.18,93.5 30.11,93.43 29.94,93.43 29.65,93.72 29.65,93.88 29.88,94.11 29.88,94.29 29.79,94.37 29.48,94.37 29.29,94.19 29.19,94.19 28.96,94.42 28.96,94.49 29.22,94.75 29.22,94.92 29.14,95 28.93,95 v2(28.87,94.94) ; UV5.T3 30.95,73.59 30.86,73.5 30.66,73.5 30.53,73.62 30.53,73.87 30.46,73.94 30.32,73.94 30.16,73.78 30.16,73.69 30.07,73.6 29.91,73.6 29.79,73.72 29.79,73.88 30.09,74.18 30.09,74.34 29.98,74.45 29.82,74.45 29.5,74.12 29.34,74.12 29.23,74.23 29.23,74.38 29.3,74.45 29.3,74.62 29.18,74.74 29.02,74.74 28.93,74.65 28.81,74.65 28.56,74.91 28.56,75.34 28.61,75.39 28.85,75.39 28.97,75.27 v2(28.97,75.14)
M_MA14: length 86.3
  TOP w0.102: UV7.T7 30.95,93.6 30.04,94.51 28.73,94.51 28.49,94.75 28.49,95.74 28.85,96.1 v2(28.85,96.34) ; 49.97,86.8 50.21,86.56 53.4,86.56 53.46,86.61 54.99,86.61 55.08,86.52 55.66,86.52 v2(56.03,86.15) ; UV6.T7 30.95,73.79 30,74.74 28.76,74.74 28.58,74.92 28.58,75.94 28.93,76.3 v2(28.93,76.54)
  TOP w0.198: 49.97,86.8 48.76,86.8 46.17,89.38 37.64,89.38 37.34,89.08 36.51,89.08 36.1,88.68 34.27,88.68 33.86,89.08 31.96,89.08 31.76,88.88 31.76,88.52 32.14,88.14 32.14,87.23 31.25,86.34 29.93,86.34 28.37,87.9 27.96,87.9 27.64,87.58 27.64,87.38 27.95,87.08 27.95,85.89 27.71,85.65 26.88,85.65 25.9,86.64 25.5,86.64 25.08,86.21 25.08,85.67 v2(25.53,85.22)
  IN2 w0.107: v2(28.85,96.34) 29.47,95.72 29.47,95.12 29.46,95.12 29.46,94.8 29.47,94.79 29.47,94.54 27.11,92.18 27.11,89.41 25.53,87.83 v2(25.53,85.22) 25.69,85.22 25.81,85.09 25.81,84.91 25.69,84.79 25.22,84.79 25.08,84.65 25.08,84.45 25.22,84.31 25.56,84.31 25.79,84.08 25.91,84.08 25.99,84 25.99,81.84 25.84,81.69 25.21,81.69 25.1,81.58 25.1,81.46 25.25,81.31 25.84,81.31 25.99,81.16 25.99,79.76 27.9,77.86 27.91,77.86 27.99,77.77 27.99,77.68 28.84,76.84 28.84,76.64 v2(28.93,76.54)
  BOTTOM w0.102: v2(28.85,96.34) 28.67,96.52 28.67,97.08 28.88,97.29 29.29,97.29 29.42,97.17 29.42,96.57 29.54,96.45 29.71,96.45 29.83,96.57 29.83,96.63 29.93,96.73 30.28,96.73 30.41,96.86 30.41,97.05 30.53,97.18 30.82,97.18 30.95,97.05 UV8.T7 ; v2(56.03,86.15) 56.03,85.83 55.9,85.7 55.9,85.41 56.03,85.28 56.27,85.28 56.4,85.41 UV1.G14 ; v2(28.93,76.54) 28.76,76.72 28.76,77.35 28.88,77.48 29.29,77.48 29.42,77.35 29.42,76.74 29.6,76.56 29.92,76.56 30.28,76.92 30.41,77.05 30.41,77.24 30.53,77.37 30.82,77.37 30.95,77.24 UV5.T7
M_MA15: length 78.4
  TOP w0.102: v2(33.83,75.14) 34.15,75.14 34.28,75.02 34.28,74.69 34.15,74.57 33.36,74.57 33.24,74.45 33.24,74.28 33.36,74.16 34.05,74.16 34.15,74.06 UV6.M7 ; v2(33.83,94.96) 34.11,94.96 34.28,94.79 34.28,94.51 34.15,94.38 33.36,94.38 33.24,94.26 33.24,94.09 33.36,93.97 34.05,93.97 34.15,93.87 UV7.M7
  IN1 w0.203: v2(60.14,82.81) 60.13,82.79 59.31,82.79 59.16,82.94 59.16,85.32 58.91,85.58 58.35,85.58 58.12,85.35 58.12,84.64 57.97,84.48 57.97,83.11 57.84,82.99 57.31,82.99 57.18,83.11 57.18,84.33 57.05,84.46 56.61,84.46 56.48,84.33 56.48,83.49 56.36,83.37 55.8,83.37 55.67,83.49 55.67,83.93 55.47,84.13 55.06,84.13 54.86,83.93 54.86,83.57 54.73,83.44 54.17,83.44 54.05,83.57 54.05,83.93 53.84,84.13 53.44,84.13 53.23,83.93 53.23,83.85 53.03,83.65 47.78,83.65 47.17,84.26 46.89,84.26 46.28,83.65 45.88,83.65 45.67,83.85 45.67,84.36 45.47,84.56 45.06,84.56 44.86,84.36 44.86,83.85 44.66,83.65 44.25,83.65 44.05,83.85 44.05,84.36 43.84,84.56 43.44,84.56 43.23,84.36 43.23,83.85 43.03,83.65 41.66,83.65 41.26,84.05 39.68,84.05 39.2,83.57 37.91,83.57 37.83,83.65 37.83,83.66 36.95,84.54 32.05,84.54 v2(31.9,84.38)
  IN2 w0.107: v2(33.83,94.96) 33.83,93.73 31.81,91.7 31.81,86.21 31.9,86.12 v2(31.9,84.38) 31.9,84.31 31.84,84.25 31.84,77.62 33.46,76 33.46,75.34 33.43,75.32 33.43,74.99 33.27,74.82 33.27,74.64 33.36,74.55 33.61,74.55 33.84,74.78 33.84,75.14 v2(33.83,75.14)
  BOTTOM w0.102: UV8.M7 34.28,96.6 34.28,96.28 34.13,96.12 33.77,96.12 33.53,96.36 33.37,96.36 33.25,96.24 33.25,96.07 33.45,95.87 33.45,95.49 33.83,95.11 v2(33.83,94.96) ; v2(60.14,82.81) 59.65,83.3 UV1.L17 ; UV5.M7 34.28,76.79 34.28,76.47 34.13,76.31 33.77,76.31 33.53,76.54 33.37,76.54 33.25,76.43 33.25,76.26 33.45,76.06 33.45,75.68 33.83,75.3 v2(33.83,75.14)
M_ODT: length 10.1
  TOP w0.254: R2348.1 R2349.1 R2350.1 R2352.1 ; R2352.1 142.82,56.19 142.64,56.01 QD2.3 ; R2352.1 143.36,56.65 144.18,57.46 146.51,57.46 v1(146.69,57.28) CD64.1
M_ODT0: length 36.8
  TOP w0.157: R2348.2 146.54,53.52 146.72,53.34 147.84,53.34 148.99,52.19 v1(148.99,50.55) 148.99,40.91 147.88,39.81 141.66,39.81 140.9,39.04 140.9,38.28 140.26,37.65 138.23,37.65 137.6,37.01 134.8,37.01 133.69,38.13 v2(132.72,38.13)
  BOTTOM w0.157: v2(132.72,38.13) 133.05,38.46 JDIMM1.116
M_ODT1: length 38.6
  TOP w0.157: v2(134.25,36.89) 134.45,36.68 135.26,36.68 135.95,36 137.47,36 138.66,37.19 140.7,37.19 141.41,37.9 141.41,38.79 141.79,39.17 148.39,39.17 149.41,40.19 149.41,52.36 147.99,53.78 146.89,53.78 146.26,54.41 R2349.2
  BOTTOM w0.157: JDIMM1.120 v2(134.25,36.89)
M_ODT2: length 38.8
  TOP w0.157: v2(145.15,25.01) 145.21,25.01 145.91,25.71 146.74,25.71 148.27,27.23 148.27,33.84 150.42,36 150.42,51.92 148.14,54.21 147.1,54.21 146.4,54.91 145.31,54.91 144.91,55.3 R2350.2
  BOTTOM w0.157: JDIMM2.116 145.42,25.28 v2(145.15,25.01)
M_ODT3: length 41.4
  TOP w0.157: v2(145.98,25.07) 146.11,24.95 146.61,24.95 148.77,27.11 148.77,27.23 149.54,28 149.54,32.95 150.42,33.84 151.69,33.84 152.08,34.22 v1(152.08,50.5) 152.08,50.85 148.19,54.74 147.33,54.74 146.6,55.47 145.92,55.47 145.19,56.19 R2352.2
  BOTTOM w0.157: JDIMM2.120 146.62,25.59 146.11,25.07 v2(145.98,25.07)
M_RAS#0: length 56.1
  TOP w0.102: 49.97,79.34 50.31,79 50.85,79 50.95,79.1 52.23,79.1 52.36,79.23 52.36,79.5 52.53,79.68 52.94,79.68 53.15,79.48 53.15,79.23 53.25,79.13 54.82,79.13 55.07,79.38 55.38,79.38 55.86,78.9 v2(56,78.9)
  TOP w0.124: v2(35.45,81.11) 35.54,81.03 37.98,81.03 38.08,81.13 38.08,81.17 38.2,81.3 39.89,81.3 40.01,81.17 40.01,81.13 40.14,81 40.39,81 40.51,81.13 40.51,81.17 40.64,81.3 41.26,81.3 41.55,81 43.19,81 43.78,80.41 44.38,80.41 45.45,79.34 49.97,79.34 ; v2(37.01,75.73) 37.01,75.69 37.19,75.51 37.37,75.51 37.52,75.66 37.52,75.78 37.7,75.96 37.7,76.06 37.6,76.16 37.59,76.16 37.44,76.31 37.34,76.31 37.17,76.14 37.04,76.14 36.88,76.29 36.88,76.45 37.02,76.59 37.02,76.83 36.94,76.92 UV6.J3
  IN2 w0.13: v2(35.45,81.11) 35.71,80.85 36.04,80.85 36.11,80.93 36.11,81.74 36.24,81.87 36.5,81.87 36.63,81.74 36.63,80.98 36.76,80.85 36.99,80.85 37.26,81.12 37.26,81.89 37.74,82.38 40.85,82.38 40.98,82.25 40.98,81.89 40.85,81.77 37.89,81.77 37.77,81.64 37.77,80.59 37.52,80.34 36.07,80.34 35.92,80.19 35.92,80.04 36.13,79.83 37.64,79.83 37.77,79.7 37.77,79.45 37.64,79.32 36.76,79.32 36.64,79.2 36.64,78.69 36.51,78.56 35.82,78.56 35.68,78.42 35.68,78.02 36.71,76.99 36.71,76.38 36.91,76.18 37.42,76.18 37.5,76.11 37.5,75.61 37.39,75.5 37.23,75.5 v2(37.01,75.73)
  BOTTOM w0.102: v2(56,78.9) 55.91,78.99 55.91,79.58 56.04,79.71 56.27,79.71 56.4,79.58 UV1.G22
  BOTTOM w0.124: v2(37.01,75.73) 37.11,75.82 37.27,75.82 37.44,75.65 37.44,74.89 37.37,74.82 37.37,74.69 37.44,74.61 37.44,74.48 37.35,74.38 37.21,74.38 37.1,74.48 36.8,74.48 36.55,74.23 UV5.J3
M_RAS#1: length 52.6
  TOP w0.102: v2(56.32,82.49) 56.24,82.42 56.24,82.05 56.11,81.92 55.89,81.92 55.76,82.05 55.76,82.47 55.63,82.6 52.99,82.6 52.76,82.38 52.2,82.38 51.87,82.71
  TOP w0.124: v2(39.71,85.13) 39.71,85.3 39.88,85.48 40.14,85.48 40.54,85.07 v1(42.55,85.07) 44.63,85.07 46.96,82.74 50.2,82.74 50.24,82.71 51.87,82.71 ; v2(37.09,95.54) 37.09,95.47 37.21,95.34 37.35,95.34 37.53,95.52 37.53,95.58 37.7,95.74 37.7,95.84 37.4,96.14 37.26,96.14 37.12,96 36.95,96 36.84,96.11 36.84,96.27 37.02,96.45 37.02,96.64 36.93,96.73 UV7.J3
  IN2 w0.13: v2(37.09,95.54) 37.34,95.54 37.45,95.43 37.45,94.7 37.31,94.56 37.16,94.56 37.08,94.49 36.87,94.28 36.75,94.28 36.38,93.91 36.38,93.65 36.51,93.53 36.51,92.13 36.84,91.8 37.27,91.8 37.37,91.7 37.37,91.42 37.29,91.34 37.29,90.88 37.84,90.34 38.03,90.34 38.3,90.61 38.48,90.61 38.67,90.43 38.67,90.24 38.15,89.73 38.15,89.55 38.34,89.36 38.52,89.36 39.03,89.88 39.22,89.88 39.4,89.69 39.4,89.51 38.79,88.9 38.79,88.72 39.03,88.49 39.21,88.49 40.04,89.31 40.24,89.31 40.43,89.12 40.43,88.94 39.15,87.66 39.15,87.48 39.4,87.23 39.58,87.23 40.67,88.32 40.87,88.32 41.04,88.16 41.04,87.92 39.71,86.59 v2(39.71,85.13)
  BOTTOM w0.124: v2(56.32,82.49) 56.46,82.49 56.62,82.66 56.62,82.78 56.8,82.96 56.8,83.37 56.93,83.49 57.13,83.49 57.26,83.62 57.26,83.8 57.13,83.93 55.94,83.93 55.78,83.77 55.78,83.57 56.25,83.1 UV1.G17 ; v2(37.09,95.54) 37.18,95.64 37.24,95.64 37.44,95.44 37.44,94.7 37.37,94.63 37.37,94.5 37.44,94.42 37.44,94.29 37.35,94.19 37.21,94.19 37.1,94.3 36.8,94.3 36.55,94.04 UV8.J3
M_WE#0: length 56.7
  TOP w0.102: 57.72,76.91 57.73,76.92 58.63,76.92 58.78,77.07 58.78,77.6 58.68,77.7 58.07,77.7 57.99,77.78 57.99,78.29 57.77,78.52 57.33,78.52 57.18,78.36 57.18,77.45 57.08,77.35 v2(56.77,77.35)
  TOP w0.124: v2(33.77,79.61) 33.79,79.58 34.33,79.58 34.46,79.46 34.46,79.38 34.58,79.25 34.83,79.25 34.95,79.38 34.95,79.46 35.08,79.58 36.1,79.58 36.28,79.4 36.56,79.4 36.73,79.58 37,79.58 37.12,79.46 37.12,79.15 37.25,79.02 37.5,79.02 37.62,79.15 37.62,79.46 37.75,79.58 37.95,79.58 38.18,79.35 38.49,79.35 38.72,79.58 38.94,79.58 39.12,79.4 39.38,79.4 39.55,79.58 39.73,79.58 39.96,79.35 40.14,79.35 40.37,79.58 40.57,79.58 40.8,79.35 41.08,79.35 41.31,79.58 41.46,79.58 41.59,79.46 41.59,79.07 41.71,78.95 41.94,78.95 42.07,79.07 42.07,79.46 42.2,79.58 42.65,79.58 43.62,78.62 43.69,78.62 44.28,78.03 44.28,77.86 44.04,77.61 44.04,77.36 44.18,77.22 44.61,77.22 44.74,77.34 44.74,77.4 44.91,77.58 45.22,77.58 45.35,77.45 45.35,77.32 45.47,77.19 45.72,77.19 45.85,77.32 45.85,77.43 45.97,77.55 46.22,77.55 46.35,77.43 46.35,77.08 46.18,76.92 46.18,76.69 46.34,76.53 46.79,76.53 47,76.74 47,76.86 46.84,77.02 46.84,77.43 46.97,77.55 47.22,77.55 47.34,77.43 47.34,77.32 47.47,77.19 47.71,77.19 47.84,77.32 47.84,77.43 47.96,77.55 48.21,77.55 48.34,77.43 48.34,77.32 48.46,77.19 48.71,77.19 48.83,77.32 48.83,77.43 48.96,77.55 49.21,77.55 49.33,77.43 49.33,77.32 49.46,77.19 49.71,77.19 49.83,77.32 49.83,77.45 49.96,77.58 50.2,77.58 50.33,77.45 50.33,77.32 50.45,77.19 50.7,77.19 50.83,77.32 50.83,77.68 50.65,77.86 50.65,78.08 50.78,78.21 50.96,78.21 51.47,77.7 51.7,77.7 51.87,77.88 51.87,77.96 51.73,78.1 51.73,78.27 51.85,78.39 52.26,78.39 52.39,78.26 52.39,78.21 52.51,78.08 52.76,78.08 52.89,78.21 52.89,78.26 53.01,78.39 53.19,78.39 53.32,78.26 53.32,77.73 53.45,77.6 53.8,77.6 53.88,77.68 53.88,77.93 53.75,78.06 53.75,78.26 53.83,78.34 54.03,78.34 54.18,78.19 v1(54.18,78.09) 54.46,78.37 54.64,78.37 54.9,78.12 54.9,77.97 54.66,77.73 54.66,77.45 54.94,77.18 55.29,77.18 55.39,77.28 55.5,77.28 55.63,77.15 55.63,77.02 55.53,76.92 55.53,76.8 55.64,76.68 55.73,76.68 55.95,76.91 57.72,76.91 ; v2(35.43,75.84) 35.42,75.83 35.42,75.65 35.29,75.52 35.13,75.52 35.03,75.61 35.03,75.66 35.02,75.67 35.02,75.69 35.02,75.69 35.02,76.02 35.02,76.02 35.02,76.04 35.03,76.05 34.93,76.16 34.9,76.16 34.83,76.23 34.83,76.86 34.89,76.92 UV6.L3
  IN2 w0.13: v2(33.77,79.61) 33.77,79.97 33.92,80.12 34.17,80.12 34.33,79.95 34.33,79.21 34.34,79.21 34.34,78.89 34.33,78.88 34.33,78.86 34.09,78.62 34.09,78.41 34.33,78.17 34.33,77.92 34.25,77.83 34.02,77.83 33.79,77.6 33.79,77.4 33.98,77.21 34.18,77.21 34.33,77.06 34.34,77.06 35.2,76.19 35.2,76.19 35.42,75.97 35.42,75.84 v2(35.43,75.84)
  BOTTOM w0.102: v2(56.77,77.35) 56.77,77.3 56.9,77.17 56.9,76.97 56.83,76.9 UV1.G25
  BOTTOM w0.124: v2(35.43,75.84) 35.42,75.84 35.42,75.7 35.58,75.54 35.58,75.54 35.81,75.31 35.81,75.31 35.82,75.3 35.82,74.91 34.95,74.04 UV5.L3
M_WE#1: length 47.9
  TOP w0.124: v2(35.44,95.67) 35.45,95.67 35.43,95.65 35.43,95.47 35.29,95.33 35.11,95.33 35.04,95.4 35.04,95.83 34.8,96.07 34.8,96.17 34.91,96.27 34.91,96.4 34.8,96.5 34.8,96.65 34.89,96.73 UV7.L3
  IN1 w0.102: 55.38,88.83 56.37,88.83 56.79,89.25 v2(56.8,89.25)
  IN1 w0.13: 55.38,88.83 54.49,87.94 53.75,87.94 53.45,88.24 42.35,88.24 42.17,88.42 39.81,88.42 39.12,89.11 38.23,89.11 37.6,89.74 37.18,89.74 37.05,89.61 37.05,89.26 36.92,89.13 36.67,89.13 36.54,89.26 36.54,89.61 36.41,89.74 36.15,89.74 36.02,89.61 36.02,89.26 35.89,89.13 35.63,89.13 35.5,89.26 35.5,89.61 35.37,89.74 v2(34.75,89.74)
  IN2 w0.13: v2(35.44,95.67) 35.41,95.67 35.29,95.79 34.99,96.09 33.23,96.09 33.1,96.22 33.1,96.5 33.23,96.63 33.93,96.63 34.06,96.76 34.06,98.51 34.19,98.63 34.45,98.63 34.58,98.51 34.58,96.76 34.71,96.63 35.13,96.63 35.85,95.91 35.85,95.52 35.74,95.41 35.74,95.19 35.82,95.12 35.82,94.79 35.74,94.72 35.74,94.57 35.26,94.09 35.26,93.22 33.74,91.7 33.74,91.04 34.09,90.68 34.09,90.4 v2(34.75,89.74)
  BOTTOM w0.124: v2(56.8,89.25) 57.15,88.9 UV1.H10 ; UV8.L3 34.95,93.92 35.82,94.8 35.82,95.16 35.6,95.38 35.43,95.55 35.43,95.67 v2(35.44,95.67)
MCT0: length 3.8
  TOP w0.102: RL19.1 189.9,104.55 v1(189.9,103.28)
  TOP w0.254: RL19.1 190.68,104.58 v2(190.81,104.7)
  BOTTOM w0.254: v2(190.81,104.7) 190.68,104.58 TL2.14
MCT1: length 3.8
  TOP w0.102: v1(190.01,109.1) RL20.1
  TOP w0.254: RL20.1 190.49,108.26 v2(190.81,108.26)
  BOTTOM w0.254: TL2.11 190.68,108.39 v2(190.81,108.26)
MDI0+: length 8.3
  BOTTOM w0.091: UL1.1 178.2,104.96 178.64,105.4 v3(178.64,106.99) 178.64,110.06 179.06,110.48 179.31,110.48 179.4,110.57 179.4,110.83 179.49,110.93 TL2.8
MDI0-: length 8.3
  BOTTOM w0.076: UL1.2 178.33,104.56 178.72,104.96
  BOTTOM w0.091: 178.72,104.96 179.01,105.24 v3(179.01,108.89) 179.01,109.9 179.21,110.11 179.31,110.11 179.4,110.01 179.4,109.75 179.49,109.66 TL2.7
MDI1+: length 3.8
  BOTTOM w0.091: UL1.4 178.29,103.76 178.3,103.75 178.69,103.75 178.8,103.64 179,103.43 179,103.04 179.07,102.97 179.15,102.89 179.47,102.89 179.56,102.98 179.56,103.18 179.69,103.31 TL2.2
MDI1-: length 3.9
  BOTTOM w0.091: UL1.5 178.29,103.36 178.3,103.37 178.53,103.37 178.63,103.28 178.63,102.89 v3(178.81,102.71) 179,102.52 179.51,102.52 179.56,102.47 179.56,102.16 179.69,102.04 TL2.1
MDO0+: length 13.5
  BOTTOM w0.091: JLAN.1 201.1,108.48 200.95,108.33 199.84,108.33 199.33,108.85 v3(196.3,108.85) 194.94,108.85 193.64,110.15 191.06,110.15 190.28,110.93 TL2.9
MDO0-: length 13.6
  BOTTOM w0.091: JLAN.2 201.38,108.1 201.24,107.96 199.69,107.96 199.18,108.47 194.79,108.47 193.49,109.78 v3(192.08,109.78) 190.63,109.78 190.51,109.66 TL2.10
MDO1+: length 14.3
  BOTTOM w0.091: JLAN.3 201.1,106.04 200.89,105.83 200.58,105.83 199.94,105.2 v3(197.01,105.2) 195.37,105.2 193.03,102.86 190.7,102.86 190.25,103.31 TL2.15
MDO1-: length 14.2
  BOTTOM w0.091: TL2.16 190.28,102.04 190.73,102.49 v3(191.85,102.49) 193.18,102.49 195.53,104.83 200.08,104.83 200.89,104.02 202.1,104.02 JLAN.6
ME_EN: length 72
  TOP w0.102: v2(192.84,9.3) 192.84,11.74 v1(193.03,11.93) 193.86,12.76 RC8.1 ; v2(144.02,17.99) 144.22,18.18 UE1.99 144.22,20.3 RE326.1
  IN1 w0.107: v2(192.84,9.3) 192.83,9.3 191.58,8.06 185.1,8.06 184.92,7.88 178.25,7.88 176.93,6.56 174.4,6.56 173.54,5.69 169.98,5.69 168.9,4.61 154.71,4.61 154.31,5.02 150.45,5.02 149.27,3.84 147.56,3.84 v2(147.25,4.15)
  BOTTOM w0.102: v2(144.02,17.99) 146.77,15.24 146.77,13.6 146.88,13.49 146.88,4.52 v2(147.25,4.15)
ME_SUS_PWR_ACK: length 121
  TOP w0.102: UE1.34 133.02,4.63 132.77,4.88 129.08,4.88 128.81,4.6 124.47,4.6 122.66,6.41 v2(122.66,6.96) ; v2(166.25,41.94) 166.25,59.8 162.41,63.64 162.41,64.22 v1(160.89,65.74) 160.65,65.74 158.13,68.25 158.13,69.16 158.45,69.47 RC42.1 158.68,69.73 157.82,70.59 RC27.2
  IN1 w0.107: v2(121.14,23.22) 121.14,23.12 122.48,21.77 128.2,21.77 128.81,22.38 136.18,22.38 136.45,22.66 140.7,22.66 140.83,22.8 142.99,22.8 143.55,22.24 148.63,22.24 151.95,25.56 152.99,25.56 155.25,27.82 155.25,32.62 159.65,37.01 161.09,37.01 162.49,38.41 163.12,38.41 163.82,39.11 164.76,39.11 165.79,40.14 165.79,41.46 166.25,41.91 v2(166.25,41.94)
  BOTTOM w0.102: v2(122.66,6.96) 122.66,6.99 121.08,8.58 121.08,21 121.14,21.06 v2(121.14,23.22)
ME_SUS_PWR_ACK_R: length 20
  TOP w0.076: v2(159.31,73.46) 159.49,73.64 159.49,77.55 159.19,77.85 159.19,78.81 v2(158.47,79.53) ; RC42.2 159.26,68.56 v2(159.31,68.51) 159.37,68.56 RC35.1 159.95,68.34 159.86,68.25
  TOP w0.102: 159.86,68.25 159.86,67.68 v1(159.95,67.59)
  IN1 w0.102: 159.31,72.19 v2(159.31,73.46)
  IN1 w0.107: v2(159.31,68.51) 159.31,72.19
  BOTTOM w0.076: UC1.AV4 154.16,80.46 154.45,80.18 154.45,79.7 154.54,79.6 154.54,79.22 155.06,78.7 157.32,78.7 157.79,79.18 158.11,79.18 v2(158.47,79.53)
MEM_SMBCLK: length 27.9
  TOP w0.102: QC1.6 174.43,82.24 174.61,82.06 174.61,80.8 174.07,80.27 171.1,80.27 170.67,79.84 v2(170.67,79.58) 170.71,79.54 RP40.1
  IN2 w0.076: v2(158.32,83.04) 158.68,83.04
  IN2 w0.107: 158.68,83.04 158.98,83.04 160.71,84.76 163.25,84.76 163.35,84.87 166.81,84.87 169.09,82.58 169.09,81.79 169.47,81.41 169.47,80.52 170.41,79.58 v2(170.67,79.58)
  BOTTOM w0.076: v2(158.32,83.04) 157.97,82.68 156.73,82.68 156.3,83.12 156.02,83.12 155.76,82.86 155.73,82.83 UC1.AP2
MEM_SMBDATA: length 21.9
  TOP w0.102: QC1.3 171.06,80.64 170.87,80.45 v2(170.67,80.45) 170.62,80.45 170.14,79.96 170.14,79.25 170.34,79.05 RP40.2
  IN2 w0.076: 158.68,85.07 v2(157.9,85.86)
  IN2 w0.107: 158.68,85.07 158.73,85.02 163.12,85.02 163.23,85.12 166.93,85.12 169.35,82.71 169.35,81.89 169.73,81.51 169.73,80.73 170.01,80.45 v2(170.67,80.45)
  BOTTOM w0.076: v2(157.9,85.86) 157.9,86.22 157.54,86.57 UC1.AH1
MIC1-L: length 2.3
  BOTTOM w0.203: CA74.1 191.53,19.38 v1(192.39,19.38) 192.41,19.38 192.71,19.69 UA1.19
MIC_CLK: length 340.4
  TOP w0.102: v2(4.2,82.74) 4.68,82.26 CA22.1
  IN2 w0.107: v2(197.69,11.23) 197.44,11.49 196.91,11.49 196.4,11.99 193.86,11.99 193.1,11.23 193.1,10.22 191.95,9.07 187.89,9.07 186.75,10.22 182.31,10.22 181.36,9.27 180.28,9.27 179.19,8.18 169.22,8.18 168.46,8.95 166.81,8.95 165.73,10.02 163.19,10.02 161.73,8.56 158.58,8.56 157.57,9.57 157.57,11.82 156.71,12.68 150.14,12.68 148.13,14.69 147.5,14.69 147.07,14.25 141.38,14.25 141.23,14.4 135.26,14.4 134.99,14.13 133.74,14.13 133.72,14.15 133.71,14.15 133.42,14.44 131.67,14.44 131.3,14.07 127.72,14.07 127.16,14.63 126.18,14.63 125.44,15.37 122.21,15.37 122.21,15.37 121.25,15.37 120.72,14.84 v2(117.53,14.84) ; v2(83.62,69.78) 83.5,69.65 83.5,68.38 83.88,68 85.02,68 87.94,65.08 89.59,65.08 90.68,66.17 95.61,66.17 96.2,65.59 96.2,50.35 96.7,49.84 96.7,48.01 v2(95.15,46.46) ; v2(13.87,82.85) 14.1,83.08 14.1,90.81 20.25,96.96 24.57,96.96 29.27,101.66 32.82,101.66 34.22,103.05 34.22,103.56 34.5,103.84 51.39,103.84 54.67,107.12 56.04,107.12 57.94,105.21 59.62,105.21 60.16,104.68 62.82,104.68 64.98,102.52 64.98,101.5 66.1,100.39 66.1,99.62 66.4,99.32 66.4,99.12 66.92,98.61 69.27,98.61 69.91,97.97 79.56,97.97 79.81,98.23 81.97,98.23 83.24,96.96 89.59,96.96 92.51,99.88 95.56,99.88 v2(96.45,98.99)
  BOTTOM w0.102: LA1.2 199.95,12.12 199.5,11.66 198.13,11.66 v2(197.69,11.23) ; JEDP.30 2.49,84.5 4.2,82.8 v2(4.2,82.74) 5.1,82.74 5.59,83.24 6.66,83.24 7.3,82.61 9.33,82.61 9.84,82.1 13.13,82.1 v2(13.87,82.85) ; v2(96.45,98.99) 95.31,97.85 95.31,97.08 87.69,89.46 87.69,84.46 87.18,83.95 87.18,82.1 85.15,80.07 85.15,70.67 84.51,70.03 83.88,70.03 v2(83.62,69.78) ; v2(95.15,46.46) 92.82,46.46 91.64,45.28 89.77,45.28 88.84,44.35 88.84,41.7 94.7,35.84 95.15,35.84 95.56,35.44 v1(98.08,35.44) 100.59,35.44 104.4,31.63 104.4,27.34 109.13,22.6 110.48,22.6 110.8,22.28 115.77,22.28 116.9,21.15 116.9,18.93 117.4,18.42 117.4,14.96 v2(117.53,14.84)
MIC_CLK_C: length 5.5
  BOTTOM w0.102: UA1.3 197.93,15.93 198.41,15.45 199.09,15.45 199.5,15.04 199.5,14.76 199.73,14.53 LA1.1 200.37,14.53 200.54,14.36 200.54,13.01 v1(200.36,12.83)
MIC_DATA: length 344.2
  IN2 w0.102: 69.78,97.72 77.91,97.72
  IN2 w0.107: v2(198.41,11.23) 198.41,11.51 198.18,11.74 197.01,11.74 196.5,12.25 193.75,12.25 192.84,11.34 192.84,10.32 191.85,9.33 188.02,9.33 186.87,10.47 182.85,10.47 182.57,10.75 181.42,10.75 179.11,8.44 169.35,8.44 168.59,9.2 166.93,9.2 165.83,10.3 163.08,10.3 161.6,8.82 158.68,8.82 157.82,9.68 157.82,12.04 156.85,13.01 150.11,13.01 148.2,14.91 147.38,14.91 146.93,14.47 141.46,14.47 141.32,14.61 135.17,14.61 134.9,14.34 133.82,14.34 133.8,14.36 133.79,14.36 133.51,14.65 131.4,14.65 131.04,14.29 128.85,14.29 127.92,15.22 125.88,15.22 125.5,15.6 122.11,15.6 122.11,15.6 121.15,15.6 120.83,15.29 117.4,15.29 v2(116.95,14.84) ; v2(95.81,98.99) 95.18,99.62 92.64,99.62 89.72,96.7 83.11,96.7 81.84,97.97 79.94,97.97 79.69,97.72 77.91,97.72 ; v2(81.84,69.65) 83.75,67.75 84.89,67.75 87.81,64.83 89.72,64.83 90.81,65.92 95.48,65.92 95.94,65.46 95.94,50.24 96.45,49.73 96.45,48.12 95.42,47.1 v2(95.15,47.1) ; v2(14.09,82.16) 14.37,82.44 14.37,90.57 20.44,96.64 24.63,96.64 29.39,101.4 32.95,101.4 34.22,102.67 55.56,102.67 57.71,104.83 58.93,104.83 62.24,101.53 64.57,101.53 65.84,100.26 65.84,99.5 66.17,99.17 66.17,99.03 66.9,98.29 69.2,98.29 69.78,97.72
  BOTTOM w0.102: JEDP.32 2.29,83.5 2.63,83.15 3.21,83.15 4.04,82.31 5.1,82.31 5.64,82.86 6.66,82.86 7.3,82.22 9.07,82.22 9.45,81.84 13.77,81.84 v2(14.09,82.16) ; v2(198.41,11.23) 199.75,11.23 200.77,12.25 200.77,14.83 200.56,15.04 199.79,15.04 199.18,15.65 198.58,15.65 198.33,15.91 UA1.2 ; v2(95.81,98.99) 94.8,97.97 94.8,96.96 87.38,89.54 87.38,84.74 86.86,84.22 86.86,82.16 84.89,80.19 84.89,70.79 84.38,70.29 83.11,70.29 82.48,69.65 v2(81.84,69.65) ; v2(116.95,14.84) 117.18,15.07 117.18,18.22 116.64,18.75 116.64,20.91 115.5,22.05 110.64,22.05 110.36,22.32 109.03,22.32 104.17,27.19 104.17,31.43 100.54,35.06 v1(95.85,35.06) 95.62,35.06 95.06,35.62 94.61,35.62 88.59,41.63 88.59,44.43 89.67,45.51 91.51,45.51 92.72,46.71 94.77,46.71 v2(95.15,47.1)
MIC_IN: length 22.4
  TOP w0.254: v2(189.92,32.24) 189.92,32.31 190.16,32.55 QA6.3
  IN2 w1.016: v2(189.92,32.24) 189.97,32.19 190.3,32.19 191.53,30.95 191.53,30.12 193.33,28.33 193.33,27.46 194.21,26.58 194.21,25.86 194.24,25.83 194.24,24.77 194.9,24.11 194.9,22.32 192.04,19.45 v2(192.04,18.89)
  BOTTOM w0.203: UA1.18 192.89,19.29 192.49,18.89 v2(192.04,18.89)
  BOTTOM w0.508: LA7.2 190.82,33.08 190.57,33.33 RA53.1 189.74,33.08 189.92,32.9 v2(189.92,32.24)
MIC_IN_R: length 26.6
  TOP w0.102: v2(197.54,33.41) v1(197.54,32.72)
  IN2 w1.016: 199.09,33.33 199.56,32.86 199.56,31.7 198.38,30.52 198.38,27.92 200.34,25.96 209.1,25.96 210.14,27.01 JHP.4
  BOTTOM w0.508: v2(198.38,33.41) v2(197.54,33.41) DA12.3 194.95,33 CA38.1 192.59,33 192.52,33.08 LA7.1
Net_5: length 4.8
  TOP w0.102: v2(134.75,16.51) 134.35,16.11 133.79,16.11 132.62,17.28 132.62,18.29 132.62,18.29 132.62,19.34
Net_54: length 1.4
  BOTTOM w0.102: v2(71.18,78.85) 70.65,78.85 70,79.5
Net_57: length 0.8
  BOTTOM w0.254: v2(69.71,84.89) 69.71,84.81 69.2,84.3
Net_63: length 3.2
  BOTTOM w0.076: 118.81,100.24 118.59,100.46 118.59,100.69 118.3,100.98 117.72,100.98 117.65,101.05 117.37,101.05 117.02,101.39 117.02,101.78 v2(117.28,102.04)
Net_77: length 0.6
  BOTTOM w0.076: 151.63,96.82 151.84,96.82 152.08,97.06 v2(152.08,97.08)
Net_78: length 0.6
  BOTTOM w0.076: 151.63,97.47 151.9,97.47 152.08,97.64 v2(152.08,97.72)
Net_185: length 0.7
  BOTTOM w0.102: 62.2,91.3 62.53,91.3 v2(62.8,91.57)
Net_283: length 0.7
  BOTTOM w0.076: 156.14,91.07 156.31,91.07 v2(156.67,91.43)
Net_284: length 0.6
  BOTTOM w0.076: v2(150.94,82.35) 150.63,82.66 150.48,82.66
Net_285: length 0.6
  BOTTOM w0.076: v2(150.94,81.7) 150.63,82.01 150.48,82.01
Net_1689: length 0.5
  BOTTOM w0.102: v2(64.82,91.81) 64.52,92.1 64.4,92.1
Net_1803: length 0.5
  BOTTOM w0.076: 120.11,95.57 120.11,95.68 v2(119.81,95.98)
Net_1804: length 0.6
  BOTTOM w0.076: 120.76,97.21 v2(121.33,97.21)
Net_1805: length 0.5
  BOTTOM w0.076: v2(121.31,94.61) 120.76,94.61
Net_1806: length 0.5
  BOTTOM w0.076: 120.11,88.07 120.11,88.03 v2(120.44,87.7)
Net_1807: length 0.8
  BOTTOM w0.076: v2(121.54,89.46) 121.47,89.39 120.78,89.39 120.76,89.41
Net_1824: length 0.6
  BOTTOM w0.076: 126.67,80.06 126.57,80.06 v2(126.25,79.74)
Net_1825: length 0.9
  BOTTOM w0.076: v2(130.87,78.59) 130.57,78.9 130.57,79.41
Net_1826: length 0.5
  BOTTOM w0.076: v2(129.41,79.08) 129.74,79.41 129.82,79.41
Net_1833: length 0.6
  BOTTOM w0.076: v2(136.86,85.38) 137.12,85.12 137.32,85.12
Net_1836: length 0.8
  BOTTOM w0.076: 144.49,96.34 144.49,96.2 v2(144.04,95.75)
Net_1837: length 0.5
  BOTTOM w0.076: v2(145.3,94.61) 144.96,94.94 144.96,95.02
Net_1838: length 0.6
  BOTTOM w0.076: v2(144.08,95) 144.45,95.38 144.45,95.42
Net_1839: length 0.6
  BOTTOM w0.076: 144.45,92.17 144.45,92.21 v2(144.08,92.59)
Net_1840: length 0.8
  BOTTOM w0.076: v2(146.4,95.51) 146.39,95.52 146.39,96.34
Net_1845: length 0.5
  BOTTOM w0.076: 143.03,88.92 142.51,88.92 v2(142.5,88.92)
Net_1846: length 0.7
  BOTTOM w0.254: 145.2,87.75 145.47,88.02 145.47,88.19 v2(145.55,88.27)
Net_1850: length 0.6
  BOTTOM w0.076: 147.82,98.77 147.79,98.77 147.46,99.09 v2(147.39,99.09)
Net_1851: length 0.6
  BOTTOM w0.076: 146.87,98.77 146.82,98.77 v2(146.45,99.14)
Net_1852: length 0.6
  BOTTOM w0.076: 147.82,98.12 147.71,98.12 v2(147.39,98.44)
Net_1853: length 0.5
  BOTTOM w0.076: 146.87,98.12 146.68,98.12 v2(146.45,98.35)
Net_1856: length 1.2
  BOTTOM w0.076: v2(149.25,96.87) 149.25,96.83 149.74,96.34 150.2,96.34
Net_1857: length 0.7
  BOTTOM w0.076: v2(149.22,95.41) 149.7,95.89 149.73,95.89
Net_1860: length 0.6
  BOTTOM w0.076: v2(153.75,94.27) 153.5,94.01 153.5,93.79
Net_1862: length 0.5
  BOTTOM w0.076: v2(153.68,91.41) 153.5,91.23 153.5,90.94
Net_1863: length 1.1
  BOTTOM w0.076: v2(153.82,88.56) 153.82,88.91 154.19,89.28 154.19,89.53
Net_1867: length 0.5
  BOTTOM w0.076: v2(150.9,80.4) 150.59,80.71 150.48,80.71
Net_1880: length 0.5
  BOTTOM w0.076: v2(155.18,93.69) 155.49,93.38 155.49,93.32
Net_1881: length 2.3
  BOTTOM w0.076: v2(157.23,93.35) 157.23,93.19 156.94,92.9 156.46,92.9 156.33,93.02 155.95,93.02 155.94,93.01 155.94,93.01 155.49,92.57
Net_1882: length 2.2
  BOTTOM w0.076: v2(157.26,91.44) 156.72,90.9 156.39,90.9 156.26,90.78 155.78,90.78 155.49,91.07
Net_1888: length 3.5
  BOTTOM w0.076: 155.48,81.39 155.81,81.72 156.41,81.72 156.7,81.43 158.08,81.43 v2(158.55,80.95)
Net_1889: length 3
  BOTTOM w0.076: 155.48,80.73 155.8,81.04 156.3,81.04 156.83,80.51 157.47,80.51 v2(157.92,80.95)
NTC: length 4.8
  TOP w0.102: PR525.2 66.47,107.66 65.13,107.66 v1(64.75,108.04)
  TOP w0.254: PR525.2 67.24,108.13 67.49,108.39 67.49,108.54 68.12,109.17 68.15,109.17 68.27,109.29 PU501.5
OCP_L: length 165.7
  TOP w0.102: v2(52.51,108.01) 54.95,108.01 v1(55.92,107.03) 57.26,105.69 57.26,104.2 57.69,103.76 58.25,103.76 60.08,105.59 61.32,105.59 61.65,105.26 61.65,103.51 62.34,102.82 62.34,102.82 62.59,102.57 62.92,102.24 RV91.1 RV90.2
  IN1 w0.107: v2(52.55,32.57) 51.84,32.57 50.86,33.56 50.86,38.66 47.34,42.18 47.34,49.02 44.61,51.74 32.58,51.74 30.63,53.7 30.63,58.81 28.8,60.63 23.83,60.63 18.34,66.12 18.34,70.11 17.46,71 17.46,95.05 19.67,97.26 24.91,97.26 28.77,101.12 32.93,101.12 34.22,102.42 34.22,103.56 35.24,104.58 38.66,104.58 40.16,106.07 48.04,106.07 49.97,108.01 v2(52.51,108.01)
  BOTTOM w0.203: PU1000.4 62.13,33.46 62.36,33.22 62.36,32.62 62.59,32.39 PR1020.2 62.36,31.83 62.36,31.19 58.66,27.49 54.54,27.49 51.99,30.03 51.99,32.01 v2(52.55,32.57)
ODD_DA#: length 11.5
  IN2 w0.076: 158.68,94.47 156.67,94.47 v2(155.12,92.92)
  IN2 w0.107: 158.68,94.47 159.08,94.47 161.29,92.26 162.24,92.26 v2(162.48,92.5)
  BOTTOM w0.076: v2(162.48,92.5) v1(162.48,91.94) 162.6,91.81 162.74,91.81 ; v2(155.12,92.92) 155.12,92.96 154.84,93.24 UC1.T3
  BOTTOM w0.102: RP54.1 162.74,91.81
ODD_DETECT#: length 13.9
  IN2 w0.076: v2(153.05,92.37) 153.45,92.77 153.93,92.77 154.36,92.33 156.09,92.33 156.14,92.38 157.92,92.38 158.43,91.88 158.68,91.88
  IN2 w0.107: 158.68,91.88 159.57,91.88 161.47,89.97 161.93,89.97 v2(162.41,89.49)
  BOTTOM w0.076: UC1.V6 152.85,92.17 v2(153.05,92.37) ; 162.74,88.6 v1(162.44,88.6) 162.41,88.62 v2(162.41,89.49)
  BOTTOM w0.102: 162.74,88.6 163.02,88.6 163.44,89.02 RP37.1
ON/OFFBTN#: length 181
  TOP w0.102: v2(172.86,28.3) 172.86,28.3 173.87,28.3 177.12,31.54 177.12,34.79 180.22,37.89 183.56,37.89 184.59,38.92 184.59,42.6 185.58,43.59 185.58,49.5 183.34,51.74 182.81,51.74 181.07,53.48 181.07,64.7 182.49,66.12 182.49,75.79 179.83,78.46 179.83,82.26 182.71,85.15 185.98,85.15 188.78,87.94 188.78,93.37 185.45,96.7 183.7,96.7 183.51,96.89 180.08,96.89 179.32,97.65 179.32,98.63 v4(180.02,99.33) 180.93,100.25 180.93,110.27 176.68,114.52 SW1.4 175.72,116.87 v2(175.7,116.84) 172.31,116.84 SW1.3 ; v2(138.11,13.3) 138.11,16.39 138.28,16.57 138.28,18.39 138.22,18.46 UE1.114
  IN1 w0.107: v2(138.11,13.3) 138.7,12.71 143.89,12.71 144.33,13.15 144.33,13.36 144.61,13.64 145.47,13.64 146.34,12.77 150.76,12.77 151.12,12.41 157.47,12.41 158.02,11.86 159.01,11.86 159.37,11.5 162.71,11.5 164.47,13.26 164.47,15.36 167.19,18.08 167.19,19.49 168.18,20.48 168.18,23.97 169.91,25.71 170.15,25.71 172.74,28.3 v2(172.86,28.3)
  BOTTOM w0.102: RE49.1 CE20.1 173.24,121.37 175.72,118.88 DE2.3 175.72,116.87 v2(175.7,116.84)
PACIN#: length 1.1
  TOP w0.102: RV147.2 v1(78.52,97.16)
PANEL_BKLEN: length 191.6
  TOP w0.076: v2(151.19,103.69) 153.24,103.69 154.62,105.06 154.62,107.24 157.03,109.66 158.45,109.66 160.41,111.61 160.99,112.2
  TOP w0.102: 160.99,112.2 v1(163.8,115) 164.67,115.88 172.01,115.88 174.55,113.34 175.44,113.34 176.14,112.64 178.17,112.64 180.68,110.14 180.68,100.54 179,98.86 179,97.59 179.93,96.66 183.36,96.66 183.57,96.45 185.38,96.45 187.79,94.04 187.79,87.33 185.86,85.4 182.57,85.4 179.6,82.43 179.6,78.32 182.26,75.66 182.26,66.21 180.84,64.79 180.84,53.33 182.68,51.49 183.27,51.49 185.35,49.41 185.35,43.74 184.33,42.73 184.33,39.01 183.44,38.12 180.07,38.12 176.87,34.92 176.87,31.61 173.96,28.71 v2(173.46,28.71) ; v2(143.85,13.21) 143.85,13.02 144.85,12.02 144.85,10.49 145.64,9.71 UE1.76
  IN1 w0.107: v2(143.85,13.21) 143.85,13.52 144.23,13.9 145.65,13.9 146.54,13.01 150.87,13.01 151.22,12.66 157.66,12.66 157.72,12.6 162.86,12.6 164.03,13.76 164.03,15.3 166.93,18.21 166.93,19.61 167.92,20.6 167.92,24.05 172.58,28.71 v2(173.46,28.71)
  BOTTOM w0.076: UC1.A9 150.69,102.43 150.88,102.62 150.88,103.26 151.19,103.56 v2(151.19,103.69)
PBTN_OUT#: length 198.4
  TOP w0.076: 160.9,68.25 160.9,68.55 160.75,68.7 160.75,69.49 160.37,69.87 v2(160.37,70.5)
  TOP w0.102: UE1.106 141.42,20.13 141.27,20.28 141.27,20.72 141.61,21.06 141.61,21.92 141.86,22.17 141.86,23.03 v2(142.27,23.44) 142.27,24.79 142.55,25.07 v2(142.8,25.07) ; RC49.1 96.48,74.32 97.15,73.65 97.15,68.74 92.94,64.53 92.94,58.63 90.99,56.68 v1(90.99,52.53) 88.58,50.12 88.58,38.61 89.57,37.62 v2(89.57,37.39) ; 160.9,68.25 160.9,67.3 163.42,64.79 163.51,64.79 165.58,62.72 165.58,62.2 168.8,58.97 168.8,43.12 167.47,41.79 167.47,39.58 166.85,38.96 v2(166.72,38.96)
  IN1 w0.076: 154.99,79.77 154.77,79.77 152.38,82.16 152.38,85.69 152.38,85.69 152.42,85.73 v2(152.42,85.73)
  IN1 w0.107: 154.99,79.77 155.21,79.54 156.15,79.54 160.15,75.54 160.15,70.72 v2(160.37,70.5) ; v2(153.47,36.77) 153.1,36.77 152.71,36.38 152.71,28.12 151.95,27.36 150.93,27.36 150.17,26.6 145.34,26.6 144.96,26.22 143.57,26.22 142.8,25.46 v2(142.8,25.07)
  IN2 w0.107: v2(89.57,37.39) 96.76,37.39 108.55,25.61 113.09,25.61 114.38,24.31 117.25,24.31 118.82,22.74 126,22.74 127.34,24.09 136.4,24.09 136.64,23.85 141.86,23.85 v2(142.27,23.44)
  BOTTOM w0.076: v2(152.42,85.73) 152.42,85.73 152.42,85.28 UC1.AL7
  BOTTOM w0.102: v2(153.47,36.77) 155.42,36.77 155.68,36.5 158.77,36.5 159.23,36.96 162.06,36.96 162.91,37.81 164.45,37.81 165.59,38.96 v2(166.72,38.96)
PC_BEEP: length 4.6
  TOP w0.102: v1(188.68,14.3) 189.11,14.74 RA19.1
  TOP w0.254: RA19.1 RA79.2 190.56,15.57 190.65,15.66 DA8.1
PCC_GPIO_6: length 15
  TOP w0.102: v1(61.91,99.88) RV90.1 CVT90.2 60.89,100.26 v2(61.02,100.13)
  IN1 w0.102: v2(62.92,89.97) 62.67,89.97 62.29,90.35 62.29,92.13 62.92,92.77 62.92,97.08 62.29,97.72
  IN1 w0.107: v2(61.02,100.13) 61.45,99.7 61.45,98.56 62.29,97.72
  BOTTOM w0.102: v2(62.92,89.97) 63.4,90.45 UV1.T8
PCH_AUDIO_EN: length 4.4
  BOTTOM w0.076: UC1.P1 156.36,94.07 156.84,94.54 v1(159.11,94.54) 159.85,93.81 RC116.1
PCH_AZ_BITCLK: length 102
  IN2 w0.107: v2(171.51,55.48) 171.54,55.48 172.98,54.04 172.98,45.56 173.25,45.28 173.25,34.68 172.29,33.71 172.29,31.19 172.03,30.93 172.03,27.09 172.93,26.19 172.93,24.92 173.79,24.06 v2(173.79,23.3)
  BOTTOM w0.076: UC1.AW8 151.26,80.06 150.99,79.79 150.99,77.02 151.31,76.69 151.31,72.95 151.57,72.7 151.57,71.81
  BOTTOM w0.102: 151.57,71.81 151.57,66.63 153.88,64.32 160.46,64.32 162.54,62.23 164.12,62.23 168.46,57.89 168.46,57.59 170.57,55.48 v2(171.51,55.48) ; v2(173.79,23.3) 175.77,23.3 178.18,20.88 183.95,20.88 185.4,19.44 185.4,19.06 v1(187.37,17.1) 187.37,17.1 187.37,16.95 190.19,14.12 190.19,13.69 190.4,13.47 190.4,12.17 191.06,11.51 191.39,11.51 191.75,11.87 193.6,11.87 194.24,12.5 194.82,12.5 R2359.2
PCH_AZ_CODEC_BITCLK: length 3.9
  BOTTOM w0.102: RA1112.1 197.03,15.55 196.73,15.86 UA1.6 ; RA1112.1 CC5.1 ; RA1112.1 R2359.1
PCH_AZ_CODEC_RST#: length 3.6
  BOTTOM w0.102: UA1.11 194.73,15.9 194.5,15.68 194.49,15.68 193.99,15.17 193.48,15.17 193.17,14.86 RA6.1 R2358.1
PCH_AZ_CODEC_SDIN0: length 99.9
  IN2 w0.107: v2(173.16,23.3) 173.16,23.93 172.35,24.74 172.35,25.79 171.54,26.59 171.54,31.15 171.8,31.41 171.8,34.47 172.77,35.44 172.77,44.45 172.49,44.73 172.49,53.84 171.57,54.75 v2(171.51,54.75)
  BOTTOM w0.076: UC1.AY10 150.68,79.25 150.68,72.95 151.06,72.57 151.06,71.81
  BOTTOM w0.102: v2(171.51,54.75) 170.4,54.75 167.95,57.21 167.95,57.59 163.79,61.75 162.26,61.75 160.33,63.68 153.73,63.68 151.06,66.35 151.06,71.81 ; RA130.1 194.32,13.01 193.99,13.01 193.33,12.35 192.17,12.35 191.3,13.21 191.3,13.29 190.69,13.91 190.69,14.31 v1(188.55,16.45) 187.88,17.12 187.88,17.27 185.91,19.24 185.91,19.69 184.21,21.39 178.36,21.39 175.95,23.8 173.67,23.8 v2(173.16,23.3)
PCH_AZ_CODEC_SDOUT: length 2.2
  TOP w0.102: v2(197.54,15.3) 197.03,14.79 R2356.1
  BOTTOM w0.102: v2(197.54,15.3) 197.54,15.42 197.13,15.84 UA1.5
PCH_AZ_CODEC_SYNC: length 2.3
  BOTTOM w0.102: R2357.1 194.04,14.74 195.13,15.83 UA1.10
PCH_AZ_RST#: length 95.7
  IN2 w0.107: v2(173.79,24.82) 173.53,25.09 173.53,27.36 173.88,27.71 173.88,29.12 172.72,30.28 172.72,30.93 172.77,30.99 172.77,33.51 173.74,34.47 173.74,45.48 173.46,45.76 173.46,54.24 171.51,56.19 v2(171.51,56.44)
  BOTTOM w0.076: UC1.AU8 151.65,81.01 151.65,80.62 151.56,80.52 151.56,78.68 152.2,78.03 152.2,75.62 152.33,75.49 152.33,73.21 152.58,72.95 152.58,71.81
  BOTTOM w0.102: v2(173.79,24.82) 176.29,24.82 178.71,22.41 184.71,22.41 187.1,20.02 187.1,19.43 v1(188.43,18.1) 189.12,17.41 189.12,17.3 191.7,14.72 191.7,14.33 R2358.2 ; v2(171.51,56.44) 171.25,56.44 169.47,58.22 169.47,58.48 164.75,63.2 163.1,63.2 160.71,65.59 154.11,65.59 152.58,67.11 152.58,71.81
PCH_AZ_SDOUT: length 110
  TOP w0.102: RC8.2 195.99,12.76 v2(196.04,12.7) 196.5,12.25 RC3.2 196.96,12.53 197.03,12.6 R2356.2
  IN2 w0.107: v2(173.16,22.66) 171.81,24.01 171.81,25.56 171.05,26.31 171.05,31.38 171.31,31.63 171.31,34.67 172.28,35.64 172.28,44.25 172,44.53 172,53.64 171.55,54.08 v2(171.51,54.08)
  BOTTOM w0.076: 150.55,71.81 150.55,72.57 150.4,72.72 150.4,79.1 150.24,79.26 150.24,80.52 150.1,80.66 150.1,80.97 149.81,81.27 UC1.AU11
  BOTTOM w0.102: v2(173.16,22.66) 175.72,22.66 178.01,20.38 183.7,20.38 184.87,19.21 184.87,18.77 v1(185.55,18.09) 186.28,17.37 186.28,16.89 186.51,16.66 186.91,16.66 189.69,13.88 189.69,13.44 189.92,13.2 189.92,11.83 190.02,11.73 190.02,10.51 190.85,9.68 192.23,9.68 194.54,11.99 195.33,11.99 v2(196.04,12.7) ; 150.55,71.81 150.55,65.97 153.35,63.17 160.08,63.17 161.98,61.27 163.38,61.27 167.44,57.21 167.44,56.95 170.31,54.08 v2(171.51,54.08)
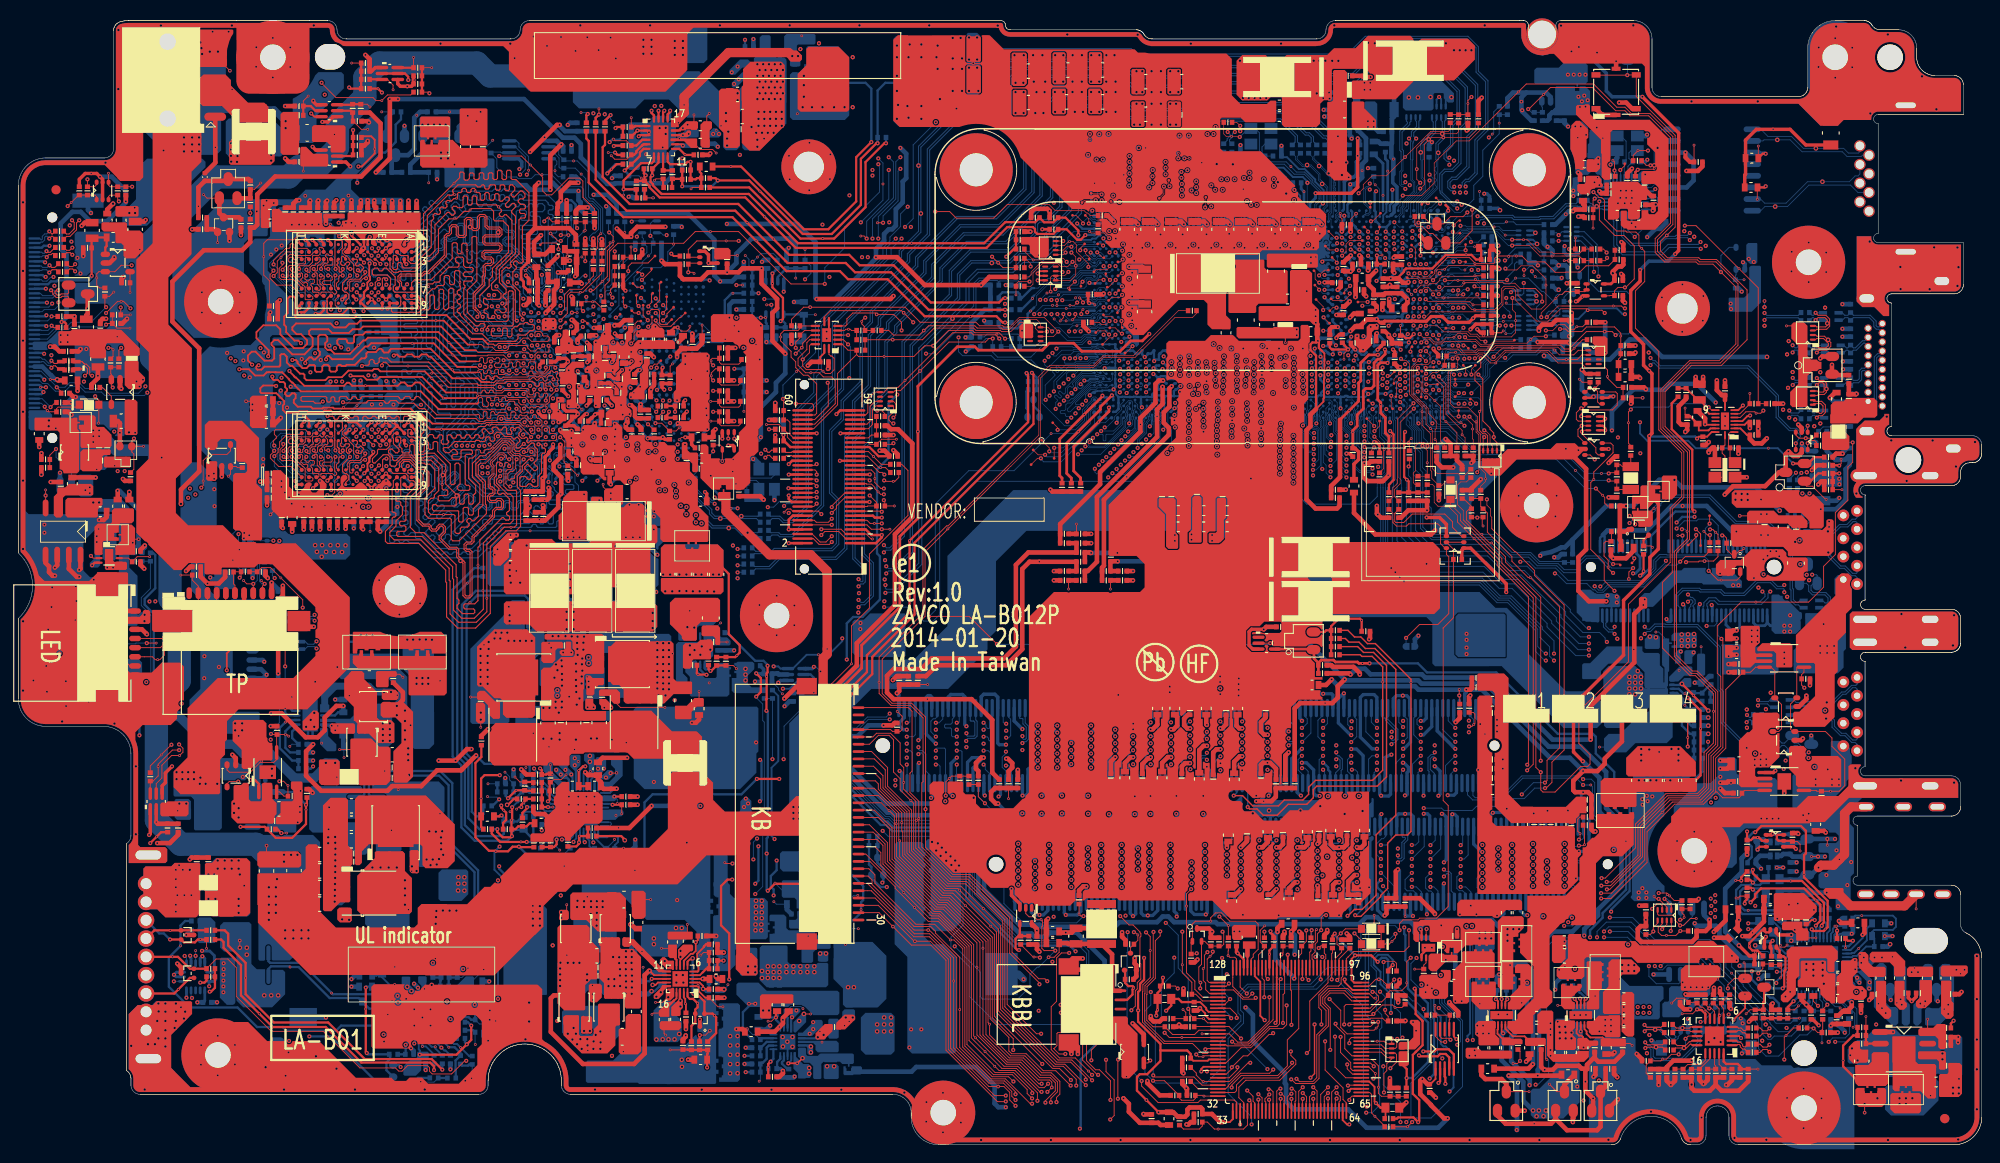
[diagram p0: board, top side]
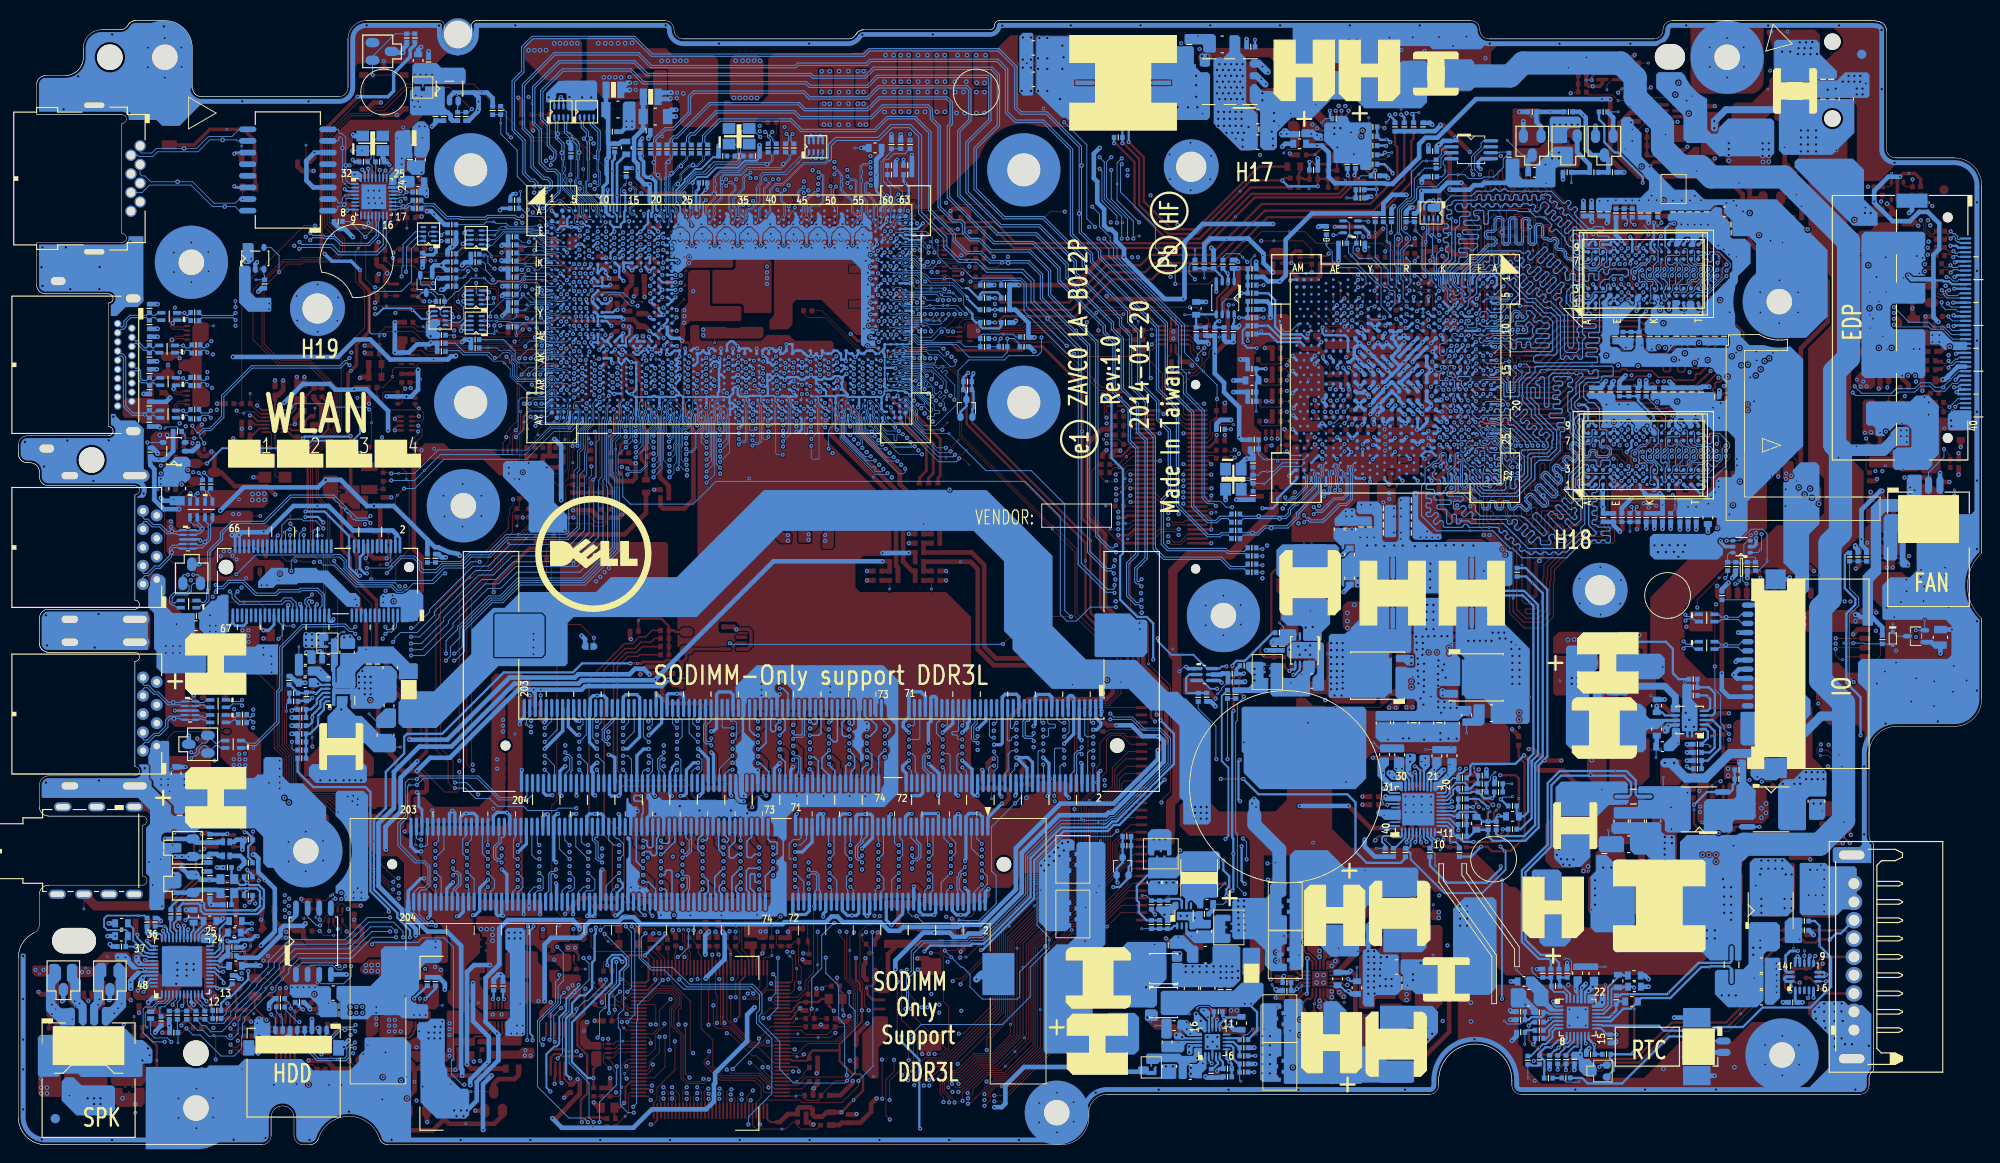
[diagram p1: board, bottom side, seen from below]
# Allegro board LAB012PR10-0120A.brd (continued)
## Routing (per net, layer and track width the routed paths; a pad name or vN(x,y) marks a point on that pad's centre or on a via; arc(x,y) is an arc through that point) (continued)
PCH_AZ_SYNC: length 102.5
  IN2 w0.107: v2(172.4,22.66) 171.3,23.75 171.3,25.35 170.57,26.09 170.57,31.63 170.82,31.88 170.82,34.88 171.79,35.84 171.79,42.78 171.29,43.28 171.29,46.68 171.47,46.86 171.47,53.39 v2(171.51,53.43)
  BOTTOM w0.076: UC1.AV11 150.05,80.47 150.05,79.2 150.17,79.07 150.17,71.94 150.04,71.81
  BOTTOM w0.102: v2(172.4,22.66) 172.4,23.3 173.41,24.31 176.12,24.31 178.53,21.9 184.46,21.9 186.47,19.89 186.47,19.36 v1(187.09,18.74) 188.36,17.47 188.36,17.32 191.2,14.48 191.2,14.12 191.76,13.57 191.76,13.46 191.96,13.26 193.53,13.26 193.96,13.69 R2357.2 ; v2(171.51,53.43) 170.07,53.43 166.93,56.57 166.93,56.95 163.11,60.78 161.71,60.78 159.95,62.54 153.09,62.54 150.04,65.59 150.04,71.81
PCH_BATLOW#: length 9.4
  TOP w0.076: v2(154.52,83.92) 155.63,82.81 155.63,79.25 v1(155.9,78.99) 157.1,77.79 RC31.2
  BOTTOM w0.076: v2(154.52,83.92) 154.19,83.58 UC1.AN4
PCH_DPWROK: length 125.2
  TOP w0.076: RC33.1 152.53,72.11 152.33,72.32 152.33,73.37 152.56,73.6 152.56,76.32 152.98,76.74 153.47,76.74 v2(153.88,76.33)
  TOP w0.102: v2(131.16,24.92) v1(132.14,23.94) RE37.1
  IN2 w0.076: v2(153.88,76.33) 153.88,76.08 158.2,71.76 158.44,71.76 158.76,71.45 159.44,71.45
  IN2 w0.107: v2(131.16,24.92) 131.38,24.7 136.66,24.7 136.9,24.46 151.52,24.46 152.86,23.13 153.03,23.13 153.27,22.89 156.12,22.89 157.39,21.62 162.57,21.62 163.57,22.62 169.13,22.62 170.09,21.67 173.55,21.67 174.98,23.1 174.98,45.62 174.44,46.16 174.44,54.65 171.26,57.83 171.26,59.44 171.21,59.48 171.21,59.49 168.59,62.11 168.59,64.95 166.94,66.6 164.78,66.6 162.77,68.61 162.77,69.6 160.92,71.45 159.44,71.45
  BOTTOM w0.076: v2(153.88,76.33) 153.88,76.8 153.47,77.21 153.47,78.03 153.27,78.24 153.27,78.99 153.06,79.2 153.06,80.29 UC1.AV5
PCH_DSW_EN: length 31.2
  TOP w0.102: v2(153.79,23.57) 153.79,23.47 153.78,23.47 153.73,23.42 U2408.3 ; UE1.1 130.05,17.71 129.83,17.94 129.83,20.27 v1(130.14,20.59) 130.44,20.88 v2(130.44,21.09)
  IN1 w0.107: v2(130.44,21.09) 130.44,21.34 130.94,21.85 136.35,21.85 136.66,22.15 141,22.15 141.18,22.33 142.8,22.33 143.83,21.3 149.52,21.3 150.76,22.53 153.06,22.53 153.79,23.26 v2(153.79,23.57)
PCH_GPIO9: length 9.5
  TOP w0.076: v2(155.14,83.94) 155.14,83.84 155.89,83.1 155.89,79.81 157.66,78.03 v1(157.66,77.55) 157.99,77.23 RC125.2
  BOTTOM w0.076: v2(155.14,83.94) 154.84,84.24 UC1.AM3
PCH_GPIO12: length 1.1
  TOP w0.076: T182.1 153.2,84.48 152.83,84.86 v2(152.83,84.87)
  BOTTOM w0.076: v2(152.83,84.87) 152.56,84.61 UC1.AM7
PCH_GPIO14: length 2
  TOP w0.076: v2(153.71,85.6) 153.12,86.19 T126.1
  BOTTOM w0.076: UC1.AH4 154.19,86.31 153.71,85.83 v2(153.71,85.6)
PCH_GPIO25: length 5.5
  TOP w0.076: v2(158.04,84.13) 158.04,84.89 T127.1
  BOTTOM w0.076: UC1.AM4 154.48,84.66 154.96,84.66 155,84.62 155.79,84.62 155.95,84.78 157.01,84.78 157.28,84.51 157.66,84.51 v2(158.04,84.13)
PCH_GPIO35: length 11.1
  TOP w0.076: v2(157.79,92.89) 157.74,92.84 v1(157.18,92.84)
  IN2 w0.076: v2(157.79,92.89) 158.36,92.32 158.68,92.32
  IN2 w0.107: 158.68,92.32 160.14,92.32 160.71,91.75 162.36,91.75 163.38,90.73 163.38,89.82 v2(163.05,89.49)
  BOTTOM w0.076: UC1.U1 157.47,92.57 v2(157.79,92.89)
  BOTTOM w0.102: v2(163.05,89.49) 163.79,89.49 RP37.2
PCH_GPIO37: length 7.9
  BOTTOM w0.076: UC1.AC1 156.14,89.58 156.39,89.83 160.62,89.83 160.74,89.95 v1(162.16,89.95) 162.21,90 162.74,90
  BOTTOM w0.102: 162.74,90 163.8,90 RP37.3
PCH_GPIO44: length 12.5
  BOTTOM w0.076: UC1.AK4 154.48,86.15 154.96,86.15 155,86.12 155.79,86.12 155.95,86.28 156.27,86.28 156.4,86.41 157.39,86.41 157.54,86.26 157.54,85.59 157.73,85.4 158.77,85.4
  BOTTOM w0.102: RC104.1 161.4,87.94 v1(160.6,87.14) 160.15,86.69 160.15,85.78 159.77,85.4 158.77,85.4
PCH_GPIO46: length 17.8
  TOP w0.076: 168.59,86.67 168.13,87.13 161.47,87.13 161.09,86.75 159.42,86.75 159.19,86.52 157.61,86.52 157.21,86.92 155.22,86.92 v2(155.14,87)
  TOP w0.102: 168.59,86.67 169.55,86.67 v1(169.89,87.01) 170.82,87.94 RC124.2
  BOTTOM w0.076: UC1.AG3 154.84,87.31 155.14,87.01 v2(155.14,87)
PCH_GPIO47: length 1.2
  TOP w0.076: v2(152.95,90.47) 152.95,90.6 T174.1
  BOTTOM w0.076: v2(152.95,90.47) 152.85,90.37 UC1.AB6
PCH_GPIO48: length 5.1
  BOTTOM w0.076: UC1.U4 154.47,92.25 154.89,92.25 155.02,92.11 155.68,92.11 155.83,92.26 157.99,92.26 T124.1
PCH_GPIO49: length 3.9
  BOTTOM w0.076: T125.1 157.71,90.74 156.45,90.74 156.33,90.61 155.71,90.61 155.66,90.66 155.32,90.66 154.94,91.03 UC1.Y3
PCH_GPIO56: length 16.5
  TOP w0.076: v2(153.21,87.64) 153.57,88.01 154.03,88.01 154.57,87.47 155.45,87.47 155.73,87.76 159.11,87.76 159.67,87.2 160.89,87.2 161.25,87.56 164.75,87.56 v1(165.16,87.96) 165.51,88.32 v2(166.81,88.32)
  BOTTOM w0.076: v2(153.21,87.64) 153.2,87.64 153.2,87.65 152.85,87.3 UC1.AG6
  BOTTOM w0.102: v2(166.81,88.32) 166.93,88.45 RC9.1
PCH_GPIO66: length 8.3
  BOTTOM w0.076: UC1.D3 155.17,99.67 155.59,99.67 155.8,99.87 155.8,100.3 156,100.51 156.3,100.51 157.2,101.4 158.22,101.4 158.26,101.44
  BOTTOM w0.102: v1(159.57,104.14) 159.57,103.61 159.75,103.43 RC122.1 RC118.2 159.5,102.29 158.65,101.44 158.26,101.44
PCH_GPIO83: length 2.2
  TOP w0.076: v2(153.13,94.28) 152.79,94.62 151.77,94.62 T177.1
  BOTTOM w0.076: v2(153.13,94.28) 152.85,94 UC1.R6
PCH_GPIO84: length 2.9
  TOP w0.076: v2(152.53,96.2) 152.58,96.25 152.58,97.84 T176.1
  BOTTOM w0.076: UC1.L6 152.85,95.88 v2(152.53,96.2)
PCH_GPIO85: length 2.2
  TOP w0.076: v2(153.03,95.22) 153.4,94.85 153.9,94.85 T175.1
  BOTTOM w0.076: v2(153.03,95.22) 152.85,95.05 UC1.N6
PCH_GPIO89: length 12
  TOP w0.076: T178.1 v2(147.63,102.93)
  IN1 w0.076: 150.2,101.88 151.69,100.39 151.69,97.46 151.44,97.21 151.44,96.07 151.82,95.69 151.95,95.69 v2(152.46,95.18)
  IN1 w0.107: v2(147.63,102.93) 149.15,102.93 150.2,101.88
  BOTTOM w0.076: UC1.N7 152.2,94.92 v2(152.46,95.18)
PCH_GPIO90: length 2.9
  TOP w0.076: T179.1 v2(157.41,96.45)
  BOTTOM w0.076: v2(157.41,96.45) 157.03,96.83 156.55,96.83 156.33,96.61 155.79,96.61 UC1.K2
PCH_GPIO93: length 3.4
  TOP w0.076: v2(158.04,97.72) 158.04,98.23 T180.1
  BOTTOM w0.076: v2(158.04,97.72) 157.98,97.66 157.1,97.66 156.81,97.37 155.79,97.37 UC1.J2
PCH_GPIO94: length 2.4
  BOTTOM w0.076: T181.1 157.42,98.34 157.22,98.34 156.7,97.81 UC1.G1
PCH_HOT#: length 9.7
  TOP w0.076: R2330.2 158.88,77.04 158.81,77.11 v1(158.81,78.19) 158.81,78.65 v2(157.91,79.55)
  BOTTOM w0.076: UC1.AU4 154.16,81.19 154.45,80.91 154.45,80.5 154.56,80.39 154.97,80.39 155.15,80.21 155.15,79.6 155.2,79.54 155.2,79.2 155.48,78.93 157.29,78.93 v2(157.91,79.55)
PCH_INTVRMEN: length 44.4
  TOP w0.102: v2(174.15,62.46) 174.1,62.46 173.62,62.95 v1(173.62,63.1) 173.62,63.85 173.16,64.31 173.16,65.71 173.36,65.92 RC2.1 173.97,65.97 RC1.2
  BOTTOM w0.076: UC1.AV7 151.98,80.6 151.74,80.36 151.74,79.14 151.95,78.92 151.95,78.54 152.46,78.03 152.46,75.75 152.58,75.62 152.58,73.72 153.12,73.18 153.12,71.81
  BOTTOM w0.102: 153.12,71.81 153.12,67.34 154.36,66.1 160.94,66.1 162.85,64.19 164.93,64.19 165.87,63.25 168,63.25 168.76,62.49 170.31,62.49 170.62,62.79 170.62,63.43 171.25,64.06 172.55,64.06 v2(174.15,62.46)
PCH_JTAG_JTAGX: length 14.3
  BOTTOM w0.076: UC1.AE63 117.44,88.18 116.63,88.18 116.08,87.63 111.51,87.63 111.05,87.18 110.93,87.18
  BOTTOM w0.102: 110.93,87.18 RC59.1 RC62.2 109.35,88.35 109.15,88.55 v1(106.86,88.55) 105.77,88.55 105.47,88.24 RC130.1
PCH_JTAG_RST#: length 39.1
  TOP w0.076: RC57.2 R2341.2 108.13,95.81
  TOP w0.102: v2(106.33,97.01) v4(106.99,96.35) 107.52,95.81 108.13,95.81
  IN1 w0.107: v2(106.33,97.01) 102.67,93.35 v2(102.67,88.19)
  BOTTOM w0.076: 110.93,85.41 111.79,84.55 111.79,81 114.26,78.54 115.55,78.54 116.19,79.18 116.19,80.29 116.6,80.7 116.6,80.75 117.19,81.34 117.19,81.5 117.38,81.68 117.64,81.68 117.95,81.37 UC1.AU62
  BOTTOM w0.102: v2(102.67,88.19) 102.67,86.63 103.1,86.2 106.24,86.2 106.71,85.73 110.61,85.73 110.93,85.41
PCH_JTAG_TCK: length 30
  TOP w0.102: v2(106.41,88.07) 105.97,88.07 105.59,87.69 101.63,87.69 v4(98.47,84.52) 96.32,82.38 95.74,82.38 95.57,82.21 RP46.4
  BOTTOM w0.076: 110.93,86.4 111.96,87.43 116.19,87.43 116.77,88.02 117.21,88.02 117.4,87.83 117.6,87.83 117.73,87.89 117.94,87.89 UC1.AE62
  BOTTOM w0.102: RC135.1 105.04,87.43 105.67,88.07 v2(106.41,88.07) RC65.2 106.41,86.57 106.94,86.03 110.56,86.03 110.93,86.4
PCH_JTAG_TDI: length 27.8
  TOP w0.076: 108.13,89.08 108.26,89.08 109.33,90.15 111.21,90.15 111.63,89.73 RP48.8 112.44,89.3 v2(112.88,88.85)
  TOP w0.102: 108.13,89.08 107.5,89.08 107.37,89.21 104.7,89.21 104.45,89.46 99.4,89.46 v4(98.88,88.94) 98.38,88.45 95.56,88.45 95.05,88.96 RC44.1
  BOTTOM w0.076: v2(112.88,88.85) 113.26,89.23 113.72,89.23 114.75,88.21 116.08,88.21 116.38,88.51 117.04,88.51 117.09,88.57 117.63,88.57 117.8,88.74 117.8,88.92 118.04,89.15 118.56,89.15 UC1.AD61
PCH_JTAG_TDO: length 30.1
  TOP w0.076: v2(112.32,88.83) 112.3,88.8 RP48.7 111.44,88.8 111.05,89.18 111.05,89.59 110.8,89.84 109.4,89.84 108.39,88.83 108.13,88.83
  TOP w0.102: 108.13,88.83 107.37,88.83 107.24,88.96 104.58,88.96 104.32,89.21 100.01,89.21 98.74,87.94 v4(95.48,87.94) RC63.2 RC43.1
  IN1 w0.076: v2(118.51,88.49) 117.66,89.34 112.83,89.34 v2(112.32,88.83)
  BOTTOM w0.076: v2(118.51,88.49) 118.81,88.19 UC1.AE61
PCH_JTAG_TMS: length 39.9
  TOP w0.076: 108.13,89.34 108.26,89.34 109.3,90.38 112.02,90.38 v2(113.57,88.83) 113.04,88.3 RP48.6
  TOP w0.102: 108.13,89.34 107.63,89.34 107.5,89.46 104.96,89.46 104.58,89.84 98.48,89.84 96.83,91.5 v4(86.47,91.5) 85.76,91.5 84.44,90.17 RC46.1
  BOTTOM w0.076: UC1.AD62 117.97,88.67 117.7,88.4 117.42,88.4 117.42,88.4 117.16,88.4 117.1,88.35 116.49,88.35 116.01,87.86 114.53,87.86 v2(113.57,88.83)
PCH_OPI_COMP: length 7.6
  TOP w0.076: RC101.1 149.08,73.84 149.08,76.35 v2(148.08,77.35)
  BOTTOM w0.076: v2(148.08,77.35) 147.68,77.75 147.68,79.1 147.81,79.23 147.81,79.64 147.7,79.75 147.52,79.93 UC1.AW15
PCH_PCIE_RCOMP: length 3.2
  BOTTOM w0.305: UC1.A27 140.39,102.13 v1(140.39,104.12) 140.09,104.42 RC91.2
PCH_PLTRST#: length 24.4
  TOP w0.076: 168.59,92.89 168.33,92.89 v1(167.9,92.46) 166.3,90.86 v2(166.3,90.4)
  TOP w0.102: UC3.1 UC3.2 171.06,93.2 CC33.1 168.89,93.2 168.59,92.89
  IN2 w0.076: 158.68,88.32 158.43,88.32 158.04,88.7 156.01,88.7 155.38,88.07 152.95,88.07 152.54,87.65 v2(152.54,87.66)
  IN2 w0.107: 158.68,88.32 160.2,88.32 161.02,87.51 164.6,87.51 165.28,88.19 165.28,89.46 166.17,90.35 166.25,90.35 v2(166.3,90.4)
  BOTTOM w0.076: UC1.AG7 152.2,87.32 v2(152.54,87.66)
PCH_PWR_EN: length 40.3
  TOP w0.102: RE36.1 141.15,23.36 v2(141.23,23.44) ; R416.1 163.99,10.16 v2(163.99,9.15) 163.71,8.87 v1(163.23,8.87)
  IN1 w0.107: v2(152.69,20.4) 152.2,20.88 151.75,20.88 150.96,20.1 149.95,20.1 149.39,19.53 143.37,19.53 v2(142.39,20.51)
  IN2 w0.107: v2(155.5,9.43) 155.73,9.43 157.23,7.93 162.03,7.93 163.25,9.15 v2(163.99,9.15)
  BOTTOM w0.102: v2(152.69,20.4) 152.08,19.79 152.08,18.01 154.26,15.83 154.26,14.56 154.97,13.85 154.97,9.96 v2(155.5,9.43) ; v2(142.39,20.51) 142.27,20.51 141.23,21.55 v2(141.23,23.44)
PCH_PWROK: length 209.6
  TOP w0.102: v2(123.91,6.99) 125.15,6.99 RE18.1 126.75,5.14 127.03,4.86 128.33,4.86 128.53,5.06 CE31.1 129.39,5.39 v1(129.47,5.31) UE1.32 ; v2(145.91,23.08) 146.68,22.31 DE4.2
  IN1 w0.107: v2(177.12,75.54) 176.66,76 176.66,79.44 176.79,79.57 176.79,81.5 175.99,82.3 175.99,88.68 173.92,90.75 173.92,94.04 173.36,94.6 173.36,95.34 172.74,95.97 172.29,95.97 168.89,99.37 v2(168.2,99.37)
  IN2 w0.107: v2(123.67,16.68) 123.9,16.45 125.88,16.45 126.33,16 129.76,16 130.23,15.53 132.98,15.53 133.34,15.89 134.23,15.89 134.71,15.41 136.58,15.41 137.12,15.96 138.91,15.96 139.16,15.7 141.62,15.7 141.87,15.45 146.53,15.45 147.18,16.1 150.89,16.1 151.55,15.44 155.45,15.44 156.17,14.72 160.09,14.72 160.17,14.64 166.2,14.64 166.71,15.15 168.74,15.15 169.12,15.52 172.23,15.52 172.91,16.2 176.69,16.2 178.14,17.66 178.14,18.68 177.61,19.2 177.61,23.83 178.16,24.39 178.16,24.87 178.01,25.03 178.01,26 178.19,26.18 178.19,28.24 176.98,29.46 176.98,35.83 180.5,39.35 181.95,39.35 182.95,40.36 182.95,42.18 181.89,43.24 181.89,47.38 179.7,49.57 179.7,56.46 179.11,57.06 179.11,62.04 177.84,63.3 177.84,74.82 v2(177.12,75.54)
  BOTTOM w0.102: CC34.1 167.98,99.62 168.2,99.39 v2(168.2,99.37) 168.58,99.75 RP50.3 169.48,99.75 169.6,99.62 169.6,99.37 169.47,99.24 169.03,99.24 RP50.2 ; v2(123.67,16.68) 123.66,16.68 123.66,16.69 123.65,16.69 123.65,16.69 123.67,16.69 123.67,15.27 123.03,14.63 123.03,7.87 v2(123.91,6.99) 124.16,6.73 129.73,6.73 131.25,8.25 131.25,11.25 133.5,13.5 133.5,14.08 133.19,14.39 133.19,16.51 134.21,17.53 141.13,17.53 142.97,19.37 145.27,19.37 146.36,20.46 146.36,22.63 v2(145.91,23.08)
PCH_PWROK_R: length 80.9
  TOP w0.102: v2(176.33,63) 176.31,63 175.88,62.56 v4(175.88,61.8)
  IN1 w0.107: v2(172.07,95.36) 172.78,95.36 172.98,95.15 172.98,93.12 173.67,92.43 173.67,90.31 175.76,88.22 175.76,82.2 176.52,81.44 176.52,79.91 176.43,79.81 176.43,75.65 177.51,74.57 177.51,65.91 177.22,65.62 177.22,63.89 v2(176.33,63)
  BOTTOM w0.076: UC1.AY7 152.13,79.29 152.13,78.6 152.71,78.01 152.71,76 153.09,75.62 153.09,73.72 153.37,73.44 153.37,71.81
  BOTTOM w0.102: v2(176.33,63) 174,63 172.68,64.32 171.13,64.32 170.36,63.56 170.36,63.02 170.16,62.82 168.81,62.82 168.15,63.48 166.05,63.48 165.08,64.44 162.97,64.44 161.07,66.35 154.49,66.35 153.37,67.47 153.37,71.81 ; v2(172.07,95.36) 172.01,95.41 172.01,98.04 170.81,99.25 RP50.7
PCH_RSMRST#_R: length 8.7
  TOP w0.076: RC33.2 RC41.2 v1(153.85,74.5) 153.85,75.84 v2(153.33,76.36)
  BOTTOM w0.076: UC1.AW6 152.48,79.78 152.48,78.71 153.22,77.97 153.22,76.47 v2(153.33,76.36)
PCH_RTCRST#: length 37.1
  TOP w0.076: 150.11,68.25 150.11,68.98 CC4.2 RC6.2 150.11,70.77 150.11,71.76 150.61,72.26 150.61,79.25 v2(152.35,81)
  TOP w0.102: v2(151.54,55.36) 153,56.82 155.01,56.82 156.2,58.02 156.2,64.22 155.95,64.48 QC2.6 155.8,65.17 155.31,65.66 155.31,67.52 155,67.83 151.83,67.83 151.58,67.58 150.5,67.58 150.11,67.97 150.11,68.25
  BOTTOM w0.076: v2(152.35,81) 151.99,81.36 UC1.AU7
  BOTTOM w0.102: v2(151.54,55.36) CMOS1.2
PCH_RTCX1: length 28.1
  TOP w0.102: v2(173.67,73.33) 173.74,73.41 RC4.1 CC1.2 174.95,74.27 175.15,74.08 YC1.1 RG3.2
  BOTTOM w0.076: UC1.AW5 153.58,80.06 153.88,79.76 153.88,78.79 154.25,78.42 156.33,78.42 158.87,75.87 162.21,75.87 162.24,75.9 162.26,75.9
  BOTTOM w0.102: 162.26,75.9 168.56,75.9 171.13,73.33 v1(172.88,73.33) v2(173.67,73.33)
PCH_RTCX1_R: length 14.1
  TOP w0.102: UG1.9 184.91,80.25 v2(184.59,80.57) ; RG3.1 176.08,76.38 175.82,76.64 v1(175.82,78.87) 175.82,80.06 v2(176.09,80.32)
  BOTTOM w0.102: v2(176.09,80.32) 176.34,80.57 180.21,80.57 180.59,80.95 184.21,80.95 v2(184.59,80.57)
PCH_RTCX2: length 26.6
  TOP w0.102: YC1.2 174.61,71.58 CC2.2 RC4.2 173.74,72.5 v2(173.67,72.57)
  BOTTOM w0.076: UC1.AY5 153.69,79.27 153.69,78.88 153.69,78.7 154.15,78.24 156.18,78.24 159.06,75.37 160.37,75.37
  BOTTOM w0.102: 160.37,75.37 160.4,75.39 168.31,75.39 v1(170.03,73.66) 171.13,72.57 v2(173.67,72.57)
PCH_SLP_WLAN#: length 10.1
  TOP w0.076: RC39.2 155.76,76.42 155.29,76.89 155.29,80.66 v1(154.68,81.28) 153.92,82.04 153.58,82.04 153.37,82.25 153.37,83.9 v2(153.72,84.25)
  BOTTOM w0.076: v2(153.72,84.25) 153.37,84.61 UC1.AM5
PCH_SMB_ALERT#: length 11.4
  BOTTOM w0.076: UC1.AN2 155.49,83.58 155.96,84.04 156.32,84.04 156.63,83.74 159.68,83.74 159.95,84 159.95,85.3 160.38,85.73 160.38,86.44 160.74,86.8 161.91,86.8 162.16,87.05 162.74,87.05
  BOTTOM w0.102: 162.74,87.05 v1(163.12,87.05) R2329.2
PCH_SPI_CLK: length 93.1
  TOP w0.102: R2333.2 180.83,26.67 v1(180.32,27.18) 180.02,27.49 v2(179.13,27.49)
  IN2 w0.076: v2(155.14,89.94) 158.33,89.94 158.43,89.84 158.68,89.84
  IN2 w0.107: 158.68,89.84 159.75,89.84 161.32,88.27 163.66,88.27 164.47,89.08 164.47,90.17 165.64,91.34 167.01,91.34 167.62,90.73 167.62,85.98 170.49,83.11 170.49,82.48 171.69,81.28 171.94,81.28 173.67,79.56 173.97,79.56 175.72,77.81 176.09,77.81 178.54,75.36 178.54,63.59 179.82,62.32 179.82,58.21 180.4,57.62 180.4,50.09 183.18,47.31 183.18,42.99 183.67,42.5 183.67,40.03 182.25,38.61 180.8,38.61 177.68,35.49 177.68,29.74 179.13,28.3 v2(179.13,27.49)
  BOTTOM w0.076: UC1.AA3 154.84,90.24 v2(155.14,89.94)
PCH_SPI_CLK_R: length 3.8
  TOP w0.102: C2326.1 R2333.1 181.67,25.33 181.91,25.09 v1(181.91,24.83) 181.91,24.79 181.68,24.57 v2(181.46,24.57)
  BOTTOM w0.102: U2302.6 181.54,24.64 v2(181.46,24.57)
PCH_SPI_CS0#: length 113.8
  IN2 w0.076: 158.68,90.99 158.43,90.99 158.17,90.73 155.66,90.73 155.4,90.99 152.81,90.99 v2(152.38,91.41)
  IN2 w0.107: v2(179.34,19.51) 181.01,21.18 181.01,23.37 180.78,23.6 180.78,27.41 178.15,30.04 178.15,35.3 180.96,38.1 182.51,38.1 184.18,39.78 184.18,42.75 183.65,43.29 183.65,48.39 182.4,49.64 181.62,49.64 180.87,50.38 180.87,57.82 180.28,58.41 180.28,62.51 179.01,63.78 179.01,77.46 178.19,78.28 175.91,78.28 174.14,80.04 173.94,80.04 172.75,81.23 172.75,82.6 171.4,83.95 170.39,83.95 169.45,84.89 169.45,85.91 168.54,86.82 168.54,88.62 168.81,88.9 168.81,90.35 166.83,92.33 166.83,92.61 166.27,93.17 165.44,93.17 163.89,91.62 163.89,89.31 163.38,88.8 161.5,88.8 159.31,90.99 158.68,90.99
  BOTTOM w0.076: UC1.Y7 152.2,91.23 v2(152.38,91.41)
  BOTTOM w0.102: v2(179.34,19.51) 179.7,19.87 183.44,19.87 184.08,19.23 U2302.1
PCH_SPI_HOLD1#: length 8.3
  TOP w0.102: RP39.4 179.01,25.19 179.13,25.07 180.65,25.07 180.9,24.82 180.9,24.52 v2(181.46,23.96) 181.83,23.96 182.58,24.71 v1(183.23,24.71)
  BOTTOM w0.102: v2(181.46,23.96) 181.84,23.96 182.81,24.92 U2302.7
PCH_SPI_HOLD#: length 89.6
  TOP w0.102: R2335.2 178.21,22.97 v2(178.54,23.3) 178.54,23.73 179.01,24.2 RP39.5
  IN2 w0.107: v2(178.54,23.3) 179,23.75 179,25.96 178.48,26.48 178.48,28.28 177.21,29.55 177.21,35.69 180.65,39.12 182.05,39.12 183.19,40.26 183.19,42.27 182.71,42.75 182.71,47.07 179.94,49.84 179.94,56.56 179.34,57.15 179.34,62.13 178.08,63.4 178.08,75.16 175.9,77.34 175.5,77.34 174.3,78.54 172.14,78.54 171.46,79.23 171.46,80.83 169.86,82.43 169.86,82.96 167.14,85.68 163.02,85.68 162.87,85.53 160.84,85.53 160,86.36 159.47,86.36 159.04,86.8 v2(159.04,87.2)
  BOTTOM w0.076: v2(159.04,87.2) 159.04,87.33 158.55,87.81 157.27,87.81 156.93,88.16 156.22,88.16 UC1.AF1
PCH_SPI_MISO: length 97.6
  TOP w0.102: v2(179.51,23.55) 180.01,24.05 RP39.7
  IN2 w0.076: v2(154.55,89.91) 154.55,89.91 155,89.46 155.89,89.46 156.14,89.72 158.17,89.72 158.3,89.59 158.68,89.59
  IN2 w0.107: v2(179.51,23.55) 179.76,23.8 179.76,25.58 178.72,26.63 178.72,28.38 177.45,29.65 177.45,35.59 180.73,38.87 182.12,38.87 183.42,40.16 183.42,42.37 182.94,42.85 182.94,47.16 180.17,49.94 180.17,56.65 179.57,57.25 179.57,62.23 178.31,63.49 178.31,75.26 175.99,77.58 175.59,77.58 174.33,78.85 172.24,78.85 171.85,79.24 171.85,80.79 170.24,82.4 170.24,82.99 167.37,85.86 167.37,90.63 166.91,91.09 165.77,91.09 164.78,90.1 164.78,88.45 164.34,88.02 161.22,88.02 159.65,89.59 158.68,89.59
  BOTTOM w0.076: UC1.AA4 154.26,90.36 154.55,90.06 v2(154.55,89.91)
PCH_SPI_MISO_1: length 15.9
  TOP w0.102: v1(178.62,27.13) 178.9,26.85 v2(179.13,26.85) 180.01,25.97 RP39.2
  IN2 w0.107: v2(179.13,26.85) 179.13,26.73 180.27,25.58 180.27,23.93 179.94,23.6 179.94,20.74 v2(178.71,19.51)
  BOTTOM w0.102: v2(178.71,19.51) 179.11,19.11 179.55,19.11 180.05,19.61 182.43,19.61 182.81,19.23 U2302.2
PCH_SPI_MOSI: length 98.2
  TOP w0.102: RP39.8 180.51,23.59 180.45,23.52 v2(180.45,23.35)
  IN2 w0.076: v2(157.34,90.36) 158.18,90.36 158.55,90.73 158.68,90.73
  IN2 w0.107: v2(180.45,23.35) 180.45,23.52 180.52,23.6 180.52,27.23 177.92,29.84 177.92,35.4 180.88,38.36 182.38,38.36 183.93,39.91 183.93,42.63 183.41,43.14 183.41,48.29 182.35,49.36 181.49,49.36 180.64,50.21 180.64,57.72 180.05,58.31 180.05,62.42 178.78,63.69 178.78,77.37 178.1,78.05 175.81,78.05 174.05,79.81 173.84,79.81 172.52,81.14 172.52,81.87 172.22,82.17 171.46,82.17 170.74,82.88 170.74,83.24 167.87,86.11 167.87,90.83 167.11,91.6 165.51,91.6 164.17,90.26 164.17,89.19 163.51,88.52 161.42,88.52 159.21,90.73 158.68,90.73
  BOTTOM w0.076: v2(157.34,90.36) 156.98,90 155.81,90 UC1.AA2
PCH_SPI_MOSI_1: length 3.5
  TOP w0.102: v2(179.76,26.85) 180.51,26.1 RP39.1
  BOTTOM w0.102: v1(180.07,27.32) 179.76,27.02 v2(179.76,26.85) 180.04,26.85 180.27,26.62 U2302.5
PCH_SPI_WP1#: length 14.1
  TOP w0.102: v2(178.42,25.76) 178.97,26.32 179.28,26.32 179.51,26.09 RP39.3
  IN2 w0.107: v2(178.06,19.51) 178.06,23.63 178.4,23.96 178.4,25.74 v2(178.42,25.76)
  BOTTOM w0.102: v2(178.06,19.51) 178.06,18.39 178.87,17.58 181.31,17.58 181.54,17.81 U2302.3
PCH_SPI_WP#: length 108.3
  TOP w0.102: RP39.6 179.51,24.14 179.08,23.7 179.08,23.22 179.43,22.86 v1(179.97,22.86) 181.01,22.86 v2(181.49,23.35) R2334.2
  IN2 w0.076: 158.68,91.24 158.3,91.24 158.04,90.99 156.11,90.99 155.3,91.8 153.42,91.8 v2(153.03,91.41)
  IN2 w0.107: v2(181.49,23.35) 181.41,23.35 181.03,23.73 181.03,27.49 178.38,30.14 178.38,35.2 181.03,37.85 182.61,37.85 184.44,39.68 184.44,42.88 183.88,43.44 183.88,48.49 182.3,50.07 182.3,50.8 181.11,52 181.11,57.91 180.52,58.5 180.52,62.61 179.25,63.88 179.25,77.56 178.29,78.51 176.01,78.51 174.2,80.32 174.05,80.32 173.01,81.36 173.01,82.68 171.46,84.23 170.47,84.23 169.73,84.97 169.73,85.98 168.79,86.92 168.79,88.47 169.09,88.78 169.09,90.61 167.09,92.61 167.09,92.74 166.4,93.43 165.31,93.43 163.63,91.75 163.63,89.41 163.28,89.06 161.63,89.06 159.44,91.24 158.68,91.24
  BOTTOM w0.076: v2(153.03,91.41) 152.85,91.23 UC1.Y6
PCH_TP_INT#: length 35.5
  TOP w0.076: v2(151.78,93.35) 151.78,93.24 v1(152.13,92.89) ; v2(159.01,93.77) 159.12,93.65 RC74.2
  TOP w0.102: RC367.2 152.5,100.51 152.68,100.33 153.28,100.33 154.07,99.55 154.46,99.55 155.49,98.51 QC3.3 157.4,98.51 158.76,99.86 v2(158.76,102.14)
  IN1 w0.076: 158.73,94.04 158.7,94.07 154.91,94.07 154.49,93.65 152.08,93.65 151.78,93.36 v2(151.78,93.35)
  IN1 w0.107: v2(158.76,102.14) 159.89,102.14 162.69,99.35 162.69,97.66 163.13,97.22 163.13,94.37 162.8,94.04 161.99,94.04 161.84,94.19 161.12,94.19 160.7,93.77 v2(159.01,93.77) 158.74,94.04 158.73,94.04
  BOTTOM w0.076: v2(151.78,93.35) 152.2,92.92 UC1.U7
PCH_X1_R: length 87.2
  TOP w0.076: v2(133.43,111.31) 133.05,111.69 RG6.1
  TOP w0.102: v2(190.56,80.19) 190.28,79.91 v1(189.77,79.91) 189.62,80.07 188.65,80.07 188.04,79.45 UG1.5
  IN2 w0.107: v2(190.56,80.19) 189.97,80.78 189.97,83.52 188.26,85.23 188.26,92.38 184.56,96.08 179.75,96.08 176.99,98.84 176.99,99.33 176.64,99.69 176.28,99.69 173.45,102.52 172.4,102.52 171.35,103.56 171.35,104.47 169.83,106 169.83,108.93 167.2,111.56 163.38,111.56 159.95,114.99 151.82,114.99 150.04,113.21 145.75,113.21 143.26,110.72 138.82,110.72 137.6,111.94 133.79,111.94 133.43,111.59 v2(133.43,111.31)
PCIE_B+:
  vias: v1(75.44,50.45)
PCIE_CRX_C_GTX_N0: length 12.1
  BOTTOM w0.102: UV1.AG31 72.48,73.38 72.65,73.38 72.75,73.28 72.75,73.21 72.62,73.08 72.62,71.93 74.7,69.85 74.91,69.85 74.98,69.78
  BOTTOM w0.112: 74.98,69.78 75.47,69.29 75.47,68.91 75.97,68.4 v3(76.66,68.4) 80.6,68.4 CV2.2
PCIE_CRX_C_GTX_N1: length 14.6
  BOTTOM w0.102: UV1.AF28 71.85,74.25 71.85,73.9 71.94,73.81 71.94,73.56 71.89,73.51 71.89,73.09 72.2,72.78 72.2,71.39 73.72,69.86 73.72,69.8 73.74,69.78
  BOTTOM w0.112: 73.74,69.78 74.58,68.94 74.58,68.53 75.75,67.36 v3(77.58,67.36) 78.24,67.36 79,66.6 80.63,66.6 CV4.2
PCIE_CRX_C_GTX_N2: length 22.8
  IN2 w0.102: v2(72,76.5) 72,76.42 71.72,76.14 71.58,76.14 71.25,75.81 71.25,74.84 69.3,72.89 69.3,71.19 70.7,69.78
  IN2 w0.114: v2(78.54,63.3) 78.8,63.05 78.93,63.05 79.06,63.18 79.06,65.29 78.25,66.1 77.43,66.1 76.38,67.14 73.34,67.14 70.7,69.78
  BOTTOM w0.102: UV1.AF26 v2(72,76.5)
  BOTTOM w0.112: v2(78.54,63.3) 79.1,63.3 CV6.2
PCIE_CRX_C_GTX_N3: length 20.6
  IN2 w0.102: 69.71,69.95 69.69,69.97 69.66,69.97 68.76,70.86 68.76,73.81 70.41,75.46 70.41,75.95 70.11,76.25 69.88,76.25 v2(69.58,76.55)
  IN2 w0.114: v2(78.54,65.08) 78.3,64.83 77.77,64.83 75.98,66.62 73.04,66.62 69.71,69.95
  BOTTOM w0.102: v2(69.58,76.55) 70,76.12 UV1.AD26
  BOTTOM w0.112: CV8.2 79.1,65.08 v2(78.54,65.08)
PCIE_CRX_C_GTX_P0: length 12.1
  BOTTOM w0.102: 75.16,69.96 75.16,69.97 75.09,69.97 75.07,69.99 75.06,69.99 74.99,70.06 74.78,70.06 73.73,71.11 73.73,71.21 73.47,71.47 73.37,71.47 72.83,72.01 72.83,73 72.95,73.12 72.95,73.37 72.84,73.48 72.84,73.62 72.99,73.77 73.13,73.77 UV1.AH30
  BOTTOM w0.112: CV1.2 80.78,68.66 v3(78.95,68.66) 76.08,68.66 75.73,69.01 75.73,69.4 75.16,69.96
PCIE_CRX_C_GTX_P1: length 14.3
  BOTTOM w0.102: UV1.AG29 72.4,74.22 72.32,74.3 72.12,74.3 72.07,74.25 72.07,73.97 72.14,73.89 72.14,73.47 72.09,73.42 72.09,73.18 72.4,72.87 72.4,71.47 73.9,69.97 73.91,69.97 73.92,69.96
  BOTTOM w0.112: 73.92,69.96 74.84,69.04 74.84,68.64 75.86,67.62 78.35,67.62 79.11,66.86 v3(79.64,66.86) 80.75,66.86 CV3.2
PCIE_CRX_C_GTX_P2: length 22.8
  IN2 w0.102: 70.88,69.95 70.81,70.03 70.74,70.03 69.5,71.27 69.5,72.8 71.46,74.76 71.46,75.72 71.67,75.93 71.77,75.93 v2(72,75.7)
  IN2 w0.114: 70.88,69.95 73.44,67.39 76.49,67.39 77.53,66.35 78.35,66.35 79.3,65.39 79.3,63.07 79.03,62.8 78.82,62.8 v2(78.54,62.52)
  BOTTOM w0.102: UV1.AF27 v2(72,75.7)
  BOTTOM w0.112: CV5.2 78.56,62.54 v2(78.54,62.52)
PCIE_CRX_C_GTX_P3: length 20.6
  IN2 w0.102: v2(69.58,75.75) 69.88,76.05 70.03,76.05 70.21,75.86 70.21,75.54 68.56,73.89 68.56,70.78 69.52,69.82 69.52,69.79 69.53,69.78
  IN2 w0.114: v2(78.54,64.3) 78.26,64.58 77.67,64.58 75.88,66.37 72.93,66.37 69.53,69.78
  BOTTOM w0.102: UV1.AD27 70,75.32 v2(69.58,75.75)
  BOTTOM w0.112: v2(78.54,64.3) 78.56,64.32 CV7.2
PCIE_PRX_LANTX_N3: length 28.6
  IN2 w0.076: v2(149.33,98.39) 149.33,98.66 149.25,98.73 148.97,98.73 148.89,98.66 148.89,96.69 149.11,96.47 150.83,96.47 151.53,97.17 151.53,97.99 151.89,98.34 152.09,98.34 152.66,98.91 154.41,98.91 156.6,101.1 158.68,101.1
  IN2 w0.114: 158.68,101.1 159.21,101.1 159.35,101.23 v2(159.35,101.43)
  BOTTOM w0.076: UC1.G11 149.73,98.26 149.6,98.39 v2(149.33,98.39)
  BOTTOM w0.112: v2(159.35,101.43) 159.45,101.32 159.91,101.32 160.11,101.53 163.2,101.53 163.4,101.32 166.05,101.32 166.12,101.4 167.57,101.4 168.97,102.8 170.08,102.8 170.41,103.13 CL31.1
PCIE_PRX_LANTX_N3_C: length 2.5
  BOTTOM w0.112: UL1.18 173.03,102.56 172.98,102.51 v3(172.36,102.51) 172.14,102.51 172.01,102.64 171.84,102.81 171.7,102.81 171.68,102.82 171.68,102.83 CL31.2
PCIE_PRX_LANTX_P3: length 28.7
  IN2 w0.076: v2(149.31,99.09) 149.24,99.09 149.04,98.9 148.9,98.9 148.73,98.73 148.73,96.62 149.04,96.31 150.9,96.31 151.69,97.1 151.69,97.92 151.95,98.18 152.15,98.18 152.72,98.75 154.48,98.75 156.58,100.85 158.68,100.85
  IN2 w0.114: v2(159.35,100.7) 159.2,100.85 158.68,100.85
  BOTTOM w0.076: UC1.F11 149.65,98.77 149.33,99.09 v2(149.31,99.09)
  BOTTOM w0.112: CL30.1 170.41,102.37 170.24,102.54 169.07,102.54 167.68,101.15 166.23,101.15 166.15,101.07 163.29,101.07 163.09,101.27 160.22,101.27 160.02,101.07 159.72,101.07 v2(159.35,100.7)
PCIE_PRX_LANTX_P3_C: length 2.5
  BOTTOM w0.112: CL30.2 171.59,102.55 171.73,102.55 171.82,102.46 172.04,102.24 172.95,102.24 173.03,102.16 UL1.17
PCIE_PRX_WLANTX_N4: length 72.1
  IN2 w0.076: 158.68,96.1 158.67,96.08 158.61,96.08 158.15,95.63 155.06,95.63 154.07,94.64 151.16,94.64 150.79,95.01 150.79,95.49 150.41,95.88 147.97,95.88 147.75,96.1 147.75,98.65 147.91,98.81 148.13,98.81 v2(148.35,99.04)
  IN2 w0.114: v2(182.33,60.1) 182.59,59.84 182.91,59.84 183.12,60.05 183.12,64.7 182.28,65.54 182.28,70.06 181.32,71.02 181.32,74.38 180.41,75.28 180.41,78.86 179.54,79.73 178.64,79.73 177.33,81.04 176.6,81.04 172.53,85.11 172.53,86.95 171.33,88.14 171.33,91.49 169.97,92.86 169.41,92.86 168.03,94.24 167.64,94.24 167.19,94.7 162.99,94.7 162.69,95.01 161.04,95.01 159.72,96.33 158.91,96.33 158.68,96.1
  BOTTOM w0.076: UC1.F13 148.63,98.77 v2(148.35,99.04)
  BOTTOM w0.112: JNGFF.35 182.98,58.7 182.89,58.79 182.89,58.9 183.11,59.12 183.11,59.5 182.82,59.79 182.64,59.79 v2(182.33,60.1)
PCIE_PRX_WLANTX_P4: length 72.1
  IN2 w0.076: v2(148.35,98.42) 148.13,98.65 147.98,98.65 147.91,98.58 147.91,96.17 148.04,96.04 150.48,96.04 150.96,95.56 150.96,95.08 151.22,94.81 154.01,94.81 154.99,95.79 158.08,95.79 158.49,96.2 158.49,96.26 158.5,96.27
  IN2 w0.114: 158.5,96.27 158.81,96.58 159.82,96.58 161.14,95.25 162.79,95.25 163.1,94.95 167.29,94.95 167.75,94.49 168.13,94.49 169.51,93.11 170.07,93.11 171.58,91.59 171.58,88.24 172.78,87.05 172.78,85.21 176.7,81.28 177.44,81.28 178.74,79.98 179.64,79.98 180.66,78.96 180.66,75.39 181.57,74.48 181.57,71.12 182.53,70.16 182.53,65.64 183.37,64.8 183.37,59.95 183.01,59.59 182.6,59.59 v2(182.33,59.32)
  BOTTOM w0.076: UC1.G13 148.66,98.12 v2(148.35,98.42)
  BOTTOM w0.112: v2(182.33,59.32) 182.54,59.53 182.71,59.53 182.85,59.39 182.85,59.23 182.63,59.01 182.63,58.82 182.48,58.66 JNGFF.33
PCIE_PTX_LANRX_N3: length 79.6
  IN2 w0.114: v2(130.52,110.42) 130.3,110.63 130.3,112.04 133.63,115.37 145.78,115.37 147.66,117.25 161.37,117.25 164.14,114.48 168.31,114.48 170.11,112.68 171.05,112.68 172.94,110.8 172.94,108.23 173.61,107.55 175.72,107.55 176.13,107.15 177.09,107.15 179.26,104.98 179.26,100.92 181.08,99.09 182.26,99.09 v2(182.53,98.82)
  BOTTOM w0.112: UL1.14 174.97,100.96 175.06,100.87 175.06,99.24 176.08,98.22 179.14,98.22 179.89,98.98 181.03,98.98 181.14,99.09 182.27,99.09 v2(182.53,98.82) ; v2(130.52,110.42) 130.51,110.42 130.28,110.19 130.28,109.69 CC32.1
PCIE_PTX_LANRX_N3_C: length 14.7
  BOTTOM w0.076: UC1.C29 138.65,101 138.65,101.27 138.52,101.41 138.52,102.62 137.71,103.43 137.71,104.8 137.75,104.84 137.75,105.45 137.71,105.49 137.71,105.74 137.43,106.01 135.53,106.01 134.8,106.74 131.26,106.74 130.87,107.13 ; 130.87,107.13 v3(130.87,107.13) ; 130.87,107.13 130.24,107.75 130.24,108.07 CC32.2
PCIE_PTX_LANRX_P3: length 79.6
  IN2 w0.114: v2(182.53,99.61) 182.53,99.47 182.4,99.34 181.18,99.34 179.51,101.02 179.51,105.08 177.2,107.4 176.23,107.4 175.82,107.8 173.72,107.8 173.18,108.33 173.18,110.9 171.16,112.93 170.22,112.93 168.41,114.73 164.24,114.73 161.48,117.5 147.55,117.5 145.67,115.62 133.53,115.62 130.05,112.15 130.05,110.55 129.93,110.42 v2(129.85,110.42)
  BOTTOM w0.112: v2(182.53,99.61) 182.27,99.34 181.03,99.34 180.92,99.23 179.79,99.23 179.03,98.48 176.19,98.48 175.32,99.35 175.32,100.84 175.37,100.89 UL1.13 ; v2(129.85,110.42) 130.02,110.25 130.02,109.65 CC40.1
PCIE_PTX_LANRX_P3_C: length 14.5
  BOTTOM w0.076: UC1.B30 138.41,101.06 138.49,101.14 138.49,101.21 138.36,101.34 138.36,101.53 138.27,101.62 138.27,101.85 138.36,101.94 138.36,102.09 138.28,102.16 138.28,102.4 138.36,102.47 138.36,102.55 138.23,102.68 138.1,102.68 137.93,102.85 137.93,102.98 137.54,103.36 v3(137.54,105.15) 137.54,105.67 137.36,105.85 135.46,105.85 134.74,106.57 131.19,106.57 131,106.76 130.95,106.76 130.93,106.77 130.51,107.19 130.51,107.25 130.08,107.68 130.08,108.08 CC40.2
PCIE_PTX_WLANRX_N4: length 132.4
  IN2 w0.114: v2(132.85,110.64) 132.71,110.64 132.47,110.88 132.47,111.39 133.54,112.46 138.13,112.46 139.15,111.44 143.04,111.44 145.32,113.73 149.86,113.73 151.63,115.5 160.23,115.5 163.43,112.3 167.18,112.3 170.88,108.6 170.88,106.5 171.81,105.57 172.55,105.57 173.29,104.83 176.21,104.83 176.67,104.37 176.67,100.94 179.13,98.48 179.13,97.46 180.02,96.57 185.5,96.57 188.75,93.32 188.75,85.5 190.87,83.39 190.87,80.67 193.23,78.31 193.23,76.47 194.03,75.68 196.75,75.68 198.18,74.25 198.18,66.2 196.53,64.55 194.77,64.55 192.14,61.92 192.14,61.11 192.51,60.75 192.7,60.75 192.84,60.61 v2(192.84,60.36)
  BOTTOM w0.112: JNGFF.29 181.48,58.64 181.23,58.88 181.23,59.97 181.79,60.53 183.5,60.53 183.65,60.38 185.85,60.38 186.23,60 188.5,60 189.9,61.4 191.34,61.4 192,60.73 192.77,60.73 192.84,60.66 v2(192.84,60.36) ; CC36.1 132.26,109.61 132.26,109.78 132.58,110.1 132.58,110.48 132.74,110.64 v2(132.85,110.64)
PCIE_PTX_WLANRX_N4_C: length 13.1
  BOTTOM w0.076: CC36.2 132.16,108.08 132.16,107.58 132.43,107.31 132.93,107.31 132.97,107.27 134.89,107.27 135.76,106.39 137.81,106.39 138.45,105.75 v3(138.45,103.9) 138.45,103.39 139.38,102.47 139.38,101.87 139.33,101.83 139.33,101.81 139.16,101.64 138.96,101.64 138.93,101.6 138.93,101.39 UC1.B29
PCIE_PTX_WLANRX_P4: length 132.5
  IN2 w0.114: v2(192.84,61.14) 192.7,61 192.61,61 192.39,61.22 192.39,61.82 194.87,64.3 196.63,64.3 198.43,66.1 198.43,74.35 196.85,75.93 194.13,75.93 193.48,76.58 193.48,78.41 191.12,80.78 191.12,83.49 189,85.6 189,93.42 185.61,96.82 180.13,96.82 179.38,97.57 179.38,98.58 176.92,101.04 176.92,104.47 176.31,105.08 173.39,105.08 172.65,105.82 171.91,105.82 171.13,106.61 171.13,108.7 167.28,112.55 163.54,112.55 160.33,115.75 151.53,115.75 149.75,113.97 145.22,113.97 142.93,111.69 139.25,111.69 138.23,112.7 133.43,112.7 132.22,111.49 132.22,110.79 v2(132.06,110.64)
  BOTTOM w0.102: JNGFF.27 180.98,59.49
  BOTTOM w0.112: v2(192.84,61.14) 192.84,61.14 192.69,60.99 192.11,60.99 191.44,61.65 189.79,61.65 188.39,60.26 186.34,60.26 185.96,60.63 183.76,60.63 183.6,60.79 181.69,60.79 180.98,60.08 180.98,59.49 ; CC41.1 132.01,109.73 132.01,109.89 132.33,110.21 132.33,110.37 v2(132.06,110.64)
PCIE_PTX_WLANRX_P4_C: length 13.1
  BOTTOM w0.076: CC41.2 131.99,108.07 131.99,107.51 132.4,107.1 v3(132.63,107.1) 134.82,107.1 135.69,106.23 137.75,106.23 138.29,105.68 138.29,105.19 138.21,105.11 138.13,105.03 138.13,104.78 138.21,104.7 138.29,104.62 138.29,104.25 138.13,104.09 138.13,103.71 138.29,103.56 138.29,103.32 139.21,102.4 139.21,101.94 139.16,101.9 139.16,101.88 139.09,101.81 138.99,101.81 138.92,101.88 UC1.A29
PCIE_WAKE#: length 195.6
  TOP w0.076: RC97.2 158.15,72.41 157.52,72.41 157.16,72.05 157.16,69.92 157.79,69.28 157.79,68.25
  TOP w0.102: v2(123.93,7.57) 124.11,7.4 128.38,7.4 129.27,6.51 UE1.29 ; 157.79,68.25 162.01,64.04 162.01,63.53 165.72,59.82 165.72,41.23 v2(166.25,40.7) 166.25,38.76 166.49,38.52 167.81,38.52 170.62,41.33 171.38,41.33 171.63,41.58 171.63,42.6 170.41,43.82 170.41,47.35 175.82,52.76 175.82,59.05 180.38,63.61 180.38,69.55 181.64,70.81 181.64,75.58 179.14,78.08 179.14,86.66 176.59,89.21 176.59,93.28 177.6,94.3 177.6,97.59 v1(177.27,97.92) 176.97,98.23 176.97,99.37 176.64,99.7 175.65,99.7 175.53,99.81 174.54,99.81 173.21,101.15 173.21,103.18 172.9,103.48 172.6,103.48 172.01,104.07 v2(172.01,104.07)
  IN1 w0.107: v2(166.25,40.7) 166.25,40.24 164.88,38.87 163.99,38.87 163.28,38.16 162.62,38.16 161.22,36.76 159.82,36.76 156.09,33.02 156.09,28.14 154.68,26.74 154.53,26.74 152.84,25.05 152.84,24.9 152.51,24.57 151.34,24.57 148.28,21.51 143.95,21.51 142.9,22.56 141.01,22.56 140.85,22.41 136.56,22.41 136.24,22.09 128.95,22.09 128.28,21.42 127.8,21.42 126.82,20.43 v2(126.23,20.43)
  BOTTOM w0.102: RL34.2 v2(172.01,104.07) 172.32,103.75 172.82,103.75 172.82,103.76 UL1.21 ; v2(126.23,20.43) 126.23,18.77 124.82,17.36 124.82,13.78 124.16,13.12 124.16,8.59 123.93,8.36 v2(123.93,7.57)
PCIE_WAKE#_R: length 18.9
  TOP w0.076: RC97.1 157.7,72.88 RC34.2 157.22,73.32 154.95,73.32 154.41,73.86 154.41,78.04 v1(154.21,78.24) 153.73,78.72 153.73,80.42 152.18,81.97 152.18,84.98 152.91,85.71 v2(153.02,85.71)
  BOTTOM w0.076: v2(153.02,85.71) 153.05,85.71 153.5,86.17 UC1.AJ5
PECI_EC: length 130.9
  TOP w0.305: v2(136.73,23.32) 136.73,23.17 137.09,22.81 RE43.2
  IN1 w0.076: 108.13,87.23 108.95,87.23 110.34,88.62 110.34,91.67 112.14,93.47 v2(113.24,93.47)
  IN1 w0.254: 108.13,87.23 100.97,87.23 95.98,82.24 v2(95.98,81.94) ; v2(113.06,24.9) 113.06,26.29 111.69,27.66 111.69,33.2 108.26,36.63 102.11,36.63 v2(101.23,37.52)
  IN2 w0.254: v2(90.47,53) 90.86,52.61 90.86,46.66 93.2,44.33 93.2,43.11 96.04,40.26 98.42,40.26 101.16,37.52 v2(101.23,37.52) ; v2(136.73,23.32) 136.28,23.78 128.37,23.78 127.03,22.44 122.04,22.44 122.03,22.43 118.11,22.43 116.8,23.75 114.2,23.75 v2(113.06,24.9)
  BOTTOM w0.076: UC1.N62 117.7,94.39 117.27,94.39 117.08,94.58 116.74,94.58 116.61,94.45 116.61,93.77 116.41,93.57 v1(114.69,93.57) 113.34,93.57 v2(113.24,93.47)
  BOTTOM w0.254: v2(90.47,53) 90.47,56.95 91.17,57.65 92.18,57.65 94.09,59.55 94.09,64.28 93.77,64.6 93.77,73.77 95.03,75.02 95.03,80.99 v2(95.98,81.94)
PECI_KB9012: length 2.6
  TOP w0.254: UE1.118 v1(136.62,20.81) 136.62,21.23 RE43.1
PEG_CLKREQ#: length 156.9
  TOP w0.076: v2(153.15,93.22) 153.58,93.65 153.98,93.65 154.36,93.27 155.26,93.27 155.77,93.78 157.66,93.78 158.07,94.19 162.11,94.19 162.19,94.11 163.43,94.11 164.01,93.53
  TOP w0.102: RV153.1 64.06,92.21 64.06,93.88 64.57,94.39 64.57,97.59 65.46,98.48 72.65,98.48 73.92,99.75 v1(75.57,99.75) 78.66,99.75 84.38,94.04 v2(88.07,94.04)
  TOP w0.107: 164.01,93.53 165.66,93.53 166.4,92.79 v2(166.4,92.1)
  IN1 w0.107: v2(93.91,107.12) 98.74,107.12 103.18,102.67 106.74,102.67 110.42,106.35 118.55,106.35 120.96,108.77 121.85,108.77 122.23,108.39 125.66,108.39 125.79,108.26 132.39,108.26 132.9,107.75 150.93,107.75 152.36,106.33 152.36,104.04 152.84,103.56 159.24,103.56 162.92,99.88 163.25,99.88 163.89,99.24 163.89,93.91 164.39,93.4 165.79,93.4 166.4,92.79 v2(166.4,92.1)
  BOTTOM w0.076: UC1.U5 153.5,92.88 153.15,93.23 153.15,93.23 v2(153.15,93.22)
  BOTTOM w0.102: v2(88.07,94.04) 88.07,95.81 90.23,97.97 90.23,100.26 94.04,104.07 94.04,106.99 v2(93.91,107.12) ; v2(166.4,92.1) 165.79,91.5 165.79,90.23 166.17,89.84 166.93,89.84 167.14,90.05 RP42.6
PEG_CLKREQ#_R: length 4.6
  TOP w0.102: RV153.2 63.02,92.08 v1(62.72,92.08) 61.68,92.08 RV150.2 61.47,91.27 v2(61.68,91.07)
  BOTTOM w0.102: v2(61.68,91.07) 61.44,91.3 UV1.N7
PEG_CRX_GTX_N0: length 149.4
  IN2 w0.076: 151.25,101.76 151.25,100.48 150.72,99.95 150.72,99.03 150.47,98.77 150.28,98.77 150.21,98.7 v2(150.21,98.44)
  IN2 w0.081: 151.27,101.78 151.25,101.76
  IN2 w0.114: 151.27,101.78 151.27,102.53 151.67,102.93 152.81,102.93 155.27,105.39 157.36,105.39 157.66,105.09 157.66,104.83 157.51,104.68 v2(157.41,104.68)
  BOTTOM w0.076: UC1.F10 150.59,98.77 150.26,98.44 v2(150.21,98.44)
  BOTTOM w0.112: v2(157.41,104.68) 157.51,104.68 157.66,104.83 157.66,105.11 158.02,105.47 158.34,105.47 159.05,106.18 159.05,109.76 160.23,110.93 160.23,116.13 159.19,117.17 159.19,119.84 158.19,120.83 147.19,120.83 145.26,118.9 122,118.9 121.42,119.49 107.4,119.49 105.59,117.68 105.59,113.21 104.96,112.58 102.16,112.58 98.56,108.97 v3(98.56,101.73) 98.56,99.67 96.45,97.57 96.45,96.95 89.16,89.66 89.16,82.8 86.29,79.93 86.29,69.67 84.57,67.95 83.52,67.95 83.06,68.4 82.32,68.4 CV2.1
PEG_CRX_GTX_N1: length 143.8
  IN2 w0.076: 152.18,101.61 152.17,101.59 152.11,101.59 152.05,101.53 152.05,100.38 151.75,100.08 151.75,99.56 151.55,99.36 151.39,99.36 v2(151.14,99.1)
  IN2 w0.114: v2(156.81,104.03) 156.56,104.27 156.19,104.27 156.01,104.45 155.52,104.45 154.76,103.69 154.76,102.6 154.1,101.94 152.52,101.94 152.18,101.61
  BOTTOM w0.076: v2(151.14,99.1) 151.48,98.77 UC1.F8
  BOTTOM w0.112: CV4.1 82.3,66.6 82.95,66.6 83.14,66.41 84.56,66.41 87.94,69.8 87.94,80.32 90.13,82.51 90.13,89.24 97.34,96.45 97.34,97.21 99.52,99.39 99.52,108.66 102.54,111.69 105.57,111.69 106.61,112.72 106.61,117.42 107.52,118.33 121.3,118.33 121.72,117.91 129.23,117.91 129.49,117.65 145.36,117.65 146.74,119.04 155.79,119.04 159.11,115.72 159.11,111.08 158.17,110.14 158.17,106.89 156.97,105.7 156.54,105.7 156.09,105.24 156.09,104.55 156.42,104.22 156.62,104.22 v2(156.81,104.03)
PEG_CRX_GTX_N2: length 152.4
  IN2 w0.076: 149.28,101.78 149.28,101.78 149.28,101.76 149.33,101.72 149.33,100.57 149.68,100.21 149.68,98.54 149.68,98.54 149.68,98.24 149.68,98.24 149.7,98.22 149.7,97.55 149.96,97.29 150.65,97.29 150.89,97.53 150.89,97.64 v2(151.16,97.91)
  IN2 w0.114: v2(156.27,107.83) 156.08,107.64 155.76,107.64 154.87,106.76 151.31,106.76 149.28,104.73 149.28,103.22 149.28,103.21 149.28,101.78
  BOTTOM w0.076: UC1.H10 150.72,97.47 v2(151.16,97.91)
  BOTTOM w0.112: v2(156.27,107.83) 156.27,107.75 156.19,107.68 156.12,107.68 155.94,107.86 155.94,108.44 156.65,109.15 156.65,111.31 157.36,112.02 157.36,115.17 154.99,117.53 147.48,117.53 146.08,116.14 128.33,116.14 127.95,115.75 121.72,115.75 120.64,116.83 108.45,116.83 108.18,116.56 108.18,111.89 110.67,109.4 110.67,104.12 107.07,100.51 102.82,100.51 98.86,96.55 98.86,95.3 93.91,90.35 93.91,89.57 92.82,88.48 92.82,82.97 91.09,81.25 91.09,78.24 90.22,77.38 90.22,65.19 89.23,64.19 83.01,64.19 81.98,63.16 80.41,63.16 CV6.1
PEG_CRX_GTX_N3: length 150.7
  IN2 w0.076: 154.84,101.78 154.83,101.77 154.83,101.71 154.52,101.4 152.6,101.4 152.29,101.09 152.29,100.45 152.49,100.25 152.49,99.92 152.39,99.81 v2(152.24,99.81)
  IN2 w0.114: v2(157.13,103.06) 157.13,102.82 157.05,102.75 155.81,102.75 154.84,101.78
  BOTTOM w0.076: v2(152.24,99.81) 152.59,99.47 UC1.E6
  BOTTOM w0.112: CV8.1 80.52,64.83 82.23,64.83 82.54,65.14 88.79,65.14 89.34,65.7 89.34,70.41 88.58,71.18 88.58,78.03 89.85,79.3 89.85,81.28 91.92,83.35 91.92,88.85 93.02,89.95 93.02,91.11 94.89,92.99 94.89,92.99 95.28,93.38 95.29,93.38 97.97,96.06 97.97,96.95 102.42,101.4 106.71,101.4 109.78,104.47 109.78,108.77 107.24,111.31 107.24,116.9 108.06,117.71 121.03,117.71 121.98,116.77 127.56,116.77 127.83,117.03 145.68,117.03 147.07,118.42 155.38,118.42 158.25,115.55 158.25,111.53 157.54,110.82 157.54,107.19 156.66,106.32 155.83,106.32 155.47,105.96 155.47,104.05 156.77,102.75 157.05,102.75 157.13,102.82 v2(157.13,103.06)
PEG_CRX_GTX_P0: length 149.8
  IN2 w0.076: v2(150.2,99.13) 150.33,99 150.46,99 150.56,99.09 150.56,100.02 151.08,100.55 151.08,101.69 151.08,101.69 151.08,101.71 151.02,101.77 151.02,101.78
  IN2 w0.114: 151.02,101.78 151.02,102.64 151.56,103.18 152.71,103.18 155.17,105.64 157.47,105.64 157.91,105.2 157.91,104.81 v2(158.04,104.68)
  BOTTOM w0.076: UC1.E10 150.52,99.42 150.23,99.13 v2(150.2,99.13)
  BOTTOM w0.112: CV1.1 82.15,68.66 83.17,68.66 83.62,68.21 84.47,68.21 86.04,69.78 86.04,80.04 88.9,82.91 88.9,89.77 96.19,97.06 96.19,97.67 98.3,99.78 v3(98.3,106.96) 98.3,109.08 102.06,112.83 104.85,112.83 105.34,113.32 105.34,117.78 107.3,119.74 121.52,119.74 122.11,119.16 145.15,119.16 147.08,121.09 158.3,121.09 159.44,119.94 159.44,117.28 160.48,116.23 160.48,110.82 159.31,109.65 159.31,106.07 158.45,105.21 158.13,105.21 157.92,105 157.92,104.8 v2(158.04,104.68)
PEG_CRX_GTX_P1: length 143.8
  IN2 w0.076: 152.01,101.78 151.99,101.77 151.99,101.71 151.88,101.6 151.88,101.05 151.88,101.04 151.88,100.45 151.58,100.15 151.58,99.68 151.46,99.57 151.32,99.57 v2(151.11,99.78)
  IN2 w0.114: 152.01,101.78 152.42,102.19 154,102.19 154.51,102.7 154.51,103.8 155.42,104.7 156.11,104.7 156.29,104.52 156.66,104.52 156.67,104.52 v2(156.8,104.66)
  BOTTOM w0.076: UC1.E8 151.47,99.42 v2(151.11,99.78)
  BOTTOM w0.112: CV3.1 82.18,66.86 83.05,66.86 83.24,66.67 84.45,66.67 87.69,69.91 87.69,80.43 89.87,82.61 89.87,89.34 97.08,96.55 97.08,97.32 99.26,99.5 99.26,108.77 102.44,111.94 105.47,111.94 106.36,112.83 106.36,117.53 107.41,118.59 121.4,118.59 121.82,118.17 129.34,118.17 129.6,117.91 145.25,117.91 146.64,119.3 155.9,119.3 159.37,115.83 159.37,110.98 158.43,110.04 158.43,106.79 157.08,105.44 156.65,105.44 156.35,105.14 156.35,104.66 156.53,104.47 156.7,104.47 156.8,104.58 v2(156.8,104.66)
PEG_CRX_GTX_P2: length 152.4
  IN2 w0.076: v2(150.28,97.82) 150.45,98 150.65,98 150.73,97.92 150.73,97.6 150.58,97.45 150.03,97.45 149.87,97.62 149.87,98.29 149.85,98.3 149.85,98.61 149.85,98.61 149.85,100.28 149.49,100.64 149.49,101.73 149.53,101.77 149.53,101.78
  IN2 w0.114: v2(156.27,107.05) 156.27,107.29 156.17,107.4 155.86,107.4 154.98,106.51 151.42,106.51 149.53,104.63 149.53,103.11 149.53,103.11 149.53,101.78
  BOTTOM w0.076: UC1.G10 150.68,97.95 150.55,97.82 v2(150.28,97.82)
  BOTTOM w0.112: v2(156.27,107.05) 156.27,107.34 156.19,107.42 156.01,107.42 155.68,107.75 155.68,108.54 156.39,109.25 156.39,111.41 157.11,112.13 157.11,115.06 154.89,117.28 147.59,117.28 146.19,115.88 128.44,115.88 128.05,115.5 121.62,115.5 120.53,116.58 108.56,116.58 108.44,116.46 108.44,112 110.93,109.51 110.93,104.01 107.17,100.26 102.92,100.26 99.12,96.45 99.12,95.2 94.17,90.25 94.17,89.47 93.07,88.37 93.07,82.86 91.35,81.14 91.35,78.14 90.48,77.27 90.48,65.08 89.34,63.94 83.11,63.94 82.09,62.91 80.51,62.91 CV5.1
PEG_CRX_GTX_P3: length 150.7
  IN2 w0.076: 155.02,101.61 155.01,101.6 154.95,101.6 154.59,101.24 152.67,101.24 152.46,101.02 152.46,100.52 152.66,100.31 152.66,99.7 152.21,99.25 v2(152.21,99.08)
  IN2 w0.114: v2(157.13,102.28) 156.91,102.5 155.91,102.5 155.02,101.61
  BOTTOM w0.076: v2(152.21,99.08) 152.47,99.08 152.59,98.96 UC1.F6
  BOTTOM w0.112: CV7.1 80.39,64.57 82.33,64.57 82.65,64.89 88.89,64.89 89.59,65.59 89.59,70.52 88.83,71.28 88.83,77.93 90.1,79.2 90.1,81.18 92.17,83.25 92.17,88.74 93.28,89.85 93.28,91.01 95.15,92.88 95.15,92.89 95.39,93.13 95.4,93.13 98.23,95.96 98.23,96.85 102.53,101.15 106.82,101.15 110.04,104.37 110.04,108.88 107.5,111.41 107.5,116.79 108.17,117.45 120.93,117.45 121.87,116.51 127.67,116.51 127.94,116.78 145.79,116.78 147.17,118.17 155.27,118.17 157.99,115.44 157.99,111.63 157.28,110.92 157.28,107.3 156.55,106.57 155.72,106.57 155.21,106.06 155.21,104.23 155.27,104.17 155.27,103.97 156.69,102.55 156.86,102.55 v2(157.13,102.28)
PEG_CTX_GRX_C_N0: length 8.7
  BOTTOM w0.076: CC18.2 141.32,107.89 141.32,107.65 v3(142.05,106.92) 142.73,106.24 142.73,106.18 143.15,105.76 143.21,105.76 143.24,105.73 143.24,101.91 143.07,101.74 143.07,101.11 143.19,100.99 143.19,100.89 143.14,100.84 UC1.C23
PEG_CTX_GRX_C_N1: length 9.3
  BOTTOM w0.076: CC20.2 139.48,107.95 139.48,107.6 140.23,106.85 140.41,106.85 140.44,106.82 141.03,106.82 141.06,106.85 141.11,106.85 141.97,105.99 141.97,105.37 v3(142.38,104.96) 142.83,104.51 142.83,102.65 142.47,102.29 142.47,101.91 142.75,101.63 142.75,101.46 UC1.B23
PEG_CTX_GRX_C_N2: length 8.3
  BOTTOM w0.076: UC1.B21 143.95,100.84 144.02,100.92 144.02,101.02 143.82,101.23 143.82,101.59 144.15,101.92 144.15,105.54 v3(144.54,105.93) 144.84,106.23 144.84,106.97 144.79,107.01 144.79,107.6 144.84,107.65 144.84,107.93 CC22.2
PEG_CTX_GRX_C_N3: length 7.7
  BOTTOM w0.076: CC24.2 142.99,108 142.99,107.8 143.12,107.67 143.12,107.66 v3(143.41,107.37) 143.59,107.19 143.59,105.67 143.68,105.58 143.68,105.5 143.59,105.42 143.59,105.07 143.68,104.99 143.68,104.91 143.59,104.82 143.59,104.48 143.68,104.39 143.68,104.32 143.59,104.23 143.59,103.89 143.68,103.8 143.68,103.73 143.59,103.64 143.59,103.3 143.68,103.21 143.68,103.14 143.59,103.05 143.59,101.47 UC1.B22
PEG_CTX_GRX_C_P0: length 9.2
  BOTTOM w0.076: CC19.2 141.48,108.01 141.48,107.72 141.93,107.28 141.98,107.28 142.41,106.85 142.41,106.8 v3(143.09,106.11) 143.41,105.8 143.41,101.8 143.24,101.64 143.24,101.18 143.36,101.06 143.36,100.36 UC1.C22
PEG_CTX_GRX_C_P1: length 9
  BOTTOM w0.076: UC1.A23 142.95,101.96 142.86,101.86 142.76,101.86 142.64,101.98 142.64,102.23 143,102.58 143,104.61 142.74,104.87 142.74,104.9 142.32,105.32 142.29,105.32 142.14,105.47 142.14,106.06 141.17,107.03 v3(140.73,107.03) 140.29,107.03 139.65,107.66 139.65,107.95 CC21.2
PEG_CTX_GRX_C_P2: length 8.8
  BOTTOM w0.076: UC1.C21 144.33,100.33 144.33,100.95 143.98,101.3 143.98,101.48 144.31,101.81 144.31,105.47 144.41,105.57 144.47,105.57 144.89,106 144.89,106.05 145,106.16 v3(145,107.31) 145,107.97 CC23.2
PEG_CTX_GRX_C_P3: length 7.3
  BOTTOM w0.076: CC25.2 143.41,108.31 143.15,108.05 143.15,107.87 143.76,107.26 143.76,107.14 143.75,107.13 143.75,105.73 143.8,105.69 143.84,105.65 143.84,105.44 143.8,105.39 143.75,105.35 143.75,105.14 143.8,105.1 143.84,105.05 143.84,104.84 143.8,104.8 143.75,104.76 143.75,104.55 143.8,104.51 143.84,104.46 143.84,104.25 143.8,104.21 143.75,104.16 143.75,103.96 143.8,103.91 143.84,103.87 143.84,103.66 143.8,103.62 143.75,103.57 143.75,103.37 143.8,103.32 143.84,103.28 143.84,103.07 143.8,103.03 143.75,102.98 143.75,102.78 143.8,102.73 143.84,102.69 143.84,102.48 143.8,102.44 143.75,102.39 143.75,102.15 UC1.A21
PEG_CTX_GRX_N0: length 122.4
  IN2 w0.102: 77.91,71.99 77.9,71.99 77.86,72.03 77.82,72.03 77.81,72.04 74.51,72.04 73.52,71.05 71.97,71.05 71.82,70.9 v2(71.82,70.82)
  IN2 w0.114: 77.91,71.99 78.39,71.99 82.99,67.39 82.99,65.36 83.77,64.58 86.54,64.58 87.3,63.81 89.85,63.81 90.49,64.45 92.72,64.45 93.27,65 94.23,65 v2(94.52,64.71)
  BOTTOM w0.102: UV1.AE31 70.8,73.57 70.89,73.66 71.03,73.66 71.12,73.57 71.12,73.16 71.01,73.05 71.01,71.88 71.09,71.8 71.09,71.24 71.29,71.04 71.71,71.04 71.82,70.93 v2(71.82,70.82)
  BOTTOM w0.112: v2(94.52,64.71) 94.76,64.95 95.26,64.95 96.75,66.44 96.75,87.63 101.91,92.78 101.91,95.41 104.02,97.51 108.27,97.51 109.49,98.73 110.47,98.73 111.31,99.58 111.31,100.56 111.54,100.79 112.35,100.79 113.98,102.42 113.98,111.18 114.81,112.02 114.81,113.03 115.12,113.34 119.94,113.34 121.21,112.07 129.07,112.07 129.7,112.7 138.13,112.7 140.54,110.29 140.89,110.29 141.18,110 141.18,109.5 CC18.1
PEG_CTX_GRX_N1: length 122.8
  IN2 w0.102: 77.74,71.31 77.72,71.33 75.88,71.33 74.97,70.41 72.99,70.41 72.81,70.24 70.99,70.24 70.23,71 70.23,71.3 v2(70.04,71.49)
  IN2 w0.114: 77.74,71.31 82.23,66.82 82.23,64.59 83.01,63.81 86.16,63.81 87.05,62.93 90.08,62.93 90.59,63.43 92.27,63.43 93.03,62.67 94.49,62.67 94.76,62.4 v2(94.78,62.4)
  BOTTOM w0.102: UV1.AD28 70.17,74.33 70.17,73.96 70.38,73.76 70.38,73.63 70.26,73.52 70.26,73.08 70.35,72.99 70.35,72.3 70.22,72.17 70.22,71.68 v2(70.04,71.49)
  BOTTOM w0.112: v2(94.78,62.4) 95.05,62.68 95.6,62.68 97.64,64.72 97.64,87.25 102.8,92.4 102.8,95 104.12,96.32 v3(106.31,96.32) 108.32,96.32 109.34,97.34 110.93,97.34 112.32,98.73 112.32,99.39 114.99,102.06 114.99,110.55 116.52,112.07 119.44,112.07 120.84,110.67 128.94,110.67 130.09,111.82 137.74,111.82 139.43,110.13 139.43,109.53 CC20.1
PEG_CTX_GRX_N2: length 137.8
  IN2 w0.114: v2(91.75,60.99) 91.48,61.27 90.99,61.27 90.23,60.51 85.3,60.51 84.28,61.53 82.12,61.53 80.58,63.07 80.58,65.87 78.86,67.59 78.19,67.59 77.04,68.74 75.59,68.74 75.14,69.2 74.63,69.2 74.43,69.4 73.79,69.4 73.59,69.2 73.28,69.2 v2(72.95,68.88)
  BOTTOM w0.102: UV1.AC31 69.42,73.41 69.53,73.37 69.58,73.33 69.58,73.22 69.2,72.83 69.2,70.96 69.7,70.46 70.67,70.46 71.3,69.83 71.3,69.8 71.32,69.78
  BOTTOM w0.112: 71.32,69.78 72.01,69.09 72.74,69.09 v2(72.95,68.88) ; CC22.1 144.78,109.55 144.78,109.77 143.71,110.85 142.83,110.85 140.99,112.68 140.99,114.43 140.56,114.86 128.69,114.86 128.05,114.23 121.61,114.23 120.4,115.44 110.87,115.44 110.62,115.19 110.62,111.98 111.82,110.78 111.82,103.65 107.53,99.37 103.31,99.37 100.01,96.07 100.01,94.69 95.06,89.74 95.06,89.08 93.97,88 93.97,82.51 92.31,80.85 92.31,77.85 91.37,76.91 91.37,64.11 92.49,62.99 92.49,61.48 92.27,61.26 92.01,61.26 v2(91.75,60.99)
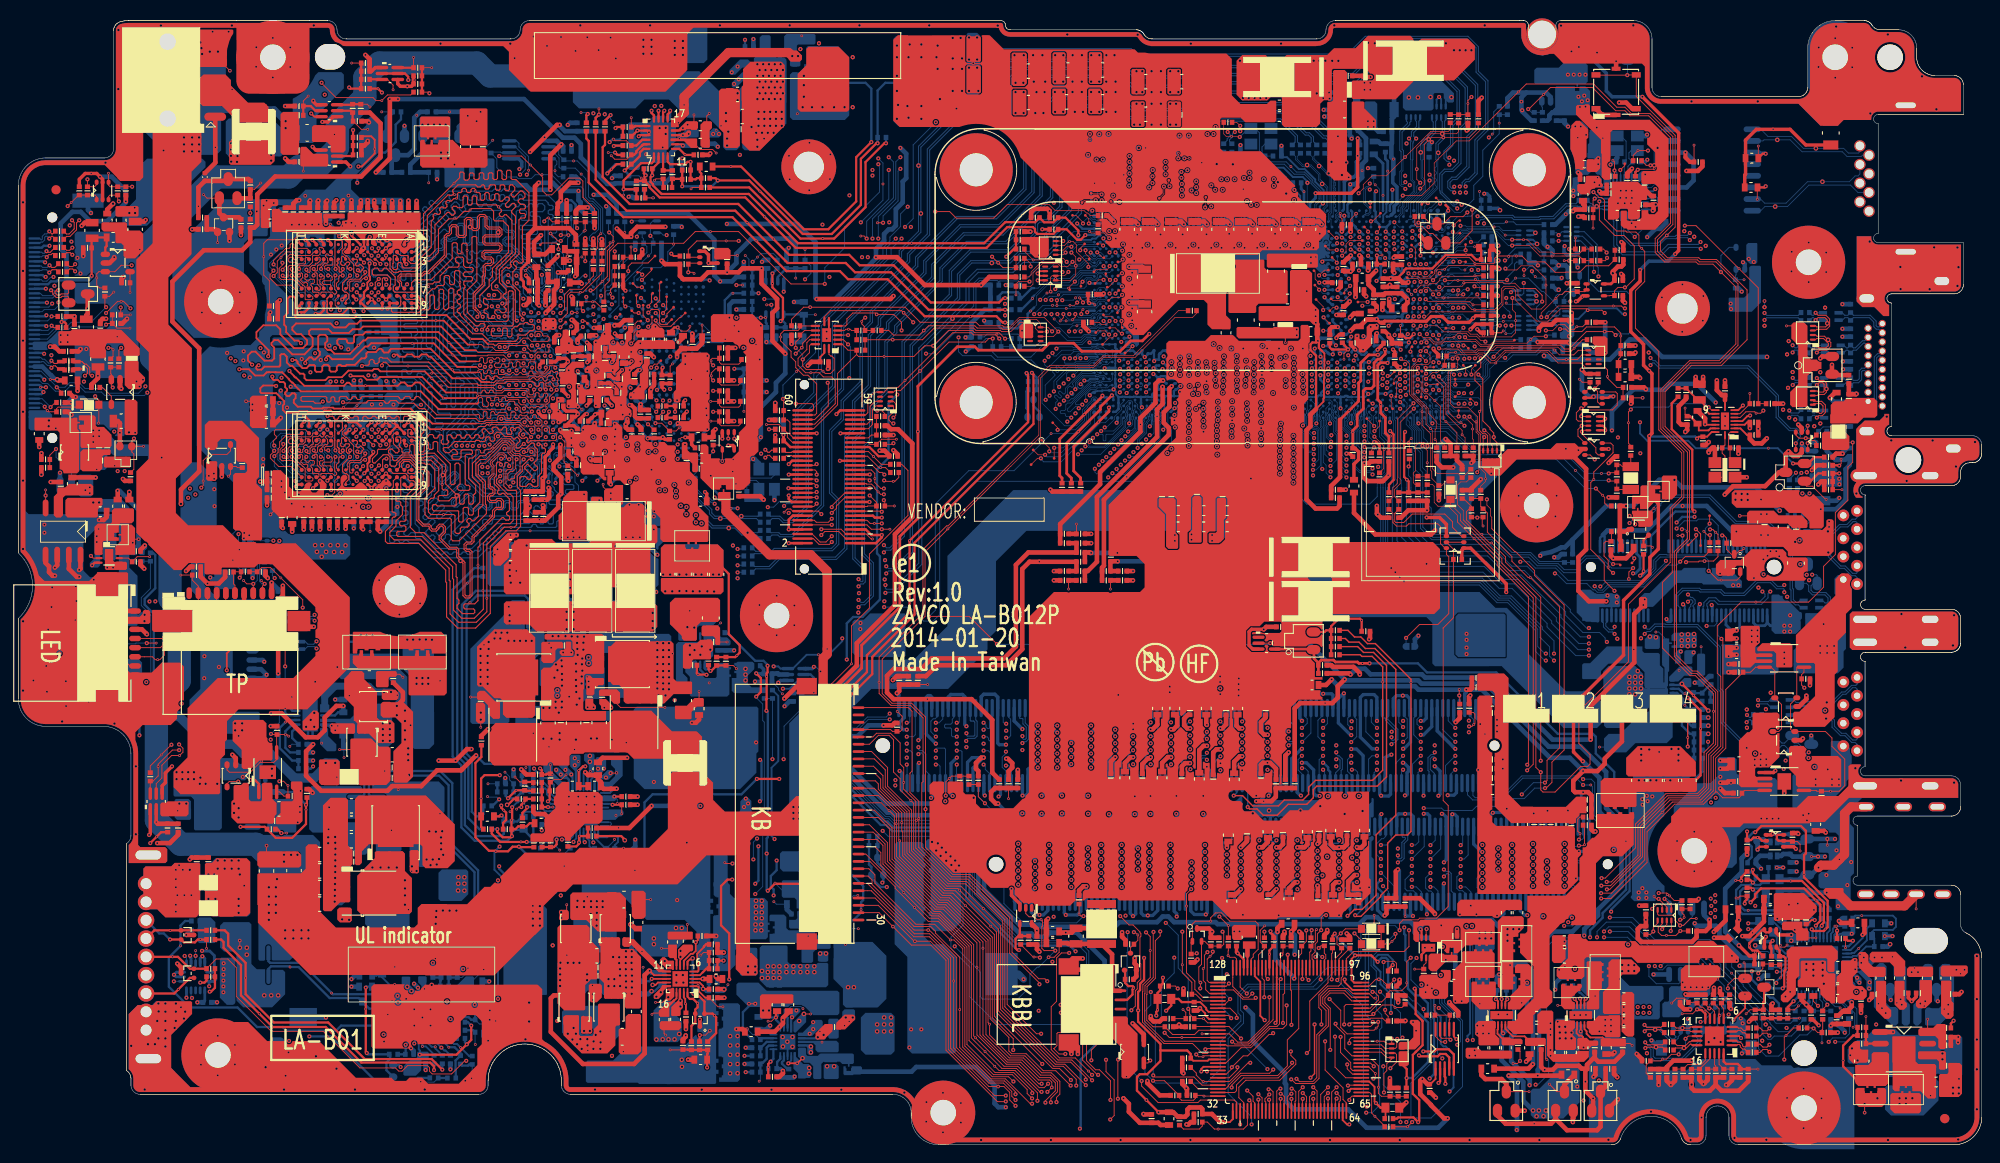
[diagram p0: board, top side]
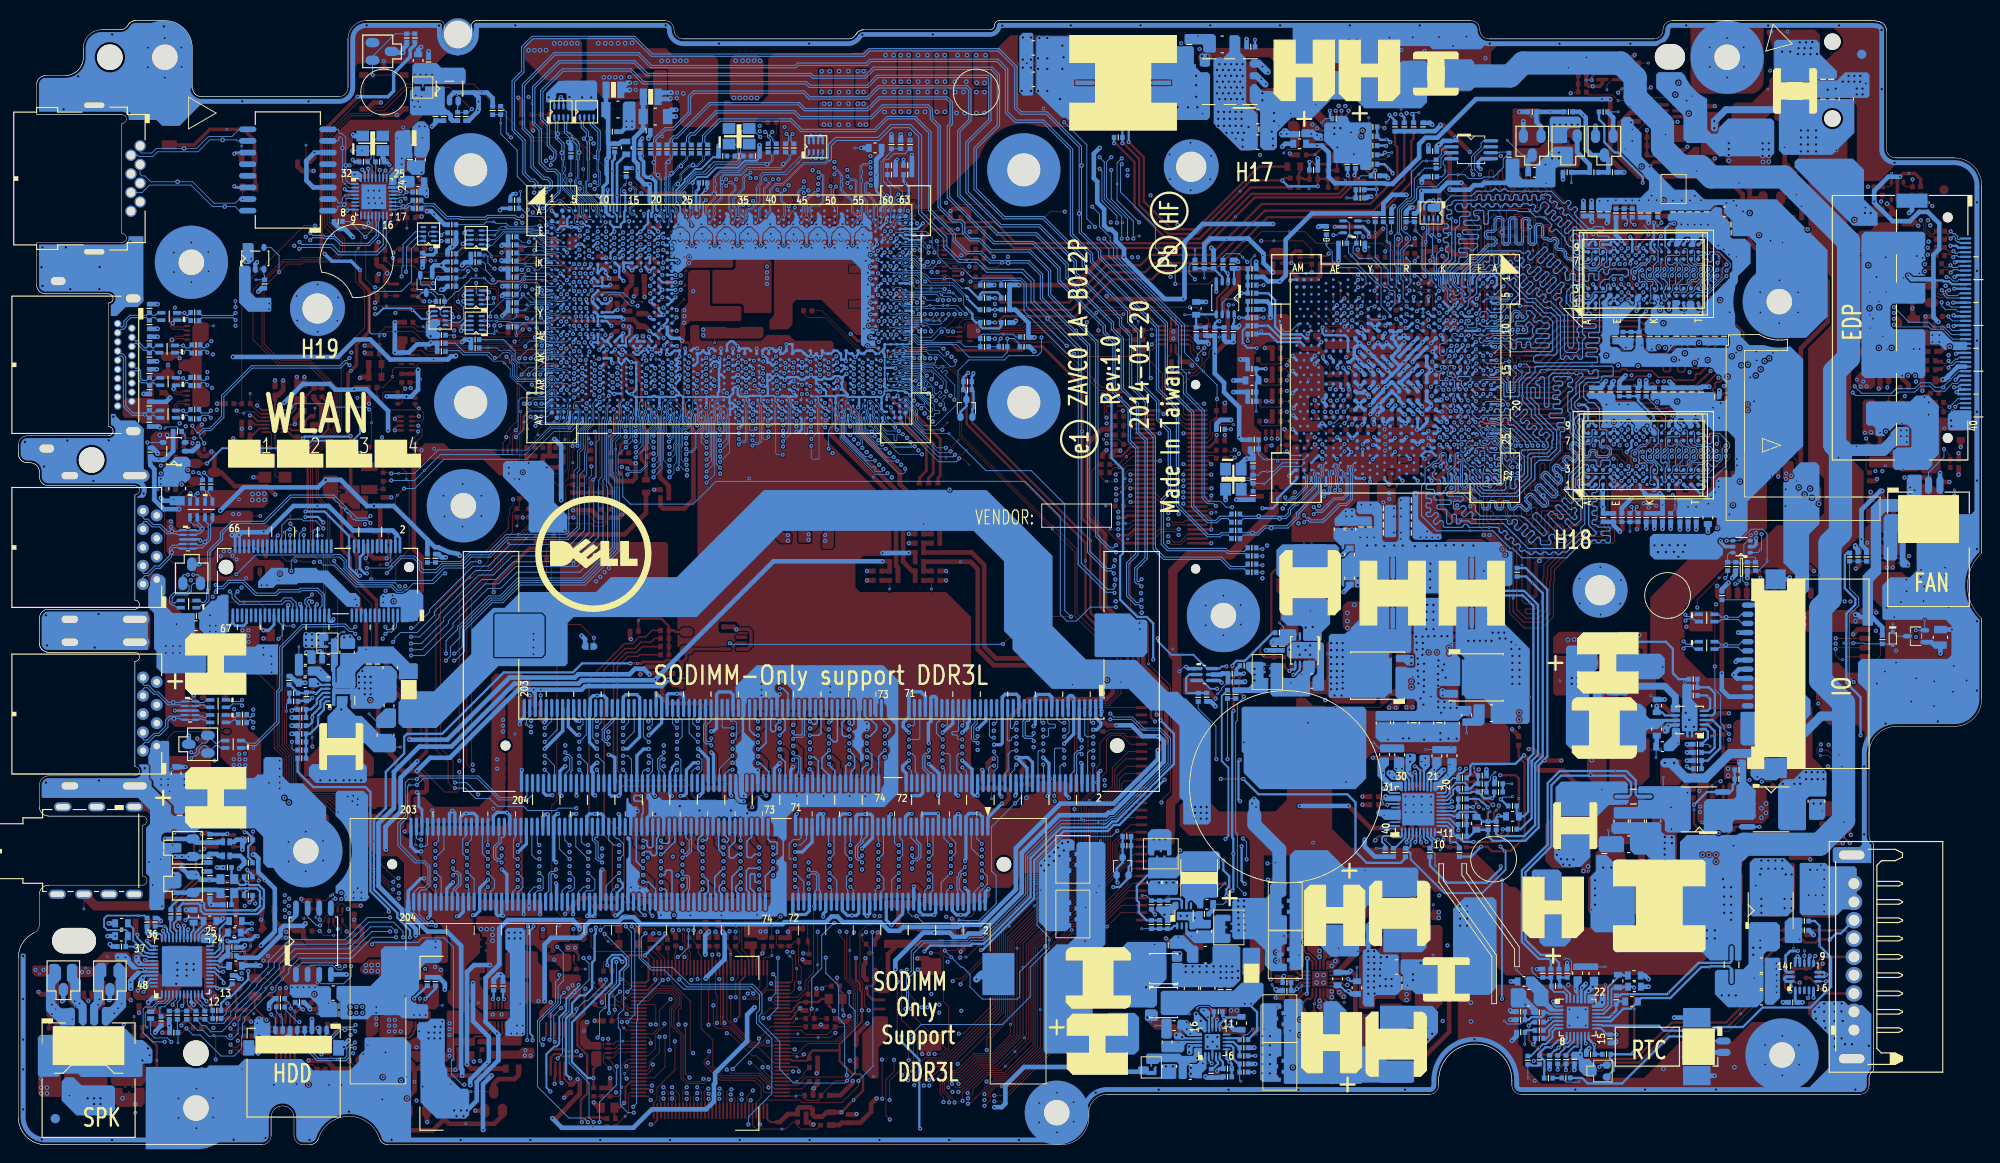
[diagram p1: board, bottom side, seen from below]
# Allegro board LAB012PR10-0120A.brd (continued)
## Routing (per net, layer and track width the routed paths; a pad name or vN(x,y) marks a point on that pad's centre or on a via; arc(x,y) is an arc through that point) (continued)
PEG_CTX_GRX_N3: length 135.5
  IN2 w0.114: v2(91.75,58.73) 91.5,58.98 85.68,58.98 83.91,60.76 81.62,60.76 79.81,62.57 79.81,65.58 78.55,66.84 77.83,66.84 76.74,67.93 75.29,67.93 74.83,68.39 74.39,68.39 v2(74,67.99)
  BOTTOM w0.102: 70.08,69.78 70.02,69.83 69.34,69.83 68.71,70.46 68.71,73.07 68.66,73.12 68.66,73.48 68.71,73.53 68.71,73.87 68.64,73.94 68.64,74.2 68.66,74.25 68.62,74.39 UV1.AB28
  BOTTOM w0.112: 70.08,69.78 71.65,68.2 71.68,68.2 71.89,68 73.35,68 73.55,68.2 73.79,68.2 v2(74,67.99) ; v2(91.75,58.73) 91.77,58.73 92.03,58.98 92.42,58.98 93.38,59.94 93.38,63.56 92.39,64.55 92.39,76.02 93.2,76.83 93.2,80.44 94.88,82.12 94.88,87.64 95.94,88.7 95.94,89.36 100.89,94.31 100.89,95.69 103.64,98.43 107.94,98.43 112.96,103.45 112.96,111.29 112.66,111.59 112.66,113.81 113.07,114.23 120.35,114.23 121.62,112.96 128.58,112.96 129.22,113.59 138.84,113.59 142.47,109.96 142.75,109.96 142.98,109.72 142.98,109.53 CC24.1
PEG_CTX_GRX_P0: length 122
  IN2 w0.102: 77.91,72.24 74.43,72.24 73.44,71.25 71.97,71.25 v2(71.82,71.4)
  IN2 w0.114: v2(94.52,65.5) 94.28,65.25 93.17,65.25 92.62,64.7 90.38,64.7 89.75,64.06 87.4,64.06 86.64,64.83 83.88,64.83 83.24,65.46 83.24,67.49 78.49,72.24 77.91,72.24
  BOTTOM w0.102: v2(71.82,71.4) 71.65,71.24 71.37,71.24 71.3,71.31 71.3,71.89 71.23,71.97 71.23,72.96 71.34,73.07 71.34,73.61 71.43,73.7 UV1.AF30
  BOTTOM w0.112: v2(94.52,65.5) 94.81,65.21 95.15,65.21 96.5,66.55 96.5,87.73 101.65,92.89 101.65,95.51 103.91,97.77 108.16,97.77 109.38,98.99 110.36,98.99 111.05,99.68 111.05,100.66 111.44,101.05 112.24,101.05 113.72,102.52 113.72,111.29 114.56,112.12 114.56,113.14 115.01,113.6 120.05,113.6 121.32,112.33 128.96,112.33 129.6,112.96 138.23,112.96 140.64,110.55 141,110.55 141.44,110.11 141.44,109.58 CC19.1
PEG_CTX_GRX_P1: length 123.2
  IN2 w0.102: 77.91,71.49 77.86,71.49 77.83,71.51 77.82,71.51 77.8,71.53 75.8,71.53 74.89,70.62 72.9,70.62 72.73,70.44 71.08,70.44 70.43,71.08 70.43,71.3 v2(70.62,71.49)
  IN2 w0.114: v2(94.78,63.19) 94.51,62.92 93.13,62.92 92.37,63.68 90.48,63.68 89.98,63.17 87.15,63.17 86.26,64.06 83.11,64.06 82.48,64.7 82.48,66.92 77.91,71.49 77.91,71.49
  BOTTOM w0.102: v2(70.62,71.49) 70.44,71.68 70.44,72.08 70.57,72.21 70.57,73.08 70.48,73.17 70.48,73.43 70.59,73.54 70.59,73.85 70.37,74.06 70.37,74.27 70.48,74.37 70.68,74.37 70.8,74.25 UV1.AE29
  BOTTOM w0.112: v2(94.78,63.19) 94.89,63.07 94.89,63.07 95.02,62.94 95.5,62.94 97.39,64.83 97.39,87.35 102.54,92.51 102.54,95.1 104.02,96.58 108.21,96.58 109.23,97.59 110.82,97.59 112.07,98.84 112.07,99.49 114.74,102.16 114.74,110.65 116.41,112.33 119.54,112.33 120.94,110.93 128.83,110.93 129.98,112.07 137.85,112.07 139.68,110.24 139.68,109.55 CC21.1
PEG_CTX_GRX_P2: length 137.9
  IN2 w0.114: v2(72.95,69.66) 73.17,69.45 73.49,69.45 73.69,69.65 74.53,69.65 74.73,69.45 75.24,69.45 75.7,68.99 77.14,68.99 78.3,67.84 78.97,67.84 80.83,65.97 80.83,63.17 82.23,61.78 84.38,61.78 85.41,60.76 90.12,60.76 90.89,61.52 91.49,61.52 v2(91.75,61.78)
  BOTTOM w0.102: 71.5,69.96 71.49,69.98 71.45,69.98 70.76,70.67 69.78,70.67 69.4,71.05 69.4,72.75 69.78,73.13 69.78,73.41 69.74,73.46 69.74,73.55 69.78,73.59 UV1.AD30
  BOTTOM w0.112: 71.5,69.96 72.12,69.35 72.64,69.35 v2(72.95,69.66) ; v2(91.75,61.78) 92.01,61.51 92.16,61.51 92.23,61.59 92.23,62.88 91.12,64 91.12,77.02 92.06,77.96 92.06,80.95 93.72,82.62 93.72,88.11 94.8,89.19 94.8,89.84 99.75,94.79 99.75,96.17 103.2,99.62 107.42,99.62 111.56,103.76 111.56,110.67 110.36,111.87 110.36,115.29 110.76,115.7 120.51,115.7 121.72,114.48 127.95,114.48 128.58,115.12 140.67,115.12 141.25,114.54 141.25,112.79 142.93,111.1 143.81,111.1 144.62,110.3 145.04,109.88 145.04,109.53 CC23.1
PEG_CTX_GRX_P3: length 135.4
  IN2 w0.114: v2(74,68.77) 74.13,68.64 74.94,68.64 75.39,68.18 76.84,68.18 77.93,67.09 78.66,67.09 80.06,65.69 80.06,62.67 81.72,61.01 84.01,61.01 85.79,59.23 91.47,59.23 v2(91.75,59.51)
  BOTTOM w0.102: 70.11,70.04 69.43,70.04 68.92,70.55 68.92,73.15 68.87,73.2 68.87,73.4 68.92,73.45 68.92,73.95 68.84,74.03 68.84,74.15 68.85,74.16 68.98,74.21 UV1.AC29
  BOTTOM w0.112: 70.11,70.04 70.18,70.04 71.76,68.46 71.79,68.46 71.99,68.26 73.24,68.26 73.44,68.46 73.68,68.46 v2(74,68.77) ; v2(91.75,59.51) 92.02,59.24 92.31,59.24 93.12,60.05 93.12,63.45 92.13,64.44 92.13,76.13 92.94,76.94 92.94,80.55 94.62,82.22 94.62,87.74 95.69,88.81 95.69,89.46 100.64,94.41 100.64,95.79 103.53,98.68 107.83,98.68 112.71,103.56 112.71,111.18 112.4,111.49 112.4,113.92 112.96,114.48 120.45,114.48 121.72,113.21 128.47,113.21 129.11,113.85 138.94,113.85 142.58,110.21 142.86,110.21 143.24,109.83 143.24,109.55 CC25.1
PHASE: length 8.4
  TOP w0.102: PC525.2 v1(73.78,112.5)
  IN2 w0.762: 73.08,111.92 73.08,112.32 v2(77.91,117.15)
  vias: v2(72.57,111.05) v2(73.08,111.43) v2(78.54,117.78)
PHASE1: length 12.5
  IN2 w0.762: v3(51.25,50.35) 52.76,48.84 52.76,47.81 57.04,43.53 57.91,43.53 59.59,41.84 59.62,41.84
  vias: v1(50.86,54.61) v2(59.75,40.95) v2(60.38,40.44) v3(50.48,54.16) v3(50.48,53.4) v3(50.48,52.63) v3(50.48,51.87) v3(50.48,51.11) v3(50.48,50.35) v3(51.25,53.4) v3(51.25,52.63) v3(51.25,51.87) v3(51.25,51.11) v3(51.36,54.92) v3(51.36,54.16) v3(52,55.3) v3(52.13,55.94) v3(52.63,55.3) v3(52.76,55.94) v3(53.4,55.94) v3(53.52,55.05) v3(54.16,55.05) v3(54.79,55.05) v3(55.43,55.05) v3(56.06,55.05)
PHASE2: length 10.6
  IN1 w0.762: 63.68,41.46 64.32,41.46 69.91,47.05 v3(69.91,49.08)
  vias: v1(71.43,53.65) v2(63.3,41.08) v2(63.94,41.08) v3(69.78,54.79) v3(69.78,54.03) v3(69.78,53.27) v3(69.78,52.51) v3(69.78,51.74) v3(69.78,51.11) v3(69.78,50.47) v3(69.78,49.84) v3(70.41,54.79) v3(70.41,54.03) v3(70.41,53.27) v3(70.41,52.51) v3(70.41,51.74) v3(70.41,51.06) v3(70.41,50.4) v3(70.41,49.76) v3(70.67,49.08) v3(71.05,54.79) v3(71.05,54.03) v3(71.05,53.27) v3(71.05,52.51) v3(71.05,51.74) v3(71.06,51.06) v3(71.05,50.39) v3(71.05,49.75)
PLL_ANALOG_IN: length 1.4
  TOP w0.102: T221.1 67.87,95.31 v2(68.13,95.05)
  BOTTOM w0.102: UV1.AA1 67.6,94.52 v2(68.13,95.05)
PLL_ANALOG_OUT: length 8.8
  BOTTOM w0.102: UV1.AA3 67.57,93.7 67.24,94.04 67.24,94.8 68.26,95.81 70.16,95.81 70.92,96.58 70.92,97.54 71.56,98.18 v1(71.56,98.38) RV83.1
PLT_RST#: length 306.9
  TOP w0.102: CE36.1 128.43,12.91 UE1.13 132.21,12.91 v2(133.52,11.6) ; v2(182.11,63.64) 182.14,63.67 183.46,63.67 183.55,63.76 v4(184.13,63.76) 185.12,63.76 185.6,64.24 RM6.2 ; v2(172.65,103.05) 172.65,101.02 174.34,99.33 175.33,99.33 176.46,98.2 176.46,94.58 175.54,93.65 v2(175.44,93.65) 174.68,93.65 174.3,93.27 R159.1 173.81,92.77 173.78,92.74 UC3.4 ; UV2.2 v2(77.53,77.14) ; v2(81.97,78.16) RC51.1
  IN1 w0.107: v2(172.65,103.05) 172.65,101.66 171.89,100.89 170.11,100.89 168.46,102.54 164.39,102.54 161.73,105.21 161.73,113.34 157.54,117.53 145.14,117.53 143.59,115.98 132.04,115.98 128.25,112.2 117.98,112.2 117.48,111.7 v2(100.2,111.7) ; v2(165.69,6.56) 165.69,6.55 165.23,6.1 161.93,6.1 161.65,6.38 161.65,6.38 160.82,7.2 157.31,7.2 156.43,8.08 156.42,8.08 156.22,8.28 155.4,8.28 155.07,8.28 154.69,8.67 152.43,8.67 152.25,8.49 150.91,8.49 149.99,9.4 147.7,9.4 146.55,8.25 142.29,8.25 141.21,9.34 137.43,9.34 136.4,8.31 v2(136.4,8.26) ; v2(175.79,21.88) 176,22.09 176,35.89 176.35,36.24 176.35,43.15 177.02,43.82 177.02,48 178.35,49.33 178.35,53.32 180.41,55.38 180.41,58.95 180.69,59.24 180.69,61.75 182.11,63.17 v2(182.11,63.64) 182.38,63.91 182.38,70.07 180.16,72.29 180.16,87.28 177.01,90.44 177.01,91.5 175.44,93.06 v2(175.44,93.65)
  IN2 w0.102: 77.91,77.96 77.53,77.58 v2(77.53,77.14)
  IN2 w0.107: 77.91,77.96 78.44,78.49 81.59,78.49 81.92,78.16 v2(81.97,78.16) 82.1,78.03 82.1,77.4 82.73,76.76 84,76.76 87.18,79.94 87.18,85.02 90.1,87.94 90.86,87.94 91.24,88.32 91.24,92.13 97.28,98.16 97.28,99.56 96.83,100 v2(96.83,100.26)
  BOTTOM w0.102: v2(133.52,11.6) 133.52,11.14 v2(136.4,8.26) ; v2(96.83,100.26) 96.83,100.28 97.72,101.17 97.72,109.22 v2(100.2,111.7) ; RC51.1 v2(81.97,78.16) ; v2(175.79,21.88) 175.57,22.1 170.76,22.1 170.26,22.6 167.9,22.6 166.9,21.59 166.9,9.48 167.11,9.26 167.11,7.74 165.93,6.56 v2(165.69,6.56) ; UL1.19 172.74,102.96 v2(172.65,103.05)
PLT_RST#_R: length 4.1
  TOP w0.102: RM6.1 185.6,66.65 v1(185.35,66.91) 185.05,67.21 v2(184.74,67.21)
  BOTTOM w0.102: JNGFF.44 185.23,66.98 184.99,67.21 v2(184.74,67.21)
PLT_RST_VGA#: length 5
  TOP w0.102: v2(75.88,75.75) RV4.1 76.65,76.43 76.88,76.2 UV2.4 v4(76.88,74.68)
  BOTTOM w0.102: v2(75.88,75.75) 75.88,75.67 75.5,75.3 UV1.AL27
PM_APWROK_R: length 35.9
  TOP w0.076: 168.59,91.32 168.41,91.32 167.06,89.97 165.79,89.97 163.51,92.26 163.51,93.27 163.25,93.53 162.36,93.53 162.12,93.29 162.12,91.76 161.35,90.99 154.23,90.99 153.71,90.46 v2(153.5,90.46)
  TOP w0.102: 168.59,91.32 171.23,91.32 v4(171.38,91.16) 172.93,91.16 v2(173.23,90.86)
  IN1 w0.107: v2(172.55,94.85) 172.55,93.02 173.28,92.28 173.28,90.99 173.23,90.94 v2(173.23,90.86)
  BOTTOM w0.076: UC1.AB5 153.6,90.08 153.6,90.37 v2(153.5,90.46)
  BOTTOM w0.102: RP50.6 171,99.75 172.4,98.35 172.4,95.97 172.52,95.84 172.52,94.87 v2(172.55,94.85)
PROC_OPI_RCOMP: length 4.4
  TOP w0.305: RC134.1 148.65,76.38 148.27,76.76 v2(148.06,76.76)
  BOTTOM w0.076: UC1.AY15 147.52,77.31 v2(148.06,76.76)
PROJECT_ID: length 17.1
  IN2 w0.076: v2(153.14,96.19) 153.14,96.02 153.35,95.81 154.11,95.81 155.63,97.34 158.68,97.34
  IN2 w0.107: 158.68,97.34 160.58,97.34 160.86,97.06 162.57,97.06 163.53,96.09 164.62,96.09 v2(165.28,95.43)
  BOTTOM w0.076: UC1.L5 153.5,95.83 v2(153.14,96.19)
  BOTTOM w0.102: v2(165.28,95.43) 165.28,95.2 v1(165.65,94.83) 165.81,94.67 RC113.1 RC112.2
PS_0: length 14.2
  TOP w0.102: RV8.2 78.85,83.21 78.62,82.99 76.76,82.99 76.56,83.19 CV29.1 RV9.1 76.13,84.76 75.67,84.31 v1(75.67,84) 75.67,83.7 v2(75.88,83.49)
  IN1 w0.107: v2(75.88,83.49) 73.34,83.49 71.81,81.96 70.77,81.96 70.63,81.82 70.2,81.82 v2(69.69,81.31)
  BOTTOM w0.102: UV1.AC19 69.2,81.8 v2(69.69,81.31)
PS_1: length 13
  TOP w0.102: RV12.1 76.56,80.78 76.76,80.57 78.67,80.57 78.85,80.75 RV11.2 ; RV12.1 CV28.1 v2(75.88,82.35) ; RV12.1 v1(75.6,81.21)
  IN1 w0.107: v2(70.4,81.3) 70.43,81.3 70.86,81.74 71.91,81.74 72.73,82.56 75.67,82.56 v2(75.88,82.35)
  BOTTOM w0.102: v2(70.4,81.3) 70,81.7 UV1.AD19
PS_2: length 12.6
  TOP w0.102: CV11.1 75.77,85.91 75.65,85.78 v1(75.65,85.63) 75.65,85.37 v2(75.88,85.15) ; CV11.1 RV13.1 ; CV11.1 76.56,85.48 76.76,85.27 78.67,85.27 78.97,85.58 RV28.2
  IN1 w0.107: v2(71.17,82.56) 72.51,83.9 73.98,83.9 75.23,85.15 v2(75.88,85.15)
  BOTTOM w0.102: v2(71.17,82.56) 70.8,82.94 UV1.AE17
PS_3: length 11.9
  TOP w0.102: v2(75.88,80.07) CV15.1 RV16.1 ; RV16.1 v1(75.62,79.05) ; RV16.1 76.56,78.74 76.76,78.54 78.67,78.54 78.85,78.72 RV15.2
  IN1 w0.107: v2(71.11,81.29) 71.5,80.91 75.29,80.91 75.88,80.32 v2(75.88,80.07)
  BOTTOM w0.102: UV1.AE20 70.8,80.98 v2(71.11,81.29)
PS_ID: length 222.6
  TOP w0.102: PR3.1 v2(25.33,101.78) PR4.2 ; v2(119.26,4.89) 119.26,6.99 118.07,8.18 117.63,8.18 116.64,9.17 v2(116.64,11.68) ; UE1.16 v1(127.06,11.71) 125.69,11.71 v2(125.18,12.22)
  IN1 w0.107: v2(119.26,4.89) 119.11,4.89 117.89,3.67 113.66,3.67 113.47,3.48 109.91,3.48 109.4,3.99 109.4,5.64 109.02,6.02 108.49,6.02 107.81,6.7 107.3,6.7 102.04,11.96 102.04,20.88 100.71,22.21 99.14,22.21 91.33,30.01 78.89,30.01 78.87,29.99 77.43,29.99 75.88,31.55 55.94,31.55 55.23,30.84 50.55,30.84 48.06,33.33 48.06,38.54 46.79,39.81 37.37,39.81 36.49,40.69 30.04,40.69 28.12,42.6 24.69,42.6 20.5,46.79 20.5,48.68 17.82,51.36 15.31,53.87 15.31,57.03 15.53,57.25 15.53,71.2 9.96,76.76 9.96,81.34 10.72,82.1 10.72,95.56 13.01,97.85 13.65,97.85 17.58,101.78 v2(25.33,101.78)
  IN2 w0.107: v2(116.64,11.68) 116.88,11.92 117.33,11.92 117.79,11.46 122.94,11.46 123.53,12.04 125,12.04 v2(125.18,12.22)
PSID: length 6.6
  TOP w0.508: PJPDC.1 v1(21.51,108.96) 21.52,107.29 PL2.2
PSID-1: length 3.7
  TOP w0.102: PQ5.2 v1(21.76,98.55)
  TOP w0.508: PR6.1 PR9.2 21.47,100 PQ5.2
PSID-2: length 6.2
  TOP w0.102: PQ6.2 20.61,103.41 v1(20.22,103.79)
  TOP w0.508: PR8.2 24.1,101.31 PQ5.1 21.95,101.77 PQ6.2
PSID-3: length 3.9
  TOP w0.102: PR11.2 25.79,104.37 v1(26.47,105.06)
  TOP w0.508: PR11.2 PR4.1 23.91,103.38 PQ6.3
PTP_DIS#: length 168
  TOP w0.102: JTP1.5 v2(22.66,58.86) ; v1(77.15,30.81) 77.24,30.72 v2(77.98,30.72) ; v2(134.42,4.86) 134.62,4.66 UE1.38
  IN1 w0.107: v2(22.66,58.86) 22.53,58.73 20.76,58.73 20.12,58.09 20.12,55.19 21.15,54.16 21.15,46.9 24.95,43.11 28.5,43.11 29.2,42.41 35.43,42.41 37.52,40.31 47.05,40.31 48.95,38.41 48.95,33.33 50.93,31.35 54.97,31.35 55.68,32.06 63.56,32.06 63.81,32.31 76.39,32.31 v2(77.98,30.72)
  IN2 w0.107: v2(134.42,4.86) 134.27,4.86 133.03,3.61 125.19,3.61 123.9,2.31 119.09,2.31 118.35,3.05 107.27,3.05 106.64,3.69 106.64,13.87 105.78,14.72 105.78,17.33 99.65,23.46 96.66,23.46 90.28,29.85 78.85,29.85 v2(77.98,30.72)
  BOTTOM w0.102: RC78.1 23.33,59.53 v2(22.66,58.86)
PTP_KBBL#: length 153.7
  TOP w0.102: v2(19.66,58.32) JTP1.2 19.66,61.02 19,61.68 RE339.2 v1(17.74,62.23) ; UE1.120 135.82,18.19 136.06,17.96 v2(136.06,16.11)
  IN2 w0.107: v2(19.66,58.32) 20.18,57.8 20.18,56.36 20.65,55.89 20.65,55.63 25.36,50.92 27.99,50.92 28.34,50.57 32.15,50.57 32.24,50.49 42.06,50.49 45.29,47.25 45.29,43.87 49.15,40.01 49.15,33.54 51.76,30.93 56.88,30.93 57.67,31.72 75.95,31.72 77.09,32.86 79.31,32.86 79.98,32.19 80.75,32.19 80.89,32.05 81.19,32.05 81.49,32.35 83.33,32.35 83.69,31.98 86.5,31.98 87.1,32.58 87.82,32.58 88.17,32.23 92.35,32.23 98.37,26.22 101.23,26.22 101.3,26.15 101.47,26.15 108.67,18.94 108.67,18.01 110.08,16.61 113.27,16.61 113.56,16.9 116.54,16.9 117.27,16.17 119.98,16.17 120.63,16.82 123.22,16.82 123.26,16.85 123.26,16.85 123.5,17.09 123.84,17.09 124.22,16.71 125.92,16.71 126.3,16.32 133.79,16.32 134.02,16.1 134.32,16.1 134.8,15.62 135.57,15.62 v2(136.06,16.11)
PWR_SRC_ON:
  vias: v1(8.57,73.77)
PX_EN: length 2.5
  TOP w0.102: T218.1 69.78,85.27 69.48,85.27 v2(69.1,84.9)
  BOTTOM w0.102: v2(69.1,84.9) 68.4,84.2 UV1.AB16
PXS_PWREN: length 452.7
  TOP w0.254: v2(81.84,27.74) 82.61,28.5 87.43,28.5 90.26,25.67 v2(90.26,25.14) ; v2(81.69,47.4) 81.69,48.67 81.72,48.7 v1(81.72,51.16) 81.72,51.49 81.82,51.59 v2(81.82,52.32)
  IN2 w0.254: v2(181.08,67.97) 179.79,69.27 179.79,77.78 177.74,79.84 175.45,79.84 174.41,80.88 174.34,80.88 173.55,81.68 173.55,82.91 173.54,82.91 173.54,82.99 171.58,84.94 171.58,85.32 170.95,85.96 170.95,87.51 170.52,87.94 170.52,91.14 170.01,91.65 169.07,91.65 166.68,94.04 165,94.04 164.62,93.65 163.52,93.65 v2(163,93.13) 162.76,93.13 162.74,93.15 162.16,93.15 162.09,93.21 161.23,93.21 159.49,94.95 155.66,94.95 153.98,93.27 v2(153.72,93.27) ; v2(183.04,68.58) 184.11,67.52 184.11,61.07 187.15,58.02 187.15,52.99 187.23,52.91 187.23,51.28 186.71,50.76 186.71,44.2 188.27,42.63 188.27,37.52 185.98,35.23 185.98,30.92 184.13,29.06 184.13,20.43 181.11,17.4 181.11,15.65 179.3,13.85 176.94,13.85 174.86,11.76 172.5,11.76 170.85,13.42 169.78,13.42 168.92,14.28 166.93,14.28 165.92,13.26 160.78,13.26 159.86,14.18 153.39,14.18 152.74,14.84 150.45,14.84 149.67,15.61 147.09,15.61 146.64,15.17 141.75,15.17 141.5,15.42 139.04,15.42 138.79,15.67 138.2,15.67 137.63,15.1 134.63,15.1 134.61,15.12 134.6,15.12 134.14,15.59 133.44,15.59 133.1,15.24 129.94,15.24 129.47,15.72 126.21,15.72 125.79,16.14 121.88,16.14 121.88,16.14 120.92,16.14 120.92,16.14 120.54,16.14 120.23,15.83 117.17,15.83 117.16,15.82 116.37,15.82 116.23,15.96 114.72,15.96 114.6,15.84 114.37,16.06 109.85,16.06 108.13,17.78 108.13,18.71 101.24,25.6 97.06,25.6 95.32,27.34 95.32,28.35 94.33,29.33 93.33,29.33 91,31.66 90.74,31.66 90.73,31.67 83.56,31.67 83.2,32.03 81.95,32.03 v2(81.72,31.8) 81.58,31.66 80.83,31.66 80.61,31.88 79.85,31.88 79.18,32.56 77.22,32.56 76.08,31.42 57.8,31.42 56.69,30.31 52.61,30.31 v2(52.51,30.41) 51.73,30.41 48.84,33.3 48.84,39.79 47.43,41.2 32.31,41.2 v2(32.19,41.33) 30.28,41.33 29.09,42.52 29.09,49.38 27.86,50.61 25.14,50.61 19.42,56.33 12.53,56.33 12.02,56.84 12.02,58.85 11.96,58.91 11.96,65.96 12.55,66.55 17.72,66.55 20.77,69.61 20.77,72.04 11.72,81.09 11.72,83.79 12.02,84.09 12.02,89.24 20.12,97.34 24.44,97.34 29.2,102.1 32.76,102.1 33.23,102.57 33.23,103.71 33.84,104.32 36.25,104.32 v2(37.01,105.08)
  BOTTOM w0.076: v2(153.72,93.27) 153.72,93.27 153.91,93.46 153.91,93.75 154.19,94.03 UC1.P4
  BOTTOM w0.254: v2(81.69,47.4) 81.84,47.25 81.84,33.58 81.72,33.46 v2(81.72,31.8) 81.72,27.87 v2(81.84,27.74) ; v2(81.82,52.32) 81.82,52.42 81.37,52.86 80.46,52.86 77.39,55.94 PR1300.1 ; v2(37.01,105.08) 37.01,105.72 39.68,108.39 40.06,108.39 41.2,109.53 41.2,111.43 41.79,112.02 RV25.1 ; v2(52.51,30.41) 52.51,30.15 54.03,28.63 58.4,28.63 60.25,30.48 PR1027.1 ; RP54.4 163.18,93.31 v2(163,93.13) ; v2(181.08,67.97) 181.69,68.58 v2(183.04,68.58) ; v2(32.19,41.33) 31.93,41.08 PR1103.1 ; PR601.2 90.66,25.53 v2(90.26,25.14)
REGN: length 19.2
  TOP w0.254: v2(38.06,10.01) 37.94,10.13 v1(37.94,14.83) v2(37.94,17.16)
  BOTTOM w0.203: PU701.19 41.28,14.3 40.43,15.15 40.43,16.93 40.19,17.17 PR710.1
  BOTTOM w0.254: v2(38.06,10.01) 38.19,9.87 PR707.1 40.6,9.87 40.6,9.38 40.2,8.98 40.2,8.13 PD700.2 ; v2(37.94,17.16) 38.04,17.26 PC709.2 39.07,17.26 39.16,17.17 PR710.1
REMOTE1+: length 85.2
  TOP w0.254: U2407.2 155.26,6.92 v2(155.09,6.75)
  IN1 w0.254: v2(155.09,6.75) 153.66,6.75 153.6,6.68 151.05,6.68 150.97,6.76 148.02,6.76 145.66,4.4 126.5,4.4 125.61,5.29 121.96,5.29 120.97,6.28 118.62,6.28 117.47,5.12 114.69,5.12 112.67,7.14 110.71,7.14 109.68,8.17 108.08,8.17 103.24,13.01 103.24,22.24 102.63,22.85 102.11,22.85 101.35,23.62 100.09,23.62 95.05,28.66 94.63,28.66 94.6,28.63 v2(94.35,28.63)
  BOTTOM w0.254: C2502.1 C2500.1 Q2407.1 93.81,30.83 94.46,30.18 Q2407.2 94.46,28.73 v2(94.35,28.63)
REMOTE1-: length 87.3
  TOP w0.254: 155.76,8.32 155.76,7.43 155.84,7.36 v2(155.84,6.65)
  IN1 w0.254: v2(94.84,28.15) 99.88,23.11 101.14,23.11 101.9,22.34 102.42,22.34 102.74,22.03 102.74,12.74 107.84,7.64 109.45,7.64 111.23,5.87 111.23,5.55 111.58,5.2 113.58,5.2 114.22,4.56 117.67,4.56 118.86,5.75 120.76,5.75 121.79,4.72 125.29,4.72 126.13,3.88 145.8,3.88 148.08,6.16 150.55,6.16 150.56,6.18 153.82,6.18 153.88,6.24 155.53,6.24 155.84,6.54 v2(155.84,6.65)
  BOTTOM w0.254: C2502.2 C2500.2 92.89,30.61 93.16,30.34 Q2407.3 93.16,29.14 94.15,28.15 v2(94.84,28.15)
REMOTE2+: length 144.8
  TOP w0.254: v2(152.95,9.76) 153.05,9.66 155.01,9.66 155.26,9.91 155.87,9.91 156.26,9.52 U2407.4 ; v2(110.69,84.32) 110.85,84.15 110.85,78.74 97.87,65.76 v1(97.87,63.8) 97.87,57.9 93.25,53.28 93.25,51.42 90.71,48.88 90.71,46.68 v2(90.26,46.23)
  IN1 w0.254: v2(152.95,9.76) 151.96,9.76 151.5,10.22 147.07,10.22 146.75,9.9 142.47,9.9 141.36,11.02 133.43,11.02 132.73,11.71 130.89,11.71 130.37,12.23 125.88,12.23 125.43,12.68 124.99,12.68 124.51,12.2 119.29,12.2 118.66,12.83 112.53,12.83 112.28,13.08 110.77,13.08 107.66,16.18 107.66,24.01 103.68,27.99 101.91,27.99 95.47,34.43 95.47,34.73 94.75,35.45 94.27,35.45 92.56,37.15 91.6,38.11 91.6,39.86 90.01,41.45 90.01,42.19 89.48,42.73 89.48,45.22 90.26,46 v2(90.26,46.23)
  BOTTOM w0.254: v2(110.69,84.32) 111.19,83.81 C2504.1 C2505.1 110.86,82.15 Q2408.1 110.86,80.7 111.51,80.05 Q2408.2
REMOTE2-: length 143.9
  TOP w0.254: U2407.5 156.76,9.86 156.2,10.42 154.88,10.42 154.65,10.19 v2(153.42,10.19) ; v2(110.1,84.29) 110.27,84.13 110.27,78.93 v1(97.32,65.99) 97.32,58.12 92.67,53.47 92.67,51.63 90.16,49.13 90.16,47.06 v2(90.1,46.99)
  IN1 w0.254: v2(153.42,10.19) 153.31,10.3 152.17,10.3 151.82,10.66 146.52,10.66 146.3,10.43 144.48,10.43 144.1,10.81 142.4,10.81 141.84,11.37 134.89,11.37 134.13,12.13 131.01,12.13 130.52,12.62 126.21,12.62 125.79,13.03 124.61,13.03 124.28,12.71 119.99,12.71 119.36,13.34 112.92,13.34 112.61,13.65 110.92,13.65 109.92,14.65 108.17,16.39 108.17,24.22 103.81,28.58 102.05,28.58 96.04,34.59 96.04,34.95 95.04,35.95 94.48,35.95 92.77,37.66 92.11,38.32 92.11,40.07 90.52,41.66 90.52,45.54 90.77,45.79 90.77,46.44 90.22,46.99 v2(90.1,46.99)
  BOTTOM w0.254: v2(110.1,84.29) 110.1,84.08 110.28,83.9 C2504.2 C2505.2 110.09,82.29 110.09,80.46 110.21,80.33 Q2408.3
RF_+1.35VGPUP: length 3.5
  BOTTOM w0.254: PR1105.1 30.03,49.08 v1(29.86,48.91) 29.65,48.7 29.65,47.68 29.93,47.39 PU1100.5
RING2: length 20.3
  IN2 w1.016: v2(190.3,30.15) 190.3,29.27 191.8,27.77 191.8,25.88 191.14,25.22 191.14,24.16 192.44,22.86 192.44,21.55 190.88,20 190.88,18.36 191.58,17.66 191.97,17.66 v2(191.97,17.66)
  BOTTOM w0.203: v2(191.97,17.66) 191.97,17.84 193.02,18.89 UA1.17
  BOTTOM w0.508: LA10.2 190.18,31.55 189.74,31.12 RA1109.1 189.74,30.71 v2(190.3,30.15)
RING2_R: length 13.1
  TOP w0.102: v2(196.53,31.47) v1(195.81,31.47)
  IN2 w1.016: 199.83,37.93 199.22,37.93 196.4,35.11 196.4,32.69
  BOTTOM w0.508: v2(197.29,31.47) v2(196.53,31.47) DA12.2 193.76,31.47 CA40.1 192.72,31.75 192.52,31.55 LA10.1
RST#: length 64
  TOP w0.102: PQ706.6 PR713.2 14.71,39.73 15.27,40.29 v1(15.27,41.3) 15.27,41.56 16.82,43.11 v2(17.56,43.11)
  IN1 w0.107: v2(43.24,11.05) 43.24,11.45 42.18,12.5 35.67,12.5 33,15.17 24.37,15.17 23.34,16.2 23.34,22.02 24.3,22.98 24.89,22.98 26.36,24.45 26.36,31.8 23.04,35.11 23.04,37.79 23.48,38.22 23.48,40.1 20.47,43.11 v2(17.56,43.11)
  BOTTOM w0.203: PU701.13 43.33,11.14 v2(43.24,11.05)
RSVD_AL1: length 4.1
  TOP w0.076: T136.1 158.68,84.71 v2(158.68,84.13)
  BOTTOM w0.076: UC1.AL1 156.97,85.07 157.28,84.76 158.04,84.76 v2(158.68,84.13)
RSVD_AM11: length 1.4
  TOP w0.102: v2(149.54,83.98) 149.54,83.97 149.81,83.97 T137.1
  BOTTOM w0.076: UC1.AM11 149.88,84.28 149.57,83.98 v2(149.54,83.98)
RSVD_AP7: length 2.6
  TOP w0.076: T139.1 153.19,83.26 v2(152.83,83.62)
  BOTTOM w0.076: v2(152.83,83.62) 152.51,83.31 UC1.AP7
RSVD_AT2: length 2.8
  TOP w0.076: v2(157.3,82.12) 157.3,82.11 T128.1
  BOTTOM w0.076: v2(157.3,82.12) 157.2,82.23 156.68,82.23 156.36,82.54 155.84,82.54 155.49,82.2 UC1.AT2
RSVD_AU10: length 2.2
  TOP w0.076: v2(149.92,81.82) 149.92,80.55 T141.1
  BOTTOM w0.076: v2(149.92,81.82) 149.98,81.82 150.44,81.36 UC1.AU10
RSVD_AU15: length 1.2
  TOP w0.076: T142.1 147.74,80.97 v2(147.9,80.97)
  BOTTOM w0.076: UC1.AU15 147.5,81.36 v2(147.9,80.97)
RSVD_AU44: length 1.4
  TOP w0.076: v2(128.84,82.01) 128.48,82.37 T132.1
  BOTTOM w0.076: v2(128.84,82.01) 128.84,81.46 UC1.AU44
RSVD_AV44: length 1
  TOP w0.076: T134.1 128.92,80.7 v2(128.61,80.38)
  BOTTOM w0.076: v2(128.61,80.38) 128.93,80.71 UC1.AV44
RSVD_AW14: length 2.9
  TOP w0.076: v2(148.06,78.51) 147.25,79.32 T144.1
  BOTTOM w0.076: UC1.AW14 148.27,79.85 147.98,79.56 147.98,78.59 v2(148.06,78.51)
RSVD_AY14: length 3
  TOP w0.076: v2(148.09,77.96) 148.65,78.52 T145.1
  BOTTOM w0.076: v2(148.09,77.96) 148.42,78.29 148.42,78.9 148.27,79.05 UC1.AY14
RSVD_D15: length 2
  TOP w0.076: T135.1 147.87,100.88 v2(147.71,100.88)
  BOTTOM w0.076: UC1.D15 v2(147.71,100.88)
RSVD_F22: length 1.7
  TOP w0.076: v2(143.96,99.08) 143.78,99.08 T138.1
  BOTTOM w0.076: UC1.F22 143.65,98.98 143.75,99.08 v2(143.96,99.08)
RSVD_H22: length 2
  TOP w0.076: T140.1 143.16,97.75 v2(143.98,97.75)
  BOTTOM w0.076: UC1.H22 143.69,97.46 v2(143.98,97.75)
RSVD_J21: length 1.5
  TOP w0.076: v2(143.98,96.35) 143.98,96.42 T143.1
  BOTTOM w0.076: UC1.J21 144.04,96.42 v2(143.98,96.35)
RSVD_N23: length 2.4
  TOP w0.076: v2(142.05,94.96) 142.62,95.54 143.04,95.54 T129.1
  BOTTOM w0.076: UC1.N23 142.4,94.61 v2(142.05,94.96)
RSVD_R23: length 2.7
  TOP w0.076: v2(142.07,94.18) 142,94.18 141.61,94.57 141.61,95.36 T130.1
  BOTTOM w0.076: UC1.R23 142.45,93.8 v2(142.07,94.18)
RSVD_T23: length 1.8
  TOP w0.076: v2(142.05,93.4) 142.05,93.45 T131.1
  BOTTOM w0.076: v2(142.05,93.4) 142.46,92.99 UC1.T23
RSVD_U10: length 4.9
  TOP w0.076: T133.1 146.3,92.07 v2(147.34,92.07)
  BOTTOM w0.076: UC1.U10 150.42,93.08 148.35,93.08 v2(147.34,92.07)
RTC_DIS: length 74.8
  TOP w0.102: v2(134.14,16.51) 133.66,17 133.65,17 133.42,17.23 UE1.126 ; 155.95,65.82 156.71,65.06 RC368.1 156.71,57.57 155.6,56.45 155.6,37.59 156.15,37.04 156.15,26.03 154.87,24.75 153.04,24.75 152.86,24.56 151.21,24.56 150.83,24.18 v2(150.83,23.43) ; 155.95,65.82 157.85,65.82 QC2.2 ; 155.95,65.82 QC2.5
  BOTTOM w0.102: v2(150.83,23.43) 150.33,23.93 148.67,23.93 148.33,24.27 147.26,24.27 146.61,23.62 146.61,20.4 145.28,19.08 143.85,19.08 141.77,16.99 134.62,16.99 v2(134.14,16.51)
RTC_VOUT: length 5.2
  TOP w0.102: v1(182.01,80.47) 182.01,79.81 RG2.2
  TOP w0.203: CG6.1 183.51,78.63 183.51,78.03 184.56,78.03 184.78,78.25 UG1.14
  TOP w0.254: RG2.2 182.56,79.58 CG6.1
RUNPWROK: length 157.8
  TOP w0.102: UC4.1 88.52,86.34 88.7,86.16 88.83,86.16 89.08,85.91 89.08,84.64 88.7,84.26 88.12,84.26 v1(87.88,84.5) 87.7,84.68 86.04,84.68 85.65,85.07 v2(85.65,85.78) 86.39,86.52 86.39,87.28 86.56,87.45 UC4.13 ; v2(84.89,87.05) 84.89,87.69 85.35,88.14 CC29.1 85.85,88.95 UC4.10 ; UE1.36 133.82,4.59 133.28,5.14 133.28,6.28 134.04,7.04 137.75,7.04 139.5,8.79 139.5,9.21 138.96,9.75 v2(138.96,10.19) ; v2(90.61,88.45) UC4.4
  IN1 w0.107: v2(90.61,88.45) 89.34,87.18 89.34,82.73 88.88,82.27 88.88,70.74 89.49,70.13 89.49,67.43 89.34,67.28 89.34,50.6 87.94,49.2 87.94,40.39 94.05,34.28 v2(94.39,34.28) ; v2(138.96,10.19) 137.09,10.19 135.44,8.54 133.86,8.54 133.72,8.68 133.72,8.71 133.37,9.05 133.35,9.05 132.16,10.24 130.41,10.24 129.73,10.92 117.71,10.92 v2(117.18,11.45)
  IN2 w0.107: v2(85.65,85.78) 86.92,85.78 89.59,88.45 v2(90.61,88.45)
  BOTTOM w0.102: v2(84.89,87.05) 85.65,86.29 v2(85.65,85.78) ; v2(117.18,11.45) 117.18,11.74 115.79,13.14 106.93,13.14 103.9,16.16 103.9,19.38 101.85,21.44 101.85,22.67 103.16,23.98 103.16,30.92 100.39,33.68 94.99,33.68 v2(94.39,34.28)
SATA_ACT#: length 247.7
  TOP w0.102: JLED.7 12.97,52.3 12.18,52.3 11.04,53.44 11.04,55.63 v2(11.56,56.14) ; v2(94.43,100.72) v1(93.81,100.72)
  IN1 w0.076: v2(158.27,93.45) 158.37,93.35 158.73,93.35
  IN1 w0.107: 158.73,93.35 160.89,93.35 160.9,93.36 162.55,93.36 163.63,94.44 163.63,99.12 163.12,99.62 162.84,99.62 159.89,102.58 158.24,102.58 157.54,101.88 156.93,101.88 156.33,102.48 155.73,102.48 155.64,102.39 151.91,102.39 150.78,103.52 150.78,104.99 148.27,107.5 132.26,107.5 132.14,107.62 128.2,107.62 127.82,107.24 126.29,107.24 125.41,108.13 122.1,108.13 121.72,108.51 121.07,108.51 118.67,106.12 110.57,106.12 106.86,102.42 103.05,102.42 99.12,106.35 96.58,106.35 v2(96.32,106.61)
  IN2 w0.107: v2(94.43,100.72) 92.97,100.72 89.54,97.29 83.29,97.29 82.1,98.48 79.69,98.48 79.43,98.23 70.03,98.23 69.4,98.86 68.51,98.86 66.99,100.39 66.6,100.39 65.64,101.35 65.64,102.24 62.29,105.59 57.97,105.59 56.14,107.42 54.62,107.42 51.52,104.32 40.57,104.32 39.81,105.08 37.9,105.08 37.39,105.59 36.38,105.59 35.49,104.7 33.33,104.7 32.31,103.69 32.31,102.93 31.81,102.42 29.01,102.42 24.31,97.72 20,97.72 11.64,89.36 11.64,84.31 10.78,83.44 10.78,81.58 20.39,71.96 20.39,69.79 17.53,66.93 12.39,66.93 11.62,66.16 11.62,58.93 11.04,58.35 11.04,56.66 v2(11.56,56.14)
  BOTTOM w0.076: UC1.U3 155.09,92.28 155.61,92.28 155.85,92.51 155.85,92.69 156.02,92.86 156.26,92.86 156.39,92.73 157.12,92.73 157.84,93.45 v2(158.27,93.45)
  BOTTOM w0.102: v2(94.43,100.72) 94.43,101.46 96.07,103.1 96.07,106.35 v2(96.32,106.61)
SATA_IREF: length 6.6
  BOTTOM w0.254: UC1.A12 149.02,102.97
  BOTTOM w0.305: RC126.1 149.02,107.18 v1(149.02,103.71) 149.02,102.97
SATA_PRX_DTX_N0: length 7.7
  TOP w0.112: v2(177.6,12.39) 177.78,12.56 v3(178.74,12.56) 179.37,12.56 CS31.2
  BOTTOM w0.112: v2(177.6,12.39) 177.81,12.6 179.12,12.6 180.41,11.31 180.93,11.31 181.26,11.64 181.26,11.82 181.53,12.09 JHDD.2
SATA_PRX_DTX_N0_C: length 118.7
  TOP w0.112: v2(191.23,11.92) 190.96,12.18 190.52,12.18 190.2,11.87 CS33.1
  IN2 w0.076: v2(153.12,97.15) 153.37,97.38 153.45,97.38 153.89,97.38 155.59,99.08 158.62,99.08 158.66,99.04 158.68,99.04
  IN2 w0.114: v2(191.23,11.92) 191.02,12.13 190.2,12.13 189.89,12.44 189.89,15.11 185.58,19.42 185.58,21.84 185.74,22 185.74,29.5 186.62,30.38 186.62,34.96 188.91,37.24 188.91,42.85 187.27,44.48 187.27,50.26 188.53,51.52 188.53,57.45 185.07,60.91 185.07,63.38 185.35,63.66 185.35,68.12 182.07,71.4 182.07,76.03 181.35,76.75 181.35,77.95 181.36,77.95 181.36,79.25 179.95,80.65 178.78,80.65 177.61,81.82 176.98,81.82 173.8,85.01 173.8,86.95 172.2,88.55 172.2,91.7 168.74,95.15 167.83,95.15 166.38,96.6 163.73,96.6 162.29,98.04 162.29,98.58 161.84,99.04 158.68,99.04
  BOTTOM w0.076: UC1.J5 153.45,96.82 v2(153.12,97.15)
SATA_PRX_DTX_N0_R: length 2.8
  TOP w0.112: CS31.1 180.89,12.49 181.28,12.49 181.28,12.49 182.48,12.49 182.6,12.37 US2.12
SATA_PRX_DTX_N0_RC: length 2.1
  TOP w0.112: CS33.2 188.52,12.22 188.3,12.22 188.03,12.49 187.79,12.49 187.67,12.37 US2.4
SATA_PRX_DTX_P0: length 7.4
  TOP w0.112: CS34.2 179.37,12.82 177.84,12.82 v2(177.58,13.08)
  BOTTOM w0.112: JHDD.1 180.73,12.09 181.01,11.82 181.01,11.75 180.82,11.56 180.52,11.56 179.22,12.86 177.8,12.86 v2(177.58,13.08)
SATA_PRX_DTX_P0_C: length 118.7
  TOP w0.112: v2(191.23,12.7) 190.96,12.44 190.52,12.44 190.2,12.76 CS35.1
  IN2 w0.076: 158.68,99.28 158.66,99.28 158.62,99.24 155.53,99.24 153.82,97.54 153.45,97.54 153.37,97.54 v2(153.14,97.8)
  IN2 w0.114: v2(191.23,12.7) 190.9,12.37 190.3,12.37 190.14,12.54 190.14,15.21 185.83,19.52 185.83,21.74 185.98,21.9 185.98,29.39 186.87,30.28 186.87,34.85 189.15,37.13 189.15,42.95 187.52,44.59 187.52,50.16 188.78,51.41 188.78,57.55 185.32,61.01 185.32,63.27 185.6,63.56 185.6,68.23 182.32,71.51 182.32,76.14 181.6,76.85 181.6,77.7 181.6,79.35 180.05,80.9 178.88,80.9 177.71,82.07 177.08,82.07 174.05,85.11 174.05,87.05 172.45,88.65 172.45,91.8 168.84,95.4 167.93,95.4 166.48,96.85 163.84,96.85 162.54,98.15 162.54,98.68 161.94,99.28 158.68,99.28
  BOTTOM w0.076: v2(153.14,97.8) 153.21,97.8 UC1.H5
SATA_PRX_DTX_P0_R: length 2.9
  TOP w0.112: CS34.1 181.04,12.74 v3(181.72,12.74) 182.49,12.74 182.62,12.87 US2.11
SATA_PRX_DTX_P0_RC: length 2
  TOP w0.112: US2.5 187.7,12.87 187.82,12.74 188.14,12.74 188.4,12.48 188.6,12.48 CS35.2
SATA_PTX_DRX_N0: length 11.6
  TOP w0.112: CS32.2 179.84,11.23 179.52,10.91 177.89,10.91 177.65,11.15 v2(177.65,11.18)
  BOTTOM w0.112: v2(177.65,11.18) 177.65,11.15 177.95,10.86 178.17,10.86 178.53,10.5 178.53,9.65 178.74,9.44 181.64,9.44 183.41,11.21 183.41,11.61 183.13,11.88 JHDD.4
SATA_PTX_DRX_N0_C: length 140.8
  TOP w0.112: CS36.1 190.2,10.98 190.52,10.66 190.96,10.66 v2(191.23,10.92)
  IN2 w0.114: v2(147.58,104.35) 147.83,104.6 148.19,104.6 148.57,104.98 148.72,104.98 148.98,105.24 148.98,105.4 149.21,105.62 149.39,105.62 149.66,105.9 149.66,106.07 149.83,106.25 150.02,106.25 150.27,106.5 150.27,106.68 151.04,107.45 151.51,107.45 151.64,107.32 152,107.32 152.13,107.45 152.43,107.45 152.56,107.32 152.94,107.32 153.07,107.45 153.33,107.45 153.46,107.32 153.85,107.32 153.99,107.45 154.8,107.45 155.73,108.39 156.93,108.39 157.59,107.73 157.59,106.43 158.5,105.52 158.5,103.1 160.26,101.35 160.26,101.09 161.5,99.85 162.93,99.85 165.36,97.41 167.52,97.41 169.07,95.86 169.17,95.86 173.72,91.32 173.72,88.17 174.81,87.07 174.81,85.04 176.77,83.09 177.76,83.09 178.32,82.52 179.26,82.52 182.58,79.2 182.58,76.74 183.06,76.26 183.06,71.53 186.52,68.08 186.52,60.51 190.43,56.6 190.43,52.15 188.02,49.74 188.02,44.8 189.07,43.75 189.95,43.75 191.29,42.4 191.29,41.23 191.12,41.06 191.12,38.18 187.39,34.45 187.39,30.03 186.5,29.14 186.5,21.62 186.42,21.54 186.42,19.63 191.96,14.09 191.96,10.95 191.58,10.57 191.32,10.57 191.23,10.66 v2(191.23,10.92)
  BOTTOM w0.076: UC1.B15 146.96,101.57 147.06,101.61 147.13,101.57 147.16,101.55 147.46,101.55 147.69,101.79 147.69,102.29 147.1,102.88 147.1,104.35 147.28,104.53 147.4,104.53 v2(147.58,104.35)
SATA_PTX_DRX_N0_R: length 2.2
  TOP w0.112: CS36.2 188.6,10.7 188.4,10.7 188.3,10.8 188.3,10.95 188.04,11.21 187.76,11.21 187.6,11.37 US2.2
SATA_PTX_DRX_N0_RC: length 3
  TOP w0.112: US2.14 182.75,11.37 182.63,11.24 182.48,11.24 182.06,10.82 181.16,10.82 CS32.1
SATA_PTX_DRX_P0: length 11.8
  TOP w0.112: CS30.2 179.84,10.34 179.52,10.66 v3(178.84,10.66) 177.76,10.66 v2(177.67,10.56)
  BOTTOM w0.112: JHDD.5 183.93,11.88 183.66,11.61 183.66,11.11 181.74,9.19 178.64,9.19 178.28,9.55 178.28,10.4 178.07,10.61 177.71,10.61 v2(177.67,10.56)
SATA_PTX_DRX_P0_C: length 140.8
  TOP w0.112: CS37.1 190.2,10.09 190.52,10.4 190.96,10.4 v2(191.23,10.14)
  IN2 w0.114: v2(147.58,105) 147.58,104.93 147.66,104.85 147.72,104.85 148.08,104.85 150.94,107.7 154.7,107.7 155.63,108.64 157.03,108.64 157.84,107.83 157.84,106.53 158.75,105.62 158.75,103.21 160.51,101.45 160.51,101.2 161.61,100.1 163.03,100.1 165.47,97.66 167.62,97.66 169.17,96.11 169.28,96.11 173.97,91.42 173.97,88.27 175.06,87.18 175.06,85.15 176.87,83.34 177.86,83.34 178.42,82.77 179.36,82.77 182.83,79.3 182.83,76.84 183.31,76.36 183.31,71.63 186.77,68.18 186.77,60.61 190.68,56.7 190.68,52.04 188.27,49.63 188.27,44.9 189.18,44 190.05,44 191.54,42.5 191.54,41.13 191.37,40.95 191.37,38.08 187.64,34.35 187.64,29.93 186.75,29.04 186.75,21.52 186.67,21.44 186.67,19.74 192.21,14.19 192.21,10.85 191.68,10.32 191.41,10.32 v2(191.23,10.14)
  BOTTOM w0.076: UC1.A15 147.1,101.86 147.14,101.75 147.2,101.72 147.39,101.72 147.53,101.86 147.53,102.22 146.93,102.81 146.93,104.42 147.21,104.69 147.44,104.69 147.58,104.83 v2(147.58,105)
SATA_PTX_DRX_P0_R: length 2.2
  TOP w0.112: US2.1 187.66,10.87 187.75,10.95 187.93,10.95 188.04,10.85 188.04,10.69 188.29,10.44 188.52,10.44 CS37.2
SATA_PTX_DRX_P0_RC: length 2.9
  TOP w0.112: US2.15 182.79,10.87 182.66,10.99 182.58,10.99 182.16,10.57 v3(181.89,10.57) 180.98,10.57 CS30.1
SATA_RCOMP: length 7.9
  BOTTOM w0.203: 149.4,102.8 149.4,101.88 149.05,101.53 149.05,100.86 UC1.C12
  BOTTOM w0.305: RC131.1 149.28,107.7 149.54,107.44 v1(149.54,106.35) 149.54,102.94 149.4,102.8
SCL: length 2.9
  BOTTOM w0.203: PR714.2 45.4,9.85 44.51,10.74 v1(44.13,10.74) PU701.11
SCLK_CPU: length 11.9
  TOP w0.254: v2(69.14,112.96) 69.14,112.72 69.41,112.45 PU501.20 ; v2(62.19,112.6) 62.03,112.45 PR508.2
  IN1 w0.254: v2(62.19,112.6) 62.19,112.73 62.21,112.75 62.21,112.96 63.1,113.85 68.26,113.85 v2(69.14,112.96)
  BOTTOM w0.102: v2(62.19,112.6) 62.03,112.75 v1(61.45,112.75)
  BOTTOM w0.254: PR508.2 62.03,112.45 v2(62.19,112.6)
SDA: length 3.1
  BOTTOM w0.203: PU701.10 44.53,11.31 45.14,10.7 v1(45.54,10.7) 45.54,10.52 PR715.2
SDA_CPU: length 11
  TOP w0.254: v2(70.54,112.96) 70.41,112.83 PU501.18 ; v2(64.67,112.48) 64.06,111.87 PR505.2
  IN1 w0.254: v2(70.54,112.96) 70.54,112.58 69.65,111.69 68.38,111.69 68,112.07 65.06,112.07 64.67,112.45 v2(64.67,112.48)
  BOTTOM w0.102: v1(65.03,111.69) 64.67,112.04 v2(64.67,112.48)
  BOTTOM w0.254: v2(64.67,112.48) 64.06,111.87 PR505.2
SERIRQ: length 132
  TOP w0.076: v2(154.49,92.89) 154.87,92.51 v1(155.66,92.51) 159.75,92.51 RC102.2
  TOP w0.102: v2(135.12,16.04) 134.99,15.9 133.7,15.9 132.7,16.91 UE1.3
  IN1 w0.076: v2(154.49,92.89) 154.51,92.89 154.9,92.51 158.17,92.51 158.43,92.26 158.73,92.26
  IN1 w0.107: 158.73,92.26 160.97,92.26 161.47,91.75 164.27,91.75 164.65,91.37 168.2,91.37 169.35,90.23 169.79,90.23 170.11,89.91 170.11,89.72 172.4,87.43 172.4,84.13 171.13,82.86 171.13,81.46 171.89,80.7 171.89,76 170.97,75.08 170.97,64.98 169.98,64 169.98,38.15 168.71,36.89 168.71,36.17 166.89,34.35 164.01,34.35 162.36,32.69 162.36,29.27 162.11,29.01 162.11,25.07 161.35,24.31 161.35,22.38 158.15,19.18 157.71,19.18 156.42,17.89 151.72,17.89 151.44,17.61 145.75,17.61 145.24,17.1 137.62,17.1 137.39,16.87 135.95,16.87 135.79,16.7 135.76,16.7 135.45,16.39 135.45,16.37 v2(135.12,16.04)
  BOTTOM w0.076: v2(154.49,92.89) 154.49,92.98 154.19,93.28 UC1.T4
SIO_EXT_SCI#: length 15.8
  TOP w0.076: v2(164.42,95.58) v1(164.42,94.95)
  IN2 w0.076: v2(153.68,95.22) 153.89,95.42 154.11,95.42 155.77,97.08 158.68,97.08
  IN2 w0.107: v2(164.42,95.58) 163.43,95.58 162.85,96.17 161.25,96.17 160.33,97.08 158.68,97.08
  BOTTOM w0.076: UC1.N5 153.5,95.04 v2(153.68,95.22)
  BOTTOM w0.102: RC98.1 165.74,95.56 165.33,95.97 165.06,95.97 164.67,95.58 v2(164.42,95.58)
SIO_SLP_S0#: length 100.4
  TOP w0.102: v2(147.88,16.69) 148.06,16.69 148.52,16.23 148.52,15.8 147.62,14.91 UE1.89 ; v2(148.06,23.85) v1(148.06,25.06)
  IN1 w0.076: 158.73,86.86 158.42,87.17 158.42,87.44 158.04,87.81 157.78,87.81 v2(157.37,88.22)
  IN1 w0.107: v2(148.06,23.85) 148.71,23.85 151.71,26.85 152.18,26.85 153.22,27.89 153.22,34.6 155.38,36.76 156.27,36.76 157.79,38.28 160.46,38.28 161.84,39.67 162.5,39.67 163.63,40.8 163.63,42.35 164.01,42.73 164.01,47.05 165.66,48.7 165.66,55.94 166.68,56.95 166.68,62.79 167.26,63.37 167.26,64.39 168.97,66.1 168.97,71.3 168.08,72.19 168.08,77.4 168.46,77.78 168.46,82.86 166.38,84.94 161.42,84.94 160.46,85.91 160.46,86.16 160.03,86.59 159,86.59 158.73,86.86
  BOTTOM w0.076: v2(157.37,88.22) 157.28,88.22 156.98,88.52 156.49,88.52 156.33,88.36 156.02,88.36 155.85,88.19 155.85,88.02 155.61,87.78 155.09,87.78 UC1.AF3
  BOTTOM w0.102: v2(147.88,16.69) 147.46,17.12 147.46,23.25 v2(148.06,23.85)
SIO_SLP_S3#: length 107
  TOP w0.102: v2(127.11,23.27) v1(127.11,19.65) 127.11,18.77 128.15,17.73 CE27.1 128.58,16.44 129.31,15.71 UE1.6
  IN1 w0.076: 158.73,80.07 155.63,80.07 154.49,81.21 v2(154.49,82.48)
  IN1 w0.107: v2(127.11,23.27) 127.11,25.28 129.17,27.33 144.56,27.33 144.82,27.59 149.68,27.59 150.17,28.08 150.17,35.49 153.37,38.69 154.19,38.69 155.3,39.81 159.7,39.81 160.58,40.7 160.58,41.58 162.49,43.49 162.49,47.81 164.14,49.46 164.14,59.81 164.52,60.19 164.52,64.57 161.67,67.42 161.67,72 161.93,72.26 161.93,77.19 159.06,80.07 158.73,80.07
  BOTTOM w0.076: UC1.AT4 154.49,82.34 v2(154.49,82.48)
SIO_SLP_S4#: length 102.9
  TOP w0.076: v2(153.12,86.69) 153.61,87.18 T104.1
  TOP w0.102: v2(147.91,13.42) 147.91,13.16 147.66,12.91 UE1.84
  IN1 w0.076: 158.73,86.34 158.72,86.32 153.49,86.32 v2(153.12,86.69)
  IN1 w0.107: 158.73,86.34 159.93,86.34 160.2,86.06 160.2,85.65 161.32,84.54 166.4,84.54 168.2,82.73 168.2,77.91 167.82,77.53 167.82,72.06 168.73,71.15 168.73,66.24 166.97,64.48 166.97,63.86 166.35,63.24 166.35,57.24 165.41,56.31 165.41,48.82 163.76,47.17 163.76,42.85 163.38,42.47 163.38,40.92 162.38,39.92 161.72,39.92 160.33,38.54 157.66,38.54 156.14,37.01 155.25,37.01 152.96,34.73 152.96,28.02 152.05,27.11 151.06,27.11 150.3,26.34 149.54,26.34 147.43,24.23 v2(147.43,23.85)
  BOTTOM w0.076: v2(153.12,86.69) 153.12,86.69 152.85,86.42 UC1.AJ6
  BOTTOM w0.102: v2(147.91,13.42) 147.08,14.24 147.08,23.51 v2(147.43,23.85)
SIO_SLP_S5#: length 121
  TOP w0.076: v2(153.75,83.06) 154.97,83.06 T103.1
  TOP w0.102: UE1.14 128.92,12.51 128.45,12.04 126.04,12.04 CE28.1 123.92,12.88 123.22,13.58 123.22,16.4 123.26,16.44 123.26,17.27 124.16,18.18 124.16,22.28 124.69,22.81 v2(124.69,23.3)
  IN1 w0.076: v2(153.75,83.06) 155.3,83.06 155.76,82.61 155.76,81.59 157.03,80.32 158.73,80.32
  IN1 w0.107: 158.73,80.32 159.19,80.32 162.19,77.32 162.19,72.19 161.91,71.9 161.91,67.57 164.78,64.7 164.78,60.05 164.39,59.67 164.39,49.33 162.74,47.68 162.74,43.36 160.84,41.46 160.84,40.54 159.85,39.55 155.45,39.55 153.6,37.7 152.89,37.7 151.95,36.76 151.95,34.09 151.19,33.33 151.19,28.76 149.79,27.36 144.96,27.36 144.68,27.08 129.6,27.08 128.28,25.76 128.28,23.75 127.36,22.84 125.15,22.84 v2(124.69,23.3)
  BOTTOM w0.076: v2(153.75,83.06) 153.75,83.06 153.5,83.31 UC1.AP5
SLATE_MODE_R: length 19.4
  IN2 w0.076: v2(158.68,82.1) 158.04,81.46 156.52,81.46 155.63,82.35 155.63,84.39 v2(154.53,85.49)
  BOTTOM w0.076: 162.74,85.81 162.54,85.6 161.55,85.6 v1(161.35,85.4) 160.69,84.74 160.69,83.93 159.87,83.11 159.7,83.11 v2(158.68,82.1) ; UC1.AL4 154.19,85.15 v2(154.53,85.49)
  BOTTOM w0.102: 162.74,85.81 163.23,86.29 165.82,86.29 166.27,86.75 167.67,86.75 RC110.1
SLP_SUS#: length 122.1
  TOP w0.076: v2(156.92,83.04) 156.9,83.06 T106.1
  TOP w0.102: v2(123.96,23.25) 123.93,23.22 123.93,18.27 123.03,17.37 123.03,16.54 122.99,16.5 122.99,13.49 125.17,11.31 UE1.17
  IN1 w0.076: 158.73,81.59 158.55,81.59 158.3,81.84 158.3,82.35 157.61,83.04 v2(156.92,83.04)
  IN1 w0.107: 158.73,81.59 159.31,81.59 159.7,81.21 159.7,80.19 162.42,77.47 162.42,72.09 162.14,71.81 162.14,67.72 165.03,64.83 165.03,59.87 164.65,59.49 164.65,49.2 163,47.55 163,43.24 162.62,42.85 162.62,41.86 162.34,41.58 161.7,41.58 161.12,41 161.12,40.47 159.95,39.3 155.58,39.3 153.73,37.44 153.02,37.44 152.2,36.63 152.2,33.96 151.44,33.2 151.44,28.63 149.92,27.11 145.09,27.11 144.79,26.8 129.67,26.8 128.66,25.79 128.66,23.7 127.54,22.58 124.54,22.58 123.96,23.17 v2(123.96,23.25)
  BOTTOM w0.076: v2(156.92,83.04) 156.92,83.04 156.76,83.2 156.44,83.2 156.36,83.28 155.95,83.28 155.79,83.12 155.01,83.12 154.96,83.17 154.49,83.17 UC1.AP4
SM_RCOMP0: length 12.4
  TOP w0.305: RC68.1 114.99,72.83 114.48,73.33 114.48,76.64 v1(115.74,77.89) 118.17,80.32 118.17,80.62 v2(119.42,81.87)
  BOTTOM w0.229: UC1.AU60 119.57,81.71 v2(119.42,81.87)
SM_RCOMP1: length 10.7
  TOP w0.305: v2(119.1,80.53) 119.1,80.11 v1(117.94,78.95) 115.25,76.26 115.25,73.6 116,72.85 116,72.28 RC69.1
  BOTTOM w0.076: v2(119.1,80.53) 119.28,80.71 UC1.AV60
SM_RCOMP2: length 12.2
  TOP w0.305: RC70.1 113.98,72.83 113.72,73.08 113.72,77.1 v1(116.4,79.77) 118.39,81.76 v2(118.39,81.83)
  BOTTOM w0.229: v2(118.39,81.83) 118.58,81.64 UC1.AU61
SML0CLK: length 18.2
  TOP w0.076: v2(161.09,86.08) 161.96,86.95 167.62,86.95 v1(167.76,86.81) 168.28,86.29 168.59,86.29
  TOP w0.102: 168.59,86.29 169.86,86.29 170.35,86.78 RP49.1
  BOTTOM w0.076: v2(161.09,86.08) 160.74,85.73 160.74,85.5 160.46,85.22 160.46,84 159.85,83.39 156.49,83.39 156.31,83.58 UC1.AN1
SML0DATA: length 17
  TOP w0.076: v2(156.63,85.88) 157,86.26 157.18,86.26 157.22,86.3 159.28,86.3 159.47,86.49 160.08,86.49 160.92,85.65 161.22,85.65 162.34,86.77 167.09,86.77 168.08,85.78 168.59,85.78
  TOP w0.102: RP49.2 170.74,86.28 170.24,85.78 v1(169.04,85.78) 168.59,85.78
  BOTTOM w0.076: v2(156.63,85.88) 156.56,85.82 156.14,85.82 UC1.AK1
SML1_SMBCLK: length 24.7
  TOP w0.102: QH1.1 170.31,77.4 170.31,78.14 v2(170.72,78.55) RP40.3
  IN2 w0.076: v2(157.87,82.1) 158.38,82.61 158.68,82.61
  IN2 w0.107: v2(170.72,78.55) 170.72,78.8 169.22,80.29 169.22,81.31 168.79,81.74 168.79,82.53 166.76,84.56 163.43,84.56 163.38,84.51 160.84,84.51 158.93,82.61 158.68,82.61
  BOTTOM w0.076: UC1.AU3 155.17,81.73 155.59,81.73 155.81,81.95 155.81,82.23 155.95,82.37 156.28,82.37 156.89,81.76 157.53,81.76 v2(157.87,82.1)
SML1_SMBDATA: length 27.2
  TOP w0.102: RP40.4 170.88,78.05 v2(170.74,77.91) 170.74,77.65 172.27,76.13 172.27,75.61 172.52,75.35 QH1.4
  IN2 w0.076: 158.68,85.68 v2(158.45,85.91)
  IN2 w0.107: v2(170.74,77.91) 171.15,78.31 171.15,80.8 169.6,82.35 169.6,82.81 167.04,85.37 163.1,85.37 163,85.27 159.09,85.27 158.68,85.68
  BOTTOM w0.076: v2(158.45,85.91) 157.62,86.74 156.39,86.74 156.36,86.76 156.26,86.87 156.02,86.87 155.85,86.69 155.85,86.52 155.61,86.28 155.1,86.28 154.85,86.54 UC1.AH3
SNB_1.05V: length 2.2
  BOTTOM w0.102: PR302.2 175.13,46.09 v1(176.1,47.07)
SNUB_PCIE: length 1
  TOP w0.102: PC1304.1 v1(77.4,54.92)
SPK_L1-_CONN:
  vias: v1(205.14,15.5) v2(205.54,15.88) v2(205.67,15.3)
SPK_L2+_CONN:
  vias: v1(203.13,15.4) v2(203.51,14.91) v2(203.92,14.38)
SPK_R1-_CONN:
  vias: v1(210.32,14.81) v2(210.75,15.3) v2(210.75,14.28)
SPK_R2+_CONN:
  vias: v1(208.13,15.14) v2(207.7,15.42) v2(208.24,15.68)
SRTCRST#: length 23.4
  TOP w0.076: v2(152.39,80.41) 150.9,78.92 150.9,72.21 150.3,71.61 150.3,70.78 RC5.2 CC3.2
  TOP w0.102: QC2.3 157.58,66.47 156.61,67.44 156.61,68.05 155.77,68.9 152.22,68.9 151.3,67.98 150.41,67.98 150.31,68.09 150.31,68.97 CC3.2
  BOTTOM w0.076: v2(152.39,80.41) 152.69,80.71 UC1.AV6
SUS_STAT#/LPCPD#: length 14.2
  TOP w0.076: v2(153.71,86.69) 153.71,86.66 154.16,86.22 154.16,85.46 153.93,85.23 152.68,85.23 152.38,84.93 152.38,82.02 153.96,80.44 153.96,79.93 154.84,79.05 154.84,78.23 154.71,78.1 v1(154.71,77.04) 154.88,76.87 RC29.2
  BOTTOM w0.076: UC1.AG4 154.19,87.17 v2(153.71,86.69)
SUSACK#: length 72
  TOP w0.102: v2(166.71,39.55) 166.93,39.78 166.93,41.99 168.31,43.36 168.31,58.75 v1(165.11,61.95) 164.88,61.95 163.1,63.73 163.1,64.24 160.42,66.92 160.42,69 RC35.2 159.7,69.73 RC37.1 RC28.2 ; UE1.97 145.02,20.32 145.22,20.51 145.22,20.51 145.8,21.1 151.31,21.1 151.86,21.65 v2(151.86,23.43)
  IN1 w0.107: v2(164.18,38.27) 163.56,37.65 163,37.65 161.2,35.85 159.63,35.85 156.98,33.2 156.98,27.69 155.53,26.24 154.84,26.24 154.23,25.63 154.23,24.9 153.37,24.03 152.06,24.03 151.86,23.83 v2(151.86,23.43)
  BOTTOM w0.102: v2(166.71,39.55) 165.46,39.55 v2(164.18,38.27)
SUSACK#_R: length 19.6
  TOP w0.076: RC37.2 159.7,71.94 160.23,72.47 v1(160.23,72.75) 160.23,73.31 159.67,73.87 159.67,77.62 159.35,77.94 159.35,79.52 158.3,80.57 156.77,80.57 156.39,80.95 156.39,84.38 156.65,84.64 156.9,84.64 157.18,84.92 v2(157.18,85.9)
  BOTTOM w0.076: v2(157.18,85.9) 157.18,85.88 156.83,86.24 156.47,86.24 156.34,86.12 156.02,86.12 155.73,85.82 UC1.AK2
SUSCLK: length 62.2
  TOP w0.076: v2(153.03,88.55) 153.4,88.19 154.16,88.19 154.66,87.69 155.4,87.69 155.87,88.16 156.71,88.16 v1(156.77,88.21) 157.18,88.62 158.12,88.62 158.43,88.32 159.24,88.32 159.7,87.86 160.08,87.86 v2(160.2,87.74)
  TOP w0.102: v2(181.48,63.69) 182.05,64.27 184.11,64.27 RM5.2
  IN1 w0.107: v2(167.8,62.41) 167.8,62.41 167.8,62.77 168.46,63.43 168.46,64.83 169.43,65.8 169.43,71.6 168.59,72.45 168.59,77.14 168.97,77.53 168.97,85.02 167.1,86.89 164.81,86.89 164.14,87.56 160.38,87.56 v2(160.2,87.74)
  BOTTOM w0.076: v2(153.03,88.55) 152.85,88.38 UC1.AE6
  BOTTOM w0.102: v2(181.48,63.69) 181.09,63.31 179.9,63.31 177.53,60.94 173.66,60.94 173.07,60.35 172.42,60.35 172.17,60.61 171.97,60.61 171.29,61.29 169.07,61.29 167.95,62.41 167.8,62.41 v2(167.8,62.41)
SUSCLK_R: length 2.9
  TOP w0.102: v1(184.05,67.01) 184.46,66.6 v2(184.72,66.6) 184.71,66.59 RM5.1
  BOTTOM w0.102: JNGFF.42 184.73,66.6 v2(184.72,66.6)
SUSP: length 20.5
  TOP w0.508: Q2308.2 161.52,3.18 162.41,2.29 v1(165.54,2.29) 167.37,2.29 167.87,2.8 167.87,2.82 ; R10.2 173.34,6.35 Q8.1 172.78,1.96 172.4,1.58 169.12,1.58 167.87,2.82 ; Q2307.2 167.87,2.82
SUSP#: length 147.3
  TOP w0.203: UE1.116 137.42,18.27 137.42,18.27 137.42,17.56 137.42,13.52 137.28,13.38 v2(137.28,13.3)
  TOP w0.254: v2(211.33,13.54) 211.03,13.24 PR402.1
  TOP w0.508: R2451.1 166.3,8.5 166.62,8.18 v2(166.68,8.18) 167.57,8.18 168,8.61 170.41,8.61 170.72,8.31 R16.1 ; R16.1 171.3,8.74 172.01,9.45 172.14,9.45 ; R16.1 171.13,8.13 v4(171.13,6.89) 171.13,5.9 v2(171.96,5.06) 171.96,3.87 Q8.2 ; R2318.1 175.19,9.96 174.3,9.07 172.52,9.07 172.14,9.45 ; 172.14,9.45 R2313.1
  IN1 w0.254: v2(173.94,25.46) 174.28,25.12 174.28,22.78 171.13,19.63 171.13,17.96 168.2,15.04 167.19,15.04 166.68,14.53 166.68,8.31 166.81,8.18 v2(166.68,8.18) ; v2(171.96,5.06) 172.07,4.96 173.89,4.96 174.83,5.9 177.16,5.9 178.58,7.31 185.75,7.31 185.86,7.42 192.33,7.42 192.72,7.8 198.46,7.8 203.64,12.98 210.78,12.98 v2(211.33,13.54)
  IN2 w0.254: v2(137.28,13.3) 138.04,12.54 141.03,12.54 141.16,12.41 143.21,12.41 143.39,12.59 145.38,12.59 148.57,9.4 148.57,8.31 149.03,7.85 153.74,7.85 153.84,7.95 156.62,7.95 157.54,7.04 163.38,7.04 164.52,8.18 v2(166.68,8.18)
  BOTTOM w0.254: v2(173.94,25.46) 173.94,25.69 175.95,27.71 175.95,38.52 176.5,39.07 182.2,39.07 183.9,40.77 PR300.2
SVI2_SVC: length 84
  IN1 w0.203: v2(80.83,93.02) 80.83,91.95 81.62,91.16 81.62,88.83 81.01,88.22 81.01,86.97 80.14,86.11 80.14,75.95 79.18,74.99 79.18,71.43 81.34,69.27 81.34,60.56 79.94,59.16 79.94,53.4 78.24,51.69 78.24,35.18 76.84,33.79 63.56,33.79 v2(62.79,33.02)
  BOTTOM w0.102: v1(79.38,97.13) 79.79,96.73 79.79,96.04 RV89.2
  BOTTOM w0.203: PU1000.3 62.52,33.5 62.79,33.23 v2(62.79,33.02)
  BOTTOM w0.254: RV89.2 RV84.1 RV78.2 RV157.2 v2(80.83,93.02)
SVI2_SVD: length 80.1
  TOP w0.102: v2(81.08,90.35) v1(81.59,90.35)
  IN1 w0.203: v2(61.86,33.05) 63.05,34.24 76.57,34.24 77.78,35.45 77.78,52 79.43,53.65 79.43,59.36 80.83,60.76 80.83,68.76 78.67,70.92 78.67,75.24 79.69,76.26 79.69,87.35 v2(80.14,87.81) 80.14,89.41 v2(81.08,90.35)
  BOTTOM w0.203: RV155.2 v2(80.14,87.81) ; v2(81.08,90.35) RV77.2 RV88.2 RV87.1 ; v2(61.86,33.05) 61.73,33.18 PU1000.5
SVI2_SVT: length 76.9
  IN1 w0.203: v2(60.62,33.08) 60.62,33.14 62.19,34.7 76.37,34.7 77.32,35.65 77.32,52.3 78.92,53.9 78.92,59.62 80.32,61.02 80.32,68.51 78.16,70.67 78.16,75.49 79.18,76.51 v2(79.18,87.05)
  BOTTOM w0.203: RV156.2 80.19,89.46 80.7,88.96 80.7,87.56 v1(80.56,87.41) 80.19,87.05 v2(79.18,87.05) ; v2(60.62,33.08) 60.62,33.16 60.92,33.47 PU1000.7
SW_1.35V:
  vias: v1(90.32,21.87) v2(86.42,12.12) v2(86.8,13.39) v2(86.8,12.63) v3(90.61,17.2) v3(91.24,17.2)
SW_+1.35VGPUP:
  vias: v1(36.15,49.05) v3(39.81,46.03) v3(39.81,45.39) v3(39.81,44.76) v3(39.81,44.12) v3(40.57,46.03) v3(40.57,45.39) v3(40.57,44.76) v3(40.57,44.12)
SW_CPU2:
  vias: v1(85.07,112.63) v3(85.65,113.34) v3(85.78,116.77) v3(85.78,115.75) v3(85.78,114.48) v3(86.67,113.34) v3(87.81,113.34) v3(89.08,113.34) v3(90.23,113.34)
SWAP_1: length 13
  BOTTOM w0.076: 128.71,107.75 128.76,107.75 v1(129.23,107.28) 130.54,105.97 132.95,105.97 133.2,105.72 133.2,104.97 133.43,104.74 133.43,103.03 134.35,102.11 134.64,102.11 134.83,101.93 134.89,101.76 134.89,101.66 134.84,101.53 134.83,101.5 134.83,101.32 134.87,101.16 134.97,101.01 UC1.C35
  BOTTOM w0.102: 128.71,107.75 127.95,107.75 127.56,108.14 RP41.2
SWAP_2: length 13.3
  BOTTOM w0.076: UC1.C34 135.58,100.86 135.41,101.03 135.23,101.03 135.02,101.24 134.99,101.34 134.99,101.47 135.01,101.53 135.03,101.54 135.05,101.62 135.05,101.79 134.97,102.02 134.7,102.29 134.42,102.29 133.77,102.94 v1(133.77,104.39) 133.77,104.67 133.41,105.03 133.41,105.9 133.08,106.23 130.75,106.23 128.97,108.01 128.71,108.01
  BOTTOM w0.102: RP41.1 128.06,108.17 128.23,108.01 128.71,108.01
SYS_PWROK: length 229.4
  TOP w0.102: v2(149.26,14.73) 149.26,14.35 149.59,14.02 CE32.1 149.28,13.52 148.98,13.82 147.71,13.82 147.59,13.71 UE1.86 ; v2(93.78,80.19) 94.29,80.19 94.62,79.86 RC52.1
  IN1 w0.107: v2(93.78,80.19) 93.02,79.43 93.02,74.22 93.66,73.59 93.66,69.91 93.78,69.78 93.78,44.88 93.06,44.16 93.06,42.77 94.81,41.02 94.81,39.24 95.44,38.6 96.03,38.6 96.03,38.61 96.2,38.61 99.16,35.65 108.02,35.65 110.32,33.35 110.32,27.23 111.08,26.47 111.08,24.95 112.5,23.53 112.5,19.49 114.63,17.35 122.18,17.35 122.46,17.62 126.01,17.62 126.22,17.84 129.98,17.84 131.1,16.71 133.06,16.71 133.85,15.93 133.89,15.93 133.9,15.92 134.41,15.92 134.53,15.8 134.53,15.8 134.88,15.45 137.04,15.45 137.9,16.31 148.29,16.31 v2(148.7,16.72) 151.39,16.72 152,16.11 154.29,16.11 154.49,15.9 155.56,15.9 157.33,17.68 158.38,17.68 162.11,21.42 162.11,23.93 162.85,24.67 162.85,26.45 164.39,28 164.39,33.08 164.9,33.58 167.12,33.58 169.07,35.53 169.64,35.53 172.36,38.24 172.36,49.61 171.92,50.05 171.92,59.58 173.28,60.94 173.28,69.6 174.07,70.4 174.07,75.13 175.09,76.15 175.09,78.65 174.82,78.93 174.82,83.23 174.19,83.86 174.19,87.16 172.01,89.34 172.01,91.5 170.62,92.89 168.08,92.89 167.32,93.65 167.32,97.85 v2(168.2,98.73)
  BOTTOM w0.102: v2(149.26,14.73) 149.26,16.16 v2(148.7,16.72) ; CC31.1 v2(168.2,98.73) 168.22,98.75 RP50.1
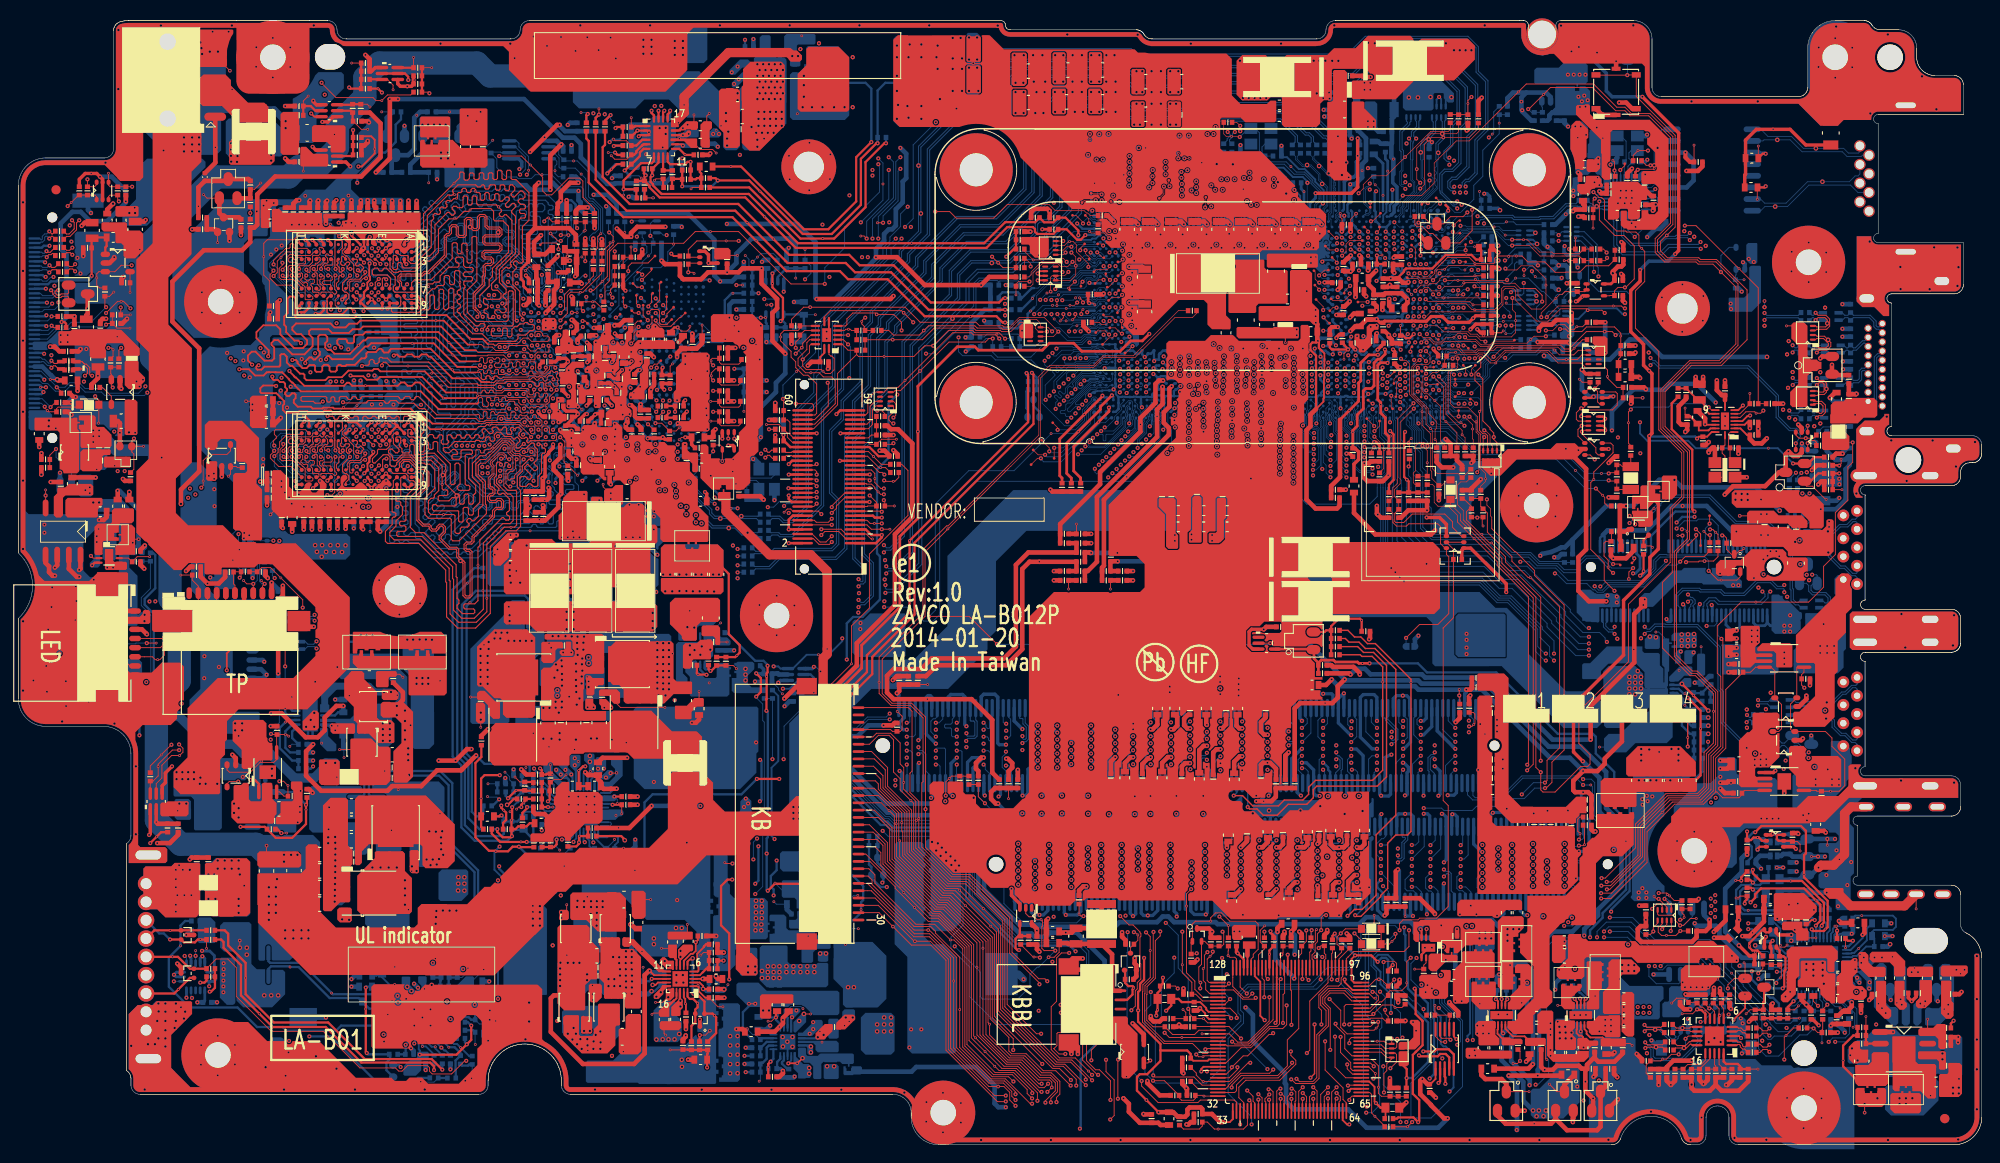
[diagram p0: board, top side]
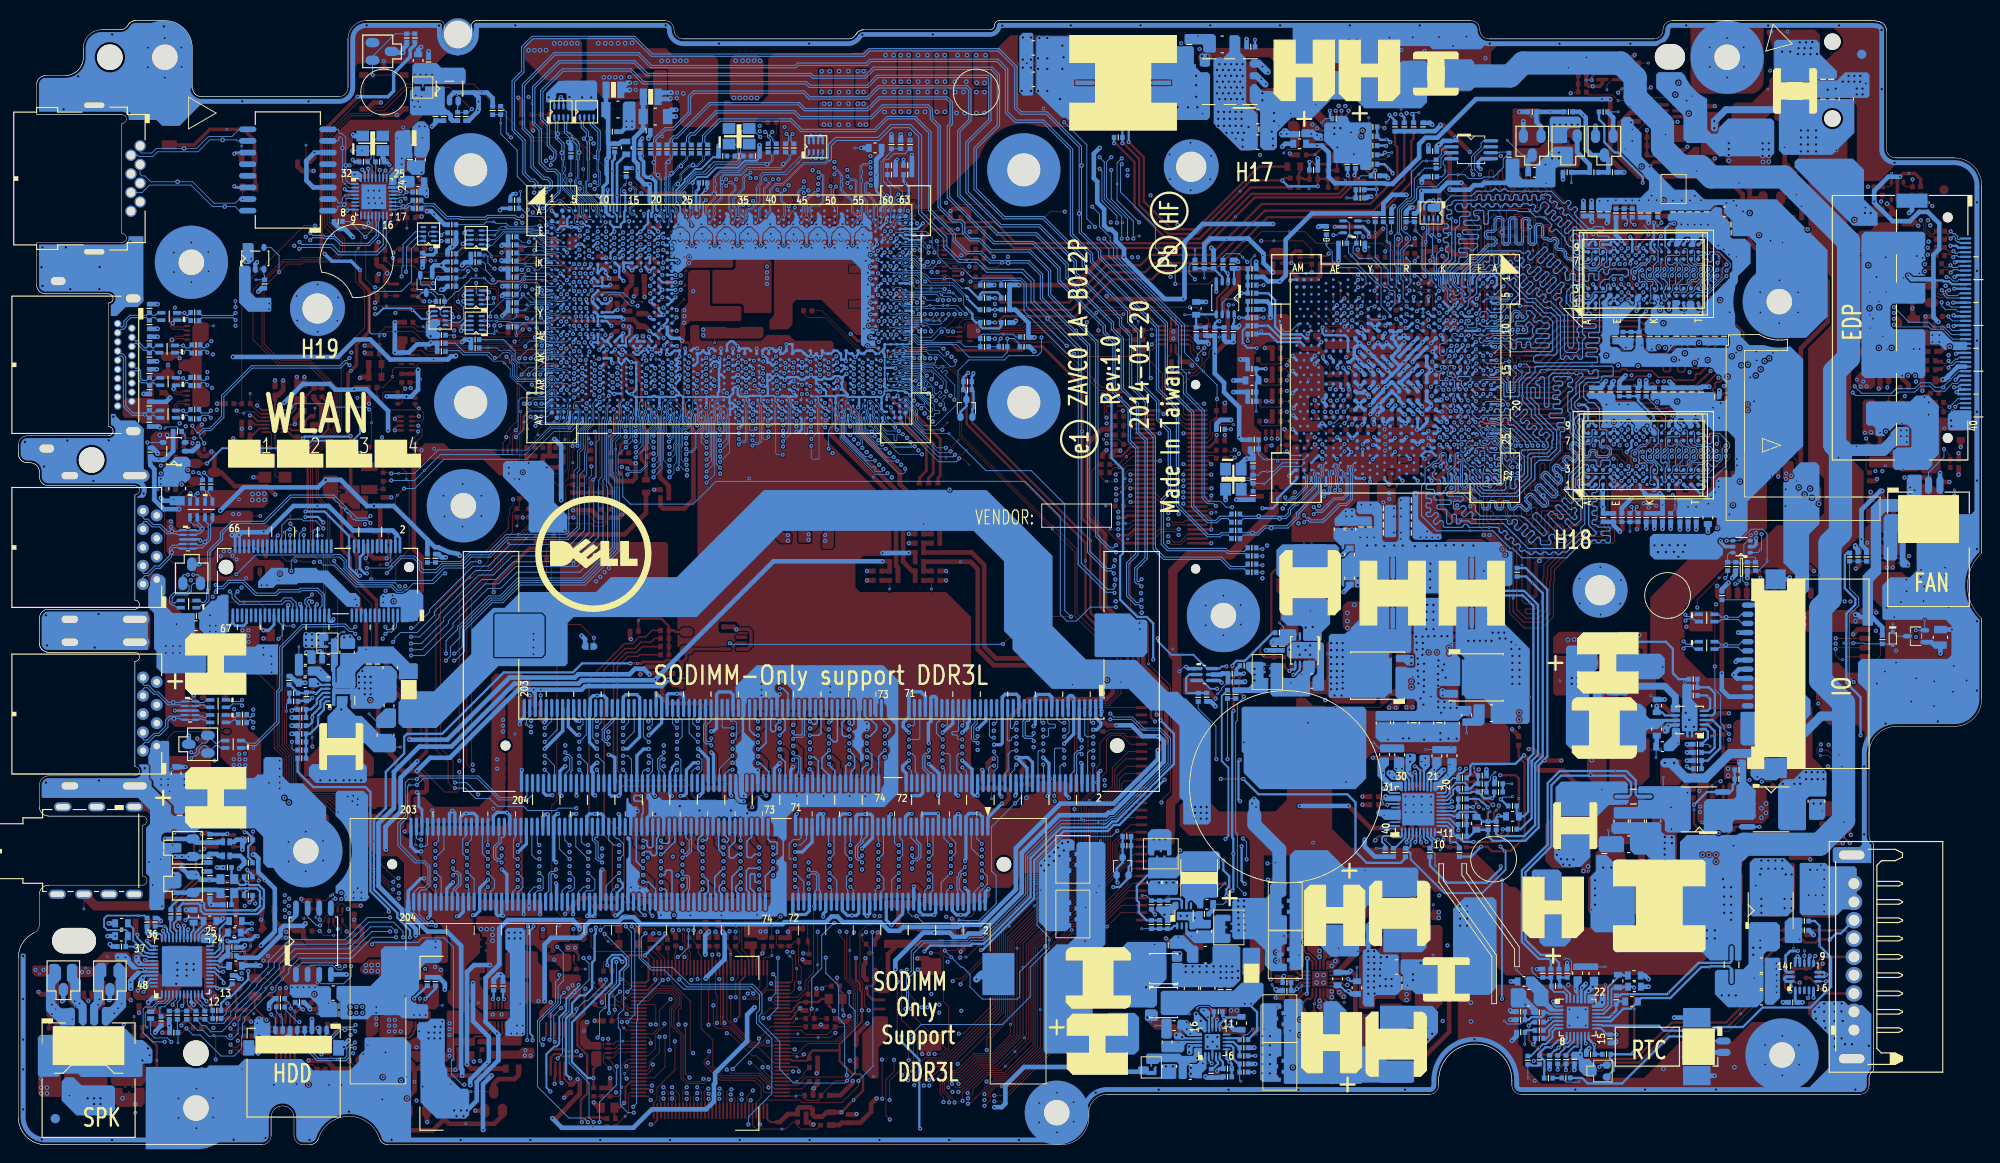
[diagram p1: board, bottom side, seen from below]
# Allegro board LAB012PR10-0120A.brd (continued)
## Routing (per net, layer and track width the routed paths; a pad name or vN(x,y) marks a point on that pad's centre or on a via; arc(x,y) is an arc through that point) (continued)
SYS_PWROK_R: length 37.1
  TOP w0.076: 168.59,87.18 168.46,87.3 161.3,87.3 160.92,86.92 159.31,86.92 159.11,86.72 157.74,86.72 157.24,87.22 v2(157.24,87.29)
  TOP w0.102: 168.59,87.18 168.84,86.92 169.32,86.92 171.23,88.83 v4(173.23,88.83) 174.05,88.83 v2(174.43,88.45)
  BOTTOM w0.076: UC1.AG2 155.73,87.32 156.02,87.61 156.33,87.61 156.45,87.73 156.8,87.73 v2(157.24,87.29)
  BOTTOM w0.102: RP50.8 170.61,98.75 171.46,97.9 171.46,95.53
  BOTTOM w0.107: v2(174.43,88.45) 174.55,88.57 175.82,88.57 176.08,88.83 176.08,92.77 175.62,93.22 172.57,93.22 171.46,94.34 171.46,95.53
SYS_PWROK_XDP: length 4.5
  TOP w0.102: JXDP1.47 92.84,77.21 93.15,77.53 CC16.1 RC64.1 RC52.2
SYS_RESET#: length 6.5
  BOTTOM w0.076: v1(160,88.37) RC26.2 159.7,89.34 159.36,89.67 156.64,89.67 156.25,89.28 155.09,89.28 UC1.AC3
SYSON: length 164.1
  TOP w0.102: UE1.95 147.47,17.31 148.23,18.06 v4(148.57,18.06) 148.85,18.06 CE26.1 150.25,17.99 v2(150.25,18.04)
  IN1 w0.107: v2(79.3,9.71) 82.52,9.71 83.79,8.44 85.53,8.44 85.99,8.89 86.85,8.89 87.66,8.08 90.13,8.08 91.01,8.97 101.89,8.97 106.1,4.75 106.1,2.47 107.27,1.3 150.4,1.3 v2(151.57,2.47)
  IN2 w0.107: v2(153.45,14.81) 153.77,14.49 159.99,14.49 160.84,13.64 165.54,13.64 166.81,14.91 168.84,14.91 169.21,15.29 172.33,15.29 172.94,15.9 176.71,15.9 178.39,17.58 178.39,17.72 182.1,21.43 182.1,24.54 181.34,25.3 181.34,27.51 178.62,30.23 178.62,34.44 181.44,37.27 182.86,37.27 184.94,39.35 184.94,42.79 184.52,43.21 v2(184.52,44.01)
  BOTTOM w0.102: PR310.2 184.33,43.11 184.52,43.29 v2(184.52,44.01) ; v2(150.25,18.04) 150.25,17.71 152.25,15.7 152.56,15.7 v2(153.45,14.81) 153.45,14.48 154.26,13.67 154.26,8.91 152.08,6.72 152.08,2.98 v2(151.57,2.47)
  BOTTOM w0.254: PR201.1 v2(79.3,9.71)
TDI_IREF: length 4.6
  BOTTOM w0.076: RC133.2 148.01,105.02 v1(148.17,104.86) 148.65,104.39 148.65,102.95 148.67,102.92 UC1.B12
TDI_XDP: length 17.4
  TOP w0.102: RC44.2 RC45.1 92.39,89.03 92.39,89.38 92.1,89.67 v1(92.1,89.95) 92.1,90.02 92.43,90.35 v2(92.48,90.35) ; v2(88.39,83.24) 88.45,83.18 88.45,80.7 86.96,79.21 JXDP1.56
  IN2 w0.107: v2(88.39,83.24) 88.39,83.69 92.48,87.78 v2(92.48,90.35)
TDI_XDP_R: length 3.2
  TOP w0.102: UC4.5 90.22,88.95 90.35,89.08 v1(90.65,89.08) 90.85,89.08 90.99,88.95 91.54,88.95 RC45.2 RC63.1
TDO_XDP: length 54.7
  TOP w0.076: RP44.4 v2(114.1,98.72)
  TOP w0.102: 91.55,86.31 RC43.2 90.61,86.8 89.96,87.45 UC4.2 ; 91.55,86.31 91.52,86.31 89.46,84.26 89.46,80.83 86.85,78.21 JXDP1.52 ; 91.55,86.31 91.75,86.11 v1(94.54,86.11) 97.8,86.11 98.82,87.13 98.84,87.13 98.99,87.28 v2(99.9,87.28) 101.58,88.96 104.2,88.96 104.45,88.7 107.11,88.7 v2(107.75,88.05)
  BOTTOM w0.076: 110.93,95.41 111.21,95.69 112.58,95.69 113.98,97.08 113.98,98.59 v2(114.1,98.72)
  BOTTOM w0.102: v2(107.75,88.05) 107.77,88.07 RC62.1 ; 110.93,95.41 110.19,94.67 104.91,94.67 104.32,94.09 104.32,91.62 99.98,87.28 v2(99.9,87.28)
TESTEN: length 14.2
  TOP w0.102: RV17.2 RV154.2 58.32,100.82 v1(57.89,101.25) 57.74,101.25 57.44,100.94 v2(57.44,100.87)
  IN2 w0.107: v2(57.44,100.87) 57.44,100.56 57.77,100.23 57.77,99.07 56.75,98.06 56.75,94.19 59.2,91.74 v2(59.2,91.65)
  BOTTOM w0.102: UV1.K7 58.85,91.3 v2(59.2,91.65)
THM_ALERT#: length 29.2
  BOTTOM w0.102: UV1.R6 63.18,92.48 63.18,94.33 63.43,94.58 63.43,97.77 62.38,98.82 62.38,99.19 62.78,99.6 62.96,99.6 63.35,99.99 63.35,102.11 62.67,102.8 62.19,102.8 61.73,103.26 61.73,104.37 61.45,104.65 59.54,104.65 58.22,105.97 v1(57.18,105.97) 56.44,105.97 56.01,105.54 54.59,105.54 54.41,105.72 53.27,105.72 52.25,106.74 52.25,107.68 52.1,107.84 52.1,107.85 RV146.2 51.72,108.44 52.65,108.44 52.72,108.37 UV3.6
TMDS_L_TX0N: length 11.1
  BOTTOM w0.112: JHDMI.9 203.55,85.92 203.31,86.16 203.13,86.16 202.93,85.96 202.93,80.64 201.97,79.68 200.39,79.68 CX25.1 199.78,79.68 199.59,79.68 199.32,79.41 LX3.2
TMDS_L_TX0P: length 10.9
  BOTTOM w0.112: LX3.3 199.3,80.21 199.57,79.94 199.78,79.94 CX26.1 200.38,79.94 201.86,79.94 202.67,80.75 202.67,86.06 203.02,86.42 203.27,86.42 JHDMI.7
TMDS_L_TX1N: length 3.8
  BOTTOM w0.112: JHDMI.6 201.63,87.57 201.49,87.57 200.71,86.79 200.38,86.79 CX27.1 199.78,86.79 199.61,86.79 199.34,86.52 LX4.2
TMDS_L_TX1P: length 3.8
  BOTTOM w0.112: JHDMI.4 201.63,87.83 201.39,87.83 200.61,87.05 200.39,87.05 CX28.1 199.78,87.05 199.62,87.05 199.35,87.32 LX4.3
TMDS_L_TX2N: length 6.1
  BOTTOM w0.112: JHDMI.3 203.17,89.08 202.9,89.08 202.62,89.36 202.62,89.86 202.13,90.35 200.39,90.35 CX29.1 199.78,90.35 199.46,90.35 199.19,90.08 LX5.2
TMDS_L_TX2P: length 6.1
  BOTTOM w0.112: JHDMI.1 203.19,89.34 203,89.34 202.88,89.47 202.88,89.97 202.24,90.61 200.38,90.61 CX30.1 199.78,90.61 199.45,90.61 199.18,90.88 LX5.3
TMDS_L_TXCN: length 4.7
  BOTTOM w0.112: LX2.2 199.3,82.97 199.57,83.24 199.78,83.24 CX23.1 200.39,83.24 200.95,83.24 201.29,83.58 201.29,84.45 201.41,84.57 201.63,84.57 JHDMI.12
TMDS_L_TXCP: length 4.7
  BOTTOM w0.112: JHDMI.10 201.63,84.83 201.31,84.83 201.03,84.55 201.03,83.68 200.85,83.5 200.38,83.5 CX24.1 199.78,83.49 199.57,83.49 199.3,83.77 LX2.3
TMDS_TX0N: length 5.5
  TOP w0.112: RP59.2 196.09,81.21 196.93,81.21 197.33,80.81 197.33,79.98 196.98,79.63 196.6,79.63 v2(196.4,79.43)
  BOTTOM w0.112: LX3.1 196.42,79.41 v2(196.4,79.43) 196.15,79.68 195.96,79.68 CX14.1
TMDS_TX0P: length 4.6
  TOP w0.112: RP59.1 196.07,80.95 196.82,80.95 197.07,80.71 197.07,80.09 196.88,79.89 196.7,79.89 v2(196.4,80.19)
  BOTTOM w0.112: LX3.4 196.42,80.21 v2(196.4,80.19) 196.14,79.94 195.97,79.94 CX15.1
TMDS_TX1N: length 6.6
  TOP w0.112: v2(196.4,86.54) 196.65,86.79 197.5,86.79 197.93,87.22 197.93,87.63 v3(197.63,87.93) 197.24,88.32 196.41,88.32 196.28,88.45 RP58.2
  BOTTOM w0.112: LX4.1 196.42,86.52 v2(196.4,86.54) 196.14,86.8 195.76,86.8 CX16.1
TMDS_TX1P: length 5.8
  TOP w0.112: v2(196.4,87.3) 196.65,87.05 197.39,87.05 197.67,87.33 197.67,87.53 197.51,87.68 197.45,87.75 197.13,88.07 196.37,88.07 196.26,87.95 RP58.1
  BOTTOM w0.112: CX17.1 195.46,87.33 195.74,87.05 196.15,87.05 v2(196.4,87.3) 196.42,87.32 LX4.4
TMDS_TX2N: length 5.5
  TOP w0.112: v2(196.27,90.08) 196.54,90.35 197.28,90.35 197.54,90.09 v3(197.54,89.73) 197.54,89.52 197.36,89.34 196.38,89.34 196.27,89.45 RP58.4
  BOTTOM w0.112: LX5.1 v2(196.27,90.08) 196.27,90.1 196.02,90.35 195.92,90.35 CX18.1
TMDS_TX2P: length 6.4
  TOP w0.112: v2(196.27,90.88) 196.54,90.61 197.39,90.61 197.8,90.2 197.8,89.41 197.47,89.08 196.39,89.08 196.26,88.95 RP58.3
  BOTTOM w0.112: CX19.1 195.89,90.61 196.02,90.61 196.27,90.85 v2(196.27,90.88) LX5.4
TMDS_TXCN: length 4.9
  TOP w0.112: RP59.4 196.44,82.34 196.56,82.22 197.1,82.22 197.19,82.31 197.19,83.09 197.04,83.24 196.65,83.24 v2(196.4,82.99)
  BOTTOM w0.112: CX12.1 195.89,83.24 196.14,83.24 v2(196.4,82.99) 196.42,82.97 LX2.1
TMDS_TXCP: length 5.8
  TOP w0.112: RP59.3 196.44,81.84 196.56,81.96 197.2,81.96 197.44,82.2 v3(197.44,82.57) 197.44,83.2 197.15,83.5 196.65,83.5 v2(196.4,83.75)
  BOTTOM w0.112: LX2.4 196.42,83.77 v2(196.4,83.75) 196.15,83.5 195.91,83.5 CX13.1
TMS_XDP: length 16.6
  TOP w0.102: UC4.9 85.37,89.45 RC46.2 85.35,89.16 85.15,88.96 83.62,88.96 83.24,88.57 v1(83.24,88.24) 83.24,87.81 84.38,86.67 84.38,86.03 84.89,85.53 84.89,84.89 85.72,84.06 86.23,84.06 87.18,83.11 87.18,79.9 86.99,79.71 JXDP1.58
TON_1.35V: length 3.4
  BOTTOM w0.102: PR208.2 80.5,12.02 80.19,12.02 79.61,12.6 v1(79.61,12.65)
  BOTTOM w0.254: PR208.2 81.18,11.63 PU200.9
TP_CLK: length 170.8
  TOP w0.102: RE9.2 151.09,14.99 v1(150.34,14.99) 150.06,15.26 148.96,15.26 v2(147.98,14.28) 147.81,14.11 UE1.87 ; v2(20.63,56.85) 20.63,57.56 20.66,57.59 JTP1.3
  IN1 w0.107: v2(20.63,56.85) 20.63,55.17 25.18,50.63 25.18,46.64 v2(27.57,44.25)
  IN2 w0.107: v2(27.57,44.25) 27.82,44 27.82,42.12 29.85,40.09 46.89,40.09 47.74,39.24 47.74,32.49 52.53,27.7 55.42,27.7 58.37,30.64 76.4,30.64 77.54,31.78 78.85,31.78 79.88,30.76 81.94,30.76 82.4,31.21 82.4,31.21 82.4,31.21 82.64,31.45 82.98,31.45 83.16,31.27 83.3,31.13 90.46,31.13 90.47,31.12 90.77,31.12 96.83,25.06 100.95,25.06 107.31,18.71 107.31,15.99 109.33,13.97 112.27,13.97 113.17,14.87 114.39,14.87 114.95,15.42 116,15.42 116.34,15.08 116.34,14.61 116.65,14.29 120.5,14.29 121.34,15.13 122.3,15.13 122.31,15.14 124.85,15.14 124.85,15.13 125.38,15.13 126.09,14.42 127.08,14.42 127.68,13.82 131.5,13.82 131.91,14.23 133.33,14.23 133.62,13.94 133.63,13.94 133.65,13.92 135.13,13.92 135.41,14.2 141.11,14.2 141.26,14.05 147.74,14.05 v2(147.98,14.28)
TP_DATA: length 173.3
  TOP w0.102: JTP1.4 21.66,59.3 21.65,59.3 21.65,58.33 v2(21.79,58.19) ; UE1.88 147.58,14.51 148.67,15.6 148.88,15.6 RE10.2 149.59,16.62 149.79,16.82 151.06,16.82 151.62,17.38 v1(151.62,17.68) 151.62,19.99 v2(152.05,20.43)
  IN2 w0.107: v2(152.05,20.43) 151.46,21.01 147.86,21.01 146.97,20.12 135.85,20.12 135.39,19.66 131.02,19.66 130.46,19.1 125.93,19.1 125.57,19.46 125.14,19.46 124.93,19.68 114.62,19.68 114.51,19.56 110.22,19.56 108.87,20.91 108.87,21.93 103.14,27.66 99.94,27.66 92.88,34.73 78.24,34.73 75.71,32.19 57.28,32.19 56.49,31.4 51.95,31.4 49.61,33.74 49.61,40.21 45.76,44.06 45.76,47.45 42.24,50.97 32.42,50.97 31.27,52.12 31.27,55.56 31.36,55.65 31.36,58.39 31.47,58.5 31.47,58.84 31.23,59.08 29.68,59.08 29.17,58.57 24.69,58.57 24.3,58.19 v2(21.79,58.19)
TP_DC_TEST_B2: length 1.4
  TOP w0.254: T167.1 156.14,102.38 v2(156.14,102.04)
  BOTTOM w0.254: UC1.B2 v2(156.14,102.04)
TP_EN: length 276
  TOP w0.102: v2(9.58,90.86) 10.85,92.13 v1(11.23,92.13) 11.49,92.13 v2(12.25,91.37) ; v2(7.93,64.32) 8.17,64.08 UE4.3 ; UE1.82 145.1,12.11 144.41,12.81 144.41,14.68 143.19,15.9 v2(143.19,15.9)
  IN1 w0.107: v2(7.93,64.32) 9.96,64.32 11.61,65.97 11.61,71.81 10.22,73.21 10.22,73.84 7.04,77.02 7.04,78.8 7.93,79.68 7.93,81.97 8.31,82.35 8.94,82.35 10.22,83.62 10.22,85.65 9.07,86.8 9.07,90.35 v2(9.58,90.86) ; v2(143.19,15.9) 142.99,16.1 137.99,16.1 137.19,15.3 137.19,15.3 137.13,15.24 134.76,15.24 134.29,15.71 133.81,15.71 133.81,15.72 133.77,15.72 133,16.49 130.95,16.49 129.85,17.58 126.26,17.58 126.02,17.34 122.5,17.34 122.28,17.12 114.53,17.12 112.24,19.41 112.24,23.45 110.84,24.85 110.84,26.31 110.06,27.08 110.06,33.2 107.89,35.37 99.1,35.37 96.11,38.37 95.34,38.37 94.57,39.14 94.57,40.91 94.56,40.92 94.56,40.93 92.83,42.66 92.83,44.25 93.53,44.96 93.53,69.65 93.4,69.78 93.4,73.46 92.77,74.1 92.77,81.59 94.04,82.86 94.04,90.99 91.62,93.4 91.62,96.07 90.86,96.83 90.86,98.3 92.82,100.26 94.6,100.26 v2(95.1,100.77)
  IN2 w0.107: v2(12.25,91.37) 12.76,91.88 13.65,91.88 19.74,97.97 24.19,97.97 28.89,102.67 31.17,102.67 31.43,102.93 31.43,103.69 32.7,104.96 35.36,104.96 36.25,105.85 37.52,105.85 37.9,105.47 39.81,105.47 40.57,104.7 51.47,104.7 54.44,107.67 56.32,107.67 58.15,105.85 62.41,105.85 66.6,101.66 67.24,101.66 70.41,98.48 72.83,98.48 74.22,99.88 81.08,99.88 83.42,97.54 89.41,97.54 93.15,101.27 94.6,101.27 v2(95.1,100.77)
TP_INT#: length 210.7
  TOP w0.102: JTP1.6 23.66,61.11 23.5,61.27 RE329.2 23.52,62.58 RE338.2 24.33,62.1 v2(24.17,61.95) ; v1(92,99.27) 92.36,99.27 92.64,98.99 v2(92.64,98.99) ; v2(158.23,101.85) 157.77,101.39 156.39,101.39 155.6,100.6 QC3.1 154.23,100.6 RC367.1
  IN1 w0.107: v2(95.05,106.48) 95.18,106.48 95.56,106.1 98.99,106.1 102.93,102.16 106.99,102.16 110.67,105.85 119.67,105.85 122.23,103.28 128.53,103.28 129.17,103.91 132.36,103.91 133.04,104.6 134.03,104.6 136.68,107.24 148.14,107.24 150.54,104.84 150.54,103.42 151.1,102.87 151.83,102.14 155.26,102.14 155.74,101.67 158.05,101.67 v2(158.23,101.85)
  IN2 w0.102: 72.32,97.46 70.92,96.07 67.9,96.07 66.32,97.64 ; 73.18,97.46 77.91,97.46
  IN2 w0.107: 77.91,97.46 79.81,97.46 80.07,97.72 81.72,97.72 82.99,96.45 89.85,96.45 92.39,98.99 v2(92.64,98.99) ; 66.32,97.64 65.48,98.48 61.02,98.48 60.51,98.99 60.51,99.88 57.97,102.42 34.47,102.42 33.2,101.15 29.9,101.15 24.95,96.19 20.63,96.19 16.19,91.75 16.19,86.54 19.61,83.11 19.61,78.67 21.27,77.02 21.27,76.03 23.59,73.7 23.59,65.68 24.17,65.09 v2(24.17,61.95) ; 72.32,97.46 73.18,97.46
  BOTTOM w0.102: v2(95.05,106.48) 95.05,103.31 92.64,100.89 v2(92.64,98.99)
TRIP_+1.35VGPUP: length 5
  BOTTOM w0.254: PU1100.2 29.89,45.89 29.17,45.17 v1(29.17,44.78) 29.17,43.36 29.67,42.85 PR1102.2
TRST#_XDP: length 15.7
  TOP w0.102: UC4.12 86.43,87.95 86.11,87.63 86.11,86.87 85.15,85.91 85.15,85.15 85.96,84.33 v1(86.54,84.33) 87.46,84.33 87.92,83.88 88.83,83.88 89.21,83.49 89.21,80.95 86.97,78.71 JXDP1.54
TS_EN: length 204.6
  TOP w0.102: UE1.19 129.71,10.51 v2(129.62,10.42) ; RX25.1 8.87,93.6 8.57,93.91 v1(8.57,94.7) 8.57,95.14 8.79,95.37 UX3.3 10.54,95.37 11.23,96.07 v2(12.38,96.07) ; v2(120.1,9.3) 120.07,9.28 v2(120.07,5.02)
  IN1 w0.107: v2(120.07,5.02) 119.79,5.31 119.04,5.31 117.67,3.94 113.57,3.94 113.37,3.74 110.42,3.74 109.66,4.5 109.66,5.77 109.15,6.28 108.64,6.28 107.99,6.93 107.39,6.93 102.29,12.03 102.29,21.01 100.86,22.44 99.24,22.44 91.14,30.54 79.09,30.54 78.8,30.25 77.69,30.25 75.88,32.06 63.94,32.06 63.68,31.81 55.81,31.81 55.1,31.09 50.68,31.09 48.44,33.33 48.44,38.54 46.92,40.06 37.45,40.06 36.58,40.92 30.23,40.92 28.3,42.85 24.82,42.85 20.88,46.79 20.88,48.63 15.54,53.97 15.54,56.93 15.76,57.15 15.76,72.87 11.61,77.02 11.61,81.21 11.93,81.53 11.93,86.1 13.14,87.3 13.14,95.31 v2(12.38,96.07)
  IN2 w0.107: v2(129.62,10.42) 129.27,10.77 123.94,10.77 122.46,9.3 v2(120.1,9.3)
TS_EN_R: length 11.5
  TOP w0.102: v1(10.42,93.15) 9.96,92.69 RX25.2 9.45,91.62 v2(9.58,91.5)
  BOTTOM w0.102: JEDP.22 3.29,88.5 4.12,89.34 5.26,89.34 5.77,89.84 7.93,89.84 v2(9.58,91.5)
TS_INT#: length 229.5
  TOP w0.076: v2(162.57,94.47) 162.52,94.42 v1(157.21,94.42) 155.81,94.42 v2(155.78,94.44)
  TOP w0.102: v2(3.64,89.47) 3.82,89.29 RX35.2
  IN1 w0.107: v2(93.27,106.48) 93.91,105.85 98.86,105.85 102.9,101.81 107.15,101.81 110.93,105.59 119.59,105.59 122.14,103.04 128.63,103.04 129.25,103.66 132.49,103.66 133.17,104.34 137.65,104.34 140.3,106.99 146.49,106.99 147.25,106.23 147.97,106.23 149.63,104.56 149.63,104 151.73,101.9 155.17,101.9 155.6,101.47 158.05,101.47 158.93,100.6 158.93,99.9 159.81,99.02 161.66,99.02 162.43,98.25 162.43,97.53 162.86,97.1 162.86,94.76 v2(162.57,94.47)
  IN2 w0.107: v2(93.27,106.48) 93.27,107.24 90.23,110.29 83.11,110.29 80.45,107.62 74.3,107.62 73.29,108.64 72.27,108.64 71.43,109.48 70.66,109.48 69.3,110.84 69.3,111.15 66.33,114.13 55.15,114.13 53.78,115.5 44,115.5 43.24,114.74 40.32,114.74 39.55,113.97 33.62,113.97 31.97,115.63 25.96,115.63 24.31,117.28 24.31,120.2 23.36,121.15 17.98,121.15 17.63,120.81 17.63,119.92 16.47,118.75 14.1,118.75 11.84,116.49 11.84,107.04 9.56,104.75 2.9,104.75 1.71,103.56 1.71,90.73 2.6,89.84 3.27,89.84 v2(3.64,89.47)
  BOTTOM w0.076: UC1.P3 154.84,94.03 155.25,94.44 v2(155.78,94.44) ; 162.74,94.92 162.57,94.75 v2(162.57,94.47)
  BOTTOM w0.102: 162.74,94.92 163.38,95.56 163.38,96.19 163.61,96.42 RC114.2 ; v2(3.64,89.47) 3.64,89.36 3.23,88.96 2.52,88.96 2.47,89 JEDP.21
TS_RST#: length 217.3
  TOP w0.102: v2(3.64,90.49) 4.29,90.49 RX24.2
  IN1 w0.107: v2(93.27,105.87) 93.56,105.59 98.74,105.59 102.75,101.58 107.24,101.58 111,105.34 119.51,105.34 122.06,102.79 128.71,102.79 129.32,103.41 132.62,103.41 133.32,104.11 137.75,104.11 140.4,106.76 146.39,106.76 147.15,105.99 147.82,105.99 149.4,104.41 149.4,103.9 151.7,101.6 155.19,101.6 155.52,101.27 157.83,101.27 158.64,100.47 158.64,99.62 159.57,98.69 159.57,95.71 v2(159.42,95.56)
  IN2 w0.107: v2(3.64,90.49) 3.24,90.1 2.72,90.1 1.96,90.86 1.96,103.43 2.98,104.45 9.63,104.45 12.12,106.94 12.12,116.39 14.23,118.5 16.62,118.5 17.94,119.82 17.94,120.6 18.25,120.92 23.21,120.92 24.06,120.07 24.06,117.15 25.84,115.37 31.86,115.37 33.51,113.72 41.71,113.72 42.22,114.23 54.41,114.23 54.77,113.87 66.17,113.87 69.04,111 69.04,110.77 70.64,109.17 71.23,109.17 72.09,108.31 73.11,108.31 74.05,107.37 80.7,107.37 83.37,110.04 89.85,110.04 91.12,108.77 91.12,108.03 v2(93.27,105.87)
  BOTTOM w0.076: RC76.2 159.91,95.56 v2(159.42,95.56) 159.04,95.94 158.35,95.94 v1(157.97,95.56) 157.56,95.56 157.31,95.81 156.39,95.81 UC1.L1
  BOTTOM w0.102: JEDP.19 3.2,90 3.64,90.44 v2(3.64,90.49)
UG_3V: length 13.1
  TOP w0.102: PQ101.4 v1(59.88,26.22)
  IN1 w0.762: 59.24,24.06 60,24.06 62.13,21.92 67.87,21.92 68.97,20.83 69.86,20.83
  vias: v3(59.29,25.4) v3(59.29,24.77) v3(70.59,20.06) v3(70.97,19.52)
UG_5V: length 10.8
  TOP w0.102: v1(69.59,15.55) 70.34,15.55 70.9,16.11 v3(70.97,16.11)
  IN1 w0.762: 70.77,15.37 69.17,13.77 62.92,13.77 62.41,13.26
  vias: v3(61.78,12.42) v3(62.41,12.42) v3(70.97,16.74)
UG_+1.35VGPUP:
  vias: v1(34.88,45.75) v2(34.22,45.78) v2(34.6,45.27)
UGATE:
  vias: v1(72.19,109.91) v2(72.57,110.29) v2(73.21,110.42)
UGATE1: length 10.6
  TOP w0.102: v3(50.5,46.44) v1(50.5,45.6)
  IN2 w0.762: 50.7,46.44 51.8,46.44 56.38,41.85 57.83,41.85 58.35,41.33
  vias: v2(58.73,40.95) v2(59.24,40.44) v3(50.5,47.2)
UGATE2: length 9.4
  TOP w0.102: v2(64.67,40.59) v1(65.36,40.59)
  IN2 w0.762: v2(64.73,47.74) v2(63.99,47.74) 63.99,43.69 65.33,42.35 65.33,41.18 64.75,40.59 v2(64.67,40.59)
  vias: v2(64.17,40.11)
USB3RN1_JUSB1: length 89.8
  IN2 w0.076: 144.13,101.31 144.13,101.3 144.14,101.28 144.14,101.24 144.25,101.13 144.28,101.13 144.95,100.46 144.95,98.32 144.84,98.21 144.62,98.21 144.57,98.26 v2(144.57,98.44)
  IN2 w0.114: v2(195.6,71.16) 195.59,71.16 195.44,71.31 195.44,71.55 194.97,72.02 190.76,72.02 189.79,73 189.79,74.58 187.94,76.43 186.04,76.43 185.49,76.98 185.49,78.88 183.95,80.42 183.95,81.47 180.9,84.51 180.9,85.37 176.96,89.31 176.96,93.32 175.87,94.42 175.87,95.26 174.99,96.14 173.59,96.14 172.68,97.06 172.68,97.87 171.11,99.44 170.5,99.44 167.39,102.54 163.43,102.54 161.09,104.88 161.09,108.18 159.23,110.04 159.23,110.72 158.43,111.53 152.36,111.53 149.85,109.02 147.17,109.02 144.08,105.94 144.08,101.78 144.13,101.74 144.13,101.31
  BOTTOM w0.076: UC1.G20 144.89,98.12 v2(144.57,98.44)
  BOTTOM w0.112: LI1.1 195.66,70.56 195.38,70.84 195.38,70.94 v2(195.6,71.16)
USB3RN1_JUSB1_R: length 9.8
  BOTTOM w0.112: LI1.2 195.66,68.25 195.65,68.25 195.65,68.1 195.24,67.69 194.87,67.69 194.58,67.4 194.58,67.17 194.72,67.03 194.87,67.03 194.97,67.13 DI1.10 DI1.1 196.82,67.13 196.95,67 v3(197.61,67) 198.12,67 198.86,67.75 199.67,67.75 200.25,68.33 200.61,68.33 200.79,68.51 JUSB1.5
USB3RN2_JUSB2: length 102.3
  IN2 w0.076: 145.86,101.78 145.86,101.76 145.88,101.74 145.88,98.93 145.81,98.86 145.62,98.86 145.48,99 v2(145.48,99.15)
  IN2 w0.114: v2(189.98,48.58) 189.86,48.46 189.67,48.46 189.56,48.58 189.56,49.67 191.57,51.68 191.57,57.21 188.52,60.25 188.52,63.78 188.02,64.29 188.02,68.05 184.07,71.99 184.07,77.84 183.69,78.22 183.69,79.49 179.21,83.98 178.29,83.98 175.95,86.31 175.95,87.96 174.75,89.16 174.75,92.04 172.95,93.85 172.86,93.85 171.51,95.2 171.51,95.57 169.8,97.28 169.07,97.28 165.98,100.37 164.38,100.37 163.86,100.89 162.19,100.89 159.51,103.56 159.51,106.13 158.6,107.04 158.6,108.31 157.31,109.6 155.38,109.6 154.72,108.94 151.11,108.94 148.01,105.84 146.77,105.84 146.24,105.31 146.24,104.81 145.6,104.17 145.6,102.82 145.86,102.57 145.86,101.78
  BOTTOM w0.076: UC1.E18 145.92,99.25 145.8,99.13 145.5,99.13 v2(145.48,99.15)
  BOTTOM w0.112: v2(189.98,48.58) 190.15,48.41 191.12,48.41 191.12,48.41 191.29,48.59 LI4.1
USB3RN2_JUSB2_R: length 9.1
  BOTTOM w0.112: JUSB2.5 200.79,50.58 200.79,50.58 200.79,50.31 200.66,50.18 200.19,50.18 199.47,49.46 199.12,49.46 197.97,48.32 v3(197.48,48.32) 196.72,48.32 196.62,48.42 196.44,48.42 DI4.1 DI4.10 194.73,48.43 194.61,48.3 194.15,48.3 193.86,48.59 LI4.2
USB3RP1_JUSB1: length 89.7
  IN2 w0.076: 144.33,101.31 145.12,100.52 145.12,98.25 144.91,98.05 144.61,98.05 144.53,97.97 v2(144.53,97.69)
  IN2 w0.114: v2(194.82,71.16) 194.82,71.16 195.09,71.16 195.19,71.26 195.19,71.45 194.86,71.77 190.66,71.77 189.54,72.89 189.54,74.48 187.83,76.18 185.93,76.18 185.24,76.88 185.24,78.78 183.7,80.32 183.7,81.36 180.66,84.41 180.66,85.27 176.71,89.21 176.71,93.22 175.62,94.31 175.62,95.16 174.88,95.89 173.49,95.89 172.43,96.95 172.43,97.77 171,99.19 170.39,99.19 167.29,102.3 163.33,102.3 160.84,104.78 160.84,108.08 158.98,109.94 158.98,110.62 158.32,111.28 152.47,111.28 149.96,108.77 147.27,108.77 144.33,105.83 144.33,101.82 144.33,101.82 144.33,101.65 144.33,101.65 144.33,101.31
  BOTTOM w0.076: UC1.H20 144.76,97.47 v2(144.53,97.69)
  BOTTOM w0.112: v2(194.82,71.16) 195.03,71.16 195.12,71.07 195.12,70.84 194.86,70.57 LI1.4
USB3RP1_JUSB1_R: length 9.7
  BOTTOM w0.112: LI1.3 194.86,68.1 194.85,68.1 194.85,68.06 194.31,67.51 v3(194.31,67.29) 194.31,67.03 194.58,66.76 194.83,66.76 194.97,66.63 DI1.9 DI1.2 196.97,66.63 197.09,66.75 198.22,66.75 198.97,67.49 199.78,67.49 200.36,68.08 200.65,68.08 200.79,67.94 JUSB1.6
USB3RP2_JUSB2: length 102.2
  IN2 w0.076: 146.11,101.78 146.11,101.71 146.05,101.66 146.05,98.86 145.88,98.7 145.68,98.7 145.5,98.52 v2(145.5,98.38)
  IN2 w0.114: 146.11,101.78 146.11,102.67 145.85,102.93 145.85,104.07 146.49,104.7 146.49,105.21 146.87,105.59 148.11,105.59 151.21,108.69 154.82,108.69 155.48,109.35 157.21,109.35 158.35,108.21 158.35,106.94 159.26,106.02 159.26,103.46 162.08,100.64 163.76,100.64 164.28,100.12 165.88,100.12 168.97,97.03 169.69,97.03 171.26,95.47 171.26,95.1 172.76,93.6 172.84,93.6 174.5,91.94 174.5,89.06 175.7,87.86 175.7,86.21 178.19,83.73 179.11,83.73 183.44,79.39 183.44,78.12 183.83,77.73 183.83,71.89 187.77,67.94 187.77,64.19 188.28,63.68 188.28,60.15 191.32,57.1 191.32,51.79 189.31,49.77 189.31,48.48 189.57,48.22 189.76,48.22 189.97,48.01 v2(189.97,47.97)
  BOTTOM w0.076: UC1.F18 145.89,98.77 v2(145.5,98.38)
  BOTTOM w0.112: LI4.4 191.38,47.79 191.01,48.16 190.15,48.16 v2(189.97,47.97)
USB3RP2_JUSB2_R: length 9.1
  BOTTOM w0.112: JUSB2.6 200.79,49.77 200.63,49.93 200.3,49.93 199.57,49.2 199.22,49.2 198.08,48.06 196.75,48.06 196.61,47.93 DI4.2 DI4.9 194.69,47.93 194.57,48.05 194.12,48.05 193.87,47.79 LI4.3
USB3TN1_JUSB1: length 98.2
  IN2 w0.076: v2(134.45,106.2) 134.65,106 135.12,106 136.31,107.2 141.23,107.2 141.27,107.24 141.29,107.24
  IN2 w0.114: v2(194.71,73.39) 194.71,73.42 194.17,73.96 192.88,73.96 191.7,75.14 191.7,75.75 189.67,77.77 188.91,77.77 187.86,78.82 187.86,83.27 184.86,86.27 184.86,87.4 185.48,88.01 185.48,92.74 183.47,94.75 179.13,94.75 175.7,98.18 174.78,98.18 174.2,98.76 174.2,99.7 172.88,101.02 171.86,101.02 170.09,102.79 169.51,102.79 168.4,103.9 168.4,108.49 166.86,110.03 162.75,110.03 159.7,113.08 151.81,113.08 149.4,110.67 145.42,110.67 141.99,107.24 141.29,107.24
  BOTTOM w0.076: UC1.C33 136.2,100.95 136.2,101.19 136.11,101.28 136.11,102.2 136.39,102.48 136.39,103.37 135.27,104.49 135.27,105.69 134.95,106.01 134.64,106.01 v2(134.45,106.2)
  BOTTOM w0.112: CI3.2 194.29,72.97 v2(194.71,73.39)
USB3TN1_JUSB1_C: length 1.8
  BOTTOM w0.112: LI3.1 194,70.66 193.77,70.89 193.77,70.99 193.94,71.16 193.94,71.37 194.04,71.47 194.04,71.47 194.28,71.71 CI3.1
USB3TN1_JUSB1_R: length 12.5
  BOTTOM w0.112: JUSB1.8 200.79,62.49 200.72,62.41 200.31,62.41 199.5,63.22 199.02,63.22 197.91,64.33 197.91,65.13 197.55,65.49 196.99,65.49 196.85,65.63 DI1.4 DI1.7 194.96,65.63 194.82,65.49 194.4,65.49 v3(194.03,65.86) 193.66,66.23 193.66,67.79 194,68.14 LI3.2
USB3TN2_JUSB2: length 128.9
  IN2 w0.076: 142.42,105.64 142.4,105.64 142.36,105.68 139.34,105.68 138.72,105.06 137.41,105.06 v2(137.1,104.75)
  IN2 w0.114: v2(188.77,46.94) 188.77,46.9 189.11,46.56 191.88,46.56 192.47,47.15 192.47,50.5 192.09,50.88 192.09,57.48 189.04,60.53 189.04,66.58 189.95,67.49 193.34,67.49 194.69,68.84 195.22,68.84 196.4,70.02 196.4,71.32 195.11,72.6 192.03,72.6 190.56,74.07 190.56,75.26 189.06,76.77 188.4,76.77 186.8,78.36 186.8,80.8 184.47,83.14 184.47,84.08 184.05,84.49 183.11,84.49 181.94,85.66 181.41,85.66 177.53,89.54 177.53,93.58 176.39,94.72 176.39,95.96 175.27,97.08 174.43,97.08 172.73,98.78 172.73,99.19 171.94,99.98 170.77,99.98 167.67,103.08 163.61,103.08 161.61,105.08 161.61,109.68 159.24,112.05 152.18,112.05 149.67,109.53 146.97,109.53 143.08,105.64 142.42,105.64
  BOTTOM w0.076: v2(137.1,104.75) 137.1,104.82 136.89,105.03 136.56,105.03 136.2,104.68 136.2,104.32 136.87,103.65 136.87,102.27 136.7,102.09 136.7,101.91 136.41,101.63 UC1.B33
  BOTTOM w0.112: CI10.2 189.15,46.68 189.04,46.68 v2(188.77,46.94)
USB3TN2_JUSB2_C: length 1.6
  BOTTOM w0.112: LI6.1 191.14,46.94 190.87,46.67 190.71,46.67 CI10.1
USB3TN2_JUSB2_R: length 9.9
  BOTTOM w0.112: JUSB2.8 200.79,44.32 200.67,44.2 200.32,44.2 199.57,44.94 199.09,44.94 198.32,45.71 198.32,46.39 197.9,46.8 196.74,46.8 196.62,46.93 DI4.4 DI4.7 194.69,46.93 194.56,46.8 194.29,46.8 194.16,46.67 193.92,46.67 193.65,46.94 LI6.2
USB3TP1_JUSB1: length 98.1
  IN2 w0.076: 141.29,106.99 141.27,106.99 141.23,107.03 136.38,107.03 135.18,105.84 134.54,105.84 134.45,105.74 v2(134.45,105.59)
  IN2 w0.114: v2(194.11,73.41) 194.11,73.6 194.01,73.71 192.78,73.71 191.45,75.03 191.45,75.64 189.57,77.53 188.81,77.53 187.62,78.72 187.62,83.16 187.22,83.56 187.04,83.56 186.8,83.8 186.8,83.98 186.51,84.27 186.32,84.27 186.06,84.54 186.06,84.72 185.84,84.94 185.65,84.94 185.4,85.2 185.4,85.38 184.61,86.16 184.61,87.5 185.23,88.12 185.23,92.64 183.37,94.5 179.02,94.5 175.59,97.93 174.68,97.93 173.95,98.66 173.95,99.6 172.78,100.77 171.76,100.77 169.98,102.54 169.4,102.54 168.15,103.79 168.15,108.39 166.76,109.78 162.65,109.78 159.6,112.83 151.91,112.83 149.5,110.42 145.52,110.42 142.09,106.99 141.29,106.99
  BOTTOM w0.076: v2(134.45,105.59) 134.45,105.77 134.52,105.85 134.88,105.85 135.11,105.62 135.11,104.42 136.23,103.3 136.23,102.55 135.95,102.27 135.95,101.44 135.88,101.37 135.66,101.37 135.59,101.3 135.59,101.12 135.65,101.06 UC1.B34
  BOTTOM w0.112: v2(194.11,73.41) 193.4,72.69 CI4.2
USB3TP1_JUSB1_C: length 1.8
  BOTTOM w0.112: CI4.1 193.69,71.39 193.69,71.26 193.51,71.09 193.51,70.96 193.2,70.65 LI3.4
USB3TP1_JUSB1_R: length 12.9
  BOTTOM w0.112: LI3.3 193.2,68.02 193.4,67.82 193.4,66.1 194.29,65.21 194.81,65.21 194.89,65.13 DI1.6 DI1.5 196.85,65.13 196.95,65.23 197.45,65.23 197.65,65.03 v3(197.65,64.7) 197.65,64.23 198.92,62.96 199.4,62.96 200.2,62.16 200.6,62.16 200.79,61.97 JUSB1.9
USB3TP2_JUSB2: length 129.2
  IN2 w0.076: v2(137.1,105.48) 137.1,105.35 137.23,105.22 138.65,105.22 139.27,105.85 142.36,105.85 142.4,105.89 142.42,105.89
  IN2 w0.114: v2(188.73,46.16) 188.88,46.31 191.98,46.31 192.72,47.05 192.72,50.6 192.33,50.98 192.33,57.59 189.29,60.63 189.29,66.48 190.05,67.24 193.45,67.24 194.8,68.59 195.32,68.59 196.65,69.92 196.65,71.42 195.22,72.85 192.13,72.85 190.81,74.17 190.81,75.37 189.16,77.02 188.5,77.02 187.05,78.46 187.05,80.9 184.71,83.24 184.71,84.18 184.16,84.74 183.22,84.74 182.05,85.91 181.51,85.91 177.78,89.64 177.78,93.68 176.64,94.82 176.64,96.07 175.37,97.33 174.53,97.33 172.98,98.89 172.98,99.29 172.04,100.23 170.87,100.23 167.77,103.33 163.71,103.33 161.85,105.19 161.85,109.78 159.34,112.3 152.08,112.3 149.56,109.78 146.87,109.78 142.97,105.89 142.42,105.89
  BOTTOM w0.076: v2(137.1,105.48) 136.82,105.2 136.49,105.2 136.04,104.75 136.04,104.25 136.71,103.58 136.71,102.33 UC1.A33
  BOTTOM w0.112: CI11.2 189.15,46.42 188.99,46.42 v2(188.73,46.16)
USB3TP2_JUSB2_C: length 1.6
  BOTTOM w0.112: CI11.1 190.68,46.41 190.94,46.41 191.21,46.14 LI6.4
USB3TP2_JUSB2_R: length 9.9
  BOTTOM w0.112: LI6.3 193.72,46.14 194,46.41 194.26,46.41 194.39,46.54 194.57,46.54 194.68,46.43 DI4.6 DI4.5 196.61,46.43 196.73,46.55 v3(197.41,46.55) 197.8,46.55 198.06,46.29 198.06,45.61 198.98,44.69 199.47,44.69 200.21,43.95 200.58,43.95 200.79,43.73 JUSB2.9
USB20_CAM_N7: length 189.3
  TOP w0.112: RX21.1 6.26,84.64 LX6.1 6.9,84.75 7.17,85.02 7.32,85.02 7.55,84.78 7.55,84.27 v2(7.28,84)
  IN2 w0.076: v2(148.96,82.99) 148.96,83.26 148.87,83.34 148.59,83.34 148.35,83.58 148.35,84.57 148.14,84.78 148.14,85.27 148.14,85.27 148.14,85.68 147.64,86.18 147.64,86.29
  IN2 w0.114: v2(7.28,84) 7.58,83.7 7.58,83.21 7.95,82.84 9.18,82.84 10.82,84.48 10.82,85 10.6,85.22 10.6,91.5 14.51,95.41 14.51,96.07 17.44,99 21.89,99 26.32,103.43 29.39,103.43 31.81,105.85 33.58,105.85 35.11,107.37 38.03,107.37 38.54,106.86 40.44,106.86 41.33,105.97 51.62,105.97 54.92,109.28 56.95,109.28 58.73,107.5 63.56,107.5 69.4,101.66 80.6,101.66 83.27,98.99 89.47,98.99 92.28,101.8 94.98,101.8 95.94,100.84 97.64,100.84 98.74,99.75 108.36,99.75 109.13,100.52 114.38,100.52 115.02,99.88 118.35,99.88 118.68,100.21 120.78,100.21 121.12,99.88 124.95,99.88 126.09,98.73 130.49,98.73 131.25,99.5 131.25,101.02 133.71,103.48 135.27,103.48 137.61,101.15 140.01,101.15 140.52,100.64 140.52,99.37 139.63,98.48 139.63,96.7 141.41,94.92 141.41,92.79 143.06,91.14 143.06,89.16 143.66,88.56 144.12,88.56 145.31,87.37 146.99,87.37 147.64,86.73 147.64,86.29
  BOTTOM w0.076: v2(148.96,82.99) 148.93,83.02 148.7,83.02 148.56,82.88 UC1.AR13
USB20_CAM_N7_R: length 4
  TOP w0.112: v2(3.61,84.87) 3.83,85.09 4.05,85.09 4.39,84.75 LX6.2 4.78,84.64 RX21.2
  BOTTOM w0.112: JEDP.28 2.5,85.5 2.54,85.55 2.77,85.55 3.19,85.13 3.5,85.13 3.61,85.02 v2(3.61,84.87)
USB20_CAM_P7: length 189.5
  TOP w0.112: v2(8.06,84) 7.91,84 7.8,84.1 7.8,84.89 7.42,85.27 7.23,85.27 6.96,85.55 LX6.4 6.26,85.65 RX22.1
  IN2 w0.076: 147.88,86.22 147.88,86.16 148.3,85.75 148.3,85.34 148.3,85.34 148.3,84.85 148.52,84.64 148.52,83.65 148.66,83.51 148.84,83.51 v2(149,83.67)
  IN2 w0.114: 147.88,86.22 147.88,86.83 147.1,87.62 145.41,87.62 144.22,88.81 143.77,88.81 143.31,89.26 143.31,91.24 141.66,92.89 141.66,95.02 139.88,96.81 139.88,98.38 140.77,99.27 140.77,100.74 140.11,101.4 137.71,101.4 135.37,103.73 133.61,103.73 131,101.12 131,99.6 130.38,98.98 126.19,98.98 125.05,100.13 121.22,100.13 120.88,100.46 118.58,100.46 118.24,100.13 115.12,100.13 114.48,100.77 109.02,100.77 108.26,100 98.84,100 97.75,101.09 96.05,101.09 95.09,102.05 92.17,102.05 89.37,99.24 83.37,99.24 80.71,101.9 69.5,101.9 63.66,107.75 58.83,107.75 57.06,109.52 54.82,109.52 51.52,106.22 41.44,106.22 40.55,107.11 38.64,107.11 38.13,107.62 35.01,107.62 33.48,106.1 31.7,106.1 29.29,103.68 26.21,103.68 21.78,99.25 17.34,99.25 14.26,96.18 14.26,95.51 10.35,91.6 10.35,85.12 10.57,84.9 10.57,84.58 10.4,84.41 10.22,84.41 9.96,84.16 9.96,83.97 9.74,83.75 9.56,83.75 9.3,83.49 9.3,83.31 9.08,83.09 8.06,83.09 7.83,83.32 7.83,83.93 7.91,84 v2(8.06,84)
  BOTTOM w0.076: UC1.AP13 148.9,83.65 148.98,83.65 v2(149,83.67)
USB20_CAM_P7_R: length 4
  TOP w0.112: RX22.2 4.78,85.65 LX6.3 4.39,85.55 4.25,85.4 4.2,85.35 3.92,85.35 v2(3.61,85.65)
  BOTTOM w0.112: JEDP.27 2.45,86 2.65,85.81 2.87,85.81 3.29,85.38 3.5,85.38 3.61,85.5 v2(3.61,85.65)
USB20_CR_N6: length 253.7
  IN2 w0.076: v2(149.46,82.67) 149.65,82.86 150.21,82.86 150.3,82.77 150.3,81.46 150.26,81.42 150.26,80.12 150.66,79.72 151.09,79.72 152.74,78.07 153.78,78.07 156.14,75.71 158.1,75.71 159.16,74.65 159.44,74.65
  IN2 w0.114: 159.44,74.65 161.07,74.65 161.52,74.2 167.42,74.2 169.68,71.94 169.68,70.11 171.16,68.63 171.16,67.28 173.39,65.05 173.39,62.16 175.7,59.85 175.7,53.24 175.07,52.61 175.07,48.46 175.47,48.06 175.47,22.89 173.71,21.13 157.19,21.13 155.92,22.4 153.01,22.4 152.8,22.61 143.46,22.61 143.18,22.89 141.21,22.89 141.05,22.74 128.13,22.74 127.26,21.87 122.27,21.87 122.27,21.87 117.11,21.87 116.24,22.74 110.72,22.74 103.98,29.49 101.94,29.49 94.54,36.89 88.29,36.89 85.93,39.25 78.52,39.25 74.08,34.81 59.07,34.81 58.82,35.06 56.35,35.06 54.56,33.27 52.7,33.27 51.11,34.86 51.11,40.81 47.26,44.66 47.26,49.62 46.88,50 46.88,51.25 44.94,53.19 44.79,53.19 44.63,53.34 44.24,53.34 44.09,53.19 43.82,53.19 43.67,53.34 43.3,53.34 43.15,53.19 42.88,53.19 42.73,53.34 42.36,53.34 42.21,53.19 41.97,53.19 41.81,53.34 41.45,53.34 41.29,53.19 41.03,53.19 40.87,53.34 40.51,53.34 40.35,53.19 40.09,53.19 39.93,53.34 39.57,53.34 39.41,53.19 39.17,53.19 39.03,53.34 38.68,53.34 38.54,53.19 38.16,53.19 38.01,53.34 37.64,53.34 37.5,53.19 37.14,53.19 37,53.34 36.65,53.34 36.51,53.19 36.15,53.19 36.01,53.34 35.66,53.34 35.52,53.19 35.16,53.19 35.01,53.34 34.67,53.34 34.52,53.19 34.22,53.19 34.08,53.34 33.74,53.34 33.61,53.47 33.61,54.48 33.31,54.77 32.78,54.77 v2(32.56,54.99)
  BOTTOM w0.076: UC1.AP11 149.92,82.97 149.62,82.67 v2(149.46,82.67)
  BOTTOM w0.112: v2(32.56,54.99) 32.25,54.67 31.62,54.67 31.35,54.95 LI8.1
USB20_CR_N6_R: length 3.9
  BOTTOM w0.112: LI8.2 28.79,54.95 28.44,54.6 v3(27.95,54.6) 26.51,54.6 26.17,54.95 JIO.12
USB20_CR_P6: length 253.5
  IN2 w0.076: v2(149.49,83.29) 149.49,83.1 149.56,83.02 150.27,83.02 150.46,82.83 150.46,81.39 150.42,81.36 150.42,80.19 150.73,79.89 151.16,79.89 152.81,78.24 153.85,78.24 156.21,75.87 158.17,75.87 159.15,74.9 159.44,74.9
  IN2 w0.114: 159.44,74.9 161.18,74.9 161.63,74.45 167.52,74.45 169.93,72.04 169.93,70.21 171.41,68.74 171.41,67.39 173.64,65.16 173.64,62.26 175.95,59.95 175.95,53.14 175.32,52.51 175.32,48.57 175.72,48.16 175.72,22.79 173.82,20.88 157.08,20.88 155.81,22.15 152.9,22.15 152.69,22.36 143.36,22.36 143.08,22.64 141.31,22.64 141.16,22.49 128.23,22.49 127.37,21.62 122.37,21.62 122.37,21.62 117,21.62 116.13,22.49 110.62,22.49 103.87,29.24 101.84,29.24 94.44,36.64 88.19,36.64 85.83,39 78.62,39 74.19,34.56 58.97,34.56 58.72,34.82 56.45,34.82 54.66,33.02 52.6,33.02 50.86,34.75 50.86,40.71 47.01,44.56 47.01,49.52 46.63,49.9 46.63,51.14 44.83,52.94 36.05,52.94 35.9,53.09 35.76,53.09 35.62,52.94 35.06,52.94 34.91,53.09 34.77,53.09 34.63,52.94 34.12,52.94 33.97,53.09 33.64,53.09 33.36,53.37 33.36,54.37 33.2,54.53 32.72,54.53 32.56,54.37 v2(32.56,54.21)
  BOTTOM w0.076: UC1.AN11 149.58,83.29 v2(149.49,83.29)
  BOTTOM w0.112: v2(32.56,54.21) 32.35,54.42 31.59,54.42 31.31,54.15 LI8.4
USB20_CR_P6_R: length 3.9
  BOTTOM w0.112: JIO.11 26.22,53.95 26.63,54.35 28.62,54.35 28.82,54.15 LI8.3
USB20_JUSB1_N0: length 63.6
  IN2 w0.076: v2(151.44,83.31) 151.62,83.49 152.08,83.49 152.22,83.34 152.22,82.04 152.73,81.53 152.73,81.08 153.31,80.51 155.21,80.51 156.71,79.01 158.87,79.01 159.12,78.76 159.38,78.76 159.42,78.72 159.44,78.72
  IN2 w0.114: 159.44,78.72 160.69,78.72 162.54,76.87 168.36,76.87 171.26,73.97 172.14,73.97 172.93,73.18 172.93,69.62 174.49,68.06 175.8,68.06 v2(175.95,67.92)
  BOTTOM w0.076: UC1.AN8 151.77,83.63 v2(151.44,83.31)
  BOTTOM w0.112: v2(175.95,67.92) 176.24,68.2 177.53,68.2 177.63,68.3 177.8,68.3 178.06,68.56 178.06,68.73 178.36,69.03 178.46,69.03 178.5,69.03 178.77,69.3 178.77,69.44 178.94,69.61 179.05,69.61 179.11,69.61 179.36,69.85 179.36,70.02 179.57,70.24 179.69,70.24 179.94,70.49 179.94,70.61 180.05,70.72 184.63,70.72 187.5,67.85 190.98,67.85 192.08,66.75 192.08,66.1 193.48,64.7 193.48,60.69 193.58,60.59 193.58,59.44 194.04,58.97 194.38,58.97 194.7,58.66 LI2.1
USB20_JUSB1_N0_R: length 13.7
  IN2 w0.114: v2(195.89,62.27) 195.66,62.49 195.66,62.94 195.91,63.18 196.88,63.18 197.54,63.85 197.54,63.85 198.98,65.29 199.24,65.29 199.42,65.11 199.42,64.38 199.29,64.25 JUSB1.2
  BOTTOM w0.112: LI2.2 197.08,58.66 197.35,58.92 197.59,58.92 197.87,59.21 197.87,59.83 197.38,60.32 196.02,60.32 195.76,60.57 195.76,61.06 196.03,61.33 DI2.2 196.43,61.33 196.43,62.19 196.35,62.27 v2(195.89,62.27)
USB20_JUSB1_P0: length 63.6
  IN2 w0.076: v2(151.45,83.96) 151.45,83.73 151.53,83.65 152.15,83.65 152.39,83.41 152.39,82.11 152.9,81.6 152.9,81.15 153.38,80.67 155.28,80.67 156.77,79.18 158.93,79.18 159.19,78.92 159.38,78.92 159.42,78.96 159.44,78.96
  IN2 w0.114: 159.44,78.96 160.8,78.96 162.64,77.12 168.46,77.12 171.36,74.22 172.25,74.22 173.18,73.28 173.18,69.72 174.59,68.31 175.79,68.31 175.95,68.47 v2(175.95,68.7)
  BOTTOM w0.076: v2(151.45,83.96) 151.78,84.28 UC1.AM8
  BOTTOM w0.112: LI2.4 194.57,59.46 194.34,59.23 194.15,59.23 193.83,59.54 193.83,60.7 193.73,60.8 193.73,64.81 192.33,66.2 192.33,66.86 191.09,68.1 187.61,68.1 184.74,70.97 179.94,70.97 177.43,68.46 176.19,68.46 v2(175.95,68.7)
USB20_JUSB1_P0_R: length 13.6
  IN2 w0.114: v2(195.3,62.26) 195.42,62.38 195.41,62.39 195.41,63.04 195.8,63.43 196.77,63.43 197.29,63.95 198.87,65.54 199.19,65.54 199.29,65.63 JUSB1.3
  BOTTOM w0.112: v2(195.3,62.26) 194.79,62.26 194.5,61.97 DI2.3 195.26,61.33 195.51,61.08 195.51,60.47 195.91,60.07 197.28,60.07 197.62,59.72 197.62,59.32 197.48,59.18 197.29,59.18 197.02,59.46 LI2.3
USB20_JUSB2_N1: length 72.1
  IN2 w0.076: v2(152.79,82.94) 152.87,82.94 153.19,82.61 153.19,82 153.33,81.86 153.33,81.33 153.55,81.11 155.73,81.11 156.65,80.19 158.7,80.19 159.17,79.72 159.38,79.72 159.42,79.76 159.44,79.76
  IN2 w0.114: v2(177.6,55.8) 177.77,55.97 178.26,55.97 178.61,56.31 178.61,61.76 177.2,63.17 177.2,67.14 177.25,67.19 177.25,69.32 175.9,70.67 175.02,70.67 174.76,70.92 174.76,76.05 173.87,76.94 170.03,76.94 169.01,77.96 162.95,77.96 161.14,79.76 159.44,79.76
  BOTTOM w0.076: UC1.AR7 152.4,82.66 152.68,82.94 v2(152.79,82.94)
  BOTTOM w0.112: LI5.1 189.6,43.34 189.34,43.6 188.44,43.6 185.93,46.11 185.93,49.43 185.6,49.76 185.6,54.26 183.29,56.57 179.78,56.57 179.73,56.62 178.79,56.62 178.23,56.06 177.87,56.06 v2(177.6,55.8)
USB20_JUSB2_N1_R: length 13.8
  IN2 w0.114: JUSB2.2 199.29,46.69 199.06,46.92 198.02,46.92 196.76,45.66 196.76,42.87 196.35,42.46 195.67,42.46 195.49,42.29 v2(195.49,42.24)
  BOTTOM w0.112: LI5.2 192.32,43.34 192.59,43.61 192.87,43.61 DI5.2 193.71,43.38 193.94,43.61 194.23,43.61 194.66,43.18 194.66,42.83 195.03,42.47 195.26,42.47 195.49,42.24 v2(195.49,42.24)
USB20_JUSB2_P1: length 71.9
  IN2 w0.076: v2(152.82,82.28) 153.03,82.07 153.03,81.93 153.17,81.79 153.17,81.26 153.49,80.94 155.66,80.94 156.58,80.03 158.64,80.03 159.11,79.56 159.38,79.56 159.42,79.52 159.44,79.52
  IN2 w0.114: 159.44,79.52 161.04,79.52 162.84,77.71 168.91,77.71 169.93,76.69 173.77,76.69 174.51,75.95 174.51,70.82 174.91,70.42 175.8,70.42 177,69.22 177,67.29 176.95,67.24 176.95,66.05 176.82,65.92 176.82,65.56 176.95,65.43 176.95,65.01 176.82,64.88 176.82,64.5 176.95,64.37 176.95,63.07 177.07,62.95 177.07,62.77 177.32,62.51 177.5,62.51 177.7,62.31 177.7,62.13 177.96,61.88 178.14,61.88 178.36,61.65 178.36,61.07 178.24,60.94 178.24,60.54 178.36,60.41 178.36,60.13 178.24,60 178.24,59.66 178.36,59.53 178.36,59.29 178.24,59.16 178.24,58.82 178.36,58.69 178.36,58.45 178.24,58.32 178.24,57.97 178.36,57.84 178.36,57.46 178.24,57.33 178.24,56.97 178.36,56.85 178.36,56.42 178.16,56.21 177.73,56.21 177.6,56.34 v2(177.6,56.58)
  BOTTOM w0.076: v2(152.82,82.28) 152.54,82.01 UC1.AT7
  BOTTOM w0.112: v2(177.6,56.58) 177.6,56.58 177.87,56.32 178.13,56.32 178.68,56.88 179.84,56.88 179.89,56.83 183.4,56.83 185.86,54.37 185.86,49.86 186.19,49.53 186.19,46.22 188.55,43.86 189.41,43.86 189.7,44.14 190.09,44.14 LI5.4
USB20_JUSB2_P1_R: length 13.7
  IN2 w0.114: JUSB2.3 199.29,47.39 199.07,47.17 197.92,47.17 196.51,45.76 196.51,42.97 196.25,42.71 195.66,42.71 195.51,42.86 v2(195.51,42.87)
  BOTTOM w0.112: v2(195.51,42.87) 195.51,42.86 195.38,42.73 195.13,42.73 194.92,42.94 194.92,43.29 194.34,43.87 193.94,43.87 193.71,44.1 DI5.3 192.87,43.87 192.59,43.87 192.32,44.14 LI5.3
USB20_JUSB3_N2: length 260.4
  IN2 w0.076: 159.44,75.5 159.43,75.5 159.35,75.58 159.12,75.58 158.36,76.34 157.55,76.34 156.77,77.12 156.6,77.12 156.33,77.39 156.33,77.56 156.19,77.7 156.01,77.7 155.76,77.96 155.76,78.13 155.6,78.29 155.43,78.29 155.19,78.53 155.19,78.7 154.93,78.96 154.59,79.3 152.11,79.3 151.3,80.1 151.3,81.68 v2(151.53,81.9)
  IN2 w0.114: 159.44,75.5 161.37,75.5 161.88,74.99 167.75,74.99 170.52,72.21 170.52,70.54 175.57,65.49 175.57,62.03 176.49,61.12 176.49,53.14 177.86,51.77 177.86,48.8 176.24,47.17 176.24,21.7 176.01,21.47 175.1,21.47 174.01,20.38 156.8,20.38 156.17,21.01 153.35,21.01 152.49,21.87 143.12,21.87 142.84,22.15 141.61,22.15 141.43,21.98 128.48,21.98 127.64,21.13 122.44,21.13 122.37,21.06 116.81,21.06 115.97,21.89 110.42,21.89 103.62,28.7 101.59,28.7 94.32,35.97 87.97,35.97 85.45,38.49 78.87,38.49 74.46,34.07 58.1,34.07 56.18,32.14 52.28,32.14 50.37,34.06 50.37,40.5 46.5,44.37 46.5,49.24 46.12,49.62 46.12,50.86 45.27,51.71 44.16,51.71 44.02,51.85 43.64,51.85 43.51,51.71 43.22,51.71 43.08,51.85 42.7,51.85 42.57,51.71 42.23,51.71 42.09,51.85 41.71,51.85 41.58,51.71 41.21,51.71 41.08,51.85 40.67,51.85 40.54,51.71 40.14,51.71 40.01,51.85 39.63,51.85 39.5,51.71 39.13,51.71 39,51.85 38.61,51.85 38.48,51.71 38.16,51.71 38.02,51.85 37.65,51.85 37.52,51.71 37.17,51.71 37.04,51.85 36.68,51.85 36.55,51.71 36.21,51.71 36.07,51.85 35.69,51.85 35.56,51.71 35.24,51.71 35.11,51.85 34.7,51.85 34.57,51.71 34.28,51.71 34.14,51.85 33.75,51.85 33.62,51.71 32.73,51.71 32.01,52.43 32.01,55.25 33.17,56.41 33.17,57.31 32.83,57.66 32.58,57.66 v2(32.35,57.88)
  BOTTOM w0.076: UC1.AR8 151.76,82.33 151.53,82.1 v2(151.53,81.9)
  BOTTOM w0.112: v2(32.35,57.88) 32.17,57.7 31.54,57.7 31.29,57.95 LI7.1
USB20_JUSB3_N2_R: length 3.9
  BOTTOM w0.112: JIO.15 26.24,57.95 26.56,57.62 v3(27.9,57.62) 28.42,57.62 28.74,57.95 LI7.2
USB20_JUSB3_P2: length 260.5
  IN2 w0.076: v2(151.44,82.66) 151.92,82.17 151.92,81.74 151.51,81.33 151.51,80.13 152.17,79.47 154.66,79.47 155.1,79.03 157.62,76.51 158.43,76.51 159.19,75.75 159.44,75.75
  IN2 w0.114: 159.44,75.75 161.47,75.75 161.98,75.24 167.85,75.24 170.77,72.32 170.77,70.64 175.82,65.59 175.82,62.13 176.73,61.22 176.73,53.25 178.11,51.87 178.11,48.7 176.49,47.07 176.49,21.59 176.11,21.22 175.2,21.22 174.11,20.13 156.7,20.13 156.06,20.76 153.24,20.76 152.38,21.62 143.02,21.62 142.74,21.9 141.71,21.9 141.54,21.73 128.59,21.73 127.74,20.88 122.54,20.88 122.48,20.81 116.7,20.81 115.87,21.65 110.32,21.65 103.51,28.45 101.48,28.45 94.21,35.72 87.86,35.72 85.35,38.24 78.98,38.24 74.56,33.82 58.21,33.82 56.28,31.89 52.18,31.89 50.12,33.96 50.12,40.4 46.25,44.27 46.25,49.14 45.87,49.52 45.87,50.76 45.17,51.46 35.14,51.46 35.01,51.6 34.81,51.6 34.67,51.46 34.17,51.46 34.04,51.6 33.86,51.6 33.72,51.46 32.62,51.46 31.76,52.33 31.76,55.35 32.92,56.52 32.92,57.21 32.72,57.41 32.52,57.41 v2(32.35,57.24)
  BOTTOM w0.076: UC1.AP8 151.76,82.98 151.44,82.67 v2(151.44,82.66)
  BOTTOM w0.112: v2(32.35,57.24) 32.15,57.44 31.5,57.44 31.2,57.15 LI7.4
USB20_JUSB3_P2_R: length 3.9
  BOTTOM w0.112: LI7.3 28.68,57.15 28.46,57.37 26.57,57.37 26.15,56.95 JIO.14
USB20_MINI1_N4: length 52.9
  IN2 w0.076: v2(147.5,84.24) 147.5,84.43 147.64,84.56 147.75,84.56 147.9,84.41 147.9,82.66 149.92,80.64 149.92,79.83 150.36,79.39 150.86,79.39 152.28,77.98 152.28,77.48 152.27,77.47 152.27,77.32 152.31,77.29 152.31,77.26 152.31,77.25
  IN2 w0.114: v2(174.32,56.58) 174.32,56.32 174.44,56.2 174.71,56.2 174.94,56.42 174.94,57.76 174.03,58.68 172.71,58.68 170.45,60.95 170.45,61.67 169.23,62.89 169.23,68.58 168.84,68.97 168.84,71.35 166.99,73.21 162.01,73.21 160.75,71.95 159.34,71.95 158.7,72.58 158.53,72.58 158.26,72.86 158.26,73.1 157.97,73.39 157.97,73.39 157.72,73.39 157.45,73.67 157.45,73.91 156.94,74.42 156.42,74.42 155.88,74.96 155.63,74.96 155.38,75.21 155.38,75.46 155.12,75.71 154.93,75.71 154.67,75.98 154.67,76.17 154.1,76.74 152.83,76.74 152.31,77.25
  BOTTOM w0.076: v2(147.5,84.24) 147.63,84.24 147.67,84.28 UC1.AM15
  BOTTOM w0.112: v2(174.32,56.58) 174.32,56.43 174.15,56.26 174,56.26 174,56.26 173.76,56.26 173.35,56.67 173.35,56.98 173.48,57.1 JNGFF.5
USB20_MINI1_P4: length 53
  IN2 w0.076: 152.46,77.4 152.44,77.41 152.44,78.05 150.93,79.56 150.42,79.56 150.08,79.9 150.08,80.71 148.06,82.73 148.06,84.48 147.81,84.73 147.67,84.73 v2(147.5,84.89)
  IN2 w0.114: 152.46,77.4 152.91,76.94 154.18,76.94 156.5,74.62 157.02,74.62 157.39,74.26 157.39,74.26 157.53,74.11 158.4,73.25 159.45,72.2 160.65,72.2 161.9,73.46 167.09,73.46 169.09,71.46 169.09,69.07 169.47,68.69 169.47,63 170.69,61.78 170.69,61.05 172.82,58.93 174.13,58.93 175.19,57.87 175.19,56.32 174.82,55.95 174.47,55.95 v2(174.32,55.8)
  BOTTOM w0.076: UC1.AL15 147.95,84.88 147.51,84.88 v2(147.5,84.89)
  BOTTOM w0.112: JNGFF.3 172.98,57.12 173.1,56.99 173.1,56.56 173.65,56 174.11,56 174.31,55.8 v2(174.32,55.8)
USB20_TOUCH_N5: length 186.5
  TOP w0.112: DX2.3 5.49,92.58 5.38,92.69 4.79,92.69 4.66,92.56 4.14,92.56 3.76,92.94 3.76,93.15 v2(3.57,93.35)
  IN2 w0.076: v2(148.98,84.9) 149.17,84.71 149.74,84.71 149.92,84.9 149.92,86.31 149.59,86.64 149.59,87.1 149.54,87.15 149.51,87.15 149.49,87.18
  IN2 w0.114: v2(3.57,93.35) 3.82,93.35 3.95,93.22 3.95,92.81 4.24,92.52 7.3,92.52 11.87,97.09 14.38,97.09 18.32,101.02 22.66,101.02 25.84,104.2 29.01,104.2 32.06,107.24 33.71,107.24 34.6,108.13 38.41,108.13 38.92,107.62 40.82,107.62 41.71,106.74 49.84,106.74 52.38,109.28 53.14,109.28 53.9,110.04 57.33,110.04 59.11,108.26 63.84,108.26 64.79,107.31 65.93,107.31 66.95,106.29 66.95,105.15 69.69,102.42 80.98,102.42 83.65,99.76 89.09,99.76 91.88,102.54 95.41,102.54 96.33,101.63 98.07,101.63 98.42,101.27 124.9,101.27 126.29,99.88 128.45,99.88 129.72,101.15 130.2,101.15 133.23,104.17 135.57,104.17 137.56,102.19 140.63,102.19 141.41,101.41 141.41,99.27 142.04,98.63 142.04,97.72 141.66,97.34 141.66,96.19 142.3,95.56 142.93,95.56 143.06,95.43 143.06,95.08 144.46,93.68 144.46,90.36 145.14,89.68 146.3,89.68 148.67,87.31 149.36,87.31 149.49,87.18
  BOTTOM w0.076: v2(148.98,84.9) 148.98,84.89 148.69,84.61 UC1.AM13
  BOTTOM w0.112: JEDP.13 2.41,93 2.66,92.76 3.65,92.76 3.94,93.05 3.94,93.27 3.87,93.35 v2(3.57,93.35)
USB20_TOUCH_P5: length 186.7
  TOP w0.112: DX2.2 5.49,93.06 5.38,92.94 4.68,92.94 4.55,92.82 4.24,92.82 4.02,93.04 4.02,93.22 4.15,93.35 v2(4.35,93.35)
  IN2 w0.076: 149.78,87.22 149.75,87.19 149.75,86.71 150.09,86.38 150.09,84.83 149.8,84.55 149.27,84.55 v2(149,84.28)
  IN2 w0.114: v2(4.35,93.35) 4.2,93.2 4.2,92.91 4.35,92.77 7.2,92.77 11.77,97.34 14.28,97.34 18.21,101.27 22.56,101.27 25.73,104.44 28.91,104.44 31.96,107.49 33.6,107.49 34.49,108.38 38.51,108.38 39.02,107.87 40.93,107.87 41.82,106.98 49.74,106.98 52.28,109.52 53.04,109.52 53.8,110.29 57.44,110.29 59.21,108.51 63.95,108.51 64.9,107.56 66.03,107.56 67.2,106.39 67.2,105.26 69.79,102.67 81.09,102.67 83.75,100 88.99,100 91.77,102.79 95.52,102.79 96.43,101.88 98.17,101.88 98.53,101.52 125,101.52 126.4,100.13 128.35,100.13 129.62,101.4 130.1,101.4 133.13,104.42 135.68,104.42 137.66,102.44 140.73,102.44 141.66,101.51 141.66,99.37 142.29,98.74 142.29,97.61 141.91,97.23 141.91,96.3 142.4,95.81 143.04,95.81 143.31,95.54 143.31,95.18 144.71,93.78 144.71,90.46 145.24,89.93 146.4,89.93 148.77,87.56 149.46,87.56 149.78,87.24 149.78,87.22
  BOTTOM w0.076: v2(149,84.28) 148.84,84.28 148.56,84.01 UC1.AN13
  BOTTOM w0.112: v2(4.35,93.35) 4.2,93.2 4.2,92.94 3.76,92.5 JEDP.14
USB_EN#: length 407.1
  TOP w0.102: UI6.4 192.24,45.14 192.54,45.43 192.54,48.09 UI5.4 191.81,51.76 191.4,52.17 UI3.4 189.71,52.17 189.16,51.62 CI13.1 186.45,49.72 186.45,43.32 185.35,42.22 185.35,38.54 ; 185.35,38.54 185.48,38.54 186.11,37.9 187.89,37.9 188.22,38.23 CI26.1 188.52,38.7 UI2.4 ; 185.35,38.54 184.02,37.2 180.87,37.2 177.86,34.19 177.86,30.84 173.91,26.9 v2(172.85,26.9) ; v2(137.03,12.18) 136.87,12.03 136.57,12.03 134.25,9.71 133.76,9.71 v2(132.52,8.46) 132.52,8.31 131.92,7.71 UE1.26 ; v2(28.5,39.7) 28.97,39.7 v1(29.44,39.23) CI46.1 29,38.08 28.53,38.55 UI4.4 ; v2(24.01,39.67) 23.02,39.67 22.79,39.44 UI7.4
  IN1 w0.107: v2(137.03,12.18) 137.18,12.03 142.65,12.03 143.48,11.21 144.85,11.21 145.43,11.79 148.42,11.79 149.27,10.94 152.04,10.94 152.41,11.31 155.06,11.31 155.59,10.77 156.41,10.77 158.49,8.69 161.35,8.69 163,10.34 164.39,10.34 165.33,11.28 165.33,15.07 169.55,19.29 169.55,23.25 171.02,24.72 171.02,25.07 v2(172.85,26.9) ; v2(28.5,39.7) 28.21,39.41 24.26,39.41 v2(24.01,39.67) 24.01,39.92 18.47,45.46 18.47,48.44 17.46,49.46 10.98,49.46 8.46,51.97 8.46,57.25 7.52,58.19 7.52,64.57 7.78,64.83 9.2,64.83 10.72,66.35 10.72,70.41 9.84,71.3 9.84,73.72 6.79,76.76 6.79,78.92 7.68,79.81 7.68,82.1 8.18,82.61 8.87,82.61 9.96,83.7 9.96,85.53 8.82,86.67 8.82,91.5 9.71,92.38 9.71,96.96 11.36,98.61 13.26,98.61 18.41,103.75 29.33,103.75 34.22,108.64 34.22,110.42 36,112.2 39.3,112.2 41.2,110.29 48.32,110.29 49.1,111.08 54.84,111.08 60.19,105.73 61.89,105.73 65.37,102.25 78.41,102.25 85.18,95.48 85.88,95.48 86.67,94.69 86.67,91.5 86.92,91.24 86.92,87.17 87.94,86.16 87.94,79.05 88.12,78.87 88.12,68.69 86.67,67.24 86.67,64.83 87.69,63.81 87.69,62.44 88.58,61.55 88.58,50.98 87.18,49.59 87.18,40.06 88.96,38.28 88.96,37.2 89.36,36.8 90.42,36.8 95.57,31.66 96.29,31.66 101.33,26.62 102.6,26.62 103.36,25.86 103.88,25.86 106.25,23.48 106.25,15.4 110.47,11.18 110.93,11.18 111.24,10.86 112.68,10.86 113.22,10.33 116.58,10.33 116.73,10.18 127.77,10.18 128.47,9.48 131.5,9.48 v2(132.52,8.46)
USB_OC0#: length 99.7
  TOP w0.102: UI2.5 196.32,38.7 196.41,38.61 CI17.1 v1(197.88,38.61) 198.84,38.61 199.45,39.22 199.45,42.12 198.05,43.51 198.05,44.43 197.34,45.14 UI6.3 193.79,45.14 193.53,45.39 193.53,48.14 UI5.3 194.21,52.08 194.29,52.17 UI3.5 194.99,51.6 194.74,51.35 CI15.1 194.74,50.21 v2(195.03,49.92) ; v2(161.12,77.3) 161.12,77.05 161.46,76.71 RP55.1
  TOP w0.107: v2(159.44,84.13) 159.92,83.65 159.92,79.07 160.71,78.29 160.71,78.16 161.12,77.75 v2(161.12,77.3)
  IN1 w0.107: v2(164.01,63.68) 164.01,64.7 161.44,67.27 161.44,72.1 161.69,72.35 161.69,76.73 v2(161.12,77.3)
  IN2 w0.107: v2(190.58,62.31) 191.62,61.27 191.62,60.94 191.83,60.74 191.83,60.13 195.03,56.93 v2(195.03,49.92)
  BOTTOM w0.076: UC1.AL3 155.09,84.78 155.6,84.78 155.77,84.96 155.77,85.11 156.03,85.36 157.16,85.36 157.58,84.94 158.63,84.94 v2(159.44,84.13)
  BOTTOM w0.102: v2(164.01,63.68) 164.98,63.68 165.66,63 167.87,63 169.22,61.65 177.25,61.65 178.59,63 178.59,63.86 179.21,64.47 179.99,64.47 180.04,64.42 188.47,64.42 v2(190.58,62.31)
USB_OC1#: length 249.6
  TOP w0.076: v2(160.08,78.04) 160.09,78.03 160.2,78.03 160.71,77.53 160.71,76.64 160.96,76.39 RP55.2
  TOP w0.102: UI7.3 22.79,40.95 23.04,40.7 25.33,40.7 26.4,41.76 27.9,41.76 28.21,42.08 UI4.5 28.21,44.77 CI47.1 ; v2(29.14,52.25) 29.14,58.89 v2(29,59.03) ; v1(29.52,44.63) 29.34,44.81 CI47.1 ; CI47.1 27.65,44.81 v2(27.59,44.87)
  IN1 w0.107: v2(120.91,25.02) 120.91,25.25 119.31,26.85 119.31,33.08 121.47,35.23 149.54,35.23 153.29,38.99 154.14,38.99 155.21,40.06 159.57,40.06 160.33,40.82 160.33,46.54 163.14,49.34 163.14,65.2 161.17,67.16 161.17,72.19 161.44,72.46 161.44,76.26 160.58,77.11 160.58,77.53 v2(160.08,78.04)
  IN2 w0.107: v2(120.91,25.02) 119.44,26.5 108.53,26.5 105.11,29.92 105.11,31.2 97.82,38.49 88.25,38.49 84.22,42.53 80.63,42.53 73.41,35.31 59.27,35.31 59.02,35.56 52.57,35.56 51.61,36.51 51.61,41.74 47.77,45.58 47.77,49.88 47.37,50.27 47.37,51.45 44.69,54.13 35.06,54.13 33.97,55.22 33.97,57.46 32.1,59.33 29.3,59.33 v2(29,59.03)
  BOTTOM w0.076: v2(160.08,78.04) 159.82,78.3 159.82,81.21 159.44,81.59 156.82,81.59 156.37,82.04 UC1.AT1
  BOTTOM w0.102: v2(27.59,44.87) 28.14,45.42 28.14,45.74 28.5,46.11 28.5,49.13 29.14,49.76 v2(29.14,52.25)
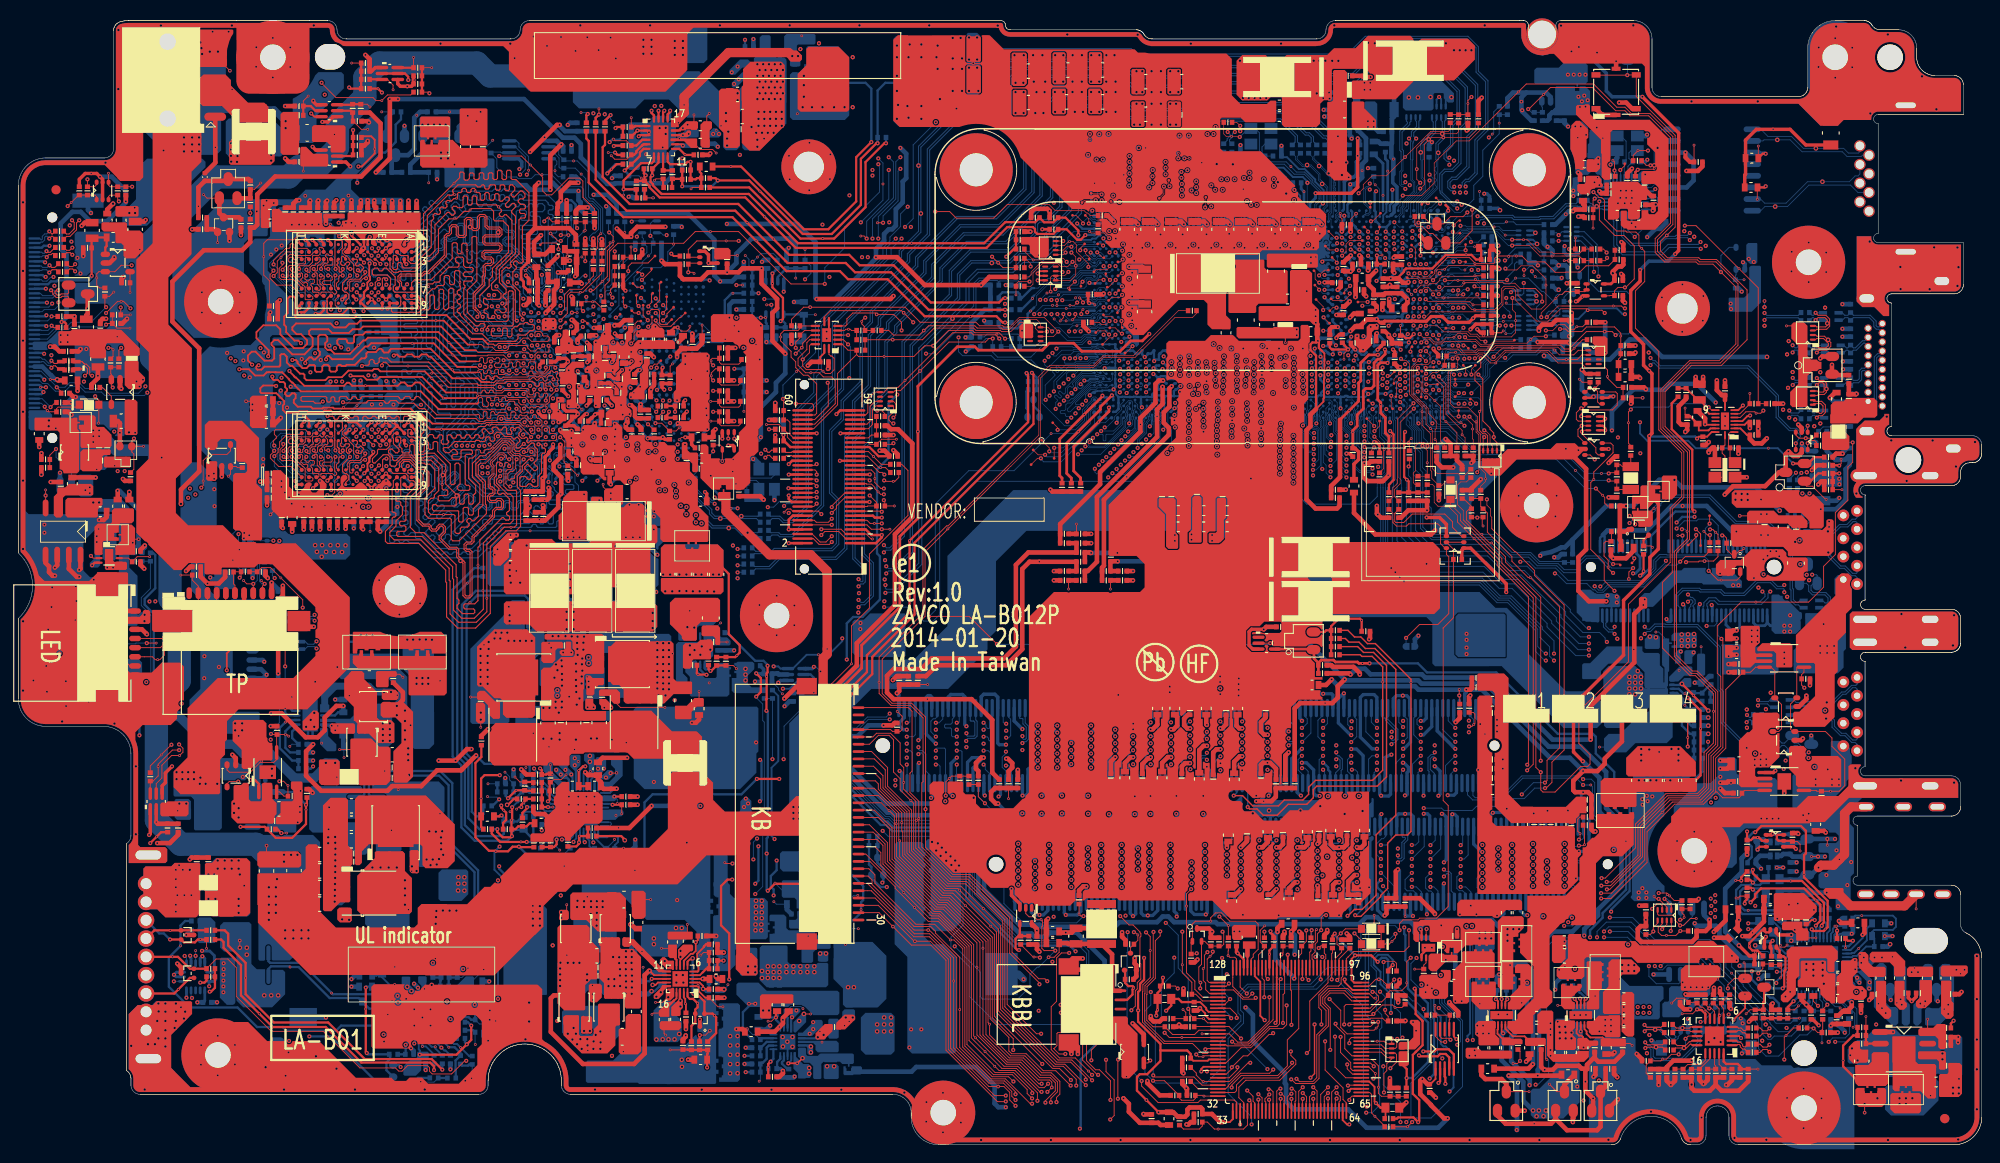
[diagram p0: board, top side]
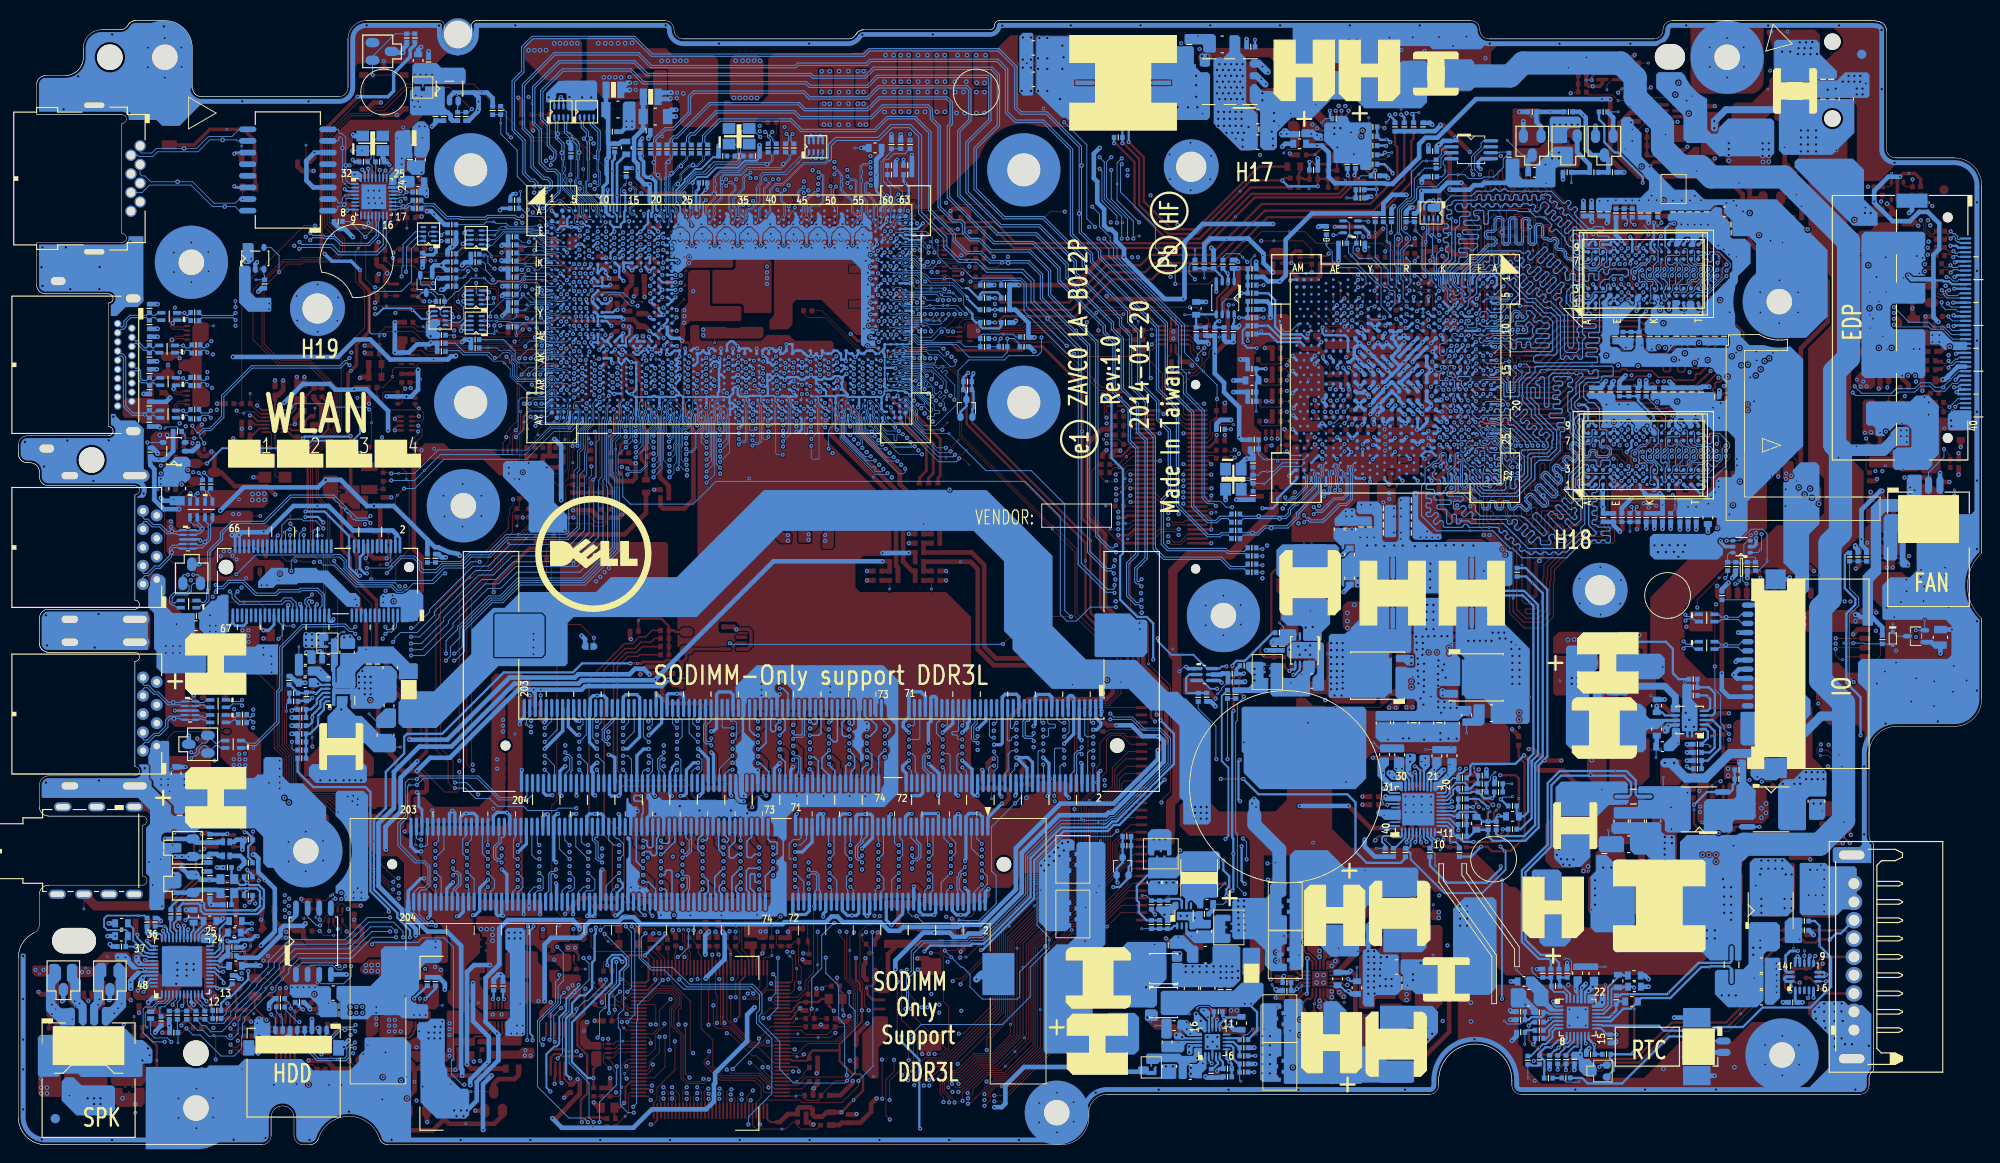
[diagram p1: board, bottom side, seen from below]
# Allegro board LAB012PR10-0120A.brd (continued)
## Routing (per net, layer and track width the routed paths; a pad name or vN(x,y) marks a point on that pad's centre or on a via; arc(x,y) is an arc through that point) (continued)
USB_OC2#: length 16.2
  TOP w0.107: v2(159.7,85.91) 159.7,84.94 159.06,84.31 159.06,83.49 159.7,82.86 159.7,80.23 v1(159.56,80.09) 159.56,78.04 159.92,77.67 160.23,77.67 160.45,77.45 160.45,75.83 RP55.3
  BOTTOM w0.076: v2(159.7,85.91) 158.7,86.9 156.46,86.9 156.33,87.03 155.95,87.03 155.88,86.96 155.74,86.96 155.49,86.72 UC1.AH2
USB_OC3#: length 9
  TOP w0.102: v2(160.08,77.3) 160.08,77.28 159.96,77.17 RP55.4
  BOTTOM w0.076: UC1.AV3 154.94,80.73 155.28,80.39 156.36,80.39 156.68,80.07 158.68,80.07 159.19,79.56 v1(159.19,78.97) 159.19,78.19 v2(160.08,77.3)
USBRBIAS: length 12.7
  TOP w0.305: RC90.1 149.66,77.37 149.28,77.75 149.28,79.43 148.77,79.94 v1(148.77,80.85) 148.77,81.08 148.44,81.41 148.44,85.15 148.72,85.42 149.49,85.42 v2(149.51,85.4)
  BOTTOM w0.305: UC1.AJ10 UC1.AJ11 149.64,85.87 149.64,85.53 v2(149.51,85.4)
VCIN0_PH: length 161.2
  TOP w0.076: 108.13,73.89 108.36,74.12 108.39,74.12 111.63,77.35 111.63,83.76 112.76,84.89 117.4,84.89 118.52,86.01 121.95,86.01 126.29,90.35 128.2,90.35 128.66,90.81 PH1.1
  TOP w0.102: v2(140.22,18.09) UE1.109 ; v2(112.36,17.87) 112.1,18.12 111.43,18.12 108.51,21.03 108.51,24.95 103.94,29.52 102.04,29.52 99.07,32.49 v2(99.07,36.66) 99.07,46.71 97.55,48.23 95.4,48.23 94.34,49.28 94.34,53.05 99.02,57.73 99.02,64.77 101.4,67.16 101.4,67.17 v1(101.5,67.28) 101.52,67.28 108.13,73.89
  IN2 w0.107: v2(140.22,18.09) 139.86,17.73 138.9,17.73 137.65,18.98 136.45,18.98 135.82,18.34 132.6,18.34 132.29,18.03 126.69,18.03 126.51,17.86 124.61,17.86 124.29,18.17 123.03,18.17 122.8,17.94 120.18,17.94 119.56,17.31 117.75,17.31 117.01,18.05 112.55,18.05 v2(112.36,17.87) ; v2(99.07,36.66) 97.47,38.26 88.16,38.26 84.71,41.7 82.77,41.7 v2(82.35,42.12)
  BOTTOM w0.102: v2(82.35,42.12) PR24.1 PR25.1
VCIN0_PH2: length 210.1
  TOP w0.102: RE7.1 v1(151.69,1.96) v2(152.2,2.47)
  IN2 w0.107: v2(13.97,50.54) 13.97,49.84 14.8,49.01 27.35,49.01 28.06,48.3 28.06,42.23 29.97,40.32 47.04,40.32 47.97,39.39 47.97,32.66 52.7,27.93 55.21,27.93 58.16,30.88 76.31,30.88 77.45,32.02 78.95,32.02 79.8,31.17 v2(80.27,31.17) ; v2(80.67,33.45) 81.71,34.48 92.79,34.48 99.85,27.43 101.97,27.43 110.77,18.63 117.71,18.63 117.79,18.54 119.69,18.54 119.89,18.75 124.61,18.75 124.73,18.63 125.19,18.63 125.58,18.24 132.18,18.24 132.54,18.6 135.69,18.6 136.38,19.28 149.14,19.28 149.91,20.05 150.68,20.05 151.44,19.29 152.4,19.29 152.4,19.28 154.59,19.28 v2(155.33,18.54)
  BOTTOM w0.102: v2(155.33,18.54) 155.33,18.19 155.73,17.78 155.73,15.53 157.7,13.56 157.7,6.34 154.28,2.92 152.65,2.92 v2(152.2,2.47) ; v2(13.97,50.54) 14.47,51.03 14.47,57.86 13.43,58.9 13.43,59.77 14.42,60.76 RE333.1 HE1.1 RE332.1 ; v2(80.27,31.17) 80.27,33.05 v2(80.67,33.45)
VCIN1_PH: length 194.9
  TOP w0.102: PR27.2 v1(45.14,117.66) ; v2(44.89,114.86) 44.76,114.99 PR23.1 ; v2(140.71,10.01) 141.03,10.33 141.03,15.7 143.02,17.7 UE1.102
  TOP w0.254: PR27.2 PC13.2 PR26.2 PR23.1
  IN1 w0.107: v2(140.71,10.01) 140.45,9.75 136.98,9.75 135.54,8.31 133.8,8.31 133.51,8.59 133.51,8.62 133.29,8.85 133.26,8.85 132.07,10.03 129.46,10.03 128.81,10.69 116.88,10.69 116.77,10.8 113.41,10.8 112.88,11.33 111.44,11.33 111.12,11.64 110.67,11.64 106.72,15.59 106.72,23.68 104.07,26.32 103.56,26.32 102.79,27.09 101.53,27.09 96.26,32.36 95.6,32.36 87.69,40.28 87.69,49.33 89.08,50.73 89.08,61.78 88.19,62.67 88.19,66.48 89.25,67.53 89.25,69.99 88.63,70.62 88.63,82.4 89.08,82.86 89.08,85.78 87.43,87.43 87.43,91.11 87.94,91.62 87.94,92.77 87.16,93.55 87.16,95.05 86.25,95.95 85.37,95.95 78.58,102.75 65.58,102.75 62.12,106.21 60.37,106.21 51.72,114.86 v2(44.89,114.86)
VCIN2_PH: length 203.2
  TOP w0.102: UE1.64 145.02,4.57 144.66,4.93 144.66,6.2 142.7,8.16 v2(142.7,11.29) ; 37.45,118.17 v1(36.4,118.17)
  TOP w0.254: 37.45,118.17 PC17.2 PR36.2 PR35.1 36.25,115.37 v2(36.12,115.5)
  IN1 w0.107: v2(36.12,115.5) 37.35,116.72 51.37,116.72 58.41,109.68 59.46,109.68 60,109.14 60,109.03 61.78,107.25 62.55,107.25 64.78,105.02 66.76,105.02 67.99,103.78 80.94,103.78 89.59,95.13 89.59,91.5 92,89.08 92,83.88 90.73,82.61 90.73,66.76 90.44,66.46 90.44,56.12 91.55,55.01 91.55,45.62 90.96,45.03 90.96,41.84 92.55,40.25 92.55,38.5 94.58,36.47 95.29,36.47 98.02,33.74 98.02,33.27 102.13,29.16 104.05,29.16 108.62,24.59 108.62,16.57 111.1,14.09 112.79,14.09 113.1,13.77 116.47,13.77 116.66,13.96 120.73,13.96 120.94,13.76 122.53,13.76 122.94,13.35 124.3,13.35 124.42,13.47 125.88,13.47 126.01,13.59 130.64,13.59 131.8,12.43 134.36,12.43 135.05,11.74 142.26,11.74 v2(142.7,11.29)
VCOMP: length 5.1
  BOTTOM w0.203: PC727.2 49.23,9.68 v1(48.3,10.62) 47.91,11 47.57,11 46.87,11.7 46.87,12.37 46.55,12.7 PU701.7
VCOUT0_PH#: length 99.2
  TOP w0.102: v1(71.18,10.36) 72.5,10.36 PR110.1 ; v2(142.22,18.06) 142.22,18.54 142.22,18.54 UE1.104
  TOP w0.254: PR110.1 73.08,10.39 73.12,10.36 PR101.2 PR102.2 PR100.2 75.28,9.95 75.22,9.89 PC100.1 v2(75.22,8.44)
  IN2 w0.107: v2(75.22,8.44) 75.24,8.44 76.79,6.89 95.56,6.89 97.24,8.56 103.21,8.56 104.99,6.78 104.99,3.19 106.86,1.32 118.09,1.32 118.22,1.2 124.75,1.2 125.11,1.56 134.02,1.56 v2(134.68,2.21)
  BOTTOM w0.102: v2(142.22,18.06) 141.4,17.24 134.32,17.24 133.47,16.39 133.47,14.69 133.79,14.38 133.79,13.26 132.11,11.58 132.11,5.59 134.68,3.03 v2(134.68,2.21)
VCOUT1_PH: length 98.8
  TOP w0.102: v2(142,21.48) 142.26,21.73 RE47.2 142.61,20.92 142.78,20.75 142.78,20.35 142.62,20.19 UE1.103 ; UE2.2 110.01,25.25 110.37,24.9 110.95,24.9 111.23,24.62 v1(111.69,24.62) 111.83,24.48 111.83,23.88 111.77,23.81 111.77,21.45 112.02,21.2 v2(113.24,21.2)
  IN1 w0.107: v2(102.25,21.67) 101.96,21.67 100.96,22.67 99.33,22.67 91.04,30.97 86.29,30.97 82.98,34.28 82.98,37.86 83.81,38.7 83.81,41.88 v2(83.57,42.12) ; v2(142,21.48) 141.45,21.48 141.27,21.3 137.67,21.3 137.47,21.1 136.42,21.1 135.33,20.02 130.46,20.02 130.26,19.82 124.75,19.82 123.73,20.83 120.55,20.83 119.84,21.54 113.58,21.54 v2(113.24,21.2)
  BOTTOM w0.102: v2(83.57,42.12) 83.62,42.17 83.62,45.72 85.55,47.65 PR30.1 ; v2(102.25,21.67) 105.05,18.88 105.05,16.16 105.3,15.9 109.12,15.9 110.47,17.25 110.47,18.61 111.26,19.4 111.44,19.4 v2(113.24,21.2)
VFB: length 6.9
  BOTTOM w0.203: 47.02,10.65 46.26,11.41 45.43,11.41 45.33,11.52 PU701.8
  BOTTOM w0.254: PC701.2 47.77,8.16 47.75,8.18 47.75,9.2 PR726.1 48.28,10.01 47.64,10.65 v1(47.01,10.65)
VGA_AC__BATT: length 15.1
  TOP w0.102: QV8.3 73.27,96.31 RV148.2 v2(73.16,95.31) 73.67,95.31 v1(73.79,95.18)
  IN2 w0.102: v2(63.91,90.21) 64.18,90.48 64.7,90.48 65.84,91.62 65.84,91.88 66.99,93.02 70.87,93.02 v2(73.16,95.31)
  BOTTOM w0.102: v2(63.91,90.21) UV1.T9
VGA_DMINUS: length 18.5
  BOTTOM w0.102: UV1.T2 63.72,94.22 63.72,98.28 63.3,98.7 63.3,99.24 63.58,99.52 63.58,102.21 62.76,103.03 62.72,103.03 62.67,103.08 62.36,103.08 61.96,103.48 61.96,105.54 v1(61.46,106.04) 60.81,106.68 CV9.2 59.16,106.68 59.05,106.8 59.05,107.79 58.47,108.37 UV3.3
VGA_DPLUS: length 19.9
  BOTTOM w0.102: UV3.2 58.61,109.02 59.01,108.61 59.01,108.16 CV9.1 59.7,107.47 v1(60.64,107.47) 61.04,107.47 62.26,106.25 62.26,103.56 62.48,103.34 62.76,103.34 62.85,103.26 62.86,103.26 63.81,102.3 63.81,99.62 64.14,99.29 64.14,96.13 63.94,95.93 63.94,93.7 63.6,93.36 UV1.T4
VGA_SMB_CK3: length 38.5
  IN1 w0.107: v2(67.54,99.19) 67.77,99.19 68.36,99.78 69.35,99.78 69.67,99.46 69.67,98.85 69.3,98.48 64.74,98.48 63.57,99.65 62.79,99.65 61.2,101.25 59.84,101.25 55.53,105.56 v2(55.53,105.97)
  BOTTOM w0.102: UV1.U7 64.06,91.83 64.06,93.12 64.27,93.33 64.62,93.33 64.95,93.65 65.21,93.65 65.59,94.04 65.59,95.81 66.6,96.83 68,96.83 68.64,97.46 68.64,98.12 RV6.2 68.26,98.51 68.26,98.99 68.13,99.12 QV1.1 67.8,99.62 67.54,99.37 v2(67.54,99.19) ; v2(55.53,105.97) 55.72,106.16 v1(55.72,106.46) 55.72,107.94 54.67,109 54.67,109.4 54.4,109.67 UV3.8
VGA_SMB_DA3: length 36
  IN1 w0.107: v2(54.79,105.97) 55.22,106.39 56.09,106.39 57.26,105.23 57.26,104.16 59.7,101.71 61.06,101.71 61.97,100.81 62.82,100.81 63.58,100.05 63.58,100.02 64.87,98.73 68.46,98.73 v2(69.02,99.29)
  BOTTOM w0.102: v2(54.79,105.97) 55.37,106.54 55.37,107.92 54.27,109.02 UV3.7 ; QV1.4 69.3,100.92 69.02,100.64 v2(69.02,99.29) 69.32,98.99 RV5.2 69.14,98.3 69.14,97.44 v1(68.8,97.1) 68.13,96.42 68.13,96.14 66.15,94.16 66.03,94.16 65.59,93.72 65.59,91.67 64.6,90.68 UV1.U8
VL: length 4.2
  TOP w0.203: PU100.13 v2(69.17,18.11)
  BOTTOM w0.102: v1(68.23,19.38) PC106.1
  BOTTOM w0.254: PC106.1 68.92,17.86 v2(69.17,18.11)
VR12.5_VR_ON_R: length 3.1
  TOP w0.076: v1(116.97,99.78) 117.15,99.6 R250.2 118.55,99.6 v2(119.13,99.02)
  BOTTOM w0.076: v2(119.13,99.02) 119.13,99.01 119.46,98.68 UC1.F60
VR_HOT#: length 126.5
  TOP w0.102: v2(111.56,20.44) 111.5,20.5 v1(110.92,20.5) 110.83,20.5 RE44.1
  TOP w0.254: v2(65.03,109.1) 65.08,109.15 PR510.1
  IN1 w0.107: v2(111.56,20.44) 110.81,21.19 110.81,24.16 110.33,24.65 110.33,26.1 109.21,27.21 109.21,27.78 107.88,29.11 107.88,31.17 104.15,34.9 98.98,34.9 98.97,34.91 98.91,34.91 95.91,37.9 95.15,37.9 94.1,38.95 94.1,39.14 94.1,40.72 92.36,42.46 92.36,44.45 93.02,45.11 93.02,68.51 92.26,69.27 92.26,81.84 93.53,83.11 93.53,90.73 91.12,93.15 91.12,95.91 87.81,99.22 v2(87.81,100.51)
  IN2 w0.107: v2(65.03,109.1) 65.35,109.1 68.1,106.35 68.1,105.73 70.65,103.18 81.34,103.18 84,100.51 v2(87.81,100.51)
  BOTTOM w0.254: v2(65.03,109.1) 65.08,109.15 PR510.1
VR_HOT#_1: length 4.2
  TOP w0.102: v1(64.98,109.86) 65.16,109.68 66.4,109.68 PR510.2
  TOP w0.254: PR510.2 67.49,109.15 68.13,109.79 PU501.4
VR_ON: length 196.9
  TOP w0.076: R250.1 C80.1 117.05,101.5 116.77,101.78 116.64,101.78 116.39,102.04 113.24,102.04 112.55,102.72 108.13,102.72
  TOP w0.102: v2(100.13,101.94) 101.71,101.94 102.42,101.22 106.51,101.22 108.01,102.72 108.13,102.72 ; v2(129.06,17.07) 129.09,17.1 v4(129.09,17.71) 128.91,17.89 128.91,19.41 129.21,19.71 DE1.3 129.56,22.22 130.08,21.7 CE34.1 RE1.2 131.43,21.7 131.63,21.9 131.63,23.14 v2(131.5,23.27) ; RE12.2 v2(136.07,23.27)
  TOP w0.254: PR519.1 PR511.1 65.34,111.18 v2(65.22,111.06)
  IN1 w0.107: v2(131.5,23.27) 131.89,22.89 135.72,22.89 136.07,23.25 v2(136.07,23.27) ; v2(129.06,17.07) 128.67,16.68 124.28,16.68 123.85,17.11 122.95,17.11 122.73,16.88 114.36,16.88 111.99,19.26 111.99,23.37 110.56,24.79 110.56,26.23 109.8,26.99 109.8,33.02 107.68,35.14 99.2,35.14 99.01,35.14 96.01,38.14 95.25,38.14 94.34,39.05 94.34,40.81 92.59,42.56 92.59,44.35 93.27,45.03 93.27,68.64 92.51,69.4 92.51,81.72 93.78,82.99 93.78,90.86 91.37,93.27 91.37,95.99 89.85,97.51 89.85,102.8 v2(90.76,103.71) 98.36,103.71 v2(100.13,101.94)
  IN2 w0.107: v2(65.22,111.06) 65.22,111.06 65.22,110.97 69.07,107.12 70.03,107.12 71.81,105.34 75.49,105.34 76.38,104.45 81.97,104.45 84.38,102.04 89.08,102.04 v2(90.76,103.71)
VR_ON_1: length 2.7
  TOP w0.102: PR511.2 v1(66.94,112.2)
  TOP w0.254: PU501.1 67.37,111.29 67.26,111.18 PR511.2
VR_ON_EC: length 5.2
  TOP w0.102: UE1.121 135.42,20.74 136.07,21.39 RE12.1 135.62,22.15 135.62,23.42 v1(136.1,23.91)
VR_READY_R: length 10.9
  BOTTOM w0.076: UC1.C59 120.11,100.86 120.11,101.1 119.95,101.26 119.95,101.41 119.74,101.61 119.74,101.83 119.74,101.83 119.74,102.21 119.18,102.76 119.18,104.5 v1(119.73,105.05) 119.94,105.26 119.94,107.37 119.69,107.62 119.44,107.62
  BOTTOM w0.102: R251.2 117.58,108.26 118.8,108.26 119.44,107.62
VR_SVID_ALRT#: length 57.3
  TOP w0.254: PR506.1 63.05,105.41 66.43,102.04 78.29,102.04 v1(79.58,100.74) 84,96.32 90.35,96.32 91.37,95.31 95.31,95.31 99.4,91.22 v2(107.75,91.22)
  BOTTOM w0.254: R254.2 v2(107.75,91.22) R252.2
VR_SVID_CLK: length 58.2
  TOP w0.254: v2(107.75,89.82) 107.5,89.82 106.81,90.5 98.96,90.5 94.93,94.54 90.61,94.54 89.72,95.43 83.88,95.43 v1(80.56,98.75) 77.98,101.32 66.07,101.32 62.29,105.11 62.29,109.66 62.03,109.91 PR508.1
  BOTTOM w0.254: R248.1 v2(107.75,89.82)
VR_SVID_DAT: length 55.6
  TOP w0.254: PR505.1 64.06,109.22 63.81,108.97 63.81,105.72 66.76,102.77 78.62,102.77 v1(82.45,98.94) 84.18,97.21 90.73,97.21 91.88,96.07 95.59,96.07 99.65,92 107.09,92 107.58,92.49 v2(107.75,92.49)
  BOTTOM w0.254: R257.2 v2(107.75,92.49)
VRAM_ODT0: length 59.4
  TOP w0.102: UV6.K1 35.75,78.24 35.42,77.91 35.42,77.59 35.72,77.29 35.84,77.29 36.12,77.01 36.12,76.88 36.62,76.39 36.62,75.54 v2(37.01,75.14) ; 49.97,81.56 50.22,81.82 53.27,81.82 53.46,81.63 55.35,81.63 55.67,81.31 55.67,81.18 55.94,80.9 57.74,80.9 57.99,81.15 57.99,81.67 v2(58.79,82.47)
  TOP w0.198: 49.97,81.56 v1(46.41,81.56) 44.1,83.87 39.5,83.87 39.2,83.57 38.05,83.57 37.67,83.95 36.35,83.95 v2(36.28,84.03)
  IN2 w0.107: v2(36.28,84.03) 36.73,84.03 36.86,83.9 37.6,83.9 38.11,83.39 39.2,83.39 39.71,83.9 41.13,83.9 41.55,83.48 41.55,83.23 41.26,82.94 37.5,82.94 37.37,82.81 37.37,82.61 37.24,82.48 36.89,82.48 36.76,82.61 36.76,82.91 36.63,83.04 36.35,83.04 36.23,82.91 36.23,82.45 35.52,81.74 35.41,81.74 34.98,81.31 34.98,80.95 35.44,80.5 35.44,79.35 35.43,79.34 35.43,79.02 35.44,79.02 35.44,77.93 36.44,76.93 36.44,76.29 36.61,76.13 36.61,74.6 36.73,74.48 37.39,74.48 37.45,74.53 37.45,75.06 37.37,75.14 v2(37.01,75.14)
  BOTTOM w0.102: UV1.L18 59.6,82.78 59.47,82.91 59.19,82.91 59.06,82.78 59.06,82.6 58.93,82.47 v2(58.79,82.47) ; UV5.K1 36.12,72.12 36.25,72.25 36.25,72.45 36.15,72.55 36.15,73.99 36.06,74.08 36,74.08 35.88,74.2 35.88,74.33 36.04,74.49 36.47,74.49 37.01,75.03 v2(37.01,75.14)
VRAM_ODT1: length 56.9
  TOP w0.102: UV7.K1 35.69,98.28 35.69,97.94 35.42,97.67 35.42,97.4 35.72,97.1 35.84,97.1 36.12,96.82 36.12,96.7 36.62,96.19 36.62,96.02 36.63,96.01 36.63,95.7 36.63,95.7 36.63,95.38 36.63,95.38 36.63,95.36 37.01,94.98 37.01,94.96 v2(37.01,94.96) ; v2(58.44,83.6) 58.44,83.88 58.28,84.03 57.93,84.03 57.75,83.85 57.75,83.56 57.62,83.43 57.46,83.43 57.33,83.56 57.33,83.67 57.2,83.79 56.99,83.79 56.86,83.67 56.86,83.64 56.73,83.52 56.58,83.52 56.45,83.64 56.45,83.67 56.33,83.79 56.12,83.79 55.95,83.62 53.12,83.62 52.94,83.44 52.13,83.44 51.95,83.27 51.48,83.27 51.43,83.32
  TOP w0.198: 51.43,83.32 50.57,83.32 50.17,83.72 47.4,83.72 45.04,86.08 44.83,86.08 44.58,86.34 44.04,86.34 43.78,86.08 43.25,86.08 42.99,86.34 42.45,86.34 42.2,86.08 41.61,86.08 41.38,86.31 41.1,86.31 v2(41,86.21)
  IN2 w0.107: v2(37.01,94.96) 37.01,94.96 37.01,94.89 36.84,94.72 36.84,94.7 36.48,94.34 36.5,94.36 36.05,93.91 36.05,93.88 36.02,93.85 36.02,93.64 36.13,93.53 36.15,93.53 36.25,93.43 36.25,93.21 36.15,93.11 36.13,93.11 36.02,93 36.02,92.79 36.13,92.68 36.15,92.68 36.25,92.57 36.25,92.36 36.15,92.25 36.13,92.25 36.02,92.15 36.02,91.88 36.13,91.78 36.42,91.78 36.53,91.67 36.53,91.46 36.42,91.35 36.13,91.35 36.02,91.24 36.02,91.09 36.54,90.57 36.69,90.57 36.79,90.67 36.95,90.67 37.1,90.52 37.1,90.37 36.99,90.27 36.99,90.12 37.14,89.97 37.3,89.97 37.37,90.04 37.55,90.04 37.67,89.92 37.67,89.74 37.6,89.67 37.6,89.51 38.31,88.8 38.31,88.26 38.42,88.15 38.61,88.15 38.72,88.04 38.72,87.83 38.61,87.72 38.42,87.72 38.31,87.62 38.31,86.67 38.42,86.56 39.12,86.56 39.22,86.46 39.22,86.24 39.12,86.14 38.42,86.14 38.31,86.03 38.31,85.55 38.5,85.36 38.65,85.36 38.98,85.69 39.13,85.69 39.28,85.54 39.28,85.39 38.81,84.92 38.64,84.92 38.51,84.79 38.51,84.59 38.64,84.46 39.68,84.46 40.3,85.08 40.3,85.19 40.11,85.38 40.11,85.55 40.24,85.68 40.42,85.68 40.6,85.49 40.68,85.49 40.87,85.69 40.87,85.76 40.28,86.35 40.28,86.53 41.36,87.61 41.51,87.61 41.71,87.4 41.71,87.25 41,86.54 v2(41,86.21)
  BOTTOM w0.102: UV1.K16 59.06,84.3 59.19,84.17 59.19,83.6 59.06,83.47 58.56,83.47 58.44,83.6 v2(58.44,83.6) ; v2(37.01,94.96) 37.01,94.96 37.01,94.84 36.47,94.3 36,94.3 35.88,94.18 35.88,94.01 36,93.89 36.06,93.89 36.15,93.81 36.15,92.36 36.25,92.26 36.25,92.06 36.12,91.93 UV8.K1
VSMB: length 73.9
  TOP w0.102: PR713.1 14.41,41.38 v1(15.6,42.57) 15.6,42.59 16.71,43.69 v2(16.72,43.69)
  TOP w0.254: v2(49.46,13.01) 49.46,11.45 v2(48.98,10.96) 47.85,9.83 v2(43.83,9.83)
  IN1 w0.107: v2(43.83,9.83) 42.73,9.83 41.74,10.82 35.67,10.82 31.83,14.66 24.12,14.66 22.87,15.9 22.87,22.21 24.13,23.47 24.49,23.47 25.85,24.83 25.85,31.54 22.54,34.86 22.54,38.26 22.84,38.56 22.84,39.97 20.38,42.44 17.2,42.44 16.72,42.92 v2(16.72,43.69)
  BOTTOM w0.203: PU701.12 43.73,10.41 43.86,10.28 43.86,10.08
  BOTTOM w0.254: v2(48.98,10.96) 48.77,11.17 PR719.1 ; PR727.1 49.08,13.39 v2(49.46,13.01)
VSUM+: length 10.8
  TOP w0.254: PR1057.1 52.53,35.87 52.63,35.97 v2(52.76,35.97)
  BOTTOM w0.102: PR1044.1 53.9,36.17 v1(53.7,36.38)
  BOTTOM w0.203: PC1032.1 55.17,36.15 55.4,36.38 56.95,36.38 57.16,36.17 PC1031.1 57.71,35.87 57.88,36.03 PU1000.14
  BOTTOM w0.254: PR1057.1 52.53,35.87 52.63,35.97 v2(52.76,35.97) 53.02,35.72 PR1042.1 PR1044.1 54.49,35.31 54.98,35.81 PC1032.1
VSUM-: length 54
  TOP w0.254: PR1053.1 54.29,34.47 54.59,34.78 PR1048.1 55.51,34.78 55.85,35.12 PC1035.1 ; PR1053.1 v1(53.85,35.46) 53.93,35.53 v2(53.93,36.87) ; PR1053.1 53.85,33.76 v2(53.9,33.71) 53.78,33.58 52.89,33.58 52.3,34.17 v2(52.3,34.47)
  BOTTOM w0.203: v2(53.93,36.87) 54.45,37.39 54.57,37.39 54.95,37.77 PR1046.1
  BOTTOM w0.254: PH1003.2 49.79,63 47.43,60.63 47.43,42.4 48.38,41.45 48.38,34.66 49.84,33.2 53.4,33.2 v2(53.9,33.71) PR1044.2 55.16,34.4 PC1032.2 55.9,33.68 PC1050.1 PC1051.1 PC1031.2 ; PR1043.1 v2(52.3,34.47)
VTTREF_1.35V: length 1.9
  BOTTOM w0.254: PU200.4 83.6,9.22 83.39,9.01 83.39,8.85 83.98,8.26 PC210.1
WAKE_PCH#: length 145.7
  TOP w0.076: v2(157.92,78.54) 157.58,78.88 v1(157.54,78.88) 157.33,78.88 156.14,80.07 156.14,84.38 156.67,84.92 RC38.1
  TOP w0.102: v2(120.33,24.97) 121.29,24.01 121.72,24.01 122.49,23.24 122.49,23.15 122.59,23.05 122.59,22.78 122.48,22.68 122.48,19.82 122.58,19.73 122.58,18.1 122.19,17.72 122.19,17.02 121.98,16.81 121.98,15.14 121.55,14.71 v2(121.55,14.69) ; UE1.74 147.67,8.91 v2(148.01,8.56)
  IN1 w0.076: v2(157.92,78.54) 158.73,77.73
  IN1 w0.107: 158.73,77.73 160.39,76.06 160.39,72.9 160.79,72.51 160.79,67.16 162.9,65.05 162.9,49.48 160.08,46.66 160.08,40.95 159.44,40.31 155.11,40.31 154.04,39.25 151.9,39.25 149.54,36.89 149.54,36 149.03,35.49 121.34,35.49 118.88,33.02 118.88,26.73 120.33,25.28 v2(120.33,24.97)
  IN2 w0.107: v2(121.55,14.69) 122.04,14.19 123.14,14.19 123.47,14.52 124.52,14.52 124.83,14.21 126.99,14.21 127.79,13.42 134.58,13.42 134.78,13.22 136.75,13.22 137.72,12.25 140.92,12.25 141.08,12.09 143.34,12.09 143.5,12.26 145.29,12.26 148.01,9.54 v2(148.01,8.56)
WAKEB: length 7.4
  BOTTOM w0.102: UV1.AJ27 74.04,74.86 v1(78.06,74.86) 78.42,74.86 78.97,75.42 RV163.1 RV162.2
WL_OFF#: length 91.3
  TOP w0.102: QM1.3 188.03,62.05 187.66,61.68 v1(185.96,61.68) 185.6,61.68 v2(184.59,62.69)
  IN1 w0.107: v2(164.39,94.14) 164.88,93.65 166.93,93.65 167.95,92.64 170.49,92.64 171.76,91.37 171.76,89.21 173.95,87.02 173.95,83.72 174.58,83.09 174.58,78.83 174.68,78.73 v2(174.68,77.27) 174.33,76.92 174.33,75.72 173.16,74.55 173.16,69.81 173.05,69.7 173.05,61.28 v2(172.75,60.99)
  IN2 w0.076: v2(153.73,81.64) 155.71,81.64 156.77,80.57 159.44,80.57
  IN2 w0.107: 159.44,80.57 159.49,80.57 160.23,81.31 160.23,82.86 161.58,84.21 163.46,84.21 163.56,84.31 166.53,84.31 168.41,82.43 168.41,81.72 168.97,81.16 168.97,78.87 170.36,77.47 174.1,77.47 174.3,77.27 v2(174.68,77.27)
  BOTTOM w0.076: v2(153.73,81.64) 153.61,81.64 UC1.AT5
  BOTTOM w0.102: v2(184.59,62.69) 184.59,63.81 184.2,64.19 179.31,64.19 178.82,63.71 178.82,62.89 177.32,61.4 173.26,61.4 172.88,61.02 172.78,61.02 v2(172.75,60.99) ; RP54.3 164.19,92.81 164.39,93.02 v2(164.39,94.14)
WL_OFF#_R: length 5.5
  TOP w0.102: v1(188.42,65.13) 188.19,64.9 187.97,64.9 187.57,64.51 QM1.1 187.07,64.51 186.54,65.03 RM8.2 186.54,66.27 186.25,66.56 v2(186.06,66.56)
  BOTTOM w0.102: v2(186.06,66.56) 186.23,66.4 JNGFF.48
WLAN_CLKREQ#: length 59.7
  IN1 w0.107: v2(172.14,61.02) 172.81,61.69 172.81,69.79 172.92,69.9 172.92,74.64 174.1,75.82 174.1,77.45 174.43,77.78 174.43,78.66 173.72,79.36 173.72,86.87 171.51,89.08 171.51,91.24 171.08,91.67 169.93,91.67 v2(169.47,92.13)
  IN2 w0.107: v2(184.36,56.67) 184.33,56.67 183.47,57.54 181.82,57.54 180.75,58.6 180.75,62.94 179.92,63.78 v2(179.92,63.79)
  BOTTOM w0.102: v2(184.36,56.67) 185.2,56.67 185.48,56.95 JNGFF.45 ; v2(172.14,61.02) 172.58,60.58 172.98,60.58 173.56,61.17 177.43,61.17 179.92,63.66 v2(179.92,63.79) ; v1(170.8,92.59) 170.3,93.09 Q2409.1 169.29,93.09 168.79,92.59 R2452.1 v2(169.47,92.13)
WLAN_CLKREQ#_R: length 20.7
  BOTTOM w0.076: 158.76,94.84 156.86,94.84 156.65,95.05 156.37,95.05 156.14,94.82 UC1.N1
  BOTTOM w0.102: 162.74,94.04 162.87,94.04 v1(163.51,94.67) 164.9,94.67 166.36,93.21 166.55,93.21 167.63,92.13 R2452.2 ; R2452.2 167.87,92.69 168.08,92.89 168.59,92.89 169.6,93.91 170.36,93.91 170.51,94.05 Q2409.3 ; R2452.2 167.87,91.7 168.33,91.24 168.33,90.73 168.15,90.55 RP42.7
  BOTTOM w0.107: 162.74,94.04 162.35,94.04 162.03,94.35 161.72,94.35 161.65,94.28 159.63,94.28 159.43,94.48 159.43,94.65 159.24,94.84 158.76,94.84
WLAN_WAKE#: length 97.7
  TOP w0.102: UE1.90 144.98,15.31 144.79,15.12 v2(144.79,13.14) ; v2(149.09,19.96) 149.17,20.03 150.28,20.03 150.5,19.81 RE72.2 ; v2(172.84,27.48) 173.97,27.48 177.6,31.12 177.6,34.41 v1(179.51,36.31) 180.63,37.43 183.86,37.43 185.1,38.66 185.1,42.35 186.14,43.39 186.14,55.1 v2(185.98,55.26)
  IN1 w0.107: v2(172.84,27.48) 172.71,27.36 172.71,27.34 170.64,25.27 170.64,24.72 169.27,23.35 169.27,20.81 167.7,19.23 167.7,17.83 165.08,15.21 165.08,11.41 164.27,10.6 162.76,10.6 161.11,8.95 158.62,8.95 157.56,10 157.56,11.6 157.22,11.94 152.23,11.94 151.98,11.7 v2(151.15,11.7) 150.7,12.15 150.15,12.15 150.14,12.14 145.78,12.14 v2(144.79,13.14)
  BOTTOM w0.102: JNGFF.47 185.98,57.13 185.59,56.74 185.59,55.65 v2(185.98,55.26) ; v2(151.15,11.7) 150.93,11.92 150.93,14.41 150.28,15.06 150.28,16.4 149.09,17.58 v2(149.09,19.96)
WOL_EN: length 180.1
  TOP w0.102: v2(164.88,113.14) 164.95,113.14 v1(166.55,114.74) 167.32,115.5 171.89,115.5 174.43,112.96 175.44,112.96 176,112.4 178.03,112.4 180.42,110.01 180.42,100.66 178.75,98.99 178.75,97.46 179.77,96.44 183.2,96.44 183.44,96.19 185.06,96.19 v2(185.93,95.33) 187.56,93.7 187.56,87.48 185.73,85.65 182.49,85.65 179.37,82.53 179.37,78.19 181.87,75.69 181.87,70.7 180.61,69.44 180.61,62.5 179.53,61.42 179.53,54.26 182.56,51.24 183.14,51.24 185.1,49.28 185.1,43.87 184.08,42.85 184.08,39.08 183.34,38.35 179.91,38.35 176.59,35.02 176.59,32.41 173.29,29.12 v2(172.89,29.12) ; UE1.98 144.62,18.38 144.46,18.21 144.46,17.61 144.18,17.33 142.98,17.33 142.02,16.36 142.02,14.96 142.3,14.69 v2(142.3,13.14)
  IN1 w0.107: v2(142.3,13.14) 143.14,13.14 144.11,14.11 145.74,14.11 145.95,13.9 148.58,13.9 149.25,13.22 150.99,13.22 151.23,12.98 158.6,12.98 160.45,14.83 163.17,14.83 166.68,18.34 166.68,19.74 167.67,20.73 167.67,24.15 172.63,29.12 v2(172.89,29.12)
  BOTTOM w0.102: UL3.4 186.82,98.03 185.93,97.13 v2(185.93,95.33) ; v2(164.88,113.14) 165.23,112.78 RL27.2 RL38.1 166.43,113.34 166.37,113.4 UL2.3
XDP_DBRESET#: length 111.5
  TOP w0.102: JXDP1.48 84.64,77.21 84.26,77.6 84.26,78.92 84,79.18 CC17.1 RC362.2 83.57,81.39 v2(83.5,81.46)
  IN2 w0.076: 111.56,102.47 117.82,102.47 118.45,101.85 125.22,101.85 125.91,101.15 128.36,101.15 129.14,101.92 130.34,101.92 133.07,104.65 135.86,104.65 137.74,102.77 141.01,102.77 142.68,101.11 142.68,97.31 142.78,97.21 142.78,96.4 143.78,95.39 144.2,95.39 144.58,95.01 145.48,95.01 146.77,93.73 v2(146.77,91.65) ; 151.38,92.07 151.44,92 156.14,92 156.27,92.13 157.79,92.13 158.3,91.62 158.68,91.62
  IN2 w0.102: 151.38,92.07 151.09,92.36 150.35,92.36 v2(150.32,92.38)
  IN2 w0.107: 111.56,102.47 v2(97.12,102.47) ; 158.68,91.62 159.44,91.62 161.58,89.49 v2(161.78,89.49)
  BOTTOM w0.076: v2(150.32,92.38) 149.87,92.84 148.71,92.84 147.52,91.65 v2(146.77,91.65) ; RC26.1 161.07,89.49 v2(161.78,89.49)
  BOTTOM w0.102: v2(83.5,81.46) 83.5,82.99 v1(84.99,84.48) 87.05,86.54 87.05,89.59 94.42,96.96 94.42,97.97 95.18,98.73 95.18,99.15 96.35,100.32 96.35,101.69 v2(97.12,102.47)
XDP_OBS0_R: length 67.2
  TOP w0.076: RC141.1 110.57,93.78 110.8,94.01 110.8,95.23 111.82,96.24 113.53,96.24 113.83,95.94 114.61,95.94 v2(115.12,96.45)
  TOP w0.102: JXDP1.21 90.27,70.71 89.34,69.78 89.34,69.52 v2(88.83,69.02)
  IN2 w0.076: 111.56,95.69 112.96,95.69 113.85,94.8 114.71,94.8 115.12,95.2 v2(115.12,96.45)
  IN2 w0.107: v2(88.83,69.02) 87.94,68.13 87.05,68.13 85.91,69.27 85.91,74.35 86.67,75.11 87.43,75.11 88.83,76.51 90.1,76.51 91.12,77.53 91.12,81.84 104.96,95.69 109.58,95.69 109.86,95.41 110.93,95.41 111.21,95.69 111.56,95.69
  BOTTOM w0.076: v2(115.12,96.45) 115.25,96.45 115.5,96.19 115.96,96.19 116.59,96.83 117.09,96.83 117.28,96.64 117.7,96.64 117.87,96.81 117.97,96.81 117.97,96.81 118.63,96.81 118.63,96.81 118.65,96.81 118.69,96.77 119.17,96.77 UC1.J60
XDP_OBS1_R: length 62
  TOP w0.076: v2(110.42,94.29) 109.2,94.29 108.95,94.04 RC141.2 v1(108.95,92.84)
  TOP w0.102: JXDP1.23 90.27,71.21 88.83,69.78 v2(88.83,69.65)
  IN2 w0.076: v2(119.16,97.48) 117.94,96.25 117.94,95.33 117.68,95.08 115.35,95.08 114.86,94.59 112.88,94.59 112.3,94.01 111.56,94.01
  IN2 w0.107: 111.56,94.01 110.7,94.01 v2(110.42,94.29) 109.4,95.31 104.96,95.31 91.43,81.78 91.43,77.46 90.23,76.26 88.96,76.26 87.56,74.86 86.8,74.86 86.16,74.22 86.16,69.4 87.18,68.38 87.81,68.38 88.19,68.76 88.19,69.14 88.7,69.65 v2(88.83,69.65)
  BOTTOM w0.076: v2(119.16,97.48) 119.46,97.78 UC1.H60
XDP_PRDY#: length 58.9
  TOP w0.102: v1(93.27,66.17) 93.13,66.17 92.59,66.71 JXDP1.5 90.37,66.71 89.85,67.24 v2(87.69,67.24)
  IN2 w0.076: v2(115.86,96.7) 115.73,96.83 113.47,96.83 113.09,96.45 111.56,96.45
  IN2 w0.107: 111.56,96.45 110.04,96.45 109.53,95.94 104.83,95.94 90.86,81.97 90.86,77.65 89.97,76.76 88.7,76.76 87.31,75.37 86.54,75.37 85.65,74.48 85.65,69.14 87.56,67.24 v2(87.69,67.24)
  BOTTOM w0.076: UC1.J62 117.92,97.1 117.63,96.81 117.37,96.81 117.07,97.11 116.39,97.11 115.98,96.7 v2(115.86,96.7)
XDP_PREQ#: length 64.2
  TOP w0.076: RP44.3 114.23,98.22 114.66,98.66 v1(114.79,98.66) 115.2,98.66 115.55,98.3 115.55,97.54 116.85,96.24 v2(116.85,95.89)
  TOP w0.102: v2(87.69,66.6) 88.07,66.98 89.59,66.98 90.36,66.21 JXDP1.3
  IN2 w0.076: 111.56,96.7 113.09,96.7 113.47,97.08 116.03,97.08 116.39,96.72 116.39,96.35 v2(116.85,95.89)
  IN2 w0.107: v2(87.69,66.6) 87.56,66.6 85.4,68.76 85.4,74.6 86.42,75.62 87.05,75.62 88.45,77.02 89.85,77.02 90.61,77.78 90.61,82.1 104.83,96.32 109.28,96.32 109.66,96.7 111.56,96.7
  BOTTOM w0.076: UC1.K62 117.97,96.16 117.7,95.89 v2(116.85,95.89)
XDP_RST#_R: length 5
  TOP w0.102: v1(81.69,78.67) 83.06,78.67 RC51.2 83.98,77.75 83.98,77.3 84.56,76.71 JXDP1.46
XDP_TCK: length 16.7
  TOP w0.076: v4(112.73,93.2) 112.73,94.77 112.89,94.93 RP45.2 114.25,94.93 v2(114.67,95.35)
  IN1 w0.076: v2(119.13,99.81) 117.59,99.81 116.77,98.99 115.17,98.99 114.86,99.29 113.72,99.29 112.71,98.28 112.71,95.56 113.34,94.92 114.23,94.92 114.65,95.35 v2(114.67,95.35)
  BOTTOM w0.076: v2(119.13,99.81) 119.46,99.48 UC1.E60
XDP_TCLK: length 22.7
  TOP w0.102: JXDP1.57 92.51,79.71 92.77,79.97 92.77,81.46 93.52,82.21 RP46.5 94.53,82.21 95.05,82.73 96.07,82.73 v1(96.83,83.49) 102.04,88.7 104.07,88.7 104.3,88.47 106.71,88.47 v2(107.12,88.07)
  BOTTOM w0.102: v2(107.12,88.07) 107.32,87.86 RC65.1 RC59.2
XDP_TDI: length 36.5
  TOP w0.076: v2(114.99,98.1) 114.48,98.1 114.1,97.72 RP44.2
  TOP w0.102: UC4.6 90.34,89.45 90.48,89.59 90.48,90.23 91.12,90.86 93.58,90.86 v4(93.73,90.71) 95.59,90.71 96.45,89.84 v2(96.45,88.96)
  IN2 w0.076: v2(114.99,98.1) 111.56,98.1
  IN2 w0.107: 111.56,98.1 104.96,98.1 96.45,89.59 v2(96.45,88.96)
  BOTTOM w0.076: UC1.F63 117.5,98.61 115.5,98.61 v2(114.99,98.1)
XDP_TDO: length 44.8
  TOP w0.076: v2(114.99,97.46) 115.47,96.98 v4(115.47,96.02) 115.47,95 114.9,94.43 RP45.1
  TOP w0.102: UC4.3 90.09,87.95 v2(90.61,87.43)
  IN2 w0.076: 111.56,97.85 114.61,97.85 v2(114.99,97.46)
  IN2 w0.107: v2(90.73,83.75) 91.88,83.75 97.21,89.08 97.21,89.97 105.09,97.85 111.56,97.85
  BOTTOM w0.076: v2(114.99,97.46) 114.99,97.59 115.75,98.35 117.36,98.35 117.39,98.32 117.64,98.32 117.74,98.42 117.74,98.42 117.92,98.6 UC1.F62
  BOTTOM w0.107: v2(90.73,83.75) 90.86,83.88 90.86,87.18 v2(90.61,87.43)
XDP_TMS: length 38.5
  TOP w0.076: v2(114.36,97.46) 114.36,97.45 114.13,97.22 RP44.1
  TOP w0.102: v2(97.72,89.84) v4(96.68,90.89) 96.45,91.11 88.7,91.11 88.02,90.43 UC4.8
  IN2 w0.076: 111.56,97.59 114.23,97.59 v2(114.36,97.46)
  IN2 w0.107: 111.56,97.59 105.47,97.59 v2(97.72,89.84)
  BOTTOM w0.076: UC1.E61 118.54,99.66 117.72,99.66 117.64,99.74 115.24,99.74 114.61,99.12 114.61,97.97 114.36,97.72 v2(114.36,97.46)
XDP_TRST#: length 54.5
  TOP w0.076: v2(110.55,95.94) 110.55,96.24 109.96,96.83 RC57.1 R2341.1 ; v2(114.03,95.33) 113.93,95.43 RP45.3
  TOP w0.102: UC4.11 86.54,88.45 85.65,87.56 85.65,87.18 v4(85.55,87.08) v2(84.89,86.42)
  IN1 w0.076: 108.13,96.19 110.29,96.19 v2(110.55,95.94) ; v2(119.77,99.8) 119.39,99.42 117.71,99.42 117.05,98.76 115.07,98.76 114.71,99.12 113.85,99.12 112.96,98.23 112.96,95.81 113.44,95.33 v2(114.03,95.33)
  IN1 w0.107: v2(92.77,96.96) 93.27,97.46 106.61,97.46 107.88,96.19 108.13,96.19
  IN2 w0.076: 111.56,96.07 113.29,96.07 v2(114.03,95.33)
  IN2 w0.107: v2(92.77,96.96) 87.94,92.13 87.94,90.86 85.4,88.32 85.4,86.92 v2(84.89,86.42) ; 111.56,96.07 110.67,96.07 v2(110.55,95.94)
  BOTTOM w0.076: v2(119.77,99.8) 120.11,99.45 UC1.E59
XTAL24_IN: length 20.5
  TOP w0.076: v2(133.38,110.09) 133.31,110.16 v1(132.47,110.16) 131.9,110.16 131.63,110.43 RG6.2
  BOTTOM w0.076: 142.04,103.36 142.04,103.2 141.55,102.71 141.55,102.16 UC1.A25 ; RC12.2 CC6.2
  BOTTOM w0.102: 142.04,103.36 142.04,104.12 141.17,105 141.17,105.27 140.42,106.02 139.33,106.02 138.24,107.12 135.82,107.12 135.56,107.37 135.56,107.68 RC12.2 135.53,108.3 135.53,110.55 135.06,111.01 YC2.3 134.31,111.01 v2(133.38,110.09)
XTAL24_OUT: length 14.9
  BOTTOM w0.076: RC12.1 CC7.2 ; UC1.B25 141.43,101.62 141.72,101.91 141.72,102.64 142.25,103.17 142.25,103.33
  BOTTOM w0.102: 142.25,103.33 142.25,104.19 141.36,105.08 141.36,105.36 140.47,106.25 139.57,106.25 v1(138.97,106.86) 138.45,107.37 135.95,107.37 135.8,107.51 135.8,107.66 RC12.1 135.81,108.35 135.81,108.99 136.13,109.31 YC2.1
XTALIN: length 10.1
  BOTTOM w0.102: YV1.1 82.57,73.17 82.23,72.83 79.89,72.83 RV20.1 ; RV20.1 CV17.1 ; RV20.1 79,73.16 78.62,73.54 v1(78.01,73.54) 77.32,73.54 76.36,74.5 UV1.AM28
XTALOUT: length 9.7
  BOTTOM w0.102: CV18.1 RV20.2 ; RV20.2 79.56,72.32 79.81,72.57 80.57,72.57 80.87,72.28 YV1.3 ; RV20.2 78.42,72.24 v1(78.37,72.19) 78.29,72.19 76.38,74.1 74.35,74.1 74,74.45 UV1.AK28
XTLI: length 7.7
  TOP w0.102: RG8.2 176.35,108.08 v1(176.87,108.6) v2(177.96,108.6)
  BOTTOM w0.102: v2(177.96,108.6) YL2.1 176.12,108.6 175.88,108.36 175.88,107.75 CL36.2 175.77,106.88 UL1.29
XTLI_R: length 34.2
  TOP w0.102: CG7.1 RG5.2 190,93.6 v1(187.9,95.7) 183.2,100.4 v2(181.98,100.4) ; RG8.1 177.77,106.99 v2(178.24,106.99)
  IN2 w0.107: v2(178.24,106.99) 179.13,106.99 180.4,105.72 180.4,101.99 v2(181.98,100.4)
XTLO: length 5.3
  BOTTOM w0.102: YL2.3 175,110.2 175.57,109.63 175.57,107.55 CL37.2 175.37,107.35 UL1.28
N71037: length 2.3
  BOTTOM w0.102: RA130.2 195.23,14.61 195.93,15.3 UA1.8
N71249: length 5.7
  TOP w0.203: v2(196.16,24.54) 195.82,24.54 195.38,24.1 RA12.2
  BOTTOM w0.203: UA1.27 195.13,23.07 194.72,23.48 194.72,23.48 194.18,24.03 CA62.2 194.53,24.79 195.91,24.79 v2(196.16,24.54)
N71261: length 5
  BOTTOM w0.203: CA63.2 201.86,23.61 201.86,22.33 v1(200.97,21.44) 200.48,20.95 200.23,20.95 200.17,20.89 UA1.39
N71273: length 2.6
  TOP w0.102: v2(196.53,15.17) 196.02,15.68 CA64.2
  BOTTOM w0.102: UA1.7 196.33,15.37 v2(196.53,15.17)
N71383: length 3
  TOP w0.102: CA24.1 v1(199.52,21.52)
  TOP w0.254: CA24.1 199.78,22.28 v2(200.34,22.28)
  BOTTOM w0.254: UA1.37 199.87,21.69 200.34,22.15 v2(200.34,22.28)
N71395: length 2.4
  TOP w0.102: v2(198.61,23.37) 198.61,23.65 v1(198.38,23.88)
  TOP w0.254: CA24.2 v2(198.61,23.37)
  BOTTOM w0.203: v2(198.61,23.37) 198.61,23.23 198.33,22.95 UA1.35
N71399: length 2.6
  BOTTOM w0.203: UA1.34 197.93,23.03 198.15,23.25 198.15,23.6 198.43,23.88 v1(198.55,23.88) 199.42,23.88 CA25.2
N71447: length 1.8
  BOTTOM w0.203: UA1.28 195.53,23.16 195.26,23.43 CA23.2
N71539: length 3.9
  TOP w0.102: v1(194.49,13.82) CA65.2
  TOP w0.254: RA79.1 CA69.1 RA81.2 CA65.2
N71593: length 3.5
  TOP w0.102: CA65.1 193.96,14.74 v1(194.39,15.17)
  TOP w0.254: v2(193.86,15.68) 193.22,15.04 CA65.1
  BOTTOM w0.254: UA1.12 194.33,16.14 v2(193.86,15.68)
N76526: length 3.3
  BOTTOM w0.102: RA1113.2 198.94,14.1 v1(198.94,14.94) 198.8,15.08 198.39,15.08 197.53,15.95 UA1.4
N14128350: length 3.3
  BOTTOM w0.102: PR1110.2 29.88,43.74 v1(29.65,43.51)
  BOTTOM w0.254: PU1100.1 30.16,45.39 29.9,45.14 29.9,44.43 PR1110.2
N16741477: length 1.5
  TOP w0.102: T212.1 67.24,90.86 v2(67.74,90.86)
  BOTTOM w0.102: UV1.AB8 68.1,90.5 v2(67.74,90.86)
N16741481: length 4.9
  TOP w0.102: T209.1 70.82,89.62 70.19,89.62 70.01,89.8 70.01,91.09 69.86,91.24 69.14,91.24 v2(68.8,90.9)
  BOTTOM w0.102: UV1.AC8 v2(68.8,90.9)
N16741485: length 2.5
  TOP w0.102: v2(70.4,90.85) 70.4,90.88 70.8,91.27 T205.1
  BOTTOM w0.102: v2(70.4,90.85) 70.75,90.5 UV1.AE8
N16741489: length 3.4
  TOP w0.102: v2(69.6,91.65) 69.6,91.82 70.03,92.26 70.03,94.09 T208.1
  BOTTOM w0.102: UV1.AD7 69.95,91.3 v2(69.6,91.65)
N16741493: length 2.5
  TOP w0.102: v2(70.4,90.05) 70.83,90.48 70.83,90.77 T203.1
  BOTTOM w0.102: v2(70.4,90.05) 70.75,89.7 UV1.AE9
N16741497: length 1.4
  TOP w0.102: v2(61.63,89.99) 61.89,89.99 T201.1
  BOTTOM w0.102: v2(61.63,89.99) 61.34,89.7 UV1.N9
N16741501: length 2.1
  TOP w0.102: T215.1 69.14,95.52 v2(68.1,94.47)
  BOTTOM w0.102: UV1.AB2 68.4,94.17 v2(68.1,94.47)
N16741505: length 1.7
  TOP w0.102: v2(68.1,93.67) 67.52,93.67 T214.1
  BOTTOM w0.102: UV1.AB4 68.4,93.37 v2(68.1,93.67)
N16741509: length 2.5
  TOP w0.102: T211.1 68.23,90.58 v2(68.74,90.07)
  BOTTOM w0.102: v2(68.74,90.07) 68.37,89.7 UV1.AB9
N16741513: length 1.9
  TOP w0.102: v2(68.78,89.36) 69.2,89.78 T207.1
  BOTTOM w0.102: v2(68.78,89.36) 68.78,89.32 UV1.AC10
N16741517: length 4.7
  TOP w0.102: T206.1 72.32,90.35 72.21,90.35 71.27,89.41 70.08,89.41 69.6,89.9 v2(69.6,90.05)
  BOTTOM w0.102: UV1.AD9 69.95,89.7 v2(69.6,90.05)
N16741521: length 1.6
  TOP w0.102: v2(59.2,89.29) 59.77,89.87 T202.1
  BOTTOM w0.102: UV1.L9 59.61,89.7 v2(59.2,89.29)
N16741525: length 2.6
  TOP w0.102: v2(65.24,90.36) 65.34,90.36 T216.1
  BOTTOM w0.102: v2(65.24,90.36) 65.48,90.12 66.62,90.12 UV1.Y8
N16741529: length 1.9
  TOP w0.102: v2(67.74,91.62) 67.74,91.63 67.49,91.88 T213.1
  BOTTOM w0.102: UV1.AB7 68.06,91.3 v2(67.74,91.62)
N16741533: length 2.2
  TOP w0.102: T210.1 69.14,92.89 69.14,92 68.8,91.66 v2(68.8,91.57)
  BOTTOM w0.102: v2(68.8,91.57) 69.07,91.3 UV1.AC7
N16741553: length 3.9
  TOP w0.102: T204.1 67.62,89.97 67.34,89.69 67.34,88.78 67.24,88.68 67.24,87.81 66.96,87.54 v2(66.93,87.54)
  BOTTOM w0.102: UV1.Y11 66.4,88.06 v2(66.93,87.54)
N16741557: length 1.9
  TOP w0.102: T217.1 66.07,91.8 v2(66.3,91.57)
  BOTTOM w0.102: UV1.Y7 66.73,91.57 v2(66.3,91.57)
N16741803: length 3.9
  TOP w0.102: v1(72.17,78.31) 71.82,77.97 RV29.2 70.26,78.82 v2(69.58,78.82)
  BOTTOM w0.102: v2(69.58,78.82) 69.2,79.2 UV1.AC22
N16741825: length 1.7
  TOP w0.102: v2(68.76,78.7) 69.35,78.11 RV59.2
  BOTTOM w0.102: UV1.AB22 68.4,79.06 v2(68.76,78.7)
N16745905: length 4.1
  BOTTOM w0.102: RV25.2 v1(39.68,112.83)
  BOTTOM w0.508: RV25.2 40.24,112.2 QV3.2
N16745935: length 7.7
  BOTTOM w0.102: v1(44.81,105.08) CV24.1
  BOTTOM w0.508: QV2.2 44.18,108.44 42.81,107.07 RV23.2 CV24.1
N16745959: length 5.9
  BOTTOM w0.508: RV26.1 v1(47.1,112.83) CV25.1 48.62,111.71 48.11,111.21 QV4.2
N16784339: length 6.8
  TOP w0.102: v2(82.23,91.75) v1(81.72,91.75)
  IN2 w0.107: v2(82.23,91.75) 80.7,91.75 79.3,90.35 v2(78.42,90.35)
  BOTTOM w0.102: v2(82.23,91.75) 82.28,91.69 U1.7 ; RV77.1 v2(78.42,90.35)
N16784342: length 8.5
  TOP w0.102: v2(78.42,93.91) v1(79.08,93.91)
  IN2 w0.107: v2(78.42,93.91) 80.7,93.91 81.46,93.15 v2(81.46,92.38)
  BOTTOM w0.102: RV78.1 v2(78.42,93.91) ; U1.6 82.93,91.93 82.48,92.38 v2(81.46,92.38)
N16787636: length 5
  TOP w0.254: JKBBL.2 121.08,15.82 121.67,16.41 121.67,16.97 v1(121.8,17.1) 121.8,17.2 121.67,17.33 121.21,17.33 120.86,17.68 RE58.1 120.86,19 QE4.2
N16803422: length 9.4
  BOTTOM w0.254: UV1.AJ11 73.86,88.1 74.28,88.52 76.33,88.52 77.15,89.34 77.15,92.26 77.91,93.02 v1(78.03,93.02) RV157.1
N16803439: length 5.8
  BOTTOM w0.254: RV155.1 77.78,88.57 v1(77.2,87.99) 76.89,87.69 74.35,87.69 74,87.33 UV1.AK12
N16803454: length 5.4
  BOTTOM w0.254: RV156.1 v1(78.19,89.46) 77.91,89.46 76.54,88.1 UV1.AL11
N16814221: length 8
  TOP w0.102: v1(73.34,89.41) 73.34,89.21 73.01,88.88 72.4,88.88 v2(71.99,89.29)
  TOP w0.254: v2(71.99,89.29) 71.63,89.29 71.28,88.93 RV60.1
  BOTTOM w0.254: UV1.AC13 UV1.AC11 69.2,88.1 69.53,88.42 71.74,88.42 71.99,88.68 v2(71.99,89.29)
N16855208: length 4.2
  TOP w0.102: U2407.7 156.26,13.64 156.32,13.69 R2448.2 R2450.1 v1(154.69,15.22)
N16924370: length 11.1
  TOP w0.102: v1(182.99,109.2) CL41.2
  TOP w0.457: v2(182.05,108.39) 182.05,107.85 182.54,107.36 CL41.2
  BOTTOM w0.508: TL2.3 182.17,104.58 182.94,105.34 182.94,107.5 v2(182.05,108.39) TL2.6
N16924426: length 3.7
  TOP w0.102: v2(176.84,106.51) 176.9,106.57 178.56,106.57 v1(178.64,106.66)
  TOP w0.254: RL31.2 176.59,106.25 v2(176.84,106.51)
  BOTTOM w0.254: v2(176.84,106.51) 176.57,106.24 UL1.31
N16924463: length 1.3
  BOTTOM w0.102: T94.1 173.59,106.56 174.17,105.98 UL1.25
N16924465: length 1.8
  TOP w0.102: v2(174.94,106.48) 175.42,106.96 T95.1
  BOTTOM w0.102: UL1.27 174.97,106.34 174.94,106.38 v2(174.94,106.48)
N16924703: length 15.7
  TOP w0.381: CL33.1 195.19,109.21 193.48,110.93 v1(191.62,110.93) 189.79,110.93 188.61,109.75 RL20.2 188.61,106.02 188.52,105.93 RL19.2
N16948644: length 3
  BOTTOM w0.203: PU1000.15 58.03,36.43 58.03,36.43 57.65,36.43 57.65,36.43 57.53,36.43 57.16,36.81 PC1036.2
  BOTTOM w0.254: PR1046.2 PC1036.2
N16948660: length 2.7
  TOP w0.254: PR1048.2 55.05,36.25 55.56,36.76 v2(55.56,36.89)
  BOTTOM w0.102: v2(55.56,36.89) 55.2,37.24 v1(55.2,37.34)
  BOTTOM w0.254: PC1036.1 v2(55.56,36.89)
N16948668: length 6.1
  TOP w0.254: PR1024.1 PC1020.1 61.19,39.18 v1(61.19,40.87) 61.65,41.33 v2(61.91,41.33)
  BOTTOM w0.203: v2(61.91,41.33) 61.78,41.33 61.32,40.88 PU1000.25
N16955053: length 34.7
  BOTTOM w0.254: PR1058.2 50.78,36.11 PR1039.2 50.02,35.87 49.52,36.36 49.52,42.13 48.95,42.7 48.95,58.86 v1(49.32,59.22) 50.09,60 55.3,60 55.68,59.62 PL1002.2
N16955054: length 35.6
  BOTTOM w0.254: PL1002.3 55.68,61.27 54.92,60.51 v1(50.73,60.51) 49.97,60.51 48.44,58.98 48.44,42.61 49.14,41.91 49.14,35.68 50.35,34.47 PR1043.2
N16955057: length 4
  BOTTOM w0.203: 58.03,33.04 58.07,33.08 58.07,34.5 58.4,34.83 PU1000.11 ; 58.03,33.04 v1(58.03,33.02) ; 58.03,33.04 57.41,33.04 57.03,32.66 PR1052.2
N16955058: length 5.1
  TOP w0.102: v2(57.84,36.89) v1(58.38,36.89)
  TOP w0.254: v2(57.84,36.89) PC1030.1 PR1049.1 PR1040.1 PC1027.1
  BOTTOM w0.203: v2(57.84,36.89) 57.9,36.83 PU1000.16
N16955061: length 5.6
  TOP w0.102: v1(59.82,40.42) 59.32,39.91 58.5,39.91 58.2,39.6 PR1050.1
  TOP w0.254: PR1050.1 58.02,39.53 PC1040.1 58.02,37.7 v2(57.84,37.51)
  BOTTOM w0.203: v2(57.84,37.51) 57.86,37.51 58.14,37.23 PU1000.17
N16955074: length 4.5
  IN1 w1.016: 58.08,49.5 57.28,50.3 57.28,53.7
  vias: v1(57.96,54.78) v2(58.18,54.28) v2(58.16,53.65) v2(58.86,49.65) v2(58.86,49.06)
N16955100: length 1.3
  BOTTOM w0.102: PC1029.1 v1(56.24,44.95)
N16955117: length 1.2
  BOTTOM w0.102: PC1026.1 v1(60.74,43.17)
N16955158: length 20.4
  TOP w0.254: PR1031.2 54.72,32.5 v2(54.67,32.56) 53.98,32.56 53.48,32.05 v1(52.13,32.05) 52.08,32.11 51.39,32.11 49.92,33.58 49.92,41.7 50.56,42.35 PH1002.2
  BOTTOM w0.254: v2(54.67,32.56) 55.75,31.47 PR1052.1
N16955166: length 11
  TOP w0.254: PR1040.2 55.35,38.66 PR1037.2 v1(54.36,38.71) 54.34,38.71 v2(53.48,37.85)
  BOTTOM w0.203: PR1041.1 55.68,38.54 55.81,38.41 56.95,38.41 57.16,38.61 PC1028.1 57.55,38.92 57.71,38.75 57.71,38.28 58.37,37.63 PU1000.18
  BOTTOM w0.254: PR1041.1 54.31,37.85 v2(53.48,37.85) 53.22,38.1 PR1045.1
N16955169: length 2.3
  TOP w0.102: PR1037.1 54.77,39.63 v1(54.24,40.16)
  TOP w0.254: PC1027.2 56.17,39.63 PR1037.1
N16955171: length 1.9
  BOTTOM w0.102: PC1034.1 v1(51.29,39.43)
  BOTTOM w0.254: PR1045.2 PC1034.1
N16955173: length 7.6
  BOTTOM w0.102: v1(55.43,41.2) 55.43,40.77 55,40.34 PR1038.1
  BOTTOM w0.203: PC1028.2 56.24,39.35 56.44,39.55 57.38,39.55 58.1,38.84 58.1,38.41 58.47,38.03 PU1000.19
  BOTTOM w0.254: PC1028.2 55.81,38.92 55.3,39.43 PC1033.2 PR1038.1
N16955176: length 2.5
  BOTTOM w0.102: v1(53.14,40.7) 53.65,40.19 53.65,39.86 PC1033.1
  BOTTOM w0.254: PR1041.2 PC1033.1
N16955207: length 1.1
  TOP w0.102: PR1060.2 v1(49.38,48.9)
N16960820: length 2.3
  TOP w0.102: v1(152.48,19.18) C5214.1 153.47,19.61 153.73,19.87 153.73,20.41 U2408.6
N16988653:
  vias: v1(86.26,22.79)
N16988706: length 2.8
  BOTTOM w0.102: v1(82.51,26.55) 82.78,26.28 PR605.2
  BOTTOM w0.508: PR605.2 83.93,25.69 PC601.1
N17016554: length 26.3
  TOP w0.102: v2(35.11,91.16) 35.06,91.22 35.06,91.27 34.6,91.72 34.6,92.33 34.95,92.68 UV7.L8
  IN1 w0.102: 27.31,93.6 27.49,93.43 32.57,93.43 34.83,91.16 v2(35.11,91.16) ; 29.09,99.34 33.61,99.34 34.65,100.39
  IN1 w0.107: 27.31,93.6 26.35,94.57 26.35,97.47 28.22,99.34 29.09,99.34 ; v2(34.98,100.72) 34.65,100.39
  BOTTOM w0.102: v1(35.39,100.37) 35.3,100.37 34.98,100.69 v2(34.98,100.72) 34.98,100.94 RV56.1
N17017096: length 17.8
  TOP w0.102: v2(35.03,99.24) 34.75,99.52 30.74,99.52 30.08,98.86 27.18,98.86 26.8,98.48 v1(26.8,97.01) 26.8,95 27.41,94.39 RV57.1
  BOTTOM w0.102: v2(35.03,99.24) 35.29,98.99 35.29,98.12 34.95,97.79 UV8.L8
N17072999: length 2.8
  TOP w0.203: v2(169.96,15.93) 169.96,15.85 170.22,15.59 U2301.12
  BOTTOM w0.254: v2(169.96,15.93) 168.84,17.05 C5216.1
N17073002: length 2.9
  TOP w0.203: v2(171.18,15.96) 171.02,15.8 U2301.10
  BOTTOM w0.254: C5217.1 170.52,16.59 170.59,16.59 171.18,16.01 v2(171.18,15.96)
N17073375: length 1.8
  TOP w0.203: U2304.12 161.58,15.67 v2(161.35,15.9)
  BOTTOM w0.254: v2(161.35,15.9) 161.47,16.03 C5218.1
N17073377: length 1.8
  TOP w0.203: U2304.10 162.38,15.62 162.59,15.83 v2(162.59,15.9)
  BOTTOM w0.254: v2(162.59,15.9) 162.49,16.01 C5219.1
N17087794: length 3.5
  BOTTOM w0.102: PU1000.39 64.63,35.23 64.75,35.11 64.75,34.98 64.6,34.83 PU1000.40 64.01,34.63 64.12,34.52 65.45,34.52 v1(65.55,34.62)
N17087943:
  vias: v1(65.26,35.97)
N17088414: length 5
  BOTTOM w0.102: v1(66.1,32.39) PR1032.2
  BOTTOM w0.203: PU1000.1 63.32,33.71 63.46,33.58 64.29,33.58 64.45,33.74 65.26,33.74 65.49,33.51 65.49,33.08 65.13,32.72 PR1032.2
N17088417: length 3.7
  BOTTOM w0.102: PR1033.2 65.11,33.25 v1(65.11,33.35)
  BOTTOM w0.203: PR1033.2 64.09,32.39 62.92,33.55 PU1000.2
N17089228: length 2.9
  TOP w0.102: v1(65.89,36.15) PR1035.2
  TOP w0.254: v2(64.89,37.13) 64.89,37.14 PR1035.2
  BOTTOM w0.203: PU1000.34 64.01,37.23 64.8,37.23 v2(64.89,37.13)
N17089248: length 2.8
  TOP w0.254: PR1056.2 v2(65.08,38.03)
  BOTTOM w0.102: v1(65.41,37.27) 65.41,37.7 v2(65.08,38.03)
  BOTTOM w0.203: v2(65.08,38.03) 64.02,38.03 PU1000.32
N17112777: length 63.5
  TOP w0.254: v2(52.58,40.37) 50.91,40.37 50.54,40 v1(50.54,37.82) PR1057.2 50.54,34.71 PR1059.2
  IN2 w0.254: v2(52.58,40.37) 52.41,40.54 52.41,42.09 48.6,45.9 48.6,50.53 48.16,50.96 48.16,59.87 52.86,64.57 68.51,64.57 69.27,63.81 69.27,60.76 68.51,60 64.45,60 v2(64.32,60.13)
  BOTTOM w0.254: PL1003.2 v2(64.32,60.13)
N17143063: length 3.7
  TOP w0.102: v1(14.34,64.24) 12.99,64.24 CE60.1 12.03,64.08 UE4.6
N17145436: length 2.1
  BOTTOM w0.102: PC307.2 185.12,48.11 v1(185.12,47.35)
  BOTTOM w0.254: PR309.1 PC307.2
N17200666: length 2
  TOP w0.102: US2.7 185.72,14.85 RS19.2
N17200672: length 2.6
  TOP w0.102: 185.22,9.97 185.22,8.73 185.35,8.6 RS20.2 RS22.2
N17200720: length 4.6
  TOP w0.102: v2(183.32,14.79) 182.84,14.3 v1(181.69,14.3)
  TOP w0.254: v2(183.32,14.79) 183.39,14.72 183.8,14.72 184.22,14.29 US2.10
  BOTTOM w0.254: RS25.2 183.39,14.79 v2(183.32,14.79)
N17242539: length 3.5
  BOTTOM w0.102: RV58.1 58.96,105.74 58.6,106.1 v1(58.6,106.4) 58.6,106.91 58.81,107.12 58.81,107.45 58.54,107.72 UV3.4
N17258399:
  vias: v1(23.35,115.28)
N17283470:
  vias: v1(90.73,13.47) v3(90.35,13.9) v3(91.12,13.9)
N17283477: length 5.7
  TOP w0.508: PC204.2 84.13,14.48 83.5,13.85 v2(83.5,13.64) 83.5,13.24 v1(83.11,12.86) 82.61,12.35 PR210.1
  BOTTOM w0.254: v2(83.5,13.64) 83.6,13.54 PU200.12
N17290798: length 7.6
  BOTTOM w0.254: PR300.1 PR310.1 PR301.1 PC300.1 182.56,44.89 181.67,45.78 v1(181.67,46.69) 181.67,46.87 181.03,47.5 181.03,48.19 180.76,48.46 PU300.1
N17411014: length 2.5
  TOP w0.102: CE12.1 R2354.1 127.49,14.46 v1(127.18,14.76)
N17434554: length 4.5
  TOP w0.102: v1(141.76,23.5) 141.63,23.37 141.63,22.27 141.15,21.79 RE36.2 141.15,21.16 141.02,21.03 UE1.107
N17434577: length 5.3
  TOP w0.102: UE1.66 147.57,5.71 147.78,5.49 147.78,3.46 v1(148.14,3.1) 149.21,2.04 RE7.2
N17438484: length 2.6
  BOTTOM w0.102: v1(196.96,11.13) CA21.1 196.96,12.53 197.03,12.6 RA1112.2
N17446326: length 1.8
  TOP w0.508: PC733.2 31.74,38.84 v2(32.14,38.45)
  BOTTOM w0.102: 34.78,39.09 v1(34.78,40.15)
N17446342:
  vias: v1(26.57,41.9)
N17446348: length 19.7
  TOP w0.254: v2(24.26,34.73) 26.9,34.73 PR725.2 28.11,33.52 29.9,33.52 31.41,35.03 v1(31.41,36.59) v2(31.41,37.13) 31.51,37.23 PC733.1
  BOTTOM w0.254: PC702.1 PR718.2 26.97,39.49 27.18,39.27 27.18,38.79 27.44,38.54 PQ701.4 30,38.54 v2(31.41,37.13) ; PQ700.4 v2(24.26,34.73)
N17455546: length 31.9
  TOP w0.076: 168.59,85.4 168.13,85.4 166.93,86.59 162.44,86.59 161.25,85.4 160.76,85.4 159.87,86.29 159.54,86.29 159.16,85.91 v2(159.06,85.91)
  TOP w0.102: 168.59,85.4 170.64,85.4 171.15,84.89 173.28,84.89 173.54,84.64 v1(173.54,83.93) 173.54,83.75 174.55,82.73 RC137.1 C93.1
  IN2 w0.076: v2(150.3,88.45) 150.42,88.45 151.69,87.18 152.06,87.18 152.95,86.29 158.68,86.29
  IN2 w0.107: v2(159.06,85.91) 158.68,86.29
  BOTTOM w0.076: v2(150.3,88.45) 150.3,88.7 150.63,89.03 UC1.AD10 UC1.AD8
N17456106: length 3
  TOP w0.076: v2(148.35,97.14) 148.86,97.14 v1(148.91,97.2)
  TOP w0.254: C92.2 148.35,96.21 ; 148.35,96.21 v2(148.35,97.14) ; 148.35,96.21 149.19,96.21 RC142.1
  BOTTOM w0.254: UC1.J13 148.68,96.82 v2(148.35,97.14)
N17456207: length 18.8
  TOP w0.305: v2(148.47,86.29) 147.47,86.29 146.59,85.4 146.59,83.45 146.36,83.22 146.36,83.22 146.36,81.23 v1(145.33,80.2) 144.33,79.2
  TOP w0.508: 144.33,79.2 144.33,72.93 143.36,71.96 C91.2 RC143.1
  BOTTOM w0.305: v2(148.47,86.29) 148.59,86.29 UC1.AH13
N17468285: length 7.9
  TOP w0.508: RD4.1 CD22.1 CD21.1 137.31,38.94 137.31,38 136.84,37.52 v1(136,37.52) v2(135.18,37.52)
  BOTTOM w0.356: v2(135.18,37.52) 135.54,37.52 135.97,37.95 135.97,38.38 136.05,38.46 JDIMM1.126
N17471827: length 3
  TOP w0.102: RD6.2 157.41,49.02 v2(157.35,49.08) v1(157.35,49.72)
  BOTTOM w0.102: v2(157.35,49.08) JDIMM1.197
N17471828: length 5
  TOP w0.102: v2(158.43,45.7) 158.73,45.7 v1(158.93,45.9) 159.06,46.03 159.06,47.05 158.88,47.22 RD7.2
  BOTTOM w0.102: JDIMM1.201 158.55,46.82 158.9,46.47 158.9,45.91 158.62,45.64 158.49,45.64 v2(158.43,45.7)
N17476323: length 6.1
  TOP w0.102: v1(151.44,24.92) RD10.1
  TOP w0.508: v2(149.21,25.04) 149.4,25.24 149.4,26.01 CD53.1 CD52.1 RD10.1
  BOTTOM w0.356: v2(149.21,25.04) 149.01,25.04 148.42,25.63 JDIMM2.126
N17476376: length 5.6
  TOP w0.102: v2(170.41,32.67) 170.92,32.67 v1(171.02,32.77) 171.02,34.75 RD13.1
  BOTTOM w0.102: v2(170.41,32.67) 170.31,32.57 169.98,32.57 169.72,32.83 JDIMM2.197
N17476385: length 4.9
  TOP w0.102: v2(170.41,33.33) 170.54,33.46 v1(170.54,33.99) 170.29,34.24 170.29,35.54 170.54,35.79 RD12.1
  BOTTOM w0.102: v2(170.41,33.33) 170.74,33.33 170.92,33.51 JDIMM2.201
N17493058: length 2.7
  TOP w0.102: v2(183.22,66.6) 183.22,66.59 183.22,66.37 T4927.1
  BOTTOM w0.102: JNGFF.36 183.23,66.6 v2(183.22,66.6)
N17493084: length 3.5
  TOP w0.102: T4929.1 v2(184.69,67.85)
  BOTTOM w0.102: v2(184.69,67.85) 184.69,67.8 184.23,67.33 JNGFF.40
N17493086: length 4.1
  TOP w0.102: v2(183.19,67.24) 183.7,66.73 T4928.1
  BOTTOM w0.102: v2(183.19,67.24) 183.73,66.7 JNGFF.38
N17493091: length 3
  TOP w0.102: T3861.1 174.83,63.43 v2(174.15,63.43)
  BOTTOM w0.102: JNGFF.6 173.73,63.75 174.05,63.43 v2(174.15,63.43)
N17493111: length 2
  TOP w0.102: T3862.1 176.46,63.81 v2(176.46,64.06)
  BOTTOM w0.102: v2(176.46,64.06) 176.45,64.06 176.23,64.29 JNGFF.16
N17494823: length 10.9
  TOP w0.254: RA3.2 191.45,21.46 QA5.2 191.32,22.03 v2(191.57,22.28)
  TOP w0.508: v2(188.27,22.79) 189.03,22.79 v1(189.39,23.14) 190.62,24.38 CA2.1 CA1.1
  BOTTOM w0.381: v2(188.27,22.79) 188.52,22.79 188.91,22.41 190.18,22.41 190.4,22.18 191.48,22.18 v2(191.57,22.28)
N17531604: length 30.7
  TOP w0.076: v2(168.36,89.11) 168.59,89.11
  TOP w0.102: 168.59,89.11 168.97,89.11 169.25,88.83 170.74,88.83 171.25,89.34 174.3,89.34 174.99,88.65 v1(174.99,88.35) C90.1 RC136.1 174.99,86.07 174.75,85.83 CC38.1 CC37.1
  IN1 w0.076: v2(151.75,90.48) 152.25,90.99 155.2,90.99 155.28,91.06 158.12,91.06 158.43,91.37 158.73,91.37
  IN1 w0.107: v2(168.36,89.11) 168.36,89.31 167.7,89.97 164.9,89.97 163.89,90.99 161.09,90.99 160.71,91.37 158.73,91.37
  BOTTOM w0.254: v2(151.75,90.48) 151.55,90.29 UC1.AB8
N17580597: length 2.3
  TOP w0.102: UX3.4 12.2,95.37 CX52.1 v1(12.2,93.12)
N17586185: length 3.1
  TOP w0.102: RE37.2 132.14,21.19 132.11,21.16 v1(132.11,20.65) 132.29,20.48 132.85,20.48 133.02,20.3 UE1.127
N17613161: length 1.5
  BOTTOM w0.102: v1(178.82,56.01) 179.13,56.01 179.74,55.4 179.74,55.02
N17613162: length 5
  BOTTOM w0.254: PR307.1 184.77,50.27 183.88,49.38 PR309.2 183.01,49.33 PR305.2 182.12,49.41 v1(182,49.28) 181.84,49.28 181.31,49.81 PU300.4
N17613228: length 1.4
  BOTTOM w0.102: PC302.1 v1(183.76,54.4)
N17745376: length 2.8
  TOP w0.102: v1(174.12,107.55) 174.3,107.37 v2(174.3,106.43) 174.3,105.87 RL39.2
  BOTTOM w0.102: v2(174.3,106.43) 174.57,106.16 UL1.26
N17847259: length 3.4
  BOTTOM w0.102: T4930.1 76.64,89.34 76.13,88.83 75.49,88.83 74.62,89.7 UV1.AL9
N17877344: length 4.5
  BOTTOM w0.102: T223.1 62.58,98.23 63.18,97.63 63.18,94.97 62.8,94.6 UV1.R1
N17877347: length 3.5
  BOTTOM w0.102: UV1.R3 62.41,94.09 62.41,96.46 T224.1
N17882994: length 34.5
  BOTTOM w0.254: PR1042.2 53.02,33.96 52.76,33.71 49.97,33.71 48.76,34.92 48.76,41.65 47.94,42.47 47.94,60.25 v1(49.03,61.35) 49.76,62.08 PH1003.1
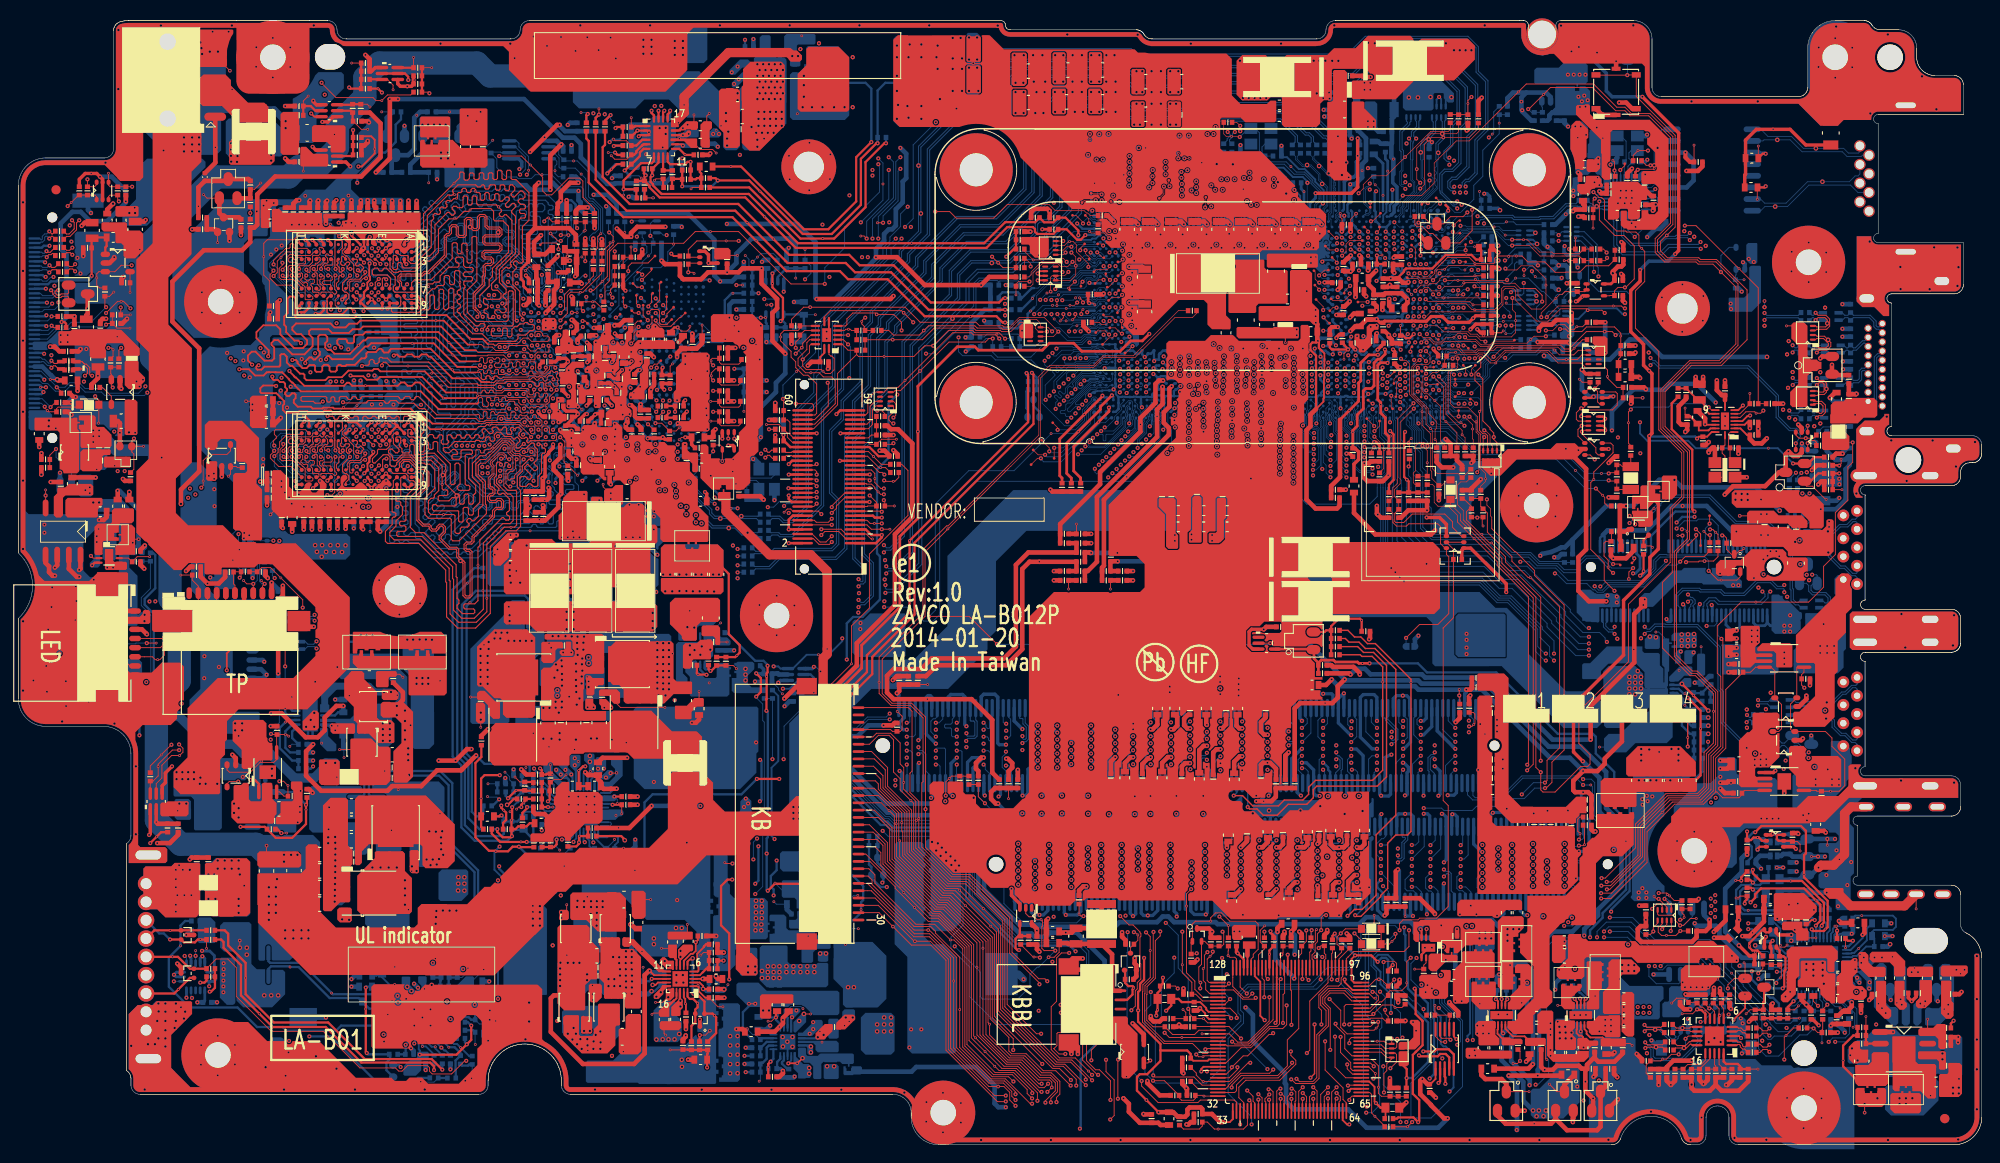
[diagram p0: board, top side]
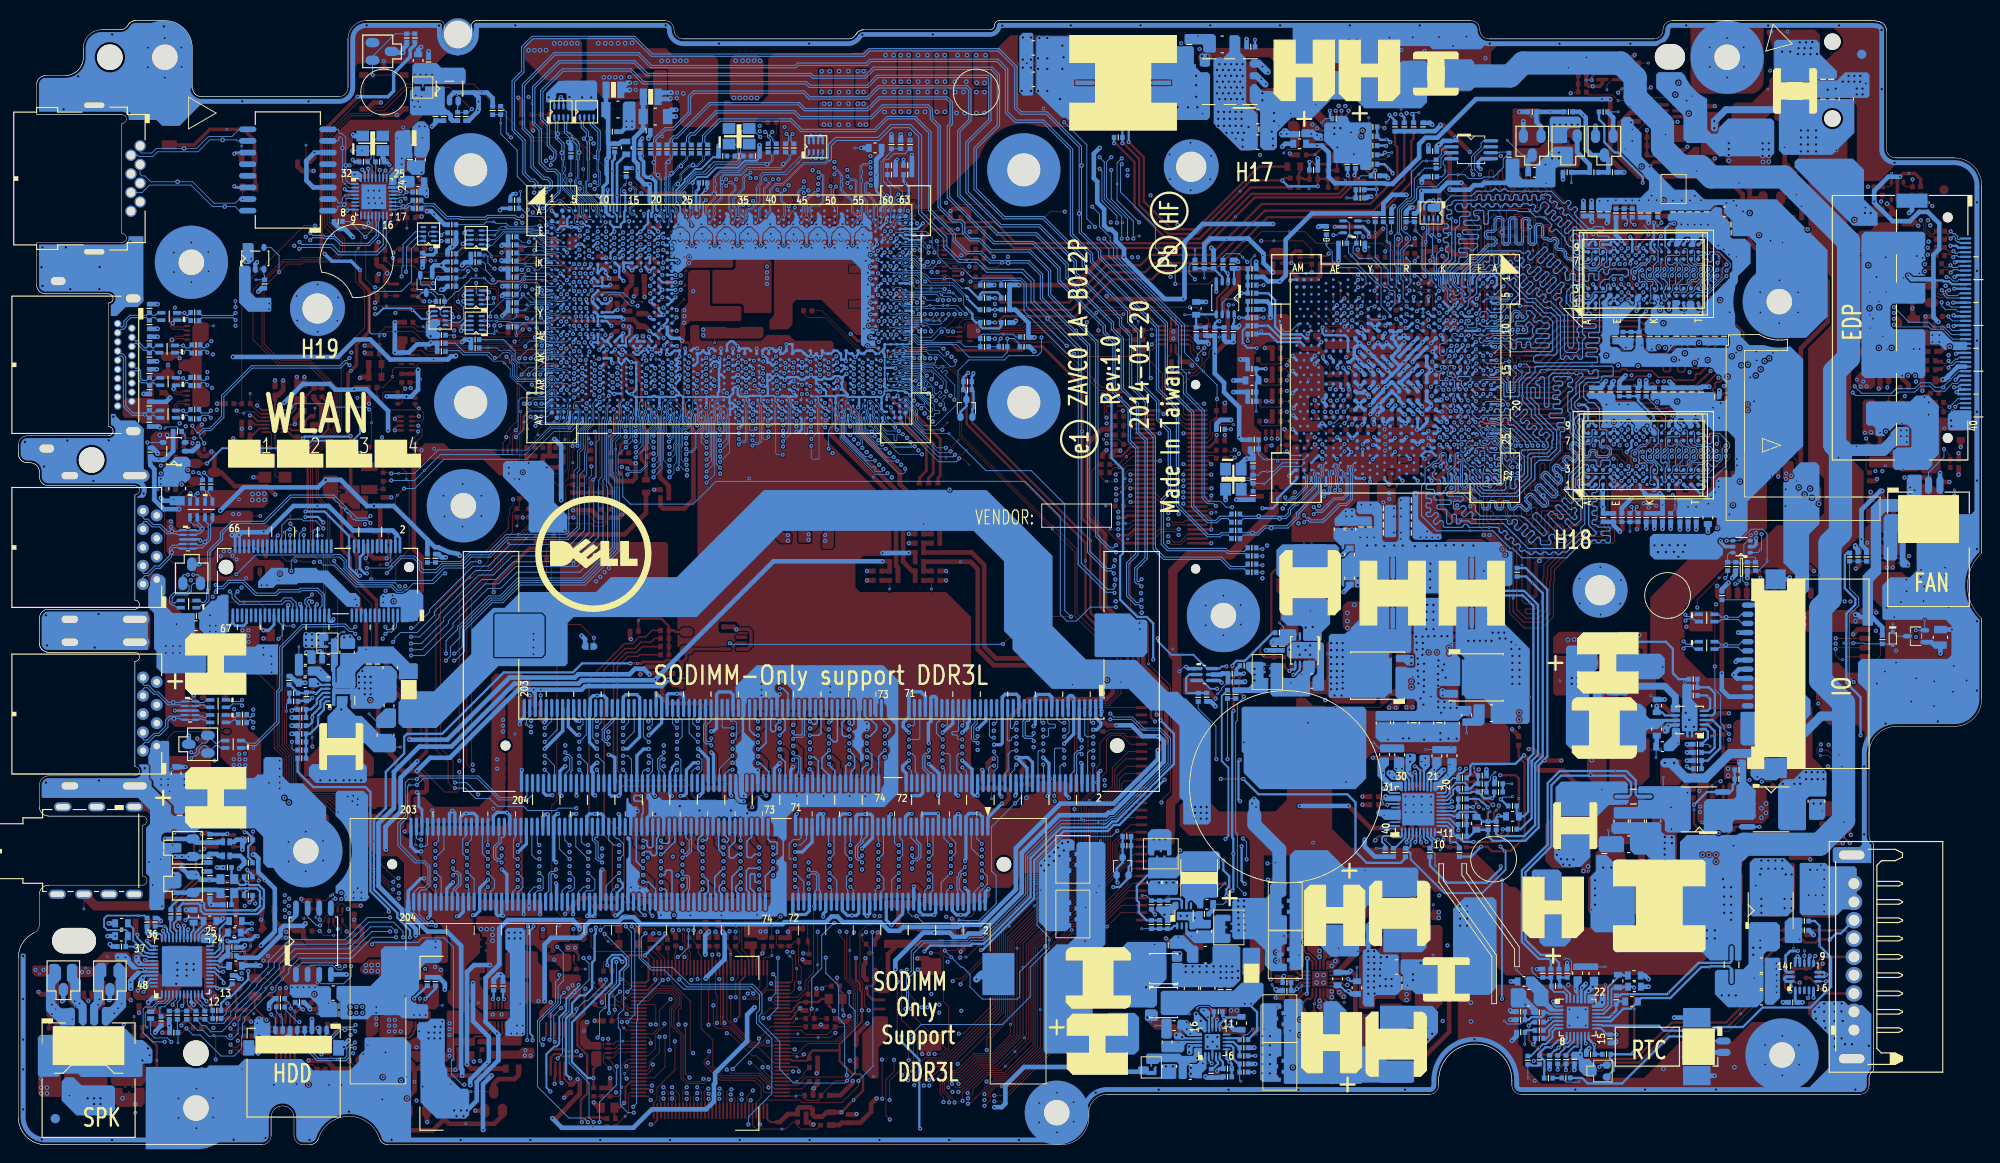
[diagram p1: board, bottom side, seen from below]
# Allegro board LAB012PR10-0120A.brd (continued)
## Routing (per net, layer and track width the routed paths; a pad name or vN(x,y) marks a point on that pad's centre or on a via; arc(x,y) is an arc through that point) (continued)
N17932877: length 2.5
  TOP w0.102: v1(22.94,73.03) 23.17,73.26 UX4.3 23.81,74.08 23.92,73.97 RX10.2
N17933206: length 62.1
  TOP w0.254: v2(52.74,37.05) 52.74,37.05 52.74,36.8 v1(53,36.54) 53.27,36.28 53.27,35.49 52.94,35.16 PR1053.2
  IN2 w0.254: v2(63.56,60.13) 63.56,60.25 64.06,60.76 64.7,60.76 65.08,60.38 68.13,60.38 68.76,61.02 68.76,63.68 68.26,64.19 53.22,64.19 48.56,59.53 48.56,51.12 48.98,50.7 48.98,46.07 53.1,41.94 53.1,40.83 53.7,40.23 53.7,39.31 52.99,38.61 52.99,37.49 52.74,37.23 v2(52.74,37.05)
  BOTTOM w0.254: v2(63.56,60.13) 64.32,60.89 PL1003.3
N17933209: length 1.7
  IN2 w1.016: 62.55,52.49 62.55,50.77
  vias: v1(62.12,51.11) v2(62.27,50.61) v3(62.27,53.23) v3(62.29,52.6) v3(62.27,49.99)
N17933219: length 1.2
  TOP w0.102: PC1044.1 v1(74.34,49.5)
N17933234: length 1.4
  BOTTOM w0.102: v1(66.39,43.92) 65.77,43.3 PR1055.2
N17933249: length 6.1
  TOP w0.102: PQ1005.4 65.33,48.19 65.75,47.77 v1(70.61,47.77)
N17933268: length 3.5
  TOP w0.254: PC1302.1 74.1,51.49 v1(74.22,51.36) 75.13,51.36 v2(75.15,51.34)
  BOTTOM w0.254: PU1300.7 74.46,51.89 75.01,51.34 v2(75.15,51.34)
N17933717: length 2.1
  BOTTOM w0.102: v1(188.45,94.49) RL40.2 187.51,94.96 187.57,95.03 UL3.3
N17936926: length 3.4
  BOTTOM w0.102: v1(198.39,78.27) 198.25,78.41 197.07,78.41 RM10.2 196.19,77.53 196.19,76.72 UM1.3
N17938093: length 10
  TOP w0.254: PU501.7 69.41,107.47 69.17,107.23 68,107.23 66.1,105.33 v2(66.1,104.37) PR537.2 67.49,103.48 PR533.2
  BOTTOM w0.102: v2(66.1,104.37) v1(66.1,103.74)
  BOTTOM w0.254: PR543.2 67.37,104.37 v2(66.1,104.37)
N17945375: length 2.6
  TOP w0.102: CX9.1 9.19,82.73 10.16,81.76 UX1.4
N17984356: length 2.7
  BOTTOM w0.102: QS1.1 9.26,55.55 DS1.1 v1(9.71,56.91)
N18923200: length 2.4
  TOP w0.102: v1(178.44,65.26) 178.29,65.41 RC10.1
  TOP w0.254: RC10.1 177.48,66.04 DC1.2
N19505504: length 1.3
  TOP w0.076: v2(154.49,88.45) 154.97,87.96 T117.1
  BOTTOM w0.076: v2(154.49,88.45) 154.19,88.75 UC1.AD4
N19607621: length 5.9
  TOP w0.102: v1(197.41,70.49) 197.36,70.49 195.91,71.94 195.27,71.94 195.06,72.15 QX5.2
  TOP w0.254: RX15.1 196.55,73.33 195.72,72.5 195.07,72.5 QX5.2
N19636367: length 26.5
  TOP w0.254: QA6.2 190.43,33.2 190.07,33.56 v1(189.92,33.56) 189.49,33.56 189.21,33.28 RA7.2 v2(188.78,34.22)
  IN1 w0.254: v2(188.78,34.22) 189.49,33.51 190.06,33.51 190.81,32.76 190.81,26.22 189.59,24.99 189.59,23.47 188.78,22.66 188.78,20.63 189.3,20.11 v2(189.3,18.95)
  BOTTOM w0.254: v2(189.3,18.95) 189.3,18.05 191.29,16.06 191.62,16.06 192.26,15.42 RA6.2
N19792312: length 5.6
  TOP w0.254: QA5.5 191.32,23.36 191.16,23.19 190.84,23.19 190.67,23.36 QA5.6 190.49,23.48 189.03,22.03 v1(189.03,21.72) 189.03,21.54 189.36,21.21 189.92,21.21 RA2.2
N19794620: length 4.7
  TOP w0.102: RA5.2 194.27,33.13 194.57,32.82 v1(194.57,32.08)
  TOP w0.254: QA6.6 192.14,33.85 192.03,33.74 192.03,33.38 192.21,33.2 QA6.5 193.66,33.2 RA5.2
N21178712:
  vias: v1(34.52,110.37)
N22753332: length 6.4
  IN2 w0.762: 78.16,115.75 75.75,113.34 75.75,110.55 v2(75.88,110.42)
  vias: v1(76.21,110.82) v2(76.51,110.42) v2(78.16,115.88) v2(78.67,116.39)
N22753389: length 1.5
  TOP w0.102: PC525.1 75.18,112.37 v1(75.46,112.65)
N22753454: length 30.9
  TOP w0.254: v2(65.16,108.39) 65.42,108.13 PR525.1
  IN1 w0.254: v2(65.16,108.39) 64.93,108.62 64.68,108.62 63.94,109.36 63.94,110.36 63.1,111.2 62.91,111.2 61.58,112.53 61.58,113.26 63.05,114.74 71.25,114.74 77.22,120.71 v2(79.36,120.71)
  BOTTOM w0.102: v2(65.16,108.39) v1(64.42,108.39)
  BOTTOM w0.254: v2(65.16,108.39) 65.42,108.13 PR525.1 ; PH500.1 v2(79.36,120.71)
N22753537: length 36.7
  TOP w0.254: PR536.2 v1(77.81,106.86) 78.92,106.86 85.78,100 88.45,100 91.5,103.05 91.5,107.88 v2(93.15,109.53)
  BOTTOM w0.254: v2(93.15,109.53) 93.15,115.37 92.51,116.01 PL502.2
N22753594: length 3.3
  TOP w0.254: v2(71.18,112.96) 71.18,112.83 70.91,112.57 PU501.17
  BOTTOM w0.102: v1(72.09,111.64) 71.63,112.09 PR507.1
  BOTTOM w0.254: v2(71.18,112.96) 71.18,112.32 PR507.1
N22753687: length 1.9
  TOP w0.102: PR533.1 v1(69.37,103.43)
  TOP w0.254: PR533.1 68.38,103.51 PC522.2
N22753703: length 1.8
  BOTTOM w0.102: PC527.2 v1(69.27,103.43)
  BOTTOM w0.254: PR543.1 PC527.2
N22753707: length 4.3
  TOP w0.254: v2(64.32,106.1) v1(64.79,106.57) 65.33,107.12 PR539.1
  BOTTOM w0.254: v2(64.32,106.1) 64.32,106.23 65.21,107.12 PR539.1
N22753760: length 2.6
  TOP w0.254: 70.41,106.43 71.43,106.43 PR535.1 ; 70.41,106.43 PC523.1 ; 70.41,106.43 PU501.9
N22753762: length 2
  TOP w0.102: PC523.2 69.63,105.52 v1(69.48,105.36)
  TOP w0.254: PR545.2 70.41,104.63 PC523.2
N22753790: length 29.4
  TOP w0.254: v2(94.75,109.4) 94.57,109.4 92.51,107.34 92.51,102.42 89.08,98.99 v1(87.84,98.99) 85.4,98.99 79.81,104.58 PR551.1
  BOTTOM w0.254: PH501.2 v2(94.75,109.4)
N22763740: length 15.1
  BOTTOM w0.254: PR708.2 39.52,16.29 39.36,16.44 34.35,16.44 34.22,16.57 ; PR716.2 27.31,20.06 27.5,19.87 30.92,19.87 34.22,16.57 ; 34.22,16.57 v1(34.21,16.57)
N22763755:
  vias: v1(17.41,36.48) v3(17.58,37.27) v3(18.34,37.27)
N22763812:
  vias: v1(19.87,22.43)
N22763830: length 6.4
  BOTTOM w0.203: PU701.20 41.35,14.7 40.81,15.24 v1(40.81,15.7) 40.81,17.2 39.72,18.29 PR710.2
  BOTTOM w0.254: PR710.2 39.19,18.57 39.1,18.48 PC719.2
N22763871: length 36.7
  BOTTOM w0.254: PR702.2 37.52,38.03 37.78,38.28 37.78,39.81 38.79,40.82 v1(40.01,40.82) 46.07,40.82 47.39,39.5 47.39,32.78 50.21,29.96 50.21,22.17 48.35,20.31 47.25,20.31 47.05,20.11 PR717.2
N22763875: length 35.3
  BOTTOM w0.254: PR702.3 38.54,38.03 38.28,38.28 38.28,39.55 39.05,40.31 v1(42.72,40.31) 45.94,40.31 46.98,39.27 46.98,32.61 49.82,29.77 49.82,22.38 48.16,20.73 47.02,20.73 46.16,19.87 PR704.2
N22763935: length 0.8
  BOTTOM w0.102: 40.73,33.52 40.75,33.53 v1(40.75,34.35)
N22764104: length 3.1
  BOTTOM w0.102: PR701.2 45.4,6.84 44,6.84 v1(43.95,6.89)
  BOTTOM w0.254: PR701.2 45.87,7.28 PC701.1
N22764115: length 2.9
  BOTTOM w0.102: v1(49.5,7.26) 49.56,7.32 PC727.1
  BOTTOM w0.254: PR726.2 48.46,8.64 49.1,8.64 49.23,8.77 PC727.1
N22764126: length 1.9
  BOTTOM w0.203: PU701.4 47.02,13.9 v2(47.2,13.72) 47.53,13.39 PR727.2
N22764133: length 2.5
  BOTTOM w0.102: v1(49.9,10.95) 49.88,10.98 PC728.2
  BOTTOM w0.254: PR728.1 49.66,12.5 PC728.2
N22764201: length 3.9
  TOP w0.381: v1(15.06,35.24) PQ706.2
  TOP w0.508: v1(15.06,35.24) 15.24,35.06 PC723.1 PR724.2
N22764304:
  vias: v1(41.48,38.79)
N22892968: length 2.9
  TOP w0.102: PR538.2 74.46,108.72 75.82,108.72 v1(76.21,108.34)
N22894348: length 2.3
  TOP w0.254: PR512.1 72.83,108.13 v1(72.8,108.16) 72.17,108.79 PU501.11
N23700314: length 9.4
  TOP w0.508: PR11.1 25.13,105.49 PQ6.1 22.72,105.29 PL2.1 19.67,104.58 v1(19.67,102.52) PR6.2
N23711299:
  vias: v1(208.82,5.36)
N23711301: length 4.5
  TOP w0.102: PR400.2 v1(201.76,14)
  TOP w0.254: PR400.2 PC403.2 PR401.1 PU400.2
N23711331: length 1.4
  TOP w0.102: PU400.8 v1(208.5,13.71)
N37640332: length 10.7
  TOP w0.102: v2(61.91,96.52) RV2.2
  IN2 w0.127: v2(61.91,96.52) 61.91,96.46 61.32,95.87 61.32,94.7 61.1,94.48 61.1,93.58 61.42,93.27 61.42,92 60.87,91.45 60.87,89.75 61.29,89.34 v2(61.65,89.34)
  BOTTOM w0.102: UV1.N10 61.21,88.9 v2(61.65,89.34) ; v1(61.54,96.98) 61.91,96.61 v2(61.91,96.52)
N37640410: length 1.4
  TOP w0.508: RV3.1 68,78.3 v2(67.62,78.69)
  BOTTOM w0.381: v2(67.62,78.69) 67.4,78.91 UV1.AA22
N37817724: length 2.4
  TOP w0.508: v1(66.51,79.27) 66.51,78.89 v2(66.34,78.72) 66.34,78.35 66.58,78.11 RV1.1
  BOTTOM w0.381: UV1.Y22 66.34,79.24 v2(66.34,78.72)
N38023415: length 3
  TOP w0.102: v1(66.91,98.07) CV96.1 RV36.2 RV37.2
N38028869: length 8.8
  TOP w0.102: v2(59.2,90.05) 59.2,90.06 59.95,90.81 59.95,92.79 60.28,93.12 v1(61.37,93.12) 61.65,93.12 63.68,95.15 CV98.2
  BOTTOM w0.102: UV1.K8 58.8,90.45 v2(59.2,90.05)
N38028873: length 7.8
  TOP w0.102: CV99.2 62.79,94.9 v1(62.34,94.44) 62.34,94.26 61.52,93.45 60.23,93.45 59.65,92.87 59.65,91.29 v2(59.2,90.85)
  BOTTOM w0.102: v2(59.2,90.85) 59.65,91.3 UV1.L7
N38028878: length 2.4
  TOP w0.102: v1(64.62,98.53) 64.62,98.4 63.73,97.51 RV40.2 CV98.1
N38028880: length 3.3
  TOP w0.102: v1(63.61,99.52) 63.26,99.18 63.26,97.96 62.79,97.49 RV41.2 CV99.1
N38039273: length 5.1
  BOTTOM w0.102: UV5.L8 34.95,77.84 34.52,78.27 34.52,79.58 v1(35.5,80.56) 36.63,81.69 RV46.1
N38046520: length 2.8
  BOTTOM w0.102: CV102.1 RV48.2 ; RV48.2 RV49.2 ; RV48.2 v1(38.41,67.01)
N38049955: length 5.1
  TOP w0.102: v2(33.74,70.97) 34.27,70.97 34.55,71.25 34.55,72.52 UV6.L8
  BOTTOM w0.102: RV47.1 33.48,69.45 v1(33.48,69.84) 33.48,70.72 v2(33.74,70.97)
N38097860: length 1.8
  BOTTOM w0.102: CV135.1 RV54.2 RV55.2
N38342282: length 5.6
  TOP w0.102: v2(59.17,77.29) 59.6,76.87 59.68,76.78 59.68,76.32 59.59,76.23 59.59,74.58 RV39.2 60.03,74.17 v1(61.07,73.13)
  BOTTOM w0.102: UV1.K25 58.8,76.91 v2(59.17,77.29)
N46660696:
  vias: v1(85.55,121.14)
N47007806: length 3.7
  TOP w0.102: v1(38.4,113.36) 38.09,113.67 PR28.2
  TOP w0.254: PQ2.3 36.44,113.61 PC16.1 PR28.2
N47007810: length 4.7
  TOP w0.102: PR29.1 37.45,110.93 v1(38.16,110.93)
  TOP w0.254: PQ2.2 36.3,112.96 PC16.2 36.51,111.87 PR29.1
N47007850: length 4.5
  TOP w0.102: v1(31.65,114.56) 31.12,114.02 PR33.2
  TOP w0.254: PR31.1 PR33.2 31.93,113.47 32.44,112.96 PQ2.5
N47007898: length 4.4
  BOTTOM w0.102: PR32.1 83.01,49.86 83.01,49.69 v1(83.45,49.25)
  BOTTOM w0.508: PQ3.5 83.05,51.36 82.92,51.49 82.86,51.49 PC14.2 PR32.1
N47008006: length 1
  TOP w0.102: PR10.2 v1(31.12,106.35)
N47008110: length 5.2
  BOTTOM w0.254: PQ3.2 86.52,51.36 86.87,51.01 v1(86.87,49.38) 86.82,49.33 PR30.2 85.54,49.34 PC15.1
N47415217: length 1.1
  TOP w0.102: v1(73.06,24.06) 73.06,22.96
N47415258: length 1.6
  TOP w0.102: PR113.2 v1(69.04,26.78)
N47415272:
  vias: v1(66.07,10.16)
N47415370: length 1.1
  TOP w0.102: v1(70.69,11.97) 70.52,12.15 PR111.2
N47420895:
  vias: v1(87.71,22.66)
N47445410: length 2.3
  TOP w0.203: PU100.19 72.67,16.09 72.83,15.93 72.83,15.42 v1(72.85,15.4) 72.9,15.35 PR114.1
N47894294: length 1.8
  TOP w0.102: CC8.2 v1(119.26,60.7)
  TOP w0.508: RC23.1 CC8.2
N47894380: length 1.9
  TOP w0.102: RC24.1 v1(115.55,67.8)
  TOP w0.508: CC9.2 RC24.1
N47894401: length 1.8
  TOP w0.102: RC25.1 v1(114.69,60.7)
  TOP w0.508: CC10.2 RC25.1
N47938591: length 2.6
  TOP w0.076: v2(150.88,83.63) 150.51,83.27 150.51,81.81 T118.1
  BOTTOM w0.076: v2(150.88,83.63) 150.55,83.96 UC1.AN10
N47938593: length 1.9
  TOP w0.076: T119.1 150.22,83.63 v2(150.88,84.28)
  BOTTOM w0.076: UC1.AM10 150.55,84.61 v2(150.88,84.28)
N47938689: length 1.2
  TOP w0.076: v2(147.39,99.74) 147.39,99.87 T120.1
  BOTTOM w0.076: v2(147.39,99.74) 147.75,99.42 UC1.E15
N47938710: length 1.2
  TOP w0.076: T121.1 148.65,99.97 v2(148.35,99.68)
  BOTTOM w0.076: UC1.E13 148.6,99.42 148.37,99.65 148.37,99.66 v2(148.35,99.68)
N47964855: length 5.8
  TOP w0.076: T153.1 114.81,93.73 v2(115.37,94.29)
  BOTTOM w0.076: UC1.L60 119.16,95.26 118.69,95.26 118.64,95.31 117.87,95.31 117.7,95.14 116.15,95.14 115.37,94.37 v2(115.37,94.29)
N47964866: length 1.4
  TOP w0.076: T154.1 118.75,94.93 v2(119.21,94.47)
  BOTTOM w0.076: UC1.N60 119.46,94.72 v2(119.21,94.47)
N47964871: length 2.1
  TOP w0.076: v2(142.49,91.18) 142.49,91.56 T155.1
  BOTTOM w0.076: v2(142.49,91.18) 142.67,91.36 UC1.W23
N47964873: length 1.5
  TOP w0.076: v2(143.95,91.45) 143.54,91.45 T156.1
  BOTTOM w0.076: v2(143.95,91.45) 143.53,91.03 UC1.Y22
N47964879: length 10.1
  TOP w0.076: v2(112.58,75.75) 112.58,76.13 T157.1
  BOTTOM w0.076: UC1.AV62 117.82,80.37 117.35,80.37 117.05,80.08 117.05,78.75 113.9,75.59 112.73,75.59 v2(112.58,75.75)
N47964884: length 4.5
  TOP w0.076: v2(120.24,102.98) 119.38,102.98 T158.1
  BOTTOM w0.076: v2(120.24,102.98) 120.6,102.62 120.6,101.48 120.52,101.4 120.52,100.21 120.8,99.92 UC1.D58
N47965485: length 8.2
  TOP w0.076: v2(113.11,76.13) T146.1
  BOTTOM w0.076: UC1.AV63 117.41,80.7 116.86,80.16 116.86,78.88 114.11,76.13 v2(113.11,76.13)
N47965487: length 7.1
  TOP w0.076: T147.1 113.49,78.34 v2(113.49,78.09)
  BOTTOM w0.076: UC1.AU63 117.46,81.36 116.78,80.69 116.78,80.59 116.42,80.23 116.42,79.08 115.43,78.09 v2(113.49,78.09)
N47965489: length 1.7
  TOP w0.076: T160.1 144.79,93.18 v2(145.43,93.83)
  BOTTOM w0.076: UC1.P20 145.06,94.2 v2(145.43,93.83)
N47965491: length 3.1
  TOP w0.076: T162.1 143.54,92.23 144.81,92.23 145.39,92.81 v2(145.39,92.99)
  BOTTOM w0.076: UC1.R20 144.99,93.39 v2(145.39,92.99)
N47965493: length 1.7
  TOP w0.076: T159.1 153.4,102.87 v2(153.93,102.87)
  BOTTOM w0.076: UC1.A5 153.59,102.53 v2(153.93,102.87)
N47965495: length 3.3
  TOP w0.076: v2(116.26,100.64) 116.26,100.77 115.5,101.53 T148.1
  BOTTOM w0.076: v2(116.26,100.64) 116.26,100.77 116.64,101.15 117.02,101.15 117.45,100.72 UC1.C63
N47965502: length 1.4
  TOP w0.076: T161.1 156.79,99.59 156.65,99.72 v2(156.65,99.73)
  BOTTOM w0.076: v2(156.65,99.73) 156.44,99.51 UC1.E1
N47965509: length 2.5
  TOP w0.076: T149.1 116.9,101.15 v2(116.9,100.64)
  BOTTOM w0.076: UC1.C62 118.16,100.63 117.91,100.39 117.15,100.39 v2(116.9,100.64)
N47965511: length 1.6
  TOP w0.076: T163.1 157.27,100.96 v2(156.75,100.44)
  BOTTOM w0.076: v2(156.75,100.44) 156.51,100.44 156.25,100.17 UC1.D1
N47965522: length 2.4
  TOP w0.076: v2(129.6,102.39) 129.6,102.54 129.67,102.62 T150.1
  BOTTOM w0.076: UC1.B43 130.27,101.57 129.6,102.24 v2(129.6,102.39)
N47965524: length 3.9
  TOP w0.076: T164.1 145.38,98.77 144.99,98.38 144.99,97.55 v2(144.56,97.12)
  BOTTOM w0.076: UC1.J20 144.86,96.82 v2(144.56,97.12)
N47965529: length 3.5
  TOP w0.076: T151.1 125.63,104.78 v2(125.71,104.7)
  BOTTOM w0.076: UC1.A51 125.25,102.34 125.63,102.72 125.63,104.63 v2(125.71,104.7)
N47965534: length 5.2
  TOP w0.076: T152.1 125.1,103.89 v2(125.1,104.68)
  BOTTOM w0.076: UC1.B51 125.24,101.39 124.95,101.68 124.95,102.49 125.38,102.93 125.38,104.4 v2(125.1,104.68)
N47965536: length 1.2
  TOP w0.076: T165.1 145.65,97.79 v2(145.5,97.79)
  BOTTOM w0.076: v2(145.5,97.79) 145.82,97.47 UC1.H18
N55155843:
  vias: v1(10.52,74.17)
N55200533: length 1.7
  TOP w0.102: RP58.5 v1(193.08,89.45)
N55201771: length 13.7
  TOP w0.102: v2(198.84,74.19) 199.05,74.39 v1(199.05,74.88)
  TOP w0.254: RX12.2 198.81,74.22 v2(198.84,74.19)
  IN1 w0.254: JHDMI.13 202.75,82.9 202.75,80.7 202.11,80.07 201.1,80.07 199.45,78.41 199.45,76.57 198.72,75.85 198.72,74.31 v2(198.84,74.19)
N60531230: length 43.8
  TOP w0.076: v2(127.34,107.75) v1(127.87,107.75)
  IN2 w0.076: v2(151.44,85.27) 151.39,85.32 151.39,86.97 150.55,87.81 149.41,87.81 148.9,88.32 148.9,90.23 149.41,90.73 149.41,91.5 145.98,94.92 145.98,95.94 145.52,96.4 144.51,96.4 143.97,96.93 143.53,96.93 142.89,97.57 142.89,101.31 140.57,103.63 137.27,103.63 136.07,104.83 132.9,104.83 131.76,103.69 130.49,103.69 129.34,104.83 129.34,106.99 128.96,107.37
  IN2 w0.107: 128.96,107.37 128.58,107.75 v2(127.34,107.75)
  BOTTOM w0.076: UC1.AK8 151.52,85.27 v2(151.44,85.27)
  BOTTOM w0.102: RP41.3 127.06,108.03 v2(127.34,107.75)
N60531232: length 46.4
  TOP w0.076: v2(126.68,107.75) v1(126.68,108.31)
  IN2 w0.076: v2(151.44,84.61) 151.54,84.61 151.82,84.89 151.82,85.4 151.57,85.65 151.57,87.05 150.55,88.07 149.41,88.07 149.15,88.32 149.15,89.84 149.66,90.35 149.66,91.62 146.87,94.42 146.87,95.81 146.11,96.58 144.58,96.58 144.02,97.13 143.64,97.13 143.06,97.72 143.06,101.4 140.65,103.81 137.37,103.81 136.1,105.08 132.9,105.08 131.76,103.94 130.49,103.94 129.72,104.7 129.72,107.12 129.47,107.37
  IN2 w0.107: 129.47,107.37 128.66,108.18 127.11,108.18 v2(126.68,107.75)
  BOTTOM w0.076: v2(151.44,84.61) 151.76,84.89 151.81,84.93 UC1.AL8
  BOTTOM w0.102: RP41.4 126.56,107.87 v2(126.68,107.75)
N60754677: length 1.2
  TOP w0.076: T111.1 118.29,98.4 v2(118.46,98.23)
  BOTTOM w0.076: v2(118.46,98.23) 118.8,97.89 UC1.H61
N60754679: length 3.5
  TOP w0.076: T112.1 116.01,97.97 116.01,97.77 v2(115.96,97.72)
  BOTTOM w0.076: UC1.H62 117.88,98.14 116.2,98.14 116.01,97.95 116.01,97.77 v2(115.96,97.72)
N60754681: length 1.2
  TOP w0.076: v2(120.6,96.7) 120.34,96.45 T113.1
  BOTTOM w0.076: v2(120.6,96.7) 120.28,96.39 UC1.K59
N60754683: length 2.2
  TOP w0.076: v2(116.54,97.72) 116.54,97.34 116.95,96.93 T114.1
  BOTTOM w0.076: UC1.H63 116.68,97.85 v2(116.54,97.72)
N60754685: length 2.6
  TOP w0.076: T115.1 117.68,95.58 118.88,95.58 119.17,95.88 v2(119.17,95.99)
  BOTTOM w0.076: UC1.K60 119.46,96.28 v2(119.17,95.99)
N60754687: length 2.2
  TOP w0.076: v2(117.81,97.49) 118.4,96.91 T116.1
  BOTTOM w0.076: v2(117.81,97.49) 118.19,97.49 118.62,97.07 UC1.J61
N60931942: length 9
  TOP w0.076: v2(157.98,88.21) 158.2,87.99 159.14,87.99 159.75,87.38 160.71,87.38 161.12,87.79 163.28,87.79 T97.1
  BOTTOM w0.076: v2(157.98,88.21) 157.5,88.69 156.41,88.69 156.26,88.54 155.82,88.54 155.49,88.2 UC1.AF2
N60931944: length 4.8
  TOP w0.076: T99.1 158.03,87.32 v2(157.81,87.32)
  BOTTOM w0.076: v2(157.81,87.32) 157.48,87.65 157.2,87.65 156.93,87.92 156.41,87.92 156.26,87.78 155.95,87.78 155.79,87.61 155,87.61 154.9,87.71 154.51,87.71 UC1.AF4
N60931946: length 2.2
  TOP w0.076: T98.1 156.69,89.21 v2(156.69,89.21)
  BOTTOM w0.076: v2(156.69,89.21) 156.59,89.11 155.78,89.11 UC1.AD2
N61580896: length 4.3
  TOP w0.102: Q2307.1 168,5.8 v1(167.19,6.61)
  TOP w0.508: Q2307.1 168.84,6.57 R2314.2
N61580898: length 7.2
  TOP w0.102: v1(164.98,5.8) Q2308.1
  TOP w0.508: Q2308.1 162.49,6.66 161.98,7.17 160.2,7.17 159.76,7.61 R2315.2
N63469524: length 9.8
  TOP w0.127: v1(187.79,26.93) 188.02,27.16 RA82.1
  TOP w0.254: RA82.1 188.78,26.83 188.52,26.57 v2(188.52,26.34)
  IN2 w0.254: v2(188.91,23.55) 188.65,23.55 188.4,23.8 188.4,24.44 188.91,24.95 189.24,24.95 190.18,25.89 190.18,26.34 189.54,26.98 188.93,26.98 188.52,26.57 v2(188.52,26.34)
  BOTTOM w0.254: CA68.2 189.67,23.17 189.29,23.55 v2(188.91,23.55)
N63469526: length 10.2
  TOP w0.127: v2(188.14,28.86) v1(187.53,28.86)
  TOP w0.254: v2(188.14,28.86) 188.14,29.21 RA80.1
  IN2 w0.254: v2(188.14,28.86) 188.14,27.87 188.65,27.36 189.92,27.36 190.56,26.73 190.56,25.71 189.03,24.19 v2(188.91,24.19)
  BOTTOM w0.254: v2(188.91,24.19) 189.73,24.19 CA67.2
N63642793: length 17.4
  TOP w0.305: v2(149.23,86.87) 149.26,86.85 149.26,86.36 148.71,85.82 148.46,85.82 148.05,85.41 148.05,82.9 147.76,82.61 147.12,82.61 146.87,82.35 146.87,80.4 146.21,79.73 146.21,78.52 145.73,78.03 v1(145.73,77.83) C51.1
  TOP w0.381: R264.2 145.85,74.35 146.36,74.86 146.36,75.69 145.98,76.07 145.72,76.07 C51.1
  BOTTOM w0.254: v2(149.23,86.87) 149.26,86.87 149.57,86.56 UC1.AH11
N63656577: length 1.8
  TOP w0.076: v2(142.53,90.39) 143.17,89.74 T38.1
  BOTTOM w0.076: v2(142.53,90.39) 142.53,90.23 143.02,89.73 UC1.AB23
N63657072: length 1.8
  TOP w0.076: v2(119.83,94.47) 119.04,93.68 T39.1
  BOTTOM w0.076: UC1.P60 119.46,94.1 v2(119.83,94.47)
N63657081: length 1.6
  TOP w0.076: v2(118.51,94.48) 117.98,94.48 T40.1
  BOTTOM w0.076: v2(118.51,94.48) 118.81,94.18 UC1.P61
N63657090: length 1.1
  TOP w0.076: v2(120.52,95.2) 120.35,95.2 T41.1
  BOTTOM w0.076: UC1.N59 120.21,94.89 v2(120.52,95.2)
N63657099: length 4
  TOP w0.076: v2(116.21,94.28) 116.03,94.1 T42.1
  BOTTOM w0.076: UC1.N61 118.65,94.89 118.4,95.15 117.96,95.15 117.82,95.01 117.82,94.74 117.63,94.56 117.34,94.56 117.15,94.74 116.63,94.74 116.21,94.33 v2(116.21,94.28)
N63657120: length 1
  TOP w0.076: v2(119.81,92.98) 120.15,93.32 T43.1
  BOTTOM w0.076: UC1.T59 120.11,93.28 v2(119.81,92.98)
N63657126: length 2.2
  TOP w0.076: v2(119.11,88.5) 118.7,88.9 117.84,88.9 T44.1
  BOTTOM w0.076: v2(119.11,88.5) 119.46,88.85 UC1.AD60
N63657135: length 2.1
  TOP w0.076: T45.1 119.8,89.23 120.43,88.6 v2(120.52,88.6)
  BOTTOM w0.076: UC1.AD59 120.13,88.9 120.43,88.6 v2(120.52,88.6)
N63657146: length 1.3
  TOP w0.076: T46.1 120.46,89.35 v2(120.46,89.99)
  BOTTOM w0.076: UC1.AA59 120.15,90.4 120.46,90.09 v2(120.46,89.99)
N63657155: length 2.4
  TOP w0.076: v2(119.81,88.49) 119.46,88.14 119.11,88.14 T47.1
  BOTTOM w0.076: v2(119.81,88.49) 119.46,88.14 UC1.AE60
N63657164: length 2.2
  TOP w0.076: T48.1 118.65,90.5 119.39,90.5 119.81,90.08 v2(119.81,89.99)
  BOTTOM w0.076: v2(119.81,89.99) 119.81,89.87 UC1.AC59
N63657173: length 2.4
  TOP w0.076: v2(121.67,87.23) 120.93,86.49 T49.1
  BOTTOM w0.076: UC1.AG58 120.79,87.03 120.83,87.08 121.51,87.08 v2(121.67,87.23)
N63657182: length 2.3
  TOP w0.076: v2(120.53,92.84) 120.26,92.57 119.39,92.57 T50.1
  BOTTOM w0.076: v2(120.53,92.84) 120.26,92.57 UC1.U59
N63657191: length 1.3
  TOP w0.076: T51.1 120.02,91.04 v2(120.46,91.48)
  BOTTOM w0.076: v2(120.46,91.48) 120.11,91.83 UC1.V59
N64564173: length 2.4
  BOTTOM w0.102: v1(35.57,42.3) 35.55,42.31 PR1101.2
  BOTTOM w0.508: PC1103.1 35.49,43.55 PR1101.2
N64564191: length 1.2
  TOP w0.102: PC1106.1 41.66,51.39 v1(41.99,51.06)
N64734520: length 1.1
  TOP w0.076: T107.1 152.02,87.02 152.02,86.64 v2(152.02,86.64)
  BOTTOM w0.076: v2(152.02,86.64) 152.2,86.45 UC1.AJ7
N64734538: length 1.5
  TOP w0.076: T105.1 153.75,84.95 153.68,84.87 v2(153.68,84.87)
  BOTTOM w0.076: UC1.AL5 153.24,85.26 153.63,84.87 153.68,84.87 v2(153.68,84.87)
N177530291: length 5.5
  BOTTOM w0.102: QV4.1 50.18,108.11 v1(51.81,109.73)
  BOTTOM w0.508: RV24.2 49.52,107.66 QV4.1
N188017740: length 3.3
  TOP w0.102: v1(40.93,115.24) 40.93,115.75 40.31,116.37 PQ4.3
  TOP w0.254: PR36.1 39.69,116.39 PQ4.3
N188020320: length 2.9
  TOP w0.102: v1(43.16,118.77) PR27.1
  TOP w0.254: PR27.1 41.45,117.66 PQ4.6

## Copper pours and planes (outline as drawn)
1.35V_B+ on BOTTOM (solid shape): 81.72,16.82 89.44,16.82 89.64,16.62 89.64,14.33 89.46,14.15 86.8,14.15 85.91,15.04 85.9,15.04 85.88,15.06 85.79,15.12 85.67,15.14 85.64,15.15 85.53,15.27 84.31,15.27 84.08,15.04 79.76,15.04 78.42,16.39 78.42,17.5 78.62,17.71 80.83,17.71
3/5V_B+ on TOP (solid shape): 62.4,23.69 62.4,22.41 63.44,21.37 63.44,19.96 63.19,19.7 63.19,18.13 63.13,18.06 62.54,18.06 61.91,17.43 61.91,14.79 61.78,14.66 59.62,14.66 58.87,15.41 58.87,23.73 59.14,24 62.03,24 62.03,24.01 62.08,24.01
3/5V_B+ on BOTTOM (solid shape): 63.43,20.12 63.43,19.99 63.44,19.98 63.44,18.74 63.18,18.47 63.18,17.01 63.02,16.86 62.2,16.86 61.78,16.44 59.11,16.44 58.87,16.68 58.87,19.88 59.24,20.25 63.3,20.25
3VALW_PCH on TOP (solid shape): 159.25,17.82 159.28,17.81 159.3,17.77 159.3,17.51 159.8,17.51 159.8,17.77 159.82,17.81 159.85,17.82 160.05,17.82 160.08,17.81 160.1,17.77 160.1,17.51 160.6,17.51 160.6,17.77 160.62,17.81 160.65,17.82 161.23,17.82 161.35,17.71 161.35,16.31 161.33,16.27 161.3,16.26 160.99,15.9 161.3,15.55 161.32,15.55 161.35,15.52 161.35,14.91 161.22,14.79 159.57,14.79 158.68,15.68 158.68,17.71 158.79,17.82
3VS on TOP (solid shape): 172.93,19.92 172.93,17.07 172.64,16.78 172.64,14.9 172.52,14.79 171.38,14.79 171.25,14.91 171.25,15.57 171.26,15.6 171.29,15.62 171.53,15.96 171.29,16.29 171.26,16.31 171.25,16.34 171.25,19.92 171.38,20.04 172.8,20.04
3VS_GATE on TOP (solid shape): 174.86,11.61 175.42,11.61 175.55,11.49 175.55,10.82 175.44,10.72 172.9,10.72 172.78,10.85 172.78,11.49 172.9,11.61 173.28,11.61
5VS on TOP (solid shape): 168.9,17.58 168.93,17.57 168.95,17.53 168.95,17.38 169.45,17.38 169.45,17.53 169.47,17.57 169.5,17.58 169.7,17.58 169.73,17.57 169.75,17.53 169.75,17.38 170.25,17.38 170.25,17.53 170.27,17.57 170.3,17.58 170.62,17.58 170.74,17.45 170.74,17.2 169.98,16.44 169.98,16.34 169.97,16.3 169.94,16.29 169.6,15.95 169.9,15.58 169.91,15.58 169.98,15.5 169.98,14.91 169.86,14.79 168.84,14.79 168.46,15.17 168.46,17.45 168.59,17.58
5VS_GATE on TOP (solid shape): 171.56,11.38 172.42,11.38 172.52,11.28 172.52,10.91 172.4,10.79 171.81,10.79 171.43,10.41 170.48,10.41 170.24,10.64 170.24,11.55 170.36,11.68 171.27,11.68
+0.675VS on TOP (solid shape): outline of 1534 points within 159.31,27.39 170.64,49.08
+0.675VS on BOTTOM (solid shape): 90.3,8.56 90.34,8.55 90.35,8.51 90.35,8.06 90.99,8.06 90.99,8.51 91,8.55 91.04,8.56 92,8.56 92.13,8.44 92.13,7.8 92,7.68 90.15,7.68 90.11,7.69 90.1,7.73 90.1,8.51 90.11,8.55 90.15,8.56
+0.675VSP on BOTTOM (solid shape): 86.04,10.47 86.04,9.83 86.16,9.71 87.31,9.71 87.56,9.96 91.12,9.96 91.24,9.83 91.24,8.95 91.12,8.82 89.97,8.82 89.72,9.07 87.94,9.07 87.69,8.82 87.69,7.29 87.56,7.17 86.92,7.17 86.8,7.29 86.8,8.56 86.42,8.95 85.83,8.95 85.15,9.63 85.15,10.47 85.27,10.6 85.91,10.6
+1.05V on TOP (solid shape): 165.31,19.33 165.31,16.11 163.96,14.76 162.74,14.76 162.64,14.86 162.64,15.5 162.71,15.57 162.75,15.58 162.8,15.61 162.84,15.65 162.88,15.69 162.91,15.74 162.93,15.79 162.94,15.84 162.95,15.89 162.95,15.95 162.93,16 162.92,16.04 162.92,16.26 164.01,17.35 164.01,17.71 164.39,17.71 164.39,17.66 164.4,17.6 164.42,17.55 164.44,17.5 164.47,17.46 164.51,17.42 164.55,17.39 164.6,17.36 164.65,17.34 164.7,17.33 164.75,17.33 164.8,17.33 164.86,17.34 164.91,17.36 164.95,17.39 164.99,17.42 165.03,17.46 165.06,17.5 165.08,17.55 165.1,17.6 165.11,17.66 165.11,17.71 165.1,17.76 165.08,17.81 165.06,17.86 165.03,17.91 164.99,17.94 164.95,17.98 164.91,18 164.86,18.02 164.8,18.04 164.75,18.04 164.7,18.04 164.65,18.02 164.6,18 164.55,17.98 164.51,17.94 164.47,17.91 164.44,17.86 164.42,17.81 164.4,17.76 164.39,17.71 164.01,17.71 164.01,18.75 163.48,18.75 163.43,18.8 163.43,19.51 163.65,19.73 164.92,19.73
+1.05V_LDO_3V on BOTTOM (solid shape): 182.68,50.86 182.68,50.09 182.56,49.97 181.67,49.97 181.54,50.09 180.27,50.09 180.27,50.35 181.29,50.35 181.92,50.98 182.56,50.98
+1.5VS on TOP (solid shape): 201.62,5.64 203.02,5.64 203.02,6.21 203.78,6.21 203.97,6.02 203.97,4.58 203.51,4.12 200.98,4.12 200.6,4.5 200.6,6.02 200.79,6.21 201.62,6.21
+1.05VS on TOP (solid shape): outline of 249 points within 162.61,12.09 176.46,36.12
+1.05VS_APLLOPI on TOP (solid shape): 135.57,89.24 137.05,89.24 137.05,89.34 139.77,89.34 139.83,89.28 139.83,88.17 139.73,88.07 133.28,88.07 133.03,88.32 133.03,89.21 133.15,89.34 135.57,89.34
+1.05VS_APLLOPI on IN1 (solid shape): outline of 134 points within 139.25,88.07 144.84,90.99
+1.05VS_AXCK_DCB on TOP (solid shape): 141.92,97.21 141.92,95.94 141.79,95.81 136.45,95.81 136.33,95.94 136.33,97.21 136.45,97.34 141.79,97.34
+1.05VS_AXCK_DCB on IN1 (solid shape): outline of 134 points within 140.65,95.81 145.73,97.34
+1.05VS_AXCK_LCPLL on TOP (solid shape): 145.09,117.15 145.09,106.35 145.6,105.85 145.6,105.47 145.47,105.34 143.69,105.34 142.93,106.1 142.93,112.19 142.94,112.2 142.96,112.32 142.94,112.45 142.93,112.46 142.93,113.85 143.02,113.93 143.04,113.94 143.07,113.94 143.22,113.92 143.36,113.97 143.37,113.97 143.44,113.97 143.57,114.1 143.57,114.18 143.57,117.28 143.69,117.4 144.84,117.4
+1.05VS_GATE on TOP (solid shape): 166.81,11.55 166.81,10.91 166.68,10.79 164.65,10.79 164.52,10.91 164.52,11.55 164.65,11.68 166.68,11.68
+1.05VS_PCH on TOP (solid shape): 110.83,89.54 110.83,88.24 110.67,88.09 109.53,88.09 109.3,88.32 109.3,89.39 109.61,89.69 110.67,89.69
+1.05VS_PCH on TOP (solid shape): 112.53,98.99 112.53,97.18 112.25,96.91 111,96.91 110.45,97.46 110.45,98.2 110.32,98.33 109.58,98.33 109.51,98.4 109.51,99.09 109.58,99.17 112.35,99.17
+1.05VS_PCH on TOP (solid shape): 141.28,95.2 141.28,91.95 142.04,91.19 142.04,89.72 141.92,89.59 141.41,89.59 141.03,89.97 135.57,89.97 135.44,90.1 135.44,91.5 135.57,91.62 138.74,91.62 138.87,91.75 138.87,95.43 138.99,95.56 140.93,95.56
+1.05VS_PCH on TOP (solid shape): 148.55,89.51 148.55,89.11 148.45,89.01 148.07,89.01 147.82,88.76 147.82,87.36 147,86.54 146.49,86.54 146.36,86.67 146.36,86.97 145.9,87.43 145.9,88.47 146.03,88.6 146.41,88.6 146.46,88.55 146.46,88.07 146.53,88 146.97,88 147.01,88.03 147.02,88.04 147.11,88.1 147.18,88.2 147.18,88.2 147.23,88.25 147.23,88.76 147.24,88.77 147.24,89.35 147.55,89.67 148.39,89.67
+1.05VS_PCH on TOP (solid shape): 152.33,120.83 152.33,116.13 150.4,114.2 147.02,114.2 147,114.23 145.73,114.23 145.6,114.36 145.6,116.13 145.73,116.26 146.72,116.26 147.83,116.26 148.05,116.48 148.05,116.8 147.81,117.04 147.62,117.04 147.12,117.53 143.57,117.53 143.44,117.4 143.44,114.23 143.31,114.1 142.55,114.1 142.17,113.72 142.17,111.56 141.79,111.18 138.23,111.18 137.98,111.43 137.98,118.55 138.49,119.05 142.93,119.05 143.66,119.78 146.01,119.78 147.37,121.15 152.01,121.15
+1.05VS_PCH on TOP (solid shape): 164.39,24.77 164.39,23.68 163.87,23.15 163.86,23.15 163.86,23.14 163.81,23.09 163.81,22.76 163.8,22.73 163.76,22.71 163.25,22.71 163.25,17.05 163.15,16.95 161.88,16.95 161.55,17.28 161.55,18.14 161.58,18.22 161.66,18.24 162.06,18.6 161.66,18.95 161.58,18.98 161.55,19.05 161.55,24.44 162.06,24.95 164.22,24.95
+1.05VS_PCH on IN1 (solid shape): 112.2,97.21 112.2,94.02 111.07,92.89 105.47,92.89 104.83,93.53 104.83,94.04 104.96,94.16 107.4,94.16 107.48,94.12 107.49,94.03 107.83,93.55 108.16,94.03 108.18,94.12 108.26,94.16 110.11,94.16 110.13,94.15 110.14,94.14 110.59,94.02 110.67,94.48 110.66,94.52 110.68,94.55 110.93,94.8 110.93,94.86 110.99,94.96 111.1,94.94 111.63,95.18 111.1,95.42 110.99,95.4 110.93,95.49 110.93,97.34 111.05,97.46 111.94,97.46
+1.05VS_PCH on VCC: outline of 468 points within 132.77,20.76 176.71,122.55
+1.5VSP on TOP (solid shape): 204.29,9.9 204.29,6.79 203.9,6.41 200.92,6.41 200.6,6.72 200.6,8.69 202,8.69 202.38,9.07 202.38,9.9 202.57,10.09 204.1,10.09
+1.05VSP on TOP (solid shape): 183.32,39.9 183.32,38.7 183.17,38.55 176.78,38.55 176.71,38.49 176.71,37.01 176.59,36.89 173.28,36.89 172.78,37.39 172.78,39.68 173.16,40.06 183.15,40.06
+1.05VSP on BOTTOM (solid shape): 180.78,42.6 180.78,41.71 180.9,41.58 182.3,41.58 182.68,41.2 182.68,40.29 181.91,39.51 176.55,39.51 176.33,39.73 176.33,41.33 176.59,41.58 177.48,41.58 177.6,41.71 177.6,42.6 177.73,42.73 180.65,42.73
+1.8VGS on TOP (solid shape): outline of 249 points within 74.48,71.56 81.34,90.73
+1.8VS on TOP (solid shape): 77.78,70.41 77.65,70.29 76.51,70.29 76.38,70.41 76.38,71.18 76.51,71.3 77.78,71.3
+1.8VS on TOP (solid shape): 90.71,33.89 90.71,32.97 90.51,32.77 88.35,32.77 88.14,32.97 88.14,34.37 88.3,34.52 90.07,34.52
+1.8VS on BOTTOM (solid shape): 91.06,34.05 91.06,31.77 90.87,31.58 90.37,31.58 90.37,32.16 88.97,32.16 88.97,31.58 88.59,31.58 88.46,31.71 88.46,34.14 88.79,34.47 90.65,34.47
+1.8VSP on BOTTOM (solid shape): 87.19,32.06 87.35,31.85 87.6,31.81 88.04,31.37 88.41,31.37 88.44,31.39 90.91,31.39 91.04,31.27 91.04,29.11 87.93,29.11 87.19,29.85 83.5,29.85 83.16,30.18 83.16,31.81 83.42,32.06
+1.35V on TOP (solid shape): outline of 15219 points within 99.5,24.62 147.68,89.56
+1.35V on BOTTOM (solid shape): 102.98,30.84 102.98,24.36 101.94,23.32 99.96,23.32 99.62,23.65 99.62,32.16 99.09,32.16 99.07,32.19 99.07,33.13 99.32,33.38 100.44,33.38
+1.35V on BOTTOM (solid shape): 147.76,37.78 147.82,37.87 147.93,37.85 148.01,37.77 148.01,35.87 148,35.84 147.94,35.81 147.9,35.77 147.82,35.74 147.52,35.87 147.22,35.74 147.15,35.77 147.06,35.84 146.95,35.87 146.92,35.88 146.91,35.92 146.91,36.3 146.77,36.44 146.77,36.89 146.79,36.92 146.82,36.94 147.26,36.94 147.76,37.44
+1.35V on BOTTOM (solid shape): 147.82,33.74 147.9,33.71 147.94,33.67 147.98,33.64 148,33.62 148.01,33.6 148.01,33.36 147.77,33.11 147.77,31.45 148.01,31.21 148.01,27.76 147.97,27.68 147.89,27.66 147.73,27.65 147.6,27.57 147.52,27.54 147.22,27.67 146.92,27.54 146.62,27.67 146.32,27.54 146.02,27.67 145.72,27.54 145.65,27.57 145.6,27.61 145.54,27.64 145.48,27.72 145.51,27.81 145.81,28.11 146.17,28.11 146.74,28.53 146.49,29.19 146.47,29.23 146.47,29.26 146.53,29.45 146.48,29.64 146.47,29.66 146.47,29.69 146.49,29.73 146.54,29.76 146.59,29.81 147.51,30.73 147.51,33.58 147.54,33.61 147.55,33.61 147.66,33.64 147.75,33.71
+1.35V on BOTTOM (solid shape): 122.81,46.48 122.81,45.49 122.9,45.4 123.08,45.27 123.3,45.22 123.33,45.22 123.34,45.2 123.35,45.18 123.36,45.14 123.34,45.11 123.07,44.61 123.34,44.12 123.36,44.09 123.35,44.05 123.3,43.85 123.35,43.66 123.36,43.62 123.34,43.59 123.27,43.54 123.21,43.48 122.48,42.65 122.48,41.89 122.42,41.8 122.31,41.82 122.15,41.98 122.1,42.03 122.05,42.06 122.03,42.1 122.03,42.13 122.09,42.33 122.03,42.52 122.03,42.56 122.05,42.59 122.32,43.09 122.05,43.59 122.03,43.62 122.03,43.66 122.09,43.85 122.03,44.05 122.03,44.09 122.05,44.12 122.3,44.78 121.73,45.2 121.63,45.2 121.39,45.45 121.39,46.01 121.63,46.25 121.98,46.25 122.24,46.51 122.77,46.51
+1.35V on BOTTOM (solid shape): outline of 443 points within 118.29,24.64 145.84,52.38
+1.35VGPUP on TOP (solid shape): 37.6,54.03 37.63,54.01 37.65,53.98 37.65,53.4 38.41,53.4 38.41,53.98 38.43,54.01 38.46,54.03 38.74,54.03 38.78,54.01 38.79,53.98 38.79,53.4 43.36,53.4 43.36,53.98 43.38,54.01 43.41,54.03 43.69,54.03 43.73,54.01 43.74,53.98 43.74,53.4 44.51,53.4 44.51,53.98 44.52,54.01 44.56,54.03 44.84,54.03 44.87,54.01 44.89,53.98 44.89,53.4 46.74,53.4 46.78,53.38 46.79,53.34 46.79,49.33 46.54,49.08 42.73,49.08 42.6,49.2 42.6,51.74 42.35,52 37.12,52 36.52,52.59 36.52,53.41 36.57,53.46 37.25,53.46 37.27,53.47 37.27,53.98 37.28,54.01 37.32,54.03
+1.35VGPUP on BOTTOM (solid shape): 45.4,54.28 45.4,43.74 44.89,43.24 43.24,43.24 42.86,43.62 42.86,51.11 41.97,52 41.97,54.16 42.35,54.54 45.14,54.54
+1.35VGPUP_B+ on TOP (solid shape): 39.43,43.49 40.44,43.49 40.66,43.27 40.66,39.77 40.19,39.3 37.14,39.3 36.25,40.19 36.25,44.25 36.38,44.38 38.54,44.38
+1.35VP on BOTTOM (solid shape): 86.8,10.85 86.8,9.96 86.67,9.83 86.29,9.83 86.16,9.96 86.16,10.6 86.04,10.72 85.15,10.72 85.15,10.98 86.67,10.98
+1.35VP on BOTTOM (solid shape): 98.86,32.82 98.86,22.79 99.75,21.9 101.02,21.9 102.42,20.5 102.42,10.22 102.16,9.96 97.59,9.96 97.08,10.47 97.08,20.5 95.69,21.9 95.69,32.82 95.94,33.08 98.61,33.08
+1.35VP on IN2 (solid shape): 86.92,11.1 86.92,9.83 86.8,9.71 86.16,9.71 86.04,9.83 86.04,11.1 86.16,11.23 86.8,11.23
+1.35VS_VGA on TOP (solid shape): 58.78,90.1 58.78,89.72 58.81,89.69 58.81,89.21 58.63,89.03 57.99,89.03 57.87,88.9 57.84,88.93 57.28,88.93 57.15,89.06 57.15,89.69 57.17,89.71 57.17,90.11 57.38,90.33 58.55,90.33
+1.35VS_VGA on TOP (solid shape): 39.52,56.04 41.66,55.55 43.81,56.03 43.82,56.04 46.18,56.04 46.79,55.43 46.79,53.78 46.67,53.65 45.14,53.65 45.14,54.16 37.01,54.16 37.01,53.65 36.52,53.65 36.52,55.95 36.61,56.04
+1.35VS_VGA on TOP (solid shape): 60.17,88.86 60.17,88.32 60.6,87.89 60.6,87.41 60.75,87.25 61.19,87.25 61.25,87.3 61.7,87.3 61.75,87.25 61.75,86.64 61.68,86.57 61.17,86.57 61.14,86.59 60.31,86.59 60.13,86.42 58.68,86.42 58.6,86.49 58.6,87.05 58.81,87.25 59.14,87.25 59.19,87.3 59.19,88.02 59.33,88.15 59.33,88.21 59.4,88.33 59.42,88.47 59.44,88.5 59.44,88.94 59.54,89.04 59.99,89.04
+1.35VS_VGA on TOP (solid shape): 59.65,81.54 59.65,81.16 59.57,81.08 58.98,81.08 58.91,81 58.91,80.42 59.49,79.84 59.8,79.84 59.9,79.73 59.9,79.18 59.75,79.02 59.47,79.02 59.14,78.69 58.88,78.69 58.78,78.8 58.78,79.13 58.65,79.25 58.17,79.25 58.12,79.3 58.12,79.73 58.32,79.94 58.32,80.24 58.1,80.47 58.1,80.98 58.15,81.03 58.55,81.03 58.74,81.22 58.74,81.64 58.8,81.7 59.49,81.7
+1.35VS_VGA on TOP (solid shape): outline of 393 points within 27.69,97.26 43.94,102.24
+1.35VS_VGA on TOP (solid shape): outline of 379 points within 27.67,68.48 40.73,73.69
+1.35VS_VGA on BOTTOM (solid shape): outline of 189 points within 35.49,77.45 43.15,82.15
+1.35VS_VGA on BOTTOM (solid shape): outline of 1695 points within 19.49,63.92 41.87,102.42
+1.35VS_VGA on IN1 (solid shape): 36.51,65.89 36.51,58.35 39.43,55.43 42.86,55.43 43.11,55.68 45.28,55.68 45.5,55.47 45.5,53.95 45.07,53.52 36.89,53.52 33.39,57.02 33.39,57.97 31.96,59.4 31.96,65.9 32.17,66.11 36.28,66.11
+1.35VS_VGA on IN2 (solid shape): outline of 528 points within 28,63.94 37.27,73.21
+1.35VS_VGA on VCC: 47.53,56.19 45.9,57.82 45.9,60.49 41.82,64.57 31.91,64.57 29.25,67.24 26.07,67.24 25.58,67.72 25.58,76.78 26.22,77.42 26.22,81.57 22.54,85.25 22.54,87.33 24.95,89.74 24.95,97.1 28.25,100.41 28.25,101.93 30.64,104.32 45.76,104.32 48.17,106.74 53.55,106.74 60.38,99.9 60.38,79.92 59.37,78.9 59.37,71.92 51.87,64.42 51.87,57.95 50.12,56.19
+3V_DSW on TOP (solid shape): 155.76,20.76 155.96,20.76 156.39,20.76 156.65,20.76 157.03,20.76 157.16,20.63 157.16,20.12 157.03,19.99 155.89,19.99 154.87,18.98 154.23,18.98 153.98,19.23 153.98,20.1 153.99,20.15 153.99,20.63 154.23,20.88 155.63,20.88
+3VALW on TOP (solid shape): 153.09,13.39 153.09,10.98 152.51,10.39 150.78,10.39 150.73,10.44 150.73,11.08 150.88,11.23 151.82,11.23 152.33,11.74 152.33,12.88 151.95,13.26 151.95,13.52 152.08,13.64 152.84,13.64
+3VALW on TOP (solid shape): 207.78,5.45 207.78,3.64 207.56,3.43 204.88,3.43 204.41,3.89 204.41,5.45 204.6,5.64 207.59,5.64
+3VALW on TOP (solid shape): 161.35,13.39 161.35,12.76 161.3,12.7 161.3,12.03 161.73,11.59 161.73,10.98 161.6,10.85 159.57,10.85 159.44,10.98 159.44,11.71 159.11,12.04 159.11,13.19 159.44,13.52 161.22,13.52
+3VALW on TOP (solid shape): 174.89,14.15 174.92,14.14 174.94,14.1 174.94,11.87 174.81,11.74 173.98,11.74 173.34,11.74 173.16,11.92 173.11,11.92 173.09,11.94 173.03,11.94 172.98,11.99 171.79,11.99 171.49,12.29 171.49,12.56 171.25,12.81 171.25,13.39 171.38,13.52 171.96,13.52 172.55,14.1 173.67,14.1 173.67,14.12 173.7,14.15 174.86,14.15
+3VALW on TOP (solid shape): 194.43,71.51 194.52,71.45 194.51,71.35 194.63,70.86 195.12,70.97 195.21,71.02 195.29,70.97 195.61,70.8 195.92,71 195.99,71.06 196.08,71.03 197.16,69.95 197.16,67.54 196.93,67.31 195.66,67.31 195.59,67.39 195.59,68.13 194.7,69.02 193.35,69.02 192.79,69.57 192.56,69.57 192.33,69.65 192.11,69.57 187.61,69.57 187.1,70.08 187.1,71.2 187.41,71.51
+3VALW on TOP (solid shape): outline of 207 points within 152.33,20.91 161.22,24.69
+3VALW on BOTTOM (solid shape): 80.04,37.56 80.04,35.47 79.87,35.3 79.07,35.3 78.85,35.52 78.85,37.53 79.22,37.9 79.7,37.9
+3VALW on BOTTOM (solid shape): 189.9,98.45 189.9,96.39 189.71,96.2 189.12,96.2 188.69,96.63 188.69,98.31 188.88,98.5 189.84,98.5
+3VALW on BOTTOM (solid shape): 171.38,117.91 171.38,116.13 171.13,115.88 165.66,115.88 165.54,116.01 165.54,117.4 165.79,117.66 168.2,117.66 168.71,118.17 171.13,118.17
+3VALW on BOTTOM (solid shape): 161.22,23.42 161.22,21.39 160.71,20.88 160.71,13.9 161.22,13.39 161.22,11.99 161.09,11.87 159.34,11.87 159.05,12.16 159.05,23.36 159.37,23.68 160.97,23.68
+3VALW on BOTTOM (solid shape): 209.68,6.91 209.68,4.83 208.04,3.19 204.48,3.19 203.84,3.83 203.84,6.23 204.09,6.49 207.5,6.49 208.37,7.36 209.24,7.36
+3VALW on BOTTOM (solid shape): 183.29,55.66 183.29,54.46 183.11,54.28 180.52,54.28 180.52,54.54 181.03,54.54 181.03,55.05 180.52,55.05 180.52,55.66 180.8,55.94 183.01,55.94
+3VALW on BOTTOM (solid shape): 80.37,52.58 80.37,51.95 79.69,51.27 79.69,50.35 80.07,49.97 81.72,49.97 81.84,49.84 81.84,49.46 81.72,49.33 78.16,49.33 77.91,49.59 77.91,50.98 78.42,50.98 78.42,52.63 78.54,52.76 80.18,52.76
+3VALW on BOTTOM (solid shape): outline of 122 points within 75.87,18.95 81.84,28.73
+3VALW on IN1 (solid shape): 171.51,117.66 171.51,116.39 171.25,116.13 168.97,116.13 168.71,116.39 168.71,117.66 169.09,118.04 171.13,118.04
+3VALW on IN1 (solid shape): 207.42,4.55 207.42,3.26 207.17,3 204.93,3 204.63,3.31 204.63,4.8 205.06,5.24 206.74,5.24
+3VALW on IN1 (solid shape): 80.1,52.11 80.1,50.68 80.09,50.6 80.1,50.52 80.1,49.6 79.96,49.46 78.66,49.46 78.59,49.53 78.59,51.54 79.3,52.25 79.96,52.25
+3VALW on IN1 (solid shape): 80.27,38.93 80.27,36.15 80.25,36.12 78.84,36.12 78.68,36.28 78.68,38.83 78.83,38.98 78.96,38.98 79.03,39.04 80.16,39.04
+3VALW on IN1 (solid shape): outline of 2233 points within 168.54,10.98 192.08,118.37
+3VALW on IN2 (solid shape): 185.07,55.76 185.07,54.56 184.74,54.23 181.54,54.23 181.29,54.49 181.29,55.94 181.41,56.06 184.77,56.06
+3VALW on IN2 (solid shape): 179.06,16.79 179.9,16.79 180.18,16.51 180.18,15.46 178.87,14.15 176.71,14.15 176.59,14.28 176.59,15.17 176.61,15.19 176.61,15.4 178.01,16.79 179.05,16.79
+3VALW on VCC: 112.05,4.5 105.06,11.49 96.43,11.49 92.39,15.53 92.39,18.58 90.59,20.38 83.22,20.38 80.32,23.27 80.32,27.64 81.44,28.76 91.26,28.76 100.66,19.36 106.25,19.36 111.58,14.03 124.41,14.03 125.3,13.14 128.6,13.14 129.24,12.5 131.99,12.5 133.51,14.03 167.44,14.03 167.44,11.36 168.12,10.85 171.74,10.85 172.4,11.51 172.4,13.54 172.88,14.03 176.23,14.03 176.23,14.02 176.48,14.02 176.59,13.92 176.59,9.31 171.78,4.5
+3VALW_EC on TOP (solid shape): 151.85,10.04 151.85,8.77 151.64,8.56 150.86,8.56 150.73,8.69 150.73,10.11 150.83,10.22 151.67,10.22
+3VALW_PCH on TOP (solid shape): 173.54,88.07 173.54,86.42 173.28,86.16 172.27,86.16 172.14,86.29 172.14,87.3 171.89,87.56 171.89,88.19 172.01,88.32 173.28,88.32
+3VALW_PCH on TOP (solid shape): 161.22,20.88 161.22,18.34 161.09,18.22 158.68,18.22 158.43,17.96 158.43,15.63 158.2,15.4 156.88,15.4 156.65,15.63 156.65,18.98 157.66,19.99 157.66,21.01 157.79,21.14 160.97,21.14
+3VALW_PCH on TOP (solid shape): 170.36,76.26 171.25,76.26 171.38,76.13 171.38,75.87 171.25,75.75 170.87,75.75 169.98,74.86 163.63,74.86 161.85,73.08 160.72,73.08 160.41,73.39 160.38,73.42 159.81,73.99 159.81,74.94 159.85,74.99 161.6,74.99 162.62,76 167.32,76 167.95,76.64 169.98,76.64
+3VALW_PCH on BOTTOM (solid shape): 158.48,74.69 161.13,74.69 161.47,74.35 161.47,72.95 158.68,70.16 158.68,67.11 158.43,66.86 154.74,66.86 154.46,67.14 154.46,68.77 155.89,70.19 155.89,73.49 159,73.49 159,73.44 159.01,73.39 159.02,73.34 159.04,73.29 159.07,73.25 159.11,73.22 159.15,73.19 159.19,73.17 159.24,73.15 159.29,73.14 159.34,73.14 159.39,73.15 159.44,73.17 159.48,73.19 159.52,73.22 159.56,73.25 159.59,73.29 159.61,73.34 159.62,73.39 159.63,73.44 159.63,73.49 159.62,73.54 159.61,73.58 159.59,73.63 159.56,73.67 159.52,73.7 159.48,73.73 159.44,73.76 159.39,73.77 159.34,73.78 159.29,73.78 159.24,73.77 159.19,73.76 159.15,73.73 159.11,73.7 159.07,73.67 159.04,73.63 159.02,73.58 159.01,73.54 159,73.49 155.89,73.49 155.89,73.59 157.03,74.73 158.45,74.73
+3VALW_PCH on IN1 (solid shape): 158.35,15.83 158.35,15.52 158.22,15.4 156.8,15.4 156.67,15.52 156.67,15.93 156.75,16.01 158.17,16.01
+3VALW_PCH on IN2 (solid shape): 159.57,15.98 159.57,15.42 159.52,15.37 158.86,15.37 158.81,15.42 156.65,15.42 156.63,15.44 156.61,15.47 156.61,15.66 156.53,15.81 156.52,15.82 156.52,15.93 156.65,16.06 159.49,16.06
+3VALW_PCH_GATE on TOP (solid shape): 163,11.58 164.1,11.58 164.27,11.42 164.27,11.03 164.21,10.97 163.47,10.97 163.34,10.85 162.11,10.85 161.98,10.98 161.98,11.61 162.11,11.74 162.85,11.74
+3VALWP on BOTTOM (solid shape): 75.57,31.6 75.57,19.23 75.42,19.08 74.4,19.08 74.06,19.42 74.06,21.78 74.33,22.13 74.06,22.47 74.06,23.26 72.76,24.55 68.61,24.55 66.1,27.06 61.82,27.06 61.52,27.36 61.52,30.03 61.78,30.28 69.53,30.28 71.42,32.17 75,32.17
+3VGS on TOP (solid shape): 44.38,109.28 45.01,109.28 45.01,109.78 45.27,109.78 45.27,109.28 45.9,109.28 45.9,109.78 47.43,109.78 48.32,108.89 50.98,108.89 51.24,108.64 51.24,106.99 50.98,106.74 44.13,106.74 43.87,106.99 43.87,109.66 44,109.78 44.38,109.78
+3VGS on BOTTOM (solid shape): 59.49,103.31 59.49,103.05 59.75,102.8 60.38,102.8 60.51,102.67 60.51,102.04 60.38,101.91 59.24,101.91 59.11,102.04 59.11,102.93 58.98,103.05 58.98,103.31 59.11,103.43 59.37,103.43
+3VGS on BOTTOM (solid shape): 48.7,106.99 48.7,105.59 48.82,105.47 50.09,105.47 50.48,105.85 50.48,107.62 50.6,107.75 51.87,107.75 52,107.62 52,104.96 51.62,104.58 46.67,104.58 46.54,104.7 46.54,106.61 46.28,106.86 44.89,106.86 44.63,107.12 44.63,108.89 44.76,109.02 46.67,109.02
+3VLP on TOP (solid shape): 179.31,71.96 179.31,71.62 178.75,71.62 178.75,71.12 179.31,71.12 179.31,70.3 179.17,70.15 178.6,70.15 177.87,69.42 177.15,69.42 177.11,69.44 177.09,69.47 177.09,70.03 176.59,70.03 176.59,69.47 176.57,69.44 176.54,69.42 176.28,69.42 176.21,69.49 176.21,70.85 176.28,70.92 177.06,70.92 177.13,70.99 177.13,71.88 177.28,72.03 179.24,72.03
+3VS on TOP (solid shape): 13.01,81.14 13.01,77.65 12.88,77.53 11.74,77.53 11.61,77.65 11.61,81.28 11.74,81.41 12.74,81.41
+3VS on TOP (solid shape): 47.17,112.2 47.17,110.16 47.05,110.04 44,110.04 43.87,110.16 43.87,112.2 44,112.32 47.05,112.32
+3VS on TOP (solid shape): 177.09,19.31 177.09,18.98 176.71,18.6 175.19,18.6 174.94,18.34 174.92,18.33 174.83,18.08 174.94,17.84 174.94,14.41 174.81,14.28 173.18,14.28 173.03,14.43 173.03,16.67 173.64,17.28 173.64,19.89 174,20.25 176.16,20.25
+3VS on TOP (solid shape): 26.29,77.2 26.29,72.96 25.99,72.66 25.99,72.22 26.62,71.59 26.62,66.14 26.49,66.01 24.53,66.01 24.41,66.12 24.41,66.85 24.17,67.08 23.69,67.08 23.45,67.32 23.45,73.16 23.67,73.38 24.76,73.38 24.98,73.6 24.98,74.34 24.72,74.61 23.98,74.61 23.8,74.78 23.8,76.82 23.53,77.09 22.11,77.09 21.76,76.74 21.76,76.22 21.42,75.89 20.69,75.89 20.36,76.22 20.36,78.62 20.82,79.09 24.4,79.09
+3VS on TOP (solid shape): outline of 203 points within 185.38,61.6 195.41,65.05
+3VS on BOTTOM (solid shape): 47.17,112.07 47.17,109.66 46.92,109.4 45.4,109.4 45.27,109.53 45.27,110.8 45.01,111.05 44.36,111.05 44.35,111.06 44.18,111.08 44,111.06 44,111.05 43.87,111.05 43.74,111.18 43.74,112.07 44,112.32 46.92,112.32
+3VS on BOTTOM (solid shape): 154.9,116.23 155.4,116.23 156.77,114.86 156.77,113.97 156.65,113.85 156.14,113.85 155.66,114.33 155.66,114.81 155.58,114.89 154.67,114.89 154.54,114.76 154.54,113.19 154.34,112.98 151.49,112.98 151.19,113.29 151.19,116.01 151.44,116.26 154.87,116.26
+3VS on BOTTOM (solid shape): 169.48,90 169.7,90 169.91,89.79 169.91,88.37 169.58,88.04 168.48,88.04 168.33,88.19 168.33,88.7 168.35,88.74 168.38,88.75 168.71,89.11 168.38,89.46 168.35,89.48 168.33,89.51 168.33,90.02 168.48,90.17 169.3,90.17
+3VS on BOTTOM (solid shape): 179.76,38.41 179.76,35.96 179.76,35.94 179.74,35.92 177.98,32.1 179.74,28.28 179.76,28.26 179.76,28.24 179.76,27.54 179.69,27.46 179.48,27.46 179.01,27.82 178.87,27.24 178.9,27.17 178.87,27.1 178.78,26.93 178.79,26.73 178.78,26.64 178.7,26.6 176.46,26.6 176.08,26.98 176.08,27.13 176.21,27.25 176.21,38.16 176.71,38.66 179.51,38.66
+3VS on IN1 (solid shape): 19.62,71.99 19.62,71.52 19.98,71.16 19.98,70.12 19.7,69.84 18.88,69.84 18.23,70.5 18.23,72.14 18.52,72.44 19.17,72.44
+3VS on IN1 (solid shape): 26.06,68.92 26.06,66.15 25.86,65.94 24.53,65.94 24.4,66.07 24.4,67.01 24.28,67.13 23.59,67.13 23.47,67.25 23.47,69.16 23.6,69.29 25.69,69.29
+3VS on IN1 (solid shape): outline of 294 points within 16.55,15.32 20.43,21.67
+3VS on IN2 (solid shape): 19.59,72.03 19.59,71.48 20.01,71.06 20.01,70.2 19.61,69.8 18.75,69.8 18.09,70.47 18.09,72.32 18.2,72.43 19.18,72.43
+3VS on IN2 (solid shape): outline of 1456 points within 1.83,70.92 13.39,88.5
+3VS on VCC: outline of 136 points within 0.23,14.28 193.6,122.57 ; 3 cut-outs
+3VS_TOUCH on TOP (solid shape): 12.76,67.37 12.76,64.44 10.6,64.44 10.6,65.33 11.23,65.97 11.23,67.62 11.36,67.75 12.38,67.75
+3VS_WLAN_NGFF on TOP (solid shape): 198.24,68.15 198.24,64.82 197.74,64.32 193.33,64.32 193.23,64.42 193.23,64.8 192.72,65.31 190.96,65.31 190.94,65.33 188.62,65.33 188.6,65.35 188.56,65.38 188.52,65.39 188.47,65.41 188.42,65.41 188.38,65.41 188.33,65.39 188.29,65.38 188.25,65.35 188.23,65.33 187.25,65.33 187,65.59 187,66.04 194.15,66.04 194.15,65.98 194.16,65.93 194.18,65.88 194.2,65.83 194.23,65.79 194.27,65.75 194.31,65.72 194.35,65.69 194.4,65.67 194.46,65.66 194.51,65.65 194.56,65.66 194.61,65.67 194.66,65.69 194.71,65.72 194.75,65.75 194.79,65.79 194.82,65.83 194.84,65.88 194.86,65.93 194.87,65.98 194.87,66.04 194.86,66.09 194.84,66.14 194.82,66.19 194.79,66.23 194.75,66.27 194.71,66.31 194.66,66.33 194.61,66.35 194.56,66.36 194.51,66.37 194.46,66.36 194.4,66.35 194.35,66.33 194.31,66.31 194.27,66.27 194.23,66.23 194.2,66.19 194.18,66.14 194.16,66.09 194.15,66.04 187,66.04 187,67.62 187.13,67.75 191.06,67.75 191.32,67.49 193.35,67.49 193.68,67.16 197.01,67.16 197.43,67.58 197.43,68.17 197.58,68.32 198.07,68.32
+3VS_WLAN_NGFF on BOTTOM (solid shape): 198.64,73.77 198.67,73.69 198.63,73.62 198.54,73.15 199.01,73.02 199.11,73.01 199.15,72.93 199.15,71.96 199.07,71.88 196.99,71.88 196.9,71.92 196.89,72.01 196.72,72.45 196.26,72.33 196.19,72.29 196.11,72.32 195.59,72.83 195.59,73.26 195.62,73.31 195.67,73.36 195.75,73.36 196.22,73.71 195.73,74.03 195.64,74.04 195.59,74.13 195.59,74.77 195.96,75.14 197.27,75.14
+3VS_WLAN_NGFF on IN1 (solid shape): 199.37,72.7 199.37,69.93 198.55,69.11 198.55,68.99 198.54,68.94 198.52,68.87 198.52,68.79 198.52,68.71 198.52,68.62 198.54,68.55 198.55,68.5 198.55,66.52 198.31,66.28 197.55,66.28 197.44,66.4 197.44,67.69 197.33,67.8 197.33,70.58 197.42,70.68 198.49,70.68 198.49,70.63 198.5,70.57 198.51,70.52 198.53,70.47 198.56,70.43 198.6,70.39 198.64,70.36 198.69,70.33 198.74,70.31 198.79,70.3 198.84,70.3 198.9,70.3 198.95,70.31 199,70.33 199.04,70.36 199.09,70.39 199.12,70.43 199.15,70.47 199.18,70.52 199.19,70.57 199.2,70.63 199.2,70.68 199.19,70.73 199.18,70.78 199.15,70.83 199.12,70.88 199.09,70.91 199.04,70.95 199,70.97 198.95,70.99 198.9,71.01 198.84,71.01 198.79,71.01 198.74,70.99 198.69,70.97 198.64,70.95 198.6,70.91 198.56,70.88 198.53,70.83 198.51,70.78 198.5,70.73 198.49,70.68 197.42,70.68 198.2,71.46 198.2,72.65 198.51,72.96 199.12,72.96
+5V_HDD on TOP (solid shape): 185.88,19.31 185.88,18.37 185,17.48 184.99,17.48 184.89,17.41 184.82,17.31 184.81,17.3 184.33,16.82 183.43,16.82 182.07,16.82 181.67,16.82 181.54,16.95 181.54,19.11 182.05,19.61 185.58,19.61
+5V_HDD on BOTTOM (solid shape): 184.78,17.33 184.78,16.44 184.39,16.05 182.53,16.05 181.64,15.16 181.64,14.21 181.35,13.92 179.63,13.92 179.53,14.03 179.53,15.38 179.77,15.63 180.15,15.63 180.25,15.73 180.25,16.46 181.72,16.46 181.72,16.41 181.73,16.36 181.74,16.31 181.76,16.26 181.79,16.22 181.83,16.18 181.87,16.14 181.92,16.12 181.97,16.1 182.02,16.09 182.07,16.08 182.13,16.09 182.18,16.1 182.23,16.12 182.27,16.14 182.32,16.18 182.35,16.22 182.38,16.26 182.41,16.31 182.42,16.36 182.43,16.41 182.43,16.46 182.42,16.52 182.41,16.57 182.38,16.62 182.35,16.66 182.32,16.7 182.27,16.73 182.23,16.76 182.18,16.78 182.13,16.79 182.07,16.79 182.02,16.79 181.97,16.78 181.92,16.76 181.87,16.73 181.83,16.7 181.79,16.66 181.76,16.62 181.74,16.57 181.73,16.52 181.72,16.46 180.25,16.46 180.25,17.08 180.48,17.31 181.72,17.31 181.91,17.5 184.61,17.5
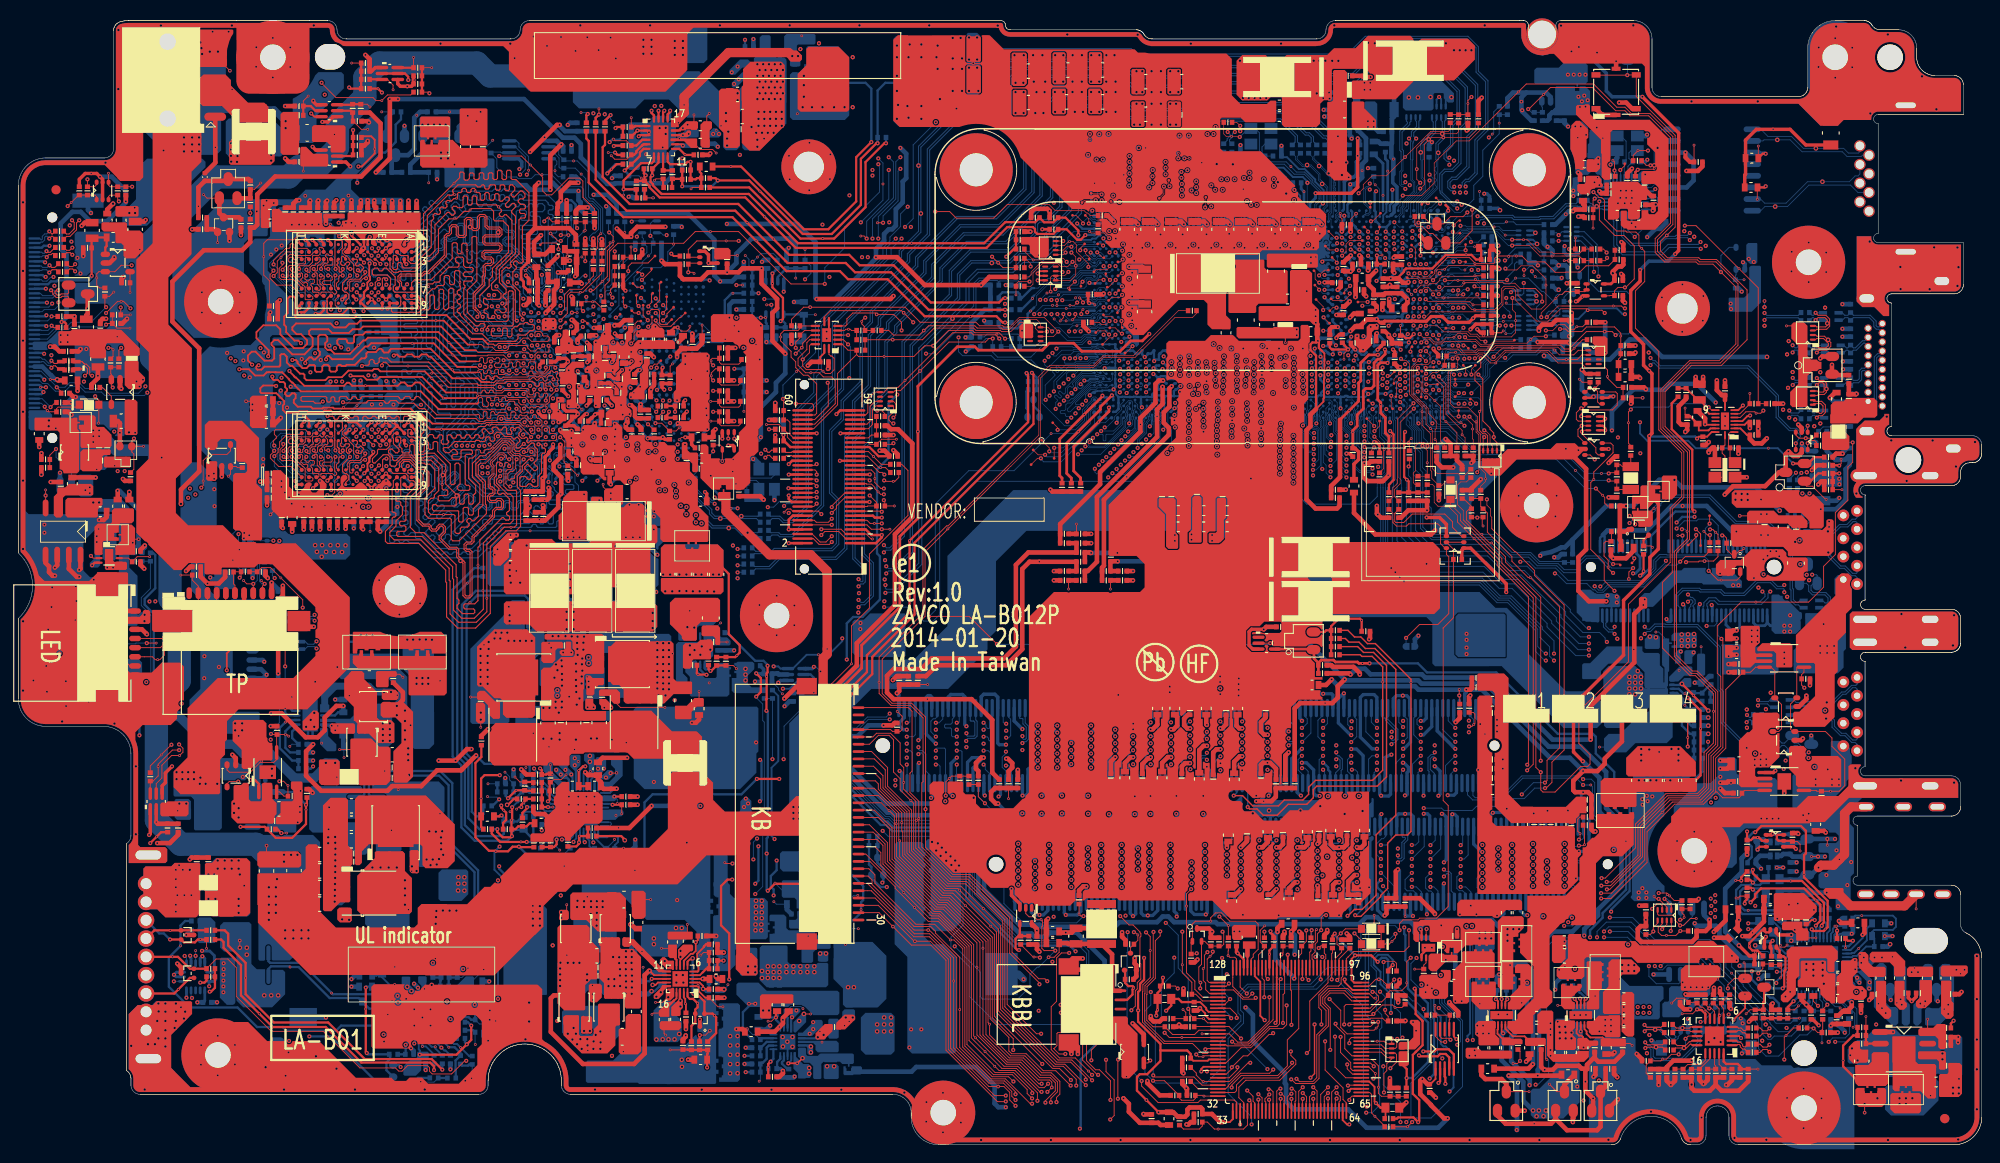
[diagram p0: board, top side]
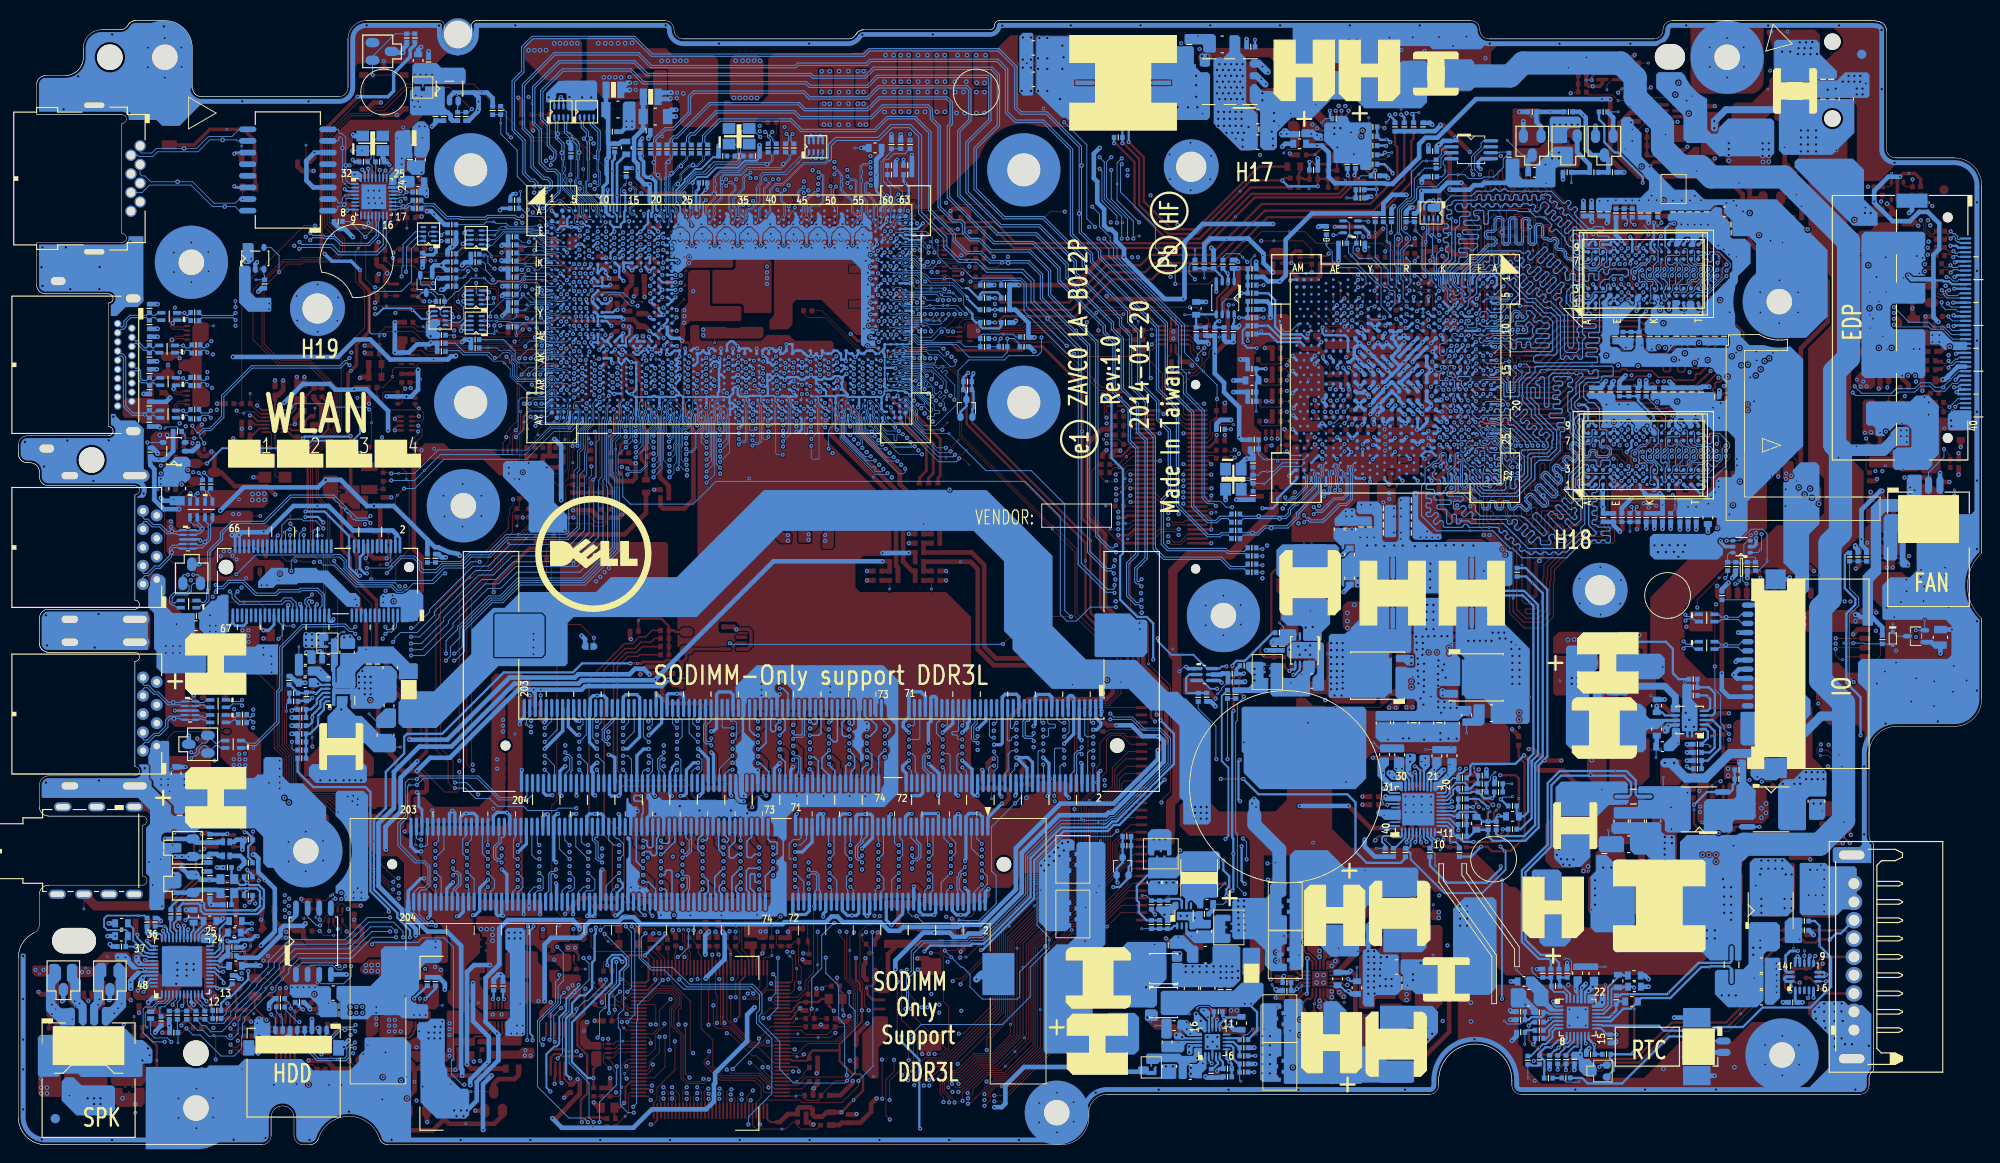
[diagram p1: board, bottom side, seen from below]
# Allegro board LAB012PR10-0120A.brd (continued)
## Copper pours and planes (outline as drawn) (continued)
+5V_HDD on BOTTOM (solid shape): 188.65,13.64 188.66,13.62 188.66,13.59 188.63,13.42 188.68,13.25 188.68,11.68 188.55,11.55 188.52,11.55 188.49,11.57 188.47,11.61 187.86,11.9 188.16,11.3 188.19,11.29 188.21,11.28 188.22,11.27 188.22,11.23 188.13,11.14 187.19,11.14 186.86,11.46 186.86,12.93 186.89,12.95 186.89,13.44 186.91,13.47 186.95,13.48 186.99,13.46 187.46,13.33 187.62,13.79 187.62,13.89 187.71,13.94 188.35,13.94
+5V_HDD on IN2 (solid shape): 184.87,17.59 184.96,17.52 184.93,17.41 184.89,16.91 185.39,16.87 185.47,16.89 185.54,16.85 185.84,16.72 186.13,16.89 186.37,16.89 186.39,16.87 186.79,16.73 187.04,17.08 187.1,17.17 187.21,17.15 188.69,15.67 188.69,13.64 188.63,13.44 188.69,13.24 188.43,12.98 188.1,12.98 187.68,13.4 187.68,14.51 187.37,14.82 187.27,15.09 186.99,15.2 186.59,15.6 182.69,15.6 182.43,15.86 182.43,16.33 182.42,16.36 182.42,16.37 182.33,16.69 182,16.79 181.99,16.78 181.97,16.79 181.75,17.01 181.75,17.3 182.04,17.59
+5V_PVDD on TOP (solid shape): 200.84,20.25 200.84,18.85 200.34,18.34 200.34,17.58 200.59,17.33 201.35,17.33 201.86,16.82 201.86,16.18 201.48,15.8 200.52,15.8 200.46,15.84 200.42,15.87 200.37,15.9 200.32,15.92 200.26,15.93 200.21,15.93 200.15,15.93 200.1,15.92 200.05,15.9 200,15.87 199.96,15.84 199.7,15.8 199.32,15.42 198.81,15.42 198.56,15.68 198.56,16.72 200.36,16.72 200.36,16.67 200.37,16.61 200.38,16.56 200.41,16.51 200.44,16.47 200.47,16.43 200.52,16.4 200.56,16.37 200.61,16.35 200.66,16.34 200.72,16.34 200.77,16.34 200.82,16.35 200.87,16.37 200.92,16.4 200.96,16.43 201,16.47 201.03,16.51 201.05,16.56 201.06,16.61 201.07,16.67 201.07,16.72 201.06,16.77 201.05,16.82 201.03,16.87 201,16.91 200.96,16.95 200.92,16.99 200.87,17.01 200.82,17.03 200.77,17.04 200.72,17.05 200.66,17.04 200.61,17.03 200.56,17.01 200.52,16.99 200.47,16.95 200.44,16.91 200.41,16.87 200.38,16.82 200.37,16.77 200.36,16.72 198.56,16.72 198.56,18.34 199.04,18.83 199.04,20.04 199.12,20.12 200.08,20.12 200.34,20.38 200.72,20.38
+5V_USB_PWR1 on TOP (solid shape): outline of 85 points within 193.81,45.64 200.21,62.41
+5V_USB_PWR1 on BOTTOM (solid shape): 200.05,61.47 200.05,61.46 200.03,61.08 200.21,60.73 200.21,58.72 199.57,58.09 199.57,54.16 199.32,53.9 199.32,52.13 198.68,51.49 194.11,51.49 193.86,51.74 193.86,54.03 195.13,55.3 195.13,57.99 195.21,58.07 196.07,58.07 196.07,58.07 197.54,58.07 198.44,58.97 198.44,60.06 198.32,60.18 198.32,61.84 198.7,62.22 199.29,62.22
+5V_USB_PWR2 on TOP (solid shape): outline of 108 points within 193.35,39.04 199.07,43.57
+5V_USB_PWR2 on BOTTOM (solid shape): 198.85,44.07 199.29,44.07 199.98,43.38 200.02,43.38 200.06,43.36 200.06,43.31 200.03,42.9 200.21,42.53 200.21,41.66 199.97,41.42 199.97,40.04 199.65,39.72 199.65,39.25 197.4,37 197.4,36.33 197.2,36.12 196.4,36.12 195.97,36.55 193.94,36.55 193.73,36.76 193.73,40.31 193.99,40.57 197.67,40.57 197.92,40.82 197.92,44 198.05,44.12 198.79,44.12
+5V_USB_PWR2 on IN1 (solid shape): 200.04,43.92 200.01,43.89 200.01,40.11 199.29,39.39 199.29,39.37 198.96,39.04 196.02,39.04 195.51,39.55 195.51,41.29 195.79,41.29 195.79,41.24 195.8,41.19 195.81,41.14 195.84,41.09 195.87,41.04 195.9,41.01 195.94,40.97 195.99,40.95 196.04,40.93 196.09,40.91 196.14,40.91 196.2,40.91 196.25,40.93 196.3,40.95 196.35,40.97 196.39,41.01 196.42,41.04 196.45,41.09 196.48,41.14 196.49,41.19 196.5,41.24 196.5,41.29 196.49,41.35 196.48,41.4 196.45,41.44 196.42,41.49 196.39,41.53 196.35,41.56 196.3,41.59 196.25,41.61 196.2,41.62 196.14,41.62 196.09,41.62 196.04,41.61 195.99,41.59 195.94,41.56 195.9,41.53 195.87,41.49 195.84,41.44 195.81,41.4 195.8,41.35 195.79,41.29 195.51,41.29 195.51,41.58 196.02,42.09 197.54,42.09 197.8,42.35 197.8,44 197.92,44.12 199.83,44.12
+5V_USB_PWR3 on TOP (solid shape): 27.11,46.03 27.11,44.51 27.23,44.38 27.31,44 27.69,43.92 27.74,43.87 27.74,42.09 27.62,41.97 26.35,41.97 25.43,41.05 24.56,41.05 24.39,41.22 24.39,43.13 23.4,44.12 23.4,46.19 23.62,46.41 26.73,46.41
+5V_USB_PWR3 on BOTTOM (solid shape): 26.35,47.17 26.35,43.87 26.09,43.62 24.82,43.62 23.55,44.89 22.28,44.89 22.15,45.01 22.15,47.05 22.41,47.3 26.22,47.3
+5VA on TOP (solid shape): 194.82,24.31 194.82,23.72 194.9,23.64 195.38,23.64 195.41,23.6 195.43,23.44 195.51,23.3 195.51,22.41 195.38,22.28 194.21,22.28 194.14,22.35 194.14,23.02 193.73,23.42 192.72,23.42 192.59,23.55 192.59,24.19 192.78,24.38 194.75,24.38
+5VALW on TOP (solid shape): 177.68,59.85 177.72,59.83 177.73,59.8 177.88,59.64 177.88,58.68 177.76,58.55 177.22,58.55 176.97,58.81 176.97,59.69 177.12,59.85
+5VALW on TOP (solid shape): 210.5,10.09 210.5,8.31 210.37,8.18 209.86,8.18 209.73,8.31 209.73,9.07 209.48,9.33 207.57,9.33 207.45,9.45 207.45,10.09 207.57,10.22 210.37,10.22
+5VALW on TOP (solid shape): 169.19,13.64 169.23,13.63 169.25,13.59 169.25,13.58 169.92,13.58 169.98,13.52 169.98,12.76 169.68,12.45 169.68,12.04 170.11,11.61 170.11,10.52 169.93,10.34 167.95,10.34 167.82,10.47 167.82,13.44 168.03,13.64
+5VALW on TOP (solid shape): 190.18,56.57 190.18,54.87 189.67,54.36 189.67,53.78 189.79,53.65 191.45,53.65 191.57,53.52 191.57,53.4 191.45,53.27 189.79,53.27 189.79,53.01 191.45,53.01 191.57,52.89 191.57,52.76 191.45,52.63 189.67,52.63 189.16,52.13 188.14,52.13 188.08,52.18 188.08,56.59 188.19,56.7 190.05,56.7
+5VALW on TOP (solid shape): 27.74,39.43 27.74,37.77 28.2,37.32 28.2,36.11 28,35.91 28,35.79 28,35.28 27.79,35.08 23.93,35.08 23.26,35.75 23.26,37.48 23.5,37.72 23.5,39.17 23.63,39.3 24.33,39.3 24.58,39.55 25.08,39.55 25.17,39.46 25.17,37.76 25.41,37.52 26.47,37.52 26.6,37.65 26.6,39.43 26.73,39.55 27.62,39.55
+5VALW on TOP (solid shape): outline of 120 points within 187.89,39.04 192.33,47.19
+5VALW on BOTTOM (solid shape): 169.73,13.39 170.58,13.39 170.85,13.12 170.85,11.71 170.49,11.36 170.49,4.63 168.71,2.85 165.54,2.85 165.16,3.23 165.16,5.9 165.39,6.13 166.11,6.13 167.54,7.56 167.54,8.28 167.82,8.56 167.82,13.64 167.95,13.77 169.35,13.77
+5VALW on BOTTOM (solid shape): 78.81,15.23 78.81,7.13 78.54,6.86 76.52,6.86 76.52,7.35 76.9,7.35 76.97,7.41 76.97,9.5 76.97,9.63 76.46,9.63 76.46,9.63 76.46,12.55 76.59,12.68 76.9,12.68 76.97,12.74 76.97,14.71 76.84,14.84 76.46,14.84 76.49,14.86 76.49,15.35 76.59,15.45 78.59,15.45
+5VALW on BOTTOM (solid shape): outline of 108 points within 177.1,58.75 188.22,63.02
+5VALW on IN1 (solid shape): outline of 1010 points within 179.56,22.6 191.19,61.47
+5VALW on VCC: outline of 161 points within 0.23,0.23 214.17,109.91 ; 1 cut-out
+5VALWP on BOTTOM (solid shape): outline of 193 points within 61.97,6.64 76.21,15.92
+5VS on TOP (solid shape): 13.14,102.42 13.14,101.53 13.01,101.4 10.72,101.4 10.6,101.53 10.6,102.42 10.72,102.54 13.01,102.54
+5VS on TOP (solid shape): 199.95,77.4 199.95,76.13 199.7,75.87 197.29,75.87 197.29,75.88 197.11,75.88 196.96,76.03 196.96,77.65 197.21,77.91 199.45,77.91
+5VS on TOP (solid shape): 9.2,70.54 9.2,69.91 8.69,69.4 8.69,68.64 8.66,68.6 8.6,68.56 8.55,68.52 8.53,68.51 8.51,68.51 5.39,68.51 5.14,68.76 5.14,70.41 5.39,70.67 9.07,70.67
+5VS on TOP (solid shape): 14.43,58.22 14.43,57.06 14.26,56.89 13.22,56.89 13.21,56.9 11.97,56.9 11.82,57.05 11.82,57.52 11.98,57.68 12.24,57.68 12.24,57.68 13.03,57.68 13.04,57.67 13.26,57.67 13.6,58 13.6,58.28 13.74,58.42 14.22,58.42
+5VS on TOP (solid shape): 198.68,21.14 198.68,20.3 198.33,19.94 198.33,18.98 198.2,18.85 197.72,18.85 197.54,19.03 197.54,20.05 197.54,20.05 197.54,20.25 197.41,20.38 194.62,20.38 194.49,20.25 194.49,20.05 194.49,20.05 194.49,18.47 194.11,18.09 194.11,16.44 193.22,15.55 192.72,15.55 192.46,15.8 192.46,16.31 193.1,16.95 193.1,18.87 193.22,19 193.22,20.48 193.1,20.61 193.1,21.14 193.6,21.64 195.79,21.64 195.91,21.77 198.05,21.77
+5VS on TOP (solid shape): outline of 147 points within 167.97,18.09 187.89,23.02
+5VS on BOTTOM (solid shape): 12.12,69.65 12.12,63.05 13.01,62.16 13.01,56.77 12.93,56.69 11.95,56.69 11.87,56.77 11.87,61.52 10.98,62.41 10.98,68.64 10.47,69.14 8.06,69.14 7.8,69.4 7.8,70.29 8.06,70.54 11.23,70.54
+5VS on BOTTOM (solid shape): 20.44,107.37 20.44,106.79 14.04,100.39 11.49,100.39 11.36,100.51 11.36,101.05 13.54,101.05 13.54,100.99 13.55,100.94 13.57,100.89 13.59,100.84 13.62,100.8 13.66,100.76 13.7,100.73 13.75,100.7 13.79,100.68 13.85,100.67 13.9,100.66 13.95,100.67 14.01,100.68 14.05,100.7 14.1,100.73 14.14,100.76 14.18,100.8 14.21,100.84 14.23,100.89 14.25,100.94 14.26,100.99 14.26,101.05 14.25,101.1 14.23,101.15 14.21,101.2 14.18,101.24 14.14,101.28 14.1,101.31 14.05,101.34 14.01,101.36 13.95,101.37 13.9,101.38 13.85,101.37 13.79,101.36 13.75,101.34 13.7,101.31 13.66,101.28 13.62,101.24 13.59,101.2 13.57,101.15 13.55,101.1 13.54,101.05 11.36,101.05 11.36,101.78 12.85,103.27 12.85,106.52 14.05,107.72 20.1,107.72
+5VS on IN1 (solid shape): 199.19,77.65 199.19,76.76 198.94,76.51 196.91,76.51 196.65,76.76 196.65,77.53 197.03,77.91 198.94,77.91
+5VS on IN1 (solid shape): outline of 219 points within 185.86,15.04 198.68,21.77
+5VS on IN1 (solid shape): outline of 1285 points within 2.34,69.4 13.39,102.29
+5VS on IN2 (solid shape): 14.01,59.51 13.97,59.33 14.03,59.15 14.03,57.08 13.7,56.76 12.55,56.76 12.38,56.93 12.38,59.49 12.5,59.62 13.9,59.62
+VCC_PWR_SRC on TOP (solid shape): 78.8,115.12 78.8,109.17 78.52,108.89 77.17,108.89 77.02,109.05 77.02,110.55 76.51,111.05 76.51,115.12 76.76,115.37 78.54,115.37
+VCC_PWR_SRC on BOTTOM (solid shape): 64.45,117.28 74.35,117.28 76.51,115.12 78.54,115.12 79.3,115.88 79.56,115.88 79.94,115.5 79.94,113.97 78.8,112.83 78.8,109.02 78.42,108.64 77.27,108.64 76.96,108.96 76.96,110.61 75.37,112.2 73.03,112.2 71.05,114.18 68.36,114.18 67.39,113.21 61.22,113.21 60.56,113.87 60.56,118.2 60.77,118.41 63.31,118.41
+VDDCI on TOP (solid shape): 61.8,85.45 61.8,85.44 61.8,84.99 61.68,84.87 60.92,84.87 60.74,84.69 60.74,84.36 60.99,84.1 60.99,83.14 60.86,83.01 60.86,82.53 60.94,82.45 60.94,81.11 61.32,80.73 61.32,80.55 61.25,80.47 60,80.47 59.87,80.6 59.87,81.28 60,81.41 60.25,81.41 60.36,81.51 60.36,81.64 60.36,81.65 60.38,81.77 60.36,81.89 60.36,81.9 60.36,82.05 60.1,82.3 60.08,82.41 60.17,82.48 60.45,82.93 59.94,83.06 59.92,83.05 59.9,83.05 59.22,83.05 59.18,83.1 59.18,83.84 59.06,83.95 59.06,84.35 59.15,84.43 59.7,84.43 59.76,84.5 59.76,84.83 60.15,85.22 60.16,85.23 60.25,85.29 60.31,85.37 60.31,85.38 60.48,85.55 61.7,85.55
+VDDR3 on TOP (solid shape): 68.94,85.9 68.94,85.19 68.93,85.18 68.78,84.99 68.81,84.74 68.82,84.73 68.82,83.75 68.82,83.75 68.82,82.81 68.38,82.38 68.38,81.55 68.25,81.42 66.86,81.42 66.68,81.59 66.68,82.07 66.82,82.21 67,82.21 67.86,83.07 67.86,84.21 67.96,84.31 67.97,84.31 68.18,84.55 68.1,84.85 68.1,85.11 68.31,85.32 68.31,85.88 68.4,85.97 68.86,85.97
GND on TOP (solid shape): 19.64,57.75 19.64,56.58 19.08,56.02 14.79,56.02 14.61,56.2 14.61,58.38 14.65,58.42 18.97,58.42
GND on TOP (solid shape): 27.14,81.75 27.14,78.44 26.98,78.29 25.54,78.29 25.29,78.54 25.29,81.58 25.54,81.83 27.06,81.83
GND on TOP (solid shape): 32.82,47.17 32.82,45.52 32.57,45.27 31.17,45.27 31.04,45.39 31.04,46.28 32.19,47.43 32.57,47.43
GND on TOP (solid shape): 51.24,113.09 51.24,109.28 51.11,109.15 48.44,109.15 48.19,109.4 48.19,113.09 48.32,113.21 51.11,113.21
GND on TOP (solid shape): 122.99,117.4 122.99,114.86 122.87,114.74 121.66,114.74 121.53,114.86 121.53,117.4 121.66,117.53 122.87,117.53
GND on TOP (solid shape): 122.99,113.9 122.99,111.31 122.87,111.18 121.66,111.18 121.53,111.31 121.53,113.85 121.66,113.97 122.92,113.97
GND on TOP (solid shape): 126.96,117.43 126.96,114.86 126.83,114.74 125.6,114.74 125.47,114.86 125.47,117.4 125.6,117.53 126.85,117.53
GND on TOP (solid shape): 126.99,113.85 126.99,111.31 126.87,111.18 125.63,111.18 125.51,111.31 125.51,113.87 125.61,113.97 126.87,113.97
GND on TOP (solid shape): 155.25,65.08 155.25,58.6 154.62,57.97 143.57,57.97 143.44,58.09 143.44,65.59 143.69,65.84 154.49,65.84
GND on TOP (solid shape): 168.97,22.79 168.97,20.32 168.48,19.84 167.7,19.84 167.47,20.07 167.47,22.76 167.6,22.89 168.87,22.89
GND on TOP (solid shape): 176.46,16.44 176.46,11.99 176.33,11.87 175.57,11.87 175.06,12.37 175.06,16.31 175.44,16.69 176.21,16.69
GND on TOP (solid shape): 28,109.61 28,107.45 27.59,107.04 23.2,107.04 23.02,107.22 23.02,109.53 23.44,109.95 27.65,109.95
GND on TOP (solid shape): 30.89,31.69 30.89,30.5 30.67,30.28 26.35,30.28 26.09,30.54 26.09,31.81 26.35,32.06 30.52,32.06
GND on TOP (solid shape): 62.16,71.3 62.16,66.35 61.91,66.1 59.11,66.1 58.98,66.22 58.98,68.76 59.49,69.27 59.49,70.67 60.25,71.43 62.03,71.43
GND on TOP (solid shape): 77.02,61.8 77.02,60.43 76.71,60.13 70.54,60.13 70.16,60.51 70.16,61.8 70.26,61.9 76.92,61.9
GND on TOP (solid shape): 83.7,117.94 83.7,111.33 80.96,108.59 79.84,108.59 79,109.43 79,115.57 79.14,115.71 79.14,117.52 79.94,118.32 83.32,118.32
GND on TOP (solid shape): 110.13,119.15 110.13,115.94 109.85,115.65 108.65,115.65 108.45,115.85 108.45,119.17 108.6,119.32 109.96,119.32
GND on TOP (solid shape): 118.23,115.24 118.23,115.23 118.34,115.12 118.34,112.73 118.19,112.58 116.96,112.58 116.83,112.7 116.83,115.24 116.96,115.37 118.1,115.37
GND on TOP (solid shape): 118.36,119.19 118.36,116.01 118.23,115.88 117.09,115.88 116.9,116.07 116.9,119.26 116.99,119.36 118.19,119.36
GND on TOP (solid shape): 147,113.85 147,113.21 148.27,111.94 148.27,111.05 148.14,110.93 145.85,110.93 145.6,111.18 145.6,113.85 145.73,113.97 146.87,113.97
GND on TOP (solid shape): 159.76,10.28 163,10.28 163.12,10.15 163.12,9.52 163,9.39 158.24,9.39 158.04,9.58 158.04,10.47 158.17,10.6 159.44,10.6
GND on TOP (solid shape): 114.36,119.22 114.36,115.96 114.21,115.82 113.09,115.82 112.92,115.98 112.92,119.2 113.07,119.35 114.23,119.35
GND on TOP (solid shape): 159.06,120.07 159.06,118.55 156.77,116.26 153.09,116.26 152.84,116.51 152.84,120.45 153.22,120.83 158.3,120.83
GND on TOP (solid shape): 10.34,64.95 10.34,63.81 10.47,63.68 11.74,63.68 11.87,63.56 11.87,62.92 11.74,62.79 9.58,62.79 9.45,62.92 9.45,64.95 9.58,65.08 10.22,65.08
GND on TOP (solid shape): 135.13,23.93 135.13,22.74 135.03,22.64 133.84,22.64 133.56,22.36 132.72,22.36 132.54,22.53 132.54,22.99 132.52,23.02 132.52,23.78 132.75,24.01 135.06,24.01
GND on TOP (solid shape): 136.71,118.55 136.71,114.4 136.39,114.08 133.65,114.08 133.03,114.7 133.03,118.42 133.66,119.05 136.2,119.05
GND on TOP (solid shape): 164.22,26.55 164.22,25.71 164.14,25.63 162.46,25.63 161.63,24.79 161.12,24.79 160.94,24.97 157.23,24.97 157.13,25.07 157.13,26.37 157.54,26.78 163.99,26.78
GND on TOP (solid shape): 114.42,115.24 114.42,112.7 114.28,112.57 114.25,112.55 113.06,112.55 112.91,112.7 112.91,115.27 113,115.36 113.14,115.36 113.15,115.37 114.29,115.37
GND on TOP (solid shape): 201.11,10.53 201.3,10.34 202,10.34 202,9.14 201.81,8.95 200.92,8.95 200.84,8.87 200.36,8.87 199.88,9.35 199.88,10.7 200.48,11.29 201.11,11.29
GND on TOP (solid shape): 28.38,103.18 28.38,102.67 28.25,102.54 27.74,102.54 27.49,102.29 27.49,100.26 27.36,100.13 26.6,100.13 26.47,100.26 26.47,100.35 26.47,103.18 26.6,103.31 28.25,103.31
GND on TOP (solid shape): 192.21,68.76 194.75,68.76 195.38,68.13 195.38,67.49 195.26,67.37 193.73,67.37 193.22,67.87 191.12,67.87 191.12,67.87 189.03,67.87 188.78,68.13 188.78,69.02 189.03,69.27 191.7,69.27
GND on TOP (solid shape): 183.19,41.84 183.19,40.26 183.15,40.23 175.81,40.23 175.57,40.47 175.57,42.27 176.84,43.54 181.49,43.54
GND on TOP (solid shape): 211.67,8.93 211.99,8.93 212.25,8.67 212.25,5.57 211.89,5.21 209.82,5.21 209.73,5.3 209.73,7.57 209.88,7.72 210.62,7.72 210.76,7.87 210.76,8.88 210.82,8.94 211.66,8.94
GND on TOP (solid shape): 75.88,54.92 75.88,54.03 75.62,53.78 75.62,53.14 75.49,53.01 73.72,53.01 73.59,52.89 73.59,52.25 73.34,52 72.7,52 72.57,52.13 72.57,54.54 72.83,54.79 74.1,54.79 74.48,55.17 75.62,55.17
GND on TOP (solid shape): 84.64,16.31 84.64,15.55 84.51,15.42 82.35,15.42 82.23,15.3 82.23,13.9 82.1,13.77 81.13,13.77 80.98,13.92 80.98,16.21 81.2,16.44 84.51,16.44
GND on TOP (solid shape): 109.91,115.24 109.99,115.24 110.09,115.14 110.09,112.58 109.96,112.45 109.85,112.45 108.71,112.45 108.58,112.58 108.58,115.12 108.71,115.24 109.85,115.24
GND on TOP (solid shape): 193.73,54.54 193.73,52.25 193.6,52.13 192.08,52.13 191.95,52.25 191.95,53.65 191.7,53.9 189.97,53.9 189.94,53.92 189.92,53.95 189.92,54.28 190.43,54.79 193.48,54.79
GND on TOP (solid shape): 43.11,47.3 43.11,40.19 42.47,39.55 41.12,39.55 40.95,39.72 40.95,42.98 41.84,43.87 41.84,46.03 41.2,46.66 39.81,46.66 39.55,46.92 39.55,48.14 39.76,48.34 42.07,48.34
GND on TOP (solid shape): 69.78,58.86 69.78,56.57 69.27,56.06 56.57,56.06 55.81,56.82 55.14,56.82 55.02,56.85 54.9,56.82 53.27,56.82 53.02,57.08 53.02,59.11 53.27,59.36 69.27,59.36
GND on TOP (solid shape): 36,37.65 36,32.69 36.51,32.19 36.51,30.66 36.25,30.41 36.25,26.6 36.12,26.47 35.13,26.47 34.16,25.5 33.42,25.5 33.27,25.66 33.27,37.08 34.09,37.9 35.74,37.9
GND on TOP (solid shape): 126.39,70.45 126.39,66.91 126.39,66.86 126.42,66.82 126.66,66.58 126.66,65.21 126.55,65.09 125.59,65.09 125.33,65.35 125.33,68.89 124.52,69.71 124.52,70.54 124.64,70.67 126.17,70.67
GND on TOP (solid shape): 129.22,70.67 129.22,69.91 129.23,69.89 129.23,65.87 129.12,65.77 127.89,65.77 127.82,65.84 127.82,66.83 128.18,67.19 128.18,69.62 128.2,69.65 128.2,70.67 128.45,70.92 128.96,70.92
GND on TOP (solid shape): 54.67,66.73 54.67,66.48 54.53,66.34 54.26,66.34 53.59,65.67 53.59,64.17 52.67,63.24 52.05,63.24 51.85,63.43 51.85,65.26 53.46,66.87 54.53,66.87
GND on TOP (solid shape): 73.08,76.64 73.08,75.87 73.34,75.62 74.1,75.62 74.22,75.49 74.22,73.59 74.1,73.46 73.72,73.46 73.59,73.59 73.59,74.4 73.13,74.86 72.57,74.86 72.45,74.99 72.45,76.64 72.57,76.76 72.95,76.76
GND on TOP (solid shape): 131.88,70.54 131.88,68.49 131.65,68.25 131.65,66.18 131.28,65.81 131.21,65.81 131.12,65.71 130.1,65.71 129.98,65.84 129.98,66.73 130.1,66.86 130.74,66.86 130.87,66.99 130.87,70.55 130.99,70.67 131.76,70.67
GND on TOP (solid shape): 167.62,14.48 167.62,10.14 167.85,9.91 169.98,9.91 170.33,10.26 171.46,10.26 171.51,10.22 171.51,9.58 170.97,9.05 167.6,9.05 166.94,9.71 166.94,10.82 166.93,12.12 166.05,12.12 165.87,12.3 165.87,14.2 166.33,14.66 167.44,14.66
GND on TOP (solid shape): 31.04,39.55 31.04,35.36 30.69,35.01 28.23,35.01 28.12,35.11 28.12,35.74 28.63,36.25 28.63,37.39 28.76,37.52 29.9,37.52 30.03,37.65 30.03,38.66 29.76,38.94 29.76,39.57 29.86,39.68 30.92,39.68
GND on TOP (solid shape): 105.12,120.96 105.12,120.81 105.12,118.56 105.12,118.42 104.99,118.29 103.66,118.29 103.53,118.42 103.53,120.96 103.66,121.09 104.99,121.09
GND on TOP (solid shape): 104.74,117.91 104.95,117.91 105.12,117.74 105.12,117.38 105.12,115.14 105.12,114.99 104.99,114.86 103.66,114.86 103.53,114.99 103.53,117.78 103.66,117.91 104.73,117.91
GND on TOP (solid shape): 177.22,104.83 177.73,104.83 177.86,104.7 177.86,103.31 177.76,103.2 177.3,103.2 177.22,103.13 177.22,102.54 177.07,102.39 177.07,101.32 176.84,101.1 175.91,101.1 175.77,101.23 175.77,102.14 175.67,102.24 174.97,102.24 174.82,102.1 174.82,101.29 174.61,101.07 173.62,101.07 173.59,101.1 173.59,103.31 173.82,103.53 173.84,103.53 173.84,105.01 174.05,105.21 176.84,105.21
GND on TOP (solid shape): 65.72,22.53 65.72,21.52 65.84,21.39 67.11,21.39 68,20.5 68,15.04 67.84,14.88 66.39,14.88 66.24,15.03 66.24,15.79 66.1,15.93 64.06,15.93 63.95,16.04 63.95,17.67 63.44,18.17 63.44,19.68 63.57,19.8 63.57,21.66 63.43,21.8 63.43,22.53 63.56,22.66 65.59,22.66
GND on TOP (solid shape): 197.41,19.99 197.41,18.98 197.67,18.72 198.3,18.72 198.43,18.6 198.43,18.4 198.43,18.4 198.43,15.62 198.43,15.55 198.3,15.42 197.98,15.42 197.95,15.44 197.94,15.45 197.77,15.66 197.52,15.73 197.48,15.73 196.78,16.44 196.78,16.95 196.53,17.2 194.42,17.2 194.38,17.21 194.37,17.25 194.37,17.96 194.62,18.22 194.62,19.99 194.75,20.12 197.29,20.12
GND on TOP (solid shape): 211.21,58.24 211.66,58 211.85,57.51 211.85,54.71 211.63,54.24 211.16,54.05 201.97,54.05 201.89,54.05 200.26,54.05 199.98,54.32 199.98,57.96 200.26,58.24
GND on TOP (solid shape): 31.79,119.03 31.79,118.59 31.81,116.51 31.78,116.11 31.74,115.87 31.65,115.65 31.09,115.04 30.28,114.81 28.02,114.81 27.81,114.8 27.59,114.81 25.28,114.81 24.29,115.19 23.81,116.13 23.8,118.76 23.81,119.02 23.83,119.28 23.81,122.48 31.81,122.48
GND on TOP (solid shape): 136.07,96.58 136.07,95.81 136.33,95.56 138.49,95.56 138.61,95.43 138.61,92 138.49,91.88 135.44,91.88 135.18,91.62 135.18,90.99 135.06,90.86 132.26,90.86 132.14,90.99 132.14,95.97 132.33,95.97 132.33,95.92 132.34,95.87 132.35,95.82 132.37,95.77 132.4,95.73 132.44,95.7 132.48,95.67 132.52,95.65 132.57,95.63 132.62,95.62 132.67,95.62 132.72,95.63 132.77,95.65 132.81,95.67 132.85,95.7 132.89,95.73 132.92,95.77 132.94,95.82 132.95,95.87 132.96,95.92 132.96,95.97 132.95,96.01 132.94,96.06 132.92,96.11 132.89,96.15 132.85,96.18 132.81,96.21 132.77,96.23 132.72,96.25 132.67,96.26 132.62,96.26 132.57,96.25 132.52,96.23 132.48,96.21 132.44,96.18 132.4,96.15 132.37,96.11 132.35,96.06 132.34,96.01 132.33,95.97 132.14,95.97 132.14,96.45 132.39,96.7 135.95,96.7
GND on TOP (solid shape): 70.02,89.26 70.29,89.26 70.57,88.98 70.57,88.29 70.44,88.17 67.61,88.17 67.42,88.36 67.42,88.63 67.43,88.64 67.43,88.65 67.49,88.71 67.49,88.88 67.53,88.96 67.62,88.98 67.82,88.99 67.98,89.1 68.04,89.14 68.11,89.12 68.27,89.08 68.41,89.14 68.48,89.16 68.55,89.13 68.94,89.07 69.1,89.43 69.1,89.45 69.11,89.47 69.35,89.71 69.57,89.71
GND on TOP (solid shape): 162.74,50.98 162.74,38.28 164.09,36.94 165.39,36.94 165.41,36.91 168.99,36.91 169.45,37.37 169.47,37.37 170.14,38.03 171.13,38.03 171.25,37.9 171.25,36.25 171.24,36.21 171.2,36.2 170.49,36.2 170.49,35.99 170.11,35.61 170.11,35.18 170.06,35.13 163.02,35.13 161.22,36.94 161.22,42.75 161.23,42.79 161.27,42.8 162,43.6 161.27,44.4 161.23,44.41 161.22,44.45 161.22,49.33 160.97,49.59 159.44,49.59 159.31,49.71 159.31,51.36 159.44,51.49 162.24,51.49
GND on TOP (solid shape): 201.12,41.55 201.21,41.49 200.96,40.54 201.67,40.04 211.1,40.04 211.52,39.91 211.79,39.57 211.83,39.44 211.85,39.3 211.85,37.94 211.83,37.9 211.79,37.89 210.27,37.89 210.26,37.89 199.93,37.89 199.92,37.9 197.26,35.25 195.73,35.25 195.58,35.09 188.4,35.09 187.99,34.69 180.98,34.69 180.49,35.18 180.49,35.87 181.46,36.85 194.2,36.85 195.45,38.09 198.74,38.09 199.84,39.2 199.84,41.33 200.06,41.55
GND on TOP (solid shape): outline of 85 points within 200.75,90.52 212.15,99.24
GND on TOP (solid shape): 60.15,39.55 60.15,38.69 60.31,38.54 63.3,38.54 63.81,38.03 63.81,35.44 63.43,35.06 61.86,35.06 60.34,33.54 60.34,33.3 60.25,33.2 59.76,33.2 59.71,33.25 59.55,33.63 59.14,33.6 59.07,33.58 59.01,33.6 58.53,33.58 58.52,33.09 56.18,33.09 56.18,33.09 55.99,33.09 55.92,33.16 55.92,33.86 56.07,34.01 57.03,34.01 57.06,34 57.41,34.09 57.5,34.44 57.48,34.49 57.46,34.53 57.46,35.62 58.47,36.62 58.48,36.62 58.66,36.87 58.5,37.13 58.48,37.15 58.48,37.95 58.68,38.16 58.68,38.94 59.37,39.63 60.08,39.63
GND on TOP (solid shape): outline of 133 points within 152.96,15.93 156.42,19.11
GND on TOP (solid shape): outline of 178 points within 57.08,46.31 64.19,55.81
GND on TOP (solid shape): outline of 259 points within 200.39,70.68 214.15,79.84
GND on TOP (solid shape): outline of 1185 points within 12.05,0.25 214.15,20.86
GND on TOP (solid shape): outline of 1285 points within 0.25,30.77 212.15,122.55
GND on BOTTOM (solid shape): 23.7,20.34 23.7,15.52 23.46,15.28 22.77,15.28 22.01,16.04 22.01,20.29 22.15,20.43 23.61,20.43
GND on BOTTOM (solid shape): 49.13,29.85 49.13,27.36 48.39,26.62 46.09,26.62 45.88,26.84 45.88,29.7 46.26,30.08 48.9,30.08
GND on BOTTOM (solid shape): 65.21,69.78 65.21,66.48 65.08,66.35 64.06,66.35 63.94,66.48 63.94,69.78 64.06,69.91 65.08,69.91
GND on BOTTOM (solid shape): 89.59,8.56 89.59,7.29 89.46,7.17 88.07,7.17 87.94,7.29 87.94,8.69 88.07,8.82 89.34,8.82
GND on BOTTOM (solid shape): 95.69,14.03 95.69,10.22 95.31,9.83 92.51,9.83 92,10.34 92,13.9 92.51,14.41 95.31,14.41
GND on BOTTOM (solid shape): 105.09,121.09 105.09,114.99 104.7,114.61 103.69,114.61 103.56,114.74 103.56,121.34 103.69,121.47 104.7,121.47
GND on BOTTOM (solid shape): 162.41,57.84 162.41,53.32 162.36,53.27 157.23,53.27 156.93,53.57 156.93,57.69 157.26,58.02 162.24,58.02
GND on BOTTOM (solid shape): 32.7,50.22 32.7,45.14 31.17,45.14 31.04,45.27 31.04,48.06 31.68,48.7 31.68,50.22 31.81,50.35 32.57,50.35
GND on BOTTOM (solid shape): 40.32,88.07 40.32,87.56 40.19,87.43 39.68,87.43 39.05,86.8 38.28,86.8 38.03,87.05 38.03,88.07 38.16,88.19 40.19,88.19
GND on BOTTOM (solid shape): 73.07,23.64 73.07,22.53 71.08,20.55 68.16,20.55 67.99,20.73 67.99,23.79 68.24,24.05 72.66,24.05
GND on BOTTOM (solid shape): 80.82,47.67 80.82,42.96 80.6,42.74 80.6,40.63 78.81,38.84 68.38,38.84 67.2,40.02 67.2,47.54 67.52,47.86 80.64,47.86
GND on BOTTOM (solid shape): 85.4,14.79 85.4,14.53 84.51,13.64 84.51,12.25 84.26,12.25 84.26,14.53 84.64,14.91 85.27,14.91
GND on BOTTOM (solid shape): 96.88,57.94 96.88,53.42 96.73,53.27 91.57,53.27 91.09,53.75 91.09,57.13 91.32,57.36 92.34,57.36 93.02,58.04 96.78,58.04
GND on BOTTOM (solid shape): 148.39,113.72 148.39,111.05 148.14,110.8 147.25,110.8 147,111.05 147,113.85 147.12,113.97 148.14,113.97
GND on BOTTOM (solid shape): 15.8,116.26 18.22,116.26 18.6,115.88 18.6,114.61 18.34,114.36 12.48,114.36 12.25,114.58 12.25,116.87 12.53,117.15 14.92,117.15
GND on BOTTOM (solid shape): 62.16,71.3 62.16,66.35 61.91,66.1 59.11,66.1 58.98,66.22 58.98,66.6 59.11,66.73 59.87,66.73 61.52,68.38 61.52,71.3 61.65,71.43 62.03,71.43
GND on BOTTOM (solid shape): 91.04,28.58 91.04,27.41 90.91,27.28 90.54,27.28 90.53,27.29 87.91,27.29 87.76,27.44 87.76,28.71 87.94,28.88 90.73,28.88
GND on BOTTOM (solid shape): 84.89,9.63 85.71,8.82 86.29,8.82 86.54,8.56 86.54,7.42 86.42,7.29 85.2,7.29 85.2,7.75 84.64,8.31 84.64,10.09 84.89,10.09
GND on BOTTOM (solid shape): 192.91,59.45 193.26,59.45 194.53,58.19 194.67,58.19 194.75,58.1 194.75,57.46 194.62,57.33 194.62,56.32 194.11,55.81 191.83,55.81 191.45,56.19 191.45,60 191.55,60.1 192.26,60.1
GND on BOTTOM (solid shape): 70.67,68.38 70.67,67.75 70.54,67.62 66.66,67.62 66.62,67.63 66.6,67.67 66.6,68.51 66.73,68.64 68.13,68.64 68.38,68.89 68.38,69.4 68.51,69.52 69.53,69.52
GND on BOTTOM (solid shape): 84,21.65 84,19.99 84.26,19.74 87.18,19.74 87.31,19.87 88.32,19.87 88.45,19.74 88.45,17.45 88.19,17.2 81.72,17.2 80.96,17.96 80.96,21.52 81.21,21.77 83.88,21.77
GND on BOTTOM (solid shape): 70.39,15.68 71.66,15.68 71.89,15.45 71.89,14.08 72.46,13.5 72.45,13.49 72.45,11.66 71.99,11.21 69.6,11.21 69.37,11.43 69.37,14.67 70.38,15.68
GND on BOTTOM (solid shape): 75.88,54.28 75.88,53.4 75.62,53.14 72.95,53.14 72.57,52.76 72.57,51.49 73.08,50.98 73.08,49.71 72.95,49.59 71.94,49.59 71.81,49.71 71.81,54.67 72.07,54.92 75.24,54.92
GND on BOTTOM (solid shape): 178.68,55.76 178.84,55.68 179.02,55.71 179.25,55.48 179.25,54.31 179.1,54.16 177.73,54.16 177.6,54.28 177.6,55.22 178.14,55.76
GND on BOTTOM (solid shape): 82.15,121.09 82.15,119.41 82.8,118.76 83.66,118.76 83.88,118.55 83.88,111.56 80.96,108.64 79.3,108.64 79.05,108.89 79.05,112.58 80.32,113.85 80.32,118.67 80.96,119.31 80.96,120.96 81.21,121.21 82.02,121.21
GND on BOTTOM (solid shape): 171.96,107.4 171.96,106.51 171.41,105.95 170.21,105.95 170.02,106.14 170.01,106.16 170.01,106.18 170.01,106.8 169.93,107.42 169.93,107.47 170.01,107.55 171.81,107.55
GND on BOTTOM (solid shape): 85.83,25.45 87.87,25.45 87.89,25.43 87.89,24.54 87.86,24.52 86.67,24.52 86.53,24.37 86.53,23.61 86.42,23.5 85.94,23.5 85.83,23.61 84.31,23.61 84.18,23.74 84.18,24.56 84.88,24.56 85.07,24.75 85.07,25.51 85.77,25.51
GND on BOTTOM (solid shape): 40.44,34.98 40.44,34.22 40.19,33.96 38.54,33.96 38.41,33.84 38.41,32.19 37.9,31.68 36.63,31.68 36.12,31.17 36.12,26.93 35.34,26.15 33.92,26.15 33.46,26.6 33.46,33.71 33.58,33.84 34.6,33.84 34.98,34.22 34.98,34.98 35.24,35.23 40.19,35.23
GND on BOTTOM (solid shape): 188.52,54.41 191.83,54.41 192.21,54.03 192.21,51.74 191.83,51.36 186.09,51.36 186.06,51.38 186.04,51.41 186.04,54.44 185.99,54.49 185.97,54.6 186.06,54.67 188.27,54.67
GND on BOTTOM (solid shape): 88.71,26.05 90.05,26.05 90.15,25.96 90.15,25.58 90.02,25.45 89.96,25.45 89.2,24.69 89.2,24.24 89.13,24.18 88.63,24.18 88.18,24.62 88.18,25.35 87.74,25.79 87.74,25.89 87.74,25.89 87.74,26.5 87.79,26.55 88.22,26.55
GND on BOTTOM (solid shape): 41.59,53.52 41.59,52 42.47,51.11 42.47,43.74 42.35,43.62 41.97,43.62 41.84,43.74 41.84,46.03 41.08,46.79 41.08,48.32 41.46,48.7 41.46,49.84 40.44,50.86 35.24,50.86 34.6,51.49 34.6,53.14 35.11,53.65 41.46,53.65
GND on BOTTOM (solid shape): 67.6,21.16 67.6,15.35 67.34,15.09 66.4,15.09 66.34,15.16 66.35,15.17 66.35,16.18 66.19,16.35 63.88,16.35 63.43,16.8 63.43,18.42 63.66,18.65 63.66,20.58 63.86,20.78 65.61,20.78 66.22,21.39 67.37,21.39
GND on BOTTOM (solid shape): 211.21,58.24 211.66,58 211.85,57.51 211.85,54.71 211.63,54.24 211.16,54.05 201.97,54.05 201.89,54.05 200.26,54.05 200.26,58.24
GND on BOTTOM (solid shape): 24.19,41.58 25.14,41.58 25.24,41.48 25.24,40.29 24.76,39.81 24.34,39.81 24.01,40.02 23.68,39.81 22.41,39.81 22.15,40.06 21.65,40.06 21.32,40.06 21.28,40.08 21.27,40.11 21.27,42.17 21.28,42.2 21.32,42.22 23.55,42.22
GND on BOTTOM (solid shape): 177.43,51.44 177.43,50.02 177.47,49.97 177.47,49.94 177.5,49.94 177.6,49.84 180.14,49.84 180.14,47.93 179.76,47.93 179.76,49.2 178.11,49.2 178.11,47.81 177.92,47.62 174.87,47.62 174.17,48.32 173.41,48.32 173.16,48.57 175.6,48.57 175.6,48.52 175.61,48.46 175.63,48.41 175.66,48.37 175.69,48.33 175.73,48.29 175.77,48.26 175.82,48.24 175.87,48.22 175.93,48.21 175.98,48.21 176.03,48.22 176.08,48.24 176.13,48.26 176.17,48.29 176.21,48.33 176.25,48.37 176.27,48.41 176.29,48.46 176.3,48.52 176.31,48.57 176.3,48.62 176.29,48.67 176.27,48.72 176.25,48.77 176.21,48.81 176.17,48.85 176.13,48.88 176.08,48.9 176.03,48.92 175.98,48.92 175.93,48.92 175.87,48.92 175.82,48.9 175.77,48.88 175.73,48.85 175.69,48.81 175.66,48.77 175.63,48.72 175.61,48.67 175.6,48.62 175.6,48.57 173.16,48.57 173.08,48.65 173.08,51.72 173.67,52.3 176.56,52.3
GND on BOTTOM (solid shape): 7.8,81.21 12.38,81.21 12.63,80.95 12.63,78.8 12.38,78.54 11.87,78.54 11.61,78.29 11.61,77.53 11.49,77.4 10.6,77.4 10.58,77.41 10.55,77.51 10.61,77.58 10.72,78.16 10.14,78.05 10.07,77.99 9.98,78.02 9.33,78.67 8.18,78.67 8.06,78.54 8.01,78.54 7.8,78.34 7.8,78.29 7.68,78.16 7.68,76.26 7.8,76.13 9.33,76.13 9.71,75.75 9.71,73.97 9.45,73.72 5.9,73.72 5.39,74.22 5.39,74.73 4.68,75.44 4.68,80.75 5.77,81.84 7.17,81.84
GND on BOTTOM (solid shape): outline of 81 points within 170.17,57.08 174.94,60.63
GND on BOTTOM (solid shape): outline of 82 points within 200.75,90.52 212.15,99.24
GND on BOTTOM (solid shape): outline of 97 points within 199.75,7.4 212.27,12.65
GND on BOTTOM (solid shape): outline of 99 points within 66.6,106.48 71.81,112.4
GND on BOTTOM (solid shape): 36.63,88.07 36.63,86.93 36.38,86.67 35.58,86.67 35.48,86.73 35.51,86.84 35.49,87.37 34.97,87.3 34.9,87.26 34.82,87.29 34.31,87.26 34.34,86.76 34.35,86.7 34.31,86.67 34.22,86.67 33.58,87.3 31.29,87.3 31.2,87.35 31.19,87.44 30.86,87.92 30.52,87.44 30.51,87.35 30.43,87.3 27.87,87.3 27.74,87.43 27.74,88.07 27.87,88.19 36.51,88.19
GND on BOTTOM (solid shape): outline of 184 points within 22.65,107.86 35.55,117.17
GND on BOTTOM (solid shape): outline of 215 points within 168.15,13.69 179.66,22.39
GND on BOTTOM (solid shape): outline of 230 points within 180.78,25.61 211.85,42.35
GND on BOTTOM (solid shape): outline of 253 points within 16.82,88.14 42.13,112.29
GND on BOTTOM (solid shape): outline of 259 points within 200.39,70.68 214.15,79.84
GND on BOTTOM (solid shape): outline of 282 points within 55.71,46.31 66.2,59.75
GND on BOTTOM (solid shape): outline of 401 points within 6.15,83.75 13.14,99.75
GND on BOTTOM (solid shape): outline of 470 points within 17.71,45.99 23.42,74.55
GND on BOTTOM (solid shape): outline of 805 points within 12.05,0.25 214.15,20.86
GND on BOTTOM (solid shape): outline of 381 points within 121.17,99.2 142.94,101.89
GND on BOTTOM (solid shape): outline of 1138 points within 0.25,30.77 212.15,122.55
GND on IN1 (solid shape): 67.7,21.06 67.7,16.31 67.37,15.98 64.27,15.98 63.25,17 63.25,21.39 63.28,21.42 67.34,21.42
GND on IN1 (solid shape): 83.7,117.94 83.7,111.33 80.96,108.59 79.84,108.59 79.24,109.19 79.24,117.62 79.94,118.32 83.32,118.32
GND on IN1 (solid shape): 43.11,47.3 43.11,41.58 42.73,41.2 41.2,41.2 40.95,41.46 40.95,42.98 41.84,43.87 41.84,46.03 40.95,46.92 40.95,48.06 41.08,48.19 42.22,48.19
GND on IN1 (solid shape): 35.03,33.66 35.03,31.86 34.98,31.81 34.98,26.58 34.67,26.26 29.44,26.26 28.76,26.94 28.76,31.81 28.87,31.92 28.87,33.6 29.8,34.52 34.17,34.52
GND on IN1 (solid shape): 211.21,58.24 211.66,58 211.85,57.51 211.85,54.71 211.63,54.24 211.16,54.05 201.97,54.05 201.9,54.05 200.26,54.05 200.26,58.24
GND on IN1 (solid shape): outline of 85 points within 200.75,90.52 212.15,99.24
GND on IN1 (solid shape): outline of 259 points within 200.39,70.68 214.15,79.84
GND on IN1 (solid shape): outline of 369 points within 190.13,25.73 211.85,41.55
GND on IN1 (solid shape): outline of 127 points within 12.05,0.25 214.15,20.86
GND on IN1 (solid shape): outline of 1201 points within 0.25,30.77 212.15,122.55
GND on IN1 (solid shape): outline of 2528 points within 118.07,88.93 143.36,101.05
GND on IN2 (solid shape): 211.21,58.24 211.66,58 211.85,57.51 211.85,54.71 211.63,54.24 211.16,54.05 201.97,54.05 201.89,54.05 200.26,54.05 200.26,58.24
GND on IN2 (solid shape): 79.01,121.11 79.11,121.05 79.09,120.94 79.36,120.35 79.62,120.94 79.6,121.05 79.7,121.11 81.11,121.11 83.95,118.27 83.95,111.82 80.8,108.67 80.14,108.67 79.81,109 79.81,117.68 79.1,118.39 67.85,118.39 67.44,118.8 67.44,120.93 67.62,121.11
GND on IN2 (solid shape): 201.12,41.55 201.21,41.49 200.96,40.54 201.67,40.04 211.1,40.04 211.52,39.91 211.79,39.57 211.83,39.44 211.85,39.3 211.85,37.94 211.83,37.9 211.79,37.89 210.27,37.89 210.18,37.89 209.5,38.56 208,38.56 207.92,38.64 203.02,38.64 202.88,38.5 200.5,38.5 199.95,39.06 199.95,39.78 200.15,39.98 200.15,41.39 200.31,41.55
GND on IN2 (solid shape): outline of 85 points within 200.75,90.52 212.15,99.24
GND on IN2 (solid shape): outline of 259 points within 200.39,70.68 214.15,79.84
GND on IN2 (solid shape): outline of 660 points within 28.5,23.37 49.17,34.35
GND on IN2 (solid shape): outline of 127 points within 12.05,0.25 214.15,20.86
GND on IN2 (solid shape): outline of 836 points within 58.58,10.14 67.51,27.79
GND on IN2 (solid shape): outline of 1201 points within 0.25,30.77 212.15,122.55
GND on VCC: 0.23,79.43 0.23,102.04 8.21,102.04 8.57,101.68 8.57,99.73 8.44,99.6 8.44,94.95 9.33,94.06 9.33,90.78 9.05,90.5 9.05,90.02 9.33,89.74 9.33,80.17 8.59,79.43
GND on VCC: 81.57,74.6 80.96,75.22 80.96,76.02 81.19,76.26 84.03,76.26 84.28,76 86.44,76 86.8,75.64 86.8,74.84 86.57,74.6 84.42,74.6 84.14,74.72 83.85,74.6
GND on VCC: 144.69,24.44 144.43,24.69 127.29,24.69 126.27,25.71 125.17,25.71 124.16,24.69 103.92,24.69 96.07,32.42 96.07,80.98 101.25,86.16 108.87,86.16 109.89,87.18 120.05,87.18 121.19,88.32 132.41,88.32 133.05,87.69 140.03,87.69 141.18,86.54 146.13,86.54 147.01,85.66 147.01,85.31 147.25,85.07 147.6,85.07 148.01,84.66 148.01,81.86 148.54,81.34 152.48,81.34 152.71,81.1 152.71,79.51 152.43,79.23 152.43,78.72 157.66,73.48 157.66,69.55 162.24,64.97 162.24,60.63 162.12,60.36 162.24,60.1 162.24,49.69 159.44,46.9 159.44,43 169.22,33.1 169.22,24.93 168.86,24.57 164.63,24.57 164.25,24.95 162,24.95 161.5,24.44
GND on VCC: 60.3,5.73 59.76,5.96 59.53,6.5 59.53,7 55.3,11.23 51.07,7 51.07,6.5 50.84,5.96 50.3,5.73 13.3,5.73 12.76,5.96 12.53,6.5 12.53,7.23 12.4,7.79 12.03,8.22 12.03,31.96 12.21,32.15 14.22,32.15 14.44,32.37 14.44,33.27 14.5,33.33 26.07,33.33 27.36,34.62 27.36,41.42 27.41,41.6 27.36,41.78 27.36,42.32 25.58,44.1 25.58,66.24 26.07,66.73 29.03,66.73 31.7,64.06 41.61,64.06 43.48,62.19 43.48,61.72 43.8,61.4 44.27,61.4 45.4,60.27 45.4,57.61 47.32,55.68 50.33,55.68 54.01,59.36 73.99,59.36 74.73,58.62 74.73,5.73
GND on VCC: 186.6,10.85 184.1,10.85 183.21,9.96 178.24,9.96 178.23,9.96 177.14,9.96 177.1,10 177.1,13.99 177.13,14.03 181.05,14.03 181.82,13.26 183.47,13.26 183.85,12.88 186.34,12.88 186.85,13.39 188.47,13.39 188.78,13.09 189.13,13.09 189.44,13.39 191.09,13.39 191.09,13.39 191.58,13.39 191.96,13 191.96,9.9 191.64,9.58 187.87,9.58
GND on VCC: outline of 114 points within 156.39,35.11 214.15,122.55
GND on VCC: 178.85,47.05 178.49,47.4 178.49,48.21 179.76,49.48 179.76,51.51 181.16,52.91 181.16,54.05 181.39,54.28 183.21,54.28 183.44,54.05 183.44,53.5 180.78,50.83 180.78,47.4 180.42,47.05
GND on VCC: 125,14.75 125,14.76 125.56,15.32 131.17,15.32 132.34,14.15 132.34,13.57 131.79,13.02 129.43,13.02 128.82,13.63 125.52,13.63 124.77,14.38 124.77,14.52
GND on VCC: 195.62,11.99 195.26,12.35 195.26,14.43 196.38,15.55 197.69,15.55 197.8,15.44 197.8,14.77 197.29,14.26 197.29,12.1 197.18,11.99
GND on VCC: 71.66,110.04 71.3,110.4 71.3,111.58 72.19,112.47 72.19,114.76 77.38,119.94 90.38,119.94 91.5,118.82 91.5,112.54 90.32,111.36 84.56,111.36 84.23,111.69 84.23,118.42 83.86,118.8 77.8,118.8 73.21,114.21 73.21,113.49 74.35,112.34 74.35,110.4 73.99,110.04
GND on GND: outline of 304 points within 0.25,0.25 214.15,122.55
GNDA on TOP (solid shape): 196.4,26.09 196.4,25.46 195.48,24.53 192.4,24.53 192.31,24.44 191.84,24.44 191.7,24.58 191.7,27.36 191.83,27.49 195,27.49
GNDA on BOTTOM (solid shape): 193.8,23.17 193.84,23.15 193.9,23.13 193.99,23.04 194.3,23.04 194.36,22.98 194.37,22.98 194.49,22.85 194.49,22.15 194.37,22.03 193.1,22.03 192.97,22.15 192.97,23.04 193.1,23.17
GNDA on GND (solid shape): outline of 2171 points within 187.38,16.82 214,38.16
GNDA on VCC: outline of 110 points within 187.38,16.82 214.02,38.16
VIN on TOP (solid shape): 30.66,112.7 30.66,108.26 30.54,108.13 28.89,108.13 28.63,108.39 28.63,112.58 28.89,112.83 30.54,112.83
VIN on TOP (solid shape): outline of 312 points within 12.88,38.28 36.2,113.47
VIN on BOTTOM (solid shape): 20.5,39.93 21.25,39.93 21.27,39.91 21.61,39.91 22.23,39.3 22.23,34.6 21.98,34.35 19.31,34.35 19.18,34.47 19.18,37.7 18.85,38.03 17.07,38.03 16.95,38.15 16.95,40.7 17.2,40.95 19.49,40.95
VIN on BOTTOM (solid shape): 51.44,16.95 51.44,15.22 51.21,14.99 49.56,14.99 49.23,14.66 49.23,14.3 49.1,14.18 48.49,14.18 48.44,14.23 48.44,14.81 49.73,16.1 49.73,16.76 50.07,17.1 51.29,17.1
VIN on BOTTOM (solid shape): outline of 87 points within 13.9,108.13 22.15,114.23
+BIF_VDDC on TOP (solid shape): 66.04,72.04 66.04,70.03 65.92,69.91 64.32,69.91 63.96,70.26 63.96,71.47 64.2,71.7 64.85,71.7 65.21,72.06 66.02,72.06
+BIF_VDDC on IN2 (solid shape): outline of 920 points within 59.49,69.91 65.72,81.34
+CHGRTC on TOP (solid shape): 178.49,69.14 178.49,67.75 178.24,67.49 176.97,67.49 176.88,67.58 176.88,67.61 176.88,67.62 176.9,67.89 176.72,68.09 176.55,68.13 176.38,68.09 176.35,68.11 176.21,68.25 176.21,68.45 176.31,68.7 176.21,68.95 176.21,69.22 176.22,69.26 176.26,69.27 178.36,69.27
+CPU_CORE on TOP (solid shape): outline of 4168 points within 95.54,88.45 142.8,121.21
+CPU_CORE on BOTTOM (solid shape): 103.24,120.9 103.24,114.99 100.46,112.2 100,112.2 99.1,111.31 96.07,111.31 95.56,111.82 95.56,115.24 95.94,115.63 99.12,115.63 99.12,116.39 95.94,116.39 95.56,116.77 95.56,120.83 95.81,121.09 103.05,121.09
+CPU_CORE on BOTTOM (solid shape): outline of 1958 points within 120.48,87.15 143.43,100.18
+CPU_CORE on IN1 (solid shape): outline of 1584 points within 95.56,111.31 125.1,121.09
+CPU_CORE on IN2 (solid shape): outline of 453 points within 121.01,88.9 139.2,98.61
+CPU_CORE on IN2 (solid shape): outline of 1626 points within 95.56,111.31 125.28,121.09
+CPU_CORE on VCC: outline of 96 points within 94.54,88.83 140.65,122.55
+FAN_POWER on TOP (solid shape): 8.18,71.94 8.18,71.05 8.06,70.92 5.14,70.92 4.88,70.67 4.88,68.76 4.63,68.51 4.12,68.51 3.87,68.76 3.87,70.79 4.25,71.18 4.25,71.68 4.37,71.81 5.14,71.81 5.52,72.19 7.93,72.19
+FAN_POWER on BOTTOM (solid shape): 8.1,73.04 8.1,73.01 8.1,73 8.09,72.81 8.18,72.64 8.18,71.05 7.93,70.79 6.79,70.79 6.53,71.05 6.53,73.08 6.66,73.21 7.93,73.21
+INV_PWR_SRC on TOP (solid shape): 5.64,79.35 5.96,79.35 6.03,79.43 6.42,79.43 6.46,79.39 6.46,78.17 6.66,77.97 6.66,76.2 6.66,75.75 6.63,75.72 6.63,73.76 6.66,73.74 6.66,73.59 6.41,73.33 5.33,73.33 5.01,73.33 4.94,73.36 4.8,73.67 4.52,73.78 4.5,73.82 4.5,77.09 4.51,77.2 4.5,77.31 4.5,77.78 4.27,78.01 1.87,78.01 1.76,78.12 1.76,79.33 1.86,79.43 5.56,79.43
+INV_PWR_SRC on BOTTOM (solid shape): 3.7,79.74 3.7,78.23 3.5,78.03 1.34,78.03 1.12,78.25 1.12,80.17 1.2,80.24 3.19,80.24
+LAN_REGOUT on TOP (solid shape): 172.75,107.89 172.75,106.66 172.35,106.25 171.43,106.25 171.25,106.43 171.25,107.52 171.38,107.65 172.12,107.65 172.42,107.95 172.69,107.95
+LAN_REGOUT on BOTTOM (solid shape): 173.28,110.52 173.28,106.48 173.92,105.85 173.92,104.88 173.91,104.85 173.87,104.83 173.21,104.83 173.09,104.95 173.09,105.53 173.06,105.57 172.65,105.97 172.4,105.97 172.19,106.18 172.19,107.57 172.01,107.75 171.43,107.75 171.38,107.8 171.38,109.28 171.56,109.45 171.56,110.6 171.74,110.77 173.03,110.77
+LAN_VDD10 on TOP (solid shape): 171.44,110.92 171.44,110.02 171.25,109.83 171.25,107.9 171.01,107.66 171.01,106.62 170.87,106.48 170.6,106.48 170.39,106.58 170.16,106.54 170.07,106.54 170.02,106.63 169.87,107.72 169.48,108.76 169.47,108.77 169.47,110.97 169.58,111.15 169.57,111.35 170.08,111.87 170.5,111.87
+LAN_VDD10 on BOTTOM (solid shape): 171.41,111.15 171.41,110.19 171.16,109.95 171.16,108.12 170.87,107.83 169.93,107.83 169.8,107.96 169.8,107.97 169.66,108.37 169.48,108.76 169.47,108.77 169.47,110.93 169.61,111.07 169.61,111.29 170.11,111.79 170.77,111.79
+LAN_VDD10 on IN1 (solid shape): outline of 530 points within 169.93,101.27 180.14,113.09
+LAN_VDD33 on TOP (solid shape): 171.63,113.49 171.63,112.61 172.27,111.97 177.96,111.97 177.96,111.97 178.15,111.97 180.21,109.91 180.21,101.43 178.73,99.95 175.76,99.95 175.61,100.1 175.34,100.1 174.99,100.44 174.99,101.99 175.05,102.05 175.6,102.05 175.64,102.01 175.64,101.05 175.76,100.93 176.9,100.93 177.26,101.29 177.26,102.05 177.3,102.1 177.96,102.1 177.98,102.08 177.98,101.76 178.09,101.65 178.7,101.65 178.7,101.66 179.04,102 179.04,104.18 179.11,104.47 178.93,104.71 178.68,104.96 177.37,104.96 177.23,105.11 177.23,106.17 177.43,106.37 178.64,106.37 178.64,106.38 178.92,106.61 178.73,106.92 178.73,108.41 177.87,109.28 177.87,109.99 178.21,110.36 177.82,110.7 177.67,110.7 177.52,110.84 174.12,110.84 173.88,110.6 173.88,107.92 173.87,107.91 173.87,107.67 173.84,107.57 173.86,107.46 173.82,107.42 173.52,107.02 173.9,106.71 173.9,105.57 173.73,105.4 173.2,105.4 172.89,105.71 172.89,108.25 172.82,108.32 172.82,109.8 170.1,112.52 170.1,113.43 170.25,113.59 171.05,113.59 171.13,113.66 171.46,113.66
+LAN_VDD33 on BOTTOM (solid shape): 190.3,95.9 190.3,92.01 189.28,90.99 186.94,90.99 186.77,91.15 186.77,92.45 186.87,92.54 188.46,92.54 189.01,93.1 189.01,95.84 189.2,96.02 190.18,96.02
+LAN_VDD33 on BOTTOM (solid shape): 169.98,115.12 170.49,115.12 170.49,115.63 171.13,115.63 171.63,115.12 171.63,112.7 171.38,112.45 167.7,112.45 167.57,112.58 167.57,113.09 167.82,113.34 167.82,115.5 167.95,115.63 169.98,115.63
+LAN_VDD33 on BOTTOM (solid shape): 170.45,105.61 170.45,104.74 170.72,104.46 170.72,103.76 170.67,103.71 170.19,103.71 169.89,103.41 169.69,103.41 169.55,103.54 169.55,104.39 169.79,105.02 169.95,105.68 170.38,105.68
+LAN_VDD33 on BOTTOM (solid shape): 178.08,106.3 178.08,105.69 178.03,105.64 177.63,105.64 177.48,105.5 177.47,105.49 177.26,105.38 177.12,105.19 177.1,105.17 177.07,105.16 176.94,105.16 176.87,105.24 176.87,106.02 177.07,106.23 177.12,106.23 177.27,106.38 178.01,106.38
+LAN_VDD33 on IN1 (solid shape): 177.24,101 177.24,100.06 177.15,99.97 176.14,99.97 175.88,100.23 175.88,100.97 175.94,101.04 177.21,101.04
+LAN_VDD33 on IN1 (solid shape): 187.8,92.58 187.8,91.25 187.47,90.92 186.87,90.92 186.76,91.03 186.76,92.1 186.69,92.18 186.69,92.55 186.8,92.66 187.73,92.66
+LAN_VDD33 on VCC: 169.33,102.8 168.2,103.92 168.2,114.63 168.56,114.99 171.02,114.99 171.63,114.38 171.63,103.67 170.77,102.8
+LAN_VDDREG on TOP (solid shape): 172.68,105.75 172.68,105.65 172.87,105.47 172.87,105.1 173.03,104.94 173.03,104.7 172.9,104.58 172.27,104.58 172.12,104.43 172.1,104.42 172.08,104.42 171.74,104.3 171.67,103.95 171.66,103.86 171.58,103.81 170.62,103.81 170.24,104.2 170.24,104.83 170.36,104.96 171,104.96 171.13,105.08 171.13,105.72 171.25,105.85 172.58,105.85
+LAN_VDDREG on BOTTOM (solid shape): 172.93,105.52 172.93,104.93 172.96,104.91 172.96,104.89 173.02,104.8 173.11,104.74 173.12,104.74 173.16,104.7 174,104.7 174.03,104.69 174.05,104.65 174.05,104.5 174.03,104.46 174,104.45 172.9,104.45 172.78,104.58 171.28,104.58 171.15,104.7 171.15,105.74 171.23,105.82 171.46,105.82 171.48,105.85 172.6,105.85
+LCDVDD on TOP (solid shape): 21.73,74.56 21.73,72.75 21.5,72.52 20.68,72.52 20.5,72.7 20.5,74.48 20.69,74.67 21.61,74.67
+LCDVDD on TOP (solid shape): 13.14,85.53 13.14,84.52 13.84,83.82 13.84,83.42 13.46,83.05 13.46,82.72 13.28,82.53 12.06,82.53 11.61,82.98 11.61,85.53 11.74,85.65 13.01,85.65
+LCDVDD on IN2 (solid shape): 21.7,73.9 21.7,72.72 21.49,72.51 20.69,72.51 20.02,73.18 20.02,74.26 20.26,74.49 21.11,74.49
+LCDVDD on IN2 (solid shape): 13.51,83.7 13.51,82.24 13.79,81.96 13.79,81.28 13.37,80.85 12.34,80.85 12.01,81.17 12.01,83.61 12.16,83.75 13.46,83.75
+LCDVDD_CONN on TOP (solid shape): 10.7,89.03 11.23,89.03 13.26,87 13.26,86.29 13.14,86.16 11.61,86.16 11.49,86.29 11.49,86.8 11.59,87.05 11.49,87.3 11.49,87.43 11.36,87.56 9.71,87.56 9.58,87.43 9.58,87.3 9.48,87.05 9.58,86.8 9.58,86.03 9.45,85.91 8.03,85.91 7.78,86.16 7.78,86.82 7.77,86.85 7.77,86.86 7.67,87.17 7.36,87.27 7.33,87.27 7.31,87.29 7.3,87.3 4.5,87.3 4.37,87.43 4.37,88.75 4.5,88.88 4.68,88.88 4.71,88.9 4.81,88.9 4.83,88.88 5.59,88.88 5.62,88.9 5.72,88.9 5.9,89.08 10.65,89.08
+LCDVDD_CONN on BOTTOM (solid shape): 5.64,88.83 5.64,87.56 5.52,87.43 4.63,87.43 3.99,86.8 3.88,86.8 3.79,86.85 3.8,86.96 3.49,87.56 3.17,86.96 3.18,86.85 3.09,86.8 1.71,86.8 1.58,86.92 1.58,87.63 1.68,87.74 3.13,87.74 3.22,87.82 3.24,87.82 3.46,88.04 3.49,88.04 4.35,88.9 5.57,88.9
+RTCVCC on TOP (solid shape): 181.14,72.99 181.14,71.05 180.58,70.48 179.57,70.48 179.47,70.59 179.47,72.95 179.63,73.11 181.02,73.11
+V_TP on TOP (solid shape): 12.63,69.4 12.63,68.13 12.38,67.87 11.11,67.87 10.98,67.75 10.98,66.86 10.47,66.86 10.47,66.35 10.98,66.35 10.98,65.97 9.33,65.97 9.2,65.84 9.2,64.57 9.07,64.44 8.44,64.44 8.31,64.57 8.31,67.49 8.69,67.87 10.09,67.87 10.22,68 10.22,69.27 10.47,69.52 12.5,69.52
+V_TP on BOTTOM (solid shape): 8.95,66.73 8.95,63.3 8.69,63.05 7.93,63.05 7.8,63.17 7.8,63.56 8.31,64.06 8.31,66.73 8.44,66.86 8.82,66.86
+V_TS on TOP (solid shape): 11.87,100.64 11.87,100.13 12.12,99.88 13.26,99.88 13.65,99.5 13.65,97.72 13.01,97.09 13.01,97.08 12.76,96.83 11.74,96.83 11.49,97.08 11.49,98.23 11.23,98.48 10.72,98.48 10.6,98.61 10.6,99.56 10.41,99.75 9.33,99.75 9.07,100 9.07,100.64 9.2,100.77 11.74,100.77
+VCHGR on BOTTOM (solid shape): 25.46,24.06 25.46,19.74 25.82,19.38 25.82,19.38 26.03,19.17 26.92,19.17 26.95,19.14 26.95,17.78 27.31,17.43 27.67,17.78 27.67,19.05 27.68,19.09 27.72,19.1 28.89,19.1 29.14,18.85 29.14,16.44 27.71,15.01 24.56,15.01 23.83,15.73 23.83,20.39 23.8,20.42 23.8,20.8 23.51,21.1 22.46,21.1 22.03,21.53 22.03,23.93 22.41,24.31 25.2,24.31
+VCHGR on IN1 (solid shape): 25.85,21.69 25.85,18.46 26.19,18.12 28.9,18.12 29.14,17.88 29.14,16.44 28.76,16.06 25.67,16.06 23.9,17.82 23.9,21.74 24.19,22.03 25.52,22.03
+VCHGR on IN2 (solid shape): 25.46,24.06 25.46,19.74 26.09,19.11 28.89,19.11 29.14,18.85 29.14,16.44 28.76,16.06 22.28,16.06 22.03,16.31 22.03,16.4 22.04,16.44 22.08,16.45 22.1,16.45 22.12,16.43 22.63,16.39 22.65,16.9 22.62,16.97 22.75,17.29 22.62,17.61 22.75,17.92 22.62,18.24 22.65,18.31 22.75,18.55 22.67,18.79 22.64,18.86 22.67,18.93 22.78,19.18 22.68,19.43 22.65,19.5 22.68,19.57 22.68,20.06 22.19,20.09 22.09,20.08 22.03,20.17 22.03,23.93 22.41,24.31 25.2,24.31
+VDISPLAY_VCC on TOP (solid shape): 203,81.21 203,79.68 202.74,79.42 201.49,79.42 200.87,78.8 197.91,78.8 197.91,80.82 198.3,81.21 199.32,81.21 199.7,81.59 202.62,81.59
+VGA_CORE on TOP (solid shape): outline of 161 points within 53.02,60.13 69.78,70.79
+VGA_CORE on TOP (solid shape): outline of 471 points within 61.02,78.49 71.68,89.77
+VGA_CORE on BOTTOM (solid shape): outline of 87 points within 51.24,60.25 70.8,70.79
+VGA_CORE on IN1 (solid shape): outline of 4080 points within 53.4,60.13 70.41,89.72
+VGA_CORE on IN2 (solid shape): 54.03,63.68 68,63.68 68.38,63.3 68.38,61.02 68.13,60.76 65.46,60.76 65.21,61.02 63.43,61.02 62.67,60.25 53.14,60.25 52.76,60.63 52.76,63.02 53.5,63.76 53.96,63.76
+VGA_CORE on IN2 (solid shape): outline of 1194 points within 60.19,78.92 70.54,88.93
+VGA_CORE on VCC: 74.73,59.34 74.2,59.87 52.87,59.87 52.38,60.36 52.38,64.21 59.87,71.7 59.87,78.69 60.89,79.71 60.89,89.36 61.88,90.35 71.58,90.35 74.73,87.2
+VGA_PCIE on TOP (solid shape): outline of 1299 points within 58.94,65.84 75.37,79.07
+VGA_PCIE on IN2 (solid shape): 65.74,78.81 65.74,78.3 65.38,77.94 65.38,75.24 64.83,75.24 64.45,75.62 64.45,78.29 64.19,78.54 64.19,79.05 64.34,79.2 65.35,79.2
+VGA_PCIEP on TOP (solid shape): 72.83,65.08 74.35,65.08 74.35,65.59 76.38,65.59 77.02,64.95 77.02,62.29 76.76,62.03 70.34,62.03 70.16,62.21 70.16,65.21 70.54,65.59 72.83,65.59
+VGA_PCIEP on BOTTOM (solid shape): 77.02,64.95 77.02,62.29 76.76,62.03 70.34,62.03 70.16,62.21 70.16,65.21 70.54,65.59 76.38,65.59
ADPIN on TOP (solid shape): 23.48,121.75 23.48,121.4 23.41,121.29 23.24,121.02 23.04,120.56 22.82,119.73 22.79,119.49 22.79,119.07 22.78,118.8 22.79,118.53 22.79,117.89 22.64,117.73 18.29,117.73 17.66,118.37 17.66,121.25 18.23,121.82 23.4,121.82
ADPIN on BOTTOM (solid shape): 22.66,120.45 22.66,116.67 22.1,116.11 18.91,116.11 18.63,116.39 16.06,116.39 15.8,116.64 15.8,117.28 17.71,119.18 17.71,120.32 18.09,120.71 22.41,120.71
AUD_HP_OUT_R_CN on TOP (solid shape): 199.32,27.94 199.32,27.03 199.14,26.85 197.77,26.85 197.13,27.49 197.13,27.82 197.35,28.05 199.22,28.05
B+ on TOP (solid shape): 35.11,41.84 35.11,39.43 34.98,39.3 33.08,39.3 32.82,39.55 32.82,41.97 32.95,42.09 34.85,42.09
